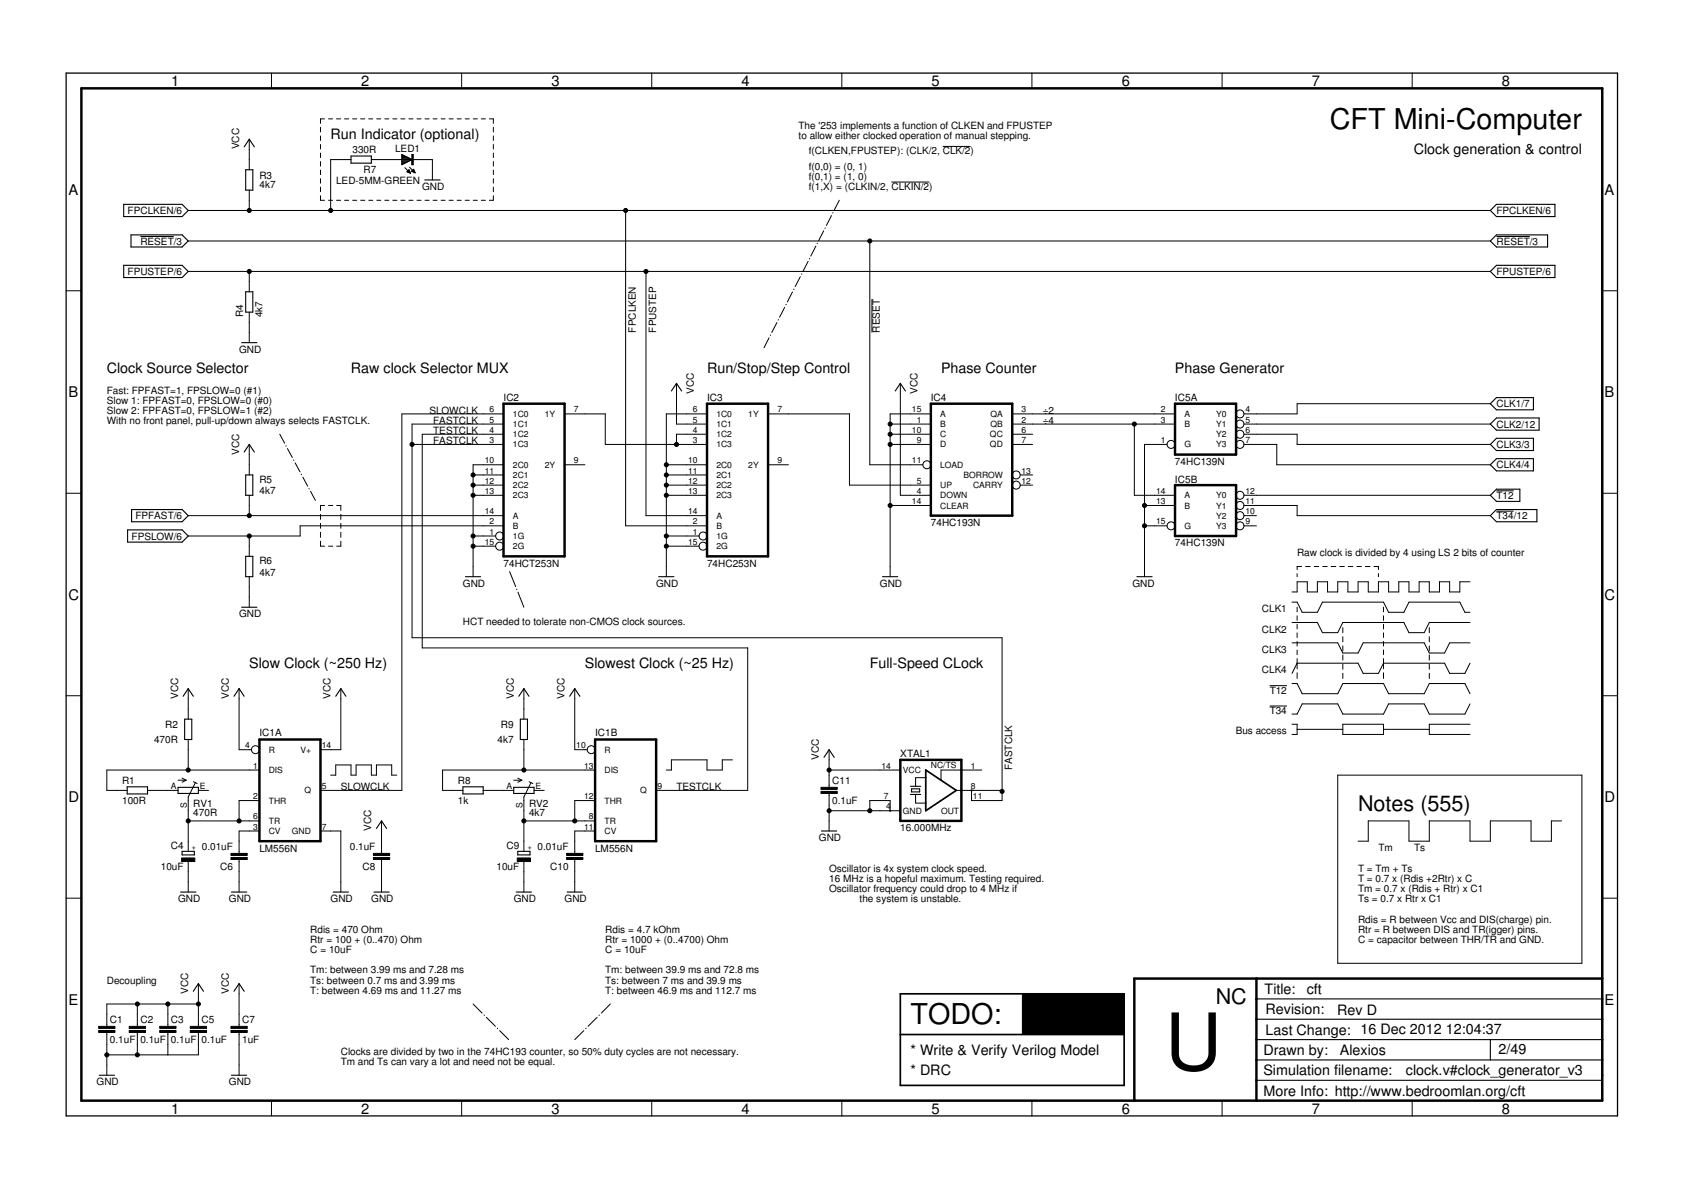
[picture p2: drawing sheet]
<svg xmlns="http://www.w3.org/2000/svg" width="420mm" height="297mm" viewBox="0 0 420 297" stroke-linecap="round" stroke-linejoin="round" font-family="sans-serif">
<defs><g id="words">
<text font-size="19.7" x="290.8" y="267.1">U</text>
<g font-size="7.2">
<text x="332" y="32.2">CFT Mini-Computer</text>
<text x="227.3" y="255.7">TODO:</text>
</g>
<g font-size="5.4">
<text x="339.1" y="202.4">Notes (555)</text>
<text x="303.5" y="250.6">NC</text>
</g>
<g font-size="3.7">
<text x="42.7" y="21.5">1</text>
<text x="90.2" y="21.5">2</text>
<text x="137.7" y="21.5">3</text>
<text x="185.1" y="21.5">4</text>
<text x="232.6" y="21.5">5</text>
<text x="280" y="21.5">6</text>
<text x="327.5" y="21.5">7</text>
<text x="375" y="21.5">8</text>
<text x="17.1" y="48.6">A</text>
<text x="400.6" y="48.6">A</text>
<text x="17.1" y="99.2">B</text>
<text x="400.6" y="99.2">B</text>
<text x="17.1" y="149.7">C</text>
<text x="400.6" y="149.7">C</text>
<text x="17.1" y="200.2">D</text>
<text x="400.6" y="200.2">D</text>
<text x="17.1" y="250.8">E</text>
<text x="400.6" y="250.8">E</text>
<text x="42.7" y="277.9">1</text>
<text x="90.2" y="277.9">2</text>
<text x="137.7" y="277.9">3</text>
<text x="185.1" y="277.9">4</text>
<text x="232.6" y="277.9">5</text>
<text x="280" y="277.9">6</text>
<text x="327.5" y="277.9">7</text>
<text x="375" y="277.9">8</text>
</g>
<g font-size="3.6">
<text x="82.5" y="34.7">Run Indicator (optional)</text>
<text x="353" y="38.6">Clock generation &amp; control</text>
<text x="26.7" y="93.2">Clock Source Selector</text>
<text x="87.6" y="93.2">Raw clock Selector MUX</text>
<text x="176.5" y="93.2">Run/Stop/Step Control</text>
<text x="234.9" y="93.2">Phase Counter</text>
<text x="293.3" y="93.2">Phase Generator</text>
<text x="62.2" y="166.8">Slow Clock (~250 Hz)</text>
<text x="146" y="166.8">Slowest Clock (~25 Hz)</text>
<text x="217.1" y="166.8">Full-Speed CLock</text>
<text x="315.7" y="248.1">Title:</text>
<text x="326.2" y="248.2">cft</text>
<text x="315.9" y="253.2">Revision:</text>
<text x="333.8" y="253.3">Rev D</text>
<text x="227.3" y="263.3">* Write &amp; Verify Verilog Model</text>
<text x="315.4" y="263.3">Drawn by:</text>
<text x="315.9" y="258.2">Last Change: 16 Dec 2012</text>
<text x="334.5" y="263.3">Alexios</text>
<text x="361" y="258.1">12:04:37</text>
<text x="374.1" y="263.2">2/49</text>
<text x="227.3" y="268.4">* DRC</text>
<text x="315.4" y="268.4">Simulation filename:</text>
<text x="351" y="268.4">clock.v#clock_generator_v3</text>
<text x="315.4" y="273.5">More Info: http://www.bedroomlan.org/cft</text>
</g>
<g font-size="2.5">
<text x="199.4" y="32.2">The '253 implements a function of CLKEN and FPUSTEP</text>
<text x="199.4" y="34.7">to allow either clocked operation of manual stepping.</text>
<text x="59.7" y="37.3" transform="rotate(-90 59.7 37.3)">VCC</text>
<text x="88" y="38.3">330R</text>
<text x="98.6" y="38.1">LED1</text>
<text x="201.9" y="38.6">f(CLKEN,FPUSTEP): (CLK/2, CLK/2)</text>
<text x="64.8" y="46.9">4k7</text>
<text x="64.8" y="44.7">R3</text>
<text x="83.9" y="46">LED-5MM-GREEN</text>
<text x="90.8" y="43.1">R7</text>
<text x="105.4" y="47.4">GND</text>
<text x="201.9" y="42.4">f(0,0) = (0, 1)</text>
<text x="201.9" y="44.9">f(0,1) = (1, 0)</text>
<text x="201.9" y="47.4">f(1,X) = (CLKIN/2, CLKIN/2)</text>
<text x="31.9" y="53.4">FPCLKEN/6</text>
<text x="373.6" y="53.4">FPCLKEN/6</text>
<text x="35" y="61">RESET/3</text>
<text x="373.6" y="61">RESET/3</text>
<text x="31.9" y="68.7">FPUSTEP/6</text>
<text x="373.6" y="68.7">FPUSTEP/6</text>
<text x="60.7" y="79.2" transform="rotate(-90 60.7 79.2)">R4</text>
<text x="65.5" y="79.2" transform="rotate(-90 65.5 79.2)">4k7</text>
<text x="158.7" y="83" transform="rotate(-90 158.7 83)">FPCLKEN</text>
<text x="163.8" y="83" transform="rotate(-90 163.8 83)">FPUSTEP</text>
<text x="219.7" y="83" transform="rotate(-90 219.7 83)">RESET</text>
<text x="59.7" y="88.1">GND</text>
<text x="26.7" y="98.2">Fast: FPFAST=1, FPSLOW=0 (#1)</text>
<text x="26.7" y="100.8">Slow 1: FPFAST=0, FPSLOW=0 (#0)</text>
<text x="125.7" y="100.1">IC2</text>
<text x="173.2" y="98.2" transform="rotate(-90 173.2 98.2)">VCC</text>
<text x="176.5" y="100.1">IC3</text>
<text x="229.1" y="98.2" transform="rotate(-90 229.1 98.2)">VCC</text>
<text x="232.4" y="100.1">IC4</text>
<text x="293.3" y="100.1">IC5A</text>
<text x="373.6" y="101.7">CLK1/7</text>
<text x="26.7" y="103.3">Slow 2: FPFAST=0, FPSLOW=1 (#2)</text>
<text x="26.7" y="105.9">With no front panel, pull-up/down always selects FASTCLK.</text>
<text x="107.2" y="103.3">SLOWCLK</text>
<text x="108.1" y="105.9">FASTCLK</text>
<text x="260.3" y="103.3">÷2</text>
<text x="260.3" y="105.9">÷4</text>
<text x="373.6" y="106.7">CLK2/12</text>
<text x="59.7" y="113.5" transform="rotate(-90 59.7 113.5)">VCC</text>
<text x="108.1" y="110.9">FASTCLK</text>
<text x="108.2" y="108.4">TESTCLK</text>
<text x="373.6" y="111.8">CLK3/3</text>
<text x="293.3" y="116">74HC139N</text>
<text x="373.6" y="116.9">CLK4/4</text>
<text x="64.8" y="123.4">4k7</text>
<text x="64.8" y="120.6">R5</text>
<text x="293.3" y="120.5">IC5B</text>
<text x="373.6" y="124.5">T12</text>
<text x="33.8" y="129.6">FPFAST/6</text>
<text x="232.4" y="131.3">74HC193N</text>
<text x="373.6" y="129.6">T34/12</text>
<text x="32.8" y="134.7">FPSLOW/6</text>
<text x="293.3" y="136.3">74HC139N</text>
<text x="64.8" y="143.7">4k7</text>
<text x="64.8" y="140.9">R6</text>
<text x="125.7" y="141.4">74HCT253N</text>
<text x="176.5" y="141.4">74HC253N</text>
<text x="323.8" y="138.9">Raw clock is divided by 4 using LS 2 bits of counter</text>
<text x="115.6" y="146.5">GND</text>
<text x="163.8" y="146.5">GND</text>
<text x="219.7" y="146.5">GND</text>
<text x="282.7" y="146.5">GND</text>
<text x="59.7" y="154.1">GND</text>
<text x="115.6" y="155.9">HCT needed to tolerate non-CMOS clock sources.</text>
<text x="315" y="152.8">CLK1</text>
<text x="315" y="157.9">CLK2</text>
<text x="315" y="163">CLK3</text>
<text x="315" y="168.1">CLK4</text>
<text x="317" y="173.2">T12</text>
<text x="44.4" y="174.4" transform="rotate(-90 44.4 174.4)">VCC</text>
<text x="57.1" y="174.4" transform="rotate(-90 57.1 174.4)">VCC</text>
<text x="82.5" y="174.4" transform="rotate(-90 82.5 174.4)">VCC</text>
<text x="128.3" y="174.4" transform="rotate(-90 128.3 174.4)">VCC</text>
<text x="141" y="174.4" transform="rotate(-90 141 174.4)">VCC</text>
<text x="317" y="178.2">T34</text>
<text x="38.5" y="185.3">470R</text>
<text x="41.3" y="181.8">R2</text>
<text x="64.8" y="183.8">IC1A</text>
<text x="124.2" y="185.3">4k7</text>
<text x="125.1" y="181.8">R9</text>
<text x="148.6" y="183.8">IC1B</text>
<text x="308.5" y="183.3">Bus access</text>
<text x="204.4" y="189.7" transform="rotate(-90 204.4 189.7)">VCC</text>
<text x="224.8" y="189">XTAL1</text>
<text x="30.5" y="195.8">R1</text>
<text x="85.1" y="197.3">SLOWCLK</text>
<text x="114.3" y="195.8">R8</text>
<text x="168.9" y="197.3">TESTCLK</text>
<text x="207.7" y="195.6">C11</text>
<text x="252.7" y="192.2" transform="rotate(-90 252.7 192.2)">FASTCLK</text>
<text x="30.5" y="200.6">100R</text>
<text x="48.3" y="203.6">470R</text>
<text x="48.3" y="201.5">RV1</text>
<text x="114.3" y="200.6">1k</text>
<text x="132.1" y="203.6">4k7</text>
<text x="132.1" y="201.5">RV2</text>
<text x="207.7" y="200.7">0.1uF</text>
<text x="92.7" y="207.4" transform="rotate(-90 92.7 207.4)">VCC</text>
<text x="204.4" y="210">GND</text>
<text x="224.8" y="207.4">16.000MHz</text>
<text x="42.6" y="212">C4</text>
<text x="50.4" y="212.1">0.01uF</text>
<text x="64.8" y="212.6">LM556N</text>
<text x="87.3" y="212.1">0.1uF</text>
<text x="126.4" y="212">C9</text>
<text x="134.2" y="212.1">0.01uF</text>
<text x="148.6" y="212.6">LM556N</text>
<text x="344.1" y="212.5">Tm</text>
<text x="353" y="212.5">Ts</text>
<text x="40.1" y="217.1">10uF</text>
<text x="54.9" y="217.2">C6</text>
<text x="90.5" y="217.2">C8</text>
<text x="123.9" y="217.1">10uF</text>
<text x="137.4" y="217.2">C10</text>
<text x="207" y="217.6">Oscillator is 4x system clock speed.</text>
<text x="207" y="220.1">16 MHz is a hopeful maximum. Testing required.</text>
<text x="339.1" y="220.1">T = 0.7 x (Rdis +2Rtr) x C</text>
<text x="339.1" y="217.6">T = Tm + Ts</text>
<text x="44.4" y="225.2">GND</text>
<text x="57.1" y="225.2">GND</text>
<text x="82.5" y="225.2">GND</text>
<text x="92.7" y="225.2">GND</text>
<text x="128.3" y="225.2">GND</text>
<text x="141" y="225.2">GND</text>
<text x="207" y="222.7">Oscillator frequency could drop to 4 MHz if</text>
<text x="214.6" y="225.2">the system is unstable.</text>
<text x="339.1" y="222.7">Tm = 0.7 x (Rdis + Rtr) x C1</text>
<text x="339.1" y="225.2">Ts = 0.7 x Rtr x C1</text>
<text x="77.5" y="232.8">Rdis = 470 Ohm</text>
<text x="151.1" y="232.8">Rdis = 4.7 kOhm</text>
<text x="339.1" y="230.3">Rdis = R between Vcc and DIS(charge) pin.</text>
<text x="339.1" y="232.8">Rtr = R between DIS and TR(igger) pins.</text>
<text x="77.5" y="235.4">Rtr = 100 + (0..470) Ohm</text>
<text x="77.5" y="237.9">C = 10uF</text>
<text x="151.1" y="235.4">Rtr = 1000 + (0..4700) Ohm</text>
<text x="151.1" y="237.9">C = 10uF</text>
<text x="339.1" y="235.4">C = capacitor between THR/TR and GND.</text>
<text x="26.7" y="245.5">Decoupling</text>
<text x="77.5" y="243">Tm: between 3.99 ms and 7.28 ms</text>
<text x="77.5" y="245.5">Ts: between 0.7 ms and 3.99 ms</text>
<text x="151.1" y="243">Tm: between 39.9 ms and 72.8 ms</text>
<text x="151.1" y="245.5">Ts: between 7 ms and 39.9 ms</text>
<text x="47" y="248.1" transform="rotate(-90 47 248.1)">VCC</text>
<text x="57.1" y="248.1" transform="rotate(-90 57.1 248.1)">VCC</text>
<text x="77.5" y="248.1">T: between 4.69 ms and 11.27 ms</text>
<text x="151.1" y="248.1">T: between 46.9 ms and 112.7 ms</text>
<text x="27.4" y="255.3">C1</text>
<text x="35" y="255.3">C2</text>
<text x="42.7" y="255.3">C3</text>
<text x="50.3" y="255.3">C5</text>
<text x="60.4" y="255.3">C7</text>
<text x="27.4" y="260.4">0.1uF</text>
<text x="35" y="260.4">0.1uF</text>
<text x="42.7" y="260.4">0.1uF</text>
<text x="50.3" y="260.4">0.1uF</text>
<text x="60.4" y="260.4">1uF</text>
<text x="85.1" y="263.3">Clocks are divided by two in the 74HC193 counter, so 50% duty cycles are not necessary.</text>
<text x="85.1" y="265.8">Tm and Ts can vary a lot and need not be equal.</text>
<text x="24.1" y="270.9">GND</text>
<text x="57.1" y="270.9">GND</text>
</g>
<g font-size="2.1">
<text x="122.2" y="105.5">5</text>
<text x="122.2" y="103">6</text>
<text x="128.1" y="106.6">1C1</text>
<text x="128.1" y="104.1">1C0</text>
<text x="136" y="104.1">1Y</text>
<text x="143.3" y="103">7</text>
<text x="173" y="105.5">5</text>
<text x="173" y="103">6</text>
<text x="178.8" y="106.6">1C1</text>
<text x="178.8" y="104.1">1C0</text>
<text x="186.8" y="104.1">1Y</text>
<text x="194.1" y="103">7</text>
<text x="227.7" y="103">15</text>
<text x="228.9" y="105.5">1</text>
<text x="234.7" y="104.1">A</text>
<text x="234.7" y="106.6">B</text>
<text x="247.3" y="106.6">QB</text>
<text x="247.3" y="104.1">QA</text>
<text x="255" y="105.5">2</text>
<text x="255" y="103">3</text>
<text x="289.8" y="103">2</text>
<text x="289.8" y="105.5">3</text>
<text x="295.7" y="104.1">A</text>
<text x="295.7" y="106.6">B</text>
<text x="303.6" y="104.1">Y0</text>
<text x="303.6" y="106.6">Y1</text>
<text x="310.9" y="103">4</text>
<text x="310.9" y="105.5">5</text>
<text x="122.2" y="110.6">3</text>
<text x="122.2" y="108">4</text>
<text x="128.1" y="111.7">1C3</text>
<text x="128.1" y="109.2">1C2</text>
<text x="173" y="110.6">3</text>
<text x="173" y="108">4</text>
<text x="178.8" y="111.7">1C3</text>
<text x="178.8" y="109.2">1C2</text>
<text x="227.7" y="108">10</text>
<text x="228.9" y="110.6">9</text>
<text x="234.7" y="109.2">C</text>
<text x="234.7" y="111.7">D</text>
<text x="247.1" y="111.7">QD</text>
<text x="247.1" y="109.2">QC</text>
<text x="255" y="110.6">7</text>
<text x="255" y="108">6</text>
<text x="289.8" y="110.6">1</text>
<text x="295.7" y="111.7">G</text>
<text x="303.6" y="109.2">Y2</text>
<text x="303.6" y="111.7">Y3</text>
<text x="310.9" y="108">6</text>
<text x="310.9" y="110.6">7</text>
<text x="121" y="115.7">10</text>
<text x="121" y="118.2">11</text>
<text x="128.1" y="116.8">2C0</text>
<text x="128.1" y="119.3">2C1</text>
<text x="136" y="116.8">2Y</text>
<text x="143.3" y="115.7">9</text>
<text x="171.8" y="115.7">10</text>
<text x="171.8" y="118.2">11</text>
<text x="178.8" y="116.8">2C0</text>
<text x="178.8" y="119.3">2C1</text>
<text x="186.8" y="116.8">2Y</text>
<text x="194.1" y="115.7">9</text>
<text x="227.7" y="115.7">11</text>
<text x="234.7" y="116.8">LOAD</text>
<text x="240.5" y="119.3">BORROW</text>
<text x="255" y="118.2">13</text>
<text x="121" y="120.7">12</text>
<text x="121" y="123.3">13</text>
<text x="128.1" y="121.9">2C2</text>
<text x="128.1" y="124.4">2C3</text>
<text x="171.8" y="120.7">12</text>
<text x="171.8" y="123.3">13</text>
<text x="178.8" y="121.9">2C2</text>
<text x="178.8" y="124.4">2C3</text>
<text x="227.7" y="125.8">14</text>
<text x="228.9" y="120.7">5</text>
<text x="228.9" y="123.3">4</text>
<text x="234.7" y="121.9">UP</text>
<text x="234.7" y="124.4">DOWN</text>
<text x="242.9" y="121.9">CARRY</text>
<text x="255" y="120.7">12</text>
<text x="288.6" y="123.3">14</text>
<text x="288.6" y="125.8">13</text>
<text x="295.7" y="124.4">A</text>
<text x="303.6" y="124.4">Y0</text>
<text x="310.9" y="123.3">12</text>
<text x="310.9" y="125.8">11</text>
<text x="121" y="128.4">14</text>
<text x="122.2" y="130.9">2</text>
<text x="128.1" y="129.5">A</text>
<text x="171.8" y="128.4">14</text>
<text x="173" y="130.9">2</text>
<text x="178.8" y="129.5">A</text>
<text x="234.7" y="126.9">CLEAR</text>
<text x="288.6" y="130.9">15</text>
<text x="295.7" y="126.9">B</text>
<text x="303.6" y="126.9">Y1</text>
<text x="303.6" y="129.5">Y2</text>
<text x="310.9" y="128.4">10</text>
<text x="310.9" y="130.9">9</text>
<text x="121" y="136">15</text>
<text x="122.2" y="133.4">1</text>
<text x="128.1" y="134.6">1G</text>
<text x="128.1" y="132">B</text>
<text x="128.1" y="137.1">2G</text>
<text x="171.8" y="136">15</text>
<text x="173" y="133.4">1</text>
<text x="178.8" y="134.6">1G</text>
<text x="178.8" y="132">B</text>
<text x="178.8" y="137.1">2G</text>
<text x="295.7" y="132">G</text>
<text x="303.6" y="132">Y3</text>
<text x="61.2" y="186.8">4</text>
<text x="63.2" y="191.8">1</text>
<text x="67.1" y="187.9">R</text>
<text x="75" y="187.9">V+</text>
<text x="80.4" y="186.8">14</text>
<text x="143.9" y="186.8">10</text>
<text x="145.8" y="191.8">13</text>
<text x="150.9" y="187.9">R</text>
<text x="220.1" y="191.8">14</text>
<text x="232.4" y="191.7">NC/TS</text>
<text x="242.3" y="191.8">1</text>
<text x="42.7" y="196.9">A</text>
<text x="49.9" y="196.9">E</text>
<text x="67.1" y="193">DIS</text>
<text x="80.4" y="196.9">5</text>
<text x="126.5" y="196.9">A</text>
<text x="133.7" y="196.9">E</text>
<text x="150.9" y="193">DIS</text>
<text x="164.2" y="196.9">9</text>
<text x="225.4" y="193">VCC</text>
<text x="242.3" y="196.9">8</text>
<text x="46.6" y="201.6" transform="rotate(-90 46.6 201.6)">S</text>
<text x="63.2" y="199.5">2</text>
<text x="67.1" y="200.6">THR</text>
<text x="76" y="198">Q</text>
<text x="130.4" y="201.6" transform="rotate(-90 130.4 201.6)">S</text>
<text x="145.8" y="199.5">12</text>
<text x="150.9" y="200.6">THR</text>
<text x="159.8" y="198">Q</text>
<text x="220.7" y="199.5">7</text>
<text x="221.2" y="202">4</text>
<text x="225.4" y="203.1">GND</text>
<text x="234.9" y="203.1">OUT</text>
<text x="242.9" y="199.5">11</text>
<text x="63.2" y="204.5">6</text>
<text x="63.2" y="207.1">3</text>
<text x="67.1" y="205.7">TR</text>
<text x="67.1" y="208.2">CV</text>
<text x="72.9" y="208.2">GND</text>
<text x="80.4" y="207.1">7</text>
<text x="145.8" y="207.1">11</text>
<text x="147" y="204.5">8</text>
<text x="150.9" y="205.7">TR</text>
<text x="150.9" y="208.2">CV</text>
</g>
<g font-size="1.8">
<text x="48.8" y="212.1" transform="rotate(-90 48.8 212.1)">+</text>
<text x="132.7" y="212.1" transform="rotate(-90 132.7 212.1)">+</text>
</g>
</g></defs>
<g fill="#000" stroke="#000" stroke-width=".25">
<path d="M67.8 18.2v3.9zM115.3 18.2v3.9zM162.7 18.2v3.9zM210.2 18.2v3.9zM257.6 18.2v3.9zM305.1 18.2v3.9zM352.5 18.2v3.9zM20.3 22.1v252.6zM62.2 34.8v2.5zM62.2 39.8v2.6zM62.2 37.3v2.5zM80 29.7h1z"/>
<path d="M80 38.2v1.1zM80 36.1v1.1zM80 33.9v1.2zM80 31.8v1.1zM80 29.7v1.1zM82 29.7h1zM82.5 39.8v12.7zM84 29.7h1zM85.1 39.8h2.5zM82.5 39.8h2.6zM86 29.7h1zM88 29.7h1z"/>
<path d="M90 29.7h1.1zM92.1 29.7h.9zM94.1 29.7h1zM92.7 39.8h2.5zM96.1 29.7h1zM97.8 39.8h2.5zM95.2 39.8h2.6zM98.1 29.7h1zM100.1 29.7h1zM100.3 39.8h2.6zM102.1 29.7h1zM104.1 29.7h1z"/>
<path d="M102.9 39.8h2.5zM106.1 29.7h1zM105.4 39.8h2.5zM108.1 29.7h1zM110.1 29.7h1zM112.1 29.7h1zM114.1 29.7h1zM116.1 29.7h1.1zM118.2 29.7h1zM120.2 29.7h1zM122.2 29.7h1zM123.2 38.2v1.1z"/>
<path d="M123.2 36.1v1.1zM123.2 33.9v1.2zM123.2 31.8v1.1zM123.2 29.7v1.1zM235.3 36.6h7zM20.3 22.1h379.7zM35.1 59h8.3zM47 52.5h15.2zM62.2 47.5v2.5zM62.2 52.5h20.3zM62.2 50v2.5zM80 48.9v1.1z"/>
<path d="M80 46.7v1.2zM80 44.6v1.1zM80 42.5v1.1zM80 40.3v1.2zM80 50h1zM82 50h1zM82.5 52.5h73.7zM84 50h1zM86 50h1zM88 50h1zM90 50h1.1zM92.1 50h.9z"/>
<path d="M94.1 50h1zM96.1 50h1zM98.1 50h1zM100.1 50h1zM101.1 41.9l1.4 1.4zM101.6 42.9l.5-.5zM101.6 42.8h.7zM101.7 42.9h.6zM101.8 42.7h.4zM101.9 42.6h.3zM102 43.1h.4zM102.1 50h1z"/>
<path d="M102.1 42.4l.4 .9zM102.2 41.7l1.4 1.4zM102.3 43.2h.1zM101.6 42.9l.9 .4zM102.7 42.8l.5-.6zM102.8 42.7h.6zM102.9 42.8h.6zM102.9 42.6h.5zM103 42.5h.3zM103.1 42.3h.2zM103.2 42.9h.3zM103.2 42.2l.4 .9z"/>
<path d="M103.4 43.1h.2zM102.7 42.8l.9 .3zM104.1 50h1zM106.1 50h1zM107.9 42.4v2.5zM107.9 39.8v2.6zM108.1 50h1zM110.1 50h1zM112.1 50h1zM114.1 50h1zM116.1 50h1.1zM118.2 50h1z"/>
<path d="M120.2 50h1zM122.2 50h1zM123.2 48.9v1.1zM123.2 46.7v1.2zM123.2 44.6v1.1zM123.2 42.5v1.1zM123.2 40.3v1.2zM156.2 52.5h215.9zM205.6 57.6l-1.2 2.5zM207.6 53.8l-1.3 2.5zM208 53.1l-.1 .1zM209.5 50l-1.2 2.5z"/>
<path d="M222.5 45.4h9.5zM373.6 59h8.3zM16.5 72.6h3.8zM47 60.2h170.1zM62.2 70.3v2.5zM47 67.8h15.2zM62.2 67.8v2.5zM62.2 67.8h99.1zM161.3 67.8h210.8zM194.3 79.8v.1zM195.9 76.7l-1.3 2.5zM196.3 76l-.1 .1z"/>
<path d="M197.8 72.9l-1.2 2.5zM198.2 72.2v.1zM199.8 69.1l-1.3 2.4zM201.7 65.3l-1.2 2.4zM202.1 64.5v.1zM203.7 61.4l-1.3 2.5zM204.1 60.7l-.1 .1zM217.1 60.2h155zM400 72.6h3.8zM62.2 77.9v2.6zM62.2 83v2.5zM62.2 80.5v2.5z"/>
<path d="M168.9 95.7v2.5zM192 84.3l-1.3 2.5zM193.9 80.5l-1.2 2.5zM217.7 74.7v8.3zM224.8 95.7v2.5zM62.2 116v2.6zM62.2 110.9v2.6zM62.2 113.5v2.5zM69.8 108.4l1.3 2.2zM71.8 112l1.2 2.2zM73.3 114.8l.1 .1zM73.7 115.5l1.2 2.3z"/>
<path d="M75.6 119.1l1.2 2.2zM100.3 103.3v94zM102.9 105.9h17.7zM102.9 105.9v5zM102.9 110.9v48.3zM105.4 108.4v53.3zM118.1 116v2.6zM118.1 118.6v2.5zM120.6 110.9h5.1zM120.6 108.4h5.1zM120.6 105.9h5.1zM120.6 103.3h5.1z"/>
<path d="M120.6 116h5.1zM120.6 118.6h5.1zM118.1 116h2.5zM118.1 118.6h2.5zM102.9 110.9h17.7zM100.3 103.3h20.3zM105.4 108.4h15.2zM140.9 103.3h5.1zM140.9 116h5.1zM146 103.3h5.1zM151.1 103.3v7.6zM151.1 110.9h17.8z"/>
<path d="M166.3 103.3v12.7zM166.3 116v2.6zM166.3 118.6v2.5zM168.9 98.2v7.7zM168.9 110.9h2.5zM168.9 108.4v2.5zM171.4 110.9h5.1zM171.4 108.4h5.1zM171.4 105.9h5.1zM171.4 103.3h5.1zM171.4 116h5.1zM171.4 118.6h5.1z"/>
<path d="M166.3 103.3h5.1zM166.3 116h5.1zM166.3 118.6h5.1zM168.9 105.9h2.5zM168.9 108.4h2.5zM191.7 103.3h5.1zM191.7 116h5.1zM196.8 103.3h15.3zM212.1 103.3v17.8zM217.1 60.2v55.8zM222.2 103.3v2.6zM222.2 105.9v2.5z"/>
<path d="M222.2 108.4v2.5zM222.2 110.9v15.3zM227.3 103.3h5.1zM227.3 105.9h5.1zM227.3 108.4h5.1zM227.3 110.9h5.1zM227.3 116h3.1zM222.2 103.3h5.1zM222.2 105.9h5.1zM222.2 108.4h5.1zM222.2 110.9h5.1zM217.1 116h10.2z"/>
<path d="M252.7 110.9h5.1zM252.7 108.4h5.1zM252.7 105.9h5.1zM252.7 103.3h5.1zM254.7 118.6h3.1zM257.8 105.9h25.4zM285.7 110.9v15.3zM288.3 110.9h3.1zM288.3 103.3h5zM288.3 105.9h5zM285.7 110.9h2.6zM257.8 103.3h30.5z"/>
<path d="M283.2 105.9h5.1zM310.6 103.3h3.1zM310.6 105.9h3.1zM310.6 108.4h3.1zM310.6 110.9h3.1zM313.7 103.3h10.1zM313.7 105.9h58.4zM313.7 108.4h10.1zM313.7 110.9h5zM318.7 110.9v5.1zM318.7 116h53.4zM323.8 100.8v2.5z"/>
<path d="M323.8 100.8h48.3zM323.8 108.4v2.5zM323.8 110.9h48.3zM16.5 123.1h3.8zM62.2 123.6v2.6zM62.2 136.3v2.6zM47 128.7h15.2zM62.2 126.2v2.5zM47 133.8h15.2zM62.2 133.8v2.5zM74.9 131.3v2.5zM62.2 133.8h12.7z"/>
<path d="M77.1 121.9l.1 .2zM77.5 122.7l1.2 2.2zM80 126.2v1.2zM80 128.4v1.2zM80 130.6v1.3zM80 132.9v1.2zM80 135.1v1.2zM80 136.3h1zM80 126.2h1zM82 136.3h1.1zM82 126.2h1.1zM84.1 136.3h1z"/>
<path d="M85.1 135.1v1.2zM85.1 132.9v1.2zM85.1 130.6v1.3zM85.1 128.4v1.2zM85.1 126.2v1.2zM84.1 126.2h1zM118.1 136.3v5.1zM118.1 133.8v2.5zM118.1 121.1v2.5zM118.1 123.6v10.2zM120.6 133.8h3.1zM120.6 131.3h5.1z"/>
<path d="M120.6 121.1h5.1zM120.6 123.6h5.1zM120.6 128.7h5.1zM120.6 136.3h3.1zM118.1 136.3h2.5zM118.1 133.8h2.5zM118.1 121.1h2.5zM118.1 123.6h2.5zM62.2 128.7h58.4zM74.9 131.3h45.7zM156.2 52.5v78.8zM161.3 67.8v60.9z"/>
<path d="M166.3 121.1v2.5zM166.3 123.6v10.2zM166.3 133.8v2.5zM166.3 136.3v5.1zM171.4 133.8h3.1zM171.4 131.3h5.1zM171.4 121.1h5.1zM171.4 123.6h5.1zM171.4 128.7h5.1zM171.4 136.3h3.1zM166.3 133.8h5.1zM166.3 136.3h5.1z"/>
<path d="M166.3 121.1h5.1zM166.3 123.6h5.1zM156.2 131.3h15.2zM161.3 128.7h10.1zM222.2 126.2v15.2zM224.8 98.2v25.4zM227.3 121.1h5.1zM227.3 123.6h5.1zM227.3 126.2h5.1zM222.2 126.2h5.1zM224.8 123.6h2.5zM212.1 121.1h15.2z"/>
<path d="M254.7 121.1h3.1zM283.2 105.9v17.7zM285.7 126.2v5.1zM285.7 131.3v10.1zM288.3 131.3h3.1zM288.3 123.6h5zM288.3 126.2h5zM285.7 126.2h2.6zM285.7 131.3h2.6zM283.2 123.6h5.1zM310.6 123.6h3.1zM310.6 126.2h3.1z"/>
<path d="M310.6 128.7h3.1zM310.6 131.3h3.1zM313.7 123.6h58.4zM313.7 126.2h10.1zM323.8 126.2v2.5zM323.8 128.7h48.3zM373.6 122.5h4.3zM373.6 127.6h4.3zM400 123.1h3.8zM62.2 144v2.5zM62.2 149v2.6zM62.2 146.5v2.5z"/>
<path d="M102.9 159.2h147.3zM118.1 141.4v2.6zM127.2 142.7l1.5 3.7zM129 147.1l.1 .1zM129.3 147.8l1.5 3.8zM166.3 141.4v2.6zM222.2 141.4v2.6zM250.2 159.2v38.1zM285.7 141.4v2.6zM322.6 147.8h1.2zM322.6 150.3h1.2zM322.6 155.4h6.3z"/>
<path d="M323.8 145.2v2.6zM323.8 145.2h2.6zM323.8 143.2v.8zM323.8 141.4v.8zM323.8 141.4h1.1zM323.8 150.3l1.3 2.5zM323.8 151.6v1.1zM323.8 153.7v1.2zM323.8 155.8v1.2zM323.8 158v1.1zM325.1 152.8h3.8zM325.9 141.4h1.2z"/>
<path d="M326.4 145.2v2.6zM326.4 147.8h2.5zM328.1 141.4h1.1zM328.9 145.2v2.6zM328.9 145.2h2.5zM330.2 150.3l-1.3 2.5zM328.9 155.4l1.3 2.5zM330.2 150.3h15.2zM330.2 157.9h3.8zM330.2 141.4h1.1zM331.4 145.2v2.6zM331.4 147.8h2.6z"/>
<path d="M332.3 141.4h1.2zM334 145.2v2.6zM334 145.2h2.5zM335.2 155.4l-1.2 2.5zM334.5 141.4h1.1zM335.2 155.4h15.3zM335.2 156.7v1.2zM335.2 158.9v1.3zM336.5 145.2v2.6zM336.5 147.8h2.5zM336.6 141.4h1.1zM338.7 141.4h1.2z"/>
<path d="M339 145.2v2.6zM339 145.2h2.6zM340.9 141.4h1.1zM341.6 145.2v2.6zM341.6 147.8h2.5zM343 141.4h1.1zM344.1 145.2v2.6zM344.1 145.2h2.6zM344.1 141.4v.8zM344.1 143.2v.8zM345.4 150.3l1.3 2.5zM345.4 151.6v1.1z"/>
<path d="M345.4 153.7v1.2zM345.4 155.8v1.2zM345.4 158v1.1zM346.7 145.2v2.6zM346.7 147.8h2.5zM346.7 152.8h3.8zM349.2 145.2v2.6zM349.2 145.2h2.5zM351.7 150.3l-1.2 2.5zM350.5 155.4l1.2 2.5zM351.7 145.2v2.6zM351.7 147.8h2.6z"/>
<path d="M351.7 150.3h12.7zM351.7 157.9h3.9zM354.3 145.2v2.6zM354.3 145.2h2.5zM356.8 155.4l-1.2 2.5zM356.8 145.2v2.6zM356.8 147.8h2.6zM356.8 155.4h10.2zM356.8 156.7v1.2zM356.8 158.9v1.3zM359.4 145.2v2.6zM359.4 145.2h2.5z"/>
<path d="M361.9 145.2v2.6zM361.9 147.8h2.5zM364.4 145.2v2.6zM364.4 145.2h2.6zM364.4 150.3l1.3 2.5zM365.7 152.8h1.3zM16.5 173.7h3.8zM47 177v2.5zM47 171.9v2.5zM47 174.4v2.6zM59.7 171.9v2.5zM59.7 174.4v12.7z"/>
<path d="M85.1 171.9v2.5zM105.4 161.7h81.3zM130.8 171.9v2.5zM130.8 177v2.5zM130.8 174.4v2.6zM143.5 171.9v2.5zM143.5 174.4v12.7zM186.7 161.7v35.6zM317 171.2h4.3zM317 176.2h4.3zM322.6 160.5h11.4zM322.6 170.6h1.2z"/>
<path d="M322.6 178.2h1.2zM323.8 165.5l-1.2 2.6zM323.8 165.5h15.2zM323.8 170.6l1.3 2.6zM323.8 160.1v1.2zM323.8 162.3v1.1zM323.8 164.4v1.1zM323.8 165.5v1.4zM323.8 167.9v1.5zM325.1 173.2h8.9zM325.1 175.7h8.9zM325.1 175.7l-1.3 2.5z"/>
<path d="M334 160.5l1.2 2.5zM335.2 170.6l-1.2 2.6zM334 175.7l1.2 2.5zM335.2 163h3.8zM335.2 170.6h10.2zM335.2 178.2h10.2zM335.2 161.2v1.3zM335.2 163.5v1.3zM335.2 165.8v1.3zM335.2 168.1v1.3zM340.3 160.5l-1.3 2.5zM339 165.5l1.3 2.6z"/>
<path d="M340.3 160.5h15.3zM340.3 168.1h3.8zM345.4 165.5l-1.3 2.6zM345.4 165.5h15.2zM345.4 170.6l1.3 2.6zM346.7 175.7l-1.3 2.5zM345.4 160.1v1.2zM345.4 162.3v1.1zM345.4 164.4v1.1zM345.4 165.5v1.4zM345.4 167.9v1.5zM346.7 173.2h8.9z"/>
<path d="M346.7 175.7h8.9zM355.6 160.5l1.2 2.5zM356.8 170.6l-1.2 2.6zM355.6 175.7l1.2 2.5zM356.8 163h3.8zM356.8 170.6h8.9zM356.8 178.2h8.9zM356.8 161.2v1.3zM356.8 163.5v1.3zM356.8 165.8v1.3zM356.8 168.1v1.3zM361.9 160.5l-1.3 2.5z"/>
<path d="M360.6 165.5l1.3 2.6zM361.9 160.5h5.1zM361.9 168.1h3.8zM367 175.7l-1.3 2.5zM367 165.5l-1.3 2.6zM365.7 170.6l1.3 2.6zM400 173.7h3.8zM26.7 192.2v5.1zM26.7 197.3h2.5zM29.2 197.3h2.5zM36.8 197.3h2.6zM39.4 197.3h2.5z"/>
<path d="M41.9 197.3h2.5zM44.4 194.8h2.1zM45.5 194.2l1 .6zM45.5 195.3l1-.5zM47 184.6v2.5zM47 198.9v.9zM48.7 195.4l-1.7 3.5zM26.7 192.2h20.3zM47 187.1v5.1zM48.3 195.1l.9 .5zM49.5 197.3h2.6zM59.7 199.8v5.1z"/>
<path d="M62.2 187.1h.6zM62.2 199.8h2.6zM62.2 192.2h2.6zM59.7 187.1h2.5zM59.7 199.8h2.5zM47 192.2h15.2zM82.5 193.5h1.3zM80 197.3h2.5zM80 187.1h2.5zM82.5 187.1h2.6zM82.5 197.3h17.8zM83.8 190.9v2.6z"/>
<path d="M83.8 190.9h3.8zM85.1 174.4v12.7zM87.6 190.9v2.6zM87.6 193.5h1.3zM88.9 190.9v2.6zM88.9 190.9h3.8zM92.7 190.9v2.6zM92.7 193.5h1.3zM94 190.9v2.6zM94 190.9h3.8zM97.8 190.9v2.6zM97.8 193.5h1.3z"/>
<path d="M110.5 192.2v5.1zM110.5 197.3h2.5zM113 197.3h2.6zM120.6 197.3h2.6zM123.2 197.3h2.5zM125.7 197.3h2.5zM128.2 194.8h2.1zM129.3 194.2l1 .6zM129.3 195.3l1-.5zM130.8 198.9v.9zM132.5 195.4l-1.7 3.5zM130.8 184.6v2.5z"/>
<path d="M110.5 192.2h20.3zM130.8 187.1v5.1zM132.1 195.1l.9 .5zM133.3 197.3h2.6zM143.5 199.8v5.1zM146 187.1h.6zM146 199.8h2.6zM146 192.2h2.6zM143.5 187.1h2.5zM143.5 199.8h2.5zM130.8 192.2h15.2zM166.3 192.2h1.3z"/>
<path d="M163.8 197.3h2.5zM166.3 197.3h20.4zM167.6 189.7v2.5zM167.6 189.7h8.9zM176.5 189.7v2.5zM176.5 192.2h3.8zM180.3 189.7v2.5zM180.3 189.7h2.6zM207 187.1v2.6zM207 193.5v2.5zM207 198.1v.5zM207 196v.5z"/>
<path d="M207 192.2h12.7zM207 192.2v1.3zM207 189.7v2.5zM217.1 199.8v2.6zM219.7 192.2h5.1zM219.7 199.8h2.5zM217.1 199.8h2.6zM228.6 194.1h2.5zM228.6 194.1v2.2zM234.9 192.2v2.6zM238.7 197.3h1.3zM234.9 192.2h5.1z"/>
<path d="M242.5 197.3v2.5zM240 197.3h5.1zM240 192.2h5.1zM242.5 199.8h2.6zM245.1 199.8h5.1zM245.1 197.3h5.1zM250.2 197.5v2.3zM250.2 197.3v.2zM322.6 183.3h1.2zM323.8 182.1v1.2zM323.8 180.8v1.3zM322.6 180.8h1.2z"/>
<path d="M323.8 182.1h11.4zM334 193.5v46.9zM335.2 183.3h10.2zM335.2 180.8v2.5zM335.2 180.8h10.2zM345.4 182.1v1.2zM345.4 180.8v1.3zM345.4 182.1h11.4zM356.8 182.1v1.2zM356.8 183.3h10.2zM356.8 180.8v1.3zM356.8 180.8h10.2z"/>
<path d="M334 193.5h60.9zM47 215v2.6zM47 210v2.5zM47 199.8v2.6zM47 204.9v5.1zM47 202.4v2.5zM59.7 215v2.6zM59.7 210v2.5zM59.7 214.5v.5zM59.7 212.5v.5zM59.7 207.4v2.6zM47 204.9h12.7z"/>
<path d="M62.2 204.9h2.6zM62.2 207.4h2.6zM59.7 207.4h2.5zM59.7 204.9h2.5zM80 207.4h2.5zM82.5 207.4h2.6zM85.1 207.4v12.7zM95.2 215v2.6zM95.2 210v2.5zM95.2 214.5v.5zM95.2 212.5v.5zM95.2 204.9v2.5z"/>
<path d="M95.2 207.4v2.6zM130.8 215v2.6zM130.8 210v2.5zM130.8 199.8v2.6zM130.8 204.9v5.1zM130.8 202.4v2.5zM143.5 215v2.6zM143.5 210v2.5zM143.5 214.5v.5zM143.5 212.5v.5zM143.5 207.4v2.6zM130.8 204.9h12.7z"/>
<path d="M146 204.9h2.6zM146 207.4h2.6zM143.5 207.4h2.5zM143.5 204.9h2.5zM207 204.9v2.5zM207 198.6v2.5zM207 202.4h10.1zM207 201.1v1.3zM207 202.4v2.5zM217.1 202.4h2.6zM219.7 202.4h5.1zM222.2 199.8v2.6z"/>
<path d="M228.6 200.5h2.5zM228.6 198.3v2.2zM339 210h2.6zM341.6 204.9v5.1zM341.6 204.9h10.1zM351.7 204.9v5.1zM351.7 210h5.1zM356.8 204.9v5.1zM356.8 204.9h10.2zM367 204.9v5.1zM367 210h5.1zM372.1 204.9v5.1z"/>
<path d="M372.1 204.9h10.1zM382.2 204.9v5.1zM382.2 210h5.1zM387.3 204.9v5.1zM387.3 204.9h2.5zM16.5 224.2h3.8zM47 220.1v2.6zM47 217.6v2.5zM59.7 220.1v2.6zM59.7 217.6v2.5zM85.1 220.1v2.6zM95.2 220.1v2.6z"/>
<path d="M95.2 217.6v2.5zM130.8 220.1v2.6zM130.8 217.6v2.5zM143.5 220.1v2.6zM143.5 217.6v2.5zM400 224.2h3.8zM26.7 253.1v2.6zM26.7 257.7v.5zM26.7 255.7v.5zM26.7 250.6v2.5zM26.7 250.6h7.6zM34.3 253.1v2.6z"/>
<path d="M34.3 257.7v.5zM34.3 255.7v.5zM34.3 250.6v2.5zM41.9 253.1v2.6zM41.9 257.7v.5zM41.9 255.7v.5zM41.9 250.6v2.5zM34.3 250.6h7.6zM41.9 250.6h7.6zM49.5 245.5v2.6zM49.5 253.1v2.6zM49.5 257.7v.5z"/>
<path d="M49.5 255.7v.5zM49.5 250.6v2.5zM49.5 248.1v2.5zM59.7 245.5v2.6zM59.7 253.1v2.6zM59.7 257.7v.5zM59.7 255.7v.5zM59.7 248.1v5zM118.1 250.6l2.3 2.3zM121.4 253.9l2.3 2.3zM124.2 256.7v.1zM124.7 257.3l2.3 2.2z"/>
<path d="M143.5 259.5l2.3-2.2zM146.3 256.7l-.1 .1zM146.8 256.2l2.3-2.3zM149.5 253.4h.1zM152.4 250.6l-2.3 2.3zM334 240.4h60.9zM394.9 193.5v46.9zM20.3 274.7h379.7zM26.7 258.2v2.6zM26.7 265.8v2.6zM26.7 260.8v2.5zM26.7 263.3h7.6z"/>
<path d="M26.7 263.3v2.5zM34.3 258.2v2.6zM34.3 260.8v2.5zM41.9 258.2v2.6zM41.9 260.8v2.5zM34.3 263.3h7.6zM41.9 263.3h7.6zM49.5 258.2v2.6zM49.5 260.8v2.5zM59.7 265.8v2.6zM59.7 258.2v2.6zM59.7 260.8v5z"/>
<path d="M67.8 274.7v3.8zM115.3 274.7v3.8zM162.7 274.7v3.8zM210.2 274.7v3.8zM257.6 274.7v3.8zM305.1 274.7v3.8zM352.5 274.7v3.8zM400 264.5v.1zM400 268.4v6.2zM400 274.6h.1zM400 22.1v252.6z"/>
<circle cx="62.2" cy="52.5" r=".51"/>
<circle cx="82.5" cy="52.5" r=".51"/>
<circle cx="156.2" cy="52.5" r=".51"/>
<circle cx="62.2" cy="67.8" r=".51"/>
<circle cx="161.3" cy="67.8" r=".51"/>
<circle cx="217.1" cy="60.2" r=".51"/>
<circle cx="102.9" cy="110.9" r=".51"/>
<circle cx="118.1" cy="118.6" r=".51"/>
<circle cx="166.3" cy="116" r=".51"/>
<circle cx="166.3" cy="118.6" r=".51"/>
<circle cx="168.9" cy="110.9" r=".51"/>
<circle cx="222.2" cy="105.9" r=".51"/>
<circle cx="222.2" cy="108.4" r=".51"/>
<circle cx="222.2" cy="110.9" r=".51"/>
<circle cx="283.2" cy="105.9" r=".51"/>
<circle cx="62.2" cy="133.8" r=".51"/>
<circle cx="62.2" cy="128.7" r=".51"/>
<circle cx="118.1" cy="133.8" r=".51"/>
<circle cx="118.1" cy="121.1" r=".51"/>
<circle cx="118.1" cy="123.6" r=".51"/>
<circle cx="118.1" cy="136.3" r=".51"/>
<circle cx="166.3" cy="133.8" r=".51"/>
<circle cx="166.3" cy="121.1" r=".51"/>
<circle cx="166.3" cy="136.3" r=".51"/>
<circle cx="166.3" cy="123.6" r=".51"/>
<circle cx="222.2" cy="126.2" r=".51"/>
<circle cx="285.7" cy="126.2" r=".51"/>
<circle cx="285.7" cy="131.3" r=".51"/>
<circle cx="47" cy="192.2" r=".51"/>
<circle cx="130.8" cy="192.2" r=".51"/>
<circle cx="207" cy="192.2" r=".51"/>
<circle cx="250.2" cy="197.5" r=".51"/>
<circle cx="47" cy="204.9" r=".51"/>
<circle cx="59.7" cy="204.9" r=".51"/>
<circle cx="130.8" cy="204.9" r=".51"/>
<circle cx="143.5" cy="204.9" r=".51"/>
<circle cx="207" cy="202.4" r=".51"/>
<circle cx="217.1" cy="202.4" r=".51"/>
<circle cx="34.3" cy="250.6" r=".51"/>
<circle cx="41.9" cy="250.6" r=".51"/>
<circle cx="49.5" cy="250.6" r=".51"/>
<circle cx="26.7" cy="263.3" r=".51"/>
<circle cx="34.3" cy="263.3" r=".51"/>
</g>
<g fill="#000" stroke="#000" stroke-width=".28">
<path d="M62.2 34.8l-1.2 1.9zM62.2 34.8l1.3 1.9zM87.6 38.9v1.8zM87.6 38.9h5.1zM92.7 38.9v1.8zM100.3 38.6l2.6 1.2zM100.3 39.9h2.3zM100.3 39.7h2.4zM100.3 39.5h1.9zM100.3 39.3h1.5zM100.3 39.1h1zM100.3 38.8h.6z"/>
<path d="M102.9 39.8v1.3zM100.3 41.1l2.6-1.3zM102.9 38.6h.2zM102.9 39.9h.2zM102.9 39.7h.2zM102.9 39.5h.2zM102.9 39.3h.2zM102.9 39.1h.2zM102.9 38.8h.2zM103.1 38.6v2.5zM30.9 51v3.1zM32.7 58.6v3.1z"/>
<path d="M32.7 58.6h12.8zM30.9 51h14.6zM30.9 54.1h14.6zM45.5 51l1.5 1.5zM47 52.5l-1.5 1.6zM61.3 42.4v5.1zM63.1 42.4v5.1zM61.3 42.4h1.8zM61.3 47.5h1.8zM87.6 40.7h5.1zM100.3 38.6v2.5zM100.3 40.8h.6z"/>
<path d="M100.3 40.6h1zM100.3 40.4h1.4zM100.3 40.2h1.9zM102.9 38.6v2.5zM102.9 41.1h.2zM102.9 40.8h.2zM102.9 40.6h.2zM102.9 40.4h.2zM102.9 40.2h.2zM106 44.9h3.9zM372.1 52.5l1.5-1.5zM372.1 52.5l1.5 1.6z"/>
<path d="M373.6 58.6h12.7zM373.6 51h14.6zM373.6 54.1h14.6zM386.3 58.6v3.1zM388.2 51v3.1zM30.9 66.2v3.1zM32.7 61.7h12.8zM30.9 66.2h14.6zM30.9 69.3h14.6zM45.5 58.6l1.5 1.6zM45.5 61.7l1.5-1.5zM45.5 66.2l1.5 1.6z"/>
<path d="M47 67.8l-1.5 1.5zM61.3 72.8v5.1zM63.1 72.8v5.1zM61.3 72.8h1.8zM61.3 77.9h1.8zM372.1 60.2l1.5-1.6zM372.1 60.2l1.5 1.5zM372.1 67.8l1.5-1.6zM372.1 67.8l1.5 1.5zM373.6 61.7h12.7zM373.6 66.2h14.6zM373.6 69.3h14.6z"/>
<path d="M388.2 66.2v3.1zM60.3 85.5h3.8zM168.9 95.7l-1.3 1.9zM168.9 95.7l1.3 1.9zM224.8 95.7l-1.3 1.9zM224.8 95.7l1.2 1.9zM373.6 99.2h9.2zM382.8 99.2v3.1zM61.3 118.6v5zM62.2 110.9l-1.2 1.9zM61.3 118.6h1.8zM62.2 110.9l1.3 1.9z"/>
<path d="M373.6 99.2l-1.5 1.6zM372.1 100.8l1.5 1.5zM372.1 105.9l1.5-1.6zM372.1 105.9l1.5 1.5zM372.1 110.9l1.5-1.5zM372.1 110.9l1.5 1.6zM373.6 114.5l-1.5 1.5zM372.1 116l1.5 1.5zM373.6 102.3h9.2zM373.6 104.3h10.6zM373.6 107.4h10.6zM373.6 109.4h9.2z"/>
<path d="M373.6 112.5h9.2zM373.6 114.5h9.2zM373.6 117.5h9.2zM382.8 109.4v3.1zM382.8 114.5v3zM384.2 104.3v3.1zM31.9 132.3v3zM32.9 127.2v3zM32.9 127.2h12.6zM32.9 130.2h12.6zM31.9 132.3h13.6zM31.9 135.3h13.6z"/>
<path d="M45.5 127.2l1.5 1.5zM47 128.7l-1.5 1.5zM45.5 132.3l1.5 1.5zM45.5 135.3l1.5-1.5zM61.3 138.9v5.1zM61.3 138.9h1.8zM63.1 118.6v5zM61.3 123.6h1.8zM373.6 122.1l-1.5 1.5zM372.1 123.6l1.5 1.6zM372.1 128.7l1.5-1.5zM372.1 128.7l1.5 1.5z"/>
<path d="M373.6 122.1h5.8zM373.6 125.2h5.8zM373.6 127.2h10.1zM373.6 130.2h10.1zM379.4 122.1v3.1zM383.7 127.2v3zM60.3 151.6h3.8zM61.3 144h1.8zM63.1 138.9v5.1zM116.2 144h3.8zM164.4 144h3.9zM220.3 144h3.8z"/>
<path d="M283.8 144h3.8zM46.1 179.5h1.8zM47 171.9l-1.3 1.9zM47.9 179.5v5.1zM47 171.9l1.3 1.9zM59.7 171.9l-1.3 1.9zM59.7 171.9l1.3 1.9zM85.1 171.9l-1.3 1.9zM85.1 171.9l1.3 1.9zM129.9 179.5v5.1zM129.9 179.5h1.8zM130.8 171.9l-1.3 1.9z"/>
<path d="M130.8 171.9l1.3 1.9zM143.5 171.9l-1.3 1.9zM143.5 171.9l1.3 1.9zM31.7 198.2h5.1zM31.7 196.4v1.8zM31.7 196.4h5.1zM36.8 196.4v1.8zM44.4 198.1h5.1zM44.4 196.5v1.6zM46.1 179.5v5.1zM46.1 184.6h1.8zM44.4 196.5h5.1z"/>
<path d="M49.5 196.5v1.6zM115.6 198.2h5zM115.6 196.4v1.8zM115.6 196.4h5zM120.6 196.4v1.8zM128.2 198.1h5.1zM128.2 196.5v1.6zM129.9 184.6h1.8zM131.7 179.5v5.1zM128.2 196.5h5.1zM133.3 196.5v1.6zM207 187.1l-1.3 1.9z"/>
<path d="M207 187.1l1.3 1.9zM227.3 198.3h1.3zM227.3 196.3h2.5zM227.6 196.9v.8zM227.6 196.9h2zM227.6 197.7h2zM228.6 198.3h1.2zM229.6 196.9v.8zM45.5 212.5v.9zM45.5 213.4h3zM48.5 212.5v.9zM45.5 212.5h3z"/>
<path d="M95.2 204.9l-1.2 1.9zM95.2 204.9l1.3 1.9zM129.3 212.5v.9zM129.3 213.4h3zM132.3 212.5v.9zM129.3 212.5h3zM205.1 207.4h3.8zM45.1 222.7h3.8zM57.8 222.7h3.8zM83.2 222.7h3.8zM93.3 222.7h3.9zM128.9 222.7h3.8z"/>
<path d="M141.6 222.7h3.8zM49.5 245.5l-1.2 1.9zM49.5 245.5l1.3 1.9zM59.7 245.5l-1.3 1.9zM59.7 245.5l1.3 1.9zM313.7 249.3h86.3zM313.7 254.4h86.3zM313.7 259.5h58.4zM372.1 259.5h27.9zM372.1 259.5v5.1zM24.8 268.4h3.8zM57.8 268.4h3.8z"/>
<path d="M313.7 264.6h58.4zM313.7 269.7h86.3zM372.1 264.6h27.9zM400 268.4v1.3z"/>
</g>
<g fill="#000" stroke="#000" stroke-width=".61">
<path d="M20.3 22.1v252.6zM20.3 22.1h379.7zM125.7 100.8v38.1zM125.7 100.8h15.2zM176.5 100.8v38.1zM176.5 100.8h15.2zM232.4 100.8v27.9zM232.4 100.8h20.3zM293.3 113.5h15.3zM293.3 100.8v12.7zM308.6 100.8v12.7zM293.3 100.8h15.3z"/>
<path d="M125.7 138.9h15.2zM140.9 100.8v38.1zM176.5 138.9h15.2zM191.7 100.8v38.1zM232.4 128.7h20.3zM252.7 100.8v27.9zM293.3 133.8h15.3zM293.3 121.1v12.7zM308.6 121.1v12.7zM293.3 121.1h15.3zM64.8 184.6v25.4zM64.8 184.6h15.2z"/>
<path d="M148.6 184.6v25.4zM148.6 184.6h15.2zM224.8 189.7v15.2zM224.8 189.7h15.2zM240 192.2v5.1zM240 189.7v2.5zM64.8 210h15.2zM80 184.6v25.4zM148.6 210h15.2zM163.8 184.6v25.4zM224.8 204.9h15.2zM240 197.3v7.6z"/>
<path d="M283.2 244.3v30.4zM313.7 254.4v5.1zM313.7 249.3v5.1zM313.7 244.3v5zM313.7 244.3h86.3zM283.2 244.3h30.5zM400 254.4v5.1zM400 249.3v5.1zM400 244.3v5zM400 22.1v222.2zM20.3 274.7h262.9zM283.2 274.7h30.5z"/>
<path d="M313.7 274.7h86.3zM313.7 269.7v5zM313.7 264.6v5.1zM313.7 259.5v5.1zM400 268.4v6.3zM400 264.6v3.8zM400 259.5v5.1z"/>
</g>
<g fill="#000" stroke="#000" stroke-width=".42">
<path d="M231.1 192.2l3.8 2.6zM231.1 192.2v1.9zM234.9 194.8l3.8 2.5zM231.1 202.4l7.6-5.1zM231.1 200.5v1.9zM231.1 194.1v6.4zM224.8 248.1v10.1zM224.8 258.2v12.7zM224.8 258.2h55.8zM280.6 248.1v10.1zM224.8 248.1h55.8zM224.8 270.9h55.8z"/>
<path d="M280.6 258.2v12.7z"/>
</g>
<g fill="none" stroke="#000" stroke-width=".25">
<circle cx="231.4" cy="116" r="1"/>
<circle cx="253.7" cy="118.6" r="1"/>
<circle cx="292.3" cy="110.9" r="1"/>
<circle cx="309.6" cy="108.4" r="1"/>
<circle cx="309.6" cy="110.9" r="1"/>
<circle cx="309.6" cy="103.3" r="1"/>
<circle cx="309.6" cy="105.9" r="1"/>
<circle cx="124.7" cy="133.8" r=".99"/>
<circle cx="124.7" cy="136.3" r=".99"/>
<circle cx="175.5" cy="136.3" r=".99"/>
<circle cx="175.5" cy="133.8" r=".99"/>
<circle cx="253.7" cy="121.1" r="1"/>
<circle cx="292.3" cy="131.3" r="1"/>
<circle cx="309.6" cy="131.3" r="1"/>
<circle cx="309.6" cy="126.2" r="1"/>
<circle cx="309.6" cy="123.6" r="1"/>
<circle cx="309.6" cy="128.7" r="1"/>
<circle cx="63.8" cy="187.1" r=".99"/>
<circle cx="147.6" cy="187.1" r=".99"/>
<circle cx="242.5" cy="197.3" r=".15"/>
<circle cx="222.2" cy="202.4" r=".15"/>
</g>
<g fill="#000" stroke="#000" stroke-width=".25">
<path d="M205 196.5h4v.5h-4zM205 197.5h4v.6h-4zM45.3 214.2h3.3v.8h-3.3zM57.7 213h4v.5h-4zM57.7 214h4v.5h-4zM93.2 213h4.1v.5h-4.1zM93.2 214h4.1v.5h-4.1zM129.1 214.2h3.3v.8h-3.3zM141.5 213h4v.5h-4zM141.5 214h4v.5h-4zM24.6 256.2h4.1v.5h-4.1zM24.6 257.2h4.1v.5h-4.1z"/>
<path d="M32.3 256.2h4v.5h-4zM32.3 257.2h4v.5h-4zM39.9 256.2h4v.5h-4zM39.9 257.2h4v.5h-4zM47.5 256.2h4.1v.5h-4.1zM47.5 257.2h4.1v.5h-4.1zM57.7 256.2h4v.5h-4zM57.7 257.2h4v.5h-4zM255.2 248.1h25.4v10.1h-25.4z"/>
</g>
<path d="M16.5 18.2v260.3zM16.5 18.2h387.3zM16.5 278.5h387.3zM403.8 18.2v260.3z" fill="#000" stroke="#000" stroke-width=".32"/>
<use href="#words"/>
</svg>
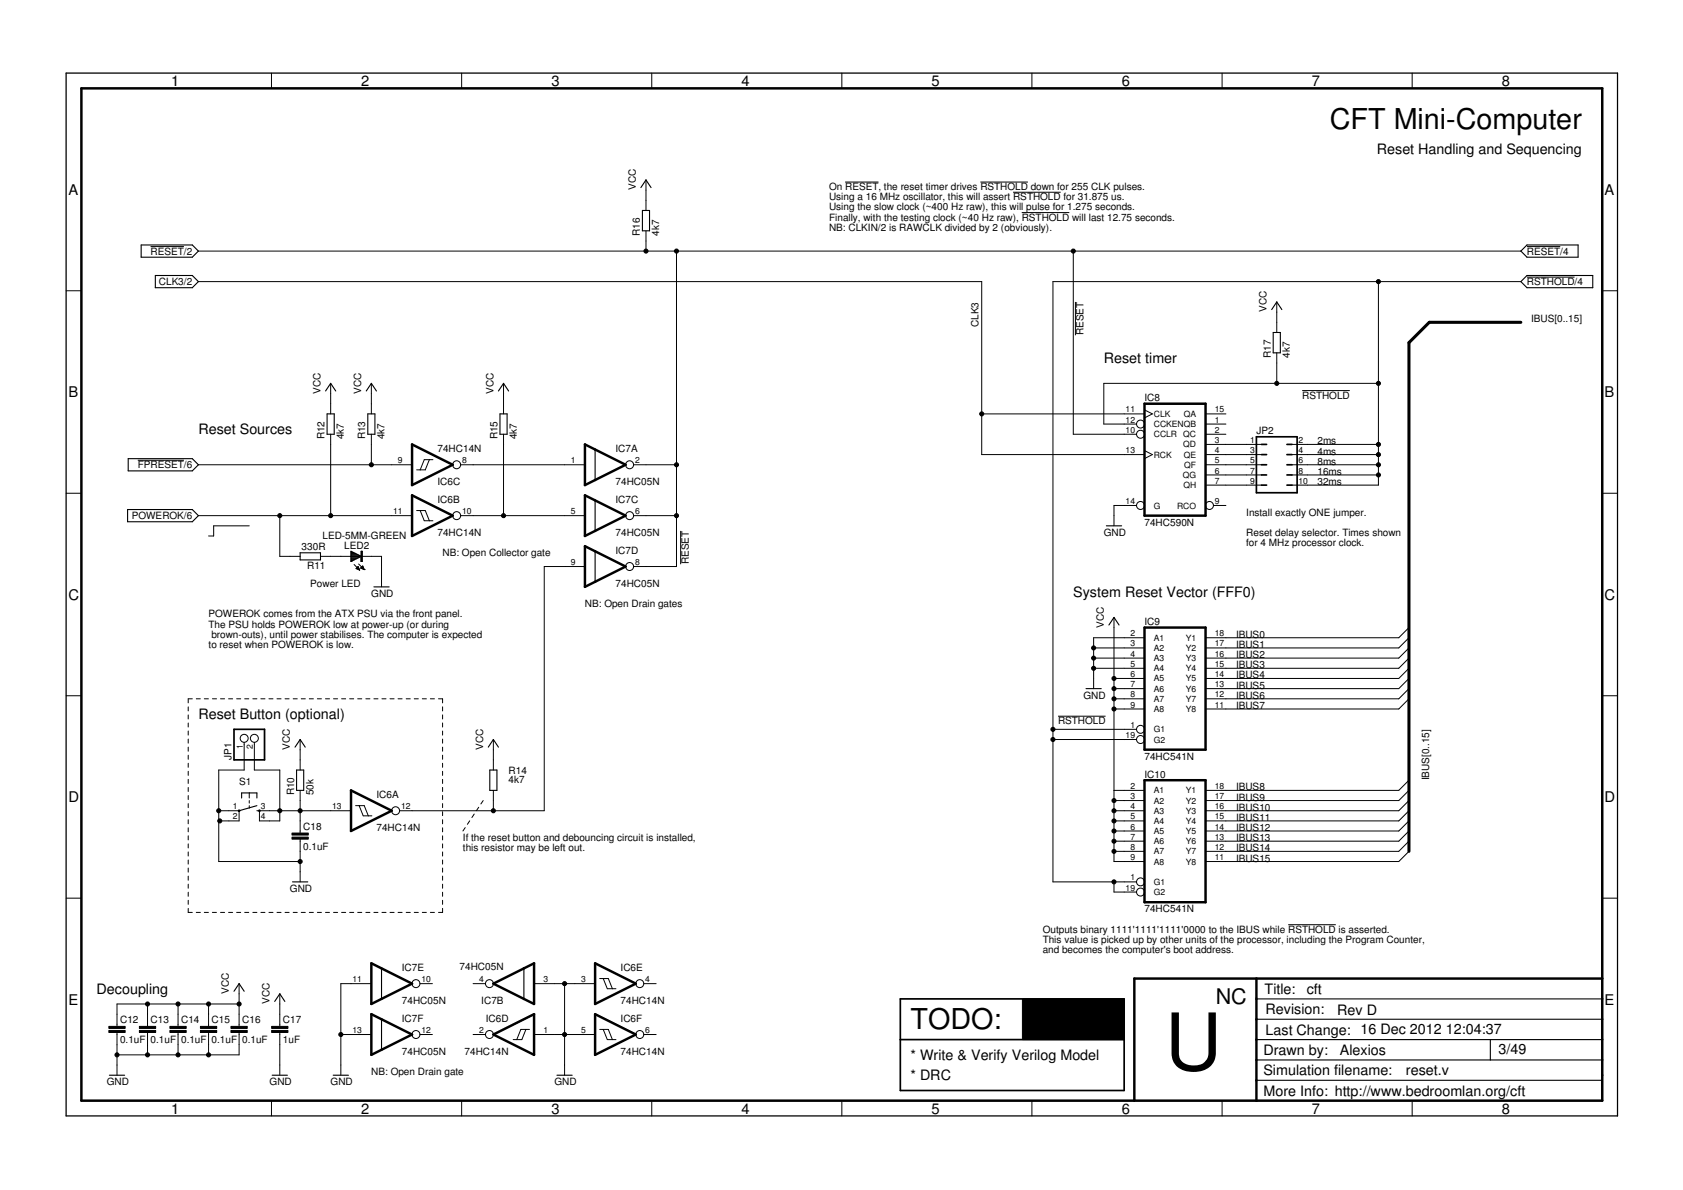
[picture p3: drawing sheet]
<svg xmlns="http://www.w3.org/2000/svg" width="420mm" height="297mm" viewBox="0 0 420 297" stroke-linecap="round" stroke-linejoin="round" font-family="sans-serif">
<defs><g id="words">
<text font-size="19.7" x="290.8" y="267.1">U</text>
<g font-size="7.2">
<text x="332" y="32.2">CFT Mini-Computer</text>
<text x="227.3" y="257">TODO:</text>
</g>
<text font-size="5.4" x="303.5" y="250.6">NC</text>
<g font-size="3.7">
<text x="42.7" y="21.5">1</text>
<text x="90.2" y="21.5">2</text>
<text x="137.7" y="21.5">3</text>
<text x="185.1" y="21.5">4</text>
<text x="232.6" y="21.5">5</text>
<text x="280" y="21.5">6</text>
<text x="327.5" y="21.5">7</text>
<text x="375" y="21.5">8</text>
<text x="17.1" y="48.6">A</text>
<text x="400.6" y="48.6">A</text>
<text x="17.1" y="99.2">B</text>
<text x="400.6" y="99.2">B</text>
<text x="17.1" y="149.7">C</text>
<text x="400.6" y="149.7">C</text>
<text x="17.1" y="200.2">D</text>
<text x="400.6" y="200.2">D</text>
<text x="17.1" y="250.8">E</text>
<text x="400.6" y="250.8">E</text>
<text x="42.7" y="277.9">1</text>
<text x="90.2" y="277.9">2</text>
<text x="137.7" y="277.9">3</text>
<text x="185.1" y="277.9">4</text>
<text x="232.6" y="277.9">5</text>
<text x="280" y="277.9">6</text>
<text x="327.5" y="277.9">7</text>
<text x="375" y="277.9">8</text>
</g>
<g font-size="3.6">
<text x="343.7" y="38.6">Reset Handling and Sequencing</text>
<text x="275.6" y="90.6">Reset timer</text>
<text x="49.5" y="108.4">Reset Sources</text>
<text x="267.9" y="149">System Reset Vector (FFF0)</text>
<text x="49.5" y="179.5">Reset Button (optional)</text>
<text x="24.1" y="248.1">Decoupling</text>
<text x="315.7" y="248.1">Title:</text>
<text x="326.2" y="248.2">cft</text>
<text x="315.9" y="253.2">Revision:</text>
<text x="333.8" y="253.3">Rev D</text>
<text x="315.4" y="263.3">Drawn by:</text>
<text x="315.9" y="258.2">Last Change: 16 Dec 2012</text>
<text x="334.5" y="263.3">Alexios</text>
<text x="361" y="258.1">12:04:37</text>
<text x="374.1" y="263.2">3/49</text>
<text x="227.3" y="264.6">* Write &amp; Verify Verilog Model</text>
<text x="227.3" y="269.7">* DRC</text>
<text x="315.4" y="268.4">Simulation filename:</text>
<text x="351" y="268.4">reset.v</text>
<text x="315.4" y="273.5">More Info: http://www.bedroomlan.org/cft</text>
</g>
<g font-size="2.5">
<text x="158.7" y="47.4" transform="rotate(-90 158.7 47.4)">VCC</text>
<text x="207" y="47.4">On RESET, the reset timer drives RSTHOLD down for 255 CLK pulses.</text>
<text x="207" y="50">Using a 16 MHz oscillator, this will assert RSTHOLD for 31.875 us.</text>
<text x="207" y="52.5">Using the slow clock (~400 Hz raw), this will pulse for 1.275 seconds.</text>
<text x="159.8" y="58.9" transform="rotate(-90 159.8 58.9)">R16</text>
<text x="164.6" y="58.9" transform="rotate(-90 164.6 58.9)">4k7</text>
<text x="207" y="55.1">Finally, with the testing clock (~40 Hz raw), RSTHOLD will last 12.75 seconds.</text>
<text x="207" y="57.6">NB: CLKIN/2 is RAWCLK divided by 2 (obviously).</text>
<text x="37.6" y="63.6">RESET/2</text>
<text x="381.2" y="63.6">RESET/4</text>
<text x="39.7" y="71.2">CLK3/2</text>
<text x="381.2" y="71.2">RSTHOLD/4</text>
<text x="316.2" y="77.9" transform="rotate(-90 316.2 77.9)">VCC</text>
<text x="244.3" y="81.6" transform="rotate(-90 244.3 81.6)">CLK3</text>
<text x="270.5" y="83.7" transform="rotate(-90 270.5 83.7)">RESET</text>
<text x="382.2" y="80.5">IBUS[0..15]</text>
<text x="317.2" y="89.3" transform="rotate(-90 317.2 89.3)">R17</text>
<text x="322" y="89.3" transform="rotate(-90 322 89.3)">4k7</text>
<text x="80" y="98.2" transform="rotate(-90 80 98.2)">VCC</text>
<text x="90.2" y="98.2" transform="rotate(-90 90.2 98.2)">VCC</text>
<text x="123.2" y="98.2" transform="rotate(-90 123.2 98.2)">VCC</text>
<text x="285.7" y="100.1">IC8</text>
<text x="325.1" y="99.5">RSTHOLD</text>
<text x="81" y="109.7" transform="rotate(-90 81 109.7)">R12</text>
<text x="85.8" y="109.7" transform="rotate(-90 85.8 109.7)">4k7</text>
<text x="91.2" y="109.7" transform="rotate(-90 91.2 109.7)">R13</text>
<text x="96" y="109.7" transform="rotate(-90 96 109.7)">4k7</text>
<text x="109.2" y="112.7">74HC14N</text>
<text x="124.2" y="109.7" transform="rotate(-90 124.2 109.7)">R15</text>
<text x="129" y="109.7" transform="rotate(-90 129 109.7)">4k7</text>
<text x="153.7" y="112.8">IC7A</text>
<text x="313.7" y="108.4">JP2</text>
<text x="328.9" y="113.5">4ms</text>
<text x="328.9" y="110.9">2ms</text>
<text x="34.4" y="116.9">FPRESET/6</text>
<text x="328.9" y="116">8ms</text>
<text x="328.9" y="118.6">16ms</text>
<text x="109.2" y="125.5">IC6B</text>
<text x="109.2" y="121">IC6C</text>
<text x="153.7" y="121.1">74HC05N</text>
<text x="153.7" y="125.5">IC7C</text>
<text x="328.9" y="121.1">32ms</text>
<text x="32.9" y="129.6">POWEROK/6</text>
<text x="285.7" y="131.3">74HC590N</text>
<text x="311.1" y="128.7">Install exactly ONE jumper.</text>
<text x="75.3" y="137.3">330R</text>
<text x="80.5" y="134.4">LED-5MM-GREEN</text>
<text x="85.9" y="137.1">LED2</text>
<text x="109.2" y="133.8">74HC14N</text>
<text x="153.7" y="133.8">74HC05N</text>
<text x="275.6" y="133.8">GND</text>
<text x="311.1" y="133.8">Reset delay selector. Times shown</text>
<text x="311.1" y="136.3">for 4 MHz processor clock.</text>
<text x="76.7" y="142.1">R11</text>
<text x="110.5" y="138.9">NB: Open Collector gate</text>
<text x="153.7" y="138.2">IC7D</text>
<text x="171.9" y="140.8" transform="rotate(-90 171.9 140.8)">RESET</text>
<text x="77.5" y="146.5">Power LED</text>
<text x="92.7" y="149">GND</text>
<text x="153.7" y="146.5">74HC05N</text>
<text x="52.1" y="154.1">POWEROK comes from the ATX PSU via the front panel.</text>
<text x="146" y="151.6">NB: Open Drain gates</text>
<text x="52.1" y="156.6">The PSU holds POWEROK low at power-up (or during</text>
<text x="52.1" y="161.7">to reset when POWEROK is low.</text>
<text x="52.8" y="159.2">brown-outs), until power stabilises. The computer is expected</text>
<text x="275.6" y="156.6" transform="rotate(-90 275.6 156.6)">VCC</text>
<text x="285.7" y="156">IC9</text>
<text x="308.6" y="159.2">IBUS0</text>
<text x="308.6" y="161.7">IBUS1</text>
<text x="308.6" y="164.3">IBUS2</text>
<text x="308.6" y="166.8">IBUS3</text>
<text x="308.6" y="169.3">IBUS4</text>
<text x="308.6" y="171.9">IBUS5</text>
<text x="270.5" y="174.4">GND</text>
<text x="308.6" y="174.4">IBUS6</text>
<text x="308.6" y="177">IBUS7</text>
<text x="264.1" y="180.8">RSTHOLD</text>
<text x="57.8" y="189.7" transform="rotate(-90 57.8 189.7)">JP1</text>
<text x="72.4" y="187.1" transform="rotate(-90 72.4 187.1)">VCC</text>
<text x="120.6" y="187.1" transform="rotate(-90 120.6 187.1)">VCC</text>
<text x="285.7" y="189.7">74HC541N</text>
<text x="59.7" y="196">S1</text>
<text x="127" y="195.5">4k7</text>
<text x="127" y="193.2">R14</text>
<text x="285.7" y="194.1">IC10</text>
<text x="308.6" y="197.3">IBUS8</text>
<text x="356.8" y="194.8" transform="rotate(-90 356.8 194.8)">IBUS[0..15]</text>
<text x="73.4" y="198.6" transform="rotate(-90 73.4 198.6)">R10</text>
<text x="78.2" y="198.6" transform="rotate(-90 78.2 198.6)">50k</text>
<text x="94" y="199.2">IC6A</text>
<text x="308.6" y="199.8">IBUS9</text>
<text x="308.6" y="202.4">IBUS10</text>
<text x="75.7" y="207.1">C18</text>
<text x="94" y="207.4">74HC14N</text>
<text x="115.6" y="210">If the reset button and debouncing circuit is installed,</text>
<text x="308.6" y="204.9">IBUS11</text>
<text x="308.6" y="207.4">IBUS12</text>
<text x="308.6" y="210">IBUS13</text>
<text x="75.7" y="212.1">0.1uF</text>
<text x="115.6" y="212.5">this resistor may be left out.</text>
<text x="308.6" y="212.5">IBUS14</text>
<text x="308.6" y="215.1">IBUS15</text>
<text x="72.4" y="222.7">GND</text>
<text x="285.7" y="227.8">74HC541N</text>
<text x="260.3" y="232.8">Outputs binary 1111'1111'1111'0000 to the IBUS while RSTHOLD is asserted.</text>
<text x="260.3" y="235.4">This value is picked up by other units of the processor, including the Program Counter,</text>
<text x="260.3" y="237.9">and becomes the computer's boot address.</text>
<text x="100.3" y="242.4">IC7E</text>
<text x="114.7" y="242.2">74HC05N</text>
<text x="154.9" y="242.4">IC6E</text>
<text x="57.1" y="248.1" transform="rotate(-90 57.1 248.1)">VCC</text>
<text x="67.3" y="250.6" transform="rotate(-90 67.3 250.6)">VCC</text>
<text x="100.3" y="250.6">74HC05N</text>
<text x="120.1" y="250.5">IC7B</text>
<text x="154.9" y="250.6">74HC14N</text>
<text x="30" y="255.3">C12</text>
<text x="37.6" y="255.3">C13</text>
<text x="45.2" y="255.3">C14</text>
<text x="52.8" y="255.3">C15</text>
<text x="60.4" y="255.3">C16</text>
<text x="70.6" y="255.3">C17</text>
<text x="100.3" y="255.1">IC7F</text>
<text x="121.3" y="255.1">IC6D</text>
<text x="154.9" y="255.1">IC6F</text>
<text x="30" y="260.4">0.1uF</text>
<text x="37.6" y="260.4">0.1uF</text>
<text x="45.2" y="260.4">0.1uF</text>
<text x="52.8" y="260.4">0.1uF</text>
<text x="60.4" y="260.4">0.1uF</text>
<text x="70.6" y="260.4">1uF</text>
<text x="100.3" y="263.3">74HC05N</text>
<text x="116" y="263.3">74HC14N</text>
<text x="154.9" y="263.3">74HC14N</text>
<text x="92.7" y="268.4">NB: Open Drain gate</text>
<text x="26.7" y="270.9">GND</text>
<text x="67.3" y="270.9">GND</text>
<text x="82.5" y="270.9">GND</text>
<text x="138.4" y="270.9">GND</text>
</g>
<g font-size="2.1">
<text x="281" y="103">11</text>
<text x="281" y="105.5">12</text>
<text x="288.1" y="104.1">CLK</text>
<text x="288.1" y="106.6">CCKENQB</text>
<text x="295.5" y="104.1">QA</text>
<text x="303.3" y="105.5">1</text>
<text x="303.3" y="103">15</text>
<text x="281" y="108">10</text>
<text x="281" y="113.1">13</text>
<text x="288.1" y="109.2">CCLR</text>
<text x="295.4" y="109.2">QC</text>
<text x="295.4" y="111.7">QD</text>
<text x="303.3" y="108">2</text>
<text x="303.3" y="110.6">3</text>
<text x="303.3" y="113.1">4</text>
<text x="312.1" y="110.6">1</text>
<text x="312.1" y="113.1">3</text>
<text x="324.2" y="110.6">2</text>
<text x="324.2" y="113.1">4</text>
<text x="99.3" y="115.7">9</text>
<text x="115.4" y="115.7">8</text>
<text x="142.5" y="115.7">1</text>
<text x="158.5" y="115.7">2</text>
<text x="288.1" y="114.2">RCK</text>
<text x="295.3" y="119.3">QG</text>
<text x="295.5" y="114.2">QE</text>
<text x="295.6" y="116.8">QF</text>
<text x="303.3" y="115.7">5</text>
<text x="303.3" y="118.2">6</text>
<text x="312.1" y="115.7">5</text>
<text x="312.1" y="118.2">7</text>
<text x="324.2" y="115.7">6</text>
<text x="324.2" y="118.2">8</text>
<text x="281" y="125.8">14</text>
<text x="295.4" y="121.9">QH</text>
<text x="303.3" y="120.7">7</text>
<text x="303.3" y="125.8">9</text>
<text x="312.1" y="120.7">9</text>
<text x="324.2" y="120.7">10</text>
<text x="98.2" y="128.4">11</text>
<text x="115.4" y="128.4">10</text>
<text x="142.5" y="128.4">5</text>
<text x="158.5" y="128.4">6</text>
<text x="288.1" y="126.9">G</text>
<text x="293.9" y="126.9">RCO</text>
<text x="142.5" y="141.1">9</text>
<text x="158.5" y="141.1">8</text>
<text x="282.2" y="158.8">2</text>
<text x="282.2" y="161.4">3</text>
<text x="288.1" y="159.9">A1</text>
<text x="296" y="160">Y1</text>
<text x="303.3" y="161.4">17</text>
<text x="303.3" y="158.8">18</text>
<text x="282.2" y="163.9">4</text>
<text x="282.2" y="166.5">5</text>
<text x="288.1" y="162.5">A2</text>
<text x="288.1" y="165">A3</text>
<text x="288.1" y="167.6">A4</text>
<text x="296" y="167.6">Y4</text>
<text x="296" y="165">Y3</text>
<text x="296" y="162.5">Y2</text>
<text x="303.3" y="166.5">15</text>
<text x="303.3" y="163.9">16</text>
<text x="282.2" y="169">6</text>
<text x="282.2" y="171.5">7</text>
<text x="288.1" y="170.1">A5</text>
<text x="288.1" y="172.6">A6</text>
<text x="296" y="172.6">Y6</text>
<text x="296" y="170.1">Y5</text>
<text x="303.3" y="171.5">13</text>
<text x="303.3" y="169">14</text>
<text x="282.2" y="174.1">8</text>
<text x="282.2" y="176.6">9</text>
<text x="288.1" y="175.2">A7</text>
<text x="288.1" y="177.7">A8</text>
<text x="296" y="177.7">Y8</text>
<text x="296" y="175.2">Y7</text>
<text x="303.3" y="176.6">11</text>
<text x="303.3" y="174.1">12</text>
<text x="281" y="184.2">19</text>
<text x="282.2" y="181.7">1</text>
<text x="288.1" y="182.8">G1</text>
<text x="288.1" y="185.3">G2</text>
<text x="60.6" y="186.8" transform="rotate(-90 60.6 186.8)">1</text>
<text x="63.1" y="186.8" transform="rotate(-90 63.1 186.8)">2</text>
<text x="282.2" y="196.9">2</text>
<text x="303.3" y="196.9">18</text>
<text x="58.1" y="202">1</text>
<text x="65.1" y="202">3</text>
<text x="82.9" y="202">13</text>
<text x="100.1" y="202">12</text>
<text x="282.2" y="199.5">3</text>
<text x="282.2" y="202">4</text>
<text x="288.1" y="198">A1</text>
<text x="288.1" y="200.6">A2</text>
<text x="288.1" y="203.1">A3</text>
<text x="296" y="203.1">Y3</text>
<text x="296" y="200.6">Y2</text>
<text x="296" y="198">Y1</text>
<text x="303.3" y="202">16</text>
<text x="303.3" y="199.5">17</text>
<text x="58.1" y="204.5">2</text>
<text x="65.1" y="204.5">4</text>
<text x="282.2" y="204.5">5</text>
<text x="282.2" y="207.1">6</text>
<text x="282.2" y="209.6">7</text>
<text x="288.1" y="205.7">A4</text>
<text x="288.1" y="208.2">A5</text>
<text x="296" y="208.2">Y5</text>
<text x="296" y="205.7">Y4</text>
<text x="303.3" y="209.6">13</text>
<text x="303.3" y="207.1">14</text>
<text x="303.3" y="204.5">15</text>
<text x="282.2" y="212.2">8</text>
<text x="282.2" y="214.7">9</text>
<text x="288.1" y="210.7">A6</text>
<text x="288.1" y="213.3">A7</text>
<text x="288.1" y="215.8">A8</text>
<text x="296" y="215.8">Y8</text>
<text x="296" y="213.3">Y7</text>
<text x="296" y="210.7">Y6</text>
<text x="303.3" y="214.7">11</text>
<text x="303.3" y="212.2">12</text>
<text x="282.2" y="219.8">1</text>
<text x="288.1" y="220.9">G1</text>
<text x="281" y="222.3">19</text>
<text x="288.1" y="223.4">G2</text>
<text x="88" y="245.2">11</text>
<text x="105.2" y="245.2">10</text>
<text x="119.7" y="245.2">4</text>
<text x="135.7" y="245.2">3</text>
<text x="145.1" y="245.2">3</text>
<text x="161.1" y="245.2">4</text>
<text x="88" y="257.9">13</text>
<text x="105.2" y="257.9">12</text>
<text x="119.7" y="257.9">2</text>
<text x="135.7" y="257.9">1</text>
<text x="145.1" y="257.9">5</text>
<text x="161.1" y="257.9">6</text>
</g>
</g></defs>
<g fill="#000" stroke="#000" stroke-width=".25">
<path d="M67.8 18.2v3.9zM115.3 18.2v3.9zM162.7 18.2v3.9zM210.2 18.2v3.9zM257.6 18.2v3.9zM305.1 18.2v3.9zM352.5 18.2v3.9zM20.3 22.1v252.6zM20.3 22.1h379.7zM161.3 50v2.5zM161.3 44.9v2.6zM161.3 47.5v2.5z"/>
<path d="M211 45.4h8.3zM244.7 45.4h11.9zM252.9 48h11.9zM255.1 53.1h11.8zM16.5 72.6h3.8zM37.6 61.6h8.3zM49.5 62.7h111.8zM161.3 57.6v2.6zM161.3 62.7h7.6zM161.3 60.2v2.5zM168.9 62.7h99zM49.5 70.3h195.6z"/>
<path d="M262.9 70.3h81.2zM267.9 62.7h111.8zM318.7 75.4v2.5zM344.1 70.3h35.6zM381.2 61.6h8.3zM381.2 69.2h11.9zM400 72.6h3.8zM82.5 95.7v2.5zM82.5 98.2v2.6zM92.7 95.7v2.5zM125.7 95.7v2.5zM125.7 98.2v2.6z"/>
<path d="M268.5 75.4v8.3zM275.6 95.7h43.1zM318.7 80.5v2.5zM318.7 88.1v2.5zM318.7 77.9v2.6zM318.7 95.7h25.4zM318.7 90.6v5.1zM325.1 97.5h11.9zM344.1 95.7v15.2zM344.1 70.3v25.4zM34.4 114.9h11.5zM82.5 100.8v2.5z"/>
<path d="M82.5 108.4v2.5zM82.5 110.9v17.8zM92.7 100.8v2.5zM92.7 108.4v2.5zM92.7 98.2v2.6zM49.5 116h43.2zM92.7 110.9v5.1zM97.8 116h5.1zM92.7 116h5.1zM104 117.3h.9zM104.9 117.3h1.3zM105.9 114.7l-1 2.6z"/>
<path d="M105.9 114.7h1.3zM107.2 114.7l-1 2.6zM107.2 114.7h.9zM115 116h3.1zM125.7 100.8v2.5zM125.7 108.4v2.5zM125.7 110.9v17.8zM140.9 116h5.1zM118.1 116h22.8zM158.2 116h3.1zM161.3 116h7.6zM168.9 116v12.7z"/>
<path d="M168.9 62.7v53.3zM245.1 70.3v33zM245.1 103.3v10.2zM245.1 113.5h35.5zM267.9 62.7v45.7zM275.6 95.7v10.2zM280.6 108.4h3.1zM280.6 103.3h5.1zM280.6 105.9h3.1zM280.6 113.5h5.1zM267.9 108.4h12.7zM275.6 105.9h5z"/>
<path d="M245.1 103.3h35.5zM285.7 102.3l2 1zM285.7 112.5l2 1zM285.7 104.3l2-1zM285.7 114.5l2-1zM301 105.9h5zM301 108.4h5zM301 110.9h5zM301 113.5h5zM301 116h5zM301 118.6h5zM301 103.3h5z"/>
<path d="M311.1 110.9h2.6zM311.1 113.5h2.6zM311.1 116h2.6zM311.1 118.6h2.6zM306 118.6h5.1zM306 116h5.1zM306 113.5h5.1zM306 110.9h5.1zM313.7 110.9h1.2zM313.7 113.5h1.2zM313.7 116h1.2zM313.7 118.6h1.2z"/>
<path d="M322.6 110.9h1.2zM322.6 113.5h1.2zM322.6 116h1.2zM322.6 118.6h1.2zM323.8 110.9h2.6zM323.8 113.5h2.6zM323.8 116h2.6zM323.8 118.6h2.6zM326.4 118.6h17.7zM326.4 116h17.7zM326.4 113.5h17.7zM326.4 110.9h17.7z"/>
<path d="M344.1 110.9v2.6zM344.1 113.5v2.5zM344.1 116v2.6zM344.1 118.6v2.5zM16.5 123.1h3.8zM49.5 128.7h20.3zM52.1 133.8h1.2zM53.3 131.3v2.5zM53.3 131.3h8.9zM69.8 138.9h2.6zM69.8 128.7v10.2zM72.4 138.9h2.5z"/>
<path d="M80 138.9h2.5zM82.5 138.9h2.6zM69.8 128.7h12.7zM85.1 138.9h2.5zM87.6 138.9h2.6zM90.2 138.9h2.5zM92.7 138.9h2.5zM97.8 128.7h5.1zM82.5 128.7h15.3zM104 127.4h.9zM104.9 127.4h1.3zM104.9 127.4l1 2.6z"/>
<path d="M105.9 130h1.3zM106.2 127.4l1 2.6zM107.2 130h.9zM115 128.7h3.1zM118.1 128.7h7.6zM125.7 128.7h15.2zM140.9 128.7h5.1zM158.2 128.7h3.1zM161.3 128.7h7.6zM168.9 128.7v12.7zM278.1 128.7v2.6zM278.1 126.2v2.5z"/>
<path d="M280.6 126.2h3.1zM278.1 126.2h2.5zM301 121.1h5zM302.9 126.2h3.1zM311.1 121.1h2.6zM306 121.1h5.1zM313.7 121.1h1.2zM322.6 121.1h1.2zM323.8 121.1h2.6zM326.4 121.1h17.7zM400 123.1h3.8zM88.4 140.9l1.4 1.4z"/>
<path d="M88.9 141.9l.5-.5zM88.9 141.9h.7zM89 141.8h.6zM89.1 141.7h.4zM89.2 142h.5zM89.2 141.6h.3zM89.4 141.4l.4 .9zM89.5 142.2h.2zM89.5 140.8l1.4 1.4zM88.9 141.9l.9 .4zM90 141.8l.5-.5zM90.1 141.8h.7z"/>
<path d="M90.1 141.7h.6zM90.3 141.6h.4zM90.4 141.9h.4zM90.4 141.5h.2zM90.5 141.3l.4 .9zM90.6 142h.3zM90 141.8l.9 .4zM95.2 144v2.5zM95.2 138.9v5.1zM135.9 141.4h5zM140.9 141.4h5.1zM158.2 141.4h3.1z"/>
<path d="M161.3 141.4h7.6zM169.9 132.5v8.3zM273 159.2v2.5zM278.1 154.1v2.6zM280.6 159.2h5.1zM273 159.2h7.6zM301 159.2h5zM306 159.2h43.2zM351.7 156.7l-2.5 2.5zM351.7 159.2l-2.5 2.5zM16.5 173.7h3.8zM47 178.5v1z"/>
<path d="M47 176.4v1.1zM47 174.4v1zM47 174.4h1zM49 174.4h1zM51 174.4h1zM53 174.4h1.1zM55.1 174.4h1zM57.1 174.4h1zM59.1 174.4h1zM61.1 174.4h1zM63.1 174.4h1zM65.1 174.4h1z"/>
<path d="M67.1 174.4h1.1zM69.2 174.4h1zM71.2 174.4h1zM73.2 174.4h1zM75.2 174.4h1zM77.2 174.4h1zM79.2 174.4h1zM81.3 174.4h1zM83.3 174.4h1zM85.3 174.4h1zM87.3 174.4h1zM89.3 174.4h1z"/>
<path d="M91.3 174.4h1zM93.3 174.4h1.1zM95.4 174.4h1zM97.4 174.4h1zM99.4 174.4h1zM101.4 174.4h1zM103.4 174.4h1zM105.4 174.4h1zM107.4 174.4h1.1zM109.5 174.4h1zM110.5 174.4v1zM110.5 176.4v1.1z"/>
<path d="M110.5 178.5v1zM264.1 178.8h11.9zM273 169.4v2.5zM273 166.8v2.6zM273 164.3v2.5zM273 164.3h7.6zM273 161.7v2.6zM278.1 156.7v12.7zM278.1 169.4v2.5zM278.1 171.9v2.5zM278.1 174.4v2.6zM280.6 161.7h5.1z"/>
<path d="M280.6 164.3h5.1zM280.6 166.8h5.1zM280.6 169.4h5.1zM280.6 171.9h5.1zM280.6 174.4h5.1zM280.6 177h5.1zM278.1 169.4h2.5zM278.1 171.9h2.5zM278.1 174.4h2.5zM278.1 177h2.5zM273 166.8h7.6zM273 161.7h7.6z"/>
<path d="M301 177h5zM301 174.4h5zM301 171.9h5zM301 169.4h5zM301 166.8h5zM301 164.3h5zM301 161.7h5zM306 161.7h43.2zM306 164.3h43.2zM306 166.8h43.2zM306 169.4h43.2zM306 171.9h43.2z"/>
<path d="M306 174.4h43.2zM306 177h43.2zM351.7 161.7l-2.5 2.6zM351.7 164.3l-2.5 2.5zM351.7 166.8l-2.5 2.6zM351.7 169.4l-2.5 2.5zM351.7 171.9l-2.5 2.5zM351.7 174.4l-2.5 2.6zM400 173.7h3.8zM47 198.6v1zM47 196.6v1zM47 194.5v1.1z"/>
<path d="M47 192.5v1zM47 190.5v1zM47 188.5v1zM47 186.5v1zM47 184.5v1zM47 182.5v1zM47 180.5v1zM54.6 192.2h6.4zM61 185.3v.6zM61 185.9v6.3zM62.2 199.8v.7zM62.2 197.9v1.3z"/>
<path d="M63.5 185.3v.6zM63.5 185.9v6.3zM63.5 192.2h6.3zM69.8 192.2v10.2zM74.9 189.7v2.5zM74.9 197.3v2.5zM74.9 184.6v2.5zM74.9 187.1v2.6zM74.9 199.8v2.6zM110.5 180.5v1zM110.5 182.5v1zM110.5 184.5v1z"/>
<path d="M110.5 186.5v1zM110.5 188.5v1zM110.5 190.5v1zM110.5 192.5v1zM110.5 194.5v1.1zM110.5 196.6v1zM110.5 198.6v1zM123.2 184.6v2.5zM123.2 189.7v2.5zM123.2 197.3v2.5zM123.2 187.1v2.6zM262.9 184.6v35.5z"/>
<path d="M262.9 182.1v2.5zM262.9 182.1h17.7zM262.9 70.3v111.8zM278.1 197.3v2.5zM278.1 199.8v2.6zM278.1 177v20.3zM280.6 182.1h3.1zM280.6 184.6h3.1zM280.6 197.3h5.1zM280.6 199.8h5.1zM278.1 197.3h2.5zM278.1 199.8h2.5z"/>
<path d="M262.9 184.6h17.7zM301 199.8h5zM301 197.3h5zM306 197.3h43.2zM306 199.8h43.2zM351.7 194.8l-2.5 2.5zM351.7 197.3l-2.5 2.5zM351.7 199.8l-2.5 2.6zM47 218.7v1zM47 216.7v1zM47 214.7v1zM47 212.7v1z"/>
<path d="M47 210.6v1.1zM47 208.6v1.1zM47 206.6v1zM47 204.6v1zM47 202.6v1zM47 200.6v1zM54.6 192.2v10.2zM54.6 202.4v2.5zM54.6 204.9v10.1zM54.6 215h20.3zM54.6 204.9h.3zM57.1 202.4h2.6z"/>
<path d="M57.1 204.9h2.6zM54.6 202.4h2.5zM54.9 204.9h2.2zM59.7 202.4v2.5zM62.2 201.1v.6zM64.8 202.4v2.5zM64.8 202.4h2.5zM64.8 204.9h2.5zM67.3 204.9h2.5zM67.3 202.4h2.5zM69.8 202.4v2.5zM74.9 217.6v2.5z"/>
<path d="M74.9 210v2.5zM74.9 204.9v2.5zM74.9 209.5v.5zM74.9 207.4v.5zM74.9 215v2.6zM74.9 212.5v2.5zM74.9 202.4v2.5zM69.8 202.4h5.1zM82.5 202.4h5.1zM74.9 202.4h7.6zM88.8 201.1h.9zM89.7 201.1h1.2z"/>
<path d="M89.7 201.1l1 2.5zM90.7 203.6h1.2zM90.9 201.1l1 2.5zM91.9 203.6h.9zM99.8 202.4h3.1zM102.9 202.4h20.3zM110.5 200.6v1zM110.5 202.6v1zM110.5 204.6v1zM110.5 206.6v1zM110.5 208.6v1.1zM110.5 210.6v1.1z"/>
<path d="M110.5 212.7v1zM110.5 214.7v1zM110.5 216.7v1zM110.5 218.7v1zM116.1 206.6l-.5 .8zM117.3 204.9l-.6 .9zM118.4 203.2l-.6 .9zM119.5 201.5l-.6 .9zM120.6 199.8l-.5 .9zM123.2 202.4h12.7zM123.2 199.8v2.6zM135.9 141.4v61z"/>
<path d="M278.1 202.4v2.5zM278.1 204.9h2.5zM278.1 204.9v2.5zM278.1 207.4v2.6zM278.1 210v2.5zM278.1 212.5v2.5zM278.1 215h2.5zM280.6 202.4h5.1zM280.6 204.9h5.1zM280.6 207.4h5.1zM280.6 210h5.1zM280.6 212.5h5.1z"/>
<path d="M280.6 215h5.1zM278.1 202.4h2.5zM278.1 207.4h2.5zM278.1 212.5h2.5zM278.1 210h2.5zM301 215h5zM301 212.5h5zM301 210h5zM301 207.4h5zM301 204.9h5zM301 202.4h5zM306 202.4h43.2z"/>
<path d="M306 204.9h43.2zM306 207.4h43.2zM306 210h43.2zM306 212.5h43.2zM306 215h43.2zM351.7 202.4l-2.5 2.5zM349.2 207.4l2.5-2.5zM351.7 207.4l-2.5 2.6zM351.7 210l-2.5 2.5zM351.7 212.5l-2.5 2.5zM16.5 224.2h3.8zM47 227.7h1z"/>
<path d="M47 226.8v.9zM47 224.7v1zM47 222.7v1zM47 220.7v1zM49 227.7h1zM51 227.7h1zM53 227.7h1zM55.1 227.7h1zM57.1 227.7h1zM59.1 227.7h1zM61.1 227.7h1zM63.1 227.7h1z"/>
<path d="M65.1 227.7h1zM67.1 227.7h1.1zM69.2 227.7h1zM71.2 227.7h1zM73.2 227.7h1zM75.2 227.7h1zM77.2 227.7h1zM79.2 227.7h1zM81.3 227.7h1zM83.3 227.7h1zM85.3 227.7h1zM87.3 227.7h1z"/>
<path d="M89.3 227.7h1zM91.3 227.7h1zM93.3 227.7h1.1zM95.4 227.7h1zM97.4 227.7h1zM99.4 227.7h1zM101.4 227.7h1zM103.4 227.7h1zM105.4 227.7h1zM107.4 227.7h1.1zM109.5 227.7h1zM110.5 220.7v1z"/>
<path d="M110.5 222.7v1zM110.5 224.7v1zM110.5 226.7v1zM262.9 220.1h15.2zM278.1 220.1h2.5zM278.1 222.7h2.5zM278.1 220.1v2.6zM280.6 220.1h3.1zM280.6 222.7h3.1zM321.6 230.8h11.9zM400 224.2h3.8zM29.2 253.1v2.6z"/>
<path d="M29.2 257.7v.5zM29.2 255.7v.5zM29.2 250.6h7.6zM29.2 250.6v2.5zM36.8 253.1v2.6zM36.8 257.7v.5zM36.8 255.7v.5zM36.8 250.6v2.5zM44.4 253.1v2.6zM44.4 257.7v.5zM44.4 255.7v.5zM44.4 250.6v2.5z"/>
<path d="M44.4 250.6h7.7zM36.8 250.6h7.6zM52.1 253.1v2.6zM52.1 257.7v.5zM52.1 255.7v.5zM52.1 250.6h7.6zM52.1 250.6v2.5zM59.7 245.5v2.6zM59.7 253.1v2.6zM59.7 257.7v.5zM59.7 255.7v.5zM59.7 250.6v2.5z"/>
<path d="M59.7 248.1v2.5zM69.8 248.1v2.5zM69.8 253.1v2.6zM69.8 257.7v.5zM69.8 255.7v.5zM69.8 250.6v2.5zM85.1 258.2v7.6zM85.1 245.5v12.7zM85.1 245.5h2.5zM87.6 245.5h5.1zM87.6 258.2h5.1zM85.1 258.2h2.5z"/>
<path d="M104.8 245.5h3.1zM104.8 258.2h3.1zM118.1 245.5h3.1zM118.1 258.2h3.1zM130 257l-1 2.5zM128.1 259.5h.9zM131.3 257l-1 2.5zM129 259.5h1.3zM130 257h1.3zM131.3 257h.9zM133.3 245.5h5.1zM133.3 258.2h5.1z"/>
<path d="M138.4 258.2h2.5zM138.4 245.5h2.5zM140.9 245.5v12.7zM140.9 258.2v7.6zM143.5 245.5h5.1zM143.5 258.2h5.1zM140.9 245.5h2.6zM140.9 258.2h2.6zM149.7 244.3h.9zM149.7 257h.9zM150.6 244.3h1.3zM150.6 257h1.3z"/>
<path d="M150.6 244.3l1 2.5zM151.6 246.8h1.3zM150.6 257l1 2.5zM151.6 259.5h1.3zM151.9 244.3l1 2.5zM152.9 246.8h.9zM151.9 257l1 2.5zM152.9 259.5h.9zM160.7 245.5h3.1zM160.7 258.2h3.1zM20.3 274.7h379.7zM29.2 258.2v2.6z"/>
<path d="M29.2 265.8v2.6zM29.2 260.8v2.5zM29.2 263.3h7.6zM29.2 263.3v2.5zM36.8 258.2v2.6zM36.8 260.8v2.5zM44.4 258.2v2.6zM44.4 260.8v2.5zM44.4 263.3h7.7zM36.8 263.3h7.6zM52.1 258.2v2.6zM52.1 263.3h7.6z"/>
<path d="M52.1 260.8v2.5zM59.7 258.2v2.6zM59.7 260.8v2.5zM67.8 274.7v3.8zM69.8 265.8v2.6zM69.8 258.2v2.6zM69.8 260.8v5zM85.1 265.8v2.6zM115.3 274.7v3.8zM140.9 265.8v2.6zM162.7 274.7v3.8zM210.2 274.7v3.8z"/>
<path d="M257.6 274.7v3.8zM305.1 274.7v3.8zM352.5 274.7v3.8zM400 264.5v.1zM400 268.4v6.2zM400 274.6h.1zM400 22.1v252.6z"/>
<circle cx="161.3" cy="62.7" r=".51"/>
<circle cx="168.9" cy="62.7" r=".51"/>
<circle cx="267.9" cy="62.7" r=".51"/>
<circle cx="344.1" cy="70.3" r=".51"/>
<circle cx="318.7" cy="95.7" r=".51"/>
<circle cx="344.1" cy="95.7" r=".51"/>
<circle cx="92.7" cy="116" r=".51"/>
<circle cx="168.9" cy="116" r=".51"/>
<circle cx="245.1" cy="103.3" r=".51"/>
<circle cx="344.1" cy="118.6" r=".51"/>
<circle cx="344.1" cy="113.5" r=".51"/>
<circle cx="344.1" cy="110.9" r=".51"/>
<circle cx="344.1" cy="116" r=".51"/>
<circle cx="69.8" cy="128.7" r=".51"/>
<circle cx="82.5" cy="128.7" r=".51"/>
<circle cx="125.7" cy="128.7" r=".51"/>
<circle cx="168.9" cy="128.7" r=".51"/>
<circle cx="273" cy="164.3" r=".51"/>
<circle cx="273" cy="161.7" r=".51"/>
<circle cx="273" cy="166.8" r=".51"/>
<circle cx="278.1" cy="174.4" r=".51"/>
<circle cx="278.1" cy="169.4" r=".51"/>
<circle cx="278.1" cy="177" r=".51"/>
<circle cx="278.1" cy="171.9" r=".51"/>
<circle cx="262.9" cy="184.6" r=".51"/>
<circle cx="262.9" cy="182.1" r=".51"/>
<circle cx="278.1" cy="199.8" r=".51"/>
<circle cx="54.6" cy="202.4" r=".51"/>
<circle cx="54.9" cy="204.9" r=".51"/>
<circle cx="69.8" cy="202.4" r=".51"/>
<circle cx="74.9" cy="202.4" r=".51"/>
<circle cx="74.9" cy="215" r=".51"/>
<circle cx="123.2" cy="202.4" r=".51"/>
<circle cx="278.1" cy="204.9" r=".51"/>
<circle cx="278.1" cy="210" r=".51"/>
<circle cx="278.1" cy="202.4" r=".51"/>
<circle cx="278.1" cy="207.4" r=".51"/>
<circle cx="278.1" cy="212.5" r=".51"/>
<circle cx="278.1" cy="220.1" r=".51"/>
<circle cx="36.8" cy="250.6" r=".51"/>
<circle cx="44.4" cy="250.6" r=".51"/>
<circle cx="52.1" cy="250.6" r=".51"/>
<circle cx="59.7" cy="250.6" r=".51"/>
<circle cx="85.1" cy="258.2" r=".51"/>
<circle cx="140.9" cy="258.2" r=".51"/>
<circle cx="140.9" cy="245.5" r=".51"/>
<circle cx="29.2" cy="263.3" r=".51"/>
<circle cx="36.8" cy="263.3" r=".51"/>
<circle cx="44.4" cy="263.3" r=".51"/>
<circle cx="52.1" cy="263.3" r=".51"/>
</g>
<g fill="#000" stroke="#000" stroke-width=".28">
<path d="M160.4 52.5v5.1zM161.3 44.9l-1.3 1.9zM162.2 52.5v5.1zM160.4 52.5h1.8zM160.4 57.6h1.8zM161.3 44.9l1.2 1.9zM35.2 61.1v3.1zM38.8 68.8v3zM35.2 61.1h12.8zM35.2 64.2h12.8zM38.8 68.8h9.2zM38.8 71.8h9.2z"/>
<path d="M48 61.1l1.5 1.6zM48 64.2l1.5-1.5zM48 68.8l1.5 1.5zM48 71.8l1.5-1.5zM318.7 75.4l-1.2 1.9zM318.7 75.4l1.3 1.9zM379.7 62.7l1.5-1.6zM379.7 62.7l1.5 1.5zM379.7 70.3l1.5-1.5zM379.7 70.3l1.5 1.5zM381.2 61.1h12.8zM381.2 64.2h12.8z"/>
<path d="M381.2 68.8h16.4zM381.2 71.8h16.4zM394 61.1v3.1zM397.6 68.8v3zM82.5 95.7l-1.2 1.9zM82.5 95.7l1.3 1.9zM92.7 95.7l-1.3 1.9zM92.7 95.7l1.3 1.9zM125.7 95.7l-1.3 1.9zM125.7 95.7l1.3 1.9zM317.9 83v5.1zM319.6 83v5.1z"/>
<path d="M317.9 83h1.7zM317.9 88.1h1.7zM32 114.5v3zM32 114.5h16zM32 117.5h16zM48 114.5l1.5 1.5zM48 117.5l1.5-1.5zM81.7 103.3v5.1zM83.4 103.3v5.1zM81.7 103.3h1.7zM81.7 108.4h1.7zM91.8 103.3v5.1z"/>
<path d="M93.6 103.3v5.1zM91.8 103.3h1.8zM91.8 108.4h1.8zM124.8 103.3v5.1zM126.6 103.3v5.1zM124.8 103.3h1.8zM124.8 108.4h1.8zM148.6 112.2v7.6zM31.9 127.2v3zM31.9 127.2h16.1zM31.9 130.2h16.1zM48 127.2l1.5 1.5z"/>
<path d="M49.5 128.7l-1.5 1.5zM74.9 139.8h5.1zM74.9 138v1.8zM74.9 138h5.1zM80 138v1.8zM87.6 137.6l2.6 1.3zM87.6 139.9h.5zM87.6 139.7h.9zM87.6 139.5h1.4zM87.6 139.3h1.8zM87.6 139h2.3zM87.6 138.8h2.4z"/>
<path d="M87.6 138.6h2zM87.6 138.4h1.6zM87.6 138.1h1.1zM87.6 137.9h.7zM87.6 137.7h.2zM90.2 138.9v1.2zM87.6 140.1l2.6-1.2zM90.2 137.6h.2zM90.2 139.9h.2zM90.2 139.7h.2zM90.2 139.5h.2zM90.2 139.3h.2z"/>
<path d="M90.2 139h.2zM90.2 138.8h.2zM90.2 138.6h.2zM90.2 138.4h.2zM90.2 138.1h.2zM90.2 137.9h.2zM90.2 137.7h.2zM90.4 137.6v2.5zM148.6 124.9v7.6zM148.6 137.6v7.6zM276.2 131.3h3.8zM87.6 137.6v2.5z"/>
<path d="M90.2 137.6v2.5zM90.2 140.1h.2zM93.3 146.5h3.9zM278.1 154.1l-1.3 1.9zM278.1 154.1l1.3 1.9zM271.1 171.9h3.8zM60.3 197.9v1.3zM60.3 197.9h1.9zM64.1 197.9v1.3zM62.2 197.9h1.9zM74 192.2v5.1zM74.9 184.6l-1.2 1.9z"/>
<path d="M75.8 192.2v5.1zM74 192.2h1.8zM74 197.3h1.8zM74.9 184.6l1.3 1.9zM122.3 192.2v5.1zM123.2 184.6l-1.3 1.9zM124.1 192.2v5.1zM122.3 192.2h1.8zM122.3 197.3h1.8zM123.2 184.6l1.2 1.9zM59.7 202.4l4.4-1.3zM64.1 202.4h.7z"/>
<path d="M73 220.1h3.8zM59.7 245.5l-1.3 1.9zM59.7 245.5l1.3 1.9zM69.8 248.1l-1.2 1.9zM69.8 248.1l1.3 1.9zM95.2 241.7v7.6zM95.2 254.4v7.6zM130.8 241.7v7.6zM313.7 249.3h86.3zM313.7 254.4h86.3zM313.7 259.5h58.4zM372.1 259.5h27.9z"/>
<path d="M372.1 259.5v5.1zM27.3 268.4h3.8zM67.9 268.4h3.9zM83.2 268.4h3.8zM139 268.4h3.9zM313.7 264.6h58.4zM313.7 269.7h86.3zM372.1 264.6h27.9zM400 268.4v1.3z"/>
</g>
<g fill="none" stroke="#000" stroke-width=".25">
<circle cx="114" cy="116" r=".99"/>
<circle cx="157.2" cy="116" r=".99"/>
<circle cx="284.7" cy="108.4" r="1"/>
<circle cx="284.7" cy="105.9" r="1"/>
<circle cx="114" cy="128.7" r=".99"/>
<circle cx="157.2" cy="128.7" r=".99"/>
<circle cx="284.7" cy="126.2" r="1"/>
<circle cx="301.9" cy="126.2" r="1"/>
<circle cx="157.2" cy="141.4" r=".99"/>
<circle cx="61" cy="184.3" r=".99"/>
<circle cx="63.5" cy="184.3" r=".99"/>
<circle cx="284.7" cy="182.1" r="1"/>
<circle cx="284.7" cy="184.6" r="1"/>
<circle cx="98.8" cy="202.4" r=".99"/>
<circle cx="284.7" cy="220.1" r="1"/>
<circle cx="284.7" cy="222.7" r="1"/>
<circle cx="103.8" cy="258.2" r=".99"/>
<circle cx="103.8" cy="245.5" r=".99"/>
<circle cx="122.2" cy="245.5" r=".99"/>
<circle cx="122.2" cy="258.2" r=".99"/>
<circle cx="159.7" cy="258.2" r=".99"/>
<circle cx="159.7" cy="245.5" r=".99"/>
</g>
<g fill="#000" stroke="#000" stroke-width=".61">
<path d="M20.3 22.1v252.6zM20.3 22.1h379.7zM102.9 110.9v10.2zM102.9 110.9l10.1 5.1zM146 110.9l2.6 1.3zM148.6 112.2l7.6 3.8zM146 121.1l2.6-1.3zM148.6 119.8l7.6-3.8zM285.7 100.8v27.9zM285.7 100.8h15.3zM102.9 123.6l10.1 5.1zM102.9 123.6v10.2z"/>
<path d="M102.9 121.1l10.1-5.1zM102.9 133.8l10.1-5.1zM146 110.9v10.2zM146 123.6l2.6 1.3zM146 123.6v10.2zM146 136.3l2.6 1.3zM148.6 124.9l7.6 3.8zM146 133.8l2.6-1.3zM148.6 137.6l7.6 3.8zM148.6 132.5l7.6-3.8zM285.7 128.7h15.3zM301 100.8v27.9z"/>
<path d="M146 136.3v10.2zM146 146.5l2.6-1.3zM148.6 145.2l7.6-3.8zM285.7 156.7v30.4zM285.7 156.7h15.3zM87.6 197.3l10.2 5.1zM285.7 187.1h15.3zM285.7 194.8v30.4zM301 156.7v30.4zM285.7 194.8h15.3zM87.6 197.3v10.1zM87.6 207.4l10.2-5z"/>
<path d="M285.7 225.2h15.3zM301 194.8v30.4zM92.7 240.4l2.5 1.3zM92.7 240.4v10.2zM92.7 253.1l2.5 1.3zM95.2 241.7l7.7 3.8zM92.7 250.6l2.5-1.3zM95.2 254.4l7.7 3.8zM95.2 249.3l7.7-3.8zM95.2 262l7.7-3.8zM123.2 245.5l7.6-3.8zM123.2 258.2l10.1 5.1z"/>
<path d="M123.2 245.5l7.6 3.8zM130.8 241.7l2.5-1.3zM130.8 249.3l2.5 1.3zM133.3 240.4v10.2zM123.2 258.2l10.1-5.1zM148.6 240.4l10.1 5.1zM148.6 240.4v10.2zM148.6 253.1l10.1 5.1zM148.6 250.6l10.1-5.1zM148.6 263.3l10.1-5.1zM283.2 244.3v30.4zM313.7 254.4v5.1z"/>
<path d="M313.7 249.3v5.1zM313.7 244.3v5zM313.7 244.3h86.3zM283.2 244.3h30.5zM400 254.4v5.1zM400 249.3v5.1zM400 244.3v5zM400 22.1v222.2zM20.3 274.7h262.9zM92.7 253.1v10.2zM92.7 263.3l2.5-1.3zM133.3 253.1v10.2z"/>
<path d="M148.6 253.1v10.2zM283.2 274.7h30.5zM313.7 274.7h86.3zM313.7 269.7v5zM313.7 264.6v5.1zM313.7 259.5v5.1zM400 268.4v6.3zM400 264.6v3.8zM400 259.5v5.1z"/>
</g>
<g fill="none" stroke="#000" stroke-width=".42">
<circle cx="59.7" cy="202.4" r=".13"/>
<circle cx="64.8" cy="202.4" r=".13"/>
</g>
<g fill="#000" stroke="#000" stroke-width=".25">
<path d="M72.9 207.9h4.1v.5h-4.1zM72.9 209h4.1v.5h-4.1zM27.2 256.2h4v.5h-4zM27.2 257.2h4v.5h-4zM34.8 256.2h4.1v.5h-4.1zM34.8 257.2h4.1v.5h-4.1zM42.4 256.2h4.1v.5h-4.1zM42.4 257.2h4.1v.5h-4.1zM50 256.2h4.1v.5h-4.1zM50 257.2h4.1v.5h-4.1zM57.7 256.2h4v.5h-4zM57.7 257.2h4v.5h-4z"/>
<path d="M67.8 256.2h4.1v.5h-4.1zM67.8 257.2h4.1v.5h-4.1zM255.2 249.3h25.4v10.2h-25.4z"/>
</g>
<g fill="#000" stroke="#000" stroke-width=".42">
<path d="M313.7 109v14zM314.9 110.9h1.3zM314.9 113.5h1.3zM314.9 116h1.3zM314.9 118.6h1.3zM321.3 110.9h1.3zM321.3 113.5h1.3zM321.3 116h1.3zM321.3 118.6h1.3zM313.7 109h10.1zM313.7 123h10.1zM314.9 121.1h1.3z"/>
<path d="M321.3 121.1h1.3zM323.8 109v14zM58.4 182.1v7.6zM58.4 189.7h7.6zM66 182.1v7.6zM58.4 182.1h7.6zM224.8 249.3v10.2zM224.8 259.5v12.7zM224.8 259.5h55.8zM280.6 249.3v10.2zM224.8 249.3h55.8zM224.8 272.2h55.8z"/>
<path d="M280.6 259.5v12.7z"/>
</g>
<path d="M16.5 18.2v260.3zM16.5 18.2h387.3zM16.5 278.5h387.3zM403.8 18.2v260.3z" fill="#000" stroke="#000" stroke-width=".32"/>
<path d="M351.7 85.5l5.1-5zM356.8 80.5h22.9zM351.7 85.5v127z" fill="#000" stroke="#000" stroke-width=".76"/>
<use href="#words"/>
</svg>
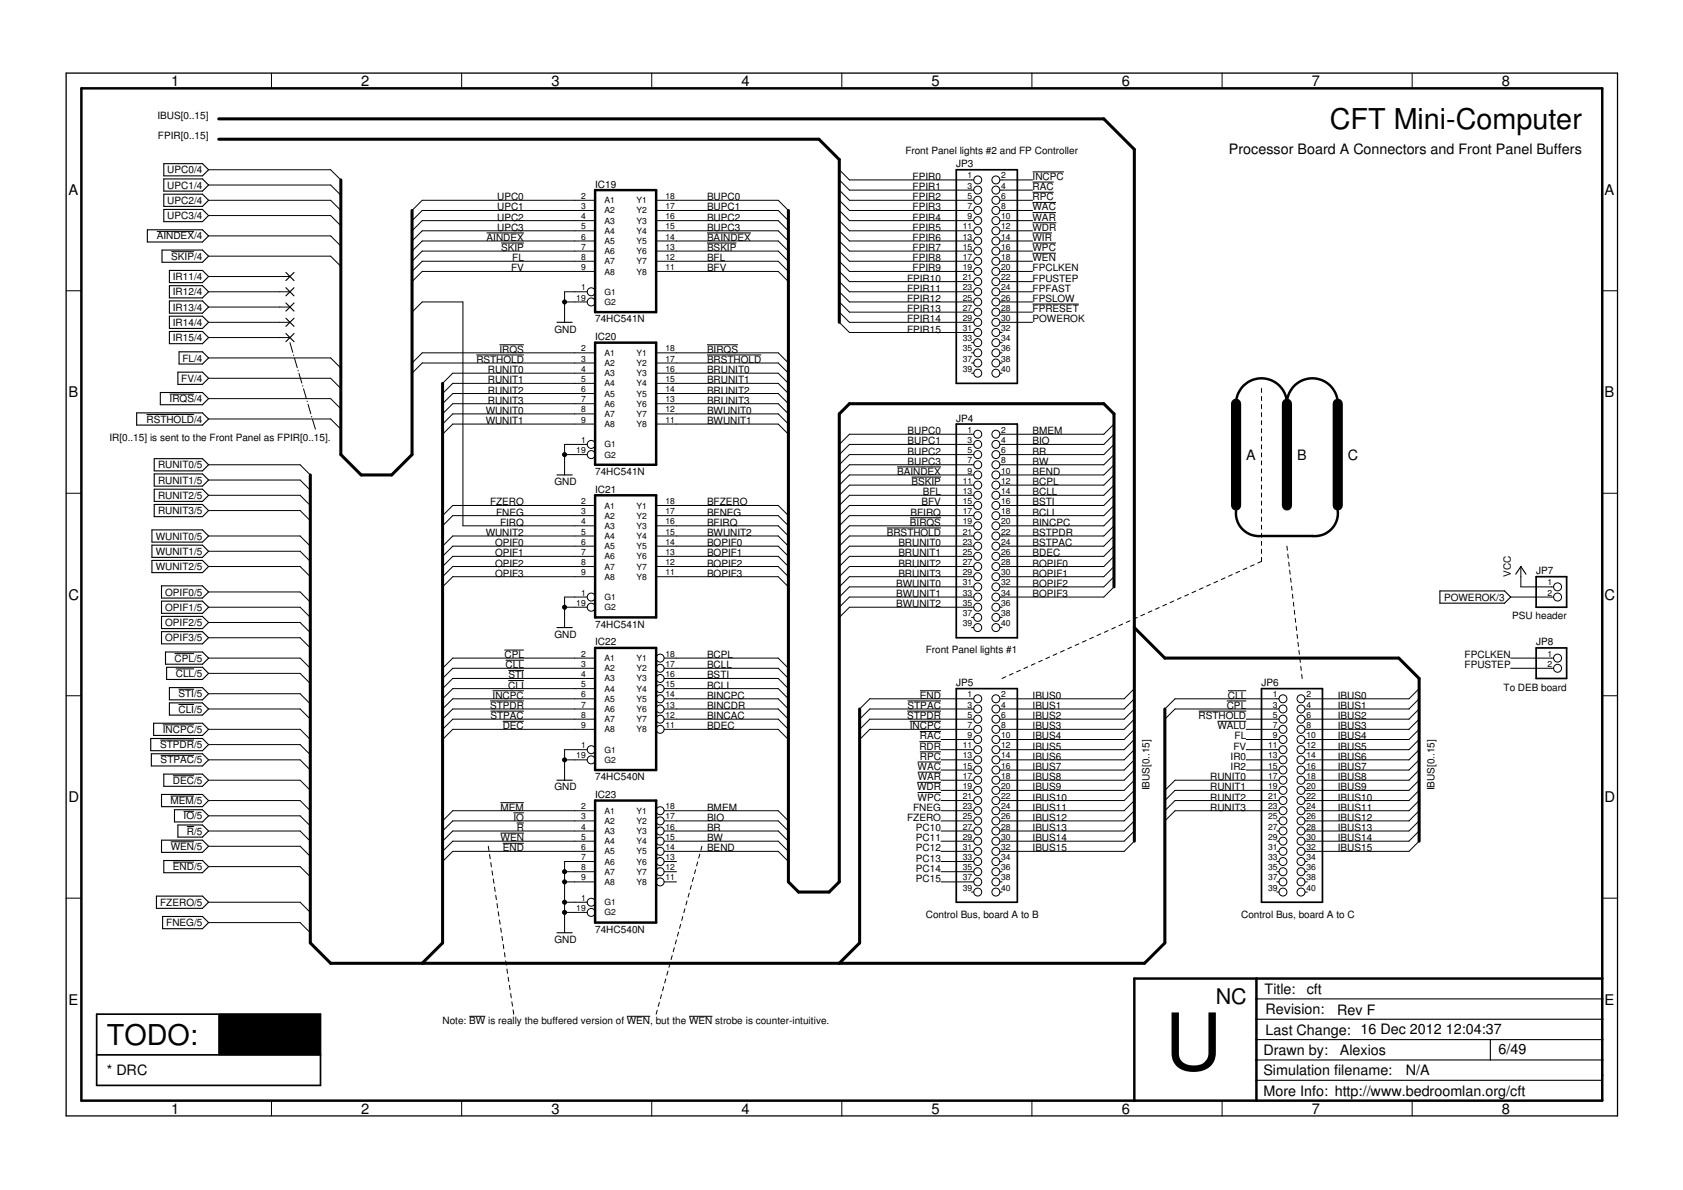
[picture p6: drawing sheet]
<svg xmlns="http://www.w3.org/2000/svg" width="420mm" height="297mm" viewBox="0 0 420 297" stroke-linecap="round" stroke-linejoin="round" font-family="sans-serif">
<defs><g id="words">
<text font-size="19.7" x="290.8" y="267.1">U</text>
<g font-size="7.2">
<text x="332" y="32.2">CFT Mini-Computer</text>
<text x="26.7" y="260.8">TODO:</text>
</g>
<text font-size="5.4" x="303.5" y="250.6">NC</text>
<g font-size="3.7">
<text x="42.7" y="21.5">1</text>
<text x="90.2" y="21.5">2</text>
<text x="137.7" y="21.5">3</text>
<text x="185.1" y="21.5">4</text>
<text x="232.6" y="21.5">5</text>
<text x="280" y="21.5">6</text>
<text x="327.5" y="21.5">7</text>
<text x="375" y="21.5">8</text>
<text x="17.1" y="48.6">A</text>
<text x="400.6" y="48.6">A</text>
<text x="17.1" y="99.2">B</text>
<text x="400.6" y="99.2">B</text>
<text x="17.1" y="149.7">C</text>
<text x="400.6" y="149.7">C</text>
<text x="17.1" y="200.2">D</text>
<text x="400.6" y="200.2">D</text>
<text x="17.1" y="250.8">E</text>
<text x="400.6" y="250.8">E</text>
<text x="42.7" y="277.9">1</text>
<text x="90.2" y="277.9">2</text>
<text x="137.7" y="277.9">3</text>
<text x="185.1" y="277.9">4</text>
<text x="232.6" y="277.9">5</text>
<text x="280" y="277.9">6</text>
<text x="327.5" y="277.9">7</text>
<text x="375" y="277.9">8</text>
</g>
<g font-size="3.6">
<text x="306.8" y="38.6">Processor Board A Connectors and Front Panel Buffers</text>
<text x="311.1" y="114.7">A</text>
<text x="323.8" y="114.7">B</text>
<text x="336.5" y="114.7">C</text>
<text x="315.7" y="248.1">Title:</text>
<text x="326.2" y="248.2">cft</text>
<text x="315.9" y="253.2">Revision:</text>
<text x="333.8" y="253.3">Rev F</text>
<text x="315.4" y="263.3">Drawn by:</text>
<text x="315.9" y="258.2">Last Change: 16 Dec 2012</text>
<text x="334.5" y="263.3">Alexios</text>
<text x="361" y="258.1">12:04:37</text>
<text x="374.1" y="263.2">6/49</text>
<text x="26.7" y="268.4">* DRC</text>
<text x="315.4" y="268.4">Simulation filename:</text>
<text x="351" y="268.4">N/A</text>
<text x="315.4" y="273.5">More Info: http://www.bedroomlan.org/cft</text>
</g>
<g font-size="2.5">
<text x="39.3" y="29.7">IBUS[0..15]</text>
<text x="39.4" y="34.7">FPIR[0..15]</text>
<text x="226" y="38.6">Front Panel lights #2 and FP Controller</text>
<text x="238.7" y="41.7">JP3</text>
<text x="41.8" y="43.3">UPC0/4</text>
<text x="41.8" y="47.1">UPC1/4</text>
<text x="148.6" y="46.8">IC19</text>
<text x="227.8" y="44.9">FPIR0</text>
<text x="227.8" y="47.4">FPIR1</text>
<text x="257.8" y="44.9">INCPC</text>
<text x="257.8" y="47.4">RAC</text>
<text x="41.8" y="50.9">UPC2/4</text>
<text x="124.1" y="50">UPC0</text>
<text x="124.1" y="52.5">UPC1</text>
<text x="176.5" y="50">BUPC0</text>
<text x="176.5" y="52.5">BUPC1</text>
<text x="227.8" y="50">FPIR2</text>
<text x="227.8" y="52.5">FPIR3</text>
<text x="257.8" y="50">RPC</text>
<text x="257.8" y="52.5">WAC</text>
<text x="39.1" y="59.8">AINDEX/4</text>
<text x="41.8" y="54.7">UPC3/4</text>
<text x="124.1" y="55.1">UPC2</text>
<text x="124.1" y="57.6">UPC3</text>
<text x="176.5" y="55.1">BUPC2</text>
<text x="176.5" y="57.6">BUPC3</text>
<text x="227.8" y="55.1">FPIR4</text>
<text x="227.8" y="57.6">FPIR5</text>
<text x="257.8" y="55.1">WAR</text>
<text x="257.8" y="57.6">WDR</text>
<text x="42.8" y="64.8">SKIP/4</text>
<text x="121.5" y="60.1">AINDEX</text>
<text x="125.1" y="62.7">SKIP</text>
<text x="127.9" y="65.2">FL</text>
<text x="176.5" y="60.1">BAINDEX</text>
<text x="176.5" y="62.7">BSKIP</text>
<text x="176.5" y="65.2">BFL</text>
<text x="227.8" y="60.1">FPIR6</text>
<text x="227.8" y="62.7">FPIR7</text>
<text x="227.8" y="65.2">FPIR8</text>
<text x="257.8" y="65.2">WEN</text>
<text x="257.8" y="62.7">WPC</text>
<text x="257.8" y="60.1">WIR</text>
<text x="43.2" y="69.9">IR11/4</text>
<text x="127.6" y="67.8">FV</text>
<text x="176.5" y="67.8">BFV</text>
<text x="226.4" y="70.3">FPIR10</text>
<text x="227.8" y="67.8">FPIR9</text>
<text x="257.8" y="67.8">FPCLKEN</text>
<text x="257.8" y="70.3">FPUSTEP</text>
<text x="43.2" y="73.7">IR12/4</text>
<text x="43.2" y="77.5">IR13/4</text>
<text x="226.4" y="72.8">FPIR11</text>
<text x="226.4" y="75.4">FPIR12</text>
<text x="226.4" y="77.9">FPIR13</text>
<text x="257.8" y="72.8">FPFAST</text>
<text x="257.8" y="75.4">FPSLOW</text>
<text x="257.8" y="77.9">FPRESET</text>
<text x="43.2" y="81.3">IR14/4</text>
<text x="138.4" y="83">GND</text>
<text x="148.6" y="80.5">74HC541N</text>
<text x="226.4" y="80.5">FPIR14</text>
<text x="226.4" y="83">FPIR15</text>
<text x="257.8" y="80.5">POWEROK</text>
<text x="43.2" y="85.2">IR15/4</text>
<text x="124.7" y="88.1">IRQS</text>
<text x="148.6" y="84.9">IC20</text>
<text x="176.5" y="88.1">BIRQS</text>
<text x="45.2" y="95.3">FV/4</text>
<text x="45.5" y="90.2">FL/4</text>
<text x="118.9" y="90.6">RSTHOLD</text>
<text x="121.8" y="93.2">RUNIT0</text>
<text x="121.8" y="95.7">RUNIT1</text>
<text x="176.5" y="90.6">BRSTHOLD</text>
<text x="176.5" y="93.2">BRUNIT0</text>
<text x="176.5" y="95.7">BRUNIT1</text>
<text x="42.4" y="100.4">IRQS/4</text>
<text x="121.8" y="98.2">RUNIT2</text>
<text x="121.8" y="100.8">RUNIT3</text>
<text x="176.5" y="98.2">BRUNIT2</text>
<text x="176.5" y="100.8">BRUNIT3</text>
<text x="36.6" y="105.5">RSTHOLD/4</text>
<text x="121.2" y="103.3">WUNIT0</text>
<text x="121.2" y="105.9">WUNIT1</text>
<text x="176.5" y="103.3">BWUNIT0</text>
<text x="176.5" y="105.9">BWUNIT1</text>
<text x="238.7" y="105.2">JP4</text>
<text x="27.3" y="110.2">IR[0..15] is sent to the Front Panel as FPIR[0..15].</text>
<text x="226.6" y="108.4">BUPC0</text>
<text x="226.6" y="110.9">BUPC1</text>
<text x="226.6" y="113.5">BUPC2</text>
<text x="257.8" y="110.9">BIO</text>
<text x="257.8" y="108.4">BMEM</text>
<text x="257.8" y="113.5">BR</text>
<text x="39.5" y="116.9">RUNIT0/5</text>
<text x="148.6" y="118.6">74HC541N</text>
<text x="224" y="118.6">BAINDEX</text>
<text x="226.6" y="116">BUPC3</text>
<text x="257.8" y="116">BW</text>
<text x="257.8" y="118.6">BEND</text>
<text x="39.5" y="120.7">RUNIT1/5</text>
<text x="39.5" y="124.5">RUNIT2/5</text>
<text x="138.4" y="121.1">GND</text>
<text x="148.6" y="123">IC21</text>
<text x="227.6" y="121.1">BSKIP</text>
<text x="230.4" y="123.6">BFL</text>
<text x="257.8" y="121.1">BCPL</text>
<text x="257.8" y="123.6">BCLL</text>
<text x="39.5" y="128.3">RUNIT3/5</text>
<text x="122.4" y="126.2">FZERO</text>
<text x="123.9" y="128.7">FNEG</text>
<text x="124.8" y="131.3">FIRQ</text>
<text x="176.5" y="126.2">BFZERO</text>
<text x="176.5" y="128.7">BFNEG</text>
<text x="176.5" y="131.3">BFIRQ</text>
<text x="227.2" y="131.3">BIRQS</text>
<text x="227.3" y="128.7">BFIRQ</text>
<text x="230.1" y="126.2">BFV</text>
<text x="257.8" y="126.2">BSTI</text>
<text x="257.8" y="128.7">BCLI</text>
<text x="257.8" y="131.3">BINCPC</text>
<text x="38.9" y="134.7">WUNIT0/5</text>
<text x="121.2" y="133.8">WUNIT2</text>
<text x="123.6" y="136.3">OPIF0</text>
<text x="176.5" y="133.8">BWUNIT2</text>
<text x="176.5" y="136.3">BOPIF0</text>
<text x="221.4" y="133.8">BRSTHOLD</text>
<text x="224.3" y="136.3">BRUNIT0</text>
<text x="257.8" y="133.8">BSTPDR</text>
<text x="257.8" y="136.3">BSTPAC</text>
<text x="38.9" y="138.5">WUNIT1/5</text>
<text x="38.9" y="142.3">WUNIT2/5</text>
<text x="123.6" y="138.9">OPIF1</text>
<text x="123.6" y="141.4">OPIF2</text>
<text x="123.6" y="144">OPIF3</text>
<text x="176.5" y="138.9">BOPIF1</text>
<text x="176.5" y="141.4">BOPIF2</text>
<text x="176.5" y="144">BOPIF3</text>
<text x="224.3" y="138.9">BRUNIT1</text>
<text x="224.3" y="141.4">BRUNIT2</text>
<text x="224.3" y="144">BRUNIT3</text>
<text x="257.8" y="141.4">BOPIF0</text>
<text x="257.8" y="144">BOPIF1</text>
<text x="257.8" y="138.9">BDEC</text>
<text x="377.1" y="144" transform="rotate(-90 377.1 144)">VCC</text>
<text x="383.5" y="143.3">JP7</text>
<text x="41.2" y="148.6">OPIF0/5</text>
<text x="223.7" y="146.5">BWUNIT0</text>
<text x="223.7" y="149">BWUNIT1</text>
<text x="257.8" y="146.5">BOPIF2</text>
<text x="257.8" y="149">BOPIF3</text>
<text x="360.5" y="149.9">POWEROK/3</text>
<text x="41.2" y="152.5">OPIF1/5</text>
<text x="223.7" y="151.6">BWUNIT2</text>
<text x="377.5" y="154.6">PSU header</text>
<text x="41.2" y="156.3">OPIF2/5</text>
<text x="41.2" y="160.1">OPIF3/5</text>
<text x="138.4" y="159.2">GND</text>
<text x="148.6" y="156.6">74HC541N</text>
<text x="148.6" y="161.1">IC22</text>
<text x="383.5" y="161.1">JP8</text>
<text x="43.6" y="165.2">CPL/5</text>
<text x="125.9" y="164.3">CPL</text>
<text x="126.2" y="166.8">CLL</text>
<text x="176.5" y="164.3">BCPL</text>
<text x="176.5" y="166.8">BCLL</text>
<text x="231.1" y="163">Front Panel lights #1</text>
<text x="365.6" y="164.3">FPCLKEN</text>
<text x="365.6" y="166.8">FPUSTEP</text>
<text x="43.9" y="169">CLL/5</text>
<text x="126.9" y="171.9">CLI</text>
<text x="126.9" y="169.3">STI</text>
<text x="176.5" y="169.3">BSTI</text>
<text x="176.5" y="171.9">BCLI</text>
<text x="238.7" y="171.3">JP5</text>
<text x="314.9" y="171.3">JP6</text>
<text x="375.4" y="172.4">To DEB board</text>
<text x="44.6" y="177.9">CLI/5</text>
<text x="44.6" y="174">STI/5</text>
<text x="122.4" y="177">STPDR</text>
<text x="122.5" y="179.5">STPAC</text>
<text x="123" y="174.4">INCPC</text>
<text x="176.5" y="174.4">BINCPC</text>
<text x="176.5" y="177">BINCDR</text>
<text x="176.5" y="179.5">BINCAC</text>
<text x="226.5" y="179.5">STPDR</text>
<text x="226.6" y="177">STPAC</text>
<text x="229.7" y="174.4">END</text>
<text x="257.8" y="174.4">IBUS0</text>
<text x="257.8" y="177">IBUS1</text>
<text x="257.8" y="179.5">IBUS2</text>
<text x="299.2" y="179.5">RSTHOLD</text>
<text x="306.2" y="177">CPL</text>
<text x="306.5" y="174.4">CLL</text>
<text x="334" y="174.4">IBUS0</text>
<text x="334" y="177">IBUS1</text>
<text x="334" y="179.5">IBUS2</text>
<text x="40.6" y="182.9">INCPC/5</text>
<text x="125.5" y="182">DEC</text>
<text x="176.5" y="182">BDEC</text>
<text x="227.1" y="182">INCPC</text>
<text x="229.6" y="184.6">RAC</text>
<text x="257.8" y="182">IBUS3</text>
<text x="257.8" y="184.6">IBUS4</text>
<text x="303.9" y="182">WALU</text>
<text x="308.2" y="184.6">FL</text>
<text x="334" y="182">IBUS3</text>
<text x="334" y="184.6">IBUS4</text>
<text x="40" y="186.7">STPDR/5</text>
<text x="40.1" y="190.6">STPAC/5</text>
<text x="229.5" y="187.1">RDR</text>
<text x="229.6" y="189.7">RPC</text>
<text x="257.8" y="187.1">IBUS5</text>
<text x="257.8" y="189.7">IBUS6</text>
<text x="307.2" y="189.7">IR0</text>
<text x="307.9" y="187.1">FV</text>
<text x="334" y="187.1">IBUS5</text>
<text x="334" y="189.7">IBUS6</text>
<text x="43.2" y="195.6">DEC/5</text>
<text x="138.4" y="197.3">GND</text>
<text x="148.6" y="194.7">74HC540N</text>
<text x="229" y="197.3">WDR</text>
<text x="229.1" y="192.2">WAC</text>
<text x="229.1" y="194.7">WAR</text>
<text x="257.8" y="192.2">IBUS7</text>
<text x="257.8" y="194.7">IBUS8</text>
<text x="257.8" y="197.3">IBUS9</text>
<text x="287" y="197.3" transform="rotate(-90 287 197.3)">IBUS[0..15]</text>
<text x="302.1" y="194.7">RUNIT0</text>
<text x="302.1" y="197.3">RUNIT1</text>
<text x="307.2" y="192.2">IR2</text>
<text x="334" y="192.2">IBUS7</text>
<text x="334" y="194.7">IBUS8</text>
<text x="334" y="197.3">IBUS9</text>
<text x="358.1" y="197.3" transform="rotate(-90 358.1 197.3)">IBUS[0..15]</text>
<text x="42.6" y="200.7">MEM/5</text>
<text x="124.9" y="202.4">MEM</text>
<text x="148.6" y="199.2">IC23</text>
<text x="176.5" y="202.4">BMEM</text>
<text x="228" y="202.4">FNEG</text>
<text x="229.1" y="199.8">WPC</text>
<text x="257.8" y="199.8">IBUS10</text>
<text x="257.8" y="202.4">IBUS11</text>
<text x="302.1" y="199.8">RUNIT2</text>
<text x="302.1" y="202.4">RUNIT3</text>
<text x="334" y="199.8">IBUS10</text>
<text x="334" y="202.4">IBUS11</text>
<text x="45.8" y="204.5">IO/5</text>
<text x="46.6" y="208.3">R/5</text>
<text x="125" y="210">WEN</text>
<text x="128.2" y="204.9">IO</text>
<text x="129" y="207.4">R</text>
<text x="176.5" y="204.9">BIO</text>
<text x="176.5" y="207.4">BR</text>
<text x="176.5" y="210">BW</text>
<text x="226.5" y="204.9">FZERO</text>
<text x="228.6" y="207.4">PC10</text>
<text x="228.6" y="210">PC11</text>
<text x="257.8" y="204.9">IBUS12</text>
<text x="257.8" y="207.4">IBUS13</text>
<text x="257.8" y="210">IBUS14</text>
<text x="334" y="204.9">IBUS12</text>
<text x="334" y="207.4">IBUS13</text>
<text x="334" y="210">IBUS14</text>
<text x="42.6" y="212.1">WEN/5</text>
<text x="125.5" y="212.5">END</text>
<text x="176.5" y="212.5">BEND</text>
<text x="228.6" y="212.5">PC12</text>
<text x="228.6" y="215.1">PC13</text>
<text x="257.8" y="212.5">IBUS15</text>
<text x="334" y="212.5">IBUS15</text>
<text x="43.2" y="217.2">END/5</text>
<text x="228.6" y="217.6">PC14</text>
<text x="228.6" y="220.1">PC15</text>
<text x="40" y="226.1">FZERO/5</text>
<text x="41.5" y="231.2">FNEG/5</text>
<text x="148.6" y="232.8">74HC540N</text>
<text x="231.1" y="229">Control Bus, board A to B</text>
<text x="309.8" y="229">Control Bus, board A to C</text>
<text x="138.4" y="235.4">GND</text>
<text x="110.5" y="255.7">Note: BW is really the buffered version of WEN, but the WEN strobe is counter-intuitive.</text>
</g>
<g font-size="2.1">
<text x="241.6" y="44.6">1</text>
<text x="241.6" y="47.1">3</text>
<text x="250" y="44.6">2</text>
<text x="250" y="47.1">4</text>
<text x="145.1" y="49.6">2</text>
<text x="145.1" y="52.2">3</text>
<text x="150.9" y="50.7">A1</text>
<text x="150.9" y="53.3">A2</text>
<text x="158.9" y="53.3">Y2</text>
<text x="158.9" y="50.7">Y1</text>
<text x="166.1" y="52.2">17</text>
<text x="166.1" y="49.6">18</text>
<text x="241.6" y="49.6">5</text>
<text x="241.6" y="52.2">7</text>
<text x="250" y="49.6">6</text>
<text x="250" y="52.2">8</text>
<text x="145.1" y="54.7">4</text>
<text x="145.1" y="57.2">5</text>
<text x="145.1" y="59.8">6</text>
<text x="150.9" y="55.8">A3</text>
<text x="150.9" y="58.4">A4</text>
<text x="158.9" y="58.4">Y4</text>
<text x="158.9" y="55.8">Y3</text>
<text x="166.1" y="59.8">14</text>
<text x="166.1" y="57.2">15</text>
<text x="166.1" y="54.7">16</text>
<text x="240.4" y="57.2">11</text>
<text x="240.4" y="59.8">13</text>
<text x="241.6" y="54.7">9</text>
<text x="250" y="54.7">10</text>
<text x="250" y="57.2">12</text>
<text x="250" y="59.8">14</text>
<text x="145.1" y="62.3">7</text>
<text x="145.1" y="64.9">8</text>
<text x="150.9" y="60.9">A5</text>
<text x="150.9" y="63.4">A6</text>
<text x="150.9" y="66">A7</text>
<text x="158.9" y="66">Y7</text>
<text x="158.9" y="63.4">Y6</text>
<text x="158.9" y="60.9">Y5</text>
<text x="166.1" y="64.9">12</text>
<text x="166.1" y="62.3">13</text>
<text x="240.4" y="62.3">15</text>
<text x="240.4" y="64.9">17</text>
<text x="250" y="62.3">16</text>
<text x="250" y="64.9">18</text>
<text x="145.1" y="67.4">9</text>
<text x="150.9" y="68.5">A8</text>
<text x="158.9" y="68.5">Y8</text>
<text x="166.1" y="67.4">11</text>
<text x="240.4" y="67.4">19</text>
<text x="240.4" y="69.9">21</text>
<text x="250" y="67.4">20</text>
<text x="250" y="69.9">22</text>
<text x="143.9" y="75">19</text>
<text x="145.1" y="72.5">1</text>
<text x="150.9" y="73.6">G1</text>
<text x="150.9" y="76.1">G2</text>
<text x="240.4" y="72.5">23</text>
<text x="240.4" y="75">25</text>
<text x="240.4" y="77.6">27</text>
<text x="250" y="72.5">24</text>
<text x="250" y="75">26</text>
<text x="250" y="77.6">28</text>
<text x="240.4" y="80.1">29</text>
<text x="240.4" y="82.6">31</text>
<text x="250" y="80.1">30</text>
<text x="250" y="82.6">32</text>
<text x="145.1" y="87.7">2</text>
<text x="150.9" y="88.8">A1</text>
<text x="158.9" y="88.8">Y1</text>
<text x="166.1" y="87.7">18</text>
<text x="240.4" y="85.2">33</text>
<text x="240.4" y="87.7">35</text>
<text x="250" y="85.2">34</text>
<text x="250" y="87.7">36</text>
<text x="145.1" y="90.3">3</text>
<text x="145.1" y="92.8">4</text>
<text x="145.1" y="95.3">5</text>
<text x="150.9" y="91.4">A2</text>
<text x="150.9" y="93.9">A3</text>
<text x="158.9" y="93.9">Y3</text>
<text x="158.9" y="91.4">Y2</text>
<text x="166.1" y="95.3">15</text>
<text x="166.1" y="92.8">16</text>
<text x="166.1" y="90.3">17</text>
<text x="240.4" y="90.3">37</text>
<text x="240.4" y="92.8">39</text>
<text x="250" y="90.3">38</text>
<text x="250" y="92.8">40</text>
<text x="145.1" y="97.9">6</text>
<text x="145.1" y="100.4">7</text>
<text x="150.9" y="96.5">A4</text>
<text x="150.9" y="99">A5</text>
<text x="150.9" y="101.5">A6</text>
<text x="158.9" y="101.5">Y6</text>
<text x="158.9" y="99">Y5</text>
<text x="158.9" y="96.5">Y4</text>
<text x="166.1" y="100.4">13</text>
<text x="166.1" y="97.9">14</text>
<text x="145.1" y="103">8</text>
<text x="145.1" y="105.5">9</text>
<text x="150.9" y="104.1">A7</text>
<text x="150.9" y="106.6">A8</text>
<text x="158.9" y="106.6">Y8</text>
<text x="158.9" y="104.1">Y7</text>
<text x="166.1" y="105.5">11</text>
<text x="166.1" y="103">12</text>
<text x="143.9" y="113.1">19</text>
<text x="145.1" y="110.6">1</text>
<text x="150.9" y="111.7">G1</text>
<text x="241.6" y="108">1</text>
<text x="241.6" y="110.6">3</text>
<text x="241.6" y="113.1">5</text>
<text x="250" y="108">2</text>
<text x="250" y="110.6">4</text>
<text x="250" y="113.1">6</text>
<text x="150.9" y="114.2">G2</text>
<text x="241.6" y="115.7">7</text>
<text x="241.6" y="118.2">9</text>
<text x="250" y="115.7">8</text>
<text x="250" y="118.2">10</text>
<text x="145.1" y="125.8">2</text>
<text x="166.1" y="125.8">18</text>
<text x="240.4" y="120.7">11</text>
<text x="240.4" y="123.3">13</text>
<text x="240.4" y="125.8">15</text>
<text x="250" y="120.7">12</text>
<text x="250" y="123.3">14</text>
<text x="250" y="125.8">16</text>
<text x="145.1" y="128.4">3</text>
<text x="145.1" y="130.9">4</text>
<text x="150.9" y="126.9">A1</text>
<text x="150.9" y="129.5">A2</text>
<text x="158.9" y="129.5">Y2</text>
<text x="158.9" y="126.9">Y1</text>
<text x="166.1" y="130.9">16</text>
<text x="166.1" y="128.4">17</text>
<text x="240.4" y="128.4">17</text>
<text x="240.4" y="130.9">19</text>
<text x="250" y="128.4">18</text>
<text x="250" y="130.9">20</text>
<text x="145.1" y="133.4">5</text>
<text x="145.1" y="136">6</text>
<text x="150.9" y="132">A3</text>
<text x="150.9" y="134.6">A4</text>
<text x="150.9" y="137.1">A5</text>
<text x="158.9" y="137.1">Y5</text>
<text x="158.9" y="134.6">Y4</text>
<text x="158.9" y="132">Y3</text>
<text x="166.1" y="136">14</text>
<text x="166.1" y="133.4">15</text>
<text x="240.4" y="133.4">21</text>
<text x="240.4" y="136">23</text>
<text x="250" y="133.4">22</text>
<text x="250" y="136">24</text>
<text x="145.1" y="138.5">7</text>
<text x="145.1" y="141.1">8</text>
<text x="145.1" y="143.6">9</text>
<text x="150.9" y="139.6">A6</text>
<text x="150.9" y="142.2">A7</text>
<text x="158.9" y="142.2">Y7</text>
<text x="158.9" y="139.6">Y6</text>
<text x="166.1" y="143.6">11</text>
<text x="166.1" y="141.1">12</text>
<text x="166.1" y="138.5">13</text>
<text x="240.4" y="138.5">25</text>
<text x="240.4" y="141.1">27</text>
<text x="240.4" y="143.6">29</text>
<text x="250" y="138.5">26</text>
<text x="250" y="141.1">28</text>
<text x="250" y="143.6">30</text>
<text x="145.1" y="148.7">1</text>
<text x="150.9" y="149.8">G1</text>
<text x="150.9" y="144.7">A8</text>
<text x="158.9" y="144.7">Y8</text>
<text x="240.4" y="146.1">31</text>
<text x="240.4" y="148.7">33</text>
<text x="250" y="146.1">32</text>
<text x="250" y="148.7">34</text>
<text x="386.3" y="146.1">1</text>
<text x="386.3" y="148.7">2</text>
<text x="143.9" y="151.2">19</text>
<text x="150.9" y="152.3">G2</text>
<text x="240.4" y="151.2">35</text>
<text x="240.4" y="153.8">37</text>
<text x="250" y="151.2">36</text>
<text x="250" y="153.8">38</text>
<text x="240.4" y="156.3">39</text>
<text x="250" y="156.3">40</text>
<text x="145.1" y="163.9">2</text>
<text x="145.1" y="166.5">3</text>
<text x="150.9" y="165">A1</text>
<text x="150.9" y="167.6">A2</text>
<text x="158.9" y="167.6">Y2</text>
<text x="158.9" y="165">Y1</text>
<text x="166.1" y="166.5">17</text>
<text x="166.1" y="163.9">18</text>
<text x="386.3" y="163.9">1</text>
<text x="386.3" y="166.5">2</text>
<text x="145.1" y="169">4</text>
<text x="145.1" y="171.5">5</text>
<text x="150.9" y="170.1">A3</text>
<text x="150.9" y="172.6">A4</text>
<text x="158.9" y="172.6">Y4</text>
<text x="158.9" y="170.1">Y3</text>
<text x="166.1" y="171.5">15</text>
<text x="166.1" y="169">16</text>
<text x="145.1" y="174.1">6</text>
<text x="145.1" y="176.6">7</text>
<text x="145.1" y="179.1">8</text>
<text x="150.9" y="175.2">A5</text>
<text x="150.9" y="177.7">A6</text>
<text x="158.9" y="177.7">Y6</text>
<text x="158.9" y="175.2">Y5</text>
<text x="166.1" y="179.1">12</text>
<text x="166.1" y="176.6">13</text>
<text x="166.1" y="174.1">14</text>
<text x="241.6" y="174.1">1</text>
<text x="241.6" y="176.6">3</text>
<text x="241.6" y="179.1">5</text>
<text x="250" y="174.1">2</text>
<text x="250" y="176.6">4</text>
<text x="250" y="179.1">6</text>
<text x="317.8" y="174.1">1</text>
<text x="317.8" y="176.6">3</text>
<text x="317.8" y="179.1">5</text>
<text x="326.1" y="174.1">2</text>
<text x="326.1" y="176.6">4</text>
<text x="326.1" y="179.1">6</text>
<text x="145.1" y="181.7">9</text>
<text x="150.9" y="180.3">A7</text>
<text x="150.9" y="182.8">A8</text>
<text x="158.9" y="182.8">Y8</text>
<text x="158.9" y="180.3">Y7</text>
<text x="166.1" y="181.7">11</text>
<text x="241.6" y="181.7">7</text>
<text x="241.6" y="184.2">9</text>
<text x="250" y="181.7">8</text>
<text x="250" y="184.2">10</text>
<text x="317.8" y="181.7">7</text>
<text x="317.8" y="184.2">9</text>
<text x="326.1" y="181.7">8</text>
<text x="326.1" y="184.2">10</text>
<text x="143.9" y="189.3">19</text>
<text x="145.1" y="186.8">1</text>
<text x="150.9" y="187.9">G1</text>
<text x="150.9" y="190.4">G2</text>
<text x="240.4" y="186.8">11</text>
<text x="240.4" y="189.3">13</text>
<text x="240.4" y="191.8">15</text>
<text x="250" y="186.8">12</text>
<text x="250" y="189.3">14</text>
<text x="250" y="191.8">16</text>
<text x="316.6" y="186.8">11</text>
<text x="316.6" y="189.3">13</text>
<text x="316.6" y="191.8">15</text>
<text x="326.1" y="186.8">12</text>
<text x="326.1" y="189.3">14</text>
<text x="326.1" y="191.8">16</text>
<text x="240.4" y="194.4">17</text>
<text x="240.4" y="196.9">19</text>
<text x="250" y="194.4">18</text>
<text x="250" y="196.9">20</text>
<text x="316.6" y="194.4">17</text>
<text x="316.6" y="196.9">19</text>
<text x="326.1" y="194.4">18</text>
<text x="326.1" y="196.9">20</text>
<text x="145.1" y="202">2</text>
<text x="150.9" y="203.1">A1</text>
<text x="158.9" y="203.1">Y1</text>
<text x="166.1" y="202">18</text>
<text x="240.4" y="199.5">21</text>
<text x="240.4" y="202">23</text>
<text x="250" y="199.5">22</text>
<text x="250" y="202">24</text>
<text x="316.6" y="199.5">21</text>
<text x="316.6" y="202">23</text>
<text x="326.1" y="199.5">22</text>
<text x="326.1" y="202">24</text>
<text x="145.1" y="204.5">3</text>
<text x="145.1" y="207.1">4</text>
<text x="145.1" y="209.6">5</text>
<text x="150.9" y="205.7">A2</text>
<text x="150.9" y="208.2">A3</text>
<text x="158.9" y="208.2">Y3</text>
<text x="158.9" y="205.7">Y2</text>
<text x="166.1" y="209.6">15</text>
<text x="166.1" y="207.1">16</text>
<text x="166.1" y="204.5">17</text>
<text x="240.4" y="204.5">25</text>
<text x="240.4" y="207.1">27</text>
<text x="240.4" y="209.6">29</text>
<text x="250" y="204.5">26</text>
<text x="250" y="207.1">28</text>
<text x="250" y="209.6">30</text>
<text x="316.6" y="204.5">25</text>
<text x="316.6" y="207.1">27</text>
<text x="316.6" y="209.6">29</text>
<text x="326.1" y="204.5">26</text>
<text x="326.1" y="207.1">28</text>
<text x="326.1" y="209.6">30</text>
<text x="145.1" y="212.2">6</text>
<text x="145.1" y="214.7">7</text>
<text x="150.9" y="210.7">A4</text>
<text x="150.9" y="213.3">A5</text>
<text x="150.9" y="215.8">A6</text>
<text x="158.9" y="215.8">Y6</text>
<text x="158.9" y="213.3">Y5</text>
<text x="158.9" y="210.7">Y4</text>
<text x="166.1" y="214.7">13</text>
<text x="166.1" y="212.2">14</text>
<text x="240.4" y="212.2">31</text>
<text x="240.4" y="214.7">33</text>
<text x="250" y="212.2">32</text>
<text x="250" y="214.7">34</text>
<text x="316.6" y="212.2">31</text>
<text x="316.6" y="214.7">33</text>
<text x="326.1" y="212.2">32</text>
<text x="326.1" y="214.7">34</text>
<text x="145.1" y="217.2">8</text>
<text x="145.1" y="219.8">9</text>
<text x="150.9" y="218.4">A7</text>
<text x="150.9" y="220.9">A8</text>
<text x="158.9" y="220.9">Y8</text>
<text x="158.9" y="218.4">Y7</text>
<text x="166.1" y="219.8">11</text>
<text x="166.1" y="217.2">12</text>
<text x="240.4" y="217.2">35</text>
<text x="240.4" y="219.8">37</text>
<text x="250" y="217.2">36</text>
<text x="250" y="219.8">38</text>
<text x="316.6" y="217.2">35</text>
<text x="316.6" y="219.8">37</text>
<text x="326.1" y="217.2">36</text>
<text x="326.1" y="219.8">38</text>
<text x="143.9" y="227.4">19</text>
<text x="145.1" y="224.9">1</text>
<text x="150.9" y="226">G1</text>
<text x="240.4" y="222.3">39</text>
<text x="250" y="222.3">40</text>
<text x="316.6" y="222.3">39</text>
<text x="326.1" y="222.3">40</text>
<text x="150.9" y="228.5">G2</text>
</g>
</g></defs>
<path d="M308.6 100.8a6.3 6.3 0 0 1 6.3-6.4 6.3 6.3 0 0 1 6.4 6.4 6.3 6.3 0 0 1 6.3-6.4 6.3 6.3 0 0 1 6.4 6.4M308.6 127.4a5.7 5.7 0 0 0 6.3 6.4M334 127.4a5.7 5.7 0 0 1-6.4 6.4" fill="none" stroke="#000" stroke-width=".61"/>
<g fill="#000" stroke="#000" stroke-width=".61">
<path d="M20.3 22.1v252.6zM20.3 22.1h379.7zM148.6 47.5v30.4zM148.6 47.5h15.2zM148.6 77.9h15.2zM163.8 47.5v30.4zM148.6 85.5v30.5zM148.6 85.5h15.2zM148.6 116h15.2zM163.8 85.5v30.5zM148.6 123.6v30.5zM148.6 123.6h15.2z"/>
<path d="M314.9 133.8h12.7zM148.6 154.1h15.2zM163.8 123.6v30.5zM148.6 161.7v30.5zM148.6 161.7h15.2zM148.6 192.2h15.2zM148.6 199.8v30.5zM163.8 161.7v30.5zM148.6 199.8h15.2zM148.6 230.3h15.2zM163.8 199.8v30.5zM283.2 244.3v30.4z"/>
<path d="M313.7 254.4v5.1zM313.7 249.3v5.1zM313.7 244.3v5zM313.7 244.3h86.3zM283.2 244.3h30.5zM400 254.4v5.1zM400 249.3v5.1zM400 244.3v5zM400 22.1v222.2zM20.3 274.7h262.9zM283.2 274.7h30.5zM313.7 274.7h86.3z"/>
<path d="M313.7 269.7v5zM313.7 264.6v5.1zM313.7 259.5v5.1zM400 268.4v6.3zM400 264.6v3.8zM400 259.5v5.1z"/>
</g>
<g fill="#000" stroke="#000" stroke-width=".25">
<path d="M67.8 18.2v3.9zM115.3 18.2v3.9zM162.7 18.2v3.9zM210.2 18.2v3.9zM257.6 18.2v3.9zM305.1 18.2v3.9zM352.5 18.2v3.9zM20.3 22.1v252.6zM20.3 22.1h379.7zM39.1 57.8h9.3zM52.1 42.4h30.4zM52.1 46.2h30.4z"/>
<path d="M52.1 50h30.4zM52.1 53.8h30.4zM52.1 58.9h30.4zM82.5 58.9l2.6 2.5zM82.5 42.4l2.6 2.5zM82.5 46.2l2.6 2.5zM82.5 50l2.6 2.5zM82.5 53.8l2.6 2.5zM102.9 52.5l2.5-2.5zM102.9 55.1l2.5-2.6zM102.9 57.6l2.5-2.5zM105.4 50h38.1z"/>
<path d="M105.4 52.5h38.1zM105.4 55.1h38.1zM105.4 57.6h38.1zM121.5 58.1h9.3zM143.5 50h5.1zM143.5 52.5h5.1zM143.5 55.1h5.1zM143.5 57.6h5.1zM163.8 57.6h5.1zM163.8 55.1h5.1zM163.8 52.5h5.1zM163.8 50h5.1z"/>
<path d="M176.5 58.1h11zM168.9 50h25.4zM168.9 52.5h25.4zM168.9 55.1h25.4zM168.9 57.6h25.4zM194.3 50l2.5 2.5zM194.3 52.5l2.5 2.6zM194.3 55.1l2.5 2.5zM209.5 42.4l2.6 2.5zM209.5 44.9l2.6 2.6zM209.5 47.5l2.6 2.5zM209.5 50l2.6 2.5z"/>
<path d="M209.5 52.5l2.6 2.6zM209.5 55.1l2.6 2.5zM242.5 44.9h.6zM242.5 47.5h.6zM242.5 50h.6zM242.5 52.5h.6zM242.5 55.1h.6zM242.5 57.6h.6zM212.1 44.9h30.4zM212.1 47.5h30.4zM212.1 50h30.4zM212.1 52.5h30.4z"/>
<path d="M212.1 55.1h30.4zM212.1 57.6h30.4zM249.6 44.9h.6zM249.6 47.5h.6zM249.6 50h.6zM249.6 52.5h.6zM249.6 55.1h.6zM249.6 57.6h.6zM250.2 44.9h7.6zM250.2 50h7.6zM250.2 47.5h7.6zM250.2 55.1h7.6z"/>
<path d="M250.2 57.6h7.6zM250.2 52.5h7.6zM257.8 42.9h7.8zM257.8 48h5.3zM257.8 45.4h5.3zM257.8 53.1h5.8zM257.8 55.6h5.9zM257.8 50.5h5.8zM257.8 58.1h4.8zM16.5 72.6h3.8zM42.8 62.8h5.6zM52.1 69h17.7z"/>
<path d="M52.1 72.8h17.7zM52.1 76.6h17.7zM69.8 69h2.6zM69.8 72.8h2.6zM69.8 76.6h2.6zM52.1 63.9h30.4zM82.5 63.9l2.6 2.6zM102.9 62.7l2.5-2.5zM102.9 65.2l2.5-2.5zM102.9 70.3l2.5-2.5zM102.9 67.8l2.5-2.6zM102.9 60.2l2.5-2.6z"/>
<path d="M102.9 77.9l2.5-2.5zM105.4 60.2h38.1zM105.4 62.7h38.1zM105.4 67.8h38.1zM105.4 65.2h38.1zM105.4 75.4h10.2zM125.1 60.7h5.7zM140.9 77.9v2.6zM140.9 75.4v2.5zM140.9 72.8v2.6zM143.5 72.8h3.1zM143.5 60.2h5.1z"/>
<path d="M143.5 62.7h5.1zM143.5 65.2h5.1zM143.5 67.8h5.1zM143.5 75.4h3.1zM140.9 75.4h2.6zM140.9 72.8h2.6zM163.8 67.8h5.1zM163.8 65.2h5.1zM163.8 62.7h5.1zM163.8 60.2h5.1zM176.5 60.7h7.4zM168.9 60.2h25.4z"/>
<path d="M168.9 62.7h25.4zM168.9 65.2h25.4zM168.9 67.8h25.4zM194.3 57.6l2.5 2.6zM194.3 60.2l2.5 2.5zM194.3 62.7l2.5 2.5zM194.3 65.2l2.5 2.6zM194.3 67.8l2.5 2.5zM209.5 57.6l2.6 2.6zM209.5 60.2l2.6 2.5zM209.5 62.7l2.6 2.5zM209.5 65.2l2.6 2.6z"/>
<path d="M209.5 67.8l2.6 2.5zM209.5 70.3l2.6 2.5zM209.5 72.8l2.6 2.6zM209.5 75.4l2.6 2.5zM242.5 60.2h.6zM242.5 62.7h.6zM242.5 65.2h.6zM242.5 67.8h.6zM242.5 70.3h.6zM242.5 72.8h.6zM242.5 75.4h.6zM242.5 77.9h.6z"/>
<path d="M212.1 60.2h30.4zM212.1 62.7h30.4zM212.1 65.2h30.4zM212.1 67.8h30.4zM212.1 70.3h30.4zM212.1 72.8h30.4zM212.1 75.4h30.4zM212.1 77.9h30.4zM249.6 60.2h.6zM249.6 62.7h.6zM249.6 65.2h.6zM249.6 67.8h.6z"/>
<path d="M249.6 70.3h.6zM249.6 72.8h.6zM249.6 75.4h.6zM249.6 77.9h.6zM250.2 65.2h7.6zM250.2 70.3h7.6zM250.2 72.8h7.6zM250.2 75.4h7.6zM250.2 77.9h7.6zM250.2 62.7h7.6zM250.2 60.2h7.6zM257.8 63.2h5.8z"/>
<path d="M257.8 75.9h11.5zM257.8 60.7h5.8zM250.2 67.8h7.6zM400 72.6h3.8zM42.4 98.4h6zM52.1 80.5h17.7zM52.1 84.3h17.7zM69.8 80.5h2.6zM69.8 84.3h2.6zM72.4 85.5l.7 2.4zM73.3 88.6v.1zM73.5 89.4l.7 2.4z"/>
<path d="M74.4 92.4v.2zM74.6 93.2l.8 2.4zM75.5 96.3l.1 .1zM75.8 97l.7 2.5zM52.1 99.5h30.4zM82.5 99.5l2.6 2.5zM52.1 94.4h30.4zM82.5 94.4l2.6 2.6zM52.1 89.3h30.4zM82.5 89.3l2.6 2.6zM102.9 93.2l2.5-2.6zM102.9 90.6l2.5-2.5z"/>
<path d="M105.4 90.6h38.1zM105.4 88.1h38.1zM110.5 95.7l2.5-2.5zM110.5 98.2l2.5-2.5zM113 93.2h30.5zM113 95.7h30.5zM113 98.2h30.5zM118.9 88.6h11.9zM124.7 86.1h6.1zM143.5 88.1h5.1zM143.5 90.6h5.1zM143.5 93.2h5.1z"/>
<path d="M143.5 95.7h5.1zM143.5 98.2h5.1zM163.8 98.2h5.1zM163.8 95.7h5.1zM163.8 93.2h5.1zM163.8 90.6h5.1zM163.8 88.1h5.1zM176.5 86.1h7.8zM176.5 88.6h13.5zM168.9 88.1h25.4zM168.9 90.6h25.4zM168.9 93.2h25.4z"/>
<path d="M168.9 95.7h25.4zM168.9 98.2h25.4zM194.3 88.1l2.5 2.5zM194.3 90.6l2.5 2.6zM194.3 93.2l2.5 2.5zM194.3 95.7l2.5 2.5zM209.5 77.9l2.6 2.6zM209.5 80.5l2.6 2.5zM242.5 80.5h.6zM242.5 83h.6zM242.5 85.5h.6zM242.5 88.1h.6z"/>
<path d="M242.5 90.6h.6zM242.5 93.2h.6zM212.1 80.5h30.4zM212.1 83h30.4zM249.6 80.5h.6zM249.6 83h.6zM249.6 85.5h.6zM249.6 88.1h.6zM249.6 90.6h.6zM249.6 93.2h.6zM250.2 80.5h7.6zM314.9 97v1z"/>
<path d="M314.9 99v1zM36.6 103.5h11.8zM52.1 119.8h22.8zM52.1 116h22.8zM74.9 116l2.6 2.6zM74.9 119.8l2.6 2.6zM76.7 100.1v.1zM76.9 100.9l.7 2.4zM77.8 103.9v.2zM78 104.7l.7 2.4zM52.1 104.6h30.4zM82.5 104.6l2.6 2.5z"/>
<path d="M110.5 100.8l2.5-2.6zM110.5 103.3l2.5-2.5zM110.5 105.9l2.5-2.6zM110.5 108.4l2.5-2.5zM113 100.8h30.5zM113 103.3h30.5zM113 105.9h30.5zM140.9 116v2.6zM140.9 113.5v2.5zM140.9 110.9v2.6zM143.5 110.9h3.1zM143.5 100.8h5.1z"/>
<path d="M143.5 103.3h5.1zM143.5 105.9h5.1zM143.5 113.5h3.1zM140.9 113.5h2.6zM140.9 110.9h2.6zM163.8 105.9h5.1zM163.8 103.3h5.1zM163.8 100.8h5.1zM168.9 100.8h25.4zM168.9 103.3h25.4zM168.9 105.9h25.4zM194.3 98.2l2.5 2.6z"/>
<path d="M194.3 100.8l2.5 2.5zM194.3 103.3l2.5 2.6zM194.3 105.9l2.5 2.5zM209.5 110.9l2.6-2.5zM212.1 110.9l-2.6 2.6zM209.5 116l2.6-2.5zM209.5 118.6l2.6-2.6zM212.1 108.4h30.4zM212.1 110.9h30.4zM212.1 113.5h30.4zM212.1 116h30.4zM212.1 118.6h30.4z"/>
<path d="M224 116.5h10.9zM227.6 119.1h7.3zM242.5 108.4h.6zM242.5 110.9h.6zM242.5 113.5h.6zM242.5 116h.6zM242.5 118.6h.6zM249.6 108.4h.6zM249.6 110.9h.6zM249.6 113.5h.6zM249.6 116h.6zM249.6 118.6h.6z"/>
<path d="M250.2 110.9h25.4zM250.2 108.4h25.4zM250.2 113.5h25.4zM250.2 116h25.4zM250.2 118.6h25.4zM278.1 108.4l-2.5 2.5zM278.1 105.9l-2.5 2.5zM278.1 110.9l-2.5 2.6zM278.1 113.5l-2.5 2.5zM278.1 116l-2.5 2.6zM314.9 101v1zM314.9 103v1z"/>
<path d="M314.9 105v1zM314.9 107v1zM314.9 109v1zM314.9 111v1zM314.9 113v1zM314.9 115v1.1zM314.9 117v1zM314.9 119.1v1zM16.5 123.1h3.8zM52.1 133.8h22.8zM52.1 123.6h22.8zM74.9 123.6l2.6 2.6z"/>
<path d="M52.1 127.4h22.8zM74.9 127.4l2.6 2.6zM74.9 133.8l2.6 2.5zM52.1 137.6h22.8zM74.9 137.6l2.6 2.5zM110.5 136.3l2.5-2.5zM110.5 138.9l2.5-2.6zM113 133.8h30.5zM113 136.3h30.5zM113 138.9h30.5zM110.5 131.3l2.5-2.6zM113 126.2l-2.5 2.5z"/>
<path d="M115.6 75.4v55.9zM143.5 126.2h5.1zM143.5 128.7h5.1zM143.5 131.3h5.1zM143.5 133.8h5.1zM143.5 136.3h5.1zM143.5 138.9h5.1zM113 128.7h30.5zM113 126.2h30.5zM115.6 131.3h27.9zM163.8 138.9h5.1zM163.8 136.3h5.1z"/>
<path d="M163.8 133.8h5.1zM163.8 131.3h5.1zM163.8 128.7h5.1zM163.8 126.2h5.1zM168.9 126.2h25.4zM168.9 128.7h25.4zM168.9 131.3h25.4zM168.9 133.8h25.4zM168.9 136.3h25.4zM168.9 138.9h25.4zM194.3 126.2l2.5 2.5zM194.3 128.7l2.5 2.6z"/>
<path d="M194.3 131.3l2.5 2.5zM194.3 133.8l2.5 2.5zM194.3 136.3l2.5 2.6zM212.1 118.6l-2.6 2.5zM209.5 123.6l2.6-2.5zM209.5 126.2l2.6-2.6zM212.1 126.2l-2.6 2.5zM212.1 131.3l-2.6 2.5zM209.5 136.3l2.6-2.5zM209.5 138.9l2.6-2.6zM212.1 121.1h30.4zM212.1 123.6h30.4z"/>
<path d="M212.1 126.2h30.4zM212.1 131.3h30.4zM212.1 133.8h30.4zM212.1 136.3h30.4zM212.1 138.9h30.4zM212.1 128.7l-2.6 2.6zM221.4 131.8h13.5zM227.2 129.2h7.7zM242.5 121.1h.6zM242.5 123.6h.6zM242.5 126.2h.6zM242.5 128.7h.6z"/>
<path d="M242.5 131.3h.6zM242.5 133.8h.6zM242.5 136.3h.6zM242.5 138.9h.6zM212.1 128.7h30.4zM249.6 121.1h.6zM249.6 123.6h.6zM249.6 126.2h.6zM249.6 128.7h.6zM249.6 131.3h.6zM249.6 133.8h.6zM249.6 136.3h.6z"/>
<path d="M249.6 138.9h.6zM250.2 121.1h25.4zM250.2 123.6h25.4zM250.2 126.2h25.4zM250.2 128.7h25.4zM250.2 131.3h25.4zM250.2 138.9h25.4zM250.2 133.8h25.4zM250.2 136.3h25.4zM278.1 118.6l-2.5 2.5zM278.1 121.1l-2.5 2.5zM275.6 126.2l2.5-2.6z"/>
<path d="M278.1 126.2l-2.5 2.5zM278.1 128.7l-2.5 2.6zM278.1 136.3l-2.5 2.6zM275.6 133.8l2.5-2.5zM278.1 133.8l-2.5 2.5zM278.1 138.9l-2.5 2.5zM314.9 121.1v1zM314.9 123.1v1zM314.9 125.1v1zM314.9 127.1v1zM314.9 129.1v1zM314.9 131.1v1z"/>
<path d="M314.9 133.1v1zM314.9 135.1v1zM314.9 137.1v1zM314.9 139.1v1zM321.3 136.3l.1 1zM321.5 138.3l.1 1zM400 123.1h3.8zM52.1 147.8h22.8zM52.1 151.6h22.8zM52.1 155.4h22.8zM52.1 159.2h22.8zM52.1 141.4h22.8z"/>
<path d="M74.9 141.4l2.6 2.6zM74.9 147.8l2.6 2.5zM74.9 151.6l2.6 2.5zM74.9 155.4l2.6 2.5zM74.9 159.2l2.6 2.5zM110.5 141.4l2.5-2.5zM110.5 144l2.5-2.6zM110.5 146.5l2.5-2.5zM113 141.4h30.5zM113 144h30.5zM140.9 154.1v2.6zM140.9 151.6v2.5z"/>
<path d="M140.9 149v2.6zM143.5 149h3.1zM143.5 141.4h5.1zM143.5 144h5.1zM143.5 151.6h3.1zM140.9 151.6h2.6zM140.9 149h2.6zM163.8 144h5.1zM163.8 141.4h5.1zM168.9 141.4h25.4zM168.9 144h25.4zM194.3 138.9l2.5 2.5z"/>
<path d="M194.3 141.4l2.5 2.6zM194.3 144l2.5 2.5zM212.1 138.9l-2.6 2.5zM209.5 144l2.6-2.6zM209.5 146.5l2.6-2.5zM212.1 146.5l-2.6 2.5zM209.5 151.6l2.6-2.6zM209.5 154.1l2.6-2.5zM212.1 141.4h30.4zM212.1 144h30.4zM212.1 146.5h30.4zM212.1 149h30.4z"/>
<path d="M212.1 151.6h30.4zM242.5 141.4h.6zM242.5 144h.6zM242.5 146.5h.6zM242.5 149h.6zM242.5 151.6h.6zM242.5 154.1h.6zM242.5 156.7h.6zM249.6 141.4h.6zM249.6 144h.6zM249.6 146.5h.6zM249.6 149h.6z"/>
<path d="M249.6 151.6h.6zM249.6 154.1h.6zM249.6 156.7h.6zM270.2 160.3l.9-.4zM272.1 159.5l.9-.4zM273.9 158.6l.9-.4zM250.2 141.4h25.4zM250.2 144h25.4zM250.2 146.5h25.4zM250.2 149h25.4zM275.7 157.8l.9-.4zM278.1 141.4l-2.5 2.6z"/>
<path d="M278.1 144l-2.5 2.5zM278.1 146.5l-2.5 2.5zM277.5 157l.9-.4zM279.4 156.2l.9-.4zM281.2 155.4l.9-.4zM283 154.5l.9-.4zM284.8 153.7l.9-.4zM286.7 152.9l.9-.4zM288.5 152.1l.9-.4zM290.3 151.3l.9-.5zM292.1 150.4l.9-.4zM293.9 149.6l1-.4z"/>
<path d="M295.8 148.8l.9-.4zM297.6 148l.9-.4zM299.4 147.1l.9-.4zM301.2 146.3l.9-.4zM303.1 145.5l.9-.4zM304.9 144.7l.9-.5zM306.7 143.8l.9-.4zM308.5 143l1-.4zM310.4 142.2l.9-.4zM312.2 141.4l.9-.4zM314 140.5l.9-.4zM321.7 140.3l.2 1z"/>
<path d="M322 142.3l.1 1zM322.2 144.3l.1 1zM322.4 146.3l.2 1zM322.7 148.3l.1 1zM322.9 150.3l.1 1zM323.1 152.3l.1 1zM323.4 154.3l.1 1zM323.6 156.3l.1 1.1zM323.8 158.3l.1 1zM377.1 149h10.2zM379.7 141.4v2.6zM379.7 144v2.5z"/>
<path d="M379.7 146.5h7.6zM387.3 146.5h.6zM387.3 149h.6zM16.5 173.7h3.8zM43.6 163.1h4.8zM43.9 167h4.5zM44.6 175.8h3.8zM44.6 172h3.8zM52.1 177h22.8zM74.9 177l2.6 2.5zM52.1 173.2h22.8zM74.9 173.2l2.6 2.5z"/>
<path d="M52.1 168.1h22.8zM74.9 168.1l2.6 2.5zM52.1 164.3h22.8zM74.9 164.3l2.6 2.5zM113 177l-2.5 2.5zM113 174.4l-2.5 2.6zM113 171.9l-2.5 2.5zM113 169.4l-2.5 2.5zM113 166.8l-2.5 2.6zM113 164.3l-2.5 2.5zM113 179.5l-2.5 2.6zM122.3 175h8.5z"/>
<path d="M122.4 177.5h8.4zM123 172.4h7.8zM125.9 162.3h4.9zM126.2 164.8h4.6zM126.9 169.9h3.9zM126.9 167.3h3.9zM143.5 164.3h5.1zM143.5 166.8h5.1zM143.5 169.4h5.1zM143.5 171.9h5.1zM143.5 174.4h5.1zM143.5 177h5.1z"/>
<path d="M143.5 179.5h5.1zM113 177h30.5zM113 174.4h30.5zM113 171.9h30.5zM113 169.4h30.5zM113 166.8h30.5zM113 164.3h30.5zM113 179.5h30.5zM165.8 179.5h3.1zM165.8 177h3.1zM165.8 174.4h3.1zM165.8 171.9h3.1z"/>
<path d="M165.8 169.4h3.1zM165.8 166.8h3.1zM165.8 164.3h3.1zM168.9 179.5h25.4zM168.9 164.3h25.4zM168.9 166.8h25.4zM168.9 169.4h25.4zM168.9 171.9h25.4zM168.9 174.4h25.4zM168.9 177h25.4zM194.3 179.5l2.5 2.6zM194.3 164.3l2.5 2.5z"/>
<path d="M194.3 166.8l2.5 2.6zM194.3 169.4l2.5 2.5zM194.3 171.9l2.5 2.5zM194.3 174.4l2.5 2.6zM194.3 177l2.5 2.5zM214.6 179.5l2.5-2.5zM214.6 177l2.5-2.6zM217.1 179.5h25.4zM217.1 177h25.4zM217.1 174.4h25.4zM226.5 177.5h8.4zM226.6 175h8.3z"/>
<path d="M229.7 172.4h5.2zM242.5 174.4h.6zM242.5 177h.6zM242.5 179.5h.6zM249.6 174.4h.6zM249.6 177h.6zM249.6 179.5h.6zM250.2 169.4l.9-.5zM252 168.5l.9-.4zM253.8 167.7l.9-.4zM255.6 166.9l1-.4zM257.5 166l.9-.4z"/>
<path d="M259.3 165.2l.9-.4zM261.1 164.4l.9-.4zM262.9 163.6l.9-.4zM264.7 162.8l1-.5zM266.6 161.9l.9-.4zM268.4 161.1l.9-.4zM250.2 174.4h30.4zM250.2 177h30.4zM250.2 179.5h30.4zM283.2 171.9l-2.6 2.5zM280.6 177l2.6-2.6zM280.6 179.5l2.6-2.5z"/>
<path d="M283.2 179.5l-2.6 2.6zM293.3 174.4l-2.5 2.6zM290.8 179.5l2.5-2.5zM293.3 174.4h25.4zM293.3 177h25.4zM299.2 177.5h11.9zM306.3 175h4.8zM306.6 172.4h4.5zM318.7 174.4h.6zM318.7 177h.6zM318.7 179.5h.6zM311.1 179.5h7.6z"/>
<path d="M324 160.3l.2 1.1zM324.3 162.3l.1 1zM324.5 164.3l.1 1.1zM324.7 166.3l.2 1zM325 168.3l.1 1.1zM325.8 174.4h.6zM325.8 177h.6zM325.8 179.5h.6zM326.4 174.4h25.3zM326.4 177h25.3zM326.4 179.5h25.3zM354.3 171.9l-2.6 2.5z"/>
<path d="M354.3 174.4l-2.6 2.6zM354.3 177l-2.6 2.5zM354.3 179.5l-2.6 2.6zM387.3 164.3h.6zM387.3 166.8h.6zM377.1 164.3h10.2zM377.1 166.8h10.2zM400 173.7h3.8zM40 184.7h8.4zM40.1 188.5h8.3zM40.6 180.9h7.8zM42.6 198.7h5.8z"/>
<path d="M43.2 193.6h5.2zM52.1 199.8h22.8zM74.9 199.8l2.6 2.6zM52.1 185.9h22.8zM74.9 185.9l2.6 2.5zM52.1 182.1h22.8zM74.9 182.1l2.6 2.5zM52.1 189.7h22.8zM74.9 189.7l2.6 2.5zM52.1 194.8h22.8zM74.9 194.8l2.6 2.5zM113 182.1l-2.5 2.5z"/>
<path d="M125.5 180h5.3zM140.9 192.2v2.6zM140.9 189.7v2.5zM140.9 187.1v2.6zM143.5 187.1h3.1zM143.5 182.1h5.1zM143.5 189.7h3.1zM113 182.1h30.5zM140.9 189.7h2.6zM140.9 187.1h2.6zM165.8 182.1h3.1zM168.9 182.1h25.4z"/>
<path d="M194.3 182.1l2.5 2.5zM214.6 182.1l2.5-2.6zM214.6 184.6l2.5-2.5zM217.1 182.1h25.4zM227.1 180h7.8zM229 195.3h5.9zM229.1 197.8h5.8zM229.1 190.2h5.8zM229.1 192.7h5.8zM229.5 185.1h5.4zM229.6 187.7h5.3zM229.6 182.6h5.3z"/>
<path d="M242.5 182.1h.6zM242.5 184.6h.6zM242.5 187.1h.6zM242.5 189.7h.6zM242.5 192.2h.6zM242.5 194.8h.6zM242.5 197.3h.6zM242.5 199.8h.6zM234.9 189.7h7.6zM234.9 187.1h7.6zM234.9 184.6h7.6zM234.9 194.8h7.6z"/>
<path d="M234.9 199.8h7.6zM234.9 197.3h7.6zM234.9 192.2h7.6zM249.6 182.1h.6zM249.6 184.6h.6zM249.6 187.1h.6zM249.6 189.7h.6zM249.6 192.2h.6zM249.6 194.8h.6zM249.6 197.3h.6zM249.6 199.8h.6zM250.2 182.1h30.4z"/>
<path d="M250.2 184.6h30.4zM250.2 187.1h30.4zM250.2 189.7h30.4zM250.2 192.2h30.4zM250.2 194.8h30.4zM250.2 197.3h30.4zM250.2 199.8h30.4zM280.6 184.6l2.6-2.5zM280.6 187.1l2.6-2.5zM283.2 187.1l-2.6 2.6zM280.6 192.2l2.6-2.5zM280.6 194.8l2.6-2.6z"/>
<path d="M283.2 194.8l-2.6 2.5zM280.6 199.8l2.6-2.5zM280.6 202.4l2.6-2.6zM293.3 194.8l-2.5 2.5zM293.3 197.3l-2.5 2.5zM293.3 199.8l-2.5 2.6zM303.9 180h7.2zM318.7 182.1h.6zM318.7 184.6h.6zM318.7 187.1h.6zM318.7 189.7h.6zM318.7 192.2h.6z"/>
<path d="M318.7 194.8h.6zM318.7 197.3h.6zM318.7 199.8h.6zM293.3 194.8h25.4zM293.3 197.3h25.4zM293.3 199.8h25.4zM311.1 187.1h7.6zM311.1 184.6h7.6zM311.1 182.1h7.6zM311.1 189.7h7.6zM311.1 192.2h7.6zM325.8 182.1h.6z"/>
<path d="M325.8 184.6h.6zM325.8 187.1h.6zM325.8 189.7h.6zM325.8 192.2h.6zM325.8 194.8h.6zM325.8 197.3h.6zM325.8 199.8h.6zM326.4 182.1h25.3zM326.4 184.6h25.3zM326.4 187.1h25.3zM326.4 189.7h25.3zM326.4 192.2h25.3z"/>
<path d="M326.4 194.8h25.3zM326.4 197.3h25.3zM326.4 199.8h25.3zM354.3 182.1l-2.6 2.5zM354.3 184.6l-2.6 2.5zM354.3 187.1l-2.6 2.6zM354.3 189.7l-2.6 2.5zM354.3 192.2l-2.6 2.6zM354.3 194.8l-2.6 2.5zM354.3 197.3l-2.6 2.5zM354.3 199.8l-2.6 2.6zM42.6 210.1h5.8z"/>
<path d="M43.2 215.2h5.2zM45.8 202.5h2.6zM46.7 206.3h1.7zM52.1 203.6h22.8zM74.9 203.6l2.6 2.6zM52.1 207.4h22.8zM74.9 207.4l2.6 2.6zM52.1 211.2h22.8zM74.9 211.2l2.6 2.6zM52.1 216.3h22.8zM74.9 216.3l2.6 2.6zM110.5 204.9l2.5-2.5z"/>
<path d="M110.5 207.4l2.5-2.5zM113 207.4l-2.5 2.6zM110.5 212.5l2.5-2.5zM110.5 215l2.5-2.5zM113 202.4h30.5zM113 204.9h30.5zM113 207.4h30.5zM113 210h30.5zM113 212.5h30.5zM121.9 211.2l.2 1.1zM122.2 213.3l.2 1.1zM122.5 215.3l.2 1.1z"/>
<path d="M122.8 217.4l.2 1zM123.1 219.4l.2 1.1zM124.9 200.4h5.9zM125 208h5.8zM125.5 210.5h5.3zM128.2 202.9h2.6zM129 205.4h1.8zM140.9 215v2.6zM140.9 217.6v2.5zM143.5 202.4h5.1zM143.5 204.9h5.1zM143.5 207.4h5.1z"/>
<path d="M143.5 210h5.1zM143.5 212.5h5.1zM143.5 215h5.1zM143.5 217.6h5.1zM140.9 215h2.6zM140.9 217.6h2.6zM165.8 217.6h3.1zM165.8 215h3.1zM165.8 212.5h3.1zM165.8 210h3.1zM165.8 207.4h3.1zM165.8 204.9h3.1z"/>
<path d="M165.8 202.4h3.1zM173.1 219.1l-.3 .9zM173.6 217.1l-.2 1zM174.2 215.2l-.3 .9zM174.7 213.2l-.3 1zM175.2 211.2l-.2 1zM168.9 204.9h25.4zM168.9 202.4h25.4zM168.9 207.4h25.4zM168.9 210h25.4zM168.9 212.5h25.4zM194.3 204.9l2.5 2.5z"/>
<path d="M194.3 202.4l2.5 2.5zM194.3 207.4l2.5 2.6zM194.3 210l2.5 2.5zM194.3 212.5l2.5 2.5zM242.5 202.4h.6zM242.5 204.9h.6zM242.5 207.4h.6zM242.5 210h.6zM242.5 212.5h.6zM242.5 215h.6zM242.5 217.6h.6zM234.9 202.4h7.6z"/>
<path d="M234.9 204.9h7.6zM234.9 207.4h7.6zM234.9 210h7.6zM234.9 212.5h7.6zM234.9 215h7.6zM234.9 217.6h7.6zM249.6 202.4h.6zM249.6 204.9h.6zM249.6 207.4h.6zM249.6 210h.6zM249.6 212.5h.6zM249.6 215h.6z"/>
<path d="M249.6 217.6h.6zM250.2 202.4h30.4zM250.2 204.9h30.4zM250.2 207.4h30.4zM250.2 210h30.4zM250.2 212.5h30.4zM283.2 202.4l-2.6 2.5zM280.6 207.4l2.6-2.5zM283.2 207.4l-2.6 2.6zM283.2 210l-2.6 2.5zM293.3 202.4l-2.5 2.5zM318.7 202.4h.6z"/>
<path d="M318.7 204.9h.6zM318.7 207.4h.6zM318.7 210h.6zM318.7 212.5h.6zM318.7 215h.6zM318.7 217.6h.6zM293.3 202.4h25.4zM325.8 202.4h.6zM325.8 204.9h.6zM325.8 207.4h.6zM325.8 210h.6zM325.8 212.5h.6z"/>
<path d="M325.8 215h.6zM325.8 217.6h.6zM326.4 202.4h25.3zM326.4 204.9h25.3zM326.4 207.4h25.3zM326.4 210h25.3zM326.4 212.5h25.3zM354.3 202.4l-2.6 2.5zM351.7 207.4l2.6-2.5zM354.3 207.4l-2.6 2.6zM354.3 210l-2.6 2.5zM16.5 224.2h3.8z"/>
<path d="M52.1 225.2h22.8zM52.1 230.3h22.8zM74.9 225.2l2.6 2.5zM74.9 230.3l2.6 2.5zM123.5 221.5l.1 1zM123.8 223.5l.1 1.1zM124.1 225.5l.1 1.1zM124.4 227.6l.1 1zM124.7 229.6l.2 1.1zM125 231.7l.2 1zM125.3 233.7l.2 1.1zM125.6 235.8l.2 1z"/>
<path d="M125.9 237.8l.2 1.1zM126.2 239.8l.2 1.1zM140.9 230.3v2.5zM140.9 220.1v5.1zM140.9 225.2v2.5zM140.9 227.7v2.6zM143.5 225.2h3.1zM143.5 220.1h5.1zM143.5 227.7h3.1zM140.9 220.1h2.6zM140.9 225.2h2.6zM140.9 227.7h2.6z"/>
<path d="M167.8 238.5l-.3 1zM168.3 236.6l-.2 1zM168.9 234.6l-.3 1zM165.8 220.1h3.1zM169.4 232.7l-.3 1zM169.9 230.7l-.3 1zM170.5 228.8l-.3 1zM171 226.8l-.3 1zM171.5 224.9l-.2 1zM172.1 222.9l-.3 1zM172.6 221l-.3 1zM242.5 220.1h.6z"/>
<path d="M242.5 222.7h.6zM234.9 220.1h7.6zM249.6 220.1h.6zM249.6 222.7h.6zM318.7 220.1h.6zM318.7 222.7h.6zM325.8 220.1h.6zM325.8 222.7h.6zM400 224.2h3.8zM117.2 253.7h4zM126.6 241.9l.1 1zM126.8 243.9l.2 1.1z"/>
<path d="M127.2 246l.1 1zM127.5 248l.1 1.1zM127.8 250.1l.2 1zM128.1 252.1l.1 1zM156.5 253.7h5.8zM164.1 252.2l-.3 .9zM164.6 250.2l-.3 1zM165.1 248.3l-.2 1zM165.7 246.3l-.3 1zM166.2 244.4l-.3 1zM166.7 242.4l-.2 1zM167.3 240.5l-.3 1z"/>
<path d="M172 253.7h5.9zM20.3 274.7h379.7zM67.8 274.7v3.8zM115.3 274.7v3.8zM162.7 274.7v3.8zM210.2 274.7v3.8zM257.6 274.7v3.8zM305.1 274.7v3.8zM352.5 274.7v3.8zM400 264.5v.1zM400 268.4v6.2zM400 274.6h.1z"/>
<path d="M400 22.1v252.6z"/>
<circle cx="140.9" cy="75.4" r=".51"/>
<circle cx="140.9" cy="113.5" r=".51"/>
<circle cx="140.9" cy="151.6" r=".51"/>
<circle cx="140.9" cy="189.7" r=".51"/>
<circle cx="140.9" cy="217.6" r=".51"/>
<circle cx="140.9" cy="220.1" r=".51"/>
<circle cx="140.9" cy="227.7" r=".51"/>
<circle cx="140.9" cy="225.2" r=".51"/>
</g>
<path d="M308.6 100.8v25.4zM321.3 100.8v25.4zM334 100.8v25.4z" fill="#000" stroke="#000" stroke-width="2.5"/>
<g fill="#000" stroke="#000" stroke-width=".28">
<path d="M36.8 57.4v3zM40.9 40.9v3zM40.9 44.7v3zM40.9 48.5v3zM40.9 52.3v3zM36.8 57.4h13.7zM40.9 40.9h9.6zM40.9 43.9h9.6zM40.9 44.7h9.6zM40.9 47.7h9.6zM40.9 48.5h9.6zM40.9 51.5h9.6z"/>
<path d="M40.9 52.3h9.6zM40.9 55.3h9.6zM50.5 57.4l1.6 1.5zM50.5 60.4l1.6-1.5zM50.5 40.9l1.6 1.5zM52.1 42.4l-1.6 1.5zM50.5 44.7l1.6 1.5zM52.1 46.2l-1.6 1.5zM50.5 48.5l1.6 1.5zM52.1 50l-1.6 1.5zM50.5 52.3l1.6 1.5zM52.1 53.8l-1.6 1.5z"/>
<path d="M40.4 62.4v3.1zM42.3 67.5v3zM42.3 71.3v3.1zM42.3 75.1v3.1zM42.3 78.9v3.1zM36.8 60.4h13.7zM40.4 62.4h10.1zM40.4 65.5h10.1zM42.3 67.5h8.2zM42.3 70.5h8.2zM42.3 71.3h8.2zM42.3 74.4h8.2z"/>
<path d="M42.3 75.1h8.2zM42.3 78.2h8.2zM42.3 78.9h8.2zM50.5 62.4l1.6 1.5zM52.1 63.9l-1.6 1.6zM50.5 67.5l1.6 1.5zM52.1 69l-1.6 1.5zM50.5 71.3l1.6 1.5zM52.1 72.8l-1.6 1.6zM50.5 75.1l1.6 1.5zM52.1 76.6l-1.6 1.6zM71.4 68l2 2z"/>
<path d="M73.4 68l-2 2zM71.4 71.8l2 2zM73.4 71.8l-2 2zM71.4 75.6l2 2.1zM73.4 75.6l-2 2.1zM73.4 79.4l-2 2.1zM40 98v3zM42.3 82.7v3.1zM44.4 92.9v3zM44.7 87.8v3.1zM40 98h10.5zM42.3 82h8.2z"/>
<path d="M42.3 82.7h8.2zM42.3 85.8h8.2zM44.4 92.9h6.1zM44.4 95.9h6.1zM44.7 87.8h5.8zM44.7 90.9h5.8zM50.5 98l1.6 1.5zM52.1 99.5l-1.6 1.5zM50.5 78.9l1.6 1.6zM52.1 80.5l-1.6 1.5zM50.5 82.7l1.6 1.6zM52.1 84.3l-1.6 1.5z"/>
<path d="M50.5 92.9l1.6 1.5zM52.1 94.4l-1.6 1.5zM50.5 87.8l1.6 1.5zM50.5 90.9l1.6-1.6zM71.4 79.4l2 2.1zM71.4 83.2l2 2.1zM73.4 83.2l-2 2.1zM139 80.5h3.9zM34.1 103.1v3zM38.5 114.5v3zM38.5 118.3v3zM34.1 103.1h16.4z"/>
<path d="M34.1 106.1h16.4zM40 101h10.5zM38.5 114.5h12zM38.5 117.5h12zM38.5 118.3h12zM50.5 103.1l1.6 1.5zM50.5 106.1l1.6-1.5zM50.5 114.5l1.6 1.5zM50.5 117.5l1.6-1.5zM50.5 118.3l1.6 1.5zM50.5 121.3l1.6-1.5zM139 118.6h3.9z"/>
<path d="M37.9 132.3v3zM37.9 136.1v3zM37.9 139.9v3zM38.5 122.1v3.1zM38.5 125.9v3.1zM38.5 121.3h12zM38.5 122.1h12zM38.5 125.2h12zM38.5 125.9h12zM38.5 129h12zM37.9 132.3h12.6zM37.9 135.3h12.6z"/>
<path d="M37.9 136.1h12.6zM37.9 139.1h12.6zM37.9 139.9h12.6zM50.5 122.1l1.6 1.5zM50.5 125.2l1.6-1.6zM50.5 125.9l1.6 1.5zM50.5 129l1.6-1.6zM50.5 132.3l1.6 1.5zM52.1 133.8l-1.6 1.5zM50.5 136.1l1.6 1.5zM52.1 137.6l-1.6 1.5zM40.3 146.2v3.1z"/>
<path d="M40.3 150v3.1zM40.3 153.9v3zM40.3 157.7v3zM37.9 142.9h12.6zM40.3 146.2h10.2zM40.3 149.3h10.2zM40.3 150h10.2zM40.3 153.1h10.2zM40.3 153.9h10.2zM40.3 156.9h10.2zM40.3 157.7h10.2zM50.5 139.9l1.6 1.5z"/>
<path d="M52.1 141.4l-1.6 1.5zM50.5 146.2l1.6 1.6zM52.1 147.8l-1.6 1.5zM50.5 150l1.6 1.6zM52.1 151.6l-1.6 1.5zM50.5 153.9l1.6 1.5zM52.1 155.4l-1.6 1.5zM50.5 157.7l1.6 1.5zM52.1 159.2l-1.6 1.5zM139 156.7h3.9zM359.5 147.5v3.1zM359.5 150.6h16.1z"/>
<path d="M359.5 147.5h16.1zM377.1 149l-1.5 1.6zM375.6 147.5l1.5 1.5zM379.7 141.4l-1.3 1.9zM379.7 141.4l1.3 1.9zM41.3 162.7v3.1zM41.6 166.6v3zM42.3 175.4v3.1zM42.3 171.6v3.1zM42.3 175.4h8.2zM42.3 178.5h8.2zM42.3 171.6h8.2z"/>
<path d="M42.3 174.7h8.2zM41.6 166.6h8.9zM41.6 169.6h8.9zM41.3 162.7h9.2zM41.3 165.8h9.2zM40.3 160.7h10.2zM50.5 175.4l1.6 1.6zM52.1 177l-1.6 1.5zM50.5 171.6l1.6 1.6zM52.1 173.2l-1.6 1.5zM50.5 166.6l1.6 1.5zM52.1 168.1l-1.6 1.5z"/>
<path d="M50.5 162.7l1.6 1.6zM52.1 164.3l-1.6 1.5zM37.6 184.3v3.1zM37.8 188.1v3.1zM38.4 180.5v3.1zM40.3 198.3v3.1zM40.9 193.2v3.1zM40.3 198.3h10.2zM37.6 184.3h12.9zM37.6 187.4h12.9zM38.4 180.5h12.1zM38.4 183.6h12.1z"/>
<path d="M37.8 188.1h12.7zM37.8 191.2h12.7zM40.9 193.2h9.6zM40.9 196.3h9.6zM50.5 198.3l1.6 1.5zM52.1 199.8l-1.6 1.6zM50.5 184.3l1.6 1.6zM52.1 185.9l-1.6 1.5zM50.5 180.5l1.6 1.6zM52.1 182.1l-1.6 1.5zM50.5 188.1l1.6 1.6zM52.1 189.7l-1.6 1.5z"/>
<path d="M50.5 193.2l1.6 1.6zM52.1 194.8l-1.6 1.5zM139 194.8h3.9zM40.3 209.7v3.1zM40.9 214.8v3zM43.6 202.1v3.1zM44.4 205.9v3.1zM40.3 201.4h10.2zM43.6 202.1h6.9zM43.6 205.2h6.9zM44.4 205.9h6.1zM44.4 209h6.1z"/>
<path d="M40.3 209.7h10.2zM40.3 212.8h10.2zM40.9 214.8h9.6zM40.9 217.8h9.6zM50.5 202.1l1.6 1.5zM52.1 203.6l-1.6 1.6zM50.5 205.9l1.6 1.5zM52.1 207.4l-1.6 1.6zM50.5 209.7l1.6 1.5zM52.1 211.2l-1.6 1.6zM50.5 214.8l1.6 1.5zM52.1 216.3l-1.6 1.5z"/>
<path d="M39.1 223.7v3zM40.6 228.8v3zM40.6 228.8h9.9zM40.6 231.8h9.9zM39.1 223.7h11.4zM39.1 226.7h11.4zM50.5 228.8l1.6 1.5zM52.1 230.3l-1.6 1.5zM50.5 223.7l1.6 1.5zM52.1 225.2l-1.6 1.5zM139 232.8h3.9zM313.7 249.3h86.3z"/>
<path d="M313.7 254.4h86.3zM313.7 259.5h58.4zM372.1 259.5h27.9zM372.1 259.5v5.1zM313.7 264.6h58.4zM313.7 269.7h86.3zM372.1 264.6h27.9zM400 268.4v1.3z"/>
</g>
<path d="M16.5 18.2v260.3zM16.5 18.2h387.3zM16.5 278.5h387.3zM403.8 18.2v260.3z" fill="#000" stroke="#000" stroke-width=".32"/>
<g fill="none" stroke="#000" stroke-width=".25">
<circle cx="244.1" cy="50" r="1"/>
<circle cx="244.1" cy="57.6" r="1"/>
<circle cx="244.1" cy="55.1" r="1"/>
<circle cx="244.1" cy="52.5" r="1"/>
<circle cx="244.1" cy="47.5" r="1"/>
<circle cx="244.1" cy="44.9" r="1"/>
<circle cx="248.6" cy="50" r="1"/>
<circle cx="248.6" cy="55.1" r="1"/>
<circle cx="248.6" cy="47.5" r="1"/>
<circle cx="248.6" cy="57.6" r="1"/>
<circle cx="248.6" cy="44.9" r="1"/>
<circle cx="248.6" cy="52.5" r="1"/>
<circle cx="147.6" cy="75.4" r=".99"/>
<circle cx="147.6" cy="72.8" r=".99"/>
<circle cx="244.1" cy="62.7" r="1"/>
<circle cx="244.1" cy="77.9" r="1"/>
<circle cx="244.1" cy="70.3" r="1"/>
<circle cx="244.1" cy="60.2" r="1"/>
<circle cx="244.1" cy="67.8" r="1"/>
<circle cx="244.1" cy="75.4" r="1"/>
<circle cx="244.1" cy="65.2" r="1"/>
<circle cx="244.1" cy="72.8" r="1"/>
<circle cx="248.6" cy="62.7" r="1"/>
<circle cx="248.6" cy="77.9" r="1"/>
<circle cx="248.6" cy="67.8" r="1"/>
<circle cx="248.6" cy="70.3" r="1"/>
<circle cx="248.6" cy="72.8" r="1"/>
<circle cx="248.6" cy="60.2" r="1"/>
<circle cx="248.6" cy="65.2" r="1"/>
<circle cx="248.6" cy="75.4" r="1"/>
<circle cx="244.1" cy="90.6" r="1"/>
<circle cx="244.1" cy="88.1" r="1"/>
<circle cx="244.1" cy="93.2" r="1"/>
<circle cx="244.1" cy="80.5" r="1"/>
<circle cx="244.1" cy="83" r="1"/>
<circle cx="244.1" cy="85.5" r="1"/>
<circle cx="248.6" cy="93.2" r="1"/>
<circle cx="248.6" cy="90.6" r="1"/>
<circle cx="248.6" cy="88.1" r="1"/>
<circle cx="248.6" cy="80.5" r="1"/>
<circle cx="248.6" cy="83" r="1"/>
<circle cx="248.6" cy="85.5" r="1"/>
<circle cx="147.6" cy="113.5" r=".99"/>
<circle cx="147.6" cy="110.9" r=".99"/>
<circle cx="244.1" cy="108.4" r="1"/>
<circle cx="244.1" cy="110.9" r="1"/>
<circle cx="244.1" cy="113.5" r="1"/>
<circle cx="244.1" cy="116" r="1"/>
<circle cx="244.1" cy="118.6" r="1"/>
<circle cx="248.6" cy="110.9" r="1"/>
<circle cx="248.6" cy="113.5" r="1"/>
<circle cx="248.6" cy="116" r="1"/>
<circle cx="248.6" cy="108.4" r="1"/>
<circle cx="248.6" cy="118.6" r="1"/>
<circle cx="244.1" cy="121.1" r="1"/>
<circle cx="244.1" cy="133.8" r="1"/>
<circle cx="244.1" cy="123.6" r="1"/>
<circle cx="244.1" cy="126.2" r="1"/>
<circle cx="244.1" cy="138.9" r="1"/>
<circle cx="244.1" cy="128.7" r="1"/>
<circle cx="244.1" cy="131.3" r="1"/>
<circle cx="244.1" cy="136.3" r="1"/>
<circle cx="248.6" cy="138.9" r="1"/>
<circle cx="248.6" cy="126.2" r="1"/>
<circle cx="248.6" cy="128.7" r="1"/>
<circle cx="248.6" cy="136.3" r="1"/>
<circle cx="248.6" cy="121.1" r="1"/>
<circle cx="248.6" cy="123.6" r="1"/>
<circle cx="248.6" cy="133.8" r="1"/>
<circle cx="248.6" cy="131.3" r="1"/>
<circle cx="147.6" cy="149" r=".99"/>
<circle cx="147.6" cy="151.6" r=".99"/>
<circle cx="244.1" cy="149" r="1"/>
<circle cx="244.1" cy="141.4" r="1"/>
<circle cx="244.1" cy="144" r="1"/>
<circle cx="244.1" cy="151.6" r="1"/>
<circle cx="244.1" cy="146.5" r="1"/>
<circle cx="244.1" cy="156.7" r="1"/>
<circle cx="244.1" cy="154.1" r="1"/>
<circle cx="248.6" cy="154.1" r="1"/>
<circle cx="248.6" cy="144" r="1"/>
<circle cx="248.6" cy="146.5" r="1"/>
<circle cx="248.6" cy="149" r="1"/>
<circle cx="248.6" cy="141.4" r="1"/>
<circle cx="248.6" cy="156.7" r="1"/>
<circle cx="248.6" cy="151.6" r="1"/>
<circle cx="388.8" cy="146.5" r="1"/>
<circle cx="388.8" cy="149" r="1"/>
<circle cx="164.8" cy="171.9" r=".99"/>
<circle cx="164.8" cy="164.3" r=".99"/>
<circle cx="164.8" cy="177" r=".99"/>
<circle cx="164.8" cy="169.4" r=".99"/>
<circle cx="164.8" cy="179.5" r=".99"/>
<circle cx="164.8" cy="174.4" r=".99"/>
<circle cx="164.8" cy="166.8" r=".99"/>
<circle cx="244.1" cy="174.4" r="1"/>
<circle cx="244.1" cy="179.5" r="1"/>
<circle cx="244.1" cy="177" r="1"/>
<circle cx="248.6" cy="179.5" r="1"/>
<circle cx="248.6" cy="174.4" r="1"/>
<circle cx="248.6" cy="177" r="1"/>
<circle cx="320.3" cy="174.4" r="1"/>
<circle cx="320.3" cy="179.5" r="1"/>
<circle cx="320.3" cy="177" r="1"/>
<circle cx="324.8" cy="174.4" r="1"/>
<circle cx="324.8" cy="179.5" r="1"/>
<circle cx="324.8" cy="177" r="1"/>
<circle cx="388.8" cy="164.3" r="1"/>
<circle cx="388.8" cy="166.8" r="1"/>
<circle cx="147.6" cy="187.1" r=".99"/>
<circle cx="147.6" cy="189.7" r=".99"/>
<circle cx="164.8" cy="182.1" r=".99"/>
<circle cx="244.1" cy="182.1" r="1"/>
<circle cx="244.1" cy="189.7" r="1"/>
<circle cx="244.1" cy="197.3" r="1"/>
<circle cx="244.1" cy="192.2" r="1"/>
<circle cx="244.1" cy="199.8" r="1"/>
<circle cx="244.1" cy="184.6" r="1"/>
<circle cx="244.1" cy="194.8" r="1"/>
<circle cx="244.1" cy="187.1" r="1"/>
<circle cx="248.6" cy="187.1" r="1"/>
<circle cx="248.6" cy="189.7" r="1"/>
<circle cx="248.6" cy="197.3" r="1"/>
<circle cx="248.6" cy="192.2" r="1"/>
<circle cx="248.6" cy="182.1" r="1"/>
<circle cx="248.6" cy="194.8" r="1"/>
<circle cx="248.6" cy="184.6" r="1"/>
<circle cx="248.6" cy="199.8" r="1"/>
<circle cx="320.3" cy="182.1" r="1"/>
<circle cx="320.3" cy="192.2" r="1"/>
<circle cx="320.3" cy="194.8" r="1"/>
<circle cx="320.3" cy="187.1" r="1"/>
<circle cx="320.3" cy="189.7" r="1"/>
<circle cx="320.3" cy="197.3" r="1"/>
<circle cx="320.3" cy="184.6" r="1"/>
<circle cx="320.3" cy="199.8" r="1"/>
<circle cx="324.8" cy="182.1" r="1"/>
<circle cx="324.8" cy="194.8" r="1"/>
<circle cx="324.8" cy="197.3" r="1"/>
<circle cx="324.8" cy="189.7" r="1"/>
<circle cx="324.8" cy="192.2" r="1"/>
<circle cx="324.8" cy="184.6" r="1"/>
<circle cx="324.8" cy="187.1" r="1"/>
<circle cx="324.8" cy="199.8" r="1"/>
<circle cx="164.8" cy="217.6" r=".99"/>
<circle cx="164.8" cy="215" r=".99"/>
<circle cx="164.8" cy="212.5" r=".99"/>
<circle cx="164.8" cy="207.4" r=".99"/>
<circle cx="164.8" cy="202.4" r=".99"/>
<circle cx="164.8" cy="204.9" r=".99"/>
<circle cx="164.8" cy="210" r=".99"/>
<circle cx="244.1" cy="217.6" r="1"/>
<circle cx="244.1" cy="215" r="1"/>
<circle cx="244.1" cy="212.5" r="1"/>
<circle cx="244.1" cy="210" r="1"/>
<circle cx="244.1" cy="204.9" r="1"/>
<circle cx="244.1" cy="202.4" r="1"/>
<circle cx="244.1" cy="207.4" r="1"/>
<circle cx="248.6" cy="217.6" r="1"/>
<circle cx="248.6" cy="212.5" r="1"/>
<circle cx="248.6" cy="215" r="1"/>
<circle cx="248.6" cy="202.4" r="1"/>
<circle cx="248.6" cy="210" r="1"/>
<circle cx="248.6" cy="204.9" r="1"/>
<circle cx="248.6" cy="207.4" r="1"/>
<circle cx="320.3" cy="215" r="1"/>
<circle cx="320.3" cy="217.6" r="1"/>
<circle cx="320.3" cy="212.5" r="1"/>
<circle cx="320.3" cy="202.4" r="1"/>
<circle cx="320.3" cy="204.9" r="1"/>
<circle cx="320.3" cy="210" r="1"/>
<circle cx="320.3" cy="207.4" r="1"/>
<circle cx="324.8" cy="212.5" r="1"/>
<circle cx="324.8" cy="215" r="1"/>
<circle cx="324.8" cy="217.6" r="1"/>
<circle cx="324.8" cy="210" r="1"/>
<circle cx="324.8" cy="204.9" r="1"/>
<circle cx="324.8" cy="207.4" r="1"/>
<circle cx="324.8" cy="202.4" r="1"/>
<circle cx="147.6" cy="225.2" r=".99"/>
<circle cx="147.6" cy="227.7" r=".99"/>
<circle cx="164.8" cy="220.1" r=".99"/>
<circle cx="244.1" cy="220.1" r="1"/>
<circle cx="244.1" cy="222.7" r="1"/>
<circle cx="248.6" cy="220.1" r="1"/>
<circle cx="248.6" cy="222.7" r="1"/>
<circle cx="320.3" cy="222.7" r="1"/>
<circle cx="320.3" cy="220.1" r="1"/>
<circle cx="324.8" cy="220.1" r="1"/>
<circle cx="324.8" cy="222.7" r="1"/>
</g>
<g fill="#000" stroke="#000" stroke-width=".42">
<path d="M238.7 42.4v53.3zM238.7 42.4h15.3zM238.7 95.7h15.3zM254 42.4v53.3zM238.7 105.9v53.3zM238.7 105.9h15.3zM238.7 159.2h15.3zM254 105.9v53.3zM383.5 151.6h7.6zM383.5 144v7.6zM391.1 144v7.6zM383.5 144h7.6z"/>
<path d="M238.7 171.9v53.3zM238.7 171.9h15.3zM314.9 171.9v53.3zM314.9 171.9h15.3zM383.5 169.4h7.6zM383.5 161.7v7.7zM391.1 161.7v7.7zM383.5 161.7h7.6zM238.7 225.2h15.3zM254 171.9v53.3zM314.9 225.2h15.3zM330.2 171.9v53.3z"/>
<path d="M24.1 253.1v10.2zM24.1 253.1h55.9zM24.1 263.3v7.6zM24.1 270.9h55.9zM24.1 263.3h55.9zM80 263.3v7.6zM80 253.1v10.2z"/>
</g>
<g fill="#000" stroke="#000" stroke-width=".76">
<path d="M54.6 34.8h149.8zM54.6 29.7h221zM204.4 34.8l5.1 5zM275.6 29.7l7.6 7.6zM283.2 37.3v172.7zM102.9 52.5v61zM196.8 52.5v167.6zM209.5 39.8v40.7zM77.5 118.6v116.8zM85.1 44.9v68.6zM85.1 113.5l5.1 5.1zM90.2 118.6h7.6z"/>
<path d="M102.9 113.5l-5.1 5.1zM209.5 103.3l2.6-2.5zM212.1 100.8h63.5zM275.6 100.8l2.5 2.5zM278.1 103.3v43.2zM283.2 156.7l7.6 7.6zM290.8 164.3h58.4zM349.2 164.3l5.1 5.1zM354.3 169.4v40.6zM77.5 235.4l5 5zM110.5 95.7v139.7zM196.8 220.1l2.6 2.6z"/>
<path d="M199.4 222.7h7.6zM207 222.7l2.5-2.6zM209.5 103.3v116.8zM214.6 177v58.4zM290.8 177v58.4zM82.5 240.4h22.9zM110.5 235.4l-5.1 5zM105.4 240.4h104.1zM209.5 240.4l5.1-5zM209.5 240.4h76.2zM285.7 240.4l5.1-5z"/>
</g>
<path d="M54.6 253.1h25.4v10.2h-25.4z" fill="#000" stroke="#000" stroke-width=".25"/>
<use href="#words"/>
</svg>
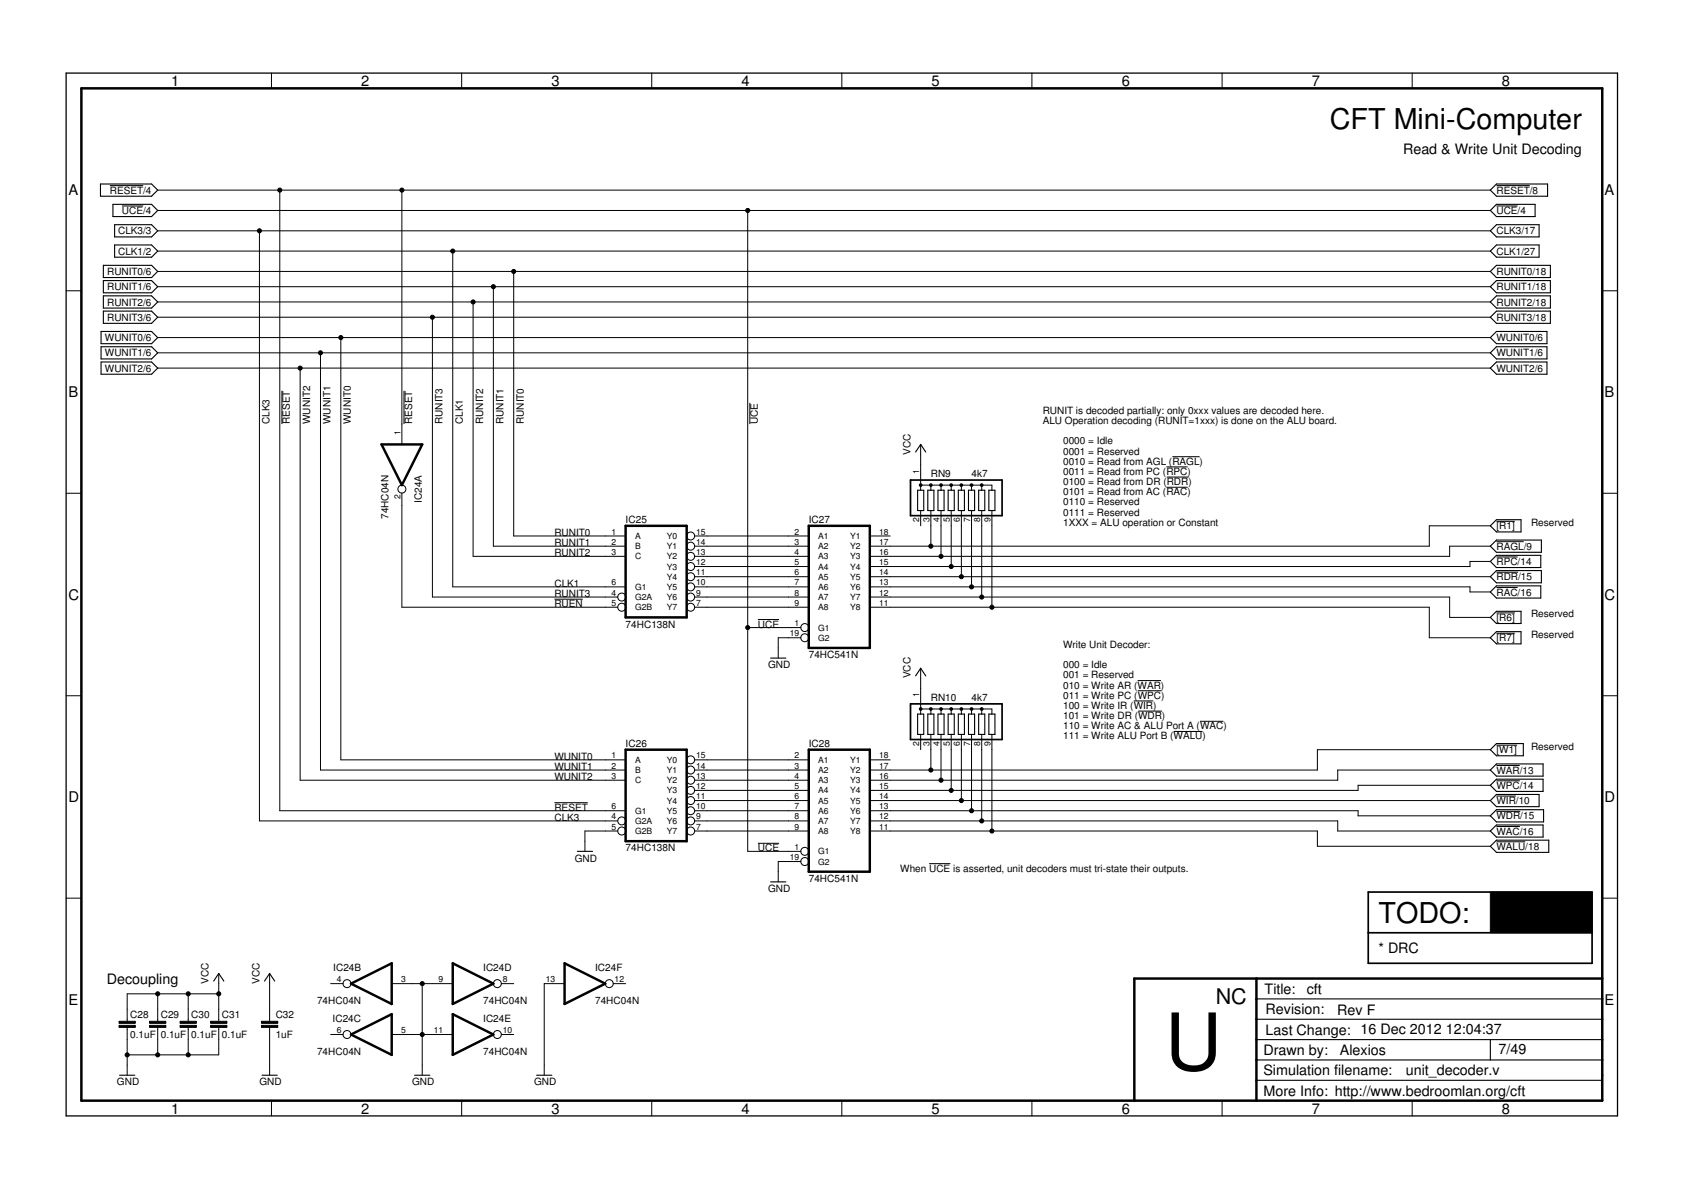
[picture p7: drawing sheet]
<svg xmlns="http://www.w3.org/2000/svg" width="420mm" height="297mm" viewBox="0 0 420 297" stroke-linecap="round" stroke-linejoin="round" font-family="sans-serif">
<defs><g id="words">
<text font-size="19.7" x="290.8" y="267.1">U</text>
<g font-size="7.2">
<text x="332" y="32.2">CFT Mini-Computer</text>
<text x="344.1" y="230.3">TODO:</text>
</g>
<text font-size="5.4" x="303.5" y="250.6">NC</text>
<g font-size="3.7">
<text x="42.7" y="21.5">1</text>
<text x="90.2" y="21.5">2</text>
<text x="137.7" y="21.5">3</text>
<text x="185.1" y="21.5">4</text>
<text x="232.6" y="21.5">5</text>
<text x="280" y="21.5">6</text>
<text x="327.5" y="21.5">7</text>
<text x="375" y="21.5">8</text>
<text x="17.1" y="48.6">A</text>
<text x="400.6" y="48.6">A</text>
<text x="17.1" y="99.2">B</text>
<text x="400.6" y="99.2">B</text>
<text x="17.1" y="149.7">C</text>
<text x="400.6" y="149.7">C</text>
<text x="17.1" y="200.2">D</text>
<text x="400.6" y="200.2">D</text>
<text x="17.1" y="250.8">E</text>
<text x="400.6" y="250.8">E</text>
<text x="42.7" y="277.9">1</text>
<text x="90.2" y="277.9">2</text>
<text x="137.7" y="277.9">3</text>
<text x="185.1" y="277.9">4</text>
<text x="232.6" y="277.9">5</text>
<text x="280" y="277.9">6</text>
<text x="327.5" y="277.9">7</text>
<text x="375" y="277.9">8</text>
</g>
<g font-size="3.6">
<text x="350.3" y="38.6">Read &amp; Write Unit Decoding</text>
<text x="344.1" y="237.9">* DRC</text>
<text x="26.7" y="245.5">Decoupling</text>
<text x="315.7" y="248.1">Title:</text>
<text x="326.2" y="248.2">cft</text>
<text x="315.9" y="253.2">Revision:</text>
<text x="333.8" y="253.3">Rev F</text>
<text x="315.4" y="263.3">Drawn by:</text>
<text x="315.9" y="258.2">Last Change: 16 Dec 2012</text>
<text x="334.5" y="263.3">Alexios</text>
<text x="361" y="258.1">12:04:37</text>
<text x="374.1" y="263.2">7/49</text>
<text x="315.4" y="268.4">Simulation filename:</text>
<text x="351" y="268.4">unit_decoder.v</text>
<text x="315.4" y="273.5">More Info: http://www.bedroomlan.org/cft</text>
</g>
<g font-size="2.5">
<text x="27.4" y="48.3">RESET/4</text>
<text x="30.5" y="53.4">UCE/4</text>
<text x="373.6" y="48.3">RESET/8</text>
<text x="373.6" y="53.4">UCE/4</text>
<text x="29.5" y="58.5">CLK3/3</text>
<text x="373.6" y="58.5">CLK3/17</text>
<text x="29.5" y="63.6">CLK1/2</text>
<text x="373.6" y="63.6">CLK1/27</text>
<text x="26.8" y="68.7">RUNIT0/6</text>
<text x="373.6" y="68.7">RUNIT0/18</text>
<text x="26.8" y="72.5">RUNIT1/6</text>
<text x="26.8" y="76.3">RUNIT2/6</text>
<text x="373.6" y="72.5">RUNIT1/18</text>
<text x="373.6" y="76.3">RUNIT2/18</text>
<text x="26.8" y="80.1">RUNIT3/6</text>
<text x="373.6" y="80.1">RUNIT3/18</text>
<text x="26.2" y="85.2">WUNIT0/6</text>
<text x="26.2" y="89">WUNIT1/6</text>
<text x="373.6" y="85.2">WUNIT0/6</text>
<text x="373.6" y="89">WUNIT1/6</text>
<text x="26.2" y="92.8">WUNIT2/6</text>
<text x="373.6" y="92.8">WUNIT2/6</text>
<text x="67.3" y="105.9" transform="rotate(-90 67.3 105.9)">CLK3</text>
<text x="72.4" y="105.9" transform="rotate(-90 72.4 105.9)">RESET</text>
<text x="77.5" y="105.9" transform="rotate(-90 77.5 105.9)">WUNIT2</text>
<text x="82.5" y="105.9" transform="rotate(-90 82.5 105.9)">WUNIT1</text>
<text x="87.6" y="105.9" transform="rotate(-90 87.6 105.9)">WUNIT0</text>
<text x="102.9" y="105.9" transform="rotate(-90 102.9 105.9)">RESET</text>
<text x="110.5" y="105.9" transform="rotate(-90 110.5 105.9)">RUNIT3</text>
<text x="115.6" y="105.9" transform="rotate(-90 115.6 105.9)">CLK1</text>
<text x="120.6" y="105.9" transform="rotate(-90 120.6 105.9)">RUNIT2</text>
<text x="125.7" y="105.9" transform="rotate(-90 125.7 105.9)">RUNIT1</text>
<text x="130.8" y="105.9" transform="rotate(-90 130.8 105.9)">RUNIT0</text>
<text x="189.2" y="105.9" transform="rotate(-90 189.2 105.9)">UCE</text>
<text x="260.3" y="103.3">RUNIT is decoded partially: only 0xxx values are decoded here.</text>
<text x="260.3" y="105.9">ALU Operation decoding (RUNIT=1xxx) is done on the ALU board.</text>
<text x="227.3" y="113.5" transform="rotate(-90 227.3 113.5)">VCC</text>
<text x="265.4" y="110.9">0000 = Idle</text>
<text x="265.4" y="113.5">0001 = Reserved</text>
<text x="232.4" y="119.2">RN9</text>
<text x="242.5" y="119.2">4k7</text>
<text x="265.4" y="116">0010 = Read from AGL (RAGL)</text>
<text x="265.4" y="118.6">0011 = Read from PC (RPC)</text>
<text x="105.3" y="125.5" transform="rotate(-90 105.3 125.5)">IC24A</text>
<text x="265.4" y="121.1">0100 = Read from DR (RDR)</text>
<text x="265.4" y="123.6">0101 = Read from AC (RAC)</text>
<text x="97" y="129.6" transform="rotate(-90 97 129.6)">74HC04N</text>
<text x="156.2" y="130.6">IC25</text>
<text x="201.9" y="130.6">IC27</text>
<text x="265.4" y="126.2">0110 = Reserved</text>
<text x="265.4" y="128.7">0111 = Reserved</text>
<text x="265.4" y="131.3">1XXX = ALU operation or Constant</text>
<text x="382.2" y="131.3">Reserved</text>
<text x="138.4" y="133.8">RUNIT0</text>
<text x="138.4" y="136.3">RUNIT1</text>
<text x="373.6" y="137.2">RAGL/9</text>
<text x="373.6" y="132.1">[R1]</text>
<text x="138.4" y="138.9">RUNIT2</text>
<text x="373.6" y="141">RPC/14</text>
<text x="138.4" y="149">RUNIT3</text>
<text x="138.4" y="146.5">CLK1</text>
<text x="373.6" y="144.8">RDR/15</text>
<text x="373.6" y="148.6">RAC/16</text>
<text x="138.4" y="151.6">RUEN</text>
<text x="373.6" y="155">[R6]</text>
<text x="382.2" y="154.1">Reserved</text>
<text x="156.2" y="156.6">74HC138N</text>
<text x="189.2" y="156.6">UCE</text>
<text x="265.4" y="161.7">Write Unit Decoder:</text>
<text x="373.6" y="160.1">[R7]</text>
<text x="382.2" y="159.2">Reserved</text>
<text x="191.7" y="166.8">GND</text>
<text x="201.9" y="164.3">74HC541N</text>
<text x="265.4" y="166.8">000 = Idle</text>
<text x="227.3" y="169.3" transform="rotate(-90 227.3 169.3)">VCC</text>
<text x="265.4" y="169.3">001 = Reserved</text>
<text x="265.4" y="171.9">010 = Write AR (WAR)</text>
<text x="232.4" y="175.1">RN10</text>
<text x="242.5" y="175.1">4k7</text>
<text x="265.4" y="174.4">011 = Write PC (WPC)</text>
<text x="265.4" y="177">100 = Write IR (WIR)</text>
<text x="265.4" y="179.5">101 = Write DR (WDR)</text>
<text x="265.4" y="184.6">111 = Write ALU Port B (WALU)</text>
<text x="265.4" y="182">110 = Write AC &amp; ALU Port A (WAC)</text>
<text x="138.4" y="189.7">WUNIT0</text>
<text x="156.2" y="186.5">IC26</text>
<text x="201.9" y="186.5">IC28</text>
<text x="373.6" y="188">[W1]</text>
<text x="382.2" y="187.1">Reserved</text>
<text x="138.4" y="192.2">WUNIT1</text>
<text x="138.4" y="194.7">WUNIT2</text>
<text x="373.6" y="193.1">WAR/13</text>
<text x="373.6" y="196.9">WPC/14</text>
<text x="138.4" y="202.4">RESET</text>
<text x="373.6" y="200.7">WIR/10</text>
<text x="138.4" y="204.9">CLK3</text>
<text x="373.6" y="204.5">WDR/15</text>
<text x="373.6" y="208.3">WAC/16</text>
<text x="143.5" y="215.1">GND</text>
<text x="156.2" y="212.5">74HC138N</text>
<text x="189.2" y="212.5">UCE</text>
<text x="373.6" y="212.1">WALU/18</text>
<text x="201.9" y="220.1">74HC541N</text>
<text x="224.8" y="217.6">When UCE is asserted, unit decoders must tri-state their outputs.</text>
<text x="191.7" y="222.7">GND</text>
<text x="52.1" y="245.5" transform="rotate(-90 52.1 245.5)">VCC</text>
<text x="64.8" y="245.5" transform="rotate(-90 64.8 245.5)">VCC</text>
<text x="83.2" y="242.4">IC24B</text>
<text x="120.6" y="242.4">IC24D</text>
<text x="148.6" y="242.4">IC24F</text>
<text x="79.2" y="250.6">74HC04N</text>
<text x="120.6" y="250.6">74HC04N</text>
<text x="148.6" y="250.6">74HC04N</text>
<text x="32.5" y="254">C28</text>
<text x="40.1" y="254">C29</text>
<text x="47.7" y="254">C30</text>
<text x="55.4" y="254">C31</text>
<text x="68.8" y="254">C32</text>
<text x="83" y="255.1">IC24C</text>
<text x="120.6" y="255.1">IC24E</text>
<text x="32.5" y="259.1">0.1uF</text>
<text x="40.1" y="259.1">0.1uF</text>
<text x="47.7" y="259.1">0.1uF</text>
<text x="55.4" y="259.1">0.1uF</text>
<text x="68.8" y="259.1">1uF</text>
<text x="79.2" y="263.3">74HC04N</text>
<text x="120.6" y="263.3">74HC04N</text>
<text x="29.2" y="270.9">GND</text>
<text x="64.8" y="270.9">GND</text>
<text x="102.9" y="270.9">GND</text>
<text x="133.3" y="270.9">GND</text>
</g>
<g font-size="2.1">
<text x="100" y="108.6" transform="rotate(-90 100 108.6)">1</text>
<text x="229.5" y="118.2" transform="rotate(-90 229.5 118.2)">1</text>
<text x="100" y="124.6" transform="rotate(-90 100 124.6)">2</text>
<text x="229.5" y="130.3" transform="rotate(-90 229.5 130.3)">2</text>
<text x="232" y="130.3" transform="rotate(-90 232 130.3)">3</text>
<text x="234.6" y="130.3" transform="rotate(-90 234.6 130.3)">4</text>
<text x="237.1" y="130.3" transform="rotate(-90 237.1 130.3)">5</text>
<text x="239.6" y="130.3" transform="rotate(-90 239.6 130.3)">6</text>
<text x="242.2" y="130.3" transform="rotate(-90 242.2 130.3)">7</text>
<text x="244.7" y="130.3" transform="rotate(-90 244.7 130.3)">8</text>
<text x="247.3" y="130.3" transform="rotate(-90 247.3 130.3)">9</text>
<text x="152.7" y="133.4">1</text>
<text x="152.7" y="136">2</text>
<text x="158.5" y="134.6">A</text>
<text x="158.5" y="137.1">B</text>
<text x="166.5" y="137.1">Y1</text>
<text x="166.5" y="134.6">Y0</text>
<text x="173.8" y="136">14</text>
<text x="173.8" y="133.4">15</text>
<text x="198.4" y="133.4">2</text>
<text x="198.4" y="136">3</text>
<text x="204.2" y="134.6">A1</text>
<text x="204.2" y="137.1">A2</text>
<text x="212.2" y="137.1">Y2</text>
<text x="212.2" y="134.6">Y1</text>
<text x="219.5" y="136">17</text>
<text x="219.5" y="133.4">18</text>
<text x="152.7" y="138.5">3</text>
<text x="158.5" y="139.6">C</text>
<text x="166.5" y="142.2">Y3</text>
<text x="166.5" y="139.6">Y2</text>
<text x="173.8" y="143.6">11</text>
<text x="173.8" y="141.1">12</text>
<text x="173.8" y="138.5">13</text>
<text x="198.4" y="138.5">4</text>
<text x="198.4" y="141.1">5</text>
<text x="198.4" y="143.6">6</text>
<text x="204.2" y="139.6">A3</text>
<text x="204.2" y="142.2">A4</text>
<text x="212.2" y="142.2">Y4</text>
<text x="212.2" y="139.6">Y3</text>
<text x="219.5" y="143.6">14</text>
<text x="219.5" y="141.1">15</text>
<text x="219.5" y="138.5">16</text>
<text x="152.7" y="148.7">4</text>
<text x="152.7" y="146.1">6</text>
<text x="158.5" y="149.8">G2A</text>
<text x="158.5" y="147.3">G1</text>
<text x="166.5" y="149.8">Y6</text>
<text x="166.5" y="147.3">Y5</text>
<text x="166.5" y="144.7">Y4</text>
<text x="173.8" y="148.7">9</text>
<text x="173.8" y="146.1">10</text>
<text x="198.4" y="146.1">7</text>
<text x="198.4" y="148.7">8</text>
<text x="204.2" y="144.7">A5</text>
<text x="204.2" y="147.3">A6</text>
<text x="204.2" y="149.8">A7</text>
<text x="212.2" y="149.8">Y7</text>
<text x="212.2" y="147.3">Y6</text>
<text x="212.2" y="144.7">Y5</text>
<text x="219.5" y="148.7">12</text>
<text x="219.5" y="146.1">13</text>
<text x="152.7" y="151.2">5</text>
<text x="158.5" y="152.3">G2B</text>
<text x="166.5" y="152.3">Y7</text>
<text x="173.8" y="151.2">7</text>
<text x="198.4" y="151.2">9</text>
<text x="204.2" y="152.3">A8</text>
<text x="212.2" y="152.3">Y8</text>
<text x="219.5" y="151.2">11</text>
<text x="197.2" y="158.8">19</text>
<text x="198.4" y="156.3">1</text>
<text x="204.2" y="157.4">G1</text>
<text x="204.2" y="159.9">G2</text>
<text x="229.5" y="174.1" transform="rotate(-90 229.5 174.1)">1</text>
<text x="152.7" y="189.3">1</text>
<text x="152.7" y="191.8">2</text>
<text x="158.5" y="190.4">A</text>
<text x="166.5" y="190.4">Y0</text>
<text x="173.8" y="191.8">14</text>
<text x="173.8" y="189.3">15</text>
<text x="198.4" y="189.3">2</text>
<text x="198.4" y="191.8">3</text>
<text x="204.2" y="190.4">A1</text>
<text x="212.2" y="190.4">Y1</text>
<text x="219.5" y="191.8">17</text>
<text x="219.5" y="189.3">18</text>
<text x="229.5" y="186.1" transform="rotate(-90 229.5 186.1)">2</text>
<text x="232" y="186.1" transform="rotate(-90 232 186.1)">3</text>
<text x="234.6" y="186.1" transform="rotate(-90 234.6 186.1)">4</text>
<text x="237.1" y="186.1" transform="rotate(-90 237.1 186.1)">5</text>
<text x="239.6" y="186.1" transform="rotate(-90 239.6 186.1)">6</text>
<text x="242.2" y="186.1" transform="rotate(-90 242.2 186.1)">7</text>
<text x="244.7" y="186.1" transform="rotate(-90 244.7 186.1)">8</text>
<text x="247.3" y="186.1" transform="rotate(-90 247.3 186.1)">9</text>
<text x="152.7" y="194.4">3</text>
<text x="158.5" y="193">B</text>
<text x="158.5" y="195.5">C</text>
<text x="166.5" y="195.5">Y2</text>
<text x="166.5" y="193">Y1</text>
<text x="173.8" y="196.9">12</text>
<text x="173.8" y="194.4">13</text>
<text x="198.4" y="194.4">4</text>
<text x="198.4" y="196.9">5</text>
<text x="204.2" y="193">A2</text>
<text x="204.2" y="195.5">A3</text>
<text x="212.2" y="195.5">Y3</text>
<text x="212.2" y="193">Y2</text>
<text x="219.5" y="196.9">15</text>
<text x="219.5" y="194.4">16</text>
<text x="152.7" y="202">6</text>
<text x="158.5" y="203.1">G1</text>
<text x="166.5" y="203.1">Y5</text>
<text x="166.5" y="200.6">Y4</text>
<text x="166.5" y="198">Y3</text>
<text x="173.8" y="202">10</text>
<text x="173.8" y="199.5">11</text>
<text x="198.4" y="199.5">6</text>
<text x="198.4" y="202">7</text>
<text x="204.2" y="198">A4</text>
<text x="204.2" y="200.6">A5</text>
<text x="204.2" y="203.1">A6</text>
<text x="212.2" y="203.1">Y6</text>
<text x="212.2" y="200.6">Y5</text>
<text x="212.2" y="198">Y4</text>
<text x="219.5" y="202">13</text>
<text x="219.5" y="199.5">14</text>
<text x="152.7" y="204.5">4</text>
<text x="152.7" y="207.1">5</text>
<text x="158.5" y="205.7">G2A</text>
<text x="158.5" y="208.2">G2B</text>
<text x="166.5" y="208.2">Y7</text>
<text x="166.5" y="205.7">Y6</text>
<text x="173.8" y="207.1">7</text>
<text x="173.8" y="204.5">9</text>
<text x="198.4" y="204.5">8</text>
<text x="198.4" y="207.1">9</text>
<text x="204.2" y="205.7">A7</text>
<text x="204.2" y="208.2">A8</text>
<text x="212.2" y="208.2">Y8</text>
<text x="212.2" y="205.7">Y7</text>
<text x="219.5" y="207.1">11</text>
<text x="219.5" y="204.5">12</text>
<text x="197.2" y="214.7">19</text>
<text x="198.4" y="212.2">1</text>
<text x="204.2" y="213.3">G1</text>
<text x="204.2" y="215.8">G2</text>
<text x="84.1" y="245.2">4</text>
<text x="100.1" y="245.2">3</text>
<text x="109.5" y="245.2">9</text>
<text x="125.5" y="245.2">8</text>
<text x="136.2" y="245.2">13</text>
<text x="153.5" y="245.2">12</text>
<text x="84.1" y="257.9">6</text>
<text x="100.1" y="257.9">5</text>
<text x="108.3" y="257.9">11</text>
<text x="125.5" y="257.9">10</text>
</g>
</g></defs>
<g fill="#000" stroke="#000" stroke-width=".25">
<path d="M67.8 18.2v3.9zM115.3 18.2v3.9zM162.7 18.2v3.9zM210.2 18.2v3.9zM257.6 18.2v3.9zM305.1 18.2v3.9zM352.5 18.2v3.9zM20.3 22.1v252.6zM20.3 22.1h379.7zM27.4 46.3h8.3zM30.5 51.4h5.2zM39.4 47.5h30.4z"/>
<path d="M39.4 52.5h147.3zM39.4 57.6h25.4zM69.8 47.5h30.5zM100.3 47.5h271.8zM186.7 52.5h185.4zM64.8 57.6h307.3zM373.6 46.3h8.3zM373.6 51.4h5.3zM16.5 72.6h3.8zM39.4 62.7h73.6zM39.4 79.2h68.5zM113 62.7h259.1z"/>
<path d="M39.4 75.4h78.7zM39.4 71.6h83.8zM39.4 67.8h88.8zM128.2 67.8h243.9zM123.2 71.6h248.9zM118.1 75.4h254zM107.9 79.2h264.2zM400 72.6h3.8zM39.4 91.9h35.5zM39.4 88.1h40.6zM39.4 84.3h45.7zM85.1 84.3h287z"/>
<path d="M80 88.1h292.1zM74.9 91.9h297.2zM70.4 97.5v8.4zM100.3 105.9v5zM100.3 47.5v58.4zM100.9 97.5v8.4zM187.2 100.6v5.3zM229.8 116v2.6zM229.8 110.9v2.6zM229.8 113.5v2.5zM291.2 116.5h5.3zM291.3 119.1h5.4z"/>
<path d="M292.7 114h6.8zM16.5 123.1h3.8zM100.3 123.1v3.1zM118.1 75.4v63.5zM123.2 71.6v64.7zM128.2 67.8v66zM151.1 133.8h5.1zM151.1 136.3h5.1zM151.1 138.9h5.1zM128.2 133.8h22.9zM123.2 136.3h27.9zM118.1 138.9h33z"/>
<path d="M173.4 138.9h3.1zM173.4 136.3h3.1zM173.4 133.8h3.1zM176.5 138.9h20.3zM176.5 136.3h20.3zM176.5 133.8h20.3zM196.8 133.8h5.1zM196.8 136.3h5.1zM196.8 138.9h5.1zM217.1 138.9h5.1zM217.1 136.3h5.1zM217.1 133.8h5.1z"/>
<path d="M222.2 138.9h12.7zM222.2 136.3h10.2zM229.8 128.7v2.6zM229.8 127.4v1.3zM229.8 121.1v1.3zM229.8 121.1h2.6zM229.8 118.6v2.5zM232.4 128.7v2.6zM232.4 121.1v1.3zM232.4 121.1h2.5zM232.4 127.4v1.3zM232.4 136.3h124.4z"/>
<path d="M232.4 131.3v5zM234.9 128.7v2.6zM234.9 121.1v1.3zM234.9 121.1h2.6zM234.9 127.4v1.3zM234.9 138.9h127zM234.9 131.3v7.6zM237.5 128.7v2.6zM237.5 121.1v1.3zM237.5 121.1h2.5zM237.5 127.4v1.3zM237.5 131.3v10.1z"/>
<path d="M240 128.7v2.6zM240 121.1v1.3zM240 127.4v1.3zM240 121.1h2.5zM240 131.3v12.7zM242.5 128.7v2.6zM242.5 127.4v1.3zM242.5 121.1v1.3zM242.5 121.1h2.6zM242.5 131.3v15.2zM245.1 128.7v2.6zM245.1 121.1v1.3z"/>
<path d="M245.1 121.1h2.5zM245.1 127.4v1.3zM245.1 131.3v17.7zM247.6 128.7v2.6zM247.6 121.1v1.3zM247.6 127.4v1.3zM247.6 131.3v20.3zM291.2 121.6h5.3zM356.8 131.3v5zM356.8 131.3h15.3zM361.9 136.3v2.6zM361.9 136.3h10.2z"/>
<path d="M373.6 135.2h6.8zM373.6 139h5.3zM373.6 130.1h4.6zM400 123.1h3.8zM100.3 126.2v25.4zM107.9 79.2v69.8zM113 62.7v83.8zM138.4 149.6h7.1zM151.1 149h3.1zM151.1 151.6h3.1zM151.1 146.5h5.1zM107.9 149h43.2z"/>
<path d="M113 146.5h38.1zM100.3 151.6h50.8zM173.4 151.6h3.1zM173.4 149h3.1zM173.4 146.5h3.1zM173.4 144h3.1zM173.4 141.4h3.1zM176.5 151.6h20.3zM176.5 149h20.3zM176.5 146.5h20.3zM176.5 144h20.3zM176.5 141.4h20.3z"/>
<path d="M186.7 52.5v104.2zM189.2 154.6h5.3zM194.3 159.2v2.5zM196.8 156.7h3.1zM196.8 141.4h5.1zM196.8 144h5.1zM196.8 146.5h5.1zM196.8 149h5.1zM196.8 151.6h5.1zM196.8 159.2h3.1zM194.3 159.2h2.5zM186.7 156.7h10.1z"/>
<path d="M217.1 151.6h5.1zM217.1 149h5.1zM217.1 146.5h5.1zM217.1 144h5.1zM217.1 141.4h5.1zM222.2 141.4h15.3zM222.2 144h17.8zM222.2 146.5h20.3zM222.2 149h22.9zM222.2 151.6h25.4zM237.5 141.4h129.5zM240 144h132.1z"/>
<path d="M242.5 146.5h124.5zM245.1 149h116.8zM247.6 151.6h109.2zM356.8 151.6v7.6zM356.8 159.2h15.3zM361.9 149v5.1zM361.9 154.1h10.2zM367 140.1v1.3zM367 140.1h5.1zM367 146.5v1.3zM367 147.8h5.1zM373.6 142.8h5.4z"/>
<path d="M373.6 146.6h5.3zM373.6 153h4.6zM373.6 158.1h4.6zM16.5 173.7h3.8zM194.3 161.7v2.6zM229.8 166.8v2.6zM229.8 171.9v2.5zM229.8 177v1.2zM229.8 177h2.6zM229.8 174.4v2.6zM229.8 169.4v2.5zM232.4 177v1.2z"/>
<path d="M232.4 177h2.5zM234.9 177v1.2zM234.9 177h2.6zM237.5 177v1.2zM237.5 177h2.5zM240 177v1.2zM240 177h2.5zM242.5 177v1.2zM242.5 177h2.6zM245.1 177v1.2zM245.1 177h2.5zM247.6 177v1.2z"/>
<path d="M283 175h4.9zM284 169.9h5.8zM284 172.4h5.9zM284.1 177.5h6zM400 173.7h3.8zM74.9 91.9v102.9zM80 88.1v104.1zM85.1 84.3v105.4zM151.1 189.7h5.1zM151.1 192.2h5.1zM151.1 194.8h5.1zM85.1 189.7h66z"/>
<path d="M80 192.2h71.1zM74.9 194.8h76.2zM173.4 199.8h3.1zM173.4 197.3h3.1zM173.4 194.8h3.1zM173.4 192.2h3.1zM173.4 189.7h3.1zM196.8 189.7h5.1zM196.8 192.2h5.1zM196.8 194.8h5.1zM196.8 197.3h5.1zM196.8 199.8h5.1z"/>
<path d="M176.5 189.7h20.3zM176.5 192.2h20.3zM176.5 194.8h20.3zM176.5 197.3h20.3zM176.5 199.8h20.3zM217.1 199.8h5.1zM217.1 197.3h5.1zM217.1 194.8h5.1zM217.1 192.2h5.1zM217.1 189.7h5.1zM222.2 197.3h15.3zM222.2 192.2h10.2z"/>
<path d="M229.8 184.6v2.5zM229.8 183.3v1.3zM232.4 184.6v2.5zM232.4 183.3v1.3zM232.4 192.2h96.5zM232.4 187.1v5.1zM234.9 184.6v2.5zM234.9 183.3v1.3zM222.2 194.8h12.7zM234.9 187.1v7.7zM237.5 184.6v2.5zM237.5 183.3v1.3z"/>
<path d="M237.5 197.3h101.5zM237.5 187.1v10.2zM240 184.6v2.5zM240 183.3v1.3zM222.2 199.8h17.8zM240 187.1v12.7zM242.5 184.6v2.5zM242.5 183.3v1.3zM242.5 187.1v15.3zM245.1 184.6v2.5zM245.1 183.3v1.3zM245.1 187.1v17.8z"/>
<path d="M247.6 184.6v2.5zM247.6 183.3v1.3zM247.6 187.1v20.3zM293 182.6h7.2zM299.6 180h5.8zM328.9 187.1v5.1zM328.9 187.1h43.2zM334 192.2v2.6zM234.9 194.8h99.1zM339 196v1.3zM339 196h33.1zM334 192.2h38.1z"/>
<path d="M240 199.8h132.1zM373.6 191.1h5.8zM373.6 194.9h5.8zM373.6 198.7h4.8zM373.6 186h5.1zM64.8 57.6v147.3zM69.8 47.5v154.9zM138.4 200.4h8.3zM146 210v2.5zM146 207.4v2.6zM151.1 204.9h3.1zM151.1 207.4h3.1z"/>
<path d="M151.1 202.4h5.1zM146 207.4h5.1zM69.8 202.4h81.3zM64.8 204.9h86.3zM173.4 207.4h3.1zM173.4 204.9h3.1zM173.4 202.4h3.1zM186.7 212.5h10.1zM186.7 156.7v55.8zM189.2 210.5h5.3zM194.3 217.6v2.5zM194.3 215v2.6z"/>
<path d="M196.8 212.5h3.1zM196.8 202.4h5.1zM196.8 204.9h5.1zM196.8 207.4h5.1zM196.8 215h3.1zM194.3 215h2.5zM176.5 202.4h20.3zM176.5 204.9h20.3zM176.5 207.4h20.3zM217.1 207.4h5.1zM217.1 204.9h5.1zM217.1 202.4h5.1z"/>
<path d="M222.2 204.9h22.9zM222.2 207.4h25.4zM232 215.6h5.3zM222.2 202.4h20.3zM245.1 204.9h88.9zM247.6 207.4h81.3zM328.9 207.4v3.8zM328.9 211.2h43.2zM334 204.9v2.5zM334 207.4h38.1zM339 202.4v1.2zM242.5 202.4h96.5z"/>
<path d="M339 203.6h33.1zM373.6 202.5h5.9zM373.6 206.3h5.8zM373.6 210.1h7.2zM16.5 224.2h3.8zM400 224.2h3.8zM31.7 257v2.5zM31.7 251.9v2.5zM31.7 256.5v.5zM31.7 254.4v.5zM31.7 259.5v3.8zM31.7 248.1v3.8z"/>
<path d="M39.4 257v2.5zM39.4 251.9v2.5zM39.4 256.5v.5zM39.4 254.4v.5zM31.7 248.1h7.7zM39.4 248.1v3.8zM47 257v2.5zM47 251.9v2.5zM47 256.5v.5zM47 254.4v.5zM39.4 248.1h7.6zM47 248.1v3.8z"/>
<path d="M54.6 243v2.5zM54.6 257v2.5zM54.6 251.9v2.5zM54.6 256.5v.5zM54.6 254.4v.5zM47 248.1h7.6zM54.6 248.1v3.8zM54.6 245.5v2.6zM67.3 243v2.5zM67.3 251.9v2.5zM67.3 257v2.5zM67.3 254.4v.5z"/>
<path d="M67.3 256.5v.5zM67.3 245.5v6.4zM82.5 245.5h3.1zM82.5 258.2h3.1zM97.8 245.5h5.1zM97.8 258.2h5.1zM102.9 245.5h2.5zM102.9 258.2h2.5zM105.4 245.5v12.7zM105.4 258.2v7.6zM105.4 245.5h2.5zM105.4 258.2h2.5z"/>
<path d="M107.9 245.5h5.1zM107.9 258.2h5.1zM125.2 245.5h3zM125.2 258.2h3zM135.9 245.5h5zM135.9 245.5v20.3zM153.1 245.5h3.1zM20.3 274.7h379.7zM31.7 265.8v2.6zM31.7 263.3h7.7zM31.7 263.3v2.5zM39.4 259.5v3.8z"/>
<path d="M39.4 263.3h7.6zM47 259.5v3.8zM47 263.3h7.6zM54.6 259.5v3.8zM67.3 265.8v2.6zM67.3 259.5v6.3zM67.8 274.7v3.8zM105.4 265.8v2.6zM115.3 274.7v3.8zM135.9 265.8v2.6zM162.7 274.7v3.8zM210.2 274.7v3.8z"/>
<path d="M257.6 274.7v3.8zM305.1 274.7v3.8zM352.5 274.7v3.8zM400 264.5v.1zM400 268.4v6.2zM400 274.6h.1zM400 22.1v252.6z"/>
<circle cx="64.8" cy="57.6" r=".51"/>
<circle cx="69.8" cy="47.5" r=".51"/>
<circle cx="100.3" cy="47.5" r=".51"/>
<circle cx="186.7" cy="52.5" r=".51"/>
<circle cx="107.9" cy="79.2" r=".51"/>
<circle cx="113" cy="62.7" r=".51"/>
<circle cx="118.1" cy="75.4" r=".51"/>
<circle cx="123.2" cy="71.6" r=".51"/>
<circle cx="128.2" cy="67.8" r=".51"/>
<circle cx="74.9" cy="91.9" r=".51"/>
<circle cx="80" cy="88.1" r=".51"/>
<circle cx="85.1" cy="84.3" r=".51"/>
<circle cx="232.4" cy="136.3" r=".51"/>
<circle cx="234.9" cy="138.9" r=".51"/>
<circle cx="186.7" cy="156.7" r=".51"/>
<circle cx="237.5" cy="141.4" r=".51"/>
<circle cx="240" cy="144" r=".51"/>
<circle cx="242.5" cy="146.5" r=".51"/>
<circle cx="245.1" cy="149" r=".51"/>
<circle cx="247.6" cy="151.6" r=".51"/>
<circle cx="232.4" cy="192.2" r=".51"/>
<circle cx="234.9" cy="194.8" r=".51"/>
<circle cx="237.5" cy="197.3" r=".51"/>
<circle cx="240" cy="199.8" r=".51"/>
<circle cx="242.5" cy="202.4" r=".51"/>
<circle cx="245.1" cy="204.9" r=".51"/>
<circle cx="247.6" cy="207.4" r=".51"/>
<circle cx="39.4" cy="248.1" r=".51"/>
<circle cx="47" cy="248.1" r=".51"/>
<circle cx="54.6" cy="248.1" r=".51"/>
<circle cx="105.4" cy="258.2" r=".51"/>
<circle cx="105.4" cy="245.5" r=".51"/>
<circle cx="31.7" cy="263.3" r=".51"/>
<circle cx="39.4" cy="263.3" r=".51"/>
<circle cx="47" cy="263.3" r=".51"/>
</g>
<g fill="#000" stroke="#000" stroke-width=".28">
<path d="M25.1 45.9v3.1zM28.2 51v3.1zM28.6 56.1v3zM25.1 45.9h12.7zM25.1 49h12.7zM28.2 51h9.6zM28.2 54.1h9.6zM28.6 56.1h9.2zM28.6 59.1h9.2zM37.8 45.9l1.6 1.6zM39.4 47.5l-1.6 1.5zM37.8 51l1.6 1.5z"/>
<path d="M39.4 52.5l-1.6 1.6zM37.8 56.1l1.6 1.5zM39.4 57.6l-1.6 1.5zM373.6 45.9l-1.5 1.6zM372.1 47.5l1.5 1.5zM372.1 52.5l1.5-1.5zM372.1 52.5l1.5 1.6zM373.6 56.1l-1.5 1.5zM372.1 57.6l1.5 1.5zM373.6 45.9h12.7zM373.6 49h12.7zM373.6 51h9.6z"/>
<path d="M373.6 54.1h9.6zM373.6 56.1h10.6zM373.6 59.1h10.6zM383.2 51v3.1zM384.2 56.1v3zM386.3 45.9v3.1zM25.8 66.2v3.1zM25.8 70v3.1zM25.8 73.8v3.1zM25.8 77.7v3zM28.6 61.1v3.1zM25.8 66.2h12z"/>
<path d="M25.8 69.3h12zM25.8 70h12zM25.8 73.1h12zM25.8 73.8h12zM25.8 76.9h12zM25.8 77.7h12zM28.6 64.2h9.2zM28.6 61.1h9.2zM37.8 66.2l1.6 1.6zM39.4 67.8l-1.6 1.5zM37.8 70l1.6 1.6zM39.4 71.6l-1.6 1.5z"/>
<path d="M37.8 73.8l1.6 1.6zM39.4 75.4l-1.6 1.5zM37.8 77.7l1.6 1.5zM39.4 79.2l-1.6 1.5zM39.4 62.7l-1.6 1.5zM37.8 61.1l1.6 1.6zM372.1 67.8l1.5-1.6zM372.1 67.8l1.5 1.5zM372.1 71.6l1.5-1.6zM372.1 71.6l1.5 1.5zM372.1 75.4l1.5-1.6zM372.1 75.4l1.5 1.5z"/>
<path d="M372.1 79.2l1.5-1.5zM372.1 79.2l1.5 1.5zM373.6 61.1l-1.5 1.6zM372.1 62.7l1.5 1.5zM373.6 66.2h13.4zM373.6 69.3h13.4zM373.6 70h13.4zM373.6 73.1h13.4zM373.6 73.8h13.4zM373.6 76.9h13.4zM373.6 77.7h13.4zM373.6 61.1h10.6z"/>
<path d="M373.6 64.2h10.6zM384.2 61.1v3.1zM387 66.2v3.1zM387 70v3.1zM387 73.8v3.1zM387 77.7v3zM25.2 82.7v3.1zM25.2 86.5v3.1zM25.2 90.4v3zM25.8 80.7h12zM25.2 82.7h12.6zM25.2 85.8h12.6z"/>
<path d="M25.2 86.5h12.6zM25.2 89.6h12.6zM25.2 90.4h12.6zM25.2 93.4h12.6zM37.8 82.7l1.6 1.6zM39.4 84.3l-1.6 1.5zM37.8 86.5l1.6 1.6zM39.4 88.1l-1.6 1.5zM37.8 90.4l1.6 1.5zM39.4 91.9l-1.6 1.5zM372.1 84.3l1.5-1.6zM372.1 84.3l1.5 1.5z"/>
<path d="M372.1 88.1l1.5-1.6zM372.1 88.1l1.5 1.5zM372.1 91.9l1.5-1.5zM372.1 91.9l1.5 1.5zM373.6 80.7h13.4zM373.6 82.7h12.6zM373.6 85.8h12.6zM373.6 86.5h12.6zM373.6 89.6h12.6zM373.6 90.4h12.6zM373.6 93.4h12.6zM386.2 82.7v3.1z"/>
<path d="M386.2 86.5v3.1zM386.2 90.4v3zM229.8 110.9l-1.2 1.9zM229.8 110.9l1.3 1.9zM229.1 122.4v5zM229.1 127.4h.7zM229.8 127.4h.8zM229.1 122.4h.7zM230.6 122.4v5zM229.8 122.4h.8zM231.6 127.4h.8zM231.6 122.4v5z"/>
<path d="M232.4 127.4h.7zM231.6 122.4h.8zM232.4 122.4h.7zM233.1 122.4v5zM234.2 122.4v5zM234.2 127.4h.7zM234.2 122.4h.7zM234.9 127.4h.8zM235.7 122.4v5zM234.9 122.4h.8zM236.7 122.4v5zM236.7 127.4h.8z"/>
<path d="M236.7 122.4h.8zM237.5 127.4h.7zM238.2 122.4v5zM237.5 122.4h.7zM239.2 122.4v5zM239.2 127.4h.8zM239.2 122.4h.8zM240 127.4h.8zM240.8 122.4v5zM240 122.4h.8zM241.8 122.4v5zM241.8 127.4h.7z"/>
<path d="M242.5 127.4h.8zM241.8 122.4h.7zM243.3 122.4v5zM242.5 122.4h.8zM244.3 127.4h.8zM244.3 122.4v5zM245.1 127.4h.7zM244.3 122.4h.8zM245.1 122.4h.7zM245.8 122.4v5zM246.9 122.4v5zM246.9 127.4h.7z"/>
<path d="M246.9 122.4h.7zM247.6 127.4h.8zM248.4 122.4v5zM247.6 122.4h.8zM372.1 136.3l1.5-1.5zM372.1 136.3l1.5 1.6zM372.1 131.3l1.5-1.6zM372.1 131.3l1.5 1.5zM373.6 134.8h11.2zM373.6 137.9h11.2zM373.6 138.6h11.1zM373.6 129.7h6.1z"/>
<path d="M373.6 132.8h6.1zM379.7 129.7v3.1zM384.7 138.6v3.1zM384.8 134.8v3.1zM372.1 140.1l1.5-1.5zM372.1 140.1l1.5 1.6zM372.1 144l1.5-1.6zM372.1 144l1.5 1.5zM372.1 147.8l1.5-1.6zM372.1 147.8l1.5 1.5zM372.1 154.1l1.5-1.5zM372.1 154.1l1.5 1.5z"/>
<path d="M372.1 159.2l1.5-1.5zM372.1 159.2l1.5 1.5zM373.6 141.7h11.1zM373.6 142.4h11.2zM373.6 145.5h11.2zM373.6 146.2h11.1zM373.6 149.3h11.1zM373.6 152.6h6.1zM373.6 155.6h6.1zM373.6 157.7h6.1zM379.7 152.6v3zM379.7 157.7v3z"/>
<path d="M384.7 146.2v3.1zM384.8 142.4v3.1zM192.4 164.3h3.8zM229.1 178.2v5.1zM229.8 166.8l-1.2 1.9zM229.1 178.2h.7zM229.8 178.2h.8zM229.8 166.8l1.3 1.9zM231.6 178.2v5.1zM231.6 178.2h.8zM232.4 178.2h.7zM234.2 178.2v5.1z"/>
<path d="M234.2 178.2h.7zM234.9 178.2h.8zM236.7 178.2v5.1zM236.7 178.2h.8zM237.5 178.2h.7zM239.2 178.2v5.1zM239.2 178.2h.8zM240 178.2h.8zM241.8 178.2v5.1zM241.8 178.2h.7zM242.5 178.2h.8zM244.3 178.2v5.1z"/>
<path d="M244.3 178.2h.8zM245.1 178.2h.7zM246.9 178.2v5.1zM246.9 178.2h.7zM247.6 178.2h.8zM373.6 160.7h6.1zM229.1 183.3h.7zM229.8 183.3h.8zM230.6 178.2v5.1zM231.6 183.3h.8zM232.4 183.3h.7zM233.1 178.2v5.1z"/>
<path d="M234.2 183.3h.7zM234.9 183.3h.8zM235.7 178.2v5.1zM236.7 183.3h.8zM237.5 183.3h.7zM238.2 178.2v5.1zM239.2 183.3h.8zM240 183.3h.8zM240.8 178.2v5.1zM241.8 183.3h.7zM242.5 183.3h.8zM243.3 178.2v5.1z"/>
<path d="M244.3 183.3h.8zM245.1 183.3h.7zM245.8 178.2v5.1zM246.9 183.3h.7zM247.6 183.3h.8zM248.4 178.2v5.1zM372.1 192.2l1.5-1.5zM372.1 192.2l1.5 1.5zM372.1 196l1.5-1.5zM372.1 196l1.5 1.5zM372.1 199.8l1.5-1.5zM372.1 199.8l1.5 1.6z"/>
<path d="M372.1 187.1l1.5-1.5zM372.1 187.1l1.5 1.6zM373.6 190.7h11.6zM373.6 193.7h11.6zM373.6 194.5h11.6zM373.6 197.5h11.6zM373.6 198.3h10.6zM373.6 185.6h6.7zM373.6 188.7h6.7zM380.3 185.6v3.1zM384.2 198.3v3.1zM385.2 190.7v3z"/>
<path d="M385.2 194.5v3zM144.1 212.5h3.8zM372.1 203.6l1.5-1.5zM372.1 203.6l1.5 1.6zM372.1 207.4l1.5-1.5zM372.1 207.4l1.5 1.6zM372.1 211.2l1.5-1.5zM372.1 211.2l1.5 1.6zM373.6 202.1h11.8zM373.6 205.2h11.8zM373.6 205.9h11.6zM373.6 209h11.6z"/>
<path d="M373.6 209.7h13zM373.6 212.8h13zM373.6 201.4h10.6zM385.2 205.9v3.1zM385.4 202.1v3.1zM386.6 209.7v3.1zM192.4 220.1h3.8zM54.6 243l-1.3 1.9zM54.6 243l1.3 1.9zM67.3 243l-1.3 1.9zM67.3 243l1.3 1.9zM313.7 249.3h86.3z"/>
<path d="M313.7 254.4h86.3zM313.7 259.5h58.4zM372.1 259.5h27.9zM372.1 259.5v5.1zM29.8 268.4h3.9zM65.4 268.4h3.8zM103.5 268.4h3.8zM134 268.4h3.8zM313.7 264.6h58.4zM313.7 269.7h86.3zM372.1 264.6h27.9zM400 268.4v1.3z"/>
</g>
<path d="M372.1 222.7h25.4v10.1h-25.4zM29.7 254.9h4.1v.5h-4.1zM29.7 255.9h4.1v.6h-4.1zM37.3 254.9h4.1v.5h-4.1zM37.3 255.9h4.1v.6h-4.1zM45 254.9h4v.5h-4zM45 255.9h4v.6h-4zM52.6 254.9h4v.5h-4zM52.6 255.9h4v.6h-4zM65.3 255.9h4v.6h-4zM65.3 254.9h4v.5h-4z" fill="#000" stroke="#000" stroke-width=".25"/>
<path d="M16.5 18.2v260.3zM16.5 18.2h387.3zM16.5 278.5h387.3zM403.8 18.2v260.3z" fill="#000" stroke="#000" stroke-width=".32"/>
<g fill="#000" stroke="#000" stroke-width=".61">
<path d="M20.3 22.1v252.6zM20.3 22.1h379.7zM95.2 110.9h10.2zM105.4 110.9l-5.1 10.2zM95.2 110.9l5.1 10.2zM156.2 131.3v22.8zM156.2 131.3h15.2zM201.9 131.3v30.4zM201.9 131.3h15.2zM156.2 154.1h15.2zM171.4 131.3v22.8zM201.9 161.7h15.2z"/>
<path d="M217.1 131.3v30.4zM156.2 187.1v22.9zM156.2 187.1h15.2zM201.9 187.1v30.5zM201.9 187.1h15.2zM156.2 210h15.2zM171.4 187.1v22.9zM201.9 217.6h15.2zM217.1 187.1v30.5zM87.6 245.5l10.2 5.1zM87.6 258.2l10.2 5.1zM87.6 245.5l10.2-5.1z"/>
<path d="M97.8 240.4v10.2zM87.6 258.2l10.2-5.1zM113 240.4l10.2 5.1zM113 240.4v10.2zM113 253.1l10.2 5.1zM113 250.6l10.2-5.1zM113 263.3l10.2-5.1zM140.9 240.4l10.2 5.1zM140.9 240.4v10.2zM140.9 250.6l10.2-5.1zM283.2 244.3v30.4zM313.7 254.4v5.1z"/>
<path d="M313.7 249.3v5.1zM313.7 244.3v5zM313.7 244.3h86.3zM283.2 244.3h30.5zM400 254.4v5.1zM400 249.3v5.1zM400 244.3v5zM400 22.1v222.2zM20.3 274.7h262.9zM97.8 253.1v10.2zM113 253.1v10.2zM283.2 274.7h30.5z"/>
<path d="M313.7 274.7h86.3zM313.7 269.7v5zM313.7 264.6v5.1zM313.7 259.5v5.1zM400 268.4v6.3zM400 264.6v3.8zM400 259.5v5.1z"/>
</g>
<g fill="none" stroke="#000" stroke-width=".25">
<circle cx="100.3" cy="122.1" r=".99"/>
<circle cx="172.4" cy="136.3" r=".99"/>
<circle cx="172.4" cy="133.8" r=".99"/>
<circle cx="172.4" cy="138.9" r=".99"/>
<circle cx="155.2" cy="151.6" r=".99"/>
<circle cx="155.2" cy="149" r=".99"/>
<circle cx="172.4" cy="149" r=".99"/>
<circle cx="172.4" cy="151.6" r=".99"/>
<circle cx="172.4" cy="144" r=".99"/>
<circle cx="172.4" cy="141.4" r=".99"/>
<circle cx="172.4" cy="146.5" r=".99"/>
<circle cx="200.9" cy="156.7" r=".99"/>
<circle cx="200.9" cy="159.2" r=".99"/>
<circle cx="172.4" cy="194.8" r=".99"/>
<circle cx="172.4" cy="197.3" r=".99"/>
<circle cx="172.4" cy="192.2" r=".99"/>
<circle cx="172.4" cy="189.7" r=".99"/>
<circle cx="172.4" cy="199.8" r=".99"/>
<circle cx="155.2" cy="204.9" r=".99"/>
<circle cx="155.2" cy="207.4" r=".99"/>
<circle cx="172.4" cy="204.9" r=".99"/>
<circle cx="172.4" cy="202.4" r=".99"/>
<circle cx="172.4" cy="207.4" r=".99"/>
<circle cx="200.9" cy="212.5" r=".99"/>
<circle cx="200.9" cy="215" r=".99"/>
<circle cx="86.6" cy="258.2" r=".99"/>
<circle cx="86.6" cy="245.5" r=".99"/>
<circle cx="124.2" cy="258.2" r=".99"/>
<circle cx="124.2" cy="245.5" r=".99"/>
<circle cx="152.1" cy="245.5" r=".99"/>
</g>
<g fill="#000" stroke="#000" stroke-width=".42">
<path d="M227.3 119.8v8.9zM227.3 119.8h22.9zM250.2 119.8v8.9zM227.3 128.7h22.9zM227.3 175.7v8.9zM227.3 175.7h22.9zM250.2 175.7v8.9zM227.3 184.6h22.9zM341.6 222.7v10.1zM341.6 232.8v7.6zM341.6 232.8h55.9zM397.5 222.7v10.1z"/>
<path d="M341.6 222.7h55.9zM341.6 240.4h55.9zM397.5 232.8v7.6z"/>
</g>
<g fill="none" stroke="#000" stroke-width=".42">
<circle cx="229.8" cy="121.1" r=".25"/>
<circle cx="232.4" cy="121.1" r=".25"/>
<circle cx="234.9" cy="121.1" r=".25"/>
<circle cx="237.5" cy="121.1" r=".25"/>
<circle cx="240" cy="121.1" r=".25"/>
<circle cx="242.5" cy="121.1" r=".25"/>
<circle cx="245.1" cy="121.1" r=".25"/>
<circle cx="229.8" cy="177" r=".25"/>
<circle cx="232.4" cy="177" r=".25"/>
<circle cx="234.9" cy="177" r=".25"/>
<circle cx="237.5" cy="177" r=".25"/>
<circle cx="240" cy="177" r=".25"/>
<circle cx="242.5" cy="177" r=".25"/>
<circle cx="245.1" cy="177" r=".25"/>
</g>
<use href="#words"/>
</svg>
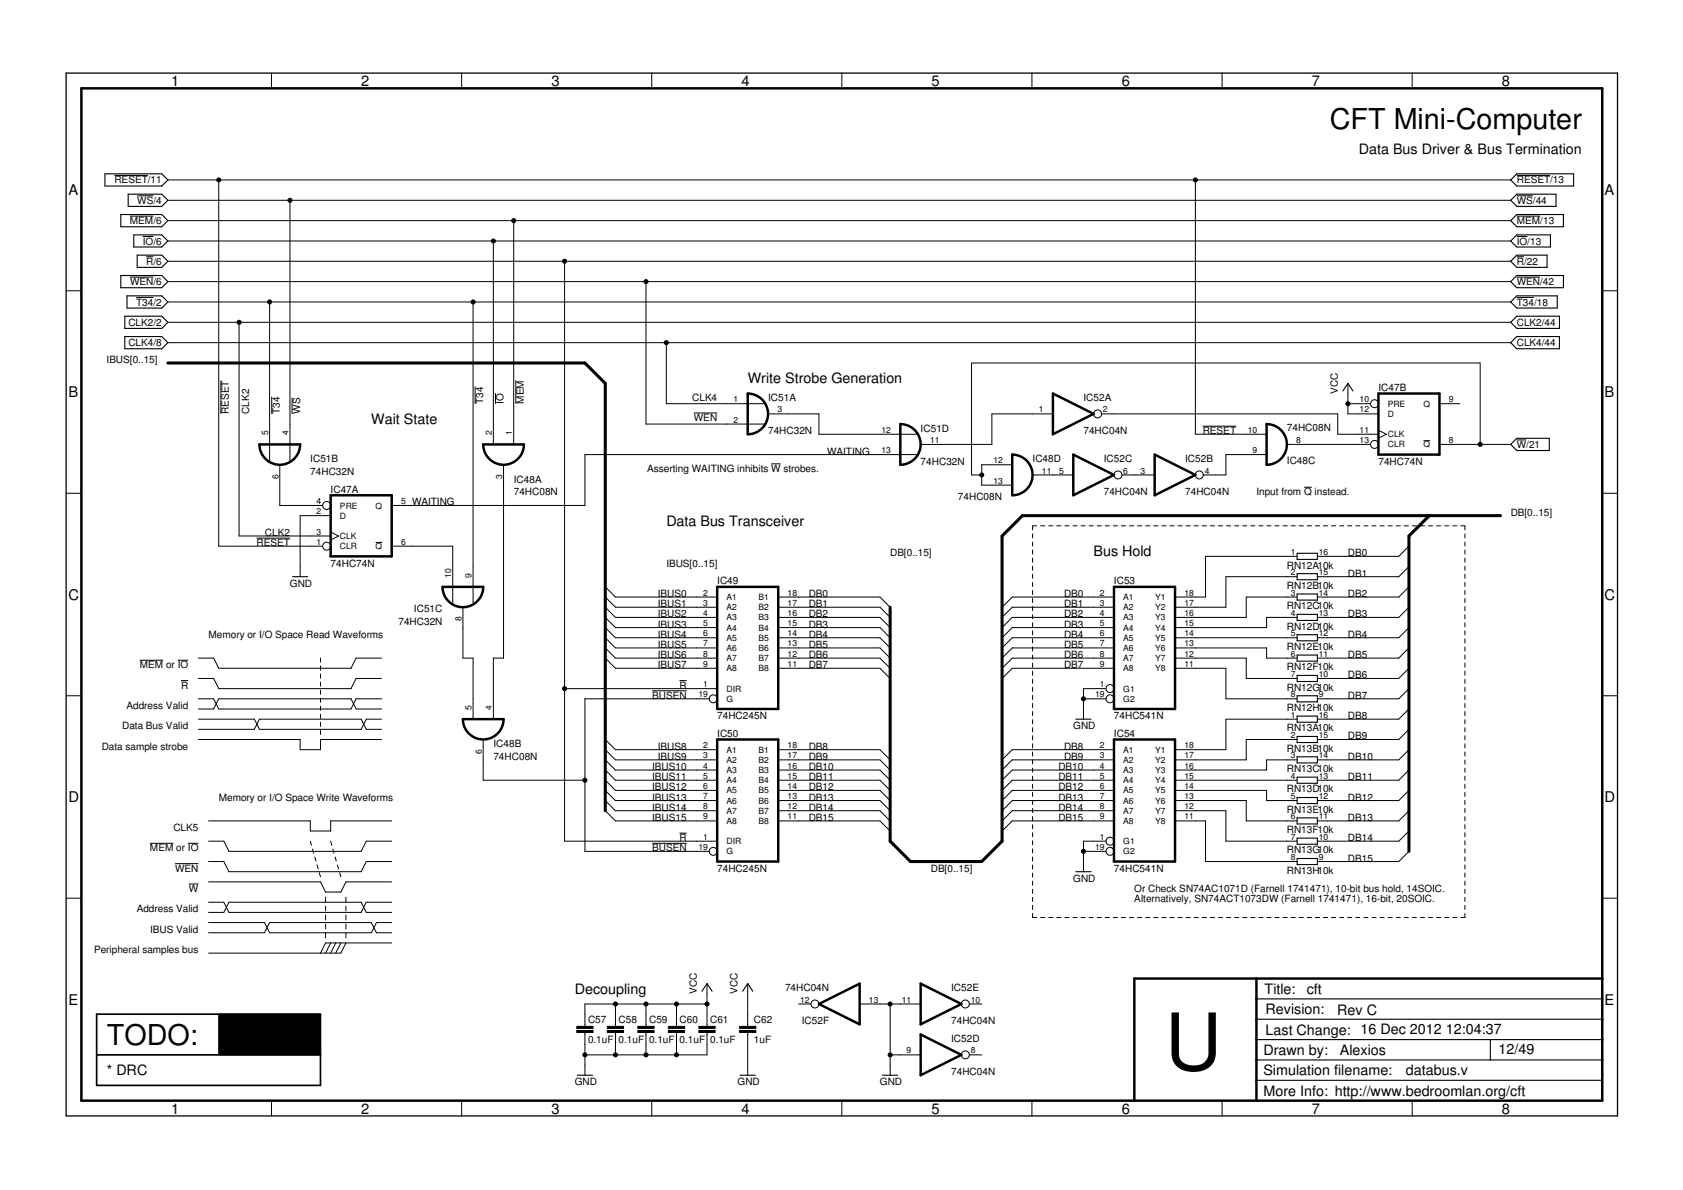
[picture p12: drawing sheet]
<svg xmlns="http://www.w3.org/2000/svg" width="420mm" height="297mm" viewBox="0 0 420 297" stroke-linecap="round" stroke-linejoin="round" font-family="sans-serif">
<defs><g id="words">
<text font-size="19.7" x="290.8" y="267.1">U</text>
<g font-size="7.2">
<text x="332" y="32.2">CFT Mini-Computer</text>
<text x="26.7" y="260.8">TODO:</text>
</g>
<g font-size="3.7">
<text x="42.7" y="21.5">1</text>
<text x="90.2" y="21.5">2</text>
<text x="137.7" y="21.5">3</text>
<text x="185.1" y="21.5">4</text>
<text x="232.6" y="21.5">5</text>
<text x="280" y="21.5">6</text>
<text x="327.5" y="21.5">7</text>
<text x="375" y="21.5">8</text>
<text x="17.1" y="48.6">A</text>
<text x="400.6" y="48.6">A</text>
<text x="17.1" y="99.2">B</text>
<text x="400.6" y="99.2">B</text>
<text x="17.1" y="149.7">C</text>
<text x="400.6" y="149.7">C</text>
<text x="17.1" y="200.2">D</text>
<text x="400.6" y="200.2">D</text>
<text x="17.1" y="250.8">E</text>
<text x="400.6" y="250.8">E</text>
<text x="42.7" y="277.9">1</text>
<text x="90.2" y="277.9">2</text>
<text x="137.7" y="277.9">3</text>
<text x="185.1" y="277.9">4</text>
<text x="232.6" y="277.9">5</text>
<text x="280" y="277.9">6</text>
<text x="327.5" y="277.9">7</text>
<text x="375" y="277.9">8</text>
</g>
<g font-size="3.6">
<text x="339.3" y="38.6">Data Bus Driver &amp; Bus Termination</text>
<text x="186.7" y="95.7">Write Strobe Generation</text>
<text x="92.7" y="105.9">Wait State</text>
<text x="166.4" y="131.3">Data Bus Transceiver</text>
<text x="273" y="138.9">Bus Hold</text>
<text x="143.5" y="248.1">Decoupling</text>
<text x="315.7" y="248.1">Title:</text>
<text x="326.2" y="248.2">cft</text>
<text x="315.9" y="253.2">Revision:</text>
<text x="333.8" y="253.3">Rev C</text>
<text x="315.4" y="263.3">Drawn by:</text>
<text x="315.9" y="258.2">Last Change: 16 Dec 2012</text>
<text x="334.5" y="263.3">Alexios</text>
<text x="361" y="258.1">12:04:37</text>
<text x="374.1" y="263.2">12/49</text>
<text x="26.7" y="268.4">* DRC</text>
<text x="315.4" y="268.4">Simulation filename:</text>
<text x="351" y="268.4">databus.v</text>
<text x="315.4" y="273.5">More Info: http://www.bedroomlan.org/cft</text>
</g>
<g font-size="2.5">
<text x="28.6" y="45.8">RESET/11</text>
<text x="378.7" y="45.8">RESET/13</text>
<text x="34.3" y="50.9">WS/4</text>
<text x="378.7" y="50.9">WS/44</text>
<text x="32.4" y="56">MEM/6</text>
<text x="378.7" y="56">MEM/13</text>
<text x="35.7" y="61">IO/6</text>
<text x="378.7" y="61">IO/13</text>
<text x="32.5" y="71.2">WEN/6</text>
<text x="36.5" y="66.1">R/6</text>
<text x="378.7" y="66.1">R/22</text>
<text x="378.7" y="71.2">WEN/42</text>
<text x="34" y="76.3">T34/2</text>
<text x="378.7" y="76.3">T34/18</text>
<text x="32" y="81.3">CLK2/2</text>
<text x="378.7" y="81.3">CLK2/44</text>
<text x="32" y="86.4">CLK4/8</text>
<text x="378.7" y="86.4">CLK4/44</text>
<text x="26.6" y="90.6">IBUS[0..15]</text>
<text x="120.6" y="100.8" transform="rotate(-90 120.6 100.8)">T34</text>
<text x="125.7" y="100.8" transform="rotate(-90 125.7 100.8)">IO</text>
<text x="130.8" y="100.8" transform="rotate(-90 130.8 100.8)">MEM</text>
<text x="172.8" y="100">CLK4</text>
<text x="191.7" y="100.1">IC51A</text>
<text x="270.5" y="100.1">IC52A</text>
<text x="334" y="98.2" transform="rotate(-90 334 98.2)">VCC</text>
<text x="344.1" y="97.6">IC47B</text>
<text x="57.1" y="103.3" transform="rotate(-90 57.1 103.3)">RESET</text>
<text x="62.2" y="103.3" transform="rotate(-90 62.2 103.3)">CLK2</text>
<text x="69.8" y="103.3" transform="rotate(-90 69.8 103.3)">T34</text>
<text x="74.9" y="103.3" transform="rotate(-90 74.9 103.3)">WS</text>
<text x="173.2" y="105.1">WEN</text>
<text x="229.8" y="107.8">IC51D</text>
<text x="321.3" y="107.6">74HC08N</text>
<text x="191.7" y="108.4">74HC32N</text>
<text x="206.5" y="113.5">WAITING</text>
<text x="270.5" y="108.4">74HC04N</text>
<text x="300.3" y="108.4">RESET</text>
<text x="378.7" y="111.8">W/21</text>
<text x="77.5" y="118.6">74HC32N</text>
<text x="77.5" y="115.4">IC51B</text>
<text x="161.6" y="117.8">Asserting WAITING inhibits W strobes.</text>
<text x="229.8" y="116">74HC32N</text>
<text x="257.8" y="115.4">IC48D</text>
<text x="275.6" y="115.4">IC52C</text>
<text x="295.9" y="115.4">IC52B</text>
<text x="321.3" y="115.9">IC48C</text>
<text x="344.1" y="116">74HC74N</text>
<text x="82.5" y="123">IC47A</text>
<text x="128.3" y="123.6">74HC08N</text>
<text x="128.3" y="120.5">IC48A</text>
<text x="239.2" y="124.9">74HC08N</text>
<text x="275.6" y="123.6">74HC04N</text>
<text x="295.9" y="123.6">74HC04N</text>
<text x="313.7" y="123.6">Input from Q instead.</text>
<text x="102.9" y="126.2">WAITING</text>
<text x="377.1" y="128.7">DB[0..15]</text>
<text x="64.1" y="136.3">RESET</text>
<text x="66.1" y="133.8">CLK2</text>
<text x="82.5" y="141.4">74HC74N</text>
<text x="166.4" y="141.4">IBUS[0..15]</text>
<text x="222.2" y="138.9">DB[0..15]</text>
<text x="321.3" y="141.9">RN12A10k</text>
<text x="336.5" y="138.9">DB0</text>
<text x="336.5" y="144">DB1</text>
<text x="72.4" y="146.5">GND</text>
<text x="164.2" y="149">IBUS0</text>
<text x="179.1" y="145.9">IC49</text>
<text x="201.9" y="149">DB0</text>
<text x="265.6" y="149">DB0</text>
<text x="278.1" y="145.9">IC53</text>
<text x="321.3" y="147">RN12B10k</text>
<text x="336.5" y="149">DB2</text>
<text x="99.5" y="155.9">74HC32N</text>
<text x="103.3" y="152.7">IC51C</text>
<text x="164.2" y="151.6">IBUS1</text>
<text x="164.2" y="154.1">IBUS2</text>
<text x="201.9" y="151.6">DB1</text>
<text x="201.9" y="154.1">DB2</text>
<text x="265.6" y="151.6">DB1</text>
<text x="265.6" y="154.1">DB2</text>
<text x="321.3" y="152.1">RN12C10k</text>
<text x="336.5" y="154.1">DB3</text>
<text x="52.1" y="159.2">Memory or I/O Space Read Waveforms</text>
<text x="164.2" y="156.6">IBUS3</text>
<text x="164.2" y="159.2">IBUS4</text>
<text x="164.2" y="161.7">IBUS5</text>
<text x="201.9" y="156.6">DB3</text>
<text x="201.9" y="159.2">DB4</text>
<text x="201.9" y="161.7">DB5</text>
<text x="265.6" y="156.6">DB3</text>
<text x="265.6" y="159.2">DB4</text>
<text x="265.6" y="161.7">DB5</text>
<text x="321.3" y="157.2">RN12D10k</text>
<text x="336.5" y="159.2">DB4</text>
<text x="34.9" y="166.8">MEM or IO</text>
<text x="164.2" y="164.3">IBUS6</text>
<text x="164.2" y="166.8">IBUS7</text>
<text x="201.9" y="164.3">DB6</text>
<text x="201.9" y="166.8">DB7</text>
<text x="265.6" y="164.3">DB6</text>
<text x="265.6" y="166.8">DB7</text>
<text x="321.3" y="162.2">RN12E10k</text>
<text x="321.3" y="167.3">RN12F10k</text>
<text x="336.5" y="164.3">DB5</text>
<text x="45.2" y="171.9">R</text>
<text x="169.6" y="171.9">R</text>
<text x="321.3" y="172.4">RN12G10k</text>
<text x="336.5" y="169.3">DB6</text>
<text x="31.6" y="177">Address Valid</text>
<text x="162.8" y="174.4">BUSEN</text>
<text x="179.1" y="179.5">74HC245N</text>
<text x="278.1" y="179.5">74HC541N</text>
<text x="321.3" y="177.5">RN12H10k</text>
<text x="336.5" y="179.5">DB8</text>
<text x="336.5" y="174.4">DB7</text>
<text x="30.5" y="182">Data Bus Valid</text>
<text x="179.1" y="183.9">IC50</text>
<text x="267.9" y="182">GND</text>
<text x="278.1" y="183.9">IC54</text>
<text x="321.3" y="182.6">RN13A10k</text>
<text x="336.5" y="184.6">DB9</text>
<text x="25.4" y="187.1">Data sample strobe</text>
<text x="123.2" y="189.7">74HC08N</text>
<text x="123.2" y="186.5">IC48B</text>
<text x="164.2" y="187.1">IBUS8</text>
<text x="164.2" y="189.7">IBUS9</text>
<text x="201.9" y="187.1">DB8</text>
<text x="201.9" y="189.7">DB9</text>
<text x="265.6" y="187.1">DB8</text>
<text x="265.6" y="189.7">DB9</text>
<text x="321.3" y="187.6">RN13B10k</text>
<text x="336.5" y="189.7">DB10</text>
<text x="162.8" y="192.2">IBUS10</text>
<text x="162.8" y="194.7">IBUS11</text>
<text x="162.8" y="197.3">IBUS12</text>
<text x="201.9" y="192.2">DB10</text>
<text x="201.9" y="194.7">DB11</text>
<text x="201.9" y="197.3">DB12</text>
<text x="264.2" y="192.2">DB10</text>
<text x="264.2" y="194.7">DB11</text>
<text x="264.2" y="197.3">DB12</text>
<text x="321.3" y="192.7">RN13C10k</text>
<text x="321.3" y="197.8">RN13D10k</text>
<text x="336.5" y="194.7">DB11</text>
<text x="54.6" y="199.8">Memory or I/O Space Write Waveforms</text>
<text x="162.8" y="199.8">IBUS13</text>
<text x="162.8" y="202.4">IBUS14</text>
<text x="201.9" y="199.8">DB13</text>
<text x="201.9" y="202.4">DB14</text>
<text x="264.2" y="199.8">DB13</text>
<text x="264.2" y="202.4">DB14</text>
<text x="321.3" y="202.9">RN13E10k</text>
<text x="336.5" y="199.8">DB12</text>
<text x="43.3" y="207.4">CLK5</text>
<text x="162.8" y="204.9">IBUS15</text>
<text x="169.6" y="210">R</text>
<text x="201.9" y="204.9">DB15</text>
<text x="264.2" y="204.9">DB15</text>
<text x="321.3" y="207.9">RN13F10k</text>
<text x="336.5" y="204.9">DB13</text>
<text x="336.5" y="210">DB14</text>
<text x="37.4" y="212.5">MEM or IO</text>
<text x="162.8" y="212.5">BUSEN</text>
<text x="321.3" y="213">RN13G10k</text>
<text x="336.5" y="215.1">DB15</text>
<text x="43.7" y="217.6">WEN</text>
<text x="179.1" y="217.6">74HC245N</text>
<text x="232.4" y="217.6">DB[0..15]</text>
<text x="267.9" y="220.1">GND</text>
<text x="278.1" y="217.6">74HC541N</text>
<text x="321.3" y="218.1">RN13H10k</text>
<text x="34.1" y="227.8">Address Valid</text>
<text x="47.2" y="222.7">W</text>
<text x="283.2" y="222.7">Or Check SN74AC1071D (Farnell 1741471), 10-bit bus hold, 14SOIC.</text>
<text x="283.2" y="225.2">Alternatively, SN74ACT1073DW (Farnell 1741471), 16-bit, 20SOIC.</text>
<text x="37.5" y="232.8">IBUS Valid</text>
<text x="23.5" y="237.9">Peripheral samples bus</text>
<text x="174" y="248.1" transform="rotate(-90 174 248.1)">VCC</text>
<text x="184.1" y="248.1" transform="rotate(-90 184.1 248.1)">VCC</text>
<text x="196" y="247.3">74HC04N</text>
<text x="237.5" y="247.4">IC52E</text>
<text x="146.8" y="255.3">C57</text>
<text x="154.4" y="255.3">C58</text>
<text x="162" y="255.3">C59</text>
<text x="169.7" y="255.3">C60</text>
<text x="177.3" y="255.3">C61</text>
<text x="188.2" y="255.3">C62</text>
<text x="200.2" y="255.6">IC52F</text>
<text x="237.5" y="255.7">74HC04N</text>
<text x="146.8" y="260.4">0.1uF</text>
<text x="154.4" y="260.4">0.1uF</text>
<text x="162" y="260.4">0.1uF</text>
<text x="169.7" y="260.4">0.1uF</text>
<text x="177.3" y="260.4">0.1uF</text>
<text x="188.2" y="260.4">1uF</text>
<text x="237.5" y="260.1">IC52D</text>
<text x="237.5" y="268.4">74HC04N</text>
<text x="143.5" y="270.9">GND</text>
<text x="184.1" y="270.9">GND</text>
<text x="219.7" y="270.9">GND</text>
</g>
<g font-size="2.1">
<text x="183.1" y="100.4">1</text>
<text x="339.4" y="100.4">10</text>
<text x="346.5" y="101.5">PRE</text>
<text x="355.4" y="101.5">Q</text>
<text x="361.7" y="100.4">9</text>
<text x="183.1" y="105.5">2</text>
<text x="194.1" y="103">3</text>
<text x="259.3" y="103">1</text>
<text x="275.4" y="103">2</text>
<text x="339.4" y="103">12</text>
<text x="346.5" y="104.1">D</text>
<text x="66.9" y="108.6" transform="rotate(-90 66.9 108.6)">5</text>
<text x="72" y="108.6" transform="rotate(-90 72 108.6)">4</text>
<text x="122.8" y="108.6" transform="rotate(-90 122.8 108.6)">2</text>
<text x="127.9" y="108.6" transform="rotate(-90 127.9 108.6)">1</text>
<text x="220.1" y="108">12</text>
<text x="220.1" y="113.1">13</text>
<text x="232.2" y="110.6">11</text>
<text x="311.5" y="108">10</text>
<text x="312.7" y="113.1">9</text>
<text x="323.6" y="110.6">8</text>
<text x="339.4" y="110.6">13</text>
<text x="339.4" y="108">11</text>
<text x="346.5" y="111.7">CLR</text>
<text x="346.5" y="109.2">CLK</text>
<text x="355.4" y="111.7">Q</text>
<text x="361.7" y="110.6">8</text>
<text x="69.5" y="119.5" transform="rotate(-90 69.5 119.5)">6</text>
<text x="125.4" y="119.5" transform="rotate(-90 125.4 119.5)">3</text>
<text x="248" y="115.7">12</text>
<text x="260.1" y="118.2">11</text>
<text x="264.4" y="118.2">5</text>
<text x="280.4" y="118.2">6</text>
<text x="284.7" y="118.2">3</text>
<text x="300.8" y="118.2">4</text>
<text x="79" y="125.8">4</text>
<text x="100.1" y="125.8">5</text>
<text x="248" y="120.7">13</text>
<text x="79" y="128.4">2</text>
<text x="84.9" y="129.5">D</text>
<text x="84.9" y="126.9">PRE</text>
<text x="93.8" y="126.9">Q</text>
<text x="79" y="136">1</text>
<text x="79" y="133.4">3</text>
<text x="84.9" y="137.1">CLR</text>
<text x="84.9" y="134.6">CLK</text>
<text x="93.8" y="137.1">Q</text>
<text x="100.1" y="136">6</text>
<text x="322.3" y="138.5">1</text>
<text x="322.3" y="143.6">2</text>
<text x="329.2" y="138.5">16</text>
<text x="329.2" y="143.6">15</text>
<text x="112.7" y="144.2" transform="rotate(-90 112.7 144.2)">10</text>
<text x="117.7" y="144.2" transform="rotate(-90 117.7 144.2)">9</text>
<text x="175.5" y="148.7">2</text>
<text x="181.4" y="149.8">A1</text>
<text x="189.3" y="149.8">B1</text>
<text x="196.6" y="148.7">18</text>
<text x="274.6" y="148.7">2</text>
<text x="280.4" y="149.8">A1</text>
<text x="288.4" y="149.8">Y1</text>
<text x="295.7" y="148.7">18</text>
<text x="322.3" y="148.7">3</text>
<text x="329.2" y="148.7">14</text>
<text x="115.2" y="155.1" transform="rotate(-90 115.2 155.1)">8</text>
<text x="175.5" y="151.2">3</text>
<text x="175.5" y="153.8">4</text>
<text x="181.4" y="152.3">A2</text>
<text x="181.4" y="154.9">A3</text>
<text x="189.3" y="154.9">B3</text>
<text x="189.3" y="152.3">B2</text>
<text x="196.6" y="153.8">16</text>
<text x="196.6" y="151.2">17</text>
<text x="274.6" y="151.2">3</text>
<text x="274.6" y="153.8">4</text>
<text x="280.4" y="152.3">A2</text>
<text x="280.4" y="154.9">A3</text>
<text x="288.4" y="154.9">Y3</text>
<text x="288.4" y="152.3">Y2</text>
<text x="295.7" y="153.8">16</text>
<text x="295.7" y="151.2">17</text>
<text x="322.3" y="153.8">4</text>
<text x="329.2" y="153.8">13</text>
<text x="175.5" y="156.3">5</text>
<text x="175.5" y="158.8">6</text>
<text x="175.5" y="161.4">7</text>
<text x="181.4" y="157.4">A4</text>
<text x="181.4" y="159.9">A5</text>
<text x="189.3" y="160">B5</text>
<text x="189.3" y="157.4">B4</text>
<text x="196.6" y="161.4">13</text>
<text x="196.6" y="158.8">14</text>
<text x="196.6" y="156.3">15</text>
<text x="274.6" y="156.3">5</text>
<text x="274.6" y="158.8">6</text>
<text x="274.6" y="161.4">7</text>
<text x="280.4" y="157.4">A4</text>
<text x="280.4" y="159.9">A5</text>
<text x="288.4" y="160">Y5</text>
<text x="288.4" y="157.4">Y4</text>
<text x="295.7" y="161.4">13</text>
<text x="295.7" y="158.8">14</text>
<text x="295.7" y="156.3">15</text>
<text x="322.3" y="158.8">5</text>
<text x="329.2" y="158.8">12</text>
<text x="175.5" y="163.9">8</text>
<text x="175.5" y="166.5">9</text>
<text x="181.4" y="162.5">A6</text>
<text x="181.4" y="165">A7</text>
<text x="181.4" y="167.6">A8</text>
<text x="189.3" y="167.6">B8</text>
<text x="189.3" y="165">B7</text>
<text x="189.3" y="162.5">B6</text>
<text x="196.6" y="166.5">11</text>
<text x="196.6" y="163.9">12</text>
<text x="274.6" y="163.9">8</text>
<text x="274.6" y="166.5">9</text>
<text x="280.4" y="162.5">A6</text>
<text x="280.4" y="165">A7</text>
<text x="280.4" y="167.6">A8</text>
<text x="288.4" y="167.6">Y8</text>
<text x="288.4" y="165">Y7</text>
<text x="288.4" y="162.5">Y6</text>
<text x="295.7" y="166.5">11</text>
<text x="295.7" y="163.9">12</text>
<text x="322.3" y="163.9">6</text>
<text x="329.2" y="163.9">11</text>
<text x="175.5" y="171.5">1</text>
<text x="181.4" y="172.6">DIR</text>
<text x="274.6" y="171.5">1</text>
<text x="280.4" y="172.6">G1</text>
<text x="322.3" y="169">7</text>
<text x="329.2" y="169">10</text>
<text x="117.7" y="177.2" transform="rotate(-90 117.7 177.2)">5</text>
<text x="122.8" y="177.2" transform="rotate(-90 122.8 177.2)">4</text>
<text x="174.3" y="174.1">19</text>
<text x="181.4" y="175.2">G</text>
<text x="273.4" y="174.1">19</text>
<text x="280.4" y="175.2">G2</text>
<text x="322.3" y="174.1">8</text>
<text x="322.3" y="179.1">1</text>
<text x="329.2" y="174.1">9</text>
<text x="329.2" y="179.1">16</text>
<text x="322.3" y="184.2">2</text>
<text x="329.2" y="184.2">15</text>
<text x="120.3" y="188.1" transform="rotate(-90 120.3 188.1)">6</text>
<text x="175.5" y="186.8">2</text>
<text x="175.5" y="189.3">3</text>
<text x="175.5" y="191.8">4</text>
<text x="181.4" y="187.9">A1</text>
<text x="181.4" y="190.4">A2</text>
<text x="189.3" y="190.4">B2</text>
<text x="189.3" y="187.9">B1</text>
<text x="196.6" y="191.8">16</text>
<text x="196.6" y="189.3">17</text>
<text x="196.6" y="186.8">18</text>
<text x="274.6" y="186.8">2</text>
<text x="274.6" y="189.3">3</text>
<text x="274.6" y="191.8">4</text>
<text x="280.4" y="187.9">A1</text>
<text x="280.4" y="190.4">A2</text>
<text x="288.4" y="190.4">Y2</text>
<text x="288.4" y="187.9">Y1</text>
<text x="295.7" y="191.8">16</text>
<text x="295.7" y="189.3">17</text>
<text x="295.7" y="186.8">18</text>
<text x="322.3" y="189.3">3</text>
<text x="329.2" y="189.3">14</text>
<text x="175.5" y="194.4">5</text>
<text x="175.5" y="196.9">6</text>
<text x="181.4" y="193">A3</text>
<text x="181.4" y="195.5">A4</text>
<text x="189.3" y="195.5">B4</text>
<text x="189.3" y="193">B3</text>
<text x="196.6" y="196.9">14</text>
<text x="196.6" y="194.4">15</text>
<text x="274.6" y="194.4">5</text>
<text x="274.6" y="196.9">6</text>
<text x="280.4" y="193">A3</text>
<text x="280.4" y="195.5">A4</text>
<text x="288.4" y="195.5">Y4</text>
<text x="288.4" y="193">Y3</text>
<text x="295.7" y="196.9">14</text>
<text x="295.7" y="194.4">15</text>
<text x="322.3" y="194.4">4</text>
<text x="329.2" y="194.4">13</text>
<text x="175.5" y="199.5">7</text>
<text x="175.5" y="202">8</text>
<text x="181.4" y="198">A5</text>
<text x="181.4" y="200.6">A6</text>
<text x="181.4" y="203.1">A7</text>
<text x="189.3" y="203.1">B7</text>
<text x="189.3" y="200.6">B6</text>
<text x="189.3" y="198">B5</text>
<text x="196.6" y="202">12</text>
<text x="196.6" y="199.5">13</text>
<text x="274.6" y="199.5">7</text>
<text x="274.6" y="202">8</text>
<text x="280.4" y="198">A5</text>
<text x="280.4" y="200.6">A6</text>
<text x="280.4" y="203.1">A7</text>
<text x="288.4" y="203.1">Y7</text>
<text x="288.4" y="200.6">Y6</text>
<text x="288.4" y="198">Y5</text>
<text x="295.7" y="202">12</text>
<text x="295.7" y="199.5">13</text>
<text x="322.3" y="199.5">5</text>
<text x="329.2" y="199.5">12</text>
<text x="175.5" y="209.6">1</text>
<text x="175.5" y="204.5">9</text>
<text x="181.4" y="205.7">A8</text>
<text x="189.3" y="205.7">B8</text>
<text x="196.6" y="204.5">11</text>
<text x="274.6" y="209.6">1</text>
<text x="274.6" y="204.5">9</text>
<text x="280.4" y="205.7">A8</text>
<text x="288.4" y="205.7">Y8</text>
<text x="295.7" y="204.5">11</text>
<text x="322.3" y="204.5">6</text>
<text x="322.3" y="209.6">7</text>
<text x="329.2" y="204.5">11</text>
<text x="329.2" y="209.6">10</text>
<text x="174.3" y="212.2">19</text>
<text x="181.4" y="210.7">DIR</text>
<text x="181.4" y="213.3">G</text>
<text x="273.4" y="212.2">19</text>
<text x="280.4" y="210.7">G1</text>
<text x="280.4" y="213.3">G2</text>
<text x="322.3" y="214.7">8</text>
<text x="329.2" y="214.7">9</text>
<text x="199.7" y="250.3">12</text>
<text x="216.9" y="250.3">13</text>
<text x="225.1" y="250.3">11</text>
<text x="242.3" y="250.3">10</text>
<text x="226.3" y="263">9</text>
<text x="242.3" y="263">8</text>
</g>
</g></defs>
<g fill="#000" stroke="#000" stroke-width=".25">
<path d="M67.8 18.2v3.9zM115.3 18.2v3.9zM162.7 18.2v3.9zM210.2 18.2v3.9zM257.6 18.2v3.9zM305.1 18.2v3.9zM352.5 18.2v3.9zM20.3 22.1v252.6zM20.3 22.1h379.7zM28.6 43.8h8.3zM32.4 54h5.9zM34.3 48.9h4z"/>
<path d="M35.7 59h2.6zM41.9 55.1h86.3zM41.9 44.9h12.7zM41.9 50h30.5zM54.6 44.9h243.8zM72.4 50h304.7zM128.2 55.1v50.8zM128.2 55.1h248.9zM298.4 44.9h78.7zM378.7 59h2.6zM378.7 54h5.8zM378.7 43.8h8.3z"/>
<path d="M378.7 48.9h4zM16.5 72.6h3.8zM32.5 69.2h5.8zM34 74.3h4.3zM36.5 64.1h1.8zM41.9 65.2h99zM41.9 60.2h81.3zM41.9 75.4h25.4zM67.3 75.4h50.8zM118.1 75.4h259zM123.2 60.2v45.7zM123.2 60.2h253.9z"/>
<path d="M140.9 65.2h236.2zM140.9 65.2v106.7zM41.9 70.3h119.4zM161.3 70.3h215.8zM378.7 64.1h1.8zM378.7 69.2h5.8zM378.7 74.3h4.3zM400 72.6h3.8zM41.9 80.5h17.8zM59.7 80.5h317.4zM41.9 85.5h124.4zM166.3 85.5v15.3z"/>
<path d="M166.3 85.5h210.8zM242.5 90.6v28zM336.5 95.7v2.5zM336.5 98.2v2.6zM242.5 90.6h127zM55.1 95v8.3zM67.3 105.9v5zM67.3 110.9v4.4zM67.3 75.4v30.5zM67.8 99v4.3zM72.4 105.9v5zM72.4 110.9v4.4z"/>
<path d="M72.4 50v55.9zM72.9 99.3v4zM118.6 96.5v4.3zM123.2 105.9v5zM123.7 98.1v2.7zM128.2 105.9v5zM128.8 94.9v5.9zM146 113.5h73.7zM161.3 70.3v35.6zM166.3 100.8h15.3zM173.2 103.1h5.8zM181.6 100.8h5.1z"/>
<path d="M181.6 105.9h5.1zM161.3 105.9h20.3zM186.7 100.8h4.3zM186.7 105.9h4.3zM192.5 115.8h2.4zM191.7 103.3h5.1zM196.8 103.3h7.6zM204.4 103.3v5.1zM204.4 108.4h15.3zM219.7 108.4h5.1zM219.7 113.5h5.1zM224.8 108.4h4.3z"/>
<path d="M224.8 113.5h4.3zM229.8 110.9h5.1zM245.1 116v2.6zM245.1 118.6v2.5zM242.5 118.6h2.6zM247.6 116h5.1zM245.1 116h2.5zM247.6 103.3v7.6zM234.9 110.9h12.7zM257.8 103.3h5.1zM247.6 103.3h10.2zM257.8 118.6h5.1z"/>
<path d="M262.9 118.6h5zM275 103.3h3.1zM283.2 118.6h5.1zM280.1 118.6h3.1zM298.4 44.9v63.5zM300.3 106.4h8.3zM300.4 118.6h3.1zM303.5 118.6h2.5zM306 113.5v5.1zM306 113.5h5.1zM311.1 113.5h5.1zM311.1 108.4h5.1z"/>
<path d="M298.4 108.4h12.7zM321.3 110.9h5.1zM326.4 110.9h12.6zM334 103.3v5.1zM278.1 103.3h55.9zM336.5 100.8v2.5zM336.5 103.3h2.5zM339 110.9h3.2zM339 103.3h5.1zM339 108.4h5.1zM339 100.8h3.2zM336.5 100.8h2.5z"/>
<path d="M334 108.4h5zM344.1 107.4l2 1zM344.1 109.4l2-1zM355.4 110h1.6zM359.4 100.8h5zM359.4 110.9h5zM364.4 110.9h5.1zM369.5 90.6v20.3zM369.5 110.9h7.6zM378.7 109.8h2.3zM16.5 123.1h3.8zM54.6 44.9v91.4z"/>
<path d="M59.7 80.5v53.3zM59.7 133.8h17.8zM64.1 134.3h8.3zM69.8 116v5.1zM69.8 121.1v5.1zM74.9 128.7v12.7zM77.5 136.3h3.1zM77.5 128.7h5zM77.5 133.8h5zM77.5 126.2h3.1zM74.9 128.7h2.6zM54.6 136.3h22.9z"/>
<path d="M69.8 126.2h7.7zM82.5 132.8l2 1zM82.5 134.8l2-1zM93.8 135.4h1.6zM97.8 126.2h5.1zM97.8 136.3h5.1zM102.9 126.2h43.1zM102.9 136.3h10.1zM113 136.3v5.1zM125.7 116v5.1zM125.7 121.1v43.2zM146 113.5v12.7z"/>
<path d="M245.1 121.1h2.5zM247.6 121.1h5.1zM257.8 137.3v1zM257.8 135.3v1zM257.8 133.3v1zM257.8 131.3v1zM257.8 131.3h1zM259.8 131.3h1zM261.8 131.3h1zM263.8 131.3h1.1zM265.8 131.3h1.1zM267.9 131.3h1z"/>
<path d="M269.9 131.3h1zM271.9 131.3h1zM273.9 131.3h1.1zM275.9 131.3h1.1zM278 131.3h1zM280 131.3h1zM282 131.3h1zM284 131.3h1zM286 131.3h1zM288.1 131.3h1zM290.1 131.3h1zM292.1 131.3h1z"/>
<path d="M294.1 131.3h1zM296.1 131.3h1zM298.1 131.3h1zM301 138.9h20.3zM300.1 131.3h1.1zM302.2 131.3h1zM304.2 131.3h1zM306.2 131.3h1zM308.2 131.3h1zM310.2 131.3h1.1zM312.2 131.3h1.1zM314.3 131.3h1z"/>
<path d="M316.3 131.3h1zM318.3 131.3h1zM321.3 138.9h2.5zM320.3 131.3h1zM322.3 131.3h1.1zM324.4 131.3h1zM325.6 121.6h1.9zM326.4 131.3h1zM328.4 131.3h1zM330.4 131.3h1zM328.9 138.9h2.5zM331.4 138.9h17.8z"/>
<path d="M332.4 131.3h1zM334.4 131.3h1.1zM336.5 131.3h1zM338.5 131.3h1zM340.5 131.3h1zM342.5 131.3h1zM344.5 131.3h1zM346.5 131.3h1.1zM349.2 138.9l2.5-2.6zM348.6 131.3h1zM350.6 131.3h1zM352.6 131.3h1z"/>
<path d="M354.6 131.3h1zM356.6 131.3h1zM358.6 131.3h1.1zM360.7 131.3h1zM362.7 131.3h1zM365.7 137.3v1zM365.7 135.3v1zM365.7 133.3v1zM365.7 131.3v1zM364.7 131.3h1zM400 123.1h3.8zM74.9 141.4v2.6z"/>
<path d="M113 141.4v5.1zM113 146.5v4.3zM115.6 151.6v5.1zM115.6 156.7v7.6zM118.1 141.4v5.1zM118.1 146.5v4.3zM118.1 75.4v66zM151.1 156.7l2.5 2.5zM151.1 159.2l2.5 2.5zM153.6 149h20.4zM151.1 146.5l2.5 2.5zM153.6 151.6h20.4z"/>
<path d="M151.1 149l2.5 2.6zM153.6 154.1h20.4zM151.1 151.6l2.5 2.5zM153.6 156.7h20.4zM151.1 154.1l2.5 2.6zM153.6 159.2h20.4zM174 149h5zM174 151.6h5zM174 154.1h5zM174 156.7h5zM174 159.2h5zM194.3 159.2h5.1z"/>
<path d="M194.3 156.7h5.1zM194.3 154.1h5.1zM194.3 151.6h5.1zM194.3 149h5.1zM199.4 149h20.3zM199.4 151.6h20.3zM199.4 154.1h20.3zM199.4 156.7h20.3zM199.4 159.2h20.3zM219.7 149l2.5 2.6zM219.7 151.6l2.5 2.5zM219.7 154.1l2.5 2.6z"/>
<path d="M219.7 156.7l2.5 2.5zM219.7 159.2l2.5 2.5zM252.7 149l-2.5 2.6zM252.7 151.6l-2.5 2.5zM252.7 154.1l-2.5 2.6zM252.7 156.7l-2.5 2.5zM252.7 159.2l-2.5 2.5zM257.8 157.5v1zM257.8 155.4v1.1zM257.8 153.4v1.1zM257.8 151.4v1zM257.8 149.4v1z"/>
<path d="M257.8 147.4v1zM257.8 145.4v1zM257.8 143.3v1.1zM257.8 141.3v1zM257.8 139.3v1zM273 149h5.1zM273 151.6h5.1zM273 154.1h5.1zM273 156.7h5.1zM273 159.2h5.1zM252.7 149h20.3zM252.7 151.6h20.3z"/>
<path d="M252.7 154.1h20.3zM252.7 156.7h20.3zM252.7 159.2h20.3zM293.3 159.2h5.1zM293.3 156.7h5.1zM293.3 154.1h5.1zM293.3 151.6h5.1zM293.3 149h5.1zM298.4 156.7h17.8zM298.4 159.2h22.9zM298.4 154.1h12.7zM298.4 151.6h7.6z"/>
<path d="M298.4 149h2.6zM301 138.9v10.1zM306 144v7.6zM306 144h15.3zM311.1 149v5.1zM311.1 149h10.2zM316.2 154.1v2.6zM316.2 154.1h5.1zM321.3 144h2.5zM321.3 149h2.5zM321.3 154.1h2.5zM321.3 159.2h2.5z"/>
<path d="M328.9 144h2.5zM328.9 149h2.5zM328.9 154.1h2.5zM328.9 159.2h2.5zM331.4 144h17.8zM331.4 149h17.8zM331.4 154.1h17.8zM331.4 159.2h17.8zM349.2 144l2.5-2.6zM351.7 146.5l-2.5 2.5zM349.2 154.1l2.5-2.5zM349.2 159.2l2.5-2.5z"/>
<path d="M365.7 157.5v1zM365.7 155.4v1.1zM365.7 153.4v1.1zM365.7 151.4v1zM365.7 149.4v1zM365.7 147.4v1zM365.7 145.4v1zM365.7 143.3v1.1zM365.7 141.3v1zM365.7 139.3v1zM16.5 173.7h3.8zM34.9 164.8h5.9z"/>
<path d="M44.4 164.8h2.6zM45.2 169.9h1.8zM49.5 164.3h3.8zM49.5 169.4h3.8zM49.5 174.4h3.8zM49.5 179.5h14zM53.3 164.3l1.3 2.5zM53.3 169.4l1.3 2.5zM53.3 174.4l1.3 2.6zM49.5 177h3.8zM54.6 166.8h33zM54.6 171.9h33z"/>
<path d="M54.6 177h33zM54.6 174.4l-1.3 2.6zM63.5 179.5l1.3 2.6zM64.8 179.5l-1.3 2.6zM80 178.3v1zM80 176.3v1zM80 174.3v1zM80 172.3v1zM80 170.3v1zM80 168.3v1zM80 166.3v1zM80 164.3v1z"/>
<path d="M88.9 164.3l-1.3 2.5zM88.9 169.4l-1.3 2.5zM88.9 174.4l-1.3 2.6zM54.6 174.4h33zM88.9 164.3h6.3zM88.9 169.4h6.3zM88.9 174.4h6.3zM87.6 174.4l1.3 2.6zM64.8 179.5h25.4zM91.4 179.5h3.8zM88.9 177h6.3zM115.6 164.3h2.5z"/>
<path d="M118.1 174.4v5.1zM118.1 164.3v10.1zM123.2 174.4v5.1zM123.2 164.3v10.1zM123.2 164.3h2.5zM140.9 171.9v38.1zM140.9 171.9h33.1zM146 174.4v20.4zM151.1 161.7l2.5 2.6zM151.1 164.3l2.5 2.5zM153.6 161.7h20.4zM153.6 164.3h20.4z"/>
<path d="M153.6 166.8h20.4zM162.8 172.4h8.6zM169.6 169.9h1.8zM174 171.9h5zM174 161.7h5zM174 164.3h5zM174 166.8h5zM174 174.4h3.1zM146 174.4h28zM194.3 166.8h5.1zM194.3 164.3h5.1zM194.3 161.7h5.1z"/>
<path d="M199.4 161.7h20.3zM199.4 164.3h20.3zM199.4 166.8h20.3zM219.7 161.7l2.5 2.6zM219.7 164.3l2.5 2.5zM219.7 166.8l2.5 2.6zM252.7 161.7l-2.5 2.6zM252.7 164.3l-2.5 2.5zM252.7 166.8l-2.5 2.6zM257.8 177.6v1zM257.8 175.6v1zM257.8 173.6v1z"/>
<path d="M257.8 171.6v1zM257.8 169.6v1zM257.8 167.5v1zM257.8 165.5v1zM257.8 163.5v1zM257.8 161.5v1zM257.8 159.5v1zM270.5 177v2.5zM270.5 171.9v2.5zM270.5 174.4v2.6zM273 171.9h3.1zM273 161.7h5.1z"/>
<path d="M273 164.3h5.1zM273 166.8h5.1zM273 174.4h3.1zM270.5 171.9h2.5zM270.5 174.4h2.5zM252.7 161.7h20.3zM252.7 164.3h20.3zM252.7 166.8h20.3zM293.3 166.8h5.1zM293.3 164.3h5.1zM293.3 161.7h5.1zM298.4 161.7h17.8z"/>
<path d="M298.4 164.3h12.7zM298.4 166.8h7.6zM306 166.8v7.6zM306 174.4h15.3zM306 179.5h15.3zM311.1 164.3v5.1zM311.1 169.4h10.2zM316.2 161.7v2.6zM316.2 164.3h5.1zM321.3 164.3h2.5zM321.3 169.4h2.5zM321.3 174.4h2.5z"/>
<path d="M321.3 179.5h2.5zM328.9 164.3h2.5zM328.9 169.4h2.5zM328.9 174.4h2.5zM328.9 179.5h2.5zM331.4 164.3h17.8zM331.4 169.4h17.8zM331.4 179.5h17.8zM331.4 174.4h17.8zM351.7 161.7l-2.5 2.6zM349.2 169.4l2.5-2.6zM349.2 179.5l2.5-2.5z"/>
<path d="M349.2 174.4l2.5-2.5zM365.7 177.6v1zM365.7 175.6v1zM365.7 173.6v1zM365.7 171.6v1zM365.7 169.6v1zM365.7 167.5v1zM365.7 165.5v1zM365.7 163.5v1zM365.7 161.5v1zM365.7 159.5v1zM400 173.7h3.8z"/>
<path d="M49.5 184.6h25.4zM49.5 182.1h14zM64.8 182.1h25.4zM74.9 187.1h5.1zM74.9 184.6v2.5zM80 184.6v2.5zM80 184.6h15.2zM80 182.3v1zM80 180.3v1zM91.4 179.5l-1.2 2.6zM90.2 179.5l1.2 2.6zM91.4 182.1h3.8z"/>
<path d="M120.6 184.6v5.1zM120.6 189.7v5.1zM120.6 194.8h25.4zM146 194.8v17.7zM151.1 184.6l2.5 2.5zM151.1 187.1l2.5 2.6zM151.1 189.7l2.5 2.5zM151.1 192.2l2.5 2.6zM151.1 194.8l2.5 2.5zM151.1 197.3l2.5 2.5zM151.1 199.8l2.5 2.6zM153.6 187.1h20.4z"/>
<path d="M153.6 189.7h20.4zM153.6 192.2h20.4zM153.6 194.8h20.4zM153.6 197.3h20.4zM153.6 199.8h20.4zM174 187.1h5zM174 189.7h5zM174 192.2h5zM174 194.8h5zM174 197.3h5zM174 199.8h5zM194.3 199.8h5.1z"/>
<path d="M194.3 197.3h5.1zM194.3 194.8h5.1zM194.3 192.2h5.1zM194.3 189.7h5.1zM194.3 187.1h5.1zM199.4 187.1h20.3zM199.4 189.7h20.3zM199.4 192.2h20.3zM199.4 194.8h20.3zM199.4 197.3h20.3zM199.4 199.8h20.3zM219.7 187.1l2.5 2.6z"/>
<path d="M219.7 189.7l2.5 2.5zM219.7 192.2l2.5 2.6zM219.7 194.8l2.5 2.5zM219.7 197.3l2.5 2.5zM219.7 199.8l2.5 2.6zM252.7 187.1l-2.5 2.6zM252.7 189.7l-2.5 2.5zM252.7 192.2l-2.5 2.6zM252.7 194.8l-2.5 2.5zM252.7 197.3l-2.5 2.5zM252.7 199.8l-2.5 2.6zM257.8 197.8v1z"/>
<path d="M257.8 195.8v1zM257.8 193.7v1.1zM257.8 191.7v1zM257.8 189.7v1zM257.8 187.7v1zM257.8 185.7v1zM257.8 183.7v1zM257.8 181.6v1.1zM257.8 179.6v1.1zM273 187.1h5.1zM273 189.7h5.1zM273 192.2h5.1z"/>
<path d="M273 194.8h5.1zM273 197.3h5.1zM273 199.8h5.1zM252.7 187.1h20.3zM252.7 189.7h20.3zM252.7 192.2h20.3zM252.7 194.8h20.3zM252.7 197.3h20.3zM252.7 199.8h20.3zM293.3 199.8h5.1zM293.3 197.3h5.1zM293.3 194.8h5.1z"/>
<path d="M293.3 192.2h5.1zM293.3 189.7h5.1zM293.3 187.1h5.1zM298.4 194.8h22.9zM298.4 192.2h17.8zM298.4 189.7h12.7zM298.4 187.1h7.6zM298.4 197.3h17.8zM298.4 199.8h12.7zM306 179.5v7.6zM311.1 184.6v5.1zM311.1 184.6h10.2z"/>
<path d="M311.1 199.8v5.1zM316.2 189.7v2.5zM316.2 189.7h5.1zM316.2 197.3v2.5zM316.2 199.8h5.1zM321.3 184.6h2.5zM321.3 189.7h2.5zM321.3 194.8h2.5zM321.3 199.8h2.5zM328.9 184.6h2.5zM328.9 189.7h2.5zM328.9 194.8h2.5z"/>
<path d="M328.9 199.8h2.5zM331.4 184.6h17.8zM331.4 189.7h17.8zM331.4 194.8h17.8zM331.4 199.8h17.8zM349.2 184.6l2.5-2.5zM349.2 189.7l2.5-2.6zM349.2 194.8l2.5-2.6zM349.2 199.8l2.5-2.5zM365.7 197.8v1zM365.7 195.8v1zM365.7 193.7v1.1z"/>
<path d="M365.7 191.7v1zM365.7 189.7v1zM365.7 187.7v1zM365.7 185.7v1zM365.7 183.7v1zM365.7 181.6v1.1zM365.7 179.6v1.1zM37.4 210.5h5.9zM43.7 215.6h5.8zM46.9 210.5h2.6zM52.1 210h3.8zM52.1 215h3.8z"/>
<path d="M52.1 204.9h25.4zM55.9 210l1.2 2.5zM55.9 215l1.2 2.6zM57.1 212.5h33.1zM57.1 217.6h33.1zM77.5 207.4h5zM77.5 204.9v2.5zM77.5 210l.2 1zM78 212l.3 1zM78.6 213.9l.3 1zM79.1 215.9l.3 1zM79.7 217.9l.3 1z"/>
<path d="M82.5 204.9v2.5zM82.5 204.9h15.3zM82.5 210l.3 1zM83.1 212l.3 1zM83.7 213.9l.2 1zM84.2 215.9l.3 1zM84.8 217.9l.3 1zM91.4 210l-1.2 2.5zM91.4 215l-1.2 2.6zM91.4 210h6.4zM91.4 215h6.4zM140.9 210h33.1z"/>
<path d="M146 212.5h28zM151.1 202.4l2.5 2.5zM153.6 202.4h20.4zM153.6 204.9h20.4zM162.8 210.5h8.6zM169.6 208h1.8zM174 210h5zM174 202.4h5zM174 204.9h5zM174 212.5h3.1zM194.3 204.9h5.1zM194.3 202.4h5.1z"/>
<path d="M199.4 202.4h20.3zM199.4 204.9h20.3zM219.7 202.4l2.5 2.5zM219.7 204.9l2.5 2.5zM252.7 202.4l-2.5 2.5zM250.2 207.4l2.5-2.5zM257.8 217.9v1zM257.8 215.9v1zM257.8 213.9v1zM257.8 211.9v1zM257.8 209.9v1zM257.8 207.9v1z"/>
<path d="M257.8 205.8v1.1zM257.8 203.8v1zM257.8 201.8v1zM257.8 199.8v1zM270.5 215v2.6zM270.5 210v2.5zM270.5 212.5v2.5zM273 210h3.1zM273 202.4h5.1zM273 204.9h5.1zM273 212.5h3.1zM270.5 210h2.5z"/>
<path d="M270.5 212.5h2.5zM252.7 202.4h20.3zM252.7 204.9h20.3zM293.3 204.9h5.1zM293.3 202.4h5.1zM298.4 202.4h7.6zM298.4 204.9h2.6zM301 204.9v10.1zM301 215h20.3zM306 202.4v7.6zM306 210h15.3zM311.1 204.9h10.2z"/>
<path d="M321.3 204.9h2.5zM321.3 210h2.5zM321.3 215h2.5zM328.9 204.9h2.5zM328.9 210h2.5zM328.9 215h2.5zM331.4 204.9h17.8zM331.4 210h17.8zM331.4 215h17.8zM349.2 204.9l2.5-2.5zM349.2 210l2.5-2.6zM349.2 215l2.5-2.5z"/>
<path d="M365.7 217.9v1zM365.7 215.9v1zM365.7 213.9v1zM365.7 211.9v1zM365.7 209.9v1zM365.7 207.9v1zM365.7 205.8v1.1zM365.7 203.8v1zM365.7 201.8v1zM365.7 199.8v1zM16.5 224.2h3.8zM47.2 220.7h2.3z"/>
<path d="M52.1 220.1h27.9zM52.1 225.2h3.8zM52.1 230.3h13.9zM52.1 237.9h27.9zM55.9 225.2l1.2 2.5zM52.1 227.7h3.8zM57.1 227.7h33.1zM57.1 225.2l-1.2 2.5zM66 230.3l1.3 2.5zM52.1 232.8h13.9zM67.3 232.8h25.4zM67.3 230.3l-1.3 2.5z"/>
<path d="M80 220.1l1.3 2.6zM81.3 235.4l-1.3 2.5zM80 237.9h5.1zM81.3 222.7h3.8zM81.3 235.4h1.2zM82.5 235.4l-1.2 2.5zM81.3 232.9v1.2zM81.3 230.6v1.3zM81.3 228.4v1.2zM81.3 226.2v1.2zM81.3 223.9v1.3zM82.5 235.4h1.3z"/>
<path d="M83.8 235.4l-1.3 2.5zM83.8 235.4h1.3zM85.1 235.4l-1.3 2.5zM86.4 220.1l-1.3 2.6zM85.1 235.4h1.3zM86.4 235.4l-1.3 2.5zM86.4 220.1h11.4zM86.4 235.4h11.4zM86.4 232.9v1.2zM86.4 230.6v1.3zM86.4 228.4v1.2zM86.4 226.2v1.2z"/>
<path d="M86.4 223.9v1.3zM91.4 225.2l-1.2 2.5zM57.1 225.2h33.1zM91.4 225.2h6.4zM90.2 225.2l1.2 2.5zM94 230.3l-1.3 2.5zM67.3 230.3h25.4zM94 230.3h3.8zM92.7 230.3l1.3 2.5zM91.4 227.7h6.4zM94 232.8h3.8zM257.8 228v1z"/>
<path d="M257.8 226v1zM257.8 224v1zM257.8 222v1zM257.8 219.9v1.1zM257.8 229h1zM259.8 229h1zM261.8 229h1zM263.8 229h1.1zM265.8 229h1.1zM267.9 229h1zM269.9 229h1zM271.9 229h1z"/>
<path d="M273.9 229h1.1zM275.9 229h1.1zM278 229h1zM280 229h1zM282 229h1zM284 229h1zM286 229h1zM288.1 229h1zM290.1 229h1zM292.1 229h1zM294.1 229h1zM296.1 229h1z"/>
<path d="M298.1 229h1zM300.1 229h1.1zM302.2 229h1zM304.2 229h1zM306.2 229h1zM308.2 229h1zM310.2 229h1.1zM312.2 229h1.1zM314.3 229h1zM316.3 229h1zM318.3 229h1zM320.3 229h1z"/>
<path d="M322.3 229h1.1zM324.4 229h1zM326.4 229h1zM328.4 229h1zM330.4 229h1zM332.4 229h1zM334.4 229h1.1zM336.5 229h1zM338.5 229h1zM340.5 229h1zM342.5 229h1zM344.5 229h1z"/>
<path d="M346.5 229h1.1zM348.6 229h1zM350.6 229h1zM352.6 229h1zM354.6 229h1zM356.6 229h1zM358.6 229h1.1zM360.7 229h1zM362.7 229h1zM364.7 229h1zM365.7 228v1zM365.7 226v1z"/>
<path d="M365.7 224v1zM365.7 222v1zM365.7 219.9v1.1zM400 224.2h3.8zM146 253.1v2.6zM146 257.7v.5zM146 255.7v.5zM146 250.6v2.5zM153.6 253.1v2.6zM153.6 257.7v.5zM153.6 255.7v.5zM153.6 250.6v2.5z"/>
<path d="M146 250.6h7.6zM161.3 253.1v2.6zM161.3 257.7v.5zM161.3 255.7v.5zM153.6 250.6h7.7zM161.3 250.6v2.5zM168.9 253.1v2.6zM168.9 257.7v.5zM168.9 255.7v.5zM161.3 250.6h7.6zM168.9 250.6v2.5zM176.5 245.5v2.6z"/>
<path d="M176.5 253.1v2.6zM176.5 257.7v.5zM176.5 255.7v.5zM168.9 250.6h7.6zM176.5 248.1v2.5zM176.5 250.6v2.5zM186.7 245.5v2.6zM186.7 253.1v2.6zM186.7 255.7v.5zM186.7 257.7v.5zM186.7 248.1v5zM199.4 250.6h3.1z"/>
<path d="M214.6 250.6h5.1zM219.7 250.6h2.5zM222.2 250.6v12.7zM224.8 250.6h5zM222.2 250.6h2.6zM242 250.6h3.1zM20.3 274.7h379.7zM67.8 274.7v3.8zM115.3 274.7v3.8zM146 265.8v2.6zM146 258.2v2.6zM146 260.8v2.5z"/>
<path d="M146 263.3h7.6zM146 263.3v2.5zM153.6 258.2v2.6zM153.6 260.8v2.5zM161.3 258.2v2.6zM153.6 263.3h7.7zM161.3 260.8v2.5zM162.7 274.7v3.8zM168.9 258.2v2.6zM161.3 263.3h7.6zM168.9 260.8v2.5zM176.5 258.2v2.6z"/>
<path d="M168.9 263.3h7.6zM176.5 260.8v2.5zM186.7 258.2v2.6zM186.7 265.8v2.6zM186.7 260.8v5zM210.2 274.7v3.8zM222.2 265.8v2.6zM222.2 263.3h2.6zM222.2 263.3v2.5zM224.8 263.3h5zM242 263.3h3.1zM257.6 274.7v3.8z"/>
<path d="M305.1 274.7v3.8zM352.5 274.7v3.8zM400 264.5v.1zM400 268.4v6.2zM400 274.6h.1zM400 22.1v252.6z"/>
<circle cx="54.6" cy="44.9" r=".51"/>
<circle cx="72.4" cy="50" r=".51"/>
<circle cx="128.2" cy="55.1" r=".51"/>
<circle cx="298.4" cy="44.9" r=".51"/>
<circle cx="67.3" cy="75.4" r=".51"/>
<circle cx="118.1" cy="75.4" r=".51"/>
<circle cx="123.2" cy="60.2" r=".51"/>
<circle cx="140.9" cy="65.2" r=".51"/>
<circle cx="161.3" cy="70.3" r=".51"/>
<circle cx="59.7" cy="80.5" r=".51"/>
<circle cx="166.3" cy="85.5" r=".51"/>
<circle cx="245.1" cy="118.6" r=".51"/>
<circle cx="336.5" cy="100.8" r=".51"/>
<circle cx="369.5" cy="110.9" r=".51"/>
<circle cx="140.9" cy="171.9" r=".51"/>
<circle cx="270.5" cy="174.4" r=".51"/>
<circle cx="146" cy="194.8" r=".51"/>
<circle cx="270.5" cy="212.5" r=".51"/>
<circle cx="153.6" cy="250.6" r=".51"/>
<circle cx="161.3" cy="250.6" r=".51"/>
<circle cx="168.9" cy="250.6" r=".51"/>
<circle cx="176.5" cy="250.6" r=".51"/>
<circle cx="222.2" cy="250.6" r=".51"/>
<circle cx="146" cy="263.3" r=".51"/>
<circle cx="153.6" cy="263.3" r=".51"/>
<circle cx="161.3" cy="263.3" r=".51"/>
<circle cx="168.9" cy="263.3" r=".51"/>
<circle cx="222.2" cy="263.3" r=".51"/>
</g>
<g fill="#000" stroke="#000" stroke-width=".28">
<path d="M26.2 43.4v3zM30.2 53.6v3zM32 48.5v3zM33.4 58.6v3.1zM33.4 58.6h7zM30.2 53.6h10.2zM30.2 56.6h10.2zM26.2 43.4h14.2zM26.2 46.4h14.2zM32 48.5h8.4zM32 51.5h8.4zM40.4 53.6l1.5 1.5z"/>
<path d="M41.9 55.1l-1.5 1.5zM40.4 43.4l1.5 1.5zM41.9 44.9l-1.5 1.5zM40.4 48.5l1.5 1.5zM41.9 50l-1.5 1.5zM377.1 55.1l1.6-1.5zM377.1 55.1l1.6 1.5zM377.1 44.9l1.6-1.5zM377.1 44.9l1.6 1.5zM378.7 48.5l-1.6 1.5zM377.1 50l1.6 1.5zM378.7 58.6h8.4z"/>
<path d="M378.7 53.6h11.6zM378.7 56.6h11.6zM378.7 43.4h14.1zM378.7 46.4h14.1zM378.7 48.5h9.8zM378.7 51.5h9.8zM387.1 58.6v3.1zM388.5 48.5v3zM390.3 53.6v3zM392.8 43.4v3zM30.2 68.8v3zM31.2 78.9v3.1z"/>
<path d="M31.7 73.8v3.1zM34.2 63.7v3zM34.2 63.7h6.2zM34.2 66.7h6.2zM33.4 61.7h7zM30.2 68.8h10.2zM30.2 71.8h10.2zM31.7 73.8h8.7zM31.7 76.9h8.7zM31.2 78.9h9.2zM40.4 63.7l1.5 1.5zM41.9 65.2l-1.5 1.5z"/>
<path d="M40.4 58.6l1.5 1.6zM40.4 61.7l1.5-1.5zM40.4 68.8l1.5 1.5zM40.4 71.8l1.5-1.5zM40.4 73.8l1.5 1.6zM41.9 75.4l-1.5 1.5zM377.1 65.2l1.6-1.5zM377.1 65.2l1.6 1.5zM377.1 60.2l1.6-1.6zM377.1 60.2l1.6 1.5zM378.7 68.8l-1.6 1.5zM377.1 70.3l1.6 1.5z"/>
<path d="M378.7 73.8l-1.6 1.6zM377.1 75.4l1.6 1.5zM378.7 63.7h7.5zM378.7 66.7h7.5zM378.7 61.7h8.4zM378.7 68.8h11.6zM378.7 71.8h11.6zM378.7 73.8h10.1zM378.7 76.9h10.1zM378.7 78.9h10.6zM386.2 63.7v3zM388.8 73.8v3.1z"/>
<path d="M389.3 78.9v3.1zM390.3 68.8v3zM31.2 84v3.1zM31.2 84h9.2zM31.2 87.1h9.2zM31.2 82h9.2zM40.4 84l1.5 1.5zM40.4 87.1l1.5-1.6zM40.4 78.9l1.5 1.6zM41.9 80.5l-1.5 1.5zM336.5 95.7l-1.3 1.9zM336.5 95.7l1.3 1.9z"/>
<path d="M378.7 84l-1.6 1.5zM377.1 85.5l1.6 1.6zM377.1 80.5l1.6-1.6zM377.1 80.5l1.6 1.5zM378.7 84h10.6zM378.7 87.1h10.6zM378.7 82h10.6zM389.3 84v3.1zM377.1 110.9l1.6-1.5zM377.1 110.9l1.6 1.6zM378.7 109.4h8.1zM378.7 112.5h8.1z"/>
<path d="M386.8 109.4v3.1zM323.8 139.6h5.1zM323.8 138.1v1.5zM323.8 138.1h5.1zM328.9 138.1v1.5zM73 144h3.8zM323.8 144.7h5.1zM323.8 143.2v1.5zM323.8 149.8h5.1zM323.8 148.3v1.5zM323.8 154.9h5.1zM323.8 153.3v1.6z"/>
<path d="M323.8 160h5.1zM323.8 158.4v1.6zM323.8 143.2h5.1zM328.9 143.2v1.5zM323.8 148.3h5.1zM328.9 148.3v1.5zM323.8 153.3h5.1zM328.9 153.3v1.6zM323.8 158.4h5.1zM328.9 158.4v1.6zM268.6 179.5h3.8zM323.8 165h5.1z"/>
<path d="M323.8 163.5v1.5zM323.8 170.1h5.1zM323.8 168.6v1.5zM323.8 175.2h5.1zM323.8 173.7v1.5zM323.8 178.7v1.6zM323.8 163.5h5.1zM328.9 163.5v1.5zM323.8 168.6h5.1zM328.9 168.6v1.5zM323.8 173.7h5.1zM328.9 173.7v1.5z"/>
<path d="M323.8 178.7h5.1zM323.8 180.3h5.1zM323.8 185.4h5.1zM323.8 183.8v1.6zM323.8 190.4h5.1zM323.8 188.9v1.5zM323.8 195.5h5.1zM323.8 194v1.5zM323.8 199.1v1.5zM328.9 178.7v1.6zM323.8 183.8h5.1zM328.9 183.8v1.6z"/>
<path d="M323.8 188.9h5.1zM328.9 188.9v1.5zM323.8 194h5.1zM328.9 194v1.5zM323.8 199.1h5.1zM268.6 217.6h3.8zM323.8 200.6h5.1zM323.8 205.7h5.1zM323.8 204.1v1.6zM323.8 210.7h5.1zM323.8 209.2v1.5zM323.8 215.8h5.1z"/>
<path d="M323.8 214.3v1.5zM328.9 199.1v1.5zM323.8 204.1h5.1zM328.9 204.1v1.6zM323.8 209.2h5.1zM328.9 209.2v1.5zM323.8 214.3h5.1zM328.9 214.3v1.5zM176.5 245.5l-1.3 1.9zM176.5 245.5l1.3 1.9zM186.7 245.5l-1.3 1.9zM186.7 245.5l1.2 1.9z"/>
<path d="M313.7 249.3h86.3zM313.7 254.4h86.3zM313.7 259.5h58.4zM372.1 259.5h27.9zM372.1 259.5v5.1zM144.1 268.4h3.8zM184.8 268.4h3.8zM220.3 268.4h3.8zM313.7 264.6h58.4zM313.7 269.7h86.3zM372.1 264.6h27.9zM400 268.4v1.3z"/>
</g>
<g fill="#000" stroke="#000" stroke-width=".25">
<path d="M54.6 253.1h25.4v10.2h-25.4zM144 256.2h4.1v.5h-4.1zM144 257.2h4.1v.5h-4.1zM151.6 256.2h4.1v.5h-4.1zM151.6 257.2h4.1v.5h-4.1zM159.2 256.2h4.1v.5h-4.1zM159.2 257.2h4.1v.5h-4.1zM166.9 256.2h4v.5h-4zM166.9 257.2h4v.5h-4zM174.5 256.2h4v.5h-4zM174.5 257.2h4v.5h-4zM184.6 257.2h4.1v.5h-4.1z"/>
<path d="M184.6 256.2h4.1v.5h-4.1z"/>
</g>
<g fill="none" stroke="#000" stroke-width=".25">
<circle cx="274" cy="103.3" r="1"/>
<circle cx="279.1" cy="118.6" r="1"/>
<circle cx="299.4" cy="118.6" r="1"/>
<circle cx="343.1" cy="110.9" r="1"/>
<circle cx="343.1" cy="100.8" r="1"/>
<circle cx="81.6" cy="126.2" r=".99"/>
<circle cx="81.6" cy="136.3" r=".99"/>
<circle cx="178.1" cy="174.4" r=".99"/>
<circle cx="277.1" cy="174.4" r="1"/>
<circle cx="277.1" cy="171.9" r="1"/>
<circle cx="178.1" cy="212.5" r=".99"/>
<circle cx="277.1" cy="212.5" r="1"/>
<circle cx="277.1" cy="210" r="1"/>
<circle cx="203.5" cy="250.6" r=".99"/>
<circle cx="241" cy="250.6" r="1"/>
<circle cx="241" cy="263.3" r="1"/>
</g>
<g fill="#000" stroke="#000" stroke-width=".61">
<path d="M20.3 22.1v252.6zM20.3 22.1h379.7zM186.7 98.2v10.2zM262.9 98.2l10.1 5.1zM344.1 98.2v15.3zM344.1 98.2h15.3zM64.8 110.9h10.1zM120.6 110.9h10.2zM224.8 105.9v10.1zM252.7 113.5v10.1zM262.9 98.2v10.2zM267.9 113.5l10.2 5.1z"/>
<path d="M262.9 108.4l10.1-5.1zM267.9 123.6l10.2-5zM288.3 113.5l10.1 5.1zM288.3 123.6l10.1-5zM316.2 105.9v10.1zM344.1 113.5h15.3zM359.4 98.2v15.3zM82.5 138.9h15.3zM82.5 123.6v15.3zM97.8 123.6v15.3zM82.5 123.6h15.3zM267.9 113.5v10.1z"/>
<path d="M288.3 113.5v10.1zM110.5 146.5h10.1zM179 146.5v30.5zM179 146.5h15.3zM278.1 146.5v30.5zM278.1 146.5h15.2zM115.6 179.5h10.1zM179 177h15.3zM194.3 146.5v30.5zM278.1 177h15.2zM293.3 146.5v30.5zM179 184.6v30.4z"/>
<path d="M179 184.6h15.3zM278.1 184.6v30.4zM278.1 184.6h15.2zM179 215h15.3zM194.3 184.6v30.4zM278.1 215h15.2zM293.3 184.6v30.4zM204.4 250.6l10.2-5.1zM204.4 250.6l10.2 5.1zM214.6 245.5v10.2zM229.8 258.2l10.2 5.1zM229.8 245.5l10.2 5.1z"/>
<path d="M229.8 245.5v10.2zM229.8 255.7l10.2-5.1zM283.2 244.3v30.4zM313.7 254.4v5.1zM313.7 249.3v5.1zM313.7 244.3v5zM313.7 244.3h86.3zM283.2 244.3h30.5zM400 254.4v5.1zM400 249.3v5.1zM400 244.3v5zM400 22.1v222.2z"/>
<path d="M20.3 274.7h262.9zM229.8 258.2v10.2zM229.8 268.4l10.2-5.1zM283.2 274.7h30.5zM313.7 274.7h86.3zM313.7 269.7v5zM313.7 264.6v5.1zM313.7 259.5v5.1zM400 268.4v6.3zM400 264.6v3.8zM400 259.5v5.1z"/>
</g>
<path d="M16.5 18.2v260.3zM16.5 18.2h387.3zM16.5 278.5h387.3zM403.8 18.2v260.3z" fill="#000" stroke="#000" stroke-width=".32"/>
<path d="M186.7 98.2a5.1 5.1 0 0 1 5.1 5.1 5.1 5.1 0 0 1-5.1 5.1M64.8 110.9a5.1 5.1 0 0 0 5 5.1 5.1 5.1 0 0 0 5.1-5.1M120.6 110.9a5.1 5.1 0 0 0 5.1 5.1 5.1 5.1 0 0 0 5.1-5.1M224.8 105.9a5.1 5.1 0 0 1 5 5 5.1 5.1 0 0 1-5 5.1M252.7 113.5a5.1 5.1 0 0 1 5.1 5.1 5.1 5.1 0 0 1-5.1 5M316.2 105.9a5.1 5.1 0 0 1 5.1 5 5.1 5.1 0 0 1-5.1 5.1M110.5 146.5a5.1 5.1 0 0 0 5.1 5.1 5.1 5.1 0 0 0 5-5.1M115.6 179.5a5.1 5.1 0 0 0 5 5.1 5.1 5.1 0 0 0 5.1-5.1" fill="none" stroke="#000" stroke-width=".61"/>
<g fill="#000" stroke="#000" stroke-width=".76">
<path d="M41.9 90.6h104.1zM146 90.6l5.1 5.1zM151.1 95.7v106.7zM250.2 133.8v76.2zM250.2 133.8l5-5.1zM255.2 128.7h101.6zM351.7 133.8v78.7zM356.8 128.7l-5.1 5.1zM356.8 128.7h17.8zM222.2 151.6v58.4zM222.2 210l5.1 5zM227.3 215h17.8z"/>
<path d="M245.1 215l5.1-5z"/>
</g>
<path d="M24.1 253.1v10.2zM24.1 253.1h55.9zM24.1 263.3v7.6zM24.1 270.9h55.9zM24.1 263.3h55.9zM80 263.3v7.6zM80 253.1v10.2z" fill="#000" stroke="#000" stroke-width=".42"/>
<use href="#words"/>
</svg>
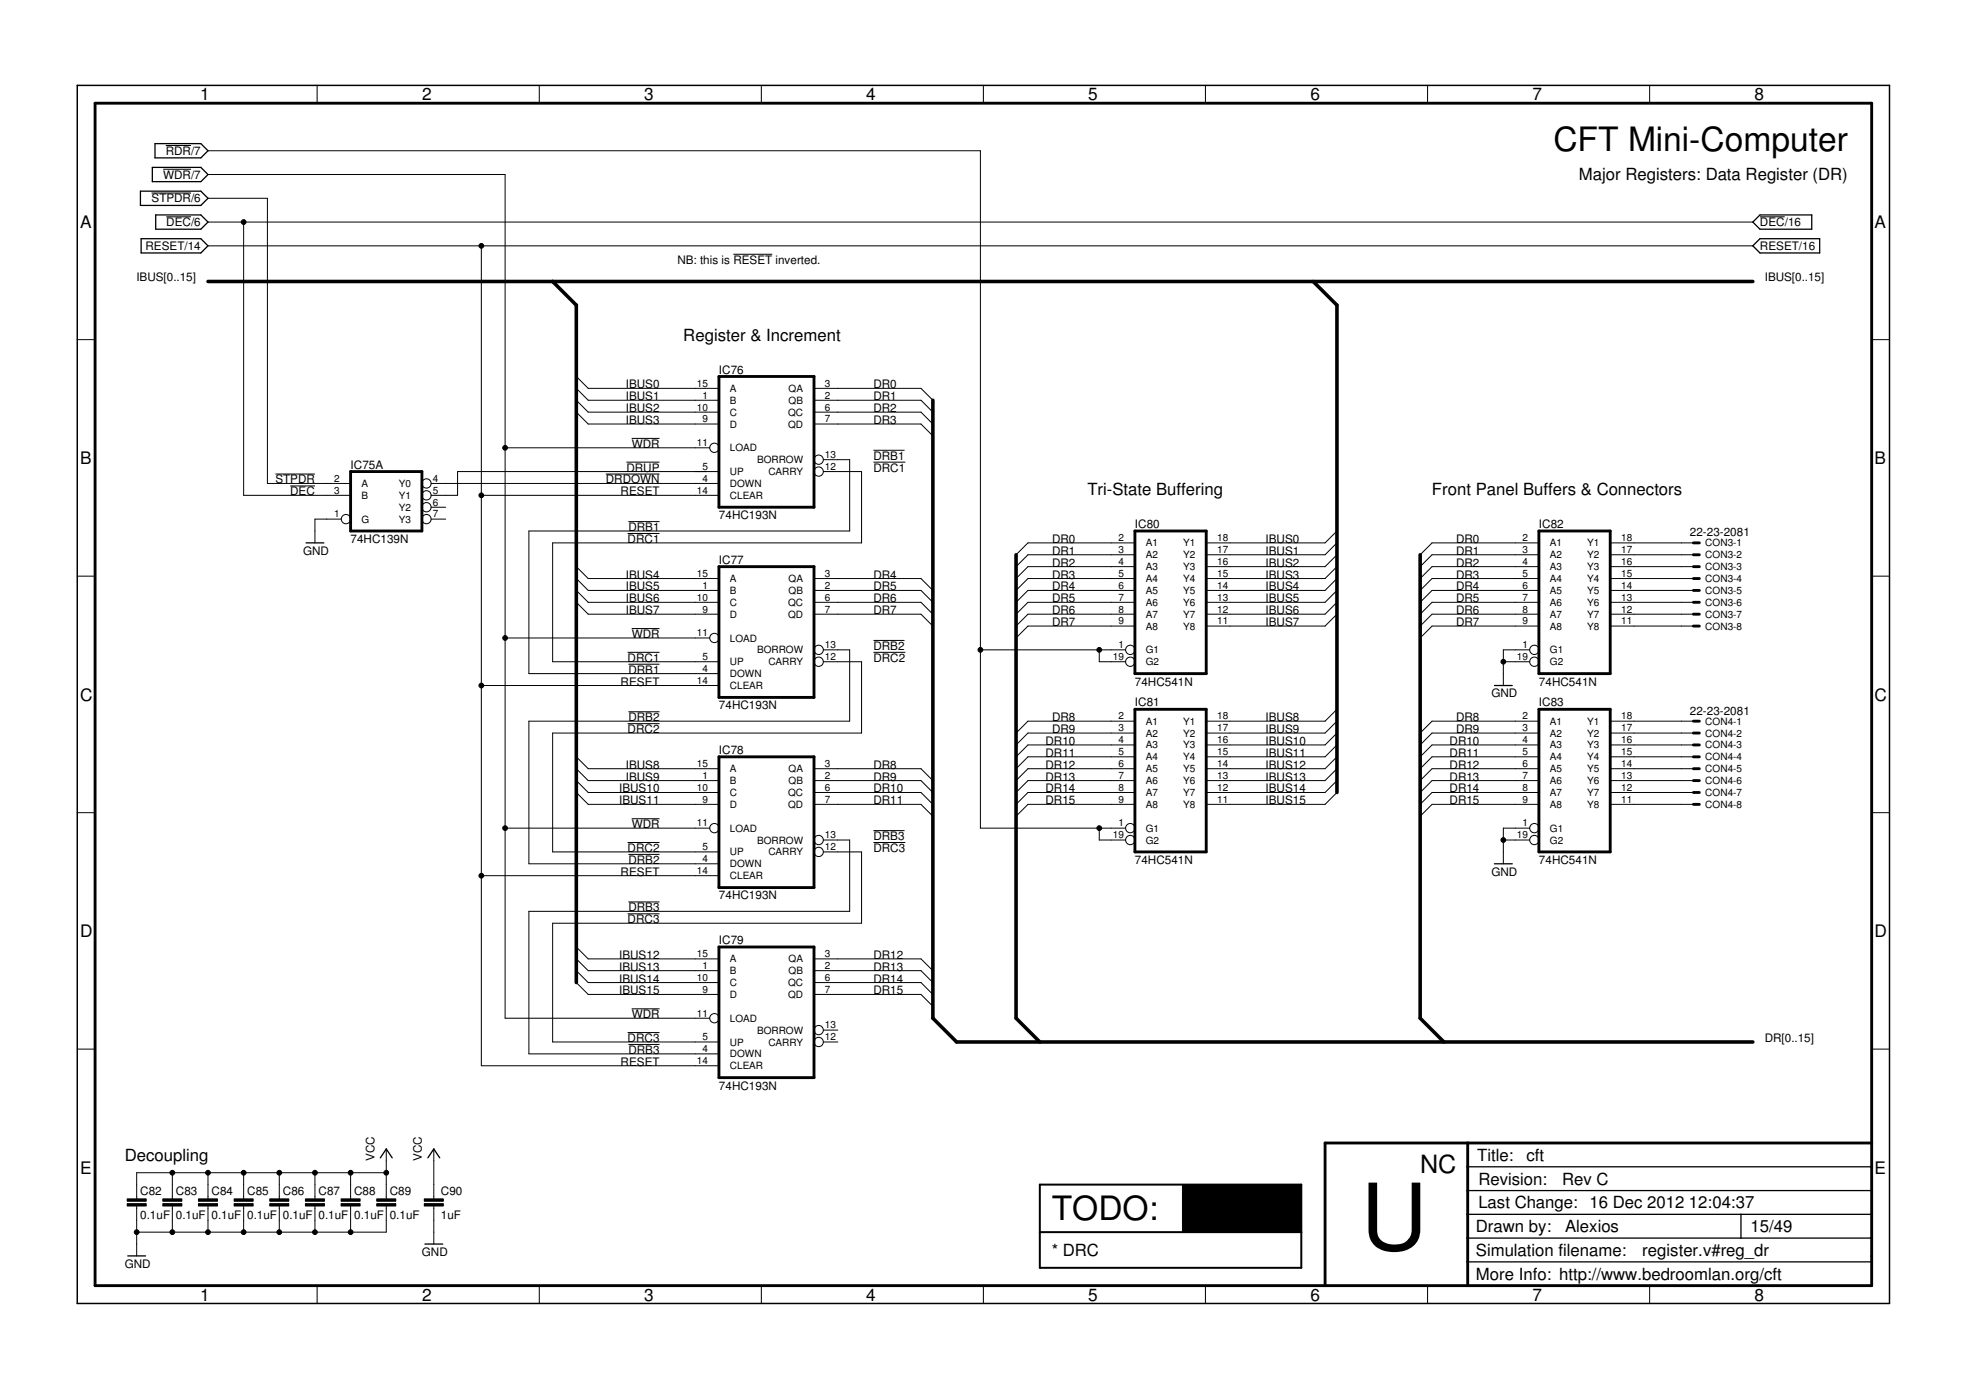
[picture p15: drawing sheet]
<svg xmlns="http://www.w3.org/2000/svg" width="420mm" height="297mm" viewBox="0 0 420 297" stroke-linecap="round" stroke-linejoin="round" font-family="sans-serif">
<defs><g id="words">
<text font-size="19.7" x="290.8" y="267.1">U</text>
<g font-size="7.2">
<text x="332" y="32.2">CFT Mini-Computer</text>
<text x="224.8" y="260.8">TODO:</text>
</g>
<text font-size="5.4" x="303.5" y="250.6">NC</text>
<g font-size="3.7">
<text x="42.7" y="21.5">1</text>
<text x="90.2" y="21.5">2</text>
<text x="137.7" y="21.5">3</text>
<text x="185.1" y="21.5">4</text>
<text x="232.6" y="21.5">5</text>
<text x="280" y="21.5">6</text>
<text x="327.5" y="21.5">7</text>
<text x="375" y="21.5">8</text>
<text x="17.1" y="48.6">A</text>
<text x="400.6" y="48.6">A</text>
<text x="17.1" y="99.2">B</text>
<text x="400.6" y="99.2">B</text>
<text x="17.1" y="149.7">C</text>
<text x="400.6" y="149.7">C</text>
<text x="17.1" y="200.2">D</text>
<text x="400.6" y="200.2">D</text>
<text x="17.1" y="250.8">E</text>
<text x="400.6" y="250.8">E</text>
<text x="42.7" y="277.9">1</text>
<text x="90.2" y="277.9">2</text>
<text x="137.7" y="277.9">3</text>
<text x="185.1" y="277.9">4</text>
<text x="232.6" y="277.9">5</text>
<text x="280" y="277.9">6</text>
<text x="327.5" y="277.9">7</text>
<text x="375" y="277.9">8</text>
</g>
<g font-size="3.6">
<text x="337.4" y="38.6">Major Registers: Data Register (DR)</text>
<text x="146" y="72.8">Register &amp; Increment</text>
<text x="232.4" y="105.9">Tri-State Buffering</text>
<text x="306" y="105.9">Front Panel Buffers &amp; Connectors</text>
<text x="26.7" y="248.1">Decoupling</text>
<text x="315.7" y="248.1">Title:</text>
<text x="326.2" y="248.2">cft</text>
<text x="315.9" y="253.2">Revision:</text>
<text x="333.8" y="253.3">Rev C</text>
<text x="315.4" y="263.3">Drawn by:</text>
<text x="315.9" y="258.2">Last Change: 16 Dec 2012</text>
<text x="334.5" y="263.3">Alexios</text>
<text x="361" y="258.1">12:04:37</text>
<text x="374.1" y="263.2">15/49</text>
<text x="224.8" y="268.4">* DRC</text>
<text x="315.4" y="268.4">Simulation filename:</text>
<text x="351" y="268.4">register.v#reg_dr</text>
<text x="315.4" y="273.5">More Info: http://www.bedroomlan.org/cft</text>
</g>
<g font-size="2.5">
<text x="35.4" y="33.1">RDR/7</text>
<text x="34.9" y="38.2">WDR/7</text>
<text x="32.4" y="43.3">STPDR/6</text>
<text x="31.1" y="53.4">RESET/14</text>
<text x="35.5" y="48.3">DEC/6</text>
<text x="376.1" y="53.4">RESET/16</text>
<text x="376.1" y="48.3">DEC/16</text>
<text x="144.8" y="56.3">NB: this is RESET inverted.</text>
<text x="29.1" y="60.1">IBUS[0..15]</text>
<text x="377.1" y="60.1">IBUS[0..15]</text>
<text x="133.7" y="83">IBUS0</text>
<text x="153.7" y="79.8">IC76</text>
<text x="186.7" y="83">DR0</text>
<text x="133.7" y="85.5">IBUS1</text>
<text x="133.7" y="88.1">IBUS2</text>
<text x="186.7" y="85.5">DR1</text>
<text x="186.7" y="88.1">DR2</text>
<text x="133.7" y="90.6">IBUS3</text>
<text x="135" y="95.7">WDR</text>
<text x="186.7" y="90.6">DR3</text>
<text x="74.9" y="100.1">IC75A</text>
<text x="133.9" y="100.8">DRUP</text>
<text x="186.7" y="100.8">DRC1</text>
<text x="186.7" y="98.2">DRB1</text>
<text x="58.9" y="103.3">STPDR</text>
<text x="62" y="105.9">DEC</text>
<text x="129.5" y="103.3">DRDOWN</text>
<text x="132.6" y="105.9">RESET</text>
<text x="134.3" y="113.5">DRB1</text>
<text x="153.7" y="110.9">74HC193N</text>
<text x="242.5" y="112.8">IC80</text>
<text x="328.9" y="112.8">IC82</text>
<text x="64.8" y="118.6">GND</text>
<text x="74.9" y="116">74HC139N</text>
<text x="134.1" y="116">DRC1</text>
<text x="224.8" y="116">DR0</text>
<text x="224.8" y="118.6">DR1</text>
<text x="270.5" y="116">IBUS0</text>
<text x="270.5" y="118.6">IBUS1</text>
<text x="311.2" y="116">DR0</text>
<text x="311.2" y="118.6">DR1</text>
<text x="361.1" y="114.6">22-23-2081</text>
<text x="133.7" y="123.6">IBUS4</text>
<text x="153.7" y="120.5">IC77</text>
<text x="186.7" y="123.6">DR4</text>
<text x="224.8" y="121.1">DR2</text>
<text x="224.8" y="123.6">DR3</text>
<text x="270.5" y="121.1">IBUS2</text>
<text x="270.5" y="123.6">IBUS3</text>
<text x="311.2" y="121.1">DR2</text>
<text x="311.2" y="123.6">DR3</text>
<text x="133.7" y="126.2">IBUS5</text>
<text x="133.7" y="128.7">IBUS6</text>
<text x="133.7" y="131.3">IBUS7</text>
<text x="186.7" y="126.2">DR5</text>
<text x="186.7" y="128.7">DR6</text>
<text x="186.7" y="131.3">DR7</text>
<text x="224.8" y="126.2">DR4</text>
<text x="224.8" y="128.7">DR5</text>
<text x="224.8" y="131.3">DR6</text>
<text x="270.5" y="126.2">IBUS4</text>
<text x="270.5" y="128.7">IBUS5</text>
<text x="270.5" y="131.3">IBUS6</text>
<text x="311.2" y="126.2">DR4</text>
<text x="311.2" y="128.7">DR5</text>
<text x="311.2" y="131.3">DR6</text>
<text x="135" y="136.3">WDR</text>
<text x="224.8" y="133.8">DR7</text>
<text x="270.5" y="133.8">IBUS7</text>
<text x="311.2" y="133.8">DR7</text>
<text x="134.1" y="141.4">DRC1</text>
<text x="134.3" y="144">DRB1</text>
<text x="186.7" y="141.4">DRC2</text>
<text x="186.7" y="138.9">DRB2</text>
<text x="132.6" y="146.5">RESET</text>
<text x="242.5" y="146.5">74HC541N</text>
<text x="318.7" y="149">GND</text>
<text x="328.9" y="146.5">74HC541N</text>
<text x="134.3" y="154.1">DRB2</text>
<text x="153.7" y="151.6">74HC193N</text>
<text x="224.8" y="154.1">DR8</text>
<text x="242.5" y="150.9">IC81</text>
<text x="270.5" y="154.1">IBUS8</text>
<text x="311.2" y="154.1">DR8</text>
<text x="328.9" y="150.9">IC83</text>
<text x="361.1" y="152.7">22-23-2081</text>
<text x="134.1" y="156.6">DRC2</text>
<text x="153.7" y="161.1">IC78</text>
<text x="223.5" y="159.2">DR10</text>
<text x="223.5" y="161.7">DR11</text>
<text x="224.8" y="156.6">DR9</text>
<text x="270.5" y="156.6">IBUS9</text>
<text x="270.5" y="159.2">IBUS10</text>
<text x="270.5" y="161.7">IBUS11</text>
<text x="309.8" y="159.2">DR10</text>
<text x="309.8" y="161.7">DR11</text>
<text x="311.2" y="156.6">DR9</text>
<text x="133.7" y="164.3">IBUS8</text>
<text x="133.7" y="166.8">IBUS9</text>
<text x="186.7" y="164.3">DR8</text>
<text x="186.7" y="166.8">DR9</text>
<text x="223.5" y="164.3">DR12</text>
<text x="223.5" y="166.8">DR13</text>
<text x="270.5" y="164.3">IBUS12</text>
<text x="270.5" y="166.8">IBUS13</text>
<text x="309.8" y="164.3">DR12</text>
<text x="309.8" y="166.8">DR13</text>
<text x="132.3" y="169.3">IBUS10</text>
<text x="132.3" y="171.9">IBUS11</text>
<text x="186.7" y="169.3">DR10</text>
<text x="186.7" y="171.9">DR11</text>
<text x="223.5" y="169.3">DR14</text>
<text x="223.5" y="171.9">DR15</text>
<text x="270.5" y="169.3">IBUS14</text>
<text x="270.5" y="171.9">IBUS15</text>
<text x="309.8" y="169.3">DR14</text>
<text x="309.8" y="171.9">DR15</text>
<text x="135" y="177">WDR</text>
<text x="186.7" y="179.5">DRB3</text>
<text x="134.1" y="182">DRC2</text>
<text x="134.3" y="184.6">DRB2</text>
<text x="186.7" y="182">DRC3</text>
<text x="242.5" y="184.6">74HC541N</text>
<text x="328.9" y="184.6">74HC541N</text>
<text x="132.6" y="187.1">RESET</text>
<text x="318.7" y="187.1">GND</text>
<text x="134.1" y="197.3">DRC3</text>
<text x="134.3" y="194.7">DRB3</text>
<text x="153.7" y="192.2">74HC193N</text>
<text x="153.7" y="201.7">IC79</text>
<text x="132.3" y="204.9">IBUS12</text>
<text x="132.3" y="207.4">IBUS13</text>
<text x="132.3" y="210">IBUS14</text>
<text x="186.7" y="204.9">DR12</text>
<text x="186.7" y="207.4">DR13</text>
<text x="186.7" y="210">DR14</text>
<text x="132.3" y="212.5">IBUS15</text>
<text x="186.7" y="212.5">DR15</text>
<text x="135" y="217.6">WDR</text>
<text x="132.6" y="227.8">RESET</text>
<text x="134.1" y="222.7">DRC3</text>
<text x="134.3" y="225.2">DRB3</text>
<text x="377.1" y="222.7">DR[0..15]</text>
<text x="153.7" y="232.8">74HC193N</text>
<text x="80" y="248.1" transform="rotate(-90 80 248.1)">VCC</text>
<text x="90.2" y="248.1" transform="rotate(-90 90.2 248.1)">VCC</text>
<text x="30" y="255.3">C82</text>
<text x="37.6" y="255.3">C83</text>
<text x="45.2" y="255.3">C84</text>
<text x="52.8" y="255.3">C85</text>
<text x="60.4" y="255.3">C86</text>
<text x="68.1" y="255.3">C87</text>
<text x="75.7" y="255.3">C88</text>
<text x="83.3" y="255.3">C89</text>
<text x="94.2" y="255.3">C90</text>
<text x="30" y="260.4">0.1uF</text>
<text x="37.6" y="260.4">0.1uF</text>
<text x="45.2" y="260.4">0.1uF</text>
<text x="52.8" y="260.4">0.1uF</text>
<text x="60.4" y="260.4">0.1uF</text>
<text x="68.1" y="260.4">0.1uF</text>
<text x="75.7" y="260.4">0.1uF</text>
<text x="83.3" y="260.4">0.1uF</text>
<text x="94.2" y="260.4">1uF</text>
<text x="90.2" y="268.4">GND</text>
<text x="26.7" y="270.9">GND</text>
</g>
<g font-size="2.1">
<text x="148.9" y="82.6">15</text>
<text x="156" y="83.8">A</text>
<text x="168.5" y="83.8">QA</text>
<text x="176.3" y="82.6">3</text>
<text x="148.9" y="87.7">10</text>
<text x="150.1" y="85.2">1</text>
<text x="156" y="86.3">B</text>
<text x="156" y="88.8">C</text>
<text x="168.4" y="88.8">QC</text>
<text x="168.5" y="86.3">QB</text>
<text x="176.3" y="87.7">6</text>
<text x="176.3" y="85.2">2</text>
<text x="148.9" y="95.3">11</text>
<text x="150.1" y="90.3">9</text>
<text x="156" y="91.4">D</text>
<text x="168.4" y="91.4">QD</text>
<text x="176.3" y="90.3">7</text>
<text x="150.1" y="100.4">5</text>
<text x="156" y="101.5">UP</text>
<text x="156" y="96.5">LOAD</text>
<text x="161.8" y="99">BORROW</text>
<text x="164.2" y="101.5">CARRY</text>
<text x="176.3" y="97.9">13</text>
<text x="176.3" y="100.4">12</text>
<text x="71.4" y="103">2</text>
<text x="71.4" y="105.5">3</text>
<text x="77.3" y="104.1">A</text>
<text x="77.3" y="106.6">B</text>
<text x="85.2" y="104.1">Y0</text>
<text x="85.2" y="106.6">Y1</text>
<text x="92.5" y="103">4</text>
<text x="92.5" y="105.5">5</text>
<text x="148.9" y="105.5">14</text>
<text x="150.1" y="103">4</text>
<text x="156" y="104.1">DOWN</text>
<text x="156" y="106.6">CLEAR</text>
<text x="71.4" y="110.6">1</text>
<text x="77.3" y="111.7">G</text>
<text x="85.2" y="109.2">Y2</text>
<text x="85.2" y="111.7">Y3</text>
<text x="92.5" y="108">6</text>
<text x="92.5" y="110.6">7</text>
<text x="239" y="115.7">2</text>
<text x="239" y="118.2">3</text>
<text x="244.9" y="116.8">A1</text>
<text x="244.9" y="119.3">A2</text>
<text x="252.8" y="119.3">Y2</text>
<text x="252.8" y="116.8">Y1</text>
<text x="260.1" y="118.2">17</text>
<text x="260.1" y="115.7">18</text>
<text x="325.4" y="115.7">2</text>
<text x="325.4" y="118.2">3</text>
<text x="331.2" y="116.8">A1</text>
<text x="331.2" y="119.3">A2</text>
<text x="339.2" y="119.3">Y2</text>
<text x="339.2" y="116.8">Y1</text>
<text x="346.5" y="118.2">17</text>
<text x="346.5" y="115.7">18</text>
<text x="364.4" y="116.8">CON3-1</text>
<text x="364.4" y="119.3">CON3-2</text>
<text x="148.9" y="123.3">15</text>
<text x="150.1" y="125.8">1</text>
<text x="156" y="124.4">A</text>
<text x="168.5" y="124.4">QA</text>
<text x="176.3" y="125.8">2</text>
<text x="176.3" y="123.3">3</text>
<text x="239" y="120.7">4</text>
<text x="239" y="123.3">5</text>
<text x="239" y="125.8">6</text>
<text x="244.9" y="121.9">A3</text>
<text x="244.9" y="124.4">A4</text>
<text x="252.8" y="124.4">Y4</text>
<text x="252.8" y="121.9">Y3</text>
<text x="260.1" y="125.8">14</text>
<text x="260.1" y="123.3">15</text>
<text x="260.1" y="120.7">16</text>
<text x="325.4" y="120.7">4</text>
<text x="325.4" y="123.3">5</text>
<text x="325.4" y="125.8">6</text>
<text x="331.2" y="121.9">A3</text>
<text x="331.2" y="124.4">A4</text>
<text x="339.2" y="124.4">Y4</text>
<text x="339.2" y="121.9">Y3</text>
<text x="346.5" y="125.8">14</text>
<text x="346.5" y="123.3">15</text>
<text x="346.5" y="120.7">16</text>
<text x="364.4" y="121.9">CON3-3</text>
<text x="364.4" y="124.4">CON3-4</text>
<text x="148.9" y="128.4">10</text>
<text x="150.1" y="130.9">9</text>
<text x="156" y="126.9">B</text>
<text x="156" y="129.5">C</text>
<text x="168.4" y="129.5">QC</text>
<text x="168.5" y="126.9">QB</text>
<text x="176.3" y="130.9">7</text>
<text x="176.3" y="128.4">6</text>
<text x="239" y="128.4">7</text>
<text x="239" y="130.9">8</text>
<text x="244.9" y="126.9">A5</text>
<text x="244.9" y="129.5">A6</text>
<text x="252.8" y="129.5">Y6</text>
<text x="252.8" y="126.9">Y5</text>
<text x="260.1" y="130.9">12</text>
<text x="260.1" y="128.4">13</text>
<text x="325.4" y="128.4">7</text>
<text x="325.4" y="130.9">8</text>
<text x="331.2" y="126.9">A5</text>
<text x="331.2" y="129.5">A6</text>
<text x="339.2" y="129.5">Y6</text>
<text x="339.2" y="126.9">Y5</text>
<text x="346.5" y="130.9">12</text>
<text x="346.5" y="128.4">13</text>
<text x="364.4" y="126.9">CON3-5</text>
<text x="364.4" y="129.5">CON3-6</text>
<text x="148.9" y="136">11</text>
<text x="156" y="132">D</text>
<text x="156" y="137.1">LOAD</text>
<text x="168.4" y="132">QD</text>
<text x="239" y="133.4">9</text>
<text x="244.9" y="132">A7</text>
<text x="244.9" y="134.6">A8</text>
<text x="252.8" y="134.6">Y8</text>
<text x="252.8" y="132">Y7</text>
<text x="260.1" y="133.4">11</text>
<text x="325.4" y="133.4">9</text>
<text x="331.2" y="132">A7</text>
<text x="331.2" y="134.6">A8</text>
<text x="339.2" y="134.6">Y8</text>
<text x="339.2" y="132">Y7</text>
<text x="346.5" y="133.4">11</text>
<text x="364.4" y="132">CON3-7</text>
<text x="364.4" y="134.6">CON3-8</text>
<text x="150.1" y="141.1">5</text>
<text x="150.1" y="143.6">4</text>
<text x="156" y="142.2">UP</text>
<text x="161.8" y="139.6">BORROW</text>
<text x="164.2" y="142.2">CARRY</text>
<text x="176.3" y="138.5">13</text>
<text x="176.3" y="141.1">12</text>
<text x="237.8" y="141.1">19</text>
<text x="239" y="138.5">1</text>
<text x="244.9" y="139.6">G1</text>
<text x="244.9" y="142.2">G2</text>
<text x="324.2" y="141.1">19</text>
<text x="325.4" y="138.5">1</text>
<text x="331.2" y="139.6">G1</text>
<text x="331.2" y="142.2">G2</text>
<text x="148.9" y="146.1">14</text>
<text x="156" y="144.7">DOWN</text>
<text x="156" y="147.3">CLEAR</text>
<text x="239" y="153.8">2</text>
<text x="244.9" y="154.9">A1</text>
<text x="252.8" y="154.9">Y1</text>
<text x="260.1" y="153.8">18</text>
<text x="325.4" y="153.8">2</text>
<text x="331.2" y="154.9">A1</text>
<text x="339.2" y="154.9">Y1</text>
<text x="346.5" y="153.8">18</text>
<text x="364.4" y="154.9">CON4-1</text>
<text x="239" y="156.3">3</text>
<text x="239" y="158.8">4</text>
<text x="239" y="161.4">5</text>
<text x="244.9" y="157.4">A2</text>
<text x="244.9" y="159.9">A3</text>
<text x="252.8" y="160">Y3</text>
<text x="252.8" y="157.4">Y2</text>
<text x="260.1" y="161.4">15</text>
<text x="260.1" y="158.8">16</text>
<text x="260.1" y="156.3">17</text>
<text x="325.4" y="156.3">3</text>
<text x="325.4" y="158.8">4</text>
<text x="325.4" y="161.4">5</text>
<text x="331.2" y="157.4">A2</text>
<text x="331.2" y="159.9">A3</text>
<text x="339.2" y="160">Y3</text>
<text x="339.2" y="157.4">Y2</text>
<text x="346.5" y="161.4">15</text>
<text x="346.5" y="158.8">16</text>
<text x="346.5" y="156.3">17</text>
<text x="364.4" y="157.4">CON4-2</text>
<text x="364.4" y="159.9">CON4-3</text>
<text x="148.9" y="163.9">15</text>
<text x="150.1" y="166.5">1</text>
<text x="156" y="165">A</text>
<text x="156" y="167.6">B</text>
<text x="168.5" y="167.6">QB</text>
<text x="168.5" y="165">QA</text>
<text x="176.3" y="166.5">2</text>
<text x="176.3" y="163.9">3</text>
<text x="239" y="163.9">6</text>
<text x="239" y="166.5">7</text>
<text x="244.9" y="162.5">A4</text>
<text x="244.9" y="165">A5</text>
<text x="244.9" y="167.6">A6</text>
<text x="252.8" y="167.6">Y6</text>
<text x="252.8" y="165">Y5</text>
<text x="252.8" y="162.5">Y4</text>
<text x="260.1" y="166.5">13</text>
<text x="260.1" y="163.9">14</text>
<text x="325.4" y="163.9">6</text>
<text x="325.4" y="166.5">7</text>
<text x="331.2" y="162.5">A4</text>
<text x="331.2" y="165">A5</text>
<text x="331.2" y="167.6">A6</text>
<text x="339.2" y="167.6">Y6</text>
<text x="339.2" y="165">Y5</text>
<text x="339.2" y="162.5">Y4</text>
<text x="346.5" y="166.5">13</text>
<text x="346.5" y="163.9">14</text>
<text x="364.4" y="162.5">CON4-4</text>
<text x="364.4" y="165">CON4-5</text>
<text x="364.4" y="167.6">CON4-6</text>
<text x="148.9" y="169">10</text>
<text x="150.1" y="171.5">9</text>
<text x="156" y="170.1">C</text>
<text x="156" y="172.6">D</text>
<text x="168.4" y="172.6">QD</text>
<text x="168.4" y="170.1">QC</text>
<text x="176.3" y="171.5">7</text>
<text x="176.3" y="169">6</text>
<text x="239" y="169">8</text>
<text x="239" y="171.5">9</text>
<text x="244.9" y="170.1">A7</text>
<text x="244.9" y="172.6">A8</text>
<text x="252.8" y="172.6">Y8</text>
<text x="252.8" y="170.1">Y7</text>
<text x="260.1" y="171.5">11</text>
<text x="260.1" y="169">12</text>
<text x="325.4" y="169">8</text>
<text x="325.4" y="171.5">9</text>
<text x="331.2" y="170.1">A7</text>
<text x="331.2" y="172.6">A8</text>
<text x="339.2" y="172.6">Y8</text>
<text x="339.2" y="170.1">Y7</text>
<text x="346.5" y="171.5">11</text>
<text x="346.5" y="169">12</text>
<text x="364.4" y="170.1">CON4-7</text>
<text x="364.4" y="172.6">CON4-8</text>
<text x="148.9" y="176.6">11</text>
<text x="156" y="177.7">LOAD</text>
<text x="176.3" y="179.1">13</text>
<text x="237.8" y="179.1">19</text>
<text x="239" y="176.6">1</text>
<text x="244.9" y="177.7">G1</text>
<text x="324.2" y="179.1">19</text>
<text x="325.4" y="176.6">1</text>
<text x="331.2" y="177.7">G1</text>
<text x="150.1" y="181.7">5</text>
<text x="150.1" y="184.2">4</text>
<text x="156" y="182.8">UP</text>
<text x="156" y="185.3">DOWN</text>
<text x="161.8" y="180.3">BORROW</text>
<text x="164.2" y="182.8">CARRY</text>
<text x="176.3" y="181.7">12</text>
<text x="244.9" y="180.3">G2</text>
<text x="331.2" y="180.3">G2</text>
<text x="148.9" y="186.8">14</text>
<text x="156" y="187.9">CLEAR</text>
<text x="148.9" y="204.5">15</text>
<text x="148.9" y="209.6">10</text>
<text x="150.1" y="207.1">1</text>
<text x="156" y="205.7">A</text>
<text x="156" y="208.2">B</text>
<text x="168.5" y="208.2">QB</text>
<text x="168.5" y="205.7">QA</text>
<text x="176.3" y="209.6">6</text>
<text x="176.3" y="207.1">2</text>
<text x="176.3" y="204.5">3</text>
<text x="150.1" y="212.2">9</text>
<text x="156" y="210.7">C</text>
<text x="156" y="213.3">D</text>
<text x="168.4" y="213.3">QD</text>
<text x="168.4" y="210.7">QC</text>
<text x="176.3" y="212.2">7</text>
<text x="148.9" y="217.2">11</text>
<text x="156" y="218.4">LOAD</text>
<text x="161.8" y="220.9">BORROW</text>
<text x="176.3" y="219.8">13</text>
<text x="148.9" y="227.4">14</text>
<text x="150.1" y="222.3">5</text>
<text x="150.1" y="224.9">4</text>
<text x="156" y="223.4">UP</text>
<text x="156" y="226">DOWN</text>
<text x="164.2" y="223.4">CARRY</text>
<text x="176.3" y="222.3">12</text>
<text x="156" y="228.5">CLEAR</text>
</g>
</g></defs>
<g fill="#000" stroke="#000" stroke-width=".21">
<path d="M67.8 18.2v3.9zM115.3 18.2v3.9zM162.7 18.2v3.9zM210.2 18.2v3.9zM257.6 18.2v3.9zM305.1 18.2v3.9zM352.5 18.2v3.9zM20.3 22.1v252.6zM34.9 36.2h5.9zM35.4 31.1h5.4zM44.4 32.2h165.1zM44.4 37.3h63.5z"/>
<path d="M20.3 22.1h379.7zM32.4 41.3h8.4zM35.5 46.3h5.3zM44.4 47.5h7.7zM52.1 47.5v58.4zM52.1 47.5h322.5zM44.4 42.4h12.7zM44.4 52.5h58.5zM102.9 52.5v53.4zM102.9 52.5h271.7zM156.7 54.3h8.3zM376.1 46.3h5.3z"/>
<path d="M16.5 72.6h3.8zM400 72.6h3.8zM107.9 37.3v58.4zM107.9 95.7v40.6zM123.2 80.5l2.5 2.5zM123.2 83l2.5 2.5zM123.2 85.5l2.5 2.6zM123.2 88.1l2.5 2.5zM125.7 83h22.9zM125.7 85.5h22.9zM125.7 88.1h22.9zM125.7 90.6h22.9z"/>
<path d="M133.9 98.8h7zM135 93.7h5.9zM148.6 83h5zM148.6 85.5h5zM148.6 88.1h5zM148.6 90.6h5zM148.6 95.7h3.1zM107.9 95.7h40.7zM174 90.6h5zM174 88.1h5zM174 85.5h5zM174 83h5z"/>
<path d="M176 98.2h3zM179 83h17.8zM179 85.5h17.8zM179 88.1h17.8zM179 90.6h17.8zM179 98.2h2.6zM181.6 98.2v15.3zM186.7 98.8h6.8zM186.7 96.2h6.6zM196.8 83l2.6 2.5zM196.8 85.5l2.6 2.6zM196.8 88.1l2.6 2.5z"/>
<path d="M196.8 90.6l2.6 2.6zM52.1 105.9h17.7zM57.1 42.4v60.9zM58.9 101.3h8.4zM62 103.8h5.3zM67.3 113.5v2.5zM67.3 110.9v2.6zM69.8 110.9h3.1zM69.8 103.3h5.1zM69.8 105.9h5.1zM67.3 110.9h2.5zM57.1 103.3h12.7z"/>
<path d="M92.1 103.3h3.1zM92.1 105.9h3.1zM92.1 108.4h3.1zM92.1 110.9h3.1zM95.2 103.3h53.4zM95.2 105.9h2.6zM97.8 100.8v5.1zM97.8 100.8h53.3zM102.9 105.9h45.7zM102.9 105.9v40.6zM113 113.5v30.5zM118.1 116v25.4z"/>
<path d="M129.5 101.3h11.4zM134.1 114h6.8zM134.3 111.5h6.6zM148.6 100.8h5zM148.6 103.3h5zM148.6 105.9h5zM176 100.8h3zM179 100.8h5.1zM113 113.5h68.6zM184.1 100.8v15.2zM118.1 116h66zM219.7 116l-2.6 2.6z"/>
<path d="M219.7 118.6l-2.6 2.5zM237.5 116h5zM237.5 118.6h5zM219.7 116h17.8zM219.7 118.6h17.8zM257.8 118.6h5.1zM257.8 116h5.1zM262.9 116h20.3zM285.7 113.5l-2.5 2.5zM262.9 118.6h20.3zM283.2 118.6l2.5-2.6zM303.5 118.6l2.5-2.6z"/>
<path d="M306 118.6l-2.5 2.5zM323.8 116h5.1zM323.8 118.6h5.1zM306 116h17.8zM306 118.6h17.8zM344.1 118.6h5.1zM344.1 116h5.1zM359.4 116h2.5zM359.4 118.6h2.5zM349.2 116h10.2zM349.2 118.6h10.2zM16.5 123.1h3.8z"/>
<path d="M107.9 136.3h40.7zM107.9 136.3v40.7zM123.2 121.1l2.5 2.5zM123.2 123.6l2.5 2.6zM123.2 126.2l2.5 2.5zM123.2 128.7l2.5 2.6zM125.7 123.6h22.9zM125.7 126.2h22.9zM125.7 128.7h22.9zM125.7 131.3h22.9zM134.1 139.4h6.8zM135 134.3h5.9z"/>
<path d="M148.6 123.6h5zM148.6 126.2h5zM148.6 128.7h5zM148.6 131.3h5zM148.6 136.3h3.1zM174 131.3h5zM174 128.7h5zM174 126.2h5zM174 123.6h5zM176 138.9h3zM179 123.6h17.8zM179 126.2h17.8z"/>
<path d="M179 128.7h17.8zM179 131.3h17.8zM179 138.9h2.6zM181.6 138.9v15.2zM186.7 139.4h6.8zM186.7 136.9h6.6zM196.8 123.6l2.6 2.6zM196.8 126.2l2.6 2.5zM196.8 128.7l2.6 2.6zM196.8 131.3l2.6 2.5zM209.5 32.2v106.7zM209.5 138.9v38.1z"/>
<path d="M219.7 121.1l-2.6 2.5zM219.7 123.6l-2.6 2.6zM219.7 126.2l-2.6 2.5zM219.7 128.7l-2.6 2.6zM219.7 131.3l-2.6 2.5zM219.7 133.8l-2.6 2.5zM209.5 138.9h25.4zM237.5 138.9h3.1zM237.5 121.1h5zM237.5 123.6h5zM237.5 126.2h5zM237.5 128.7h5z"/>
<path d="M237.5 131.3h5zM237.5 133.8h5zM219.7 121.1h17.8zM219.7 123.6h17.8zM219.7 126.2h17.8zM219.7 128.7h17.8zM219.7 131.3h17.8zM219.7 133.8h17.8zM234.9 138.9h2.6zM257.8 133.8h5.1zM257.8 131.3h5.1zM257.8 128.7h5.1z"/>
<path d="M257.8 126.2h5.1zM257.8 123.6h5.1zM257.8 121.1h5.1zM262.9 121.1h20.3zM285.7 118.6l-2.5 2.5zM262.9 123.6h20.3zM285.7 121.1l-2.5 2.5zM262.9 126.2h20.3zM262.9 128.7h20.3zM262.9 131.3h20.3zM262.9 133.8h20.3zM285.7 123.6l-2.5 2.6z"/>
<path d="M285.7 126.2l-2.5 2.5zM285.7 128.7l-2.5 2.6zM285.7 131.3l-2.5 2.5zM306 121.1l-2.5 2.5zM303.5 126.2l2.5-2.6zM306 126.2l-2.5 2.5zM303.5 131.3l2.5-2.6zM306 131.3l-2.5 2.5zM306 133.8l-2.5 2.5zM323.8 138.9h3.1zM323.8 121.1h5.1zM323.8 123.6h5.1z"/>
<path d="M323.8 126.2h5.1zM323.8 128.7h5.1zM323.8 131.3h5.1zM323.8 133.8h5.1zM321.3 138.9h2.5zM306 121.1h17.8zM306 123.6h17.8zM306 126.2h17.8zM306 128.7h17.8zM306 131.3h17.8zM306 133.8h17.8zM344.1 133.8h5.1z"/>
<path d="M344.1 131.3h5.1zM344.1 128.7h5.1zM344.1 126.2h5.1zM344.1 123.6h5.1zM344.1 121.1h5.1zM359.4 121.1h2.5zM359.4 123.6h2.5zM359.4 126.2h2.5zM359.4 128.7h2.5zM359.4 131.3h2.5zM359.4 133.8h2.5zM349.2 121.1h10.2z"/>
<path d="M349.2 123.6h10.2zM349.2 126.2h10.2zM349.2 128.7h10.2zM349.2 131.3h10.2zM349.2 133.8h10.2zM400 123.1h3.8zM102.9 146.5h45.7zM102.9 146.5v40.6zM113 144h35.6zM113 154.1v30.5zM118.1 141.4h30.5zM118.1 156.7v25.4z"/>
<path d="M134.1 154.6h6.8zM134.3 141.9h6.6zM134.3 152.1h6.6zM148.6 141.4h5zM148.6 144h5zM148.6 146.5h5zM148.6 146.5h2.5zM176 141.4h3zM179 141.4h5.1zM113 154.1h68.6zM184.1 141.4v15.3zM118.1 156.7h66z"/>
<path d="M219.7 154.1l-2.6 2.6zM219.7 156.7l-2.6 2.5zM219.7 159.2l-2.6 2.5zM234.9 138.9v2.5zM237.5 141.4h3.1zM237.5 154.1h5zM237.5 156.7h5zM237.5 159.2h5zM219.7 154.1h17.8zM219.7 156.7h17.8zM219.7 159.2h17.8zM234.9 141.4h2.6z"/>
<path d="M257.8 159.2h5.1zM257.8 156.7h5.1zM257.8 154.1h5.1zM262.9 154.1h20.3zM262.9 156.7h20.3zM262.9 159.2h20.3zM285.7 151.6l-2.5 2.5zM285.7 154.1l-2.5 2.6zM285.7 156.7l-2.5 2.5zM285.7 159.2l-2.5 2.5zM306 154.1l-2.5 2.6zM306 156.7l-2.5 2.5z"/>
<path d="M303.5 161.7l2.5-2.5zM321.3 144v2.5zM321.3 138.9v2.5zM321.3 141.4v2.6zM323.8 141.4h3.1zM323.8 154.1h5.1zM323.8 156.7h5.1zM323.8 159.2h5.1zM321.3 141.4h2.5zM306 154.1h17.8zM306 156.7h17.8zM306 159.2h17.8z"/>
<path d="M344.1 159.2h5.1zM344.1 156.7h5.1zM344.1 154.1h5.1zM359.4 154.1h2.5zM359.4 156.7h2.5zM359.4 159.2h2.5zM349.2 154.1h10.2zM349.2 156.7h10.2zM349.2 159.2h10.2zM16.5 173.7h3.8zM107.9 177h40.7zM107.9 177v40.6z"/>
<path d="M123.2 161.7l2.5 2.6zM123.2 164.3l2.5 2.5zM123.2 166.8l2.5 2.6zM123.2 169.4l2.5 2.5zM125.7 164.3h22.9zM125.7 166.8h22.9zM125.7 169.4h22.9zM125.7 171.9h22.9zM135 175h5.9zM148.6 164.3h5zM148.6 166.8h5zM148.6 169.4h5z"/>
<path d="M148.6 171.9h5zM148.6 177h3.1zM174 171.9h5zM174 169.4h5zM174 166.8h5zM174 164.3h5zM176 179.5h3zM179 164.3h17.8zM179 166.8h17.8zM179 169.4h17.8zM179 171.9h17.8zM179 179.5h2.6z"/>
<path d="M181.6 179.5v15.3zM186.7 177.5h6.6zM196.8 164.3l2.6 2.5zM196.8 166.8l2.6 2.6zM196.8 169.4l2.6 2.5zM196.8 171.9l2.6 2.5zM209.5 177h25.4zM219.7 161.7l-2.6 2.6zM219.7 164.3l-2.6 2.5zM219.7 166.8l-2.6 2.6zM219.7 169.4l-2.6 2.5zM219.7 171.9l-2.6 2.5z"/>
<path d="M234.9 177h2.6zM234.9 177v2.5zM237.5 177h3.1zM237.5 161.7h5zM237.5 164.3h5zM237.5 166.8h5zM237.5 169.4h5zM237.5 171.9h5zM237.5 179.5h3.1zM219.7 161.7h17.8zM219.7 164.3h17.8zM219.7 166.8h17.8z"/>
<path d="M219.7 169.4h17.8zM219.7 171.9h17.8zM234.9 179.5h2.6zM257.8 171.9h5.1zM257.8 169.4h5.1zM257.8 166.8h5.1zM257.8 164.3h5.1zM257.8 161.7h5.1zM262.9 161.7h20.3zM262.9 164.3h20.3zM262.9 166.8h20.3zM262.9 169.4h20.3z"/>
<path d="M262.9 171.9h20.3zM285.7 161.7l-2.5 2.6zM285.7 164.3l-2.5 2.5zM285.7 166.8l-2.5 2.6zM285.7 169.4l-2.5 2.5zM306 161.7l-2.5 2.6zM306 164.3l-2.5 2.5zM303.5 169.4l2.5-2.6zM306 169.4l-2.5 2.5zM306 171.9l-2.5 2.5zM321.3 177h2.5zM321.3 177v2.5z"/>
<path d="M321.3 179.5v2.6zM323.8 177h3.1zM323.8 161.7h5.1zM323.8 164.3h5.1zM323.8 166.8h5.1zM323.8 169.4h5.1zM323.8 171.9h5.1zM323.8 179.5h3.1zM321.3 179.5h2.5zM306 161.7h17.8zM306 164.3h17.8zM306 166.8h17.8z"/>
<path d="M306 169.4h17.8zM306 171.9h17.8zM344.1 171.9h5.1zM344.1 169.4h5.1zM344.1 166.8h5.1zM344.1 164.3h5.1zM344.1 161.7h5.1zM359.4 161.7h2.5zM359.4 164.3h2.5zM359.4 166.8h2.5zM359.4 169.4h2.5zM359.4 171.9h2.5z"/>
<path d="M349.2 161.7h10.2zM349.2 164.3h10.2zM349.2 166.8h10.2zM349.2 169.4h10.2zM349.2 171.9h10.2zM400 173.7h3.8zM102.9 187.1h45.7zM102.9 187.1v40.6zM113 184.6h35.6zM113 194.8v30.4zM118.1 182.1h30.5zM118.1 197.3v25.4z"/>
<path d="M134.1 180h6.8zM134.1 195.3h6.8zM134.3 182.6h6.6zM134.3 192.7h6.6zM148.6 182.1h5zM148.6 184.6h5zM148.6 187.1h5zM176 182.1h3zM179 182.1h5.1zM113 194.8h68.6zM184.1 182.1v15.2zM118.1 197.3h66z"/>
<path d="M186.7 180h6.8zM321.3 182.1v2.5zM107.9 217.6h40.7zM123.2 202.4l2.5 2.5zM123.2 204.9l2.5 2.5zM123.2 207.4l2.5 2.6zM123.2 210l2.5 2.5zM125.7 204.9h22.9zM125.7 207.4h22.9zM125.7 210h22.9zM125.7 212.5h22.9zM135 215.6h5.9z"/>
<path d="M148.6 204.9h5zM148.6 207.4h5zM148.6 210h5zM148.6 212.5h5zM148.6 217.6h3.1zM174 212.5h5zM174 210h5zM174 207.4h5zM174 204.9h5zM179 204.9h17.8zM179 207.4h17.8zM179 210h17.8z"/>
<path d="M179 212.5h17.8zM196.8 204.9l2.6 2.5zM196.8 207.4l2.6 2.6zM196.8 210l2.6 2.5zM196.8 212.5l2.6 2.5zM16.5 224.2h3.8zM102.9 227.7h45.7zM113 225.2h35.6zM118.1 222.7h30.5zM134.1 220.7h6.8zM134.3 223.2h6.6zM148.6 222.7h5z"/>
<path d="M148.6 225.2h5zM148.6 227.7h5zM176 220.1h3zM176 222.7h3zM400 224.2h3.8zM29.2 253.1v2.6zM29.2 257.7v.5zM29.2 255.7v.5zM29.2 250.6v2.5zM36.8 253.1v2.6zM36.8 257.7v.5zM36.8 255.7v.5z"/>
<path d="M36.8 250.6v2.5zM29.2 250.6h7.6zM44.4 253.1v2.6zM44.4 257.7v.5zM44.4 255.7v.5zM36.8 250.6h7.6zM44.4 250.6v2.5zM52.1 253.1v2.6zM52.1 257.7v.5zM52.1 255.7v.5zM44.4 250.6h7.7zM52.1 250.6v2.5z"/>
<path d="M59.7 253.1v2.6zM59.7 257.7v.5zM59.7 255.7v.5zM52.1 250.6h7.6zM59.7 250.6v2.5zM67.3 253.1v2.6zM67.3 257.7v.5zM67.3 255.7v.5zM59.7 250.6h7.6zM67.3 250.6v2.5zM74.9 253.1v2.6zM74.9 257.7v.5z"/>
<path d="M74.9 255.7v.5zM67.3 250.6h7.6zM74.9 250.6v2.5zM82.5 245.5v2.6zM82.5 253.1v2.6zM82.5 257.7v.5zM82.5 255.7v.5zM74.9 250.6h7.6zM82.5 248.1v2.5zM82.5 250.6v2.5zM92.7 245.5v2.6zM92.7 253.1v2.6z"/>
<path d="M92.7 255.7v.5zM92.7 257.7v.5zM92.7 248.1v5zM20.3 274.7h379.7zM29.2 265.8v2.6zM29.2 258.2v2.6zM29.2 260.8v2.5zM29.2 263.3h7.6zM29.2 263.3v2.5zM36.8 258.2v2.6zM36.8 260.8v2.5zM44.4 258.2v2.6z"/>
<path d="M36.8 263.3h7.6zM44.4 260.8v2.5zM52.1 258.2v2.6zM44.4 263.3h7.7zM52.1 260.8v2.5zM59.7 258.2v2.6zM52.1 263.3h7.6zM59.7 260.8v2.5zM67.3 258.2v2.6zM59.7 263.3h7.6zM67.3 260.8v2.5zM67.8 274.7v3.8z"/>
<path d="M74.9 258.2v2.6zM67.3 263.3h7.6zM74.9 260.8v2.5zM82.5 258.2v2.6zM74.9 263.3h7.6zM82.5 260.8v2.5zM92.7 258.2v2.6zM92.7 263.3v2.5zM92.7 260.8v2.5zM115.3 274.7v3.8zM162.7 274.7v3.8zM210.2 274.7v3.8z"/>
<path d="M257.6 274.7v3.8zM305.1 274.7v3.8zM352.5 274.7v3.8zM400 264.5v.1zM400 268.4v6.2zM400 274.6h.1zM400 22.1v252.6z"/>
<circle cx="52.1" cy="47.5" r=".51"/>
<circle cx="102.9" cy="52.5" r=".51"/>
<circle cx="107.9" cy="95.7" r=".51"/>
<circle cx="102.9" cy="105.9" r=".51"/>
<circle cx="107.9" cy="136.3" r=".51"/>
<circle cx="209.5" cy="138.9" r=".51"/>
<circle cx="234.9" cy="138.9" r=".51"/>
<circle cx="102.9" cy="146.5" r=".51"/>
<circle cx="321.3" cy="141.4" r=".51"/>
<circle cx="107.9" cy="177" r=".51"/>
<circle cx="234.9" cy="177" r=".51"/>
<circle cx="321.3" cy="179.5" r=".51"/>
<circle cx="102.9" cy="187.1" r=".51"/>
<circle cx="36.8" cy="250.6" r=".51"/>
<circle cx="44.4" cy="250.6" r=".51"/>
<circle cx="52.1" cy="250.6" r=".51"/>
<circle cx="59.7" cy="250.6" r=".51"/>
<circle cx="67.3" cy="250.6" r=".51"/>
<circle cx="74.9" cy="250.6" r=".51"/>
<circle cx="82.5" cy="250.6" r=".51"/>
<circle cx="29.2" cy="263.3" r=".51"/>
<circle cx="36.8" cy="263.3" r=".51"/>
<circle cx="44.4" cy="263.3" r=".51"/>
<circle cx="52.1" cy="263.3" r=".51"/>
<circle cx="59.7" cy="263.3" r=".51"/>
<circle cx="67.3" cy="263.3" r=".51"/>
<circle cx="74.9" cy="263.3" r=".51"/>
</g>
<g fill="#000" stroke="#000" stroke-width=".28">
<path d="M32.6 35.8v3zM33.1 30.7v3zM33.1 30.7h9.8zM33.1 33.7h9.8zM32.6 35.8h10.3zM32.6 38.8h10.3zM42.9 30.7l1.5 1.5zM44.4 32.2l-1.5 1.5zM42.9 35.8l1.5 1.5zM44.4 37.3l-1.5 1.5zM30 40.9v3zM30.2 51v3.1z"/>
<path d="M33.3 45.9v3.1zM30.2 51h12.7zM30.2 54.1h12.7zM33.3 45.9h9.6zM33.3 49h9.6zM30 40.9h12.9zM30 43.9h12.9zM42.9 51l1.5 1.5zM44.4 52.5l-1.5 1.6zM42.9 45.9l1.5 1.6zM44.4 47.5l-1.5 1.5zM42.9 40.9l1.5 1.5z"/>
<path d="M44.4 42.4l-1.5 1.5zM374.6 52.5l1.5-1.5zM374.6 52.5l1.5 1.6zM374.6 47.5l1.5-1.6zM374.6 47.5l1.5 1.5zM376.1 51h12.8zM376.1 54.1h12.8zM376.1 45.9h11.1zM376.1 49h11.1zM387.2 45.9v3.1zM388.9 51v3.1zM65.4 116h3.8z"/>
<path d="M319.4 146.5h3.8zM319.4 184.6h3.8zM82.5 245.5l-1.2 1.9zM82.5 245.5l1.3 1.9zM92.7 245.5l-1.3 1.9zM92.7 245.5l1.3 1.9zM313.7 249.3h86.3zM313.7 254.4h86.3zM313.7 259.5h58.4zM372.1 259.5h27.9zM372.1 259.5v5.1zM27.3 268.4h3.8z"/>
<path d="M90.8 265.8h3.8zM313.7 264.6h58.4zM313.7 269.7h86.3zM372.1 264.6h27.9zM400 268.4v1.3z"/>
</g>
<g fill="none" stroke="#000" stroke-width=".21">
<circle cx="152.7" cy="95.7" r=".99"/>
<circle cx="175" cy="98.2" r=".99"/>
<circle cx="73.9" cy="110.9" r=".99"/>
<circle cx="91.1" cy="105.9" r=".99"/>
<circle cx="91.1" cy="108.4" r=".99"/>
<circle cx="91.1" cy="103.3" r=".99"/>
<circle cx="91.1" cy="110.9" r=".99"/>
<circle cx="175" cy="100.8" r=".99"/>
<circle cx="152.7" cy="136.3" r=".99"/>
<circle cx="175" cy="138.9" r=".99"/>
<circle cx="241.5" cy="138.9" r="1"/>
<circle cx="327.9" cy="138.9" r="1"/>
<circle cx="175" cy="141.4" r=".99"/>
<circle cx="241.5" cy="141.4" r="1"/>
<circle cx="327.9" cy="141.4" r="1"/>
<circle cx="152.7" cy="177" r=".99"/>
<circle cx="175" cy="179.5" r=".99"/>
<circle cx="241.5" cy="177" r="1"/>
<circle cx="241.5" cy="179.5" r="1"/>
<circle cx="327.9" cy="177" r="1"/>
<circle cx="327.9" cy="179.5" r="1"/>
<circle cx="175" cy="182.1" r=".99"/>
<circle cx="152.7" cy="217.6" r=".99"/>
<circle cx="175" cy="220.1" r=".99"/>
<circle cx="175" cy="222.7" r=".99"/>
</g>
<g fill="#000" stroke="#000" stroke-width=".61">
<path d="M20.3 22.1v252.6zM20.3 22.1h379.7zM153.6 80.5v27.9zM153.6 80.5h20.4zM74.9 113.5h15.3zM74.9 100.8v12.7zM90.2 100.8v12.7zM74.9 100.8h15.3zM153.6 108.4h20.4zM174 80.5v27.9zM242.5 113.5v30.5zM242.5 113.5h15.3z"/>
<path d="M328.9 113.5v30.5zM328.9 113.5h15.2zM361.9 116h1.3zM361.9 118.6h1.3zM153.6 121.1v27.9zM153.6 121.1h20.4zM361.9 121.1h1.3zM361.9 123.6h1.3zM361.9 126.2h1.3zM361.9 128.7h1.3zM361.9 131.3h1.3zM361.9 133.8h1.3z"/>
<path d="M153.6 149h20.4zM174 121.1v27.9zM242.5 144h15.3zM242.5 151.6v30.5zM257.8 113.5v30.5zM242.5 151.6h15.3zM328.9 144h15.2zM328.9 151.6v30.5zM344.1 113.5v30.5zM328.9 151.6h15.2zM361.9 154.1h1.3zM361.9 156.7h1.3z"/>
<path d="M361.9 159.2h1.3zM153.6 161.7v28zM153.6 161.7h20.4zM361.9 161.7h1.3zM361.9 164.3h1.3zM361.9 166.8h1.3zM361.9 169.4h1.3zM361.9 171.9h1.3zM153.6 189.7h20.4zM174 161.7v28zM242.5 182.1h15.3zM257.8 151.6v30.5z"/>
<path d="M328.9 182.1h15.2zM344.1 151.6v30.5zM153.6 202.4v27.9zM153.6 202.4h20.4zM153.6 230.3h20.4zM174 202.4v27.9zM283.2 244.3v30.4zM313.7 254.4v5.1zM313.7 249.3v5.1zM313.7 244.3v5zM313.7 244.3h86.3zM283.2 244.3h30.5z"/>
<path d="M400 254.4v5.1zM400 249.3v5.1zM400 244.3v5zM400 22.1v222.2zM20.3 274.7h262.9zM283.2 274.7h30.5zM313.7 274.7h86.3zM313.7 269.7v5zM313.7 264.6v5.1zM313.7 259.5v5.1zM400 268.4v6.3zM400 264.6v3.8z"/>
<path d="M400 259.5v5.1z"/>
</g>
<g fill="#000" stroke="#000" stroke-width=".21">
<path d="M27.2 256.2h4v.5h-4zM27.2 257.2h4v.5h-4zM34.8 256.2h4.1v.5h-4.1zM34.8 257.2h4.1v.5h-4.1zM42.4 256.2h4.1v.5h-4.1zM42.4 257.2h4.1v.5h-4.1zM50 256.2h4.1v.5h-4.1zM50 257.2h4.1v.5h-4.1zM57.7 256.2h4v.5h-4zM57.7 257.2h4v.5h-4zM65.3 256.2h4v.5h-4zM65.3 257.2h4v.5h-4z"/>
<path d="M72.9 256.2h4.1v.5h-4.1zM72.9 257.2h4.1v.5h-4.1zM80.5 256.2h4.1v.5h-4.1zM80.5 257.2h4.1v.5h-4.1zM90.7 257.2h4v.5h-4zM90.7 256.2h4v.5h-4zM252.7 253.1h25.4v10.2h-25.4z"/>
</g>
<path d="M16.5 18.2v260.3zM16.5 18.2h387.3zM16.5 278.5h387.3zM403.8 18.2v260.3z" fill="#000" stroke="#000" stroke-width=".32"/>
<g fill="#000" stroke="#000" stroke-width=".76">
<path d="M44.4 60.2h73.7zM118.1 60.2h256.5zM118.1 60.2l5.1 5zM280.6 60.2l5.1 5zM285.7 65.2v104.2zM123.2 65.2v144.8zM199.4 85.5v132.1zM217.1 118.6v99zM303.5 118.6v99zM204.4 222.7h170.2zM199.4 217.6l5 5.1zM217.1 217.6l5.1 5.1z"/>
<path d="M303.5 217.6l5.1 5.1z"/>
</g>
<path d="M222.2 253.1v10.2zM222.2 253.1h55.9zM222.2 263.3v7.6zM222.2 270.9h55.9zM222.2 263.3h55.9zM278.1 263.3v7.6zM278.1 253.1v10.2z" fill="#000" stroke="#000" stroke-width=".42"/>
<use href="#words"/>
</svg>
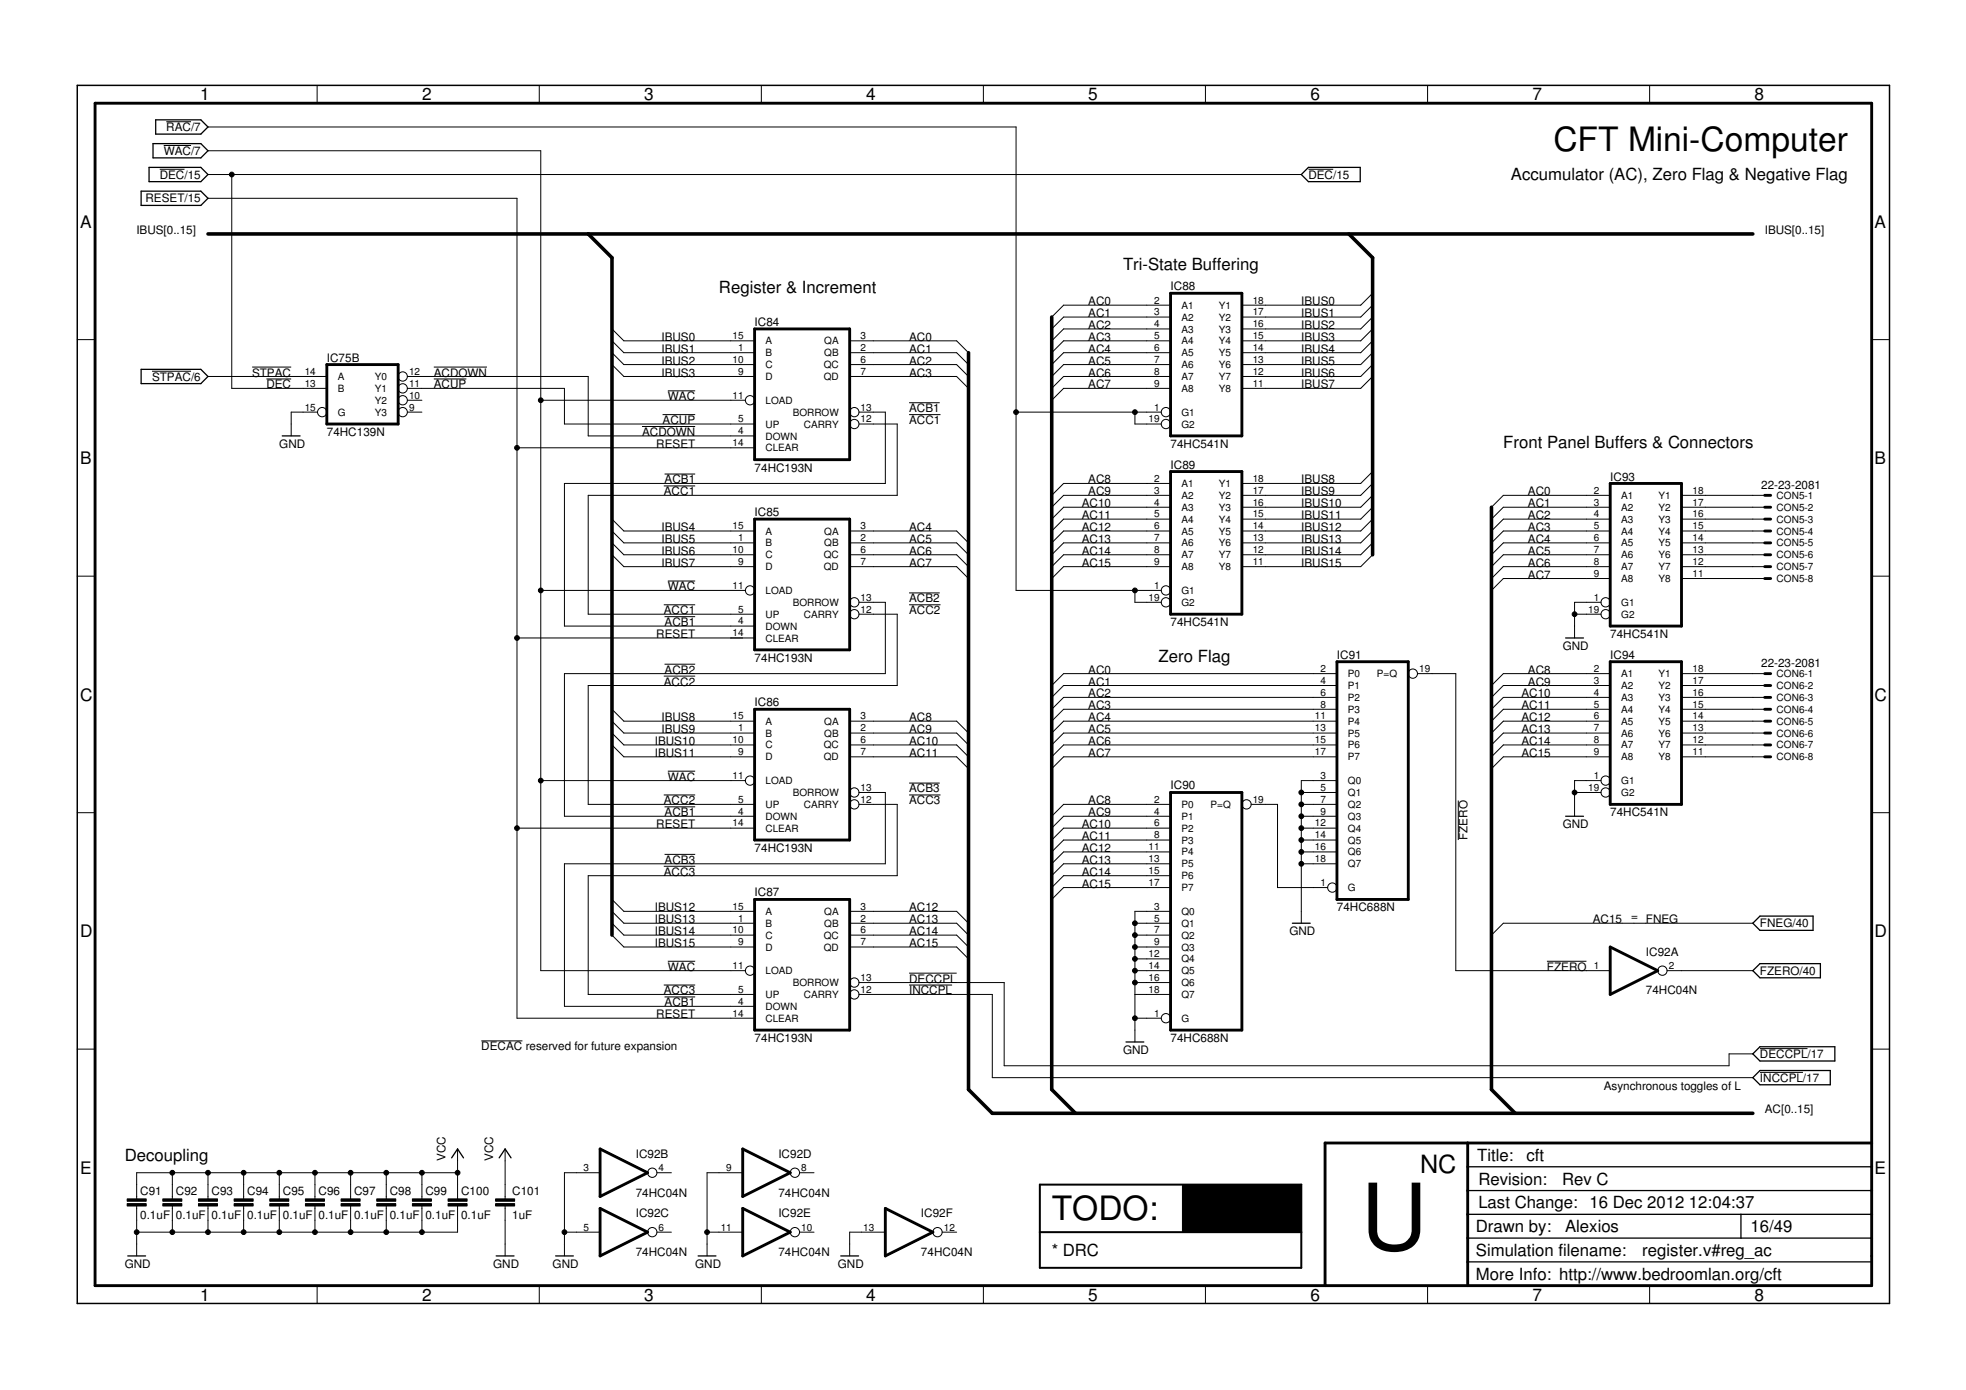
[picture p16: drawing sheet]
<svg xmlns="http://www.w3.org/2000/svg" width="420mm" height="297mm" viewBox="0 0 420 297" stroke-linecap="round" stroke-linejoin="round" font-family="sans-serif">
<defs><g id="words">
<text font-size="19.7" x="290.8" y="267.1">U</text>
<g font-size="7.2">
<text x="332" y="32.2">CFT Mini-Computer</text>
<text x="224.8" y="260.8">TODO:</text>
</g>
<text font-size="5.4" x="303.5" y="250.6">NC</text>
<g font-size="3.7">
<text x="42.7" y="21.5">1</text>
<text x="90.2" y="21.5">2</text>
<text x="137.7" y="21.5">3</text>
<text x="185.1" y="21.5">4</text>
<text x="232.6" y="21.5">5</text>
<text x="280" y="21.5">6</text>
<text x="327.5" y="21.5">7</text>
<text x="375" y="21.5">8</text>
<text x="17.1" y="48.6">A</text>
<text x="400.6" y="48.6">A</text>
<text x="17.1" y="99.2">B</text>
<text x="400.6" y="99.2">B</text>
<text x="17.1" y="149.7">C</text>
<text x="400.6" y="149.7">C</text>
<text x="17.1" y="200.2">D</text>
<text x="400.6" y="200.2">D</text>
<text x="17.1" y="250.8">E</text>
<text x="400.6" y="250.8">E</text>
<text x="42.7" y="277.9">1</text>
<text x="90.2" y="277.9">2</text>
<text x="137.7" y="277.9">3</text>
<text x="185.1" y="277.9">4</text>
<text x="232.6" y="277.9">5</text>
<text x="280" y="277.9">6</text>
<text x="327.5" y="277.9">7</text>
<text x="375" y="277.9">8</text>
</g>
<g font-size="3.6">
<text x="322.9" y="38.6">Accumulator (AC), Zero Flag &amp; Negative Flag</text>
<text x="240" y="57.6">Tri-State Buffering</text>
<text x="153.7" y="62.7">Register &amp; Increment</text>
<text x="321.3" y="95.7">Front Panel Buffers &amp; Connectors</text>
<text x="247.6" y="141.4">Zero Flag</text>
<text x="26.7" y="248.1">Decoupling</text>
<text x="315.7" y="248.1">Title:</text>
<text x="326.2" y="248.2">cft</text>
<text x="315.9" y="253.2">Revision:</text>
<text x="333.8" y="253.3">Rev C</text>
<text x="315.4" y="263.3">Drawn by:</text>
<text x="315.9" y="258.2">Last Change: 16 Dec 2012</text>
<text x="334.5" y="263.3">Alexios</text>
<text x="361" y="258.1">12:04:37</text>
<text x="374.1" y="263.2">16/49</text>
<text x="224.8" y="268.4">* DRC</text>
<text x="315.4" y="268.4">Simulation filename:</text>
<text x="351" y="268.4">register.v#reg_ac</text>
<text x="315.4" y="273.5">More Info: http://www.bedroomlan.org/cft</text>
</g>
<g font-size="2.5">
<text x="35.5" y="28">RAC/7</text>
<text x="35" y="33.1">WAC/7</text>
<text x="34.1" y="38.2">DEC/15</text>
<text x="279.6" y="38.2">DEC/15</text>
<text x="31.1" y="43.3">RESET/15</text>
<text x="29.1" y="50">IBUS[0..15]</text>
<text x="377.1" y="50">IBUS[0..15]</text>
<text x="232.6" y="65.2">AC0</text>
<text x="250.2" y="62">IC88</text>
<text x="278.1" y="65.2">IBUS0</text>
<text x="161.3" y="69.7">IC84</text>
<text x="232.6" y="67.8">AC1</text>
<text x="232.6" y="70.3">AC2</text>
<text x="278.1" y="67.8">IBUS1</text>
<text x="278.1" y="70.3">IBUS2</text>
<text x="69.8" y="77.3">IC75B</text>
<text x="141.4" y="72.8">IBUS0</text>
<text x="141.4" y="75.4">IBUS1</text>
<text x="141.4" y="77.9">IBUS2</text>
<text x="194.3" y="72.8">AC0</text>
<text x="194.3" y="75.4">AC1</text>
<text x="194.3" y="77.9">AC2</text>
<text x="232.6" y="72.8">AC3</text>
<text x="232.6" y="75.4">AC4</text>
<text x="232.6" y="77.9">AC5</text>
<text x="278.1" y="72.8">IBUS3</text>
<text x="278.1" y="75.4">IBUS4</text>
<text x="278.1" y="77.9">IBUS5</text>
<text x="32.5" y="81.3">STPAC/6</text>
<text x="53.9" y="80.5">STPAC</text>
<text x="56.9" y="83">DEC</text>
<text x="92.7" y="80.5">ACDOWN</text>
<text x="92.7" y="83">ACUP</text>
<text x="141.4" y="80.5">IBUS3</text>
<text x="194.3" y="80.5">AC3</text>
<text x="232.6" y="80.5">AC6</text>
<text x="232.6" y="83">AC7</text>
<text x="278.1" y="80.5">IBUS6</text>
<text x="278.1" y="83">IBUS7</text>
<text x="142.7" y="85.5">WAC</text>
<text x="194.3" y="88.1">ACB1</text>
<text x="59.7" y="95.7">GND</text>
<text x="69.8" y="93.2">74HC139N</text>
<text x="137.2" y="93.2">ACDOWN</text>
<text x="140.3" y="95.7">RESET</text>
<text x="141.6" y="90.6">ACUP</text>
<text x="194.3" y="90.6">ACC1</text>
<text x="250.2" y="95.7">74HC541N</text>
<text x="161.3" y="100.8">74HC193N</text>
<text x="250.2" y="100.1">IC89</text>
<text x="141.9" y="105.9">ACC1</text>
<text x="142" y="103.3">ACB1</text>
<text x="232.6" y="103.3">AC8</text>
<text x="232.6" y="105.9">AC9</text>
<text x="278.1" y="103.3">IBUS8</text>
<text x="278.1" y="105.9">IBUS9</text>
<text x="326.5" y="105.9">AC0</text>
<text x="344.1" y="102.7">IC93</text>
<text x="376.4" y="104.5">22-23-2081</text>
<text x="141.4" y="113.5">IBUS4</text>
<text x="161.3" y="110.3">IC85</text>
<text x="194.3" y="113.5">AC4</text>
<text x="231.2" y="108.4">AC10</text>
<text x="231.2" y="110.9">AC11</text>
<text x="231.2" y="113.5">AC12</text>
<text x="278.1" y="108.4">IBUS10</text>
<text x="278.1" y="110.9">IBUS11</text>
<text x="278.1" y="113.5">IBUS12</text>
<text x="326.5" y="108.4">AC1</text>
<text x="326.5" y="110.9">AC2</text>
<text x="326.5" y="113.5">AC3</text>
<text x="141.4" y="116">IBUS5</text>
<text x="141.4" y="118.6">IBUS6</text>
<text x="194.3" y="116">AC5</text>
<text x="194.3" y="118.6">AC6</text>
<text x="231.2" y="116">AC13</text>
<text x="231.2" y="118.6">AC14</text>
<text x="278.1" y="116">IBUS13</text>
<text x="278.1" y="118.6">IBUS14</text>
<text x="326.5" y="116">AC4</text>
<text x="326.5" y="118.6">AC5</text>
<text x="141.4" y="121.1">IBUS7</text>
<text x="194.3" y="121.1">AC7</text>
<text x="231.2" y="121.1">AC15</text>
<text x="278.1" y="121.1">IBUS15</text>
<text x="326.5" y="121.1">AC6</text>
<text x="326.5" y="123.6">AC7</text>
<text x="141.9" y="131.3">ACC1</text>
<text x="142.7" y="126.2">WAC</text>
<text x="194.3" y="131.3">ACC2</text>
<text x="194.3" y="128.7">ACB2</text>
<text x="140.3" y="136.3">RESET</text>
<text x="142" y="133.8">ACB1</text>
<text x="250.2" y="133.8">74HC541N</text>
<text x="344.1" y="136.3">74HC541N</text>
<text x="142" y="144">ACB2</text>
<text x="161.3" y="141.4">74HC193N</text>
<text x="232.6" y="144">AC0</text>
<text x="285.7" y="140.8">IC91</text>
<text x="326.5" y="144">AC8</text>
<text x="334" y="138.9">GND</text>
<text x="344.1" y="140.8">IC94</text>
<text x="376.4" y="142.6">22-23-2081</text>
<text x="141.9" y="146.5">ACC2</text>
<text x="232.6" y="146.5">AC1</text>
<text x="232.6" y="149">AC2</text>
<text x="325.1" y="149">AC10</text>
<text x="326.5" y="146.5">AC9</text>
<text x="141.4" y="154.1">IBUS8</text>
<text x="161.3" y="150.9">IC86</text>
<text x="194.3" y="154.1">AC8</text>
<text x="232.6" y="151.6">AC3</text>
<text x="232.6" y="154.1">AC4</text>
<text x="325.1" y="151.6">AC11</text>
<text x="325.1" y="154.1">AC12</text>
<text x="140" y="159.2">IBUS10</text>
<text x="140" y="161.7">IBUS11</text>
<text x="141.4" y="156.6">IBUS9</text>
<text x="194.3" y="156.6">AC9</text>
<text x="194.3" y="159.2">AC10</text>
<text x="194.3" y="161.7">AC11</text>
<text x="232.6" y="156.6">AC5</text>
<text x="232.6" y="159.2">AC6</text>
<text x="232.6" y="161.7">AC7</text>
<text x="325.1" y="156.6">AC13</text>
<text x="325.1" y="159.2">AC14</text>
<text x="325.1" y="161.7">AC15</text>
<text x="142.7" y="166.8">WAC</text>
<text x="141.9" y="171.9">ACC2</text>
<text x="194.3" y="171.9">ACC3</text>
<text x="194.3" y="169.3">ACB3</text>
<text x="232.6" y="171.9">AC8</text>
<text x="250.2" y="168.7">IC90</text>
<text x="140.3" y="177">RESET</text>
<text x="142" y="174.4">ACB1</text>
<text x="231.2" y="177">AC10</text>
<text x="231.2" y="179.5">AC11</text>
<text x="232.6" y="174.4">AC9</text>
<text x="313.7" y="179.5" transform="rotate(-90 313.7 179.5)">FZERO</text>
<text x="334" y="177">GND</text>
<text x="344.1" y="174.4">74HC541N</text>
<text x="142" y="184.6">ACB3</text>
<text x="161.3" y="182">74HC193N</text>
<text x="231.2" y="182">AC12</text>
<text x="231.2" y="184.6">AC13</text>
<text x="141.9" y="187.1">ACC3</text>
<text x="161.3" y="191.6">IC87</text>
<text x="231.2" y="187.1">AC14</text>
<text x="231.2" y="189.7">AC15</text>
<text x="140" y="194.7">IBUS12</text>
<text x="140" y="197.3">IBUS13</text>
<text x="194.3" y="194.7">AC12</text>
<text x="194.3" y="197.3">AC13</text>
<text x="285.7" y="194.7">74HC688N</text>
<text x="340.4" y="197.3">AC15</text>
<text x="348.6" y="196.6">=</text>
<text x="351.7" y="197.3">FNEG</text>
<text x="140" y="199.8">IBUS14</text>
<text x="140" y="202.4">IBUS15</text>
<text x="194.3" y="199.8">AC14</text>
<text x="194.3" y="202.4">AC15</text>
<text x="275.6" y="199.8">GND</text>
<text x="376.1" y="198.2">FNEG/40</text>
<text x="142.7" y="207.4">WAC</text>
<text x="194.3" y="210">DECCPL</text>
<text x="330.6" y="207.4">FZERO</text>
<text x="351.7" y="204.3">IC92A</text>
<text x="376.1" y="208.3">FZERO/40</text>
<text x="141.9" y="212.5">ACC3</text>
<text x="142" y="215.1">ACB1</text>
<text x="194.3" y="212.5">INCCPL</text>
<text x="351.7" y="212.5">74HC04N</text>
<text x="140.3" y="217.6">RESET</text>
<text x="102.9" y="224.5">DECAC reserved for future expansion</text>
<text x="161.3" y="222.7">74HC193N</text>
<text x="240" y="225.2">GND</text>
<text x="250.2" y="222.7">74HC688N</text>
<text x="376.1" y="226.1">DECCPL/17</text>
<text x="342.8" y="232.8">Asynchronous toggles of L</text>
<text x="376.1" y="231.2">INCCPL/17</text>
<text x="377.1" y="237.9">AC[0..15]</text>
<text x="95.2" y="248.1" transform="rotate(-90 95.2 248.1)">VCC</text>
<text x="105.4" y="248.1" transform="rotate(-90 105.4 248.1)">VCC</text>
<text x="135.9" y="247.4">IC92B</text>
<text x="166.4" y="247.4">IC92D</text>
<text x="30" y="255.3">C91</text>
<text x="37.6" y="255.3">C92</text>
<text x="45.2" y="255.3">C93</text>
<text x="52.8" y="255.3">C94</text>
<text x="60.4" y="255.3">C95</text>
<text x="68.1" y="255.3">C96</text>
<text x="75.7" y="255.3">C97</text>
<text x="83.3" y="255.3">C98</text>
<text x="90.9" y="255.3">C99</text>
<text x="98.5" y="255.3">C100</text>
<text x="109.5" y="255.3">C101</text>
<text x="135.9" y="255.7">74HC04N</text>
<text x="166.4" y="255.7">74HC04N</text>
<text x="30" y="260.4">0.1uF</text>
<text x="37.6" y="260.4">0.1uF</text>
<text x="45.2" y="260.4">0.1uF</text>
<text x="52.8" y="260.4">0.1uF</text>
<text x="60.4" y="260.4">0.1uF</text>
<text x="68.1" y="260.4">0.1uF</text>
<text x="75.7" y="260.4">0.1uF</text>
<text x="83.3" y="260.4">0.1uF</text>
<text x="90.9" y="260.4">0.1uF</text>
<text x="98.5" y="260.4">0.1uF</text>
<text x="109.5" y="260.4">1uF</text>
<text x="135.9" y="260.1">IC92C</text>
<text x="166.4" y="260.1">IC92E</text>
<text x="196.8" y="260.1">IC92F</text>
<text x="135.9" y="268.4">74HC04N</text>
<text x="166.4" y="268.4">74HC04N</text>
<text x="196.8" y="268.4">74HC04N</text>
<text x="26.7" y="270.9">GND</text>
<text x="105.4" y="270.9">GND</text>
<text x="118.1" y="270.9">GND</text>
<text x="148.6" y="270.9">GND</text>
<text x="179.1" y="270.9">GND</text>
</g>
<g font-size="2.1">
<text x="246.6" y="64.9">2</text>
<text x="252.5" y="66">A1</text>
<text x="260.5" y="66">Y1</text>
<text x="267.7" y="64.9">18</text>
<text x="246.6" y="67.4">3</text>
<text x="246.6" y="69.9">4</text>
<text x="252.5" y="68.5">A2</text>
<text x="252.5" y="71.1">A3</text>
<text x="260.5" y="71.1">Y3</text>
<text x="260.5" y="68.5">Y2</text>
<text x="267.7" y="69.9">16</text>
<text x="267.7" y="67.4">17</text>
<text x="156.6" y="72.5">15</text>
<text x="156.6" y="77.6">10</text>
<text x="157.8" y="75">1</text>
<text x="163.6" y="73.6">A</text>
<text x="163.6" y="76.1">B</text>
<text x="176.2" y="76.1">QB</text>
<text x="176.2" y="73.6">QA</text>
<text x="183.9" y="77.6">6</text>
<text x="183.9" y="75">2</text>
<text x="183.9" y="72.5">3</text>
<text x="246.6" y="72.5">5</text>
<text x="246.6" y="75">6</text>
<text x="246.6" y="77.6">7</text>
<text x="252.5" y="73.6">A4</text>
<text x="252.5" y="76.1">A5</text>
<text x="260.5" y="76.1">Y5</text>
<text x="260.5" y="73.6">Y4</text>
<text x="267.7" y="77.6">13</text>
<text x="267.7" y="75">14</text>
<text x="267.7" y="72.5">15</text>
<text x="65.1" y="80.1">14</text>
<text x="65.1" y="82.6">13</text>
<text x="72.2" y="81.2">A</text>
<text x="72.2" y="83.8">B</text>
<text x="80.1" y="81.2">Y0</text>
<text x="80.1" y="83.8">Y1</text>
<text x="87.4" y="80.1">12</text>
<text x="87.4" y="82.6">11</text>
<text x="157.8" y="80.1">9</text>
<text x="163.6" y="78.7">C</text>
<text x="163.6" y="81.2">D</text>
<text x="176" y="81.2">QD</text>
<text x="176" y="78.7">QC</text>
<text x="183.9" y="80.1">7</text>
<text x="246.6" y="80.1">8</text>
<text x="246.6" y="82.6">9</text>
<text x="252.5" y="78.7">A6</text>
<text x="252.5" y="81.2">A7</text>
<text x="252.5" y="83.8">A8</text>
<text x="260.5" y="83.8">Y8</text>
<text x="260.5" y="81.2">Y7</text>
<text x="260.5" y="78.7">Y6</text>
<text x="267.7" y="82.6">11</text>
<text x="267.7" y="80.1">12</text>
<text x="65.1" y="87.7">15</text>
<text x="72.2" y="88.8">G</text>
<text x="80.1" y="86.3">Y2</text>
<text x="80.1" y="88.8">Y3</text>
<text x="87.4" y="85.2">10</text>
<text x="87.4" y="87.7">9</text>
<text x="156.6" y="85.2">11</text>
<text x="163.6" y="86.3">LOAD</text>
<text x="169.4" y="88.8">BORROW</text>
<text x="183.9" y="87.7">13</text>
<text x="246.6" y="87.7">1</text>
<text x="252.5" y="88.8">G1</text>
<text x="156.6" y="95.3">14</text>
<text x="157.8" y="90.3">5</text>
<text x="157.8" y="92.8">4</text>
<text x="163.6" y="91.4">UP</text>
<text x="163.6" y="93.9">DOWN</text>
<text x="171.8" y="91.4">CARRY</text>
<text x="183.9" y="90.3">12</text>
<text x="245.5" y="90.3">19</text>
<text x="252.5" y="91.4">G2</text>
<text x="163.6" y="96.5">CLEAR</text>
<text x="246.6" y="103">2</text>
<text x="246.6" y="105.5">3</text>
<text x="252.5" y="104.1">A1</text>
<text x="252.5" y="106.6">A2</text>
<text x="260.5" y="106.6">Y2</text>
<text x="260.5" y="104.1">Y1</text>
<text x="267.7" y="105.5">17</text>
<text x="267.7" y="103">18</text>
<text x="340.6" y="105.5">2</text>
<text x="346.5" y="106.6">A1</text>
<text x="354.4" y="106.6">Y1</text>
<text x="361.7" y="105.5">18</text>
<text x="379.7" y="106.6">CON5-1</text>
<text x="156.6" y="113.1">15</text>
<text x="183.9" y="113.1">3</text>
<text x="246.6" y="108">4</text>
<text x="246.6" y="110.6">5</text>
<text x="246.6" y="113.1">6</text>
<text x="252.5" y="109.2">A3</text>
<text x="252.5" y="111.7">A4</text>
<text x="260.5" y="111.7">Y4</text>
<text x="260.5" y="109.2">Y3</text>
<text x="267.7" y="113.1">14</text>
<text x="267.7" y="110.6">15</text>
<text x="267.7" y="108">16</text>
<text x="340.6" y="108">3</text>
<text x="340.6" y="110.6">4</text>
<text x="340.6" y="113.1">5</text>
<text x="346.5" y="109.2">A2</text>
<text x="346.5" y="111.7">A3</text>
<text x="354.4" y="111.7">Y3</text>
<text x="354.4" y="109.2">Y2</text>
<text x="361.7" y="113.1">15</text>
<text x="361.7" y="110.6">16</text>
<text x="361.7" y="108">17</text>
<text x="379.7" y="109.2">CON5-2</text>
<text x="379.7" y="111.7">CON5-3</text>
<text x="156.6" y="118.2">10</text>
<text x="157.8" y="115.7">1</text>
<text x="163.6" y="114.2">A</text>
<text x="163.6" y="116.8">B</text>
<text x="163.6" y="119.3">C</text>
<text x="176" y="119.3">QC</text>
<text x="176.2" y="116.8">QB</text>
<text x="176.2" y="114.2">QA</text>
<text x="183.9" y="118.2">6</text>
<text x="183.9" y="115.7">2</text>
<text x="246.6" y="115.7">7</text>
<text x="246.6" y="118.2">8</text>
<text x="252.5" y="114.2">A5</text>
<text x="252.5" y="116.8">A6</text>
<text x="252.5" y="119.3">A7</text>
<text x="260.5" y="119.3">Y7</text>
<text x="260.5" y="116.8">Y6</text>
<text x="260.5" y="114.2">Y5</text>
<text x="267.7" y="118.2">12</text>
<text x="267.7" y="115.7">13</text>
<text x="340.6" y="115.7">6</text>
<text x="340.6" y="118.2">7</text>
<text x="346.5" y="114.2">A4</text>
<text x="346.5" y="116.8">A5</text>
<text x="346.5" y="119.3">A6</text>
<text x="354.4" y="119.3">Y6</text>
<text x="354.4" y="116.8">Y5</text>
<text x="354.4" y="114.2">Y4</text>
<text x="361.7" y="118.2">13</text>
<text x="361.7" y="115.7">14</text>
<text x="379.7" y="114.2">CON5-4</text>
<text x="379.7" y="116.8">CON5-5</text>
<text x="379.7" y="119.3">CON5-6</text>
<text x="156.6" y="125.8">11</text>
<text x="157.8" y="120.7">9</text>
<text x="163.6" y="121.9">D</text>
<text x="176" y="121.9">QD</text>
<text x="183.9" y="120.7">7</text>
<text x="246.6" y="125.8">1</text>
<text x="246.6" y="120.7">9</text>
<text x="252.5" y="121.9">A8</text>
<text x="260.5" y="121.9">Y8</text>
<text x="267.7" y="120.7">11</text>
<text x="340.6" y="120.7">8</text>
<text x="340.6" y="123.3">9</text>
<text x="346.5" y="121.9">A7</text>
<text x="346.5" y="124.4">A8</text>
<text x="354.4" y="124.4">Y8</text>
<text x="354.4" y="121.9">Y7</text>
<text x="361.7" y="123.3">11</text>
<text x="361.7" y="120.7">12</text>
<text x="379.7" y="121.9">CON5-7</text>
<text x="379.7" y="124.4">CON5-8</text>
<text x="157.8" y="130.9">5</text>
<text x="163.6" y="126.9">LOAD</text>
<text x="169.4" y="129.5">BORROW</text>
<text x="183.9" y="128.4">13</text>
<text x="183.9" y="130.9">12</text>
<text x="245.5" y="128.4">19</text>
<text x="252.5" y="126.9">G1</text>
<text x="252.5" y="129.5">G2</text>
<text x="339.4" y="130.9">19</text>
<text x="340.6" y="128.4">1</text>
<text x="346.5" y="129.5">G1</text>
<text x="156.6" y="136">14</text>
<text x="157.8" y="133.4">4</text>
<text x="163.6" y="132">UP</text>
<text x="163.6" y="134.6">DOWN</text>
<text x="163.6" y="137.1">CLEAR</text>
<text x="171.8" y="132">CARRY</text>
<text x="346.5" y="132">G2</text>
<text x="282.2" y="143.6">2</text>
<text x="303.3" y="143.6">19</text>
<text x="340.6" y="143.6">2</text>
<text x="361.7" y="143.6">18</text>
<text x="282.2" y="146.1">4</text>
<text x="282.2" y="148.7">6</text>
<text x="288.1" y="144.7">P0</text>
<text x="288.1" y="147.3">P1</text>
<text x="288.1" y="149.8">P2</text>
<text x="294.3" y="144.7">P=Q</text>
<text x="340.6" y="146.1">3</text>
<text x="340.6" y="148.7">4</text>
<text x="346.5" y="144.7">A1</text>
<text x="346.5" y="147.3">A2</text>
<text x="346.5" y="149.8">A3</text>
<text x="354.4" y="149.8">Y3</text>
<text x="354.4" y="147.3">Y2</text>
<text x="354.4" y="144.7">Y1</text>
<text x="361.7" y="148.7">16</text>
<text x="361.7" y="146.1">17</text>
<text x="379.7" y="144.7">CON6-1</text>
<text x="379.7" y="147.3">CON6-2</text>
<text x="379.7" y="149.8">CON6-3</text>
<text x="156.6" y="153.8">15</text>
<text x="163.6" y="154.9">A</text>
<text x="176.2" y="154.9">QA</text>
<text x="183.9" y="153.8">3</text>
<text x="281" y="153.8">11</text>
<text x="282.2" y="151.2">8</text>
<text x="288.1" y="152.3">P3</text>
<text x="288.1" y="154.9">P4</text>
<text x="340.6" y="151.2">5</text>
<text x="340.6" y="153.8">6</text>
<text x="346.5" y="152.3">A4</text>
<text x="346.5" y="154.9">A5</text>
<text x="354.4" y="154.9">Y5</text>
<text x="354.4" y="152.3">Y4</text>
<text x="361.7" y="153.8">14</text>
<text x="361.7" y="151.2">15</text>
<text x="379.7" y="152.3">CON6-4</text>
<text x="379.7" y="154.9">CON6-5</text>
<text x="156.6" y="158.8">10</text>
<text x="157.8" y="156.3">1</text>
<text x="157.8" y="161.4">9</text>
<text x="163.6" y="157.4">B</text>
<text x="163.6" y="159.9">C</text>
<text x="176" y="160">QC</text>
<text x="176.2" y="157.4">QB</text>
<text x="183.9" y="161.4">7</text>
<text x="183.9" y="158.8">6</text>
<text x="183.9" y="156.3">2</text>
<text x="281" y="156.3">13</text>
<text x="281" y="158.8">15</text>
<text x="281" y="161.4">17</text>
<text x="288.1" y="157.4">P5</text>
<text x="288.1" y="159.9">P6</text>
<text x="340.6" y="156.3">7</text>
<text x="340.6" y="158.8">8</text>
<text x="340.6" y="161.4">9</text>
<text x="346.5" y="157.4">A6</text>
<text x="346.5" y="159.9">A7</text>
<text x="354.4" y="160">Y7</text>
<text x="354.4" y="157.4">Y6</text>
<text x="361.7" y="161.4">11</text>
<text x="361.7" y="158.8">12</text>
<text x="361.7" y="156.3">13</text>
<text x="379.7" y="157.4">CON6-6</text>
<text x="379.7" y="159.9">CON6-7</text>
<text x="156.6" y="166.5">11</text>
<text x="163.6" y="162.5">D</text>
<text x="163.6" y="167.6">LOAD</text>
<text x="176" y="162.5">QD</text>
<text x="282.2" y="166.5">3</text>
<text x="288.1" y="167.6">Q0</text>
<text x="288.1" y="162.5">P7</text>
<text x="340.6" y="166.5">1</text>
<text x="346.5" y="167.6">G1</text>
<text x="346.5" y="162.5">A8</text>
<text x="354.4" y="162.5">Y8</text>
<text x="379.7" y="162.5">CON6-8</text>
<text x="157.8" y="171.5">5</text>
<text x="163.6" y="172.6">UP</text>
<text x="169.4" y="170.1">BORROW</text>
<text x="171.8" y="172.6">CARRY</text>
<text x="183.9" y="169">13</text>
<text x="183.9" y="171.5">12</text>
<text x="246.6" y="171.5">2</text>
<text x="252.5" y="172.6">P0</text>
<text x="258.7" y="172.6">P=Q</text>
<text x="267.7" y="171.5">19</text>
<text x="282.2" y="169">5</text>
<text x="282.2" y="171.5">7</text>
<text x="288.1" y="170.1">Q1</text>
<text x="288.1" y="172.6">Q2</text>
<text x="339.4" y="169">19</text>
<text x="346.5" y="170.1">G2</text>
<text x="156.6" y="176.6">14</text>
<text x="157.8" y="174.1">4</text>
<text x="163.6" y="175.2">DOWN</text>
<text x="163.6" y="177.7">CLEAR</text>
<text x="246.6" y="174.1">4</text>
<text x="246.6" y="176.6">6</text>
<text x="246.6" y="179.1">8</text>
<text x="252.5" y="175.2">P1</text>
<text x="252.5" y="177.7">P2</text>
<text x="281" y="176.6">12</text>
<text x="281" y="179.1">14</text>
<text x="282.2" y="174.1">9</text>
<text x="288.1" y="175.2">Q3</text>
<text x="288.1" y="177.7">Q4</text>
<text x="245.5" y="181.7">11</text>
<text x="245.5" y="184.2">13</text>
<text x="252.5" y="180.3">P3</text>
<text x="252.5" y="182.8">P4</text>
<text x="252.5" y="185.3">P5</text>
<text x="281" y="181.7">16</text>
<text x="281" y="184.2">18</text>
<text x="288.1" y="180.3">Q5</text>
<text x="288.1" y="182.8">Q6</text>
<text x="288.1" y="185.3">Q7</text>
<text x="245.5" y="186.8">15</text>
<text x="245.5" y="189.3">17</text>
<text x="252.5" y="187.9">P6</text>
<text x="252.5" y="190.4">P7</text>
<text x="282.2" y="189.3">1</text>
<text x="288.1" y="190.4">G</text>
<text x="156.6" y="194.4">15</text>
<text x="157.8" y="196.9">1</text>
<text x="163.6" y="195.5">A</text>
<text x="176.2" y="195.5">QA</text>
<text x="183.9" y="196.9">2</text>
<text x="183.9" y="194.4">3</text>
<text x="246.6" y="194.4">3</text>
<text x="246.6" y="196.9">5</text>
<text x="252.5" y="195.5">Q0</text>
<text x="156.6" y="199.5">10</text>
<text x="157.8" y="202">9</text>
<text x="163.6" y="198">B</text>
<text x="163.6" y="200.6">C</text>
<text x="163.6" y="203.1">D</text>
<text x="176" y="203.1">QD</text>
<text x="176" y="200.6">QC</text>
<text x="176.2" y="198">QB</text>
<text x="183.9" y="202">7</text>
<text x="183.9" y="199.5">6</text>
<text x="246.6" y="199.5">7</text>
<text x="246.6" y="202">9</text>
<text x="252.5" y="198">Q1</text>
<text x="252.5" y="200.6">Q2</text>
<text x="252.5" y="203.1">Q3</text>
<text x="156.6" y="207.1">11</text>
<text x="163.6" y="208.2">LOAD</text>
<text x="183.9" y="209.6">13</text>
<text x="245.5" y="204.5">12</text>
<text x="245.5" y="207.1">14</text>
<text x="245.5" y="209.6">16</text>
<text x="252.5" y="205.7">Q4</text>
<text x="252.5" y="208.2">Q5</text>
<text x="340.6" y="207.1">1</text>
<text x="356.6" y="207.1">2</text>
<text x="157.8" y="212.2">5</text>
<text x="157.8" y="214.7">4</text>
<text x="163.6" y="213.3">UP</text>
<text x="163.6" y="215.8">DOWN</text>
<text x="169.4" y="210.7">BORROW</text>
<text x="171.8" y="213.3">CARRY</text>
<text x="183.9" y="212.2">12</text>
<text x="245.5" y="212.2">18</text>
<text x="252.5" y="210.7">Q6</text>
<text x="252.5" y="213.3">Q7</text>
<text x="156.6" y="217.2">14</text>
<text x="163.6" y="218.4">CLEAR</text>
<text x="246.6" y="217.2">1</text>
<text x="252.5" y="218.4">G</text>
<text x="124.7" y="250.3">3</text>
<text x="140.8" y="250.3">4</text>
<text x="155.2" y="250.3">9</text>
<text x="171.2" y="250.3">8</text>
<text x="124.7" y="263">5</text>
<text x="140.8" y="263">6</text>
<text x="154" y="263">11</text>
<text x="171.2" y="263">10</text>
<text x="184.5" y="263">13</text>
<text x="201.7" y="263">12</text>
</g>
</g></defs>
<g fill="#000" stroke="#000" stroke-width=".21">
<path d="M67.8 18.2v3.9zM115.3 18.2v3.9zM162.7 18.2v3.9zM210.2 18.2v3.9zM257.6 18.2v3.9zM305.1 18.2v3.9zM352.5 18.2v3.9zM20.3 22.1v252.6zM34.1 36.2h5.3zM35 31.1h5.8zM35.5 26h5.3zM44.4 27.1h172.7z"/>
<path d="M44.4 32.2h71.2zM44.4 37.3h5.1zM49.5 37.3h228.6zM279.6 36.2h5.3zM20.3 22.1h379.7zM44.4 42.4h66.1zM110.5 42.4v53.3zM16.5 72.6h3.8zM32.5 79.3h8.3zM53.9 78.4h8.3zM92.7 78.4h11.4zM130.8 70.3l2.5 2.5z"/>
<path d="M130.8 72.8l2.5 2.6zM130.8 75.4l2.5 2.5zM130.8 77.9l2.5 2.6zM133.3 72.8h22.9zM133.3 75.4h22.9zM133.3 77.9h22.9zM156.2 72.8h5.1zM156.2 75.4h5.1zM156.2 77.9h5.1zM181.6 77.9h5.1zM181.6 75.4h5.1zM181.6 72.8h5.1z"/>
<path d="M186.7 72.8h17.7zM186.7 75.4h17.7zM186.7 77.9h17.7zM204.4 72.8l2.6 2.6zM204.4 75.4l2.6 2.5zM204.4 77.9l2.6 2.6zM227.3 65.2l-2.5 2.6zM227.3 67.8l-2.5 2.5zM227.3 70.3l-2.5 2.5zM227.3 72.8l-2.5 2.6zM227.3 75.4l-2.5 2.5zM227.3 77.9l-2.5 2.6z"/>
<path d="M245.1 65.2h5.1zM245.1 67.8h5.1zM245.1 70.3h5.1zM245.1 72.8h5.1zM245.1 75.4h5.1zM245.1 77.9h5.1zM227.3 65.2h17.8zM227.3 67.8h17.8zM227.3 70.3h17.8zM227.3 72.8h17.8zM227.3 75.4h17.8zM227.3 77.9h17.8z"/>
<path d="M265.4 77.9h5.1zM265.4 75.4h5.1zM265.4 72.8h5.1zM265.4 70.3h5.1zM265.4 67.8h5.1zM265.4 65.2h5.1zM270.5 65.2h20.3zM290.8 65.2l2.5-2.5zM270.5 67.8h20.3zM293.3 65.2l-2.5 2.6zM270.5 70.3h20.3zM293.3 67.8l-2.5 2.5z"/>
<path d="M270.5 72.8h20.3zM290.8 72.8l2.5-2.5zM270.5 75.4h20.3zM270.5 77.9h20.3zM293.3 72.8l-2.5 2.6zM293.3 75.4l-2.5 2.5zM293.3 77.9l-2.5 2.6zM400 72.6h3.8zM49.5 37.3v45.7zM56.9 81h5.3zM62.2 90.6v2.6zM62.2 88.1v2.5z"/>
<path d="M64.8 88.1h3.1zM64.8 80.5h5zM64.8 83h5zM62.2 88.1h2.6zM44.4 80.5h20.4zM49.5 83h15.3zM87.1 80.5h3.1zM87.1 83h3.1zM87.1 85.5h3.1zM87.1 88.1h3.1zM90.2 80.5h35.5zM92.7 81h7z"/>
<path d="M110.5 95.7h45.7zM110.5 95.7v40.6zM115.6 32.2v53.3zM115.6 85.5v40.7zM120.6 83v7.6zM90.2 83h30.4zM125.7 80.5v12.7zM125.7 93.2h30.5zM133.3 80.5h22.9zM137.2 91.1h11.4zM141.6 88.6h7zM142.7 83.5h5.9z"/>
<path d="M156.2 90.6h5.1zM156.2 80.5h5.1zM156.2 85.5h3.1zM156.2 93.2h5.1zM156.2 95.7h5.1zM115.6 85.5h40.6zM120.6 90.6h35.6zM181.6 80.5h5.1zM183.6 88.1h3.1zM183.6 90.6h3.1zM186.7 80.5h17.7zM186.7 90.6h5z"/>
<path d="M186.7 88.1h2.5zM189.2 88.1v15.2zM191.7 90.6v15.3zM194.3 88.6h6.7zM194.3 86.1h6.5zM204.4 80.5l2.6 2.5zM217.1 27.1v61zM217.1 88.1v38.1zM227.3 80.5l-2.5 2.5zM227.3 83l-2.5 2.5zM242.5 88.1v2.5zM217.1 88.1h25.4z"/>
<path d="M245.1 88.1h3.1zM245.1 80.5h5.1zM245.1 83h5.1zM245.1 90.6h3.1zM227.3 80.5h17.8zM227.3 83h17.8zM242.5 88.1h2.6zM242.5 90.6h2.6zM265.4 83h5.1zM265.4 80.5h5.1zM270.5 80.5h20.3zM270.5 83h20.3z"/>
<path d="M293.3 80.5l-2.5 2.5zM120.6 103.3v30.5zM125.7 105.9v25.4zM130.8 110.9l2.5 2.6zM130.8 113.5l2.5 2.5zM130.8 116l2.5 2.6zM130.8 118.6l2.5 2.5zM133.3 113.5h22.9zM133.3 116h22.9zM133.3 118.6h22.9zM141.9 103.8h6.7zM142 101.3h6.6z"/>
<path d="M156.2 113.5h5.1zM156.2 116h5.1zM156.2 118.6h5.1zM181.6 118.6h5.1zM181.6 116h5.1zM181.6 113.5h5.1zM186.7 113.5h17.7zM186.7 116h17.7zM186.7 118.6h17.7zM120.6 103.3h68.6zM125.7 105.9h66zM204.4 113.5l2.6 2.5z"/>
<path d="M204.4 116l2.6 2.6zM204.4 118.6l2.6 2.5zM227.3 103.3l-2.5 2.6zM227.3 105.9l-2.5 2.5zM227.3 108.4l-2.5 2.5zM227.3 110.9l-2.5 2.6zM227.3 113.5l-2.5 2.5zM227.3 116l-2.5 2.6zM227.3 118.6l-2.5 2.5zM245.1 103.3h5.1zM245.1 105.9h5.1zM245.1 108.4h5.1z"/>
<path d="M245.1 110.9h5.1zM245.1 113.5h5.1zM245.1 116h5.1zM245.1 118.6h5.1zM227.3 103.3h17.8zM227.3 105.9h17.8zM227.3 108.4h17.8zM227.3 110.9h17.8zM227.3 113.5h17.8zM227.3 116h17.8zM227.3 118.6h17.8zM265.4 118.6h5.1z"/>
<path d="M265.4 116h5.1zM265.4 113.5h5.1zM265.4 110.9h5.1zM265.4 108.4h5.1zM265.4 105.9h5.1zM265.4 103.3h5.1zM270.5 103.3h20.3zM270.5 105.9h20.3zM270.5 108.4h20.3zM270.5 110.9h20.3zM270.5 113.5h20.3zM270.5 116h20.3z"/>
<path d="M270.5 118.6h20.3zM293.3 100.8l-2.5 2.5zM293.3 103.3l-2.5 2.6zM293.3 105.9l-2.5 2.5zM293.3 108.4l-2.5 2.5zM293.3 110.9l-2.5 2.6zM293.3 113.5l-2.5 2.5zM293.3 116l-2.5 2.6zM293.3 118.6l-2.5 2.5zM321.3 105.9l-2.6 2.5zM318.7 110.9l2.6-2.5zM321.3 110.9l-2.6 2.6z"/>
<path d="M321.3 113.5l-2.6 2.5zM318.7 118.6l2.6-2.6zM321.3 118.6l-2.6 2.5zM339 105.9h5.1zM339 108.4h5.1zM339 110.9h5.1zM339 113.5h5.1zM339 116h5.1zM339 118.6h5.1zM321.3 105.9h17.7zM321.3 108.4h17.7zM321.3 110.9h17.7z"/>
<path d="M321.3 113.5h17.7zM321.3 116h17.7zM321.3 118.6h17.7zM359.4 118.6h5zM359.4 116h5zM359.4 113.5h5zM359.4 110.9h5zM359.4 108.4h5zM359.4 105.9h5zM374.6 105.9h2.5zM374.6 108.4h2.5zM374.6 110.9h2.5z"/>
<path d="M374.6 113.5h2.5zM374.6 116h2.5zM374.6 118.6h2.5zM364.4 105.9h10.2zM364.4 108.4h10.2zM364.4 110.9h10.2zM364.4 113.5h10.2zM364.4 116h10.2zM364.4 118.6h10.2zM16.5 123.1h3.8zM110.5 136.3h45.7zM110.5 136.3v40.7z"/>
<path d="M115.6 126.2h40.6zM115.6 126.2v40.6zM125.7 131.3h30.5zM133.3 121.1h22.9zM141.9 129.2h6.7zM142 131.8h6.6zM142.7 124.2h5.9zM156.2 131.3h5.1zM156.2 121.1h5.1zM156.2 126.2h3.1zM156.2 133.8h5.1zM156.2 136.3h5.1z"/>
<path d="M156.2 136.3h2.5zM120.6 133.8h35.6zM181.6 121.1h5.1zM183.6 128.7h3.1zM183.6 131.3h3.1zM186.7 121.1h17.7zM186.7 131.3h5zM186.7 128.7h2.5zM189.2 128.7v15.3zM191.7 131.3v15.2zM194.3 129.2h6.7zM194.3 126.7h6.5z"/>
<path d="M204.4 121.1l2.6 2.5zM217.1 126.2h25.4zM227.3 121.1l-2.5 2.5zM242.5 126.2h2.6zM242.5 126.2v2.5zM245.1 126.2h3.1zM245.1 121.1h5.1zM245.1 128.7h3.1zM227.3 121.1h17.8zM242.5 128.7h2.6zM265.4 121.1h5.1zM270.5 121.1h20.3z"/>
<path d="M321.3 121.1l-2.6 2.5zM318.7 126.2l2.6-2.6zM336.5 133.8v2.5zM336.5 128.7v2.6zM336.5 131.3v2.5zM339 128.7h3.2zM339 121.1h5.1zM339 123.6h5.1zM339 131.3h3.2zM336.5 128.7h2.5zM336.5 131.3h2.5zM321.3 121.1h17.7z"/>
<path d="M321.3 123.6h17.7zM359.4 123.6h5zM359.4 121.1h5zM374.6 121.1h2.5zM374.6 123.6h2.5zM364.4 121.1h10.2zM364.4 123.6h10.2zM400 123.1h3.8zM120.6 144v30.4zM125.7 146.5v25.4zM130.8 151.6l2.5 2.5zM130.8 154.1l2.5 2.6z"/>
<path d="M130.8 156.7l2.5 2.5zM130.8 159.2l2.5 2.5zM133.3 154.1h22.9zM133.3 156.7h22.9zM133.3 159.2h22.9zM141.9 144.5h6.7zM142 141.9h6.6zM156.2 154.1h5.1zM156.2 156.7h5.1zM156.2 159.2h5.1zM181.6 159.2h5.1zM181.6 156.7h5.1z"/>
<path d="M181.6 154.1h5.1zM186.7 154.1h17.7zM186.7 156.7h17.7zM186.7 159.2h17.7zM120.6 144h68.6zM125.7 146.5h66zM204.4 154.1l2.6 2.6zM204.4 156.7l2.6 2.5zM204.4 159.2l2.6 2.5zM227.3 144l-2.5 2.5zM227.3 146.5l-2.5 2.5zM227.3 149l-2.5 2.6z"/>
<path d="M227.3 151.6l-2.5 2.5zM227.3 154.1l-2.5 2.6zM227.3 156.7l-2.5 2.5zM227.3 159.2l-2.5 2.5zM280.6 144h5.1zM280.6 146.5h5.1zM280.6 149h5.1zM280.6 151.6h5.1zM280.6 154.1h5.1zM280.6 156.7h5.1zM280.6 159.2h5.1zM227.3 144h53.3z"/>
<path d="M227.3 146.5h53.3zM227.3 149h53.3zM227.3 151.6h53.3zM227.3 154.1h53.3zM227.3 156.7h53.3zM227.3 159.2h53.3zM302.9 144h3.1zM306 144h5.1zM318.7 146.5l2.6-2.5zM321.3 146.5l-2.6 2.5zM321.3 149l-2.6 2.6zM318.7 154.1l2.6-2.5z"/>
<path d="M321.3 154.1l-2.6 2.6zM321.3 156.7l-2.6 2.5zM318.7 161.7l2.6-2.5zM339 144h5.1zM339 146.5h5.1zM339 149h5.1zM339 151.6h5.1zM339 154.1h5.1zM339 156.7h5.1zM339 159.2h5.1zM321.3 144h17.7zM321.3 146.5h17.7z"/>
<path d="M321.3 149h17.7zM321.3 151.6h17.7zM321.3 154.1h17.7zM321.3 156.7h17.7zM321.3 159.2h17.7zM359.4 159.2h5zM359.4 156.7h5zM359.4 154.1h5zM359.4 151.6h5zM359.4 149h5zM359.4 146.5h5zM359.4 144h5z"/>
<path d="M374.6 144h2.5zM374.6 146.5h2.5zM374.6 149h2.5zM374.6 151.6h2.5zM374.6 154.1h2.5zM374.6 156.7h2.5zM374.6 159.2h2.5zM364.4 144h10.2zM364.4 146.5h10.2zM364.4 149h10.2zM364.4 151.6h10.2zM364.4 154.1h10.2z"/>
<path d="M364.4 156.7h10.2zM364.4 159.2h10.2zM16.5 173.7h3.8zM110.5 177h45.7zM110.5 177v40.6zM115.6 166.8h40.6zM115.6 166.8v40.6zM120.6 174.4h35.6zM125.7 171.9h30.5zM133.3 161.7h22.9zM141.9 169.9h6.7zM142 172.4h6.6z"/>
<path d="M142.7 164.8h5.9zM156.2 171.9h5.1zM156.2 161.7h5.1zM156.2 166.8h3.1zM156.2 174.4h5.1zM156.2 177h5.1zM181.6 161.7h5.1zM183.6 169.4h3.1zM183.6 171.9h3.1zM186.7 161.7h17.7zM186.7 171.9h5zM186.7 169.4h2.5z"/>
<path d="M189.2 169.4v15.2zM191.7 171.9v15.2zM194.3 169.9h6.7zM194.3 167.3h6.5zM204.4 161.7l2.6 2.6zM227.3 161.7l-2.5 2.6zM227.3 171.9l-2.5 2.5zM227.3 174.4l-2.5 2.6zM227.3 177l-2.5 2.5zM227.3 179.5l-2.5 2.6zM245.1 171.9h5.1zM245.1 174.4h5.1z"/>
<path d="M245.1 177h5.1zM245.1 179.5h5.1zM227.3 171.9h17.8zM227.3 174.4h17.8zM227.3 177h17.8zM227.3 179.5h17.8zM267.4 171.9h3.1zM270.5 171.9h2.5zM273 171.9v17.8zM278.1 166.8v2.6zM278.1 169.4v2.5zM278.1 171.9v2.5z"/>
<path d="M278.1 174.4v2.6zM278.1 177v2.5zM278.1 179.5v2.6zM280.6 166.8h5.1zM280.6 169.4h5.1zM280.6 171.9h5.1zM280.6 174.4h5.1zM280.6 177h5.1zM280.6 179.5h5.1zM280.6 161.7h5.1zM278.1 166.8h2.5zM278.1 169.4h2.5z"/>
<path d="M278.1 171.9h2.5zM278.1 174.4h2.5zM278.1 177h2.5zM278.1 179.5h2.5zM227.3 161.7h53.3zM311.7 171.1v8.4zM321.3 161.7l-2.6 2.6zM336.5 171.9v2.5zM336.5 166.8h2.5zM336.5 166.8v2.6zM336.5 169.4v2.5zM339 166.8h3.2z"/>
<path d="M339 161.7h5.1zM339 169.4h3.2zM336.5 169.4h2.5zM321.3 161.7h17.7zM359.4 161.7h5zM374.6 161.7h2.5zM364.4 161.7h10.2zM400 173.7h3.8zM120.6 184.6v30.4zM125.7 187.1v25.4zM130.8 192.2l2.5 2.6zM130.8 194.8l2.5 2.5z"/>
<path d="M130.8 197.3l2.5 2.5zM130.8 199.8l2.5 2.6zM133.3 194.8h22.9zM133.3 197.3h22.9zM133.3 199.8h22.9zM141.9 185.1h6.7zM142 182.6h6.6zM156.2 194.8h5.1zM156.2 197.3h5.1zM156.2 199.8h5.1zM181.6 199.8h5.1zM181.6 197.3h5.1z"/>
<path d="M181.6 194.8h5.1zM186.7 194.8h17.7zM186.7 197.3h17.7zM186.7 199.8h17.7zM120.6 184.6h68.6zM125.7 187.1h66zM204.4 194.8l2.6 2.5zM204.4 197.3l2.6 2.5zM204.4 199.8l2.6 2.6zM227.3 182.1l-2.5 2.5zM227.3 184.6l-2.5 2.5zM227.3 187.1l-2.5 2.6z"/>
<path d="M227.3 189.7l-2.5 2.5zM242.5 194.8v2.5zM242.5 197.3v2.5zM242.5 199.8v2.6zM245.1 194.8h5.1zM245.1 197.3h5.1zM245.1 199.8h5.1zM245.1 182.1h5.1zM245.1 184.6h5.1zM245.1 187.1h5.1zM245.1 189.7h5.1zM242.5 194.8h2.6z"/>
<path d="M242.5 197.3h2.6zM242.5 199.8h2.6zM227.3 182.1h17.8zM227.3 184.6h17.8zM227.3 187.1h17.8zM227.3 189.7h17.8zM273 189.7h7.6zM278.1 194.8v2.5zM278.1 182.1v2.5zM278.1 184.6v10.2zM280.6 189.7h3.1zM280.6 182.1h5.1z"/>
<path d="M280.6 184.6h5.1zM278.1 182.1h2.5zM278.1 184.6h2.5zM318.7 199.8l2.6-2.5zM321.3 197.3h25.4zM346.7 197.3h2.5zM349.2 197.3h2.5zM351.7 197.3h22.9zM110.5 217.6h45.7zM115.6 207.4h40.6zM120.6 215h35.6zM125.7 212.5h30.5z"/>
<path d="M133.3 202.4h22.9zM141.9 210.5h6.7zM142 213h6.6zM142.7 205.4h5.9zM156.2 212.5h5.1zM156.2 202.4h5.1zM156.2 207.4h3.1zM156.2 215h5.1zM156.2 217.6h5.1zM181.6 202.4h5.1zM183.6 210h3.1zM183.6 212.5h3.1z"/>
<path d="M186.7 202.4h17.7zM186.7 212.5h25.4zM186.7 210h27.9zM194.3 210.5h9.2zM194.3 208h10.1zM204.4 202.4l2.6 2.5zM212.1 212.5v17.8zM214.6 210v17.7zM242.5 202.4v2.5zM242.5 204.9v2.5zM242.5 207.4v2.6zM242.5 210v2.5z"/>
<path d="M242.5 212.5v5.1zM242.5 217.6v2.5zM245.1 217.6h3.1zM245.1 202.4h5.1zM245.1 204.9h5.1zM245.1 207.4h5.1zM245.1 210h5.1zM245.1 212.5h5.1zM242.5 202.4h2.6zM242.5 204.9h2.6zM242.5 207.4h2.6zM242.5 210h2.6z"/>
<path d="M242.5 212.5h2.6zM242.5 217.6h2.6zM311.1 144v63.4zM330.6 205.4h8.4zM339 207.4h5.1zM311.1 207.4h27.9zM356.3 207.4h3.1zM359.4 207.4h15.2zM16.5 224.2h3.8zM102.9 222.4h8.8zM212.1 230.3h162.5zM214.6 227.7h154.9z"/>
<path d="M242.5 220.1v2.6zM369.5 225.2v2.5zM369.5 225.2h5.1zM376.1 229.2h9.2zM376.1 224.1h10.2zM400 224.2h3.8zM29.2 253.1v2.6zM29.2 257.7v.5zM29.2 255.7v.5zM29.2 250.6v2.5zM36.8 253.1v2.6zM36.8 257.7v.5z"/>
<path d="M36.8 255.7v.5zM36.8 250.6v2.5zM29.2 250.6h7.6zM44.4 253.1v2.6zM44.4 257.7v.5zM44.4 255.7v.5zM36.8 250.6h7.6zM44.4 250.6v2.5zM52.1 253.1v2.6zM52.1 257.7v.5zM52.1 255.7v.5zM44.4 250.6h7.7z"/>
<path d="M52.1 250.6v2.5zM59.7 253.1v2.6zM59.7 257.7v.5zM59.7 255.7v.5zM52.1 250.6h7.6zM59.7 250.6v2.5zM67.3 253.1v2.6zM67.3 257.7v.5zM67.3 255.7v.5zM59.7 250.6h7.6zM67.3 250.6v2.5zM74.9 253.1v2.6z"/>
<path d="M74.9 257.7v.5zM74.9 255.7v.5zM67.3 250.6h7.6zM74.9 250.6v2.5zM82.5 253.1v2.6zM82.5 257.7v.5zM82.5 255.7v.5zM74.9 250.6h7.6zM82.5 250.6v2.5zM90.2 253.1v2.6zM90.2 257.7v.5zM90.2 255.7v.5z"/>
<path d="M82.5 250.6h7.7zM90.2 250.6v2.5zM97.8 245.5v2.6zM97.8 253.1v2.6zM97.8 257.7v.5zM97.8 255.7v.5zM90.2 250.6h7.6zM97.8 248.1v2.5zM97.8 250.6v2.5zM107.9 245.5v2.6zM107.9 253.1v2.6zM107.9 255.7v.5z"/>
<path d="M107.9 257.7v.5zM107.9 248.1v5zM120.6 250.6v12.7zM123.2 250.6h5zM120.6 250.6h2.6zM140.4 250.6h3.1zM151.1 250.6v12.7zM153.6 250.6h5.1zM151.1 250.6h2.5zM170.9 250.6h3.1zM20.3 274.7h379.7zM29.2 265.8v2.6z"/>
<path d="M29.2 258.2v2.6zM29.2 260.8v2.5zM29.2 263.3h7.6zM29.2 263.3v2.5zM36.8 258.2v2.6zM36.8 260.8v2.5zM44.4 258.2v2.6zM36.8 263.3h7.6zM44.4 260.8v2.5zM52.1 258.2v2.6zM44.4 263.3h7.7zM52.1 260.8v2.5z"/>
<path d="M59.7 258.2v2.6zM52.1 263.3h7.6zM59.7 260.8v2.5zM67.3 258.2v2.6zM59.7 263.3h7.6zM67.3 260.8v2.5zM67.8 274.7v3.8zM74.9 258.2v2.6zM67.3 263.3h7.6zM74.9 260.8v2.5zM82.5 258.2v2.6zM74.9 263.3h7.6z"/>
<path d="M82.5 260.8v2.5zM90.2 258.2v2.6zM82.5 263.3h7.7zM90.2 260.8v2.5zM97.8 258.2v2.6zM90.2 263.3h7.6zM97.8 260.8v2.5zM107.9 265.8v2.6zM107.9 258.2v2.6zM107.9 260.8v5zM115.3 274.7v3.8zM120.6 265.8v2.6z"/>
<path d="M120.6 263.3v2.5zM123.2 263.3h5zM120.6 263.3h2.6zM140.4 263.3h3.1zM151.1 265.8v2.6zM151.1 263.3v2.5zM153.6 263.3h5.1zM151.1 263.3h2.5zM162.7 274.7v3.8zM170.9 263.3h3.1zM181.6 265.8v2.6zM181.6 263.3v2.5z"/>
<path d="M184.1 263.3h5.1zM181.6 263.3h2.5zM201.4 263.3h3zM210.2 274.7v3.8zM257.6 274.7v3.8zM305.1 274.7v3.8zM352.5 274.7v3.8zM400 264.5v.1zM400 268.4v6.2zM400 274.6h.1zM400 22.1v252.6z"/>
<circle cx="49.5" cy="37.3" r=".51"/>
<circle cx="110.5" cy="95.7" r=".51"/>
<circle cx="115.6" cy="85.5" r=".51"/>
<circle cx="217.1" cy="88.1" r=".51"/>
<circle cx="242.5" cy="88.1" r=".51"/>
<circle cx="110.5" cy="136.3" r=".51"/>
<circle cx="115.6" cy="126.2" r=".51"/>
<circle cx="242.5" cy="126.2" r=".51"/>
<circle cx="336.5" cy="131.3" r=".51"/>
<circle cx="110.5" cy="177" r=".51"/>
<circle cx="115.6" cy="166.8" r=".51"/>
<circle cx="278.1" cy="179.5" r=".51"/>
<circle cx="278.1" cy="174.4" r=".51"/>
<circle cx="278.1" cy="169.4" r=".51"/>
<circle cx="278.1" cy="177" r=".51"/>
<circle cx="278.1" cy="171.9" r=".51"/>
<circle cx="336.5" cy="169.4" r=".51"/>
<circle cx="242.5" cy="199.8" r=".51"/>
<circle cx="242.5" cy="197.3" r=".51"/>
<circle cx="278.1" cy="182.1" r=".51"/>
<circle cx="278.1" cy="184.6" r=".51"/>
<circle cx="242.5" cy="202.4" r=".51"/>
<circle cx="242.5" cy="204.9" r=".51"/>
<circle cx="242.5" cy="210" r=".51"/>
<circle cx="242.5" cy="207.4" r=".51"/>
<circle cx="242.5" cy="217.6" r=".51"/>
<circle cx="36.8" cy="250.6" r=".51"/>
<circle cx="44.4" cy="250.6" r=".51"/>
<circle cx="52.1" cy="250.6" r=".51"/>
<circle cx="59.7" cy="250.6" r=".51"/>
<circle cx="67.3" cy="250.6" r=".51"/>
<circle cx="74.9" cy="250.6" r=".51"/>
<circle cx="82.5" cy="250.6" r=".51"/>
<circle cx="90.2" cy="250.6" r=".51"/>
<circle cx="97.8" cy="250.6" r=".51"/>
<circle cx="29.2" cy="263.3" r=".51"/>
<circle cx="36.8" cy="263.3" r=".51"/>
<circle cx="44.4" cy="263.3" r=".51"/>
<circle cx="52.1" cy="263.3" r=".51"/>
<circle cx="59.7" cy="263.3" r=".51"/>
<circle cx="67.3" cy="263.3" r=".51"/>
<circle cx="74.9" cy="263.3" r=".51"/>
<circle cx="82.5" cy="263.3" r=".51"/>
<circle cx="90.2" cy="263.3" r=".51"/>
<circle cx="120.6" cy="263.3" r=".51"/>
<circle cx="151.1" cy="263.3" r=".51"/>
</g>
<g fill="#000" stroke="#000" stroke-width=".28">
<path d="M31.9 35.8v3zM32.7 30.7v3zM33.3 25.6v3.1zM33.3 25.6h9.6zM33.3 28.7h9.6zM32.7 30.7h10.2zM32.7 33.7h10.2zM31.9 35.8h11zM31.9 38.8h11zM42.9 25.6l1.5 1.5zM44.4 27.1l-1.5 1.6zM42.9 30.7l1.5 1.5z"/>
<path d="M44.4 32.2l-1.5 1.5zM42.9 35.8l1.5 1.5zM44.4 37.3l-1.5 1.5zM278.1 37.3l1.5-1.5zM278.1 37.3l1.5 1.5zM279.6 35.8h11.1zM279.6 38.8h11.1zM290.7 35.8v3zM30.2 40.9v3zM30.2 40.9h12.7zM30.2 43.9h12.7zM42.9 40.9l1.5 1.5z"/>
<path d="M44.4 42.4l-1.5 1.5zM30.2 78.9v3.1zM30.2 78.9h12.7zM30.2 82h12.7zM42.9 78.9l1.5 1.6zM44.4 80.5l-1.5 1.5zM60.3 93.2h3.8zM334.6 136.3h3.8zM334.6 174.4h3.8zM276.2 197.3h3.8zM374.6 197.3l1.5-1.5zM374.6 197.3l1.5 1.5z"/>
<path d="M376.1 195.8h11.4zM376.1 198.8h11.4zM387.5 195.8v3zM374.6 207.4l1.5-1.5zM374.6 207.4l1.5 1.6zM376.1 205.9h12.9zM376.1 209h12.9zM389 205.9v3.1zM240.6 222.7h3.8zM374.6 230.3l1.5-1.5zM374.6 230.3l1.5 1.5zM374.6 225.2l1.5-1.5z"/>
<path d="M374.6 225.2l1.5 1.5zM376.1 228.8h15.1zM376.1 231.8h15.1zM376.1 223.7h16zM376.1 226.7h16zM391.2 228.8v3zM392.1 223.7v3zM97.8 245.5l-1.3 1.9zM97.8 245.5l1.3 1.9zM107.9 245.5l-1.2 1.9zM107.9 245.5l1.3 1.9zM313.7 249.3h86.3z"/>
<path d="M313.7 254.4h86.3zM313.7 259.5h58.4zM372.1 259.5h27.9zM372.1 259.5v5.1zM27.3 268.4h3.8zM106 268.4h3.9zM118.7 268.4h3.8zM149.2 268.4h3.8zM179.7 268.4h3.8zM313.7 264.6h58.4zM313.7 269.7h86.3zM372.1 264.6h27.9z"/>
<path d="M400 268.4v1.3z"/>
</g>
<g fill="none" stroke="#000" stroke-width=".21">
<circle cx="68.9" cy="88.1" r=".99"/>
<circle cx="86.1" cy="88.1" r=".99"/>
<circle cx="86.1" cy="80.5" r=".99"/>
<circle cx="86.1" cy="83" r=".99"/>
<circle cx="86.1" cy="85.5" r=".99"/>
<circle cx="160.3" cy="85.5" r=".99"/>
<circle cx="182.6" cy="90.6" r=".99"/>
<circle cx="182.6" cy="88.1" r=".99"/>
<circle cx="249.2" cy="88.1" r="1"/>
<circle cx="249.2" cy="90.6" r="1"/>
<circle cx="160.3" cy="126.2" r=".99"/>
<circle cx="182.6" cy="131.3" r=".99"/>
<circle cx="182.6" cy="128.7" r=".99"/>
<circle cx="249.2" cy="128.7" r="1"/>
<circle cx="249.2" cy="126.2" r="1"/>
<circle cx="343.1" cy="128.7" r="1"/>
<circle cx="343.1" cy="131.3" r="1"/>
<circle cx="301.9" cy="144" r="1"/>
<circle cx="160.3" cy="166.8" r=".99"/>
<circle cx="182.6" cy="169.4" r=".99"/>
<circle cx="182.6" cy="171.9" r=".99"/>
<circle cx="266.4" cy="171.9" r="1"/>
<circle cx="343.1" cy="166.8" r="1"/>
<circle cx="343.1" cy="169.4" r="1"/>
<circle cx="284.7" cy="189.7" r="1"/>
<circle cx="160.3" cy="207.4" r=".99"/>
<circle cx="182.6" cy="212.5" r=".99"/>
<circle cx="182.6" cy="210" r=".99"/>
<circle cx="249.2" cy="217.6" r="1"/>
<circle cx="355.3" cy="207.4" r="1"/>
<circle cx="139.4" cy="250.6" r=".99"/>
<circle cx="169.9" cy="250.6" r=".99"/>
<circle cx="139.4" cy="263.3" r=".99"/>
<circle cx="169.9" cy="263.3" r=".99"/>
<circle cx="200.4" cy="263.3" r=".99"/>
</g>
<g fill="#000" stroke="#000" stroke-width=".61">
<path d="M20.3 22.1v252.6zM20.3 22.1h379.7zM69.8 77.9v12.7zM69.8 77.9h15.3zM161.3 70.3v27.9zM161.3 70.3h20.3zM250.2 62.7v30.5zM250.2 62.7h15.2zM69.8 90.6h15.3zM85.1 77.9v12.7zM161.3 98.2h20.3zM181.6 70.3v27.9z"/>
<path d="M250.2 93.2h15.2zM265.4 62.7v30.5zM161.3 110.9v28zM161.3 110.9h20.3zM250.2 100.8v30.5zM250.2 100.8h15.2zM344.1 103.3v30.5zM344.1 103.3h15.3zM377.1 105.9h1.3zM377.1 108.4h1.3zM377.1 110.9h1.3zM377.1 113.5h1.3z"/>
<path d="M377.1 116h1.3zM377.1 118.6h1.3zM161.3 138.9h20.3zM181.6 110.9v28zM250.2 131.3h15.2zM265.4 100.8v30.5zM344.1 133.8h15.3zM359.4 103.3v30.5zM377.1 121.1h1.3zM377.1 123.6h1.3zM161.3 151.6v27.9zM161.3 151.6h20.3z"/>
<path d="M285.7 141.4v50.8zM285.7 141.4h15.3zM344.1 141.4v30.5zM344.1 141.4h15.3zM377.1 144h1.3zM377.1 146.5h1.3zM377.1 149h1.3zM377.1 151.6h1.3zM377.1 154.1h1.3zM377.1 156.7h1.3zM377.1 159.2h1.3zM161.3 179.5h20.3z"/>
<path d="M181.6 151.6v27.9zM250.2 169.4v50.7zM250.2 169.4h15.2zM344.1 171.9h15.3zM359.4 141.4v30.5zM377.1 161.7h1.3zM161.3 192.2v27.9zM161.3 192.2h20.3zM285.7 192.2h15.3zM301 141.4v50.8zM344.1 202.4l10.2 5zM344.1 202.4v10.1z"/>
<path d="M344.1 212.5l10.2-5.1zM161.3 220.1h20.3zM181.6 192.2v27.9zM250.2 220.1h15.2zM265.4 169.4v50.7zM128.2 245.5l10.2 5.1zM128.2 245.5v10.2zM128.2 258.2l10.2 5.1zM128.2 255.7l10.2-5.1zM158.7 245.5l10.2 5.1zM158.7 245.5v10.2zM158.7 258.2l10.2 5.1z"/>
<path d="M158.7 255.7l10.2-5.1zM189.2 258.2l10.2 5.1zM283.2 244.3v30.4zM313.7 254.4v5.1zM313.7 249.3v5.1zM313.7 244.3v5zM313.7 244.3h86.3zM283.2 244.3h30.5zM400 254.4v5.1zM400 249.3v5.1zM400 244.3v5zM400 22.1v222.2z"/>
<path d="M20.3 274.7h262.9zM128.2 258.2v10.2zM128.2 268.4l10.2-5.1zM158.7 258.2v10.2zM158.7 268.4l10.2-5.1zM189.2 258.2v10.2zM189.2 268.4l10.2-5.1zM283.2 274.7h30.5zM313.7 274.7h86.3zM313.7 269.7v5zM313.7 264.6v5.1zM313.7 259.5v5.1z"/>
<path d="M400 268.4v6.3zM400 264.6v3.8zM400 259.5v5.1z"/>
</g>
<path d="M16.5 18.2v260.3zM16.5 18.2h387.3zM16.5 278.5h387.3zM403.8 18.2v260.3z" fill="#000" stroke="#000" stroke-width=".32"/>
<g fill="#000" stroke="#000" stroke-width=".21">
<path d="M27.2 256.2h4v.5h-4zM27.2 257.2h4v.5h-4zM34.8 256.2h4.1v.5h-4.1zM34.8 257.2h4.1v.5h-4.1zM42.4 256.2h4.1v.5h-4.1zM42.4 257.2h4.1v.5h-4.1zM50 256.2h4.1v.5h-4.1zM50 257.2h4.1v.5h-4.1zM57.7 256.2h4v.5h-4zM57.7 257.2h4v.5h-4zM65.3 256.2h4v.5h-4zM65.3 257.2h4v.5h-4z"/>
<path d="M72.9 256.2h4.1v.5h-4.1zM72.9 257.2h4.1v.5h-4.1zM80.5 256.2h4.1v.5h-4.1zM80.5 257.2h4.1v.5h-4.1zM88.1 256.2h4.1v.5h-4.1zM88.1 257.2h4.1v.5h-4.1zM95.8 256.2h4v.5h-4zM95.8 257.2h4v.5h-4zM105.9 257.2h4.1v.5h-4.1zM105.9 256.2h4.1v.5h-4.1zM252.7 253.1h25.4v10.2h-25.4z"/>
</g>
<g fill="#000" stroke="#000" stroke-width=".76">
<path d="M44.4 50h81.3zM125.7 50h248.9zM125.7 50l5.1 5.1zM288.3 50l5 5.1zM293.3 55.1v63.5zM130.8 55.1v144.7zM207 75.4v157.4zM212.1 237.9h162.5zM207 232.8l5.1 5.1zM224.8 67.8v165zM224.8 232.8l5 5.1zM318.7 108.4v124.4z"/>
<path d="M318.7 232.8l5.1 5.1z"/>
</g>
<path d="M222.2 253.1v10.2zM222.2 253.1h55.9zM222.2 263.3v7.6zM222.2 270.9h55.9zM222.2 263.3h55.9zM278.1 263.3v7.6zM278.1 253.1v10.2z" fill="#000" stroke="#000" stroke-width=".42"/>
<use href="#words"/>
</svg>
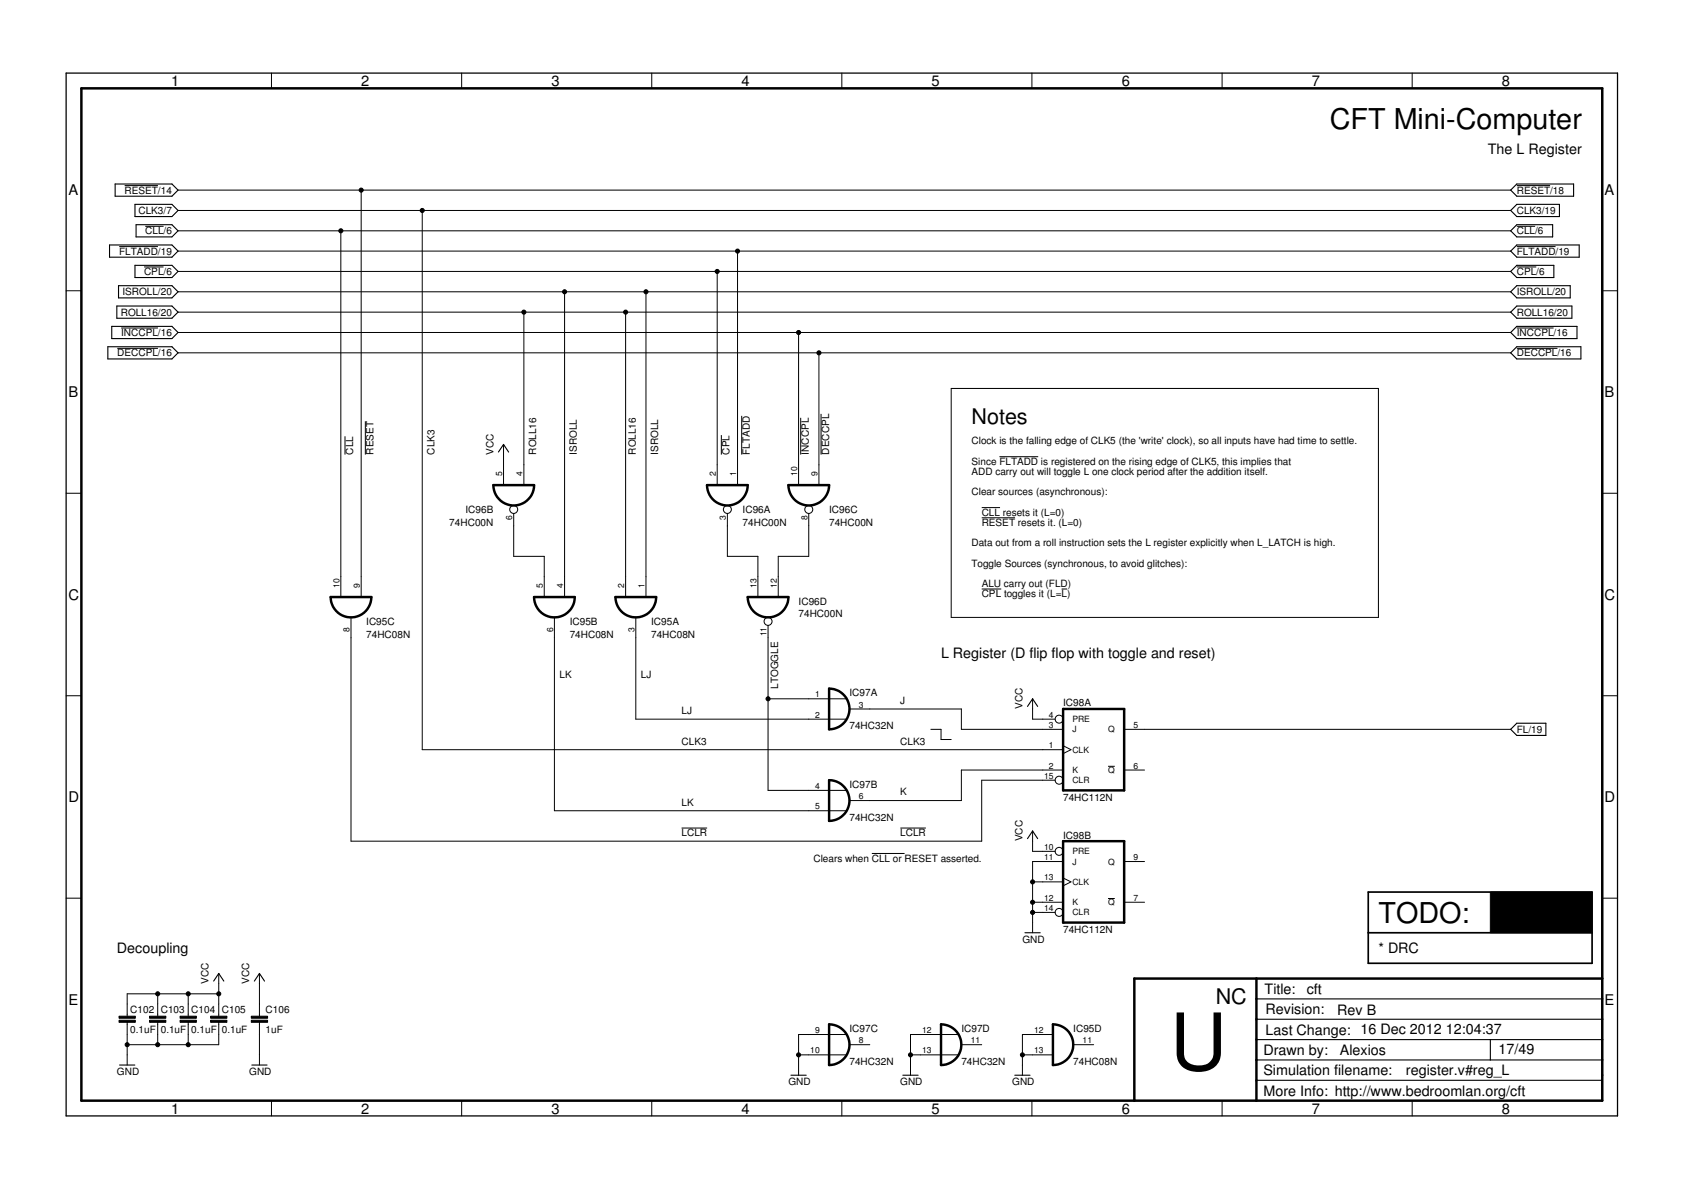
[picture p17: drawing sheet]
<svg xmlns="http://www.w3.org/2000/svg" width="420mm" height="297mm" viewBox="0 0 420 297" stroke-linecap="round" stroke-linejoin="round" font-family="sans-serif">
<defs><g id="words">
<text font-size="19.7" x="292.1" y="267.1">U</text>
<g font-size="7.2">
<text x="332" y="32.2">CFT Mini-Computer</text>
<text x="344.1" y="230.3">TODO:</text>
</g>
<g font-size="5.4">
<text x="242.5" y="105.9">Notes</text>
<text x="303.5" y="250.6">NC</text>
</g>
<g font-size="3.7">
<text x="42.7" y="21.5">1</text>
<text x="90.2" y="21.5">2</text>
<text x="137.7" y="21.5">3</text>
<text x="185.1" y="21.5">4</text>
<text x="232.6" y="21.5">5</text>
<text x="280" y="21.5">6</text>
<text x="327.5" y="21.5">7</text>
<text x="375" y="21.5">8</text>
<text x="17.1" y="48.6">A</text>
<text x="400.6" y="48.6">A</text>
<text x="17.1" y="99.2">B</text>
<text x="400.6" y="99.2">B</text>
<text x="17.1" y="149.7">C</text>
<text x="400.6" y="149.7">C</text>
<text x="17.1" y="200.2">D</text>
<text x="400.6" y="200.2">D</text>
<text x="17.1" y="250.8">E</text>
<text x="400.6" y="250.8">E</text>
<text x="42.7" y="277.9">1</text>
<text x="90.2" y="277.9">2</text>
<text x="137.7" y="277.9">3</text>
<text x="185.1" y="277.9">4</text>
<text x="232.6" y="277.9">5</text>
<text x="280" y="277.9">6</text>
<text x="327.5" y="277.9">7</text>
<text x="375" y="277.9">8</text>
</g>
<g font-size="3.6">
<text x="371.4" y="38.6">The L Register</text>
<text x="234.9" y="164.3">L Register (D flip flop with toggle and reset)</text>
<text x="29.2" y="237.9">Decoupling</text>
<text x="344.1" y="237.9">* DRC</text>
<text x="315.7" y="248.1">Title:</text>
<text x="326.2" y="248.2">cft</text>
<text x="315.9" y="253.2">Revision:</text>
<text x="333.8" y="253.3">Rev B</text>
<text x="315.4" y="263.3">Drawn by:</text>
<text x="315.9" y="258.2">Last Change: 16 Dec 2012</text>
<text x="334.5" y="263.3">Alexios</text>
<text x="361" y="258.1">12:04:37</text>
<text x="374.1" y="263.2">17/49</text>
<text x="315.4" y="268.4">Simulation filename:</text>
<text x="351" y="268.4">register.v#reg_L</text>
<text x="315.4" y="273.5">More Info: http://www.bedroomlan.org/cft</text>
</g>
<g font-size="2.5">
<text x="31.1" y="48.3">RESET/14</text>
<text x="34.6" y="53.4">CLK3/7</text>
<text x="378.7" y="48.3">RESET/18</text>
<text x="378.7" y="53.4">CLK3/19</text>
<text x="36.3" y="58.5">CLL/6</text>
<text x="378.7" y="58.5">CLL/6</text>
<text x="29.8" y="63.6">FLTADD/19</text>
<text x="378.7" y="63.6">FLTADD/19</text>
<text x="36" y="68.7">CPL/6</text>
<text x="378.7" y="68.7">CPL/6</text>
<text x="30.6" y="73.7">ISROLL/20</text>
<text x="378.7" y="73.7">ISROLL/20</text>
<text x="30.2" y="78.8">ROLL16/20</text>
<text x="30.2" y="83.9">INCCPL/16</text>
<text x="378.7" y="78.8">ROLL16/20</text>
<text x="378.7" y="83.9">INCCPL/16</text>
<text x="29.3" y="89">DECCPL/16</text>
<text x="378.7" y="89">DECCPL/16</text>
<text x="88.1" y="113.5" transform="rotate(-90 88.1 113.5)">CLL</text>
<text x="93.2" y="113.5" transform="rotate(-90 93.2 113.5)">RESET</text>
<text x="108.4" y="113.5" transform="rotate(-90 108.4 113.5)">CLK3</text>
<text x="123.2" y="113.5" transform="rotate(-90 123.2 113.5)">VCC</text>
<text x="133.8" y="113.5" transform="rotate(-90 133.8 113.5)">ROLL16</text>
<text x="144" y="113.5" transform="rotate(-90 144 113.5)">ISROLL</text>
<text x="158.7" y="113.5" transform="rotate(-90 158.7 113.5)">ROLL16</text>
<text x="164.3" y="113.5" transform="rotate(-90 164.3 113.5)">ISROLL</text>
<text x="182.1" y="113.5" transform="rotate(-90 182.1 113.5)">CPL</text>
<text x="187.2" y="113.5" transform="rotate(-90 187.2 113.5)">FLTADD</text>
<text x="201.9" y="113.5" transform="rotate(-90 201.9 113.5)">INCCPL</text>
<text x="207" y="113.5" transform="rotate(-90 207 113.5)">DECCPL</text>
<text x="242.5" y="110.9">Clock is the falling edge of CLK5 (the 'write' clock), so all inputs have had time to settle.</text>
<text x="242.5" y="116">Since FLTADD is registered on the rising edge of CLK5, this implies that</text>
<text x="242.5" y="118.6">ADD carry out will toggle L one clock period after the addition itself.</text>
<text x="242.5" y="123.6">Clear sources (asynchronous):</text>
<text x="112.2" y="131.3">74HC00N</text>
<text x="116.2" y="128.1">IC96B</text>
<text x="185.4" y="131.3">74HC00N</text>
<text x="185.4" y="128.1">IC96A</text>
<text x="207" y="131.3">74HC00N</text>
<text x="207" y="128.1">IC96C</text>
<text x="245.1" y="128.7">CLL resets it (L=0)</text>
<text x="245.1" y="131.3">RESET resets it. (L=0)</text>
<text x="242.5" y="136.3">Data out from a roll instruction sets the L register explicitly when L_LATCH is high.</text>
<text x="242.5" y="141.4">Toggle Sources (synchronous, to avoid glitches):</text>
<text x="245.1" y="146.5">ALU carry out (FLD)</text>
<text x="245.1" y="149">CPL toggles it (L=L)</text>
<text x="199.4" y="154.1">74HC00N</text>
<text x="199.4" y="150.9">IC96D</text>
<text x="91.4" y="159.2">74HC08N</text>
<text x="91.4" y="156">IC95C</text>
<text x="142.2" y="159.2">74HC08N</text>
<text x="142.2" y="156">IC95B</text>
<text x="162.5" y="159.2">74HC08N</text>
<text x="162.5" y="156">IC95A</text>
<text x="139.7" y="169.3">LK</text>
<text x="160" y="169.3">LJ</text>
<text x="194.3" y="171.9" transform="rotate(-90 194.3 171.9)">LTOGGLE</text>
<text x="212.1" y="173.8">IC97A</text>
<text x="170.2" y="178.2">LJ</text>
<text x="224.8" y="175.7">J</text>
<text x="255.2" y="177" transform="rotate(-90 255.2 177)">VCC</text>
<text x="265.4" y="176.3">IC98A</text>
<text x="170.2" y="185.9">CLK3</text>
<text x="212.1" y="182">74HC32N</text>
<text x="224.8" y="185.9">CLK3</text>
<text x="378.7" y="182.9">FL/19</text>
<text x="212.1" y="196.6">IC97B</text>
<text x="170.2" y="201.1">LK</text>
<text x="224.8" y="198.6">K</text>
<text x="265.4" y="199.8">74HC112N</text>
<text x="170.2" y="208.7">LCLR</text>
<text x="212.1" y="204.9">74HC32N</text>
<text x="224.8" y="208.7">LCLR</text>
<text x="255.2" y="210" transform="rotate(-90 255.2 210)">VCC</text>
<text x="265.4" y="209.3">IC98B</text>
<text x="203.1" y="215.1">Clears when CLL or RESET asserted.</text>
<text x="265.4" y="232.8">74HC112N</text>
<text x="255.2" y="235.4">GND</text>
<text x="52.1" y="245.5" transform="rotate(-90 52.1 245.5)">VCC</text>
<text x="62.2" y="245.5" transform="rotate(-90 62.2 245.5)">VCC</text>
<text x="32.5" y="257.9">0.1uF</text>
<text x="32.5" y="252.8">C102</text>
<text x="40.1" y="257.9">0.1uF</text>
<text x="40.1" y="252.8">C103</text>
<text x="47.7" y="257.9">0.1uF</text>
<text x="47.7" y="252.8">C104</text>
<text x="55.4" y="257.9">0.1uF</text>
<text x="55.4" y="252.8">C105</text>
<text x="66.3" y="257.9">1uF</text>
<text x="66.3" y="252.8">C106</text>
<text x="212.1" y="257.6">IC97C</text>
<text x="240" y="257.6">IC97D</text>
<text x="267.9" y="257.6">IC95D</text>
<text x="29.2" y="268.4">GND</text>
<text x="62.2" y="268.4">GND</text>
<text x="212.1" y="265.8">74HC32N</text>
<text x="240" y="265.8">74HC32N</text>
<text x="267.9" y="265.8">74HC08N</text>
<text x="196.8" y="270.9">GND</text>
<text x="224.8" y="270.9">GND</text>
<text x="252.7" y="270.9">GND</text>
</g>
<g font-size="2.1">
<text x="125.4" y="118.8" transform="rotate(-90 125.4 118.8)">5</text>
<text x="130.4" y="118.8" transform="rotate(-90 130.4 118.8)">4</text>
<text x="178.7" y="118.8" transform="rotate(-90 178.7 118.8)">2</text>
<text x="183.8" y="118.8" transform="rotate(-90 183.8 118.8)">1</text>
<text x="199" y="118.8" transform="rotate(-90 199 118.8)">10</text>
<text x="204.1" y="118.8" transform="rotate(-90 204.1 118.8)">9</text>
<text x="127.9" y="129.7" transform="rotate(-90 127.9 129.7)">6</text>
<text x="181.2" y="129.7" transform="rotate(-90 181.2 129.7)">3</text>
<text x="201.6" y="129.7" transform="rotate(-90 201.6 129.7)">8</text>
<text x="84.7" y="146.7" transform="rotate(-90 84.7 146.7)">10</text>
<text x="89.8" y="146.7" transform="rotate(-90 89.8 146.7)">9</text>
<text x="135.5" y="146.7" transform="rotate(-90 135.5 146.7)">5</text>
<text x="140.6" y="146.7" transform="rotate(-90 140.6 146.7)">4</text>
<text x="155.8" y="146.7" transform="rotate(-90 155.8 146.7)">2</text>
<text x="160.9" y="146.7" transform="rotate(-90 160.9 146.7)">1</text>
<text x="188.9" y="146.7" transform="rotate(-90 188.9 146.7)">13</text>
<text x="193.9" y="146.7" transform="rotate(-90 193.9 146.7)">12</text>
<text x="87.3" y="157.6" transform="rotate(-90 87.3 157.6)">8</text>
<text x="138.1" y="157.6" transform="rotate(-90 138.1 157.6)">6</text>
<text x="158.4" y="157.6" transform="rotate(-90 158.4 157.6)">3</text>
<text x="191.4" y="158.8" transform="rotate(-90 191.4 158.8)">11</text>
<text x="203.5" y="174.1">1</text>
<text x="203.5" y="179.1">2</text>
<text x="214.4" y="176.6">3</text>
<text x="261.9" y="179.1">4</text>
<text x="261.9" y="181.7">3</text>
<text x="267.7" y="182.8">J</text>
<text x="267.7" y="180.3">PRE</text>
<text x="276.6" y="182.8">Q</text>
<text x="283" y="181.7">5</text>
<text x="261.9" y="186.8">1</text>
<text x="261.9" y="191.8">2</text>
<text x="267.7" y="187.9">CLK</text>
<text x="283" y="191.8">6</text>
<text x="203.5" y="196.9">4</text>
<text x="260.7" y="194.4">15</text>
<text x="267.7" y="193">K</text>
<text x="267.7" y="195.5">CLR</text>
<text x="276.6" y="193">Q</text>
<text x="203.5" y="202">5</text>
<text x="214.4" y="199.5">6</text>
<text x="260.7" y="214.7">11</text>
<text x="260.7" y="212.2">10</text>
<text x="267.7" y="215.8">J</text>
<text x="267.7" y="213.3">PRE</text>
<text x="276.6" y="215.8">Q</text>
<text x="283" y="214.7">9</text>
<text x="260.7" y="219.8">13</text>
<text x="267.7" y="220.9">CLK</text>
<text x="260.7" y="224.9">12</text>
<text x="260.7" y="227.4">14</text>
<text x="267.7" y="226">K</text>
<text x="276.6" y="226">Q</text>
<text x="283" y="224.9">7</text>
<text x="267.7" y="228.5">CLR</text>
<text x="203.5" y="257.9">9</text>
<text x="230.2" y="257.9">12</text>
<text x="258.2" y="257.9">12</text>
<text x="202.3" y="263">10</text>
<text x="214.4" y="260.4">8</text>
<text x="230.2" y="263">13</text>
<text x="242.3" y="260.4">11</text>
<text x="258.2" y="263">13</text>
<text x="270.3" y="260.4">11</text>
</g>
</g></defs>
<g fill="#000" stroke="#000" stroke-width=".25">
<path d="M67.8 18.2v3.9zM115.3 18.2v3.9zM162.7 18.2v3.9zM210.2 18.2v3.9zM257.6 18.2v3.9zM305.1 18.2v3.9zM352.5 18.2v3.9zM20.3 22.1v252.6zM20.3 22.1h379.7zM31.1 46.3h8.3zM36.3 56.5h4.5zM44.4 52.5h61z"/>
<path d="M44.4 57.6h40.7zM85.1 57.6v86.4zM44.4 47.5h45.8zM90.2 47.5v96.5zM105.4 52.5h271.7zM105.4 52.5v134.6zM90.2 47.5h286.9zM85.1 57.6h292zM378.7 46.3h8.3zM378.7 56.5h4.5zM16.5 72.6h3.8zM29.8 61.6h9.6z"/>
<path d="M36 66.6h4.8zM44.4 77.9h86.4zM44.4 72.8h96.5zM130.8 77.9h25.4zM140.9 72.8h20.4zM140.9 72.8v71.2zM156.2 77.9h220.9zM161.3 72.8h215.8zM44.4 67.8h134.6zM44.4 62.7h139.7zM184.1 62.7v53.3zM179 67.8h198.1z"/>
<path d="M184.1 62.7h193zM378.7 66.6h4.8zM378.7 61.6h9.6zM400 72.6h3.8zM29.3 87h10.1zM30.2 81.9h9.2zM44.4 83h155zM44.4 88.1h160zM199.4 83h177.7zM204.4 88.1h172.7zM237.5 97v57.1zM237.5 97h106.6z"/>
<path d="M378.7 81.9h9.2zM378.7 87h10.1zM86.1 108.9v4.6zM91.2 105.2v8.3zM125.7 116v5.1zM125.7 110.9v2.6zM125.7 113.5v2.5zM130.8 116v5.1zM130.8 77.9v38.1zM179 116v5.1zM179 67.8v48.2zM180.1 108.6v4.9z"/>
<path d="M184.1 116v5.1zM185.2 103.8v9.7zM199.4 116v5.1zM199.4 83v33zM199.9 104.3v9.2zM204.4 116v5.1zM204.4 88.1v27.9zM205 103.3v10.2zM249.5 114h9.7zM16.5 123.1h3.8zM128.2 128.2v3.1zM128.2 131.3v7.6z"/>
<path d="M128.2 138.9h7.7zM135.9 138.9v5.1zM181.6 128.2v3.1zM181.6 131.3v7.6zM181.6 138.9h7.6zM189.2 138.9v5.1zM194.3 138.9h7.6zM201.9 128.2v3.1zM201.9 131.3v7.6zM245.1 126.7h4.6zM245.1 129.2h8.3zM400 123.1h3.8z"/>
<path d="M85.1 144v5zM87.6 154.1v5.1zM87.6 159.2v50.8zM90.2 144v5zM135.9 144v5zM138.4 154.1v5.1zM138.4 159.2v43.2zM140.9 144v5zM156.2 144v5zM156.2 77.9v66.1zM158.7 154.1v5.1zM158.7 159.2v20.3z"/>
<path d="M161.3 144v5zM161.3 72.8v71.2zM189.2 144v5zM191.7 156.1v3.1zM194.3 144v5zM194.3 138.9v5.1zM237.5 154.1h106.6zM245.1 147h4.9zM265 147h1.4zM344.1 97v57.1zM16.5 173.7h3.8zM158.7 179.5h43.2z"/>
<path d="M191.7 174.4h10.2zM191.7 174.4v22.9zM191.7 159.2v15.2zM201.9 174.4h5.1zM201.9 179.5h5.1zM207 174.4h4.3zM207 179.5h4.3zM212.1 177h5zM217.1 177h22.9zM240 177v5.1zM257.8 174.4v2.6zM257.8 177v2.5z"/>
<path d="M260.3 179.5h3.1zM257.8 179.5h2.5zM400 173.7h3.8zM105.4 187.1h154.9zM191.7 197.3h10.2zM201.9 197.3h5.1zM207 197.3h4.3zM212.1 199.8h5zM217.1 199.8h22.9zM232.4 182.1h2.5zM234.9 182.1v2.5zM234.9 184.6h2.6z"/>
<path d="M240 182.1h20.3zM240 192.2v7.6zM240 192.2h20.3zM245.1 194.8h15.2zM260.3 187.1h5.1zM260.3 192.2h5.1zM260.3 182.1h5.1zM260.3 194.8h3.1zM265.4 186.1l2 1zM265.4 188.1l2-1zM276.6 191.3h1.7zM280.6 182.1h5.1z"/>
<path d="M280.6 192.2h5.1zM285.7 182.1h91.4zM87.6 210h157.5zM138.4 202.4h63.5zM170.2 206.7h6.3zM201.9 202.4h5.1zM207 202.4h4.3zM217.7 213h8.1zM224.8 206.7h6.3zM245.1 194.8v15.2zM257.8 207.4v2.6zM257.8 210v2.5z"/>
<path d="M257.8 215v5.1zM260.3 215h5.1zM260.3 212.5h3.1zM257.8 212.5h2.5zM257.8 215h2.5zM265.4 219.2l2 .9zM280.6 215h5.1zM16.5 224.2h3.8zM257.8 230.3v2.5zM257.8 220.1v5.1zM257.8 225.2v2.5zM257.8 227.7v2.6z"/>
<path d="M260.3 220.1h5.1zM260.3 225.2h5.1zM260.3 227.7h3.1zM257.8 220.1h2.5zM257.8 225.2h2.5zM257.8 227.7h2.5zM265.4 221.1l2-1zM276.6 224.3h1.7zM280.6 225.2h5.1zM400 224.2h3.8zM31.7 255.7v2.5zM31.7 250.6v2.5z"/>
<path d="M31.7 255.2v.5zM31.7 253.1v.6zM31.7 248.1v2.5zM31.7 258.2v2.6zM39.4 255.7v2.5zM39.4 250.6v2.5zM39.4 255.2v.5zM39.4 253.1v.6zM39.4 248.1v2.5zM31.7 248.1h7.7zM47 255.7v2.5zM47 250.6v2.5z"/>
<path d="M47 255.2v.5zM47 253.1v.6zM39.4 248.1h7.6zM47 248.1v2.5zM54.6 243v2.5zM54.6 255.7v2.5zM54.6 250.6v2.5zM54.6 255.2v.5zM54.6 253.1v.6zM47 248.1h7.6zM54.6 245.5v2.6zM54.6 248.1v2.5z"/>
<path d="M64.8 243v2.5zM64.8 250.6v2.5zM64.8 255.7v2.5zM64.8 253.1v.6zM64.8 255.2v.5zM64.8 245.5v5.1zM199.4 258.2v5.1zM201.9 258.2h5.1zM199.4 258.2h2.5zM207 258.2h4.3zM227.3 258.2v5.1zM229.8 258.2h5.1z"/>
<path d="M227.3 258.2h2.5zM234.9 258.2h4.3zM255.2 258.2v5.1zM257.8 258.2h5.1zM255.2 258.2h2.6zM20.3 274.7h379.7zM31.7 263.3v2.5zM31.7 260.8h7.7zM31.7 260.8v2.5zM39.4 258.2v2.6zM39.4 260.8h7.6zM47 258.2v2.6z"/>
<path d="M47 260.8h7.6zM54.6 258.2v2.6zM64.8 263.3v2.5zM64.8 258.2v5.1zM67.8 274.7v3.8zM115.3 274.7v3.8zM162.7 274.7v3.8zM199.4 265.8v2.6zM199.4 263.3v2.5zM201.9 263.3h5.1zM199.4 263.3h2.5zM210.2 274.7v3.8z"/>
<path d="M207 263.3h4.3zM212.1 260.8h5zM227.3 265.8v2.6zM227.3 263.3v2.5zM229.8 263.3h5.1zM227.3 263.3h2.5zM234.9 263.3h4.3zM240 260.8h5.1zM255.2 265.8v2.6zM255.2 263.3v2.5zM257.6 274.7v3.8zM257.8 263.3h5.1z"/>
<path d="M255.2 263.3h2.6zM267.9 260.8h5.1zM305.1 274.7v3.8zM352.5 274.7v3.8zM400 264.5v.1zM400 268.4v6.2zM400 274.6h.1zM400 22.1v252.6z"/>
<circle cx="85.1" cy="57.6" r=".51"/>
<circle cx="90.2" cy="47.5" r=".51"/>
<circle cx="105.4" cy="52.5" r=".51"/>
<circle cx="130.8" cy="77.9" r=".51"/>
<circle cx="140.9" cy="72.8" r=".51"/>
<circle cx="156.2" cy="77.9" r=".51"/>
<circle cx="161.3" cy="72.8" r=".51"/>
<circle cx="179" cy="67.8" r=".51"/>
<circle cx="184.1" cy="62.7" r=".51"/>
<circle cx="199.4" cy="83" r=".51"/>
<circle cx="204.4" cy="88.1" r=".51"/>
<circle cx="191.7" cy="174.4" r=".51"/>
<circle cx="257.8" cy="227.7" r=".51"/>
<circle cx="257.8" cy="220.1" r=".51"/>
<circle cx="257.8" cy="225.2" r=".51"/>
<circle cx="39.4" cy="248.1" r=".51"/>
<circle cx="47" cy="248.1" r=".51"/>
<circle cx="54.6" cy="248.1" r=".51"/>
<circle cx="31.7" cy="260.8" r=".51"/>
<circle cx="39.4" cy="260.8" r=".51"/>
<circle cx="47" cy="260.8" r=".51"/>
<circle cx="199.4" cy="263.3" r=".51"/>
<circle cx="227.3" cy="263.3" r=".51"/>
<circle cx="255.2" cy="263.3" r=".51"/>
</g>
<g fill="#000" stroke="#000" stroke-width=".28">
<path d="M28.7 45.9v3.1zM33.7 51v3.1zM34 56.1v3zM28.7 45.9h14.2zM28.7 49h14.2zM34 56.1h8.9zM34 59.1h8.9zM33.7 51h9.2zM33.7 54.1h9.2zM42.9 45.9l1.5 1.6zM44.4 47.5l-1.5 1.5zM42.9 56.1l1.5 1.5z"/>
<path d="M44.4 57.6l-1.5 1.5zM42.9 51l1.5 1.5zM44.4 52.5l-1.5 1.6zM377.1 47.5l1.6 1.5zM377.1 47.5l1.6-1.6zM377.1 57.6l1.6 1.5zM378.7 56.1l-1.6 1.5zM377.1 52.5l1.6 1.6zM377.1 52.5l1.6-1.5zM378.7 49h14.1zM378.7 45.9h14.1zM378.7 59.1h8.9z"/>
<path d="M378.7 56.1h8.9zM378.7 54.1h10.6zM378.7 51h10.6zM387.6 56.1v3zM389.3 51v3.1zM392.8 45.9v3.1zM27.3 61.1v3.1zM29.2 76.4v3zM29.6 71.3v3.1zM33.7 66.2v3.1zM33.7 66.2h9.2zM33.7 69.3h9.2z"/>
<path d="M29.2 76.4h13.7zM29.2 79.4h13.7zM29.6 71.3h13.3zM29.6 74.4h13.3zM27.3 61.1h15.6zM27.3 64.2h15.6zM42.9 66.2l1.5 1.6zM44.4 67.8l-1.5 1.5zM42.9 76.4l1.5 1.5zM42.9 79.4l1.5-1.5zM42.9 71.3l1.5 1.5zM44.4 72.8l-1.5 1.6z"/>
<path d="M42.9 61.1l1.5 1.6zM42.9 64.2l1.5-1.5zM377.1 67.8l1.6 1.5zM378.7 66.2l-1.6 1.6zM377.1 77.9l1.6 1.5zM378.7 76.4l-1.6 1.5zM377.1 72.8l1.6 1.6zM377.1 72.8l1.6-1.5zM377.1 62.7l1.6 1.5zM378.7 61.1l-1.6 1.6zM378.7 69.3h9.2zM378.7 66.2h9.2z"/>
<path d="M378.7 79.4h13.7zM378.7 76.4h13.7zM378.7 74.4h13.3zM378.7 71.3h13.3zM378.7 64.2h15.5zM378.7 61.1h15.5zM387.9 66.2v3.1zM392 71.3v3.1zM392.4 76.4v3zM394.2 61.1v3.1zM26.9 86.5v3.1zM27.9 81.5v3z"/>
<path d="M27.9 84.5h15zM27.9 81.5h15zM26.9 89.6h16zM26.9 86.5h16zM44.4 83l-1.5 1.5zM42.9 81.5l1.5 1.5zM44.4 88.1l-1.5 1.5zM42.9 86.5l1.5 1.6zM378.7 81.5l-1.6 1.5zM377.1 83l1.6 1.5zM377.1 88.1l1.6-1.6zM377.1 88.1l1.6 1.5z"/>
<path d="M378.7 81.5h15zM378.7 84.5h15zM378.7 86.5h16zM378.7 89.6h16zM393.7 81.5v3zM394.7 86.5v3.1zM125.7 110.9l-1.3 1.9zM125.7 110.9l1.3 1.9zM257.8 174.4l-1.3 1.9zM257.8 174.4l1.3 1.9zM377.1 182.1l1.6-1.6zM377.1 182.1l1.6 1.5z"/>
<path d="M378.7 180.5h7.2zM378.7 183.6h7.2zM385.9 180.5v3.1zM257.8 207.4l-1.3 1.9zM257.8 207.4l1.3 1.9zM255.9 232.8h3.8zM54.6 243l-1.3 1.9zM54.6 243l1.3 1.9zM64.8 243l-1.3 1.9zM64.8 243l1.2 1.9zM313.7 249.3h86.3zM313.7 254.4h86.3z"/>
<path d="M313.7 259.5h58.4zM372.1 259.5h27.9zM372.1 259.5v5.1zM29.8 265.8h3.9zM62.9 265.8h3.8zM197.5 268.4h3.8zM225.4 268.4h3.8zM253.3 268.4h3.8zM313.7 264.6h58.4zM313.7 269.7h86.3zM372.1 264.6h27.9zM400 268.4v1.3z"/>
</g>
<g fill="#000" stroke="#000" stroke-width=".61">
<path d="M20.3 22.1v252.6zM20.3 22.1h379.7zM123.2 121.1h10.1zM176.5 121.1h10.2zM196.8 121.1h10.2zM82.5 149h10.2zM133.3 149h10.2zM153.6 149h10.2zM186.7 149h10.1zM207 171.9v10.2zM265.4 177v20.3zM265.4 177h15.2z"/>
<path d="M207 194.8v10.1zM265.4 197.3h15.2zM280.6 177v20.3zM265.4 210v20.3zM265.4 210h15.2zM265.4 230.3h15.2zM280.6 210v20.3zM207 255.7v10.1zM234.9 255.7v10.1zM262.9 255.7v10.1zM283.2 244.3v30.4zM313.7 254.4v5.1z"/>
<path d="M313.7 249.3v5.1zM313.7 244.3v5zM313.7 244.3h86.3zM283.2 244.3h30.5zM400 254.4v5.1zM400 249.3v5.1zM400 244.3v5zM400 22.1v222.2zM20.3 274.7h262.9zM283.2 274.7h30.5zM313.7 274.7h86.3zM313.7 269.7v5z"/>
<path d="M313.7 264.6v5.1zM313.7 259.5v5.1zM400 268.4v6.3zM400 264.6v3.8zM400 259.5v5.1z"/>
</g>
<path d="M123.2 121.1a5.1 5.1 0 0 0 5 5.1 5.1 5.1 0 0 0 5.1-5.1M176.5 121.1a5.1 5.1 0 0 0 5.1 5.1 5.1 5.1 0 0 0 5.1-5.1M196.8 121.1a5.1 5.1 0 0 0 5.1 5.1 5.1 5.1 0 0 0 5.1-5.1M82.5 149a5.1 5.1 0 0 0 5.1 5.1 5.1 5.1 0 0 0 5.1-5.1M133.3 149a5.1 5.1 0 0 0 5.1 5.1 5.1 5.1 0 0 0 5.1-5.1M153.6 149a5.1 5.1 0 0 0 5.1 5.1 5.1 5.1 0 0 0 5.1-5.1M186.7 149a5.1 5.1 0 0 0 5 5.1 5.1 5.1 0 0 0 5.1-5.1M207 171.9a5.1 5.1 0 0 1 5.1 5.1 5.1 5.1 0 0 1-5.1 5.1M207 194.8a5.1 5.1 0 0 1 5.1 5 5.1 5.1 0 0 1-5.1 5.1M207 255.7a5.1 5.1 0 0 1 5.1 5.1 5.1 5.1 0 0 1-5.1 5M234.9 255.7a5.1 5.1 0 0 1 5.1 5.1 5.1 5.1 0 0 1-5.1 5M262.9 255.7a5.1 5.1 0 0 1 5 5.1 5.1 5.1 0 0 1-5 5" fill="none" stroke="#000" stroke-width=".61"/>
<g fill="none" stroke="#000" stroke-width=".25">
<circle cx="128.2" cy="127.2" r=".99"/>
<circle cx="181.6" cy="127.2" r=".99"/>
<circle cx="201.9" cy="127.2" r=".99"/>
<circle cx="191.7" cy="155.1" r=".99"/>
<circle cx="264.4" cy="179.5" r="1"/>
<circle cx="264.4" cy="194.8" r="1"/>
<circle cx="264.4" cy="212.5" r="1"/>
<circle cx="264.4" cy="227.7" r="1"/>
</g>
<path d="M16.5 18.2v260.3zM16.5 18.2h387.3zM16.5 278.5h387.3zM403.8 18.2v260.3z" fill="#000" stroke="#000" stroke-width=".32"/>
<path d="M372.1 222.7h25.4v10.1h-25.4zM29.7 253.7h4.1v.5h-4.1zM29.7 254.7h4.1v.5h-4.1zM37.3 253.7h4.1v.5h-4.1zM37.3 254.7h4.1v.5h-4.1zM45 253.7h4v.5h-4zM45 254.7h4v.5h-4zM52.6 253.7h4v.5h-4zM52.6 254.7h4v.5h-4zM62.7 254.7h4.1v.5h-4.1zM62.7 253.7h4.1v.5h-4.1z" fill="#000" stroke="#000" stroke-width=".25"/>
<path d="M341.6 222.7v10.1zM341.6 232.8v7.6zM341.6 232.8h55.9zM397.5 222.7v10.1zM341.6 222.7h55.9zM341.6 240.4h55.9zM397.5 232.8v7.6z" fill="#000" stroke="#000" stroke-width=".42"/>
<use href="#words"/>
</svg>
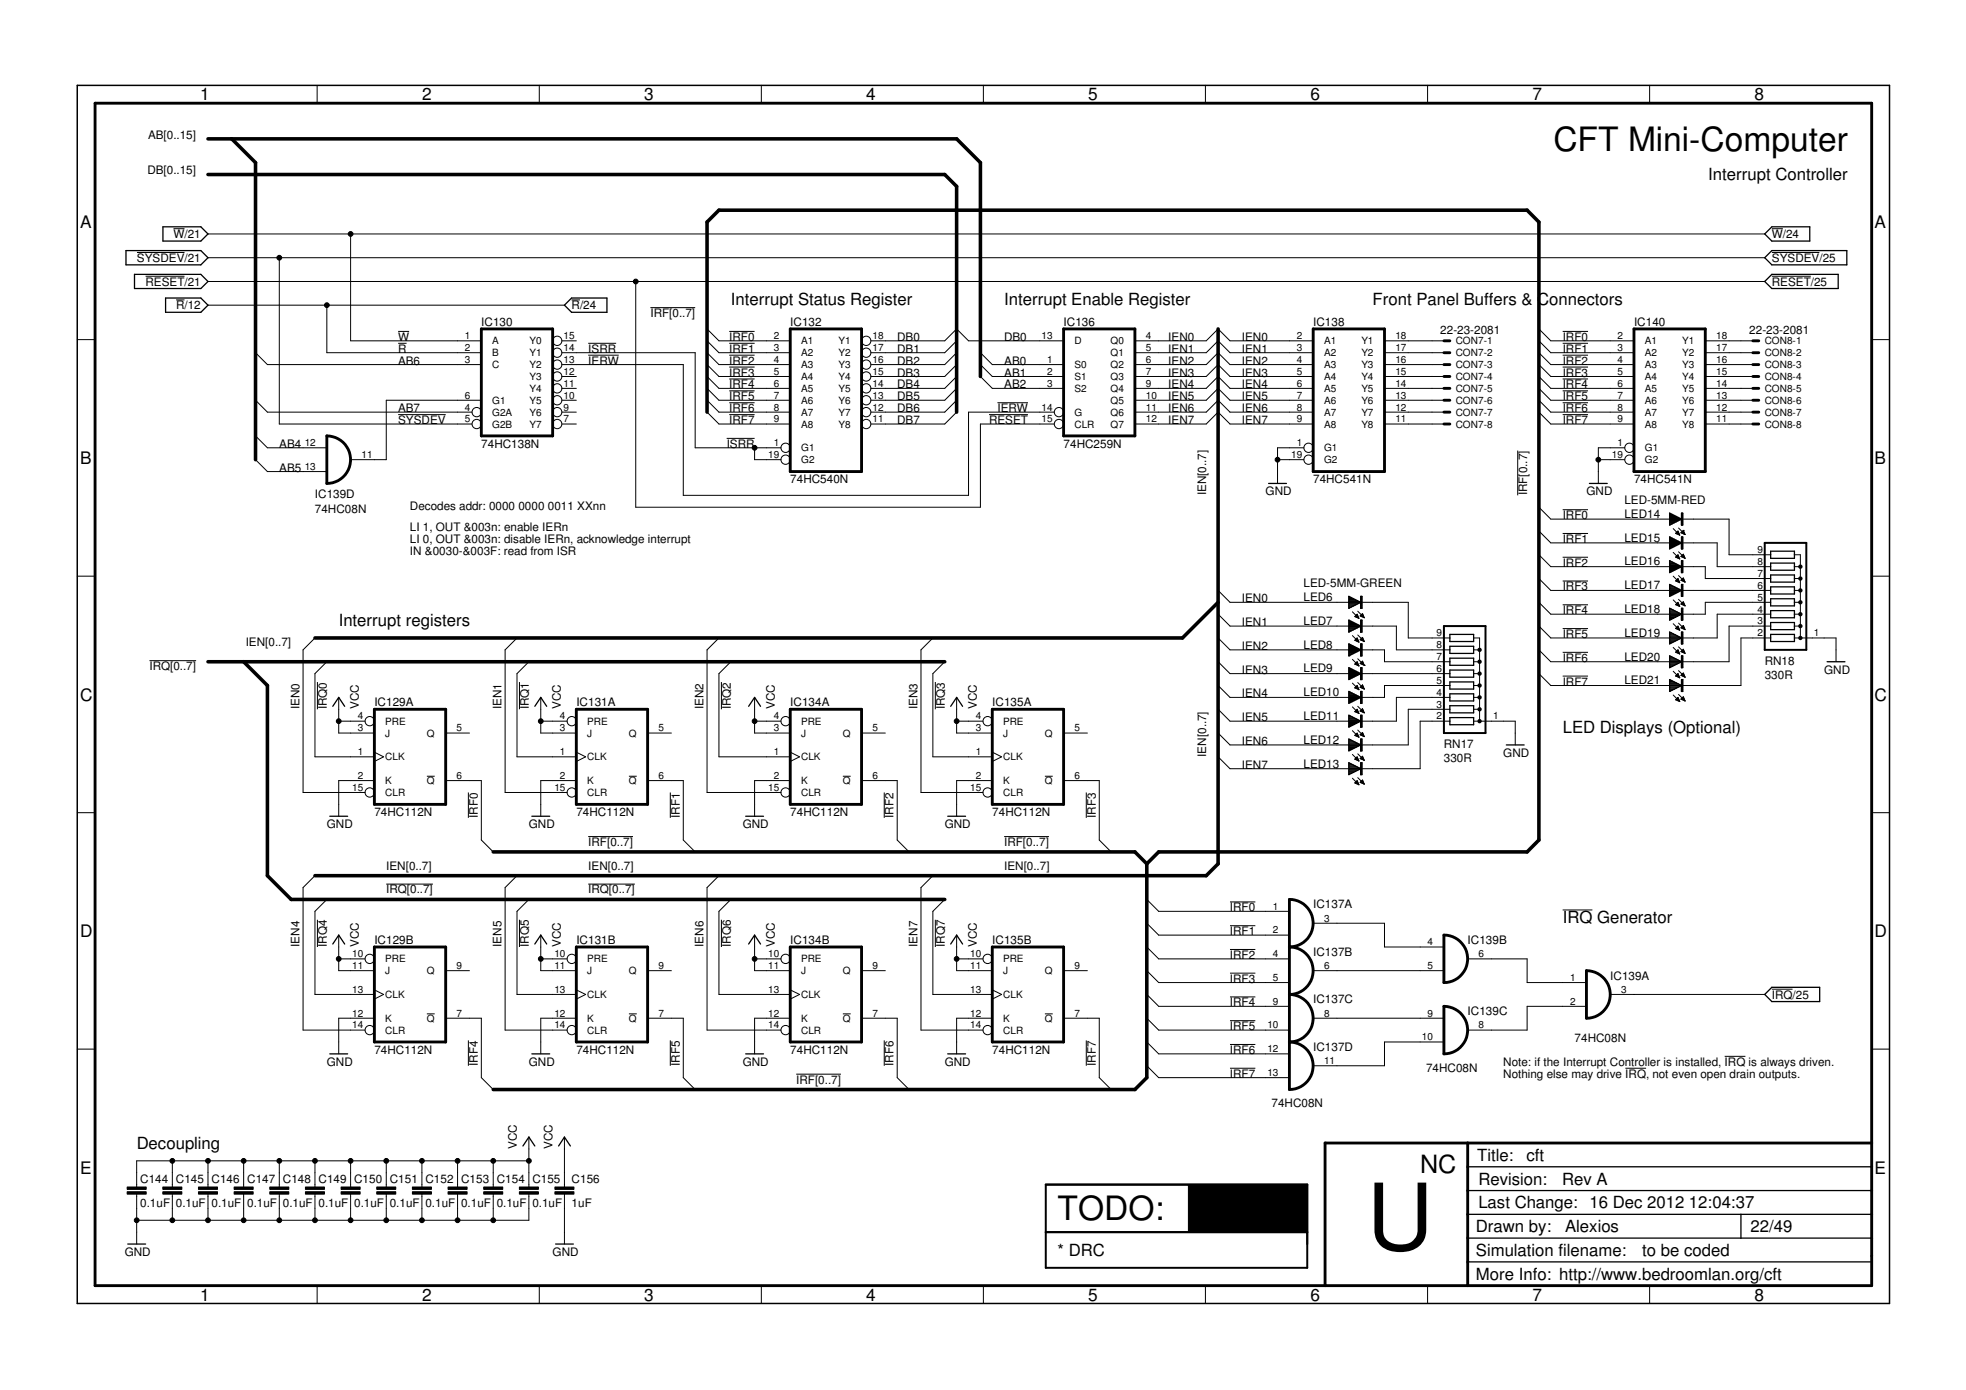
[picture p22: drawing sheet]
<svg xmlns="http://www.w3.org/2000/svg" width="420mm" height="297mm" viewBox="0 0 420 297" stroke-linecap="round" stroke-linejoin="round" font-family="sans-serif">
<defs><g id="words">
<text font-size="19.7" x="292.1" y="267.1">U</text>
<g font-size="7.2">
<text x="332" y="32.2">CFT Mini-Computer</text>
<text x="226" y="260.8">TODO:</text>
</g>
<text font-size="5.4" x="303.5" y="250.6">NC</text>
<g font-size="3.7">
<text x="42.7" y="21.5">1</text>
<text x="90.2" y="21.5">2</text>
<text x="137.7" y="21.5">3</text>
<text x="185.1" y="21.5">4</text>
<text x="232.6" y="21.5">5</text>
<text x="280" y="21.5">6</text>
<text x="327.5" y="21.5">7</text>
<text x="375" y="21.5">8</text>
<text x="17.1" y="48.6">A</text>
<text x="400.6" y="48.6">A</text>
<text x="17.1" y="99.2">B</text>
<text x="400.6" y="99.2">B</text>
<text x="17.1" y="149.7">C</text>
<text x="400.6" y="149.7">C</text>
<text x="17.1" y="200.2">D</text>
<text x="400.6" y="200.2">D</text>
<text x="17.1" y="250.8">E</text>
<text x="400.6" y="250.8">E</text>
<text x="42.7" y="277.9">1</text>
<text x="90.2" y="277.9">2</text>
<text x="137.7" y="277.9">3</text>
<text x="185.1" y="277.9">4</text>
<text x="232.6" y="277.9">5</text>
<text x="280" y="277.9">6</text>
<text x="327.5" y="277.9">7</text>
<text x="375" y="277.9">8</text>
</g>
<g font-size="3.6">
<text x="365.1" y="38.6">Interrupt Controller</text>
<text x="156.2" y="65.2">Interrupt Status Register</text>
<text x="214.6" y="65.2">Interrupt Enable Register</text>
<text x="293.3" y="65.2">Front Panel Buffers &amp; Connectors</text>
<text x="72.4" y="133.8">Interrupt registers</text>
<text x="334" y="156.6">LED Displays (Optional)</text>
<text x="334" y="197.3">IRQ Generator</text>
<text x="29.2" y="245.5">Decoupling</text>
<text x="315.7" y="248.1">Title:</text>
<text x="326.2" y="248.2">cft</text>
<text x="315.9" y="253.2">Revision:</text>
<text x="333.8" y="253.3">Rev A</text>
<text x="315.4" y="263.3">Drawn by:</text>
<text x="315.9" y="258.2">Last Change: 16 Dec 2012</text>
<text x="334.5" y="263.3">Alexios</text>
<text x="361" y="258.1">12:04:37</text>
<text x="374.1" y="263.2">22/49</text>
<text x="226" y="268.4">* DRC</text>
<text x="315.4" y="268.4">Simulation filename:</text>
<text x="351" y="268.4">to be coded</text>
<text x="315.4" y="273.5">More Info: http://www.bedroomlan.org/cft</text>
</g>
<g font-size="2.5">
<text x="31.6" y="29.7">AB[0..15]</text>
<text x="31.5" y="37.3">DB[0..15]</text>
<text x="37.1" y="50.9">W/21</text>
<text x="378.7" y="50.9">W/24</text>
<text x="29.3" y="56">SYSDEV/21</text>
<text x="378.7" y="56">SYSDEV/25</text>
<text x="31.1" y="61">RESET/21</text>
<text x="378.7" y="61">RESET/25</text>
<text x="37.6" y="66.1">R/12</text>
<text x="102.9" y="69.7">IC130</text>
<text x="122.2" y="66.1">R/24</text>
<text x="139" y="67.8">IRF[0..7]</text>
<text x="168.9" y="69.7">IC132</text>
<text x="227.3" y="69.7">IC136</text>
<text x="280.6" y="69.7">IC138</text>
<text x="307.8" y="71.4">22-23-2081</text>
<text x="349.2" y="69.7">IC140</text>
<text x="373.8" y="71.4">22-23-2081</text>
<text x="85.1" y="72.8">W</text>
<text x="85.1" y="75.4">R</text>
<text x="85.1" y="77.9">AB6</text>
<text x="125.7" y="77.9">IERW</text>
<text x="125.7" y="75.4">ISRR</text>
<text x="155.9" y="72.8">IRF0</text>
<text x="155.9" y="75.4">IRF1</text>
<text x="155.9" y="77.9">IRF2</text>
<text x="191.7" y="72.8">DB0</text>
<text x="191.7" y="75.4">DB1</text>
<text x="191.7" y="77.9">DB2</text>
<text x="214.6" y="72.8">DB0</text>
<text x="214.6" y="77.9">AB0</text>
<text x="249.7" y="75.4">IEN1</text>
<text x="249.7" y="72.8">IEN0</text>
<text x="249.7" y="77.9">IEN2</text>
<text x="265.4" y="75.4">IEN1</text>
<text x="265.4" y="72.8">IEN0</text>
<text x="265.4" y="77.9">IEN2</text>
<text x="334" y="72.8">IRF0</text>
<text x="334" y="75.4">IRF1</text>
<text x="334" y="77.9">IRF2</text>
<text x="155.9" y="80.5">IRF3</text>
<text x="155.9" y="83">IRF4</text>
<text x="191.7" y="80.5">DB3</text>
<text x="191.7" y="83">DB4</text>
<text x="214.6" y="80.5">AB1</text>
<text x="214.6" y="83">AB2</text>
<text x="249.7" y="83">IEN4</text>
<text x="249.7" y="80.5">IEN3</text>
<text x="265.4" y="83">IEN4</text>
<text x="265.4" y="80.5">IEN3</text>
<text x="334" y="80.5">IRF3</text>
<text x="334" y="83">IRF4</text>
<text x="85.1" y="88.1">AB7</text>
<text x="155.9" y="85.5">IRF5</text>
<text x="155.9" y="88.1">IRF6</text>
<text x="191.7" y="85.5">DB5</text>
<text x="191.7" y="88.1">DB6</text>
<text x="213.2" y="88.1">IERW</text>
<text x="249.7" y="85.5">IEN5</text>
<text x="249.7" y="88.1">IEN6</text>
<text x="265.4" y="85.5">IEN5</text>
<text x="265.4" y="88.1">IEN6</text>
<text x="334" y="85.5">IRF5</text>
<text x="334" y="88.1">IRF6</text>
<text x="59.7" y="95.7">AB4</text>
<text x="85.1" y="90.6">SYSDEV</text>
<text x="102.9" y="95.7">74HC138N</text>
<text x="155.3" y="95.7">ISRR</text>
<text x="155.9" y="90.6">IRF7</text>
<text x="191.7" y="90.6">DB7</text>
<text x="211.4" y="90.6">RESET</text>
<text x="227.3" y="95.7">74HC259N</text>
<text x="249.7" y="90.6">IEN7</text>
<text x="265.4" y="90.6">IEN7</text>
<text x="334" y="90.6">IRF7</text>
<text x="59.7" y="100.8">AB5</text>
<text x="67.3" y="106.5">IC139D</text>
<text x="168.9" y="103.3">74HC540N</text>
<text x="257.8" y="105.9" transform="rotate(-90 257.8 105.9)">IEN[0..7]</text>
<text x="270.5" y="105.9">GND</text>
<text x="280.6" y="103.3">74HC541N</text>
<text x="326.4" y="105.9" transform="rotate(-90 326.4 105.9)">IRF[0..7]</text>
<text x="339.1" y="105.9">GND</text>
<text x="347.2" y="107.8">LED-5MM-RED</text>
<text x="349.2" y="103.3">74HC541N</text>
<text x="67.3" y="109.7">74HC08N</text>
<text x="87.6" y="108.9">Decodes addr: 0000</text>
<text x="87.6" y="113.5">LI 1, OUT &amp;003n: enable IERn</text>
<text x="110.8" y="108.9">0000</text>
<text x="117.1" y="108.9">0011 XXnn</text>
<text x="334" y="110.9">IRF0</text>
<text x="347.2" y="110.7">LED14</text>
<text x="87.6" y="116">LI 0, OUT &amp;003n: disable IERn, acknowledge interrupt</text>
<text x="87.6" y="118.6">IN &amp;0030-&amp;003F: read from ISR</text>
<text x="334" y="116">IRF1</text>
<text x="347.2" y="115.8">LED15</text>
<text x="278.6" y="125.5">LED-5MM-GREEN</text>
<text x="334" y="121.1">IRF2</text>
<text x="347.2" y="120.8">LED16</text>
<text x="347.2" y="125.9">LED17</text>
<text x="265.4" y="128.7">IEN0</text>
<text x="278.6" y="128.5">LED6</text>
<text x="334" y="126.2">IRF3</text>
<text x="334" y="131.3">IRF4</text>
<text x="347.2" y="131">LED18</text>
<text x="265.4" y="133.8">IEN1</text>
<text x="278.6" y="133.5">LED7</text>
<text x="334" y="136.3">IRF5</text>
<text x="347.2" y="136.1">LED19</text>
<text x="31.9" y="143.2">IRQ[0..7]</text>
<text x="52.5" y="138.1">IEN[0..7]</text>
<text x="265.4" y="138.9">IEN2</text>
<text x="265.4" y="144">IEN3</text>
<text x="278.6" y="138.6">LED8</text>
<text x="278.6" y="143.7">LED9</text>
<text x="334" y="141.4">IRF6</text>
<text x="347.2" y="141.2">LED20</text>
<text x="377.1" y="142">RN18</text>
<text x="389.8" y="144">GND</text>
<text x="265.4" y="149">IEN4</text>
<text x="278.6" y="148.8">LED10</text>
<text x="334" y="146.5">IRF7</text>
<text x="347.2" y="146.2">LED21</text>
<text x="377.1" y="145.1">330R</text>
<text x="64" y="151.6" transform="rotate(-90 64 151.6)">IEN0</text>
<text x="69.8" y="151.6" transform="rotate(-90 69.8 151.6)">IRQ0</text>
<text x="76.7" y="151.6" transform="rotate(-90 76.7 151.6)">VCC</text>
<text x="80" y="150.9">IC129A</text>
<text x="107.2" y="151.6" transform="rotate(-90 107.2 151.6)">IEN1</text>
<text x="113" y="151.6" transform="rotate(-90 113 151.6)">IRQ1</text>
<text x="119.9" y="151.6" transform="rotate(-90 119.9 151.6)">VCC</text>
<text x="123.2" y="150.9">IC131A</text>
<text x="150.4" y="151.6" transform="rotate(-90 150.4 151.6)">IEN2</text>
<text x="156.2" y="151.6" transform="rotate(-90 156.2 151.6)">IRQ2</text>
<text x="165.6" y="151.6" transform="rotate(-90 165.6 151.6)">VCC</text>
<text x="168.9" y="150.9">IC134A</text>
<text x="196.1" y="151.6" transform="rotate(-90 196.1 151.6)">IEN3</text>
<text x="201.9" y="151.6" transform="rotate(-90 201.9 151.6)">IRQ3</text>
<text x="208.8" y="151.6" transform="rotate(-90 208.8 151.6)">VCC</text>
<text x="212.1" y="150.9">IC135A</text>
<text x="265.4" y="154.1">IEN5</text>
<text x="278.6" y="153.9">LED11</text>
<text x="257.8" y="161.7" transform="rotate(-90 257.8 161.7)">IEN[0..7]</text>
<text x="265.4" y="159.2">IEN6</text>
<text x="278.6" y="158.9">LED12</text>
<text x="308.6" y="159.8">RN17</text>
<text x="321.3" y="161.7">GND</text>
<text x="265.4" y="164.3">IEN7</text>
<text x="278.6" y="164">LED13</text>
<text x="308.6" y="162.9">330R</text>
<text x="69.8" y="177">GND</text>
<text x="80" y="174.4">74HC112N</text>
<text x="102.1" y="174.8" transform="rotate(-90 102.1 174.8)">IRF0</text>
<text x="113" y="177">GND</text>
<text x="123.2" y="174.4">74HC112N</text>
<text x="145.3" y="174.8" transform="rotate(-90 145.3 174.8)">IRF1</text>
<text x="158.7" y="177">GND</text>
<text x="168.9" y="174.4">74HC112N</text>
<text x="191" y="174.8" transform="rotate(-90 191 174.8)">IRF2</text>
<text x="201.9" y="177">GND</text>
<text x="212.1" y="174.4">74HC112N</text>
<text x="234.2" y="174.8" transform="rotate(-90 234.2 174.8)">IRF3</text>
<text x="82.5" y="185.9">IEN[0..7]</text>
<text x="125.7" y="185.9">IEN[0..7]</text>
<text x="125.7" y="180.8">IRF[0..7]</text>
<text x="214.6" y="185.9">IEN[0..7]</text>
<text x="214.6" y="180.8">IRF[0..7]</text>
<text x="82.5" y="190.9">IRQ[0..7]</text>
<text x="125.7" y="190.9">IRQ[0..7]</text>
<text x="262.9" y="194.7">IRF0</text>
<text x="280.6" y="194.1">IC137A</text>
<text x="64" y="202.4" transform="rotate(-90 64 202.4)">IEN4</text>
<text x="69.8" y="202.4" transform="rotate(-90 69.8 202.4)">IRQ4</text>
<text x="76.7" y="202.4" transform="rotate(-90 76.7 202.4)">VCC</text>
<text x="80" y="201.7">IC129B</text>
<text x="107.2" y="202.4" transform="rotate(-90 107.2 202.4)">IEN5</text>
<text x="113" y="202.4" transform="rotate(-90 113 202.4)">IRQ5</text>
<text x="119.9" y="202.4" transform="rotate(-90 119.9 202.4)">VCC</text>
<text x="123.2" y="201.7">IC131B</text>
<text x="150.4" y="202.4" transform="rotate(-90 150.4 202.4)">IEN6</text>
<text x="156.2" y="202.4" transform="rotate(-90 156.2 202.4)">IRQ6</text>
<text x="165.6" y="202.4" transform="rotate(-90 165.6 202.4)">VCC</text>
<text x="168.9" y="201.7">IC134B</text>
<text x="196.1" y="202.4" transform="rotate(-90 196.1 202.4)">IEN7</text>
<text x="201.9" y="202.4" transform="rotate(-90 201.9 202.4)">IRQ7</text>
<text x="208.8" y="202.4" transform="rotate(-90 208.8 202.4)">VCC</text>
<text x="212.1" y="201.7">IC135B</text>
<text x="262.9" y="199.8">IRF1</text>
<text x="313.7" y="201.7">IC139B</text>
<text x="262.9" y="204.9">IRF2</text>
<text x="262.9" y="210">IRF3</text>
<text x="280.6" y="204.3">IC137B</text>
<text x="344.1" y="209.3">IC139A</text>
<text x="262.9" y="215.1">IRF4</text>
<text x="280.6" y="214.4">IC137C</text>
<text x="378.7" y="213.4">IRQ/25</text>
<text x="262.9" y="220.1">IRF5</text>
<text x="313.7" y="217">IC139C</text>
<text x="69.8" y="227.8">GND</text>
<text x="80" y="225.2">74HC112N</text>
<text x="102.1" y="227.8" transform="rotate(-90 102.1 227.8)">IRF4</text>
<text x="113" y="227.8">GND</text>
<text x="123.2" y="225.2">74HC112N</text>
<text x="145.3" y="227.8" transform="rotate(-90 145.3 227.8)">IRF5</text>
<text x="158.7" y="227.8">GND</text>
<text x="168.9" y="225.2">74HC112N</text>
<text x="191" y="227.8" transform="rotate(-90 191 227.8)">IRF6</text>
<text x="201.9" y="227.8">GND</text>
<text x="212.1" y="225.2">74HC112N</text>
<text x="234.2" y="227.8" transform="rotate(-90 234.2 227.8)">IRF7</text>
<text x="262.9" y="225.2">IRF6</text>
<text x="280.6" y="224.6">IC137D</text>
<text x="321.3" y="227.8">Note: if the Interrupt Controller is installed, IRQ is always driven.</text>
<text x="336.5" y="222.7">74HC08N</text>
<text x="170.2" y="231.6">IRF[0..7]</text>
<text x="262.9" y="230.3">IRF7</text>
<text x="304.8" y="229">74HC08N</text>
<text x="321.3" y="230.3">Nothing else may drive IRQ, not even open drain outputs.</text>
<text x="271.7" y="236.6">74HC08N</text>
<text x="110.5" y="245.5" transform="rotate(-90 110.5 245.5)">VCC</text>
<text x="118.1" y="245.5" transform="rotate(-90 118.1 245.5)">VCC</text>
<text x="30" y="257.9">0.1uF</text>
<text x="30" y="252.8">C144</text>
<text x="37.6" y="257.9">0.1uF</text>
<text x="37.6" y="252.8">C145</text>
<text x="45.2" y="257.9">0.1uF</text>
<text x="45.2" y="252.8">C146</text>
<text x="52.8" y="257.9">0.1uF</text>
<text x="52.8" y="252.8">C147</text>
<text x="60.4" y="257.9">0.1uF</text>
<text x="60.4" y="252.8">C148</text>
<text x="68.1" y="257.9">0.1uF</text>
<text x="68.1" y="252.8">C149</text>
<text x="75.7" y="257.9">0.1uF</text>
<text x="75.7" y="252.8">C150</text>
<text x="83.3" y="257.9">0.1uF</text>
<text x="83.3" y="252.8">C151</text>
<text x="90.9" y="257.9">0.1uF</text>
<text x="90.9" y="252.8">C152</text>
<text x="98.5" y="257.9">0.1uF</text>
<text x="98.5" y="252.8">C153</text>
<text x="106.2" y="257.9">0.1uF</text>
<text x="106.2" y="252.8">C154</text>
<text x="113.8" y="257.9">0.1uF</text>
<text x="113.8" y="252.8">C155</text>
<text x="122.2" y="257.9">1uF</text>
<text x="122.2" y="252.8">C156</text>
<text x="26.7" y="268.4">GND</text>
<text x="118.1" y="268.4">GND</text>
</g>
<g font-size="2.1">
<text x="99.3" y="72.5">1</text>
<text x="99.3" y="75">2</text>
<text x="99.3" y="77.6">3</text>
<text x="105.2" y="73.6">A</text>
<text x="105.2" y="76.1">B</text>
<text x="113.2" y="76.1">Y1</text>
<text x="113.2" y="73.6">Y0</text>
<text x="120.4" y="77.6">13</text>
<text x="120.4" y="75">14</text>
<text x="120.4" y="72.5">15</text>
<text x="165.4" y="72.5">2</text>
<text x="165.4" y="75">3</text>
<text x="165.4" y="77.6">4</text>
<text x="171.2" y="73.6">A1</text>
<text x="171.2" y="76.1">A2</text>
<text x="179.2" y="76.1">Y2</text>
<text x="179.2" y="73.6">Y1</text>
<text x="186.5" y="77.6">16</text>
<text x="186.5" y="75">17</text>
<text x="186.5" y="72.5">18</text>
<text x="222.6" y="72.5">13</text>
<text x="223.8" y="77.6">1</text>
<text x="229.6" y="73.6">D</text>
<text x="237.3" y="73.6">Q0</text>
<text x="237.3" y="76.1">Q1</text>
<text x="244.9" y="72.5">4</text>
<text x="244.9" y="75">5</text>
<text x="244.9" y="77.6">6</text>
<text x="277.1" y="72.5">2</text>
<text x="277.1" y="75">3</text>
<text x="277.1" y="77.6">4</text>
<text x="283" y="73.6">A1</text>
<text x="283" y="76.1">A2</text>
<text x="290.9" y="76.1">Y2</text>
<text x="290.9" y="73.6">Y1</text>
<text x="298.2" y="77.6">16</text>
<text x="298.2" y="75">17</text>
<text x="298.2" y="72.5">18</text>
<text x="311.1" y="73.6">CON7-1</text>
<text x="311.1" y="76.1">CON7-2</text>
<text x="345.7" y="72.5">2</text>
<text x="345.7" y="75">3</text>
<text x="345.7" y="77.6">4</text>
<text x="351.5" y="73.6">A1</text>
<text x="351.5" y="76.1">A2</text>
<text x="359.5" y="76.1">Y2</text>
<text x="359.5" y="73.6">Y1</text>
<text x="366.8" y="77.6">16</text>
<text x="366.8" y="75">17</text>
<text x="366.8" y="72.5">18</text>
<text x="377.1" y="73.6">CON8-1</text>
<text x="377.1" y="76.1">CON8-2</text>
<text x="105.2" y="78.7">C</text>
<text x="113.2" y="83.8">Y4</text>
<text x="113.2" y="81.2">Y3</text>
<text x="113.2" y="78.7">Y2</text>
<text x="120.4" y="82.6">11</text>
<text x="120.4" y="80.1">12</text>
<text x="165.4" y="80.1">5</text>
<text x="165.4" y="82.6">6</text>
<text x="171.2" y="78.7">A3</text>
<text x="171.2" y="81.2">A4</text>
<text x="171.2" y="83.8">A5</text>
<text x="179.2" y="83.8">Y5</text>
<text x="179.2" y="81.2">Y4</text>
<text x="179.2" y="78.7">Y3</text>
<text x="186.5" y="82.6">14</text>
<text x="186.5" y="80.1">15</text>
<text x="223.8" y="80.1">2</text>
<text x="223.8" y="82.6">3</text>
<text x="229.6" y="78.7">S0</text>
<text x="229.6" y="81.2">S1</text>
<text x="229.6" y="83.8">S2</text>
<text x="237.3" y="78.7">Q2</text>
<text x="237.3" y="81.2">Q3</text>
<text x="237.3" y="83.8">Q4</text>
<text x="244.9" y="80.1">7</text>
<text x="244.9" y="82.6">9</text>
<text x="277.1" y="80.1">5</text>
<text x="277.1" y="82.6">6</text>
<text x="283" y="78.7">A3</text>
<text x="283" y="81.2">A4</text>
<text x="283" y="83.8">A5</text>
<text x="290.9" y="83.8">Y5</text>
<text x="290.9" y="81.2">Y4</text>
<text x="290.9" y="78.7">Y3</text>
<text x="298.2" y="82.6">14</text>
<text x="298.2" y="80.1">15</text>
<text x="311.1" y="78.7">CON7-3</text>
<text x="311.1" y="81.2">CON7-4</text>
<text x="311.1" y="83.8">CON7-5</text>
<text x="345.7" y="80.1">5</text>
<text x="345.7" y="82.6">6</text>
<text x="351.5" y="78.7">A3</text>
<text x="351.5" y="81.2">A4</text>
<text x="351.5" y="83.8">A5</text>
<text x="359.5" y="83.8">Y5</text>
<text x="359.5" y="81.2">Y4</text>
<text x="359.5" y="78.7">Y3</text>
<text x="366.8" y="82.6">14</text>
<text x="366.8" y="80.1">15</text>
<text x="377.1" y="78.7">CON8-3</text>
<text x="377.1" y="81.2">CON8-4</text>
<text x="377.1" y="83.8">CON8-5</text>
<text x="99.3" y="87.7">4</text>
<text x="99.3" y="85.2">6</text>
<text x="105.2" y="88.8">G2A</text>
<text x="105.2" y="86.3">G1</text>
<text x="113.2" y="88.8">Y6</text>
<text x="113.2" y="86.3">Y5</text>
<text x="120.4" y="87.7">9</text>
<text x="120.4" y="85.2">10</text>
<text x="165.4" y="85.2">7</text>
<text x="165.4" y="87.7">8</text>
<text x="171.2" y="86.3">A6</text>
<text x="171.2" y="88.8">A7</text>
<text x="179.2" y="88.8">Y7</text>
<text x="179.2" y="86.3">Y6</text>
<text x="186.5" y="87.7">12</text>
<text x="186.5" y="85.2">13</text>
<text x="222.6" y="87.7">14</text>
<text x="229.6" y="88.8">G</text>
<text x="237.3" y="86.3">Q5</text>
<text x="237.3" y="88.8">Q6</text>
<text x="244.9" y="85.2">10</text>
<text x="244.9" y="87.7">11</text>
<text x="277.1" y="85.2">7</text>
<text x="277.1" y="87.7">8</text>
<text x="283" y="86.3">A6</text>
<text x="283" y="88.8">A7</text>
<text x="290.9" y="88.8">Y7</text>
<text x="290.9" y="86.3">Y6</text>
<text x="298.2" y="87.7">12</text>
<text x="298.2" y="85.2">13</text>
<text x="311.1" y="86.3">CON7-6</text>
<text x="311.1" y="88.8">CON7-7</text>
<text x="345.7" y="85.2">7</text>
<text x="345.7" y="87.7">8</text>
<text x="351.5" y="86.3">A6</text>
<text x="351.5" y="88.8">A7</text>
<text x="359.5" y="88.8">Y7</text>
<text x="359.5" y="86.3">Y6</text>
<text x="366.8" y="87.7">12</text>
<text x="366.8" y="85.2">13</text>
<text x="377.1" y="86.3">CON8-6</text>
<text x="377.1" y="88.8">CON8-7</text>
<text x="65.1" y="95.3">12</text>
<text x="99.3" y="90.3">5</text>
<text x="105.2" y="91.4">G2B</text>
<text x="113.2" y="91.4">Y7</text>
<text x="120.4" y="90.3">7</text>
<text x="165.4" y="95.3">1</text>
<text x="165.4" y="90.3">9</text>
<text x="171.2" y="91.4">A8</text>
<text x="179.2" y="91.4">Y8</text>
<text x="186.5" y="90.3">11</text>
<text x="222.6" y="90.3">15</text>
<text x="229.6" y="91.4">CLR</text>
<text x="237.3" y="91.4">Q7</text>
<text x="244.9" y="90.3">12</text>
<text x="277.1" y="95.3">1</text>
<text x="277.1" y="90.3">9</text>
<text x="283" y="91.4">A8</text>
<text x="290.9" y="91.4">Y8</text>
<text x="298.2" y="90.3">11</text>
<text x="311.1" y="91.4">CON7-8</text>
<text x="345.7" y="95.3">1</text>
<text x="345.7" y="90.3">9</text>
<text x="351.5" y="91.4">A8</text>
<text x="359.5" y="91.4">Y8</text>
<text x="366.8" y="90.3">11</text>
<text x="377.1" y="91.4">CON8-8</text>
<text x="65.1" y="100.4">13</text>
<text x="77.3" y="97.9">11</text>
<text x="164.2" y="97.9">19</text>
<text x="171.2" y="96.5">G1</text>
<text x="171.2" y="99">G2</text>
<text x="275.9" y="97.9">19</text>
<text x="283" y="96.5">G1</text>
<text x="283" y="99">G2</text>
<text x="344.5" y="97.9">19</text>
<text x="351.5" y="96.5">G1</text>
<text x="351.5" y="99">G2</text>
<text x="375.6" y="118.2">9</text>
<text x="375.6" y="125.8">6</text>
<text x="375.6" y="123.3">7</text>
<text x="375.6" y="120.7">8</text>
<text x="375.6" y="130.9">4</text>
<text x="375.6" y="128.4">5</text>
<text x="307" y="136">9</text>
<text x="375.6" y="136">2</text>
<text x="375.6" y="133.4">3</text>
<text x="387.7" y="136">1</text>
<text x="307" y="143.6">6</text>
<text x="307" y="141.1">7</text>
<text x="307" y="138.5">8</text>
<text x="307" y="148.7">4</text>
<text x="307" y="146.1">5</text>
<text x="76.5" y="153.8">4</text>
<text x="82.3" y="154.9">PRE</text>
<text x="119.7" y="153.8">4</text>
<text x="125.5" y="154.9">PRE</text>
<text x="165.4" y="153.8">4</text>
<text x="171.2" y="154.9">PRE</text>
<text x="208.5" y="153.8">4</text>
<text x="214.4" y="154.9">PRE</text>
<text x="307" y="153.8">2</text>
<text x="307" y="151.2">3</text>
<text x="319.1" y="153.8">1</text>
<text x="76.5" y="161.4">1</text>
<text x="76.5" y="156.3">3</text>
<text x="82.3" y="157.4">J</text>
<text x="91.2" y="157.4">Q</text>
<text x="97.6" y="156.3">5</text>
<text x="119.7" y="161.4">1</text>
<text x="119.7" y="156.3">3</text>
<text x="125.5" y="157.4">J</text>
<text x="134.4" y="157.4">Q</text>
<text x="140.8" y="156.3">5</text>
<text x="165.4" y="161.4">1</text>
<text x="165.4" y="156.3">3</text>
<text x="171.2" y="157.4">J</text>
<text x="180.1" y="157.4">Q</text>
<text x="186.5" y="156.3">5</text>
<text x="208.5" y="161.4">1</text>
<text x="208.5" y="156.3">3</text>
<text x="214.4" y="157.4">J</text>
<text x="223.3" y="157.4">Q</text>
<text x="229.6" y="156.3">5</text>
<text x="76.5" y="166.5">2</text>
<text x="82.3" y="162.5">CLK</text>
<text x="82.3" y="167.6">K</text>
<text x="91.2" y="167.6">Q</text>
<text x="97.6" y="166.5">6</text>
<text x="119.7" y="166.5">2</text>
<text x="125.5" y="162.5">CLK</text>
<text x="125.5" y="167.6">K</text>
<text x="134.4" y="167.6">Q</text>
<text x="140.8" y="166.5">6</text>
<text x="165.4" y="166.5">2</text>
<text x="171.2" y="162.5">CLK</text>
<text x="171.2" y="167.6">K</text>
<text x="180.1" y="167.6">Q</text>
<text x="186.5" y="166.5">6</text>
<text x="208.5" y="166.5">2</text>
<text x="214.4" y="162.5">CLK</text>
<text x="214.4" y="167.6">K</text>
<text x="223.3" y="167.6">Q</text>
<text x="229.6" y="166.5">6</text>
<text x="75.3" y="169">15</text>
<text x="82.3" y="170.1">CLR</text>
<text x="118.5" y="169">15</text>
<text x="125.5" y="170.1">CLR</text>
<text x="164.2" y="169">15</text>
<text x="171.2" y="170.1">CLR</text>
<text x="207.4" y="169">15</text>
<text x="214.4" y="170.1">CLR</text>
<text x="272" y="194.4">1</text>
<text x="283" y="196.9">3</text>
<text x="272" y="199.5">2</text>
<text x="305.1" y="202">4</text>
<text x="75.3" y="207.1">11</text>
<text x="75.3" y="204.5">10</text>
<text x="82.3" y="208.2">J</text>
<text x="82.3" y="205.7">PRE</text>
<text x="91.2" y="208.2">Q</text>
<text x="97.6" y="207.1">9</text>
<text x="118.5" y="207.1">11</text>
<text x="118.5" y="204.5">10</text>
<text x="125.5" y="208.2">J</text>
<text x="125.5" y="205.7">PRE</text>
<text x="134.4" y="208.2">Q</text>
<text x="140.8" y="207.1">9</text>
<text x="164.2" y="207.1">11</text>
<text x="164.2" y="204.5">10</text>
<text x="171.2" y="208.2">J</text>
<text x="171.2" y="205.7">PRE</text>
<text x="180.1" y="208.2">Q</text>
<text x="186.5" y="207.1">9</text>
<text x="207.4" y="207.1">11</text>
<text x="207.4" y="204.5">10</text>
<text x="214.4" y="208.2">J</text>
<text x="214.4" y="205.7">PRE</text>
<text x="223.3" y="208.2">Q</text>
<text x="229.6" y="207.1">9</text>
<text x="272" y="204.5">4</text>
<text x="272" y="209.6">5</text>
<text x="283" y="207.1">6</text>
<text x="305.1" y="207.1">5</text>
<text x="316" y="204.5">6</text>
<text x="335.5" y="209.6">1</text>
<text x="75.3" y="212.2">13</text>
<text x="82.3" y="213.3">CLK</text>
<text x="118.5" y="212.2">13</text>
<text x="125.5" y="213.3">CLK</text>
<text x="164.2" y="212.2">13</text>
<text x="171.2" y="213.3">CLK</text>
<text x="207.4" y="212.2">13</text>
<text x="214.4" y="213.3">CLK</text>
<text x="272" y="214.7">9</text>
<text x="335.5" y="214.7">2</text>
<text x="346.5" y="212.2">3</text>
<text x="75.3" y="217.2">12</text>
<text x="75.3" y="219.8">14</text>
<text x="82.3" y="218.4">K</text>
<text x="82.3" y="220.9">CLR</text>
<text x="91.2" y="218.4">Q</text>
<text x="97.6" y="217.2">7</text>
<text x="118.5" y="217.2">12</text>
<text x="118.5" y="219.8">14</text>
<text x="125.5" y="218.4">K</text>
<text x="125.5" y="220.9">CLR</text>
<text x="134.4" y="218.4">Q</text>
<text x="140.8" y="217.2">7</text>
<text x="164.2" y="217.2">12</text>
<text x="164.2" y="219.8">14</text>
<text x="171.2" y="218.4">K</text>
<text x="171.2" y="220.9">CLR</text>
<text x="180.1" y="218.4">Q</text>
<text x="186.5" y="217.2">7</text>
<text x="207.4" y="217.2">12</text>
<text x="207.4" y="219.8">14</text>
<text x="214.4" y="218.4">K</text>
<text x="214.4" y="220.9">CLR</text>
<text x="223.3" y="218.4">Q</text>
<text x="229.6" y="217.2">7</text>
<text x="270.9" y="219.8">10</text>
<text x="283" y="217.2">8</text>
<text x="305.1" y="217.2">9</text>
<text x="316" y="219.8">8</text>
<text x="270.9" y="224.9">12</text>
<text x="283" y="227.4">11</text>
<text x="303.9" y="222.3">10</text>
<text x="270.9" y="229.9">13</text>
</g>
</g></defs>
<g fill="#000" stroke="#000" stroke-width=".21">
<path d="M67.8 18.2v3.9zM115.3 18.2v3.9zM162.7 18.2v3.9zM210.2 18.2v3.9zM257.6 18.2v3.9zM305.1 18.2v3.9zM352.5 18.2v3.9zM20.3 22.1v252.6zM20.3 22.1h379.7zM29.3 54h10.1zM31.1 59h8.3zM37.1 48.9h2.3z"/>
<path d="M44.4 55.1h15.3zM59.7 55.1h317.4zM44.4 50h30.5zM74.9 50h302.2zM378.7 59h8.3zM378.7 48.9h2.3zM378.7 54h10.1zM16.5 72.6h3.8zM37.6 64.1h1.8zM44.4 65.2h25.4zM54.6 75.4l2.5 2.5zM69.8 65.2v10.2z"/>
<path d="M69.8 65.2h50.8zM74.9 50v22.8zM85.1 70.8h2.3zM85.1 73.4h1.8zM97.8 72.8h5.1zM97.8 75.4h5.1zM97.8 77.9h5.1zM74.9 72.8h22.9zM69.8 75.4h28zM57.1 77.9h40.7zM122.2 64.1h1.7zM120.1 77.9h3.1z"/>
<path d="M120.1 75.4h3.1zM120.1 72.8h3.1zM125.7 75.9h6.5zM125.7 73.4h6zM44.4 60.2h91.5zM139 65.7h9.6zM146 77.9v28zM123.2 77.9h22.8zM123.2 75.4h25.4zM151.1 70.3l2.5 2.5zM151.1 72.8l2.5 2.6zM151.1 75.4l2.5 2.5z"/>
<path d="M151.1 77.9l2.5 2.6zM153.6 72.8h10.2zM153.6 75.4h10.2zM153.6 77.9h10.2zM155.8 70.8h5.5zM155.8 73.4h5.5zM155.8 75.9h5.5zM155.8 78.4h5.5zM163.8 72.8h5.1zM163.8 75.4h5.1zM163.8 77.9h5.1zM186.1 77.9h3.1z"/>
<path d="M186.1 75.4h3.1zM186.1 72.8h3.1zM189.2 72.8h12.7zM189.2 75.4h12.7zM189.2 77.9h12.7zM204.4 70.3l-2.5 2.5zM204.4 72.8l-2.5 2.6zM204.4 75.4l-2.5 2.5zM204.4 77.9l-2.5 2.6zM204.4 70.3l2.6 2.5zM209.5 75.4l2.6 2.5zM222.2 77.9h5.1z"/>
<path d="M222.2 72.8h5.1zM207 72.8h15.2zM212.1 77.9h10.1zM242.5 72.8h5.1zM242.5 75.4h5.1zM242.5 77.9h5.1zM247.6 75.4h10.2zM247.6 72.8h10.2zM247.6 77.9h10.2zM260.3 72.8l-2.5 2.6zM260.3 72.8l2.6 2.6zM260.3 70.3l-2.5 2.5z"/>
<path d="M260.3 70.3l2.6 2.5zM260.3 75.4l-2.5 2.5zM260.3 75.4l2.6 2.5zM257.8 80.5l2.5-2.6zM260.3 77.9l2.6 2.6zM262.9 75.4h12.7zM262.9 72.8h12.7zM262.9 77.9h12.7zM275.6 72.8h5zM275.6 75.4h5zM275.6 77.9h5zM295.9 77.9h5.1z"/>
<path d="M295.9 75.4h5.1zM295.9 72.8h5.1zM306 72.8h2.6zM306 75.4h2.6zM306 77.9h2.6zM301 72.8h5zM301 75.4h5zM301 77.9h5zM328.9 70.3l2.5 2.5zM328.9 72.8l2.5 2.6zM328.9 75.4l2.5 2.5zM328.9 77.9l2.5 2.6z"/>
<path d="M331.4 72.8h12.7zM331.4 75.4h12.7zM331.4 77.9h12.7zM334 70.8h5.4zM334 73.4h5.4zM334 75.9h5.4zM334 78.4h5.4zM344.1 72.8h5.1zM344.1 75.4h5.1zM344.1 77.9h5.1zM364.4 77.9h5.1zM364.4 75.4h5.1z"/>
<path d="M364.4 72.8h5.1zM372.1 72.8h2.5zM372.1 75.4h2.5zM372.1 77.9h2.5zM369.5 72.8h2.6zM369.5 75.4h2.6zM369.5 77.9h2.6zM135.9 60.2h241.2zM400 72.6h3.8zM54.6 85.5l2.5 2.6zM54.6 93.2l2.5 2.5zM59.7 55.1v35.5z"/>
<path d="M64.8 95.7h5zM57.1 95.7h7.7zM74.9 98.2h5.1zM80 98.2h2.5zM82.5 85.5v12.7zM82.5 85.5h15.3zM85.1 88.6h10.1zM97.8 88.1h3.1zM97.8 90.6h3.1zM97.8 85.5h5.1zM59.7 90.6h38.1zM57.1 88.1h40.7z"/>
<path d="M120.1 90.6h3.1zM120.1 88.1h3.1zM120.1 85.5h3.1zM120.1 83h3.1zM120.1 80.5h3.1zM148.6 95.7h12.7zM148.6 75.4v20.3zM151.1 80.5l2.5 2.5zM151.1 83l2.5 2.5zM151.1 85.5l2.5 2.6zM151.1 88.1l2.5 2.5zM153.6 80.5h10.2z"/>
<path d="M153.6 83h10.2zM153.6 85.5h10.2zM153.6 88.1h10.2zM153.6 90.6h10.2zM155.3 93.7h6zM155.8 81h5.5zM155.8 83.5h5.5zM155.8 86.1h5.5zM155.8 88.6h5.5zM161.3 95.7v2.5zM161.3 98.2h2.5zM163.8 95.7h3.1z"/>
<path d="M163.8 80.5h5.1zM163.8 83h5.1zM163.8 85.5h5.1zM163.8 88.1h5.1zM163.8 90.6h5.1zM163.8 98.2h3.1zM161.3 95.7h2.5zM186.1 90.6h3.1zM186.1 88.1h3.1zM186.1 85.5h3.1zM186.1 83h3.1zM186.1 80.5h3.1z"/>
<path d="M189.2 80.5h12.7zM189.2 83h12.7zM189.2 85.5h12.7zM189.2 88.1h12.7zM189.2 90.6h12.7zM204.4 80.5l-2.5 2.5zM204.4 83l-2.5 2.5zM204.4 85.5l-2.5 2.6zM204.4 88.1l-2.5 2.5zM207 88.1h15.2zM209.5 90.6h12.7zM209.5 90.6v17.8z"/>
<path d="M211.4 88.6h8.3zM209.5 77.9l2.6 2.6zM209.5 80.5l2.6 2.5zM213.2 86.1h6.5zM222.2 80.5h5.1zM222.2 83h5.1zM222.2 88.1h3.1zM222.2 90.6h3.1zM212.1 80.5h10.1zM212.1 83h10.1zM242.5 80.5h5.1zM242.5 83h5.1z"/>
<path d="M242.5 85.5h5.1zM242.5 88.1h5.1zM242.5 90.6h5.1zM247.6 83h10.2zM247.6 85.5h10.2zM247.6 88.1h10.2zM247.6 90.6h10.2zM247.6 80.5h10.2zM260.3 80.5l-2.5 2.5zM260.3 80.5l2.6 2.5zM260.3 83l-2.5 2.5zM260.3 83l2.6 2.5z"/>
<path d="M257.8 88.1l2.5-2.6zM260.3 85.5l2.6 2.6zM260.3 88.1l-2.5 2.5zM260.3 88.1l2.6 2.5zM262.9 83h12.7zM262.9 85.5h12.7zM262.9 88.1h12.7zM262.9 90.6h12.7zM262.9 80.5h12.7zM273 95.7v2.5zM273 98.2v2.6zM275.6 95.7h3.1z"/>
<path d="M275.6 80.5h5zM275.6 83h5zM275.6 85.5h5zM275.6 88.1h5zM275.6 90.6h5zM275.6 98.2h3.1zM273 95.7h2.6zM273 98.2h2.6zM295.9 90.6h5.1zM295.9 88.1h5.1zM295.9 85.5h5.1zM295.9 83h5.1z"/>
<path d="M295.9 80.5h5.1zM306 80.5h2.6zM306 83h2.6zM306 85.5h2.6zM306 88.1h2.6zM306 90.6h2.6zM301 80.5h5zM301 83h5zM301 85.5h5zM301 88.1h5zM301 90.6h5zM328.9 80.5l2.5 2.5z"/>
<path d="M328.9 83l2.5 2.5zM328.9 85.5l2.5 2.6zM328.9 88.1l2.5 2.5zM331.4 80.5h12.7zM331.4 83h12.7zM331.4 85.5h12.7zM331.4 88.1h12.7zM331.4 90.6h12.7zM334 81h5.4zM334 83.5h5.4zM334 86.1h5.4zM334 88.6h5.4z"/>
<path d="M341.6 95.7v2.5zM341.6 98.2v2.6zM344.1 95.7h3.1zM344.1 80.5h5.1zM344.1 83h5.1zM344.1 85.5h5.1zM344.1 88.1h5.1zM344.1 90.6h5.1zM344.1 98.2h3.1zM341.6 95.7h2.5zM341.6 98.2h2.5zM364.4 90.6h5.1z"/>
<path d="M364.4 88.1h5.1zM364.4 85.5h5.1zM364.4 83h5.1zM364.4 80.5h5.1zM372.1 80.5h2.5zM372.1 83h2.5zM372.1 85.5h2.5zM372.1 88.1h2.5zM372.1 90.6h2.5zM369.5 80.5h2.6zM369.5 83h2.6zM369.5 85.5h2.6z"/>
<path d="M369.5 88.1h2.6zM369.5 90.6h2.6zM54.6 98.2l2.5 2.6zM64.8 100.8h5zM57.1 100.8h7.7zM135.9 60.2v48.2zM146 105.9h61zM207 88.1v17.8zM135.9 108.4h73.6zM273 100.8v2.5zM324.4 96.3v9.6zM328.9 108.4l2.5 2.5z"/>
<path d="M328.9 113.5l2.5 2.5zM334 108.9h5.4zM334 114h5.4zM334 119.1h5.4zM341.6 100.8v2.5zM354.3 110.9h2.5zM354.3 116h2.5zM331.4 110.9h22.9zM331.4 116h22.9zM356.8 110.9h2.6zM356.8 116h2.6zM357.6 113l1.4 1.4z"/>
<path d="M357.6 118l1.4 1.4zM358.6 113.5l-.5 .5zM358.6 118.6l-.5 .5zM358.1 114h.7zM358.1 119h.7zM358.2 113.8h.6zM358.3 118.9h.4zM358.3 119.1h.6zM358.3 114.1h.6zM358.4 113.7h.3zM358.4 118.8h.3zM358.5 113.6h.2z"/>
<path d="M358.5 118.7h.1zM358.6 119.3h.3zM358.6 113.5l.4 .9zM358.6 114.2h.3zM358.6 118.6l.4 .8zM358.7 112.8l1.4 1.4zM358.7 117.9l1.4 1.4zM358.1 114l.9 .4zM358.1 119.1l.9 .3zM359.2 113.9l.5-.6zM359.2 118.9l.5-.5zM359.3 113.8h.7z"/>
<path d="M359.3 118.9h.7zM359.4 113.7h.5zM359.4 118.8h.5zM359.4 119h.6zM359.5 114h.5zM359.5 113.6h.3zM359.5 118.7h.3zM359.6 113.5h.2zM359.6 118.5h.2zM359.7 119.1h.4zM359.7 113.3l.4 .9zM359.7 118.4l.4 .9z"/>
<path d="M359.8 114.1h.3zM359.2 113.9l.9 .3zM359.2 118.9l.9 .4zM359.4 110.9h2.5zM359.4 116h2.5zM361.9 116h5.1zM367 116v5.1zM369.5 110.9v7.7zM361.9 110.9h7.6zM374.6 118.6h2.5zM369.5 118.6h5.1zM377.1 118.6h1.3z"/>
<path d="M383.5 118.6h1.3zM16.5 123.1h3.8zM64.8 138.9v30.5zM67.3 136.3l-2.5 2.6zM107.9 138.9v30.5zM110.5 136.3l-2.6 2.6zM151.1 138.9v30.5zM151.1 138.9l2.5-2.6zM196.8 138.9v30.5zM199.4 136.3l-2.6 2.6zM260.3 131.3l2.6 2.5zM260.3 126.2l2.6 2.5z"/>
<path d="M260.3 136.3l2.6 2.6zM262.9 133.8h22.8zM262.9 128.7h22.8zM262.9 138.9h22.8zM285.7 128.7h2.6zM285.7 133.8h2.6zM285.7 138.9h2.6zM288.3 128.7h2.5zM288.3 133.8h2.5zM288.3 138.9h2.5zM289 130.7l1.4 1.4zM289 135.8l1.4 1.4z"/>
<path d="M289.5 131.8l.5-.5zM289.5 136.8l.5-.5zM289.6 131.7h.6zM289.6 136.9h.7zM289.6 131.8h.7zM289.6 136.8h.6zM289.7 131.6h.5zM289.7 136.6h.5zM289.9 131.4h.2zM289.9 136.5h.2zM289.9 137h.4zM289.9 131.9h.4z"/>
<path d="M290 131.3l.4 .8zM290 136.3l.4 .9zM290.1 137.1h.3zM290.2 130.6l1.4 1.4zM290.2 135.7l1.4 1.4zM290.2 132h.2zM289.5 131.8l.9 .3zM289.5 136.8l.9 .4zM290.7 131.6l.5-.5zM290.7 136.7l.5-.5zM290.7 131.6h.7zM290.7 136.8h.7z"/>
<path d="M290.8 136.6h.6zM290.8 131.7h.6zM290.9 131.4h.4zM290.9 136.5h.4zM291 131.3h.3zM291 136.4h.2zM291 136.9h.5zM291.1 131.8h.4zM291.2 131.1l.4 .9zM291.2 136.2l.4 .9zM291.3 137h.2zM291.4 131.9h.1z"/>
<path d="M290.7 131.6l.9 .4zM290.7 136.7l.9 .4zM290.8 128.7h2.5zM290.8 133.8h2.5zM290.8 138.9h2.5zM293.3 133.8h5.1zM293.3 138.9h2.6zM298.4 133.8v5.1zM298.4 138.9h7.6zM301 128.7v7.6zM293.3 128.7h7.7zM306 138.9h2.6z"/>
<path d="M306 136.3h2.6zM301 136.3h5zM308.6 136.3h1.3zM308.6 138.9h1.3zM314.9 138.9h1.3zM316.2 136.3v2.6zM314.9 136.3h1.3zM328.9 118.6l2.5 2.5zM328.9 123.6l2.5 2.6zM328.9 128.7l2.5 2.6zM328.9 133.8l2.5 2.5zM334 124.2h5.4z"/>
<path d="M334 129.2h5.4zM334 134.3h5.4zM334 139.4h5.4zM354.3 121.1h2.5zM354.3 126.2h2.5zM354.3 131.3h2.5zM354.3 136.3h2.5zM331.4 121.1h22.9zM331.4 126.2h22.9zM331.4 131.3h22.9zM331.4 136.3h22.9zM356.8 121.1h2.6z"/>
<path d="M356.8 126.2h2.6zM356.8 131.3h2.6zM356.8 136.3h2.6zM357.6 123.1l1.4 1.4zM357.6 128.2l1.4 1.4zM357.6 133.3l1.4 1.4zM357.6 138.4l1.4 1.4zM358.1 124.1l.5-.5zM358.6 128.7l-.5 .5zM358.6 133.8l-.5 .5zM358.1 139.4l.5-.5zM358.2 124.1h.6z"/>
<path d="M358.2 139.4h.6zM358.2 129.2h.6zM358.2 134.3h.6zM358.2 134.2h.6zM358.2 139.3h.6zM358.2 129.3h.7zM358.2 124.2h.7zM358.3 124h.4zM358.3 129h.4zM358.3 134.1h.4zM358.3 139.1h.4zM358.4 123.8h.3z"/>
<path d="M358.4 128.9h.3zM358.4 134h.3zM358.4 139.5h.5zM358.5 134.4h.4zM358.5 139h.2zM358.5 129.4h.4zM358.5 123.7h.1zM358.5 124.3h.4zM358.6 123.6l.4 .9zM358.6 128.7l.4 .9zM358.6 133.8l.4 .9zM358.6 138.9l.4 .9z"/>
<path d="M358.7 139.6h.2zM358.7 123l1.4 1.4zM358.7 128.1l1.4 1.4zM358.7 133.2l1.4 1.4zM358.7 138.2l1.4 1.4zM358.7 134.6h.2zM358.8 129.5h.2zM358.8 124.4h.2zM358.1 124.1l.9 .4zM358.1 129.2l.9 .4zM358.1 134.3l.9 .4zM358.1 139.4l.9 .4z"/>
<path d="M359.2 124l.5-.5zM359.2 129.1l.5-.5zM359.2 134.2l.5-.5zM359.2 139.3l.5-.6zM359.3 124h.7zM359.3 129h.6zM359.3 139.3h.7zM359.3 134.1h.6zM359.3 134.2h.7zM359.3 139.1h.6zM359.4 129.2h.6zM359.4 124.1h.6z"/>
<path d="M359.4 123.8h.5zM359.4 128.9h.5zM359.4 134h.5zM359.5 139h.4zM359.5 123.7h.3zM359.6 128.8h.2zM359.6 133.9h.2zM359.6 138.9h.2zM359.6 139.4h.4zM359.6 134.3h.4zM359.7 123.6h.1zM359.7 129.3h.3z"/>
<path d="M359.7 124.2h.3zM359.7 123.5l.4 .9zM359.7 128.6l.4 .9zM359.7 133.7l.4 .9zM359.7 138.7l.4 .9zM359.9 139.5h.2zM359.9 134.4h.2zM359.9 129.4h.2zM360 124.3h.1zM359.2 124l.9 .4zM359.2 129.1l.9 .4zM359.2 134.2l.9 .4z"/>
<path d="M359.2 139.3l.9 .3zM359.4 121.1h2.5zM359.4 126.2h2.5zM359.4 131.3h2.5zM359.4 136.3h2.5zM361.9 126.2h12.7zM361.9 131.3h2.5zM361.9 136.3h5.1zM364.4 121.1v2.5zM361.9 121.1h2.5zM364.4 128.7v2.6zM364.4 128.7h10.2z"/>
<path d="M367 121.1h7.6zM367 131.3v5zM367 131.3h7.6zM369.5 133.8h5.1zM372.1 136.3h2.5zM374.6 136.3h2.5zM374.6 133.8h2.5zM374.6 131.3h2.5zM374.6 128.7h2.5zM374.6 126.2h2.5zM374.6 123.6h2.5zM374.6 121.1h2.5z"/>
<path d="M364.4 123.6h10.2zM377.1 126.2h1.3zM377.1 128.7h1.3zM377.1 131.3h1.3zM377.1 133.8h1.3zM377.1 121.1h1.3zM377.1 136.3h1.3zM377.1 123.6h1.3zM383.5 136.3h1.3zM384.8 133.8v2.5zM383.5 133.8h1.3zM384.8 131.3v2.5z"/>
<path d="M383.5 131.3h1.3zM384.8 128.7v2.6zM383.5 128.7h1.3zM384.8 126.2v2.5zM383.5 126.2h1.3zM383.5 123.6h1.3zM384.8 121.1v2.5zM383.5 121.1h1.3zM384.8 118.6v2.5zM384.8 123.6v2.6zM384.8 136.3h2.5zM387.3 136.3h2.5z"/>
<path d="M389.8 136.3h2.6zM392.4 138.9v2.5zM392.4 136.3v2.6zM400 123.1h3.8zM31.9 141.2h10zM67.3 144v17.7zM67.8 145.8v5.8zM67.3 144l2.5-2.6zM72.4 149v2.6zM72.4 151.6v2.5zM72.4 154.1v2.6zM74.9 156.7h5.1z"/>
<path d="M74.9 154.1h3.1zM72.4 154.1h2.5zM72.4 156.7h2.5zM95.2 156.7h5.1zM110.5 144v17.7zM111 145.8v5.8zM113 141.4l-2.5 2.6zM115.6 149v2.6zM115.6 151.6v2.5zM115.6 154.1v2.6zM118.1 156.7h5.1zM118.1 154.1h3.1z"/>
<path d="M115.6 154.1h2.5zM115.6 156.7h2.5zM138.4 156.7h5.1zM153.6 144v17.7zM154.2 145.8v5.8zM156.2 141.4l-2.6 2.6zM161.3 149v2.6zM161.3 151.6v2.5zM161.3 154.1v2.6zM163.8 156.7h5.1zM163.8 154.1h3.1zM161.3 154.1h2.5z"/>
<path d="M161.3 156.7h2.5zM184.1 156.7h5.1zM199.4 144v17.7zM199.9 145.8v5.8zM199.4 144l2.5-2.6zM204.4 149v2.6zM204.4 151.6v2.5zM204.4 154.1v2.6zM207 156.7h5.1zM207 154.1h3.1zM204.4 154.1h2.6zM204.4 156.7h2.6z"/>
<path d="M227.3 156.7h5.1zM260.3 146.5l2.6 2.5zM260.3 151.6l2.6 2.5zM260.3 156.7l2.6 2.5zM260.3 141.4l2.6 2.6zM262.9 149h22.8zM262.9 154.1h22.8zM262.9 159.2h22.8zM262.9 144h22.8zM285.7 144h2.6zM285.7 149h2.6zM285.7 154.1h2.6z"/>
<path d="M285.7 159.2h2.6zM288.3 144h2.5zM288.3 149h2.5zM288.3 154.1h2.5zM288.3 159.2h2.5zM289 140.9l1.4 1.4zM289 146l1.4 1.4zM289 151.1l1.4 1.4zM289 156.1l1.4 1.4zM289.5 141.9l.5-.5zM289.5 147l.5-.5zM289.5 147h.8z"/>
<path d="M289.5 152.1l.5-.5zM289.5 157.2l.5-.5zM289.6 141.9h.7zM289.6 152.1h.7zM289.6 157.1h.6zM289.6 141.8h.6zM289.6 146.9h.6zM289.7 151.9h.5zM289.7 157h.5zM289.7 157.2h.6zM289.7 141.7h.4zM289.8 146.7h.3z"/>
<path d="M289.8 152.2h.5zM289.8 151.8h.3zM289.8 147.1h.5zM289.8 156.9h.3zM289.8 142h.5zM289.9 141.6h.2zM289.9 146.6h.2zM289.9 151.7h.2zM289.9 156.8h.2zM290 157.4h.3zM290 141.4l.4 .9zM290 146.5l.4 .9z"/>
<path d="M290 151.6l.4 .9zM290 152.3h.3zM290 156.7l.4 .8zM290.1 147.2h.3zM290.1 142.2h.3zM290.2 140.8l1.4 1.4zM290.2 145.9l1.4 1.4zM290.2 150.9l1.4 1.4zM290.2 156l1.4 1.4zM289.5 141.9l.9 .4zM289.5 147l.9 .4zM289.5 152.1l.9 .4z"/>
<path d="M289.5 157.2l.9 .3zM290.7 141.8l.5-.5zM290.7 146.9l.5-.5zM290.7 146.9h.7zM290.7 152l.5-.6zM290.7 151.9h.7zM290.7 157l.5-.5zM290.7 157h.7zM290.7 141.8h.7zM290.8 141.7h.6zM290.8 146.7h.6zM290.8 151.8h.5z"/>
<path d="M290.8 156.9h.5zM290.9 141.6h.4zM290.9 157.1h.5zM290.9 146.6h.4zM290.9 152.1h.5zM290.9 151.7h.4zM290.9 156.8h.4zM291 147h.4zM291 141.9h.5zM291 141.5h.2zM291 146.5h.2zM291 151.6h.2z"/>
<path d="M291.1 156.7h.1zM291.2 157.2h.3zM291.2 141.3l.4 .9zM291.2 146.4l.4 .9zM291.2 151.4l.4 .9zM291.2 156.5l.4 .9zM291.2 152.2h.3zM291.2 147.1h.3zM291.3 142h.2zM290.7 141.8l.9 .4zM290.7 146.9l.9 .4zM290.7 152l.9 .3z"/>
<path d="M290.7 157l.9 .4zM290.8 144h2.5zM290.8 149h2.5zM290.8 154.1h2.5zM290.8 159.2h2.5zM293.3 144h12.7zM293.3 149h2.6zM293.3 154.1h5.1zM293.3 159.2h7.7zM295.9 138.9v2.5zM295.9 146.5v2.5zM295.9 146.5h10.1z"/>
<path d="M298.4 149v5.1zM298.4 149h7.6zM301 151.6v7.6zM301 151.6h5zM303.5 154.1h2.5zM306 154.1h2.6zM306 151.6h2.6zM306 149h2.6zM306 146.5h2.6zM306 144h2.6zM306 141.4h2.6zM295.9 141.4h10.1z"/>
<path d="M308.6 144h1.3zM308.6 146.5h1.3zM308.6 149h1.3zM308.6 151.6h1.3zM308.6 154.1h1.3zM308.6 141.4h1.3zM314.9 154.1h1.3zM316.2 151.6v2.5zM314.9 151.6h1.3zM316.2 149v2.6zM314.9 149h1.3zM316.2 146.5v2.5z"/>
<path d="M314.9 146.5h1.3zM316.2 144v2.5zM314.9 144h1.3zM314.9 141.4h1.3zM316.2 138.9v2.5zM316.2 141.4v2.6zM316.2 154.1h2.5zM318.7 154.1h2.6zM321.3 154.1h2.5zM323.8 156.7v2.5zM323.8 154.1v2.6zM328.9 138.9l2.5 2.5z"/>
<path d="M328.9 144l2.5 2.5zM334 144.5h5.4zM354.3 141.4h2.5zM354.3 146.5h2.5zM331.4 141.4h22.9zM331.4 146.5h22.9zM356.8 141.4h2.6zM356.8 146.5h2.6zM357.6 143.4l1.4 1.4zM357.6 148.5l1.4 1.4zM358.6 144l-.5 .5zM358.6 149l-.5 .5z"/>
<path d="M358.1 144.5h.7zM358.1 149.5h.7zM358.2 144.3h.6zM358.2 149.4h.6zM358.3 144.2h.4zM358.3 149.3h.4zM358.4 149.6h.5zM358.4 144.6h.5zM358.5 144.1h.2zM358.5 149.2h.2zM358.6 144l.4 .8zM358.6 149l.4 .9z"/>
<path d="M358.6 149.8h.3zM358.7 144.7h.2zM358.7 143.3l1.4 1.4zM358.7 148.4l1.4 1.4zM358.1 144.5l.9 .3zM358.1 149.5l.9 .4zM359.2 144.3l.5-.5zM359.2 149.4l.5-.5zM359.3 149.4h.7zM359.3 144.3h.7zM359.4 144.2h.5zM359.4 149.3h.5z"/>
<path d="M359.5 144.1h.4zM359.5 149.2h.4zM359.5 149.5h.5zM359.6 144.5h.4zM359.6 144h.2zM359.6 149.1h.2zM359.7 143.8l.4 .9zM359.7 148.9l.4 .9zM359.8 149.6h.3zM359.8 144.6h.3zM359.2 144.3l.9 .4zM359.2 149.4l.9 .4z"/>
<path d="M359.4 141.4h2.5zM359.4 146.5h2.5zM361.9 141.4h7.6zM361.9 146.5h10.2zM369.5 133.8v7.6zM372.1 136.3v10.2zM16.5 173.7h3.8zM64.8 169.4h10.1zM67.3 161.7h7.6zM72.4 171.9v2.5zM72.4 166.8v5.1zM72.4 166.8h2.5z"/>
<path d="M74.9 161.7h5.1zM74.9 166.8h5.1zM74.9 169.4h3.1zM80 160.7l2 1zM80 162.7l2-1zM91.2 165.9h1.7zM100.1 169.4v5.4zM95.2 166.8h5.1zM102.9 166.8v12.7zM100.3 166.8h2.6zM107.9 169.4h10.2zM110.5 161.7h7.6z"/>
<path d="M115.6 171.9v2.5zM115.6 166.8v5.1zM118.1 161.7h5.1zM118.1 166.8h5.1zM118.1 169.4h3.1zM115.6 166.8h2.5zM123.2 160.7l2 1zM123.2 162.7l2-1zM125.7 178.8h9.6zM134.4 165.9h1.7zM143.3 169.4v5.4zM138.4 166.8h5.1z"/>
<path d="M146 166.8v12.7zM143.5 166.8h2.5zM151.1 169.4h12.7zM153.6 161.7h10.2zM161.3 171.9v2.5zM161.3 166.8v5.1zM163.8 161.7h5.1zM163.8 166.8h5.1zM163.8 169.4h3.1zM161.3 166.8h2.5zM168.9 160.7l2 1zM168.9 162.7l2-1z"/>
<path d="M180.1 165.9h1.7zM189 169.4v5.4zM184.1 166.8h5.1zM191.7 166.8v12.7zM189.2 166.8h2.5zM196.8 169.4h10.2zM199.4 161.7h7.6zM204.4 171.9v2.5zM204.4 166.8v5.1zM204.4 166.8h2.6zM207 161.7h5.1zM207 166.8h5.1z"/>
<path d="M207 169.4h3.1zM212.1 160.7l2 1zM212.1 162.7l2-1zM214.6 178.8h9.6zM223.3 165.9h1.7zM232.2 169.4v5.4zM227.3 166.8h5.1zM234.9 166.8v12.7zM232.4 166.8h2.5zM260.3 161.7l2.6 2.6zM262.9 164.3h22.8zM285.7 164.3h2.6z"/>
<path d="M288.3 164.3h2.5zM289 161.2l1.4 1.4zM289 166.3l1.4 1.4zM289.5 162.2l.5-.5zM289.5 167.3l.5-.5zM289.6 162.2h.6zM289.6 167.3h.6zM289.7 167.4h.6zM289.7 162.3h.6zM289.7 162.1h.5zM289.7 167.1h.5zM289.8 161.9h.3z"/>
<path d="M289.8 167h.3zM289.9 161.8h.2zM289.9 167.5h.4zM290 162.4h.3zM290 161.7l.4 .9zM290 166.8l.4 .9zM290.2 161.1l1.4 1.4zM290.2 166.2l1.4 1.4zM290.2 167.6h.2zM290.3 162.6h.1zM289.5 162.2l.9 .4zM289.5 167.3l.9 .4z"/>
<path d="M290.7 162.1l.5-.5zM290.7 167.2l.5-.5zM290.7 162.1h.7zM290.7 167.1h.7zM290.8 161.9h.5zM290.8 167.3h.6zM290.8 162.2h.6zM290.8 167h.5zM291 161.8h.3zM291 166.9h.3zM291.1 161.7h.1zM291.1 166.8h.1z"/>
<path d="M291.1 167.4h.4zM291.1 162.3h.4zM291.2 161.6l.4 .9zM291.2 166.7l.4 .9zM291.4 167.5h.1zM290.7 162.1l.9 .4zM290.7 167.2l.9 .4zM290.8 164.3h2.5zM293.3 164.3h10.2zM303.5 154.1v10.2zM400 173.7h3.8zM64.8 189.7v30.4z"/>
<path d="M67.3 187.1l-2.5 2.6zM67.3 194.8v17.7zM69.8 192.2l-2.5 2.6zM82.5 188.9h10zM102.9 179.5l2.5 2.6zM107.9 189.7v30.4zM110.5 187.1l-2.6 2.6zM110.5 194.8v17.7zM113 192.2l-2.5 2.6zM125.7 188.9h10zM146 179.5l2.6 2.6zM151.1 189.7v30.4z"/>
<path d="M153.6 187.1l-2.5 2.6zM153.6 194.8v17.7zM156.2 192.2l-2.6 2.6zM191.7 179.5l2.6 2.6zM196.8 189.7v30.4zM199.4 187.1l-2.6 2.6zM199.4 194.8v17.7zM201.9 192.2l-2.5 2.6zM234.9 179.5l2.6 2.6zM245.1 192.2l2.5 2.6zM245.1 197.3l2.5 2.5zM247.6 194.8h22.9z"/>
<path d="M247.6 199.8h22.9zM262.9 192.7h5.4zM262.9 197.8h5.4zM270.5 194.8h5.1zM270.5 199.8h5.1zM280.6 197.3h5.1zM285.7 197.3h10.2zM334 194.5h6.3zM67.3 212.5h7.6zM67.8 196.6v5.8zM72.4 199.8v2.6zM72.4 217.6v5.1z"/>
<path d="M72.4 217.6h2.5zM72.4 202.4v2.5zM72.4 204.9v2.5zM74.9 212.5h5.1zM74.9 217.6h5.1zM74.9 207.4h5.1zM74.9 204.9h3.1zM72.4 204.9h2.5zM72.4 207.4h2.5zM80 211.5l2 1zM80 213.5l2-1zM91.2 216.7h1.7z"/>
<path d="M95.2 207.4h5.1zM95.2 217.6h5.1zM100.3 217.6h2.6zM110.5 212.5h7.6zM111 196.6v5.8zM115.6 199.8v2.6zM115.6 217.6v5.1zM115.6 202.4v2.5zM115.6 204.9v2.5zM118.1 212.5h5.1zM118.1 217.6h5.1zM118.1 207.4h5.1z"/>
<path d="M118.1 204.9h3.1zM115.6 217.6h2.5zM115.6 204.9h2.5zM115.6 207.4h2.5zM123.2 211.5l2 1zM123.2 213.5l2-1zM134.4 216.7h1.7zM138.4 207.4h5.1zM138.4 217.6h5.1zM143.5 217.6h2.5zM153.6 212.5h10.2zM154.2 196.6v5.8z"/>
<path d="M161.3 199.8v2.6zM161.3 217.6v5.1zM161.3 202.4v2.5zM161.3 204.9v2.5zM163.8 212.5h5.1zM163.8 217.6h5.1zM163.8 207.4h5.1zM163.8 204.9h3.1zM161.3 217.6h2.5zM161.3 204.9h2.5zM161.3 207.4h2.5zM168.9 211.5l2 1z"/>
<path d="M168.9 213.5l2-1zM180.1 216.7h1.7zM184.1 207.4h5.1zM184.1 217.6h5.1zM189.2 217.6h2.5zM199.4 212.5h7.6zM199.9 196.6v5.8zM204.4 199.8v2.6zM204.4 217.6h2.6zM204.4 202.4v2.5zM204.4 204.9v2.5zM207 212.5h5.1z"/>
<path d="M207 217.6h5.1zM207 207.4h5.1zM207 204.9h3.1zM204.4 204.9h2.6zM204.4 207.4h2.6zM212.1 211.5l2 1zM212.1 213.5l2-1zM223.3 216.7h1.7zM227.3 207.4h5.1zM227.3 217.6h5.1zM232.4 217.6h2.5zM245.1 202.4l2.5 2.5z"/>
<path d="M245.1 207.4l2.5 2.6zM245.1 212.5l2.5 2.5zM245.1 217.6l2.5 2.5zM247.6 204.9h22.9zM247.6 210h22.9zM247.6 215h22.9zM262.9 202.9h5.4zM262.9 208h5.4zM262.9 213h5.4zM262.9 218.1h5.4zM270.5 204.9h5.1zM270.5 210h5.1z"/>
<path d="M270.5 215h5.1zM280.6 207.4h5.1zM280.6 217.6h5.1zM285.7 207.4h17.8zM285.7 217.6h17.8zM295.9 197.3v5.1zM303.5 202.4h5.1zM303.5 207.4h5.1zM303.5 217.6h5.1zM295.9 202.4h7.6zM313.7 204.9h5zM318.7 204.9h7.7z"/>
<path d="M326.4 204.9v5.1zM326.4 210h7.6zM326.4 215h7.6zM334 210h5zM334 215h5zM344.1 212.5h5.1zM349.2 212.5h27.9zM378.7 211.4h4.4zM16.5 224.2h3.8zM64.8 220.1h10.1zM72.4 222.7v2.5zM74.9 220.1h3.1z"/>
<path d="M100.1 222.3v5.4zM102.9 217.6v12.7zM102.9 230.3l2.5 2.5zM107.9 220.1h10.2zM115.6 222.7v2.5zM118.1 220.1h3.1zM143.3 222.3v5.4zM146 217.6v12.7zM146 230.3l2.6 2.5zM151.1 220.1h12.7zM161.3 222.7v2.5zM163.8 220.1h3.1z"/>
<path d="M170.2 229.5h9.5zM189 222.3v5.4zM191.7 217.6v12.7zM191.7 230.3l2.6 2.5zM196.8 220.1h10.2zM204.4 222.7v2.5zM204.4 217.6v5.1zM207 220.1h3.1zM232.2 222.3v5.4zM234.9 217.6v12.7zM234.9 230.3l2.6 2.5zM245.1 222.7l2.5 2.5z"/>
<path d="M245.1 227.7l2.5 2.6zM247.6 220.1h22.9zM247.6 225.2h22.9zM247.6 230.3h22.9zM262.9 223.2h5.4zM262.9 228.3h5.4zM270.5 220.1h5.1zM270.5 225.2h5.1zM270.5 230.3h5.1zM280.6 227.7h5.1zM285.7 227.7h10.2zM295.9 222.7v5z"/>
<path d="M295.9 222.7h7.6zM303.5 222.7h5.1zM313.7 220.1h5zM318.7 220.1h7.7zM326.4 215v5.1zM347.4 228.3h4.4zM368.6 225.7h4.4zM400 224.2h3.8zM29.2 255.7v2.5zM29.2 250.6v2.5zM29.2 255.2v.5zM29.2 253.1v.6z"/>
<path d="M29.2 258.2v2.6zM29.2 248.1v2.5zM36.8 255.7v2.5zM36.8 250.6v2.5zM36.8 255.2v.5zM36.8 253.1v.6zM36.8 248.1v2.5zM29.2 248.1h7.6zM44.4 255.7v2.5zM44.4 250.6v2.5zM44.4 255.2v.5zM44.4 253.1v.6z"/>
<path d="M36.8 248.1h7.6zM44.4 248.1v2.5zM52.1 255.7v2.5zM52.1 250.6v2.5zM52.1 255.2v.5zM52.1 253.1v.6zM44.4 248.1h7.7zM52.1 248.1v2.5zM59.7 255.7v2.5zM59.7 250.6v2.5zM59.7 255.2v.5zM59.7 253.1v.6z"/>
<path d="M52.1 248.1h7.6zM59.7 248.1v2.5zM67.3 255.7v2.5zM67.3 250.6v2.5zM67.3 255.2v.5zM67.3 253.1v.6zM59.7 248.1h7.6zM67.3 248.1v2.5zM74.9 255.7v2.5zM74.9 250.6v2.5zM74.9 255.2v.5zM74.9 253.1v.6z"/>
<path d="M67.3 248.1h7.6zM74.9 248.1v2.5zM82.5 255.7v2.5zM82.5 250.6v2.5zM82.5 255.2v.5zM82.5 253.1v.6zM74.9 248.1h7.6zM82.5 248.1v2.5zM90.2 255.7v2.5zM90.2 250.6v2.5zM90.2 255.2v.5zM90.2 253.1v.6z"/>
<path d="M82.5 248.1h7.7zM90.2 248.1v2.5zM97.8 255.7v2.5zM97.8 250.6v2.5zM97.8 255.2v.5zM97.8 253.1v.6zM97.8 258.2v2.6zM90.2 248.1h7.6zM97.8 248.1v2.5zM105.4 255.7v2.5zM105.4 250.6v2.5zM105.4 255.2v.5z"/>
<path d="M105.4 253.1v.6zM105.4 258.2v2.6zM97.8 248.1h7.6zM105.4 248.1v2.5zM113 243v2.5zM113 255.7v2.5zM113 250.6v2.5zM113 255.2v.5zM113 253.1v.6zM105.4 248.1h7.6zM113 245.5v2.6zM113 248.1v2.5z"/>
<path d="M120.6 243v2.5zM120.6 250.6v2.5zM120.6 255.7v2.5zM120.6 253.1v.6zM120.6 255.2v.5zM120.6 245.5v5.1zM20.3 274.7h379.7zM29.2 263.3v2.5zM29.2 260.8h7.6zM29.2 260.8v2.5zM36.8 258.2v2.6zM36.8 260.8h7.6z"/>
<path d="M44.4 258.2v2.6zM44.4 260.8h7.7zM52.1 258.2v2.6zM52.1 260.8h7.6zM59.7 258.2v2.6zM59.7 260.8h7.6zM67.3 258.2v2.6zM67.8 274.7v3.8zM67.3 260.8h7.6zM74.9 258.2v2.6zM74.9 260.8h7.6zM82.5 258.2v2.6z"/>
<path d="M82.5 260.8h7.7zM90.2 258.2v2.6zM90.2 260.8h7.6zM97.8 260.8h7.6zM105.4 260.8h7.6zM113 258.2v2.6zM115.3 274.7v3.8zM120.6 263.3v2.5zM120.6 258.2v5.1zM162.7 274.7v3.8zM210.2 274.7v3.8zM257.6 274.7v3.8z"/>
<path d="M305.1 274.7v3.8zM352.5 274.7v3.8zM400 264.5v.1zM400 268.4v6.2zM400 274.6h.1zM400 22.1v252.6z"/>
<circle cx="59.7" cy="55.1" r=".51"/>
<circle cx="74.9" cy="50" r=".51"/>
<circle cx="69.8" cy="65.2" r=".51"/>
<circle cx="135.9" cy="60.2" r=".51"/>
<circle cx="161.3" cy="95.7" r=".51"/>
<circle cx="273" cy="98.2" r=".51"/>
<circle cx="341.6" cy="98.2" r=".51"/>
<circle cx="72.4" cy="154.1" r=".51"/>
<circle cx="115.6" cy="154.1" r=".51"/>
<circle cx="161.3" cy="154.1" r=".51"/>
<circle cx="204.4" cy="154.1" r=".51"/>
<circle cx="72.4" cy="204.9" r=".51"/>
<circle cx="115.6" cy="204.9" r=".51"/>
<circle cx="161.3" cy="204.9" r=".51"/>
<circle cx="204.4" cy="204.9" r=".51"/>
<circle cx="36.8" cy="248.1" r=".51"/>
<circle cx="44.4" cy="248.1" r=".51"/>
<circle cx="52.1" cy="248.1" r=".51"/>
<circle cx="59.7" cy="248.1" r=".51"/>
<circle cx="67.3" cy="248.1" r=".51"/>
<circle cx="74.9" cy="248.1" r=".51"/>
<circle cx="82.5" cy="248.1" r=".51"/>
<circle cx="90.2" cy="248.1" r=".51"/>
<circle cx="97.8" cy="248.1" r=".51"/>
<circle cx="105.4" cy="248.1" r=".51"/>
<circle cx="113" cy="248.1" r=".51"/>
<circle cx="29.2" cy="260.8" r=".51"/>
<circle cx="36.8" cy="260.8" r=".51"/>
<circle cx="44.4" cy="260.8" r=".51"/>
<circle cx="52.1" cy="260.8" r=".51"/>
<circle cx="59.7" cy="260.8" r=".51"/>
<circle cx="67.3" cy="260.8" r=".51"/>
<circle cx="74.9" cy="260.8" r=".51"/>
<circle cx="82.5" cy="260.8" r=".51"/>
<circle cx="90.2" cy="260.8" r=".51"/>
<circle cx="97.8" cy="260.8" r=".51"/>
<circle cx="105.4" cy="260.8" r=".51"/>
</g>
<g fill="#000" stroke="#000" stroke-width=".28">
<path d="M26.9 53.6v3zM28.7 58.6v3.1zM34.8 48.5v3zM28.7 58.6h14.2zM34.8 48.5h8.1zM34.8 51.5h8.1zM26.9 56.6h16zM26.9 53.6h16zM42.9 48.5l1.5 1.5zM44.4 50l-1.5 1.5zM42.9 56.6l1.5-1.5zM42.9 53.6l1.5 1.5z"/>
<path d="M378.7 48.5l-1.6 1.5zM377.1 50l1.6 1.5zM377.1 55.1l1.6-1.5zM377.1 55.1l1.6 1.5zM378.7 58.6h14.1zM378.7 48.5h8.1zM378.7 51.5h8.1zM378.7 53.6h16zM378.7 56.6h16zM386.8 48.5v3zM392.8 58.6v3.1zM394.7 53.6v3z"/>
<path d="M35.4 63.7v3zM28.7 61.7h14.2zM35.4 66.7h7.5zM35.4 63.7h7.5zM42.9 58.6l1.5 1.6zM42.9 61.7l1.5-1.5zM44.4 65.2l-1.5 1.5zM42.9 63.7l1.5 1.5zM122.2 63.7l-1.6 1.5zM120.6 65.2l1.6 1.5zM122.2 63.7h7.5zM122.2 66.7h7.5z"/>
<path d="M129.7 63.7v3zM377.1 60.2l1.6-1.6zM377.1 60.2l1.6 1.5zM378.7 61.7h14.1zM271.1 103.3h3.8zM339.7 103.3h3.8zM356.8 109.7v2.5zM356.8 109.7l2.6 1.2zM356.8 112.1h.1zM356.8 111.9h.6zM356.8 111.7h1zM356.8 111.5h1.5z"/>
<path d="M356.8 111.3h1.9zM356.8 111h2.4zM356.8 110.8h2.3zM356.8 110.6h1.9zM356.8 110.4h1.4zM356.8 110.1h1zM356.8 109.9h.6zM356.8 114.7v2.6zM356.8 114.7l2.6 1.3zM356.8 117h.5zM356.8 116.8h1zM356.8 116.6h1.4z"/>
<path d="M356.8 116.4h1.9zM356.8 116.1h2.3zM356.8 115.9h2.4zM356.8 115.7h1.9zM356.8 115.5h1.5zM356.8 115.3h1.1zM356.8 115h.6zM356.8 114.8h.2zM356.8 119.8l2.6 1.3zM356.8 119.9h.2zM359.4 110.9v1.3zM356.8 112.2l2.6-1.3z"/>
<path d="M359.4 109.7v2.5zM359.4 109.7h.2zM359.4 112.1h.2zM359.4 111.9h.2zM359.4 111.7h.2zM359.4 111.5h.2zM359.4 111.3h.2zM359.4 111h.2zM359.4 110.8h.2zM359.4 110.6h.2zM359.4 110.4h.2zM359.4 110.1h.2z"/>
<path d="M359.4 109.9h.2zM359.4 116v1.3zM356.8 117.3l2.6-1.3zM359.4 114.7v2.6zM359.4 114.7h.2zM359.4 117.3h.2zM359.4 117h.2zM359.4 116.8h.2zM359.4 116.6h.2zM359.4 116.4h.2zM359.4 116.1h.2zM359.4 115.9h.2z"/>
<path d="M359.4 115.7h.2zM359.4 115.5h.2zM359.4 115.3h.2zM359.4 115h.2zM359.4 114.8h.2zM359.4 119.8h.2zM359.4 119.9h.2zM359.6 109.7v2.5zM359.4 112.2h.2zM359.6 114.7v2.6zM359.6 119.8v2.6zM378.4 117.8h5.1z"/>
<path d="M378.4 117.8v.8zM378.4 118.6v.7zM378.4 119.3h5.1zM383.5 117.8v.8zM383.5 118.6v.7zM288.3 127.4v2.6zM288.3 127.4l2.5 1.3zM288.3 129.9h.1zM288.3 129.7h.5zM288.3 129.5h1zM288.3 129.3h1.4zM288.3 129h1.8z"/>
<path d="M288.3 128.8h2.3zM288.3 128.6h2.2zM288.3 128.4h1.8zM288.3 128.1h1.4zM288.3 127.9h.9zM288.3 127.7h.5zM288.3 132.5v2.6zM288.3 132.5l2.5 1.3zM288.3 134.8h.5zM288.3 134.6h.9zM288.3 134.4h1.4zM288.3 134.2h1.8z"/>
<path d="M288.3 133.9h2.2zM288.3 133.7h2.3zM288.3 133.5h1.9zM288.3 133.3h1.4zM288.3 133h1zM288.3 132.8h.5zM288.3 132.6h.1zM288.3 137.6l2.5 1.3zM288.3 139.9h.4zM288.3 139.7h.9zM288.3 139.5h1.3zM288.3 139.3h1.7z"/>
<path d="M288.3 139h2.2zM288.3 138.8h2.4zM288.3 138.6h1.9zM288.3 138.4h1.5zM288.3 138.1h1zM288.3 137.9h.6zM288.3 137.7h.2zM290.8 128.7v1.3zM288.3 130l2.5-1.3zM290.8 127.4v2.6zM290.8 127.4h.3zM290.8 129.9h.3z"/>
<path d="M290.8 129.7h.3zM290.8 129.5h.3zM290.8 129.3h.3zM290.8 129h.3zM290.8 128.8h.3zM290.8 128.6h.3zM290.8 128.4h.3zM290.8 128.1h.3zM290.8 127.9h.3zM290.8 127.7h.3zM290.8 127.5h.3zM290.8 133.8v1.3z"/>
<path d="M288.3 135.1l2.5-1.3zM290.8 132.5v2.6zM290.8 132.5h.3zM290.8 135h.3zM290.8 134.8h.3zM290.8 134.6h.3zM290.8 134.4h.3zM290.8 134.2h.3zM290.8 133.9h.3zM290.8 133.7h.3zM290.8 133.5h.3zM290.8 133.3h.3z"/>
<path d="M290.8 133h.3zM290.8 132.8h.3zM290.8 132.6h.3zM290.8 138.9v1.2zM288.3 140.1l2.5-1.2zM290.8 137.6h.3zM290.8 139.9h.3zM290.8 139.7h.3zM290.8 139.5h.3zM290.8 139.3h.3zM290.8 139h.3zM290.8 138.8h.3z"/>
<path d="M290.8 138.6h.3zM290.8 138.4h.3zM290.8 138.1h.3zM290.8 137.9h.3zM290.8 137.7h.3zM291.1 127.4v2.6zM290.8 130h.3zM291.1 132.5v2.6zM290.8 135.1h.3zM291.1 137.6v2.5zM309.9 138.1v.8zM309.9 138.9v.7z"/>
<path d="M309.9 138.1h5zM309.9 135.6h5zM309.9 135.6v.7zM309.9 136.3v.8zM314.9 138.1v.8zM314.9 138.9v.7zM309.9 139.6h5zM309.9 137.1h5zM314.9 135.6v.7zM314.9 136.3v.8zM356.8 119.8v2.6zM356.8 122.2h.5z"/>
<path d="M356.8 121.9h.9zM356.8 121.7h1.4zM356.8 121.5h1.8zM356.8 121.3h2.2zM356.8 121h2.5zM356.8 120.8h2zM356.8 120.6h1.6zM356.8 120.4h1.1zM356.8 120.1h.7zM356.8 124.9v2.5zM356.8 124.9l2.6 1.3zM356.8 127.3h.4z"/>
<path d="M356.8 127h.8zM356.8 126.8h1.3zM356.8 126.6h1.7zM356.8 126.4h2.2zM356.8 126.2h2.5zM356.8 125.9h2.1zM356.8 125.7h1.6zM356.8 125.5h1.2zM356.8 125.3h.7zM356.8 125h.3zM356.8 130v2.5zM356.8 130l2.6 1.3z"/>
<path d="M356.8 132.4h.3zM356.8 132.1h.8zM356.8 131.9h1.2zM356.8 131.7h1.7zM356.8 131.5h2.1zM356.8 131.3h2.6zM356.8 131h2.1zM356.8 130.8h1.7zM356.8 130.6h1.2zM356.8 130.4h.8zM356.8 130.2h.4zM356.8 135.1v2.5z"/>
<path d="M356.8 135.1l2.6 1.2zM356.8 137.5h.3zM356.8 137.2h.7zM356.8 137h1.2zM356.8 136.8h1.6zM356.8 136.6h2.1zM356.8 136.4h2.5zM356.8 136.1h2.2zM356.8 135.9h1.7zM356.8 135.7h1.3zM356.8 135.5h.8zM356.8 135.3h.4z"/>
<path d="M359.4 121.1v1.3zM356.8 122.4l2.6-1.3zM359.4 119.8v2.6zM359.4 122.2h.2zM359.4 121.9h.2zM359.4 121.7h.2zM359.4 121.5h.2zM359.4 121.3h.2zM359.4 121h.2zM359.4 120.8h.2zM359.4 120.6h.2zM359.4 120.4h.2z"/>
<path d="M359.4 120.1h.2zM359.4 126.2v1.2zM356.8 127.4l2.6-1.2zM359.4 124.9v2.5zM359.4 124.9h.2zM359.4 127.3h.2zM359.4 127h.2zM359.4 126.8h.2zM359.4 126.6h.2zM359.4 126.4h.2zM359.4 126.2h.2zM359.4 125.9h.2z"/>
<path d="M359.4 125.7h.2zM359.4 125.5h.2zM359.4 125.3h.2zM359.4 125h.2zM359.4 131.3v1.2zM356.8 132.5l2.6-1.2zM359.4 130v2.5zM359.4 130h.2zM359.4 132.4h.2zM359.4 132.1h.2zM359.4 131.9h.2zM359.4 131.7h.2z"/>
<path d="M359.4 131.5h.2zM359.4 131.3h.2zM359.4 131h.2zM359.4 130.8h.2zM359.4 130.6h.2zM359.4 130.4h.2zM359.4 130.2h.2zM359.4 136.3v1.3zM356.8 137.6l2.6-1.3zM359.4 135.1v2.5zM359.4 135.1h.2zM359.4 137.5h.2z"/>
<path d="M359.4 137.2h.2zM359.4 137h.2zM359.4 136.8h.2zM359.4 136.6h.2zM359.4 136.4h.2zM359.4 136.1h.2zM359.4 135.9h.2zM359.4 135.7h.2zM359.4 135.5h.2zM359.4 135.3h.2zM359.4 122.4h.2zM359.6 124.9v2.5z"/>
<path d="M359.4 127.4h.2zM359.6 130v2.5zM359.4 132.5h.2zM359.6 135.1v2.5zM359.4 137.6h.2zM378.4 135.6h5.1zM378.4 136.3v.8zM378.4 135.6v.7zM378.4 133v.8zM378.4 133.8v.8zM378.4 133h5.1zM378.4 130.5h5.1z"/>
<path d="M378.4 128h5.1zM378.4 125.4h5.1zM378.4 130.5v.8zM378.4 128v.7zM378.4 125.4v.8zM378.4 131.3v.7zM378.4 128.7v.8zM378.4 126.2v.7zM378.4 122.9h5.1zM378.4 123.6v.8zM378.4 122.9v.7zM378.4 120.3v.8z"/>
<path d="M378.4 121.1v.8zM378.4 120.3h5.1zM378.4 137.1h5.1zM383.5 135.6v.7zM383.5 136.3v.8zM383.5 133v.8zM383.5 133.8v.8zM378.4 134.6h5.1zM378.4 132h5.1zM378.4 129.5h5.1zM378.4 126.9h5.1zM383.5 130.5v.8z"/>
<path d="M383.5 128v.7zM383.5 125.4v.8zM383.5 131.3v.7zM383.5 128.7v.8zM383.5 126.2v.7zM378.4 124.4h5.1zM383.5 122.9v.7zM383.5 123.6v.8zM383.5 120.3v.8zM383.5 121.1v.8zM378.4 121.9h5.1zM72.4 149l-1.3 1.9z"/>
<path d="M72.4 149l1.3 1.9zM115.6 149l-1.3 1.9zM115.6 149l1.2 1.9zM161.3 149l-1.3 1.9zM161.3 149l1.2 1.9zM204.4 149l-1.2 1.9zM204.4 149l1.3 1.9zM288.3 137.6v2.5zM288.3 142.7v2.5zM288.3 142.7l2.5 1.3zM288.3 145h.3zM288.3 144.8h.8z"/>
<path d="M288.3 144.6h1.2zM288.3 144.4h1.7zM288.3 144.1h2.1zM288.3 143.9h2.4zM288.3 143.7h2zM288.3 143.5h1.6zM288.3 143.3h1.1zM288.3 143h.7zM288.3 142.8h.2zM288.3 147.8v2.5zM288.3 147.8l2.5 1.2zM288.3 150.1h.3z"/>
<path d="M288.3 149.9h.7zM288.3 149.7h1.2zM288.3 149.5h1.6zM288.3 149.2h2.1zM288.3 149h2.5zM288.3 148.8h2zM288.3 148.6h1.6zM288.3 148.4h1.1zM288.3 148.1h.7zM288.3 147.9h.3zM288.3 152.8v2.6zM288.3 152.8l2.5 1.3z"/>
<path d="M288.3 155.3h.2zM288.3 155h.7zM288.3 154.8h1.1zM288.3 154.6h1.6zM288.3 154.4h2zM288.3 154.1h2.4zM288.3 153.9h2.1zM288.3 153.7h1.7zM288.3 153.5h1.2zM288.3 153.2h.8zM288.3 153h.3zM288.3 157.9l2.5 1.3z"/>
<path d="M288.3 159.9h1zM288.3 159.7h1.5zM288.3 159.5h1.9zM288.3 159.3h2.4zM288.3 159h2.2zM288.3 158.8h1.7zM288.3 158.6h1.3zM288.3 158.4h.8zM288.3 158.1h.4zM290.8 137.6v2.5zM290.8 140.1h.3zM290.8 144v1.2z"/>
<path d="M288.3 145.2l2.5-1.2zM290.8 142.7v2.5zM290.8 142.7h.3zM290.8 145h.3zM290.8 144.8h.3zM290.8 144.6h.3zM290.8 144.4h.3zM290.8 144.1h.3zM290.8 143.9h.3zM290.8 143.7h.3zM290.8 143.5h.3zM290.8 143.3h.3z"/>
<path d="M290.8 143h.3zM290.8 142.8h.3zM290.8 149v1.3zM288.3 150.3l2.5-1.3zM290.8 147.8v2.5zM290.8 147.8h.3zM290.8 150.1h.3zM290.8 149.9h.3zM290.8 149.7h.3zM290.8 149.5h.3zM290.8 149.2h.3zM290.8 149h.3z"/>
<path d="M290.8 148.8h.3zM290.8 148.6h.3zM290.8 148.4h.3zM290.8 148.1h.3zM290.8 147.9h.3zM290.8 154.1v1.3zM288.3 155.4l2.5-1.3zM290.8 152.8v2.6zM290.8 152.8h.3zM290.8 155.3h.3zM290.8 155h.3zM290.8 154.8h.3z"/>
<path d="M290.8 154.6h.3zM290.8 154.4h.3zM290.8 154.1h.3zM290.8 153.9h.3zM290.8 153.7h.3zM290.8 153.5h.3zM290.8 153.2h.3zM290.8 153h.3zM290.8 159.2v1.3zM288.3 160.5l2.5-1.3zM290.8 157.9h.3zM290.8 159.9h.3z"/>
<path d="M290.8 159.7h.3zM290.8 159.5h.3zM290.8 159.3h.3zM290.8 159h.3zM290.8 158.8h.3zM290.8 158.6h.3zM290.8 158.4h.3zM290.8 158.1h.3zM291.1 142.7v2.5zM290.8 145.2h.3zM291.1 147.8v2.5zM290.8 150.3h.3z"/>
<path d="M291.1 152.8v2.6zM290.8 155.4h.3zM291.1 157.9v2.6zM309.9 153.3h5zM309.9 154.1v.8zM309.9 153.3v.8zM309.9 150.8v.8zM309.9 151.6v.7zM309.9 150.8h5zM309.9 148.3h5zM309.9 145.7h5zM309.9 143.2h5z"/>
<path d="M309.9 148.3v.7zM309.9 145.7v.8zM309.9 143.2v.8zM309.9 149v.8zM309.9 146.5v.8zM309.9 144v.7zM309.9 140.7h5zM309.9 141.4v.8zM309.9 140.7v.7zM309.9 154.9h5zM314.9 153.3v.8zM314.9 154.1v.8z"/>
<path d="M314.9 150.8v.8zM314.9 151.6v.7zM309.9 152.3h5zM309.9 149.8h5zM309.9 147.3h5zM309.9 144.7h5zM314.9 148.3v.7zM314.9 145.7v.8zM314.9 143.2v.8zM314.9 149v.8zM314.9 146.5v.8zM314.9 144v.7z"/>
<path d="M309.9 142.2h5zM314.9 140.7v.7zM314.9 141.4v.8zM321.9 159.2h3.8zM356.8 140.1v2.6zM356.8 140.1l2.6 1.3zM356.8 142.6h.2zM356.8 142.4h.7zM356.8 142.1h1.1zM356.8 141.9h1.5zM356.8 141.7h2zM356.8 141.5h2.4z"/>
<path d="M356.8 141.2h2.2zM356.8 141h1.8zM356.8 140.8h1.4zM356.8 140.6h.9zM356.8 140.4h.5zM356.8 145.2v2.6zM356.8 145.2l2.6 1.3zM356.8 147.7h.2zM356.8 147.5h.6zM356.8 147.3h1.1zM356.8 147h1.5zM356.8 146.8h1.9z"/>
<path d="M356.8 146.6h2.4zM356.8 146.4h2.3zM356.8 146.1h1.9zM356.8 145.9h1.4zM356.8 145.7h1zM356.8 145.5h.5zM359.4 141.4v1.3zM356.8 142.7l2.6-1.3zM359.4 140.1v2.6zM359.4 140.1h.2zM359.4 142.6h.2zM359.4 142.4h.2z"/>
<path d="M359.4 142.1h.2zM359.4 141.9h.2zM359.4 141.7h.2zM359.4 141.5h.2zM359.4 141.2h.2zM359.4 141h.2zM359.4 140.8h.2zM359.4 140.6h.2zM359.4 140.4h.2zM359.4 146.5v1.3zM356.8 147.8l2.6-1.3zM359.4 145.2v2.6z"/>
<path d="M359.4 145.2h.2zM359.4 147.7h.2zM359.4 147.5h.2zM359.4 147.3h.2zM359.4 147h.2zM359.4 146.8h.2zM359.4 146.6h.2zM359.4 146.4h.2zM359.4 146.1h.2zM359.4 145.9h.2zM359.4 145.7h.2zM359.4 145.5h.2z"/>
<path d="M359.6 140.1v2.6zM359.4 142.7h.2zM359.6 145.2v2.6zM359.4 147.8h.2zM390.5 141.4h3.8zM70.5 174.4h3.8zM113.7 174.4h3.8zM159.4 174.4h3.8zM202.5 174.4h3.9zM288.3 157.9v2.6zM288.3 160.4h.2zM288.3 160.1h.6z"/>
<path d="M288.3 163v2.5zM288.3 163l2.5 1.3zM288.3 165.5h.1zM288.3 165.2h.5zM288.3 165h1zM288.3 164.8h1.4zM288.3 164.6h1.9zM288.3 164.4h2.3zM288.3 164.1h2.2zM288.3 163.9h1.8zM288.3 163.7h1.3zM288.3 163.5h.9z"/>
<path d="M288.3 163.3h.5zM290.8 157.9v2.6zM290.8 160.4h.3zM290.8 160.1h.3zM290.8 164.3v1.2zM288.3 165.5l2.5-1.2zM290.8 163v2.5zM290.8 163h.3zM290.8 165.5h.3zM290.8 165.2h.3zM290.8 165h.3zM290.8 164.8h.3z"/>
<path d="M290.8 164.6h.3zM290.8 164.4h.3zM290.8 164.1h.3zM290.8 163.9h.3zM290.8 163.7h.3zM290.8 163.5h.3zM290.8 163.3h.3zM290.8 160.5h.3zM291.1 163v2.5zM72.4 199.8l1.3 1.9zM115.6 199.8l1.2 1.9zM161.3 199.8l1.2 1.9z"/>
<path d="M204.4 199.8l1.3 1.9zM72.4 199.8l-1.3 1.9zM115.6 199.8l-1.3 1.9zM161.3 199.8l-1.3 1.9zM204.4 199.8l-1.2 1.9zM377.1 212.5l1.6-1.5zM377.1 212.5l1.6 1.5zM378.7 211h10.2zM378.7 214h10.2zM388.9 211v3zM70.5 225.2h3.8zM113.7 225.2h3.8z"/>
<path d="M159.4 225.2h3.8zM202.5 225.2h3.9zM113 243l-1.2 1.9zM113 243l1.3 1.9zM120.6 243l-1.2 1.9zM120.6 243l1.3 1.9zM313.7 249.3h86.3zM313.7 254.4h86.3zM313.7 259.5h58.4zM372.1 259.5h27.9zM372.1 259.5v5.1zM27.3 265.8h3.8z"/>
<path d="M118.7 265.8h3.8zM313.7 264.6h58.4zM313.7 269.7h86.3zM372.1 264.6h27.9zM400 268.4v1.3z"/>
</g>
<path d="M16.5 18.2v260.3zM16.5 18.2h387.3zM16.5 278.5h387.3zM403.8 18.2v260.3z" fill="#000" stroke="#000" stroke-width=".32"/>
<g fill="#000" stroke="#000" stroke-width=".61">
<path d="M20.3 22.1v252.6zM20.3 22.1h379.7zM102.9 70.3v22.9zM102.9 70.3h15.2zM168.9 70.3v30.5zM168.9 70.3h15.2zM227.3 70.3v22.9zM227.3 70.3h15.2zM280.6 70.3v30.5zM280.6 70.3h15.3zM308.6 72.8h1.3zM308.6 75.4h1.3z"/>
<path d="M308.6 77.9h1.3zM349.2 70.3v30.5zM349.2 70.3h15.2zM374.6 72.8h1.3zM374.6 75.4h1.3zM374.6 77.9h1.3zM69.8 93.2v10.1zM102.9 93.2h15.2zM118.1 70.3v22.9zM227.3 93.2h15.2zM242.5 70.3v22.9zM308.6 80.5h1.3z"/>
<path d="M308.6 83h1.3zM308.6 85.5h1.3zM308.6 88.1h1.3zM308.6 90.6h1.3zM374.6 80.5h1.3zM374.6 83h1.3zM374.6 85.5h1.3zM374.6 88.1h1.3zM374.6 90.6h1.3zM168.9 100.8h15.2zM184.1 70.3v30.5zM280.6 100.8h15.3z"/>
<path d="M295.9 70.3v30.5zM349.2 100.8h15.2zM364.4 70.3v30.5zM80 151.6v20.3zM80 151.6h15.2zM123.2 151.6v20.3zM123.2 151.6h15.2zM168.9 151.6v20.3zM168.9 151.6h15.2zM212.1 151.6v20.3zM212.1 151.6h15.2zM80 171.9h15.2z"/>
<path d="M95.2 151.6v20.3zM123.2 171.9h15.2zM138.4 151.6v20.3zM168.9 171.9h15.2zM184.1 151.6v20.3zM212.1 171.9h15.2zM227.3 151.6v20.3zM275.6 192.2v10.2zM308.6 199.8v10.2zM80 202.4v20.3zM80 202.4h15.2zM123.2 202.4v20.3z"/>
<path d="M123.2 202.4h15.2zM168.9 202.4v20.3zM168.9 202.4h15.2zM212.1 202.4v20.3zM212.1 202.4h15.2zM275.6 202.4v10.1zM275.6 212.5v10.2zM308.6 215v10.2zM339 207.4v10.2zM80 222.7h15.2zM95.2 202.4v20.3zM123.2 222.7h15.2z"/>
<path d="M138.4 202.4v20.3zM168.9 222.7h15.2zM184.1 202.4v20.3zM212.1 222.7h15.2zM227.3 202.4v20.3zM275.6 222.7v10.1zM283.2 244.3v30.4zM313.7 254.4v5.1zM313.7 249.3v5.1zM313.7 244.3v5zM313.7 244.3h86.3zM283.2 244.3h30.5z"/>
<path d="M400 254.4v5.1zM400 249.3v5.1zM400 244.3v5zM400 22.1v222.2zM20.3 274.7h262.9zM283.2 274.7h30.5zM313.7 274.7h86.3zM313.7 269.7v5zM313.7 264.6v5.1zM313.7 259.5v5.1zM400 268.4v6.3zM400 264.6v3.8z"/>
<path d="M400 259.5v5.1z"/>
</g>
<g fill="none" stroke="#000" stroke-width=".21">
<circle cx="119.1" cy="77.9" r=".99"/>
<circle cx="119.1" cy="72.8" r=".99"/>
<circle cx="119.1" cy="75.4" r=".99"/>
<circle cx="185.1" cy="72.8" r=".99"/>
<circle cx="185.1" cy="75.4" r=".99"/>
<circle cx="185.1" cy="77.9" r=".99"/>
<circle cx="101.9" cy="88.1" r=".99"/>
<circle cx="101.9" cy="90.6" r=".99"/>
<circle cx="119.1" cy="90.6" r=".99"/>
<circle cx="119.1" cy="88.1" r=".99"/>
<circle cx="119.1" cy="85.5" r=".99"/>
<circle cx="119.1" cy="80.5" r=".99"/>
<circle cx="119.1" cy="83" r=".99"/>
<circle cx="167.9" cy="98.2" r=".99"/>
<circle cx="167.9" cy="95.7" r=".99"/>
<circle cx="185.1" cy="90.6" r=".99"/>
<circle cx="185.1" cy="88.1" r=".99"/>
<circle cx="185.1" cy="80.5" r=".99"/>
<circle cx="185.1" cy="85.5" r=".99"/>
<circle cx="185.1" cy="83" r=".99"/>
<circle cx="226.3" cy="90.6" r="1"/>
<circle cx="226.3" cy="88.1" r="1"/>
<circle cx="279.6" cy="95.7" r="1"/>
<circle cx="279.6" cy="98.2" r="1"/>
<circle cx="348.2" cy="95.7" r="1"/>
<circle cx="348.2" cy="98.2" r="1"/>
<circle cx="79" cy="154.1" r=".99"/>
<circle cx="122.2" cy="154.1" r=".99"/>
<circle cx="167.9" cy="154.1" r=".99"/>
<circle cx="211.1" cy="154.1" r=".99"/>
<circle cx="79" cy="169.4" r=".99"/>
<circle cx="122.2" cy="169.4" r=".99"/>
<circle cx="167.9" cy="169.4" r=".99"/>
<circle cx="211.1" cy="169.4" r=".99"/>
<circle cx="79" cy="204.9" r=".99"/>
<circle cx="122.2" cy="204.9" r=".99"/>
<circle cx="167.9" cy="204.9" r=".99"/>
<circle cx="211.1" cy="204.9" r=".99"/>
<circle cx="79" cy="220.1" r=".99"/>
<circle cx="122.2" cy="220.1" r=".99"/>
<circle cx="167.9" cy="220.1" r=".99"/>
<circle cx="211.1" cy="220.1" r=".99"/>
</g>
<path d="M69.8 93.2a5.1 5.1 0 0 1 5.1 5 5.1 5.1 0 0 1-5.1 5.1M275.6 192.2a5.1 5.1 0 0 1 5 5.1 5.1 5.1 0 0 1-5 5.1 5.1 5.1 0 0 1 5 5 5.1 5.1 0 0 1-5 5.1 5.1 5.1 0 0 1 5 5.1 5.1 5.1 0 0 1-5 5.1 5.1 5.1 0 0 1 5 5 5.1 5.1 0 0 1-5 5.1M308.6 199.8a5.1 5.1 0 0 1 5.1 5.1 5.1 5.1 0 0 1-5.1 5.1M308.6 215a5.1 5.1 0 0 1 5.1 5.1 5.1 5.1 0 0 1-5.1 5.1M339 207.4a5.1 5.1 0 0 1 5.1 5.1 5.1 5.1 0 0 1-5.1 5.1" fill="none" stroke="#000" stroke-width=".61"/>
<g fill="#000" stroke="#000" stroke-width=".21">
<path d="M27.2 253.7h4v.5h-4zM27.2 254.7h4v.5h-4zM34.8 253.7h4.1v.5h-4.1zM34.8 254.7h4.1v.5h-4.1zM42.4 253.7h4.1v.5h-4.1zM42.4 254.7h4.1v.5h-4.1zM50 253.7h4.1v.5h-4.1zM50 254.7h4.1v.5h-4.1zM57.7 253.7h4v.5h-4zM57.7 254.7h4v.5h-4zM65.3 253.7h4v.5h-4zM65.3 254.7h4v.5h-4z"/>
<path d="M72.9 253.7h4.1v.5h-4.1zM72.9 254.7h4.1v.5h-4.1zM80.5 253.7h4.1v.5h-4.1zM80.5 254.7h4.1v.5h-4.1zM88.1 253.7h4.1v.5h-4.1zM88.1 254.7h4.1v.5h-4.1zM95.8 253.7h4v.5h-4zM95.8 254.7h4v.5h-4zM103.4 253.7h4v.5h-4zM103.4 254.7h4v.5h-4zM111 253.7h4.1v.5h-4.1zM111 254.7h4.1v.5h-4.1z"/>
<path d="M118.6 254.7h4.1v.5h-4.1zM118.6 253.7h4.1v.5h-4.1zM254 253.1h25.4v10.2h-25.4z"/>
</g>
<g fill="#000" stroke="#000" stroke-width=".42">
<path d="M377.1 116h8.9zM308.6 133.8h8.9zM377.1 116v22.9zM377.1 138.9h8.9zM386 116v22.9zM308.6 133.8v22.9zM308.6 156.7h8.9zM317.5 133.8v22.9zM223.5 253.1v10.2zM223.5 253.1h55.9zM223.5 263.3v7.6zM223.5 270.9h55.9z"/>
<path d="M223.5 263.3h55.9zM279.4 263.3v7.6zM279.4 253.1v10.2zM279.4 263.3v2.5z"/>
</g>
<g fill="none" stroke="#000" stroke-width=".42">
<circle cx="316.2" cy="138.9" r=".25"/>
<circle cx="384.8" cy="121.1" r=".25"/>
<circle cx="384.8" cy="131.3" r=".25"/>
<circle cx="384.8" cy="123.6" r=".25"/>
<circle cx="384.8" cy="128.7" r=".25"/>
<circle cx="384.8" cy="136.3" r=".25"/>
<circle cx="384.8" cy="126.2" r=".25"/>
<circle cx="384.8" cy="133.8" r=".25"/>
<circle cx="316.2" cy="146.5" r=".25"/>
<circle cx="316.2" cy="154.1" r=".25"/>
<circle cx="316.2" cy="149" r=".25"/>
<circle cx="316.2" cy="141.4" r=".25"/>
<circle cx="316.2" cy="144" r=".25"/>
<circle cx="316.2" cy="151.6" r=".25"/>
</g>
<g fill="#000" stroke="#000" stroke-width=".76">
<path d="M44.4 29.7h5.1zM49.5 29.7l5.1 5.1zM44.4 37.3h157.5zM49.5 29.7h154.9zM201.9 37.3l2.5 2.5zM204.4 29.7l5.1 5.1zM151.1 47.5l2.5-2.6zM153.6 44.9h172.8zM326.4 44.9l2.5 2.6zM260.3 70.3v114.3zM54.6 34.8v63.4zM151.1 47.5v40.6z"/>
<path d="M204.4 39.8v48.3zM209.5 34.8v45.7zM67.3 136.3h185.4zM252.7 136.3l7.6-7.6zM44.4 141.4h157.5zM52.1 141.4l5 5.1zM57.1 146.5v40.6zM328.9 47.5v132zM57.1 187.1l5.1 5.1zM62.2 192.2h139.7zM67.3 187.1h190.5zM105.4 182.1h137.1z"/>
<path d="M242.5 182.1l2.6 2.5zM245.1 184.6v45.7zM245.1 184.6l2.5-2.5zM247.6 182.1h78.8zM257.8 187.1l2.5-2.5zM328.9 179.5l-2.5 2.6zM105.4 232.8h137.1zM245.1 230.3l-2.6 2.5z"/>
</g>
<use href="#words"/>
</svg>
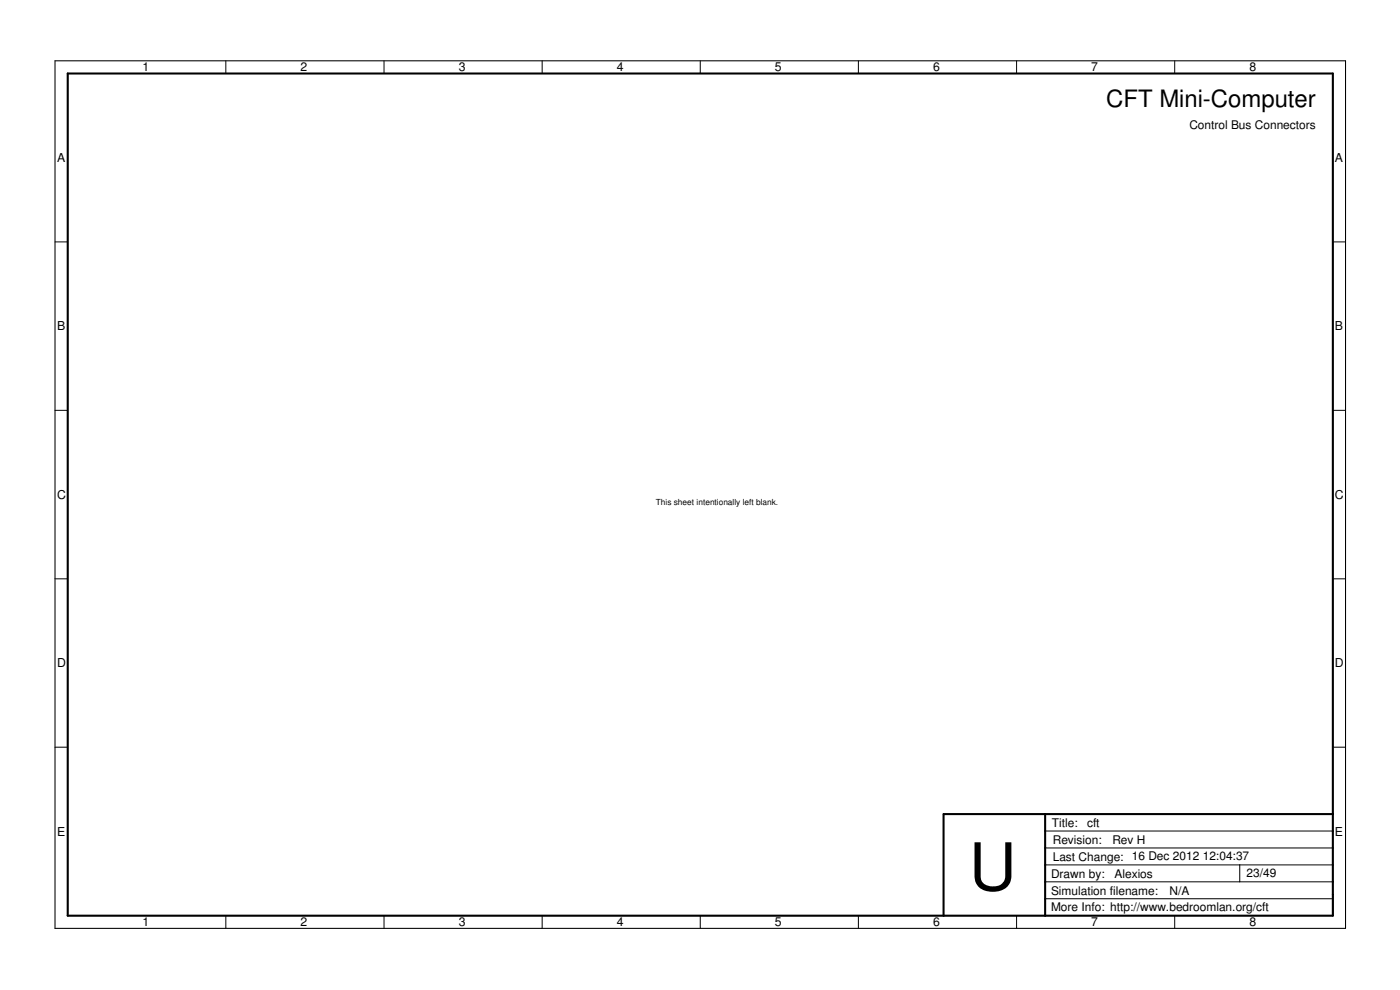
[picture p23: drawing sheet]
<svg xmlns="http://www.w3.org/2000/svg" width="420mm" height="297mm" viewBox="0 0 420 297" stroke-linecap="round" stroke-linejoin="round" font-family="sans-serif">
<defs><g id="words">
<text font-size="19.7" x="290.8" y="267.1">U</text>
<text font-size="7.2" x="332" y="32.2">CFT Mini-Computer</text>
<g font-size="3.7">
<text x="42.7" y="21.5">1</text>
<text x="90.2" y="21.5">2</text>
<text x="137.7" y="21.5">3</text>
<text x="185.1" y="21.5">4</text>
<text x="232.6" y="21.5">5</text>
<text x="280" y="21.5">6</text>
<text x="327.5" y="21.5">7</text>
<text x="375" y="21.5">8</text>
<text x="17.1" y="48.6">A</text>
<text x="400.6" y="48.6">A</text>
<text x="17.1" y="99.2">B</text>
<text x="400.6" y="99.2">B</text>
<text x="17.1" y="149.7">C</text>
<text x="400.6" y="149.7">C</text>
<text x="17.1" y="200.2">D</text>
<text x="400.6" y="200.2">D</text>
<text x="17.1" y="250.8">E</text>
<text x="400.6" y="250.8">E</text>
<text x="42.7" y="277.9">1</text>
<text x="90.2" y="277.9">2</text>
<text x="137.7" y="277.9">3</text>
<text x="185.1" y="277.9">4</text>
<text x="232.6" y="277.9">5</text>
<text x="280" y="277.9">6</text>
<text x="327.5" y="277.9">7</text>
<text x="375" y="277.9">8</text>
</g>
<g font-size="3.6">
<text x="357" y="38.6">Control Bus Connectors</text>
<text x="315.7" y="248.1">Title:</text>
<text x="326.2" y="248.2">cft</text>
<text x="315.9" y="253.2">Revision:</text>
<text x="333.8" y="253.3">Rev H</text>
<text x="315.4" y="263.3">Drawn by:</text>
<text x="315.9" y="258.2">Last Change: 16 Dec 2012</text>
<text x="334.5" y="263.3">Alexios</text>
<text x="361" y="258.1">12:04:37</text>
<text x="374.1" y="263.2">23/49</text>
<text x="315.4" y="268.4">Simulation filename:</text>
<text x="351" y="268.4">N/A</text>
<text x="315.4" y="273.5">More Info: http://www.bedroomlan.org/cft</text>
</g>
<text font-size="2.5" x="196.8" y="151.6">This sheet intentionally left blank.</text>
</g></defs>
<g fill="#000" stroke="#000" stroke-width=".3">
<path d="M67.8 18.2v3.9zM115.3 18.2v3.9zM162.7 18.2v3.9zM210.2 18.2v3.9zM257.6 18.2v3.9zM305.1 18.2v3.9zM352.5 18.2v3.9zM20.3 22.1v252.6zM20.3 22.1h379.7zM16.5 72.6h3.8zM400 72.6h3.8zM16.5 123.1h3.8z"/>
<path d="M400 123.1h3.8zM16.5 173.7h3.8zM400 173.7h3.8zM16.5 224.2h3.8zM400 224.2h3.8zM313.7 249.3h86.3zM313.7 254.4h86.3zM313.7 259.5h58.4zM372.1 259.5h27.9zM372.1 259.5v5.1zM20.3 274.7h379.7zM67.8 274.7v3.8z"/>
<path d="M115.3 274.7v3.8zM162.7 274.7v3.8zM210.2 274.7v3.8zM257.6 274.7v3.8zM305.1 274.7v3.8zM313.7 264.6h58.4zM313.7 269.7h86.3zM352.5 274.7v3.8zM372.1 264.6h27.9zM400 268.4v6.2zM400 22.1v252.6zM400 268.4v1.3z"/>
</g>
<path d="M16.5 18.2v260.3zM16.5 18.2h387.3zM16.5 278.5h387.3zM403.8 18.2v260.3z" fill="#000" stroke="#000" stroke-width=".32"/>
<g fill="#000" stroke="#000" stroke-width=".61">
<path d="M20.3 22.1v252.6zM20.3 22.1h379.7zM283.2 244.3v30.4zM313.7 254.4v5.1zM313.7 249.3v5.1zM313.7 244.3v5zM313.7 244.3h86.3zM283.2 244.3h30.5zM400 254.4v5.1zM400 249.3v5.1zM400 244.3v5zM400 22.1v222.2z"/>
<path d="M20.3 274.7h262.9zM283.2 274.7h30.5zM313.7 274.7h86.3zM313.7 269.7v5zM313.7 264.6v5.1zM313.7 259.5v5.1zM400 268.4v6.3zM400 264.6v3.8zM400 259.5v5.1z"/>
</g>
<use href="#words"/>
</svg>
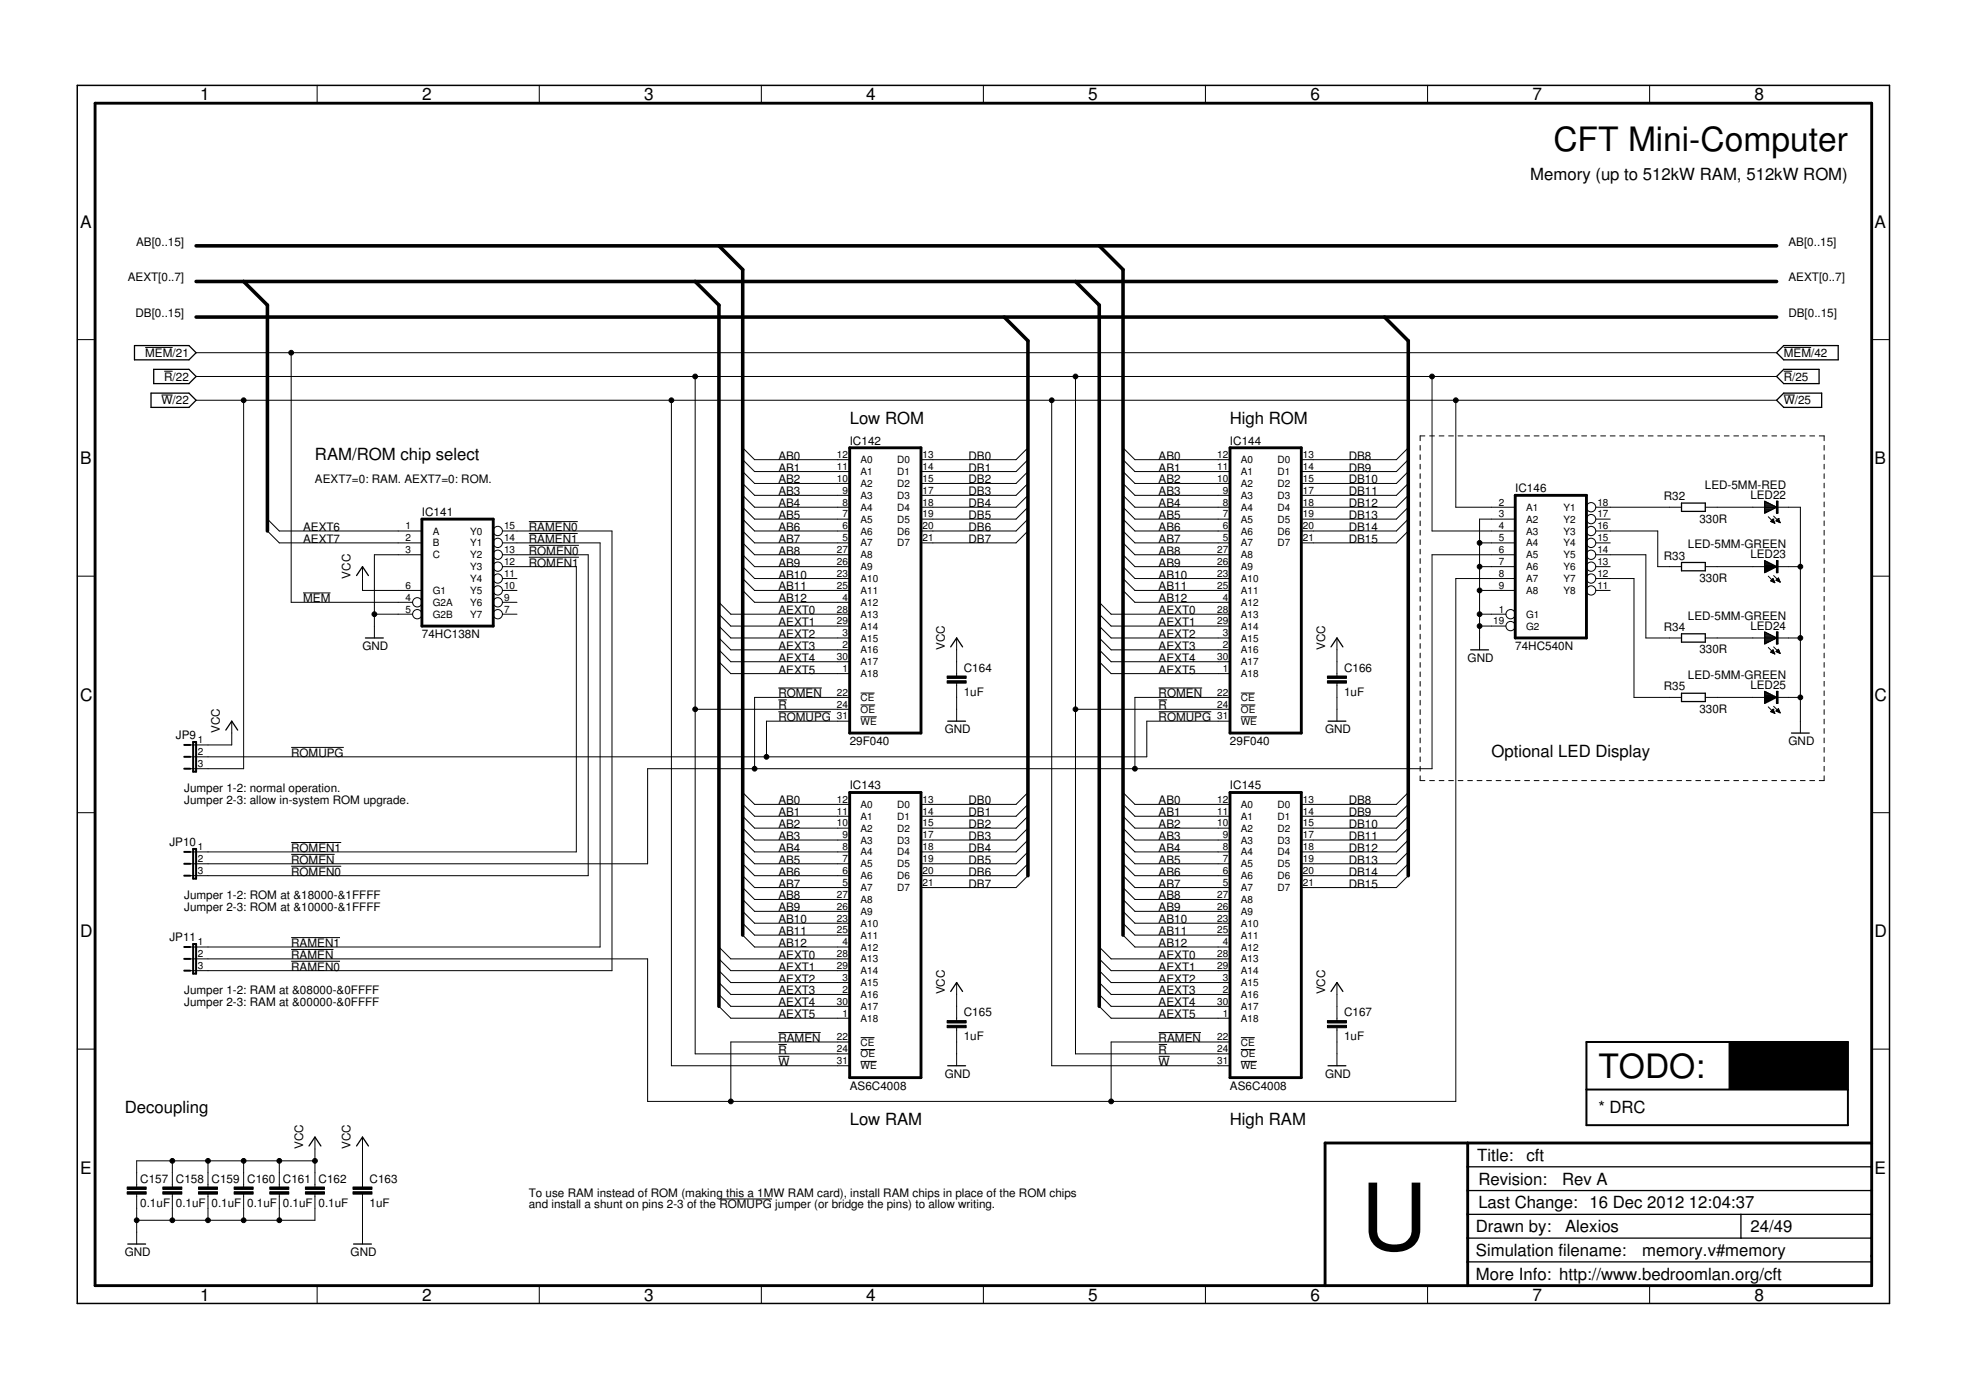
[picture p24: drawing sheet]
<svg xmlns="http://www.w3.org/2000/svg" width="420mm" height="297mm" viewBox="0 0 420 297" stroke-linecap="round" stroke-linejoin="round" font-family="sans-serif">
<defs><g id="words">
<text font-size="19.7" x="290.8" y="267.1">U</text>
<g font-size="7.2">
<text x="332" y="32.2">CFT Mini-Computer</text>
<text x="341.6" y="230.3">TODO:</text>
</g>
<g font-size="3.7">
<text x="42.7" y="21.5">1</text>
<text x="90.2" y="21.5">2</text>
<text x="137.7" y="21.5">3</text>
<text x="185.1" y="21.5">4</text>
<text x="232.6" y="21.5">5</text>
<text x="280" y="21.5">6</text>
<text x="327.5" y="21.5">7</text>
<text x="375" y="21.5">8</text>
<text x="17.1" y="48.6">A</text>
<text x="400.6" y="48.6">A</text>
<text x="17.1" y="99.2">B</text>
<text x="400.6" y="99.2">B</text>
<text x="17.1" y="149.7">C</text>
<text x="400.6" y="149.7">C</text>
<text x="17.1" y="200.2">D</text>
<text x="400.6" y="200.2">D</text>
<text x="17.1" y="250.8">E</text>
<text x="400.6" y="250.8">E</text>
<text x="42.7" y="277.9">1</text>
<text x="90.2" y="277.9">2</text>
<text x="137.7" y="277.9">3</text>
<text x="185.1" y="277.9">4</text>
<text x="232.6" y="277.9">5</text>
<text x="280" y="277.9">6</text>
<text x="327.5" y="277.9">7</text>
<text x="375" y="277.9">8</text>
</g>
<g font-size="3.6">
<text x="327" y="38.6">Memory (up to 512kW RAM, 512kW ROM)</text>
<text x="181.6" y="90.6">Low ROM</text>
<text x="262.9" y="90.6">High ROM</text>
<text x="67.3" y="98.2">RAM/ROM chip select</text>
<text x="318.7" y="161.7">Optional LED Display</text>
<text x="26.7" y="237.9">Decoupling</text>
<text x="341.6" y="237.9">* DRC</text>
<text x="181.6" y="240.5">Low RAM</text>
<text x="262.9" y="240.5">High RAM</text>
<text x="315.7" y="248.1">Title:</text>
<text x="326.2" y="248.2">cft</text>
<text x="315.9" y="253.2">Revision:</text>
<text x="333.8" y="253.3">Rev A</text>
<text x="315.4" y="263.3">Drawn by:</text>
<text x="315.9" y="258.2">Last Change: 16 Dec 2012</text>
<text x="334.5" y="263.3">Alexios</text>
<text x="361" y="258.1">12:04:37</text>
<text x="374.1" y="263.2">24/49</text>
<text x="315.4" y="268.4">Simulation filename:</text>
<text x="351" y="268.4">memory.v#memory</text>
<text x="315.4" y="273.5">More Info: http://www.bedroomlan.org/cft</text>
</g>
<g font-size="2.5">
<text x="29.1" y="52.5">AB[0..15]</text>
<text x="382.2" y="52.5">AB[0..15]</text>
<text x="27.3" y="60.1">AEXT[0..7]</text>
<text x="382.2" y="60.1">AEXT[0..7]</text>
<text x="29" y="67.8">DB[0..15]</text>
<text x="382.2" y="67.8">DB[0..15]</text>
<text x="31" y="76.3">MEM/21</text>
<text x="381.2" y="76.3">MEM/42</text>
<text x="35.1" y="81.3">R/22</text>
<text x="381.2" y="81.3">R/25</text>
<text x="34.5" y="86.4">W/22</text>
<text x="381.2" y="86.4">W/25</text>
<text x="181.6" y="95.1">IC142</text>
<text x="262.9" y="95.1">IC144</text>
<text x="166.4" y="98.2">AB0</text>
<text x="166.4" y="100.8">AB1</text>
<text x="207" y="98.2">DB0</text>
<text x="207" y="100.8">DB1</text>
<text x="247.6" y="98.2">AB0</text>
<text x="247.6" y="100.8">AB1</text>
<text x="288.3" y="98.2">DB8</text>
<text x="288.3" y="100.8">DB9</text>
<text x="67.3" y="103.3">AEXT7=0: RAM. AEXT7=0: ROM.</text>
<text x="166.4" y="103.3">AB2</text>
<text x="166.4" y="105.9">AB3</text>
<text x="207" y="103.3">DB2</text>
<text x="207" y="105.9">DB3</text>
<text x="247.6" y="103.3">AB2</text>
<text x="247.6" y="105.9">AB3</text>
<text x="288.3" y="103.3">DB10</text>
<text x="288.3" y="105.9">DB11</text>
<text x="323.8" y="105.2">IC146</text>
<text x="355.6" y="106.9">R32</text>
<text x="364.4" y="104.5">LED-5MM-RED</text>
<text x="374.1" y="106.6">LED22</text>
<text x="64.8" y="113.5">AEXT6</text>
<text x="90.2" y="110.3">IC141</text>
<text x="113" y="113.5">RAMEN0</text>
<text x="166.4" y="108.4">AB4</text>
<text x="166.4" y="110.9">AB5</text>
<text x="166.4" y="113.5">AB6</text>
<text x="207" y="108.4">DB4</text>
<text x="207" y="110.9">DB5</text>
<text x="207" y="113.5">DB6</text>
<text x="247.6" y="108.4">AB4</text>
<text x="247.6" y="110.9">AB5</text>
<text x="247.6" y="113.5">AB6</text>
<text x="288.3" y="108.4">DB12</text>
<text x="288.3" y="110.9">DB13</text>
<text x="288.3" y="113.5">DB14</text>
<text x="363.2" y="111.7">330R</text>
<text x="64.8" y="116">AEXT7</text>
<text x="113" y="116">RAMEN1</text>
<text x="113" y="118.6">ROMEN0</text>
<text x="166.4" y="116">AB7</text>
<text x="166.4" y="118.6">AB8</text>
<text x="207" y="116">DB7</text>
<text x="247.6" y="116">AB7</text>
<text x="247.6" y="118.6">AB8</text>
<text x="288.3" y="116">DB15</text>
<text x="355.6" y="119.6">R33</text>
<text x="360.7" y="117.2">LED-5MM-GREEN</text>
<text x="374.1" y="119.3">LED23</text>
<text x="74.9" y="123.6" transform="rotate(-90 74.9 123.6)">VCC</text>
<text x="113" y="121.1">ROMEN1</text>
<text x="166.4" y="121.1">AB9</text>
<text x="166.4" y="123.6">AB10</text>
<text x="247.6" y="121.1">AB9</text>
<text x="247.6" y="123.6">AB10</text>
<text x="363.2" y="124.4">330R</text>
<text x="64.8" y="128.7">MEM</text>
<text x="166.4" y="126.2">AB11</text>
<text x="166.4" y="131.3">AEXT0</text>
<text x="166.4" y="128.7">AB12</text>
<text x="247.6" y="126.2">AB11</text>
<text x="247.6" y="131.3">AEXT0</text>
<text x="247.6" y="128.7">AB12</text>
<text x="90.2" y="136.3">74HC138N</text>
<text x="166.4" y="136.3">AEXT2</text>
<text x="166.4" y="133.8">AEXT1</text>
<text x="247.6" y="136.3">AEXT2</text>
<text x="247.6" y="133.8">AEXT1</text>
<text x="355.6" y="134.8">R34</text>
<text x="360.7" y="132.4">LED-5MM-GREEN</text>
<text x="374.1" y="134.6">LED24</text>
<text x="77.5" y="138.9">GND</text>
<text x="166.4" y="138.9">AEXT3</text>
<text x="166.4" y="141.4">AEXT4</text>
<text x="166.4" y="144">AEXT5</text>
<text x="201.9" y="138.9" transform="rotate(-90 201.9 138.9)">VCC</text>
<text x="206" y="143.6">C164</text>
<text x="247.6" y="138.9">AEXT3</text>
<text x="247.6" y="141.4">AEXT4</text>
<text x="247.6" y="144">AEXT5</text>
<text x="283.2" y="138.9" transform="rotate(-90 283.2 138.9)">VCC</text>
<text x="287.2" y="143.6">C166</text>
<text x="313.7" y="141.4">GND</text>
<text x="323.8" y="138.9">74HC540N</text>
<text x="363.2" y="139.6">330R</text>
<text x="166.4" y="149">ROMEN</text>
<text x="206" y="148.6">1uF</text>
<text x="247.6" y="149">ROMEN</text>
<text x="287.2" y="148.6">1uF</text>
<text x="355.6" y="147.5">R35</text>
<text x="360.7" y="145.1">LED-5MM-GREEN</text>
<text x="374.1" y="147.3">LED25</text>
<text x="166.4" y="151.6">R</text>
<text x="166.4" y="154.1">ROMUPG</text>
<text x="247.6" y="151.6">R</text>
<text x="247.6" y="154.1">ROMUPG</text>
<text x="363.2" y="152.3">330R</text>
<text x="37.6" y="157.9">JP9</text>
<text x="47" y="156.6" transform="rotate(-90 47 156.6)">VCC</text>
<text x="62.2" y="161.7">ROMUPG</text>
<text x="181.6" y="159.2">29F040</text>
<text x="201.9" y="156.6">GND</text>
<text x="262.9" y="159.2">29F040</text>
<text x="283.2" y="156.6">GND</text>
<text x="382.2" y="159.2">GND</text>
<text x="39.4" y="169.3">Jumper 1-2: normal operation.</text>
<text x="39.4" y="171.9">Jumper 2-3: allow in-system ROM upgrade.</text>
<text x="166.4" y="171.9">AB0</text>
<text x="181.6" y="168.7">IC143</text>
<text x="207" y="171.9">DB0</text>
<text x="247.6" y="171.9">AB0</text>
<text x="262.9" y="168.7">IC145</text>
<text x="288.3" y="171.9">DB8</text>
<text x="166.4" y="174.4">AB1</text>
<text x="166.4" y="177">AB2</text>
<text x="166.4" y="179.5">AB3</text>
<text x="207" y="174.4">DB1</text>
<text x="207" y="177">DB2</text>
<text x="207" y="179.5">DB3</text>
<text x="247.6" y="174.4">AB1</text>
<text x="247.6" y="177">AB2</text>
<text x="247.6" y="179.5">AB3</text>
<text x="288.3" y="174.4">DB9</text>
<text x="288.3" y="177">DB10</text>
<text x="288.3" y="179.5">DB11</text>
<text x="36.2" y="180.8">JP10</text>
<text x="62.2" y="184.6">ROMEN</text>
<text x="62.2" y="182">ROMEN1</text>
<text x="166.4" y="182">AB4</text>
<text x="166.4" y="184.6">AB5</text>
<text x="207" y="182">DB4</text>
<text x="207" y="184.6">DB5</text>
<text x="247.6" y="182">AB4</text>
<text x="247.6" y="184.6">AB5</text>
<text x="288.3" y="182">DB12</text>
<text x="288.3" y="184.6">DB13</text>
<text x="62.2" y="187.1">ROMEN0</text>
<text x="166.4" y="187.1">AB6</text>
<text x="166.4" y="189.7">AB7</text>
<text x="207" y="187.1">DB6</text>
<text x="207" y="189.7">DB7</text>
<text x="247.6" y="187.1">AB6</text>
<text x="247.6" y="189.7">AB7</text>
<text x="288.3" y="187.1">DB14</text>
<text x="288.3" y="189.7">DB15</text>
<text x="39.4" y="192.2">Jumper 1-2: ROM at &amp;18000-&amp;1FFFF</text>
<text x="39.4" y="194.7">Jumper 2-3: ROM at &amp;10000-&amp;1FFFF</text>
<text x="166.4" y="192.2">AB8</text>
<text x="166.4" y="194.7">AB9</text>
<text x="166.4" y="197.3">AB10</text>
<text x="247.6" y="192.2">AB8</text>
<text x="247.6" y="194.7">AB9</text>
<text x="247.6" y="197.3">AB10</text>
<text x="36.2" y="201.1">JP11</text>
<text x="62.2" y="202.4">RAMEN1</text>
<text x="166.4" y="199.8">AB11</text>
<text x="166.4" y="202.4">AB12</text>
<text x="247.6" y="199.8">AB11</text>
<text x="247.6" y="202.4">AB12</text>
<text x="62.2" y="204.9">RAMEN</text>
<text x="62.2" y="207.4">RAMEN0</text>
<text x="166.4" y="210">AEXT2</text>
<text x="166.4" y="207.4">AEXT1</text>
<text x="166.4" y="204.9">AEXT0</text>
<text x="247.6" y="210">AEXT2</text>
<text x="247.6" y="207.4">AEXT1</text>
<text x="247.6" y="204.9">AEXT0</text>
<text x="39.4" y="212.5">Jumper 1-2: RAM at &amp;08000-&amp;0FFFF</text>
<text x="39.4" y="215.1">Jumper 2-3: RAM at &amp;00000-&amp;0FFFF</text>
<text x="166.4" y="212.5">AEXT3</text>
<text x="166.4" y="215.1">AEXT4</text>
<text x="201.9" y="212.5" transform="rotate(-90 201.9 212.5)">VCC</text>
<text x="247.6" y="212.5">AEXT3</text>
<text x="247.6" y="215.1">AEXT4</text>
<text x="283.2" y="212.5" transform="rotate(-90 283.2 212.5)">VCC</text>
<text x="166.4" y="217.6">AEXT5</text>
<text x="206" y="217.2">C165</text>
<text x="247.6" y="217.6">AEXT5</text>
<text x="287.2" y="217.2">C167</text>
<text x="166.4" y="225.2">R</text>
<text x="166.4" y="227.8">W</text>
<text x="166.4" y="222.7">RAMEN</text>
<text x="206" y="222.3">1uF</text>
<text x="247.6" y="225.2">R</text>
<text x="247.6" y="227.8">W</text>
<text x="247.6" y="222.7">RAMEN</text>
<text x="287.2" y="222.3">1uF</text>
<text x="181.6" y="232.8">AS6C4008</text>
<text x="201.9" y="230.3">GND</text>
<text x="262.9" y="232.8">AS6C4008</text>
<text x="283.2" y="230.3">GND</text>
<text x="64.8" y="245.5" transform="rotate(-90 64.8 245.5)">VCC</text>
<text x="74.9" y="245.5" transform="rotate(-90 74.9 245.5)">VCC</text>
<text x="30" y="257.9">0.1uF</text>
<text x="30" y="252.8">C157</text>
<text x="37.6" y="257.9">0.1uF</text>
<text x="37.6" y="252.8">C158</text>
<text x="45.2" y="257.9">0.1uF</text>
<text x="45.2" y="252.8">C159</text>
<text x="52.8" y="257.9">0.1uF</text>
<text x="52.8" y="252.8">C160</text>
<text x="60.4" y="257.9">0.1uF</text>
<text x="60.4" y="252.8">C161</text>
<text x="68.1" y="257.9">0.1uF</text>
<text x="68.1" y="252.8">C162</text>
<text x="79" y="257.9">1uF</text>
<text x="79" y="252.8">C163</text>
<text x="113" y="255.7">To use RAM instead of ROM (making this a 1MW RAM card), install RAM chips in place of the ROM chips</text>
<text x="113" y="258.2">and install a shunt on pins 2-3 of the ROMUPG jumper (or bridge the pins) to allow writing.</text>
<text x="26.7" y="268.4">GND</text>
<text x="74.9" y="268.4">GND</text>
</g>
<g font-size="2.1">
<text x="178.9" y="100.4">11</text>
<text x="178.9" y="97.9">12</text>
<text x="183.9" y="101.5">A1</text>
<text x="183.9" y="99">A0</text>
<text x="191.8" y="99">D0</text>
<text x="191.8" y="101.5">D1</text>
<text x="197.2" y="97.9">13</text>
<text x="197.2" y="100.4">14</text>
<text x="260.1" y="100.4">11</text>
<text x="260.1" y="97.9">12</text>
<text x="265.2" y="101.5">A1</text>
<text x="265.2" y="99">A0</text>
<text x="273" y="99">D0</text>
<text x="273" y="101.5">D1</text>
<text x="278.5" y="97.9">13</text>
<text x="278.5" y="100.4">14</text>
<text x="178.9" y="103">10</text>
<text x="180" y="105.5">9</text>
<text x="183.9" y="106.6">A3</text>
<text x="183.9" y="104.1">A2</text>
<text x="191.8" y="104.1">D2</text>
<text x="191.8" y="106.6">D3</text>
<text x="197.2" y="103">15</text>
<text x="197.2" y="105.5">17</text>
<text x="260.1" y="103">10</text>
<text x="261.3" y="105.5">9</text>
<text x="265.2" y="106.6">A3</text>
<text x="265.2" y="104.1">A2</text>
<text x="273" y="104.1">D2</text>
<text x="273" y="106.6">D3</text>
<text x="278.5" y="103">15</text>
<text x="278.5" y="105.5">17</text>
<text x="86.6" y="113.1">1</text>
<text x="107.7" y="113.1">15</text>
<text x="180" y="113.1">6</text>
<text x="180" y="110.6">7</text>
<text x="180" y="108">8</text>
<text x="183.9" y="111.7">A5</text>
<text x="183.9" y="109.2">A4</text>
<text x="191.8" y="109.2">D4</text>
<text x="191.8" y="111.7">D5</text>
<text x="197.2" y="108">18</text>
<text x="197.2" y="110.6">19</text>
<text x="197.2" y="113.1">20</text>
<text x="261.3" y="113.1">6</text>
<text x="261.3" y="110.6">7</text>
<text x="261.3" y="108">8</text>
<text x="265.2" y="111.7">A5</text>
<text x="265.2" y="109.2">A4</text>
<text x="273" y="109.2">D4</text>
<text x="273" y="111.7">D5</text>
<text x="278.5" y="108">18</text>
<text x="278.5" y="110.6">19</text>
<text x="278.5" y="113.1">20</text>
<text x="320.3" y="108">2</text>
<text x="320.3" y="110.6">3</text>
<text x="320.3" y="113.1">4</text>
<text x="326.1" y="109.2">A1</text>
<text x="326.1" y="111.7">A2</text>
<text x="334.1" y="111.7">Y2</text>
<text x="334.1" y="109.2">Y1</text>
<text x="341.4" y="113.1">16</text>
<text x="341.4" y="110.6">17</text>
<text x="341.4" y="108">18</text>
<text x="86.6" y="115.7">2</text>
<text x="86.6" y="118.2">3</text>
<text x="92.5" y="114.2">A</text>
<text x="92.5" y="116.8">B</text>
<text x="92.5" y="119.3">C</text>
<text x="100.5" y="119.3">Y2</text>
<text x="100.5" y="116.8">Y1</text>
<text x="100.5" y="114.2">Y0</text>
<text x="107.7" y="118.2">13</text>
<text x="107.7" y="115.7">14</text>
<text x="178.9" y="118.2">27</text>
<text x="180" y="115.7">5</text>
<text x="183.9" y="116.8">A7</text>
<text x="183.9" y="114.2">A6</text>
<text x="183.9" y="119.3">A8</text>
<text x="191.8" y="114.2">D6</text>
<text x="191.8" y="116.8">D7</text>
<text x="197.2" y="115.7">21</text>
<text x="260.1" y="118.2">27</text>
<text x="261.3" y="115.7">5</text>
<text x="265.2" y="116.8">A7</text>
<text x="265.2" y="114.2">A6</text>
<text x="265.2" y="119.3">A8</text>
<text x="273" y="114.2">D6</text>
<text x="273" y="116.8">D7</text>
<text x="278.5" y="115.7">21</text>
<text x="320.3" y="115.7">5</text>
<text x="320.3" y="118.2">6</text>
<text x="326.1" y="114.2">A3</text>
<text x="326.1" y="116.8">A4</text>
<text x="326.1" y="119.3">A5</text>
<text x="334.1" y="119.3">Y5</text>
<text x="334.1" y="116.8">Y4</text>
<text x="334.1" y="114.2">Y3</text>
<text x="341.4" y="118.2">14</text>
<text x="341.4" y="115.7">15</text>
<text x="86.6" y="125.8">6</text>
<text x="100.5" y="124.4">Y4</text>
<text x="100.5" y="121.9">Y3</text>
<text x="107.7" y="125.8">10</text>
<text x="107.7" y="123.3">11</text>
<text x="107.7" y="120.7">12</text>
<text x="178.9" y="123.3">23</text>
<text x="178.9" y="125.8">25</text>
<text x="178.9" y="120.7">26</text>
<text x="183.9" y="124.4">A10</text>
<text x="183.9" y="121.9">A9</text>
<text x="260.1" y="123.3">23</text>
<text x="260.1" y="125.8">25</text>
<text x="260.1" y="120.7">26</text>
<text x="265.2" y="124.4">A10</text>
<text x="265.2" y="121.9">A9</text>
<text x="320.3" y="120.7">7</text>
<text x="320.3" y="123.3">8</text>
<text x="320.3" y="125.8">9</text>
<text x="326.1" y="121.9">A6</text>
<text x="326.1" y="124.4">A7</text>
<text x="334.1" y="124.4">Y7</text>
<text x="334.1" y="121.9">Y6</text>
<text x="341.4" y="125.8">11</text>
<text x="341.4" y="123.3">12</text>
<text x="341.4" y="120.7">13</text>
<text x="86.6" y="128.4">4</text>
<text x="86.6" y="130.9">5</text>
<text x="92.5" y="129.5">G2A</text>
<text x="92.5" y="126.9">G1</text>
<text x="100.5" y="129.5">Y6</text>
<text x="100.5" y="126.9">Y5</text>
<text x="107.7" y="130.9">7</text>
<text x="107.7" y="128.4">9</text>
<text x="178.9" y="130.9">28</text>
<text x="180" y="128.4">4</text>
<text x="183.9" y="129.5">A12</text>
<text x="183.9" y="126.9">A11</text>
<text x="260.1" y="130.9">28</text>
<text x="261.3" y="128.4">4</text>
<text x="265.2" y="129.5">A12</text>
<text x="265.2" y="126.9">A11</text>
<text x="320.3" y="130.9">1</text>
<text x="326.1" y="126.9">A8</text>
<text x="334.1" y="126.9">Y8</text>
<text x="92.5" y="132">G2B</text>
<text x="100.5" y="132">Y7</text>
<text x="178.9" y="133.4">29</text>
<text x="180" y="136">3</text>
<text x="183.9" y="132">A13</text>
<text x="183.9" y="134.6">A14</text>
<text x="183.9" y="137.1">A15</text>
<text x="260.1" y="133.4">29</text>
<text x="261.3" y="136">3</text>
<text x="265.2" y="132">A13</text>
<text x="265.2" y="134.6">A14</text>
<text x="265.2" y="137.1">A15</text>
<text x="319.1" y="133.4">19</text>
<text x="326.1" y="132">G1</text>
<text x="326.1" y="134.6">G2</text>
<text x="178.9" y="141.1">30</text>
<text x="180" y="138.5">2</text>
<text x="180" y="143.6">1</text>
<text x="183.9" y="139.6">A16</text>
<text x="183.9" y="142.2">A17</text>
<text x="260.1" y="141.1">30</text>
<text x="261.3" y="138.5">2</text>
<text x="261.3" y="143.6">1</text>
<text x="265.2" y="139.6">A16</text>
<text x="265.2" y="142.2">A17</text>
<text x="178.9" y="148.7">22</text>
<text x="183.9" y="149.8">CE</text>
<text x="183.9" y="144.7">A18</text>
<text x="260.1" y="148.7">22</text>
<text x="265.2" y="149.8">CE</text>
<text x="265.2" y="144.7">A18</text>
<text x="178.9" y="153.8">31</text>
<text x="178.9" y="151.2">24</text>
<text x="183.9" y="154.9">WE</text>
<text x="183.9" y="152.3">OE</text>
<text x="260.1" y="153.8">31</text>
<text x="260.1" y="151.2">24</text>
<text x="265.2" y="154.9">WE</text>
<text x="265.2" y="152.3">OE</text>
<text x="42.3" y="158.8">1</text>
<text x="42.3" y="161.4">2</text>
<text x="42.3" y="163.9">3</text>
<text x="178.9" y="171.5">12</text>
<text x="183.9" y="172.6">A0</text>
<text x="191.8" y="172.6">D0</text>
<text x="197.2" y="171.5">13</text>
<text x="260.1" y="171.5">12</text>
<text x="265.2" y="172.6">A0</text>
<text x="273" y="172.6">D0</text>
<text x="278.5" y="171.5">13</text>
<text x="178.9" y="176.6">10</text>
<text x="178.9" y="174.1">11</text>
<text x="180" y="179.1">9</text>
<text x="183.9" y="177.7">A2</text>
<text x="183.9" y="175.2">A1</text>
<text x="191.8" y="175.2">D1</text>
<text x="191.8" y="177.7">D2</text>
<text x="197.2" y="174.1">14</text>
<text x="197.2" y="176.6">15</text>
<text x="197.2" y="179.1">17</text>
<text x="260.1" y="176.6">10</text>
<text x="260.1" y="174.1">11</text>
<text x="261.3" y="179.1">9</text>
<text x="265.2" y="177.7">A2</text>
<text x="265.2" y="175.2">A1</text>
<text x="273" y="175.2">D1</text>
<text x="273" y="177.7">D2</text>
<text x="278.5" y="174.1">14</text>
<text x="278.5" y="176.6">15</text>
<text x="278.5" y="179.1">17</text>
<text x="42.3" y="181.7">1</text>
<text x="42.3" y="184.2">2</text>
<text x="180" y="184.2">7</text>
<text x="180" y="181.7">8</text>
<text x="183.9" y="185.3">A5</text>
<text x="183.9" y="182.8">A4</text>
<text x="183.9" y="180.3">A3</text>
<text x="191.8" y="180.3">D3</text>
<text x="191.8" y="182.8">D4</text>
<text x="191.8" y="185.3">D5</text>
<text x="197.2" y="181.7">18</text>
<text x="197.2" y="184.2">19</text>
<text x="261.3" y="184.2">7</text>
<text x="261.3" y="181.7">8</text>
<text x="265.2" y="185.3">A5</text>
<text x="265.2" y="182.8">A4</text>
<text x="265.2" y="180.3">A3</text>
<text x="273" y="180.3">D3</text>
<text x="273" y="182.8">D4</text>
<text x="273" y="185.3">D5</text>
<text x="278.5" y="181.7">18</text>
<text x="278.5" y="184.2">19</text>
<text x="42.3" y="186.8">3</text>
<text x="178.9" y="191.8">27</text>
<text x="180" y="189.3">5</text>
<text x="180" y="186.8">6</text>
<text x="183.9" y="190.4">A7</text>
<text x="183.9" y="187.9">A6</text>
<text x="191.8" y="187.9">D6</text>
<text x="191.8" y="190.4">D7</text>
<text x="197.2" y="186.8">20</text>
<text x="197.2" y="189.3">21</text>
<text x="260.1" y="191.8">27</text>
<text x="261.3" y="189.3">5</text>
<text x="261.3" y="186.8">6</text>
<text x="265.2" y="190.4">A7</text>
<text x="265.2" y="187.9">A6</text>
<text x="273" y="187.9">D6</text>
<text x="273" y="190.4">D7</text>
<text x="278.5" y="186.8">20</text>
<text x="278.5" y="189.3">21</text>
<text x="178.9" y="196.9">23</text>
<text x="178.9" y="194.4">26</text>
<text x="183.9" y="195.5">A9</text>
<text x="183.9" y="193">A8</text>
<text x="260.1" y="196.9">23</text>
<text x="260.1" y="194.4">26</text>
<text x="265.2" y="195.5">A9</text>
<text x="265.2" y="193">A8</text>
<text x="42.3" y="202">1</text>
<text x="178.9" y="199.5">25</text>
<text x="180" y="202">4</text>
<text x="183.9" y="203.1">A12</text>
<text x="183.9" y="198">A10</text>
<text x="183.9" y="200.6">A11</text>
<text x="260.1" y="199.5">25</text>
<text x="261.3" y="202">4</text>
<text x="265.2" y="203.1">A12</text>
<text x="265.2" y="198">A10</text>
<text x="265.2" y="200.6">A11</text>
<text x="42.3" y="204.5">2</text>
<text x="42.3" y="207.1">3</text>
<text x="178.9" y="204.5">28</text>
<text x="178.9" y="207.1">29</text>
<text x="180" y="209.6">3</text>
<text x="183.9" y="205.7">A13</text>
<text x="183.9" y="208.2">A14</text>
<text x="260.1" y="204.5">28</text>
<text x="260.1" y="207.1">29</text>
<text x="261.3" y="209.6">3</text>
<text x="265.2" y="205.7">A13</text>
<text x="265.2" y="208.2">A14</text>
<text x="178.9" y="214.7">30</text>
<text x="180" y="212.2">2</text>
<text x="183.9" y="210.7">A15</text>
<text x="183.9" y="213.3">A16</text>
<text x="183.9" y="215.8">A17</text>
<text x="260.1" y="214.7">30</text>
<text x="261.3" y="212.2">2</text>
<text x="265.2" y="210.7">A15</text>
<text x="265.2" y="213.3">A16</text>
<text x="265.2" y="215.8">A17</text>
<text x="180" y="217.2">1</text>
<text x="183.9" y="218.4">A18</text>
<text x="261.3" y="217.2">1</text>
<text x="265.2" y="218.4">A18</text>
<text x="178.9" y="227.4">31</text>
<text x="178.9" y="222.3">22</text>
<text x="178.9" y="224.9">24</text>
<text x="183.9" y="223.4">CE</text>
<text x="183.9" y="226">OE</text>
<text x="260.1" y="227.4">31</text>
<text x="260.1" y="222.3">22</text>
<text x="260.1" y="224.9">24</text>
<text x="265.2" y="223.4">CE</text>
<text x="265.2" y="226">OE</text>
<text x="183.9" y="228.5">WE</text>
<text x="265.2" y="228.5">WE</text>
</g>
</g></defs>
<g fill="#000" stroke="#000" stroke-width=".21">
<path d="M67.8 18.2v3.9zM115.3 18.2v3.9zM162.7 18.2v3.9zM210.2 18.2v3.9zM257.6 18.2v3.9zM305.1 18.2v3.9zM352.5 18.2v3.9zM20.3 22.1v252.6zM20.3 22.1h379.7zM16.5 72.6h3.8zM31 74.3h5.9zM35.1 79.3h1.8z"/>
<path d="M41.9 75.4h20.3zM62.2 75.4v53.3zM62.2 75.4h317.5zM381.2 79.3h1.8zM381.2 74.3h5.9zM400 72.6h3.8zM34.5 84.4h2.4zM41.9 80.5h106.7zM41.9 85.5h10.2zM52.1 85.5v78.8zM52.1 85.5h91.4zM148.6 80.5h81.2z"/>
<path d="M158.7 95.7l2.6 2.5zM158.7 98.2l2.6 2.6zM161.3 98.2h17.7zM179 98.2h2.6zM196.8 98.2h2.6zM199.4 98.2h17.7zM219.7 95.7l-2.6 2.5zM219.7 98.2l-2.6 2.6zM143.5 85.5h81.3zM224.8 85.5v142.2zM229.8 80.5h76.2zM240 95.7l2.5 2.5z"/>
<path d="M240 98.2l2.5 2.6zM242.5 98.2h17.8zM260.3 98.2h2.6zM278.1 98.2h2.5zM280.6 98.2h17.8zM301 95.7l-2.6 2.5zM301 98.2l-2.6 2.6zM303.5 93.2h1zM303.5 97.2v1zM303.5 95.2v1zM303.5 93.2v1zM305.5 93.2h1.1z"/>
<path d="M306 80.5h73.7zM307.6 93.2h1zM309.6 93.2h1zM224.8 85.5h86.3zM311.6 93.2h1zM313.6 93.2h1.1zM315.7 93.2h1zM317.7 93.2h1zM319.7 93.2h1.1zM321.8 93.2h1zM323.8 93.2h1zM325.8 93.2h1.1z"/>
<path d="M327.9 93.2h1zM329.9 93.2h1zM331.9 93.2h1.1zM334 93.2h1zM336 93.2h1zM338 93.2h1.1zM340.1 93.2h1zM342.1 93.2h1zM344.1 93.2h1.1zM346.2 93.2h1zM348.2 93.2h1zM350.2 93.2h1.1z"/>
<path d="M352.2 93.2h1.1zM354.3 93.2h1zM356.3 93.2h1.1zM358.3 93.2h1.1zM360.4 93.2h1zM362.4 93.2h1zM364.4 93.2h1.1zM366.5 93.2h1zM368.5 93.2h1zM370.5 93.2h1.1zM372.6 93.2h1zM374.6 93.2h1z"/>
<path d="M376.6 93.2h1zM378.7 93.2h1zM311.1 85.5h68.6zM380.7 93.2h1zM381.2 84.4h2.4zM382.7 93.2h1zM384.7 93.2h1.1zM386.8 93.2h1zM388.8 93.2h1zM389.8 93.2v1zM389.8 95.2v1zM389.8 97.2v1z"/>
<path d="M389.8 99.2v1zM57.1 110.9l2.6 2.6zM57.1 113.5l2.6 2.5zM80 118.6v12.7zM85.1 113.5h5.1zM85.1 116h5.1zM85.1 118.6h5.1zM80 118.6h5.1zM59.7 113.5h25.4zM59.7 116h25.4zM107.4 118.6h3.1zM107.4 116h3.1z"/>
<path d="M107.4 113.5h3.1zM110.5 118.6h15.2zM113 114h10.5zM113 119.1h10.7zM113 111.5h10.5zM113 116.5h10.7zM125.7 118.6v68.5zM110.5 116h17.7zM110.5 113.5h20.3zM158.7 100.8l2.6 2.5zM158.7 103.3l2.6 2.6zM158.7 105.9l2.6 2.5z"/>
<path d="M158.7 108.4l2.6 2.5zM158.7 110.9l2.6 2.6zM158.7 113.5l2.6 2.5zM158.7 116l2.6 2.6zM158.7 118.6l2.6 2.5zM161.3 100.8h17.7zM161.3 103.3h17.7zM161.3 105.9h17.7zM161.3 108.4h17.7zM161.3 110.9h17.7zM161.3 113.5h17.7zM161.3 116h17.7z"/>
<path d="M161.3 118.6h17.7zM179 116h2.6zM179 113.5h2.6zM179 110.9h2.6zM179 108.4h2.6zM179 105.9h2.6zM179 103.3h2.6zM179 100.8h2.6zM179 118.6h2.6zM196.8 100.8h2.6zM196.8 103.3h2.6zM196.8 105.9h2.6z"/>
<path d="M196.8 108.4h2.6zM196.8 110.9h2.6zM196.8 113.5h2.6zM196.8 116h2.6zM199.4 100.8h17.7zM199.4 103.3h17.7zM199.4 105.9h17.7zM199.4 108.4h17.7zM199.4 110.9h17.7zM199.4 113.5h17.7zM199.4 116h17.7zM219.7 100.8l-2.6 2.5z"/>
<path d="M219.7 103.3l-2.6 2.6zM219.7 105.9l-2.6 2.5zM219.7 108.4l-2.6 2.5zM219.7 110.9l-2.6 2.6zM219.7 113.5l-2.6 2.5zM240 100.8l2.5 2.5zM240 103.3l2.5 2.6zM240 105.9l2.5 2.5zM240 108.4l2.5 2.5zM240 110.9l2.5 2.6zM240 113.5l2.5 2.5zM240 116l2.5 2.6z"/>
<path d="M240 118.6l2.5 2.5zM242.5 100.8h17.8zM242.5 103.3h17.8zM242.5 105.9h17.8zM242.5 108.4h17.8zM242.5 110.9h17.8zM242.5 113.5h17.8zM242.5 116h17.8zM242.5 118.6h17.8zM260.3 116h2.6zM260.3 113.5h2.6zM260.3 110.9h2.6z"/>
<path d="M260.3 108.4h2.6zM260.3 105.9h2.6zM260.3 103.3h2.6zM260.3 100.8h2.6zM260.3 118.6h2.6zM278.1 100.8h2.5zM278.1 103.3h2.5zM278.1 105.9h2.5zM278.1 108.4h2.5zM278.1 110.9h2.5zM278.1 113.5h2.5zM278.1 116h2.5z"/>
<path d="M280.6 100.8h17.8zM280.6 103.3h17.8zM280.6 105.9h17.8zM280.6 108.4h17.8zM280.6 110.9h17.8zM280.6 113.5h17.8zM280.6 116h17.8zM301 100.8l-2.6 2.5zM301 103.3l-2.6 2.6zM301 105.9l-2.6 2.5zM301 108.4l-2.6 2.5zM301 110.9l-2.6 2.6z"/>
<path d="M301 113.5l-2.6 2.5zM303.5 117.4v1zM303.5 115.4v1zM303.5 113.3v1.1zM303.5 111.3v1zM303.5 109.3v1zM303.5 107.3v1zM303.5 105.3v1zM303.5 103.2v1.1zM303.5 101.2v1.1zM303.5 99.2v1zM306 80.5v33z"/>
<path d="M306 118.6h12.7zM311.1 85.5v22.9zM316.2 110.9v5.1zM316.2 116v5.1zM318.7 108.4h5.1zM318.7 110.9h5.1zM318.7 113.5h5.1zM318.7 116h5.1zM318.7 118.6h5.1zM316.2 110.9h2.5zM316.2 116h2.5zM306 113.5h12.7z"/>
<path d="M311.1 108.4h7.6zM341 118.6h3.1zM341 116h3.1zM341 113.5h3.1zM341 110.9h3.1zM341 108.4h3.1zM344.1 113.5h10.2zM344.1 118.6h7.6zM351.7 118.6v17.7zM354.3 113.5v7.6zM356.8 108.4h2.6zM344.1 108.4h12.7z"/>
<path d="M364.4 108.4h2.6zM374.6 108.4h2.5zM367 108.4h7.6zM377.1 108.4h2.6zM377.9 110.4l1.4 1.4zM378.4 111.4l.5-.5zM378.4 111.4h.7zM378.6 111.3h.5zM378.6 111.5h.6zM378.7 111.2h.3zM378.8 111.1h.2zM378.9 110.9l.4 .9z"/>
<path d="M378.9 111.7h.3zM379 110.3l1.4 1.4zM378.4 111.4l.9 .4zM379.6 111.3l.5-.5zM379.6 111.3h.7zM379.7 111.2h.5zM379.8 111.4h.5zM379.8 111.1h.4zM379.9 110.9h.2zM380.1 110.8l.3 .9zM380.1 111.5h.3zM379.6 111.3l.8 .4z"/>
<path d="M379.7 108.4h2.5zM382.2 108.4h2.6zM384.8 108.4v12.7zM389.8 101.2v1.1zM389.8 103.2v1.1zM389.8 105.3v1zM389.8 107.3v1zM389.8 109.3v1zM389.8 111.3v1zM389.8 113.3v1.1zM389.8 115.4v1zM389.8 117.4v1z"/>
<path d="M389.8 119.4v1zM16.5 123.1h3.8zM62.2 128.7h22.9zM64.8 126.7h5.8zM77.5 121.1v2.5zM77.5 123.6v2.6zM80 133.8v2.5zM80 131.3v2.5zM85.1 128.7h3.1zM85.1 131.3h3.1zM85.1 126.2h5.1zM80 131.3h5.1z"/>
<path d="M77.5 126.2h7.6zM107.4 131.3h3.1zM107.4 128.7h3.1zM107.4 126.2h3.1zM107.4 123.6h3.1zM107.4 121.1h3.1zM110.5 121.1h12.7zM123.2 121.1v61zM153.6 136.3l2.6 2.6zM153.6 133.8l2.6 2.5zM153.6 131.3l2.6 2.5zM153.6 128.7l2.6 2.6z"/>
<path d="M158.7 121.1l2.6 2.5zM158.7 123.6l2.6 2.6zM161.3 121.1h17.7zM161.3 123.6h17.7zM161.3 126.2h17.7zM158.7 126.2l2.6 2.5zM179 128.7h2.6zM179 123.6h2.6zM179 126.2h2.6zM179 121.1h2.6zM179 131.3h2.6zM179 133.8h2.6z"/>
<path d="M179 136.3h2.6zM179 138.9h2.6zM156.2 138.9h22.8zM156.2 136.3h22.8zM156.2 133.8h22.8zM156.2 131.3h22.8zM161.3 128.7h17.7zM204.4 136.3v2.6zM234.9 136.3l2.6 2.6zM234.9 133.8l2.6 2.5zM234.9 131.3l2.6 2.5zM234.9 128.7l2.6 2.6z"/>
<path d="M240 121.1l2.5 2.5zM240 123.6l2.5 2.6zM242.5 121.1h17.8zM242.5 123.6h17.8zM242.5 126.2h17.8zM240 126.2l2.5 2.5zM260.3 128.7h2.6zM260.3 123.6h2.6zM260.3 126.2h2.6zM260.3 121.1h2.6zM260.3 131.3h2.6zM260.3 133.8h2.6z"/>
<path d="M260.3 136.3h2.6zM260.3 138.9h2.6zM237.5 138.9h22.8zM237.5 136.3h22.8zM237.5 133.8h22.8zM237.5 131.3h22.8zM242.5 128.7h17.8zM285.7 136.3v2.6zM303.5 137.5v1.1zM303.5 135.5v1zM303.5 133.5v1zM303.5 131.5v1z"/>
<path d="M303.5 129.5v1zM303.5 127.5v1zM303.5 125.4v1zM303.5 123.4v1zM303.5 121.4v1zM303.5 119.4v1zM311.1 123.6v111.8zM316.2 136.3v2.6zM316.2 131.3v2.5zM316.2 133.8v2.5zM316.2 121.1v5.1zM316.2 126.2v5.1z"/>
<path d="M318.7 131.3h3.1zM318.7 121.1h5.1zM318.7 123.6h5.1zM318.7 126.2h5.1zM318.7 133.8h3.1zM316.2 131.3h2.5zM316.2 133.8h2.5zM316.2 121.1h2.5zM316.2 126.2h2.5zM311.1 123.6h7.6zM341 126.2h3.1zM341 123.6h3.1z"/>
<path d="M341 121.1h3.1zM344.1 123.6h5.1zM349.2 123.6v25.4zM351.7 136.3h5.1zM354.3 121.1h2.5zM356.8 121.1h2.6zM356.8 136.3h2.6zM364.4 121.1h2.6zM364.4 136.3h2.6zM367 136.3h7.6zM374.6 121.1h2.5zM374.6 136.3h2.5z"/>
<path d="M367 121.1h7.6zM377.1 121.1h2.6zM377.1 136.3h2.6zM377.9 123.1l1.4 1.4zM377.9 138.4l1.4 1.4zM378.4 124.1l.5-.5zM378.4 139.4l.5-.5zM378.5 139.4h.7zM378.5 124.1h.6zM378.5 139.3h.6zM378.6 124.2h.6zM378.6 124h.5z"/>
<path d="M378.6 139.1h.4zM378.7 123.8h.3zM378.8 139.5h.4zM378.8 139h.2zM378.8 123.7h.2zM378.9 124.3h.3zM378.9 123.6l.4 .9zM378.9 138.9l.4 .9zM379 139.6h.3zM379 123l1.4 1.4zM379 138.2l1.4 1.4zM379.1 124.4h.2z"/>
<path d="M378.4 124.1l.9 .4zM378.4 139.4l.9 .4zM379.6 124l.5-.5zM379.6 139.3l.5-.6zM379.6 124h.7zM379.6 139.3h.7zM379.7 139.1h.6zM379.7 124.1h.6zM379.7 123.8h.5zM379.8 139h.4zM379.9 123.7h.3zM379.9 139.4h.4z"/>
<path d="M379.9 138.9h.2zM380 123.6h.1zM380 124.2h.4zM380.1 123.5l.3 .9zM380.1 138.7l.3 .9zM380.2 139.5h.2zM380.3 124.3h.1zM379.6 124l.8 .4zM379.6 139.3l.8 .3zM379.7 121.1h2.5zM379.7 136.3h2.5zM382.2 121.1h2.6z"/>
<path d="M382.2 136.3h2.6zM384.8 121.1v15.2zM384.8 136.3v12.7zM389.8 121.4v1zM389.8 123.4v1zM389.8 125.4v1zM389.8 127.5v1zM389.8 129.5v1zM389.8 131.5v1zM389.8 133.5v1zM389.8 135.5v1zM389.8 137.5v1.1z"/>
<path d="M389.8 139.6v1zM400 123.1h3.8zM40.6 159.2h1.3zM41.9 159.2h2.5zM44.4 159.2h5.1zM49.5 154.1v2.6zM49.5 156.7v2.5zM62.2 159.7h11.3zM148.6 80.5v71.1zM148.6 151.6v73.6zM153.6 138.9l2.6 2.5zM153.6 141.4l2.6 2.6z"/>
<path d="M161.3 149v15.3zM163.8 154.1v7.6zM166.3 149.6h1.8zM166.3 147h9.3zM166.3 152.1h11.3zM179 154.1h2.6zM179 149h2.6zM179 151.6h2.6zM179 141.4h2.6zM179 144h2.6zM148.6 151.6h30.4zM161.3 149h17.7z"/>
<path d="M156.2 141.4h22.8zM156.2 144h22.8zM163.8 154.1h15.2zM183.9 153.2h3.5zM183.9 148.1h3zM183.9 150.6h3.1zM204.4 151.6v2.5zM204.4 141.4v2.6zM204.4 146.5v2.5zM204.4 144v.5zM204.4 146v.5zM204.4 149v2.6z"/>
<path d="M204.4 138.9v2.5zM229.8 80.5v71.1zM229.8 151.6v73.6zM234.9 138.9l2.6 2.5zM234.9 141.4l2.6 2.6zM242.5 149h17.8zM245.1 154.1v7.6zM247.6 149.6h1.8zM247.6 147h9.3zM247.6 152.1h11.3zM260.3 154.1h2.6zM260.3 149h2.6z"/>
<path d="M260.3 151.6h2.6zM260.3 141.4h2.6zM260.3 144h2.6zM229.8 151.6h30.5zM237.5 141.4h22.8zM237.5 144h22.8zM245.1 154.1h15.2zM265.2 153.2h3.4zM265.2 148.1h3zM265.2 150.6h3.1zM285.7 151.6v2.5zM285.7 141.4v2.6z"/>
<path d="M285.7 146.5v2.5zM285.7 144v.5zM285.7 146v.5zM285.7 149v2.6zM285.7 138.9v2.5zM303.5 157.7v1zM303.5 155.7v1zM303.5 153.7v1zM303.5 151.7v1zM303.5 149.6v1.1zM303.5 147.6v1.1zM303.5 145.6v1z"/>
<path d="M303.5 143.6v1zM303.5 141.6v1zM303.5 139.6v1zM349.2 149h7.6zM356.8 149h2.6zM364.4 149h2.6zM367 149h7.6zM374.6 149h2.5zM377.1 149h2.6zM377.9 151.1l1.4 1.4zM378.4 152.1l.5-.5zM378.4 152.1h.7z"/>
<path d="M378.6 151.9h.5zM378.7 152.2h.5zM378.7 151.8h.3zM378.8 151.7h.2zM378.9 151.6l.4 .9zM378.9 152.3h.3zM379 150.9l1.4 1.4zM378.4 152.1l.9 .4zM379.6 152l.5-.6zM379.6 151.9h.7zM379.7 151.8h.5zM379.8 152.1h.5z"/>
<path d="M379.8 151.7h.4zM379.9 151.6h.2zM380.1 151.4l.3 .9zM380.1 152.2h.3zM379.6 152l.8 .3zM379.7 149h2.5zM382.2 149h2.6zM384.8 154.1v2.6zM384.8 149v5.1zM389.8 141.6v1zM389.8 143.6v1zM389.8 145.6v1z"/>
<path d="M389.8 147.6v1.1zM389.8 149.6v1.1zM389.8 151.7v1zM389.8 153.7v1zM389.8 155.7v1zM389.8 157.7v1zM389.8 159.7v1.1zM16.5 173.7h3.8zM40.6 164.3h1.3zM40.6 161.7h1.3zM41.9 161.7h2.5zM41.9 164.3h2.5z"/>
<path d="M44.4 164.3h7.7zM158.7 169.4l2.6 2.5zM158.7 171.9l2.6 2.5zM158.7 174.4l2.6 2.6zM158.7 177l2.6 2.5zM158.7 179.5l2.6 2.6zM161.3 171.9h17.7zM161.3 174.4h17.7zM161.3 177h17.7zM161.3 179.5h17.7zM138.4 164.3h22.9zM44.4 161.7h119.4z"/>
<path d="M179 179.5h2.6zM179 177h2.6zM179 174.4h2.6zM179 171.9h2.6zM196.8 171.9h2.6zM196.8 174.4h2.6zM196.8 177h2.6zM196.8 179.5h2.6zM199.4 171.9h17.7zM199.4 174.4h17.7zM199.4 177h17.7zM199.4 179.5h17.7z"/>
<path d="M219.7 169.4l-2.6 2.5zM219.7 171.9l-2.6 2.5zM219.7 174.4l-2.6 2.6zM219.7 177l-2.6 2.5zM219.7 179.5l-2.6 2.6zM240 169.4l2.5 2.5zM240 171.9l2.5 2.5zM240 174.4l2.5 2.6zM240 177l2.5 2.5zM240 179.5l2.5 2.6zM242.5 171.9h17.8zM242.5 174.4h17.8z"/>
<path d="M242.5 177h17.8zM242.5 179.5h17.8zM161.3 164.3h81.2zM242.5 149v15.3zM242.5 164.3h63.5zM163.8 161.7h81.3zM260.3 179.5h2.6zM260.3 177h2.6zM260.3 174.4h2.6zM260.3 171.9h2.6zM278.1 171.9h2.5zM278.1 174.4h2.5z"/>
<path d="M278.1 177h2.5zM278.1 179.5h2.5zM280.6 171.9h17.8zM280.6 174.4h17.8zM280.6 177h17.8zM280.6 179.5h17.8zM301 169.4l-2.6 2.5zM301 171.9l-2.6 2.5zM301 174.4l-2.6 2.6zM301 177l-2.6 2.5zM301 179.5l-2.6 2.6zM303.5 165.8v1z"/>
<path d="M303.5 163.8v1zM303.5 161.8v1zM303.5 159.7v1.1zM303.5 166.8h1zM306 118.6v45.7zM305.5 166.8h1.1zM307.6 166.8h1zM309.6 166.8h1zM311.6 166.8h1zM313.7 166.8h1zM315.7 166.8h1zM317.7 166.8h1z"/>
<path d="M319.7 166.8h1.1zM321.8 166.8h1zM323.8 166.8h1zM325.8 166.8h1.1zM327.9 166.8h1zM329.9 166.8h1zM331.9 166.8h1.1zM334 166.8h1zM336 166.8h1zM338 166.8h1.1zM340.1 166.8h1zM342.1 166.8h1z"/>
<path d="M344.1 166.8h1.1zM346.2 166.8h1zM348.2 166.8h1zM350.2 166.8h1.1zM352.2 166.8h1.1zM354.3 166.8h1zM356.3 166.8h1.1zM358.3 166.8h1.1zM360.4 166.8h1zM362.4 166.8h1zM364.4 166.8h1.1zM366.5 166.8h1z"/>
<path d="M368.5 166.8h1zM370.5 166.8h1.1zM372.6 166.8h1zM374.6 166.8h1zM376.6 166.8h1zM378.7 166.8h1zM380.7 166.8h1zM382.7 166.8h1zM384.8 166.8h1zM386.8 166.8h1zM389.8 161.8v1zM389.8 163.8v1z"/>
<path d="M389.8 165.8v1zM388.8 166.8h1zM400 173.7h3.8zM40.6 187.1h1.3zM40.6 184.6h1.3zM40.6 182.1h1.3zM41.9 182.1h2.5zM41.9 184.6h2.5zM41.9 187.1h2.5zM44.4 184.6h94zM62.2 182.6h9.3zM62.2 180h10.7z"/>
<path d="M62.2 185.1h10.7zM44.4 182.1h78.8zM44.4 187.1h81.3zM138.4 164.3v20.3zM158.7 182.1l2.6 2.5zM158.7 184.6l2.6 2.5zM158.7 187.1l2.6 2.6zM158.7 189.7l2.6 2.5zM158.7 192.2l2.6 2.6zM158.7 194.8l2.6 2.5zM158.7 197.3l2.6 2.5zM161.3 182.1h17.7z"/>
<path d="M161.3 184.6h17.7zM161.3 187.1h17.7zM161.3 189.7h17.7zM161.3 192.2h17.7zM161.3 194.8h17.7zM161.3 197.3h17.7zM161.3 199.8h17.7zM179 189.7h2.6zM179 187.1h2.6zM179 184.6h2.6zM179 182.1h2.6zM179 197.3h2.6z"/>
<path d="M179 199.8h2.6zM179 194.8h2.6zM179 192.2h2.6zM196.8 182.1h2.6zM196.8 184.6h2.6zM196.8 187.1h2.6zM196.8 189.7h2.6zM199.4 182.1h17.7zM199.4 184.6h17.7zM199.4 187.1h17.7zM199.4 189.7h17.7zM219.7 182.1l-2.6 2.5z"/>
<path d="M219.7 184.6l-2.6 2.5zM219.7 187.1l-2.6 2.6zM240 182.1l2.5 2.5zM240 184.6l2.5 2.5zM240 187.1l2.5 2.6zM240 189.7l2.5 2.5zM240 192.2l2.5 2.6zM240 194.8l2.5 2.5zM240 197.3l2.5 2.5zM242.5 182.1h17.8zM242.5 184.6h17.8zM242.5 187.1h17.8z"/>
<path d="M242.5 189.7h17.8zM242.5 192.2h17.8zM242.5 194.8h17.8zM242.5 197.3h17.8zM242.5 199.8h17.8zM260.3 189.7h2.6zM260.3 187.1h2.6zM260.3 184.6h2.6zM260.3 182.1h2.6zM260.3 197.3h2.6zM260.3 199.8h2.6zM260.3 194.8h2.6z"/>
<path d="M260.3 192.2h2.6zM278.1 182.1h2.5zM278.1 184.6h2.5zM278.1 187.1h2.5zM278.1 189.7h2.5zM280.6 182.1h17.8zM280.6 184.6h17.8zM280.6 187.1h17.8zM280.6 189.7h17.8zM301 182.1l-2.6 2.5zM301 184.6l-2.6 2.5zM301 187.1l-2.6 2.6z"/>
<path d="M40.6 207.4h1.3zM40.6 204.9h1.3zM40.6 202.4h1.3zM41.9 202.4h2.5zM41.9 204.9h2.5zM41.9 207.4h2.5zM44.4 204.9h94zM44.4 202.4h83.8zM44.4 207.4h86.4zM62.2 202.9h9.1zM62.2 200.4h10.5zM62.2 205.4h10.5z"/>
<path d="M128.2 116v86.4zM130.8 113.5v93.9zM138.4 204.9v30.5zM153.6 210l2.6 2.5zM153.6 212.5l2.6 2.5zM153.6 215l2.6 2.6zM153.6 207.4l2.6 2.6zM153.6 204.9l2.6 2.5zM153.6 202.4l2.6 2.5zM158.7 199.8l2.6 2.6zM179 202.4h2.6zM179 204.9h2.6z"/>
<path d="M179 207.4h2.6zM179 210h2.6zM179 212.5h2.6zM179 215h2.6zM179 217.6h2.6zM156.2 212.5h22.8zM156.2 215h22.8zM156.2 217.6h22.8zM156.2 210h22.8zM156.2 207.4h22.8zM156.2 204.9h22.8zM161.3 202.4h17.7z"/>
<path d="M204.4 210v2.5zM204.4 215v2.6zM204.4 217.6v.5zM204.4 212.5v2.5zM234.9 210l2.6 2.5zM234.9 212.5l2.6 2.5zM234.9 215l2.6 2.6zM234.9 207.4l2.6 2.6zM234.9 204.9l2.6 2.5zM234.9 202.4l2.6 2.5zM240 199.8l2.5 2.6zM260.3 202.4h2.6z"/>
<path d="M260.3 204.9h2.6zM260.3 207.4h2.6zM260.3 210h2.6zM260.3 212.5h2.6zM260.3 215h2.6zM260.3 217.6h2.6zM237.5 212.5h22.8zM237.5 215h22.8zM237.5 217.6h22.8zM237.5 210h22.8zM237.5 207.4h22.8zM237.5 204.9h22.8z"/>
<path d="M242.5 202.4h17.8zM285.7 210v2.5zM285.7 215v2.6zM285.7 217.6v.5zM285.7 212.5v2.5zM16.5 224.2h3.8zM143.5 85.5v142.2zM148.6 225.2h30.4zM156.2 222.7v12.7zM138.4 235.4h17.8zM166.3 223.2h1.8zM166.3 225.7h2.4z"/>
<path d="M166.3 220.7h9.1zM179 227.7h2.6zM179 222.7h2.6zM179 225.2h2.6zM143.5 227.7h35.5zM156.2 222.7h22.8zM183.9 226.8h3.5zM183.9 221.7h3zM183.9 224.3h3.1zM204.4 225.2v2.5zM204.4 220.1v2.6zM204.4 219.6v.5z"/>
<path d="M204.4 222.7v2.5zM224.8 227.7h35.5zM229.8 225.2h30.5zM237.5 222.7v12.7zM156.2 235.4h81.3zM237.5 235.4h73.6zM247.6 223.2h1.8zM247.6 225.7h2.4zM247.6 220.7h9.1zM260.3 227.7h2.6zM260.3 222.7h2.6zM260.3 225.2h2.6z"/>
<path d="M237.5 222.7h22.8zM265.2 226.8h3.4zM265.2 221.7h3zM265.2 224.3h3.1zM285.7 225.2v2.5zM285.7 220.1v2.6zM285.7 219.6v.5zM285.7 222.7v2.5zM400 224.2h3.8zM29.2 255.7v2.5zM29.2 250.6v2.5zM29.2 255.2v.5z"/>
<path d="M29.2 253.1v.6zM29.2 258.2v2.6zM29.2 248.1v2.5zM36.8 255.7v2.5zM36.8 250.6v2.5zM36.8 255.2v.5zM36.8 253.1v.6zM36.8 248.1v2.5zM29.2 248.1h7.6zM44.4 255.7v2.5zM44.4 250.6v2.5zM44.4 255.2v.5z"/>
<path d="M44.4 253.1v.6zM36.8 248.1h7.6zM44.4 248.1v2.5zM52.1 255.7v2.5zM52.1 250.6v2.5zM52.1 255.2v.5zM52.1 253.1v.6zM44.4 248.1h7.7zM52.1 248.1v2.5zM59.7 255.7v2.5zM59.7 250.6v2.5zM59.7 255.2v.5z"/>
<path d="M59.7 253.1v.6zM59.7 258.2v2.6zM52.1 248.1h7.6zM59.7 248.1v2.5zM67.3 243v2.5zM67.3 255.7v2.5zM67.3 250.6v2.5zM67.3 255.2v.5zM67.3 253.1v.6zM59.7 248.1h7.6zM67.3 245.5v2.6zM67.3 248.1v2.5z"/>
<path d="M77.5 243v2.5zM77.5 250.6v2.5zM77.5 255.7v2.5zM77.5 253.1v.6zM77.5 255.2v.5zM77.5 245.5v5.1zM153.8 256.2h11.2zM20.3 274.7h379.7zM29.2 263.3v2.5zM29.2 260.8h7.6zM29.2 260.8v2.5zM36.8 258.2v2.6z"/>
<path d="M36.8 260.8h7.6zM44.4 258.2v2.6zM44.4 260.8h7.7zM52.1 258.2v2.6zM52.1 260.8h7.6zM59.7 260.8h7.6zM67.3 258.2v2.6zM67.8 274.7v3.8zM77.5 263.3v2.5zM77.5 258.2v5.1zM115.3 274.7v3.8zM162.7 274.7v3.8z"/>
<path d="M210.2 274.7v3.8zM257.6 274.7v3.8zM305.1 274.7v3.8zM352.5 274.7v3.8zM400 264.5v.1zM400 268.4v6.2zM400 274.6h.1zM400 22.1v252.6z"/>
<circle cx="62.2" cy="75.4" r=".51"/>
<circle cx="52.1" cy="85.5" r=".51"/>
<circle cx="143.5" cy="85.5" r=".51"/>
<circle cx="148.6" cy="80.5" r=".51"/>
<circle cx="224.8" cy="85.5" r=".51"/>
<circle cx="229.8" cy="80.5" r=".51"/>
<circle cx="306" cy="80.5" r=".51"/>
<circle cx="311.1" cy="85.5" r=".51"/>
<circle cx="316.2" cy="116" r=".51"/>
<circle cx="80" cy="131.3" r=".51"/>
<circle cx="316.2" cy="133.8" r=".51"/>
<circle cx="316.2" cy="126.2" r=".51"/>
<circle cx="316.2" cy="131.3" r=".51"/>
<circle cx="316.2" cy="121.1" r=".51"/>
<circle cx="384.8" cy="136.3" r=".51"/>
<circle cx="384.8" cy="121.1" r=".51"/>
<circle cx="148.6" cy="151.6" r=".51"/>
<circle cx="229.8" cy="151.6" r=".51"/>
<circle cx="384.8" cy="149" r=".51"/>
<circle cx="161.3" cy="164.3" r=".51"/>
<circle cx="163.8" cy="161.7" r=".51"/>
<circle cx="242.5" cy="164.3" r=".51"/>
<circle cx="156.2" cy="235.4" r=".51"/>
<circle cx="237.5" cy="235.4" r=".51"/>
<circle cx="36.8" cy="248.1" r=".51"/>
<circle cx="44.4" cy="248.1" r=".51"/>
<circle cx="52.1" cy="248.1" r=".51"/>
<circle cx="59.7" cy="248.1" r=".51"/>
<circle cx="67.3" cy="248.1" r=".51"/>
<circle cx="29.2" cy="260.8" r=".51"/>
<circle cx="36.8" cy="260.8" r=".51"/>
<circle cx="44.4" cy="260.8" r=".51"/>
<circle cx="52.1" cy="260.8" r=".51"/>
<circle cx="59.7" cy="260.8" r=".51"/>
</g>
<g fill="#000" stroke="#000" stroke-width=".28">
<path d="M28.7 73.8v3.1zM32.9 78.9v3.1zM32.9 78.9h7.5zM28.7 73.8h11.7zM28.7 76.9h11.7zM40.4 73.8l1.5 1.6zM41.9 75.4l-1.5 1.5zM379.7 75.4l1.5 1.5zM379.7 75.4l1.5-1.6zM381.2 78.9h7.6zM381.2 76.9h11.6zM381.2 73.8h11.6z"/>
<path d="M392.8 73.8v3.1zM32.3 84v3.1zM32.9 82h7.5zM32.3 84h8.1zM32.3 87.1h8.1zM40.4 78.9l1.5 1.6zM41.9 80.5l-1.5 1.5zM40.4 84l1.5 1.5zM40.4 87.1l1.5-1.6zM379.7 80.5l1.5 1.5zM379.7 80.5l1.5-1.6zM379.7 85.5l1.5 1.6z"/>
<path d="M379.7 85.5l1.5-1.5zM381.2 82h7.6zM381.2 87.1h8.1zM381.2 84h8.1zM388.8 78.9v3.1zM389.3 84v3.1zM359.4 109.3h5zM359.4 107.5v1.8zM359.4 107.5h5zM364.4 107.5v1.8zM377.1 119.8l2.6 1.3zM377.1 119.9h.3z"/>
<path d="M377.1 107.1v2.6zM377.1 107.1l2.6 1.3zM377.1 109.5h.4zM377.1 109.3h.9zM377.1 109h1.3zM377.1 108.8h1.8zM377.1 108.6h2.2zM377.1 108.4h2.5zM377.1 108.1h2.1zM377.1 107.9h1.7zM377.1 107.7h1.2zM377.1 107.5h.8z"/>
<path d="M377.1 107.3h.3zM379.7 119.8h.2zM379.7 119.9h.2zM379.7 108.4v1.3zM377.1 109.7l2.6-1.3zM379.7 107.1v2.6zM379.7 107.1h.2zM379.7 109.5h.2zM379.7 109.3h.2zM379.7 109h.2zM379.7 108.8h.2zM379.7 108.6h.2z"/>
<path d="M379.7 108.4h.2zM379.7 108.1h.2zM379.7 107.9h.2zM379.7 107.7h.2zM379.7 107.5h.2zM379.7 107.3h.2zM379.9 119.8v2.6zM379.9 107.1v2.6zM379.7 109.7h.2zM77.5 121.1l-1.3 1.9zM78.1 136.3h3.8zM77.5 121.1l1.2 1.9z"/>
<path d="M204.4 136.3l-1.2 1.9zM204.4 136.3l1.3 1.9zM285.7 136.3l-1.2 1.9zM285.7 136.3l1.3 1.9zM314.3 138.9h3.8zM359.4 122h5zM359.4 120.2v1.8zM359.4 137.2h5zM359.4 135.4v1.8zM359.4 120.2h5zM364.4 120.2v1.8zM359.4 135.4h5z"/>
<path d="M364.4 135.4v1.8zM377.1 119.8v2.6zM377.1 122.2h.5zM377.1 121.9h.9zM377.1 121.7h1.4zM377.1 121.5h1.8zM377.1 121.3h2.3zM377.1 121h2.5zM377.1 120.8h2zM377.1 120.6h1.6zM377.1 120.4h1.1zM377.1 120.1h.7z"/>
<path d="M377.1 135.1v2.5zM377.1 135.1l2.6 1.2zM377.1 137.5h.3zM377.1 137.2h.7zM377.1 137h1.2zM377.1 136.8h1.6zM377.1 136.6h2.1zM377.1 136.4h2.5zM377.1 136.1h2.2zM377.1 135.9h1.8zM377.1 135.7h1.3zM377.1 135.5h.9z"/>
<path d="M377.1 135.3h.4zM379.7 121.1v1.3zM377.1 122.4l2.6-1.3zM379.7 119.8v2.6zM379.7 122.2h.2zM379.7 121.9h.2zM379.7 121.7h.2zM379.7 121.5h.2zM379.7 121.3h.2zM379.7 121h.2zM379.7 120.8h.2zM379.7 120.6h.2z"/>
<path d="M379.7 120.4h.2zM379.7 120.1h.2zM379.7 136.3v1.3zM377.1 137.6l2.6-1.3zM379.7 135.1v2.5zM379.7 135.1h.2zM379.7 137.5h.2zM379.7 137.2h.2zM379.7 137h.2zM379.7 136.8h.2zM379.7 136.6h.2zM379.7 136.4h.2z"/>
<path d="M379.7 136.1h.2zM379.7 135.9h.2zM379.7 135.7h.2zM379.7 135.5h.2zM379.7 135.3h.2zM379.7 122.4h.2zM379.9 135.1v2.5zM379.7 137.6h.2zM49.5 154.1l-1.2 1.9zM49.5 154.1l1.3 1.9zM202.5 154.1h3.9zM283.8 154.1h3.8z"/>
<path d="M359.4 149.9h5zM359.4 148.1v1.8zM359.4 148.1h5zM364.4 148.1v1.8zM377.1 147.8v2.5zM377.1 147.8l2.6 1.2zM377.1 150.1h.4zM377.1 149.9h.8zM377.1 149.7h1.3zM377.1 149.5h1.7zM377.1 149.2h2.1zM377.1 149h2.6z"/>
<path d="M377.1 148.8h2.1zM377.1 148.6h1.7zM377.1 148.4h1.2zM377.1 148.1h.8zM377.1 147.9h.4zM379.7 149v1.3zM377.1 150.3l2.6-1.3zM379.7 147.8v2.5zM379.7 147.8h.2zM379.7 150.1h.2zM379.7 149.9h.2zM379.7 149.7h.2z"/>
<path d="M379.7 149.5h.2zM379.7 149.2h.2zM379.7 149h.2zM379.7 148.8h.2zM379.7 148.6h.2zM379.7 148.4h.2zM379.7 148.1h.2zM379.7 147.9h.2zM379.9 147.8v2.5zM379.7 150.3h.2zM382.9 156.7h3.8zM204.4 210l-1.2 1.9z"/>
<path d="M204.4 210l1.3 1.9zM285.7 210l-1.2 1.9zM285.7 210l1.3 1.9zM202.5 227.7h3.9zM283.8 227.7h3.8zM67.3 243l-1.3 1.9zM67.3 243l1.3 1.9zM77.5 243l-1.3 1.9zM77.5 243l1.2 1.9zM313.7 249.3h86.3zM313.7 254.4h86.3zM313.7 259.5h58.4z"/>
<path d="M372.1 259.5h27.9zM372.1 259.5v5.1zM27.3 265.8h3.8zM75.6 265.8h3.8zM313.7 264.6h58.4zM313.7 269.7h86.3zM372.1 264.6h27.9zM400 268.4v1.3z"/>
</g>
<path d="M16.5 18.2v260.3zM16.5 18.2h387.3zM16.5 278.5h387.3zM403.8 18.2v260.3z" fill="#000" stroke="#000" stroke-width=".32"/>
<g fill="#000" stroke="#000" stroke-width=".61">
<path d="M20.3 22.1v252.6zM20.3 22.1h379.7zM181.6 95.7v61zM181.6 95.7h15.2zM262.9 95.7v61zM262.9 95.7h15.2zM90.2 110.9v22.9zM90.2 110.9h15.2zM323.8 105.9v30.4zM323.8 105.9h15.2zM90.2 133.8h15.2zM105.4 110.9v22.9z"/>
<path d="M323.8 136.3h15.2zM339 105.9v30.4zM181.6 156.7h15.2zM196.8 95.7v61zM262.9 156.7h15.2zM278.1 95.7v61zM181.6 169.4v60.9zM181.6 169.4h15.2zM262.9 169.4v60.9zM262.9 169.4h15.2zM181.6 230.3h15.2zM196.8 169.4v60.9z"/>
<path d="M262.9 230.3h15.2zM278.1 169.4v60.9zM283.2 244.3v30.4zM313.7 254.4v5.1zM313.7 249.3v5.1zM313.7 244.3v5zM313.7 244.3h86.3zM283.2 244.3h30.5zM400 254.4v5.1zM400 249.3v5.1zM400 244.3v5zM400 22.1v222.2z"/>
<path d="M20.3 274.7h262.9zM283.2 274.7h30.5zM313.7 274.7h86.3zM313.7 269.7v5zM313.7 264.6v5.1zM313.7 259.5v5.1zM400 268.4v6.3zM400 264.6v3.8zM400 259.5v5.1z"/>
</g>
<g fill="none" stroke="#000" stroke-width=".21">
<circle cx="106.4" cy="116" r=".99"/>
<circle cx="106.4" cy="118.6" r=".99"/>
<circle cx="106.4" cy="113.5" r=".99"/>
<circle cx="340" cy="113.5" r="1"/>
<circle cx="340" cy="110.9" r="1"/>
<circle cx="340" cy="108.4" r="1"/>
<circle cx="340" cy="118.6" r="1"/>
<circle cx="340" cy="116" r="1"/>
<circle cx="89.2" cy="128.7" r=".99"/>
<circle cx="89.2" cy="131.3" r=".99"/>
<circle cx="106.4" cy="131.3" r=".99"/>
<circle cx="106.4" cy="126.2" r=".99"/>
<circle cx="106.4" cy="123.6" r=".99"/>
<circle cx="106.4" cy="121.1" r=".99"/>
<circle cx="106.4" cy="128.7" r=".99"/>
<circle cx="322.8" cy="131.3" r="1"/>
<circle cx="322.8" cy="133.8" r="1"/>
<circle cx="340" cy="121.1" r="1"/>
<circle cx="340" cy="126.2" r="1"/>
<circle cx="340" cy="123.6" r="1"/>
</g>
<g fill="#000" stroke="#000" stroke-width=".42">
<path d="M39.4 159.2h1.2zM41.3 158.6h.6zM41.9 158.6v6.3zM39.4 164.3h1.2zM39.4 161.7h1.2zM41.3 158.6v6.3zM41.3 164.9h.6zM39.4 187.1h1.2zM39.4 184.6h1.2zM39.4 182.1h1.2zM41.3 181.4v6.4zM41.3 181.4h.6z"/>
<path d="M41.9 181.4v6.4zM41.3 187.8h.6zM39.4 207.4h1.2zM39.4 204.9h1.2zM39.4 202.4h1.2zM41.3 201.7v6.4zM41.3 201.7h.6zM41.9 201.7v6.4zM41.3 208.1h.6zM339 222.7v10.1zM339 232.8v7.6zM339 232.8h55.9z"/>
<path d="M394.9 222.7v10.1zM339 222.7h55.9zM339 240.4h55.9zM394.9 232.8v7.6z"/>
</g>
<g fill="#000" stroke="#000" stroke-width=".21">
<path d="M202.4 145.5h4.1v.5h-4.1zM202.4 144.5h4.1v.5h-4.1zM283.7 145.5h4.1v.5h-4.1zM283.7 144.5h4.1v.5h-4.1zM202.4 219.1h4.1v.5h-4.1zM202.4 218.1h4.1v.5h-4.1zM283.7 219.1h4.1v.5h-4.1zM283.7 218.1h4.1v.5h-4.1zM369.5 222.7h25.4v10.1h-25.4zM27.2 253.7h4v.5h-4zM27.2 254.7h4v.5h-4zM34.8 253.7h4.1v.5h-4.1z"/>
<path d="M34.8 254.7h4.1v.5h-4.1zM42.4 253.7h4.1v.5h-4.1zM42.4 254.7h4.1v.5h-4.1zM50 253.7h4.1v.5h-4.1zM50 254.7h4.1v.5h-4.1zM57.7 253.7h4v.5h-4zM57.7 254.7h4v.5h-4zM65.3 253.7h4v.5h-4zM65.3 254.7h4v.5h-4zM75.4 254.7h4.1v.5h-4.1zM75.4 253.7h4.1v.5h-4.1z"/>
</g>
<g fill="#000" stroke="#000" stroke-width=".76">
<path d="M41.9 52.5h337.8zM153.6 52.5l5.1 5.1zM158.7 57.6v142.2zM234.9 52.5l5.1 5.1zM240 57.6v142.2zM41.9 67.8h337.8zM41.9 60.2h10.2zM52.1 60.2h96.5zM52.1 60.2l5 5zM148.6 60.2h231.1zM148.6 60.2l5 5zM214.6 67.8l5.1 5z"/>
<path d="M219.7 72.8v114.3zM229.8 60.2l5.1 5zM295.9 67.8l5.1 5zM301 72.8v114.3zM57.1 65.2v48.3zM153.6 65.2v149.8zM234.9 65.2v149.8z"/>
</g>
<use href="#words"/>
</svg>
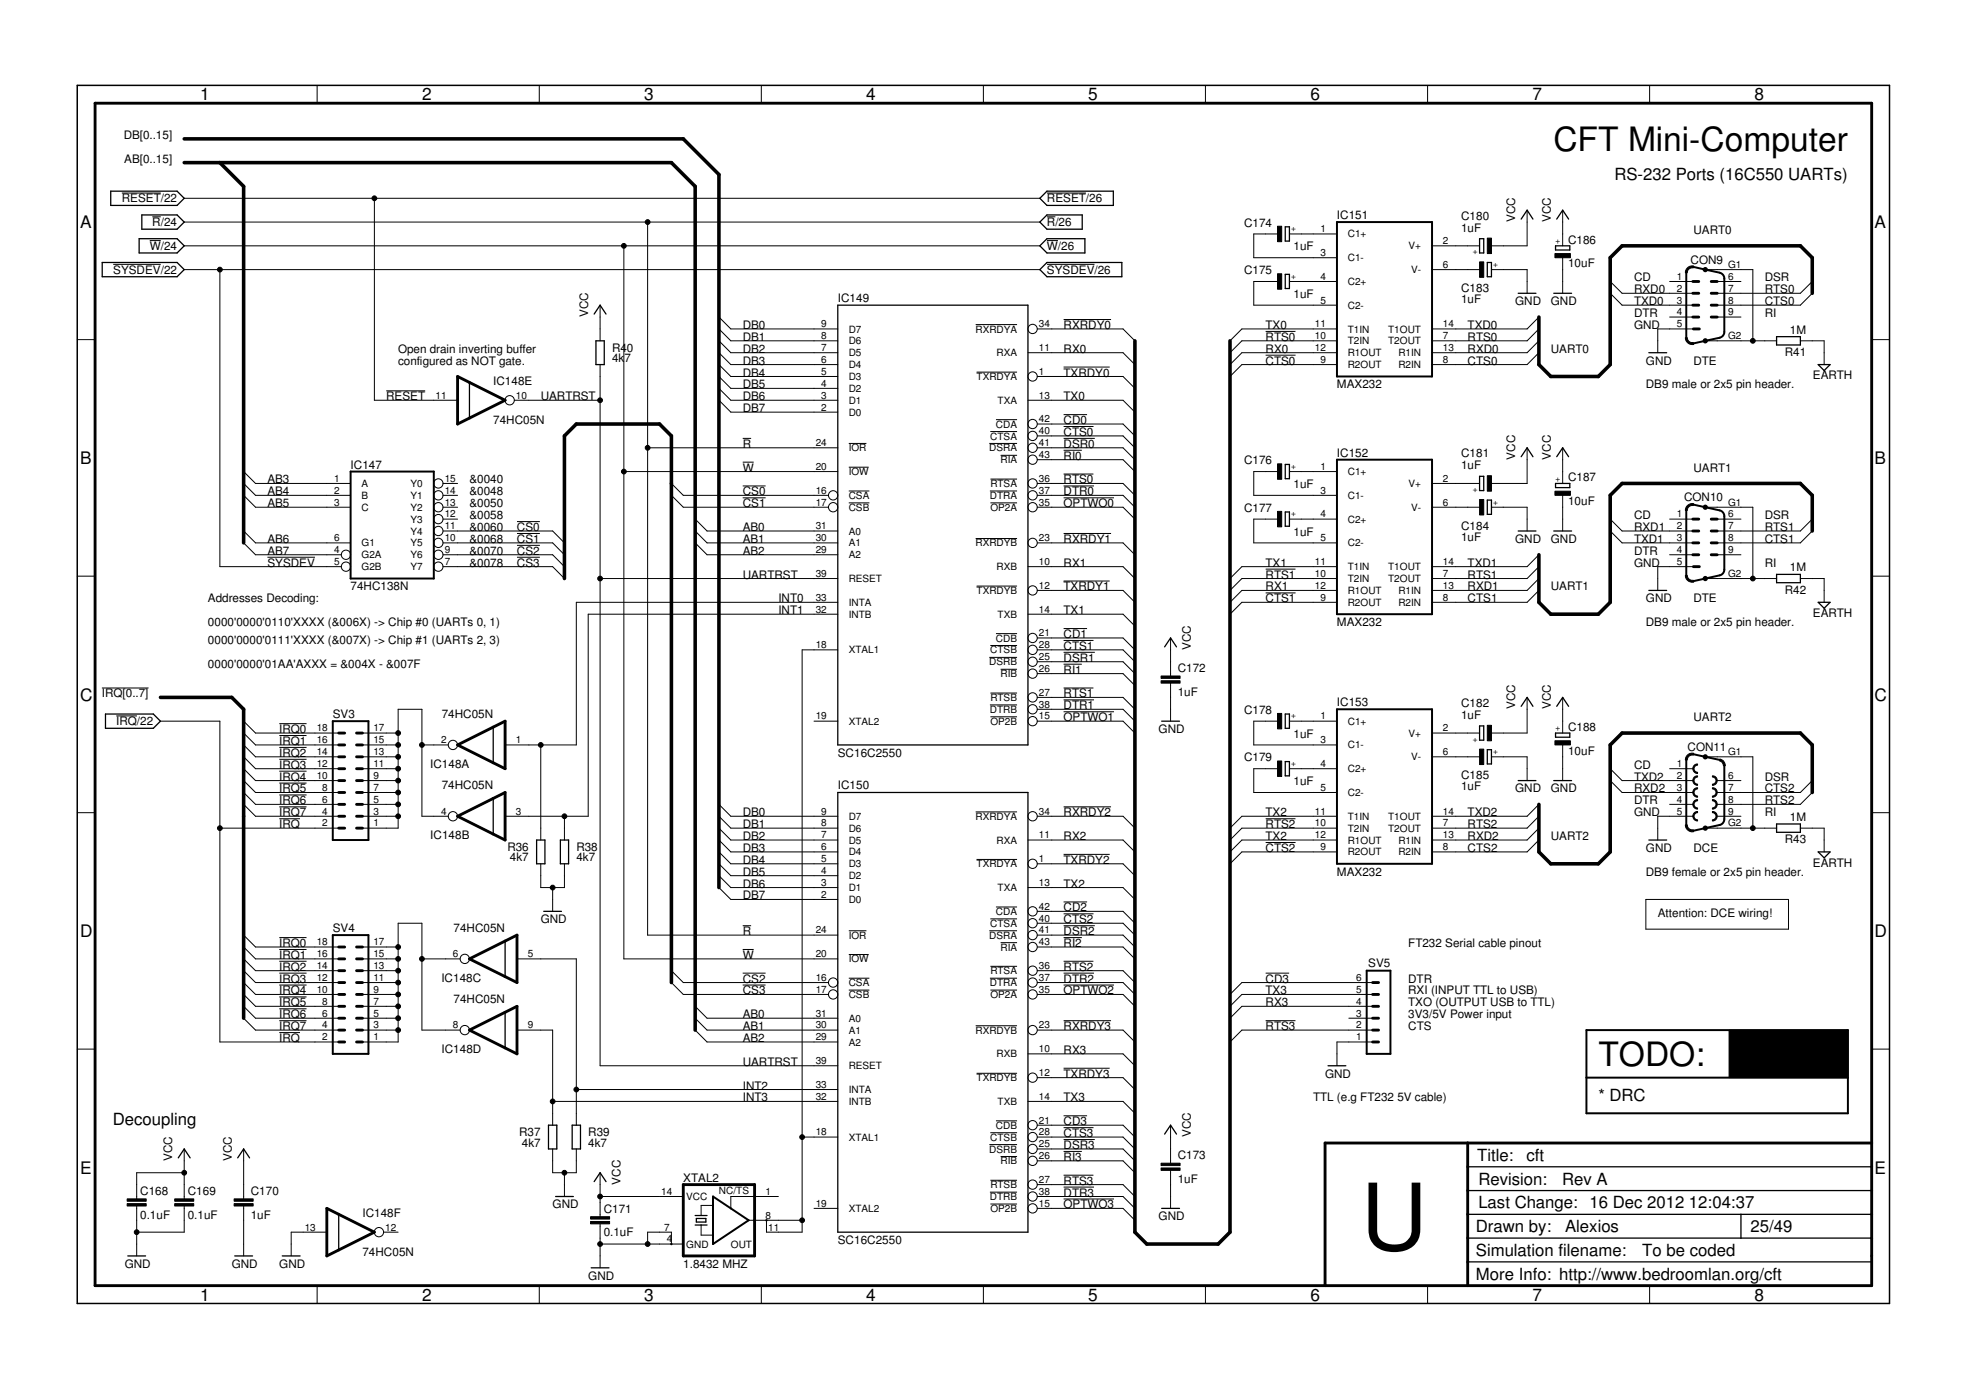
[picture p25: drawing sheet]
<svg xmlns="http://www.w3.org/2000/svg" width="420mm" height="297mm" viewBox="0 0 420 297" stroke-linecap="round" stroke-linejoin="round" font-family="sans-serif">
<defs><g id="words">
<text font-size="19.7" x="290.8" y="267.1">U</text>
<g font-size="7.2">
<text x="332" y="32.2">CFT Mini-Computer</text>
<text x="341.6" y="227.8">TODO:</text>
</g>
<g font-size="3.7">
<text x="42.7" y="21.5">1</text>
<text x="90.2" y="21.5">2</text>
<text x="137.7" y="21.5">3</text>
<text x="185.1" y="21.5">4</text>
<text x="232.6" y="21.5">5</text>
<text x="280" y="21.5">6</text>
<text x="327.5" y="21.5">7</text>
<text x="375" y="21.5">8</text>
<text x="17.1" y="48.6">A</text>
<text x="400.6" y="48.6">A</text>
<text x="17.1" y="99.2">B</text>
<text x="400.6" y="99.2">B</text>
<text x="17.1" y="149.7">C</text>
<text x="400.6" y="149.7">C</text>
<text x="17.1" y="200.2">D</text>
<text x="400.6" y="200.2">D</text>
<text x="17.1" y="250.8">E</text>
<text x="400.6" y="250.8">E</text>
<text x="42.7" y="277.9">1</text>
<text x="90.2" y="277.9">2</text>
<text x="137.7" y="277.9">3</text>
<text x="185.1" y="277.9">4</text>
<text x="232.6" y="277.9">5</text>
<text x="280" y="277.9">6</text>
<text x="327.5" y="277.9">7</text>
<text x="375" y="277.9">8</text>
</g>
<g font-size="3.6">
<text x="345" y="38.6">RS-232 Ports (16C550 UARTs)</text>
<text x="341.6" y="235.4">* DRC</text>
<text x="24.1" y="240.5">Decoupling</text>
<text x="315.7" y="248.1">Title:</text>
<text x="326.2" y="248.2">cft</text>
<text x="315.9" y="253.2">Revision:</text>
<text x="333.8" y="253.3">Rev A</text>
<text x="315.4" y="263.3">Drawn by:</text>
<text x="315.9" y="258.2">Last Change: 16 Dec 2012</text>
<text x="334.5" y="263.3">Alexios</text>
<text x="361" y="258.1">12:04:37</text>
<text x="374.1" y="263.2">25/49</text>
<text x="315.4" y="268.4">Simulation filename:</text>
<text x="351" y="268.4">To be coded</text>
<text x="315.4" y="273.5">More Info: http://www.bedroomlan.org/cft</text>
</g>
<g font-size="2.5">
<text x="26.4" y="29.7">DB[0..15]</text>
<text x="26.6" y="34.7">AB[0..15]</text>
<text x="26" y="43.3">RESET/22</text>
<text x="223.7" y="43.3">RESET/26</text>
<text x="285.7" y="46.8">IC151</text>
<text x="312.3" y="47">C180</text>
<text x="323.8" y="47.4" transform="rotate(-90 323.8 47.4)">VCC</text>
<text x="331.4" y="47.4" transform="rotate(-90 331.4 47.4)">VCC</text>
<text x="32" y="53.4">W/24</text>
<text x="32.6" y="48.3">R/24</text>
<text x="223.7" y="48.3">R/26</text>
<text x="223.7" y="53.4">W/26</text>
<text x="265.9" y="48.4">C174</text>
<text x="276.4" y="53.5">1uF</text>
<text x="312.3" y="49.5">1uF</text>
<text x="335.1" y="52">C186</text>
<text x="361.9" y="50">UART0</text>
<text x="24.2" y="58.5">SYSDEV/22</text>
<text x="223.7" y="58.5">SYSDEV/26</text>
<text x="265.9" y="58.6">C175</text>
<text x="335.1" y="57.1">10uF</text>
<text x="361.3" y="56.3">CON9</text>
<text x="179.1" y="64.6">IC149</text>
<text x="276.4" y="63.7">1uF</text>
<text x="312.3" y="64.7">1uF</text>
<text x="312.3" y="62.4">C183</text>
<text x="323.8" y="65.2">GND</text>
<text x="331.4" y="65.2">GND</text>
<text x="349.2" y="65.2">TXD0</text>
<text x="349.2" y="62.7">RXD0</text>
<text x="349.2" y="60.1">CD</text>
<text x="377.1" y="62.7">RTS0</text>
<text x="377.1" y="65.2">CTS0</text>
<text x="377.1" y="60.1">DSR</text>
<text x="125.7" y="67.8" transform="rotate(-90 125.7 67.8)">VCC</text>
<text x="158.7" y="70.3">DB0</text>
<text x="227.3" y="70.3">RXRDY0</text>
<text x="270.5" y="70.3">TX0</text>
<text x="313.7" y="70.3">TXD0</text>
<text x="349.2" y="67.8">DTR</text>
<text x="349.2" y="70.3">GND</text>
<text x="377.1" y="67.8">RI</text>
<text x="382.5" y="71.3">1M</text>
<text x="85.1" y="75.4">Open drain inverting buffer</text>
<text x="85.1" y="77.9">configured as NOT gate.</text>
<text x="130.8" y="77.4">4k</text>
<text x="130.8" y="75.2">R4</text>
<text x="133.4" y="77.4">7</text>
<text x="134" y="75.2">0</text>
<text x="158.7" y="72.8">DB1</text>
<text x="158.7" y="75.4">DB2</text>
<text x="158.7" y="77.9">DB3</text>
<text x="227.3" y="75.4">RX0</text>
<text x="270.5" y="75.4">RX0</text>
<text x="270.5" y="77.9">CTS0</text>
<text x="270.5" y="72.8">RTS0</text>
<text x="313.7" y="72.8">RTS0</text>
<text x="313.7" y="75.4">RXD0</text>
<text x="313.7" y="77.9">CTS0</text>
<text x="331.4" y="75.4">UART0</text>
<text x="351.7" y="77.9">GND</text>
<text x="361.9" y="77.9">DTE</text>
<text x="381.4" y="76.1">R41</text>
<text x="105.4" y="82.4">IC148E</text>
<text x="158.7" y="80.5">DB4</text>
<text x="158.7" y="83">DB5</text>
<text x="227.3" y="80.5">TXRDY0</text>
<text x="285.7" y="83">MAX232</text>
<text x="351.7" y="83">DB9 male or 2x5 pin header.</text>
<text x="387.4" y="81.1">EARTH</text>
<text x="82.5" y="85.5">RESET</text>
<text x="115.6" y="85.5">UARTRST</text>
<text x="158.7" y="85.5">DB6</text>
<text x="158.7" y="88.1">DB7</text>
<text x="227.3" y="85.5">TX0</text>
<text x="105.4" y="90.6">74HC05N</text>
<text x="158.7" y="95.7">R</text>
<text x="227.3" y="90.6">CD0</text>
<text x="227.3" y="93.2">CTS0</text>
<text x="227.3" y="95.7">DSR0</text>
<text x="74.9" y="100.1">IC147</text>
<text x="158.7" y="100.8">W</text>
<text x="227.3" y="98.2">RI0</text>
<text x="265.9" y="99.2">C176</text>
<text x="285.7" y="97.6">IC152</text>
<text x="312.3" y="100.3">1uF</text>
<text x="312.3" y="97.8">C181</text>
<text x="323.8" y="98.2" transform="rotate(-90 323.8 98.2)">VCC</text>
<text x="331.4" y="98.2" transform="rotate(-90 331.4 98.2)">VCC</text>
<text x="361.9" y="100.8">UART1</text>
<text x="57.1" y="103.3">AB3</text>
<text x="57.1" y="105.9">AB4</text>
<text x="100.3" y="103.3">&amp;0040</text>
<text x="100.3" y="105.9">&amp;0048</text>
<text x="158.7" y="105.9">CS0</text>
<text x="227.3" y="103.3">RTS0</text>
<text x="227.3" y="105.9">DTR0</text>
<text x="276.4" y="104.3">1uF</text>
<text x="335.1" y="107.9">10uF</text>
<text x="335.1" y="102.8">C187</text>
<text x="359.9" y="107.1">CON10</text>
<text x="57.1" y="108.4">AB5</text>
<text x="100.3" y="108.4">&amp;0050</text>
<text x="100.3" y="110.9">&amp;0058</text>
<text x="100.3" y="113.5">&amp;0060</text>
<text x="110.5" y="113.5">CS0</text>
<text x="158.7" y="113.5">AB0</text>
<text x="158.7" y="108.4">CS1</text>
<text x="227.3" y="108.4">OPTWO0</text>
<text x="265.9" y="109.4">C177</text>
<text x="312.3" y="113.2">C184</text>
<text x="349.2" y="113.5">RXD1</text>
<text x="349.2" y="110.9">CD</text>
<text x="377.1" y="113.5">RTS1</text>
<text x="377.1" y="110.9">DSR</text>
<text x="57.1" y="116">AB6</text>
<text x="57.1" y="118.6">AB7</text>
<text x="100.3" y="116">&amp;0068</text>
<text x="100.3" y="118.6">&amp;0070</text>
<text x="110.5" y="116">CS1</text>
<text x="110.5" y="118.6">CS2</text>
<text x="158.7" y="116">AB1</text>
<text x="158.7" y="118.6">AB2</text>
<text x="227.3" y="116">RXRDY1</text>
<text x="276.4" y="114.5">1uF</text>
<text x="312.3" y="115.5">1uF</text>
<text x="323.8" y="116">GND</text>
<text x="331.4" y="116">GND</text>
<text x="349.2" y="116">TXD1</text>
<text x="349.2" y="118.6">DTR</text>
<text x="377.1" y="116">CTS1</text>
<text x="57.1" y="121.1">SYSDEV</text>
<text x="100.3" y="121.1">&amp;0078</text>
<text x="110.5" y="121.1">CS3</text>
<text x="158.7" y="123.6">UARTRST</text>
<text x="227.3" y="121.1">RX1</text>
<text x="270.5" y="121.1">TX1</text>
<text x="270.5" y="123.6">RTS1</text>
<text x="313.7" y="121.1">TXD1</text>
<text x="313.7" y="123.6">RTS1</text>
<text x="349.2" y="121.1">GND</text>
<text x="377.1" y="121.1">RI</text>
<text x="382.5" y="122.1">1M</text>
<text x="44.4" y="128.7">Addresses Decoding:</text>
<text x="74.9" y="126.2">74HC138N</text>
<text x="166.4" y="128.7">INT0</text>
<text x="166.4" y="131.3">INT1</text>
<text x="227.3" y="126.2">TXRDY1</text>
<text x="227.3" y="131.3">TX1</text>
<text x="270.5" y="126.2">RX1</text>
<text x="270.5" y="128.7">CTS1</text>
<text x="313.7" y="126.2">RXD1</text>
<text x="313.7" y="128.7">CTS1</text>
<text x="331.4" y="126.2">UART1</text>
<text x="351.7" y="128.7">GND</text>
<text x="361.9" y="128.7">DTE</text>
<text x="381.4" y="126.9">R42</text>
<text x="387.4" y="131.9">EARTH</text>
<text x="44.4" y="133.8">0000'0000'0110'XXXX (&amp;006X) -&gt; Chip #0 (UARTs 0, 1)</text>
<text x="44.4" y="137.6">0000'0000'0111'XXXX (&amp;007X) -&gt; Chip #1 (UARTs 2, 3)</text>
<text x="227.3" y="136.3">CD1</text>
<text x="285.7" y="133.8">MAX232</text>
<text x="351.7" y="133.8">DB9 male or 2x5 pin header.</text>
<text x="44.4" y="142.7">0000'0000'01AA'AXXX = &amp;004X - &amp;007F</text>
<text x="227.3" y="138.9">CTS1</text>
<text x="227.3" y="141.4">DSR1</text>
<text x="227.3" y="144">RI1</text>
<text x="251.7" y="143.6">C172</text>
<text x="254.5" y="138.9" transform="rotate(-90 254.5 138.9)">VCC</text>
<text x="21.8" y="149">IRQ[0..7]</text>
<text x="227.3" y="149">RTS1</text>
<text x="251.7" y="148.6">1uF</text>
<text x="24.8" y="155">IRQ/22</text>
<text x="71.1" y="153.3">SV3</text>
<text x="94.4" y="153.3">74HC05N</text>
<text x="227.3" y="151.6">DTR1</text>
<text x="227.3" y="154.1">OPTWO1</text>
<text x="265.9" y="152.6">C178</text>
<text x="285.7" y="150.9">IC153</text>
<text x="312.3" y="153.6">1uF</text>
<text x="312.3" y="151.1">C182</text>
<text x="323.8" y="151.6" transform="rotate(-90 323.8 151.6)">VCC</text>
<text x="331.4" y="151.6" transform="rotate(-90 331.4 151.6)">VCC</text>
<text x="361.9" y="154.1">UART2</text>
<text x="59.7" y="156.6">IRQ0</text>
<text x="59.7" y="159.2">IRQ1</text>
<text x="59.7" y="161.7">IRQ2</text>
<text x="179.1" y="161.7">SC16C2550</text>
<text x="247.6" y="156.6">GND</text>
<text x="276.4" y="157.6">1uF</text>
<text x="335.1" y="161.2">10uF</text>
<text x="335.1" y="156.2">C188</text>
<text x="360.6" y="160.5">CON11</text>
<text x="59.7" y="164.3">IRQ3</text>
<text x="59.7" y="166.8">IRQ4</text>
<text x="91.9" y="164.1">IC148A</text>
<text x="265.9" y="162.7">C179</text>
<text x="276.4" y="167.8">1uF</text>
<text x="312.3" y="166.5">C185</text>
<text x="349.2" y="166.8">TXD2</text>
<text x="349.2" y="164.3">CD</text>
<text x="377.1" y="166.8">DSR</text>
<text x="59.7" y="169.3">IRQ5</text>
<text x="59.7" y="171.9">IRQ6</text>
<text x="94.4" y="168.6">74HC05N</text>
<text x="179.1" y="168.7">IC150</text>
<text x="312.3" y="168.9">1uF</text>
<text x="323.8" y="169.3">GND</text>
<text x="331.4" y="169.3">GND</text>
<text x="349.2" y="169.3">RXD2</text>
<text x="349.2" y="171.9">DTR</text>
<text x="377.1" y="169.3">CTS2</text>
<text x="377.1" y="171.9">RTS2</text>
<text x="59.7" y="174.4">IRQ7</text>
<text x="59.7" y="177">IRQ</text>
<text x="92" y="179.4">IC148B</text>
<text x="158.7" y="174.4">DB0</text>
<text x="158.7" y="177">DB1</text>
<text x="158.7" y="179.5">DB2</text>
<text x="227.3" y="174.4">RXRDY2</text>
<text x="227.3" y="179.5">RX2</text>
<text x="270.5" y="174.4">TX2</text>
<text x="270.5" y="179.5">TX2</text>
<text x="270.5" y="177">RTS2</text>
<text x="313.7" y="174.4">TXD2</text>
<text x="313.7" y="179.5">RXD2</text>
<text x="313.7" y="177">RTS2</text>
<text x="331.4" y="179.5">UART2</text>
<text x="349.2" y="174.4">GND</text>
<text x="377.1" y="174.4">RI</text>
<text x="382.5" y="175.4">1M</text>
<text x="108.4" y="181.8">R36</text>
<text x="109" y="184.1">4k7</text>
<text x="123.2" y="184.1">4k7</text>
<text x="123.2" y="181.8">R38</text>
<text x="158.7" y="182">DB3</text>
<text x="158.7" y="184.6">DB4</text>
<text x="227.3" y="184.6">TXRDY2</text>
<text x="270.5" y="182">CTS2</text>
<text x="313.7" y="182">CTS2</text>
<text x="351.7" y="182">GND</text>
<text x="361.9" y="182">DCE</text>
<text x="381.4" y="180.2">R43</text>
<text x="387.4" y="185.2">EARTH</text>
<text x="158.7" y="187.1">DB5</text>
<text x="158.7" y="189.7">DB6</text>
<text x="227.3" y="189.7">TX2</text>
<text x="285.7" y="187.1">MAX232</text>
<text x="351.7" y="187.1">DB9 female or 2x5 pin header.</text>
<text x="115.6" y="197.3">GND</text>
<text x="158.7" y="192.2">DB7</text>
<text x="227.3" y="194.7">CD2</text>
<text x="227.3" y="197.3">CTS2</text>
<text x="354.3" y="196">Attention: DCE wiring!</text>
<text x="59.7" y="202.4">IRQ0</text>
<text x="71.1" y="199.1">SV4</text>
<text x="96.9" y="199.1">74HC05N</text>
<text x="158.7" y="199.8">R</text>
<text x="227.3" y="199.8">DSR2</text>
<text x="227.3" y="202.4">RI2</text>
<text x="301" y="202.4">FT232 Serial cable pinout</text>
<text x="59.7" y="204.9">IRQ1</text>
<text x="59.7" y="207.4">IRQ2</text>
<text x="59.7" y="210">IRQ3</text>
<text x="94.3" y="209.9">IC148C</text>
<text x="158.7" y="204.9">W</text>
<text x="158.7" y="210">CS2</text>
<text x="227.3" y="207.4">RTS2</text>
<text x="227.3" y="210">DTR2</text>
<text x="270.5" y="210">CD3</text>
<text x="292.4" y="206.7">SV5</text>
<text x="301" y="210">DTR</text>
<text x="59.7" y="212.5">IRQ4</text>
<text x="59.7" y="215.1">IRQ5</text>
<text x="96.9" y="214.3">74HC05N</text>
<text x="158.7" y="212.5">CS3</text>
<text x="227.3" y="212.5">OPTWO2</text>
<text x="270.5" y="215.1">RX3</text>
<text x="270.5" y="212.5">TX3</text>
<text x="301" y="215.1">TXO (OUTPUT USB to TTL)</text>
<text x="301" y="212.5">RXI (INPUT TTL to USB)</text>
<text x="59.7" y="217.6">IRQ6</text>
<text x="59.7" y="220.1">IRQ7</text>
<text x="158.7" y="217.6">AB0</text>
<text x="158.7" y="220.1">AB1</text>
<text x="227.3" y="220.1">RXRDY3</text>
<text x="270.5" y="220.1">RTS3</text>
<text x="301" y="220.1">CTS</text>
<text x="301" y="217.6">3V3/5V Power input</text>
<text x="59.7" y="222.7">IRQ</text>
<text x="94.4" y="225.1">IC148D</text>
<text x="158.7" y="222.7">AB2</text>
<text x="158.7" y="227.8">UARTRST</text>
<text x="227.3" y="225.2">RX3</text>
<text x="158.7" y="232.8">INT2</text>
<text x="227.3" y="230.3">TXRDY3</text>
<text x="283.2" y="230.3">GND</text>
<text x="158.7" y="235.4">INT3</text>
<text x="227.3" y="235.4">TX3</text>
<text x="280.6" y="235.4">TTL (e.g FT232</text>
<text x="298.6" y="235.4">5V cable)</text>
<text x="111" y="242.8">R37</text>
<text x="111.5" y="245">4k7</text>
<text x="125.7" y="245">4k7</text>
<text x="125.7" y="242.8">R39</text>
<text x="227.3" y="240.5">CD3</text>
<text x="227.3" y="243">CTS3</text>
<text x="227.3" y="245.5">DSR3</text>
<text x="254.5" y="243" transform="rotate(-90 254.5 243)">VCC</text>
<text x="36.8" y="248.1" transform="rotate(-90 36.8 248.1)">VCC</text>
<text x="49.5" y="248.1" transform="rotate(-90 49.5 248.1)">VCC</text>
<text x="227.3" y="248.1">RI3</text>
<text x="251.7" y="247.7">C173</text>
<text x="30" y="255.3">C168</text>
<text x="40.1" y="255.3">C169</text>
<text x="53.6" y="255.3">C170</text>
<text x="132.6" y="253.2" transform="rotate(-90 132.6 253.2)">VCC</text>
<text x="146" y="252.5">XTAL2</text>
<text x="227.3" y="253.2">RTS3</text>
<text x="227.3" y="255.7">DTR3</text>
<text x="251.7" y="252.8">1uF</text>
<text x="30" y="260.4">0.1uF</text>
<text x="40.1" y="260.4">0.1uF</text>
<text x="53.6" y="260.4">1uF</text>
<text x="77.5" y="260.1">IC148F</text>
<text x="118.1" y="258.2">GND</text>
<text x="129" y="259.1">C171</text>
<text x="227.3" y="258.2">OPTWO3</text>
<text x="247.6" y="260.8">GND</text>
<text x="77.5" y="268.4">74HC05N</text>
<text x="129" y="264.2">0.1uF</text>
<text x="179.1" y="265.8">SC16C2550</text>
<text x="26.7" y="270.9">GND</text>
<text x="49.5" y="270.9">GND</text>
<text x="59.7" y="270.9">GND</text>
<text x="125.7" y="273.5">GND</text>
<text x="146" y="270.9">1.8432 MHZ</text>
</g>
<g font-size="2.1">
<text x="282.2" y="49.6">1</text>
<text x="288.1" y="50.7">C1+</text>
<text x="301" y="53.3">V+</text>
<text x="308.4" y="52.2">2</text>
<text x="282.2" y="54.7">3</text>
<text x="282.2" y="59.8">4</text>
<text x="288.1" y="55.8">C1-</text>
<text x="301.6" y="58.4">V-</text>
<text x="308.4" y="57.2">6</text>
<text x="358.4" y="59.8">1</text>
<text x="369.3" y="59.8">6</text>
<text x="369.3" y="57.2">G1</text>
<text x="282.2" y="64.9">5</text>
<text x="288.1" y="60.9">C2+</text>
<text x="288.1" y="66">C2-</text>
<text x="358.4" y="62.3">2</text>
<text x="358.4" y="64.9">3</text>
<text x="369.3" y="62.3">7</text>
<text x="369.3" y="64.9">8</text>
<text x="175.5" y="69.9">9</text>
<text x="181.4" y="71.1">D7</text>
<text x="208.5" y="71.1">RXRDYA</text>
<text x="222" y="69.9">34</text>
<text x="281" y="69.9">11</text>
<text x="288.1" y="71.1">T1IN</text>
<text x="296.7" y="71.1">T1OUT</text>
<text x="308.4" y="69.9">14</text>
<text x="358.4" y="67.4">4</text>
<text x="358.4" y="69.9">5</text>
<text x="369.3" y="67.4">9</text>
<text x="175.5" y="75">7</text>
<text x="175.5" y="72.5">8</text>
<text x="175.5" y="77.6">6</text>
<text x="181.4" y="76.1">D5</text>
<text x="181.4" y="73.6">D6</text>
<text x="213" y="76.1">RXA</text>
<text x="222" y="75">11</text>
<text x="281" y="72.5">10</text>
<text x="281" y="75">12</text>
<text x="282.2" y="77.6">9</text>
<text x="288.1" y="73.6">T2IN</text>
<text x="288.1" y="76.1">R1OUT</text>
<text x="296.7" y="73.6">T2OUT</text>
<text x="298.9" y="76.1">R1IN</text>
<text x="308.4" y="72.5">7</text>
<text x="308.4" y="75">13</text>
<text x="308.4" y="77.6">8</text>
<text x="369.3" y="72.5">G2</text>
<text x="175.5" y="80.1">5</text>
<text x="175.5" y="82.6">4</text>
<text x="181.4" y="81.2">D3</text>
<text x="181.4" y="78.7">D4</text>
<text x="181.4" y="83.8">D2</text>
<text x="208.7" y="81.2">TXRDYA</text>
<text x="222" y="80.1">1</text>
<text x="288.1" y="78.7">R2OUT</text>
<text x="298.9" y="78.7">R2IN</text>
<text x="93.1" y="85.2">11</text>
<text x="110.3" y="85.2">10</text>
<text x="175.5" y="85.2">3</text>
<text x="175.5" y="87.7">2</text>
<text x="181.4" y="86.3">D1</text>
<text x="181.4" y="88.8">D0</text>
<text x="213.2" y="86.3">TXA</text>
<text x="222" y="85.2">13</text>
<text x="174.3" y="95.3">24</text>
<text x="211.6" y="93.9">CTSA</text>
<text x="212.8" y="91.4">CDA</text>
<text x="222" y="90.3">42</text>
<text x="222" y="92.8">40</text>
<text x="222" y="95.3">41</text>
<text x="174.3" y="100.4">20</text>
<text x="181.4" y="101.5">IOW</text>
<text x="181.4" y="96.5">IOR</text>
<text x="211.4" y="96.5">DSRA</text>
<text x="213.8" y="99">RIA</text>
<text x="222" y="97.9">43</text>
<text x="282.2" y="100.4">1</text>
<text x="288.1" y="101.5">C1+</text>
<text x="71.4" y="103">1</text>
<text x="71.4" y="105.5">2</text>
<text x="77.3" y="104.1">A</text>
<text x="77.3" y="106.6">B</text>
<text x="87.8" y="106.6">Y1</text>
<text x="87.8" y="104.1">Y0</text>
<text x="95" y="105.5">14</text>
<text x="95" y="103">15</text>
<text x="174.3" y="105.5">16</text>
<text x="181.4" y="106.6">CSA</text>
<text x="211.5" y="106.6">DTRA</text>
<text x="211.7" y="104.1">RTSA</text>
<text x="222" y="105.5">37</text>
<text x="222" y="103">36</text>
<text x="282.2" y="105.5">3</text>
<text x="288.1" y="106.6">C1-</text>
<text x="301" y="104.1">V+</text>
<text x="308.4" y="103">2</text>
<text x="71.4" y="108">3</text>
<text x="77.3" y="109.2">C</text>
<text x="87.8" y="111.7">Y3</text>
<text x="87.8" y="109.2">Y2</text>
<text x="95" y="113.1">11</text>
<text x="95" y="110.6">12</text>
<text x="95" y="108">13</text>
<text x="174.3" y="113.1">31</text>
<text x="174.3" y="108">17</text>
<text x="181.4" y="109.2">CSB</text>
<text x="211.7" y="109.2">OP2A</text>
<text x="222" y="108">35</text>
<text x="282.2" y="110.6">4</text>
<text x="288.1" y="111.7">C2+</text>
<text x="301.6" y="109.2">V-</text>
<text x="308.4" y="108">6</text>
<text x="358.4" y="110.6">1</text>
<text x="358.4" y="113.1">2</text>
<text x="369.3" y="110.6">6</text>
<text x="369.3" y="113.1">7</text>
<text x="369.3" y="108">G1</text>
<text x="71.4" y="118.2">4</text>
<text x="71.4" y="115.7">6</text>
<text x="77.3" y="119.3">G2A</text>
<text x="77.3" y="116.8">G1</text>
<text x="87.8" y="119.3">Y6</text>
<text x="87.8" y="116.8">Y5</text>
<text x="87.8" y="114.2">Y4</text>
<text x="95" y="118.2">9</text>
<text x="95" y="115.7">10</text>
<text x="174.3" y="115.7">30</text>
<text x="174.3" y="118.2">29</text>
<text x="181.4" y="114.2">A0</text>
<text x="181.4" y="116.8">A1</text>
<text x="181.4" y="119.3">A2</text>
<text x="208.5" y="116.8">RXRDYB</text>
<text x="222" y="115.7">23</text>
<text x="282.2" y="115.7">5</text>
<text x="288.1" y="116.8">C2-</text>
<text x="358.4" y="115.7">3</text>
<text x="358.4" y="118.2">4</text>
<text x="369.3" y="115.7">8</text>
<text x="369.3" y="118.2">9</text>
<text x="71.4" y="120.7">5</text>
<text x="77.3" y="121.9">G2B</text>
<text x="87.8" y="121.9">Y7</text>
<text x="95" y="120.7">7</text>
<text x="174.3" y="123.3">39</text>
<text x="181.4" y="124.4">RESET</text>
<text x="213" y="121.9">RXB</text>
<text x="222" y="125.8">12</text>
<text x="222" y="120.7">10</text>
<text x="281" y="120.7">11</text>
<text x="281" y="123.3">10</text>
<text x="281" y="125.8">12</text>
<text x="288.1" y="121.9">T1IN</text>
<text x="288.1" y="124.4">T2IN</text>
<text x="296.7" y="121.9">T1OUT</text>
<text x="296.7" y="124.4">T2OUT</text>
<text x="308.4" y="120.7">14</text>
<text x="308.4" y="123.3">7</text>
<text x="308.4" y="125.8">13</text>
<text x="358.4" y="120.7">5</text>
<text x="369.3" y="123.3">G2</text>
<text x="174.3" y="128.4">33</text>
<text x="174.3" y="130.9">32</text>
<text x="181.4" y="129.5">INTA</text>
<text x="208.7" y="126.9">TXRDYB</text>
<text x="222" y="130.9">14</text>
<text x="282.2" y="128.4">9</text>
<text x="288.1" y="126.9">R1OUT</text>
<text x="288.1" y="129.5">R2OUT</text>
<text x="298.9" y="126.9">R1IN</text>
<text x="298.9" y="129.5">R2IN</text>
<text x="308.4" y="128.4">8</text>
<text x="181.4" y="132">INTB</text>
<text x="212.8" y="137.1">CDB</text>
<text x="213.2" y="132">TXB</text>
<text x="222" y="136">21</text>
<text x="174.3" y="138.5">18</text>
<text x="181.4" y="139.6">XTAL1</text>
<text x="211.4" y="142.2">DSRB</text>
<text x="211.6" y="139.6">CTSB</text>
<text x="222" y="138.5">28</text>
<text x="222" y="141.1">25</text>
<text x="222" y="143.6">26</text>
<text x="211.7" y="149.8">RTSB</text>
<text x="213.8" y="144.7">RIB</text>
<text x="222" y="148.7">27</text>
<text x="174.3" y="153.8">19</text>
<text x="181.4" y="154.9">XTAL2</text>
<text x="211.5" y="152.3">DTRB</text>
<text x="211.7" y="154.9">OP2B</text>
<text x="222" y="151.2">38</text>
<text x="222" y="153.8">15</text>
<text x="282.2" y="153.8">1</text>
<text x="288.1" y="154.9">C1+</text>
<text x="67.7" y="161.4">14</text>
<text x="67.7" y="158.8">16</text>
<text x="67.7" y="156.3">18</text>
<text x="79.8" y="161.4">13</text>
<text x="79.8" y="158.8">15</text>
<text x="79.8" y="156.3">17</text>
<text x="94.3" y="158.8">2</text>
<text x="110.3" y="158.8">1</text>
<text x="282.2" y="158.8">3</text>
<text x="288.1" y="159.9">C1-</text>
<text x="301" y="157.4">V+</text>
<text x="308.4" y="156.3">2</text>
<text x="308.4" y="161.4">6</text>
<text x="369.3" y="161.4">G1</text>
<text x="67.7" y="166.5">10</text>
<text x="67.7" y="163.9">12</text>
<text x="79.8" y="166.5">9</text>
<text x="79.8" y="163.9">11</text>
<text x="282.2" y="163.9">4</text>
<text x="288.1" y="165">C2+</text>
<text x="301.6" y="162.5">V-</text>
<text x="358.4" y="163.9">1</text>
<text x="358.4" y="166.5">2</text>
<text x="369.3" y="166.5">6</text>
<text x="68.9" y="171.5">6</text>
<text x="68.9" y="169">8</text>
<text x="79.8" y="171.5">5</text>
<text x="79.8" y="169">7</text>
<text x="282.2" y="169">5</text>
<text x="288.1" y="170.1">C2-</text>
<text x="358.4" y="169">3</text>
<text x="358.4" y="171.5">4</text>
<text x="369.3" y="169">7</text>
<text x="369.3" y="171.5">8</text>
<text x="68.9" y="176.6">2</text>
<text x="68.9" y="174.1">4</text>
<text x="79.8" y="176.6">1</text>
<text x="79.8" y="174.1">3</text>
<text x="94.3" y="174.1">4</text>
<text x="110.3" y="174.1">3</text>
<text x="175.5" y="179.1">7</text>
<text x="175.5" y="174.1">9</text>
<text x="175.5" y="176.6">8</text>
<text x="181.4" y="175.2">D7</text>
<text x="181.4" y="177.7">D6</text>
<text x="208.5" y="175.2">RXRDYA</text>
<text x="222" y="174.1">34</text>
<text x="222" y="179.1">11</text>
<text x="281" y="174.1">11</text>
<text x="281" y="176.6">10</text>
<text x="281" y="179.1">12</text>
<text x="288.1" y="175.2">T1IN</text>
<text x="288.1" y="177.7">T2IN</text>
<text x="296.7" y="175.2">T1OUT</text>
<text x="296.7" y="177.7">T2OUT</text>
<text x="308.4" y="174.1">14</text>
<text x="308.4" y="176.6">7</text>
<text x="308.4" y="179.1">13</text>
<text x="358.4" y="174.1">5</text>
<text x="369.3" y="174.1">9</text>
<text x="369.3" y="176.6">G2</text>
<text x="175.5" y="184.2">5</text>
<text x="175.5" y="181.7">6</text>
<text x="181.4" y="185.3">D3</text>
<text x="181.4" y="180.3">D5</text>
<text x="181.4" y="182.8">D4</text>
<text x="208.7" y="185.3">TXRDYA</text>
<text x="213" y="180.3">RXA</text>
<text x="222" y="184.2">1</text>
<text x="282.2" y="181.7">9</text>
<text x="288.1" y="180.3">R1OUT</text>
<text x="288.1" y="182.8">R2OUT</text>
<text x="298.9" y="180.3">R1IN</text>
<text x="298.9" y="182.8">R2IN</text>
<text x="308.4" y="181.7">8</text>
<text x="175.5" y="189.3">3</text>
<text x="175.5" y="186.8">4</text>
<text x="175.5" y="191.8">2</text>
<text x="181.4" y="190.4">D1</text>
<text x="181.4" y="187.9">D2</text>
<text x="213.2" y="190.4">TXA</text>
<text x="222" y="189.3">13</text>
<text x="181.4" y="193">D0</text>
<text x="212.8" y="195.5">CDA</text>
<text x="222" y="194.4">42</text>
<text x="222" y="196.9">40</text>
<text x="67.7" y="202">18</text>
<text x="79.8" y="202">17</text>
<text x="174.3" y="199.5">24</text>
<text x="181.4" y="200.6">IOR</text>
<text x="211.4" y="200.6">DSRA</text>
<text x="211.6" y="198">CTSA</text>
<text x="213.8" y="203.1">RIA</text>
<text x="222" y="199.5">41</text>
<text x="222" y="202">43</text>
<text x="67.7" y="209.6">12</text>
<text x="67.7" y="207.1">14</text>
<text x="67.7" y="204.5">16</text>
<text x="79.8" y="209.6">11</text>
<text x="79.8" y="207.1">13</text>
<text x="79.8" y="204.5">15</text>
<text x="96.8" y="204.5">6</text>
<text x="112.8" y="204.5">5</text>
<text x="174.3" y="204.5">20</text>
<text x="174.3" y="209.6">16</text>
<text x="181.4" y="205.7">IOW</text>
<text x="211.7" y="208.2">RTSA</text>
<text x="222" y="209.6">37</text>
<text x="222" y="207.1">36</text>
<text x="289.8" y="209.6">6</text>
<text x="67.7" y="212.2">10</text>
<text x="68.9" y="214.7">8</text>
<text x="79.8" y="214.7">7</text>
<text x="79.8" y="212.2">9</text>
<text x="174.3" y="212.2">17</text>
<text x="181.4" y="210.7">CSA</text>
<text x="181.4" y="213.3">CSB</text>
<text x="211.5" y="210.7">DTRA</text>
<text x="211.7" y="213.3">OP2A</text>
<text x="222" y="212.2">35</text>
<text x="289.8" y="214.7">4</text>
<text x="289.8" y="212.2">5</text>
<text x="68.9" y="219.8">4</text>
<text x="68.9" y="217.2">6</text>
<text x="79.8" y="219.8">3</text>
<text x="79.8" y="217.2">5</text>
<text x="96.8" y="219.8">8</text>
<text x="112.8" y="219.8">9</text>
<text x="174.3" y="217.2">31</text>
<text x="174.3" y="219.8">30</text>
<text x="181.4" y="218.4">A0</text>
<text x="181.4" y="220.9">A1</text>
<text x="208.5" y="220.9">RXRDYB</text>
<text x="222" y="219.8">23</text>
<text x="289.8" y="219.8">2</text>
<text x="289.8" y="217.2">3</text>
<text x="68.9" y="222.3">2</text>
<text x="79.8" y="222.3">1</text>
<text x="174.3" y="222.3">29</text>
<text x="174.3" y="227.4">39</text>
<text x="181.4" y="223.4">A2</text>
<text x="213" y="226">RXB</text>
<text x="222" y="224.9">10</text>
<text x="289.8" y="222.3">1</text>
<text x="174.3" y="232.5">33</text>
<text x="181.4" y="233.6">INTA</text>
<text x="181.4" y="228.5">RESET</text>
<text x="208.7" y="231.1">TXRDYB</text>
<text x="222" y="229.9">12</text>
<text x="174.3" y="235">32</text>
<text x="181.4" y="236.1">INTB</text>
<text x="213.2" y="236.1">TXB</text>
<text x="222" y="235">14</text>
<text x="174.3" y="242.6">18</text>
<text x="181.4" y="243.8">XTAL1</text>
<text x="211.6" y="243.8">CTSB</text>
<text x="212.8" y="241.2">CDB</text>
<text x="222" y="240.1">21</text>
<text x="222" y="242.6">28</text>
<text x="222" y="245.2">25</text>
<text x="211.4" y="246.3">DSRB</text>
<text x="213.8" y="248.8">RIB</text>
<text x="222" y="247.7">26</text>
<text x="141.3" y="255.3">14</text>
<text x="146.7" y="256.5">VCC</text>
<text x="153.7" y="255.2">NC/TS</text>
<text x="163.6" y="255.3">1</text>
<text x="174.3" y="257.9">19</text>
<text x="211.5" y="256.5">DTRB</text>
<text x="211.7" y="253.9">RTSB</text>
<text x="222" y="255.3">38</text>
<text x="222" y="252.8">27</text>
<text x="222" y="257.9">15</text>
<text x="65.1" y="263">13</text>
<text x="82.3" y="263">12</text>
<text x="142" y="263">7</text>
<text x="163.6" y="260.4">8</text>
<text x="164.2" y="263">11</text>
<text x="181.4" y="259">XTAL2</text>
<text x="211.7" y="259">OP2B</text>
<text x="142.5" y="265.5">4</text>
<text x="146.7" y="266.6">GND</text>
<text x="156.2" y="266.6">OUT</text>
</g>
<g font-size="1.8">
<text x="276" y="49.4">+</text>
<text x="333.4" y="52.1" transform="rotate(-90 333.4 52.1)">+</text>
<text x="276" y="59.6">+</text>
<text x="314.7" y="54.4">+</text>
<text x="319.1" y="57">+</text>
<text x="276" y="100.2">+</text>
<text x="314.7" y="105.2">+</text>
<text x="319.1" y="107.8">+</text>
<text x="333.4" y="102.9" transform="rotate(-90 333.4 102.9)">+</text>
<text x="276" y="110.4">+</text>
<text x="276" y="153.5">+</text>
<text x="314.7" y="158.5">+</text>
<text x="319.1" y="161.1">+</text>
<text x="333.4" y="156.2" transform="rotate(-90 333.4 156.2)">+</text>
<text x="276" y="163.7">+</text>
</g>
</g></defs>
<g fill="#000" stroke="#000" stroke-width=".21">
<path d="M67.8 18.2v3.9zM115.3 18.2v3.9zM162.7 18.2v3.9zM210.2 18.2v3.9zM257.6 18.2v3.9zM305.1 18.2v3.9zM352.5 18.2v3.9zM20.3 22.1v252.6zM20.3 22.1h379.7zM24.2 56.5h10.2zM26 41.3h8.4zM32 51.4h2.4z"/>
<path d="M32.6 46.3h1.8zM39.4 47.5h99zM39.4 52.5h93.9zM39.4 57.6h7.6zM39.4 42.4h40.6zM47 57.6v63.5zM47 57.6h175.2zM80 42.4h142.2zM133.3 52.5v48.3zM133.3 52.5h88.9zM138.4 47.5v48.2zM138.4 47.5h83.8z"/>
<path d="M223.7 46.3h1.8zM223.7 51.4h2.4zM223.7 56.5h10.2zM223.7 41.3h8.4zM267.9 50v5.1zM267.9 55.1h12.7zM270.5 50h2.5zM267.9 50h2.6zM275.6 50h2.5zM278.1 50h2.5zM280.6 50h5.1zM280.6 55.1h5.1z"/>
<path d="M306 52.5h5.1zM306 57.6h5.1zM311.1 52.5h2.6zM313.7 57.6h2.5zM313.7 52.5h2.5zM311.1 57.6h2.6zM318.7 57.6h2.6zM318.7 52.5h2.6zM321.3 52.5h5.1zM321.3 57.6h5.1zM326.4 44.9v2.6zM326.4 47.5v5z"/>
<path d="M326.4 57.6v2.6zM334 44.9v2.6zM334 55.1v2.5zM334 50v2.5zM334 47.5v2.5zM334 57.6v2.6zM364.4 57.6h2.6zM367 57.6h5.1zM372.1 57.6h2.5zM374.6 57.6v15.2zM16.5 72.6h3.8zM128.2 65.2v2.6z"/>
<path d="M128.2 70.3v2.5zM128.2 67.8v2.5zM153.6 67.8l2.6 2.5zM153.6 70.3l2.6 2.5zM153.6 72.8l2.6 2.6zM153.6 75.4l2.6 2.5zM153.6 77.9l2.6 2.6zM156.2 70.3h17.8zM156.2 72.8h17.8zM156.2 75.4h17.8zM156.2 77.9h17.8zM174 75.4h5z"/>
<path d="M174 70.3h5zM174 72.8h5zM174 77.9h5zM208.5 69.4h8.9zM208.7 79.5h8.7zM221.7 70.3h3.1zM219.7 75.4h5.1zM227.3 68.3h10.1zM227.3 78.4h9.8zM224.8 70.3h15.2zM224.8 75.4h15.2zM240 70.3l2.5 2.5z"/>
<path d="M240 75.4l2.5 2.5zM262.9 77.9l2.5-2.5zM262.9 72.8l2.5-2.5zM262.9 75.4l2.5-2.6zM265.4 75.4h15.2zM265.4 70.3h15.2zM265.4 77.9h15.2zM265.4 72.8h15.2zM267.9 60.2v5zM267.9 65.2h12.7zM270.5 75.9h6.4zM270.5 70.8h6.4z"/>
<path d="M270.5 60.2h2.5zM267.9 60.2h2.6zM275.6 60.2h2.5zM278.1 60.2h2.5zM280.6 60.2h5.1zM280.6 65.2h5.1zM280.6 70.3h5.1zM280.6 72.8h5.1zM280.6 75.4h5.1zM280.6 77.9h5.1zM306 70.3h5.1zM306 72.8h5.1z"/>
<path d="M306 75.4h5.1zM306 77.9h5.1zM311.1 70.3h15.3zM311.1 72.8h15.3zM311.1 75.4h15.3zM311.1 77.9h15.3zM326.4 60.2v2.5zM328.9 67.8l-2.5 2.5zM328.9 70.3l-2.5 2.5zM328.9 72.8l-2.5 2.6zM328.9 75.4l-2.5 2.5zM334 60.2v2.5z"/>
<path d="M344.1 62.7l2.6 2.5zM344.1 60.2l2.6 2.5zM354.3 72.8v2.6zM354.3 70.3v2.5zM356.8 60.2h5.1zM356.8 62.7h5.1zM356.8 65.2h5.1zM356.8 67.8h5.1zM356.8 70.3h5.1zM354.3 70.3h2.5zM346.7 65.2h10.1zM346.7 62.7h10.1z"/>
<path d="M364.4 72.8h2.6zM367 60.2h5.1zM367 62.7h5.1zM367 65.2h5.1zM367 67.8h5.1zM367 72.8h5.1zM372.1 72.8h2.5zM372.1 62.7h12.7zM372.1 65.2h12.7zM374.6 72.8h2.5zM377.1 72.8h2.6zM384.8 62.7l2.5-2.5z"/>
<path d="M384.8 65.2l2.5-2.5zM384.8 72.8h2.5zM389.8 75.4v2.5zM389.8 72.8v2.6zM387.3 72.8h2.5zM400 72.6h3.8zM80 42.4v43.1zM82.5 83.5h8.4zM92.7 85.5h5.1zM80 85.5h12.7zM109.9 85.5h3.1zM113 85.5h15.2z"/>
<path d="M128.2 77.9v2.6zM128.2 85.5v38.1zM128.2 80.5v5zM138.4 95.7v104.1zM153.6 80.5l2.6 2.5zM153.6 83l2.6 2.5zM153.6 85.5l2.6 2.6zM156.2 80.5h17.8zM156.2 83h17.8zM156.2 85.5h17.8zM156.2 88.1h17.8zM158.7 93.7h1.8z"/>
<path d="M158.7 98.8h2.4zM174 95.7h5zM174 85.5h5zM174 80.5h5zM174 83h5zM174 88.1h5zM138.4 95.7h35.6zM181.4 99.8h4.2zM181.4 94.8h3.8zM211.4 94.8h6zM211.6 92.2h5.8zM212.8 89.7h4.6z"/>
<path d="M213.8 97.3h3.6zM221.7 80.5h3.1zM221.7 90.6h3.1zM221.7 93.2h3.1zM221.7 95.7h3.1zM221.7 98.2h3.1zM219.7 85.5h5.1zM227.3 88.6h5zM227.3 91.1h6.4zM227.3 93.7h6.7zM227.3 96.2h3.9zM224.8 80.5h15.2z"/>
<path d="M224.8 85.5h15.2zM224.8 90.6h15.2zM224.8 93.2h15.2zM224.8 95.7h15.2zM224.8 98.2h15.2zM240 80.5l2.5 2.5zM240 85.5l2.5 2.6zM240 90.6l2.5 2.6zM240 93.2l2.5 2.5zM240 95.7l2.5 2.5zM262.9 80.5l2.5-2.6zM326.4 95.7v2.5z"/>
<path d="M334 95.7v2.5zM52.1 100.8l2.5 2.5zM52.1 113.5l2.5 2.5zM52.1 116l2.5 2.6zM52.1 103.3l2.5 2.6zM52.1 105.9l2.5 2.5zM54.6 103.3h15.2zM54.6 116h15.2zM54.6 118.6h15.2zM54.6 105.9h15.2zM54.6 108.4h15.2zM57.1 119.1h10.2z"/>
<path d="M69.8 103.3h5.1zM69.8 105.9h5.1zM69.8 108.4h5.1zM69.8 118.6h3.1zM69.8 116h5.1zM94.7 118.6h3.1zM94.7 116h3.1zM94.7 113.5h3.1zM94.7 110.9h3.1zM94.7 108.4h3.1zM94.7 105.9h3.1zM94.7 103.3h3.1z"/>
<path d="M97.8 113.5h20.3zM97.8 116h20.3zM97.8 118.6h20.3zM110.5 111.5h4.9zM110.5 114h4.9zM110.5 119.1h4.9zM110.5 116.5h4.9zM118.1 113.5l2.5 2.5zM118.1 116l2.5 2.6zM133.3 100.8v104.1zM143.5 103.3l2.5 2.6zM143.5 105.9l2.5 2.5z"/>
<path d="M146 105.9h28zM146 108.4h28zM148.6 110.9l2.5 2.6zM148.6 113.5l2.5 2.5zM148.6 116l2.5 2.6zM151.1 113.5h22.9zM151.1 116h22.9zM151.1 118.6h22.9zM158.7 103.8h4.9zM158.7 106.4h4.9zM174 113.5h5zM174 116h5z"/>
<path d="M174 118.6h5zM174 100.8h5zM174 105.9h3.1zM174 108.4h3.1zM133.3 100.8h40.7zM181.4 104.9h4.4zM181.4 107.5h4.4zM208.5 115.1h8.9zM211.6 104.9h5.8zM211.7 102.4h5.7zM211.7 107.5h5.7zM221.7 105.9h3.1z"/>
<path d="M221.7 103.3h3.1zM221.7 116h3.1zM221.7 108.4h3.1zM224.8 108.4h15.2zM227.3 114h10.1zM227.3 101.3h6.4zM227.3 103.8h6.5zM227.3 106.4h10.8zM224.8 116h15.2zM224.8 103.3h15.2zM224.8 105.9h15.2zM240 108.4l2.5 2.5z"/>
<path d="M240 116l2.5 2.6zM240 98.2l2.5 2.6zM240 103.3l2.5 2.6zM240 105.9l2.5 2.5zM267.9 100.8v5.1zM267.9 105.9h12.7zM267.9 110.9v5.1zM267.9 116h12.7zM270.5 100.8h2.5zM270.5 110.9h2.5zM267.9 100.8h2.6zM267.9 110.9h2.6z"/>
<path d="M275.6 100.8h2.5zM275.6 110.9h2.5zM278.1 100.8h2.5zM278.1 110.9h2.5zM280.6 100.8h5.1zM280.6 105.9h5.1zM280.6 110.9h5.1zM280.6 116h5.1zM306 103.3h5.1zM306 108.4h5.1zM311.1 103.3h2.6zM313.7 108.4h2.5z"/>
<path d="M313.7 103.3h2.5zM311.1 108.4h2.6zM318.7 108.4h2.6zM318.7 103.3h2.6zM321.3 103.3h5.1zM321.3 108.4h5.1zM326.4 110.9v2.6zM326.4 98.2v5.1zM326.4 108.4v2.5zM334 105.9v2.5zM334 100.8v2.5zM334 110.9v2.6z"/>
<path d="M334 98.2v2.6zM334 108.4v2.5zM344.1 113.5l2.6 2.5zM344.1 110.9l2.6 2.6zM356.8 110.9h5.1zM356.8 113.5h5.1zM356.8 116h5.1zM356.8 118.6h5.1zM346.7 116h10.1zM346.7 113.5h10.1zM364.4 108.4h2.6zM367 110.9h5.1z"/>
<path d="M367 113.5h5.1zM367 116h5.1zM367 118.6h5.1zM367 108.4h5.1zM372.1 108.4h2.5zM372.1 113.5h12.7zM372.1 116h12.7zM374.6 108.4v15.2zM387.3 110.9l-2.5 2.6zM387.3 113.5l-2.5 2.5zM16.5 123.1h3.8zM47 121.1h22.8z"/>
<path d="M69.8 121.1h3.1zM94.7 121.1h3.1zM97.8 121.1h20.3zM118.1 121.1l2.5 2.5zM118.1 118.6l2.5 2.5zM123.2 128.7v30.5zM125.7 131.3h48.3zM128.2 123.6v104.1zM171.4 138.9h2.6zM174 128.7h5zM174 138.9h5zM174 123.6h5z"/>
<path d="M174 131.3h5zM123.2 128.7h50.8zM128.2 123.6h45.8zM208.7 125.2h8.7zM211.6 137.9h5.8zM212.8 135.4h4.6zM221.7 126.2h3.1zM221.7 136.3h3.1zM221.7 138.9h3.1zM219.7 121.1h5.1zM219.7 131.3h5.1zM224.8 121.1h15.2z"/>
<path d="M224.8 126.2h15.2zM224.8 131.3h15.2zM224.8 136.3h15.2zM224.8 138.9h15.2zM227.3 124.2h9.8zM227.3 134.3h5zM227.3 136.9h6.4zM227.3 139.4h6.7zM240 121.1l2.5 2.5zM240 126.2l2.5 2.5zM240 131.3l2.5 2.5zM240 136.3l2.5 2.6z"/>
<path d="M240 138.9l2.5 2.5zM250.2 136.3v2.6zM262.9 128.7l2.5-2.5zM262.9 123.6l2.5-2.5zM262.9 131.3l2.5-2.6zM262.9 126.2l2.5-2.6zM265.4 126.2h15.2zM265.4 121.1h15.2zM265.4 128.7h15.2zM265.4 123.6h15.2zM270.5 126.7h6.4zM270.5 121.6h6.4z"/>
<path d="M280.6 121.1h5.1zM280.6 123.6h5.1zM280.6 126.2h5.1zM280.6 128.7h5.1zM306 121.1h5.1zM306 123.6h5.1zM306 126.2h5.1zM306 128.7h5.1zM311.1 121.1h15.3zM311.1 123.6h15.3zM311.1 126.2h15.3zM311.1 128.7h15.3z"/>
<path d="M328.9 118.6l-2.5 2.5zM328.9 121.1l-2.5 2.5zM328.9 123.6l-2.5 2.6zM328.9 126.2l-2.5 2.5zM354.3 123.6v2.6zM354.3 121.1v2.5zM356.8 121.1h5.1zM354.3 121.1h2.5zM364.4 123.6h2.6zM367 123.6h5.1zM372.1 123.6h2.5zM374.6 123.6h2.5z"/>
<path d="M377.1 123.6h2.6zM384.8 123.6h2.5zM389.8 126.2v2.5zM389.8 123.6v2.6zM387.3 123.6h2.5zM400 123.1h3.8zM21.8 147h9.9zM24.8 153h4.5zM34.3 154.1h12.7zM52.1 154.1l2.5 2.6zM52.1 156.7l2.5 2.5zM52.1 159.2l2.5 2.5z"/>
<path d="M54.6 156.7h12.7zM54.6 159.2h12.7zM59.7 154.6h5.8zM59.7 157.2h5.8zM59.7 159.7h5.8zM67.3 159.2h5.1zM67.3 156.7h5.1zM77.5 159.2h5zM77.5 156.7h5zM82.5 159.2h2.6zM82.5 156.7h2.6zM85.1 151.6v5.1z"/>
<path d="M85.1 156.7v2.5zM85.1 159.2v2.5zM85.1 151.6h5.1zM90.2 151.6v7.6zM90.2 159.2v15.2zM92.7 159.2h3.1zM90.2 159.2h2.5zM107.9 159.2h5.1zM113 159.2h2.6zM115.6 159.2h7.6zM115.6 159.2v17.8zM174 154.1h5z"/>
<path d="M211.4 140.5h6zM211.6 150.6h5.8zM211.7 148.1h5.7zM211.7 153.2h5.7zM213.8 143h3.6zM221.7 141.4h3.1zM221.7 151.6h3.1zM221.7 144h3.1zM221.7 149h3.1zM221.7 154.1h3.1zM224.8 141.4h15.2zM224.8 144h15.2z"/>
<path d="M224.8 149h15.2zM224.8 151.6h15.2zM224.8 154.1h15.2zM227.3 141.9h3.9zM227.3 147h6.4zM227.3 149.6h6.5zM227.3 152.1h10.8zM240 141.4l2.5 2.6zM240 144l2.5 2.5zM240 149l2.5 2.6zM240 151.6l2.5 2.5zM240 154.1l2.5 2.6z"/>
<path d="M250.2 151.6v2.5zM250.2 141.4v2.6zM250.2 146.5v2.5zM250.2 144v.5zM250.2 146v.5zM250.2 138.9v2.5zM250.2 149v2.6zM267.9 154.1v5.1zM267.9 159.2h12.7zM270.5 154.1h2.5zM267.9 154.1h2.6zM275.6 154.1h2.5z"/>
<path d="M278.1 154.1h2.5zM280.6 154.1h5.1zM280.6 159.2h5.1zM306 156.7h5.1zM311.1 156.7h2.6zM313.7 156.7h2.5zM318.7 156.7h2.6zM321.3 156.7h5.1zM326.4 149v2.6zM326.4 151.6v5.1zM334 149v2.6zM334 154.1v2.6z"/>
<path d="M334 151.6v2.5zM16.5 173.7h3.8zM47 154.1v22.9zM47 177v45.7zM52.1 161.7l2.5 2.6zM52.1 164.3l2.5 2.5zM52.1 166.8l2.5 2.6zM52.1 169.4l2.5 2.5zM52.1 171.9l2.5 2.5zM54.6 161.7h12.7zM54.6 164.3h12.7zM54.6 166.8h12.7z"/>
<path d="M54.6 169.4h12.7zM54.6 171.9h12.7zM54.6 174.4h12.7zM59.7 162.3h5.8zM59.7 164.8h5.8zM59.7 167.3h5.8zM59.7 169.9h5.8zM59.7 172.4h5.8zM59.7 175h4.4zM67.3 177h5.1zM67.3 174.4h5.1zM67.3 171.9h5.1z"/>
<path d="M67.3 169.4h5.1zM67.3 166.8h5.1zM67.3 164.3h5.1zM67.3 161.7h5.1zM47 177h20.3zM77.5 177h5zM77.5 174.4h5zM77.5 171.9h5zM77.5 169.4h5zM77.5 166.8h5zM77.5 164.3h5zM77.5 161.7h5z"/>
<path d="M82.5 174.4h2.6zM82.5 171.9h2.6zM82.5 169.4h2.6zM82.5 166.8h2.6zM82.5 164.3h2.6zM82.5 161.7h2.6zM82.5 177h2.6zM85.1 161.7v2.6zM85.1 164.3v2.5zM85.1 166.8v2.6zM85.1 169.4v2.5zM85.1 171.9v2.5z"/>
<path d="M85.1 174.4v2.6zM90.2 174.4h2.5zM92.7 174.4h3.1zM107.9 174.4h5.1zM115.6 177v2.5zM120.6 177v2.5zM113 174.4h7.6zM120.6 174.4v2.6zM125.7 131.3v43.1zM120.6 174.4h5.1zM153.6 171.9l2.6 2.5zM153.6 174.4l2.6 2.6z"/>
<path d="M153.6 177l2.6 2.5zM153.6 179.5l2.6 2.6zM156.2 174.4h17.8zM156.2 177h17.8zM156.2 179.5h17.8zM174 179.5h5zM174 174.4h5zM174 177h5zM208.5 173.5h8.9zM221.7 174.4h3.1zM219.7 179.5h5.1zM224.8 179.5h15.2z"/>
<path d="M227.3 172.4h10.1zM224.8 174.4h15.2zM240 179.5l2.5 2.6zM240 174.4l2.5 2.6zM262.9 177l2.5-2.6zM262.9 179.5l2.5-2.5zM265.4 174.4h15.2zM265.4 179.5h15.2zM265.4 177h15.2zM267.9 164.3v5.1zM267.9 169.4h12.7zM270.5 175h6.4z"/>
<path d="M270.5 164.3h2.5zM267.9 164.3h2.6zM275.6 164.3h2.5zM278.1 164.3h2.5zM280.6 164.3h5.1zM280.6 169.4h5.1zM280.6 174.4h5.1zM280.6 177h5.1zM280.6 179.5h5.1zM306 161.7h5.1zM306 174.4h5.1zM306 177h5.1z"/>
<path d="M306 179.5h5.1zM311.1 174.4h15.3zM311.1 179.5h15.3zM311.1 177h15.3zM313.7 161.7h2.5zM311.1 161.7h2.6zM318.7 161.7h2.6zM321.3 161.7h5.1zM326.4 164.3v2.5zM326.4 161.7v2.6zM328.9 171.9l-2.5 2.5zM328.9 177l-2.5 2.5z"/>
<path d="M328.9 174.4l-2.5 2.6zM334 159.2v2.5zM334 164.3v2.5zM334 161.7v2.6zM344.1 164.3l2.6 2.5zM344.1 166.8l2.6 2.6zM354.3 177v2.5zM354.3 174.4v2.6zM356.8 164.3h5.1zM356.8 166.8h5.1zM356.8 169.4h5.1zM356.8 171.9h5.1z"/>
<path d="M356.8 174.4h5.1zM354.3 174.4h2.5zM346.7 166.8h10.1zM346.7 169.4h10.1zM364.4 177h2.6zM364.4 161.7h2.6zM367 166.8h5.1zM367 169.4h5.1zM367 171.9h5.1zM367 174.4h5.1zM367 161.7h5.1zM367 177h5.1z"/>
<path d="M372.1 161.7h2.5zM372.1 177h2.5zM372.1 169.4h12.7zM372.1 171.9h12.7zM374.6 161.7v15.3zM374.6 177h2.5zM377.1 177h2.6zM384.8 169.4l2.5-2.6zM384.8 171.9l2.5-2.5zM384.8 177h2.5zM389.8 179.5v2.6zM389.8 177v2.5z"/>
<path d="M387.3 177h2.5zM400 173.7h3.8zM52.1 199.8l2.5 2.6zM85.1 197.3h5.1zM90.2 197.3v7.6zM115.6 184.6v2.5zM115.6 187.1v2.6zM115.6 189.7h2.5zM118.1 192.2v2.6zM118.1 189.7h2.5zM118.1 189.7v2.5zM120.6 184.6v2.5z"/>
<path d="M120.6 187.1v2.6zM138.4 199.8h35.6zM153.6 182.1l2.6 2.5zM153.6 184.6l2.6 2.5zM153.6 187.1l2.6 2.6zM153.6 189.7l2.6 2.5zM156.2 182.1h17.8zM156.2 184.6h17.8zM156.2 187.1h17.8zM156.2 189.7h17.8zM156.2 192.2h17.8zM158.7 197.8h1.8z"/>
<path d="M174 199.8h5zM174 189.7h5zM174 184.6h5zM174 182.1h5zM174 187.1h5zM174 192.2h5zM181.4 198.9h3.8zM208.7 183.7h8.7zM211.4 198.9h6zM211.6 196.4h5.8zM212.8 193.8h4.6zM221.7 184.6h3.1z"/>
<path d="M221.7 194.8h3.1zM221.7 197.3h3.1zM221.7 199.8h3.1zM219.7 189.7h5.1zM224.8 184.6h15.2zM224.8 189.7h15.2zM224.8 194.8h15.2zM224.8 197.3h15.2zM224.8 199.8h15.2zM227.3 182.6h9.8zM227.3 192.7h5zM227.3 195.3h6.4z"/>
<path d="M227.3 197.8h6.7zM240 184.6l2.5 2.5zM240 189.7l2.5 2.5zM240 194.8l2.5 2.5zM240 197.3l2.5 2.5zM240 199.8l2.5 2.6zM262.9 182.1l2.5-2.6zM262.9 184.6l2.5-2.5zM265.4 182.1h15.2zM270.5 180h6.4zM280.6 182.1h5.1zM306 182.1h5.1z"/>
<path d="M311.1 182.1h15.3zM328.9 179.5l-2.5 2.6zM351.7 192.2h30.5zM351.7 192.2v6.4zM382.2 192.2v6.4zM351.7 198.6h30.5zM52.1 202.4l2.5 2.5zM52.1 204.9l2.5 2.5zM52.1 207.4l2.5 2.6zM52.1 210l2.5 2.5zM52.1 212.5l2.5 2.5zM52.1 215l2.5 2.6z"/>
<path d="M52.1 217.6l2.5 2.5zM54.6 202.4h12.7zM54.6 204.9h12.7zM54.6 207.4h12.7zM54.6 210h12.7zM54.6 212.5h12.7zM54.6 215h12.7zM54.6 217.6h12.7zM59.7 200.4h5.8zM59.7 202.9h5.8zM59.7 205.4h5.8zM59.7 208h5.8z"/>
<path d="M59.7 210.5h5.8zM59.7 213h5.8zM59.7 215.6h5.8zM59.7 218.1h5.8zM67.3 217.6h5.1zM67.3 215h5.1zM67.3 212.5h5.1zM67.3 210h5.1zM67.3 207.4h5.1zM67.3 204.9h5.1zM67.3 202.4h5.1zM77.5 217.6h5z"/>
<path d="M77.5 215h5zM77.5 212.5h5zM77.5 210h5zM77.5 207.4h5zM77.5 204.9h5zM77.5 202.4h5zM82.5 204.9h2.6zM82.5 210h2.6zM82.5 215h2.6zM82.5 202.4h2.6zM85.1 197.3v5.1zM85.1 202.4v2.5z"/>
<path d="M85.1 204.9v2.5zM82.5 207.4h2.6zM85.1 207.4v2.6zM85.1 210v2.5zM82.5 212.5h2.6zM85.1 212.5v2.5zM85.1 215v2.6zM82.5 217.6h2.6zM85.1 217.6v2.5zM90.2 204.9v15.2zM95.2 204.9h3.1zM90.2 204.9h5z"/>
<path d="M110.5 204.9h5.1zM115.6 204.9h7.6zM133.3 204.9h40.7zM143.5 210l2.5 2.5zM143.5 207.4l2.5 2.6zM146 212.5h28zM146 210h28zM148.6 215l2.5 2.6zM148.6 217.6l2.5 2.5zM151.1 217.6h22.9zM158.7 202.9h2.4zM158.7 210.5h4.9z"/>
<path d="M158.7 208h4.9zM174 217.6h5zM174 204.9h5zM174 210h3.1zM174 212.5h3.1zM181.4 204h4.2zM181.4 209h4.4zM181.4 211.6h4.4zM208.5 219.2h8.9zM211.6 209h5.8zM211.7 206.5h5.7zM211.7 211.6h5.7z"/>
<path d="M213.8 201.4h3.6zM221.7 210h3.1zM221.7 202.4h3.1zM221.7 207.4h3.1zM221.7 212.5h3.1zM224.8 202.4h15.2zM224.8 207.4h15.2zM224.8 210h15.2zM224.8 212.5h15.2zM227.3 218.1h10.1zM227.3 200.4h3.9zM227.3 205.4h6.4z"/>
<path d="M227.3 208h6.5zM227.3 210.5h10.8zM240 202.4l2.5 2.5zM240 207.4l2.5 2.6zM240 210l2.5 2.5zM240 212.5l2.5 2.5zM262.9 217.6l2.5-2.6zM262.9 215l2.5-2.5zM265.4 215h22.9zM265.4 212.5h22.9zM262.9 212.5l2.5-2.5zM270.5 208h5z"/>
<path d="M270.5 218.1h6.4zM288.3 217.6h5zM288.3 215h5zM288.3 212.5h5zM288.3 210h5zM265.4 210h22.9zM16.5 224.2h3.8zM54.6 220.1h12.7zM59.7 220.7h4.4zM67.3 222.7h5.1zM67.3 220.1h5.1zM47 222.7h20.3z"/>
<path d="M77.5 222.7h5zM77.5 220.1h5zM82.5 220.1h2.6zM85.1 220.1v2.6zM82.5 222.7h2.6zM90.2 220.1h5zM95.2 220.1h3.1zM110.5 220.1h5.1zM118.1 237.9v2.5zM118.1 220.1v15.3zM115.6 220.1h2.5zM118.1 235.4v2.5z"/>
<path d="M123.2 237.9v2.5zM123.2 204.9v27.9zM123.2 232.8v5.1zM128.2 227.7h45.8zM148.6 220.1l2.5 2.6zM151.1 220.1h22.9zM151.1 222.7h22.9zM174 220.1h5zM174 222.7h5zM174 232.8h5zM174 227.7h5zM174 235.4h5z"/>
<path d="M123.2 232.8h50.8zM118.1 235.4h55.9zM208.7 229.4h8.7zM212.8 239.5h4.6zM221.7 220.1h3.1zM221.7 230.3h3.1zM219.7 225.2h5.1zM219.7 235.4h5.1zM224.8 225.2h15.2zM224.8 230.3h15.2zM224.8 235.4h15.2zM227.3 228.3h9.8z"/>
<path d="M227.3 238.4h5zM224.8 220.1h15.2zM240 225.2l2.5 2.5zM240 230.3l2.5 2.5zM240 235.4l2.5 2.5zM240 220.1l2.5 2.6zM262.9 222.7l2.5-2.6zM285.7 225.2v2.5zM285.7 222.7v2.5zM288.3 222.7h5zM288.3 220.1h5zM285.7 222.7h2.6z"/>
<path d="M265.4 220.1h22.9zM400 224.2h3.8zM29.2 253.1v2.6zM29.2 257.7v.5zM29.2 255.7v.5zM29.2 250.6v2.5zM39.4 245.5v2.6zM39.4 253.1v2.6zM39.4 257.7v.5zM39.4 255.7v.5zM29.2 250.6h10.2zM39.4 248.1v2.5z"/>
<path d="M39.4 250.6v2.5zM52.1 245.5v2.6zM52.1 253.1v2.6zM52.1 255.7v.5zM52.1 257.7v.5zM52.1 248.1v5zM118.1 245.5v2.6zM118.1 248.1v2.5zM118.1 250.6h2.5zM120.6 253.1v2.6zM120.6 250.6h2.6zM120.6 250.6v2.5z"/>
<path d="M123.2 245.5v2.6zM123.2 248.1v2.5zM128.2 250.6v2.5zM128.2 257v2.5zM128.2 259.5v.5zM128.2 255.7h12.7zM128.2 255.7v1.3zM128.2 253.1v2.6zM140.9 255.7h5.1zM149.8 257.6h2.6zM149.8 257.6v2.2zM156.2 255.7v2.5z"/>
<path d="M156.2 255.7h5.1zM161.3 255.7h5zM171.4 243h2.6zM171.4 138.9v104.1zM174 243h5zM174 258.2h5zM211.4 244.6h6zM211.6 254.8h5.8zM211.6 242.1h5.8zM211.7 252.2h5.7zM211.7 257.3h5.7zM213.8 247.1h3.6z"/>
<path d="M221.7 240.4h3.1zM221.7 243h3.1zM221.7 245.5h3.1zM221.7 255.7h3.1zM221.7 248.1h3.1zM221.7 253.1h3.1zM221.7 258.2h3.1zM224.8 240.4h15.2zM224.8 243h15.2zM224.8 245.5h15.2zM224.8 248.1h15.2zM224.8 253.1h15.2z"/>
<path d="M224.8 255.7h15.2zM224.8 258.2h15.2zM227.3 241h6.4zM227.3 243.5h6.7zM227.3 246.1h3.9zM227.3 251.1h6.4zM227.3 253.7h6.5zM227.3 256.2h10.8zM240 240.4l2.5 2.6zM240 243l2.5 2.5zM240 245.5l2.5 2.6zM240 248.1l2.5 2.5z"/>
<path d="M240 253.1l2.5 2.6zM240 255.7l2.5 2.5zM240 258.2l2.5 2.6zM250.2 255.7v2.5zM250.2 240.4v2.6zM250.2 245.5v2.6zM250.2 250.6v2.5zM250.2 248.1v.5zM250.2 250.1v.5zM250.2 243v2.5zM250.2 253.1v2.6zM20.3 274.7h379.7z"/>
<path d="M29.2 265.8v2.6zM29.2 258.2v2.6zM29.2 260.8v2.5zM29.2 263.3v2.5zM39.4 258.2v2.6zM29.2 263.3h10.2zM39.4 260.8v2.5zM52.1 265.8v2.6zM52.1 258.2v2.6zM52.1 260.8v5zM62.2 265.8v2.6zM62.2 263.3v2.5z"/>
<path d="M64.8 263.3h5zM62.2 263.3h2.6zM67.8 274.7v3.8zM82 263.3h3.1zM115.3 274.7v3.8zM128.2 268.4v2.5zM128.2 262v2.6zM128.2 261.5v.5zM128.2 265.8h10.2zM128.2 264.6v1.2zM128.2 265.8v2.6zM138.4 265.8h2.5z"/>
<path d="M138.4 263.3v2.5zM140.9 265.8h5.1zM140.9 263.3h2.6zM138.4 263.3h2.5zM143.5 263.3v2.5zM149.8 263.9h2.6zM149.8 261.8v2.1zM160 260.8h1.3zM162.7 274.7v3.8zM163.8 260.8v2.5zM161.3 260.8h5zM163.8 263.3h2.5z"/>
<path d="M166.3 263.3h5.1zM166.3 260.8h5.1zM171.4 243v17.8zM171.4 260.8v2.5zM210.2 274.7v3.8zM257.6 274.7v3.8zM305.1 274.7v3.8zM352.5 274.7v3.8zM400 264.5v.1zM400 268.4v6.2zM400 274.6h.1zM400 22.1v252.6z"/>
<path d="M360.6 57.3l.6-.4h.8l-.1 .4-.8 .1-.4 .4-.1 .5h-.4l.1-.5z" fill-rule="evenodd"/>
<path d="M360.2 72.2h.4l.1 .5 .4 .4 .8 .1 .1 .4a1.46 1.46 0 0 1-1.8-1.4z" fill-rule="evenodd"/>
<path d="M360.6 108l.6-.3h.8l-.1 .3-.5 .1-.5 .3-.3 .7h-.4l.1-.5z" fill-rule="evenodd"/>
<path d="M360.2 123h.4l.1 .5 .4 .3 .8 .2 .1 .4a1.46 1.46 0 0 1-1.8-1.4z" fill-rule="evenodd"/>
<path d="M360.2 176.3h.4l.1 .5 .4 .4 .8 .1 .1 .4a1.46 1.46 0 0 1-1.8-1.4z" fill-rule="evenodd"/>
<path d="M360.6 161.4l.6-.4h.8l-.1 .4-.8 .1-.4 .4-.1 .5h-.4l.1-.5z" fill-rule="evenodd"/>
<path d="M362 166.2l.7-.4h.1v.2a.76 .76 0 0 0-.8 .8 .76 .76 0 0 0 .8 .8v.2a1.03 1.03 0 0 1-.9-.5 1.03 1.03 0 0 1 .1-1.1z" fill-rule="evenodd"/>
<path d="M362 163.6l.7-.3h.1v.2a.76 .76 0 0 0-.8 .8 .76 .76 0 0 0 .8 .7v.3a1.03 1.03 0 0 1-.9-.6 1.03 1.03 0 0 1 .1-1.1z" fill-rule="evenodd"/>
<path d="M362 168.7l.7-.4h.1v.3a.76 .76 0 0 0-.8 .8 .76 .76 0 0 0 .8 .7v.3a1.03 1.03 0 0 1-.9-.6 1.03 1.03 0 0 1 .1-1.1z" fill-rule="evenodd"/>
<path d="M362 171.3l.7-.4h.1v.2a.76 .76 0 0 0-.8 .8 .76 .76 0 0 0 .8 .8v.2a1.03 1.03 0 0 1-.9-.6 1.03 1.03 0 0 1 .1-1z" fill-rule="evenodd"/>
<path d="M362 173.8l.7-.4h.1v.3a.76 .76 0 0 0-.8 .7 .76 .76 0 0 0 .8 .8v.2a1.03 1.03 0 0 1-.9-.5 1.03 1.03 0 0 1 .1-1.1z" fill-rule="evenodd"/>
<path d="M366 165.8a1.02 1.02 0 0 1 1 1 1.02 1.02 0 0 1-1 1v-.2a.76 .76 0 0 0 .7-.8 .76 .76 0 0 0-.7-.8z" fill-rule="evenodd"/>
<path d="M366 170.9a1.02 1.02 0 0 1 1 1 1.02 1.02 0 0 1-1 1v-.2a.76 .76 0 0 0 .7-.8 .76 .76 0 0 0-.7-.8z" fill-rule="evenodd"/>
<path d="M366 168.3a1.02 1.02 0 0 1 1 1.1 1.02 1.02 0 0 1-1 1v-.3a.76 .76 0 0 0 .7-.7 .76 .76 0 0 0-.7-.8z" fill-rule="evenodd"/>
<path d="M366 173.4a1.02 1.02 0 0 1 1 1 1.02 1.02 0 0 1-1 1v-.2a.76 .76 0 0 0 .7-.8 .76 .76 0 0 0-.7-.7z" fill-rule="evenodd"/>
<path d="M367.6 162.2h.1a1.51 1.51 0 0 1 1 1.4h-.4v-.2a1.01 1.01 0 0 0-.8-.8z" fill-rule="evenodd"/>
<circle cx="47" cy="57.6" r=".51"/>
<circle cx="80" cy="42.4" r=".51"/>
<circle cx="133.3" cy="52.5" r=".51"/>
<circle cx="138.4" cy="47.5" r=".51"/>
<circle cx="374.6" cy="72.8" r=".51"/>
<circle cx="128.2" cy="85.5" r=".51"/>
<circle cx="138.4" cy="95.7" r=".51"/>
<circle cx="133.3" cy="100.8" r=".51"/>
<circle cx="128.2" cy="123.6" r=".51"/>
<circle cx="374.6" cy="123.6" r=".51"/>
<circle cx="85.1" cy="159.2" r=".51"/>
<circle cx="85.1" cy="156.7" r=".51"/>
<circle cx="90.2" cy="159.2" r=".51"/>
<circle cx="115.6" cy="159.2" r=".51"/>
<circle cx="47" cy="177" r=".51"/>
<circle cx="85.1" cy="161.7" r=".51"/>
<circle cx="85.1" cy="166.8" r=".51"/>
<circle cx="85.1" cy="164.3" r=".51"/>
<circle cx="85.1" cy="171.9" r=".51"/>
<circle cx="85.1" cy="169.4" r=".51"/>
<circle cx="85.1" cy="174.4" r=".51"/>
<circle cx="120.6" cy="174.4" r=".51"/>
<circle cx="374.6" cy="177" r=".51"/>
<circle cx="118.1" cy="189.7" r=".51"/>
<circle cx="85.1" cy="204.9" r=".51"/>
<circle cx="85.1" cy="202.4" r=".51"/>
<circle cx="85.1" cy="207.4" r=".51"/>
<circle cx="85.1" cy="210" r=".51"/>
<circle cx="85.1" cy="217.6" r=".51"/>
<circle cx="85.1" cy="212.5" r=".51"/>
<circle cx="85.1" cy="215" r=".51"/>
<circle cx="90.2" cy="204.9" r=".51"/>
<circle cx="85.1" cy="220.1" r=".51"/>
<circle cx="118.1" cy="235.4" r=".51"/>
<circle cx="123.2" cy="232.8" r=".51"/>
<circle cx="39.4" cy="250.6" r=".51"/>
<circle cx="120.6" cy="250.6" r=".51"/>
<circle cx="128.2" cy="255.7" r=".51"/>
<circle cx="171.4" cy="243" r=".51"/>
<circle cx="29.2" cy="263.3" r=".51"/>
<circle cx="128.2" cy="265.8" r=".51"/>
<circle cx="138.4" cy="265.8" r=".51"/>
<circle cx="171.4" cy="260.8" r=".51"/>
</g>
<g fill="#000" stroke="#000" stroke-width=".28">
<path d="M21.8 56.1v3zM23.7 40.9v3zM29.7 51v3.1zM30.3 45.9v3.1zM30.3 45.9h7.5zM30.3 49h7.5zM29.7 51h8.1zM29.7 54.1h8.1zM21.8 56.1h16zM21.8 59.1h16zM23.7 40.9h14.1zM23.7 43.9h14.1z"/>
<path d="M37.8 45.9l1.6 1.6zM39.4 47.5l-1.6 1.5zM37.8 51l1.6 1.5zM39.4 52.5l-1.6 1.6zM37.8 56.1l1.6 1.5zM39.4 57.6l-1.6 1.5zM37.8 40.9l1.6 1.5zM39.4 42.4l-1.6 1.5zM222.2 47.5l1.5-1.6zM222.2 47.5l1.5 1.5zM222.2 52.5l1.5-1.5zM222.2 52.5l1.5 1.6z"/>
<path d="M222.2 57.6l1.5-1.5zM222.2 57.6l1.5 1.5zM222.2 42.4l1.5-1.5zM222.2 42.4l1.5 1.5zM223.7 45.9h7.6zM223.7 49h7.6zM223.7 51h8.2zM223.7 54.1h8.2zM223.7 56.1h16.1zM223.7 59.1h16.1zM223.7 40.9h14.2zM223.7 43.9h14.2z"/>
<path d="M231.3 45.9v3.1zM231.9 51v3.1zM237.9 40.9v3zM239.8 56.1v3zM274.7 48.5v3zM274.7 51.5h.9zM274.7 58.6v3.1zM274.7 48.5h.9zM275.6 48.5v3zM274.7 58.6h.9zM275.6 58.6v3.1zM316.2 54.1h.9z"/>
<path d="M316.2 51v3.1zM317.1 51v3.1zM316.2 51h.9zM317.9 56.1v3zM317.9 59.1h.8zM317.9 56.1h.8zM318.7 56.1v3zM326.4 44.9l-1.3 1.9zM326.4 44.9l1.2 1.9zM332.4 53.4h3.1zM332.4 52.5v.9zM332.4 52.5h3.1z"/>
<path d="M334 44.9l-1.3 1.9zM334 44.9l1.2 1.9zM335.5 52.5v.9zM127.4 72.8v5.1zM128.2 65.2l-1.2 1.9zM129.1 72.8v5.1zM127.4 72.8h1.7zM127.4 77.9h1.7zM128.2 65.2l1.3 1.9zM179 65.2h40.7zM219.7 65.2v94zM274.7 61.7h.9z"/>
<path d="M324.5 62.7h3.7zM332.1 62.7h3.8zM352.4 75.4h3.8zM379.7 73.7h5.1zM379.7 71.9v1.8zM379.7 71.9h5.1zM384.8 71.9v1.8zM388.6 77.9h2.5zM388.6 77.9l1.2 1.3zM391.1 77.9l-1.3 1.3zM100.3 81.7v7.6zM274.7 99.2v3.1z"/>
<path d="M274.7 99.2h.9zM275.6 99.2v3.1zM326.4 95.7l-1.3 1.9zM326.4 95.7l1.2 1.9zM334 95.7l-1.3 1.9zM334 95.7l1.2 1.9zM274.7 102.3h.9zM274.7 109.4v3.1zM274.7 112.5h.9zM274.7 109.4h.9zM275.6 109.4v3.1zM316.2 104.8h.9z"/>
<path d="M316.2 101.8v3zM317.1 101.8v3zM316.2 101.8h.9zM317.9 106.9v3zM317.9 109.9h.8zM317.9 106.9h.8zM318.7 106.9v3zM324.5 113.5h3.7zM332.1 113.5h3.8zM332.4 104.2h3.1zM332.4 103.3v.9zM332.4 103.3h3.1z"/>
<path d="M335.5 103.3v.9zM250.2 136.3l-1.3 1.9zM250.2 136.3l1.2 1.9zM352.4 126.2h3.8zM379.7 124.5h5.1zM379.7 122.7v1.8zM379.7 122.7h5.1zM384.8 122.7v1.8zM388.6 128.7h2.5zM388.6 128.7l1.2 1.3zM391.1 128.7l-1.3 1.3zM22.5 152.6v3z"/>
<path d="M22.5 152.6h10.3zM22.5 155.6h10.3zM32.8 152.6l1.5 1.5zM34.3 154.1l-1.5 1.5zM179 65.2v94zM179 159.2h40.7zM248.3 154.1h3.8zM274.7 152.6v3zM274.7 155.6h.9zM274.7 152.6h.9zM275.6 152.6v3zM316.2 158.2h.9z"/>
<path d="M316.2 155.1v3.1zM317.1 155.1v3.1zM316.2 155.1h.9zM326.4 149l-1.3 1.9zM326.4 149l1.2 1.9zM332.4 157.5h3.1zM332.4 156.7v.8zM332.4 156.7h3.1zM334 149l-1.3 1.9zM334 149l1.2 1.9zM335.5 156.7v.8zM105.4 155.4v7.6z"/>
<path d="M105.4 170.6v7.6zM114.7 179.5h1.8zM116.5 179.5v5.1zM119.8 179.5v5.1zM119.8 179.5h1.7zM179 169.4h40.7zM219.7 169.4v93.9zM274.7 162.7v3.1zM274.7 165.8h.9zM274.7 162.7h.9zM275.6 162.7v3.1zM317.9 160.2v3.1z"/>
<path d="M317.9 163.3h.8zM317.9 160.2h.8zM318.7 160.2v3.1zM324.5 166.8h3.7zM332.1 166.8h3.8zM352.4 179.5h3.8zM379.7 177.9h5.1zM379.7 176.1v1.8zM379.7 176.1h5.1zM384.8 176.1v1.8zM114.7 179.5v5.1zM114.7 184.6h1.8z"/>
<path d="M116.2 194.8h3.8zM121.5 179.5v5.1zM119.8 184.6h1.7zM388.6 182.1h2.5zM388.6 182.1l1.2 1.2zM391.1 182.1l-1.3 1.2zM107.9 201.1v7.6zM107.9 216.3v7.6zM283.8 227.7h3.8zM39.4 245.5l-1.3 1.9zM39.4 245.5l1.2 1.9zM52.1 245.5l-1.3 1.9z"/>
<path d="M52.1 245.5l1.2 1.9zM72.4 259.5v7.6zM117.2 240.4v5.1zM117.2 240.4h1.8zM117.2 245.5h1.8zM118.7 255.7h3.8zM119 240.4v5.1zM122.3 240.4v5.1zM124.1 240.4v5.1zM122.3 240.4h1.8zM122.3 245.5h1.8zM128.2 250.6l-1.2 1.9z"/>
<path d="M128.2 250.6l1.3 1.9zM148.6 259.8h2.5zM248.3 258.2h3.8zM250.2 240.4l-1.3 2zM250.2 240.4l1.2 2zM313.7 249.3h86.3zM313.7 254.4h86.3zM313.7 259.5h58.4zM372.1 259.5h27.9zM372.1 259.5v5.1zM27.3 268.4h3.8zM50.2 268.4h3.8z"/>
<path d="M60.3 268.4h3.8zM126.3 270.9h3.9zM148.6 261.8h1.2zM148.8 260.4v.7zM148.8 260.4h2.1zM148.8 261.1h2.1zM149.8 261.8h1.3zM150.9 260.4v.7zM179 169.4v93.9zM179 263.3h40.7zM313.7 264.6h58.4zM313.7 269.7h86.3z"/>
<path d="M372.1 264.6h27.9zM400 268.4v1.3z"/>
</g>
<g fill="#000" stroke="#000" stroke-width=".61">
<path d="M20.3 22.1v252.6zM20.3 22.1h379.7zM361.8 60.2h1.2zM361.8 62.7h1.2zM361.8 65.2h1.2zM361.8 67.8h1.2zM361.9 70.3h1.3zM365.7 60.2h1.3zM365.7 62.7h1.3zM365.7 65.2h1.3zM365.7 67.8h1.3zM97.8 80.5l2.5 1.2z"/>
<path d="M97.8 80.5v10.1zM100.3 81.7l7.6 3.8zM97.8 90.6l2.5-1.3zM100.3 89.3l7.6-3.8zM361.8 110.9h1.2zM361.8 113.5h1.2zM361.8 116h1.2zM361.8 118.6h1.2zM365.7 110.9h1.3zM365.7 113.5h1.3zM365.7 116h1.3zM365.7 118.6h1.3z"/>
<path d="M361.9 121.1h1.3zM72.4 159.2h1.3zM72.4 156.7h1.3zM76.2 159.2h1.3zM76.2 156.7h1.3zM97.8 159.2l7.6-3.8zM105.4 155.4l2.5-1.3zM107.9 154.1v10.2zM72.4 171.9h1.3zM72.4 174.4h1.3zM72.4 177h1.3zM72.4 166.8h1.3z"/>
<path d="M72.4 169.4h1.3zM72.4 161.7h1.3zM72.4 164.3h1.3zM76.2 171.9h1.3zM76.2 174.4h1.3zM76.2 177h1.3zM76.2 166.8h1.3zM76.2 169.4h1.3zM76.2 161.7h1.3zM76.2 164.3h1.3zM97.8 174.4l7.6-3.8zM97.8 159.2l7.6 3.8z"/>
<path d="M97.8 174.4l7.6 3.8zM105.4 170.6l2.5-1.2zM105.4 163l2.5 1.3zM105.4 178.2l2.5 1.3zM107.9 169.4v10.1zM110.5 199.8v10.2zM72.4 217.6h1.3zM72.4 212.5h1.3zM72.4 215h1.3zM72.4 204.9h1.3zM72.4 207.4h1.3zM72.4 210h1.3z"/>
<path d="M72.4 202.4h1.3zM76.2 217.6h1.3zM76.2 212.5h1.3zM76.2 215h1.3zM76.2 204.9h1.3zM76.2 207.4h1.3zM76.2 210h1.3zM76.2 202.4h1.3zM100.3 204.9l7.6-3.8zM100.3 204.9l7.6 3.8zM107.9 201.1l2.6-1.3zM107.9 216.3l2.6-1.3z"/>
<path d="M107.9 208.7l2.6 1.3zM110.5 215v10.2zM293.3 217.6h1.3zM293.3 212.5h1.3zM293.3 215h1.3zM293.3 210h1.3zM72.4 220.1h1.3zM72.4 222.7h1.3zM76.2 220.1h1.3zM76.2 222.7h1.3zM100.3 220.1l7.6-3.8zM100.3 220.1l7.6 3.8z"/>
<path d="M107.9 223.9l2.6 1.3zM293.3 220.1h1.3zM293.3 222.7h1.3zM69.8 258.2l2.6 1.3zM72.4 259.5l7.6 3.8zM146 253.1v15.3zM146 253.1h15.3zM161.3 253.1v2.6zM283.2 244.3v30.4zM313.7 254.4v5.1zM313.7 249.3v5.1zM313.7 244.3v5z"/>
<path d="M313.7 244.3h86.3zM283.2 244.3h30.5zM400 254.4v5.1zM400 249.3v5.1zM400 244.3v5zM400 22.1v222.2zM20.3 274.7h262.9zM69.8 258.2v10.2zM69.8 268.4l2.6-1.3zM72.4 267.1l7.6-3.8zM146 268.4h15.3zM161.3 260.8v7.6z"/>
<path d="M161.3 255.7v5.1zM283.2 274.7h30.5zM313.7 274.7h86.3zM313.7 269.7v5zM313.7 264.6v5.1zM313.7 259.5v5.1zM400 268.4v6.3zM400 264.6v3.8zM400 259.5v5.1z"/>
</g>
<g fill="#000" stroke="#000" stroke-width=".42">
<path d="M285.7 47.5h20.3zM285.7 47.5v33zM360.4 58.3v13.9zM361.9 57l2.5 .6zM364.4 57.6l3.1 .7zM368.5 59.5v11.4zM361.9 73.4l2.5-.6zM364.4 72.8l3.1-.6zM285.7 98.2h20.3zM285.7 98.2v33.1zM306 47.5v33zM285.7 80.5h20.3z"/>
<path d="M74.9 100.8v22.8zM74.9 100.8h17.8zM360.4 109.1v13.9zM361.9 107.8l2.5 .6zM364.4 108.4l3.1 .7zM368.5 110.3v11.4zM74.9 123.6h17.8zM92.7 100.8v22.8zM306 98.2v33.1zM285.7 131.3h20.3zM361.9 124.2l2.5-.6zM364.4 123.6l3.1-.6z"/>
<path d="M71.1 154.1v25.4zM71.1 154.1h7.6zM285.7 151.6h20.3zM285.7 151.6v33zM71.1 179.5h7.6zM78.7 154.1v25.4zM360.4 162.4v13.9zM361.9 161.2l2.5 .5zM361.9 177.5l2.5-.5zM364.4 161.7l3.1 .7zM364.4 177l3.1-.7zM368.5 163.6v11.4z"/>
<path d="M71.1 199.8v25.4zM71.1 199.8h7.6zM306 151.6v33zM285.7 184.6h20.3zM297.2 207.4v17.8zM292.1 207.4h5.1zM71.1 225.2h7.6zM78.7 199.8v25.4zM292.1 225.2h5.1zM292.1 207.4v17.8zM339 220.1v10.2zM339 230.3v7.6z"/>
<path d="M339 237.9h55.9zM339 230.3h55.9zM394.9 230.3v7.6zM394.9 220.1v10.2zM339 220.1h55.9zM152.4 255.7l3.8 2.5zM152.4 255.7v1.9zM156.2 258.2l3.8 2.6zM152.4 263.9v1.9zM152.4 257.6v6.3zM152.4 265.8l7.6-5z"/>
</g>
<path d="M367.5 58.3l.7 .4 .3 .8M368.5 70.9l-.3 .8-.7 .5M367.5 109.1l.7 .4 .3 .8M368.5 121.7l-.3 .8-.7 .5M368.5 175l-.3 .8-.7 .5" fill="none" stroke="#000" stroke-width=".42"/>
<g fill="none" stroke="#000" stroke-width=".61">
<circle cx="364.4" cy="57.6" r=".25"/>
<circle cx="364.4" cy="72.8" r=".25"/>
<circle cx="364.4" cy="108.4" r=".25"/>
<circle cx="364.4" cy="123.6" r=".25"/>
<circle cx="364.4" cy="161.7" r=".25"/>
<circle cx="364.4" cy="177" r=".25"/>
</g>
<g fill="none" stroke="#000" stroke-width=".21">
<circle cx="220.7" cy="70.3" r="1"/>
<circle cx="108.9" cy="85.5" r=".99"/>
<circle cx="220.7" cy="90.6" r="1"/>
<circle cx="220.7" cy="93.2" r="1"/>
<circle cx="220.7" cy="98.2" r="1"/>
<circle cx="220.7" cy="95.7" r="1"/>
<circle cx="220.7" cy="80.5" r="1"/>
<circle cx="73.9" cy="118.6" r=".99"/>
<circle cx="93.7" cy="118.6" r=".99"/>
<circle cx="93.7" cy="116" r=".99"/>
<circle cx="93.7" cy="110.9" r=".99"/>
<circle cx="93.7" cy="103.3" r=".99"/>
<circle cx="93.7" cy="113.5" r=".99"/>
<circle cx="93.7" cy="105.9" r=".99"/>
<circle cx="93.7" cy="108.4" r=".99"/>
<circle cx="178.1" cy="108.4" r=".99"/>
<circle cx="178.1" cy="105.9" r=".99"/>
<circle cx="220.7" cy="105.9" r="1"/>
<circle cx="220.7" cy="108.4" r="1"/>
<circle cx="220.7" cy="103.3" r="1"/>
<circle cx="220.7" cy="116" r="1"/>
<circle cx="73.9" cy="121.1" r=".99"/>
<circle cx="93.7" cy="121.1" r=".99"/>
<circle cx="220.7" cy="136.3" r="1"/>
<circle cx="220.7" cy="138.9" r="1"/>
<circle cx="220.7" cy="126.2" r="1"/>
<circle cx="96.8" cy="159.2" r=".99"/>
<circle cx="220.7" cy="154.1" r="1"/>
<circle cx="220.7" cy="149" r="1"/>
<circle cx="220.7" cy="141.4" r="1"/>
<circle cx="220.7" cy="151.6" r="1"/>
<circle cx="220.7" cy="144" r="1"/>
<circle cx="96.8" cy="174.4" r=".99"/>
<circle cx="220.7" cy="174.4" r="1"/>
<circle cx="220.7" cy="194.8" r="1"/>
<circle cx="220.7" cy="199.8" r="1"/>
<circle cx="220.7" cy="197.3" r="1"/>
<circle cx="220.7" cy="184.6" r="1"/>
<circle cx="99.3" cy="204.9" r=".99"/>
<circle cx="178.1" cy="212.5" r=".99"/>
<circle cx="178.1" cy="210" r=".99"/>
<circle cx="220.7" cy="212.5" r="1"/>
<circle cx="220.7" cy="202.4" r="1"/>
<circle cx="220.7" cy="207.4" r="1"/>
<circle cx="220.7" cy="210" r="1"/>
<circle cx="99.3" cy="220.1" r=".99"/>
<circle cx="220.7" cy="230.3" r="1"/>
<circle cx="220.7" cy="220.1" r="1"/>
<circle cx="220.7" cy="258.2" r="1"/>
<circle cx="220.7" cy="255.7" r="1"/>
<circle cx="220.7" cy="243" r="1"/>
<circle cx="220.7" cy="240.4" r="1"/>
<circle cx="220.7" cy="253.1" r="1"/>
<circle cx="220.7" cy="248.1" r="1"/>
<circle cx="220.7" cy="245.5" r="1"/>
<circle cx="81" cy="263.3" r=".99"/>
<circle cx="143.5" cy="265.8" r=".15"/>
<circle cx="163.8" cy="260.8" r=".15"/>
</g>
<g fill="#000" stroke="#000" stroke-width=".21">
<path d="M273 48.3h.9v3.3h-.9zM273 58.5h.9v3.3h-.9zM316.2 56h.9v3.3h-.9zM317.9 50.9h.8v3.3h-.8zM332.3 54.2h3.3v.9h-3.3zM273 99.1h.9v3.3h-.9zM273 109.3h.9v3.3h-.9zM316.2 106.7h.9v3.3h-.9zM317.9 101.7h.8v3.3h-.8zM332.3 105h3.3v.9h-3.3zM248.1 145.5h4.1v.5h-4.1zM248.1 144.5h4.1v.5h-4.1z"/>
<path d="M273 152.5h.9v3.3h-.9zM317.9 155h.8v3.3h-.8zM332.3 158.3h3.3v.9h-3.3zM273 162.6h.9v3.3h-.9zM316.2 160.1h.9v3.3h-.9zM369.5 220.1h25.4v10.2h-25.4zM27.2 256.2h4v.5h-4zM27.2 257.2h4v.5h-4zM37.3 256.2h4.1v.5h-4.1zM37.3 257.2h4.1v.5h-4.1zM50 257.2h4.1v.5h-4.1zM50 256.2h4.1v.5h-4.1z"/>
<path d="M248.1 249.6h4.1v.5h-4.1zM248.1 248.6h4.1v.5h-4.1zM126.2 260h4.1v.5h-4.1zM126.2 261h4.1v.5h-4.1z"/>
</g>
<path d="M16.5 18.2v260.3zM16.5 18.2h387.3zM16.5 278.5h387.3zM403.8 18.2v260.3z" fill="#000" stroke="#000" stroke-width=".32"/>
<g fill="#000" stroke="#000" stroke-width=".76">
<path d="M39.4 29.7h106.6zM39.4 34.8h7.6zM47 34.8h96.5zM47 34.8l5.1 5zM143.5 34.8l5.1 5zM146 29.7l7.6 7.6zM148.6 39.8v180.3zM153.6 37.3v152.4zM344.1 55.1v22.8zM346.7 52.5l-2.6 2.6zM346.7 52.5h38.1zM384.8 52.5l2.5 2.6z"/>
<path d="M387.3 55.1v7.6zM242.5 72.8v190.5zM262.9 72.8v190.5zM328.9 67.8v10.1zM328.9 77.9l2.5 2.6zM344.1 77.9l-2.5 2.6zM120.6 93.2v30.4zM123.2 90.6l-2.6 2.6zM123.2 90.6h17.7zM140.9 90.6l2.6 2.6zM331.4 80.5h10.2zM52.1 39.8v76.2z"/>
<path d="M143.5 93.2v10.1zM328.9 118.6v10.1zM344.1 105.9v22.8zM346.7 103.3l-2.6 2.6zM346.7 103.3h38.1zM384.8 103.3l2.5 2.6zM387.3 105.9v7.6zM328.9 128.7l2.5 2.6zM331.4 131.3h10.2zM344.1 128.7l-2.5 2.6zM34.3 149h15.2zM49.5 149l2.6 2.6z"/>
<path d="M52.1 151.6v22.8zM344.1 159.2v22.9zM346.7 156.7l-2.6 2.5zM346.7 156.7h38.1zM384.8 156.7l2.5 2.5zM387.3 159.2v10.2zM52.1 174.4v43.2zM328.9 171.9v10.2zM328.9 182.1l2.5 2.5zM331.4 184.6h10.2zM344.1 182.1l-2.5 2.5zM143.5 103.3v106.7z"/>
<path d="M242.5 263.3l2.6 2.5zM245.1 265.8h15.2zM262.9 263.3l-2.6 2.5z"/>
</g>
<use href="#words"/>
</svg>
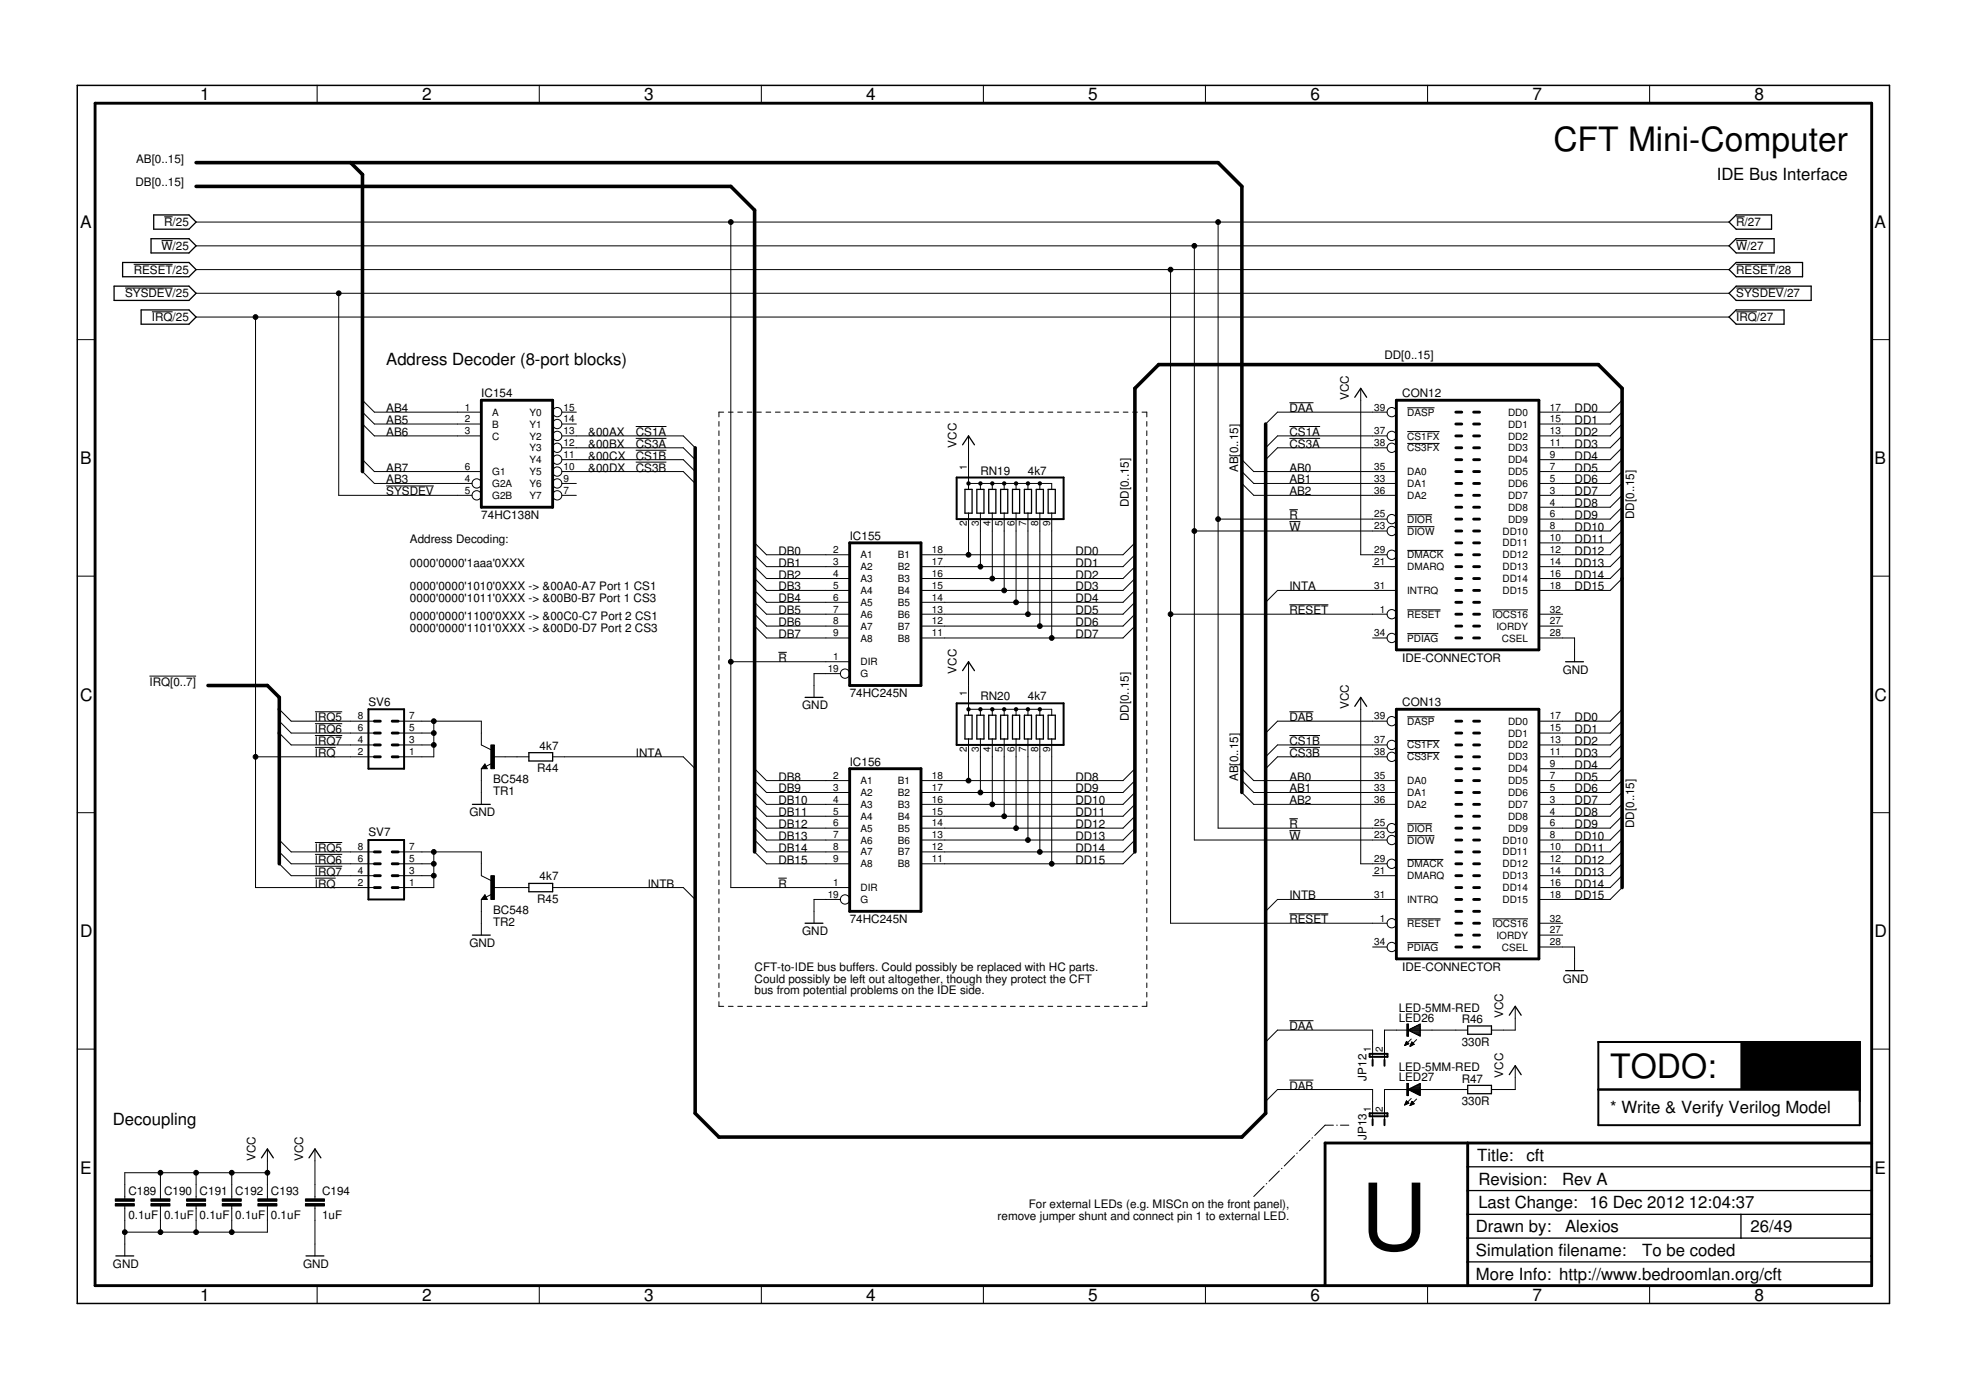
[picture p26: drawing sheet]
<svg xmlns="http://www.w3.org/2000/svg" width="420mm" height="297mm" viewBox="0 0 420 297" stroke-linecap="round" stroke-linejoin="round" font-family="sans-serif">
<defs><g id="words">
<text font-size="19.7" x="290.8" y="267.1">U</text>
<g font-size="7.2">
<text x="332" y="32.2">CFT Mini-Computer</text>
<text x="344.1" y="230.3">TODO:</text>
</g>
<g font-size="3.7">
<text x="42.7" y="21.5">1</text>
<text x="90.2" y="21.5">2</text>
<text x="137.7" y="21.5">3</text>
<text x="185.1" y="21.5">4</text>
<text x="232.6" y="21.5">5</text>
<text x="280" y="21.5">6</text>
<text x="327.5" y="21.5">7</text>
<text x="375" y="21.5">8</text>
<text x="17.1" y="48.6">A</text>
<text x="400.6" y="48.6">A</text>
<text x="17.1" y="99.2">B</text>
<text x="400.6" y="99.2">B</text>
<text x="17.1" y="149.7">C</text>
<text x="400.6" y="149.7">C</text>
<text x="17.1" y="200.2">D</text>
<text x="400.6" y="200.2">D</text>
<text x="17.1" y="250.8">E</text>
<text x="400.6" y="250.8">E</text>
<text x="42.7" y="277.9">1</text>
<text x="90.2" y="277.9">2</text>
<text x="137.7" y="277.9">3</text>
<text x="185.1" y="277.9">4</text>
<text x="232.6" y="277.9">5</text>
<text x="280" y="277.9">6</text>
<text x="327.5" y="277.9">7</text>
<text x="375" y="277.9">8</text>
</g>
<g font-size="3.6">
<text x="366.9" y="38.6">IDE Bus Interface</text>
<text x="82.5" y="77.9">Address Decoder (8-port blocks)</text>
<text x="344.1" y="237.9">* Write &amp; Verify Verilog Model</text>
<text x="24.1" y="240.5">Decoupling</text>
<text x="315.7" y="248.1">Title:</text>
<text x="326.2" y="248.2">cft</text>
<text x="315.9" y="253.2">Revision:</text>
<text x="333.8" y="253.3">Rev A</text>
<text x="315.4" y="263.3">Drawn by:</text>
<text x="315.9" y="258.2">Last Change: 16 Dec 2012</text>
<text x="334.5" y="263.3">Alexios</text>
<text x="361" y="258.1">12:04:37</text>
<text x="374.1" y="263.2">26/49</text>
<text x="315.4" y="268.4">Simulation filename:</text>
<text x="351" y="268.4">To be coded</text>
<text x="315.4" y="273.5">More Info: http://www.bedroomlan.org/cft</text>
</g>
<g font-size="2.5">
<text x="29.1" y="34.7">AB[0..15]</text>
<text x="29" y="39.8">DB[0..15]</text>
<text x="34.5" y="53.4">W/25</text>
<text x="35.1" y="48.3">R/25</text>
<text x="371" y="53.4">W/27</text>
<text x="371" y="48.3">R/27</text>
<text x="28.6" y="58.5">RESET/25</text>
<text x="371" y="58.5">RESET/28</text>
<text x="26.7" y="63.6">SYSDEV/25</text>
<text x="371" y="63.6">SYSDEV/27</text>
<text x="32.5" y="68.7">IRQ/25</text>
<text x="371" y="68.7">IRQ/27</text>
<text x="295.9" y="76.7">DD[0..15]</text>
<text x="82.5" y="88.1">AB4</text>
<text x="102.9" y="84.9">IC154</text>
<text x="275.6" y="88.1">DAA</text>
<text x="288.3" y="85.5" transform="rotate(-90 288.3 85.5)">VCC</text>
<text x="299.7" y="84.8">CON12</text>
<text x="336.5" y="88.1">DD0</text>
<text x="82.5" y="90.6">AB5</text>
<text x="82.5" y="93.2">AB6</text>
<text x="125.7" y="93.2">&amp;00AX</text>
<text x="125.7" y="95.7">&amp;00BX</text>
<text x="135.9" y="93.2">CS1A</text>
<text x="135.9" y="95.7">CS3A</text>
<text x="204.4" y="95.7" transform="rotate(-90 204.4 95.7)">VCC</text>
<text x="275.6" y="93.2">CS1A</text>
<text x="275.6" y="95.7">CS3A</text>
<text x="336.5" y="95.7">DD3</text>
<text x="336.5" y="93.2">DD2</text>
<text x="336.5" y="90.6">DD1</text>
<text x="82.5" y="100.8">AB7</text>
<text x="125.7" y="98.2">&amp;00CX</text>
<text x="125.7" y="100.8">&amp;00DX</text>
<text x="135.9" y="98.2">CS1B</text>
<text x="135.9" y="100.8">CS3B</text>
<text x="209.5" y="101.4">RN19</text>
<text x="219.7" y="101.4">4k7</text>
<text x="264.6" y="100.9" transform="rotate(-90 264.6 100.9)">AB[0..15]</text>
<text x="275.6" y="100.8">AB0</text>
<text x="336.5" y="100.8">DD5</text>
<text x="336.5" y="98.2">DD4</text>
<text x="82.5" y="105.9">SYSDEV</text>
<text x="82.5" y="103.3">AB3</text>
<text x="275.6" y="105.9">AB2</text>
<text x="275.6" y="103.3">AB1</text>
<text x="336.5" y="105.9">DD7</text>
<text x="336.5" y="103.3">DD6</text>
<text x="102.9" y="110.9">74HC138N</text>
<text x="241.3" y="108.4" transform="rotate(-90 241.3 108.4)">DD[0..15]</text>
<text x="275.6" y="113.5">W</text>
<text x="275.6" y="110.9">R</text>
<text x="336.5" y="108.4">DD8</text>
<text x="336.5" y="110.9">DD9</text>
<text x="336.5" y="113.5">DD10</text>
<text x="349.2" y="110.9" transform="rotate(-90 349.2 110.9)">DD[0..15]</text>
<text x="87.6" y="116">Address Decoding:</text>
<text x="166.4" y="118.6">DB0</text>
<text x="181.6" y="115.4">IC155</text>
<text x="229.8" y="118.6">DD0</text>
<text x="336.5" y="116">DD11</text>
<text x="336.5" y="118.6">DD12</text>
<text x="87.6" y="121.1">0000'0000'1aaa'0XXX</text>
<text x="166.4" y="121.1">DB1</text>
<text x="166.4" y="123.6">DB2</text>
<text x="229.8" y="123.6">DD2</text>
<text x="229.8" y="121.1">DD1</text>
<text x="336.5" y="121.1">DD13</text>
<text x="336.5" y="123.6">DD14</text>
<text x="87.6" y="126.2">0000'0000'1010'0XXX -&gt; &amp;00A0-A7 Port 1 CS1</text>
<text x="87.6" y="128.7">0000'0000'1011'0XXX -&gt; &amp;00B0-B7 Port 1 CS3</text>
<text x="166.4" y="126.2">DB3</text>
<text x="166.4" y="128.7">DB4</text>
<text x="166.4" y="131.3">DB5</text>
<text x="229.8" y="131.3">DD5</text>
<text x="229.8" y="128.7">DD4</text>
<text x="229.8" y="126.2">DD3</text>
<text x="275.6" y="126.2">INTA</text>
<text x="275.6" y="131.3">RESET</text>
<text x="336.5" y="126.2">DD15</text>
<text x="87.6" y="132.5">0000'0000'1100'0XXX -&gt; &amp;00C0-C7 Port 2 CS1</text>
<text x="87.6" y="135.1">0000'0000'1101'0XXX -&gt; &amp;00D0-D7 Port 2 CS3</text>
<text x="166.4" y="133.8">DB6</text>
<text x="166.4" y="136.3">DB7</text>
<text x="229.8" y="136.3">DD7</text>
<text x="229.8" y="133.8">DD6</text>
<text x="166.4" y="141.4">R</text>
<text x="204.4" y="144" transform="rotate(-90 204.4 144)">VCC</text>
<text x="299.7" y="141.4">IDE-CONNECTOR</text>
<text x="334" y="144">GND</text>
<text x="31.9" y="146.5">IRQ[0..7]</text>
<text x="181.6" y="149">74HC245N</text>
<text x="209.5" y="149.7">RN20</text>
<text x="219.7" y="149.7">4k7</text>
<text x="67.3" y="154.1">IRQ5</text>
<text x="78.7" y="150.8">SV6</text>
<text x="171.4" y="151.6">GND</text>
<text x="241.3" y="154.1" transform="rotate(-90 241.3 154.1)">DD[0..15]</text>
<text x="275.6" y="154.1">DAB</text>
<text x="288.3" y="151.6" transform="rotate(-90 288.3 151.6)">VCC</text>
<text x="299.7" y="150.8">CON13</text>
<text x="336.5" y="154.1">DD0</text>
<text x="67.3" y="161.7">IRQ</text>
<text x="67.3" y="156.6">IRQ6</text>
<text x="67.3" y="159.2">IRQ7</text>
<text x="115.3" y="160.2">4k7</text>
<text x="135.9" y="161.7">INTA</text>
<text x="275.6" y="159.2">CS1B</text>
<text x="275.6" y="161.7">CS3B</text>
<text x="336.5" y="161.7">DD3</text>
<text x="336.5" y="159.2">DD2</text>
<text x="336.5" y="156.6">DD1</text>
<text x="105.4" y="167.3">BC548</text>
<text x="114.8" y="165">R44</text>
<text x="166.4" y="166.8">DB8</text>
<text x="181.6" y="163.6">IC156</text>
<text x="229.8" y="166.8">DD8</text>
<text x="264.6" y="166.9" transform="rotate(-90 264.6 166.9)">AB[0..15]</text>
<text x="275.6" y="166.8">AB0</text>
<text x="336.5" y="166.8">DD5</text>
<text x="336.5" y="164.3">DD4</text>
<text x="105.4" y="169.9">TR1</text>
<text x="166.4" y="171.9">DB10</text>
<text x="166.4" y="169.3">DB9</text>
<text x="229.8" y="169.3">DD9</text>
<text x="229.8" y="171.9">DD10</text>
<text x="275.6" y="171.9">AB2</text>
<text x="275.6" y="169.3">AB1</text>
<text x="336.5" y="171.9">DD7</text>
<text x="336.5" y="169.3">DD6</text>
<text x="78.7" y="178.7">SV7</text>
<text x="100.3" y="174.4">GND</text>
<text x="166.4" y="179.5">DB13</text>
<text x="166.4" y="177">DB12</text>
<text x="166.4" y="174.4">DB11</text>
<text x="229.8" y="174.4">DD11</text>
<text x="229.8" y="177">DD12</text>
<text x="229.8" y="179.5">DD13</text>
<text x="275.6" y="179.5">W</text>
<text x="275.6" y="177">R</text>
<text x="336.5" y="174.4">DD8</text>
<text x="336.5" y="177">DD9</text>
<text x="336.5" y="179.5">DD10</text>
<text x="349.2" y="177" transform="rotate(-90 349.2 177)">DD[0..15]</text>
<text x="67.3" y="182">IRQ5</text>
<text x="67.3" y="184.6">IRQ6</text>
<text x="166.4" y="184.6">DB15</text>
<text x="166.4" y="182">DB14</text>
<text x="229.8" y="182">DD14</text>
<text x="229.8" y="184.6">DD15</text>
<text x="336.5" y="182">DD11</text>
<text x="336.5" y="184.6">DD12</text>
<text x="67.3" y="189.7">IRQ</text>
<text x="67.3" y="187.1">IRQ7</text>
<text x="115.3" y="188.1">4k7</text>
<text x="138.4" y="189.7">INTB</text>
<text x="166.4" y="189.7">R</text>
<text x="336.5" y="187.1">DD13</text>
<text x="336.5" y="189.7">DD14</text>
<text x="105.4" y="195.3">BC548</text>
<text x="105.4" y="197.8">TR2</text>
<text x="114.8" y="192.9">R45</text>
<text x="181.6" y="197.3">74HC245N</text>
<text x="275.6" y="192.2">INTB</text>
<text x="275.6" y="197.3">RESET</text>
<text x="336.5" y="192.2">DD15</text>
<text x="100.3" y="202.4">GND</text>
<text x="171.4" y="199.8">GND</text>
<text x="161.3" y="207.4">CFT-to-IDE bus buffers. Could possibly be replaced with HC parts.</text>
<text x="161.3" y="210">Could possibly be left out altogether, though they protect the CFT</text>
<text x="299.7" y="207.4">IDE-CONNECTOR</text>
<text x="334" y="210">GND</text>
<text x="161.3" y="212.5">bus from potential problems on the IDE side.</text>
<text x="275.6" y="220.1">DAA</text>
<text x="298.9" y="216.2">LED-5MM-RED</text>
<text x="298.9" y="218.4">LED26</text>
<text x="312.4" y="218.6">R46</text>
<text x="321.3" y="217.6" transform="rotate(-90 321.3 217.6)">VCC</text>
<text x="312.4" y="223.4">330R</text>
<text x="275.6" y="232.8">DAB</text>
<text x="292.1" y="230.9" transform="rotate(-90 292.1 230.9)">JP12</text>
<text x="298.9" y="228.9">LED-5MM-RED</text>
<text x="298.9" y="231.1">LED27</text>
<text x="312.4" y="231.3">R47</text>
<text x="321.3" y="230.3" transform="rotate(-90 321.3 230.3)">VCC</text>
<text x="312.4" y="236.1">330R</text>
<text x="292.1" y="243.6" transform="rotate(-90 292.1 243.6)">JP13</text>
<text x="54.6" y="248.1" transform="rotate(-90 54.6 248.1)">VCC</text>
<text x="64.8" y="248.1" transform="rotate(-90 64.8 248.1)">VCC</text>
<text x="27.4" y="255.3">C189</text>
<text x="35" y="255.3">C190</text>
<text x="42.7" y="255.3">C191</text>
<text x="50.3" y="255.3">C192</text>
<text x="57.9" y="255.3">C193</text>
<text x="68.8" y="255.3">C194</text>
<text x="27.4" y="260.4">0.1uF</text>
<text x="35" y="260.4">0.1uF</text>
<text x="42.7" y="260.4">0.1uF</text>
<text x="50.3" y="260.4">0.1uF</text>
<text x="57.9" y="260.4">0.1uF</text>
<text x="68.8" y="260.4">1uF</text>
<text x="213.2" y="260.8">remove jumper shunt and connect pin 1 to external LED.</text>
<text x="219.9" y="258.2">For external LEDs (e.g. MISCn on the front panel),</text>
<text x="24.1" y="270.9">GND</text>
<text x="64.8" y="270.9">GND</text>
</g>
<g font-size="2.1">
<text x="99.3" y="87.7">1</text>
<text x="105.2" y="88.8">A</text>
<text x="113.2" y="88.8">Y0</text>
<text x="120.4" y="87.7">15</text>
<text x="293.7" y="87.7">39</text>
<text x="300.8" y="88.8">DASP</text>
<text x="322.3" y="88.8">DD0</text>
<text x="331.2" y="87.7">17</text>
<text x="99.3" y="90.3">2</text>
<text x="99.3" y="92.8">3</text>
<text x="105.2" y="91.4">B</text>
<text x="105.2" y="93.9">C</text>
<text x="113.2" y="93.9">Y2</text>
<text x="113.2" y="91.4">Y1</text>
<text x="120.4" y="95.3">12</text>
<text x="120.4" y="92.8">13</text>
<text x="120.4" y="90.3">14</text>
<text x="293.7" y="92.8">37</text>
<text x="293.7" y="95.3">38</text>
<text x="300.8" y="93.9">CS1FX</text>
<text x="322.3" y="91.4">DD1</text>
<text x="322.3" y="93.9">DD2</text>
<text x="331.2" y="90.3">15</text>
<text x="331.2" y="92.8">13</text>
<text x="331.2" y="95.3">11</text>
<text x="99.3" y="100.4">6</text>
<text x="105.2" y="101.5">G1</text>
<text x="113.2" y="101.5">Y5</text>
<text x="113.2" y="99">Y4</text>
<text x="113.2" y="96.5">Y3</text>
<text x="120.4" y="100.4">10</text>
<text x="120.4" y="97.9">11</text>
<text x="206.6" y="100.4" transform="rotate(-90 206.6 100.4)">1</text>
<text x="293.7" y="100.4">35</text>
<text x="300.8" y="96.5">CS3FX</text>
<text x="300.8" y="101.5">DA0</text>
<text x="322.3" y="96.5">DD3</text>
<text x="322.3" y="99">DD4</text>
<text x="322.3" y="101.5">DD5</text>
<text x="331.2" y="97.9">9</text>
<text x="331.2" y="100.4">7</text>
<text x="99.3" y="103">4</text>
<text x="99.3" y="105.5">5</text>
<text x="105.2" y="104.1">G2A</text>
<text x="105.2" y="106.6">G2B</text>
<text x="113.2" y="106.6">Y7</text>
<text x="113.2" y="104.1">Y6</text>
<text x="120.4" y="105.5">7</text>
<text x="120.4" y="103">9</text>
<text x="293.7" y="103">33</text>
<text x="293.7" y="105.5">36</text>
<text x="300.8" y="104.1">DA1</text>
<text x="300.8" y="106.6">DA2</text>
<text x="322.3" y="104.1">DD6</text>
<text x="322.3" y="106.6">DD7</text>
<text x="331.2" y="103">5</text>
<text x="331.2" y="105.5">3</text>
<text x="206.6" y="112.5" transform="rotate(-90 206.6 112.5)">2</text>
<text x="209.2" y="112.5" transform="rotate(-90 209.2 112.5)">3</text>
<text x="211.7" y="112.5" transform="rotate(-90 211.7 112.5)">4</text>
<text x="214.2" y="112.5" transform="rotate(-90 214.2 112.5)">5</text>
<text x="216.8" y="112.5" transform="rotate(-90 216.8 112.5)">6</text>
<text x="219.3" y="112.5" transform="rotate(-90 219.3 112.5)">7</text>
<text x="221.9" y="112.5" transform="rotate(-90 221.9 112.5)">8</text>
<text x="224.4" y="112.5" transform="rotate(-90 224.4 112.5)">9</text>
<text x="293.7" y="110.6">25</text>
<text x="293.7" y="113.1">23</text>
<text x="300.8" y="111.7">DIOR</text>
<text x="322.3" y="109.2">DD8</text>
<text x="322.3" y="111.7">DD9</text>
<text x="331.2" y="108">4</text>
<text x="331.2" y="110.6">6</text>
<text x="331.2" y="113.1">8</text>
<text x="178.1" y="118.2">2</text>
<text x="183.9" y="119.3">A1</text>
<text x="191.9" y="119.3">B1</text>
<text x="199.2" y="118.2">18</text>
<text x="293.7" y="118.2">29</text>
<text x="300.8" y="114.2">DIOW</text>
<text x="300.8" y="119.3">DMACK</text>
<text x="321.1" y="114.2">DD10</text>
<text x="321.1" y="116.8">DD11</text>
<text x="321.1" y="119.3">DD12</text>
<text x="331.2" y="115.7">10</text>
<text x="331.2" y="118.2">12</text>
<text x="178.1" y="120.7">3</text>
<text x="178.1" y="123.3">4</text>
<text x="178.1" y="125.8">5</text>
<text x="183.9" y="121.9">A2</text>
<text x="183.9" y="124.4">A3</text>
<text x="191.9" y="124.4">B3</text>
<text x="191.9" y="121.9">B2</text>
<text x="199.2" y="125.8">15</text>
<text x="199.2" y="123.3">16</text>
<text x="199.2" y="120.7">17</text>
<text x="293.7" y="120.7">21</text>
<text x="293.7" y="125.8">31</text>
<text x="300.8" y="121.9">DMARQ</text>
<text x="321.1" y="121.9">DD13</text>
<text x="321.1" y="124.4">DD14</text>
<text x="331.2" y="120.7">14</text>
<text x="331.2" y="123.3">16</text>
<text x="331.2" y="125.8">18</text>
<text x="178.1" y="128.4">6</text>
<text x="178.1" y="130.9">7</text>
<text x="183.9" y="126.9">A4</text>
<text x="183.9" y="129.5">A5</text>
<text x="191.9" y="129.5">B5</text>
<text x="191.9" y="126.9">B4</text>
<text x="199.2" y="130.9">13</text>
<text x="199.2" y="128.4">14</text>
<text x="294.9" y="130.9">1</text>
<text x="300.8" y="126.9">INTRQ</text>
<text x="321.1" y="126.9">DD15</text>
<text x="331.2" y="130.9">32</text>
<text x="178.1" y="133.4">8</text>
<text x="178.1" y="136">9</text>
<text x="183.9" y="132">A6</text>
<text x="183.9" y="134.6">A7</text>
<text x="183.9" y="137.1">A8</text>
<text x="191.9" y="137.1">B8</text>
<text x="191.9" y="134.6">B7</text>
<text x="191.9" y="132">B6</text>
<text x="199.2" y="136">11</text>
<text x="199.2" y="133.4">12</text>
<text x="293.7" y="136">34</text>
<text x="300.8" y="137.1">PDIAG</text>
<text x="300.8" y="132">RESET</text>
<text x="319" y="132">IOCS16</text>
<text x="319.8" y="134.6">IORDY</text>
<text x="321" y="137.1">CSEL</text>
<text x="331.2" y="133.4">27</text>
<text x="331.2" y="136">28</text>
<text x="176.9" y="143.6">19</text>
<text x="178.1" y="141.1">1</text>
<text x="183.9" y="142.2">DIR</text>
<text x="183.9" y="144.7">G</text>
<text x="206.6" y="148.7" transform="rotate(-90 206.6 148.7)">1</text>
<text x="76.5" y="153.8">8</text>
<text x="87.4" y="153.8">7</text>
<text x="293.7" y="153.8">39</text>
<text x="300.8" y="154.9">DASP</text>
<text x="322.3" y="154.9">DD0</text>
<text x="331.2" y="153.8">17</text>
<text x="76.5" y="161.4">2</text>
<text x="76.5" y="158.8">4</text>
<text x="76.5" y="156.3">6</text>
<text x="87.4" y="161.4">1</text>
<text x="87.4" y="158.8">3</text>
<text x="87.4" y="156.3">5</text>
<text x="206.6" y="160.7" transform="rotate(-90 206.6 160.7)">2</text>
<text x="209.2" y="160.7" transform="rotate(-90 209.2 160.7)">3</text>
<text x="211.7" y="160.7" transform="rotate(-90 211.7 160.7)">4</text>
<text x="214.2" y="160.7" transform="rotate(-90 214.2 160.7)">5</text>
<text x="216.8" y="160.7" transform="rotate(-90 216.8 160.7)">6</text>
<text x="219.3" y="160.7" transform="rotate(-90 219.3 160.7)">7</text>
<text x="221.9" y="160.7" transform="rotate(-90 221.9 160.7)">8</text>
<text x="224.4" y="160.7" transform="rotate(-90 224.4 160.7)">9</text>
<text x="293.7" y="158.8">37</text>
<text x="293.7" y="161.4">38</text>
<text x="300.8" y="159.9">CS1FX</text>
<text x="322.3" y="157.4">DD1</text>
<text x="322.3" y="160">DD2</text>
<text x="331.2" y="156.3">15</text>
<text x="331.2" y="158.8">13</text>
<text x="331.2" y="161.4">11</text>
<text x="178.1" y="166.5">2</text>
<text x="183.9" y="167.6">A1</text>
<text x="191.9" y="167.6">B1</text>
<text x="199.2" y="166.5">18</text>
<text x="293.7" y="166.5">35</text>
<text x="300.8" y="162.5">CS3FX</text>
<text x="300.8" y="167.6">DA0</text>
<text x="322.3" y="162.5">DD3</text>
<text x="322.3" y="165">DD4</text>
<text x="322.3" y="167.6">DD5</text>
<text x="331.2" y="163.9">9</text>
<text x="331.2" y="166.5">7</text>
<text x="178.1" y="169">3</text>
<text x="178.1" y="171.5">4</text>
<text x="183.9" y="170.1">A2</text>
<text x="183.9" y="172.6">A3</text>
<text x="191.9" y="172.6">B3</text>
<text x="191.9" y="170.1">B2</text>
<text x="199.2" y="171.5">16</text>
<text x="199.2" y="169">17</text>
<text x="293.7" y="169">33</text>
<text x="293.7" y="171.5">36</text>
<text x="300.8" y="170.1">DA1</text>
<text x="300.8" y="172.6">DA2</text>
<text x="322.3" y="170.1">DD6</text>
<text x="322.3" y="172.6">DD7</text>
<text x="331.2" y="169">5</text>
<text x="331.2" y="171.5">3</text>
<text x="178.1" y="174.1">5</text>
<text x="178.1" y="176.6">6</text>
<text x="178.1" y="179.1">7</text>
<text x="183.9" y="175.2">A4</text>
<text x="183.9" y="177.7">A5</text>
<text x="191.9" y="177.7">B5</text>
<text x="191.9" y="175.2">B4</text>
<text x="199.2" y="179.1">13</text>
<text x="199.2" y="176.6">14</text>
<text x="199.2" y="174.1">15</text>
<text x="293.7" y="176.6">25</text>
<text x="293.7" y="179.1">23</text>
<text x="300.8" y="177.7">DIOR</text>
<text x="322.3" y="175.2">DD8</text>
<text x="322.3" y="177.7">DD9</text>
<text x="331.2" y="174.1">4</text>
<text x="331.2" y="176.6">6</text>
<text x="331.2" y="179.1">8</text>
<text x="76.5" y="184.2">6</text>
<text x="76.5" y="181.7">8</text>
<text x="87.4" y="184.2">5</text>
<text x="87.4" y="181.7">7</text>
<text x="178.1" y="181.7">8</text>
<text x="178.1" y="184.2">9</text>
<text x="183.9" y="180.3">A6</text>
<text x="183.9" y="182.8">A7</text>
<text x="183.9" y="185.3">A8</text>
<text x="191.9" y="185.3">B8</text>
<text x="191.9" y="182.8">B7</text>
<text x="191.9" y="180.3">B6</text>
<text x="199.2" y="184.2">11</text>
<text x="199.2" y="181.7">12</text>
<text x="293.7" y="184.2">29</text>
<text x="300.8" y="180.3">DIOW</text>
<text x="300.8" y="185.3">DMACK</text>
<text x="321.1" y="180.3">DD10</text>
<text x="321.1" y="182.8">DD11</text>
<text x="321.1" y="185.3">DD12</text>
<text x="331.2" y="181.7">10</text>
<text x="331.2" y="184.2">12</text>
<text x="76.5" y="189.3">2</text>
<text x="76.5" y="186.8">4</text>
<text x="87.4" y="189.3">1</text>
<text x="87.4" y="186.8">3</text>
<text x="176.9" y="191.8">19</text>
<text x="178.1" y="189.3">1</text>
<text x="183.9" y="190.4">DIR</text>
<text x="293.7" y="186.8">21</text>
<text x="293.7" y="191.8">31</text>
<text x="300.8" y="187.9">DMARQ</text>
<text x="321.1" y="187.9">DD13</text>
<text x="321.1" y="190.4">DD14</text>
<text x="331.2" y="186.8">14</text>
<text x="331.2" y="189.3">16</text>
<text x="331.2" y="191.8">18</text>
<text x="183.9" y="193">G</text>
<text x="294.9" y="196.9">1</text>
<text x="300.8" y="193">INTRQ</text>
<text x="321.1" y="193">DD15</text>
<text x="331.2" y="196.9">32</text>
<text x="293.7" y="202">34</text>
<text x="300.8" y="203.1">PDIAG</text>
<text x="300.8" y="198">RESET</text>
<text x="319" y="198">IOCS16</text>
<text x="319.8" y="200.6">IORDY</text>
<text x="321" y="203.1">CSEL</text>
<text x="331.2" y="199.5">27</text>
<text x="331.2" y="202">28</text>
<text x="293" y="224.9" transform="rotate(-90 293 224.9)">1</text>
<text x="295.5" y="224.9" transform="rotate(-90 295.5 224.9)">2</text>
<text x="293" y="237.6" transform="rotate(-90 293 237.6)">1</text>
<text x="295.5" y="237.6" transform="rotate(-90 295.5 237.6)">2</text>
</g>
</g></defs>
<g fill="#000" stroke="#000" stroke-width=".21">
<path d="M67.8 18.2v3.9zM115.3 18.2v3.9zM162.7 18.2v3.9zM210.2 18.2v3.9zM257.6 18.2v3.9zM305.1 18.2v3.9zM352.5 18.2v3.9zM20.3 22.1v252.6zM20.3 22.1h379.7zM28.6 56.5h8.3zM34.5 51.4h2.4zM35.1 46.3h1.8z"/>
<path d="M41.9 52.5h213.3zM41.9 47.5h114.3zM156.2 47.5h104.1zM156.2 47.5v93.9zM41.9 57.6h208.3zM250.2 57.6h119.3zM255.2 52.5v61zM255.2 52.5h114.3zM260.3 47.5h109.2zM371 51.4h2.4zM371 46.3h1.8zM371 56.5h8.4z"/>
<path d="M16.5 72.6h3.8zM26.7 61.6h10.2zM32.5 66.6h4.4zM41.9 67.8h12.7zM41.9 62.7h30.5zM54.6 67.8h314.9zM72.4 62.7h297.1zM72.4 62.7v43.2zM371 66.6h4.5zM371 61.6h10.2zM400 72.6h3.8zM77.5 85.5l2.5 2.6z"/>
<path d="M77.5 88.1l2.5 2.5zM77.5 90.6l2.5 2.6zM80 88.1h17.8zM80 90.6h17.8zM80 93.2h17.8zM97.8 88.1h5.1zM97.8 90.6h5.1zM97.8 93.2h5.1zM120.1 98.2h3.1zM120.1 95.7h3.1zM120.1 93.2h3.1zM120.1 90.6h3.1z"/>
<path d="M120.1 88.1h3.1zM123.2 93.2h22.8zM123.2 95.7h22.8zM123.2 98.2h22.8zM135.9 91.1h6.5zM135.9 93.7h6.5zM135.9 96.2h6.5zM135.9 98.8h6.5zM146 93.2l2.6 2.5zM146 95.7l2.6 2.5zM146 98.2l2.6 2.6zM153.6 88.1v1z"/>
<path d="M153.6 90.1v1zM153.6 92.1v1zM153.6 94.1v1zM153.6 96.1v1zM153.6 98.1v1zM153.6 88.1h1.1zM155.7 88.1h1zM157.7 88.1h1zM159.7 88.1h1zM161.7 88.1h1zM163.7 88.1h1zM165.7 88.1h1z"/>
<path d="M167.7 88.1h1zM169.7 88.1h1zM171.7 88.1h1.1zM173.8 88.1h.9zM175.8 88.1h1zM177.8 88.1h1zM179.8 88.1h1zM181.8 88.1h1zM183.8 88.1h1zM185.8 88.1h1zM187.8 88.1h1zM189.8 88.1h1z"/>
<path d="M191.8 88.1h1zM193.8 88.1h1.1zM195.9 88.1h1zM197.9 88.1h1zM199.9 88.1h1zM201.9 88.1h1zM203.9 88.1h1zM205.9 88.1h1zM207 98.2v2.6zM207 93.2v2.5zM207 95.7v2.5zM207.9 88.1h1z"/>
<path d="M209.9 88.1h1zM211.9 88.1h1zM213.9 88.1h1zM215.9 88.1h1.1zM217.9 88.1h1.1zM220 88.1h1zM222 88.1h1zM224 88.1h1zM226 88.1h1zM228 88.1h1zM230 88.1h1zM232 88.1h1z"/>
<path d="M234 88.1h1zM236 88.1h1zM238 88.1h1.1zM240 88.1h1.1zM242.1 88.1h1zM245.1 98.1v1zM245.1 96.1v1zM245.1 94.1v1zM245.1 92.1v1zM245.1 90.1v1zM245.1 88.1v1zM244.1 88.1h1z"/>
<path d="M273 88.1l-2.5 2.5zM270.5 95.7l2.5-2.5zM273 95.7l-2.5 2.5zM275.6 86.1h5.1zM275.6 91.1h6.5zM275.6 93.7h6.5zM290.8 83v2.5zM293.3 93.2h3.1zM293.3 95.7h3.1zM293.3 88.1h3.1zM273 88.1h20.3zM273 93.2h20.3z"/>
<path d="M273 95.7h20.3zM300.8 92.2h6.9zM300.8 94.8h6.9zM300.8 87.1h5.8zM328.9 88.1h5.1zM328.9 90.6h5.1zM328.9 93.2h5.1zM328.9 95.7h5.1zM328.9 98.2h5.1zM334 98.2h10.1zM334 95.7h10.1zM334 93.2h10.1z"/>
<path d="M334 90.6h10.1zM334 88.1h10.1zM344.1 98.2l2.6-2.5zM344.1 95.7l2.6-2.5zM344.1 93.2l2.6-2.6zM344.1 90.6l2.6-2.5zM344.1 88.1l2.6-2.6zM77.5 98.2l2.5 2.6zM77.5 100.8l2.5 2.5zM82.5 103.8h10.2zM97.8 103.3h3.1zM97.8 105.9h3.1z"/>
<path d="M97.8 100.8h5.1zM72.4 105.9h25.4zM80 100.8h17.8zM80 103.3h17.8zM120.1 105.9h3.1zM120.1 103.3h3.1zM120.1 100.8h3.1zM123.2 100.8h22.8zM146 100.8l2.6 2.5zM153.6 100.1v1zM153.6 102.1v1zM153.6 104.1v1z"/>
<path d="M153.6 106.1v1zM153.6 108.1v1zM153.6 110.1v1zM153.6 112.1v1zM153.6 114.1v1zM153.6 116.1v1zM153.6 118.1v1zM161.3 116l2.5 2.6zM161.3 118.6l2.5 2.5zM163.8 118.6h12.7zM176.5 118.6h5.1zM196.8 118.6h5.1z"/>
<path d="M207 110.9v2.6zM207 109.7v1.2zM207 103.3v1.3zM207 103.3h2.5zM207 100.8v2.5zM201.9 118.6h5.1zM207 113.5v5.1zM209.5 110.9v2.6zM209.5 103.3v1.3zM209.5 103.3h2.6zM209.5 109.7v1.2zM209.5 113.5v7.6z"/>
<path d="M212.1 110.9v2.6zM212.1 103.3v1.3zM212.1 103.3h2.5zM212.1 109.7v1.2zM212.1 113.5v10.1zM214.6 110.9v2.6zM214.6 103.3v1.3zM214.6 103.3h2.5zM214.6 109.7v1.2zM214.6 113.5v12.7zM217.1 110.9v2.6zM217.1 103.3v1.3z"/>
<path d="M217.1 109.7v1.2zM217.1 103.3h2.6zM217.1 113.5v15.2zM219.7 110.9v2.6zM219.7 109.7v1.2zM219.7 103.3v1.3zM219.7 103.3h2.5zM219.7 113.5v17.8zM222.2 110.9v2.6zM222.2 103.3v1.3zM222.2 103.3h2.6zM222.2 109.7v1.2z"/>
<path d="M222.2 113.5v20.3zM224.8 110.9v2.6zM224.8 103.3v1.3zM224.8 109.7v1.2zM224.8 113.5v22.8zM207 118.6h33zM242.5 118.6l-2.5 2.5zM242.5 116l-2.5 2.6zM245.1 118.1v1zM245.1 116.1v1zM245.1 114.1v1zM245.1 112.1v1z"/>
<path d="M245.1 110.1v1zM245.1 108.1v1zM245.1 106.1v1zM245.1 104.1v1zM245.1 102.1v1zM245.1 100.1v1zM255.2 113.5h38.1zM255.2 113.5v66zM260.3 47.5v63.4zM260.3 110.9v66.1zM265.4 103.3l2.5 2.6zM265.4 100.8l2.5 2.5z"/>
<path d="M265.4 98.2l2.5 2.6zM275.6 111.5h2.3zM275.6 108.9h1.8zM290.8 85.5v33.1zM293.3 100.8h5.1zM293.3 103.3h5.1zM293.3 105.9h5.1zM293.3 110.9h3.1zM293.3 113.5h3.1zM293.3 118.6h3.1zM290.8 118.6h2.5zM260.3 110.9h33z"/>
<path d="M267.9 105.9h25.4zM267.9 103.3h25.4zM267.9 100.8h25.4zM300.8 110h5.3zM300.8 112.5h5.8zM300.8 117.6h7.7zM328.9 100.8h5.1zM328.9 103.3h5.1zM328.9 105.9h5.1zM328.9 108.4h5.1zM328.9 110.9h5.1zM328.9 113.5h5.1z"/>
<path d="M328.9 116h5.1zM328.9 118.6h5.1zM334 105.9h10.1zM334 103.3h10.1zM334 100.8h10.1zM344.1 105.9l2.6-2.6zM344.1 103.3l2.6-2.5zM344.1 100.8l2.6-2.6zM334 108.4h10.1zM334 110.9h10.1zM334 113.5h10.1zM334 116h10.1z"/>
<path d="M334 118.6h10.1zM346.7 105.9l-2.6 2.5zM344.1 110.9l2.6-2.5zM346.7 110.9l-2.6 2.6zM346.7 113.5l-2.6 2.5zM344.1 118.6l2.6-2.6zM346.7 118.6l-2.6 2.5zM16.5 123.1h3.8zM153.6 120.1v1zM153.6 122.1v1zM153.6 124.1v1zM153.6 126.1v1z"/>
<path d="M153.6 128.1v1zM153.6 130.1v1zM153.6 132.1v1zM153.6 134.1v1zM153.6 136.1v1zM153.6 138.1v1zM161.3 121.1l2.5 2.5zM161.3 123.6l2.5 2.6zM161.3 126.2l2.5 2.5zM161.3 128.7l2.5 2.6zM161.3 131.3l2.5 2.5zM161.3 133.8l2.5 2.5z"/>
<path d="M163.8 121.1h12.7zM163.8 123.6h12.7zM163.8 126.2h12.7zM163.8 128.7h12.7zM163.8 131.3h12.7zM163.8 133.8h12.7zM163.8 136.3h12.7zM166.3 139.4h1.8zM176.5 121.1h5.1zM176.5 123.6h5.1zM176.5 126.2h5.1zM176.5 128.7h5.1z"/>
<path d="M176.5 131.3h5.1zM176.5 133.8h5.1zM176.5 136.3h5.1zM196.8 136.3h5.1zM196.8 133.8h5.1zM196.8 131.3h5.1zM196.8 128.7h5.1zM196.8 126.2h5.1zM196.8 123.6h5.1zM196.8 121.1h5.1zM201.9 121.1h7.6zM201.9 123.6h10.2z"/>
<path d="M201.9 126.2h12.7zM201.9 128.7h15.2zM201.9 131.3h17.8zM201.9 133.8h20.3zM201.9 136.3h22.9zM224.8 136.3h15.2zM222.2 133.8h17.8zM219.7 131.3h20.3zM217.1 128.7h22.9zM214.6 126.2h25.4zM212.1 123.6h27.9zM209.5 121.1h30.5z"/>
<path d="M242.5 133.8l-2.5 2.5zM242.5 131.3l-2.5 2.5zM242.5 128.7l-2.5 2.6zM242.5 126.2l-2.5 2.5zM242.5 123.6l-2.5 2.6zM242.5 121.1l-2.5 2.5zM245.1 138.1v1zM245.1 136.1v1zM245.1 134.1v1zM245.1 132.1v1zM245.1 130.1v1zM245.1 128.1v1z"/>
<path d="M245.1 126.1v1zM245.1 124.1v1zM245.1 122.1v1zM245.1 120.1v1zM250.2 57.6v73.7zM250.2 131.3v66zM273 126.2l-2.5 2.5zM275.6 129.2h8.3zM293.3 121.1h5.1zM293.3 126.2h5.1zM293.3 136.3h3.1zM293.3 131.3h3.1z"/>
<path d="M273 126.2h20.3zM250.2 131.3h43.1zM300.8 135.4h6.6zM300.8 130.3h7.1zM319 130.3h7.6zM328.9 121.1h5.1zM328.9 123.6h5.1zM328.9 126.2h5.1zM328.9 131.3h5.1zM328.9 133.8h5.1zM328.9 136.3h5.1zM334 136.3h2.5z"/>
<path d="M336.5 138.9v2.5zM336.5 136.3v2.6zM334 121.1h10.1zM334 123.6h10.1zM334 126.2h10.1zM346.7 121.1l-2.6 2.5zM344.1 126.2l2.6-2.6zM400 123.1h3.8zM31.9 144.5h10zM59.7 151.6l2.5 2.5zM59.7 154.1l2.5 2.6zM59.7 156.7l2.5 2.5z"/>
<path d="M67.3 159.7h4.4zM67.3 152.1h5.8zM67.3 154.6h5.8zM67.3 157.2h5.8zM74.9 159.2h5.1zM74.9 156.7h5.1zM74.9 154.1h5.1zM62.2 154.1h12.7zM62.2 156.7h12.7zM62.2 159.2h12.7zM85.1 159.2h5.1zM85.1 156.7h5.1z"/>
<path d="M85.1 154.1h5.1zM90.2 156.7h2.5zM90.2 154.1h2.5zM92.7 154.1v2.6zM92.7 156.7v2.5zM90.2 159.2h2.5zM92.7 159.2v2.5zM102.9 156.7v2.5zM102.9 159.2l2 1zM92.7 154.1h10.2zM102.9 154.1v2.6zM153.6 140.1v1z"/>
<path d="M153.6 142.1v1zM153.6 144.1v1zM153.6 146.1v1zM153.6 148.1v1zM153.6 150.1v1zM153.6 152.1v1zM153.6 154.1v1zM153.6 156.1v1zM153.6 158.1v1zM156.2 141.4h20.3zM156.2 141.4v48.3zM174 146.5v2.5z"/>
<path d="M174 144v2.5zM176.5 141.4h5.1zM176.5 144h3.1zM174 144h2.5zM207 146.5v2.5zM207 157.9v1.3zM207 151.6v1.2zM207 151.6h2.5zM207 149v2.6zM207 141.4v2.6zM207 144v2.5zM209.5 151.6v1.2z"/>
<path d="M209.5 151.6h2.6zM209.5 157.9v1.3zM212.1 151.6v1.2zM212.1 151.6h2.5zM212.1 157.9v1.3zM214.6 151.6v1.2zM214.6 151.6h2.5zM214.6 157.9v1.3zM217.1 151.6v1.2zM217.1 157.9v1.3zM217.1 151.6h2.6zM219.7 157.9v1.3z"/>
<path d="M219.7 151.6v1.2zM219.7 151.6h2.5zM222.2 151.6v1.2zM222.2 151.6h2.6zM222.2 157.9v1.3zM224.8 151.6v1.2zM224.8 157.9v1.3zM245.1 158.1v1zM245.1 156.1v1zM245.1 154.1v1zM245.1 152.1v1zM245.1 150.1v1z"/>
<path d="M245.1 148.1v1zM245.1 146.1v1zM245.1 144.1v1zM245.1 142.1v1zM245.1 140.1v1zM273 154.1l-2.5 2.6zM273 159.2l-2.5 2.5zM275.6 152.1h5.1zM275.6 157.2h6.5zM275.6 159.7h6.5zM290.8 149v2.6zM293.3 159.2h3.1z"/>
<path d="M293.3 154.1h3.1zM273 154.1h20.3zM273 159.2h20.3zM300.8 158.3h6.9zM300.8 153.2h5.8zM328.9 154.1h5.1zM328.9 156.7h5.1zM328.9 159.2h5.1zM334 159.2h10.1zM334 156.7h10.1zM334 154.1h10.1zM344.1 159.2l2.6-2.5z"/>
<path d="M344.1 156.7l2.6-2.6zM344.1 154.1l2.6-2.5zM16.5 173.7h3.8zM54.6 67.8v93.9zM74.9 161.7h5.1zM54.6 161.7h20.3zM85.1 161.7h5.1zM90.2 161.7h2.5zM102.9 169.4v2.5zM102.9 164.3v2.5zM102.9 164.3h1.2zM102.9 166.8v2.6z"/>
<path d="M103.6 163.3l-.7 1zM103.9 163.8l1.2-.7zM103.6 163.3l.5 1zM105.4 161.7h2.5zM110.5 161.7h2.5zM107.9 161.7h2.6zM118.1 161.7h2.5zM120.6 161.7h25.4zM146 161.7l2.6 2.6zM153.6 160.1v1zM153.6 162.1v1zM153.6 164.1v1z"/>
<path d="M153.6 166.1v1zM153.6 168.1v1zM153.6 170.1v1zM153.6 172.1v1zM153.6 174.1v1zM153.6 176.1v1zM153.6 178.1v1zM161.3 179.5l2.5 2.6zM161.3 177l2.5 2.5zM161.3 174.4l2.5 2.6zM161.3 171.9l2.5 2.5zM161.3 169.4l2.5 2.5z"/>
<path d="M161.3 166.8l2.5 2.6zM161.3 164.3l2.5 2.5zM176.5 166.8h5.1zM176.5 169.4h5.1zM176.5 171.9h5.1zM176.5 174.4h5.1zM176.5 177h5.1zM176.5 179.5h5.1zM163.8 179.5h12.7zM163.8 177h12.7zM163.8 174.4h12.7zM163.8 171.9h12.7z"/>
<path d="M163.8 169.4h12.7zM163.8 166.8h12.7zM196.8 179.5h5.1zM196.8 177h5.1zM196.8 174.4h5.1zM196.8 171.9h5.1zM196.8 169.4h5.1zM196.8 166.8h5.1zM207 159.2v2.5zM201.9 166.8h5.1zM207 161.7v5.1zM209.5 159.2v2.5z"/>
<path d="M201.9 169.4h7.6zM209.5 161.7v7.7zM212.1 159.2v2.5zM201.9 171.9h10.2zM212.1 161.7v10.2zM214.6 159.2v2.5zM201.9 174.4h12.7zM214.6 161.7v12.7zM217.1 159.2v2.5zM201.9 177h15.2zM217.1 161.7v15.3zM219.7 159.2v2.5z"/>
<path d="M201.9 179.5h17.8zM219.7 161.7v17.8zM222.2 159.2v2.5zM222.2 161.7v20.4zM224.8 159.2v2.5zM224.8 161.7v22.9zM207 166.8h33zM209.5 169.4h30.5zM212.1 171.9h27.9zM214.6 174.4h25.4zM217.1 177h22.9zM219.7 179.5h20.3z"/>
<path d="M242.5 164.3l-2.5 2.5zM242.5 166.8l-2.5 2.6zM242.5 169.4l-2.5 2.5zM242.5 171.9l-2.5 2.5zM242.5 174.4l-2.5 2.6zM242.5 177l-2.5 2.5zM242.5 179.5l-2.5 2.6zM245.1 178.1v1zM245.1 176.1v1zM245.1 174.1v1zM245.1 172.1v1zM245.1 170.1v1z"/>
<path d="M245.1 168.1v1zM245.1 166.1v1zM245.1 164.1v1zM245.1 162.1v1zM245.1 160.1v1zM255.2 179.5h38.1zM265.4 169.4l2.5 2.5zM265.4 166.8l2.5 2.6zM265.4 164.3l2.5 2.5zM273 161.7l-2.5 2.6zM275.6 177.5h2.3zM275.6 175h1.8z"/>
<path d="M293.3 161.7h3.1zM293.3 166.8h5.1zM293.3 169.4h5.1zM293.3 171.9h5.1zM293.3 177h3.1zM293.3 179.5h3.1zM260.3 177h33zM273 161.7h20.3zM267.9 171.9h25.4zM267.9 169.4h25.4zM267.9 166.8h25.4zM300.8 160.8h6.9z"/>
<path d="M300.8 176h5.3zM300.8 178.6h5.8zM328.9 161.7h5.1zM328.9 164.3h5.1zM328.9 166.8h5.1zM328.9 169.4h5.1zM328.9 171.9h5.1zM328.9 174.4h5.1zM328.9 177h5.1zM328.9 179.5h5.1zM334 171.9h10.1zM334 169.4h10.1z"/>
<path d="M334 166.8h10.1zM334 164.3h10.1zM334 161.7h10.1zM344.1 171.9l2.6-2.5zM344.1 169.4l2.6-2.6zM344.1 166.8l2.6-2.5zM344.1 164.3l2.6-2.6zM344.1 161.7l2.6-2.5zM334 174.4h10.1zM334 177h10.1zM334 179.5h10.1zM346.7 171.9l-2.6 2.5z"/>
<path d="M346.7 174.4l-2.6 2.6zM346.7 177l-2.6 2.5zM346.7 179.5l-2.6 2.6zM400 173.7h3.8zM54.6 161.7v28zM59.7 179.5l2.5 2.6zM59.7 182.1l2.5 2.5zM59.7 184.6l2.5 2.5zM67.3 187.7h4.4zM67.3 180h5.8zM67.3 182.6h5.8zM67.3 185.1h5.8z"/>
<path d="M74.9 189.7h5.1zM74.9 187.1h5.1zM74.9 184.6h5.1zM74.9 182.1h5.1zM54.6 189.7h20.3zM62.2 182.1h12.7zM62.2 184.6h12.7zM62.2 187.1h12.7zM85.1 189.7h5.1zM85.1 187.1h5.1zM85.1 184.6h5.1zM85.1 182.1h5.1z"/>
<path d="M90.2 184.6h2.5zM90.2 189.7h2.5zM90.2 182.1h2.5zM92.7 182.1v2.5zM92.7 184.6v2.5zM90.2 187.1h2.5zM92.7 187.1v2.6zM92.7 182.1h10.2zM102.9 197.3v2.5zM102.9 192.2v2.6zM102.9 184.6v2.5zM102.9 187.1l2 1z"/>
<path d="M102.9 192.2h1.2zM102.9 194.8v2.5zM102.9 182.1v2.5zM103.6 191.2l-.7 1zM103.9 191.7l1.2-.6zM103.6 191.2l.5 1zM105.4 189.7h2.5zM110.5 189.7h2.5zM107.9 189.7h2.6zM118.1 189.7h2.5zM120.6 189.7h25.4zM146 189.7l2.6 2.5z"/>
<path d="M153.6 180.1v1zM153.6 182.1v1zM153.6 184.1v1zM153.6 186.1v1zM153.6 188.1v1zM153.6 190.1v1zM153.6 192.1v1zM153.6 194.1v1zM153.6 196.1v1zM153.6 198.1v1zM156.2 189.7h20.3zM161.3 182.1l2.5 2.5z"/>
<path d="M163.8 184.6h12.7zM163.8 182.1h12.7zM166.3 187.7h1.8zM174 194.8v2.5zM174 192.2v2.6zM176.5 189.7h5.1zM176.5 182.1h5.1zM176.5 184.6h5.1zM176.5 192.2h3.1zM174 192.2h2.5zM196.8 184.6h5.1zM196.8 182.1h5.1z"/>
<path d="M201.9 182.1h20.3zM201.9 184.6h22.9zM222.2 182.1h17.8zM224.8 184.6h15.2zM242.5 182.1l-2.5 2.5zM245.1 198.1v1zM245.1 196.1v1zM245.1 194.1v1zM245.1 192.1v1zM245.1 190.1v1zM245.1 188.1v1zM245.1 186.1v1z"/>
<path d="M245.1 184.1v1zM245.1 182.1v1zM245.1 180.1v1zM273 192.2l-2.5 2.6zM275.6 195.3h8.3zM290.8 151.6v33zM293.3 184.6h3.1zM293.3 187.1h5.1zM293.3 192.2h5.1zM293.3 197.3h3.1zM290.8 184.6h2.5zM273 192.2h20.3z"/>
<path d="M250.2 197.3h43.1zM300.8 183.7h7.7zM300.8 196.4h7.1zM319 196.4h7.6zM328.9 182.1h5.1zM328.9 184.6h5.1zM328.9 187.1h5.1zM328.9 189.7h5.1zM328.9 192.2h5.1zM328.9 197.3h5.1zM328.9 199.8h5.1zM334 182.1h10.1z"/>
<path d="M334 184.6h10.1zM334 187.1h10.1zM334 189.7h10.1zM334 192.2h10.1zM346.7 182.1l-2.6 2.5zM346.7 184.6l-2.6 2.5zM346.7 187.1l-2.6 2.6zM346.7 189.7l-2.6 2.5zM153.6 215h1.1zM153.6 200.1v1zM153.6 202.1v1zM153.6 204.1v1z"/>
<path d="M153.6 206.1v1zM153.6 208.1v1zM153.6 210.1v.9zM153.6 212.1v1zM153.6 214.1v.9zM155.7 215h1zM157.7 215h1zM159.7 215h1zM161.7 215h1zM163.7 215h1zM165.7 215h1zM167.7 215h1z"/>
<path d="M169.7 215h1zM171.7 215h1zM173.8 215h.9zM175.8 215h1zM177.8 215h1zM179.8 215h1zM181.8 215h1zM183.8 215h1zM185.8 215h1zM187.8 215h1zM189.8 215h1zM191.8 215h1z"/>
<path d="M193.8 215h1.1zM195.9 215h.9zM197.9 215h1zM199.9 215h1zM201.9 215h1zM203.9 215h1zM205.9 215h1zM207.9 215h1zM209.9 215h1zM211.9 215h1zM213.9 215h1zM215.9 215h1.1z"/>
<path d="M217.9 215h1.1zM220 215h1zM222 215h1zM224 215h1zM226 215h1zM228 215h1zM230 215h1zM232 215h1zM234 215h1zM236 215h1zM238 215h1.1zM240 215h1.1z"/>
<path d="M242.1 215h1zM244.1 215h1zM245.1 214.1v.9zM245.1 212.1v1zM245.1 210.1v.9zM245.1 208.1v1zM245.1 206.1v1zM245.1 204.1v1zM245.1 202.1v1zM245.1 200.1v1zM275.6 218.1h5.1zM293.3 202.4h3.1z"/>
<path d="M300.8 201.4h6.6zM323.8 215v2.6zM328.9 202.4h5.1zM334 202.4h2.5zM336.5 204.9v2.5zM336.5 202.4v2.5zM16.5 224.2h3.8zM270.5 222.7l2.5-2.6zM270.5 235.4l2.5-2.6zM275.6 230.8h5.1zM293.3 222.7v2.5zM293.3 225.2v1.3z"/>
<path d="M293.3 235.4v2.5zM293.3 237.9v1.3zM273 220.1h20.3zM293.3 220.1v2.6zM273 232.8h20.3zM293.3 232.8v2.6zM295.9 222.7v2.5zM295.9 225.2v1.3zM295.9 235.4v2.5zM295.9 237.9v1.3zM295.9 220.1v2.6zM295.9 220.1h2.5z"/>
<path d="M295.9 232.8v2.6zM295.9 232.8h2.5zM298.4 220.1h2.6zM298.4 232.8h2.6zM300.2 223.4l.9-.3zM300.2 236.1l.9-.3zM300.2 223.3h.3zM300.3 236h.3zM300.3 223.2h.5zM300.3 235.9h.5zM300.3 223.1h.7zM300.4 235.8h.7z"/>
<path d="M300.4 223h.6zM300.4 235.6h.5zM300.5 222.8h.4zM300.5 235.5h.3zM300.5 222.7h.3zM300.5 235.4h.2zM300.6 222.5l-.4 .9zM300.6 235.2l-.4 .9zM300.6 222.5l.5 .6zM300.6 235.2l.5 .6zM301.3 223.6l.9-.4zM301.3 236.3l.9-.4z"/>
<path d="M301.4 223.5h.2zM301.4 236.1h.3zM301.5 223.3h.4zM301.5 236h.5zM301.5 223.2h.7zM301.5 235.9h.7zM301.5 223.1h.6zM301.6 235.8h.5zM301.6 222l-1.4 1.4zM301.6 223h.4zM301.6 234.7l-1.4 1.4zM301.6 235.6h.4z"/>
<path d="M301.6 222.8h.3zM301.7 235.5h.2zM301.7 222.7l-.4 .9zM301.7 235.4l-.4 .9zM301.7 222.7l.5 .5zM301.7 235.4l.5 .5zM302.7 222.2l-1.4 1.4zM302.7 234.9l-1.4 1.4zM301 220.1h2.5zM301 232.8h2.5zM303.5 220.1h2.5zM303.5 232.8h2.5z"/>
<path d="M311.1 220.1h2.6zM311.1 232.8h2.6zM306 220.1h5.1zM306 232.8h5.1zM318.7 220.1h2.6zM318.7 232.8h2.6zM321.3 220.1h2.5zM321.3 232.8h2.5zM323.8 227.7v2.6zM323.8 217.6v2.5zM323.8 230.3v2.5zM400 224.2h3.8z"/>
<path d="M26.7 253.1v2.6zM26.7 257.7v.5zM26.7 255.7v.5zM26.7 250.6v2.5zM34.3 253.1v2.6zM34.3 257.7v.5zM34.3 255.7v.5zM34.3 250.6v2.5zM26.7 250.6h7.6zM41.9 253.1v2.6zM41.9 257.7v.5zM41.9 255.7v.5z"/>
<path d="M34.3 250.6h7.6zM41.9 250.6v2.5zM49.5 253.1v2.6zM49.5 257.7v.5zM49.5 255.7v.5zM41.9 250.6h7.6zM49.5 250.6v2.5zM57.1 245.5v2.6zM57.1 253.1v2.6zM57.1 257.7v.5zM57.1 255.7v.5zM49.5 250.6h7.6z"/>
<path d="M57.1 248.1v2.5zM57.1 250.6v2.5zM67.3 245.5v2.6zM67.3 253.1v2.6zM67.3 255.7v.5zM67.3 257.7v.5zM67.3 248.1v5zM267.9 255.7l2.2-2.2zM270.6 253l.1-.1zM271.2 252.4l2.2-2.2zM273.9 249.7h.1zM274.5 249.2l2.2-2.2z"/>
<path d="M277.1 246.5l.1-.1zM277.7 245.9l2.2-2.2zM280.4 243.2l.1-.1zM281 242.7l2.2-2.3zM283.2 240.4h1.8zM285.7 240.4h.1zM286.5 240.4h1.8zM20.3 274.7h379.7zM26.7 265.8v2.6zM26.7 258.2v2.6zM26.7 260.8v2.5zM26.7 263.3h7.6z"/>
<path d="M26.7 263.3v2.5zM34.3 258.2v2.6zM34.3 260.8v2.5zM41.9 258.2v2.6zM34.3 263.3h7.6zM41.9 260.8v2.5zM49.5 258.2v2.6zM41.9 263.3h7.6zM49.5 260.8v2.5zM57.1 258.2v2.6zM49.5 263.3h7.6zM57.1 260.8v2.5z"/>
<path d="M67.3 265.8v2.6zM67.3 258.2v2.6zM67.3 260.8v5zM67.8 274.7v3.8zM115.3 274.7v3.8zM162.7 274.7v3.8zM210.2 274.7v3.8zM257.6 274.7v3.8zM305.1 274.7v3.8zM352.5 274.7v3.8zM400 264.5v.1zM400 268.4v6.2z"/>
<path d="M400 274.6h.1zM400 22.1v252.6z"/>
<circle cx="156.2" cy="47.5" r=".51"/>
<circle cx="250.2" cy="57.6" r=".51"/>
<circle cx="255.2" cy="52.5" r=".51"/>
<circle cx="260.3" cy="47.5" r=".51"/>
<circle cx="54.6" cy="67.8" r=".51"/>
<circle cx="72.4" cy="62.7" r=".51"/>
<circle cx="207" cy="118.6" r=".51"/>
<circle cx="255.2" cy="113.5" r=".51"/>
<circle cx="260.3" cy="110.9" r=".51"/>
<circle cx="209.5" cy="121.1" r=".51"/>
<circle cx="212.1" cy="123.6" r=".51"/>
<circle cx="214.6" cy="126.2" r=".51"/>
<circle cx="217.1" cy="128.7" r=".51"/>
<circle cx="219.7" cy="131.3" r=".51"/>
<circle cx="222.2" cy="133.8" r=".51"/>
<circle cx="224.8" cy="136.3" r=".51"/>
<circle cx="250.2" cy="131.3" r=".51"/>
<circle cx="92.7" cy="156.7" r=".51"/>
<circle cx="92.7" cy="154.1" r=".51"/>
<circle cx="92.7" cy="159.2" r=".51"/>
<circle cx="156.2" cy="141.4" r=".51"/>
<circle cx="54.6" cy="161.7" r=".51"/>
<circle cx="207" cy="166.8" r=".51"/>
<circle cx="209.5" cy="169.4" r=".51"/>
<circle cx="212.1" cy="171.9" r=".51"/>
<circle cx="214.6" cy="174.4" r=".51"/>
<circle cx="217.1" cy="177" r=".51"/>
<circle cx="219.7" cy="179.5" r=".51"/>
<circle cx="92.7" cy="182.1" r=".51"/>
<circle cx="92.7" cy="184.6" r=".51"/>
<circle cx="92.7" cy="187.1" r=".51"/>
<circle cx="222.2" cy="182.1" r=".51"/>
<circle cx="224.8" cy="184.6" r=".51"/>
<circle cx="34.3" cy="250.6" r=".51"/>
<circle cx="41.9" cy="250.6" r=".51"/>
<circle cx="49.5" cy="250.6" r=".51"/>
<circle cx="57.1" cy="250.6" r=".51"/>
<circle cx="26.7" cy="263.3" r=".51"/>
<circle cx="34.3" cy="263.3" r=".51"/>
<circle cx="41.9" cy="263.3" r=".51"/>
<circle cx="49.5" cy="263.3" r=".51"/>
</g>
<g fill="#000" stroke="#000" stroke-width=".28">
<path d="M26.2 56.1v3zM32.3 51v3.1zM32.9 45.9v3.1zM32.3 51h8.1zM32.3 54.1h8.1zM32.9 45.9h7.5zM32.9 49h7.5zM26.2 56.1h14.2zM26.2 59.1h14.2zM40.4 51l1.5 1.5zM41.9 52.5l-1.5 1.6zM40.4 45.9l1.5 1.6z"/>
<path d="M41.9 47.5l-1.5 1.5zM40.4 56.1l1.5 1.5zM41.9 57.6l-1.5 1.5zM369.5 52.5l1.5-1.5zM369.5 52.5l1.5 1.6zM369.5 47.5l1.5-1.6zM369.5 47.5l1.5 1.5zM371 56.1l-1.5 1.5zM369.5 57.6l1.5 1.5zM371 51h8.2zM371 54.1h8.2zM371 45.9h7.6z"/>
<path d="M371 49h7.6zM371 56.1h14.2zM371 59.1h14.2zM378.6 45.9v3.1zM379.2 51v3.1zM385.2 56.1v3zM24.4 61.1v3.1zM30.2 66.2v3.1zM30.2 69.3h10.2zM30.2 66.2h10.2zM24.4 64.2h16zM24.4 61.1h16z"/>
<path d="M41.9 67.8l-1.5 1.5zM40.4 66.2l1.5 1.6zM40.4 64.2l1.5-1.5zM40.4 61.1l1.5 1.6zM371 66.2l-1.5 1.6zM369.5 67.8l1.5 1.5zM371 61.1l-1.5 1.6zM369.5 62.7l1.5 1.5zM371 66.2h10.3zM371 69.3h10.3zM371 61.1h16.1zM371 64.2h16.1z"/>
<path d="M381.3 66.2v3.1zM387.1 61.1v3.1zM207 93.2l-1.3 1.9zM207 93.2l1.3 1.9zM290.8 83l-1.3 1.9zM290.8 83l1.3 1.9zM206.2 104.6v5.1zM206.2 109.7h.8zM207 109.7h.7zM206.2 104.6h.8zM207.7 104.6v5.1zM207 104.6h.7z"/>
<path d="M208.8 109.7h.7zM208.8 104.6v5.1zM209.5 109.7h.8zM208.8 104.6h.7zM209.5 104.6h.8zM210.3 104.6v5.1zM211.3 104.6v5.1zM211.3 109.7h.8zM211.3 104.6h.8zM212.1 109.7h.7zM212.8 104.6v5.1zM212.1 104.6h.7z"/>
<path d="M213.8 104.6v5.1zM213.8 109.7h.8zM213.8 104.6h.8zM214.6 109.7h.8zM215.4 104.6v5.1zM214.6 104.6h.8zM216.4 104.6v5.1zM216.4 109.7h.7zM216.4 104.6h.7zM217.1 109.7h.8zM217.9 104.6v5.1zM217.1 104.6h.8z"/>
<path d="M218.9 104.6v5.1zM218.9 109.7h.8zM219.7 109.7h.7zM218.9 104.6h.8zM220.4 104.6v5.1zM219.7 104.6h.7zM221.5 109.7h.7zM221.5 104.6v5.1zM222.2 109.7h.8zM221.5 104.6h.7zM222.2 104.6h.8zM223 104.6v5.1z"/>
<path d="M224 104.6v5.1zM224 109.7h.8zM224 104.6h.8zM224.8 109.7h.7zM225.5 104.6v5.1zM224.8 104.6h.7zM172.1 149h3.8zM206.2 152.8v5.1zM206.2 157.9h.8zM207 157.9h.7zM206.2 152.8h.8zM207 141.4l-1.3 1.9z"/>
<path d="M207.7 152.8v5.1zM207 152.8h.7zM207 141.4l1.3 1.9zM208.8 157.9h.7zM208.8 152.8v5.1zM209.5 157.9h.8zM208.8 152.8h.7zM209.5 152.8h.8zM210.3 152.8v5.1zM211.3 152.8v5.1zM211.3 157.9h.8zM211.3 152.8h.8z"/>
<path d="M212.1 157.9h.7zM212.8 152.8v5.1zM212.1 152.8h.7zM213.8 152.8v5.1zM213.8 157.9h.8zM213.8 152.8h.8zM214.6 157.9h.8zM215.4 152.8v5.1zM214.6 152.8h.8zM216.4 152.8v5.1zM216.4 157.9h.7zM216.4 152.8h.7z"/>
<path d="M217.1 157.9h.8zM217.9 152.8v5.1zM217.1 152.8h.8zM218.9 152.8v5.1zM218.9 157.9h.8zM219.7 157.9h.7zM218.9 152.8h.8zM220.4 152.8v5.1zM219.7 152.8h.7zM221.5 157.9h.7zM221.5 152.8v5.1zM222.2 157.9h.8z"/>
<path d="M221.5 152.8h.7zM222.2 152.8h.8zM223 152.8v5.1zM224 152.8v5.1zM224 157.9h.8zM224 152.8h.8zM224.8 157.9h.7zM225.5 152.8v5.1zM224.8 152.8h.7zM290.8 149l-1.3 1.9zM290.8 149l1.3 1.9zM334.6 141.4h3.8z"/>
<path d="M101 171.9h3.8zM103.6 163.5l-.5 .6zM103.6 163.8l-.1 .2zM103.6 163.5l.3 .5zM103.1 164.1h.8zM103.5 164h.4zM113 162.6h5.1zM113 160.8v1.8zM113 160.8h5.1zM118.1 160.8v1.8zM101 199.8h3.8zM103.6 191.4l-.5 .7z"/>
<path d="M103.6 191.7l-.1 .3zM103.6 191.4l.3 .6zM103.1 192.1h.8zM103.5 192h.4zM113 190.6h5.1zM113 188.8v1.8zM113 188.8h5.1zM118.1 188.8v1.8zM172.1 197.3h3.8zM300.7 218.9v2.5zM300.7 219.9h.3zM300.7 219.7h.3z"/>
<path d="M300.7 219.5h.3zM300.7 219.2h.3zM300.7 219h.3zM300.7 218.9h.3zM301.4 219.9h2.1zM301.9 219.7h1.6zM302.3 219.5h1.2zM302.8 219.2h.7zM303.2 219h.3zM301 220.1l2.5-1.2zM313.7 219.2h5zM323.8 215l-1.2 2z"/>
<path d="M323.8 215l1.3 2zM334.6 207.4h3.8zM300.7 221.4h.3zM300.7 221.2h.3zM300.7 221h.3zM300.7 220.8h.3zM300.7 220.6h.3zM300.7 220.3h.3zM300.7 220.1h.3zM300.7 231.6v2.5zM300.7 234.1h.3zM300.7 233.9h.3z"/>
<path d="M300.7 233.7h.3zM300.7 233.4h.3zM300.7 233.2h.3zM300.7 233h.3zM300.7 232.8h.3zM300.7 232.6h.3zM300.7 232.3h.3zM300.7 232.1h.3zM300.7 231.9h.3zM300.7 231.7h.3zM301 220.1v1.3zM301 220.1l2.5 1.3z"/>
<path d="M301 218.9v2.5zM301 232.8v1.3zM301 232.8l2.5 1.3zM301 231.6v2.5zM300.7 231.6h.3zM301 220.1h2.5zM301.1 232.8h2.4zM301.3 233h2.2zM301.4 220.3h2.1zM301.5 232.6h2zM301.7 233.2h1.8zM301.8 220.6h1.7z"/>
<path d="M302 232.3h1.5zM302.2 233.4h1.3zM302.3 220.8h1.2zM302.4 232.1h1.1zM302.6 233.7h.9zM302.7 221h.8zM302.8 231.9h.7zM303.1 233.9h.4zM303.1 221.2h.4zM303.3 231.7h.2zM303.5 218.9v2.5zM303.5 231.6v2.5z"/>
<path d="M301 232.8l2.5-1.2zM313.7 221h5zM313.7 219.2v1.8zM313.7 233.7h5zM313.7 231.9v1.8zM318.7 219.2v1.8zM313.7 231.9h5zM318.7 231.9v1.8zM323.8 227.7l-1.2 2zM323.8 227.7l1.3 2zM57.1 245.5l-1.2 1.9zM57.1 245.5l1.3 1.9z"/>
<path d="M67.3 245.5l-1.3 1.9zM67.3 245.5l1.3 1.9zM313.7 249.3h86.3zM313.7 254.4h86.3zM313.7 259.5h58.4zM372.1 259.5h27.9zM372.1 259.5v5.1zM24.8 268.4h3.8zM65.4 268.4h3.8zM313.7 264.6h58.4zM313.7 269.7h86.3zM372.1 264.6h27.9z"/>
<path d="M400 268.4v1.3z"/>
</g>
<g fill="none" stroke="#000" stroke-width=".21">
<circle cx="119.1" cy="90.6" r=".99"/>
<circle cx="119.1" cy="95.7" r=".99"/>
<circle cx="119.1" cy="88.1" r=".99"/>
<circle cx="119.1" cy="93.2" r=".99"/>
<circle cx="119.1" cy="98.2" r=".99"/>
<circle cx="297.4" cy="95.7" r="1"/>
<circle cx="297.4" cy="93.2" r="1"/>
<circle cx="297.4" cy="88.1" r="1"/>
<circle cx="101.9" cy="105.9" r=".99"/>
<circle cx="101.9" cy="103.3" r=".99"/>
<circle cx="119.1" cy="103.3" r=".99"/>
<circle cx="119.1" cy="100.8" r=".99"/>
<circle cx="119.1" cy="105.9" r=".99"/>
<circle cx="297.4" cy="110.9" r="1"/>
<circle cx="297.4" cy="118.6" r="1"/>
<circle cx="297.4" cy="113.5" r="1"/>
<circle cx="297.4" cy="136.3" r="1"/>
<circle cx="297.4" cy="131.3" r="1"/>
<circle cx="180.6" cy="144" r=".99"/>
<circle cx="297.4" cy="159.2" r="1"/>
<circle cx="297.4" cy="154.1" r="1"/>
<circle cx="297.4" cy="177" r="1"/>
<circle cx="297.4" cy="179.5" r="1"/>
<circle cx="297.4" cy="161.7" r="1"/>
<circle cx="180.6" cy="192.2" r=".99"/>
<circle cx="297.4" cy="184.6" r="1"/>
<circle cx="297.4" cy="197.3" r="1"/>
<circle cx="297.4" cy="202.4" r="1"/>
</g>
<g fill="#000" stroke="#000" stroke-width=".61">
<path d="M20.3 22.1v252.6zM20.3 22.1h379.7zM102.9 85.5v22.9zM102.9 85.5h15.2zM298.4 85.5v53.4zM298.4 85.5h30.5zM311.1 95.7h1.3zM311.1 98.2h1.3zM311.1 93.2h1.3zM311.1 90.6h1.3zM311.1 88.1h1.3zM314.9 95.7h1.3z"/>
<path d="M314.9 98.2h1.3zM314.9 93.2h1.3zM314.9 90.6h1.3zM314.9 88.1h1.3zM102.9 108.4h15.2zM118.1 85.5v22.9zM181.6 116v30.5zM181.6 116h15.2zM311.1 118.6h1.3zM311.1 113.5h1.3zM311.1 116h1.3zM311.1 105.9h1.3z"/>
<path d="M311.1 108.4h1.3zM311.1 110.9h1.3zM311.1 100.8h1.3zM311.1 103.3h1.3zM314.9 118.6h1.3zM314.9 113.5h1.3zM314.9 116h1.3zM314.9 105.9h1.3zM314.9 108.4h1.3zM314.9 110.9h1.3zM314.9 100.8h1.3zM314.9 103.3h1.3z"/>
<path d="M311.1 126.2h1.3zM311.1 121.1h1.3zM311.1 123.6h1.3zM311.1 131.3h1.3zM311.1 133.8h1.3zM311.1 136.3h1.3zM311.1 128.7h1.3zM314.9 126.2h1.3zM314.9 121.1h1.3zM314.9 123.6h1.3zM314.9 131.3h1.3zM314.9 133.8h1.3z"/>
<path d="M314.9 136.3h1.3zM314.9 128.7h1.3zM298.4 138.9h30.5zM328.9 85.5v53.4zM80 156.7h1.3zM80 159.2h1.3zM80 154.1h1.3zM83.8 156.7h1.3zM83.8 159.2h1.3zM83.8 154.1h1.3zM181.6 146.5h15.2zM196.8 116v30.5z"/>
<path d="M298.4 151.6v53.3zM298.4 151.6h30.5zM311.1 159.2h1.3zM311.1 156.7h1.3zM311.1 154.1h1.3zM314.9 159.2h1.3zM314.9 156.7h1.3zM314.9 154.1h1.3zM80 161.7h1.3zM83.8 161.7h1.3zM181.6 164.3v30.5zM181.6 164.3h15.2z"/>
<path d="M311.1 179.5h1.3zM311.1 171.9h1.3zM311.1 174.4h1.3zM311.1 177h1.3zM311.1 166.8h1.3zM311.1 169.4h1.3zM311.1 161.7h1.3zM311.1 164.3h1.3zM314.9 179.5h1.3zM314.9 171.9h1.3zM314.9 174.4h1.3zM314.9 177h1.3z"/>
<path d="M314.9 166.8h1.3zM314.9 169.4h1.3zM314.9 161.7h1.3zM314.9 164.3h1.3zM80 184.6h1.3zM80 187.1h1.3zM80 189.7h1.3zM80 182.1h1.3zM83.8 184.6h1.3zM83.8 187.1h1.3zM83.8 189.7h1.3zM83.8 182.1h1.3z"/>
<path d="M181.6 194.8h15.2zM196.8 164.3v30.5zM311.1 192.2h1.3zM311.1 184.6h1.3zM311.1 187.1h1.3zM311.1 189.7h1.3zM311.1 182.1h1.3zM311.1 197.3h1.3zM311.1 199.8h1.3zM311.1 194.8h1.3zM314.9 192.2h1.3zM314.9 184.6h1.3z"/>
<path d="M314.9 187.1h1.3zM314.9 189.7h1.3zM314.9 182.1h1.3zM314.9 197.3h1.3zM314.9 199.8h1.3zM314.9 194.8h1.3zM311.1 202.4h1.3zM314.9 202.4h1.3zM298.4 204.9h30.5zM328.9 151.6v53.3zM283.2 244.3v30.4zM313.7 254.4v5.1z"/>
<path d="M313.7 249.3v5.1zM313.7 244.3v5zM313.7 244.3h86.3zM283.2 244.3h30.5zM400 254.4v5.1zM400 249.3v5.1zM400 244.3v5zM400 22.1v222.2zM20.3 274.7h262.9zM283.2 274.7h30.5zM313.7 274.7h86.3zM313.7 269.7v5z"/>
<path d="M313.7 264.6v5.1zM313.7 259.5v5.1zM400 268.4v6.3zM400 264.6v3.8zM400 259.5v5.1z"/>
</g>
<g fill="#000" stroke="#000" stroke-width=".42">
<path d="M204.4 102v8.9zM204.4 102h22.9zM204.4 110.9h22.9zM227.3 102v8.9zM78.7 151.6v12.7zM78.7 151.6h7.7zM204.4 150.3v8.9zM204.4 150.3h22.9zM204.4 159.2h22.9zM227.3 150.3v8.9zM78.7 179.5v12.7zM78.7 179.5h7.7z"/>
<path d="M78.7 164.3h7.7zM86.4 151.6v12.7zM78.7 192.2h7.7zM86.4 179.5v12.7zM292.7 225.2h3.8zM292.7 225.2v.6zM292.7 237.9h3.8zM292.7 237.9v.6zM293.3 226.5v1.2zM295.9 226.5v1.2zM296.5 225.2v.6zM292.7 225.8h3.8z"/>
<path d="M296.5 237.9v.6zM292.7 238.5h3.8zM341.6 222.7v10.1zM341.6 232.8v7.6zM341.6 232.8h55.9zM397.5 222.7v10.1zM341.6 222.7h55.9zM397.5 232.8v2.6zM293.3 239.2v1.2zM295.9 239.2v1.2zM341.6 240.4h55.9zM397.5 232.8v7.6z"/>
</g>
<g fill="none" stroke="#000" stroke-width=".42">
<circle cx="207" cy="103.3" r=".25"/>
<circle cx="209.5" cy="103.3" r=".25"/>
<circle cx="212.1" cy="103.3" r=".25"/>
<circle cx="214.6" cy="103.3" r=".25"/>
<circle cx="217.1" cy="103.3" r=".25"/>
<circle cx="219.7" cy="103.3" r=".25"/>
<circle cx="222.2" cy="103.3" r=".25"/>
<circle cx="207" cy="151.6" r=".25"/>
<circle cx="209.5" cy="151.6" r=".25"/>
<circle cx="212.1" cy="151.6" r=".25"/>
<circle cx="214.6" cy="151.6" r=".25"/>
<circle cx="217.1" cy="151.6" r=".25"/>
<circle cx="219.7" cy="151.6" r=".25"/>
<circle cx="222.2" cy="151.6" r=".25"/>
</g>
<path d="M16.5 18.2v260.3zM16.5 18.2h387.3zM16.5 278.5h387.3zM403.8 18.2v260.3z" fill="#000" stroke="#000" stroke-width=".32"/>
<g fill="#000" stroke="#000" stroke-width=".21">
<path d="M104.9 159.2h.8v5.1h-.8zM104.9 187.1h.8v5.1h-.8zM372.1 222.7h25.4v10.1h-25.4zM24.6 256.2h4.1v.5h-4.1zM24.6 257.2h4.1v.5h-4.1zM32.3 256.2h4v.5h-4zM32.3 257.2h4v.5h-4zM39.9 256.2h4v.5h-4zM39.9 257.2h4v.5h-4zM47.5 256.2h4.1v.5h-4.1zM47.5 257.2h4.1v.5h-4.1zM55.1 256.2h4.1v.5h-4.1z"/>
<path d="M55.1 257.2h4.1v.5h-4.1zM65.3 257.2h4v.5h-4zM65.3 256.2h4v.5h-4z"/>
</g>
<g fill="#000" stroke="#000" stroke-width=".76">
<path d="M41.9 34.8h33zM74.9 34.8l2.6 2.5zM74.9 34.8h185.4zM77.5 37.3v63.5zM41.9 39.8h114.3zM260.3 34.8l5.1 5zM265.4 39.8v129.6zM156.2 39.8l5.1 5.1zM247.6 77.9l-5.1 5.1zM247.6 77.9h94zM341.6 77.9l5.1 5.1zM242.5 83v99.1z"/>
<path d="M270.5 90.6v147.3zM346.7 83v40.6zM346.7 123.6v66.1zM44.4 146.5h12.7zM57.1 146.5l2.6 2.5zM59.7 149v2.6zM59.7 151.6v5.1zM59.7 156.7v27.9zM161.3 44.9v137.2zM148.6 95.7v142.2zM270.5 237.9l-5.1 5.1zM148.6 237.9l5 5.1z"/>
<path d="M153.6 243h111.8z"/>
</g>
<use href="#words"/>
</svg>
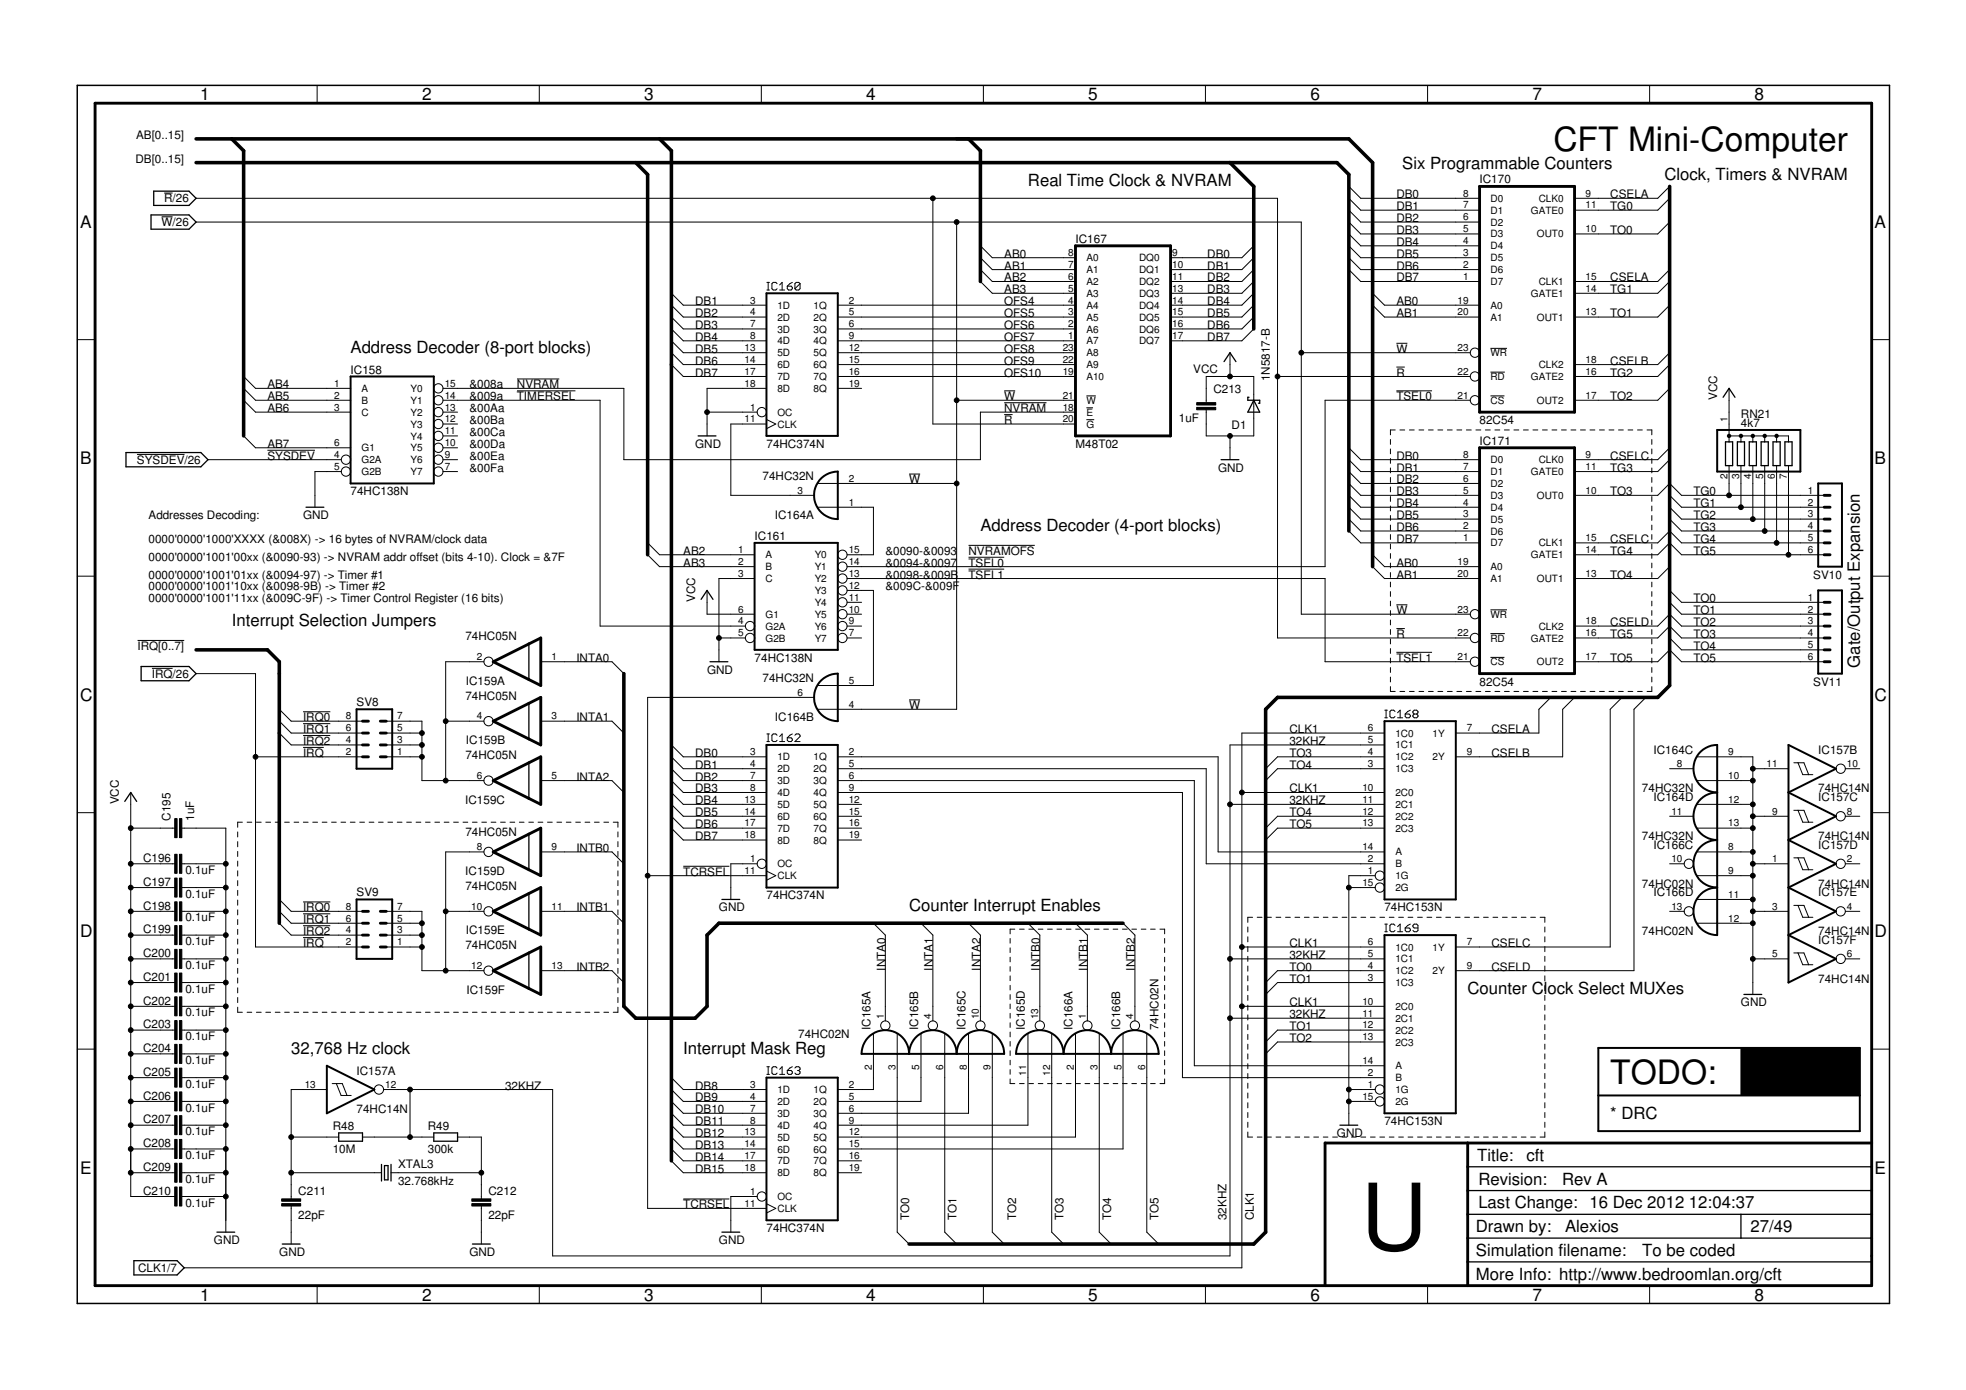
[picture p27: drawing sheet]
<svg xmlns="http://www.w3.org/2000/svg" width="420mm" height="297mm" viewBox="0 0 420 297" stroke-linecap="round" stroke-linejoin="round" font-family="sans-serif">
<defs><g id="words">
<text font-size="19.7" x="290.8" y="267.1">U</text>
<g font-size="7.2">
<text x="332" y="32.2">CFT Mini-Computer</text>
<text x="344.1" y="231.6">TODO:</text>
</g>
<g font-size="3.7">
<text x="42.7" y="21.5">1</text>
<text x="90.2" y="21.5">2</text>
<text x="137.7" y="21.5">3</text>
<text x="185.1" y="21.5">4</text>
<text x="232.6" y="21.5">5</text>
<text x="280" y="21.5">6</text>
<text x="327.5" y="21.5">7</text>
<text x="375" y="21.5">8</text>
<text x="17.1" y="48.6">A</text>
<text x="400.6" y="48.6">A</text>
<text x="17.1" y="99.2">B</text>
<text x="400.6" y="99.2">B</text>
<text x="17.1" y="149.7">C</text>
<text x="400.6" y="149.7">C</text>
<text x="17.1" y="200.2">D</text>
<text x="400.6" y="200.2">D</text>
<text x="17.1" y="250.8">E</text>
<text x="400.6" y="250.8">E</text>
<text x="42.7" y="277.9">1</text>
<text x="90.2" y="277.9">2</text>
<text x="137.7" y="277.9">3</text>
<text x="185.1" y="277.9">4</text>
<text x="232.6" y="277.9">5</text>
<text x="280" y="277.9">6</text>
<text x="327.5" y="277.9">7</text>
<text x="375" y="277.9">8</text>
</g>
<g font-size="3.6">
<text x="219.7" y="39.8">Real Time Clock &amp; NVRAM</text>
<text x="299.7" y="36">Six Programmable Counters</text>
<text x="355.7" y="38.6">Clock, Timers &amp; NVRAM</text>
<text x="74.9" y="75.4">Address Decoder (8-port blocks)</text>
<text x="209.5" y="113.5">Address Decoder (4-port blocks)</text>
<text x="49.5" y="133.8">Interrupt Selection Jumpers</text>
<text x="397.5" y="142.7" transform="rotate(-90 397.5 142.7)">Gate/Output Expansion</text>
<text x="194.3" y="194.7">Counter Interrupt Enables</text>
<text x="313.7" y="212.5">Counter Clock Select MUXes</text>
<text x="62.2" y="225.2">32,768 Hz clock</text>
<text x="146" y="225.2">Interrupt Mask Reg</text>
<text x="344.1" y="239.2">* DRC</text>
<text x="315.7" y="248.1">Title:</text>
<text x="326.2" y="248.2">cft</text>
<text x="315.9" y="253.2">Revision:</text>
<text x="333.8" y="253.3">Rev A</text>
<text x="315.4" y="263.3">Drawn by:</text>
<text x="315.9" y="258.2">Last Change: 16 Dec 2012</text>
<text x="334.5" y="263.3">Alexios</text>
<text x="361" y="258.1">12:04:37</text>
<text x="374.1" y="263.2">27/49</text>
<text x="315.4" y="268.4">Simulation filename:</text>
<text x="351" y="268.4">To be coded</text>
<text x="315.4" y="273.5">More Info: http://www.bedroomlan.org/cft</text>
</g>
<g font-size="2.5">
<text x="29.1" y="29.7">AB[0..15]</text>
<text x="29" y="34.7">DB[0..15]</text>
<text x="316.2" y="39.2">IC170</text>
<text x="35.1" y="43.3">R/26</text>
<text x="298.4" y="42.4">DB0</text>
<text x="298.4" y="44.9">DB1</text>
<text x="298.4" y="47.4">DB2</text>
<text x="344.1" y="44.9">TG0</text>
<text x="344.1" y="42.4">CSELA</text>
<text x="34.5" y="48.3">W/26</text>
<text x="229.8" y="51.9">IC167</text>
<text x="298.4" y="50">DB3</text>
<text x="298.4" y="52.5">DB4</text>
<text x="344.1" y="50">TO0</text>
<text x="214.6" y="57.6">AB1</text>
<text x="214.6" y="55.1">AB0</text>
<text x="258" y="55.1">DB0</text>
<text x="258" y="57.6">DB1</text>
<text x="298.4" y="55.1">DB5</text>
<text x="298.4" y="57.6">DB6</text>
<text x="148.6" y="65.2">DB1</text>
<text x="214.6" y="60.1">AB2</text>
<text x="214.6" y="62.7">AB3</text>
<text x="214.6" y="65.2">OFS4</text>
<text x="258" y="60.1">DB2</text>
<text x="258" y="62.7">DB3</text>
<text x="258" y="65.2">DB4</text>
<text x="298.4" y="60.1">DB7</text>
<text x="298.4" y="65.2">AB0</text>
<text x="344.1" y="62.7">TG1</text>
<text x="344.1" y="60.1">CSELA</text>
<text x="148.6" y="67.8">DB2</text>
<text x="148.6" y="70.3">DB3</text>
<text x="214.6" y="67.8">OFS5</text>
<text x="214.6" y="70.3">OFS6</text>
<text x="258" y="67.8">DB5</text>
<text x="258" y="70.3">DB6</text>
<text x="298.4" y="67.8">AB1</text>
<text x="344.1" y="67.8">TO1</text>
<text x="148.6" y="72.8">DB4</text>
<text x="148.6" y="75.4">DB5</text>
<text x="148.6" y="77.9">DB6</text>
<text x="214.6" y="72.8">OFS7</text>
<text x="214.6" y="75.4">OFS8</text>
<text x="214.6" y="77.9">OFS9</text>
<text x="258" y="72.8">DB7</text>
<text x="298.4" y="75.4">W</text>
<text x="344.1" y="77.9">CSELB</text>
<text x="57.1" y="83">AB4</text>
<text x="74.9" y="79.8">IC158</text>
<text x="100.3" y="83">&amp;008a</text>
<text x="110.5" y="83">NVRAM</text>
<text x="148.6" y="80.5">DB7</text>
<text x="214.6" y="80.5">OFS10</text>
<text x="255" y="79.7">VCC</text>
<text x="259.3" y="83.9">C213</text>
<text x="271.4" y="81.5" transform="rotate(-90 271.4 81.5)">1N5817-B</text>
<text x="298.4" y="80.5">R</text>
<text x="344.1" y="80.5">TG2</text>
<text x="57.1" y="85.5">AB5</text>
<text x="57.1" y="88.1">AB6</text>
<text x="100.3" y="85.5">&amp;009a</text>
<text x="100.3" y="88.1">&amp;00Aa</text>
<text x="110.5" y="85.5">TIMERSEL</text>
<text x="214.6" y="88.1">NVRAM</text>
<text x="214.6" y="85.5">W</text>
<text x="298.4" y="85.5">TSEL0</text>
<text x="344.1" y="85.5">TO2</text>
<text x="367" y="85.5" transform="rotate(-90 367 85.5)">VCC</text>
<text x="372.1" y="89.3">RN21</text>
<text x="57.1" y="95.7">AB7</text>
<text x="100.3" y="90.6">&amp;00Ba</text>
<text x="100.3" y="93.2">&amp;00Ca</text>
<text x="100.3" y="95.7">&amp;00Da</text>
<text x="148.6" y="95.7">GND</text>
<text x="163.8" y="95.7">74HC374N</text>
<text x="214.6" y="90.6">R</text>
<text x="229.8" y="95.7">M48T02</text>
<text x="251.9" y="90.2">1uF</text>
<text x="263.2" y="91.8">D1</text>
<text x="316.2" y="90.6">82C54</text>
<text x="316.2" y="95.1">IC171</text>
<text x="372.1" y="91.3">4k7</text>
<text x="29.3" y="99.1">SYSDEV/26</text>
<text x="57.1" y="98.2">SYSDEV</text>
<text x="100.3" y="98.2">&amp;00Ea</text>
<text x="100.3" y="100.8">&amp;00Fa</text>
<text x="260.3" y="100.8">GND</text>
<text x="298.4" y="98.2">DB0</text>
<text x="298.4" y="100.8">DB1</text>
<text x="344.1" y="100.8">TG3</text>
<text x="344.1" y="98.2">CSELC</text>
<text x="74.9" y="105.9">74HC138N</text>
<text x="163" y="102.6">74HC32N</text>
<text x="194.3" y="103.3">W</text>
<text x="298.4" y="103.3">DB2</text>
<text x="298.4" y="105.9">DB3</text>
<text x="344.1" y="105.9">TO3</text>
<text x="361.9" y="105.9">TG0</text>
<text x="31.7" y="110.9">Addresses Decoding:</text>
<text x="64.8" y="110.9">GND</text>
<text x="165.6" y="110.8">IC164A</text>
<text x="298.4" y="108.4">DB4</text>
<text x="298.4" y="110.9">DB5</text>
<text x="298.4" y="113.5">DB6</text>
<text x="361.9" y="108.4">TG1</text>
<text x="361.9" y="113.5">TG3</text>
<text x="361.9" y="110.9">TG2</text>
<text x="31.7" y="116">0000'0000'1000'XXXX (&amp;008X) -&gt; 16 bytes of NVRAM/clock data</text>
<text x="31.7" y="119.8">0000'0000'1001'00xx (&amp;0090-93) -&gt; NVRAM addr offset (bits 4-10). Clock = &amp;7F</text>
<text x="146" y="118.6">AB2</text>
<text x="161.3" y="115.4">IC161</text>
<text x="189.2" y="118.6">&amp;0090-&amp;0093</text>
<text x="207" y="118.6">NVRAMOFS</text>
<text x="298.4" y="116">DB7</text>
<text x="344.1" y="118.6">TG4</text>
<text x="344.1" y="116">CSELC</text>
<text x="361.9" y="116">TG4</text>
<text x="361.9" y="118.6">TG5</text>
<text x="31.7" y="123.6">0000'0000'1001'01xx (&amp;0094-97) -&gt; Timer #1</text>
<text x="146" y="121.1">AB3</text>
<text x="189.2" y="121.1">&amp;0094-&amp;0097</text>
<text x="189.2" y="123.6">&amp;0098-&amp;009B</text>
<text x="207" y="123.6">TSEL1</text>
<text x="207" y="121.1">TSEL0</text>
<text x="298.4" y="123.6">AB1</text>
<text x="298.4" y="121.1">AB0</text>
<text x="344.1" y="123.6">TO4</text>
<text x="387.5" y="123.6">SV10</text>
<text x="31.7" y="126.2">0000'0000'1001'10xx (&amp;0098-9B) -&gt; Timer #2</text>
<text x="31.7" y="128.7">0000'0000'1001'11xx (&amp;009C-9F) -&gt; Timer Control Register (16 bits)</text>
<text x="148.6" y="128.7" transform="rotate(-90 148.6 128.7)">VCC</text>
<text x="189.2" y="126.2">&amp;009C-&amp;009F</text>
<text x="298.4" y="131.3">W</text>
<text x="361.9" y="128.7">TO0</text>
<text x="361.9" y="131.3">TO1</text>
<text x="99.5" y="136.8">74HC05N</text>
<text x="298.4" y="136.3">R</text>
<text x="344.1" y="136.3">TG5</text>
<text x="344.1" y="133.8">CSELD</text>
<text x="361.9" y="136.3">TO3</text>
<text x="361.9" y="133.8">TO2</text>
<text x="29.4" y="138.9">IRQ[0..7]</text>
<text x="123.2" y="141.4">INTA0</text>
<text x="151.1" y="144">GND</text>
<text x="161.3" y="141.4">74HC138N</text>
<text x="298.4" y="141.4">TSEL1</text>
<text x="344.1" y="141.4">TO5</text>
<text x="361.9" y="138.9">TO4</text>
<text x="361.9" y="141.4">TO5</text>
<text x="32.5" y="144.8">IRQ/26</text>
<text x="99.5" y="149.5">74HC05N</text>
<text x="99.6" y="146.4">IC159A</text>
<text x="163" y="145.7">74HC32N</text>
<text x="316.2" y="146.5">82C54</text>
<text x="387.5" y="146.5">SV11</text>
<text x="64.8" y="154.1">IRQ0</text>
<text x="76.2" y="150.8">SV8</text>
<text x="123.2" y="154.1">INTA1</text>
<text x="165.6" y="154">IC164B</text>
<text x="194.3" y="151.6">W</text>
<text x="64.8" y="156.6">IRQ1</text>
<text x="64.8" y="159.2">IRQ2</text>
<text x="64.8" y="161.7">IRQ</text>
<text x="99.6" y="159.1">IC159B</text>
<text x="148.6" y="161.7">DB0</text>
<text x="275.6" y="159.2">32KHZ</text>
<text x="275.6" y="161.7">TO3</text>
<text x="275.6" y="156.6">CLK1</text>
<text x="318.7" y="156.6">CSELA</text>
<text x="318.7" y="161.7">CSELB</text>
<text x="353.4" y="161.1">IC164C</text>
<text x="388.6" y="161.1">IC157B</text>
<text x="99.5" y="162.2">74HC05N</text>
<text x="123.2" y="166.8">INTA2</text>
<text x="148.6" y="164.3">DB1</text>
<text x="148.6" y="166.8">DB2</text>
<text x="275.6" y="164.3">TO4</text>
<text x="25.4" y="171.9" transform="rotate(-90 25.4 171.9)">VCC</text>
<text x="99.4" y="171.8">IC159C</text>
<text x="148.6" y="169.3">DB3</text>
<text x="148.6" y="171.9">DB4</text>
<text x="275.6" y="171.9">32KHZ</text>
<text x="275.6" y="169.3">CLK1</text>
<text x="350.9" y="169.3">74HC32N</text>
<text x="353.4" y="171.3">IC164D</text>
<text x="388.6" y="169.3">74HC14N</text>
<text x="388.6" y="171.3">IC157C</text>
<text x="36.4" y="175.4" transform="rotate(-90 36.4 175.4)">C195</text>
<text x="41.5" y="175.4" transform="rotate(-90 41.5 175.4)">1uF</text>
<text x="99.5" y="178.7">74HC05N</text>
<text x="148.6" y="174.4">DB5</text>
<text x="148.6" y="177">DB6</text>
<text x="148.6" y="179.5">DB7</text>
<text x="275.6" y="174.4">TO4</text>
<text x="275.6" y="177">TO5</text>
<text x="350.9" y="179.5">74HC32N</text>
<text x="388.6" y="179.5">74HC14N</text>
<text x="30.6" y="184.2">C196</text>
<text x="123.2" y="182">INTB0</text>
<text x="353.4" y="181.4">IC166C</text>
<text x="388.6" y="181.4">IC157D</text>
<text x="30.6" y="189.3">C197</text>
<text x="39.6" y="186.7">0.1uF</text>
<text x="39.6" y="191.8">0.1uF</text>
<text x="76.2" y="191.4">SV9</text>
<text x="99.4" y="187">IC159D</text>
<text x="99.5" y="190.2">74HC05N</text>
<text x="146" y="187.1">TCRSEL</text>
<text x="350.9" y="189.7">74HC02N</text>
<text x="353.4" y="191.6">IC166D</text>
<text x="388.6" y="189.7">74HC14N</text>
<text x="388.6" y="191.6">IC157E</text>
<text x="30.6" y="194.4">C198</text>
<text x="39.6" y="196.9">0.1uF</text>
<text x="64.8" y="194.7">IRQ0</text>
<text x="64.8" y="197.3">IRQ1</text>
<text x="123.2" y="194.7">INTB1</text>
<text x="153.7" y="194.7">GND</text>
<text x="163.8" y="192.2">74HC374N</text>
<text x="295.9" y="194.7">74HC153N</text>
<text x="30.6" y="199.4">C199</text>
<text x="39.6" y="202">0.1uF</text>
<text x="64.8" y="199.8">IRQ2</text>
<text x="64.8" y="202.4">IRQ</text>
<text x="99.5" y="202.9">74HC05N</text>
<text x="99.6" y="199.7">IC159E</text>
<text x="275.6" y="202.4">CLK1</text>
<text x="318.7" y="202.4">CSELC</text>
<text x="350.9" y="199.8">74HC02N</text>
<text x="388.6" y="199.8">74HC14N</text>
<text x="388.6" y="201.7">IC157F</text>
<text x="30.6" y="204.5">C200</text>
<text x="30.6" y="209.6">C201</text>
<text x="39.6" y="207.1">0.1uF</text>
<text x="123.2" y="207.4">INTB2</text>
<text x="189.2" y="207.4" transform="rotate(-90 189.2 207.4)">INTA0</text>
<text x="199.4" y="207.4" transform="rotate(-90 199.4 207.4)">INTA1</text>
<text x="209.5" y="207.4" transform="rotate(-90 209.5 207.4)">INTA2</text>
<text x="222.2" y="207.4" transform="rotate(-90 222.2 207.4)">INTB0</text>
<text x="232.4" y="207.4" transform="rotate(-90 232.4 207.4)">INTB1</text>
<text x="242.5" y="207.4" transform="rotate(-90 242.5 207.4)">INTB2</text>
<text x="275.6" y="204.9">32KHZ</text>
<text x="275.6" y="207.4">TO0</text>
<text x="275.6" y="210">TO1</text>
<text x="318.7" y="207.4">CSELD</text>
<text x="388.6" y="210">74HC14N</text>
<text x="30.6" y="214.7">C202</text>
<text x="39.6" y="212.1">0.1uF</text>
<text x="99.7" y="212.4">IC159F</text>
<text x="275.6" y="215.1">CLK1</text>
<text x="372.1" y="215.1">GND</text>
<text x="30.6" y="219.8">C203</text>
<text x="39.6" y="217.2">0.1uF</text>
<text x="170.6" y="221.9">74HC02N</text>
<text x="186" y="220.1" transform="rotate(-90 186 220.1)">IC165A</text>
<text x="196.2" y="220.1" transform="rotate(-90 196.2 220.1)">IC165B</text>
<text x="206.4" y="220.1" transform="rotate(-90 206.4 220.1)">IC165C</text>
<text x="219.1" y="220.1" transform="rotate(-90 219.1 220.1)">IC165D</text>
<text x="229.2" y="220.1" transform="rotate(-90 229.2 220.1)">IC166A</text>
<text x="239.4" y="220.1" transform="rotate(-90 239.4 220.1)">IC166B</text>
<text x="247.6" y="220.1" transform="rotate(-90 247.6 220.1)">74HC02N</text>
<text x="275.6" y="217.6">32KHZ</text>
<text x="275.6" y="220.1">TO1</text>
<text x="30.6" y="224.8">C204</text>
<text x="39.6" y="222.3">0.1uF</text>
<text x="39.6" y="227.4">0.1uF</text>
<text x="275.6" y="222.7">TO2</text>
<text x="30.6" y="229.9">C205</text>
<text x="39.6" y="232.5">0.1uF</text>
<text x="76.2" y="229.7">IC157A</text>
<text x="107.9" y="232.8">32KHZ</text>
<text x="148.6" y="232.8">DB8</text>
<text x="30.6" y="235">C206</text>
<text x="39.6" y="237.5">0.1uF</text>
<text x="76.2" y="237.9">74HC14N</text>
<text x="148.6" y="237.9">DB10</text>
<text x="148.6" y="235.4">DB9</text>
<text x="30.6" y="240.1">C207</text>
<text x="30.6" y="245.2">C208</text>
<text x="39.6" y="242.6">0.1uF</text>
<text x="71.1" y="241.5">R48</text>
<text x="91.4" y="241.5">R49</text>
<text x="148.6" y="245.5">DB13</text>
<text x="148.6" y="243">DB12</text>
<text x="148.6" y="240.5">DB11</text>
<text x="285.7" y="243">GND</text>
<text x="295.9" y="240.5">74HC153N</text>
<text x="30.6" y="250.2">C209</text>
<text x="39.6" y="247.7">0.1uF</text>
<text x="71.1" y="246.3">10M</text>
<text x="85.1" y="249.6">XTAL3</text>
<text x="91.4" y="246.3">300k</text>
<text x="148.6" y="250.6">DB15</text>
<text x="148.6" y="248.1">DB14</text>
<text x="30.6" y="255.3">C210</text>
<text x="39.6" y="257.9">0.1uF</text>
<text x="39.6" y="252.8">0.1uF</text>
<text x="63.7" y="255.3">C211</text>
<text x="85.1" y="253.2">32.768kHz</text>
<text x="104.4" y="255.3">C212</text>
<text x="63.7" y="260.4">22pF</text>
<text x="104.4" y="260.4">22pF</text>
<text x="146" y="258.2">TCRSEL</text>
<text x="163.8" y="263.3">74HC374N</text>
<text x="194.3" y="260.8" transform="rotate(-90 194.3 260.8)">TO0</text>
<text x="204.4" y="260.8" transform="rotate(-90 204.4 260.8)">TO1</text>
<text x="217.1" y="260.8" transform="rotate(-90 217.1 260.8)">TO2</text>
<text x="227.3" y="260.8" transform="rotate(-90 227.3 260.8)">TO3</text>
<text x="237.5" y="260.8" transform="rotate(-90 237.5 260.8)">TO4</text>
<text x="247.6" y="260.8" transform="rotate(-90 247.6 260.8)">TO5</text>
<text x="262.1" y="260.8" transform="rotate(-90 262.1 260.8)">32KHZ</text>
<text x="267.9" y="260.8" transform="rotate(-90 267.9 260.8)">CLK1</text>
<text x="45.7" y="265.8">GND</text>
<text x="59.7" y="268.4">GND</text>
<text x="100.3" y="268.4">GND</text>
<text x="153.7" y="265.8">GND</text>
<text x="29.5" y="271.8">CLK1/7</text>
</g>
<g font-size="2.1">
<text x="312.7" y="42">8</text>
<text x="312.7" y="44.6">7</text>
<text x="312.7" y="47.1">6</text>
<text x="318.5" y="43.1">D0</text>
<text x="318.5" y="45.7">D1</text>
<text x="327.2" y="45.7">GATE0</text>
<text x="328.8" y="43.1">CLK0</text>
<text x="338.8" y="42">9</text>
<text x="338.8" y="44.6">11</text>
<text x="312.7" y="49.6">5</text>
<text x="312.7" y="52.2">4</text>
<text x="318.5" y="48.2">D2</text>
<text x="318.5" y="50.7">D3</text>
<text x="318.5" y="53.3">D4</text>
<text x="328.5" y="50.7">OUT0</text>
<text x="338.8" y="49.6">10</text>
<text x="228.3" y="54.7">8</text>
<text x="228.3" y="57.2">7</text>
<text x="228.3" y="59.8">6</text>
<text x="232.2" y="55.8">A0</text>
<text x="232.2" y="58.4">A1</text>
<text x="243.4" y="55.8">DQ0</text>
<text x="243.4" y="58.4">DQ1</text>
<text x="250.5" y="54.7">9</text>
<text x="250.5" y="57.2">10</text>
<text x="250.5" y="59.8">11</text>
<text x="312.7" y="54.7">3</text>
<text x="312.7" y="57.2">2</text>
<text x="312.7" y="59.8">1</text>
<text x="318.5" y="55.8">D5</text>
<text x="318.5" y="58.4">D6</text>
<text x="338.8" y="59.8">15</text>
<text x="160.3" y="64.9">3</text>
<text x="166.1" y="66">1D</text>
<text x="173.9" y="66">1Q</text>
<text x="181.4" y="64.9">2</text>
<text x="228.3" y="62.3">5</text>
<text x="228.3" y="64.9">4</text>
<text x="232.2" y="60.9">A2</text>
<text x="232.2" y="63.4">A3</text>
<text x="232.2" y="66">A4</text>
<text x="243.4" y="60.9">DQ2</text>
<text x="243.4" y="63.4">DQ3</text>
<text x="243.4" y="66">DQ4</text>
<text x="250.5" y="62.3">13</text>
<text x="250.5" y="64.9">14</text>
<text x="311.5" y="64.9">19</text>
<text x="318.5" y="60.9">D7</text>
<text x="318.5" y="66">A0</text>
<text x="327.2" y="63.4">GATE1</text>
<text x="328.8" y="60.9">CLK1</text>
<text x="338.8" y="62.3">14</text>
<text x="160.3" y="67.4">4</text>
<text x="160.3" y="69.9">7</text>
<text x="166.1" y="68.5">2D</text>
<text x="166.1" y="71.1">3D</text>
<text x="173.9" y="68.5">2Q</text>
<text x="173.9" y="71.1">3Q</text>
<text x="181.4" y="67.4">5</text>
<text x="181.4" y="69.9">6</text>
<text x="228.3" y="67.4">3</text>
<text x="228.3" y="69.9">2</text>
<text x="232.2" y="68.5">A5</text>
<text x="232.2" y="71.1">A6</text>
<text x="243.4" y="68.5">DQ5</text>
<text x="243.4" y="71.1">DQ6</text>
<text x="250.5" y="67.4">15</text>
<text x="250.5" y="69.9">16</text>
<text x="311.5" y="67.4">20</text>
<text x="318.5" y="68.5">A1</text>
<text x="328.5" y="68.5">OUT1</text>
<text x="338.8" y="67.4">13</text>
<text x="159.1" y="75">13</text>
<text x="159.1" y="77.6">14</text>
<text x="160.3" y="72.5">8</text>
<text x="166.1" y="73.6">4D</text>
<text x="166.1" y="76.1">5D</text>
<text x="173.9" y="73.6">4Q</text>
<text x="173.9" y="76.1">5Q</text>
<text x="181.4" y="72.5">9</text>
<text x="181.4" y="75">12</text>
<text x="181.4" y="77.6">15</text>
<text x="227.1" y="75">23</text>
<text x="227.1" y="77.6">22</text>
<text x="228.3" y="72.5">1</text>
<text x="232.2" y="73.6">A7</text>
<text x="232.2" y="76.1">A8</text>
<text x="243.4" y="73.6">DQ7</text>
<text x="250.5" y="72.5">17</text>
<text x="311.5" y="75">23</text>
<text x="318.5" y="76.1">WR</text>
<text x="338.8" y="77.6">18</text>
<text x="71.4" y="82.6">1</text>
<text x="77.3" y="83.8">A</text>
<text x="87.8" y="83.8">Y0</text>
<text x="95" y="82.6">15</text>
<text x="159.1" y="80.1">17</text>
<text x="159.1" y="82.6">18</text>
<text x="166.1" y="78.7">6D</text>
<text x="166.1" y="81.2">7D</text>
<text x="166.1" y="83.8">8D</text>
<text x="173.9" y="78.7">6Q</text>
<text x="173.9" y="81.2">7Q</text>
<text x="173.9" y="83.8">8Q</text>
<text x="181.4" y="80.1">16</text>
<text x="181.4" y="82.6">19</text>
<text x="227.1" y="80.1">19</text>
<text x="232.2" y="78.7">A9</text>
<text x="232.2" y="81.2">A10</text>
<text x="311.5" y="80.1">22</text>
<text x="318.5" y="81.2">RD</text>
<text x="327.2" y="81.2">GATE2</text>
<text x="328.8" y="78.7">CLK2</text>
<text x="338.8" y="80.1">16</text>
<text x="71.4" y="85.2">2</text>
<text x="71.4" y="87.7">3</text>
<text x="77.3" y="86.3">B</text>
<text x="77.3" y="88.8">C</text>
<text x="87.8" y="88.8">Y2</text>
<text x="87.8" y="86.3">Y1</text>
<text x="95" y="87.7">13</text>
<text x="95" y="85.2">14</text>
<text x="160.3" y="87.7">1</text>
<text x="166.1" y="88.8">OC</text>
<text x="227.1" y="85.2">21</text>
<text x="227.1" y="87.7">18</text>
<text x="232.2" y="86.3">W</text>
<text x="232.2" y="88.8">E</text>
<text x="311.5" y="85.2">21</text>
<text x="318.5" y="86.3">CS</text>
<text x="328.5" y="86.3">OUT2</text>
<text x="338.8" y="85.2">17</text>
<text x="71.4" y="95.3">6</text>
<text x="87.8" y="93.9">Y4</text>
<text x="87.8" y="91.4">Y3</text>
<text x="95" y="95.3">10</text>
<text x="95" y="92.8">11</text>
<text x="95" y="90.3">12</text>
<text x="159.1" y="90.3">11</text>
<text x="166.1" y="91.4">CLK</text>
<text x="227.1" y="90.3">20</text>
<text x="232.2" y="91.4">G</text>
<text x="369.2" y="90.3" transform="rotate(-90 369.2 90.3)">1</text>
<text x="71.4" y="97.9">4</text>
<text x="71.4" y="100.4">5</text>
<text x="77.3" y="99">G2A</text>
<text x="77.3" y="101.5">G2B</text>
<text x="77.3" y="96.5">G1</text>
<text x="87.8" y="101.5">Y7</text>
<text x="87.8" y="99">Y6</text>
<text x="87.8" y="96.5">Y5</text>
<text x="95" y="100.4">7</text>
<text x="95" y="97.9">9</text>
<text x="312.7" y="97.9">8</text>
<text x="312.7" y="100.4">7</text>
<text x="318.5" y="99">D0</text>
<text x="318.5" y="101.5">D1</text>
<text x="327.2" y="101.5">GATE0</text>
<text x="328.8" y="99">CLK0</text>
<text x="338.8" y="97.9">9</text>
<text x="338.8" y="100.4">11</text>
<text x="170.4" y="105.5">3</text>
<text x="181.4" y="103">2</text>
<text x="312.7" y="103">6</text>
<text x="312.7" y="105.5">5</text>
<text x="318.5" y="104.1">D2</text>
<text x="318.5" y="106.6">D3</text>
<text x="328.5" y="106.6">OUT0</text>
<text x="338.8" y="105.5">10</text>
<text x="369.2" y="102.3" transform="rotate(-90 369.2 102.3)">2</text>
<text x="371.7" y="102.3" transform="rotate(-90 371.7 102.3)">3</text>
<text x="374.3" y="102.3" transform="rotate(-90 374.3 102.3)">4</text>
<text x="376.8" y="102.3" transform="rotate(-90 376.8 102.3)">5</text>
<text x="379.3" y="102.3" transform="rotate(-90 379.3 102.3)">6</text>
<text x="381.9" y="102.3" transform="rotate(-90 381.9 102.3)">7</text>
<text x="386.3" y="105.5">1</text>
<text x="181.4" y="108">1</text>
<text x="312.7" y="108">4</text>
<text x="312.7" y="110.6">3</text>
<text x="312.7" y="113.1">2</text>
<text x="318.5" y="109.2">D4</text>
<text x="318.5" y="111.7">D5</text>
<text x="386.3" y="108">2</text>
<text x="386.3" y="110.6">3</text>
<text x="386.3" y="113.1">4</text>
<text x="157.8" y="118.2">1</text>
<text x="163.6" y="119.3">A</text>
<text x="174.1" y="119.3">Y0</text>
<text x="181.4" y="118.2">15</text>
<text x="312.7" y="115.7">1</text>
<text x="318.5" y="114.2">D6</text>
<text x="318.5" y="116.8">D7</text>
<text x="327.2" y="119.3">GATE1</text>
<text x="328.8" y="116.8">CLK1</text>
<text x="338.8" y="115.7">15</text>
<text x="338.8" y="118.2">14</text>
<text x="386.3" y="115.7">5</text>
<text x="386.3" y="118.2">6</text>
<text x="157.8" y="120.7">2</text>
<text x="157.8" y="123.3">3</text>
<text x="163.6" y="121.9">B</text>
<text x="163.6" y="124.4">C</text>
<text x="174.1" y="124.4">Y2</text>
<text x="174.1" y="121.9">Y1</text>
<text x="181.4" y="125.8">12</text>
<text x="181.4" y="123.3">13</text>
<text x="181.4" y="120.7">14</text>
<text x="311.5" y="120.7">19</text>
<text x="311.5" y="123.3">20</text>
<text x="318.5" y="121.9">A0</text>
<text x="318.5" y="124.4">A1</text>
<text x="328.5" y="124.4">OUT1</text>
<text x="338.8" y="123.3">13</text>
<text x="157.8" y="130.9">6</text>
<text x="174.1" y="129.5">Y4</text>
<text x="174.1" y="126.9">Y3</text>
<text x="181.4" y="130.9">10</text>
<text x="181.4" y="128.4">11</text>
<text x="311.5" y="130.9">23</text>
<text x="386.3" y="128.4">1</text>
<text x="386.3" y="130.9">2</text>
<text x="157.8" y="133.4">4</text>
<text x="157.8" y="136">5</text>
<text x="163.6" y="134.6">G2A</text>
<text x="163.6" y="137.1">G2B</text>
<text x="163.6" y="132">G1</text>
<text x="174.1" y="137.1">Y7</text>
<text x="174.1" y="134.6">Y6</text>
<text x="174.1" y="132">Y5</text>
<text x="181.4" y="136">7</text>
<text x="181.4" y="133.4">9</text>
<text x="311.5" y="136">22</text>
<text x="318.5" y="132">WR</text>
<text x="318.5" y="137.1">RD</text>
<text x="327.2" y="137.1">GATE2</text>
<text x="328.8" y="134.6">CLK2</text>
<text x="338.8" y="133.4">18</text>
<text x="338.8" y="136">16</text>
<text x="386.3" y="133.4">3</text>
<text x="386.3" y="136">4</text>
<text x="101.9" y="141.1">2</text>
<text x="117.9" y="141.1">1</text>
<text x="311.5" y="141.1">21</text>
<text x="318.5" y="142.2">CS</text>
<text x="328.5" y="142.2">OUT2</text>
<text x="338.8" y="141.1">17</text>
<text x="386.3" y="138.5">5</text>
<text x="386.3" y="141.1">6</text>
<text x="170.4" y="148.7">6</text>
<text x="181.4" y="146.1">5</text>
<text x="73.9" y="153.8">8</text>
<text x="84.9" y="153.8">7</text>
<text x="101.9" y="153.8">4</text>
<text x="117.9" y="153.8">3</text>
<text x="181.4" y="151.2">4</text>
<text x="73.9" y="161.4">2</text>
<text x="73.9" y="158.8">4</text>
<text x="73.9" y="156.3">6</text>
<text x="84.9" y="161.4">1</text>
<text x="84.9" y="158.8">3</text>
<text x="84.9" y="156.3">5</text>
<text x="160.3" y="161.4">3</text>
<text x="181.4" y="161.4">2</text>
<text x="292.4" y="161.4">4</text>
<text x="292.4" y="158.8">5</text>
<text x="292.4" y="156.3">6</text>
<text x="298.2" y="159.9">1C1</text>
<text x="298.2" y="157.4">1C0</text>
<text x="306.2" y="157.4">1Y</text>
<text x="313.4" y="156.3">7</text>
<text x="313.4" y="161.4">9</text>
<text x="369.3" y="161.4">9</text>
<text x="101.9" y="166.5">6</text>
<text x="117.9" y="166.5">5</text>
<text x="160.3" y="163.9">4</text>
<text x="160.3" y="166.5">7</text>
<text x="166.1" y="162.5">1D</text>
<text x="166.1" y="165">2D</text>
<text x="166.1" y="167.6">3D</text>
<text x="173.9" y="162.5">1Q</text>
<text x="173.9" y="165">2Q</text>
<text x="173.9" y="167.6">3Q</text>
<text x="181.4" y="163.9">5</text>
<text x="181.4" y="166.5">6</text>
<text x="292.4" y="163.9">3</text>
<text x="298.2" y="165">1C3</text>
<text x="298.2" y="162.5">1C2</text>
<text x="306.2" y="162.5">2Y</text>
<text x="358.4" y="163.9">8</text>
<text x="369.3" y="166.5">10</text>
<text x="377.5" y="163.9">11</text>
<text x="394.7" y="163.9">10</text>
<text x="159.1" y="171.5">13</text>
<text x="160.3" y="169">8</text>
<text x="166.1" y="170.1">4D</text>
<text x="166.1" y="172.6">5D</text>
<text x="173.9" y="170.1">4Q</text>
<text x="173.9" y="172.6">5Q</text>
<text x="181.4" y="169">9</text>
<text x="181.4" y="171.5">12</text>
<text x="291.2" y="169">10</text>
<text x="291.2" y="171.5">11</text>
<text x="298.2" y="170.1">2C0</text>
<text x="298.2" y="172.6">2C1</text>
<text x="369.3" y="171.5">12</text>
<text x="159.1" y="174.1">14</text>
<text x="159.1" y="176.6">17</text>
<text x="159.1" y="179.1">18</text>
<text x="166.1" y="175.2">6D</text>
<text x="166.1" y="177.7">7D</text>
<text x="173.9" y="175.2">6Q</text>
<text x="173.9" y="177.7">7Q</text>
<text x="181.4" y="174.1">15</text>
<text x="181.4" y="176.6">16</text>
<text x="181.4" y="179.1">19</text>
<text x="291.2" y="174.1">12</text>
<text x="291.2" y="176.6">13</text>
<text x="298.2" y="175.2">2C2</text>
<text x="298.2" y="177.7">2C3</text>
<text x="357.2" y="174.1">11</text>
<text x="369.3" y="176.6">13</text>
<text x="378.7" y="174.1">9</text>
<text x="394.7" y="174.1">8</text>
<text x="101.9" y="181.7">8</text>
<text x="117.9" y="181.7">9</text>
<text x="160.3" y="184.2">1</text>
<text x="166.1" y="185.3">OC</text>
<text x="166.1" y="180.3">8D</text>
<text x="173.9" y="180.3">8Q</text>
<text x="291.2" y="181.7">14</text>
<text x="292.4" y="184.2">2</text>
<text x="298.2" y="185.3">B</text>
<text x="298.2" y="182.8">A</text>
<text x="357.2" y="184.2">10</text>
<text x="369.3" y="181.7">8</text>
<text x="378.7" y="184.2">1</text>
<text x="394.7" y="184.2">2</text>
<text x="159.1" y="186.8">11</text>
<text x="166.1" y="187.9">CLK</text>
<text x="291.2" y="189.3">15</text>
<text x="292.4" y="186.8">1</text>
<text x="298.2" y="187.9">1G</text>
<text x="298.2" y="190.4">2G</text>
<text x="369.3" y="186.8">9</text>
<text x="369.3" y="191.8">11</text>
<text x="73.9" y="196.9">6</text>
<text x="73.9" y="194.4">8</text>
<text x="84.9" y="196.9">5</text>
<text x="84.9" y="194.4">7</text>
<text x="100.7" y="194.4">10</text>
<text x="117.9" y="194.4">11</text>
<text x="357.2" y="194.4">13</text>
<text x="369.3" y="196.9">12</text>
<text x="378.7" y="194.4">3</text>
<text x="394.7" y="194.4">4</text>
<text x="73.9" y="202">2</text>
<text x="73.9" y="199.5">4</text>
<text x="84.9" y="202">1</text>
<text x="84.9" y="199.5">3</text>
<text x="292.4" y="202">6</text>
<text x="298.2" y="203.1">1C0</text>
<text x="306.2" y="203.1">1Y</text>
<text x="313.4" y="202">7</text>
<text x="100.7" y="207.1">12</text>
<text x="117.9" y="207.1">13</text>
<text x="292.4" y="209.6">3</text>
<text x="292.4" y="207.1">4</text>
<text x="292.4" y="204.5">5</text>
<text x="298.2" y="208.2">1C2</text>
<text x="298.2" y="205.7">1C1</text>
<text x="306.2" y="208.2">2Y</text>
<text x="313.4" y="207.1">9</text>
<text x="378.7" y="204.5">5</text>
<text x="394.7" y="204.5">6</text>
<text x="291.2" y="214.7">10</text>
<text x="298.2" y="210.7">1C3</text>
<text x="298.2" y="215.8">2C0</text>
<text x="188.9" y="217.8" transform="rotate(-90 188.9 217.8)">1</text>
<text x="199" y="217.8" transform="rotate(-90 199 217.8)">4</text>
<text x="209.2" y="217.8" transform="rotate(-90 209.2 217.8)">10</text>
<text x="221.9" y="217.8" transform="rotate(-90 221.9 217.8)">13</text>
<text x="232" y="217.8" transform="rotate(-90 232 217.8)">1</text>
<text x="242.2" y="217.8" transform="rotate(-90 242.2 217.8)">4</text>
<text x="291.2" y="217.2">11</text>
<text x="291.2" y="219.8">12</text>
<text x="298.2" y="218.4">2C1</text>
<text x="298.2" y="220.9">2C2</text>
<text x="291.2" y="222.3">13</text>
<text x="291.2" y="227.4">14</text>
<text x="298.2" y="223.4">2C3</text>
<text x="65.1" y="232.5">13</text>
<text x="82.3" y="232.5">12</text>
<text x="160.3" y="232.5">3</text>
<text x="166.1" y="233.6">1D</text>
<text x="173.9" y="233.6">1Q</text>
<text x="181.4" y="232.5">2</text>
<text x="186.3" y="228.7" transform="rotate(-90 186.3 228.7)">2</text>
<text x="191.4" y="228.7" transform="rotate(-90 191.4 228.7)">3</text>
<text x="196.5" y="228.7" transform="rotate(-90 196.5 228.7)">5</text>
<text x="201.6" y="228.7" transform="rotate(-90 201.6 228.7)">6</text>
<text x="206.6" y="228.7" transform="rotate(-90 206.6 228.7)">8</text>
<text x="211.7" y="228.7" transform="rotate(-90 211.7 228.7)">9</text>
<text x="219.3" y="229.9" transform="rotate(-90 219.3 229.9)">11</text>
<text x="224.4" y="229.9" transform="rotate(-90 224.4 229.9)">12</text>
<text x="229.5" y="228.7" transform="rotate(-90 229.5 228.7)">2</text>
<text x="234.6" y="228.7" transform="rotate(-90 234.6 228.7)">3</text>
<text x="239.6" y="228.7" transform="rotate(-90 239.6 228.7)">5</text>
<text x="244.7" y="228.7" transform="rotate(-90 244.7 228.7)">6</text>
<text x="292.4" y="232.5">1</text>
<text x="292.4" y="229.9">2</text>
<text x="298.2" y="233.6">1G</text>
<text x="298.2" y="231.1">B</text>
<text x="298.2" y="228.5">A</text>
<text x="160.3" y="235">4</text>
<text x="160.3" y="237.6">7</text>
<text x="166.1" y="236.1">2D</text>
<text x="166.1" y="238.7">3D</text>
<text x="173.9" y="236.1">2Q</text>
<text x="173.9" y="238.7">3Q</text>
<text x="181.4" y="235">5</text>
<text x="181.4" y="237.6">6</text>
<text x="291.2" y="235">15</text>
<text x="298.2" y="236.1">2G</text>
<text x="159.1" y="242.6">13</text>
<text x="159.1" y="245.2">14</text>
<text x="160.3" y="240.1">8</text>
<text x="166.1" y="241.2">4D</text>
<text x="166.1" y="243.8">5D</text>
<text x="173.9" y="241.2">4Q</text>
<text x="173.9" y="243.8">5Q</text>
<text x="181.4" y="240.1">9</text>
<text x="181.4" y="242.6">12</text>
<text x="181.4" y="245.2">15</text>
<text x="159.1" y="247.7">17</text>
<text x="159.1" y="250.3">18</text>
<text x="166.1" y="246.3">6D</text>
<text x="166.1" y="248.8">7D</text>
<text x="166.1" y="251.4">8D</text>
<text x="173.9" y="246.3">6Q</text>
<text x="173.9" y="248.8">7Q</text>
<text x="173.9" y="251.4">8Q</text>
<text x="181.4" y="247.7">16</text>
<text x="181.4" y="250.3">19</text>
<text x="159.1" y="257.9">11</text>
<text x="160.3" y="255.3">1</text>
<text x="166.1" y="256.5">OC</text>
<text x="166.1" y="259">CLK</text>
</g>
</g></defs>
<g fill="#000" stroke="#000" stroke-width=".21">
<path d="M67.8 18.2v3.9zM115.3 18.2v3.9zM162.7 18.2v3.9zM210.2 18.2v3.9zM257.6 18.2v3.9zM305.1 18.2v3.9zM352.5 18.2v3.9zM20.3 22.1v252.6zM288.3 39.8l2.5 2.6zM356.8 39.8l-2.5 2.6zM20.3 22.1h379.7zM34.5 46.3h2.4z"/>
<path d="M35.1 41.3h1.8zM41.9 47.5h162.5zM41.9 42.4h157.5zM199.4 42.4h73.6zM204.4 47.5h73.7zM209.5 55.1l2.6 2.5zM209.5 57.6l2.6 2.6zM209.5 52.5l2.6 2.6zM212.1 57.6h15.2zM212.1 55.1h15.2zM227.3 55.1h2.5zM227.3 57.6h2.5z"/>
<path d="M250.2 55.1h2.5zM250.2 57.6h2.5zM252.7 55.1h12.7zM252.7 57.6h12.7zM267.9 52.5l-2.5 2.6zM267.9 55.1l-2.5 2.5zM265.4 60.2l2.5-2.6zM288.3 42.4l2.5 2.5zM288.3 44.9l2.5 2.6zM288.3 47.5l2.5 2.5zM288.3 50l2.5 2.5zM288.3 52.5l2.5 2.6z"/>
<path d="M288.3 55.1l2.5 2.5zM288.3 57.6l2.5 2.6zM290.8 42.4h20.3zM290.8 44.9h20.3zM290.8 47.5h20.3zM290.8 50h20.3zM290.8 52.5h20.3zM290.8 55.1h20.3zM290.8 57.6h20.3zM311.1 42.4h5.1zM311.1 44.9h5.1zM311.1 47.5h5.1z"/>
<path d="M311.1 50h5.1zM311.1 52.5h5.1zM311.1 55.1h5.1zM311.1 57.6h5.1zM336.5 42.4h5.1zM336.5 50h5.1zM336.5 44.9h5.1zM341.6 44.9h12.7zM341.6 50h12.7zM354.3 44.9l2.5-2.5zM354.3 50l2.5-2.5zM341.6 42.4h12.7z"/>
<path d="M16.5 72.6h3.8zM143.5 62.7l2.5 2.5zM143.5 65.2l2.5 2.6zM143.5 67.8l2.5 2.5zM143.5 70.3l2.5 2.5zM143.5 72.8l2.5 2.6zM143.5 75.4l2.5 2.5zM143.5 77.9l2.5 2.6zM146 65.2h12.7zM146 67.8h12.7zM146 70.3h12.7zM146 72.8h12.7z"/>
<path d="M146 75.4h12.7zM146 77.9h12.7zM158.7 65.2h5.1zM158.7 67.8h5.1zM158.7 70.3h5.1zM158.7 72.8h5.1zM158.7 75.4h5.1zM158.7 77.9h5.1zM163.9 62h.5zM163.9 60.3h.5zM164.2 60.3v1.7zM165 60.6v1.1z"/>
<path d="M165 61.7l.2 .3zM165.2 60.3l-.2 .3zM165.2 62h.6zM165.2 60.3h.6zM165.8 62l.3-.3zM165.8 60.3l.3 .3zM167.2 60.3l-.6 .6zM166.6 62h1.1zM167.2 60.3v1.7zM168.3 61.1v.6zM168.3 61.7l.2 .3zM168.5 62h.6z"/>
<path d="M168.3 61.1l.5-.5zM169.3 61.7l-.2 .3zM168.3 61.1h.8zM168.8 60.6l.5-.3zM169.3 61.4v.3zM169.1 61.1l.2 .3zM169.9 60.6v1.1zM170.2 60.3l-.3 .3zM169.9 61.7l1.1-1.1zM170.2 60.3h.5zM169.9 61.7l.3 .3zM170.7 60.3l.3 .3z"/>
<path d="M170.2 62h.5zM171 60.6v1.1zM171 61.7l-.3 .3zM179 65.2h5.1zM179 67.8h5.1zM179 70.3h5.1zM179 72.8h5.1zM179 75.4h5.1zM179 77.9h5.1zM184.1 65.2h43.2zM184.1 67.8h43.2zM184.1 70.3h43.2z"/>
<path d="M184.1 72.8h43.2zM184.1 75.4h43.2zM184.1 77.9h43.2zM209.5 60.2l2.6 2.5zM212.1 60.2h15.2zM212.1 62.7h15.2zM227.3 60.2h2.5zM227.3 62.7h2.5zM227.3 65.2h2.5zM227.3 67.8h2.5zM227.3 70.3h2.5zM227.3 72.8h2.5z"/>
<path d="M227.3 75.4h2.5zM227.3 77.9h2.5zM250.2 60.2h2.5zM250.2 62.7h2.5zM250.2 65.2h2.5zM250.2 67.8h2.5zM250.2 70.3h2.5zM250.2 72.8h2.5zM262.9 75.4v2.5zM262.9 77.9v2.6zM252.7 60.2h12.7zM252.7 62.7h12.7z"/>
<path d="M252.7 65.2h12.7zM252.7 67.8h12.7zM252.7 70.3h12.7zM252.7 72.8h12.7zM265.4 62.7l2.5-2.5zM267.9 62.7l-2.5 2.5zM267.9 65.2l-2.5 2.6zM267.9 67.8l-2.5 2.5zM267.9 70.3l-2.5 2.5zM278.1 47.5v27.9zM278.1 75.4v55.9zM290.8 60.2h20.3z"/>
<path d="M293.3 65.2l2.6 2.6zM293.3 62.7l2.6 2.5zM298.4 73.4h2.4zM298.4 78.4h1.8zM311.1 60.2h5.1zM311.1 75.4h3.1zM311.1 65.2h5.1zM311.1 67.8h5.1zM295.9 67.8h15.2zM295.9 65.2h15.2zM278.1 75.4h33zM318.5 74.4h3.6z"/>
<path d="M318.5 79.5h3.1zM336.5 60.2h5.1zM336.5 67.8h5.1zM336.5 62.7h5.1zM336.5 77.9h5.1zM341.6 62.7h12.7zM341.6 67.8h12.7zM341.6 60.2h12.7zM341.6 77.9h12.7zM354.3 62.7l2.5-2.5zM354.3 67.8l2.5-2.6zM354.3 60.2l2.5-2.6z"/>
<path d="M354.3 77.9l2.5-2.5zM400 72.6h3.8zM29.3 97.1h10.1zM44.4 98.2h25.4zM52.1 80.5l2.5 2.5zM52.1 83l2.5 2.5zM52.1 85.5l2.5 2.6zM54.6 83h15.2zM54.6 85.5h15.2zM54.6 88.1h15.2zM52.1 93.2l2.5 2.5zM57.1 96.2h10.2z"/>
<path d="M69.8 83h5.1zM69.8 85.5h5.1zM69.8 88.1h5.1zM69.8 98.2h3.1zM69.8 95.7h5.1zM54.6 95.7h15.2zM94.7 98.2h3.1zM94.7 95.7h3.1zM94.7 93.2h3.1zM94.7 90.6h3.1zM94.7 88.1h3.1zM94.7 85.5h3.1z"/>
<path d="M94.7 83h3.1zM97.8 83h35.5zM97.8 85.5h30.4zM110.5 81h9zM110.5 83.5h12.5zM128.2 85.5v48.3zM133.3 83v15.2zM133.3 98.2h76.2zM146 80.5h12.7zM151.1 90.6v2.6zM151.1 88.1v2.5zM151.1 83v5.1z"/>
<path d="M158.7 88.1h3.1zM158.7 90.6h5.1zM158.7 80.5h5.1zM158.7 83h5.1zM151.1 88.1h7.6zM151.1 83h7.6zM156.2 90.6h2.5zM163.8 89.6l2 1zM163.8 91.6l2-1zM179 80.5h5.1zM179 83h5.1zM184.1 80.5h43.2z"/>
<path d="M199.4 42.4v48.2zM204.4 47.5v38zM209.5 88.1v10.1zM209.5 88.1h17.8zM214.6 86.1h9zM214.6 83.5h2.4zM214.6 88.6h1.8zM227.3 80.5h2.5zM227.3 85.5h2.5zM227.3 88.1h2.5zM227.3 90.6h2.5zM204.4 85.5h22.9z"/>
<path d="M199.4 90.6h27.9zM232.2 84.6h2zM232.2 87.1h1.4zM232.2 89.7h1.6zM257.8 83v2.5zM257.8 88.1v2.5zM257.8 85.5v.5zM257.8 87.6v.5zM257.8 80.5v2.5zM257.8 80.5h5.1zM257.8 90.6v2.6zM257.8 93.2h5.1z"/>
<path d="M262.9 95.7v2.5zM262.9 80.5h5zM262.9 93.2h5zM262.9 93.2v2.5zM267.9 86.8v2.5zM267.9 84.3v2.5zM267.9 80.5v3.8zM267.9 89.3v3.9zM273 80.5h38.1zM273 80.5v55.8zM273 42.4v38.1zM288.3 95.7l2.5 2.5z"/>
<path d="M288.3 98.2l2.5 2.6zM290.8 98.2h20.3zM297.2 98v1zM297.2 95.9v1.1zM297.2 93.9v1.1zM297.2 91.9v1zM297.2 91.9h1zM298.4 83.5h7.6zM299.2 91.9h1zM301.2 91.9h1zM303.2 91.9h1.1zM305.3 91.9h1z"/>
<path d="M307.3 91.9h1zM309.3 91.9h1.1zM311.1 80.5h3.1zM311.1 85.5h3.1zM311.1 98.2h5.1zM283.2 85.5h27.9zM311.4 91.9h1zM313.4 91.9h1zM315.4 91.9h1.1zM317.5 91.9h1zM318.5 84.6h3zM319.5 91.9h1z"/>
<path d="M321.5 91.9h1.1zM323.5 91.9h1.1zM325.6 91.9h1zM327.6 91.9h1zM329.6 91.9h1.1zM331.7 91.9h1zM333.7 91.9h1zM335.7 91.9h1.1zM337.8 91.9h1zM339.8 91.9h1zM336.5 85.5h5.1zM336.5 80.5h5.1z"/>
<path d="M336.5 98.2h5.1zM341.6 80.5h12.7zM341.6 85.5h12.7zM341.6 98.2h12.7zM341.8 91.9h1.1zM343.9 91.9h1zM345.9 91.9h1zM347.9 91.9h1zM350 91.9h1zM353 98v1zM353 95.9v1.1zM353 93.9v1.1z"/>
<path d="M353 91.9v1zM352 91.9h1zM354.3 80.5l2.5-2.6zM354.3 85.5l2.5-2.5zM354.3 98.2l2.5-2.5zM369.5 88.1v2.5zM369.5 99.5v1.3zM369.5 93.2v1.2zM369.5 93.2h2.6zM369.5 90.6v2.6zM369.5 83v2.5zM369.5 85.5v2.6z"/>
<path d="M372.1 93.2v1.2zM372.1 93.2h2.5zM374.6 93.2v1.2zM374.6 93.2h2.5zM377.1 93.2v1.2zM377.1 93.2h2.6zM379.7 93.2v1.2zM379.7 93.2h2.5zM382.2 93.2v1.2zM67.3 105.9v2.5zM67.3 100.8v5.1zM69.8 100.8h3.1z"/>
<path d="M67.3 100.8h2.5zM94.7 100.8h3.1zM138.4 116l2.5 2.6zM156.2 118.6h5.1zM140.9 118.6h15.3zM156.2 90.6v15.3zM168.9 105.9h5.1zM156.2 105.9h12.7zM174.7 108.4h4.3zM174.7 103.3h4.3zM181 118.6h3.1zM179 108.4h5.1z"/>
<path d="M179 103.3h5.1zM184.1 118.6h2.6zM184.1 108.4h2.6zM184.1 103.3h20.3zM186.7 108.4v10.2zM194.3 101.3h2.3zM204.4 103.3v48.3zM204.4 85.5v17.8zM207 116.5h14.1zM207 119.1h7.6zM288.3 100.8l2.5 2.5zM288.3 103.3l2.5 2.6z"/>
<path d="M288.3 105.9l2.5 2.5zM288.3 108.4l2.5 2.5zM288.3 110.9l2.5 2.6zM288.3 113.5l2.5 2.5zM290.8 100.8h20.3zM290.8 103.3h20.3zM290.8 105.9h20.3zM290.8 108.4h20.3zM290.8 110.9h20.3zM290.8 113.5h20.3zM290.8 116h20.3zM297.2 118.3v1z"/>
<path d="M297.2 116.3v1zM297.2 114.2v1.1zM297.2 112.2v1zM297.2 110.2v1zM297.2 108.1v1.1zM297.2 106.1v1zM297.2 104.1v1zM297.2 102v1.1zM297.2 100v1zM311.1 100.8h5.1zM311.1 103.3h5.1zM311.1 105.9h5.1z"/>
<path d="M311.1 108.4h5.1zM311.1 110.9h5.1zM311.1 113.5h5.1zM311.1 116h5.1zM336.5 105.9h5.1zM336.5 100.8h5.1zM336.5 116h5.1zM336.5 118.6h5.1zM341.6 100.8h12.7zM341.6 105.9h12.7zM341.6 118.6h12.7zM341.6 116h12.7z"/>
<path d="M353 118.3v1zM353 116.3v1zM353 114.2v1.1zM353 112.2v1zM353 110.2v1zM353 108.1v1.1zM353 106.1v1zM353 104.1v1zM353 102v1.1zM353 100v1zM354.3 100.8l2.5-2.6zM354.3 105.9l2.5-2.6z"/>
<path d="M354.3 118.6l2.5-2.6zM354.3 116l2.5-2.5zM356.8 103.3l2.6 2.6zM359.4 108.4h12.7zM356.8 105.9l2.6 2.5zM359.4 113.5h17.7zM356.8 110.9l2.6 2.6zM359.4 116h20.3zM356.8 113.5l2.6 2.5zM359.4 110.9h15.2zM356.8 108.4l2.6 2.5zM359.4 118.6h22.8z"/>
<path d="M356.8 116l2.6 2.6zM369.5 100.8v2.5zM369.5 105.9h15.3zM369.5 103.3v2.6zM359.4 105.9h10.1zM372.1 100.8v2.5zM372.1 99.5v1.3zM372.1 108.4h12.7zM372.1 103.3v5.1zM374.6 100.8v2.5zM374.6 99.5v1.3zM374.6 110.9h10.2z"/>
<path d="M374.6 103.3v7.6zM377.1 100.8v2.5zM377.1 99.5v1.3zM377.1 113.5h7.7zM377.1 103.3v10.2zM379.7 100.8v2.5zM379.7 99.5v1.3zM379.7 116h5.1zM379.7 103.3v12.7zM382.2 100.8v2.5zM382.2 99.5v1.3zM382.2 118.6h2.6z"/>
<path d="M382.2 103.3v15.3zM384.8 105.9h5zM384.8 108.4h5zM384.8 110.9h5zM384.8 113.5h5zM384.8 116h5zM384.8 118.6h5zM16.5 123.1h3.8zM29.4 136.9h10zM128.2 133.8h28zM138.4 118.6l2.5 2.5zM151.1 126.2v2.5z"/>
<path d="M151.1 128.7v2.6zM153.6 138.9v2.5zM153.6 123.6v12.7zM153.6 136.3v2.6zM156.2 121.1h5.1zM156.2 123.6h5.1zM156.2 133.8h3.1zM156.2 136.3h3.1zM156.2 131.3h5.1zM151.1 131.3h5.1zM153.6 123.6h2.6zM153.6 136.3h2.6z"/>
<path d="M140.9 121.1h15.3zM181 136.3h3.1zM181 133.8h3.1zM181 131.3h3.1zM181 128.7h3.1zM181 126.2h3.1zM181 123.6h3.1zM181 121.1h3.1zM184.1 121.1h99.1zM184.1 126.2h2.6zM186.7 126.2v20.3zM207 121.6h7.6z"/>
<path d="M273 136.3h38.1zM278.1 131.3h33zM184.1 123.6h99.1zM283.2 85.5v35.6zM293.3 121.1l2.6 2.5zM293.3 118.6l2.6 2.5zM297.2 138.6v1zM297.2 136.6v1zM297.2 134.5v1.1zM297.2 132.5v1zM297.2 130.5v1zM297.2 128.5v1z"/>
<path d="M297.2 126.4v1zM297.2 124.4v1zM297.2 122.4v1zM297.2 120.3v1zM298.4 129.2h2.4zM298.4 134.3h1.8zM298.4 139.4h7.6zM311.1 131.3h3.1zM311.1 136.3h3.1zM311.1 121.1h5.1zM311.1 123.6h5.1zM295.9 123.6h15.2z"/>
<path d="M295.9 121.1h15.2zM318.5 130.3h3.6zM318.5 135.4h3.1zM336.5 123.6h5.1zM336.5 133.8h5.1zM336.5 136.3h5.1zM341.6 123.6h12.7zM341.6 136.3h12.7zM341.6 133.8h12.7zM353 138.6v1zM353 136.6v1zM353 134.5v1.1z"/>
<path d="M353 132.5v1zM353 130.5v1zM353 128.5v1zM353 126.4v1zM353 124.4v1zM353 122.4v1zM353 120.3v1zM354.3 123.6l2.5-2.5zM354.3 136.3l2.5-2.5zM354.3 133.8l2.5-2.5zM356.8 126.2l2.6 2.5zM356.8 128.7l2.6 2.6z"/>
<path d="M356.8 133.8l2.6 2.5zM356.8 136.3l2.6 2.6zM356.8 131.3l2.6 2.5zM384.8 128.7h5zM384.8 131.3h5zM384.8 133.8h5zM384.8 136.3h5zM384.8 138.9h5zM359.4 128.7h25.4zM359.4 131.3h25.4zM359.4 136.3h25.4zM359.4 138.9h25.4z"/>
<path d="M359.4 133.8h25.4zM400 123.1h3.8zM32.5 142.8h4.4zM41.9 144h12.7zM59.7 151.6l2.5 2.5zM59.7 154.1l2.5 2.6zM59.7 156.7l2.5 2.5zM62.2 154.1h10.2zM62.2 156.7h10.2zM62.2 159.2h10.2zM64.8 152.1h5.8zM64.8 154.6h5.8z"/>
<path d="M64.8 157.2h5.8zM64.8 159.7h4.4zM72.4 159.2h5.1zM72.4 156.7h5.1zM72.4 154.1h5.1zM82.5 159.2h5.1zM82.5 156.7h5.1zM82.5 154.1h5.1zM87.6 156.7h2.6zM87.6 154.1h2.6zM90.2 154.1v2.6zM90.2 156.7v2.5z"/>
<path d="M90.2 159.2v2.5zM87.6 159.2h2.6zM95.2 141.4v12.7zM95.2 154.1v12.7zM100.3 141.4h3.1zM100.3 154.1h3.1zM95.2 141.4h5.1zM95.2 154.1h5.1zM115.6 141.4h5zM115.6 154.1h5zM120.6 141.4h10.2zM120.6 154.1h10.2z"/>
<path d="M130.8 141.4l2.5 2.6zM130.8 154.1l2.5 2.6zM138.4 149v38.1zM143.5 159.2l2.5 2.5zM163.9 158.5h.5zM163.9 156.8h.5zM164.2 156.8v1.7zM165 157.1v1.1zM165 158.2l.2 .3zM165.2 156.8l-.2 .3zM165.2 158.5h.6zM165.2 156.8h.6z"/>
<path d="M166.1 158.2l-.3 .3zM165.8 156.8l.3 .3zM167.2 156.8l-.6 .6zM166.6 158.5h1.1zM167.2 156.8v1.7zM168.3 157.7v.5zM168.3 158.2l.2 .3zM168.5 158.5h.6zM168.8 157.1l-.5 .6zM168.9 149h5.1zM138.4 149h30.5zM169.3 158.2l-.2 .3z"/>
<path d="M168.3 157.7h.8zM168.8 157.1l.5-.3zM169.3 157.9v.3zM169.1 157.7l.2 .2zM169.9 158.5l1.1-1.1zM170.2 156.8l-.3 .3zM170.2 156.8h.5zM169.9 158.5h1.1zM171 157.1v.3zM170.7 156.8l.3 .3zM174.7 151.6h4.3zM174.7 146.5h4.3z"/>
<path d="M179 151.6h5.1zM179 146.5h5.1zM184.1 146.5h2.6zM194.3 149.6h2.3zM184.1 151.6h20.3zM262.9 159.2h27.9zM265.4 156.7h25.4zM283.2 123.6v17.8zM290.8 159.2h5.1zM290.8 156.7h5.1zM295.9 153.4h.6zM295.9 151.8h.6z"/>
<path d="M296.2 151.8v1.6zM297 152v1.1zM297 153.1l.3 .3zM297.2 146.7v1.1zM297.2 144.7v1zM297.2 142.7v1zM297.2 140.6v1.1zM297.3 151.8l-.3 .2zM297.3 153.4h.6zM297.3 151.8h.6zM297.9 153.4l.2-.3zM297.9 151.8l.2 .2z"/>
<path d="M297.2 147.8h1zM299.2 151.8l-.5 .5zM298.7 153.4h1.1zM299.2 151.8v1.6zM299.2 147.8h1zM300.3 152.6v.5zM300.3 153.1l.3 .3zM300.6 153.4h.5zM300.3 152.6l.6-.6zM301.1 153.4l.3-.3zM300.3 152.6h.8zM300.9 152l.5-.2z"/>
<path d="M301.4 152.9v.2zM301.1 152.6l.3 .3zM302 152l.2-.2zM302 152.9v.2zM302 152.9l.2-.3zM302 152v.3zM301.2 147.8h1zM302.2 151.8h.6zM302 153.1l.2 .3zM302 152.3l.2 .3zM302.2 152.6h.6zM302.8 151.8l.2 .2z"/>
<path d="M302.8 152.6l.2 .3zM302.2 153.4h.6zM303 152v.3zM303 152.3l-.2 .3zM303 152.9v.2zM303 153.1l-.2 .3zM303.2 147.8h1.1zM305.3 147.8h1zM307.3 147.8h1zM309.3 147.8h1.1zM311.1 141.4h3.1zM283.2 141.4h27.9z"/>
<path d="M311.4 147.8h1zM313.4 147.8h1zM311.1 156.7h5.1zM316.2 156.7h12.7zM315.4 147.8h1.1zM317.5 147.8h1zM318.5 140.5h3zM319.5 147.8h1zM321.5 147.8h1.1zM323.5 147.8h1.1zM325.6 147.8h1zM327.6 147.8h1z"/>
<path d="M328.9 151.6v5.1zM328.9 151.6l2.5-2.6zM329.6 147.8h1.1zM331.7 147.8h1zM334 151.6l2.5-2.6zM333.7 147.8h1zM335.7 147.8h1.1zM337.8 147.8h1zM339.8 147.8h1zM336.5 141.4h5.1zM341.6 141.4h12.7zM341.8 147.8h1.1z"/>
<path d="M344.1 151.6l2.6-2.6zM343.9 147.8h1zM345.9 147.8h1zM347.9 147.8h1zM349.2 151.6l2.5-2.6zM350 147.8h1zM352 147.8h1zM353 146.7v1.1zM353 144.7v1zM353 142.7v1zM353 140.6v1.1zM354.3 141.4l2.5-2.5z"/>
<path d="M356.8 138.9l2.6 2.5zM384.8 141.4h5zM359.4 141.4h25.4zM16.5 173.7h3.8zM27.9 169.4v2.5zM27.9 171.9v5.1zM27.9 177v7.6zM34.3 177h2.5zM27.9 177h6.4zM36.8 177h.5zM38.9 177h.5zM39.4 177h2.5z"/>
<path d="M41.9 177h6.4zM48.3 177v7.6zM50.8 175.7h1zM50.8 177.8v1.1zM50.8 175.7v1.1zM52.8 175.7h1zM54.6 144v17.7zM54.8 175.7h1zM56.8 175.7h1zM58.8 175.7h1zM60.8 175.7h1zM62.8 175.7h1z"/>
<path d="M64.8 175.7h1zM66.8 175.7h1.1zM68.9 175.7h1zM70.9 175.7h1zM72.4 161.7h5.1zM54.6 161.7h17.8zM72.9 175.7h1zM74.9 175.7h1zM76.9 175.7h1zM78.9 175.7h1zM80.9 175.7h1zM82.9 175.7h1z"/>
<path d="M84.9 175.7h1zM86.9 175.7h1zM82.5 161.7h5.1zM87.6 161.7h2.6zM88.9 175.7h1zM90.2 161.7v5.1zM90.2 166.8h5zM90.9 175.7h1zM92.9 175.7h1zM94.9 175.7h1zM95.2 166.8h5.1zM96.9 175.7h1.1z"/>
<path d="M99 175.7h1zM100.3 166.8h3.1zM101 175.7h1zM103 175.7h1zM105 175.7h1zM107 175.7h1zM109 175.7h1zM111 175.7h1zM113 175.7h1zM115 175.7h1zM117 175.7h1zM119 175.7h1z"/>
<path d="M115.6 166.8h5zM120.6 166.8h10.2zM121 175.7h1zM123 175.7h1zM125 175.7h1zM127 175.7h1.1zM129.1 175.7h1zM130.8 166.8l2.5 2.6zM131.1 175.7h1zM132.1 177.8v1.1zM132.1 175.7v1.1zM143.5 161.7l2.5 2.6z"/>
<path d="M143.5 164.3l2.5 2.5zM143.5 166.8l2.5 2.6zM143.5 169.4l2.5 2.5zM143.5 171.9l2.5 2.5zM143.5 174.4l2.5 2.6zM143.5 177l2.5 2.5zM146 161.7h12.7zM146 164.3h12.7zM146 166.8h12.7zM146 169.4h12.7zM146 171.9h12.7zM146 174.4h12.7z"/>
<path d="M146 177h12.7zM146 179.5h12.7zM158.7 161.7h5.1zM158.7 164.3h5.1zM158.7 166.8h5.1zM158.7 169.4h5.1zM158.7 171.9h5.1zM158.7 174.4h5.1zM158.7 177h5.1zM158.7 179.5h5.1zM179 161.7h5.1zM179 164.3h5.1z"/>
<path d="M179 166.8h5.1zM179 169.4h5.1zM179 171.9h5.1zM179 174.4h5.1zM179 177h5.1zM179 179.5h5.1zM184.1 161.7h76.2zM184.1 164.3h73.7zM184.1 166.8h71.1zM184.1 169.4h68.6zM252.7 169.4v60.9zM255.2 166.8v60.9z"/>
<path d="M257.8 164.3v20.3zM260.3 161.7v20.4zM262.9 171.9h27.9zM262.9 159.2v12.7zM265.4 156.7v12.7zM273 161.7l-2.5 2.6zM270.5 166.8l2.5-2.5zM273 174.4l-2.5 2.6zM273 177l-2.5 2.5zM290.8 164.3h5.1zM290.8 161.7h5.1zM290.8 169.4h5.1z"/>
<path d="M290.8 171.9h5.1zM290.8 174.4h5.1zM290.8 177h5.1zM273 161.7h17.8zM273 164.3h17.8zM273 174.4h17.8zM273 177h17.8zM265.4 169.4h25.4zM311.1 161.7h5.1zM316.2 161.7h17.8zM334 151.6v10.1zM356.8 164.3h5.1z"/>
<path d="M356.8 174.4h5.1zM362.7 161.7h4.3zM362.7 166.8h4.3zM362.7 171.9h4.3zM362.7 177h4.3zM367 161.7h5.1zM367 166.8h5.1zM367 171.9h5.1zM367 177h5.1zM372.1 161.7h2.5zM372.1 166.8h2.5zM372.1 171.9h2.5z"/>
<path d="M372.1 177h2.5zM374.6 164.3v2.5zM374.6 166.8v5.1zM374.6 171.9v2.5zM374.6 174.4v2.6zM374.6 177v5.1zM374.6 161.7v2.6zM377.1 164.3h5.1zM377.1 174.4h5.1zM374.6 164.3h2.5zM374.6 174.4h2.5zM383.4 163h.9z"/>
<path d="M383.4 173.2h.9zM384.3 163h1.2zM384.3 173.2h1.2zM384.3 163l1 2.5zM385.3 165.5h1.2zM384.3 173.2l1 2.5zM385.3 175.7h1.2zM385.5 163l1 2.5zM386.5 165.5h.9zM385.5 173.2l1 2.5zM386.5 175.7h.9zM394.4 164.3h3.1z"/>
<path d="M394.4 174.4h3.1zM400 173.7h3.8zM27.9 184.6v5.1zM27.9 189.7v5.1zM27.9 194.8v5zM27.9 199.8v5.1zM34.3 184.6h2.5zM34.3 189.7h2.5zM34.3 194.8h2.5zM34.3 199.8h2.5zM27.9 199.8h6.4zM27.9 194.8h6.4z"/>
<path d="M27.9 189.7h6.4zM27.9 184.6h6.4zM36.8 184.6h.5zM36.8 189.7h.5zM36.8 194.8h.5zM36.8 199.8h.5zM38.9 184.6h.5zM38.9 189.7h.5zM38.9 194.8h.5zM38.9 199.8h.5zM39.4 184.6h2.5zM39.4 189.7h2.5z"/>
<path d="M39.4 194.8h2.5zM39.4 199.8h2.5zM41.9 184.6h6.4zM41.9 189.7h6.4zM41.9 194.8h6.4zM41.9 199.8h6.4zM48.3 194.8v5zM48.3 189.7v5.1zM48.3 184.6v5.1zM50.8 198.6v1.1zM50.8 196.5v1.1zM50.8 194.4v1.1z"/>
<path d="M50.8 192.3v1.1zM50.8 190.3v1zM50.8 188.2v1.1zM50.8 186.1v1.1zM50.8 184v1.1zM50.8 181.9v1.1zM50.8 179.9v1.1zM59.7 192.2l2.5 2.6zM59.7 194.8l2.5 2.5zM59.7 197.3l2.5 2.5zM62.2 194.8h10.2zM62.2 197.3h10.2z"/>
<path d="M62.2 199.8h10.2zM64.8 192.7h5.8zM64.8 195.3h5.8zM64.8 197.8h5.8zM72.4 199.8h5.1zM72.4 197.3h5.1zM72.4 194.8h5.1zM82.5 199.8h5.1zM82.5 197.3h5.1zM82.5 194.8h5.1zM87.6 197.3h2.6zM87.6 194.8h2.6z"/>
<path d="M90.2 194.8v2.5zM90.2 197.3v2.5zM90.2 199.8v2.6zM87.6 199.8h2.6zM95.2 194.8h5.1zM95.2 182.1v12.7zM100.3 182.1h3.1zM100.3 194.8h3.1zM95.2 182.1h5.1zM115.6 182.1h5zM115.6 194.8h5zM120.6 182.1h10.2z"/>
<path d="M120.6 194.8h10.2zM130.8 182.1l2.5 2.5zM130.8 194.8l2.5 2.5zM132.1 198.6v1.1zM132.1 196.5v1.1zM132.1 194.4v1.1zM132.1 192.3v1.1zM132.1 190.3v1zM132.1 188.2v1.1zM132.1 186.1v1.1zM132.1 184v1.1zM132.1 181.9v1.1z"/>
<path d="M132.1 179.9v1.1zM138.4 187.1v71.1zM138.4 187.1h20.3zM146 185.1h9.9zM156.2 189.7v2.5zM156.2 184.6v5.1zM158.7 184.6h3.1zM158.7 187.1h5.1zM156.2 184.6h2.5zM163.8 186.1l2 1zM163.8 188.1l2-1zM186.7 197.3l2.5 2.5z"/>
<path d="M196.8 197.3l2.6 2.5zM207 197.3l2.5 2.5zM215.9 198.6v1zM215.9 198.6h1zM217.9 198.6h1zM219.9 198.6h1zM219.7 197.3l2.5 2.5zM221.9 198.6h1zM223.9 198.6h1zM225.9 198.6h1zM227.9 198.6h1zM229.9 198.6h1z"/>
<path d="M229.8 197.3l2.6 2.5zM231.9 198.6h1zM233.9 198.6h1zM235.9 198.6h1zM237.9 198.6h1zM239.9 198.6h1zM240 197.3l2.5 2.5zM241.9 198.6h1zM243.9 198.6h1zM245.9 198.6h1zM248.9 198.6v1zM247.9 198.6h1z"/>
<path d="M257.8 184.6h33zM260.3 182.1h30.5zM266.7 196h1zM266.7 198.1v1.1zM266.7 196v1.1zM268.7 196h1zM270.7 196h1zM272.7 196h1zM274.7 196h1.1zM276.7 196h1.1zM278.8 196h1zM280.8 196h1z"/>
<path d="M282.8 196h1zM284.8 196h1zM286.8 196h1zM288.3 187.1v2.6zM288.3 189.7v43.1zM288.8 196h1.1zM290.8 187.1h3.1zM290.8 184.6h5.1zM290.8 182.1h5.1zM290.8 189.7h3.1zM288.3 187.1h2.5zM288.3 189.7h2.5z"/>
<path d="M290.8 196h1.1zM292.9 196h1zM294.9 196h1zM295.9 199.1h.6zM295.9 197.5h.6zM296.2 197.5v1.6zM296.9 196h1zM297 197.8v1zM297 198.8l.3 .3zM297.3 197.5l-.3 .3zM297.3 199.1h.6zM297.3 197.5h.6z"/>
<path d="M297.9 199.1l.2-.3zM297.9 197.5l.2 .3zM299.2 197.5l-.5 .5zM298.7 199.1h1.1zM298.9 196h1zM299.2 197.5v1.6zM300.3 198.3v.5zM300.3 198.8l.3 .3zM300.6 199.1h.5zM300.3 198.3l.6-.5zM300.9 196h1zM301.1 199.1l.3-.3z"/>
<path d="M300.3 198.3h.8zM300.9 197.8l.5-.3zM301.4 198.6v.2zM301.1 198.3l.3 .3zM302 198.8l.2 .3zM302 197.8v.2zM302 198l.2 .3zM302.2 199.1h.6zM302.2 197.5l-.2 .3zM302.2 198.3h.8zM302.8 199.1l.2-.3zM302.2 197.5h.6z"/>
<path d="M303 196h1zM303 197.8v1zM302.8 197.5l.2 .3zM305 196h1zM307 196h1zM309 196h1zM311 196h1zM313 196h1zM315 196h1.1zM317.1 196h1zM319.1 196h1zM321.1 196h1z"/>
<path d="M323.1 196h1zM325.1 196h1zM327.1 196h1zM329.1 196h1.1zM330.2 198.1v1.1zM330.2 196v1.1zM356.8 184.6h3.1zM356.8 194.8h3.1zM362.7 182.1h4.3zM362.7 187.1h4.3zM362.7 192.2h4.3zM362.7 197.3h4.3z"/>
<path d="M367 182.1h5.1zM367 187.1h5.1zM367 192.2h5.1zM367 197.3h5.1zM372.1 182.1h2.5zM372.1 187.1h2.5zM372.1 192.2h2.5zM372.1 197.3h2.5zM374.6 182.1v2.5zM374.6 184.6v2.5zM374.6 187.1v5.1zM374.6 192.2v2.6z"/>
<path d="M374.6 194.8v2.5zM374.6 197.3v7.6zM377.1 184.6h5.1zM377.1 194.8h5.1zM374.6 194.8h2.5zM374.6 184.6h2.5zM383.4 183.3h.9zM383.4 193.5h.9zM384.3 183.3h1.2zM384.3 193.5h1.2zM384.3 183.3l1 2.6zM385.3 185.9h1.2z"/>
<path d="M384.3 193.5l1 2.5zM385.3 196h1.2zM385.5 183.3l1 2.6zM386.5 185.9h.9zM385.5 193.5l1 2.5zM386.5 196h.9zM394.4 184.6h3.1zM394.4 194.8h3.1zM27.9 204.9v5.1zM27.9 210v5zM27.9 215v5.1zM34.3 204.9h2.5z"/>
<path d="M34.3 210h2.5zM34.3 215h2.5zM27.9 215h6.4zM27.9 210h6.4zM27.9 204.9h6.4zM36.8 204.9h.5zM36.8 210h.5zM36.8 215h.5zM38.9 204.9h.5zM38.9 210h.5zM38.9 215h.5zM39.4 204.9h2.5z"/>
<path d="M39.4 210h2.5zM39.4 215h2.5zM41.9 204.9h6.4zM41.9 210h6.4zM41.9 215h6.4zM48.3 210v5zM48.3 204.9v5.1zM48.3 199.8v5.1zM50.8 215.2v1.1zM50.8 213.2v1zM50.8 211.1v1.1zM50.8 209v1.1z"/>
<path d="M50.8 206.9v1.1zM50.8 204.8v1.1zM50.8 202.8v1zM50.8 200.7v1.1zM50.8 216.3h1zM52.8 216.3h1zM54.6 161.7v40.7zM54.8 216.3h1zM56.8 216.3h1zM58.8 216.3h1zM60.8 216.3h1zM62.8 216.3h1z"/>
<path d="M64.8 200.4h4.4zM64.8 216.3h1zM66.8 216.3h1.1zM68.9 216.3h1zM70.9 216.3h1zM72.4 202.4h5.1zM54.6 202.4h17.8zM72.9 216.3h1zM74.9 216.3h1zM76.9 216.3h1zM78.9 216.3h1zM80.9 216.3h1z"/>
<path d="M82.9 216.3h1zM84.9 216.3h1zM86.9 216.3h1zM82.5 202.4h5.1zM87.6 202.4h2.6zM88.9 216.3h1zM90.2 202.4v5zM90.2 207.4h5zM90.9 216.3h1zM92.9 216.3h1zM94.9 216.3h1zM95.2 207.4h5.1z"/>
<path d="M95.2 194.8v12.6zM96.9 216.3h1.1zM99 216.3h1zM100.3 207.4h3.1zM101 216.3h1zM103 216.3h1zM105 216.3h1zM107 216.3h1zM109 216.3h1zM111 216.3h1zM113 216.3h1zM115 216.3h1z"/>
<path d="M117 216.3h1zM119 216.3h1zM115.6 207.4h5zM120.6 207.4h10.2zM121 216.3h1zM123 216.3h1zM125 216.3h1zM127 216.3h1.1zM129.1 216.3h1zM130.8 207.4l2.5 2.6zM131.1 216.3h1zM132.1 215.2v1.1z"/>
<path d="M132.1 213.2v1zM132.1 211.1v1.1zM132.1 209v1.1zM132.1 206.9v1.1zM132.1 204.8v1.1zM132.1 202.8v1zM132.1 200.7v1.1zM189.2 215v3.2zM189.2 199.8v15.2zM199.4 215v3.2zM199.4 199.8v15.2zM209.5 215v3.2z"/>
<path d="M209.5 199.8v15.2zM215.9 218.6v1zM215.9 216.6v1zM215.9 214.6v1zM215.9 212.6v1zM215.9 210.6v1zM215.9 208.6v1zM215.9 206.6v1zM215.9 204.6v.9zM215.9 202.6v1zM215.9 200.6v.9zM222.2 215v3.2z"/>
<path d="M222.2 199.8v15.2zM232.4 215v3.2zM232.4 199.8v15.2zM242.5 215v3.2zM242.5 199.8v15.2zM248.9 200.6v.9zM248.9 202.6v1zM248.9 204.6v.9zM248.9 206.6v1zM248.9 208.6v.9zM248.9 210.6v1zM248.9 212.6v1z"/>
<path d="M248.9 214.6v1zM248.9 216.6v1zM248.9 218.6v1zM262.9 217.6h27.9zM262.9 204.9v12.7zM262.9 171.9v33zM265.4 202.4v12.6zM265.4 169.4v33zM266.7 216.9v1.1zM266.7 214.8v1.1zM266.7 212.7v1.1zM266.7 210.6v1.1z"/>
<path d="M266.7 208.5v1.1zM266.7 206.4v1.1zM266.7 204.4v1zM266.7 202.3v1.1zM266.7 200.2v1.1zM273 207.4l-2.5 2.6zM270.5 212.5l2.5-2.5zM290.8 210h5.1zM290.8 207.4h5.1zM290.8 204.9h5.1zM290.8 202.4h5.1zM290.8 215h5.1z"/>
<path d="M290.8 217.6h5.1zM262.9 204.9h27.9zM273 207.4h17.8zM273 210h17.8zM265.4 202.4h25.4zM265.4 215h25.4zM311.1 202.4h5.1zM311.1 207.4h5.1zM316.2 202.4h27.9zM316.2 207.4h33zM330.2 216.9v1.1zM330.2 214.8v1.1z"/>
<path d="M330.2 212.7v1.1zM330.2 210.6v1.1zM330.2 208.5v1.1zM330.2 206.4v1.1zM330.2 204.4v1zM330.2 202.3v1.1zM330.2 200.2v1.1zM344.1 151.6v50.8zM349.2 151.6v55.8zM374.6 210v2.5zM374.6 204.9v5.1zM377.1 204.9h5.1z"/>
<path d="M374.6 204.9h2.5zM383.4 203.6h.9zM384.3 203.6h1.2zM384.3 203.6l1 2.6zM385.3 206.2h1.2zM385.5 203.6l1 2.6zM386.5 206.2h.9zM394.4 204.9h3.1zM16.5 224.2h3.8zM27.9 220.1v5.1zM27.9 225.2v5.1zM27.9 230.3v5.1z"/>
<path d="M27.9 235.4v5zM34.3 220.1h2.5zM34.3 225.2h2.5zM34.3 230.3h2.5zM34.3 235.4h2.5zM27.9 235.4h6.4zM27.9 230.3h6.4zM27.9 225.2h6.4zM27.9 220.1h6.4zM36.8 220.1h.5zM36.8 225.2h.5zM36.8 230.3h.5z"/>
<path d="M36.8 235.4h.5zM38.9 220.1h.5zM38.9 225.2h.5zM38.9 230.3h.5zM38.9 235.4h.5zM39.4 220.1h2.5zM39.4 225.2h2.5zM39.4 230.3h2.5zM39.4 235.4h2.5zM41.9 220.1h6.4zM41.9 225.2h6.4zM41.9 230.3h6.4z"/>
<path d="M41.9 235.4h6.4zM48.3 230.3v5.1zM48.3 225.2v5.1zM48.3 220.1v5.1zM48.3 215v5.1zM62.2 232.8h2.6zM64.8 232.8h5zM71 231.6h.9zM71.9 231.6h1.3zM71.9 231.6l1 2.5zM72.9 234.1h1.3zM73.2 231.6l1 2.5z"/>
<path d="M74.2 234.1h.9zM82 232.8h3.1zM85.1 232.8h2.5zM87.6 232.8h30.5zM118.1 232.8v35.6zM143.5 235.4l2.5 2.5zM143.5 232.8l2.5 2.6zM143.5 230.3l2.5 2.5zM158.7 232.8h5.1zM158.7 235.4h5.1zM158.7 237.9h5.1zM146 237.9h12.7z"/>
<path d="M146 235.4h12.7zM146 232.8h12.7zM163.9 229.6h.5zM163.9 228h.5zM164.2 228v1.6zM165 228.2v1.1zM165 229.3l.2 .3zM165.2 228l-.2 .2zM165.2 229.6h.6zM165.2 228h.6zM165.8 229.6l.3-.3zM165.8 228l.3 .2z"/>
<path d="M167.2 228l-.6 .5zM166.6 229.6h1.1zM167.2 228v1.6zM168.3 228.8v.5zM168.3 229.3l.2 .3zM168.5 229.6h.6zM168.3 228.8l.5-.6zM169.3 229.3l-.2 .3zM168.3 228.8h.8zM168.8 228.2l.5-.2zM169.3 229v.3zM169.1 228.8l.2 .2z"/>
<path d="M169.9 228.2l.3-.2zM170.2 228h.5zM169.9 229.3l.3 .3zM170.7 228l.3 .2zM170.4 228.8h.3zM170.7 228.8l.3 .2zM170.2 229.6h.5zM171 228.2v.3zM170.7 228.8l.3-.3zM171 229v.3zM171 229.3l-.3 .3zM179 232.8h5.1z"/>
<path d="M179 235.4h5.1zM179 237.9h5.1zM184.1 235.4h12.7zM184.1 237.9h22.9zM186.7 225.2v5.1zM186.7 220.9v4.3zM186.7 230.3v2.5zM184.1 232.8h2.6zM191.7 225.2v5.1zM191.7 220.9v4.3zM191.7 230.3v33zM196.8 225.2v5.1z"/>
<path d="M196.8 220.9v4.3zM196.8 230.3v5.1zM201.9 225.2v5.1zM201.9 220.9v4.3zM201.9 230.3v33zM207 225.2v5.1zM207 220.9v4.3zM207 230.3v7.6zM212.1 225.2v5.1zM212.1 220.9v4.3zM212.1 230.3v33zM215.9 230.6v1z"/>
<path d="M215.9 228.6v1zM215.9 226.6v1zM215.9 224.6v1zM215.9 222.6v1zM215.9 220.6v1zM215.9 231.6h1zM217.9 231.6h1zM219.7 225.2v5.1zM219.7 220.9v4.3zM219.9 231.6h1zM221.9 231.6h1zM224.8 225.2v5.1z"/>
<path d="M224.8 220.9v4.3zM224.8 230.3v33zM223.9 231.6h1zM225.9 231.6h1zM227.9 231.6h1zM229.8 225.2v5.1zM229.8 220.9v4.3zM229.9 231.6h1zM231.9 231.6h1zM233.9 231.6h1zM234.9 225.2v5.1zM234.9 220.9v4.3z"/>
<path d="M234.9 230.3v33zM235.9 231.6h1zM237.9 231.6h1zM240 225.2v5.1zM240 220.9v4.3zM239.9 231.6h1zM241.9 231.6h1zM243.9 231.6h1zM245.1 225.2v5.1zM245.1 220.9v4.3zM245.1 230.3v33zM245.9 231.6h1z"/>
<path d="M247.9 231.6h1zM248.9 220.6v1zM248.9 222.6v1zM248.9 224.6v1zM248.9 226.6v1zM248.9 228.6v1zM248.9 230.6v1zM252.7 230.3h38.1zM255.2 227.7h35.6zM266.7 237.7v1.1zM266.7 235.6v1.1zM266.7 233.6v1z"/>
<path d="M266.7 231.5v1.1zM266.7 229.4v1.1zM266.7 227.3v1.1zM266.7 225.2v1.1zM266.7 223.1v1.1zM266.7 221v1.1zM266.7 219v1zM270.5 222.7l2.5-2.6zM273 222.7l-2.5 2.5zM288.3 237.9v2.5zM288.3 232.8v2.6zM288.3 235.4v2.5z"/>
<path d="M290.8 232.8h3.1zM290.8 230.3h5.1zM290.8 220.1h5.1zM290.8 222.7h5.1zM290.8 227.7h5.1zM290.8 235.4h3.1zM288.3 232.8h2.5zM288.3 235.4h2.5zM273 220.1h17.8zM273 222.7h17.8zM330.2 237.7v1.1zM330.2 235.6v1.1z"/>
<path d="M330.2 233.6v1zM330.2 231.5v1.1zM330.2 229.4v1.1zM330.2 227.3v1.1zM330.2 225.2v1.1zM330.2 223.1v1.1zM330.2 221v1.1zM330.2 219v1zM400 224.2h3.8zM27.9 240.4v5.1zM27.9 245.5v5.1zM27.9 250.6v5.1z"/>
<path d="M27.9 245.5h6.4zM27.9 250.6h6.4zM34.3 240.4h2.5zM34.3 245.5h2.5zM34.3 255.7h2.5zM34.3 250.6h2.5zM27.9 255.7h6.4zM27.9 240.4h6.4zM36.8 240.4h.5zM36.8 245.5h.5zM36.8 255.7h.5zM36.8 250.6h.5z"/>
<path d="M38.9 240.4h.5zM38.9 245.5h.5zM38.9 255.7h.5zM38.9 250.6h.5zM39.4 240.4h2.5zM39.4 245.5h2.5zM39.4 255.7h2.5zM39.4 250.6h2.5zM41.9 240.4h6.4zM41.9 255.7h6.4zM41.9 245.5h6.4zM41.9 250.6h6.4z"/>
<path d="M48.3 245.5v10.2zM48.3 240.4v5.1zM48.3 235.4v5zM48.3 245.5v5.1zM62.2 253.1v2.6zM62.2 255.7v.5zM62.2 257.7v.5zM62.2 250.6v2.5zM62.2 243v7.6zM62.2 232.8v10.2zM69.8 243h2.6zM62.2 243h7.6z"/>
<path d="M80 250.6h1.5zM77.5 243h2.5zM62.2 250.6h17.8zM80 243h7.6zM83.6 250.6h1.5zM85.1 250.6h17.8zM87.6 232.8v10.2zM90.2 243h2.5zM87.6 243h2.6zM97.8 243h2.5zM100.3 243h2.6zM102.9 253.1v2.6z"/>
<path d="M102.9 255.7v.5zM102.9 257.7v.5zM102.9 250.6v2.5zM102.9 243v7.6zM138.4 258.2h20.3zM143.5 248.1l2.5 2.5zM143.5 245.5l2.5 2.6zM146 256.2h9.9zM146 250.6h12.7zM146 248.1h12.7zM143.5 243l2.5 2.5zM143.5 240.4l2.5 2.6z"/>
<path d="M143.5 237.9l2.5 2.5zM156.2 255.7v5.1zM158.7 255.7h3.1zM158.7 240.4h5.1zM158.7 258.2h5.1zM158.7 243h5.1zM158.7 245.5h5.1zM158.7 248.1h5.1zM158.7 250.6h5.1zM156.2 255.7h2.5zM146 245.5h12.7zM146 243h12.7z"/>
<path d="M146 240.4h12.7zM163.8 257.2l2 1zM163.8 259.2l2-1zM179 240.4h5.1zM179 243h5.1zM179 245.5h5.1zM179 248.1h5.1zM179 250.6h5.1zM184.1 240.4h35.6zM184.1 243h45.7zM184.1 245.5h55.9zM219.7 230.3v10.1z"/>
<path d="M229.8 230.3v12.7zM240 230.3v15.2zM266.7 241.9v1.1zM266.7 239.8v1.1zM266.7 243h1zM268.7 243h1zM270.7 243h1zM272.7 243h1zM274.7 243h1.1zM276.7 243h1.1zM278.8 243h1zM280.8 243h1z"/>
<path d="M282.8 243h1zM284.8 243h1zM286.8 243h1zM288.8 243h1.1zM290.8 243h1.1zM292.9 243h1zM294.9 243h1zM296.9 243h1zM298.9 243h1zM300.9 243h1zM303 243h1zM305 243h1z"/>
<path d="M307 243h1zM309 243h1zM311 243h1zM313 243h1zM315 243h1.1zM317.1 243h1zM319.1 243h1zM321.1 243h1zM323.1 243h1zM325.1 243h1zM327.1 243h1zM329.1 243h1.1z"/>
<path d="M330.2 241.9v1.1zM330.2 239.8v1.1zM20.3 274.7h379.7zM39.4 270.9h226zM48.3 260.8v2.5zM48.3 255.7v5.1zM48.3 250.6v10.2zM62.2 258.2v2.6zM62.2 263.3v2.5zM62.2 260.8v2.5zM67.8 274.7v3.8zM102.9 263.3v2.5z"/>
<path d="M102.9 258.2v2.6zM102.9 260.8v2.5zM115.3 274.7v3.8zM118.1 268.4h144.8zM156.2 260.8v2.5zM162.7 274.7v3.8zM191.7 263.3l2.6 2.5zM201.9 263.3l2.5 2.5zM210.2 274.7v3.8zM212.1 263.3l2.5 2.5zM224.8 263.3l2.5 2.5zM234.9 263.3l2.6 2.5z"/>
<path d="M245.1 263.3l2.5 2.5zM257.6 274.7v3.8zM262.9 217.6v50.8zM265.4 215v55.9zM305.1 274.7v3.8zM352.5 274.7v3.8zM400 264.5v.1zM400 268.4v6.2zM400 274.6h.1zM400 22.1v252.6z"/>
<circle cx="199.4" cy="42.4" r=".51"/>
<circle cx="204.4" cy="47.5" r=".51"/>
<circle cx="278.1" cy="75.4" r=".51"/>
<circle cx="151.1" cy="88.1" r=".51"/>
<circle cx="204.4" cy="85.5" r=".51"/>
<circle cx="262.9" cy="80.5" r=".51"/>
<circle cx="262.9" cy="93.2" r=".51"/>
<circle cx="273" cy="80.5" r=".51"/>
<circle cx="204.4" cy="103.3" r=".51"/>
<circle cx="369.5" cy="105.9" r=".51"/>
<circle cx="372.1" cy="108.4" r=".51"/>
<circle cx="374.6" cy="110.9" r=".51"/>
<circle cx="377.1" cy="113.5" r=".51"/>
<circle cx="379.7" cy="116" r=".51"/>
<circle cx="382.2" cy="118.6" r=".51"/>
<circle cx="153.6" cy="136.3" r=".51"/>
<circle cx="90.2" cy="159.2" r=".51"/>
<circle cx="90.2" cy="156.7" r=".51"/>
<circle cx="95.2" cy="154.1" r=".51"/>
<circle cx="27.9" cy="177" r=".51"/>
<circle cx="54.6" cy="161.7" r=".51"/>
<circle cx="90.2" cy="161.7" r=".51"/>
<circle cx="95.2" cy="166.8" r=".51"/>
<circle cx="262.9" cy="171.9" r=".51"/>
<circle cx="265.4" cy="169.4" r=".51"/>
<circle cx="374.6" cy="171.9" r=".51"/>
<circle cx="374.6" cy="164.3" r=".51"/>
<circle cx="374.6" cy="174.4" r=".51"/>
<circle cx="374.6" cy="166.8" r=".51"/>
<circle cx="374.6" cy="177" r=".51"/>
<circle cx="27.9" cy="194.8" r=".51"/>
<circle cx="27.9" cy="184.6" r=".51"/>
<circle cx="27.9" cy="189.7" r=".51"/>
<circle cx="27.9" cy="199.8" r=".51"/>
<circle cx="48.3" cy="194.8" r=".51"/>
<circle cx="48.3" cy="184.6" r=".51"/>
<circle cx="48.3" cy="199.8" r=".51"/>
<circle cx="48.3" cy="189.7" r=".51"/>
<circle cx="90.2" cy="197.3" r=".51"/>
<circle cx="90.2" cy="199.8" r=".51"/>
<circle cx="95.2" cy="194.8" r=".51"/>
<circle cx="138.4" cy="187.1" r=".51"/>
<circle cx="288.3" cy="189.7" r=".51"/>
<circle cx="374.6" cy="187.1" r=".51"/>
<circle cx="374.6" cy="197.3" r=".51"/>
<circle cx="374.6" cy="182.1" r=".51"/>
<circle cx="374.6" cy="192.2" r=".51"/>
<circle cx="374.6" cy="184.6" r=".51"/>
<circle cx="374.6" cy="194.8" r=".51"/>
<circle cx="27.9" cy="210" r=".51"/>
<circle cx="27.9" cy="204.9" r=".51"/>
<circle cx="27.9" cy="215" r=".51"/>
<circle cx="48.3" cy="204.9" r=".51"/>
<circle cx="48.3" cy="210" r=".51"/>
<circle cx="48.3" cy="215" r=".51"/>
<circle cx="90.2" cy="202.4" r=".51"/>
<circle cx="95.2" cy="207.4" r=".51"/>
<circle cx="262.9" cy="204.9" r=".51"/>
<circle cx="262.9" cy="217.6" r=".51"/>
<circle cx="265.4" cy="202.4" r=".51"/>
<circle cx="265.4" cy="215" r=".51"/>
<circle cx="374.6" cy="204.9" r=".51"/>
<circle cx="27.9" cy="230.3" r=".51"/>
<circle cx="27.9" cy="220.1" r=".51"/>
<circle cx="27.9" cy="235.4" r=".51"/>
<circle cx="27.9" cy="225.2" r=".51"/>
<circle cx="48.3" cy="225.2" r=".51"/>
<circle cx="48.3" cy="230.3" r=".51"/>
<circle cx="48.3" cy="235.4" r=".51"/>
<circle cx="48.3" cy="220.1" r=".51"/>
<circle cx="87.6" cy="232.8" r=".51"/>
<circle cx="288.3" cy="235.4" r=".51"/>
<circle cx="288.3" cy="232.8" r=".51"/>
<circle cx="27.9" cy="240.4" r=".51"/>
<circle cx="27.9" cy="250.6" r=".51"/>
<circle cx="27.9" cy="245.5" r=".51"/>
<circle cx="48.3" cy="255.7" r=".51"/>
<circle cx="48.3" cy="240.4" r=".51"/>
<circle cx="48.3" cy="250.6" r=".51"/>
<circle cx="48.3" cy="245.5" r=".51"/>
<circle cx="62.2" cy="243" r=".51"/>
<circle cx="62.2" cy="250.6" r=".51"/>
<circle cx="87.6" cy="243" r=".51"/>
<circle cx="102.9" cy="250.6" r=".51"/>
</g>
<g fill="#000" stroke="#000" stroke-width=".28">
<path d="M32.3 45.9v3.1zM32.9 40.9v3zM32.3 45.9h8.1zM32.3 49h8.1zM32.9 40.9h7.5zM32.9 43.9h7.5zM40.4 45.9l1.5 1.6zM41.9 47.5l-1.5 1.5zM40.4 40.9l1.5 1.5zM41.9 42.4l-1.5 1.5zM262.9 75.4l-1.3 1.9zM262.9 75.4l1.2 1.9z"/>
<path d="M26.9 96.7v3.1zM26.9 96.7h16zM26.9 99.8h16zM42.9 96.7l1.5 1.5zM44.4 98.2l-1.5 1.6zM149.2 93.2h3.8zM261 98.2h3.8zM266.7 84.9v.6zM266.7 85.5h1.2zM266.7 88.1h2.5zM266.7 84.9h.2zM267.9 85.5l-1.2 2.6z"/>
<path d="M267.9 85.5h1.3zM269 86.2h.2zM267.9 85.5l1.3 2.6zM269.2 85.5v.7zM368.8 94.4v5.1zM368.8 99.5h.7zM369.5 99.5h.8zM368.8 94.4h.7zM369.5 83l-1.2 1.9zM370.3 94.4v5.1zM369.5 94.4h.8zM369.5 83l1.3 1.9z"/>
<path d="M371.3 99.5h.8zM371.3 94.4v5.1zM372.1 99.5h.7zM371.3 94.4h.8zM372.1 94.4h.7zM372.8 94.4v5.1zM373.8 94.4v5.1zM373.8 99.5h.8zM373.8 94.4h.8zM374.6 99.5h.8zM375.4 94.4v5.1zM374.6 94.4h.8z"/>
<path d="M376.4 94.4v5.1zM376.4 99.5h.7zM376.4 94.4h.7zM377.1 99.5h.8zM377.9 94.4v5.1zM377.1 94.4h.8zM378.9 94.4v5.1zM378.9 99.5h.8zM378.9 94.4h.8zM379.7 99.5h.7zM380.4 94.4v5.1zM379.7 94.4h.7z"/>
<path d="M381.5 94.4v5.1zM381.5 99.5h.7zM382.2 99.5h.8zM381.5 94.4h.7zM383 94.4v5.1zM382.2 94.4h.8zM65.4 108.4h3.8zM151.1 126.2l-1.3 1.9zM151.1 126.2l1.3 1.9zM30.2 142.4v3.1zM30.2 142.4h10.2zM30.2 145.5h10.2z"/>
<path d="M40.4 142.4l1.5 1.6zM41.9 144l-1.5 1.5zM113 137.6v7.6zM113 150.3v7.6zM151.7 141.4h3.9zM27.9 169.4l-1.2 1.9zM27.9 169.4l1.3 1.9zM113 163v7.6zM113 178.2v7.7zM113 190.9v7.7zM154.3 192.2h3.8zM113 203.6v7.6z"/>
<path d="M372.7 212.5h3.8zM72.4 243.9h5.1zM72.4 242.1v1.8zM72.4 242.1h5.1zM77.5 242.1v1.8zM81.5 248.8v3.6zM82.2 249.1v3zM82.2 252.1h.7zM82.9 249.1v3zM82.2 249.1h.7zM83.6 248.8v3.6zM92.7 243.9h5.1z"/>
<path d="M92.7 242.1v1.8zM92.7 242.1h5.1zM97.8 242.1v1.8zM286.4 240.4h3.8zM313.7 249.3h86.3zM313.7 254.4h86.3zM313.7 259.5h58.4zM372.1 259.5h27.9zM372.1 259.5v5.1zM28.6 269.4v3.1zM28.6 269.4h9.2zM28.6 272.5h9.2z"/>
<path d="M37.8 269.4l1.6 1.5zM39.4 270.9l-1.6 1.6zM46.4 263.3h3.8zM60.3 265.8h3.8zM101 265.8h3.8zM154.3 263.3h3.8zM313.7 264.6h58.4zM313.7 269.7h86.3zM372.1 264.6h27.9zM400 268.4v1.3z"/>
</g>
<g fill="none" stroke="#000" stroke-width=".21">
<circle cx="315.2" cy="75.4" r="1"/>
<circle cx="73.9" cy="98.2" r=".99"/>
<circle cx="93.7" cy="90.6" r=".99"/>
<circle cx="93.7" cy="98.2" r=".99"/>
<circle cx="93.7" cy="93.2" r=".99"/>
<circle cx="93.7" cy="95.7" r=".99"/>
<circle cx="93.7" cy="88.1" r=".99"/>
<circle cx="93.7" cy="85.5" r=".99"/>
<circle cx="93.7" cy="83" r=".99"/>
<circle cx="162.8" cy="88.1" r=".99"/>
<circle cx="315.2" cy="80.5" r="1"/>
<circle cx="315.2" cy="85.5" r="1"/>
<circle cx="73.9" cy="100.8" r=".99"/>
<circle cx="93.7" cy="100.8" r=".99"/>
<circle cx="180" cy="118.6" r=".99"/>
<circle cx="160.3" cy="133.8" r=".99"/>
<circle cx="160.3" cy="136.3" r=".99"/>
<circle cx="180" cy="126.2" r=".99"/>
<circle cx="180" cy="131.3" r=".99"/>
<circle cx="180" cy="123.6" r=".99"/>
<circle cx="180" cy="133.8" r=".99"/>
<circle cx="180" cy="121.1" r=".99"/>
<circle cx="180" cy="136.3" r=".99"/>
<circle cx="180" cy="128.7" r=".99"/>
<circle cx="315.2" cy="136.3" r="1"/>
<circle cx="315.2" cy="131.3" r="1"/>
<circle cx="104.4" cy="154.1" r=".99"/>
<circle cx="104.4" cy="141.4" r=".99"/>
<circle cx="315.2" cy="141.4" r="1"/>
<circle cx="104.4" cy="166.8" r=".99"/>
<circle cx="393.4" cy="174.4" r="1"/>
<circle cx="393.4" cy="164.3" r="1"/>
<circle cx="104.4" cy="194.8" r=".99"/>
<circle cx="104.4" cy="182.1" r=".99"/>
<circle cx="162.8" cy="184.6" r=".99"/>
<circle cx="294.9" cy="187.1" r="1"/>
<circle cx="294.9" cy="189.7" r="1"/>
<circle cx="360.9" cy="194.8" r="1"/>
<circle cx="360.9" cy="184.6" r="1"/>
<circle cx="393.4" cy="194.8" r="1"/>
<circle cx="393.4" cy="184.6" r="1"/>
<circle cx="104.4" cy="207.4" r=".99"/>
<circle cx="189.2" cy="219.2" r=".99"/>
<circle cx="199.4" cy="219.2" r=".99"/>
<circle cx="209.5" cy="219.2" r=".99"/>
<circle cx="222.2" cy="219.2" r="1"/>
<circle cx="232.4" cy="219.2" r="1"/>
<circle cx="242.5" cy="219.2" r="1"/>
<circle cx="393.4" cy="204.9" r="1"/>
<circle cx="81" cy="232.8" r=".99"/>
<circle cx="294.9" cy="232.8" r="1"/>
<circle cx="294.9" cy="235.4" r="1"/>
<circle cx="162.8" cy="255.7" r=".99"/>
</g>
<g fill="#000" stroke="#000" stroke-width=".42">
<path d="M163.8 62.7v30.5zM163.8 62.7h15.2zM74.9 80.5v22.8zM74.9 80.5h17.8zM163.8 93.2h15.2zM179 62.7v30.5zM367 91.9h17.8zM384.8 91.9v8.9zM74.9 103.3h17.8zM92.7 80.5v22.8zM161.3 116v22.9zM161.3 116h17.7z"/>
<path d="M179 100.8v10.1zM367 91.9v8.9zM367 100.8h17.8zM388.6 103.3h5.1zM388.6 103.3v17.8zM161.3 138.9h17.7zM179 116v22.9zM388.6 126.2h5.1zM388.6 126.2v17.8zM393.7 103.3v17.8zM388.6 121.1h5.1zM76.2 151.6v12.7z"/>
<path d="M76.2 151.6h7.6zM163.8 159.2v30.5zM163.8 159.2h15.2zM179 144v10.1zM295.9 154.1v38.1zM295.9 154.1h15.2zM367 159.2v10.2zM382.2 159.2l10.2 5.1zM393.7 126.2v17.8zM388.6 144h5.1zM76.2 164.3h7.6zM83.8 151.6v12.7z"/>
<path d="M367 169.4v10.1zM367 179.5v7.6zM382.2 159.2v10.2zM382.2 169.4l10.2 5zM382.2 169.4v10.1zM382.2 179.5l10.2 5.1zM382.2 169.4l10.2-5.1zM382.2 179.5l10.2-5.1zM76.2 192.2v12.7zM76.2 192.2h7.6zM163.8 189.7h15.2zM179 159.2v30.5z"/>
<path d="M295.9 192.2h15.2zM295.9 199.8v38.1zM311.1 154.1v38.1zM295.9 199.8h15.2zM367 187.1v2.6zM367 189.7v7.6zM367 197.3v2.5zM382.2 179.5v10.2zM382.2 189.7l10.2 5.1zM382.2 189.7v10.1zM382.2 199.8l10.2 5.1zM382.2 189.7l10.2-5.1z"/>
<path d="M382.2 199.8l10.2-5zM76.2 204.9h7.6zM83.8 192.2v12.7zM382.2 199.8v10.2zM382.2 210l10.2-5.1zM69.8 227.7l10.2 5.1zM69.8 227.7v10.2zM69.8 237.9l10.2-5.1zM163.8 230.3v30.5zM163.8 230.3h15.2zM184.1 225.2h7.6zM191.7 225.2h2.6z"/>
<path d="M194.3 225.2h7.6zM201.9 225.2h2.5zM204.4 225.2h7.7zM212.1 225.2h2.5zM217.1 225.2h7.7zM224.8 225.2h2.5zM227.3 225.2h7.6zM234.9 225.2h2.6zM237.5 225.2h7.6zM245.1 225.2h2.5zM295.9 237.9h15.2zM311.1 199.8v38.1z"/>
<path d="M341.6 223.9v10.2zM341.6 234.1v7.6zM341.6 234.1h55.9zM397.5 223.9v10.2zM341.6 223.9h55.9zM341.6 241.7h55.9zM397.5 234.1v7.6zM163.8 260.8h15.2zM179 230.3v30.5z"/>
</g>
<g fill="#000" stroke="#000" stroke-width=".21">
<path d="M255.8 87.1h4v.5h-4zM255.8 86h4v.5h-4zM37.3 174.9h.5v4.1h-.5zM38.4 174.9h.5v4.1h-.5zM37.3 182.6h.5v4h-.5zM37.3 187.6h.5v4.1h-.5zM37.3 192.7h.5v4.1h-.5zM37.3 197.8h.5v4.1h-.5zM38.4 182.6h.5v4h-.5zM38.4 187.6h.5v4.1h-.5zM38.4 192.7h.5v4.1h-.5zM38.4 197.8h.5v4.1h-.5z"/>
<path d="M37.3 202.9h.5v4h-.5zM37.3 207.9h.5v4.1h-.5zM37.3 213h.5v4.1h-.5zM37.3 218.1h.5v4.1h-.5zM38.4 202.9h.5v4h-.5zM38.4 207.9h.5v4.1h-.5zM38.4 213h.5v4.1h-.5zM38.4 218.1h.5v4.1h-.5zM37.3 223.2h.5v4h-.5zM37.3 228.3h.5v4h-.5zM37.3 233.3h.5v4.1h-.5zM37.3 238.4h.5v4.1h-.5z"/>
<path d="M38.4 223.2h.5v4h-.5zM38.4 228.3h.5v4h-.5zM38.4 233.3h.5v4.1h-.5zM38.4 238.4h.5v4.1h-.5zM372.1 223.9h25.4v10.2h-25.4zM37.3 243.5h.5v4.1h-.5zM37.3 253.7h.5v4h-.5zM37.3 248.6h.5v4h-.5zM38.4 243.5h.5v4.1h-.5zM38.4 253.7h.5v4h-.5zM38.4 248.6h.5v4h-.5zM60.2 257.2h4.1v.5h-4.1z"/>
<path d="M60.2 256.2h4.1v.5h-4.1zM100.8 257.2h4.1v.5h-4.1zM100.8 256.2h4.1v.5h-4.1z"/>
</g>
<g fill="#000" stroke="#000" stroke-width=".61">
<path d="M20.3 22.1v252.6zM316.2 39.8v48.3zM316.2 39.8h20.3zM20.3 22.1h379.7zM250.2 52.5v40.7zM229.8 52.5h20.4zM229.8 93.2h20.4zM229.8 52.5v40.7zM316.2 88.1h20.3zM316.2 95.7v48.3zM336.5 39.8v48.3zM316.2 95.7h20.3z"/>
<path d="M389.8 110.9h1.3zM389.8 108.4h1.3zM389.8 105.9h1.3zM389.8 116h1.3zM389.8 113.5h1.3zM389.8 118.6h1.3zM113 137.6l2.6-1.3zM115.6 136.3v10.2zM389.8 133.8h1.3zM389.8 131.3h1.3zM389.8 128.7h1.3zM389.8 138.9h1.3z"/>
<path d="M389.8 136.3h1.3zM77.5 156.7h1.2zM77.5 159.2h1.2zM77.5 154.1h1.2zM81.3 156.7h1.2zM81.3 159.2h1.2zM81.3 154.1h1.2zM105.4 141.4l7.6-3.8zM105.4 154.1l7.6-3.8zM105.4 141.4l7.6 3.8zM105.4 154.1l7.6 3.8zM113 150.3l2.6-1.3z"/>
<path d="M113 145.2l2.6 1.3zM113 157.9l2.6 1.3zM115.6 149v10.2zM316.2 144h20.3zM336.5 95.7v48.3zM389.8 141.4h1.3zM77.5 161.7h1.2zM81.3 161.7h1.2zM105.4 166.8l7.6-3.8zM105.4 166.8l7.6 3.8zM113 163l2.6-1.3zM113 178.2l2.6-1.2z"/>
<path d="M113 170.6l2.6 1.3zM115.6 161.7v10.2zM115.6 177v10.1zM77.5 197.3h1.2zM77.5 199.8h1.2zM77.5 194.8h1.2zM81.3 197.3h1.2zM81.3 199.8h1.2zM81.3 194.8h1.2zM105.4 182.1l7.6-3.9zM105.4 194.8l7.6-3.9zM105.4 182.1l7.6 3.8z"/>
<path d="M105.4 194.8l7.6 3.8zM113 190.9l2.6-1.2zM113 185.9l2.6 1.2zM113 198.6l2.6 1.2zM115.6 189.7v10.1zM77.5 202.4h1.2zM81.3 202.4h1.2zM105.4 207.4l7.6-3.8zM105.4 207.4l7.6 3.8zM113 203.6l2.6-1.2zM113 211.2l2.6 1.3zM115.6 202.4v10.1z"/>
<path d="M283.2 244.3v30.4zM313.7 254.4v5.1zM313.7 249.3v5.1zM313.7 244.3v5zM313.7 244.3h86.3zM283.2 244.3h30.5zM400 254.4v5.1zM400 249.3v5.1zM400 244.3v5zM400 22.1v222.2zM20.3 274.7h262.9zM283.2 274.7h30.5z"/>
<path d="M313.7 274.7h86.3zM313.7 269.7v5zM313.7 264.6v5.1zM313.7 259.5v5.1zM400 268.4v6.3zM400 264.6v3.8zM400 259.5v5.1z"/>
</g>
<g fill="none" stroke="#000" stroke-width=".42">
<path d="M179 100.8a5.1 5.1 0 0 0-5 5.1 5.1 5.1 0 0 0 5 5M179 144a5.1 5.1 0 0 0-5 5 5.1 5.1 0 0 0 5 5.1M367 159.2a5.1 5.1 0 0 0-5.1 5.1 5.1 5.1 0 0 0 5.1 5.1 5.1 5.1 0 0 0-5.1 5 5.1 5.1 0 0 0 5.1 5.1 5.1 5.1 0 0 0-5.1 5.1 5.1 5.1 0 0 0 5.1 5.1 5.1 5.1 0 0 0-5.1 5.1 5.1 5.1 0 0 0 5.1 5M184.1 225.2a5.1 5.1 0 0 1 5.1-5.1 5.1 5.1 0 0 1 5.1 5.1 5.1 5.1 0 0 1 5.1-5.1 5.1 5.1 0 0 1 5 5.1 5.1 5.1 0 0 1 5.1-5.1 5.1 5.1 0 0 1 5.1 5.1M217.1 225.2a5.1 5.1 0 0 1 5.1-5.1 5.1 5.1 0 0 1 5.1 5.1 5.1 5.1 0 0 1 5.1-5.1 5.1 5.1 0 0 1 5.1 5.1 5.1 5.1 0 0 1 5-5.1 5.1 5.1 0 0 1 5.1 5.1"/>
<circle cx="369.5" cy="93.2" r=".25"/>
<circle cx="372.1" cy="93.2" r=".25"/>
<circle cx="374.6" cy="93.2" r=".25"/>
<circle cx="377.1" cy="93.2" r=".25"/>
<circle cx="379.7" cy="93.2" r=".25"/>
</g>
<path d="M16.5 18.2v260.3zM16.5 18.2h387.3zM16.5 278.5h387.3zM403.8 18.2v260.3z" fill="#000" stroke="#000" stroke-width=".32"/>
<g fill="#000" stroke="#000" stroke-width=".76">
<path d="M41.9 34.8h221zM41.9 29.7h7.6zM49.5 29.7h157.5zM49.5 29.7l2.6 2.5zM135.9 34.8l2.5 2.5zM138.4 37.3v81.3zM140.9 29.7l2.6 2.5zM143.5 32.2v45.7zM204.4 29.7h83.9zM207 29.7l2.5 2.5zM209.5 32.2v28zM262.9 34.8l5 5z"/>
<path d="M262.9 34.8h22.8zM267.9 39.8v30.5zM285.7 34.8l2.6 2.5zM288.3 37.3v76.2zM288.3 29.7l5 5.1zM293.3 34.8v86.3zM356.8 39.8v106.7zM143.5 77.9v170.2zM52.1 32.2v61zM41.9 138.9h15.2zM57.1 138.9l2.6 2.5zM59.7 141.4v2.6z"/>
<path d="M59.7 144v12.7zM59.7 156.7v40.6zM133.3 144v71zM270.5 151.6v111.7zM270.5 151.6l2.5-2.6zM273 149h81.3zM356.8 146.5l-2.5 2.5zM151.1 199.8l2.5-2.5zM153.6 197.3h86.4zM133.3 215l2.6 2.6zM135.9 217.6h12.7zM148.6 217.6l2.5-2.6z"/>
<path d="M151.1 199.8v15.2zM194.3 265.8h73.6zM270.5 263.3l-2.6 2.5z"/>
</g>
<use href="#words"/>
</svg>
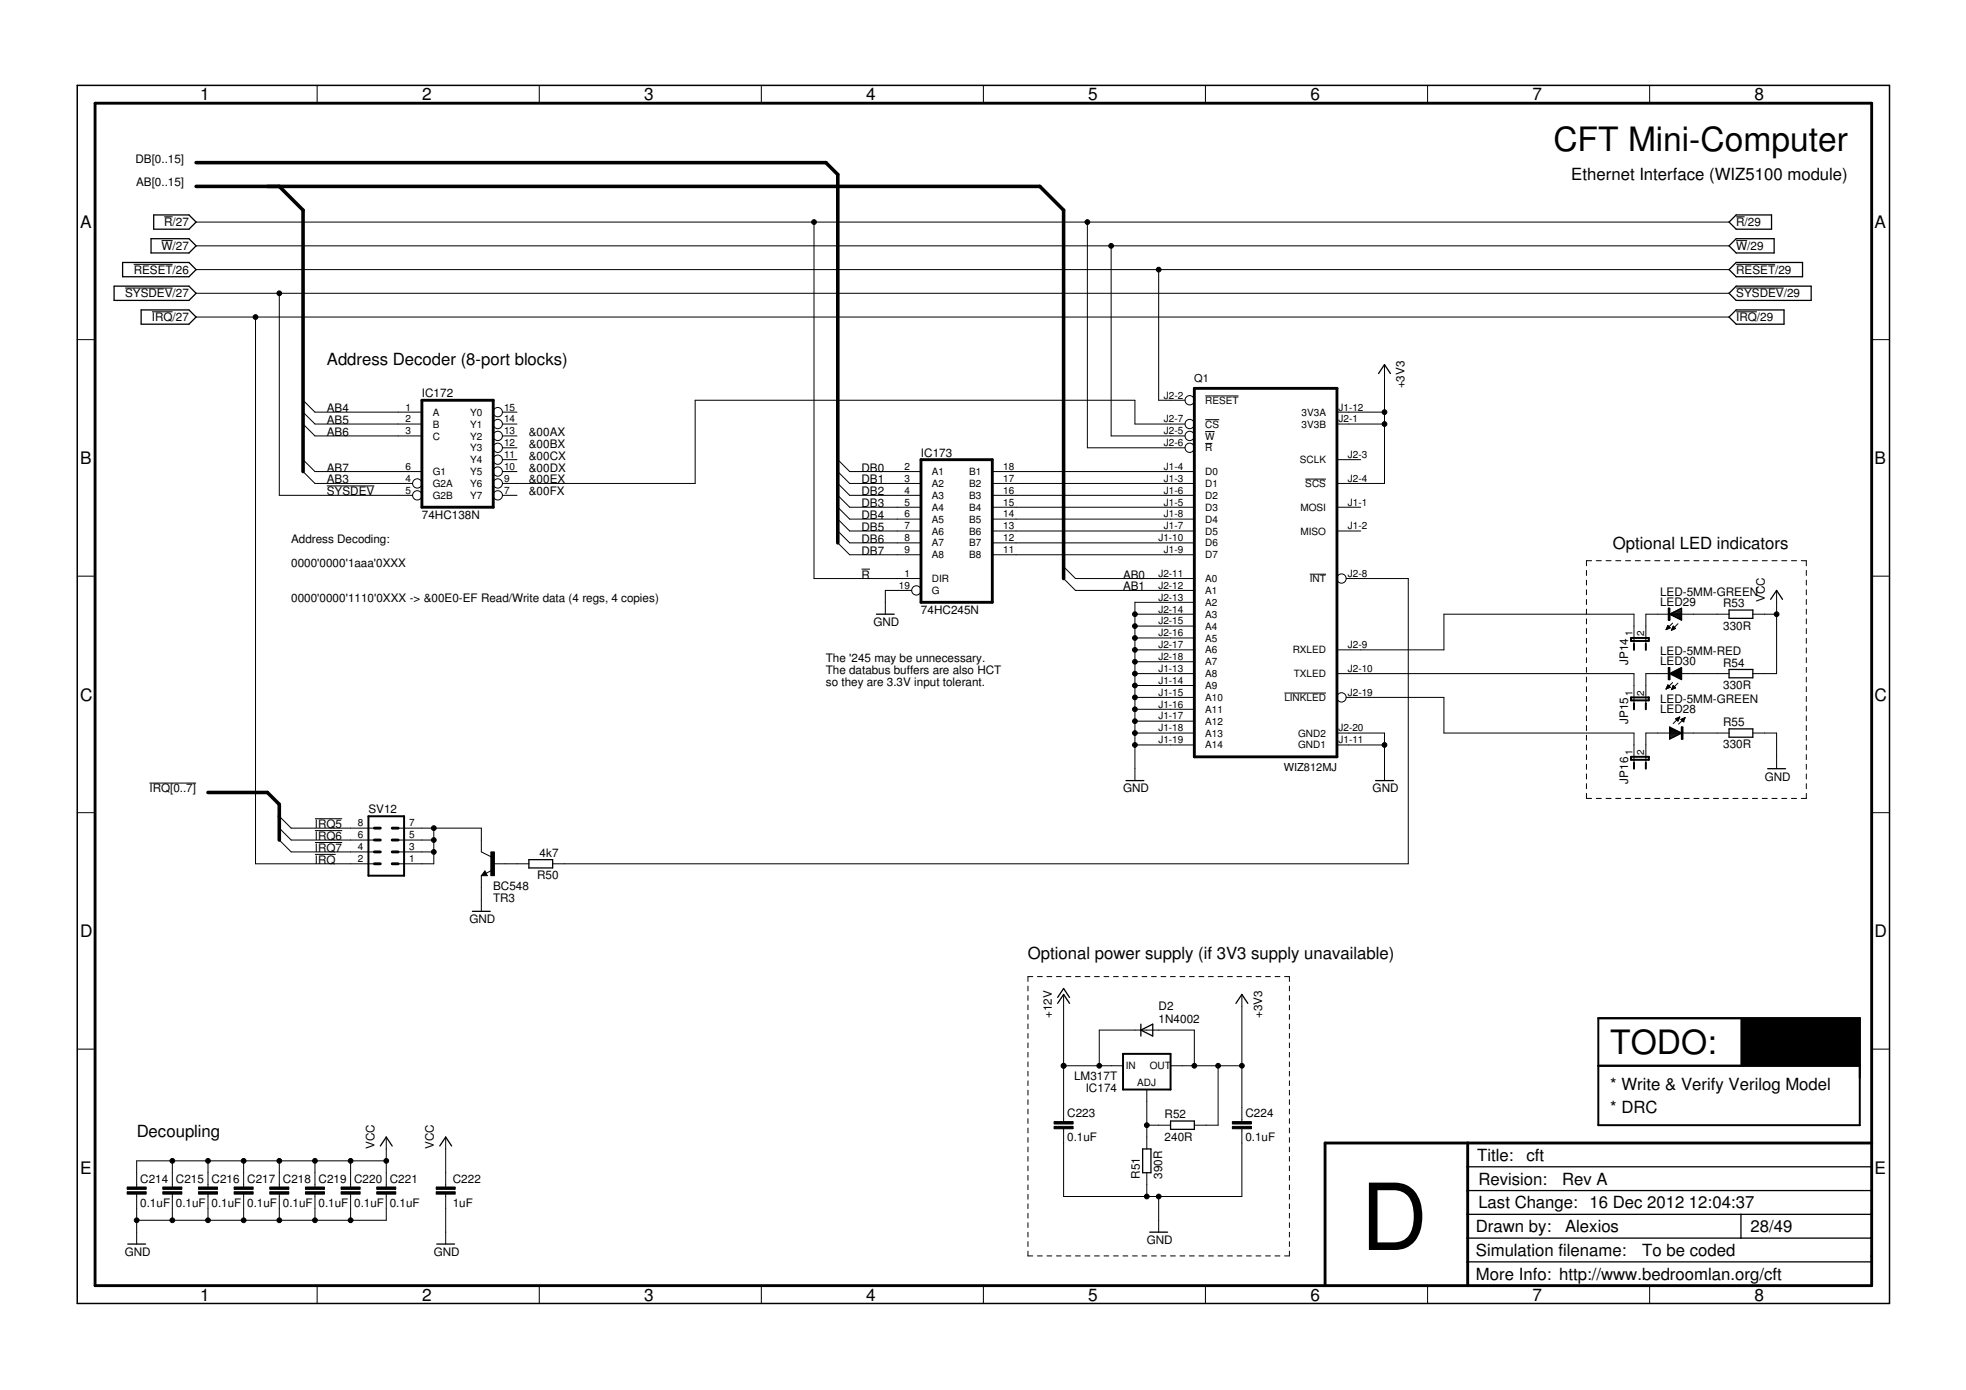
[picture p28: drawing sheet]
<svg xmlns="http://www.w3.org/2000/svg" width="420mm" height="297mm" viewBox="0 0 420 297" stroke-linecap="round" stroke-linejoin="round" font-family="sans-serif">
<defs><g id="words">
<text font-size="19.7" x="290.8" y="267.1">D</text>
<g font-size="7.2">
<text x="332" y="32.2">CFT Mini-Computer</text>
<text x="344.1" y="225.2">TODO:</text>
</g>
<g font-size="3.7">
<text x="42.7" y="21.5">1</text>
<text x="90.2" y="21.5">2</text>
<text x="137.7" y="21.5">3</text>
<text x="185.1" y="21.5">4</text>
<text x="232.6" y="21.5">5</text>
<text x="280" y="21.5">6</text>
<text x="327.5" y="21.5">7</text>
<text x="375" y="21.5">8</text>
<text x="17.1" y="48.6">A</text>
<text x="400.6" y="48.6">A</text>
<text x="17.1" y="99.2">B</text>
<text x="400.6" y="99.2">B</text>
<text x="17.1" y="149.7">C</text>
<text x="400.6" y="149.7">C</text>
<text x="17.1" y="200.2">D</text>
<text x="400.6" y="200.2">D</text>
<text x="17.1" y="250.8">E</text>
<text x="400.6" y="250.8">E</text>
<text x="42.7" y="277.9">1</text>
<text x="90.2" y="277.9">2</text>
<text x="137.7" y="277.9">3</text>
<text x="185.1" y="277.9">4</text>
<text x="232.6" y="277.9">5</text>
<text x="280" y="277.9">6</text>
<text x="327.5" y="277.9">7</text>
<text x="375" y="277.9">8</text>
</g>
<g font-size="3.6">
<text x="335.8" y="38.6">Ethernet Interface (WIZ5100 module)</text>
<text x="69.8" y="77.9">Address Decoder (8-port blocks)</text>
<text x="344.7" y="117.3">Optional LED indicators</text>
<text x="219.7" y="204.9">Optional power supply (if 3V3 supply unavailable)</text>
<text x="344.1" y="232.8">* Write &amp; Verify Verilog Model</text>
<text x="344.1" y="237.9">* DRC</text>
<text x="29.2" y="243">Decoupling</text>
<text x="315.7" y="248.1">Title:</text>
<text x="326.2" y="248.2">cft</text>
<text x="315.9" y="253.2">Revision:</text>
<text x="333.8" y="253.3">Rev A</text>
<text x="315.4" y="263.3">Drawn by:</text>
<text x="315.9" y="258.2">Last Change: 16 Dec 2012</text>
<text x="334.5" y="263.3">Alexios</text>
<text x="361" y="258.1">12:04:37</text>
<text x="374.1" y="263.2">28/49</text>
<text x="315.4" y="268.4">Simulation filename:</text>
<text x="351" y="268.4">To be coded</text>
<text x="315.4" y="273.5">More Info: http://www.bedroomlan.org/cft</text>
</g>
<g font-size="2.5">
<text x="29" y="34.7">DB[0..15]</text>
<text x="29.1" y="39.8">AB[0..15]</text>
<text x="34.5" y="53.4">W/27</text>
<text x="35.1" y="48.3">R/27</text>
<text x="371" y="53.4">W/29</text>
<text x="371" y="48.3">R/29</text>
<text x="28.6" y="58.5">RESET/26</text>
<text x="371" y="58.5">RESET/29</text>
<text x="26.7" y="63.6">SYSDEV/27</text>
<text x="371" y="63.6">SYSDEV/29</text>
<text x="32.5" y="68.7">IRQ/27</text>
<text x="371" y="68.7">IRQ/29</text>
<text x="300.2" y="83" transform="rotate(-90 300.2 83)">+3V3</text>
<text x="69.8" y="88.1">AB4</text>
<text x="90.2" y="84.9">IC172</text>
<text x="69.8" y="90.6">AB5</text>
<text x="69.8" y="93.2">AB6</text>
<text x="113" y="93.2">&amp;00AX</text>
<text x="113" y="95.7">&amp;00BX</text>
<text x="69.8" y="100.8">AB7</text>
<text x="113" y="98.2">&amp;00CX</text>
<text x="113" y="100.8">&amp;00DX</text>
<text x="184.1" y="100.8">DB0</text>
<text x="196.8" y="97.6">IC173</text>
<text x="69.8" y="105.9">SYSDEV</text>
<text x="69.8" y="103.3">AB3</text>
<text x="113" y="103.3">&amp;00EX</text>
<text x="113" y="105.9">&amp;00FX</text>
<text x="184.1" y="103.3">DB1</text>
<text x="184.1" y="105.9">DB2</text>
<text x="90.2" y="110.9">74HC138N</text>
<text x="184.1" y="108.4">DB3</text>
<text x="184.1" y="110.9">DB4</text>
<text x="184.1" y="113.5">DB5</text>
<text x="62.2" y="116">Address Decoding:</text>
<text x="184.1" y="116">DB6</text>
<text x="184.1" y="118.6">DB7</text>
<text x="62.2" y="121.1">0000'0000'1aaa'0XXX</text>
<text x="184.1" y="123.6">R</text>
<text x="240" y="123.6">AB0</text>
<text x="62.2" y="128.7">0000'0000'1110'0XXX -&gt; &amp;00E0-EF Read/Write data (4 regs, 4 copies)</text>
<text x="196.8" y="131.3">74HC245N</text>
<text x="240" y="126.2">AB1</text>
<text x="354.8" y="127.3">LED-5MM-GREEN</text>
<text x="354.8" y="129.5">LED29</text>
<text x="368.3" y="129.8">R53</text>
<text x="377.1" y="128.7" transform="rotate(-90 377.1 128.7)">VCC</text>
<text x="186.7" y="133.8">GND</text>
<text x="368.3" y="134.6">330R</text>
<text x="176.5" y="141.4">The '245 may be unnecessary.</text>
<text x="176.5" y="144">The databus buffers are also HCT</text>
<text x="347.9" y="142" transform="rotate(-90 347.9 142)">JP14</text>
<text x="354.8" y="140">LED-5MM-RED</text>
<text x="354.8" y="142.2">LED30</text>
<text x="368.3" y="142.5">R54</text>
<text x="176.5" y="146.5">so they are 3.3V input tolerant.</text>
<text x="368.3" y="147.3">330R</text>
<text x="347.9" y="154.7" transform="rotate(-90 347.9 154.7)">JP15</text>
<text x="354.8" y="150.2">LED-5MM-GREEN</text>
<text x="354.8" y="152.3">LED28</text>
<text x="368.3" y="155.2">R55</text>
<text x="368.3" y="159.9">330R</text>
<text x="347.9" y="167.4" transform="rotate(-90 347.9 167.4)">JP16</text>
<text x="377.1" y="166.8">GND</text>
<text x="31.9" y="169.3">IRQ[0..7]</text>
<text x="78.7" y="173.7">SV12</text>
<text x="240" y="169.3">GND</text>
<text x="293.3" y="169.3">GND</text>
<text x="67.3" y="177">IRQ5</text>
<text x="67.3" y="179.5">IRQ6</text>
<text x="67.3" y="184.6">IRQ</text>
<text x="67.3" y="182">IRQ7</text>
<text x="115.3" y="183.1">4k7</text>
<text x="105.4" y="190.2">BC548</text>
<text x="114.8" y="187.9">R50</text>
<text x="100.3" y="197.3">GND</text>
<text x="105.4" y="192.7">TR3</text>
<text x="247.6" y="215.8">D2</text>
<text x="224.8" y="217.6" transform="rotate(-90 224.8 217.6)">+12V</text>
<text x="247.6" y="218.6">1N4002</text>
<text x="269.7" y="217.6" transform="rotate(-90 269.7 217.6)">+3V3</text>
<text x="229.6" y="230.8">LM317T</text>
<text x="232" y="233.3">IC174</text>
<text x="228.1" y="238.8">C223</text>
<text x="248.9" y="239">R52</text>
<text x="266.2" y="238.8">C224</text>
<text x="80" y="245.5" transform="rotate(-90 80 245.5)">VCC</text>
<text x="92.7" y="245.5" transform="rotate(-90 92.7 245.5)">VCC</text>
<text x="228.1" y="243.9">0.1uF</text>
<text x="248.9" y="243.8">240R</text>
<text x="266.2" y="243.9">0.1uF</text>
<text x="243.6" y="251.9" transform="rotate(-90 243.6 251.9)">R51</text>
<text x="248.4" y="251.9" transform="rotate(-90 248.4 251.9)">390R</text>
<text x="30" y="257.9">0.1uF</text>
<text x="30" y="252.8">C214</text>
<text x="37.6" y="257.9">0.1uF</text>
<text x="37.6" y="252.8">C215</text>
<text x="45.2" y="257.9">0.1uF</text>
<text x="45.2" y="252.8">C216</text>
<text x="52.8" y="257.9">0.1uF</text>
<text x="52.8" y="252.8">C217</text>
<text x="60.4" y="257.9">0.1uF</text>
<text x="60.4" y="252.8">C218</text>
<text x="68.1" y="257.9">0.1uF</text>
<text x="68.1" y="252.8">C219</text>
<text x="75.7" y="257.9">0.1uF</text>
<text x="75.7" y="252.8">C220</text>
<text x="83.3" y="257.9">0.1uF</text>
<text x="83.3" y="252.8">C221</text>
<text x="96.8" y="257.9">1uF</text>
<text x="96.8" y="252.8">C222</text>
<text x="26.7" y="268.4">GND</text>
<text x="92.7" y="268.4">GND</text>
<text x="245.1" y="265.8">GND</text>
</g>
<g font-size="2.3">
<text x="255.2" y="81.7">Q1</text>
<text x="274.4" y="164.7">WIZ812MJ</text>
</g>
<g font-size="2.1">
<text x="86.6" y="87.7">1</text>
<text x="92.5" y="88.8">A</text>
<text x="100.5" y="88.8">Y0</text>
<text x="107.7" y="87.7">15</text>
<text x="248.8" y="85.2">J2-2</text>
<text x="257.6" y="86.3">RESET</text>
<text x="278.2" y="88.8">3V3A</text>
<text x="286.1" y="87.7">J1-12</text>
<text x="86.6" y="90.3">2</text>
<text x="86.6" y="92.8">3</text>
<text x="92.5" y="91.4">B</text>
<text x="92.5" y="93.9">C</text>
<text x="100.5" y="93.9">Y2</text>
<text x="100.5" y="91.4">Y1</text>
<text x="107.7" y="95.3">12</text>
<text x="107.7" y="92.8">13</text>
<text x="107.7" y="90.3">14</text>
<text x="248.8" y="90.3">J2-7</text>
<text x="248.8" y="92.8">J2-5</text>
<text x="248.8" y="95.3">J2-6</text>
<text x="257.6" y="91.4">CS</text>
<text x="257.6" y="93.9">W</text>
<text x="278.2" y="91.4">3V3B</text>
<text x="286.1" y="90.3">J2-1</text>
<text x="86.6" y="100.4">6</text>
<text x="92.5" y="101.5">G1</text>
<text x="100.5" y="101.5">Y5</text>
<text x="100.5" y="99">Y4</text>
<text x="100.5" y="96.5">Y3</text>
<text x="107.7" y="100.4">10</text>
<text x="107.7" y="97.9">11</text>
<text x="193.3" y="100.4">2</text>
<text x="199.2" y="101.5">A1</text>
<text x="207.1" y="101.5">B1</text>
<text x="214.4" y="100.4">18</text>
<text x="248.8" y="100.4">J1-4</text>
<text x="257.6" y="101.5">D0</text>
<text x="257.6" y="96.5">R</text>
<text x="277.8" y="99">SCLK</text>
<text x="288.1" y="97.9">J2-3</text>
<text x="86.6" y="103">4</text>
<text x="86.6" y="105.5">5</text>
<text x="92.5" y="104.1">G2A</text>
<text x="92.5" y="106.6">G2B</text>
<text x="100.5" y="106.6">Y7</text>
<text x="100.5" y="104.1">Y6</text>
<text x="107.7" y="105.5">7</text>
<text x="107.7" y="103">9</text>
<text x="193.3" y="103">3</text>
<text x="193.3" y="105.5">4</text>
<text x="199.2" y="104.1">A2</text>
<text x="199.2" y="106.6">A3</text>
<text x="207.1" y="106.6">B3</text>
<text x="207.1" y="104.1">B2</text>
<text x="214.4" y="105.5">16</text>
<text x="214.4" y="103">17</text>
<text x="248.8" y="103">J1-3</text>
<text x="248.8" y="105.5">J1-6</text>
<text x="257.6" y="104.1">D1</text>
<text x="257.6" y="106.6">D2</text>
<text x="279" y="104.1">SCS</text>
<text x="288.1" y="103">J2-4</text>
<text x="193.3" y="108">5</text>
<text x="193.3" y="110.6">6</text>
<text x="193.3" y="113.1">7</text>
<text x="199.2" y="109.2">A4</text>
<text x="199.2" y="111.7">A5</text>
<text x="207.1" y="111.7">B5</text>
<text x="207.1" y="109.2">B4</text>
<text x="214.4" y="113.1">13</text>
<text x="214.4" y="110.6">14</text>
<text x="214.4" y="108">15</text>
<text x="248.8" y="108">J1-5</text>
<text x="248.8" y="110.6">J1-8</text>
<text x="248.8" y="113.1">J1-7</text>
<text x="257.6" y="109.2">D3</text>
<text x="257.6" y="111.7">D4</text>
<text x="277.9" y="109.2">MOSI</text>
<text x="288.1" y="108">J1-1</text>
<text x="288.1" y="113.1">J1-2</text>
<text x="193.3" y="115.7">8</text>
<text x="193.3" y="118.2">9</text>
<text x="199.2" y="114.2">A6</text>
<text x="199.2" y="116.8">A7</text>
<text x="199.2" y="119.3">A8</text>
<text x="207.1" y="119.3">B8</text>
<text x="207.1" y="116.8">B7</text>
<text x="207.1" y="114.2">B6</text>
<text x="214.4" y="118.2">11</text>
<text x="214.4" y="115.7">12</text>
<text x="247.6" y="115.7">J1-10</text>
<text x="248.8" y="118.2">J1-9</text>
<text x="257.6" y="114.2">D5</text>
<text x="257.6" y="116.8">D6</text>
<text x="257.6" y="119.3">D7</text>
<text x="277.9" y="114.2">MISO</text>
<text x="192.1" y="125.8">19</text>
<text x="193.3" y="123.3">1</text>
<text x="199.2" y="124.4">DIR</text>
<text x="247.6" y="123.3">J2-11</text>
<text x="247.6" y="125.8">J2-12</text>
<text x="257.6" y="124.4">A0</text>
<text x="279.9" y="124.4">INT</text>
<text x="288.1" y="123.3">J2-8</text>
<text x="199.2" y="126.9">G</text>
<text x="247.6" y="128.4">J2-13</text>
<text x="247.6" y="130.9">J2-14</text>
<text x="257.6" y="126.9">A1</text>
<text x="257.6" y="129.5">A2</text>
<text x="247.6" y="133.4">J2-15</text>
<text x="247.6" y="136">J2-16</text>
<text x="257.6" y="132">A3</text>
<text x="257.6" y="134.6">A4</text>
<text x="257.6" y="137.1">A5</text>
<text x="348.9" y="136" transform="rotate(-90 348.9 136)">1</text>
<text x="351.4" y="136" transform="rotate(-90 351.4 136)">2</text>
<text x="247.6" y="138.5">J2-17</text>
<text x="247.6" y="141.1">J2-18</text>
<text x="247.6" y="143.6">J1-13</text>
<text x="257.6" y="139.6">A6</text>
<text x="257.6" y="142.2">A7</text>
<text x="276.3" y="139.6">RXLED</text>
<text x="288.1" y="143.6">J2-10</text>
<text x="288.1" y="138.5">J2-9</text>
<text x="247.6" y="146.1">J1-14</text>
<text x="247.6" y="148.7">J1-15</text>
<text x="257.6" y="144.7">A8</text>
<text x="257.6" y="147.3">A9</text>
<text x="257.6" y="149.8">A10</text>
<text x="274.5" y="149.8">LINKLED</text>
<text x="276.5" y="144.7">TXLED</text>
<text x="288.1" y="148.7">J2-19</text>
<text x="348.9" y="148.7" transform="rotate(-90 348.9 148.7)">1</text>
<text x="351.4" y="148.7" transform="rotate(-90 351.4 148.7)">2</text>
<text x="247.6" y="151.2">J1-16</text>
<text x="247.6" y="153.8">J1-17</text>
<text x="257.6" y="152.3">A11</text>
<text x="257.6" y="154.9">A12</text>
<text x="247.6" y="156.3">J1-18</text>
<text x="247.6" y="158.8">J1-19</text>
<text x="257.6" y="157.4">A13</text>
<text x="257.6" y="159.9">A14</text>
<text x="277.4" y="160">GND1</text>
<text x="277.4" y="157.4">GND2</text>
<text x="286.1" y="158.8">J1-11</text>
<text x="286.1" y="156.3">J2-20</text>
<text x="348.9" y="161.4" transform="rotate(-90 348.9 161.4)">1</text>
<text x="351.4" y="161.4" transform="rotate(-90 351.4 161.4)">2</text>
<text x="76.5" y="179.1">6</text>
<text x="76.5" y="176.6">8</text>
<text x="87.4" y="179.1">5</text>
<text x="87.4" y="176.6">7</text>
<text x="76.5" y="184.2">2</text>
<text x="76.5" y="181.7">4</text>
<text x="87.4" y="184.2">1</text>
<text x="87.4" y="181.7">3</text>
<text x="240.6" y="228.4">IN</text>
<text x="243.1" y="232.1">ADJ</text>
<text x="245.7" y="228.4">OUT</text>
</g>
</g></defs>
<g fill="#000" stroke="#000" stroke-width=".21">
<path d="M67.8 18.2v3.9zM115.3 18.2v3.9zM162.7 18.2v3.9zM210.2 18.2v3.9zM257.6 18.2v3.9zM305.1 18.2v3.9zM352.5 18.2v3.9zM20.3 22.1v252.6zM20.3 22.1h379.7zM28.6 56.5h8.3zM34.5 51.4h2.4zM35.1 46.3h1.8z"/>
<path d="M41.9 52.5h195.6zM41.9 47.5h132.1zM174 47.5h58.4zM232.4 47.5h137.1zM237.5 52.5h132zM41.9 57.6h205.7zM247.6 57.6h121.9zM371 51.4h2.4zM371 46.3h1.8zM371 56.5h8.4zM16.5 72.6h3.8zM26.7 61.6h10.2z"/>
<path d="M32.5 66.6h4.4zM41.9 67.8h12.7zM41.9 62.7h17.8zM54.6 67.8h314.9zM59.7 62.7h309.8zM59.7 62.7v43.2zM371 66.6h4.5zM371 61.6h10.2zM400 72.6h3.8zM64.8 85.5l2.5 2.6zM64.8 88.1l2.5 2.5zM64.8 90.6l2.5 2.6z"/>
<path d="M67.3 88.1h17.8zM67.3 90.6h17.8zM67.3 93.2h17.8zM85.1 88.1h5.1zM85.1 90.6h5.1zM85.1 93.2h5.1zM107.4 98.2h3.1zM107.4 95.7h3.1zM107.4 93.2h3.1zM107.4 90.6h3.1zM107.4 88.1h3.1zM148.6 85.5h93.9z"/>
<path d="M232.4 47.5v48.2zM237.5 52.5v40.7zM242.5 90.6h7.7zM242.5 85.5v5.1zM247.6 57.6v27.9zM250.2 85.5h3.1zM250.2 90.6h3.1zM250.2 93.2h3.1zM250.2 95.7h3.1zM237.5 93.2h12.7zM232.4 95.7h17.8zM247.6 85.5h2.6z"/>
<path d="M257.6 84.6h7.1zM257.6 89.7h3zM257.6 92.2h2zM257.6 94.8h1.5zM285.7 88.1h2.6zM285.7 90.6h2.6zM288.3 88.1h7.6zM288.3 90.6h7.6zM285.7 98.2h5.1zM295.9 77.9v2.6zM295.9 80.5v7.6zM295.9 88.1v2.5z"/>
<path d="M64.8 98.2l2.5 2.6zM64.8 100.8l2.5 2.5zM69.8 103.8h10.2zM85.1 103.3h3.1zM85.1 105.9h3.1zM85.1 100.8h5.1zM59.7 105.9h25.4zM67.3 100.8h17.8zM67.3 103.3h17.8zM107.4 105.9h3.1zM107.4 103.3h3.1zM107.4 100.8h3.1z"/>
<path d="M110.5 103.3h38.1zM148.6 85.5v17.8zM179 116l2.6 2.6zM179 98.2l2.6 2.6zM179 100.8l2.6 2.5zM179 103.3l2.6 2.6zM179 105.9l2.6 2.5zM179 108.4l2.6 2.5zM179 110.9l2.6 2.6zM179 113.5l2.6 2.5zM181.6 118.6h10.1zM191.7 100.8h5.1z"/>
<path d="M191.7 103.3h5.1zM191.7 105.9h5.1zM191.7 108.4h5.1zM191.7 110.9h5.1zM191.7 113.5h5.1zM191.7 116h5.1zM191.7 118.6h5.1zM181.6 100.8h10.1zM181.6 103.3h10.1zM181.6 105.9h10.1zM181.6 108.4h10.1zM181.6 110.9h10.1z"/>
<path d="M181.6 113.5h10.1zM181.6 116h10.1zM212.1 118.6h5zM212.1 116h5zM212.1 113.5h5zM212.1 110.9h5zM212.1 108.4h5zM212.1 105.9h5zM212.1 103.3h5zM212.1 100.8h5zM217.1 118.6h33.1zM217.1 116h33.1z"/>
<path d="M217.1 113.5h33.1zM217.1 110.9h33.1zM217.1 108.4h33.1zM217.1 105.9h33.1zM217.1 103.3h33.1zM217.1 100.8h33.1zM250.2 100.8h5zM250.2 103.3h5zM250.2 105.9h5zM250.2 108.4h5zM250.2 110.9h5zM250.2 113.5h5z"/>
<path d="M250.2 116h5zM250.2 118.6h5zM279 102.4h4.4zM285.7 103.3h5.1zM285.7 108.4h5.1zM285.7 113.5h5.1zM290.8 103.3h5.1zM295.9 90.6v12.7zM339 119.8h1.1zM341.1 119.8h1.1zM343.2 119.8h1.1zM345.3 119.8h1.1z"/>
<path d="M347.4 119.8h1.1zM349.5 119.8h1.1zM351.6 119.8h1.1zM353.6 119.8h1.1zM355.7 119.8h1.1zM357.8 119.8h1.1zM359.9 119.8h1.1zM362 119.8h1.1zM364.1 119.8h1.1zM366.2 119.8h1.1zM368.3 119.8h1.1zM370.3 119.8h1.1z"/>
<path d="M372.4 119.8h1.1zM374.5 119.8h1.1zM376.6 119.8h1.1zM378.7 119.8h1.1zM380.8 119.8h1.1zM382.9 119.8h1.1zM385 119.8h1zM16.5 123.1h3.8zM174 47.5v76.1zM184.1 121.6h1.8zM189.2 128.7v2.6zM189.2 126.2v2.5z"/>
<path d="M191.7 123.6h5.1zM191.7 126.2h3.2zM189.2 126.2h2.5zM174 123.6h17.7zM227.3 123.6l2.5 2.6zM227.3 121.1l2.5 2.5zM229.8 126.2h20.4zM229.8 123.6h20.4zM242.5 128.7v2.6zM242.5 131.3v2.5zM242.5 133.8v2.5zM242.5 136.3v2.6z"/>
<path d="M242.5 138.9v2.5zM242.5 138.9h7.7zM250.2 123.6h5zM250.2 126.2h5zM250.2 128.7h5zM250.2 131.3h5zM250.2 133.8h5zM250.2 136.3h5zM250.2 138.9h5zM242.5 128.7h7.7zM242.5 131.3h7.7zM242.5 133.8h7.7z"/>
<path d="M242.5 136.3h7.7zM279.9 122.7h3.5zM287.7 123.6h3.1zM285.7 138.9h5.1zM290.8 138.9h17.8zM301 123.6v61zM290.8 123.6h10.2zM308.6 131.3v7.6zM308.6 131.3h40.6zM339 138.5v1zM339 136.4v1.1zM339 134.3v1.1z"/>
<path d="M339 132.2v1.1zM339 130.2v1.1zM339 128.1v1.1zM339 126v1.1zM339 124v1zM339 121.9v1.1zM339 119.8v1.1zM349.2 133.8v2.5zM349.2 136.3v1.3zM349.2 131.3v2.5zM351.7 133.8v2.5zM351.7 136.3v1.3z"/>
<path d="M351.7 131.3v2.5zM351.7 131.3h2.6zM354.3 131.3h2.5zM356.1 134.6l.8-.4zM356.1 134.4h.2zM356.2 134.3h.4zM356.2 134.2h.7zM356.3 134.1h.6zM356.3 134h.5zM356.4 133.9h.2zM356.4 133.7l-.3 .9zM356.4 133.7l.5 .5z"/>
<path d="M357.2 134.7l.9-.4zM357.2 134.6h.3zM357.3 134.4h.4zM357.4 134.3h.6zM357.4 134.2h.6zM357.5 133.2l-1.4 1.4zM357.5 134.1h.4zM357.5 134h.3zM357.6 133.8l-.4 .9zM357.6 133.8l.5 .5zM358.6 133.3l-1.4 1.4zM356.8 131.3h2.6z"/>
<path d="M359.4 131.3h2.5zM367 131.3h2.5zM361.9 131.3h5.1zM374.6 131.3h2.5zM377.1 131.3h2.6zM379.7 126.2v2.5zM379.7 128.7v2.6zM386 138.5v1zM386 136.4v1.1zM386 134.3v1.1zM386 132.2v1.1zM386 130.2v1.1z"/>
<path d="M386 128.1v1.1zM386 126v1.1zM386 124v1zM386 121.9v1.1zM386 119.8v1.1zM400 123.1h3.8zM242.5 141.4v2.6zM242.5 144v2.5zM242.5 146.5v2.5zM242.5 149v2.6zM242.5 151.6v2.5zM242.5 154.1v2.6z"/>
<path d="M242.5 156.7v2.5zM242.5 159.2v5.1zM242.5 144h7.7zM242.5 149h7.7zM242.5 154.1h7.7zM242.5 159.2h7.7zM250.2 141.4h5zM250.2 144h5zM250.2 146.5h5zM250.2 149h5zM250.2 151.6h5zM250.2 154.1h5z"/>
<path d="M250.2 156.7h5zM250.2 159.2h5zM242.5 141.4h7.7zM242.5 146.5h7.7zM242.5 151.6h7.7zM242.5 156.7h7.7zM274.5 148.1h8.9zM285.7 159.2h2.6zM285.7 156.7h2.6zM288.3 156.7h7.6zM288.3 159.2h7.6zM287.7 149h3.1z"/>
<path d="M285.7 144h5.1zM290.8 149h17.8zM295.9 156.7v2.5zM295.9 159.2v5.1zM308.6 149v7.7zM308.6 156.7h40.6zM339 157.1v1.1zM339 155v1.1zM339 153v1zM339 150.9v1.1zM339 148.8v1.1zM339 146.7v1.1z"/>
<path d="M339 144.7v1.1zM339 142.6v1.1zM339 140.5v1.1zM349.2 146.5v2.5zM349.2 149v1.3zM349.2 159.2v2.5zM349.2 144v2.5zM290.8 144h58.4zM349.2 156.7v2.5zM351.7 146.5v2.5zM351.7 149v1.3zM351.7 159.2v2.5z"/>
<path d="M351.7 144v2.5zM351.7 144h2.6zM351.7 156.7v2.5zM351.7 156.7h2.6zM354.3 144h2.5zM354.3 156.7h2.5zM356.1 147.3l.8-.4zM356.1 147.1h.3zM356.2 147h.5zM356.2 146.9h.7zM356.3 146.7h.5zM356.3 146.6h.4z"/>
<path d="M356.4 146.5h.2zM356.4 146.4l-.3 .9zM356.8 156.7h2.6zM356.4 146.4l.5 .5zM357.2 147.4l.9-.4zM357.3 147.2h.2zM357.3 147.1h.5zM357.4 147h.7zM357.4 146.9h.6zM357.5 145.9l-1.4 1.4zM357.5 146.7h.4zM357.5 146.6h.2z"/>
<path d="M357.6 146.5l-.4 .9zM357.6 154.6l1.4-1.4zM357.6 146.5l.5 .5zM358.1 153.6l.5 .5zM358.1 153.6h.7zM358.2 153.8h.6zM358.3 153.5h.6zM358.4 153.9h.3zM358.5 154h.2zM358.6 146l-1.4 1.4zM359 153.2l-.4 .9zM358.6 153.4h.3z"/>
<path d="M360.1 153.3l-1.4 1.4zM358.1 153.6l.9-.4zM359.2 153.7l.5 .5zM359.3 153.8h.7zM356.8 144h2.6zM359.4 153.9h.5zM359.5 153.6h.5zM359.5 154h.3zM359.6 154.1h.2zM360.1 153.3l-.4 .9zM359.8 153.5h.3zM359.2 153.7l.9-.4z"/>
<path d="M359.4 144h2.5zM359.4 156.7h2.5zM361.9 156.7h5.1zM367 144h2.5zM367 156.7h2.5zM361.9 144h5.1zM374.6 144h2.5zM374.6 156.7h2.5zM377.1 156.7h2.6zM377.1 144h2.6zM379.7 156.7v5zM379.7 131.3v12.7z"/>
<path d="M386 157.1v1.1zM386 155v1.1zM386 153v1zM386 150.9v1.1zM386 148.8v1.1zM386 146.7v1.1zM386 144.7v1.1zM386 142.6v1.1zM386 140.5v1.1zM16.5 173.7h3.8zM31.9 167.3h10zM59.7 174.4l2.5 2.6z"/>
<path d="M59.7 177l2.5 2.5zM67.3 175h5.8zM67.3 177.5h5.8zM74.9 179.5h5.1zM74.9 177h5.1zM62.2 177h12.7zM62.2 179.5h12.7zM85.1 179.5h5.1zM85.1 177h5.1zM90.2 179.5h2.5zM90.2 177h2.5zM92.7 177v2.5z"/>
<path d="M92.7 179.5v2.6zM102.9 179.5v2.6zM92.7 177h10.2zM102.9 177v2.5zM242.5 164.3v2.5zM295.9 164.3v2.5zM339 169.5v1.1zM339 167.5v1zM339 165.4v1.1zM339 163.3v1.1zM339 161.3v1zM339 159.2v1.1z"/>
<path d="M339 170.6h1.1zM341.1 170.6h1.1zM343.2 170.6h1.1zM345.3 170.6h1.1zM347.4 170.6h1.1zM349.2 161.7v1.3zM349.5 170.6h1.1zM351.7 161.7v1.3zM351.6 170.6h1.1zM353.6 170.6h1.1zM355.7 170.6h1.1zM357.8 170.6h1.1z"/>
<path d="M359.9 170.6h1.1zM362 170.6h1.1zM364.1 170.6h1.1zM366.2 170.6h1.1zM368.3 170.6h1.1zM370.3 170.6h1.1zM372.4 170.6h1.1zM374.5 170.6h1.1zM376.6 170.6h1.1zM379.7 161.7v2.6zM378.7 170.6h1.1zM380.8 170.6h1.1z"/>
<path d="M382.9 170.6h1.1zM385 170.6h1zM386 169.5v1.1zM386 167.5v1zM386 165.4v1.1zM386 163.3v1.1zM386 161.3v1zM386 159.2v1.1zM400 173.7h3.8zM54.6 67.8v116.8zM59.7 179.5l2.5 2.6zM67.3 182.6h4.4z"/>
<path d="M67.3 180h5.8zM74.9 184.6h5.1zM74.9 182.1h5.1zM54.6 184.6h20.3zM62.2 182.1h12.7zM85.1 184.6h5.1zM85.1 182.1h5.1zM90.2 184.6h2.5zM90.2 182.1h2.5zM92.7 182.1v2.5zM102.9 192.2v2.6zM102.9 187.1v2.6z"/>
<path d="M102.9 182.1l2 1zM102.9 187.1h1.2zM102.9 189.7v2.5zM103.6 186.1l-.7 1zM103.9 186.6l1.2-.6zM103.6 186.1l.5 1zM105.4 184.6h2.5zM110.5 184.6h2.5zM107.9 184.6h2.6zM118.1 184.6h2.5zM120.6 184.6h180.4zM219.7 208.7v1z"/>
<path d="M219.7 210.7v1zM219.7 212.8v1zM219.7 214.8v1zM219.7 216.8v1zM219.7 218.8v1.1zM219.7 208.7h1zM221.7 208.7h1.1zM223.7 208.7h1.1zM225.8 208.7h1zM227.3 212.5v2.5zM227.8 208.7h1.1zM229.8 208.7h1.1z"/>
<path d="M231.9 208.7h1zM233.9 208.7h1zM235.9 208.7h1.1zM238 208.7h1zM240 208.7h1zM242 208.7h1.1zM244.1 208.7h1zM246.1 208.7h1zM248.1 208.7h1zM250.1 208.7h1.1zM252.2 208.7h1zM254.2 208.7h1z"/>
<path d="M256.2 208.7h1.1zM258.3 208.7h1zM260.3 208.7h1zM262.3 208.7h1.1zM264.4 208.7h1zM265.4 212.5v2.5zM265.4 215v12.7zM266.4 208.7h1zM268.4 208.7h1.1zM270.5 208.7h1zM272.5 208.7h1zM274.5 208.7h1.1z"/>
<path d="M275.6 208.7v1zM275.6 210.7v1zM275.6 212.8v1zM275.6 214.8v1zM275.6 216.8v1zM275.6 218.8v1.1zM16.5 224.2h3.8zM219.7 220.8v1.1zM219.7 222.9v1zM219.7 224.9v1zM219.7 226.9v1zM219.7 228.9v1.1z"/>
<path d="M219.7 231v1zM219.7 233v1zM219.7 235v1zM219.7 237v1.1zM219.7 239.1v1zM227.3 236.6v2.6zM227.3 239.2v.5zM227.3 227.7h7.6zM227.3 227.7v8.9zM227.3 215v12.7zM234.9 227.7h2.6zM234.9 220.1v7.6z"/>
<path d="M237.5 227.7h2.5zM242.5 220.1h2.6zM234.9 220.1h7.6zM245.1 232.8v2.6zM245.1 235.4v5zM245.1 220.1h2.5zM247.6 220.1h7.6zM250.2 227.7h2.5zM252.7 227.7h2.5zM255.2 220.1v7.6zM255.2 227.7h5.1zM260.3 227.7h5.1z"/>
<path d="M265.4 236.6v2.6zM265.4 239.2v.5zM265.4 227.7v8.9zM275.6 220.8v1.1zM275.6 222.9v1zM275.6 224.9v1zM275.6 226.9v1zM275.6 228.9v1.1zM275.6 231v1zM275.6 233v1zM275.6 235v1zM275.6 237v1.1z"/>
<path d="M275.6 239.1v1zM400 224.2h3.8zM29.2 255.7v2.5zM29.2 250.6v2.5zM29.2 255.2v.5zM29.2 253.1v.6zM29.2 258.2v2.6zM29.2 248.1v2.5zM36.8 255.7v2.5zM36.8 250.6v2.5zM36.8 255.2v.5zM36.8 253.1v.6z"/>
<path d="M36.8 248.1v2.5zM29.2 248.1h7.6zM44.4 255.7v2.5zM44.4 250.6v2.5zM44.4 255.2v.5zM44.4 253.1v.6zM36.8 248.1h7.6zM44.4 248.1v2.5zM52.1 255.7v2.5zM52.1 250.6v2.5zM52.1 255.2v.5zM52.1 253.1v.6z"/>
<path d="M44.4 248.1h7.7zM52.1 248.1v2.5zM59.7 255.7v2.5zM59.7 250.6v2.5zM59.7 255.2v.5zM59.7 253.1v.6zM52.1 248.1h7.6zM59.7 248.1v2.5zM67.3 255.7v2.5zM67.3 250.6v2.5zM67.3 255.2v.5zM67.3 253.1v.6z"/>
<path d="M59.7 248.1h7.6zM67.3 248.1v2.5zM74.9 255.7v2.5zM74.9 250.6v2.5zM74.9 255.2v.5zM74.9 253.1v.6zM67.3 248.1h7.6zM74.9 248.1v2.5zM82.5 243v2.5zM82.5 255.7v2.5zM82.5 250.6v2.5zM82.5 255.2v.5z"/>
<path d="M82.5 253.1v.6zM74.9 248.1h7.6zM82.5 245.5v2.6zM82.5 248.1v2.5zM95.2 243v2.5zM95.2 250.6v2.5zM95.2 255.7v2.5zM95.2 253.1v.6zM95.2 255.2v.5zM95.2 245.5v5.1zM219.7 241.1v1zM219.7 243.1v1z"/>
<path d="M219.7 245.1v1zM219.7 247.1v1.1zM219.7 249.2v1zM219.7 251.2v1zM219.7 253.2v1zM219.7 255.2v1.1zM219.7 257.3v1zM219.7 259.3v1zM227.3 241.7v2.6zM227.3 241.2v.5zM227.3 255.7h17.8zM227.3 244.3v11.4z"/>
<path d="M245.1 243v2.5zM245.1 250.6v2.5zM245.1 255.7h2.5zM245.1 253.1v2.6zM245.1 240.4v2.6zM245.1 240.4h2.5zM247.6 240.4h2.6zM247.6 255.7h17.8zM255.2 240.4h2.6zM257.8 240.4h2.5zM260.3 227.7v12.7zM265.4 241.7v2.6z"/>
<path d="M265.4 241.2v.5zM265.4 244.3v11.4zM275.6 241.1v1zM275.6 243.1v1zM275.6 245.1v1zM275.6 247.1v1.1zM275.6 249.2v1zM275.6 251.2v1zM275.6 253.2v1zM275.6 255.2v1.1zM275.6 257.3v1zM275.6 259.3v1z"/>
<path d="M20.3 274.7h379.7zM29.2 263.3v2.5zM29.2 260.8h7.6zM29.2 260.8v2.5zM36.8 258.2v2.6zM36.8 260.8h7.6zM44.4 258.2v2.6zM44.4 260.8h7.7zM52.1 258.2v2.6zM52.1 260.8h7.6zM59.7 258.2v2.6zM59.7 260.8h7.6z"/>
<path d="M67.3 258.2v2.6zM67.8 274.7v3.8zM67.3 260.8h7.6zM74.9 258.2v2.6zM74.9 260.8h7.6zM82.5 258.2v2.6zM95.2 263.3v2.5zM95.2 258.2v5.1zM115.3 274.7v3.8zM162.7 274.7v3.8zM210.2 274.7v3.8zM219.7 261.3v1z"/>
<path d="M219.7 263.3v1zM219.7 265.3v1.1zM219.7 267.4v1zM219.7 268.4h1zM221.7 268.4h1.1zM223.7 268.4h1.1zM225.8 268.4h1zM227.8 268.4h1.1zM229.8 268.4h1.1zM231.9 268.4h1zM233.9 268.4h1zM235.9 268.4h1.1z"/>
<path d="M238 268.4h1zM240 268.4h1zM242 268.4h1.1zM244.1 268.4h1zM246.1 268.4h1zM247.6 260.8v2.5zM247.6 255.7v5.1zM248.1 268.4h1zM250.1 268.4h1.1zM252.2 268.4h1zM254.2 268.4h1zM256.2 268.4h1.1z"/>
<path d="M257.6 274.7v3.8zM258.3 268.4h1zM260.3 268.4h1zM262.3 268.4h1.1zM264.4 268.4h1zM266.4 268.4h1zM268.4 268.4h1.1zM270.5 268.4h1zM272.5 268.4h1zM274.5 268.4h1.1zM275.6 261.3v1zM275.6 263.3v1z"/>
<path d="M275.6 265.3v1.1zM275.6 267.4v1zM305.1 274.7v3.8zM352.5 274.7v3.8zM400 264.5v.1zM400 268.4v6.2zM400 274.6h.1zM400 22.1v252.6z"/>
<circle cx="174" cy="47.5" r=".51"/>
<circle cx="232.4" cy="47.5" r=".51"/>
<circle cx="237.5" cy="52.5" r=".51"/>
<circle cx="247.6" cy="57.6" r=".51"/>
<circle cx="54.6" cy="67.8" r=".51"/>
<circle cx="59.7" cy="62.7" r=".51"/>
<circle cx="295.9" cy="88.1" r=".51"/>
<circle cx="295.9" cy="90.6" r=".51"/>
<circle cx="242.5" cy="133.8" r=".51"/>
<circle cx="242.5" cy="136.3" r=".51"/>
<circle cx="242.5" cy="138.9" r=".51"/>
<circle cx="242.5" cy="131.3" r=".51"/>
<circle cx="379.7" cy="131.3" r=".51"/>
<circle cx="242.5" cy="144" r=".51"/>
<circle cx="242.5" cy="159.2" r=".51"/>
<circle cx="242.5" cy="146.5" r=".51"/>
<circle cx="242.5" cy="141.4" r=".51"/>
<circle cx="242.5" cy="156.7" r=".51"/>
<circle cx="242.5" cy="149" r=".51"/>
<circle cx="242.5" cy="154.1" r=".51"/>
<circle cx="242.5" cy="151.6" r=".51"/>
<circle cx="295.9" cy="159.2" r=".51"/>
<circle cx="92.7" cy="177" r=".51"/>
<circle cx="92.7" cy="179.5" r=".51"/>
<circle cx="92.7" cy="182.1" r=".51"/>
<circle cx="227.3" cy="227.7" r=".51"/>
<circle cx="234.9" cy="227.7" r=".51"/>
<circle cx="255.2" cy="227.7" r=".51"/>
<circle cx="260.3" cy="227.7" r=".51"/>
<circle cx="265.4" cy="227.7" r=".51"/>
<circle cx="36.8" cy="248.1" r=".51"/>
<circle cx="44.4" cy="248.1" r=".51"/>
<circle cx="52.1" cy="248.1" r=".51"/>
<circle cx="59.7" cy="248.1" r=".51"/>
<circle cx="67.3" cy="248.1" r=".51"/>
<circle cx="74.9" cy="248.1" r=".51"/>
<circle cx="82.5" cy="248.1" r=".51"/>
<circle cx="245.1" cy="255.7" r=".51"/>
<circle cx="245.1" cy="240.4" r=".51"/>
<circle cx="247.6" cy="255.7" r=".51"/>
<circle cx="29.2" cy="260.8" r=".51"/>
<circle cx="36.8" cy="260.8" r=".51"/>
<circle cx="44.4" cy="260.8" r=".51"/>
<circle cx="52.1" cy="260.8" r=".51"/>
<circle cx="59.7" cy="260.8" r=".51"/>
<circle cx="67.3" cy="260.8" r=".51"/>
<circle cx="74.9" cy="260.8" r=".51"/>
</g>
<g fill="#000" stroke="#000" stroke-width=".28">
<path d="M26.2 56.1v3zM32.3 51v3.1zM32.9 45.9v3.1zM32.3 51h8.1zM32.3 54.1h8.1zM32.9 45.9h7.5zM32.9 49h7.5zM26.2 56.1h14.2zM26.2 59.1h14.2zM40.4 51l1.5 1.5zM41.9 52.5l-1.5 1.6zM40.4 45.9l1.5 1.6z"/>
<path d="M41.9 47.5l-1.5 1.5zM40.4 56.1l1.5 1.5zM41.9 57.6l-1.5 1.5zM369.5 52.5l1.5-1.5zM369.5 52.5l1.5 1.6zM369.5 47.5l1.5-1.6zM369.5 47.5l1.5 1.5zM371 56.1l-1.5 1.5zM369.5 57.6l1.5 1.5zM371 51h8.2zM371 54.1h8.2zM371 45.9h7.6z"/>
<path d="M371 49h7.6zM371 56.1h14.2zM371 59.1h14.2zM378.6 45.9v3.1zM379.2 51v3.1zM385.2 56.1v3zM24.4 61.1v3.1zM30.2 66.2v3.1zM30.2 69.3h10.2zM30.2 66.2h10.2zM24.4 64.2h16zM24.4 61.1h16z"/>
<path d="M41.9 67.8l-1.5 1.5zM40.4 66.2l1.5 1.6zM40.4 64.2l1.5-1.5zM40.4 61.1l1.5 1.6zM295.9 77.9l-1.3 1.9zM295.9 77.9l1.3 1.9zM371 66.2l-1.5 1.6zM369.5 67.8l1.5 1.5zM371 61.1l-1.5 1.6zM369.5 62.7l1.5 1.5zM371 66.2h10.3zM371 69.3h10.3z"/>
<path d="M371 61.1h16.1zM371 64.2h16.1zM381.3 66.2v3.1zM387.1 61.1v3.1zM187.3 131.3h3.8zM356.6 130v2.5zM356.6 132.5h.2zM356.6 132.4h.2zM356.6 132.1h.2zM356.6 131.9h.2zM356.6 131.7h.2zM356.6 131.5h.2z"/>
<path d="M356.6 131.3h.2zM356.6 131h.2zM356.6 130.8h.2zM356.6 130.6h.2zM356.6 130.4h.2zM356.6 130.2h.2zM356.8 131.3v1.2zM356.8 131.3l2.6 1.2zM356.8 131.3h2.6zM356.8 130v2.5zM356.6 130h.2zM357.3 131.5h2.1z"/>
<path d="M357.3 131h2.1zM357.7 131.7h1.7zM357.7 130.8h1.7zM358.2 131.9h1.2zM358.2 130.6h1.2zM358.6 132.1h.8zM358.6 130.4h.8zM359 132.4h.4zM359 130.2h.4zM359.4 130v2.5zM356.8 131.3l2.6-1.3zM369.5 132.1h5.1z"/>
<path d="M369.5 130.4v1.7zM369.5 130.4h5.1zM374.6 130.4v1.7zM379.7 126.2l-1.3 1.9zM379.7 126.2l1.3 1.9zM356.6 142.7v2.5zM356.6 145.2h.2zM356.6 145h.2zM356.6 144.8h.2zM356.6 144.6h.2zM356.6 144.4h.2zM356.6 144.1h.2z"/>
<path d="M356.6 143.9h.2zM356.6 143.7h.2zM356.6 143.5h.2zM356.6 143.3h.2zM356.6 143h.2zM356.6 142.8h.2zM356.8 144v1.2zM356.8 144l2.6 1.2zM356.8 142.7v2.5zM356.6 142.7h.2zM356.8 155.4v2.5zM356.8 157.9l2.6-1.2z"/>
<path d="M356.8 157.7h.5zM356.8 157.5h.9zM356.8 157.2h1.4zM356.8 157h1.8zM356.8 156.8h2.3zM356.8 156.6h2.4zM356.8 156.4h2zM356.8 156.1h1.5zM356.8 155.9h1.1zM356.8 155.7h.7zM356.8 155.5h.2zM356.9 143.9h2.5z"/>
<path d="M357.2 144.1h2.2zM357.3 143.7h2.1zM357.6 144.4h1.8zM357.8 143.5h1.6zM358.1 144.6h1.3zM358.2 143.3h1.2zM358.5 144.8h.9zM358.7 143h.7zM359 145h.4zM359.1 142.8h.3zM359.4 142.7v2.5zM356.8 144l2.6-1.3z"/>
<path d="M359.4 155.4v1.3zM356.8 155.4l2.6 1.3zM359.4 155.4v2.5zM359.4 157.9h.2zM359.4 157.7h.2zM359.4 157.5h.2zM359.4 157.2h.2zM359.4 157h.2zM359.4 156.8h.2zM359.4 156.6h.2zM359.4 156.4h.2zM359.4 156.1h.2z"/>
<path d="M359.4 155.9h.2zM359.4 155.7h.2zM359.4 155.5h.2zM359.6 155.4v2.5zM359.4 155.4h.2zM369.5 144.8h5.1zM369.5 143.1v1.7zM369.5 157.5h5.1zM369.5 155.8v1.7zM369.5 143.1h5.1zM374.6 143.1v1.7zM369.5 155.8h5.1z"/>
<path d="M374.6 155.8v1.7zM240.6 166.8h3.8zM294 166.8h3.8zM377.8 164.3h3.8zM101 194.8h3.8zM103.6 186.4l-.5 .6zM103.6 186.6l-.1 .3zM103.6 186.4l.3 .5zM103.1 187h.8zM103.5 186.9h.4zM113 185.5h5.1zM113 183.7v1.8z"/>
<path d="M113 183.7h5.1zM118.1 183.7v1.8zM227.3 212.5l-1.3 1.9zM227.3 211.2l-1.3 1.9zM227.3 212.5l1.3 1.9zM227.3 211.2l1.3 1.9zM243.8 220.1l2.6-1.2zM265.4 212.5l-1.3 1.9zM265.4 212.5l1.3 1.9zM243.8 220.1l2.6 1.3zM243.8 220.1v1.3zM243.8 218.9v1.2z"/>
<path d="M246.4 218.9v2.5zM250.2 239.6h5zM82.5 243l-1.2 1.9zM82.5 243l1.3 1.9zM95.2 243l-1.2 1.9zM95.2 243l1.3 1.9zM244.2 245.5v5.1zM246 245.5v5.1zM244.2 245.5h1.8zM244.2 250.6h1.8zM250.2 241.3h5zM250.2 239.6v1.7z"/>
<path d="M255.2 239.6v1.7zM313.7 249.3h86.3zM313.7 254.4h86.3zM313.7 259.5h58.4zM372.1 259.5h27.9zM372.1 259.5v5.1zM27.3 265.8h3.8zM93.3 265.8h3.9zM245.7 263.3h3.8zM313.7 264.6h58.4zM313.7 269.7h86.3zM372.1 264.6h27.9z"/>
<path d="M400 268.4v1.3z"/>
</g>
<g fill="none" stroke="#000" stroke-width=".21">
<circle cx="106.4" cy="95.7" r=".99"/>
<circle cx="106.4" cy="93.2" r=".99"/>
<circle cx="106.4" cy="90.6" r=".99"/>
<circle cx="106.4" cy="88.1" r=".99"/>
<circle cx="106.4" cy="98.2" r=".99"/>
<circle cx="254.2" cy="95.7" r="1"/>
<circle cx="254.2" cy="90.6" r="1"/>
<circle cx="254.2" cy="93.2" r="1"/>
<circle cx="254.2" cy="85.5" r="1"/>
<circle cx="89.2" cy="103.3" r=".99"/>
<circle cx="89.2" cy="105.9" r=".99"/>
<circle cx="106.4" cy="105.9" r=".99"/>
<circle cx="106.4" cy="103.3" r=".99"/>
<circle cx="106.4" cy="100.8" r=".99"/>
<circle cx="195.8" cy="126.2" r=".99"/>
<circle cx="286.7" cy="123.6" r="1"/>
<circle cx="286.7" cy="149" r="1"/>
</g>
<g fill="#000" stroke="#000" stroke-width=".61">
<path d="M20.3 22.1v252.6zM20.3 22.1h379.7zM90.2 85.5v22.9zM90.2 85.5h15.2zM196.8 98.2v30.5zM196.8 98.2h15.3zM255.2 83h30.5zM285.7 83v78.7zM90.2 108.4h15.2zM105.4 85.5v22.9zM196.8 128.7h15.3zM212.1 98.2v30.5z"/>
<path d="M80 179.5h1.3zM80 177h1.3zM83.8 179.5h1.3zM83.8 177h1.3zM255.2 83v78.7zM255.2 161.7h30.5zM80 182.1h1.3zM80 184.6h1.3zM83.8 182.1h1.3zM83.8 184.6h1.3zM283.2 244.3v30.4zM313.7 254.4v5.1z"/>
<path d="M313.7 249.3v5.1zM313.7 244.3v5zM313.7 244.3h86.3zM283.2 244.3h30.5zM400 254.4v5.1zM400 249.3v5.1zM400 244.3v5zM400 22.1v222.2zM20.3 274.7h262.9zM283.2 274.7h30.5zM313.7 274.7h86.3zM313.7 269.7v5z"/>
<path d="M313.7 264.6v5.1zM313.7 259.5v5.1zM400 268.4v6.3zM400 264.6v3.8zM400 259.5v5.1z"/>
</g>
<g fill="#000" stroke="#000" stroke-width=".42">
<path d="M348.6 136.3h3.8zM348.6 136.3v.7zM349.2 137.6v1.3zM351.7 137.6v1.3zM352.4 136.3v.7zM348.6 137h3.8zM348.6 149h3.8zM348.6 149v.7zM349.2 150.3v1.3zM351.7 150.3v1.3zM352.4 149v.7zM348.6 149.7h3.8z"/>
<path d="M78.7 174.4v12.7zM78.7 174.4h7.7zM348.6 161.7h3.8zM348.6 161.7v.7zM349.2 163v1.3zM351.7 163v1.3zM352.4 161.7v.7zM348.6 162.4h3.8zM78.7 187.1h7.7zM86.4 174.4v12.7zM341.6 217.6v10.1zM341.6 217.6h55.9z"/>
<path d="M240 232.8h10.2zM240 225.2v7.6zM250.2 225.2v7.6zM240 225.2h10.2zM341.6 227.7v12.7zM341.6 227.7h55.9zM397.5 217.6v10.1zM397.5 227.7v2.6zM341.6 240.4h55.9zM397.5 227.7v12.7z"/>
</g>
<path d="M16.5 18.2v260.3zM16.5 18.2h387.3zM16.5 278.5h387.3zM403.8 18.2v260.3z" fill="#000" stroke="#000" stroke-width=".32"/>
<g fill="#000" stroke="#000" stroke-width=".21">
<path d="M104.9 182.1h.8v5h-.8zM372.1 217.6h25.4v10.1h-25.4zM225.3 239.7h4v.5h-4zM263.4 239.7h4v.5h-4zM27.2 253.7h4v.5h-4zM27.2 254.7h4v.5h-4zM34.8 253.7h4.1v.5h-4.1zM34.8 254.7h4.1v.5h-4.1zM42.4 253.7h4.1v.5h-4.1zM42.4 254.7h4.1v.5h-4.1zM50 253.7h4.1v.5h-4.1zM50 254.7h4.1v.5h-4.1z"/>
<path d="M57.7 253.7h4v.5h-4zM57.7 254.7h4v.5h-4zM65.3 253.7h4v.5h-4zM65.3 254.7h4v.5h-4zM72.9 253.7h4.1v.5h-4.1zM72.9 254.7h4.1v.5h-4.1zM80.5 253.7h4.1v.5h-4.1zM80.5 254.7h4.1v.5h-4.1zM93.2 254.7h4.1v.5h-4.1zM93.2 253.7h4.1v.5h-4.1zM225.3 240.7h4v.5h-4zM263.4 240.7h4v.5h-4z"/>
</g>
<g fill="#000" stroke="#000" stroke-width=".76">
<path d="M41.9 39.8h17.8zM57.1 39.8h165.1zM59.7 39.8l5.1 5.1zM41.9 34.8h134.6zM176.5 34.8l2.5 2.5zM179 37.3v78.7zM222.2 39.8l5.1 5.1zM64.8 44.9v55.9zM227.3 44.9v78.7zM44.4 169.4h12.7zM57.1 169.4l2.6 2.5zM59.7 171.9v2.5z"/>
<path d="M59.7 174.4v5.1z"/>
</g>
<use href="#words"/>
</svg>
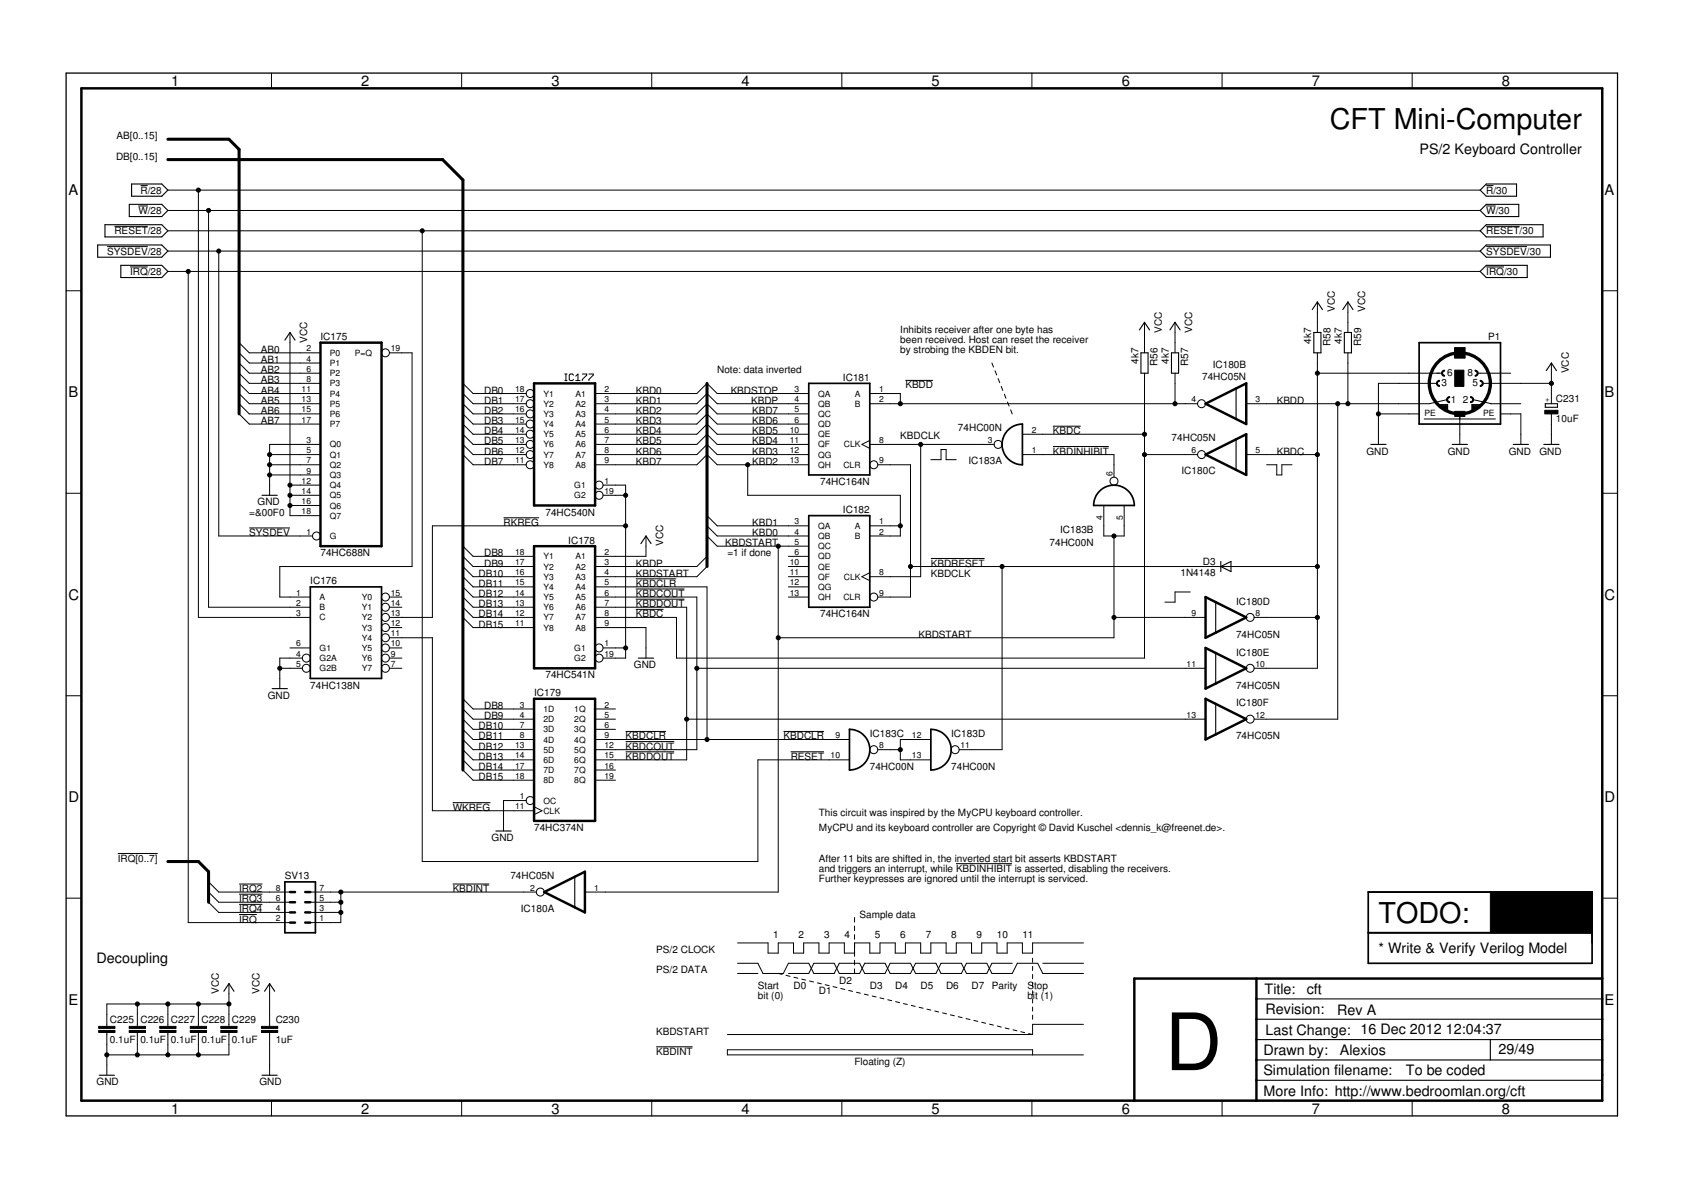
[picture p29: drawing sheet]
<svg xmlns="http://www.w3.org/2000/svg" width="420mm" height="297mm" viewBox="0 0 420 297" stroke-linecap="round" stroke-linejoin="round" font-family="sans-serif">
<defs><g id="words">
<text font-size="19.7" x="290.8" y="267.1">D</text>
<g font-size="7.2">
<text x="332" y="32.2">CFT Mini-Computer</text>
<text x="344.1" y="230.3">TODO:</text>
</g>
<g font-size="3.7">
<text x="42.7" y="21.5">1</text>
<text x="90.2" y="21.5">2</text>
<text x="137.7" y="21.5">3</text>
<text x="185.1" y="21.5">4</text>
<text x="232.6" y="21.5">5</text>
<text x="280" y="21.5">6</text>
<text x="327.5" y="21.5">7</text>
<text x="375" y="21.5">8</text>
<text x="17.1" y="48.6">A</text>
<text x="400.6" y="48.6">A</text>
<text x="17.1" y="99.2">B</text>
<text x="400.6" y="99.2">B</text>
<text x="17.1" y="149.7">C</text>
<text x="400.6" y="149.7">C</text>
<text x="17.1" y="200.2">D</text>
<text x="400.6" y="200.2">D</text>
<text x="17.1" y="250.8">E</text>
<text x="400.6" y="250.8">E</text>
<text x="42.7" y="277.9">1</text>
<text x="90.2" y="277.9">2</text>
<text x="137.7" y="277.9">3</text>
<text x="185.1" y="277.9">4</text>
<text x="232.6" y="277.9">5</text>
<text x="280" y="277.9">6</text>
<text x="327.5" y="277.9">7</text>
<text x="375" y="277.9">8</text>
</g>
<g font-size="3.6">
<text x="354.4" y="38.6">PS/2 Keyboard Controller</text>
<text x="344.1" y="237.9">* Write &amp; Verify Verilog Model</text>
<text x="24.1" y="240.5">Decoupling</text>
<text x="315.7" y="248.1">Title:</text>
<text x="326.2" y="248.2">cft</text>
<text x="315.9" y="253.2">Revision:</text>
<text x="333.8" y="253.3">Rev A</text>
<text x="315.4" y="263.3">Drawn by:</text>
<text x="315.9" y="258.2">Last Change: 16 Dec 2012</text>
<text x="334.5" y="263.3">Alexios</text>
<text x="361" y="258.1">12:04:37</text>
<text x="374.1" y="263.2">29/49</text>
<text x="315.4" y="268.4">Simulation filename:</text>
<text x="351" y="268.4">To be coded</text>
<text x="315.4" y="273.5">More Info: http://www.bedroomlan.org/cft</text>
</g>
<g font-size="2.5">
<text x="29.1" y="34.7">AB[0..15]</text>
<text x="29" y="39.8">DB[0..15]</text>
<text x="34.5" y="53.4">W/28</text>
<text x="35.1" y="48.3">R/28</text>
<text x="371" y="53.4">W/30</text>
<text x="371" y="48.3">R/30</text>
<text x="28.6" y="58.5">RESET/28</text>
<text x="371" y="58.5">RESET/30</text>
<text x="26.7" y="63.6">SYSDEV/28</text>
<text x="371" y="63.6">SYSDEV/30</text>
<text x="32.5" y="68.7">IRQ/28</text>
<text x="371" y="68.7">IRQ/30</text>
<text x="333.2" y="77.9" transform="rotate(-90 333.2 77.9)">VCC</text>
<text x="340.8" y="77.9" transform="rotate(-90 340.8 77.9)">VCC</text>
<text x="224.8" y="83">Inhibits receiver after one byte has</text>
<text x="290" y="83" transform="rotate(-90 290 83)">VCC</text>
<text x="297.7" y="83" transform="rotate(-90 297.7 83)">VCC</text>
<text x="65.1" y="88.1">AB0</text>
<text x="76.7" y="85.5" transform="rotate(-90 76.7 85.5)">VCC</text>
<text x="80" y="84.9">IC175</text>
<text x="224.8" y="85.5">been received. Host can reset the receiver</text>
<text x="224.8" y="88.1">by strobing the KBDEN bit.</text>
<text x="327.4" y="85.8" transform="rotate(-90 327.4 85.8)">4k7</text>
<text x="332.2" y="86.3" transform="rotate(-90 332.2 86.3)">R58</text>
<text x="335" y="85.8" transform="rotate(-90 335 85.8)">4k7</text>
<text x="339.8" y="86.3" transform="rotate(-90 339.8 86.3)">R59</text>
<text x="371.5" y="84.9">P1</text>
<text x="65.1" y="90.6">AB1</text>
<text x="65.1" y="93.2">AB2</text>
<text x="65.1" y="95.7">AB3</text>
<text x="179.1" y="93.2">Note: data inverted</text>
<text x="210.4" y="95.1">IC181</text>
<text x="284.2" y="90.9" transform="rotate(-90 284.2 90.9)">4k7</text>
<text x="289" y="91.4" transform="rotate(-90 289 91.4)">R56</text>
<text x="291.8" y="90.9" transform="rotate(-90 291.8 90.9)">4k7</text>
<text x="296.6" y="91.4" transform="rotate(-90 296.6 91.4)">R57</text>
<text x="300.1" y="94.9">74HC05N</text>
<text x="302.8" y="91.8">IC180B</text>
<text x="361.3" y="93.9">6</text>
<text x="366.4" y="93.9">8</text>
<text x="391.6" y="93.2" transform="rotate(-90 391.6 93.2)">VCC</text>
<text x="65.1" y="98.2">AB4</text>
<text x="65.1" y="100.8">AB5</text>
<text x="120.9" y="98.2">DB0</text>
<text x="120.9" y="100.8">DB1</text>
<text x="158.7" y="100.8">KBD1</text>
<text x="158.7" y="98.2">KBD0</text>
<text x="182.4" y="98.2">KBDSTOP</text>
<text x="187.5" y="100.8">KBDP</text>
<text x="226" y="97">KBDD</text>
<text x="318.7" y="100.8">KBDD</text>
<text x="359.9" y="96.5">3</text>
<text x="362.2" y="100.5">1</text>
<text x="365.2" y="100.5">2</text>
<text x="367.6" y="96.5">5</text>
<text x="388.4" y="100.3">C231</text>
<text x="65.1" y="103.3">AB6</text>
<text x="65.1" y="105.9">AB7</text>
<text x="120.9" y="103.3">DB2</text>
<text x="120.9" y="105.9">DB3</text>
<text x="158.7" y="105.9">KBD3</text>
<text x="158.7" y="103.3">KBD2</text>
<text x="187.8" y="103.3">KBD7</text>
<text x="187.8" y="105.9">KBD6</text>
<text x="239.2" y="107.6">74HC00N</text>
<text x="388.4" y="105.4">10uF</text>
<text x="120.9" y="108.4">DB4</text>
<text x="120.9" y="110.9">DB5</text>
<text x="120.9" y="113.5">DB6</text>
<text x="158.7" y="113.5">KBD6</text>
<text x="158.7" y="110.9">KBD5</text>
<text x="158.7" y="108.4">KBD4</text>
<text x="187.8" y="108.4">KBD5</text>
<text x="187.8" y="110.9">KBD4</text>
<text x="187.8" y="113.5">KBD3</text>
<text x="224.8" y="109.7">KBDCLK</text>
<text x="262.9" y="108.4">KBDC</text>
<text x="262.9" y="113.5">KBDINHIBIT</text>
<text x="292.5" y="110.2">74HC05N</text>
<text x="318.7" y="113.5">KBDC</text>
<text x="341.1" y="113.5">GND</text>
<text x="361.4" y="113.5">GND</text>
<text x="376.7" y="113.5">GND</text>
<text x="384.3" y="113.5">GND</text>
<text x="120.9" y="116">DB7</text>
<text x="158.7" y="116">KBD7</text>
<text x="187.8" y="116">KBD2</text>
<text x="241.8" y="115.9">IC183A</text>
<text x="295" y="118.4">IC180C</text>
<text x="204.7" y="121.1">74HC164N</text>
<text x="62.2" y="128.7">=&amp;00F0</text>
<text x="64.3" y="126.2">GND</text>
<text x="125.7" y="131.3">RKREG</text>
<text x="136.2" y="128.7">74HC540N</text>
<text x="187.8" y="131.3">KBD1</text>
<text x="210.4" y="128.1">IC182</text>
<text x="62.2" y="133.8">SYSDEV</text>
<text x="141.9" y="135.7">IC178</text>
<text x="165.6" y="136.3" transform="rotate(-90 165.6 136.3)">VCC</text>
<text x="181" y="136.3">KBDSTART</text>
<text x="187.8" y="133.8">KBD0</text>
<text x="262" y="136.3">74HC00N</text>
<text x="264.7" y="133.2">IC183B</text>
<text x="80" y="138.9">74HC688N</text>
<text x="119.5" y="144">DB10</text>
<text x="120.9" y="138.9">DB8</text>
<text x="120.9" y="141.4">DB9</text>
<text x="158.7" y="141.4">KBDP</text>
<text x="158.7" y="144">KBDSTART</text>
<text x="181.6" y="138.9">=1 if done</text>
<text x="232.4" y="141.4">KBDRESET</text>
<text x="232.4" y="144">KBDCLK</text>
<text x="294.7" y="143.7">1N4148</text>
<text x="300.3" y="140.9">D3</text>
<text x="77.5" y="145.9">IC176</text>
<text x="119.5" y="149">DB12</text>
<text x="119.5" y="146.5">DB11</text>
<text x="158.7" y="146.5">KBDCLR</text>
<text x="158.7" y="149">KBDCOUT</text>
<text x="119.5" y="151.6">DB13</text>
<text x="119.5" y="154.1">DB14</text>
<text x="158.7" y="154.1">KBDC</text>
<text x="158.7" y="151.6">KBDDOUT</text>
<text x="204.7" y="154.1">74HC164N</text>
<text x="308.6" y="150.9">IC180D</text>
<text x="119.5" y="156.6">DB15</text>
<text x="229.3" y="159.2">KBDSTART</text>
<text x="308.6" y="159.2">74HC05N</text>
<text x="158.3" y="166.8">GND</text>
<text x="308.6" y="163.6">IC180E</text>
<text x="77.5" y="171.9">74HC138N</text>
<text x="133.3" y="173.8">IC179</text>
<text x="136.2" y="169.3">74HC541N</text>
<text x="308.6" y="171.9">74HC05N</text>
<text x="66.8" y="174.4">GND</text>
<text x="120.9" y="177">DB8</text>
<text x="120.9" y="179.5">DB9</text>
<text x="308.6" y="176.3">IC180F</text>
<text x="119.5" y="182">DB10</text>
<text x="119.5" y="184.6">DB11</text>
<text x="156.2" y="184.6">KBDCLR</text>
<text x="195.6" y="184.6">KBDCLR</text>
<text x="217.1" y="183.9">IC183C</text>
<text x="237.5" y="183.9">IC183D</text>
<text x="308.6" y="184.6">74HC05N</text>
<text x="119.5" y="187.1">DB12</text>
<text x="119.5" y="189.7">DB13</text>
<text x="156.2" y="187.1">KBDCOUT</text>
<text x="156.2" y="189.7">KBDDOUT</text>
<text x="197.4" y="189.7">RESET</text>
<text x="119.5" y="192.2">DB14</text>
<text x="119.5" y="194.7">DB15</text>
<text x="217.1" y="192.2">74HC00N</text>
<text x="237.5" y="192.2">74HC00N</text>
<text x="113" y="202.4">WKREG</text>
<text x="204.4" y="203.6">This circuit was inspired by the MyCPU keyboard controller.</text>
<text x="122.7" y="210">GND</text>
<text x="133.3" y="207.4">74HC374N</text>
<text x="204.4" y="207.4">MyCPU and its keyboard controller are Copyright © David Kuschel &lt;dennis_k@freenet.de&gt;.</text>
<text x="29.4" y="215.1">IRQ[0..7]</text>
<text x="204.4" y="215.1">After 11 bits are shifted in, the inverted start bit asserts KBDSTART</text>
<text x="71.1" y="219.4">SV13</text>
<text x="127.4" y="219.4">74HC05N</text>
<text x="204.4" y="217.6">and triggers an interrupt, while KBDINHIBIT is asserted, disabling the receivers.</text>
<text x="204.4" y="220.1">Further keypresses are ignored until the interrupt is serviced.</text>
<text x="59.7" y="222.7">IRQ2</text>
<text x="59.7" y="225.2">IRQ3</text>
<text x="59.7" y="227.8">IRQ4</text>
<text x="113" y="222.7">KBDINT</text>
<text x="130" y="227.6">IC180A</text>
<text x="59.7" y="230.3">IRQ</text>
<text x="214.6" y="229">Sample data</text>
<text x="163.8" y="237.9">PS/2 CLOCK</text>
<text x="193" y="234.1">1</text>
<text x="199.4" y="234.1">2</text>
<text x="205.7" y="234.1">3</text>
<text x="210.8" y="234.1">4</text>
<text x="218.4" y="234.1">5</text>
<text x="224.8" y="234.1">6</text>
<text x="231.1" y="234.1">7</text>
<text x="237.5" y="234.1">8</text>
<text x="243.8" y="234.1">9</text>
<text x="248.9" y="234.1">10</text>
<text x="255.2" y="234.1">11</text>
<text x="163.8" y="243">PS/2 DATA</text>
<text x="209.5" y="245.5">D2</text>
<text x="54.6" y="248.1" transform="rotate(-90 54.6 248.1)">VCC</text>
<text x="64.8" y="248.1" transform="rotate(-90 64.8 248.1)">VCC</text>
<text x="189.2" y="246.8">Start</text>
<text x="189.2" y="249.3">bit (0)</text>
<text x="198.1" y="246.8">D0</text>
<text x="204.4" y="248.1">D1</text>
<text x="217.1" y="246.8">D3</text>
<text x="223.5" y="246.8">D4</text>
<text x="229.8" y="246.8">D5</text>
<text x="236.2" y="246.8">D6</text>
<text x="242.5" y="246.8">D7</text>
<text x="247.6" y="246.8">Parity</text>
<text x="256.5" y="246.8">Stop</text>
<text x="256.5" y="249.3">bit (1)</text>
<text x="27.4" y="255.3">C225</text>
<text x="35" y="255.3">C226</text>
<text x="42.7" y="255.3">C227</text>
<text x="50.3" y="255.3">C228</text>
<text x="57.9" y="255.3">C229</text>
<text x="68.8" y="255.3">C230</text>
<text x="27.4" y="260.4">0.1uF</text>
<text x="35" y="260.4">0.1uF</text>
<text x="42.7" y="260.4">0.1uF</text>
<text x="50.3" y="260.4">0.1uF</text>
<text x="57.9" y="260.4">0.1uF</text>
<text x="68.8" y="260.4">1uF</text>
<text x="163.8" y="258.2">KBDSTART</text>
<text x="163.8" y="263.3">KBDINT</text>
<text x="213.3" y="265.8">Floating (Z)</text>
<text x="24.1" y="270.9">GND</text>
<text x="64.8" y="270.9">GND</text>
</g>
<g font-size="2.1">
<text x="76.5" y="87.7">2</text>
<text x="82.3" y="88.8">P0</text>
<text x="88.6" y="88.8">P=Q</text>
<text x="97.6" y="87.7">19</text>
<text x="76.5" y="90.3">4</text>
<text x="76.5" y="92.8">6</text>
<text x="76.5" y="95.3">8</text>
<text x="82.3" y="91.4">P1</text>
<text x="82.3" y="93.9">P2</text>
<text x="75.3" y="97.9">11</text>
<text x="75.3" y="100.4">13</text>
<text x="82.3" y="96.5">P3</text>
<text x="82.3" y="99">P4</text>
<text x="82.3" y="101.5">P5</text>
<text x="128.6" y="100.4">17</text>
<text x="128.6" y="97.9">18</text>
<text x="135.7" y="101.5">Y2</text>
<text x="135.7" y="99">Y1</text>
<text x="143.6" y="99">A1</text>
<text x="143.6" y="101.5">A2</text>
<text x="150.9" y="97.9">2</text>
<text x="150.9" y="100.4">3</text>
<text x="198.4" y="97.9">3</text>
<text x="198.4" y="100.4">4</text>
<text x="204.2" y="99">QA</text>
<text x="204.2" y="101.5">QB</text>
<text x="213.4" y="99">A</text>
<text x="213.4" y="101.5">B</text>
<text x="219.5" y="97.9">1</text>
<text x="219.5" y="100.4">2</text>
<text x="297.4" y="100.4">4</text>
<text x="313.4" y="100.4">3</text>
<text x="75.3" y="103">15</text>
<text x="75.3" y="105.5">17</text>
<text x="82.3" y="104.1">P6</text>
<text x="82.3" y="106.6">P7</text>
<text x="128.6" y="105.5">15</text>
<text x="128.6" y="103">16</text>
<text x="135.7" y="106.6">Y4</text>
<text x="135.7" y="104.1">Y3</text>
<text x="143.6" y="104.1">A3</text>
<text x="143.6" y="106.6">A4</text>
<text x="150.9" y="103">4</text>
<text x="150.9" y="105.5">5</text>
<text x="198.4" y="103">5</text>
<text x="198.4" y="105.5">6</text>
<text x="204.2" y="104.1">QC</text>
<text x="204.2" y="106.6">QD</text>
<text x="355.6" y="104">PE</text>
<text x="370.2" y="104">PE</text>
<text x="76.5" y="110.6">3</text>
<text x="76.5" y="113.1">5</text>
<text x="82.3" y="111.7">Q0</text>
<text x="128.6" y="113.1">12</text>
<text x="128.6" y="110.6">13</text>
<text x="128.6" y="108">14</text>
<text x="135.7" y="111.7">Y6</text>
<text x="135.7" y="109.2">Y5</text>
<text x="143.6" y="109.2">A5</text>
<text x="143.6" y="111.7">A6</text>
<text x="150.9" y="108">6</text>
<text x="150.9" y="110.6">7</text>
<text x="150.9" y="113.1">8</text>
<text x="197.2" y="108">10</text>
<text x="197.2" y="110.6">11</text>
<text x="197.2" y="113.1">12</text>
<text x="204.2" y="109.2">QE</text>
<text x="204.2" y="111.7">QF</text>
<text x="210.7" y="111.7">CLK</text>
<text x="219.5" y="110.6">8</text>
<text x="246.6" y="110.6">3</text>
<text x="257.6" y="113.1">1</text>
<text x="257.6" y="108">2</text>
<text x="297.4" y="113.1">6</text>
<text x="313.4" y="113.1">5</text>
<text x="76.5" y="115.7">7</text>
<text x="76.5" y="118.2">9</text>
<text x="82.3" y="114.2">Q1</text>
<text x="82.3" y="116.8">Q2</text>
<text x="82.3" y="119.3">Q3</text>
<text x="128.6" y="115.7">11</text>
<text x="135.7" y="116.8">Y8</text>
<text x="135.7" y="114.2">Y7</text>
<text x="143.6" y="114.2">A7</text>
<text x="143.6" y="116.8">A8</text>
<text x="150.9" y="115.7">9</text>
<text x="197.2" y="115.7">13</text>
<text x="204.2" y="114.2">QG</text>
<text x="204.2" y="116.8">QH</text>
<text x="210.6" y="116.8">CLR</text>
<text x="219.5" y="115.7">9</text>
<text x="277.7" y="118.8" transform="rotate(-90 277.7 118.8)">6</text>
<text x="75.3" y="120.7">12</text>
<text x="75.3" y="123.3">14</text>
<text x="75.3" y="125.8">16</text>
<text x="82.3" y="121.9">Q4</text>
<text x="82.3" y="124.4">Q5</text>
<text x="143.4" y="121.9">G1</text>
<text x="143.4" y="124.4">G2</text>
<text x="150.9" y="120.7">1</text>
<text x="150.9" y="123.3">19</text>
<text x="75.3" y="128.4">18</text>
<text x="82.3" y="126.9">Q6</text>
<text x="82.3" y="129.5">Q7</text>
<text x="198.4" y="130.9">3</text>
<text x="219.5" y="130.9">1</text>
<text x="275.2" y="129.7" transform="rotate(-90 275.2 129.7)">4</text>
<text x="280.3" y="129.7" transform="rotate(-90 280.3 129.7)">5</text>
<text x="76.5" y="133.4">1</text>
<text x="82.3" y="134.6">G</text>
<text x="198.4" y="133.4">4</text>
<text x="198.4" y="136">5</text>
<text x="204.2" y="132">QA</text>
<text x="204.2" y="134.6">QB</text>
<text x="204.2" y="137.1">QC</text>
<text x="213.4" y="132">A</text>
<text x="213.4" y="134.6">B</text>
<text x="219.5" y="133.4">2</text>
<text x="128.6" y="143.6">16</text>
<text x="128.6" y="141.1">17</text>
<text x="128.6" y="138.5">18</text>
<text x="135.7" y="142.2">Y2</text>
<text x="135.7" y="139.6">Y1</text>
<text x="143.6" y="139.6">A1</text>
<text x="143.6" y="142.2">A2</text>
<text x="150.9" y="138.5">2</text>
<text x="150.9" y="141.1">3</text>
<text x="150.9" y="143.6">4</text>
<text x="197.2" y="141.1">10</text>
<text x="197.2" y="143.6">11</text>
<text x="198.4" y="138.5">6</text>
<text x="204.2" y="139.6">QD</text>
<text x="204.2" y="142.2">QE</text>
<text x="219.5" y="143.6">8</text>
<text x="73.9" y="148.7">1</text>
<text x="79.8" y="149.8">A</text>
<text x="90.3" y="149.8">Y0</text>
<text x="97.6" y="148.7">15</text>
<text x="128.6" y="148.7">14</text>
<text x="128.6" y="146.1">15</text>
<text x="135.7" y="149.8">Y5</text>
<text x="135.7" y="147.3">Y4</text>
<text x="135.7" y="144.7">Y3</text>
<text x="143.6" y="144.7">A3</text>
<text x="143.6" y="147.3">A4</text>
<text x="143.6" y="149.8">A5</text>
<text x="150.9" y="146.1">5</text>
<text x="150.9" y="148.7">6</text>
<text x="197.2" y="146.1">12</text>
<text x="197.2" y="148.7">13</text>
<text x="204.2" y="144.7">QF</text>
<text x="204.2" y="147.3">QG</text>
<text x="204.2" y="149.8">QH</text>
<text x="210.6" y="149.8">CLR</text>
<text x="210.7" y="144.7">CLK</text>
<text x="219.5" y="148.7">9</text>
<text x="73.9" y="151.2">2</text>
<text x="73.9" y="153.8">3</text>
<text x="79.8" y="152.3">B</text>
<text x="79.8" y="154.9">C</text>
<text x="90.3" y="154.9">Y2</text>
<text x="90.3" y="152.3">Y1</text>
<text x="97.6" y="153.8">13</text>
<text x="97.6" y="151.2">14</text>
<text x="128.6" y="153.8">12</text>
<text x="128.6" y="151.2">13</text>
<text x="135.7" y="154.9">Y7</text>
<text x="135.7" y="152.3">Y6</text>
<text x="143.6" y="152.3">A6</text>
<text x="143.6" y="154.9">A7</text>
<text x="150.9" y="151.2">7</text>
<text x="150.9" y="153.8">8</text>
<text x="297.4" y="153.8">9</text>
<text x="313.4" y="153.8">8</text>
<text x="73.9" y="161.4">6</text>
<text x="90.3" y="160">Y4</text>
<text x="90.3" y="157.4">Y3</text>
<text x="97.6" y="161.4">10</text>
<text x="97.6" y="158.8">11</text>
<text x="97.6" y="156.3">12</text>
<text x="128.6" y="156.3">11</text>
<text x="135.7" y="157.4">Y8</text>
<text x="143.6" y="157.4">A8</text>
<text x="150.9" y="161.4">1</text>
<text x="150.9" y="156.3">9</text>
<text x="73.9" y="163.9">4</text>
<text x="73.9" y="166.5">5</text>
<text x="79.8" y="165">G2A</text>
<text x="79.8" y="167.6">G2B</text>
<text x="79.8" y="162.5">G1</text>
<text x="90.3" y="167.6">Y7</text>
<text x="90.3" y="165">Y6</text>
<text x="90.3" y="162.5">Y5</text>
<text x="97.6" y="166.5">7</text>
<text x="97.6" y="163.9">9</text>
<text x="143.4" y="162.5">G1</text>
<text x="143.4" y="165">G2</text>
<text x="150.9" y="163.9">19</text>
<text x="296.2" y="166.5">11</text>
<text x="313.4" y="166.5">10</text>
<text x="129.8" y="176.6">3</text>
<text x="129.8" y="179.1">4</text>
<text x="135.7" y="177.7">1D</text>
<text x="143.4" y="177.7">1Q</text>
<text x="150.9" y="176.6">2</text>
<text x="150.9" y="179.1">5</text>
<text x="296.2" y="179.1">13</text>
<text x="313.4" y="179.1">12</text>
<text x="129.8" y="181.7">7</text>
<text x="129.8" y="184.2">8</text>
<text x="135.7" y="180.3">2D</text>
<text x="135.7" y="182.8">3D</text>
<text x="135.7" y="185.3">4D</text>
<text x="143.4" y="180.3">2Q</text>
<text x="143.4" y="182.8">3Q</text>
<text x="143.4" y="185.3">4Q</text>
<text x="150.9" y="181.7">6</text>
<text x="150.9" y="184.2">9</text>
<text x="208.5" y="184.2">9</text>
<text x="227.7" y="184.2">12</text>
<text x="128.6" y="186.8">13</text>
<text x="128.6" y="189.3">14</text>
<text x="128.6" y="191.8">17</text>
<text x="135.7" y="187.9">5D</text>
<text x="135.7" y="190.4">6D</text>
<text x="143.4" y="187.9">5Q</text>
<text x="143.4" y="190.4">6Q</text>
<text x="150.9" y="186.8">12</text>
<text x="150.9" y="189.3">15</text>
<text x="150.9" y="191.8">16</text>
<text x="207.4" y="189.3">10</text>
<text x="219.5" y="186.8">8</text>
<text x="227.7" y="189.3">13</text>
<text x="239.8" y="186.8">11</text>
<text x="128.6" y="194.4">18</text>
<text x="135.7" y="193">7D</text>
<text x="135.7" y="195.5">8D</text>
<text x="143.4" y="193">7Q</text>
<text x="143.4" y="195.5">8Q</text>
<text x="150.9" y="194.4">19</text>
<text x="128.6" y="202">11</text>
<text x="129.8" y="199.5">1</text>
<text x="135.7" y="200.6">OC</text>
<text x="135.7" y="203.1">CLK</text>
<text x="68.9" y="227.4">4</text>
<text x="68.9" y="224.9">6</text>
<text x="68.9" y="222.3">8</text>
<text x="79.8" y="227.4">3</text>
<text x="79.8" y="224.9">5</text>
<text x="79.8" y="222.3">7</text>
<text x="132.4" y="222.3">2</text>
<text x="148.4" y="222.3">1</text>
<text x="68.9" y="229.9">2</text>
<text x="79.8" y="229.9">1</text>
</g>
<text font-size="1.8" x="386.7" y="100.4" transform="rotate(-90 386.7 100.4)">+</text>
</g></defs>
<g fill="#000" stroke="#000" stroke-width=".25">
<path d="M67.8 18.2v3.9zM115.3 18.2v3.9zM162.7 18.2v3.9zM210.2 18.2v3.9zM257.6 18.2v3.9zM305.1 18.2v3.9zM352.5 18.2v3.9zM20.3 22.1v252.6zM20.3 22.1h379.7zM28.6 56.5h8.3zM34.5 51.4h2.4zM35.1 46.3h1.8z"/>
<path d="M41.9 52.5h10.2zM41.9 47.5h7.6zM49.5 47.5h320zM49.5 47.5v106.6zM52.1 52.5h317.4zM41.9 57.6h63.5zM105.4 57.6h264.1zM371 51.4h2.4zM371 46.3h1.8zM371 56.5h8.4zM16.5 72.6h3.8zM26.7 61.6h10.2z"/>
<path d="M32.5 66.6h4.4zM41.9 67.8h5.1zM41.9 62.7h12.7zM47 67.8h322.5zM54.6 62.7h314.9zM54.6 62.7v71.1zM328.9 75.4v2.5zM328.9 77.9v2.6zM336.5 75.4v2.5zM336.5 77.9v2.6zM371 66.6h4.5zM371 61.6h10.2z"/>
<path d="M400 72.6h3.8zM59.7 95.7l2.5 2.5zM59.7 98.2l2.5 2.6zM59.7 85.5l2.5 2.6zM59.7 88.1l2.5 2.5zM59.7 90.6l2.5 2.6zM59.7 93.2l2.5 2.5zM62.2 98.2h12.7zM72.4 83v2.5zM74.9 88.1h5.1zM74.9 90.6h5.1zM74.9 93.2h5.1z"/>
<path d="M74.9 95.7h5.1zM74.9 98.2h5.1zM62.2 88.1h12.7zM62.2 90.6h12.7zM62.2 93.2h12.7zM62.2 95.7h12.7zM97.2 88.1h3.1zM100.3 88.1h2.6zM102.9 88.1v53.3zM115.6 95.7l2.5 2.5zM128.2 98.2h3.2zM118.1 98.2h10.1z"/>
<path d="M141 95h.6zM141 93.4h.6zM141.3 93.4v1.6zM142.1 93.6v1.1zM142.1 94.7l.3 .3zM142.4 93.4l-.3 .2zM142.4 95h.5zM142.4 93.4h.5zM142.9 95l.3-.3zM142.9 93.4l.3 .2zM143.7 93.9l.6-.5zM143.7 95h1.1z"/>
<path d="M144.3 93.4v1.6zM145.4 93.4h1.1zM145.4 94.7v.3zM146.5 93.4v.2zM145.4 94.7l1.1-1.1zM147 93.4h1.1zM147 94.7v.3zM148.1 93.4v.2zM148.1 93.6l-1.1 1.1zM148.6 98.2h5zM153.6 98.2h20.4zM176.5 95.7l2.5 2.5z"/>
<path d="M176.5 98.2l2.5 2.6zM176.5 98.2l-2.5 2.6zM176.5 95.7l-2.5 2.5zM179 98.2h17.8zM196.8 98.2h5.1zM217.1 98.2h5.1zM222.2 98.2h2.6zM224.8 98.2v2.6zM226 95h6.9zM247.6 90.6l.4 1zM248.4 92.6l.4 1zM249.2 94.5l.4 1z"/>
<path d="M250 96.5l.4 1zM250.7 98.4l.4 1zM285.7 93.2v2.5zM285.7 85.5v2.6zM285.7 80.5v2.5zM285.7 83v2.5zM285.7 95.7v12.7zM293.3 93.2v2.5zM293.3 85.5v2.6zM293.3 80.5v2.5zM293.3 83v2.5zM293.3 95.7v5.1z"/>
<path d="M328.9 88.1v2.5zM328.9 80.5v2.5zM328.9 90.6v2.6zM328.9 93.2v20.3zM336.5 88.1v2.5zM336.5 80.5v2.5zM344.1 95.7v7.6zM349.2 95.7h7.6zM344.1 95.7h5.1zM351.7 93.2h7.7zM328.9 93.2h22.8zM356.8 95.7h1.9z"/>
<path d="M358.7 93.2h1.3zM356.8 100.8l4.5-1zM363.2 86.8v2.5zM363.2 89.3h2.5zM365.7 86.8v2.5zM363.2 86.8h2.5zM368.9 93.2h.6zM370.2 95.7h1.9zM369.5 93.2h7.6zM372.1 95.7h7.6zM379.7 95.7h7.6zM387.3 90.6v2.6z"/>
<path d="M387.3 98.2v2.6zM387.3 93.2v2.5zM387.3 95.7v2.5zM59.7 100.8l2.5 2.5zM59.7 103.3l2.5 2.6zM62.2 100.8h12.7zM62.2 103.3h12.7zM62.2 105.9h12.7zM67.3 110.9v2.6zM67.3 113.5v2.5zM67.3 116v2.6zM67.3 118.6v2.5z"/>
<path d="M74.9 110.9h5.1zM74.9 113.5h5.1zM74.9 116h5.1zM74.9 118.6h5.1zM74.9 100.8h5.1zM74.9 103.3h5.1zM74.9 105.9h5.1zM67.3 110.9h7.6zM67.3 113.5h7.6zM67.3 116h7.6zM67.3 118.6h7.6zM115.6 98.2l2.5 2.6z"/>
<path d="M115.6 100.8l2.5 2.5zM115.6 103.3l2.5 2.6zM115.6 105.9l2.5 2.5zM115.6 108.4l2.5 2.5zM115.6 110.9l2.5 2.6zM115.6 113.5l2.5 2.5zM128.2 116h3.2zM128.2 113.5h3.2zM128.2 110.9h3.2zM128.2 108.4h3.2zM128.2 105.9h3.2zM128.2 103.3h3.2z"/>
<path d="M128.2 100.8h3.2zM118.1 100.8h10.1zM118.1 103.3h10.1zM118.1 105.9h10.1zM118.1 108.4h10.1zM118.1 110.9h10.1zM118.1 113.5h10.1zM118.1 116h10.1zM148.6 100.8h5zM148.6 103.3h5zM148.6 105.9h5zM148.6 108.4h5z"/>
<path d="M148.6 110.9h5zM148.6 113.5h5zM148.6 116h5zM153.6 116h20.4zM153.6 113.5h20.4zM153.6 110.9h20.4zM153.6 108.4h20.4zM153.6 105.9h20.4zM153.6 103.3h20.4zM153.6 100.8h20.4zM176.5 100.8l2.5 2.5zM176.5 113.5l-2.5 2.5z"/>
<path d="M176.5 103.3l2.5 2.6zM176.5 110.9l-2.5 2.6zM176.5 105.9l2.5 2.5zM174 110.9l2.5-2.5zM176.5 108.4l2.5 2.5zM176.5 105.9l-2.5 2.5zM176.5 110.9l2.5 2.6zM176.5 103.3l-2.5 2.6zM176.5 113.5l2.5 2.5zM174 103.3l2.5-2.5zM179 100.8h17.8zM179 103.3h17.8z"/>
<path d="M179 105.9h17.8zM179 108.4h17.8zM179 110.9h17.8zM179 113.5h17.8zM179 116h7.7zM186.7 116h10.1zM196.8 100.8h5.1zM196.8 103.3h5.1zM196.8 105.9h5.1zM196.8 108.4h5.1zM196.8 110.9h5.1zM196.8 113.5h5.1z"/>
<path d="M196.8 116h5.1zM215.2 110.9l1.9 1zM215.2 110.9l1.9-1zM217.1 100.8h5.1zM217.1 110.9h5.1zM219.1 116h3.1zM222.2 100.8h2.6zM222.2 116h5.1zM224.8 100.8h68.5zM227.3 116v25.4zM222.2 110.9h7.6zM229.8 110.9v33.1z"/>
<path d="M229.8 110.9h15.3zM232.4 114.7h2.5zM234.9 112.2v2.5zM234.9 112.2h1.3zM236.2 112.2v2.5zM236.2 114.7h2.5zM245.1 110.9h3.1zM251.5 100.3l.4 1.1zM252.3 102.3l.4 1zM255.2 113.5h5.1zM255.2 108.4h5.1zM260.3 108.4h25.4z"/>
<path d="M260.3 113.5h17.8zM262.9 106.4h6.9zM262.9 111.5h13.9zM278.1 116v3.1zM278.1 113.5v2.5zM285.7 108.4v5.1zM293.3 100.8h2.6zM295.9 100.8h3.1zM295.9 113.5h3.1zM285.7 113.5h10.2zM316.2 116h2.5zM311.1 100.8h5.1z"/>
<path d="M311.1 113.5h5.1zM318.7 116v2.6zM318.7 118.6h1.3zM320 116v2.6zM320 116h2.6zM316.2 113.5h12.7zM316.2 100.8h17.8zM334 100.8h2.5zM336.5 90.6v10.2zM344.1 108.4v2.5zM344.1 103.3v5.1zM349.2 100.8h7.6z"/>
<path d="M336.5 100.8h12.7zM351.7 103.3h2.6zM344.1 103.3h7.6zM364.4 103.3v1.3zM355.6 104.6h8.8zM364.4 103.3v5.1zM364.4 108.4v2.5zM367.7 99.8l4.6 1zM364.4 104.6h8.9zM374.6 103.3h2.5zM377.1 103.3h2.6zM372.1 100.8h7.6z"/>
<path d="M379.7 108.4v2.5zM379.7 103.3v5.1zM387.3 108.4v2.5zM387.3 103.3v2.6zM387.3 105.9v2.5zM16.5 123.1h3.8zM62.2 131.8h10.2zM67.3 121.1v2.5zM72.4 85.5v35.6zM72.4 121.1v2.5zM72.4 123.6v2.6zM72.4 126.2v2.5z"/>
<path d="M74.9 133.8h3.1zM74.9 121.1h5.1zM74.9 123.6h5.1zM74.9 126.2h5.1zM74.9 128.7h5.1zM72.4 121.1h2.5zM72.4 123.6h2.5zM72.4 126.2h2.5zM72.4 128.7h2.5zM54.6 133.8h20.3zM115.6 136.3l2.5 2.6zM115.6 138.9l2.5 2.5z"/>
<path d="M118.1 138.9h10.1zM125.7 129.2h8.9zM128.2 138.9h5.1zM150.6 121.1h3zM150.6 123.6h3zM148.6 138.9h5zM153.6 138.9h7.7zM153.6 121.1h2.6zM153.6 123.6h2.6zM156.2 121.1v2.5zM156.2 123.6v7.7zM156.2 131.3v30.4z"/>
<path d="M107.9 131.3h48.3zM161.3 133.8v2.5zM161.3 136.3v2.6zM176.5 138.9l-2.5 2.5zM176.5 128.7l2.5 2.6zM176.5 131.3l2.5 2.5zM176.5 133.8l2.5 2.5zM179 131.3h17.8zM179 133.8h17.8zM179 136.3h15.3zM186.7 116v7.6zM194.3 136.3h2.5z"/>
<path d="M196.8 131.3h5.1zM196.8 133.8h5.1zM196.8 136.3h5.1zM196.8 138.9h5.1zM217.1 131.3h5.1zM217.1 133.8h5.1zM222.2 131.3h2.6zM222.2 133.8h2.6zM224.8 123.6v7.7zM186.7 123.6h38.1zM224.8 131.3v2.5zM232.4 139.4h13.4z"/>
<path d="M275.6 126.2v5.1zM275.6 131.3v2.5zM275.6 133.8h2.5zM278.1 133.8h2.5zM280.6 126.2v5.1zM280.6 131.3v2.5zM400 123.1h3.8zM49.5 154.1h22.9zM52.1 52.5v99.1zM69.8 141.4v7.6zM69.8 149h2.6zM72.4 149h5.1z"/>
<path d="M72.4 151.6h5.1zM72.4 154.1h5.1zM52.1 151.6h20.3zM97.2 159.2h3.1zM97.2 156.7h3.1zM97.2 154.1h3.1zM97.2 151.6h3.1zM97.2 149h3.1zM100.3 154.1h7.6zM100.3 159.2h7.6zM69.8 141.4h33.1zM107.9 131.3v22.8z"/>
<path d="M107.9 159.2v43.2zM115.6 141.4l2.5 2.6zM115.6 146.5l2.5 2.5zM115.6 149l2.5 2.6zM115.6 151.6l2.5 2.5zM115.6 154.1l2.5 2.6zM115.6 144l2.5 2.5zM118.1 141.4h10.1zM118.1 144h10.1zM118.1 149h10.1zM118.1 151.6h10.1zM118.1 154.1h10.1z"/>
<path d="M118.1 156.7h10.1zM118.1 146.5h10.1zM128.2 156.7h5.1zM128.2 154.1h5.1zM128.2 151.6h5.1zM128.2 149h5.1zM128.2 146.5h5.1zM128.2 144h5.1zM128.2 141.4h5.1zM148.6 141.4h5zM148.6 144h5zM148.6 146.5h5z"/>
<path d="M148.6 149h5zM148.6 151.6h5zM148.6 154.1h5zM148.6 156.7h5zM153.6 156.7h7.7zM153.6 144h20.4zM153.6 154.1h15.3zM153.6 146.5h22.9zM153.6 149h20.4zM153.6 151.6h17.8zM158.7 152.1h6.9zM158.7 144.5h10.1z"/>
<path d="M158.7 147h12.2zM158.7 149.6h12.2zM161.3 156.7v5zM168.9 154.1v10.2zM171.4 151.6v27.9zM153.6 141.4h20.4zM174 144l2.5-2.6zM174 149v17.8zM176.5 146.5v38.1zM194.3 136.3v22.9zM194.3 159.2h83.8zM196.8 141.4h5.1z"/>
<path d="M196.8 144h5.1zM196.8 146.5h5.1zM196.8 149h5.1zM215.2 144l1.9 .9zM215.2 144l1.9-1zM217.1 144h5.1zM219.1 149h3.1zM222.2 149h5.1zM227.3 141.4v7.6zM222.2 144h7.6zM227.3 141.4h22.9zM278.1 154.1h17.8z"/>
<path d="M278.1 154.1v5.1zM278.1 133.8v20.3zM290.8 150.3h2.5zM293.3 147.8v2.5zM293.3 147.8h3.9zM295.9 154.1h5.1zM303.5 141.4h2.5zM250.2 141.4h53.3zM306 141.4h2.6zM308.6 141.4h20.3zM313.1 154.1h3.1zM316.2 154.1h12.7z"/>
<path d="M328.9 141.4v12.7zM328.9 113.5v27.9zM16.5 173.7h3.8zM69.8 169.4v2.5zM69.8 164.3v2.5zM69.8 166.8v2.6zM72.4 164.3h3.1zM72.4 166.8h3.1zM72.4 161.7h5.1zM69.8 164.3h2.6zM69.8 166.8h2.6zM97.2 166.8h3.1z"/>
<path d="M97.2 164.3h3.1zM97.2 161.7h3.1zM115.6 174.4l2.5 2.6zM115.6 177l2.5 2.5zM115.6 179.5l2.5 2.6zM118.1 177h10.1zM118.1 179.5h10.1zM128.2 177h5.1zM128.2 179.5h5.1zM148.6 177h5zM148.6 179.5h5zM150.6 161.7h3z"/>
<path d="M150.6 164.3h3zM153.6 161.7h2.6zM153.6 164.3h2.6zM156.2 161.7v2.6zM161.3 161.7v2.6zM168.9 164.3h116.8zM171.4 179.5v10.2zM174 166.8v20.3zM174 166.8h121.9zM285.7 113.5v50.8zM295.9 166.8h5.1zM295.9 179.5h5.1z"/>
<path d="M171.4 179.5h124.5zM313.1 166.8h3.1zM313.1 179.5h3.1zM316.2 179.5h17.8zM316.2 166.8h12.7zM328.9 154.1v12.7zM334 100.8v78.7zM400 173.7h3.8zM115.6 184.6l2.5 2.5zM115.6 187.1l2.5 2.6zM115.6 189.7l2.5 2.5zM115.6 192.2l2.5 2.6z"/>
<path d="M115.6 182.1l2.5 2.5zM118.1 182.1h10.1zM118.1 187.1h10.1zM118.1 189.7h10.1zM118.1 192.2h10.1zM118.1 194.8h10.1zM118.1 184.6h10.1zM125.7 199.8v5.1zM128.2 199.8h3.2zM128.2 182.1h5.1zM128.2 184.6h5.1zM128.2 187.1h5.1z"/>
<path d="M128.2 189.7h5.1zM128.2 192.2h5.1zM128.2 194.8h5.1zM125.7 199.8h2.5zM148.6 182.1h5zM148.6 184.6h5zM148.6 187.1h5zM148.6 189.7h5zM148.6 192.2h5zM148.6 194.8h5zM153.6 184.6h22.9zM153.6 187.1h20.4z"/>
<path d="M153.6 189.7h17.8zM156.2 182.6h10.1zM156.2 185.1h12.1zM156.2 187.7h12.1zM189.2 189.7h17.8zM195.6 182.6h10.1zM197.4 187.7h8.3zM207 184.6h5.1zM207 189.7h5.1zM176.5 184.6h30.5zM219.1 187.1h3.1zM222.2 187.1h2.6z"/>
<path d="M224.8 184.6v2.5zM224.8 184.6h2.5zM224.8 187.1v2.6zM224.8 189.7h2.5zM227.3 184.6h5.1zM227.3 189.7h5.1zM239.5 187.1h3zM242.5 187.1h7.7zM250.2 141.4v45.7zM29.4 213h10zM105.4 215h83.8zM105.4 57.6v157.4z"/>
<path d="M113 200.4h9.4zM125.7 204.9v2.5zM128.2 202.4h5.1zM107.9 202.4h20.3zM133.3 201.4l2 1zM133.3 203.3l2-.9zM189.2 189.7v25.3zM238.7 215.6h13.9zM16.5 224.2h3.8zM47 67.8v162.5zM52.1 220.1l2.5 2.6zM52.1 222.7l2.5 2.5z"/>
<path d="M52.1 225.2l2.5 2.5zM59.7 228.3h4.4zM59.7 220.7h5.8zM59.7 223.2h5.8zM59.7 225.7h5.8zM67.3 230.3h5.1zM67.3 227.7h5.1zM67.3 225.2h5.1zM67.3 222.7h5.1zM47 230.3h20.3zM54.6 222.7h12.7zM54.6 225.2h12.7z"/>
<path d="M54.6 227.7h12.7zM77.5 230.3h5zM77.5 227.7h5zM77.5 225.2h5zM77.5 222.7h5zM82.5 225.2h2.6zM82.5 230.3h2.6zM82.5 222.7h2.6zM85.1 222.7v2.5zM85.1 225.2v2.5zM82.5 227.7h2.6zM85.1 227.7v2.6z"/>
<path d="M113 220.7h9.1zM130.8 222.7h3.1zM85.1 222.7h45.7zM146 222.7h5.1zM151.1 222.7h43.2zM184.1 235.4h7.6zM191.7 235.4v2.5zM191.7 237.9h2.6zM194.3 235.4v2.5zM194.3 235.4h3.8zM194.3 159.2v63.5zM198.1 235.4v2.5z"/>
<path d="M198.1 237.9h2.5zM200.6 235.4v2.5zM200.6 235.4h3.8zM204.4 235.4v2.5zM204.4 237.9h2.6zM207 235.4v2.5zM207 235.4h3.8zM210.8 235.4v2.5zM210.8 237.9h2.5zM213.3 235.4v2.5zM213.3 235.4h3.8zM213.3 229v1.2z"/>
<path d="M213.3 231.2v1.1zM213.3 233.3v1.1zM213.3 235.4v1.2zM213.3 237.6v1.1zM213.3 239.7v1.2zM217.1 235.4v2.5zM217.1 237.9h2.6zM219.7 235.4v2.5zM219.7 235.4h3.8zM223.5 235.4v2.5zM223.5 237.9h2.5zM226 235.4v2.5z"/>
<path d="M226 235.4h3.8zM229.8 235.4v2.5zM229.8 237.9h2.6zM232.4 235.4v2.5zM232.4 235.4h3.8zM236.2 235.4v2.5zM236.2 237.9h2.5zM238.7 235.4v2.5zM238.7 235.4h3.8zM242.5 235.4v2.5zM242.5 237.9h2.6zM245.1 235.4v2.5z"/>
<path d="M245.1 235.4h3.8zM248.9 235.4v2.5zM248.9 237.9h2.5zM251.4 235.4v2.5zM251.4 235.4h3.8zM255.2 235.4v2.5zM255.2 237.9h2.6zM257.8 235.4v2.5zM257.8 235.4h12.7zM257.8 239.2v1zM400 224.2h3.8zM26.7 253.1v2.6z"/>
<path d="M26.7 257.7v.5zM26.7 255.7v.5zM26.7 250.6v2.5zM34.3 253.1v2.6zM34.3 257.7v.5zM34.3 255.7v.5zM34.3 250.6v2.5zM26.7 250.6h7.6zM41.9 253.1v2.6zM41.9 257.7v.5zM41.9 255.7v.5zM34.3 250.6h7.6z"/>
<path d="M41.9 250.6v2.5zM49.5 253.1v2.6zM49.5 257.7v.5zM49.5 255.7v.5zM41.9 250.6h7.6zM49.5 250.6v2.5zM57.1 245.5v2.6zM57.1 253.1v2.6zM57.1 257.7v.5zM57.1 255.7v.5zM49.5 250.6h7.6zM57.1 248.1v2.5z"/>
<path d="M57.1 250.6v2.5zM67.3 245.5v2.6zM67.3 253.1v2.6zM67.3 255.7v.5zM67.3 257.7v.5zM67.3 248.1v5zM181.6 258.2h76.2zM184.1 240.4h5.1zM184.1 243h5.1zM189.2 240.4l1.3 2.6zM190.5 243h3.8zM194.3 243h1.3z"/>
<path d="M194.3 243l1 .2zM196.8 240.4l-1.2 2.6zM196.2 243.5l1 .2zM196.8 243h5.1zM196.8 240.4h5.1zM198.2 243.9l1 .3zM200.1 244.4l1 .2zM203.2 240.4l-1.3 2.6zM201.9 240.4l1.3 2.6zM202.1 244.9l1 .2zM203.2 243h5.1zM203.2 240.4h5.1z"/>
<path d="M204.1 245.3l.9 .3zM206 245.8l1 .2zM208 246.3l1 .2zM209.5 240.4l-1.2 2.6zM208.3 240.4l1.2 2.6zM209.5 243h3.8zM209.5 240.4h5.1zM209.9 246.7l1 .3zM211.9 247.2l.9 .3zM213.3 243h1.3zM213.3 241.8v1.2zM213.8 247.7l1 .2z"/>
<path d="M215.9 240.4l-1.3 2.6zM214.6 240.4l1.3 2.6zM215.8 248.2l1 .2zM215.9 243h5.1zM215.9 240.4h5.1zM217.7 248.6l1 .3zM219.7 249.1l1 .2zM222.2 240.4l-1.2 2.6zM221 240.4l1.2 2.6zM221.6 249.6l1 .2zM222.2 243h5.1zM222.2 240.4h5.1z"/>
<path d="M223.6 250l1 .3zM225.5 250.5l1 .2zM228.6 240.4l-1.3 2.6zM227.3 240.4l1.3 2.6zM227.5 251l1 .2zM228.6 243h5.1zM228.6 240.4h5.1zM229.4 251.4l1 .3zM231.4 251.9l1 .2zM233.4 252.4l.9 .2zM234.9 240.4l-1.2 2.6zM233.7 240.4l1.2 2.6z"/>
<path d="M234.9 243h5.1zM234.9 240.4h5.1zM235.3 252.8l1 .3zM237.3 253.3l.9 .3zM239.2 253.8l1 .2zM241.3 240.4l-1.3 2.6zM240 240.4l1.3 2.6zM241.2 254.2l.9 .3zM241.3 243h5.1zM241.3 240.4h5.1zM243.1 254.7l1 .2zM245.1 255.2l1 .2z"/>
<path d="M247.6 240.4l-1.2 2.6zM246.4 240.4l1.2 2.6zM247 255.6l1 .3zM247.6 243h5.1zM247.6 240.4h5.1zM249 256.1l1 .3zM250.9 256.6l1 .2zM254 240.4l-1.3 2.6zM252.9 257.1l1 .2zM254 240.4h5.1zM254.8 257.5l1 .3zM256.8 258l1 .2z"/>
<path d="M257.8 255.7v2.5zM257.8 255.7h12.7zM257.8 241.2v1zM257.8 243.2v1.1zM257.8 245.3v1zM257.8 247.3v1zM257.8 249.3v1.1zM257.8 251.4v1zM257.8 253.4v1zM259.1 240.4l1.2 2.6zM260.3 240.4h10.2zM260.3 243h10.2z"/>
<path d="M20.3 274.7h379.7zM26.7 265.8v2.6zM26.7 258.2v2.6zM26.7 260.8v2.5zM26.7 263.3h7.6zM26.7 263.3v2.5zM34.3 258.2v2.6zM34.3 260.8v2.5zM41.9 258.2v2.6zM34.3 263.3h7.6zM41.9 260.8v2.5zM49.5 258.2v2.6z"/>
<path d="M41.9 263.3h7.6zM49.5 260.8v2.5zM57.1 258.2v2.6zM49.5 263.3h7.6zM57.1 260.8v2.5zM67.3 265.8v2.6zM67.3 258.2v2.6zM67.3 260.8v5zM67.8 274.7v3.8zM115.3 274.7v3.8zM162.7 274.7v3.8zM163.8 261.3h9.1z"/>
<path d="M181.6 262h76.2zM181.6 263.3h76.2zM181.6 262v1.3zM210.2 274.7v3.8zM257.6 274.7v3.8zM257.8 262v1.3zM257.8 263.3h12.7zM305.1 274.7v3.8zM352.5 274.7v3.8zM400 264.5v.1zM400 268.4v6.2zM400 274.6h.1z"/>
<path d="M400 22.1v252.6z"/>
<path d="M358.8 95.1l.6-.2v.3a.51 .51 0 0 0-.5 .5 .51 .51 0 0 0 .5 .5v.3a.76 .76 0 0 1-.8-.5 .76 .76 0 0 1 .2-.9z" fill-rule="evenodd"/>
<path d="M360.1 92.6l.5-.2v.2a.51 .51 0 0 0-.5 .6 .51 .51 0 0 0 .5 .5v.2a.75 .75 0 0 1-.7-.4 .75 .75 0 0 1 .2-.9z" fill-rule="evenodd"/>
<path d="M361.4 99.2l.5-.2v.2a.51 .51 0 0 0-.5 .6 .51 .51 0 0 0 .5 .5v.2a.76 .76 0 0 1-.7-.5 .76 .76 0 0 1 .2-.8z" fill-rule="evenodd"/>
<path d="M368.3 92.4a.76 .76 0 0 1 .7 .8 .76 .76 0 0 1-.7 .7v-.2a.51 .51 0 0 0 .5-.5 .51 .51 0 0 0-.5-.6z" fill-rule="evenodd"/>
<path d="M369.5 94.9a.76 .76 0 0 1 .8 .8 .76 .76 0 0 1-.8 .8v-.3a.51 .51 0 0 0 .5-.5 .51 .51 0 0 0-.5-.5z" fill-rule="evenodd"/>
<path d="M367.1 99a.76 .76 0 0 1 .8 .8 .76 .76 0 0 1-.8 .7v-.2a.51 .51 0 0 0 .5-.5 .51 .51 0 0 0-.5-.6z" fill-rule="evenodd"/>
<circle cx="49.5" cy="47.5" r=".51"/>
<circle cx="52.1" cy="52.5" r=".51"/>
<circle cx="105.4" cy="57.6" r=".51"/>
<circle cx="47" cy="67.8" r=".51"/>
<circle cx="54.6" cy="62.7" r=".51"/>
<circle cx="328.9" cy="93.2" r=".51"/>
<circle cx="387.3" cy="95.7" r=".51"/>
<circle cx="67.3" cy="118.6" r=".51"/>
<circle cx="67.3" cy="113.5" r=".51"/>
<circle cx="67.3" cy="116" r=".51"/>
<circle cx="186.7" cy="116" r=".51"/>
<circle cx="224.8" cy="100.8" r=".51"/>
<circle cx="229.8" cy="110.9" r=".51"/>
<circle cx="285.7" cy="108.4" r=".51"/>
<circle cx="285.7" cy="113.5" r=".51"/>
<circle cx="293.3" cy="100.8" r=".51"/>
<circle cx="328.9" cy="113.5" r=".51"/>
<circle cx="334" cy="100.8" r=".51"/>
<circle cx="336.5" cy="100.8" r=".51"/>
<circle cx="344.1" cy="103.3" r=".51"/>
<circle cx="72.4" cy="123.6" r=".51"/>
<circle cx="72.4" cy="121.1" r=".51"/>
<circle cx="72.4" cy="126.2" r=".51"/>
<circle cx="156.2" cy="123.6" r=".51"/>
<circle cx="156.2" cy="131.3" r=".51"/>
<circle cx="194.3" cy="136.3" r=".51"/>
<circle cx="224.8" cy="131.3" r=".51"/>
<circle cx="278.1" cy="133.8" r=".51"/>
<circle cx="194.3" cy="159.2" r=".51"/>
<circle cx="227.3" cy="141.4" r=".51"/>
<circle cx="250.2" cy="141.4" r=".51"/>
<circle cx="278.1" cy="154.1" r=".51"/>
<circle cx="328.9" cy="154.1" r=".51"/>
<circle cx="328.9" cy="141.4" r=".51"/>
<circle cx="69.8" cy="166.8" r=".51"/>
<circle cx="156.2" cy="161.7" r=".51"/>
<circle cx="171.4" cy="179.5" r=".51"/>
<circle cx="174" cy="166.8" r=".51"/>
<circle cx="176.5" cy="184.6" r=".51"/>
<circle cx="224.8" cy="187.1" r=".51"/>
<circle cx="85.1" cy="227.7" r=".51"/>
<circle cx="85.1" cy="225.2" r=".51"/>
<circle cx="85.1" cy="222.7" r=".51"/>
<circle cx="34.3" cy="250.6" r=".51"/>
<circle cx="41.9" cy="250.6" r=".51"/>
<circle cx="49.5" cy="250.6" r=".51"/>
<circle cx="57.1" cy="250.6" r=".51"/>
<circle cx="26.7" cy="263.3" r=".51"/>
<circle cx="34.3" cy="263.3" r=".51"/>
<circle cx="41.9" cy="263.3" r=".51"/>
<circle cx="49.5" cy="263.3" r=".51"/>
</g>
<g fill="#000" stroke="#000" stroke-width=".28">
<path d="M26.2 56.1v3zM32.3 51v3.1zM32.9 45.9v3.1zM32.3 51h8.1zM32.3 54.1h8.1zM32.9 45.9h7.5zM32.9 49h7.5zM26.2 56.1h14.2zM26.2 59.1h14.2zM40.4 51l1.5 1.5zM41.9 52.5l-1.5 1.6zM40.4 45.9l1.5 1.6z"/>
<path d="M41.9 47.5l-1.5 1.5zM40.4 56.1l1.5 1.5zM41.9 57.6l-1.5 1.5zM369.5 52.5l1.5-1.5zM369.5 52.5l1.5 1.6zM369.5 47.5l1.5-1.6zM369.5 47.5l1.5 1.5zM371 56.1l-1.5 1.5zM369.5 57.6l1.5 1.5zM371 51h8.2zM371 54.1h8.2zM371 45.9h7.6z"/>
<path d="M371 49h7.6zM371 56.1h14.2zM371 59.1h14.2zM378.6 45.9v3.1zM379.2 51v3.1zM385.2 56.1v3zM24.4 61.1v3.1zM30.2 66.2v3.1zM30.2 69.3h10.2zM30.2 66.2h10.2zM24.4 64.2h16zM24.4 61.1h16z"/>
<path d="M41.9 67.8l-1.5 1.5zM40.4 66.2l1.5 1.6zM40.4 64.2l1.5-1.5zM40.4 61.1l1.5 1.6zM328.9 75.4l-1.3 1.9zM328.9 75.4l1.3 1.9zM336.5 75.4l-1.3 1.9zM336.5 75.4l1.3 1.9zM371 66.2l-1.5 1.6zM369.5 67.8l1.5 1.5zM371 61.1l-1.5 1.6zM369.5 62.7l1.5 1.5z"/>
<path d="M371 66.2h10.3zM371 69.3h10.3zM371 61.1h16.1zM371 64.2h16.1zM381.3 66.2v3.1zM387.1 61.1v3.1zM72.4 83l-1.3 1.9zM72.4 83l1.3 1.9zM285.7 80.5l-1.2 1.9zM284.8 88.1v5.1zM284.8 93.2h1.8zM284.8 88.1h1.8z"/>
<path d="M285.7 80.5l1.3 1.9zM286.6 88.1v5.1zM293.3 80.5l-1.2 1.9zM292.5 88.1v5.1zM292.5 93.2h1.7zM292.5 88.1h1.7zM293.3 80.5l1.3 1.9zM294.2 88.1v5.1zM328 83v5.1zM328 88.1h1.8zM328 83h1.8zM329.8 83v5.1z"/>
<path d="M335.6 83v5.1zM335.6 88.1h1.8zM335.6 83h1.8zM337.4 83v5.1zM387.3 90.6l-1.3 1.9zM387.3 90.6l1.3 1.9zM308.6 97v7.6zM308.6 109.7v7.6zM342.2 110.9h3.8zM358.9 101l2.5 1.6zM358.9 101h2.5zM359.2 101.3h2.2z"/>
<path d="M359.6 101.5h1.8zM360 101.7h1.4zM360.4 101.9h1zM360.7 102.1h.7zM361.1 102.4h.3zM361.4 101v1.6zM362.5 110.9h3.8zM367.5 101v1.6zM367.5 101h2.5zM367.5 102.4h.3zM367.5 102.1h.7zM367.5 101.9h1z"/>
<path d="M367.5 101.7h1.4zM367.5 101.5h1.8zM367.5 101.3h2.1zM367.5 102.6l2.5-1.6zM377.8 110.9h3.8zM385.8 101.7h3zM385.8 100.8v.9zM385.8 100.8h3zM388.8 100.8v.9zM385.4 110.9h3.8zM65.4 123.6h3.8zM161.3 133.8l-1.3 1.9z"/>
<path d="M161.3 133.8l1.2 1.9zM303.5 150.3v7.6zM304.8 141.4l2.5-1.3zM304.8 140.1v1.3zM304.8 141.4v1.3zM304.8 141.4l2.5 1.3zM307.3 140.1v2.6zM67.9 171.9h3.9zM159.4 164.3h3.8zM303.5 163v7.6zM303.5 175.7v7.6zM123.8 207.4h3.8z"/>
<path d="M143.5 218.9v7.6zM57.1 245.5l-1.2 1.9zM57.1 245.5l1.3 1.9zM67.3 245.5l-1.3 1.9zM67.3 245.5l1.3 1.9zM313.7 249.3h86.3zM313.7 254.4h86.3zM313.7 259.5h58.4zM372.1 259.5h27.9zM372.1 259.5v5.1zM24.8 268.4h3.8zM65.4 268.4h3.8z"/>
<path d="M313.7 264.6h58.4zM313.7 269.7h86.3zM372.1 264.6h27.9zM400 268.4v1.3z"/>
</g>
<g fill="#000" stroke="#000" stroke-width=".42">
<path d="M201.9 95.7h15.2zM217.1 95.7v22.9zM354.3 85.5v20.4zM354.3 85.5h20.3zM201.9 95.7v22.9zM201.9 118.6h15.2zM255.2 105.9v10.1zM354.3 105.9h20.3zM374.6 85.5v20.4zM201.9 128.7h15.2zM217.1 128.7v22.9zM273 126.2h10.2z"/>
<path d="M77.5 146.5v22.9zM77.5 146.5h17.7zM201.9 128.7v22.9zM201.9 151.6h15.2zM77.5 169.4h17.7zM95.2 146.5v22.9zM212.1 182.1v10.1zM232.4 182.1v10.1zM71.1 220.1v12.7zM71.1 220.1h7.6zM71.1 232.8h7.6zM78.7 220.1v12.7z"/>
<path d="M341.6 222.7v10.1zM341.6 232.8v7.6zM341.6 232.8h55.9zM397.5 222.7v10.1zM341.6 222.7h55.9zM397.5 232.8v2.6zM341.6 240.4h55.9zM397.5 232.8v7.6z"/>
</g>
<g fill="#000" stroke="#000" stroke-width=".61">
<path d="M20.3 22.1v252.6zM20.3 22.1h379.7zM80 85.5v50.8zM80 85.5h15.2zM133.3 95.7h15.3zM148.6 95.7v30.5zM308.6 97l2.5-1.3zM311.1 95.7v10.2zM301 100.8l7.6-3.8zM301 113.5l7.6-3.8zM301 100.8l7.6 3.8zM301 113.5l7.6 3.8z"/>
<path d="M308.6 109.7l2.5-1.3zM308.6 104.6l2.5 1.3zM308.6 117.3l2.5 1.3zM311.1 108.4v10.2zM80 136.3h15.2zM95.2 85.5v50.8zM133.3 95.7v30.5zM133.3 136.3h15.3zM133.3 126.2h15.3zM148.6 136.3v30.5zM301 149l2.5 1.3zM301 149v10.2z"/>
<path d="M303.5 150.3l7.6 3.8zM301 159.2l2.5-1.3zM303.5 157.9l7.6-3.8zM133.3 174.4v30.5zM133.3 136.3v30.5zM133.3 174.4h15.3zM133.3 166.8h15.3zM301 161.7l2.5 1.3zM301 161.7v10.2zM301 174.4l2.5 1.3zM303.5 163l7.6 3.8zM301 171.9l2.5-1.3z"/>
<path d="M303.5 175.7l7.6 3.8zM303.5 170.6l7.6-3.8zM303.5 183.3l7.6-3.8zM301 174.4v10.2zM301 184.6l2.5-1.3zM133.3 204.9h15.3zM143.5 218.9l2.5-1.3zM146 217.6v10.1zM148.6 174.4v30.5zM72.4 225.2h1.3zM72.4 227.7h1.3zM72.4 230.3h1.3z"/>
<path d="M72.4 222.7h1.3zM76.2 225.2h1.3zM76.2 227.7h1.3zM76.2 230.3h1.3zM76.2 222.7h1.3zM135.9 222.7l7.6-3.8zM135.9 222.7l7.6 3.8zM143.5 226.5l2.5 1.2zM283.2 244.3v30.4zM313.7 254.4v5.1zM313.7 249.3v5.1zM313.7 244.3v5z"/>
<path d="M313.7 244.3h86.3zM283.2 244.3h30.5zM400 254.4v5.1zM400 249.3v5.1zM400 244.3v5zM400 22.1v222.2zM20.3 274.7h262.9zM283.2 274.7h30.5zM313.7 274.7h86.3zM313.7 269.7v5zM313.7 264.6v5.1zM313.7 259.5v5.1z"/>
<path d="M400 268.4v6.3zM400 264.6v3.8zM400 259.5v5.1z"/>
</g>
<path d="M16.5 18.2v260.3zM16.5 18.2h387.3zM16.5 278.5h387.3zM403.8 18.2v260.3z" fill="#000" stroke="#000" stroke-width=".32"/>
<g fill="#000" stroke="#000" stroke-width=".25">
<path d="M363.2 86.8h2.5v2.5h-2.5zM363.2 92.4h2.3v4.1h-2.3zM363.2 102.7h2.5v1.2h-2.5zM385.7 102.4h3.3v.9h-3.3zM372.1 222.7h25.4v10.1h-25.4zM24.6 256.2h4.1v.5h-4.1zM24.6 257.2h4.1v.5h-4.1zM32.3 256.2h4v.5h-4zM32.3 257.2h4v.5h-4zM39.9 256.2h4v.5h-4zM39.9 257.2h4v.5h-4zM47.5 256.2h4.1v.5h-4.1z"/>
<path d="M47.5 257.2h4.1v.5h-4.1zM55.1 256.2h4.1v.5h-4.1zM55.1 257.2h4.1v.5h-4.1zM65.3 257.2h4v.5h-4zM65.3 256.2h4v.5h-4z"/>
</g>
<circle cx="364.4" cy="95.7" r="7.6" fill="none" stroke="#000" stroke-width=".83"/>
<g fill="none" stroke="#000" stroke-width=".25">
<circle cx="96.2" cy="88.1" r=".99"/>
<circle cx="132.4" cy="98.2" r=".99"/>
<circle cx="132.4" cy="105.9" r=".99"/>
<circle cx="132.4" cy="108.4" r=".99"/>
<circle cx="132.4" cy="113.5" r=".99"/>
<circle cx="132.4" cy="110.9" r=".99"/>
<circle cx="132.4" cy="103.3" r=".99"/>
<circle cx="132.4" cy="100.8" r=".99"/>
<circle cx="132.4" cy="116" r=".99"/>
<circle cx="218.1" cy="116" r="1"/>
<circle cx="249.2" cy="110.9" r="1"/>
<circle cx="300" cy="100.8" r="1"/>
<circle cx="300" cy="113.5" r="1"/>
<circle cx="79" cy="133.8" r=".99"/>
<circle cx="149.6" cy="123.6" r=".99"/>
<circle cx="149.6" cy="121.1" r=".99"/>
<circle cx="278.1" cy="120.1" r="1"/>
<circle cx="96.2" cy="159.2" r=".99"/>
<circle cx="96.2" cy="149" r=".99"/>
<circle cx="96.2" cy="154.1" r=".99"/>
<circle cx="96.2" cy="151.6" r=".99"/>
<circle cx="96.2" cy="156.7" r=".99"/>
<circle cx="218.1" cy="149" r="1"/>
<circle cx="312.1" cy="154.1" r="1"/>
<circle cx="76.5" cy="164.3" r=".99"/>
<circle cx="76.5" cy="166.8" r=".99"/>
<circle cx="96.2" cy="166.8" r=".99"/>
<circle cx="96.2" cy="164.3" r=".99"/>
<circle cx="96.2" cy="161.7" r=".99"/>
<circle cx="149.6" cy="161.7" r=".99"/>
<circle cx="149.6" cy="164.3" r=".99"/>
<circle cx="312.1" cy="166.8" r="1"/>
<circle cx="312.1" cy="179.5" r="1"/>
<circle cx="132.4" cy="199.8" r=".99"/>
<circle cx="218.1" cy="187.1" r="1"/>
<circle cx="238.5" cy="187.1" r="1"/>
<circle cx="134.9" cy="222.7" r=".99"/>
</g>
<path d="M255.2 105.9a5.1 5.1 0 0 0-5 5 5.1 5.1 0 0 0 5 5.1M273 126.2a5.1 5.1 0 0 1 5.1-5.1 5.1 5.1 0 0 1 5.1 5.1M212.1 182.1a5.1 5.1 0 0 1 5.1 5 5.1 5.1 0 0 1-5.1 5.1M232.4 182.1a5.1 5.1 0 0 1 5.1 5 5.1 5.1 0 0 1-5.1 5.1" fill="none" stroke="#000" stroke-width=".42"/>
<path d="M41.9 34.8h15.2zM57.1 34.8l2.6 2.5zM59.7 37.3v66zM41.9 39.8h68.6zM110.5 39.8l5.1 5.1zM176.5 95.7v45.7zM115.6 44.9v147.3zM41.9 215h7.6zM49.5 215l2.6 2.6zM52.1 217.6v2.5zM52.1 220.1v5.1z" fill="#000" stroke="#000" stroke-width=".76"/>
<use href="#words"/>
</svg>
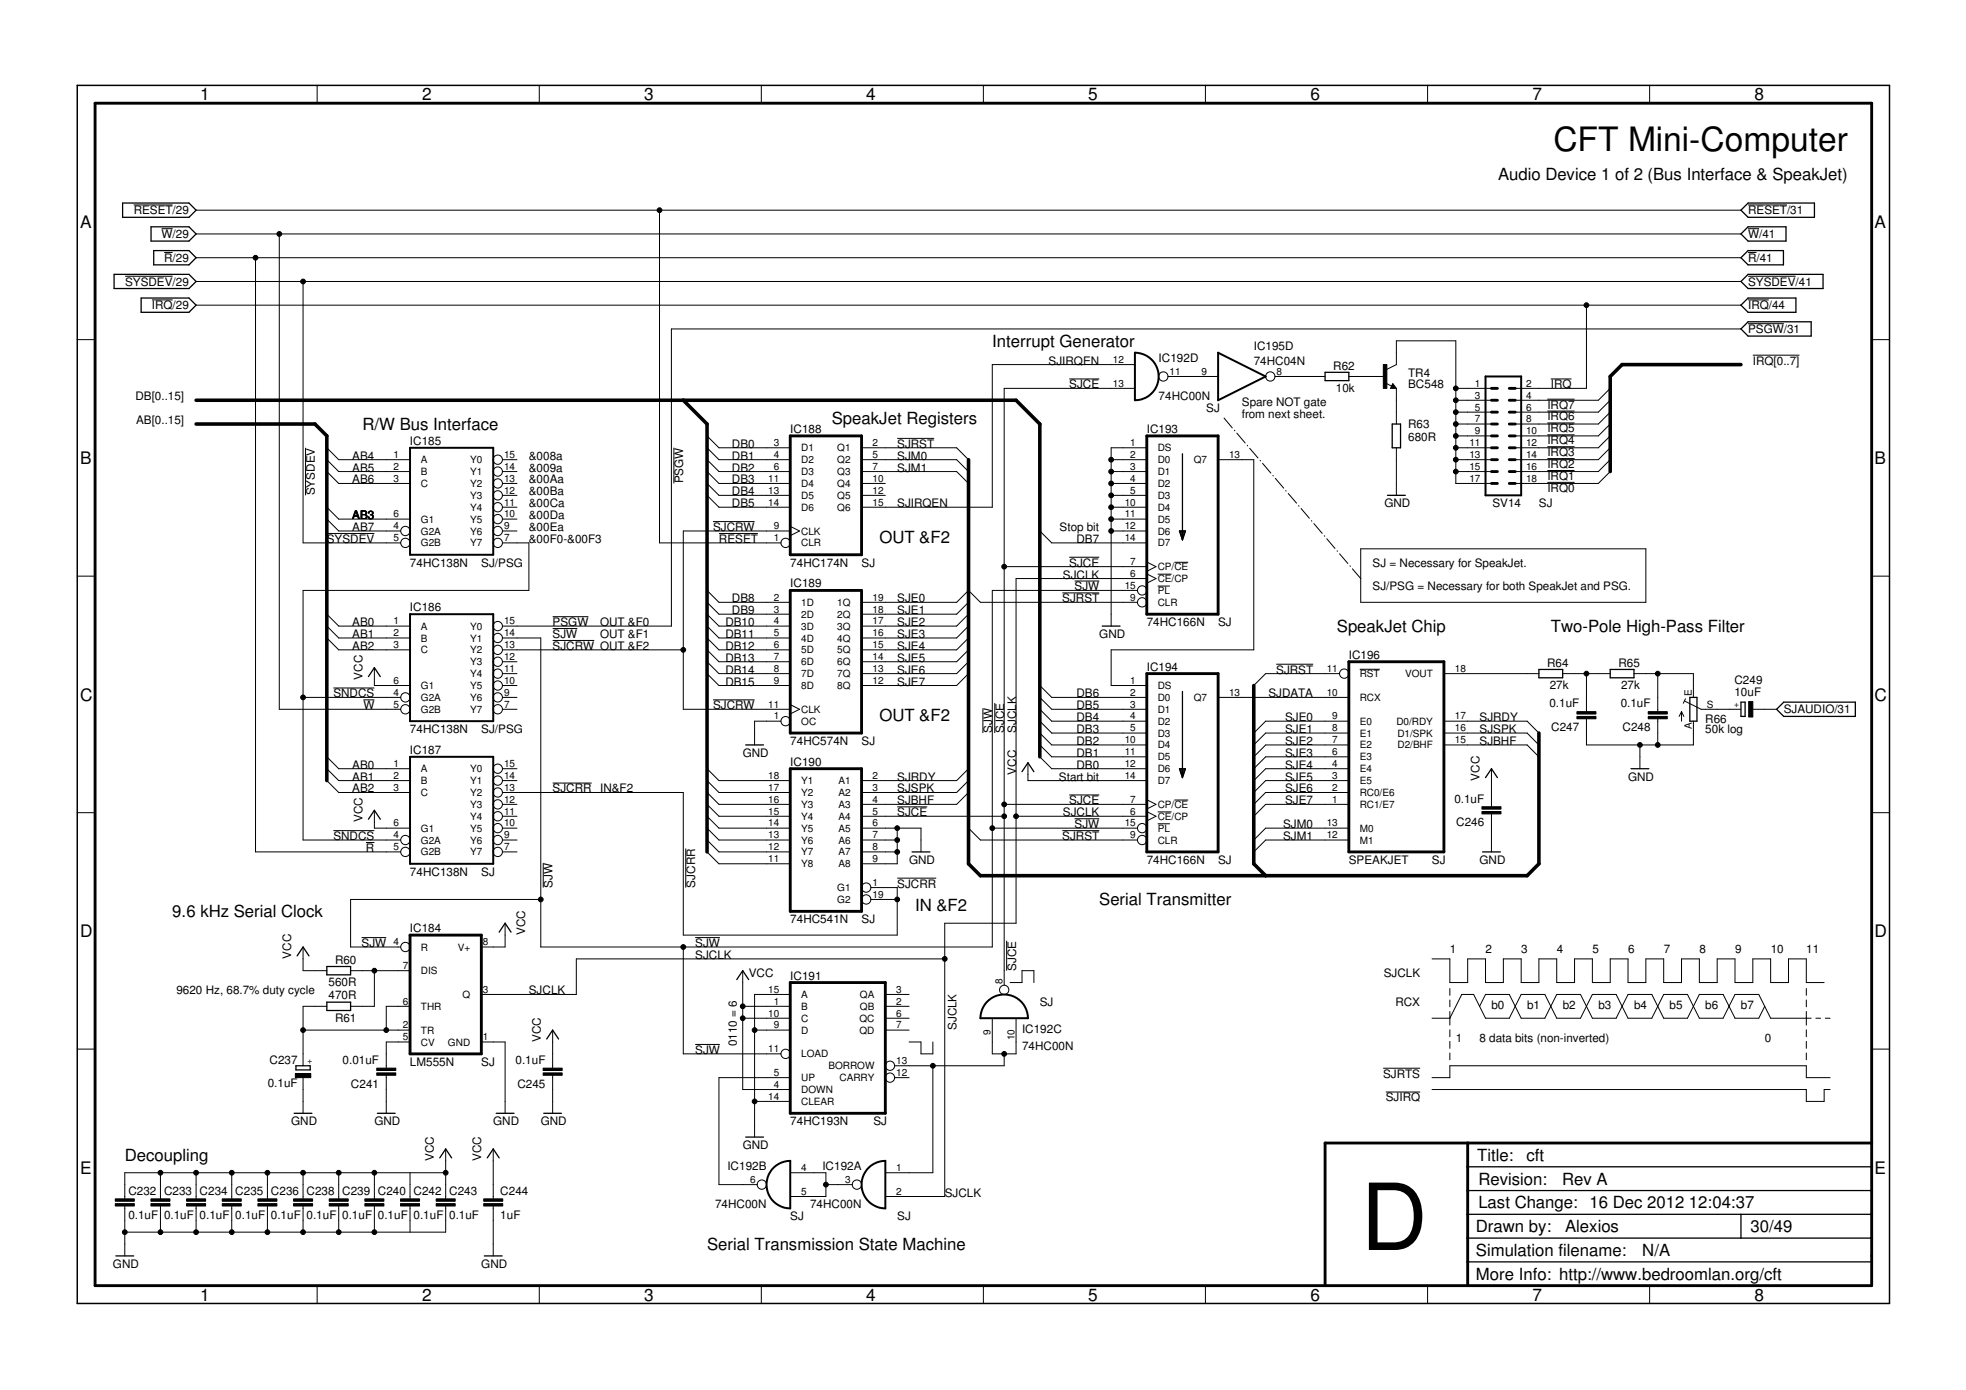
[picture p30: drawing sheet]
<svg xmlns="http://www.w3.org/2000/svg" width="420mm" height="297mm" viewBox="0 0 420 297" stroke-linecap="round" stroke-linejoin="round" font-family="sans-serif">
<defs><g id="words">
<text font-size="19.7" x="290.8" y="267.1">D</text>
<text font-size="7.2" x="332" y="32.2">CFT Mini-Computer</text>
<g font-size="3.7">
<text x="42.7" y="21.5">1</text>
<text x="90.2" y="21.5">2</text>
<text x="137.7" y="21.5">3</text>
<text x="185.1" y="21.5">4</text>
<text x="232.6" y="21.5">5</text>
<text x="280" y="21.5">6</text>
<text x="327.5" y="21.5">7</text>
<text x="375" y="21.5">8</text>
<text x="17.1" y="48.6">A</text>
<text x="400.6" y="48.6">A</text>
<text x="17.1" y="99.2">B</text>
<text x="400.6" y="99.2">B</text>
<text x="17.1" y="149.7">C</text>
<text x="400.6" y="149.7">C</text>
<text x="17.1" y="200.2">D</text>
<text x="400.6" y="200.2">D</text>
<text x="17.1" y="250.8">E</text>
<text x="400.6" y="250.8">E</text>
<text x="42.7" y="277.9">1</text>
<text x="90.2" y="277.9">2</text>
<text x="137.7" y="277.9">3</text>
<text x="185.1" y="277.9">4</text>
<text x="232.6" y="277.9">5</text>
<text x="280" y="277.9">6</text>
<text x="327.5" y="277.9">7</text>
<text x="375" y="277.9">8</text>
</g>
<g font-size="3.6">
<text x="320.1" y="38.6">Audio Device 1 of 2 (Bus Interface &amp; SpeakJet)</text>
<text x="212.1" y="74.1">Interrupt Generator</text>
<text x="77.5" y="91.9">R/W Bus Interface</text>
<text x="177.8" y="90.6">SpeakJet Registers</text>
<text x="187.9" y="116">OUT &amp;F2</text>
<text x="285.7" y="135.1">SpeakJet Chip</text>
<text x="331.4" y="135.1">Two-Pole High-Pass Filter</text>
<text x="187.9" y="154.1">OUT &amp;F2</text>
<text x="36.8" y="196">9.6 kHz Serial Clock</text>
<text x="195.6" y="194.7">IN &amp;F2</text>
<text x="234.9" y="193.5">Serial Transmitter</text>
<text x="26.7" y="248.1">Decoupling</text>
<text x="315.7" y="248.1">Title:</text>
<text x="326.2" y="248.2">cft</text>
<text x="315.9" y="253.2">Revision:</text>
<text x="333.8" y="253.3">Rev A</text>
<text x="315.4" y="263.3">Drawn by:</text>
<text x="315.9" y="258.2">Last Change: 16 Dec 2012</text>
<text x="334.5" y="263.3">Alexios</text>
<text x="361" y="258.1">12:04:37</text>
<text x="374.1" y="263.2">30/49</text>
<text x="151.1" y="267.1">Serial Transmission State Machine</text>
<text x="315.4" y="268.4">Simulation filename:</text>
<text x="351" y="268.4">N/A</text>
<text x="315.4" y="273.5">More Info: http://www.bedroomlan.org/cft</text>
</g>
<g font-size="2.5">
<text x="28.6" y="45.8">RESET/29</text>
<text x="373.6" y="45.8">RESET/31</text>
<text x="34.5" y="50.9">W/29</text>
<text x="373.6" y="50.9">W/41</text>
<text x="35.1" y="56">R/29</text>
<text x="373.6" y="56">R/41</text>
<text x="26.7" y="61">SYSDEV/29</text>
<text x="373.6" y="61">SYSDEV/41</text>
<text x="32.5" y="66.1">IRQ/29</text>
<text x="373.6" y="71.2">PSGW/31</text>
<text x="373.6" y="66.1">IRQ/44</text>
<text x="224.1" y="77.9">SJIRQEN</text>
<text x="247.6" y="77.3">IC192D</text>
<text x="267.9" y="77.9">74HC04N</text>
<text x="267.9" y="74.7">IC195D</text>
<text x="374.6" y="77.9">IRQ[0..7]</text>
<text x="228.5" y="83">SJCE</text>
<text x="284.9" y="79">R62</text>
<text x="285.5" y="83.8">10k</text>
<text x="301" y="83">BC548</text>
<text x="301" y="80.5">TR4</text>
<text x="331.4" y="83">IRQ</text>
<text x="29" y="85.5">DB[0..15]</text>
<text x="247.6" y="85.5">74HC00N</text>
<text x="257.8" y="88.1">SJ</text>
<text x="265.4" y="86.8">Spare NOT gate</text>
<text x="265.4" y="89.3">from next sheet.</text>
<text x="330.7" y="89.9">IRQ6</text>
<text x="330.7" y="87.3">IRQ7</text>
<text x="29.1" y="90.6">AB[0..15]</text>
<text x="87.6" y="95.1">IC185</text>
<text x="156.4" y="95.7">DB0</text>
<text x="168.9" y="92.5">IC188</text>
<text x="191.7" y="95.7">SJRST</text>
<text x="245.1" y="92.5">IC193</text>
<text x="301" y="94.2">680R</text>
<text x="301" y="91.4">R63</text>
<text x="330.7" y="94.9">IRQ4</text>
<text x="330.7" y="92.4">IRQ5</text>
<text x="75.3" y="98.2">AB4</text>
<text x="75.3" y="100.8">AB5</text>
<text x="113" y="98.2">&amp;008a</text>
<text x="113" y="100.8">&amp;009a</text>
<text x="156.4" y="98.2">DB1</text>
<text x="156.4" y="100.8">DB2</text>
<text x="191.7" y="98.2">SJM0</text>
<text x="191.7" y="100.8">SJM1</text>
<text x="330.7" y="100">IRQ2</text>
<text x="330.7" y="97.5">IRQ3</text>
<text x="67.3" y="105.9" transform="rotate(-90 67.3 105.9)">SYSDEV</text>
<text x="75.3" y="103.3">AB6</text>
<text x="113" y="103.3">&amp;00Aa</text>
<text x="113" y="105.9">&amp;00Ba</text>
<text x="146" y="103.3" transform="rotate(-90 146 103.3)">PSGW</text>
<text x="156.4" y="103.3">DB3</text>
<text x="156.4" y="105.9">DB4</text>
<text x="330.7" y="105.1">IRQ0</text>
<text x="330.7" y="102.6">IRQ1</text>
<text x="75.3" y="113.5">AB7</text>
<text x="75.3" y="110.9">AB3</text>
<text x="113" y="108.4">&amp;00Ca</text>
<text x="113" y="110.9">&amp;00Da</text>
<text x="113" y="113.5">&amp;00Ea</text>
<text x="152.4" y="113.5">SJCRW</text>
<text x="156.4" y="108.4">DB5</text>
<text x="191.7" y="108.4">SJIRQEN</text>
<text x="226.5" y="113.5">Stop bit</text>
<text x="295.9" y="108.4">GND</text>
<text x="318.9" y="108.4">SV14</text>
<text x="328.9" y="108.4">SJ</text>
<text x="69.8" y="116">SYSDEV</text>
<text x="113" y="116">&amp;00F0-&amp;00F3</text>
<text x="153.7" y="116">RESET</text>
<text x="230.1" y="116">DB7</text>
<text x="87.6" y="121.1">74HC138N</text>
<text x="102.9" y="121.1">SJ/PSG</text>
<text x="168.9" y="121.1">74HC174N</text>
<text x="168.9" y="125.5">IC189</text>
<text x="184.1" y="121.1">SJ</text>
<text x="227.2" y="123.6">SJCLK</text>
<text x="228.5" y="121.1">SJCE</text>
<text x="293.3" y="121.1">SJ = Necessary for SpeakJet.</text>
<text x="87.6" y="130.6">IC186</text>
<text x="156.4" y="128.7">DB8</text>
<text x="156.4" y="131.3">DB9</text>
<text x="191.7" y="128.7">SJE0</text>
<text x="191.7" y="131.3">SJE1</text>
<text x="227" y="128.7">SJRST</text>
<text x="229.7" y="126.2">SJW</text>
<text x="293.3" y="126.2">SJ/PSG = Necessary for both SpeakJet and PSG.</text>
<text x="75.3" y="133.8">AB0</text>
<text x="75.3" y="136.3">AB1</text>
<text x="118.1" y="133.8">PSGW</text>
<text x="118.1" y="136.3">SJW</text>
<text x="128.3" y="133.8">OUT &amp;F0</text>
<text x="128.3" y="136.3">OUT &amp;F1</text>
<text x="155" y="133.8">DB10</text>
<text x="155" y="136.3">DB11</text>
<text x="191.7" y="133.8">SJE2</text>
<text x="191.7" y="136.3">SJE3</text>
<text x="234.9" y="136.3">GND</text>
<text x="245.1" y="133.8">74HC166N</text>
<text x="260.3" y="133.8">SJ</text>
<text x="75.3" y="138.9">AB2</text>
<text x="118.1" y="138.9">SJCRW OUT &amp;F2</text>
<text x="155" y="138.9">DB12</text>
<text x="155" y="141.4">DB13</text>
<text x="155" y="144">DB14</text>
<text x="191.7" y="138.9">SJE4</text>
<text x="191.7" y="141.4">SJE5</text>
<text x="191.7" y="144">SJE6</text>
<text x="245.1" y="143.3">IC194</text>
<text x="272.7" y="144">SJRST</text>
<text x="288.3" y="140.8">IC196</text>
<text x="330.6" y="142.5">R64</text>
<text x="345.9" y="142.5">R65</text>
<text x="71.2" y="149">SNDCS</text>
<text x="77.5" y="145.2" transform="rotate(-90 77.5 145.2)">VCC</text>
<text x="155" y="146.5">DB15</text>
<text x="191.7" y="146.5">SJE7</text>
<text x="230.1" y="149">DB6</text>
<text x="271.1" y="149">SJDATA</text>
<text x="331.2" y="147.3">27k</text>
<text x="346.4" y="147.3">27k</text>
<text x="370.7" y="148.8">10uF</text>
<text x="370.7" y="146.2">C249</text>
<text x="77.7" y="151.6">W</text>
<text x="152.4" y="151.6">SJCRW</text>
<text x="230.1" y="154.1">DB4</text>
<text x="230.1" y="151.6">DB5</text>
<text x="274.6" y="154.1">SJE0</text>
<text x="316.2" y="154.1">SJRDY</text>
<text x="331.1" y="151.2">0.1uF</text>
<text x="346.4" y="151.2">0.1uF</text>
<text x="364.4" y="154.5">R66</text>
<text x="381.2" y="152.5">SJAUDIO/31</text>
<text x="87.6" y="156.6">74HC138N</text>
<text x="87.6" y="161.1">IC187</text>
<text x="102.9" y="156.6">SJ/PSG</text>
<text x="158.7" y="161.7">GND</text>
<text x="168.9" y="159.2">74HC574N</text>
<text x="184.1" y="159.2">SJ</text>
<text x="212.1" y="156.6" transform="rotate(-90 212.1 156.6)">SJW</text>
<text x="214.6" y="156.6" transform="rotate(-90 214.6 156.6)">SJCE</text>
<text x="217.1" y="156.6" transform="rotate(-90 217.1 156.6)">SJCLK</text>
<text x="230.1" y="161.7">DB1</text>
<text x="230.1" y="159.2">DB2</text>
<text x="230.1" y="156.6">DB3</text>
<text x="274.6" y="156.6">SJE1</text>
<text x="274.6" y="159.2">SJE2</text>
<text x="274.6" y="161.7">SJE3</text>
<text x="316.2" y="156.6">SJSPK</text>
<text x="316.2" y="159.2">SJBHF</text>
<text x="331.5" y="156.3">C247</text>
<text x="346.8" y="156.3">C248</text>
<text x="364.4" y="156.6">50k log</text>
<text x="75.3" y="164.3">AB0</text>
<text x="75.3" y="166.8">AB1</text>
<text x="168.9" y="163.6">IC190</text>
<text x="191.7" y="166.8">SJRDY</text>
<text x="217.1" y="165.5" transform="rotate(-90 217.1 165.5)">VCC</text>
<text x="226.3" y="166.8">Start bit</text>
<text x="230.1" y="164.3">DB0</text>
<text x="274.6" y="164.3">SJE4</text>
<text x="274.6" y="166.8">SJE5</text>
<text x="316.2" y="166.8" transform="rotate(-90 316.2 166.8)">VCC</text>
<text x="347.9" y="166.8">GND</text>
<text x="75.3" y="169.3">AB2</text>
<text x="118.1" y="169.3">SJCRR</text>
<text x="128.3" y="169.3">IN&amp;F2</text>
<text x="191.7" y="169.3">SJSPK</text>
<text x="191.7" y="171.9">SJBHF</text>
<text x="228.5" y="171.9">SJCE</text>
<text x="274.6" y="169.3">SJE6</text>
<text x="274.6" y="171.9">SJE7</text>
<text x="310.8" y="171.5">0.1uF</text>
<text x="71.2" y="179.5">SNDCS</text>
<text x="77.5" y="175.7" transform="rotate(-90 77.5 175.7)">VCC</text>
<text x="191.7" y="174.4">SJCE</text>
<text x="227" y="179.5">SJRST</text>
<text x="227.2" y="174.4">SJCLK</text>
<text x="229.7" y="177">SJW</text>
<text x="274.2" y="177">SJM0</text>
<text x="274.2" y="179.5">SJM1</text>
<text x="311.2" y="176.6">C246</text>
<text x="78.2" y="182">R</text>
<text x="194.3" y="184.6">GND</text>
<text x="245.1" y="184.6">74HC166N</text>
<text x="260.3" y="184.6">SJ</text>
<text x="288.3" y="184.6">SPEAKJET</text>
<text x="306" y="184.6">SJ</text>
<text x="316.2" y="184.6">GND</text>
<text x="87.6" y="187.1">74HC138N</text>
<text x="102.9" y="187.1">SJ</text>
<text x="118.1" y="189.7" transform="rotate(-90 118.1 189.7)">SJW</text>
<text x="148.6" y="189.7" transform="rotate(-90 148.6 189.7)">SJCRR</text>
<text x="191.7" y="189.7">SJCRR</text>
<text x="168.9" y="197.3">74HC541N</text>
<text x="184.1" y="197.3">SJ</text>
<text x="77.3" y="202.4">SJW</text>
<text x="87.6" y="199.1">IC184</text>
<text x="112.3" y="199.8" transform="rotate(-90 112.3 199.8)">VCC</text>
<text x="148.6" y="202.4">SJW</text>
<text x="309.8" y="203.6">1</text>
<text x="317.5" y="203.6">2</text>
<text x="325.1" y="203.6">3</text>
<text x="332.7" y="203.6">4</text>
<text x="340.3" y="203.6">5</text>
<text x="347.9" y="203.6">6</text>
<text x="355.6" y="203.6">7</text>
<text x="363.2" y="203.6">8</text>
<text x="370.8" y="203.6">9</text>
<text x="378.4" y="203.6">10</text>
<text x="386" y="203.6">11</text>
<text x="62.2" y="204.9" transform="rotate(-90 62.2 204.9)">VCC</text>
<text x="71.6" y="205.9">R60</text>
<text x="148.6" y="204.9">SJCLK</text>
<text x="160" y="208.7">VCC</text>
<text x="168.9" y="209.3">IC191</text>
<text x="217.1" y="207.4" transform="rotate(-90 217.1 207.4)">SJCE</text>
<text x="295.7" y="208.7">SJCLK</text>
<text x="37.7" y="212.5">9620 Hz, 68.7% duty cycle</text>
<text x="70.2" y="210.7">560R</text>
<text x="70.2" y="213.5">470R</text>
<text x="113" y="212.5">SJCLK</text>
<text x="222.2" y="215.1">SJ</text>
<text x="298.2" y="215.1">RCX</text>
<text x="318.7" y="215.7">b0</text>
<text x="326.4" y="215.7">b1</text>
<text x="334" y="215.7">b2</text>
<text x="341.6" y="215.7">b3</text>
<text x="349.2" y="215.7">b4</text>
<text x="356.8" y="215.7">b5</text>
<text x="364.4" y="215.7">b6</text>
<text x="372.1" y="215.7">b7</text>
<text x="71.6" y="218.3">R61</text>
<text x="204.4" y="220.1" transform="rotate(-90 204.4 220.1)">SJCLK</text>
<text x="218.4" y="220.8">IC192C</text>
<text x="57.6" y="227.3">C237</text>
<text x="73.2" y="227.4">0.01uF</text>
<text x="87.6" y="227.9">LM555N</text>
<text x="102.9" y="227.8">SJ</text>
<text x="110.2" y="227.4">0.1uF</text>
<text x="115.6" y="222.7" transform="rotate(-90 115.6 222.7)">VCC</text>
<text x="148.6" y="225.2">SJW</text>
<text x="157.5" y="223.6" transform="rotate(-90 157.5 223.6)">0110 = 6</text>
<text x="218.4" y="224.5">74HC00N</text>
<text x="311.1" y="222.7">1</text>
<text x="316.2" y="222.7">8 data bits (non-inverted)</text>
<text x="377.1" y="222.7">0</text>
<text x="57.2" y="232.4">0.1uF</text>
<text x="75" y="232.5">C241</text>
<text x="110.6" y="232.5">C245</text>
<text x="295.6" y="230.3">SJRTS</text>
<text x="296.2" y="235.4">SJIRQ</text>
<text x="62.2" y="240.5">GND</text>
<text x="80" y="240.5">GND</text>
<text x="105.4" y="240.5">GND</text>
<text x="115.6" y="240.5">GND</text>
<text x="158.7" y="245.5">GND</text>
<text x="168.9" y="240.5">74HC193N</text>
<text x="186.7" y="240.5">SJ</text>
<text x="92.7" y="248.1" transform="rotate(-90 92.7 248.1)">VCC</text>
<text x="102.9" y="248.1" transform="rotate(-90 102.9 248.1)">VCC</text>
<text x="155.5" y="250">IC192B</text>
<text x="175.7" y="250">IC192A</text>
<text x="27.4" y="255.3">C232</text>
<text x="35" y="255.3">C233</text>
<text x="42.7" y="255.3">C234</text>
<text x="50.3" y="255.3">C235</text>
<text x="57.9" y="255.3">C236</text>
<text x="65.5" y="255.3">C238</text>
<text x="73.1" y="255.3">C239</text>
<text x="80.8" y="255.3">C240</text>
<text x="88.4" y="255.3">C242</text>
<text x="96" y="255.3">C243</text>
<text x="106.9" y="255.3">C244</text>
<text x="201.9" y="255.7">SJCLK</text>
<text x="27.4" y="260.4">0.1uF</text>
<text x="35" y="260.4">0.1uF</text>
<text x="42.7" y="260.4">0.1uF</text>
<text x="50.3" y="260.4">0.1uF</text>
<text x="57.9" y="260.4">0.1uF</text>
<text x="65.5" y="260.4">0.1uF</text>
<text x="73.1" y="260.4">0.1uF</text>
<text x="80.8" y="260.4">0.1uF</text>
<text x="88.4" y="260.4">0.1uF</text>
<text x="96" y="260.4">0.1uF</text>
<text x="106.9" y="260.4">1uF</text>
<text x="152.8" y="258.2">74HC00N</text>
<text x="168.9" y="260.8">SJ</text>
<text x="173.1" y="258.2">74HC00N</text>
<text x="191.7" y="260.8">SJ</text>
<text x="24.1" y="270.9">GND</text>
<text x="102.9" y="270.9">GND</text>
</g>
<g font-size="2.1">
<text x="237.8" y="77.6">12</text>
<text x="237.8" y="82.6">13</text>
<text x="250" y="80.1">11</text>
<text x="256.8" y="80.1">9</text>
<text x="272.8" y="80.1">8</text>
<text x="315.2" y="82.6">1</text>
<text x="326.1" y="82.6">2</text>
<text x="315.2" y="85.2">3</text>
<text x="315.2" y="87.7">5</text>
<text x="326.1" y="85.2">4</text>
<text x="326.1" y="87.7">6</text>
<text x="165.4" y="95.3">3</text>
<text x="186.5" y="95.3">2</text>
<text x="241.6" y="95.3">1</text>
<text x="314" y="95.3">11</text>
<text x="315.2" y="90.3">7</text>
<text x="315.2" y="92.8">9</text>
<text x="326.1" y="90.3">8</text>
<text x="326.1" y="92.8">10</text>
<text x="326.1" y="95.3">12</text>
<text x="84.1" y="97.9">1</text>
<text x="84.1" y="100.4">2</text>
<text x="90" y="99">A</text>
<text x="90" y="101.5">B</text>
<text x="100.5" y="101.5">Y1</text>
<text x="100.5" y="99">Y0</text>
<text x="107.7" y="100.4">14</text>
<text x="107.7" y="97.9">15</text>
<text x="165.4" y="97.9">4</text>
<text x="165.4" y="100.4">6</text>
<text x="171.2" y="96.5">D1</text>
<text x="171.2" y="99">D2</text>
<text x="171.2" y="101.5">D3</text>
<text x="178.9" y="96.5">Q1</text>
<text x="178.9" y="99">Q2</text>
<text x="178.9" y="101.5">Q3</text>
<text x="186.5" y="97.9">5</text>
<text x="186.5" y="100.4">7</text>
<text x="241.6" y="97.9">2</text>
<text x="241.6" y="100.4">3</text>
<text x="247.4" y="96.5">DS</text>
<text x="247.4" y="99">D0</text>
<text x="247.4" y="101.5">D1</text>
<text x="255.1" y="99">Q7</text>
<text x="262.7" y="97.9">13</text>
<text x="314" y="97.9">13</text>
<text x="314" y="100.4">15</text>
<text x="326.1" y="97.9">14</text>
<text x="326.1" y="100.4">16</text>
<text x="84.1" y="103">3</text>
<text x="90" y="104.1">C</text>
<text x="100.5" y="106.6">Y3</text>
<text x="100.5" y="104.1">Y2</text>
<text x="107.7" y="105.5">12</text>
<text x="107.7" y="103">13</text>
<text x="164.2" y="103">11</text>
<text x="164.2" y="105.5">13</text>
<text x="171.2" y="104.1">D4</text>
<text x="171.2" y="106.6">D5</text>
<text x="178.9" y="104.1">Q4</text>
<text x="178.9" y="106.6">Q5</text>
<text x="186.5" y="103">10</text>
<text x="186.5" y="105.5">12</text>
<text x="241.6" y="103">4</text>
<text x="241.6" y="105.5">5</text>
<text x="247.4" y="104.1">D2</text>
<text x="247.4" y="106.6">D3</text>
<text x="314" y="103">17</text>
<text x="326.1" y="103">18</text>
<text x="84.1" y="113.1">4</text>
<text x="84.1" y="110.6">6</text>
<text x="90" y="111.7">G1</text>
<text x="100.5" y="111.7">Y5</text>
<text x="100.5" y="109.2">Y4</text>
<text x="107.7" y="113.1">9</text>
<text x="107.7" y="110.6">10</text>
<text x="107.7" y="108">11</text>
<text x="164.2" y="108">14</text>
<text x="165.4" y="113.1">9</text>
<text x="171.2" y="109.2">D6</text>
<text x="178.9" y="109.2">Q6</text>
<text x="186.5" y="108">15</text>
<text x="240.4" y="108">10</text>
<text x="240.4" y="110.6">11</text>
<text x="240.4" y="113.1">12</text>
<text x="247.4" y="109.2">D4</text>
<text x="247.4" y="111.7">D5</text>
<text x="84.1" y="115.7">5</text>
<text x="90" y="114.2">G2A</text>
<text x="90" y="116.8">G2B</text>
<text x="100.5" y="116.8">Y7</text>
<text x="100.5" y="114.2">Y6</text>
<text x="107.7" y="115.7">7</text>
<text x="165.4" y="115.7">1</text>
<text x="171.2" y="116.8">CLR</text>
<text x="171.2" y="114.2">CLK</text>
<text x="240.4" y="115.7">14</text>
<text x="247.4" y="114.2">D6</text>
<text x="247.4" y="116.8">D7</text>
<text x="240.4" y="125.8">15</text>
<text x="241.6" y="123.3">6</text>
<text x="241.6" y="120.7">7</text>
<text x="247.4" y="124.4">CE/CP</text>
<text x="247.4" y="121.9">CP/CE</text>
<text x="165.4" y="128.4">2</text>
<text x="165.4" y="130.9">3</text>
<text x="171.2" y="129.5">1D</text>
<text x="178.9" y="129.5">1Q</text>
<text x="186.5" y="130.9">18</text>
<text x="186.5" y="128.4">19</text>
<text x="241.6" y="128.4">9</text>
<text x="247.4" y="129.5">CLR</text>
<text x="247.4" y="126.9">PL</text>
<text x="84.1" y="133.4">1</text>
<text x="84.1" y="136">2</text>
<text x="90" y="134.6">A</text>
<text x="90" y="137.1">B</text>
<text x="100.5" y="137.1">Y1</text>
<text x="100.5" y="134.6">Y0</text>
<text x="107.7" y="136">14</text>
<text x="107.7" y="133.4">15</text>
<text x="165.4" y="133.4">4</text>
<text x="165.4" y="136">5</text>
<text x="171.2" y="132">2D</text>
<text x="171.2" y="134.6">3D</text>
<text x="171.2" y="137.1">4D</text>
<text x="178.9" y="137.1">4Q</text>
<text x="178.9" y="134.6">3Q</text>
<text x="178.9" y="132">2Q</text>
<text x="186.5" y="136">16</text>
<text x="186.5" y="133.4">17</text>
<text x="84.1" y="138.5">3</text>
<text x="90" y="139.6">C</text>
<text x="100.5" y="142.2">Y3</text>
<text x="100.5" y="139.6">Y2</text>
<text x="107.7" y="143.6">11</text>
<text x="107.7" y="141.1">12</text>
<text x="107.7" y="138.5">13</text>
<text x="165.4" y="138.5">6</text>
<text x="165.4" y="141.1">7</text>
<text x="165.4" y="143.6">8</text>
<text x="171.2" y="139.6">5D</text>
<text x="171.2" y="142.2">6D</text>
<text x="178.9" y="142.2">6Q</text>
<text x="178.9" y="139.6">5Q</text>
<text x="186.5" y="143.6">13</text>
<text x="186.5" y="141.1">14</text>
<text x="186.5" y="138.5">15</text>
<text x="283.5" y="143.6">11</text>
<text x="310.9" y="143.6">18</text>
<text x="84.1" y="148.7">4</text>
<text x="84.1" y="146.1">6</text>
<text x="90" y="149.8">G2A</text>
<text x="90" y="147.3">G1</text>
<text x="100.5" y="149.8">Y6</text>
<text x="100.5" y="147.3">Y5</text>
<text x="100.5" y="144.7">Y4</text>
<text x="107.7" y="148.7">9</text>
<text x="107.7" y="146.1">10</text>
<text x="165.4" y="146.1">9</text>
<text x="171.2" y="144.7">7D</text>
<text x="171.2" y="147.3">8D</text>
<text x="178.9" y="147.3">8Q</text>
<text x="178.9" y="144.7">7Q</text>
<text x="186.5" y="146.1">12</text>
<text x="241.6" y="146.1">1</text>
<text x="241.6" y="148.7">2</text>
<text x="247.4" y="147.3">DS</text>
<text x="247.4" y="149.8">D0</text>
<text x="255.1" y="149.8">Q7</text>
<text x="262.7" y="148.7">13</text>
<text x="283.5" y="148.7">10</text>
<text x="290.6" y="144.7">RST</text>
<text x="290.6" y="149.8">RCX</text>
<text x="300.3" y="144.7">VOUT</text>
<text x="361.6" y="148.7" transform="rotate(-90 361.6 148.7)">E</text>
<text x="84.1" y="151.2">5</text>
<text x="90" y="152.3">G2B</text>
<text x="100.5" y="152.3">Y7</text>
<text x="107.7" y="151.2">7</text>
<text x="164.2" y="151.2">11</text>
<text x="165.4" y="153.8">1</text>
<text x="171.2" y="154.9">OC</text>
<text x="171.2" y="152.3">CLK</text>
<text x="241.6" y="151.2">3</text>
<text x="241.6" y="153.8">4</text>
<text x="247.4" y="152.3">D1</text>
<text x="247.4" y="154.9">D2</text>
<text x="284.7" y="153.8">9</text>
<text x="290.6" y="154.9">E0</text>
<text x="298.4" y="154.9">D0/RDY</text>
<text x="310.9" y="153.8">17</text>
<text x="361.6" y="155.9" transform="rotate(-90 361.6 155.9)">A</text>
<text x="364.8" y="151.2">S</text>
<text x="240.4" y="158.8">10</text>
<text x="240.4" y="161.4">11</text>
<text x="241.6" y="156.3">5</text>
<text x="247.4" y="157.4">D3</text>
<text x="247.4" y="159.9">D4</text>
<text x="284.7" y="156.3">8</text>
<text x="284.7" y="158.8">7</text>
<text x="284.7" y="161.4">6</text>
<text x="290.6" y="157.4">E1</text>
<text x="290.6" y="159.9">E2</text>
<text x="298.6" y="157.4">D1/SPK</text>
<text x="298.7" y="160">D2/BHF</text>
<text x="310.9" y="156.3">16</text>
<text x="310.9" y="158.8">15</text>
<text x="84.1" y="163.9">1</text>
<text x="84.1" y="166.5">2</text>
<text x="90" y="165">A</text>
<text x="90" y="167.6">B</text>
<text x="100.5" y="167.6">Y1</text>
<text x="100.5" y="165">Y0</text>
<text x="107.7" y="166.5">14</text>
<text x="107.7" y="163.9">15</text>
<text x="164.2" y="166.5">18</text>
<text x="171.2" y="167.6">Y1</text>
<text x="179.2" y="167.6">A1</text>
<text x="186.5" y="166.5">2</text>
<text x="240.4" y="163.9">12</text>
<text x="240.4" y="166.5">14</text>
<text x="247.4" y="162.5">D5</text>
<text x="247.4" y="165">D6</text>
<text x="247.4" y="167.6">D7</text>
<text x="284.7" y="163.9">4</text>
<text x="284.7" y="166.5">3</text>
<text x="290.6" y="162.5">E3</text>
<text x="290.6" y="165">E4</text>
<text x="290.6" y="167.6">E5</text>
<text x="84.1" y="169">3</text>
<text x="90" y="170.1">C</text>
<text x="100.5" y="172.6">Y3</text>
<text x="100.5" y="170.1">Y2</text>
<text x="107.7" y="171.5">12</text>
<text x="107.7" y="169">13</text>
<text x="164.2" y="171.5">16</text>
<text x="164.2" y="169">17</text>
<text x="171.2" y="172.6">Y3</text>
<text x="171.2" y="170.1">Y2</text>
<text x="179.2" y="170.1">A2</text>
<text x="179.2" y="172.6">A3</text>
<text x="186.5" y="169">3</text>
<text x="186.5" y="171.5">4</text>
<text x="241.6" y="171.5">7</text>
<text x="247.4" y="172.6">CP/CE</text>
<text x="284.7" y="169">2</text>
<text x="284.7" y="171.5">1</text>
<text x="290.6" y="170.1">RC0/E6</text>
<text x="290.6" y="172.6">RC1/E7</text>
<text x="84.1" y="179.1">4</text>
<text x="84.1" y="176.6">6</text>
<text x="90" y="177.7">G1</text>
<text x="100.5" y="177.7">Y5</text>
<text x="100.5" y="175.2">Y4</text>
<text x="107.7" y="179.1">9</text>
<text x="107.7" y="176.6">10</text>
<text x="107.7" y="174.1">11</text>
<text x="164.2" y="179.1">13</text>
<text x="164.2" y="176.6">14</text>
<text x="164.2" y="174.1">15</text>
<text x="171.2" y="177.7">Y5</text>
<text x="171.2" y="175.2">Y4</text>
<text x="179.2" y="175.2">A4</text>
<text x="179.2" y="177.7">A5</text>
<text x="186.5" y="174.1">5</text>
<text x="186.5" y="176.6">6</text>
<text x="186.5" y="179.1">7</text>
<text x="240.4" y="176.6">15</text>
<text x="241.6" y="174.1">6</text>
<text x="241.6" y="179.1">9</text>
<text x="247.4" y="175.2">CE/CP</text>
<text x="247.4" y="177.7">PL</text>
<text x="283.5" y="176.6">13</text>
<text x="283.5" y="179.1">12</text>
<text x="290.6" y="177.7">M0</text>
<text x="84.1" y="181.7">5</text>
<text x="90" y="180.3">G2A</text>
<text x="90" y="182.8">G2B</text>
<text x="100.5" y="182.8">Y7</text>
<text x="100.5" y="180.3">Y6</text>
<text x="107.7" y="181.7">7</text>
<text x="164.2" y="184.2">11</text>
<text x="164.2" y="181.7">12</text>
<text x="171.2" y="185.3">Y8</text>
<text x="171.2" y="182.8">Y7</text>
<text x="171.2" y="180.3">Y6</text>
<text x="179.2" y="180.3">A6</text>
<text x="179.2" y="182.8">A7</text>
<text x="179.2" y="185.3">A8</text>
<text x="186.5" y="181.7">8</text>
<text x="186.5" y="184.2">9</text>
<text x="247.4" y="180.3">CLR</text>
<text x="290.6" y="180.3">M1</text>
<text x="178.9" y="190.4">G1</text>
<text x="186.5" y="189.3">1</text>
<text x="186.5" y="191.8">19</text>
<text x="178.9" y="193">G2</text>
<text x="84.1" y="202">4</text>
<text x="90" y="203.1">R</text>
<text x="97.9" y="203.1">V+</text>
<text x="103.2" y="202">8</text>
<text x="86.1" y="207.1">7</text>
<text x="90" y="208.2">DIS</text>
<text x="86.1" y="214.7">6</text>
<text x="90" y="215.8">THR</text>
<text x="98.9" y="213.3">Q</text>
<text x="103.2" y="212.2">3</text>
<text x="164.2" y="212.2">15</text>
<text x="165.4" y="214.7">1</text>
<text x="171.2" y="213.3">A</text>
<text x="171.2" y="215.8">B</text>
<text x="183.8" y="215.8">QB</text>
<text x="183.8" y="213.3">QA</text>
<text x="191.5" y="214.7">2</text>
<text x="191.5" y="212.2">3</text>
<text x="214.2" y="210.2" transform="rotate(-90 214.2 210.2)">8</text>
<text x="86.1" y="219.8">2</text>
<text x="90" y="220.9">TR</text>
<text x="164.2" y="217.2">10</text>
<text x="165.4" y="219.8">9</text>
<text x="171.2" y="218.4">C</text>
<text x="171.2" y="220.9">D</text>
<text x="183.7" y="220.9">QD</text>
<text x="183.7" y="218.4">QC</text>
<text x="191.5" y="219.8">7</text>
<text x="191.5" y="217.2">6</text>
<text x="211.7" y="221.1" transform="rotate(-90 211.7 221.1)">9</text>
<text x="86.1" y="222.3">5</text>
<text x="90" y="223.4">CV</text>
<text x="95.7" y="223.4">GND</text>
<text x="103.2" y="222.3">1</text>
<text x="164.2" y="224.9">11</text>
<text x="171.2" y="226">LOAD</text>
<text x="191.5" y="227.4">13</text>
<text x="216.8" y="222.3" transform="rotate(-90 216.8 222.3)">10</text>
<text x="165.4" y="229.9">5</text>
<text x="165.4" y="232.5">4</text>
<text x="171.2" y="231.1">UP</text>
<text x="171.2" y="233.6">DOWN</text>
<text x="177.1" y="228.5">BORROW</text>
<text x="179.4" y="231.1">CARRY</text>
<text x="191.5" y="229.9">12</text>
<text x="164.2" y="235">14</text>
<text x="171.2" y="236.1">CLEAR</text>
<text x="171.2" y="250.3">4</text>
<text x="191.5" y="250.3">1</text>
<text x="160.3" y="252.8">6</text>
<text x="171.2" y="255.3">5</text>
<text x="180.6" y="252.8">3</text>
<text x="191.5" y="255.3">2</text>
</g>
<g font-size="1.8">
<text x="370.6" y="151">+</text>
<text x="66.6" y="227.3" transform="rotate(-90 66.6 227.3)">+</text>
</g>
</g></defs>
<g fill="#000" stroke="#000" stroke-width=".21">
<path d="M67.8 18.2v3.9zM115.3 18.2v3.9zM162.7 18.2v3.9zM210.2 18.2v3.9zM257.6 18.2v3.9zM305.1 18.2v3.9zM352.5 18.2v3.9zM20.3 22.1v252.6zM20.3 22.1h379.7zM26.7 59h10.2zM28.6 43.8h8.3zM34.5 48.9h2.4z"/>
<path d="M35.1 54h1.8zM41.9 50h17.8zM41.9 55.1h12.7zM54.6 55.1h317.5zM54.6 55.1v127zM59.7 50h312.4zM59.7 50v101.6zM41.9 44.9h99zM140.9 44.9h231.2zM373.6 43.8h8.3zM373.6 59h10.1zM373.6 48.9h2.3z"/>
<path d="M373.6 54h1.8zM16.5 72.6h3.8zM32.5 64.1h4.4zM41.9 60.2h22.9zM64.8 60.2h307.3zM64.8 60.2v55.8zM143.5 70.3h228.6zM212.1 77.9h25.4zM237.5 77.9h5zM298.4 75.4v2.5zM296.4 78.9l2-1zM298.4 72.8v2.6z"/>
<path d="M298.4 72.8h12.7zM311.1 72.8v10.2zM41.9 65.2h297.1zM339 65.2h33.1zM373.6 69.2h7.6zM373.6 64.1h4.4zM374.6 75.9h10zM400 72.6h3.8zM69.8 95.7l2.6 2.5zM69.8 98.2l2.6 2.6zM72.4 98.2h10.1zM82.5 98.2h5.1z"/>
<path d="M107.4 98.2h3.1zM151.1 93.2l2.5 2.5zM151.1 95.7l2.5 2.5zM163.8 95.7h5.1zM163.8 98.2h5.1zM153.6 95.7h10.2zM153.6 98.2h10.2zM184.1 95.7h5.1zM184.1 98.2h5.1zM189.2 95.7h15.2zM189.2 98.2h15.2zM191.7 93.7h7.9z"/>
<path d="M204.4 95.7l2.6 2.5zM204.4 98.2l2.6 2.6zM214.6 83h22.9zM228.5 81h6.4zM237.5 83h5zM237.5 95.7v2.5zM237.5 95.7h2.5zM240 95.7h5.1zM240 98.2h5.1zM237.5 98.2h2.5zM249.6 80.5h3.1zM255.2 80.5h5.1z"/>
<path d="M252.7 80.5h2.5zM261.6 89.3l1.8 2.1zM263.8 91.9l.1 .2zM264.3 92.6l1.8 2.1zM260.3 98.2h5.1zM265.4 98.2h2.5zM266.5 95.2l.1 .1zM267.1 95.8l1.8 2.1zM267.9 98.2v40.7zM269.3 98.4l.1 .1zM269.8 99l1.8 2.1zM272.5 80.5h3.1z"/>
<path d="M280.6 80.5h2.6zM275.6 80.5h5zM288.3 80.5h2.5zM293.3 80.5h2.6zM290.8 80.5h2.5zM297.7 82l-.5 1zM296.2 81.9l1.2 .6zM297.7 82l.7 1zM298.4 95.7v2.5zM298.4 88.1v2.5zM298.4 83v2.5zM297.2 83h1.2z"/>
<path d="M298.4 85.5v2.6zM311.1 83v2.5zM311.1 85.5v2.6zM311.1 88.1v2.5zM311.1 90.6v2.6zM311.1 93.2v2.5zM311.1 95.7v2.5zM311.1 98.2v2.6zM313.7 83h5zM313.7 85.5h5zM313.7 88.1h5zM313.7 90.6h5z"/>
<path d="M313.7 93.2h5zM313.7 95.7h5zM313.7 98.2h5zM311.1 98.2h2.6zM311.1 95.7h2.6zM311.1 93.2h2.6zM311.1 90.6h2.6zM311.1 88.1h2.6zM311.1 85.5h2.6zM311.1 83h2.6zM323.8 83h5.1zM323.8 85.5h5.1z"/>
<path d="M323.8 88.1h5.1zM323.8 90.6h5.1zM323.8 93.2h5.1zM323.8 95.7h5.1zM323.8 98.2h5.1zM328.9 83h10.1zM330.7 98h5.8zM330.7 95.5h5.8zM330.7 92.9h5.8zM330.7 90.4h5.8zM330.7 87.8h5.8zM330.7 85.3h5.8z"/>
<path d="M331.4 81h4.4zM339 65.2v17.8zM328.9 98.2h12.7zM328.9 95.7h12.7zM328.9 93.2h12.7zM328.9 90.6h12.7zM328.9 88.1h12.7zM328.9 85.5h12.7zM344.1 98.2l-2.5 2.6zM344.1 95.7l-2.5 2.5zM344.1 93.2l-2.5 2.5zM344.1 90.6l-2.5 2.6z"/>
<path d="M344.1 88.1l-2.5 2.5zM344.1 85.5l-2.5 2.6zM344.1 83l-2.5 2.5zM64.8 116h17.7zM65.3 95.7v10.2zM69.8 114h10.2zM69.8 100.8l2.6 2.5zM69.8 110.9l2.6 2.6zM72.4 100.8h10.1zM72.4 103.3h10.1zM72.4 113.5h10.1zM69.8 108.4l2.6 2.5z"/>
<path d="M82.5 100.8h5.1zM82.5 103.3h5.1zM82.5 113.5h3.1zM82.5 116h3.1zM82.5 110.9h5.1zM72.4 110.9h10.1zM107.4 116h3.1zM107.4 113.5h3.1zM107.4 110.9h3.1zM107.4 108.4h3.1zM107.4 105.9h3.1zM107.4 103.3h3.1z"/>
<path d="M107.4 100.8h3.1zM110.5 116h2.5zM113 116v10.2zM140.9 44.9v71.1zM144 95.7v7.6zM146 113.5h17.8zM152.4 111.5h8.9zM153.6 114h8.4zM151.1 98.2l2.5 2.6zM151.1 100.8l2.5 2.5zM151.1 103.3l2.5 2.6zM151.1 105.9l2.5 2.5z"/>
<path d="M163.8 116h3.1zM163.8 100.8h5.1zM163.8 113.5h5.1zM163.8 103.3h5.1zM163.8 105.9h5.1zM163.8 108.4h5.1zM140.9 116h22.9zM153.6 100.8h10.2zM153.6 103.3h10.2zM153.6 105.9h10.2zM153.6 108.4h10.2zM168.9 112.5l2 1z"/>
<path d="M168.9 114.5l2-1zM184.1 100.8h5.1zM184.1 103.3h5.1zM184.1 105.9h5.1zM184.1 108.4h5.1zM189.2 100.8h15.2zM189.2 108.4h22.9zM204.4 100.8l2.6 2.5zM212.1 77.9v30.5zM222.2 113.5l2.6 2.5zM228.5 119.1h6.4zM237.5 113.5v17.8z"/>
<path d="M237.5 110.9v2.6zM237.5 108.4v2.5zM237.5 105.9v2.5zM237.5 103.3v2.6zM237.5 100.8v2.5zM237.5 98.2v2.6zM240 100.8h5.1zM240 103.3h5.1zM240 105.9h5.1zM240 108.4h5.1zM240 110.9h5.1zM240 113.5h5.1z"/>
<path d="M240 116h5.1zM237.5 113.5h2.5zM237.5 110.9h2.5zM237.5 108.4h2.5zM237.5 105.9h2.5zM237.5 103.3h2.5zM237.5 100.8h2.5zM224.8 116h15.2zM272 101.6l.1 .1zM272.6 102.2l1.7 2.1zM274.8 104.8l.1 .1zM275.3 105.5l1.8 2z"/>
<path d="M277.5 108.1l.1 .1zM278.1 108.7l1.7 2zM280.3 111.3v.1zM280.8 111.9l1.8 2.1zM283 114.5l.1 .1zM283.5 115.1l1.8 2.1zM285.7 117.7l.1 .1zM286.3 118.3l1.8 2.1zM290.8 117.3h60.9zM298.4 103.3v2.6zM298.4 98.2v5.1zM311.1 100.8v2.5z"/>
<path d="M313.7 100.8h5zM313.7 103.3h5zM311.1 100.8h2.6zM311.1 103.3h2.6zM323.8 100.8h5.1zM323.8 103.3h5.1zM330.7 103.1h5.8zM330.7 100.5h5.8zM328.9 103.3h12.7zM328.9 100.8h12.7zM344.1 100.8l-2.5 2.5zM351.7 117.3v11.4z"/>
<path d="M16.5 123.1h3.8zM64.8 126.2v22.8zM69.8 131.3l2.6 2.5zM69.8 136.3l2.6 2.6zM69.8 133.8l2.6 2.5zM82.5 133.8h5.1zM82.5 136.3h5.1zM82.5 138.9h5.1zM72.4 133.8h10.1zM72.4 138.9h10.1zM72.4 136.3h10.1zM107.4 138.9h3.1z"/>
<path d="M107.4 136.3h3.1zM107.4 133.8h3.1zM110.5 133.8h33zM110.5 136.3h5.1zM110.5 138.9h35.5zM64.8 126.2h48.2zM115.6 136.3v55.9zM118.1 131.8h7.6zM118.1 134.3h5.3zM118.1 136.9h8.9zM143.5 70.3v63.5zM146 113.5v25.4z"/>
<path d="M146 138.9v12.7zM151.1 126.2l2.5 2.5zM151.1 128.7l2.5 2.6zM151.1 131.3l2.5 2.5zM151.1 133.8l2.5 2.5zM151.1 136.3l2.5 2.6zM163.8 128.7h5.1zM163.8 131.3h5.1zM163.8 133.8h5.1zM163.8 136.3h5.1zM163.8 138.9h5.1zM153.6 128.7h10.2z"/>
<path d="M153.6 131.3h10.2zM153.6 133.8h10.2zM153.6 136.3h10.2zM153.6 138.9h10.2zM184.1 138.9h5.1zM184.1 136.3h5.1zM184.1 133.8h5.1zM184.1 131.3h5.1zM184.1 128.7h5.1zM189.2 128.7h15.2zM189.2 131.3h15.2zM189.2 133.8h15.2z"/>
<path d="M189.2 136.3h15.2zM189.2 138.9h15.2zM204.4 128.7l2.6-2.5zM204.4 131.3l2.6-2.6zM207 131.3l-2.6 2.5zM204.4 136.3l2.6-2.5zM204.4 138.9l2.6-2.6zM207 126.2l2.5 2.5zM209.5 128.7h30.5zM212.1 126.2h27.9zM214.6 121.1v50.8zM214.6 83v38.1z"/>
<path d="M217.1 123.6v50.8zM227 126.7h7.9zM229.7 124.2h5.2zM237.5 131.3v2.5zM237.5 138.9v7.6zM240 123.6h5.1zM240 121.1h5.1zM240 128.7h3.1zM240 126.2h3.1zM217.1 123.6h22.9zM214.6 121.1h25.4zM245.1 122.6l2 1z"/>
<path d="M245.1 120.1l2 1zM245.1 124.6l2-1zM245.1 122.1l2-1zM247.4 122.7h3zM247.4 125.2h2.6zM251 120.2h2.9zM237.5 138.9h30.4zM288.5 120.9l.1 .1zM289 121.6l1.8 2zM290.8 123.6v5.1zM290.8 117.3v6.3zM290.8 128.7h60.9z"/>
<path d="M400 123.1h3.8zM59.7 151.6h22.8zM64.8 149h17.7zM64.8 149v30.5zM71.2 147h8.8zM77.7 149.6h2.3zM80 142.7v2.5zM80 145.2v1.3zM82.5 149h3.1zM82.5 151.6h3.1zM82.5 146.5h5.1zM80 146.5h2.5z"/>
<path d="M107.4 151.6h3.1zM107.4 149h3.1zM107.4 146.5h3.1zM107.4 144h3.1zM107.4 141.4h3.1zM146 151.6h17.8zM152.4 149.6h8.9zM151.1 138.9l2.5 2.5zM151.1 141.4l2.5 2.6zM151.1 144l2.5 2.5zM161.3 156.7v2.5zM161.3 154.1v2.6z"/>
<path d="M163.8 154.1h3.1zM163.8 141.4h5.1zM163.8 144h5.1zM163.8 146.5h5.1zM163.8 151.6h5.1zM161.3 154.1h2.5zM153.6 141.4h10.2zM153.6 144h10.2zM153.6 146.5h10.2zM168.9 150.6l2 1zM168.9 152.6l2-1zM184.1 146.5h5.1z"/>
<path d="M184.1 144h5.1zM184.1 141.4h5.1zM189.2 141.4h15.2zM189.2 144h15.2zM189.2 146.5h15.2zM207 138.9l-2.6 2.5zM204.4 144l2.6-2.6zM204.4 146.5l2.6-2.5zM210.1 151.4v5.3zM212.6 150.2v6.5zM222.2 156.7l2.6 2.5zM222.2 154.1l2.6 2.6z"/>
<path d="M222.2 151.6l2.6 2.5zM222.2 149l2.6 2.6zM222.2 146.5l2.6 2.5zM237.5 146.5h2.5zM240 146.5h5.1zM240 149h5.1zM240 151.6h5.1zM240 154.1h5.1zM240 156.7h5.1zM240 159.2h5.1zM224.8 159.2h15.2zM224.8 156.7h15.2z"/>
<path d="M224.8 154.1h15.2zM224.8 151.6h15.2zM224.8 149h15.2zM260.3 149h5.1zM270.5 144l-2.6 2.5zM270.5 144h12.7zM270.5 154.1l-2.6 2.6zM270.5 156.7l-2.6 2.5zM270.5 159.2l-2.6 2.5zM272.7 141.9h7.9zM283.2 154.1h5.1zM283.2 156.7h5.1z"/>
<path d="M283.2 159.2h5.1zM283.2 144h3.1zM283.2 149h5.1zM265.4 149h17.8zM270.5 154.1h12.7zM270.5 156.7h12.7zM270.5 159.2h12.7zM290.6 143h4.3zM308.6 144h5.1zM308.6 154.1h5.1zM308.6 156.7h5.1zM308.6 159.2h5.1z"/>
<path d="M313.7 154.1h12.7zM313.7 156.7h12.7zM313.7 159.2h12.7zM313.7 144h12.7zM326.4 144h2.5zM326.4 154.1l2.5 2.6zM326.4 156.7l2.5 2.5zM326.4 159.2l2.5 2.5zM334 144h2.5zM336.5 144h2.5zM339 154.1v2.6zM339 149v2.6z"/>
<path d="M339 153.6v.5zM339 151.6v.5zM339 156.7v2.5zM339 159.2h11.5zM339 144h2.6zM339 144v5zM341.6 144h2.5zM350.5 159.2h3.8zM349.2 144h2.5zM351.7 144h2.6zM354.3 154.1v2.6zM354.3 149v2.6z"/>
<path d="M354.3 153.6v.5zM354.3 151.6v.5zM354.3 156.7v2.5zM354.3 159.2h7.6zM354.3 144v5zM354.3 144h7.6zM359.4 152.1v2zM359.4 152.1l-.5 1zM359.4 152.1l.5 1zM360.2 149.3l-.5 1zM361.9 154.1v2.6zM361.9 146.5v2.5z"/>
<path d="M361.9 156.7v2.5zM361.9 144v2.5zM360 149.8l3.6 1.8zM363.6 151.6h.8zM364.4 151.6h2.6zM369.5 151.6h2.6zM367 151.6h2.5zM374.6 151.6h2.5zM377.1 151.6h2.6zM16.5 173.7h3.8zM64.8 179.5h17.7zM71.2 177.5h8.8z"/>
<path d="M69.8 161.7l2.6 2.6zM69.8 166.8l2.6 2.6zM69.8 164.3l2.6 2.5zM80 173.2v2.5zM80 175.7v1.3zM82.5 164.3h5.1zM82.5 166.8h5.1zM82.5 169.4h5.1zM82.5 179.5h3.1zM82.5 177h5.1zM80 177h2.5zM72.4 164.3h10.1z"/>
<path d="M72.4 169.4h10.1zM72.4 166.8h10.1zM107.4 179.5h3.1zM107.4 177h3.1zM107.4 174.4h3.1zM107.4 171.9h3.1zM107.4 169.4h3.1zM107.4 166.8h3.1zM107.4 164.3h3.1zM110.5 169.4h35.5zM118.1 167.3h8.3zM151.1 164.3l2.5 2.5z"/>
<path d="M151.1 166.8l2.5 2.6zM151.1 169.4l2.5 2.5zM151.1 171.9l2.5 2.5zM151.1 174.4l2.5 2.6zM151.1 177l2.5 2.5zM163.8 179.5h5.1zM163.8 177h5.1zM163.8 174.4h5.1zM163.8 171.9h5.1zM163.8 169.4h5.1zM163.8 166.8h5.1zM153.6 166.8h10.2z"/>
<path d="M153.6 169.4h10.2zM153.6 171.9h10.2zM153.6 174.4h10.2zM153.6 177h10.2zM153.6 179.5h10.2zM184.1 166.8h5.1zM184.1 169.4h5.1zM184.1 171.9h5.1zM184.1 174.4h5.1zM184.1 177h5.1zM184.1 179.5h5.1zM189.2 177h2.5z"/>
<path d="M189.2 179.5h2.5zM189.2 166.8h15.2zM189.2 169.4h15.2zM189.2 171.9h15.2zM189.2 174.4h25.4zM191.7 172.4h6.5zM191.7 177v2.5zM191.7 179.5v2.6zM191.7 177h5.1zM196.8 179.5v2.6zM196.8 177v2.5zM204.4 166.8l2.6-2.5z"/>
<path d="M204.4 169.4l2.6-2.6zM207 169.4l-2.6 2.5zM207 177l2.5 2.5zM212.1 126.2v50.8zM214.6 171.9v2.5zM214.6 174.4v33zM217.1 174.4v22.9zM219.7 163v2.5zM219.7 165.5v1.3zM222.2 161.7l2.6 2.6zM222.2 159.2l2.6 2.5zM227 177.5h7.9z"/>
<path d="M228.5 169.9h6.4zM229.7 175h5.2zM240 174.4h5.1zM240 171.9h5.1zM240 179.5h3.1zM240 161.7h5.1zM240 164.3h5.1zM240 166.8h5.1zM240 177h3.1zM219.7 166.8h20.3zM212.1 177h27.9zM209.5 179.5h30.5z"/>
<path d="M224.8 164.3h15.2zM224.8 161.7h15.2zM217.1 174.4h22.9zM214.6 171.9h25.4zM245.1 173.4l2 1zM245.1 170.9l2 1zM245.1 175.4l2-1zM245.1 172.9l2-1zM247.4 173.5h3zM247.4 176h2.6zM251 171h2.9zM270.5 161.7l-2.6 2.6z"/>
<path d="M270.5 164.3l-2.6 2.5zM270.5 166.8l-2.6 2.6zM270.5 169.4l-2.6 2.5zM270.5 171.9l-2.6 2.5zM270.5 177l-2.6 2.5zM270.5 179.5l-2.6 2.6zM283.2 161.7h5.1zM283.2 164.3h5.1zM283.2 166.8h5.1zM283.2 169.4h5.1zM283.2 171.9h5.1zM283.2 177h5.1z"/>
<path d="M283.2 179.5h5.1zM270.5 161.7h12.7zM270.5 164.3h12.7zM270.5 166.8h12.7zM270.5 169.4h12.7zM270.5 171.9h12.7zM270.5 177h12.7zM270.5 179.5h12.7zM318.7 174.4v2.6zM318.7 169.4v2.5zM318.7 173.9v.5zM318.7 171.9v.5z"/>
<path d="M318.7 179.5v2.6zM318.7 164.3v2.5zM318.7 177v2.5zM318.7 166.8v2.6zM350.5 161.7v2.6zM350.5 159.2v2.5zM400 173.7h3.8zM54.6 182.1h27.9zM78.2 180h1.8zM82.5 182.1h3.1zM107.9 197.3v2.5zM107.4 182.1h3.1z"/>
<path d="M74.9 192.2h40.7zM115.6 192.2v10.2zM116.1 184.4v5.3zM146 169.4v30.4zM146.6 181.3v8.4zM151.1 179.5l2.5 2.6zM151.1 182.1l2.5 2.5zM163.8 184.6h5.1zM163.8 182.1h5.1zM153.6 182.1h10.2zM153.6 184.6h10.2zM186.1 189.7h3.1z"/>
<path d="M184.1 182.1h5.1zM184.1 184.6h5.1zM186.1 192.2h3.1zM189.2 182.1h2.5zM189.2 184.6h2.5zM189.2 189.7h2.5zM189.2 192.2h2.5zM191.7 187.7h8.4zM191.7 182.1v2.5zM191.7 189.7v2.5zM191.7 192.2v7.6zM146 199.8h45.7z"/>
<path d="M201.9 197.3h15.2zM64.8 202.4v2.5zM64.8 204.9v2.5zM64.8 207.4h2.5zM64.8 215v5.1zM67.3 207.4h2.5zM67.3 215h2.5zM64.8 215h2.5zM74.9 192.2v10.2zM77.3 200.4h5.2zM74.9 207.4h2.6zM74.9 215h2.6z"/>
<path d="M77.5 215h2.5zM77.5 207.4h2.5zM80 207.4v7.6zM82.5 215v5.1zM85.1 202.4h.5zM85.1 215h2.5zM85.1 207.4h2.5zM82.5 215h2.6zM80 207.4h5.1zM74.9 202.4h10.2zM102.9 212.5h2.5zM102.9 202.4h2.5z"/>
<path d="M105.4 202.4h2.5zM105.4 212.5h17.8zM107.9 199.8v2.6zM115.6 202.4h30.4zM123.2 204.9v7.6zM123.2 204.9h78.7zM146 202.4v22.8zM146 202.4h66.1zM148.6 200.4h5.2zM158.7 207.4v2.6zM158.7 210v5zM158.7 215v2.6z"/>
<path d="M158.7 217.6v15.2zM161.3 212.5v7.6zM163.8 212.5h5.1zM163.8 215h5.1zM163.8 217.6h5.1zM161.3 212.5h2.5zM158.7 215h5.1zM158.7 217.6h5.1zM189.2 217.6h5.1zM189.2 215h5.1zM189.2 212.5h5.1zM201.9 204.9v50.8z"/>
<path d="M201.9 197.3v7.6zM212.1 177v25.4zM214.6 207.4v3.1zM215.1 201v6.4zM215.9 210h2.5zM218.4 207.4v2.6zM218.4 207.4h2.6zM221 207.4v2.6zM306 204.9h3.9zM306 217.6h3.9zM309.9 204.9v5.1zM309.9 210h3.8z"/>
<path d="M309.9 211.2v1.5zM309.9 213.7v1.5zM309.9 216.2v1.4zM309.9 217.6v1.5zM312.4 212.5h2.5zM312.4 212.5l-2.5 5.1zM313.7 204.9v5.1zM313.7 204.9h3.8zM314.9 212.5l1.3 2.5zM317.5 212.5l-1.3 2.5zM316.2 215l1.3 2.6zM317.5 212.5h5.1z"/>
<path d="M317.5 217.6h5.1zM317.5 204.9v5.1zM317.5 210h3.8zM321.3 204.9v5.1zM321.3 204.9h3.8zM323.8 215l-1.2 2.6zM322.6 212.5l1.2 2.5zM325.1 212.5l-1.3 2.5zM323.8 215l1.3 2.6zM325.1 204.9v5.1zM325.1 210h3.8zM325.1 212.5h5.1z"/>
<path d="M325.1 217.6h5.1zM328.9 204.9v5.1zM328.9 204.9h3.8zM331.4 215l-1.2 2.6zM330.2 212.5l1.2 2.5zM332.7 212.5l-1.3 2.5zM331.4 215l1.3 2.6zM332.7 204.9v5.1zM332.7 210h3.8zM332.7 212.5h5.1zM332.7 217.6h5.1zM336.5 204.9v5.1z"/>
<path d="M336.5 204.9h3.8zM339 215l-1.2 2.6zM337.8 212.5l1.2 2.5zM340.3 212.5l-1.3 2.5zM339 215l1.3 2.6zM340.3 204.9v5.1zM340.3 210h3.8zM340.3 212.5h5.1zM340.3 217.6h5.1zM344.1 204.9v5.1zM344.1 204.9h3.8zM346.7 215l-1.3 2.6z"/>
<path d="M345.4 212.5l1.3 2.5zM347.9 212.5l-1.2 2.5zM346.7 215l1.2 2.6zM347.9 204.9v5.1zM347.9 210h3.8zM347.9 212.5h5.1zM347.9 217.6h5.1zM351.7 204.9v5.1zM351.7 204.9h3.9zM354.3 215l-1.3 2.6zM353 212.5l1.3 2.5zM355.6 212.5l-1.3 2.5z"/>
<path d="M354.3 215l1.3 2.6zM355.6 204.9v5.1zM355.6 210h3.8zM355.6 212.5h5zM355.6 217.6h5zM359.4 204.9v5.1zM359.4 204.9h3.8zM361.9 215l-1.3 2.6zM360.6 212.5l1.3 2.5zM363.2 212.5l-1.3 2.5zM361.9 215l1.3 2.6zM363.2 204.9v5.1z"/>
<path d="M363.2 210h3.8zM363.2 212.5h5.1zM363.2 217.6h5.1zM367 204.9v5.1zM367 204.9h3.8zM369.5 215l-1.2 2.6zM368.3 212.5l1.2 2.5zM370.8 212.5l-1.3 2.5zM369.5 215l1.3 2.6zM370.8 204.9v5.1zM370.8 210h3.8zM370.8 212.5h5.1z"/>
<path d="M370.8 217.6h5.1zM374.6 204.9v5.1zM374.6 204.9h3.8zM375.9 212.5l1.2 2.5zM377.1 215l-1.2 2.6zM377.1 215l1.3 2.6zM378.4 204.9v5.1zM378.4 210h3.8zM378.4 217.6h7.6zM382.2 204.9v5.1zM382.2 204.9h3.8zM386 217.6h1.1z"/>
<path d="M386 204.9v5.1zM386 210h3.8zM386 211.2v1.5zM386 213.7v1.5zM386 216.2v1.4zM386 217.6v1.5zM388.1 217.6h1zM390.1 217.6h1zM16.5 224.2h3.8zM64.8 235.4v2.5zM64.8 230.3v2.5zM64.8 225.2v2.5z"/>
<path d="M64.8 232.8v2.6zM64.8 220.1v5.1zM82.5 230.3v2.5zM82.5 225.2v2.5zM82.5 229.8v.5zM82.5 227.7v.6zM82.5 235.4v2.5zM82.5 232.8v2.6zM82.5 222.7v2.5zM64.8 220.1h17.7zM85.1 220.1h2.5zM85.1 222.7h2.5z"/>
<path d="M82.5 222.7h2.6zM82.5 220.1h2.6zM102.9 222.7h2.5zM105.4 222.7h2.5zM107.9 235.4v2.5zM107.9 222.7v12.7zM118.1 230.3v2.5zM118.1 225.2v2.5zM118.1 229.8v.5zM118.1 227.7v.6zM118.1 235.4v2.5zM118.1 220.1v2.6z"/>
<path d="M118.1 232.8v2.6zM118.1 222.7v2.5zM146 225.2h17.8zM148.6 223.2h5.2zM158.7 232.8h5.1zM161.3 220.1v15.3zM161.3 235.4v5zM163.8 230.3h5.1zM163.8 220.1h5.1zM163.8 225.2h3.1zM163.8 232.8h5.1zM163.8 235.4h5.1z"/>
<path d="M161.3 220.1h2.5zM161.3 235.4h2.5zM153.6 230.3h10.2zM194.3 222.7h2.5zM189.2 220.1h5.1zM191.2 227.7h3.1zM191.2 230.3h3.1zM194.3 227.7h5.1zM196.8 222.7v2.5zM196.8 225.2h2.6zM199.4 222.7v2.5zM199.4 227.7v22.9z"/>
<path d="M199.4 227.7h15.2zM212.1 217.6v5.1zM212.1 222.7v2.5zM214.6 225.2v2.5zM212.1 225.2h2.5zM214.6 225.2h2.5zM217.1 217.6v5.1zM217.1 222.7v2.5zM295.6 228.3h7.9zM296.2 233.4h7.3zM306 230.3h3.9zM306 232.8h80z"/>
<path d="M309.9 227.7v2.6zM309.9 227.7h76.1zM309.9 220.1v1.4zM309.9 222.5v1.5zM309.9 225v1.5zM386 227.7v2.6zM386 230.3h5.1zM386 220.1v1.4zM386 222.5v1.5zM386 225v1.5zM386 232.8v2.6zM386 235.4h3.8z"/>
<path d="M389.8 232.8v2.6zM389.8 232.8h1.3zM400 224.2h3.8zM26.7 253.1v2.6zM26.7 257.7v.5zM26.7 255.7v.5zM26.7 250.6v2.5zM34.3 253.1v2.6zM34.3 257.7v.5zM34.3 255.7v.5zM34.3 250.6v2.5zM26.7 250.6h7.6z"/>
<path d="M41.9 253.1v2.6zM41.9 257.7v.5zM41.9 255.7v.5zM34.3 250.6h7.6zM41.9 250.6v2.5zM49.5 253.1v2.6zM49.5 257.7v.5zM49.5 255.7v.5zM41.9 250.6h7.6zM49.5 250.6v2.5zM57.1 253.1v2.6zM57.1 257.7v.5z"/>
<path d="M57.1 255.7v.5zM49.5 250.6h7.6zM57.1 250.6v2.5zM64.8 253.1v2.6zM64.8 257.7v.5zM64.8 255.7v.5zM57.1 250.6h7.7zM64.8 250.6v2.5zM72.4 253.1v2.6zM72.4 257.7v.5zM72.4 255.7v.5zM64.8 250.6h7.6z"/>
<path d="M72.4 250.6v2.5zM80 253.1v2.6zM80 257.7v.5zM80 255.7v.5zM72.4 250.6h7.6zM80 250.6v2.5zM87.6 253.1v2.6zM87.6 257.7v.5zM87.6 255.7v.5zM87.6 250.6v2.5zM95.2 245.5v2.6zM95.2 253.1v2.6z"/>
<path d="M95.2 257.7v.5zM95.2 255.7v.5zM80 250.6h15.2zM95.2 248.1v2.5zM95.2 250.6v2.5zM105.4 245.5v2.6zM105.4 253.1v2.6zM105.4 255.7v.5zM105.4 257.7v.5zM105.4 248.1v5zM153.6 230.3v22.8zM158.7 253.1h3.1z"/>
<path d="M153.6 253.1h5.1zM161.3 240.4v2.6zM168.9 250.6h5.1zM168.9 255.7h5.1zM176.5 250.6v2.5zM174 250.6h2.5zM176.5 253.1v2.6zM174 255.7h2.5zM179 253.1h3.2zM176.5 253.1h2.5zM189.2 250.6h5.1zM189.2 255.7h5.1z"/>
<path d="M194.3 255.7h7.6zM194.3 250.6h5.1zM20.3 274.7h379.7zM26.7 265.8v2.6zM26.7 258.2v2.6zM26.7 260.8v2.5zM26.7 263.3h7.6zM26.7 263.3v2.5zM34.3 258.2v2.6zM34.3 260.8v2.5zM41.9 258.2v2.6zM34.3 263.3h7.6z"/>
<path d="M41.9 260.8v2.5zM49.5 258.2v2.6zM41.9 263.3h7.6zM49.5 260.8v2.5zM57.1 258.2v2.6zM49.5 263.3h7.6zM57.1 260.8v2.5zM64.8 258.2v2.6zM57.1 263.3h7.7zM64.8 260.8v2.5zM67.8 274.7v3.8zM72.4 258.2v2.6z"/>
<path d="M64.8 263.3h7.6zM72.4 260.8v2.5zM80 258.2v2.6zM72.4 263.3h7.6zM80 260.8v2.5zM87.6 258.2v2.6zM87.6 260.8v2.5zM95.2 258.2v2.6zM80 263.3h15.2zM95.2 260.8v2.5zM105.4 265.8v2.6zM105.4 258.2v2.6z"/>
<path d="M105.4 260.8v5zM115.3 274.7v3.8zM162.7 274.7v3.8zM210.2 274.7v3.8zM257.6 274.7v3.8zM305.1 274.7v3.8zM352.5 274.7v3.8zM400 264.5v.1zM400 268.4v6.2zM400 274.6h.1zM400 22.1v252.6z"/>
<circle cx="54.6" cy="55.1" r=".51"/>
<circle cx="59.7" cy="50" r=".51"/>
<circle cx="140.9" cy="44.9" r=".51"/>
<circle cx="64.8" cy="60.2" r=".51"/>
<circle cx="339" cy="65.2" r=".51"/>
<circle cx="237.5" cy="98.2" r=".51"/>
<circle cx="311.1" cy="83" r=".51"/>
<circle cx="311.1" cy="85.5" r=".51"/>
<circle cx="311.1" cy="88.1" r=".51"/>
<circle cx="311.1" cy="95.7" r=".51"/>
<circle cx="311.1" cy="93.2" r=".51"/>
<circle cx="311.1" cy="98.2" r=".51"/>
<circle cx="311.1" cy="90.6" r=".51"/>
<circle cx="237.5" cy="103.3" r=".51"/>
<circle cx="237.5" cy="110.9" r=".51"/>
<circle cx="237.5" cy="105.9" r=".51"/>
<circle cx="237.5" cy="100.8" r=".51"/>
<circle cx="237.5" cy="113.5" r=".51"/>
<circle cx="237.5" cy="108.4" r=".51"/>
<circle cx="311.1" cy="100.8" r=".51"/>
<circle cx="146" cy="138.9" r=".51"/>
<circle cx="214.6" cy="121.1" r=".51"/>
<circle cx="64.8" cy="149" r=".51"/>
<circle cx="339" cy="144" r=".51"/>
<circle cx="350.5" cy="159.2" r=".51"/>
<circle cx="354.3" cy="144" r=".51"/>
<circle cx="354.3" cy="159.2" r=".51"/>
<circle cx="191.7" cy="177" r=".51"/>
<circle cx="191.7" cy="179.5" r=".51"/>
<circle cx="212.1" cy="177" r=".51"/>
<circle cx="214.6" cy="174.4" r=".51"/>
<circle cx="214.6" cy="171.9" r=".51"/>
<circle cx="217.1" cy="174.4" r=".51"/>
<circle cx="115.6" cy="192.2" r=".51"/>
<circle cx="191.7" cy="192.2" r=".51"/>
<circle cx="191.7" cy="182.1" r=".51"/>
<circle cx="80" cy="207.4" r=".51"/>
<circle cx="146" cy="202.4" r=".51"/>
<circle cx="158.7" cy="217.6" r=".51"/>
<circle cx="158.7" cy="215" r=".51"/>
<circle cx="201.9" cy="204.9" r=".51"/>
<circle cx="64.8" cy="220.1" r=".51"/>
<circle cx="82.5" cy="220.1" r=".51"/>
<circle cx="161.3" cy="220.1" r=".51"/>
<circle cx="161.3" cy="235.4" r=".51"/>
<circle cx="199.4" cy="227.7" r=".51"/>
<circle cx="214.6" cy="225.2" r=".51"/>
<circle cx="34.3" cy="250.6" r=".51"/>
<circle cx="41.9" cy="250.6" r=".51"/>
<circle cx="49.5" cy="250.6" r=".51"/>
<circle cx="57.1" cy="250.6" r=".51"/>
<circle cx="64.8" cy="250.6" r=".51"/>
<circle cx="72.4" cy="250.6" r=".51"/>
<circle cx="80" cy="250.6" r=".51"/>
<circle cx="95.2" cy="250.6" r=".51"/>
<circle cx="176.5" cy="253.1" r=".51"/>
<circle cx="26.7" cy="263.3" r=".51"/>
<circle cx="34.3" cy="263.3" r=".51"/>
<circle cx="41.9" cy="263.3" r=".51"/>
<circle cx="49.5" cy="263.3" r=".51"/>
<circle cx="57.1" cy="263.3" r=".51"/>
<circle cx="64.8" cy="263.3" r=".51"/>
<circle cx="72.4" cy="263.3" r=".51"/>
<circle cx="80" cy="263.3" r=".51"/>
</g>
<g fill="#000" stroke="#000" stroke-width=".28">
<path d="M24.4 58.6v3.1zM26.2 43.4v3zM32.3 48.5v3zM32.9 53.6v3zM26.2 43.4h14.2zM26.2 46.4h14.2zM24.4 58.6h16zM32.3 48.5h8.1zM32.3 51.5h8.1zM32.9 53.6h7.5zM32.9 56.6h7.5zM40.4 43.4l1.5 1.5z"/>
<path d="M41.9 44.9l-1.5 1.5zM40.4 48.5l1.5 1.5zM41.9 50l-1.5 1.5zM40.4 53.6l1.5 1.5zM41.9 55.1l-1.5 1.5zM372.1 44.9l1.5-1.5zM372.1 44.9l1.5 1.5zM373.6 48.5l-1.5 1.5zM372.1 50l1.5 1.5zM373.6 53.6l-1.5 1.5zM372.1 55.1l1.5 1.5zM373.6 43.4h14.2z"/>
<path d="M373.6 46.4h14.2zM373.6 58.6h16zM373.6 48.5h8.1zM373.6 51.5h8.1zM373.6 53.6h7.5zM373.6 56.6h7.5zM381.1 53.6v3zM381.7 48.5v3zM387.8 43.4v3zM389.6 58.6v3.1zM30.2 63.7v3zM24.4 61.7h16z"/>
<path d="M30.2 63.7h10.2zM30.2 66.7h10.2zM40.4 58.6l1.5 1.6zM40.4 61.7l1.5-1.5zM40.4 63.7l1.5 1.5zM41.9 65.2l-1.5 1.5zM283.2 79.6h5.1zM372.1 60.2l1.5-1.6zM372.1 60.2l1.5 1.5zM373.6 68.8l-1.5 1.5zM372.1 70.3l1.5 1.5zM373.6 63.7l-1.5 1.5z"/>
<path d="M372.1 65.2l1.5 1.5zM373.6 61.7h16zM373.6 68.8h13.5zM373.6 71.8h13.5zM373.6 63.7h10.2zM373.6 66.7h10.2zM383.8 63.7v3zM387.1 68.8v3zM252.7 97v18.4zM283.2 79.6v1.7zM283.2 81.3h5.1zM288.3 79.6v1.7z"/>
<path d="M297.4 82.9h.8zM297.4 82.7h.4zM297.5 90.6v5.1zM297.7 82.2l-.3 .5zM297.7 82.5l.1 .2zM297.7 82.2l.5 .7zM299.3 90.6v5.1zM297.5 95.7h1.8zM297.5 90.6h1.8zM252.1 113.5h1.2zM252.1 113.7h1.2zM252.2 113.9h1z"/>
<path d="M252.3 114.1h.8zM252.4 114.4h.6zM252.4 114.6h.6zM252.5 114.8h.4zM252.6 115h.2zM252.1 113.5l.6 1.9zM253.3 113.5l-.6 1.9zM296.5 105.9h3.8zM235.6 133.8h3.8zM80 142.7l-1.3 1.9zM80 142.7l1.3 1.9zM159.4 159.2h3.8z"/>
<path d="M252.7 147.8v18.4zM328.9 143.1h5.1zM328.9 143.1v1.7zM328.9 144.8h5.1zM334 143.1v1.7zM344.1 143.1h5.1zM344.1 143.1v1.7zM344.1 144.8h5.1zM349.2 143.1v1.7zM361.1 149v5.1zM361.1 154.1h1.6zM362.7 149v5.1z"/>
<path d="M361.1 149h1.6zM372.1 150h.9zM372.1 150v3.1zM373 150v3.1zM372.1 153.1h.9zM379.7 151.6l1.5-1.6zM379.7 151.6l1.5 1.5zM381.2 150h15.3zM381.2 153.1h15.3zM396.5 150v3.1zM80 173.2l-1.3 1.9zM80 173.2l1.3 1.9z"/>
<path d="M219.7 163l-1.3 1.9zM219.7 163l1.3 1.9zM252.1 164.3h1.2zM252.1 164.4h1.2zM252.2 164.6h1zM252.2 164.8h.9zM252.3 165h.8zM252.4 165.2h.6zM252.5 165.5h.4zM252.5 165.7h.4zM252.6 165.9h.2zM252.1 164.3l.6 1.9z"/>
<path d="M253.3 164.3l-.6 1.9zM318.7 164.3l-1.2 1.9zM318.7 164.3l1.3 1.9zM348.6 164.3h3.8zM107.9 197.3l-1.2 1.9zM107.9 197.3l1.3 1.9zM194.9 182.1h3.8zM316.8 182.1h3.8zM64.8 202.4l-1.3 1.9zM64.8 202.4l1.2 1.9zM69.8 206.5h5.1zM69.8 206.5v1.8z"/>
<path d="M69.8 215.9h5.1zM69.8 214.2v1.7zM69.8 208.3h5.1zM74.9 206.5v1.8zM69.8 214.2h5.1zM74.9 214.2v1.7zM158.7 207.4l-1.2 1.9zM158.7 207.4l1.3 1.9zM62.9 237.9h3.8zM63.2 227.7v.9zM63.2 228.6h3.1zM66.3 227.7v.9z"/>
<path d="M63.2 227.7h3.1zM80.6 237.9h3.9zM106 237.9h3.9zM116.2 237.9h3.8zM118.1 220.1l-1.3 1.9zM118.1 220.1l1.3 1.9zM95.2 245.5l-1.2 1.9zM95.2 245.5l1.3 1.9zM105.4 245.5l-1.3 1.9zM105.4 245.5l1.3 1.9zM159.4 243h3.8zM313.7 249.3h86.3z"/>
<path d="M313.7 254.4h86.3zM313.7 259.5h58.4zM372.1 259.5h27.9zM372.1 259.5v5.1zM24.8 268.4h3.8zM103.5 268.4h3.8zM313.7 264.6h58.4zM313.7 269.7h86.3zM372.1 264.6h27.9zM400 268.4v1.3z"/>
</g>
<path d="M16.5 18.2v260.3zM16.5 18.2h387.3zM16.5 278.5h387.3zM403.8 18.2v260.3z" fill="#000" stroke="#000" stroke-width=".32"/>
<g fill="#000" stroke="#000" stroke-width=".61">
<path d="M20.3 22.1v252.6zM20.3 22.1h379.7zM168.9 93.2v25.4zM168.9 93.2h15.2zM245.1 93.2v38.1zM245.1 93.2h15.2zM318.7 88.1h1.3zM318.7 85.5h1.3zM318.7 83h1.3zM318.7 93.2h1.3zM318.7 90.6h1.3zM318.7 98.2h1.3z"/>
<path d="M318.7 95.7h1.3zM322.6 88.1h1.2zM322.6 85.5h1.2zM322.6 83h1.2zM322.6 93.2h1.2zM322.6 90.6h1.2zM322.6 98.2h1.2zM322.6 95.7h1.2zM168.9 118.6h15.2zM184.1 93.2v25.4zM318.7 100.8h1.3zM318.7 103.3h1.3z"/>
<path d="M322.6 100.8h1.2zM322.6 103.3h1.2zM168.9 126.2v30.5zM168.9 126.2h15.2zM245.1 131.3h15.2zM260.3 93.2v38.1zM168.9 156.7h15.2zM184.1 126.2v30.5zM245.1 144v38.1zM245.1 144h15.2zM288.3 141.4v40.7zM288.3 141.4h20.3z"/>
<path d="M168.9 164.3h15.2zM184.1 164.3v30.5zM87.6 199.8v25.4zM87.6 199.8h15.3zM168.9 164.3v30.5zM168.9 194.8h15.2zM245.1 182.1h15.2zM260.3 144v38.1zM288.3 182.1h20.3zM308.6 141.4v40.7zM168.9 210v27.9zM168.9 210h20.3z"/>
<path d="M87.6 225.2h15.3zM102.9 199.8v25.4zM168.9 237.9h20.3zM189.2 210v27.9zM283.2 244.3v30.4zM313.7 254.4v5.1zM313.7 249.3v5.1zM313.7 244.3v5zM313.7 244.3h86.3zM283.2 244.3h30.5zM400 254.4v5.1zM400 249.3v5.1z"/>
<path d="M400 244.3v5zM400 22.1v222.2zM20.3 274.7h262.9zM283.2 274.7h30.5zM313.7 274.7h86.3zM313.7 269.7v5zM313.7 264.6v5.1zM313.7 259.5v5.1zM400 268.4v6.3zM400 264.6v3.8zM400 259.5v5.1z"/>
</g>
<g fill="none" stroke="#000" stroke-width=".21">
<circle cx="106.4" cy="98.2" r=".99"/>
<circle cx="248.6" cy="80.5" r="1"/>
<circle cx="271.5" cy="80.5" r="1"/>
<circle cx="86.6" cy="113.5" r=".99"/>
<circle cx="86.6" cy="116" r=".99"/>
<circle cx="106.4" cy="116" r=".99"/>
<circle cx="106.4" cy="110.9" r=".99"/>
<circle cx="106.4" cy="108.4" r=".99"/>
<circle cx="106.4" cy="105.9" r=".99"/>
<circle cx="106.4" cy="103.3" r=".99"/>
<circle cx="106.4" cy="100.8" r=".99"/>
<circle cx="106.4" cy="113.5" r=".99"/>
<circle cx="167.9" cy="116" r=".99"/>
<circle cx="106.4" cy="136.3" r=".99"/>
<circle cx="106.4" cy="138.9" r=".99"/>
<circle cx="106.4" cy="133.8" r=".99"/>
<circle cx="244.1" cy="126.2" r="1"/>
<circle cx="244.1" cy="128.7" r="1"/>
<circle cx="86.6" cy="149" r=".99"/>
<circle cx="86.6" cy="151.6" r=".99"/>
<circle cx="106.4" cy="146.5" r=".99"/>
<circle cx="106.4" cy="149" r=".99"/>
<circle cx="106.4" cy="144" r=".99"/>
<circle cx="106.4" cy="141.4" r=".99"/>
<circle cx="106.4" cy="151.6" r=".99"/>
<circle cx="167.9" cy="154.1" r=".99"/>
<circle cx="287.3" cy="144" r="1"/>
<circle cx="86.6" cy="179.5" r=".99"/>
<circle cx="106.4" cy="177" r=".99"/>
<circle cx="106.4" cy="171.9" r=".99"/>
<circle cx="106.4" cy="169.4" r=".99"/>
<circle cx="106.4" cy="174.4" r=".99"/>
<circle cx="106.4" cy="166.8" r=".99"/>
<circle cx="106.4" cy="179.5" r=".99"/>
<circle cx="106.4" cy="164.3" r=".99"/>
<circle cx="244.1" cy="179.5" r="1"/>
<circle cx="244.1" cy="177" r="1"/>
<circle cx="86.6" cy="182.1" r=".99"/>
<circle cx="106.4" cy="182.1" r=".99"/>
<circle cx="185.1" cy="192.2" r=".99"/>
<circle cx="185.1" cy="189.7" r=".99"/>
<circle cx="86.6" cy="202.4" r=".99"/>
<circle cx="214.6" cy="211.5" r=".99"/>
<circle cx="167.9" cy="225.2" r=".99"/>
<circle cx="190.2" cy="230.3" r=".99"/>
<circle cx="190.2" cy="227.7" r=".99"/>
<circle cx="162.8" cy="253.1" r=".99"/>
<circle cx="183.1" cy="253.1" r=".99"/>
</g>
<g fill="#000" stroke="#000" stroke-width=".21">
<path d="M295.6 77.9h.8v5.1h-.8zM337 152.1h4.1v.5h-4.1zM337 153.1h4.1v.5h-4.1zM352.2 152.1h4.1v.5h-4.1zM352.2 153.1h4.1v.5h-4.1zM373.7 149.9h.9v3.3h-.9zM316.7 172.4h4.1v.5h-4.1zM316.7 173.4h4.1v.5h-4.1zM63.1 229.4h3.3v.9h-3.3zM80.5 228.3h4.1v.5h-4.1zM80.5 229.3h4.1v.5h-4.1zM116.1 228.3h4v.5h-4z"/>
<path d="M116.1 229.3h4v.5h-4zM24.6 256.2h4.1v.5h-4.1zM24.6 257.2h4.1v.5h-4.1zM32.3 256.2h4v.5h-4zM32.3 257.2h4v.5h-4zM39.9 256.2h4v.5h-4zM39.9 257.2h4v.5h-4zM47.5 256.2h4.1v.5h-4.1zM47.5 257.2h4.1v.5h-4.1zM55.1 256.2h4.1v.5h-4.1zM55.1 257.2h4.1v.5h-4.1zM62.7 256.2h4.1v.5h-4.1z"/>
<path d="M62.7 257.2h4.1v.5h-4.1zM70.4 256.2h4v.5h-4zM70.4 257.2h4v.5h-4zM78 256.2h4v.5h-4zM78 257.2h4v.5h-4zM85.6 256.2h4.1v.5h-4.1zM85.6 257.2h4.1v.5h-4.1zM93.2 256.2h4.1v.5h-4.1zM93.2 257.2h4.1v.5h-4.1zM103.4 257.2h4v.5h-4zM103.4 256.2h4v.5h-4z"/>
</g>
<g fill="#000" stroke="#000" stroke-width=".42">
<path d="M242.5 75.4v10.1zM260.3 75.4l10.2 5.1zM87.6 95.7v22.9zM87.6 95.7h17.8zM260.3 75.4v10.1zM260.3 85.5l10.2-5zM317.5 80.5h7.6zM317.5 80.5v25.4zM87.6 118.6h17.8zM105.4 95.7v22.9zM325.1 80.5v25.4zM317.5 105.9h7.6z"/>
<path d="M87.6 131.3v22.8zM87.6 131.3h17.8zM87.6 154.1h17.8zM105.4 131.3v22.8zM87.6 161.7v22.9zM87.6 161.7h17.8zM87.6 184.6h17.8zM105.4 161.7v22.9zM209.5 217.6h10.2zM168.9 248.1v10.1zM189.2 248.1v10.1z"/>
</g>
<path d="M242.5 75.4a5.1 5.1 0 0 1 5.1 5.1 5.1 5.1 0 0 1-5.1 5M209.5 217.6a5.1 5.1 0 0 1 5.1-5.1 5.1 5.1 0 0 1 5.1 5.1M168.9 248.1a5.1 5.1 0 0 0-5.1 5 5.1 5.1 0 0 0 5.1 5.1M189.2 248.1a5.1 5.1 0 0 0-5.1 5 5.1 5.1 0 0 0 5.1 5.1" fill="none" stroke="#000" stroke-width=".42"/>
<g fill="#000" stroke="#000" stroke-width=".76">
<path d="M344.1 80.5l2.6-2.6zM346.7 77.9h25.4zM41.9 90.6h25.4zM67.3 90.6l2.5 2.6zM41.9 85.5h104.1zM146 85.5l5.1 5.1zM207 98.2v86.4zM146 85.5h71.1zM217.1 85.5l5.1 5.1zM344.1 80.5v20.3zM267.9 146.5v38.1zM328.9 156.7v27.9z"/>
<path d="M69.8 93.2v73.6zM222.2 90.6v71.1zM151.1 90.6v91.5zM207 184.6l2.5 2.5zM209.5 187.1h61zM267.9 184.6l2.6 2.5zM270.5 187.1h55.9zM328.9 184.6l-2.5 2.5z"/>
</g>
<use href="#words"/>
</svg>
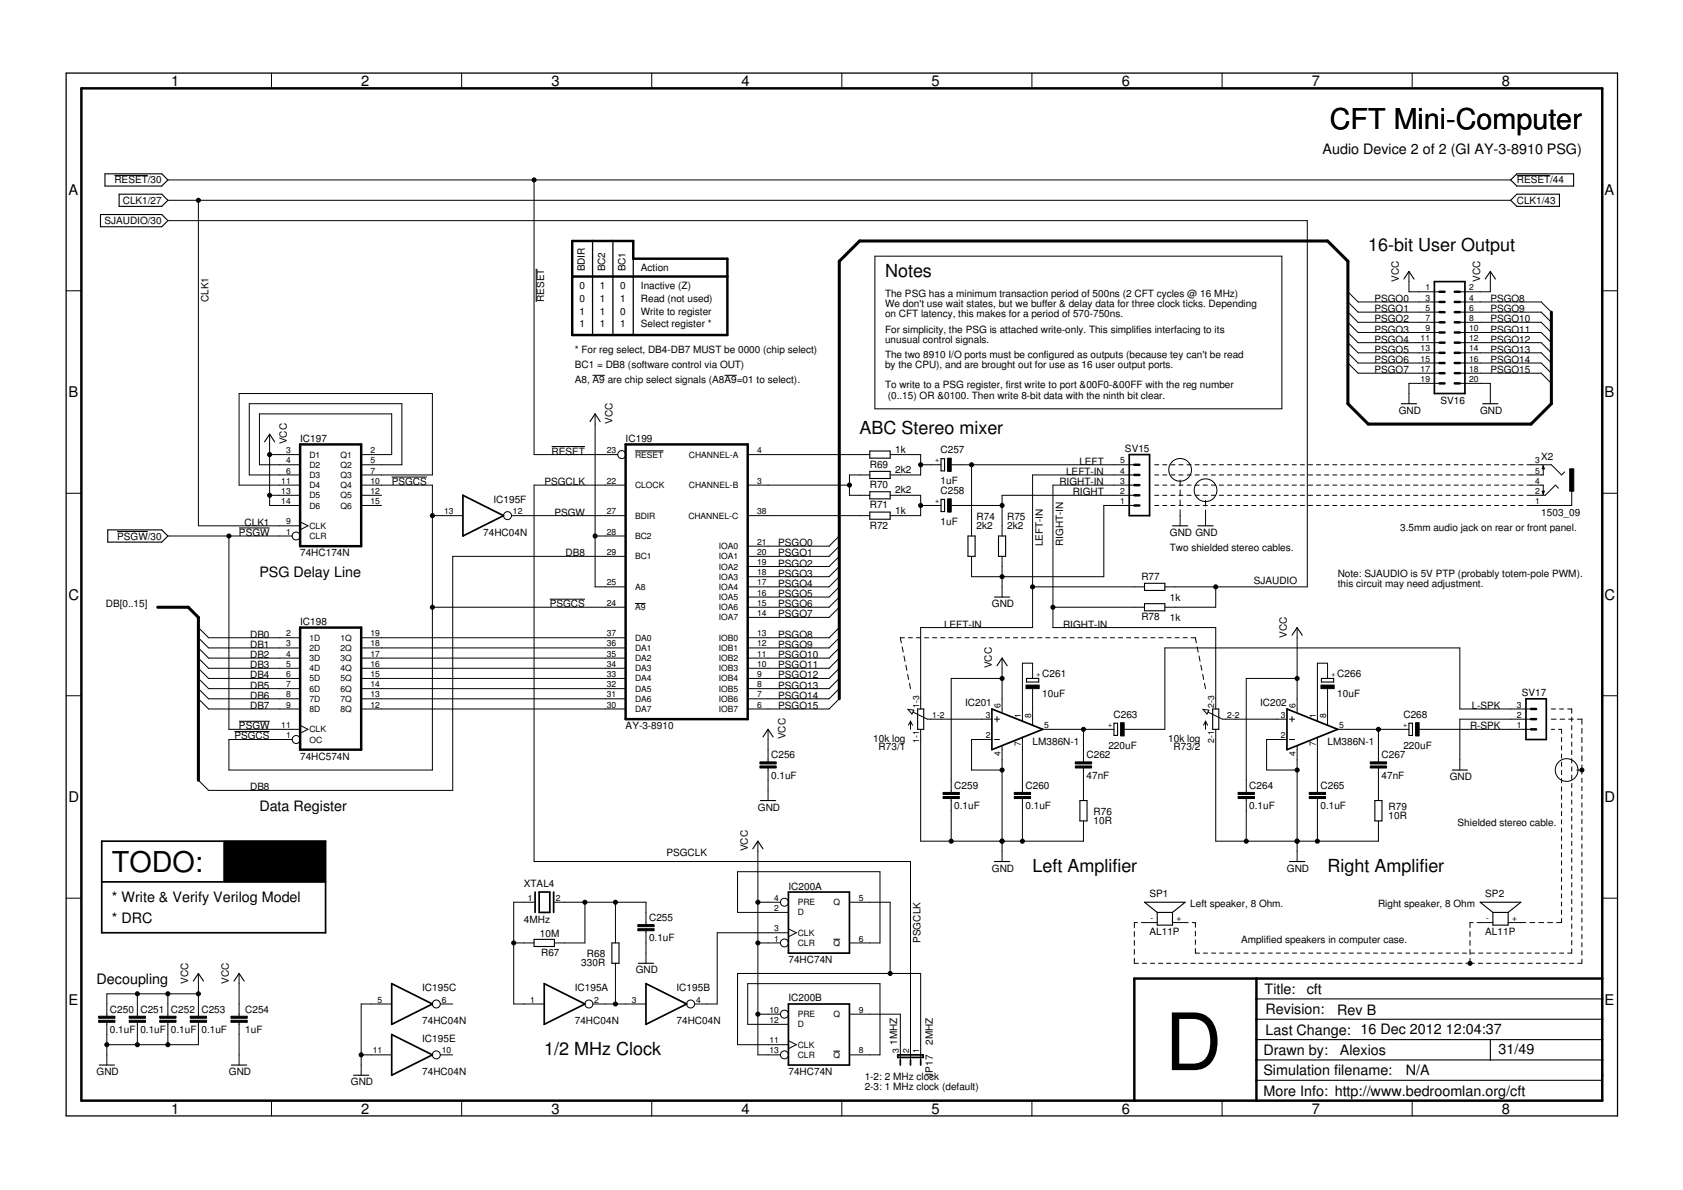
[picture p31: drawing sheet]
<svg xmlns="http://www.w3.org/2000/svg" width="420mm" height="297mm" viewBox="0 0 420 297" stroke-linecap="round" stroke-linejoin="round" font-family="sans-serif">
<defs><g id="words">
<text font-size="19.7" x="290.8" y="267.1">D</text>
<g font-size="7.2">
<text x="332" y="32.2">CFT Mini-Computer</text>
<text x="27.9" y="217.6">TODO:</text>
</g>
<g font-size="4.5">
<text x="341.6" y="62.7">16-bit User Output</text>
<text x="221" y="69">Notes</text>
<text x="214.6" y="108.4">ABC Stereo mixer</text>
<text x="257.8" y="217.6">Left Amplifier</text>
<text x="331.4" y="217.6">Right Amplifier</text>
<text x="135.9" y="263.3">1/2 MHz Clock</text>
</g>
<g font-size="3.7">
<text x="42.7" y="21.5">1</text>
<text x="90.2" y="21.5">2</text>
<text x="137.7" y="21.5">3</text>
<text x="185.1" y="21.5">4</text>
<text x="232.6" y="21.5">5</text>
<text x="280" y="21.5">6</text>
<text x="327.5" y="21.5">7</text>
<text x="375" y="21.5">8</text>
<text x="17.1" y="48.6">A</text>
<text x="400.6" y="48.6">A</text>
<text x="17.1" y="99.2">B</text>
<text x="400.6" y="99.2">B</text>
<text x="17.1" y="149.7">C</text>
<text x="400.6" y="149.7">C</text>
<text x="17.1" y="200.2">D</text>
<text x="400.6" y="200.2">D</text>
<text x="17.1" y="250.8">E</text>
<text x="400.6" y="250.8">E</text>
<text x="42.7" y="277.9">1</text>
<text x="90.2" y="277.9">2</text>
<text x="137.7" y="277.9">3</text>
<text x="185.1" y="277.9">4</text>
<text x="232.6" y="277.9">5</text>
<text x="280" y="277.9">6</text>
<text x="327.5" y="277.9">7</text>
<text x="375" y="277.9">8</text>
</g>
<g font-size="3.6">
<text x="330.2" y="38.6">Audio Device 2 of 2 (GI AY-3-8910 PSG)</text>
<text x="64.8" y="144">PSG Delay Line</text>
<text x="64.8" y="202.4">Data Register</text>
<text x="27.9" y="225.2">* Write &amp; Verify Verilog Model</text>
<text x="27.9" y="230.3">* DRC</text>
<text x="24.1" y="245.5">Decoupling</text>
<text x="315.7" y="248.1">Title:</text>
<text x="326.2" y="248.2">cft</text>
<text x="315.9" y="253.2">Revision:</text>
<text x="333.8" y="253.3">Rev B</text>
<text x="315.4" y="263.3">Drawn by:</text>
<text x="315.9" y="258.2">Last Change: 16 Dec 2012</text>
<text x="334.5" y="263.3">Alexios</text>
<text x="361" y="258.1">12:04:37</text>
<text x="374.1" y="263.2">31/49</text>
<text x="315.4" y="268.4">Simulation filename:</text>
<text x="351" y="268.4">N/A</text>
<text x="315.4" y="273.5">More Info: http://www.bedroomlan.org/cft</text>
</g>
<g font-size="2.5">
<text x="28.6" y="45.8">RESET/30</text>
<text x="378.7" y="45.8">RESET/44</text>
<text x="30.6" y="50.9">CLK1/27</text>
<text x="378.7" y="50.9">CLK1/43</text>
<text x="26.1" y="56">SJAUDIO/30</text>
<text x="146" y="67.8" transform="rotate(-90 146 67.8)">BDIR</text>
<text x="151.1" y="67.8" transform="rotate(-90 151.1 67.8)">BC2</text>
<text x="156.2" y="67.8" transform="rotate(-90 156.2 67.8)">BC1</text>
<text x="160" y="67.8">Action</text>
<text x="349.2" y="70.3" transform="rotate(-90 349.2 70.3)">VCC</text>
<text x="369.5" y="70.3" transform="rotate(-90 369.5 70.3)">VCC</text>
<text x="52.1" y="75.4" transform="rotate(-90 52.1 75.4)">CLK1</text>
<text x="135.9" y="75.4" transform="rotate(-90 135.9 75.4)">RESET</text>
<text x="144.6" y="72.2">0</text>
<text x="144.6" y="75.4">0</text>
<text x="149.7" y="72.2">1</text>
<text x="149.7" y="75.4">1</text>
<text x="154.8" y="72.2">0</text>
<text x="154.8" y="75.4">1</text>
<text x="160" y="72.2">Inactive (Z)</text>
<text x="160" y="75.4">Read (not used)</text>
<text x="221" y="74.1">The PSG has a minimum transaction period of 500ns (2 CFT cycles @ 16 MHz)</text>
<text x="221" y="76.7">We don't use wait states, but we buffer &amp; delay data for three clock ticks. Depending</text>
<text x="343.1" y="75.4">PSGO0</text>
<text x="343.1" y="77.9">PSGO1</text>
<text x="372.1" y="75.4">PSGO8</text>
<text x="372.1" y="77.9">PSGO9</text>
<text x="144.6" y="78.6">1</text>
<text x="144.6" y="81.7">1</text>
<text x="149.7" y="78.6">1</text>
<text x="149.7" y="81.7">1</text>
<text x="154.8" y="78.6">0</text>
<text x="154.8" y="81.7">1</text>
<text x="160" y="78.6">Write to register</text>
<text x="160" y="81.7">Select register *</text>
<text x="221" y="79.2">on CFT latency, this makes for a period of 570-750ns.</text>
<text x="221" y="83">For simplicity, the PSG is attached write-only. This simplifies interfacing to its</text>
<text x="343.1" y="80.5">PSGO2</text>
<text x="343.1" y="83">PSGO3</text>
<text x="372.1" y="80.5">PSGO10</text>
<text x="372.1" y="83">PSGO11</text>
<text x="143.5" y="88.1">* For reg select, DB4-DB7 MUST be 0000 (chip select)</text>
<text x="221" y="85.5">unusual control signals.</text>
<text x="221" y="89.3">The two 8910 I/O ports must be configured as outputs (because tey can't be read</text>
<text x="343.1" y="85.5">PSGO4</text>
<text x="343.1" y="88.1">PSGO5</text>
<text x="372.1" y="85.5">PSGO12</text>
<text x="372.1" y="88.1">PSGO13</text>
<text x="143.5" y="91.9">BC1 = DB8 (software control via OUT)</text>
<text x="143.5" y="95.7">A8, A9 are chip select signals (A8A9=01 to select).</text>
<text x="221" y="91.9">by the CPU), and are brought out for use as 16 user output ports.</text>
<text x="343.1" y="90.6">PSGO6</text>
<text x="343.1" y="93.2">PSGO7</text>
<text x="372.1" y="90.6">PSGO14</text>
<text x="372.1" y="93.2">PSGO15</text>
<text x="221" y="97">To write to a PSG register, first write to port &amp;00F0-&amp;00FF with the reg number</text>
<text x="221.7" y="99.5">(0..15) OR &amp;0100. Then write 8-bit data with the ninth bit clear.</text>
<text x="359.6" y="100.8">SV16</text>
<text x="152.9" y="105.9" transform="rotate(-90 152.9 105.9)">VCC</text>
<text x="349.2" y="103.3">GND</text>
<text x="369.5" y="103.3">GND</text>
<text x="71.6" y="110.9" transform="rotate(-90 71.6 110.9)">VCC</text>
<text x="74.9" y="110.3">IC197</text>
<text x="137.7" y="113.5">RESET</text>
<text x="156.2" y="110.3">IC199</text>
<text x="223.5" y="113">1k</text>
<text x="234.8" y="113.2">C257</text>
<text x="280.8" y="112.7">SV15</text>
<text x="217.1" y="116.8">R69</text>
<text x="223.5" y="118">2k2</text>
<text x="266.2" y="118.6">LEFT-IN</text>
<text x="269.5" y="116">LEFT</text>
<text x="384.8" y="114.7">X2</text>
<text x="97.8" y="121.1">PSGCS</text>
<text x="123.2" y="125.5">IC195F</text>
<text x="135.9" y="121.1">PSGCLK</text>
<text x="217.1" y="121.8">R70</text>
<text x="223.5" y="123.1">2k2</text>
<text x="234.8" y="120.8">1uF</text>
<text x="234.8" y="123.4">C258</text>
<text x="264.5" y="121.1">RIGHT-IN</text>
<text x="267.8" y="123.6">RIGHT</text>
<text x="61.1" y="131.3">CLK1</text>
<text x="138.4" y="128.7">PSGW</text>
<text x="217.1" y="126.9">R71</text>
<text x="217.1" y="132">R72</text>
<text x="223.5" y="128.2">1k</text>
<text x="234.8" y="131">1uF</text>
<text x="243.8" y="129.8">R74</text>
<text x="251.4" y="129.8">R75</text>
<text x="384.8" y="128.7">1503_09</text>
<text x="29.2" y="134.7">PSGW/30</text>
<text x="59.7" y="133.8">PSGW</text>
<text x="120.6" y="133.8">74HC04N</text>
<text x="194.3" y="136.3">PSGO0</text>
<text x="243.8" y="132">2k2</text>
<text x="251.4" y="132">2k2</text>
<text x="260.3" y="136.3" transform="rotate(-90 260.3 136.3)">LEFT-IN</text>
<text x="265.4" y="136.3" transform="rotate(-90 265.4 136.3)">RIGHT-IN</text>
<text x="292.1" y="137.6">Two shielded stereo cables.</text>
<text x="292.1" y="133.8">GND GND</text>
<text x="349.5" y="132.5">3.5mm audio jack on rear or front panel.</text>
<text x="74.9" y="138.9">74HC174N</text>
<text x="141.2" y="138.9">DB8</text>
<text x="194.3" y="138.9">PSGO1</text>
<text x="194.3" y="141.4">PSGO2</text>
<text x="194.3" y="144">PSGO3</text>
<text x="334" y="144">Note: SJAUDIO is 5V PTP (probably totem-pole PWM).</text>
<text x="194.3" y="146.5">PSGO4</text>
<text x="194.3" y="149">PSGO5</text>
<text x="284.9" y="144.7">R77</text>
<text x="313" y="145.7">SJAUDIO</text>
<text x="334" y="146.5">this circuit may need adjustment.</text>
<text x="26.4" y="151.6">DB[0..15]</text>
<text x="137.3" y="151.6">PSGCS</text>
<text x="194.3" y="151.6">PSGO6</text>
<text x="194.3" y="154.1">PSGO7</text>
<text x="247.6" y="151.6">GND</text>
<text x="284.9" y="154.8">R78</text>
<text x="292.1" y="150">1k</text>
<text x="292.1" y="155.1">1k</text>
<text x="62.5" y="159.2">DB0</text>
<text x="62.5" y="161.7">DB1</text>
<text x="74.9" y="156">IC198</text>
<text x="194.3" y="159.2">PSGO8</text>
<text x="194.3" y="161.7">PSGO9</text>
<text x="235.7" y="156.6">LEFT-IN</text>
<text x="265.4" y="156.6">RIGHT-IN</text>
<text x="321.3" y="159.2" transform="rotate(-90 321.3 159.2)">VCC</text>
<text x="62.5" y="164.3">DB2</text>
<text x="62.5" y="166.8">DB3</text>
<text x="194.3" y="164.3">PSGO10</text>
<text x="194.3" y="166.8">PSGO11</text>
<text x="247.6" y="166.8" transform="rotate(-90 247.6 166.8)">VCC</text>
<text x="62.5" y="169.3">DB4</text>
<text x="62.5" y="171.9">DB5</text>
<text x="194.3" y="169.3">PSGO12</text>
<text x="194.3" y="171.9">PSGO13</text>
<text x="260.2" y="173.9">10uF</text>
<text x="260.2" y="168.9">C261</text>
<text x="333.8" y="173.9">10uF</text>
<text x="333.8" y="168.9">C266</text>
<text x="379.9" y="173.7">SV17</text>
<text x="62.5" y="174.4">DB6</text>
<text x="62.5" y="177">DB7</text>
<text x="194.3" y="174.4">PSGO14</text>
<text x="194.3" y="177">PSGO15</text>
<text x="240.9" y="176.2">IC201</text>
<text x="278" y="179.2">C263</text>
<text x="314.6" y="176.2">IC202</text>
<text x="350.4" y="179.2">C268</text>
<text x="367.4" y="177">L-SPK</text>
<text x="58.5" y="184.6">PSGCS</text>
<text x="59.7" y="182">PSGW</text>
<text x="156.2" y="182">AY-3-8910</text>
<text x="196.1" y="184.6" transform="rotate(-90 196.1 184.6)">VCC</text>
<text x="218" y="185.1">10k log</text>
<text x="257.8" y="185.9">LM386N-1</text>
<text x="291.6" y="185.1">10k log</text>
<text x="331.4" y="185.9">LM386N-1</text>
<text x="367" y="182">R-SPK</text>
<text x="74.9" y="189.7">74HC574N</text>
<text x="192.5" y="189.3">C256</text>
<text x="219.3" y="187.3">R73/1</text>
<text x="271.2" y="189.3">C262</text>
<text x="276.7" y="186.8">220uF</text>
<text x="293" y="187.3">R73/2</text>
<text x="344.9" y="189.3">C267</text>
<text x="350.4" y="186.8">220uF</text>
<text x="62.5" y="197.3">DB8</text>
<text x="192.5" y="194.4">0.1uF</text>
<text x="238.2" y="196.9">C259</text>
<text x="256" y="196.9">C260</text>
<text x="271.2" y="194.4">47nF</text>
<text x="311.9" y="196.9">C264</text>
<text x="329.7" y="196.9">C265</text>
<text x="344.9" y="194.4">47nF</text>
<text x="361.9" y="194.7">GND</text>
<text x="189.2" y="202.4">GND</text>
<text x="238.2" y="202">0.1uF</text>
<text x="256" y="202">0.1uF</text>
<text x="273" y="203.4">R76</text>
<text x="311.9" y="202">0.1uF</text>
<text x="329.7" y="202">0.1uF</text>
<text x="346.7" y="202.1">R79</text>
<text x="273" y="205.7">10R</text>
<text x="346.7" y="204.4">10R</text>
<text x="363.9" y="206.2">Shielded stereo cable.</text>
<text x="166.4" y="213.8">PSGCLK</text>
<text x="186.7" y="212.5" transform="rotate(-90 186.7 212.5)">VCC</text>
<text x="130.8" y="221.4">XTAL4</text>
<text x="247.6" y="217.6">GND</text>
<text x="321.3" y="217.6">GND</text>
<text x="196.8" y="222">IC200A</text>
<text x="287" y="223.9">SP1</text>
<text x="297.1" y="226.5">Left speaker, 8 Ohm.</text>
<text x="344" y="226.5">Right speaker, 8 Ohm</text>
<text x="370.8" y="223.9">SP2</text>
<text x="130.8" y="230.3">4MHz</text>
<text x="134.8" y="233.9">10M</text>
<text x="162" y="229.9">C255</text>
<text x="287" y="233.5">AL11P</text>
<text x="370.8" y="233.5">AL11P</text>
<text x="135.1" y="238.7">R67</text>
<text x="146.5" y="239">R68</text>
<text x="162" y="235">0.1uF</text>
<text x="229.8" y="235.4" transform="rotate(-90 229.8 235.4)">PSGCLK</text>
<text x="309.8" y="235.4">Amplified speakers in computer case.</text>
<text x="47" y="245.5" transform="rotate(-90 47 245.5)">VCC</text>
<text x="57.1" y="245.5" transform="rotate(-90 57.1 245.5)">VCC</text>
<text x="145.1" y="241.2">330R</text>
<text x="158.7" y="243">GND</text>
<text x="196.8" y="240.5">74HC74N</text>
<text x="105.4" y="247.4">IC195C</text>
<text x="143.5" y="247.4">IC195A</text>
<text x="168.9" y="247.4">IC195B</text>
<text x="196.8" y="250">IC200B</text>
<text x="27.4" y="257.9">0.1uF</text>
<text x="27.4" y="252.8">C250</text>
<text x="35" y="257.9">0.1uF</text>
<text x="35" y="252.8">C251</text>
<text x="42.7" y="257.9">0.1uF</text>
<text x="42.7" y="252.8">C252</text>
<text x="50.3" y="257.9">0.1uF</text>
<text x="50.3" y="252.8">C253</text>
<text x="61.2" y="257.9">1uF</text>
<text x="61.2" y="252.8">C254</text>
<text x="105.4" y="255.7">74HC04N</text>
<text x="143.5" y="255.7">74HC04N</text>
<text x="168.9" y="255.7">74HC04N</text>
<text x="105.4" y="260.1">IC195E</text>
<text x="224" y="260.8" transform="rotate(-90 224 260.8)">1MHZ</text>
<text x="232.9" y="260.8" transform="rotate(-90 232.9 260.8)">2MHZ</text>
<text x="24.1" y="268.4">GND</text>
<text x="57.1" y="268.4">GND</text>
<text x="105.4" y="268.4">74HC04N</text>
<text x="196.8" y="268.4">74HC74N</text>
<text x="215.9" y="269.7">1-2: 2 MHz clock</text>
<text x="232.9" y="269" transform="rotate(-90 232.9 269)">JP17</text>
<text x="87.6" y="270.9">GND</text>
<text x="215.9" y="272.2">2-3: 1 MHz clock (default)</text>
</g>
<g font-size="2.1">
<text x="355.8" y="72.5">1</text>
<text x="355.8" y="75">3</text>
<text x="355.8" y="77.6">5</text>
<text x="366.8" y="72.5">2</text>
<text x="366.8" y="75">4</text>
<text x="366.8" y="77.6">6</text>
<text x="355.8" y="80.1">7</text>
<text x="355.8" y="82.6">9</text>
<text x="366.8" y="80.1">8</text>
<text x="366.8" y="82.6">10</text>
<text x="354.7" y="85.2">11</text>
<text x="354.7" y="87.7">13</text>
<text x="366.8" y="85.2">12</text>
<text x="366.8" y="87.7">14</text>
<text x="354.7" y="90.3">15</text>
<text x="354.7" y="92.8">17</text>
<text x="354.7" y="95.3">19</text>
<text x="366.8" y="90.3">16</text>
<text x="366.8" y="92.8">18</text>
<text x="366.8" y="95.3">20</text>
<text x="71.4" y="113.1">3</text>
<text x="92.5" y="113.1">2</text>
<text x="151.5" y="113.1">23</text>
<text x="189" y="113.1">4</text>
<text x="71.4" y="115.7">4</text>
<text x="71.4" y="118.2">6</text>
<text x="77.3" y="114.2">D1</text>
<text x="77.3" y="116.8">D2</text>
<text x="77.3" y="119.3">D3</text>
<text x="85" y="114.2">Q1</text>
<text x="85" y="116.8">Q2</text>
<text x="85" y="119.3">Q3</text>
<text x="92.5" y="115.7">5</text>
<text x="92.5" y="118.2">7</text>
<text x="158.5" y="114.2">RESET</text>
<text x="172" y="114.2">CHANNEL-A</text>
<text x="279.7" y="118.2">4</text>
<text x="279.7" y="115.7">5</text>
<text x="383.2" y="115.7">3</text>
<text x="383.2" y="118.2">5</text>
<text x="70.2" y="120.7">11</text>
<text x="70.2" y="123.3">13</text>
<text x="70.2" y="125.8">14</text>
<text x="77.3" y="121.9">D4</text>
<text x="77.3" y="124.4">D5</text>
<text x="85" y="121.9">Q4</text>
<text x="85" y="124.4">Q5</text>
<text x="92.5" y="120.7">10</text>
<text x="92.5" y="123.3">12</text>
<text x="92.5" y="125.8">15</text>
<text x="151.5" y="120.7">22</text>
<text x="158.5" y="121.9">CLOCK</text>
<text x="172" y="121.9">CHANNEL-B</text>
<text x="189" y="120.7">3</text>
<text x="279.7" y="125.8">1</text>
<text x="279.7" y="123.3">2</text>
<text x="279.7" y="120.7">3</text>
<text x="383.2" y="125.8">1</text>
<text x="383.2" y="123.3">2</text>
<text x="383.2" y="120.7">4</text>
<text x="71.4" y="130.9">9</text>
<text x="77.3" y="126.9">D6</text>
<text x="85" y="126.9">Q6</text>
<text x="110.9" y="128.4">13</text>
<text x="128.1" y="128.4">12</text>
<text x="151.5" y="128.4">27</text>
<text x="158.5" y="129.5">BDIR</text>
<text x="171.8" y="129.5">CHANNEL-C</text>
<text x="189" y="128.4">38</text>
<text x="71.4" y="133.4">1</text>
<text x="77.3" y="134.6">CLR</text>
<text x="77.3" y="132">CLK</text>
<text x="151.5" y="133.4">28</text>
<text x="158.5" y="134.6">BC2</text>
<text x="179.5" y="137.1">IOA0</text>
<text x="189" y="136">21</text>
<text x="151.5" y="138.5">29</text>
<text x="158.5" y="139.6">BC1</text>
<text x="179.5" y="139.6">IOA1</text>
<text x="179.5" y="142.2">IOA2</text>
<text x="189" y="138.5">20</text>
<text x="189" y="141.1">19</text>
<text x="189" y="143.6">18</text>
<text x="151.5" y="146.1">25</text>
<text x="158.5" y="147.3">A8</text>
<text x="179.5" y="144.7">IOA3</text>
<text x="179.5" y="147.3">IOA4</text>
<text x="179.5" y="149.8">IOA5</text>
<text x="189" y="146.1">17</text>
<text x="189" y="148.7">16</text>
<text x="151.5" y="151.2">24</text>
<text x="158.5" y="152.3">A9</text>
<text x="179.5" y="152.3">IOA6</text>
<text x="179.5" y="154.9">IOA7</text>
<text x="189" y="151.2">15</text>
<text x="189" y="153.8">14</text>
<text x="71.4" y="158.8">2</text>
<text x="71.4" y="161.4">3</text>
<text x="77.3" y="159.9">1D</text>
<text x="85" y="160">1Q</text>
<text x="92.5" y="161.4">18</text>
<text x="92.5" y="158.8">19</text>
<text x="151.5" y="158.8">37</text>
<text x="151.5" y="161.4">36</text>
<text x="158.5" y="159.9">DA0</text>
<text x="179.5" y="160">IOB0</text>
<text x="189" y="158.8">13</text>
<text x="189" y="161.4">12</text>
<text x="71.4" y="163.9">4</text>
<text x="71.4" y="166.5">5</text>
<text x="77.3" y="162.5">2D</text>
<text x="77.3" y="165">3D</text>
<text x="77.3" y="167.6">4D</text>
<text x="85" y="167.6">4Q</text>
<text x="85" y="165">3Q</text>
<text x="85" y="162.5">2Q</text>
<text x="92.5" y="166.5">16</text>
<text x="92.5" y="163.9">17</text>
<text x="151.5" y="163.9">35</text>
<text x="151.5" y="166.5">34</text>
<text x="158.5" y="162.5">DA1</text>
<text x="158.5" y="165">DA2</text>
<text x="158.5" y="167.6">DA3</text>
<text x="179.5" y="162.5">IOB1</text>
<text x="179.5" y="165">IOB2</text>
<text x="179.5" y="167.6">IOB3</text>
<text x="189" y="163.9">11</text>
<text x="189" y="166.5">10</text>
<text x="71.4" y="169">6</text>
<text x="71.4" y="171.5">7</text>
<text x="77.3" y="170.1">5D</text>
<text x="77.3" y="172.6">6D</text>
<text x="85" y="172.6">6Q</text>
<text x="85" y="170.1">5Q</text>
<text x="92.5" y="171.5">14</text>
<text x="92.5" y="169">15</text>
<text x="151.5" y="169">33</text>
<text x="151.5" y="171.5">32</text>
<text x="158.5" y="170.1">DA4</text>
<text x="158.5" y="172.6">DA5</text>
<text x="179.5" y="170.1">IOB4</text>
<text x="179.5" y="172.6">IOB5</text>
<text x="189" y="169">9</text>
<text x="189" y="171.5">8</text>
<text x="71.4" y="174.1">8</text>
<text x="71.4" y="176.6">9</text>
<text x="77.3" y="175.2">7D</text>
<text x="77.3" y="177.7">8D</text>
<text x="85" y="177.7">8Q</text>
<text x="85" y="175.2">7Q</text>
<text x="92.5" y="176.6">12</text>
<text x="92.5" y="174.1">13</text>
<text x="151.5" y="174.1">31</text>
<text x="151.5" y="176.6">30</text>
<text x="158.5" y="175.2">DA6</text>
<text x="158.5" y="177.7">DA7</text>
<text x="179.5" y="175.2">IOB6</text>
<text x="179.5" y="177.7">IOB7</text>
<text x="189" y="174.1">7</text>
<text x="189" y="176.6">6</text>
<text x="229.5" y="176.6" transform="rotate(-90 229.5 176.6)">1-3</text>
<text x="232.7" y="179.1">1-2</text>
<text x="246.1" y="179.1">3</text>
<text x="249.8" y="176.6" transform="rotate(-90 249.8 176.6)">6</text>
<text x="254.9" y="179.1" transform="rotate(-90 254.9 179.1)">1</text>
<text x="257.4" y="179.1" transform="rotate(-90 257.4 179.1)">8</text>
<text x="303.1" y="176.6" transform="rotate(-90 303.1 176.6)">2-3</text>
<text x="306.4" y="179.1">2-2</text>
<text x="319.7" y="179.1">3</text>
<text x="323.5" y="176.6" transform="rotate(-90 323.5 176.6)">6</text>
<text x="328.5" y="179.1" transform="rotate(-90 328.5 179.1)">1</text>
<text x="331.1" y="179.1" transform="rotate(-90 331.1 179.1)">8</text>
<text x="378.7" y="179.1">2</text>
<text x="378.7" y="176.6">3</text>
<text x="70.2" y="181.7">11</text>
<text x="71.4" y="184.2">1</text>
<text x="77.3" y="185.3">OC</text>
<text x="77.3" y="182.8">CLK</text>
<text x="229.5" y="185.5" transform="rotate(-90 229.5 185.5)">1-1</text>
<text x="246.1" y="184.2">2</text>
<text x="260.7" y="181.7">5</text>
<text x="303.1" y="185.5" transform="rotate(-90 303.1 185.5)">2-1</text>
<text x="319.7" y="184.2">2</text>
<text x="334.3" y="181.7">5</text>
<text x="378.7" y="181.7">1</text>
<text x="249.8" y="188.7" transform="rotate(-90 249.8 188.7)">4</text>
<text x="254.9" y="186.1" transform="rotate(-90 254.9 186.1)">7</text>
<text x="323.5" y="188.7" transform="rotate(-90 323.5 188.7)">4</text>
<text x="328.5" y="186.1" transform="rotate(-90 328.5 186.1)">7</text>
<text x="131.8" y="224.9">1</text>
<text x="138.8" y="224.9">2</text>
<text x="193.3" y="227.4">2</text>
<text x="193.3" y="224.9">4</text>
<text x="199.2" y="226">PRE</text>
<text x="208.1" y="226">Q</text>
<text x="214.4" y="224.9">5</text>
<text x="193.3" y="232.5">3</text>
<text x="199.2" y="228.5">D</text>
<text x="199.2" y="233.6">CLK</text>
<text x="287.2" y="229.9">-</text>
<text x="293.7" y="229.9">+</text>
<text x="371" y="229.9">-</text>
<text x="377.5" y="229.9">+</text>
<text x="193.3" y="235">1</text>
<text x="199.2" y="236.1">CLR</text>
<text x="208.1" y="236.1">Q</text>
<text x="214.4" y="235">6</text>
<text x="94.3" y="250.3">5</text>
<text x="110.3" y="250.3">6</text>
<text x="132.4" y="250.3">1</text>
<text x="148.4" y="250.3">2</text>
<text x="157.8" y="250.3">3</text>
<text x="173.8" y="250.3">4</text>
<text x="192.1" y="255.3">12</text>
<text x="192.1" y="252.8">10</text>
<text x="199.2" y="256.5">D</text>
<text x="199.2" y="253.9">PRE</text>
<text x="208.1" y="253.9">Q</text>
<text x="214.4" y="252.8">9</text>
<text x="93.1" y="263">11</text>
<text x="110.3" y="263">10</text>
<text x="192.1" y="263">13</text>
<text x="192.1" y="260.4">11</text>
<text x="199.2" y="261.5">CLK</text>
<text x="214.4" y="263">8</text>
<text x="224.4" y="263" transform="rotate(-90 224.4 263)">3</text>
<text x="226.9" y="263" transform="rotate(-90 226.9 263)">2</text>
<text x="229.5" y="263" transform="rotate(-90 229.5 263)">1</text>
<text x="199.2" y="264.1">CLR</text>
<text x="208.1" y="264.1">Q</text>
</g>
<g font-size="1.8">
<text x="233.5" y="115.4">+</text>
<text x="233.5" y="125.6">+</text>
<text x="259.6" y="168.9" transform="rotate(-90 259.6 168.9)">+</text>
<text x="333.3" y="168.9" transform="rotate(-90 333.3 168.9)">+</text>
<text x="276.7" y="181.5">+</text>
<text x="350.3" y="181.5">+</text>
</g>
</g></defs>
<g fill="#000" stroke="#000" stroke-width=".25">
<path d="M67.8 18.2v3.9zM115.3 18.2v3.9zM162.7 18.2v3.9zM210.2 18.2v3.9zM257.6 18.2v3.9zM305.1 18.2v3.9zM352.5 18.2v3.9zM20.3 22.1v252.6zM20.3 22.1h379.7zM28.6 43.8h8.3zM41.9 50h7.6zM41.9 55.1h284.5z"/>
<path d="M49.5 50h327.6zM41.9 44.9h91.4zM326.4 55.1v91.4zM133.3 44.9h243.8zM378.7 43.8h8.3zM16.5 72.6h3.8zM133.9 67.1v8.3zM218.4 63.9v38.1zM218.4 63.9h101.6zM336.5 72.8l2.5 2.6zM336.5 75.4l2.5 2.5zM351.7 67.8v2.5z"/>
<path d="M351.7 70.3v2.5zM354.3 72.8h5.1zM354.3 75.4h5.1zM354.3 77.9h5.1zM351.7 72.8h2.6zM339 75.4h15.3zM339 77.9h15.3zM364.4 72.8h5.1zM364.4 75.4h5.1zM364.4 77.9h5.1zM369.5 72.8h2.6zM369.5 75.4h15.3z"/>
<path d="M369.5 77.9h15.3zM372.1 67.8v2.5zM372.1 70.3v2.5zM384.8 75.4l2.5 2.5zM384.8 77.9l2.5 2.6zM400 72.6h3.8zM59.7 98.2h48.2zM107.9 98.2v20.4zM147.9 93.7h3.1zM180.9 93.7h3zM336.5 77.9l2.5 2.6zM336.5 80.5l2.5 2.5z"/>
<path d="M336.5 83l2.5 2.5zM336.5 85.5l2.5 2.6zM336.5 88.1l2.5 2.5zM336.5 90.6l2.5 2.6zM351.7 98.2v2.6zM351.7 95.7v2.5zM354.3 80.5h5.1zM354.3 83h5.1zM354.3 85.5h5.1zM354.3 88.1h5.1zM354.3 90.6h5.1zM354.3 93.2h5.1z"/>
<path d="M354.3 95.7h5.1zM351.7 95.7h2.6zM339 80.5h15.3zM339 83h15.3zM339 85.5h15.3zM339 88.1h15.3zM339 90.6h15.3zM339 93.2h15.3zM364.4 80.5h5.1zM364.4 83h5.1zM364.4 85.5h5.1zM364.4 88.1h5.1z"/>
<path d="M364.4 90.6h5.1zM364.4 93.2h5.1zM364.4 95.7h5.1zM369.5 95.7h2.6zM369.5 80.5h15.3zM369.5 83h15.3zM369.5 85.5h15.3zM369.5 88.1h15.3zM369.5 90.6h15.3zM369.5 93.2h15.3zM372.1 98.2v2.6zM372.1 95.7v2.5z"/>
<path d="M384.8 80.5l2.5 2.5zM384.8 83l2.5 2.5zM384.8 85.5l2.5 2.6zM384.8 88.1l2.5 2.5zM384.8 90.6l2.5 2.6zM384.8 93.2l2.5 2.5zM62.2 100.8v17.8zM62.2 100.8h38.1zM64.8 103.3v12.7zM64.8 103.3h33zM67.3 108.4v2.5zM67.3 110.9v2.6z"/>
<path d="M69.8 113.5h5.1zM69.8 116h5.1zM69.8 118.6h5.1zM67.3 113.5h2.5zM64.8 116h5zM62.2 118.6h7.6zM90.2 113.5h5zM90.2 116h5zM90.2 118.6h5zM97.8 119.1h8.8zM97.8 103.3v10.2zM95.2 113.5h2.6z"/>
<path d="M100.3 100.8v15.2zM95.2 116h5.1zM95.2 118.6h12.7zM133.3 44.9v68.6zM137.7 111.5h8.3zM148.6 103.3v2.6zM151.1 113.5h3.1zM133.3 113.5h17.8zM158.5 112.5h7.1zM186.7 113.5h5zM212.1 118.6h2.5zM214.6 113.5h2.5z"/>
<path d="M214.6 118.6h2.5zM191.7 113.5h22.9zM218.4 102h101.6zM222.2 113.5h2.6zM222.2 118.6h2.6zM224.8 113.5h5zM229.8 113.5v2.5zM229.8 116v2.6zM224.8 118.6h5zM229.8 116h2.6zM232.4 116h2.5zM237.5 116h2.5z"/>
<path d="M240 116h2.5zM242.5 116h35.6zM257.8 118.6v27.9zM278.1 118.6h5.1zM278.1 116h5.1zM257.8 118.6h20.3zM288.3 116h1zM288.3 118.6h1zM290.3 116h1zM290.3 118.6h1zM292.3 116h1zM292.3 118.6h1z"/>
<path d="M294.3 116h1zM294.3 118.6h1zM294.6 119.8v1.5zM296.3 116h1.1zM296.3 118.6h1.1zM298.4 116h1zM298.4 118.6h1zM300.4 116h1zM300.4 118.6h1zM302.4 116h1zM302.4 118.6h1zM304.4 116h1.1z"/>
<path d="M304.4 118.6h1.1zM306.4 116h1.1zM306.4 118.6h1.1zM308.5 116h1zM308.5 118.6h1zM310.5 116h1zM310.5 118.6h1zM312.5 116h1zM312.5 118.6h1zM314.5 116h1zM314.5 118.6h1zM316.5 116h1.1z"/>
<path d="M316.5 118.6h1.1zM318.6 116h1zM318.6 118.6h1zM320 63.9v38.1zM320.6 116h1zM320.6 118.6h1zM322.6 116h1zM322.6 118.6h1zM324.6 116h1zM324.6 118.6h1zM326.6 116h1.1zM326.6 118.6h1.1z"/>
<path d="M328.7 116h1zM328.7 118.6h1zM330.7 116h1zM330.7 118.6h1zM332.7 116h1zM332.7 118.6h1zM334.7 116h1.1zM334.7 118.6h1.1zM336.8 116h1zM336.8 118.6h1zM338.8 116h1zM338.8 118.6h1z"/>
<path d="M340.8 116h1zM340.8 118.6h1zM342.8 116h1zM342.8 118.6h1zM344.8 116h1.1zM344.8 118.6h1.1zM346.9 116h1zM346.9 118.6h1zM348.9 116h1zM348.9 118.6h1zM350.9 116h1zM350.9 118.6h1z"/>
<path d="M352.9 116h1zM352.9 118.6h1zM354.9 116h1.1zM354.9 118.6h1.1zM356.9 116h1.1zM356.9 118.6h1.1zM359 116h1zM359 118.6h1zM361 116h1zM361 118.6h1zM363 116h1zM363 118.6h1z"/>
<path d="M365 116h1.1zM365 118.6h1.1zM367.1 116h1zM367.1 118.6h1zM369.1 116h1zM369.1 118.6h1zM371.1 116h1zM371.1 118.6h1zM373.1 116h1zM373.1 118.6h1zM375.2 116h1zM375.2 118.6h1z"/>
<path d="M377.2 116h1zM377.2 118.6h1zM379.2 116h1zM379.2 118.6h1zM381.2 116h1zM381.2 118.6h1zM382.2 116h2.6zM382.2 118.6h2.6zM384.8 116h2.5zM384.8 118.6h.5zM385.3 116.3v2.3zM387.3 116l2.5 2.6z"/>
<path d="M389.8 118.6l.8-.8zM16.5 123.1h3.8zM29.3 132.7h7.6zM41.9 133.8h15.2zM49.5 50v81.3zM57.1 133.8v48.3zM59.7 131.8h7.6zM59.7 98.2v22.9zM67.3 123.6v2.6zM67.3 113.5v10.1zM69.8 133.8h3.1zM69.8 131.3h5.1z"/>
<path d="M69.8 121.1h5.1zM69.8 123.6h5.1zM69.8 126.2h5.1zM67.3 126.2h2.5zM67.3 123.6h2.5zM57.1 133.8h12.7zM49.5 131.3h20.3zM59.7 121.1h10.1zM74.9 130.3l2 1zM74.9 132.2l2-.9zM90.2 121.1h5zM90.2 123.6h5z"/>
<path d="M90.2 126.2h5zM95.2 121.1h12.7zM107.9 121.1v7.6zM110.5 128.7h5.1zM107.9 128.7h2.6zM113 138.9v58.4zM127.7 128.7h3.1zM130.8 128.7h20.3zM133.3 121.1h17.8zM148.6 105.9v27.9zM151.1 121.1h5.1zM151.1 128.7h5.1z"/>
<path d="M151.1 138.9h5.1zM151.1 133.8h5.1zM148.6 133.8h2.5zM113 138.9h38.1zM186.7 121.1h5zM186.7 128.7h5zM186.7 136.3h5zM186.7 138.9h5zM191.7 121.1h20.4zM191.7 136.3h15.3zM191.7 138.9h15.3zM207 136.3l2.5-2.5z"/>
<path d="M207 138.9l2.5-2.6zM212.1 118.6v2.5zM212.1 121.1v2.5zM212.1 123.6h2.5zM214.6 123.6h2.5zM214.6 128.7h2.5zM191.7 128.7h22.9zM222.2 123.6h2.6zM222.2 128.7h2.6zM224.8 123.6h5zM229.8 123.6v2.6zM229.8 126.2v2.5z"/>
<path d="M224.8 128.7h5zM229.8 126.2h2.6zM232.4 126.2h2.5zM237.5 126.2h2.5zM240 126.2h10.2zM242.5 131.3v2.5zM242.5 116v15.3zM250.2 131.3v2.5zM250.2 123.6h27.9zM250.2 123.6v2.6zM250.2 126.2v5.1zM262.9 121.1v30.5z"/>
<path d="M275.6 126.2v17.8zM278.1 126.2h5.1zM278.1 123.6h5.1zM278.1 121.1h5.1zM275.6 126.2h2.5zM262.9 121.1h15.2zM288.3 121.1h1zM288.3 123.6h1zM288.3 126.2h1zM290.3 121.1h1zM290.3 123.6h1zM290.3 126.2h1z"/>
<path d="M292.3 121.1h1zM292.3 123.6h1zM292.3 126.2h1zM294.3 121.1h1zM294.3 123.6h1zM294.3 126.2h1zM294.6 128.7v2.6zM294.6 122.3v1.5zM294.6 124.8v1.4zM294.6 127.2v1.5zM296.3 121.1h1.1zM296.3 123.6h1.1z"/>
<path d="M296.3 126.2h1.1zM298.4 121.1h1zM298.4 123.6h1zM298.4 126.2h1zM300.4 121.1h1zM300.4 123.6h1zM300.4 126.2h1zM301 128.7v2.6zM301 124.9v1.4zM301 127.3v1.4zM302.4 121.1h1zM302.4 123.6h1z"/>
<path d="M302.4 126.2h1zM304.4 121.1h1.1zM304.4 123.6h1.1zM304.4 126.2h1.1zM306.4 121.1h1.1zM306.4 123.6h1.1zM306.4 126.2h1.1zM308.5 121.1h1zM308.5 123.6h1zM308.5 126.2h1zM310.5 121.1h1zM310.5 123.6h1z"/>
<path d="M310.5 126.2h1zM312.5 121.1h1zM312.5 123.6h1zM312.5 126.2h1zM314.5 121.1h1zM314.5 123.6h1zM314.5 126.2h1zM316.5 121.1h1.1zM316.5 123.6h1.1zM316.5 126.2h1.1zM318.6 121.1h1zM318.6 123.6h1z"/>
<path d="M318.6 126.2h1zM320.6 121.1h1zM320.6 123.6h1zM320.6 126.2h1zM322.6 121.1h1zM322.6 123.6h1zM322.6 126.2h1zM324.6 121.1h1zM324.6 123.6h1zM324.6 126.2h1zM326.6 121.1h1.1zM326.6 123.6h1.1z"/>
<path d="M326.6 126.2h1.1zM328.7 121.1h1zM328.7 123.6h1zM328.7 126.2h1zM330.7 121.1h1zM330.7 123.6h1zM330.7 126.2h1zM332.7 121.1h1zM332.7 123.6h1zM332.7 126.2h1zM334.7 121.1h1.1zM334.7 123.6h1.1z"/>
<path d="M334.7 126.2h1.1zM336.8 121.1h1zM336.8 123.6h1zM336.8 126.2h1zM338.8 121.1h1zM338.8 123.6h1zM338.8 126.2h1zM340.8 121.1h1zM340.8 123.6h1zM340.8 126.2h1zM342.8 121.1h1zM342.8 123.6h1z"/>
<path d="M342.8 126.2h1zM344.8 121.1h1.1zM344.8 123.6h1.1zM344.8 126.2h1.1zM346.9 121.1h1zM346.9 123.6h1zM346.9 126.2h1zM348.9 121.1h1zM348.9 123.6h1zM348.9 126.2h1zM350.9 121.1h1zM350.9 123.6h1z"/>
<path d="M350.9 126.2h1zM352.9 121.1h1zM352.9 123.6h1zM352.9 126.2h1zM354.9 121.1h1.1zM354.9 123.6h1.1zM354.9 126.2h1.1zM356.9 121.1h1.1zM356.9 123.6h1.1zM356.9 126.2h1.1zM359 121.1h1zM359 123.6h1z"/>
<path d="M359 126.2h1zM361 121.1h1zM361 123.6h1zM361 126.2h1zM363 121.1h1zM363 123.6h1zM363 126.2h1zM365 121.1h1.1zM365 123.6h1.1zM365 126.2h1.1zM367.1 121.1h1zM367.1 123.6h1z"/>
<path d="M367.1 126.2h1zM369.1 121.1h1zM369.1 123.6h1zM369.1 126.2h1zM371.1 121.1h1zM371.1 123.6h1zM371.1 126.2h1zM373.1 121.1h1zM373.1 123.6h1zM373.1 126.2h1zM375.2 121.1h1zM375.2 123.6h1z"/>
<path d="M375.2 126.2h1zM377.2 121.1h1zM377.2 123.6h1zM377.2 126.2h1zM379.2 121.1h1zM379.2 123.6h1zM379.2 126.2h1zM381.2 121.1h1zM381.2 123.6h1zM381.2 126.2h1zM382.2 126.2h2.6zM382.2 123.6h2.6z"/>
<path d="M382.2 121.1h2.6zM384.8 126.2h7.6zM384.8 123.6h1zM384.8 121.1h.5zM385.3 121.1v2.3zM385.8 123.6l2.5-2.5zM388.3 121.1l.8 .8zM392.4 122.6v3.6zM400 123.1h3.8zM49.5 156.7l2.6 2.5zM69.8 159.2h5.1zM52.1 159.2h17.7z"/>
<path d="M90.2 159.2h5zM95.2 159.2h55.9zM107.9 128.7v22.9zM137.2 149.6h8.8zM148.6 133.8v12.7zM151.1 159.2h5.1zM151.1 146.5h5.1zM151.1 151.6h5.1zM148.6 146.5h2.5zM107.9 151.6h43.2zM158.5 150.6h2.6zM186.7 141.4h5z"/>
<path d="M186.7 144h5zM186.7 146.5h5zM186.7 149h5zM186.7 151.6h5zM186.7 154.1h5zM186.7 159.2h5zM191.7 141.4h15.3zM191.7 144h15.3zM191.7 146.5h15.3zM191.7 149h15.3zM191.7 151.6h15.3zM191.7 154.1h15.3z"/>
<path d="M191.7 159.2h15.3zM207 141.4l2.5-2.5zM207 144l2.5-2.6zM207 146.5l2.5-2.5zM207 149l2.5-2.5zM207 151.6l2.5-2.6zM207 154.1l2.5-2.5zM207 159.2l2.5-2.5zM224.8 159.2h1zM226.8 159.2h1zM228.8 159.2h1zM229.8 156.7h28z"/>
<path d="M230.8 159.2h1zM232.8 159.2h1zM234.9 159.2h1zM236.9 159.2h1zM238.9 159.2h1zM240.9 159.2h1zM242.5 138.9v2.5zM242.5 141.4v2.6zM242.5 144h7.7zM242.9 159.2h1zM244.9 159.2h1.1zM247 159.2h1z"/>
<path d="M249 159.2h1zM250.2 138.9v2.5zM250.2 146.5v2.5zM250.2 141.4v2.6zM250.2 144h25.4zM250.2 144v2.5zM251 159.2h1zM253 159.2h1zM255 159.2h1zM257 159.2h1.1zM257.8 146.5v10.2zM259.1 159.2h1z"/>
<path d="M261.1 159.2h1zM262.9 151.6v5.1zM263.1 159.2h1zM265.1 159.2h1zM267.1 159.2h1.1zM269.2 159.2h1zM271.2 159.2h1zM273.2 159.2h1zM275.2 159.2h1zM277.2 159.2h1zM279.2 159.2h1.1zM281.3 159.2h1z"/>
<path d="M283.2 146.5h2.5zM283.2 151.6h2.5zM257.8 146.5h25.4zM262.9 151.6h20.3zM283.3 159.2h1zM285.3 159.2h1zM287.3 159.2h1zM289.3 159.2h1zM291.4 159.2h1zM290.8 146.5h2.5zM290.8 151.6h2.5zM293.3 151.6h10.2z"/>
<path d="M293.4 159.2h1zM295.4 159.2h1zM297.4 159.2h1zM298.4 159.2l.3 1.3zM262.9 156.7h40.6zM293.3 146.5h10.2zM303.5 146.5v5.1zM323.8 156.7v2.5zM303.5 146.5h22.9zM16.5 173.7h3.8zM49.5 159.2l2.6 2.5zM49.5 161.7l2.6 2.6z"/>
<path d="M49.5 164.3l2.6 2.5zM49.5 166.8l2.6 2.6zM49.5 169.4l2.6 2.5zM49.5 171.9l2.6 2.5zM49.5 174.4l2.6 2.6zM69.8 161.7h5.1zM69.8 164.3h5.1zM69.8 166.8h5.1zM69.8 169.4h5.1zM69.8 171.9h5.1zM69.8 174.4h5.1zM69.8 177h5.1z"/>
<path d="M52.1 161.7h17.7zM52.1 164.3h17.7zM52.1 166.8h17.7zM52.1 169.4h17.7zM52.1 171.9h17.7zM52.1 174.4h17.7zM52.1 177h17.7zM90.2 177h5zM90.2 174.4h5zM90.2 171.9h5zM90.2 169.4h5zM90.2 166.8h5z"/>
<path d="M90.2 164.3h5zM90.2 161.7h5zM95.2 177h55.9zM95.2 174.4h55.9zM95.2 171.9h55.9zM95.2 169.4h55.9zM95.2 166.8h55.9zM95.2 164.3h55.9zM95.2 161.7h55.9zM151.1 161.7h5.1zM151.1 164.3h5.1zM151.1 166.8h5.1z"/>
<path d="M151.1 169.4h5.1zM151.1 171.9h5.1zM151.1 174.4h5.1zM151.1 177h5.1zM186.7 161.7h5zM186.7 164.3h5zM186.7 166.8h5zM186.7 169.4h5zM186.7 171.9h5zM186.7 174.4h5zM186.7 177h5zM191.7 161.7h15.3z"/>
<path d="M191.7 164.3h15.3zM191.7 166.8h15.3zM191.7 169.4h15.3zM191.7 171.9h15.3zM191.7 174.4h15.3zM191.7 177h15.3zM207 161.7l2.5-2.5zM207 164.3l2.5-2.6zM207 166.8l2.5-2.5zM207 169.4l2.5-2.6zM207 171.9l2.5-2.5zM207 174.4l2.5-2.5z"/>
<path d="M207 177l2.5-2.6zM224.8 159.2l.2 1.3zM225.2 161.5l.3 1.3zM225.7 163.7l.2 1.4zM226.1 166l.3 1.3zM226.6 177.1l1.6 .2zM226.6 168.3l.2 1.3zM227.1 170.6l.2 1.3zM226.6 177.1l1.1 1.1zM228.2 177.3l-.5 .9zM229.8 174.4v2.6zM229.8 156.7v17.7z"/>
<path d="M228 177.8l3.5 1.7zM231.5 179.5h.9zM232.4 179.5h2.5zM234.9 179.5h10.2zM237.5 169.4v25.4zM245.1 179.5h2.5zM248.3 179.5h1.2zM248.9 178.9v1.2zM250.2 177v.9zM250.2 174.4v2.6zM250.2 164.3v2.5zM250.2 169.4v5z"/>
<path d="M250.2 166.8v2.6zM237.5 169.4h12.7zM255.2 177v2.5zM255.2 179.5v.5zM255.2 165.5v11.5zM255.2 165.5h2.6zM257.8 177v2.5zM257.8 179.5v1.5zM257.8 171.9v2.5zM257.8 166.8v2.6zM257.8 174.4v2.6zM257.8 165.5v1.3z"/>
<path d="M290.8 161.7h73.6zM298.9 161.5l.2 1.3zM299.3 163.7l.3 1.4zM299.8 166l.3 1.3zM300.2 168.3l.3 1.3zM300.3 177.1l1.5 .2zM300.7 170.6l.3 1.3zM300.3 177.1l1 1.1zM301.8 177.3l-.5 .9zM303.5 174.4v2.6zM303.5 156.7v17.7zM301.6 177.8l3.6 1.7z"/>
<path d="M305.2 179.5h.8zM306 179.5h2.6zM308.6 179.5h10.1zM311.1 169.4v25.4zM318.7 179.5h2.6zM321.9 179.5h1.3zM322.6 178.9v1.2zM323.8 177v.9zM323.8 174.4v2.6zM323.8 169.4v5zM323.8 159.2v10.2zM311.1 169.4h12.7z"/>
<path d="M328.9 177v2.5zM328.9 179.5v.5zM328.9 165.5v11.5zM328.9 165.5h2.5zM331.4 177v2.5zM331.4 179.5v1.5zM331.4 171.9v2.5zM331.4 166.8v2.6zM331.4 174.4v2.6zM331.4 165.5v1.3zM364.4 179.5v10.2zM364.4 161.7v15.3z"/>
<path d="M364.4 177h12.7zM377.1 179.5h5.1zM377.1 177h5.1zM364.4 179.5h12.7zM387.3 177h1zM387.3 179.5h1.2zM389.3 177h1zM389.5 179.5h1.1zM391.4 177h1zM391.6 179.5h1.2zM392.4 177v1zM392.4 179v1.1z"/>
<path d="M393.8 179.5h1.1zM394.9 179.5v1.3zM400 173.7h3.8zM49.5 194.8l2.6 2.5zM57.1 182.1h12.7zM57.1 184.6v7.6zM57.1 192.2h50.8zM58.5 182.6h8.8zM59.7 180h7.6zM69.8 184.6h3.1zM69.8 182.1h5.1zM57.1 184.6h12.7z"/>
<path d="M74.9 181.1l2 1zM74.9 183l2-.9zM107.9 151.6v40.6zM52.1 197.3h60.9zM191.7 182.1v2.5zM191.7 192.2v2.6zM191.7 187.1v2.6zM191.7 191.7v.5zM191.7 189.7v.5zM191.7 197.3v2.5zM191.7 194.8v2.5zM191.7 184.6v2.5z"/>
<path d="M227.3 180v2.1zM227.3 180l-.5 1zM227.3 180l.5 1zM229.8 182.1v2.5zM229.8 184.6v25.4zM237.5 194.8v2.5zM237.5 199.3v.5zM237.5 197.3v.5zM242.5 184.6v7.6zM242.5 192.2h7.7zM245.1 184.6h2.5zM242.5 184.6h2.6z"/>
<path d="M248.3 184.6h1.2zM250.2 186.2v.9zM250.2 187.1v2.6zM250.2 189.7v2.5zM250.2 192.2v17.8zM255.2 184.6v2.5zM255.2 184.1v.5zM255.2 194.8v2.5zM255.2 199.3v.5zM255.2 197.3v.5zM255.2 187.1v7.7zM260.3 182.1h2.6z"/>
<path d="M270.5 192.2v2.6zM270.5 187.1v2.6zM270.5 191.7v.5zM270.5 189.7v.5zM270.5 197.3v2.5zM270.5 194.8v2.5zM262.9 182.1h7.6zM270.5 182.1v5zM275.6 182.1h2.5zM270.5 182.1h5.1zM280.6 182.1h2.6zM283.2 182.1h7.6z"/>
<path d="M290.8 161.7v20.4zM301 180v2.1zM301 180l-.5 1zM301 180l.5 1zM303.5 182.1v2.5zM303.5 184.6v25.4zM311.1 194.8v2.5zM311.1 199.3v.5zM311.1 197.3v.5zM316.2 184.6v7.6zM316.2 192.2h7.6zM318.7 184.6h2.6z"/>
<path d="M316.2 184.6h2.5zM321.9 184.6h1.3zM323.8 186.2v.9zM323.8 187.1v2.6zM323.8 189.7v2.5zM323.8 192.2v17.8zM328.9 184.6v2.5zM328.9 184.1v.5zM328.9 194.8v2.5zM328.9 199.3v.5zM328.9 197.3v.5zM328.9 187.1v7.7z"/>
<path d="M334 182.1h2.5zM344.1 192.2v2.6zM344.1 187.1v2.6zM344.1 191.7v.5zM344.1 189.7v.5zM344.1 197.3v2.5zM344.1 194.8v2.5zM336.5 182.1h7.6zM344.1 182.1v5zM349.2 182.1h2.5zM344.1 182.1h5.1zM354.3 182.1h2.5z"/>
<path d="M356.8 182.1h20.3zM364.4 189.7v2.5zM377.1 182.1h5.1zM387.3 182.1h.8zM389.1 182.1h.7zM389.8 182.1v1zM389.8 184.1v1zM389.8 186.2v1zM389.8 188.2v1zM389.8 190.2v1.1zM389.8 192.3v1.1zM389.8 194.3v1.1z"/>
<path d="M389.8 196.4v1.1zM389.8 198.5v1zM392.4 181.1v1.1zM392.4 183.2v1zM392.4 185.2v1.1zM392.4 187.3v1.1zM392.4 189.4v1zM392.4 191.4v1.1zM392.4 193.5v1zM392.4 195.6v1zM392.4 197.6v1.1zM392.4 199.7v1z"/>
<path d="M394.9 181.8v1.3zM394.9 184.1v1.3zM394.9 186.3v1.3zM394.9 188.6v1.3zM394.9 190.9v1.3zM393.7 192.2h1.2zM394.9 192.2v1zM394.9 194.3v1zM394.9 196.3v1.1zM394.9 198.3v1.1zM133.3 121.1v93.9zM184.1 217.6v10.1z"/>
<path d="M189.2 210v2.5zM184.1 217.6h35.6zM133.3 215h94zM229.8 210h7.7zM237.5 199.8v2.6zM237.5 202.4v7.6zM237.5 210h12.7zM250.2 212.5v2.5zM250.2 210h5zM250.2 210v2.5zM255.2 199.8v2.6zM255.2 210h15.3z"/>
<path d="M255.2 202.4v7.6zM270.5 204.9v2.5zM270.5 207.4v2.6zM303.5 210h7.6zM311.1 199.8v2.6zM311.1 202.4v7.6zM311.1 210h12.7zM323.8 212.5v2.5zM323.8 210h5.1zM323.8 210v2.5zM328.9 199.8v2.6zM328.9 210h15.2z"/>
<path d="M328.9 202.4v7.6zM344.1 204.9v2.5zM344.1 207.4v2.6zM389.8 200.5v1.1zM389.8 202.6v1zM389.8 204.6v1.1zM389.8 206.7v1zM389.8 208.7v1.1zM389.8 210.8v1zM389.8 212.8v1.1zM389.8 214.9v1zM389.8 216.9v1.1z"/>
<path d="M389.8 219v1zM392.4 201.7v1.1zM392.4 203.8v1.1zM392.4 205.9v1zM392.4 207.9v1.1zM392.4 210v1.1zM392.4 212.1v1zM392.4 214.1v1.1zM392.4 216.2v1.1zM392.4 218.3v1zM394.9 200.4v1.1zM394.9 202.5v1z"/>
<path d="M394.9 204.5v1.1zM394.9 206.6v1zM394.9 208.6v1.1zM394.9 210.7v1zM394.9 212.7v1.1zM394.9 214.8v1zM394.9 216.8v1.1zM394.9 218.9v1zM16.5 224.2h3.8zM128.2 225.2v10.2zM128.2 235.4v15.2zM130.8 225.2h2.5z"/>
<path d="M130.8 235.4h2.5zM128.2 225.2h2.6zM128.2 235.4h2.6zM138.4 225.2h2.5zM138.4 235.4h2.5zM140.9 225.2h5.1zM140.9 235.4h5.1zM146 225.2h7.6zM146 225.2v10.2zM153.6 232.8v2.6zM153.6 225.2v7.6zM153.6 225.2h7.7z"/>
<path d="M161.3 232.8v2.6zM161.3 227.7v2.6zM161.3 232.3v.5zM161.3 230.3v.5zM161.3 237.9v2.5zM161.3 235.4v2.5zM161.3 225.2v2.5zM179 232.8h12.7zM184.1 227.7h7.6zM189.2 225.2v10.2zM189.2 212.5v12.7zM189.2 235.4v17.7z"/>
<path d="M191.7 235.4h3.2zM191.7 227.7h5.1zM191.7 232.8h5.1zM191.7 225.2h3.2zM189.2 235.4h2.5zM189.2 225.2h2.5zM196.8 231.9l2 .9zM196.8 233.8l2-1zM208.1 234.4h1.6zM212.1 225.2h5zM212.1 235.4h5zM217.1 225.2h5.1z"/>
<path d="M217.1 235.4h2.6zM219.7 217.6v17.8zM222.2 225.2v17.8zM283.2 237v1.2zM283.2 234.8v1.2zM283.2 232.5v1.3zM283.2 230.3v1.2zM283.2 230.3h.7zM284.9 230.3h.8zM285.7 230.3h2.6zM288.3 230.3h.6zM292.7 230.3h.6z"/>
<path d="M293.3 230.3h2.6zM295.9 230.3h.7zM298.4 236.8v1.1zM298.4 234.6v1.2zM298.4 232.4v1.2zM298.4 230.3v1.2zM297.6 230.3h.8zM298.4 237.9h1zM300.4 237.9h1.1zM302.5 237.9h1zM304.5 237.9h1zM306.5 237.9h1z"/>
<path d="M308.5 237.9h1zM310.6 237.9h1zM312.6 237.9h1zM314.6 237.9h1zM316.6 237.9h1zM318.6 237.9h1.1zM320.6 237.9h1.1zM322.7 237.9h1zM324.7 237.9h1zM326.7 237.9h1zM328.7 237.9h1.1zM330.7 237.9h1.1z"/>
<path d="M332.8 237.9h1zM334.8 237.9h1zM336.8 237.9h1zM338.8 237.9h1zM340.8 237.9h1.1zM342.9 237.9h1zM344.9 237.9h1zM346.9 237.9h1zM348.9 237.9h1zM351 237.9h1zM353 237.9h1zM355 237.9h1z"/>
<path d="M357 237.9h1zM359 237.9h1.1zM361.1 237.9h1zM363.1 237.9h1zM365.1 237.9h1zM367 237v1.2zM367 234.8v1.2zM367 232.5v1.3zM367 230.3v1.2zM367 230.3h.8zM367.1 237.9h1zM368.8 230.3h.7z"/>
<path d="M369.5 230.3h2.6zM369.1 237.9h1.1zM372.1 230.3h.6zM371.2 237.9h1zM373.2 237.9h1zM375.2 237.9h1zM376.5 230.3h.6zM377.2 237.9h1zM377.1 230.3h2.6zM379.2 237.9h1.1zM379.7 230.3h1.2zM381.3 237.9h1z"/>
<path d="M381.9 230.3h1.3zM383.3 237.9h1zM384.1 230.3h1.3zM385.3 237.9h1zM386.4 230.3h1.2zM387.3 237.9h1zM389.8 221v1.1zM389.8 223.1v1zM389.8 225.1v1.1zM389.8 227.2v1zM389.8 229.3v1zM388.6 230.3h1.2z"/>
<path d="M389.3 237.9h1.1zM392.4 220.3v1.1zM392.4 222.4v1.1zM392.4 224.5v1zM392.4 226.5v1.1zM392.4 228.6v1.1zM392.4 230.6v1.1zM392.4 232.7v1.1zM392.4 234.8v1.1zM392.4 236.9v1zM391.4 237.9h1zM394.9 220.9v1.1z"/>
<path d="M394.9 223v1zM394.9 225v1.1zM394.9 227.1v1.1zM394.9 229.1v1.1zM394.9 231.2v1zM394.9 233.3v1zM394.9 235.3v1zM394.9 237.4v1zM394.9 239.4v1zM400 224.2h3.8zM26.7 255.7v2.5zM26.7 250.6v2.5z"/>
<path d="M26.7 255.2v.5zM26.7 253.1v.6zM26.7 258.2v2.6zM26.7 248.1v2.5zM34.3 255.7v2.5zM34.3 250.6v2.5zM34.3 255.2v.5zM34.3 253.1v.6zM34.3 248.1v2.5zM26.7 248.1h7.6zM41.9 255.7v2.5zM41.9 250.6v2.5z"/>
<path d="M41.9 255.2v.5zM41.9 253.1v.6zM34.3 248.1h7.6zM41.9 248.1v2.5zM49.5 243v2.5zM49.5 255.7v2.5zM49.5 250.6v2.5zM49.5 255.2v.5zM49.5 253.1v.6zM41.9 248.1h7.6zM49.5 245.5v2.6zM49.5 248.1v2.5z"/>
<path d="M59.7 243v2.5zM59.7 250.6v2.5zM59.7 255.7v2.5zM59.7 253.1v.6zM59.7 255.2v.5zM59.7 245.5v5.1zM90.2 250.6v12.7zM92.7 250.6h5.1zM90.2 250.6h2.5zM109.9 250.6h3.1zM128.2 250.6h2.6zM130.8 250.6h5.1z"/>
<path d="M148 250.6h3.1zM151.1 250.6h2.5zM153.6 240.4v2.6zM153.6 250.6h2.6zM153.6 243v7.6zM156.2 250.6h5.1zM173.4 250.6h3.1zM176.5 250.6h2.5zM179 232.8v17.8zM184.1 243v17.8zM186.7 245.5v10.2zM186.7 255.7h5z"/>
<path d="M189.2 253.1v10.2zM191.7 255.7h5.1zM191.7 253.1h3.2zM189.2 253.1h2.5zM196.8 259.8l2 1zM212.1 253.1h5zM217.1 253.1h7.7zM186.7 245.5h33zM184.1 243h38.1zM222.2 243h7.6zM283.2 239.2v1.2zM283.2 240.4h1z"/>
<path d="M285.2 240.4h1zM287.2 240.4h1zM289.2 240.4h1.1zM291.2 240.4h1.1zM293.3 240.4h1zM295.3 240.4h1zM297.3 240.4h1zM299.3 240.4h1zM301.3 240.4h1.1zM303.4 240.4h1zM305.4 240.4h1zM307.4 240.4h1z"/>
<path d="M309.4 240.4h1zM311.4 240.4h1.1zM313.5 240.4h1zM315.5 240.4h1zM317.5 240.4h1zM319.5 240.4h1zM321.5 240.4h1.1zM323.6 240.4h1zM325.6 240.4h1zM327.6 240.4h1zM329.6 240.4h1zM331.6 240.4h1.1z"/>
<path d="M333.7 240.4h1zM335.7 240.4h1zM337.7 240.4h1zM339.7 240.4h1zM341.7 240.4h1.1zM343.8 240.4h1zM345.8 240.4h1zM347.8 240.4h1zM349.8 240.4h1zM351.8 240.4h1.1zM353.9 240.4h1zM355.9 240.4h1z"/>
<path d="M357.9 240.4h1zM359.9 240.4h1zM361.9 240.4h1.1zM364 240.4h1zM367 239.2v1.2zM366 240.4h1zM367 240.4h1.1zM369.1 240.4h1zM371.1 240.4h1.1zM373.2 240.4h1.1zM375.3 240.4h1zM377.3 240.4h1.1z"/>
<path d="M379.4 240.4h1.1zM381.5 240.4h1zM383.5 240.4h1.1zM385.6 240.4h1.1zM387.7 240.4h1zM389.7 240.4h1.1zM391.8 240.4h1.1zM393.9 240.4h1zM20.3 274.7h379.7zM26.7 263.3v2.5zM26.7 260.8h7.6zM26.7 260.8v2.5z"/>
<path d="M34.3 258.2v2.6zM34.3 260.8h7.6zM41.9 258.2v2.6zM41.9 260.8h7.6zM49.5 258.2v2.6zM59.7 263.3v2.5zM59.7 258.2v5.1zM67.8 274.7v3.8zM90.2 265.8v2.6zM90.2 263.3v2.5zM92.7 263.3h5.1zM90.2 263.3h2.5z"/>
<path d="M109.9 263.3h3.1zM115.3 274.7v3.8zM162.7 274.7v3.8zM184.1 260.8h7.6zM189.2 263.3h2.5zM191.7 263.3h3.2zM191.7 260.8h5.1zM196.8 261.8l2-1zM208.1 262.4h1.6zM210.2 274.7v3.8zM212.1 263.3h5zM217.1 263.3h2.6z"/>
<path d="M219.7 245.5v17.8zM224.8 260.8v2.5zM224.8 263.3v1.3zM224.8 253.1v7.7zM227.3 260.8v2.5zM227.3 263.3v1.3zM227.3 215v45.8zM229.8 260.8v2.5zM229.8 263.3v1.3zM229.8 243v17.8zM257.6 274.7v3.8zM305.1 274.7v3.8z"/>
<path d="M352.5 274.7v3.8zM400 264.5v.1zM400 268.4v6.2zM400 274.6h.1zM400 22.1v252.6z"/>
<circle cx="49.5" cy="50" r=".51"/>
<circle cx="133.3" cy="44.9" r=".51"/>
<circle cx="67.3" cy="113.5" r=".51"/>
<circle cx="229.8" cy="116" r=".51"/>
<circle cx="242.5" cy="116" r=".51"/>
<circle cx="57.1" cy="133.8" r=".51"/>
<circle cx="67.3" cy="123.6" r=".51"/>
<circle cx="107.9" cy="128.7" r=".51"/>
<circle cx="148.6" cy="133.8" r=".51"/>
<circle cx="212.1" cy="121.1" r=".51"/>
<circle cx="229.8" cy="126.2" r=".51"/>
<circle cx="250.2" cy="126.2" r=".51"/>
<circle cx="107.9" cy="151.6" r=".51"/>
<circle cx="250.2" cy="144" r=".51"/>
<circle cx="257.8" cy="146.5" r=".51"/>
<circle cx="262.9" cy="151.6" r=".51"/>
<circle cx="303.5" cy="146.5" r=".51"/>
<circle cx="250.2" cy="169.4" r=".51"/>
<circle cx="323.8" cy="169.4" r=".51"/>
<circle cx="250.2" cy="192.2" r=".51"/>
<circle cx="270.5" cy="182.1" r=".51"/>
<circle cx="323.8" cy="192.2" r=".51"/>
<circle cx="344.1" cy="182.1" r=".51"/>
<circle cx="394.9" cy="192.2" r=".51"/>
<circle cx="237.5" cy="210" r=".51"/>
<circle cx="250.2" cy="210" r=".51"/>
<circle cx="255.2" cy="210" r=".51"/>
<circle cx="311.1" cy="210" r=".51"/>
<circle cx="323.8" cy="210" r=".51"/>
<circle cx="328.9" cy="210" r=".51"/>
<circle cx="128.2" cy="235.4" r=".51"/>
<circle cx="146" cy="225.2" r=".51"/>
<circle cx="153.6" cy="225.2" r=".51"/>
<circle cx="189.2" cy="235.4" r=".51"/>
<circle cx="189.2" cy="225.2" r=".51"/>
<circle cx="34.3" cy="248.1" r=".51"/>
<circle cx="41.9" cy="248.1" r=".51"/>
<circle cx="49.5" cy="248.1" r=".51"/>
<circle cx="153.6" cy="250.6" r=".51"/>
<circle cx="189.2" cy="253.1" r=".51"/>
<circle cx="222.2" cy="243" r=".51"/>
<circle cx="367" cy="240.4" r=".51"/>
<circle cx="26.7" cy="260.8" r=".51"/>
<circle cx="34.3" cy="260.8" r=".51"/>
<circle cx="41.9" cy="260.8" r=".51"/>
<circle cx="90.2" cy="263.3" r=".51"/>
</g>
<g fill="#000" stroke="#000" stroke-width=".61">
<path d="M20.3 22.1v252.6zM20.3 22.1h379.7zM142.9 60.2v8.8zM142.9 69v14.6zM142.9 69h38.7zM142.9 60.2h5zM147.9 60.2h5.1zM153 60.2h5.1zM158.1 60.2v4.4zM158.1 64.6h23.5zM181.6 64.6v4.4zM359.4 77.9h1.2z"/>
<path d="M359.4 75.4h1.2zM359.4 72.8h1.2zM363.2 77.9h1.2zM363.2 75.4h1.2zM363.2 72.8h1.2zM142.9 83.6h5zM147.9 83.6h5.1zM153 83.6h5.1zM158.1 83.6h23.5zM181.6 69v14.6zM359.4 83h1.2zM359.4 80.5h1.2z"/>
<path d="M359.4 90.6h1.2zM359.4 88.1h1.2zM359.4 85.5h1.2zM359.4 95.7h1.2zM359.4 93.2h1.2zM363.2 83h1.2zM363.2 80.5h1.2zM363.2 90.6h1.2zM363.2 88.1h1.2zM363.2 85.5h1.2zM363.2 95.7h1.2zM363.2 93.2h1.2z"/>
<path d="M74.9 110.9v25.4zM74.9 110.9h15.3zM156.2 110.9h30.5zM186.7 110.9v68.6zM283.2 116h1.3zM283.2 118.6h1.3zM74.9 136.3h15.3zM90.2 110.9v25.4zM283.2 121.1h1.3zM283.2 123.6h1.3zM283.2 126.2h1.3zM74.9 156.7v30.4z"/>
<path d="M74.9 156.7h15.3zM156.2 110.9v68.6zM156.2 179.5h30.5zM382.2 177h1.3zM382.2 179.5h1.3zM74.9 187.1h15.3zM90.2 156.7v30.4zM382.2 182.1h1.3zM283.2 244.3v30.4zM313.7 254.4v5.1zM313.7 249.3v5.1zM313.7 244.3v5z"/>
<path d="M313.7 244.3h86.3zM283.2 244.3h30.5zM400 254.4v5.1zM400 249.3v5.1zM400 244.3v5zM400 22.1v222.2zM20.3 274.7h262.9zM283.2 274.7h30.5zM313.7 274.7h86.3zM313.7 269.7v5zM313.7 264.6v5.1zM313.7 259.5v5.1z"/>
<path d="M400 268.4v6.3zM400 264.6v3.8zM400 259.5v5.1z"/>
</g>
<path d="M16.5 18.2v260.3zM16.5 18.2h387.3zM147.9 60.2v23.4zM153 60.2v23.4zM158.1 64.6v19zM16.5 278.5h387.3zM403.8 18.2v260.3z" fill="#000" stroke="#000" stroke-width=".32"/>
<g fill="#000" stroke="#000" stroke-width=".28">
<path d="M25.1 53.6v3zM26.2 43.4v3zM29.7 48.5v3zM26.2 43.4h14.2zM26.2 46.4h14.2zM29.7 48.5h10.7zM29.7 51.5h10.7zM25.1 56.6h15.3zM25.1 53.6h15.3zM40.4 43.4l1.5 1.5zM41.9 44.9l-1.5 1.5zM40.4 48.5l1.5 1.5z"/>
<path d="M41.9 50l-1.5 1.5zM41.9 55.1l-1.5 1.5zM40.4 53.6l1.5 1.5zM377.1 44.9l1.6 1.5zM377.1 44.9l1.6-1.5zM377.1 50l1.6 1.5zM378.7 48.5l-1.6 1.5zM378.7 46.4h14.1zM378.7 43.4h14.1zM378.7 51.5h10.6zM378.7 48.5h10.6zM389.3 48.5v3z"/>
<path d="M392.8 43.4v3zM351.7 67.8l-1.2 1.9zM351.7 67.8l1.3 1.9zM372.1 67.8l-1.3 1.9zM372.1 67.8l1.2 1.9zM67.3 108.4l-1.3 1.9zM67.3 108.4l1.3 1.9zM148.6 103.3l-1.3 1.9zM148.6 103.3l1.2 1.9zM217.1 114.4h5.1zM217.1 112.6v1.8zM217.1 119.4h5.1z"/>
<path d="M217.1 117.7v1.7zM217.1 112.6h5.1zM222.2 112.6v1.8zM217.1 117.7h5.1zM222.2 117.7v1.7zM234.9 114.5h.9zM234.9 114.5v3zM235.8 114.5v3zM234.9 117.5h.9zM349.8 100.8h3.8zM370.2 100.8h3.8zM385 117h.5z"/>
<path d="M385.3 116.3l-.3 .7zM385.3 116.3l.2 .7zM26.9 132.3v3zM26.9 132.3h13.5zM26.9 135.3h13.5zM40.4 132.3l1.5 1.5zM41.9 133.8l-1.5 1.5zM217.1 124.5h5.1zM217.1 122.7v1.8zM217.1 129.6h5.1zM217.1 127.8v1.8zM217.1 122.7h5.1z"/>
<path d="M222.2 122.7v1.8zM217.1 127.8h5.1zM222.2 127.8v1.8zM234.9 124.6h.9zM234.9 124.6v3.1zM235.8 124.6v3.1zM234.9 127.7h.9zM241.7 133.8v5.1zM241.7 138.9h1.7zM241.7 133.8h1.7zM243.4 133.8v5.1zM249.3 133.8v5.1z"/>
<path d="M249.3 138.9h1.8zM249.3 133.8h1.8zM251.1 133.8v5.1zM292.7 131.3h3.8zM299.1 131.3h3.8zM385 122.6h.5zM385 122.6l.3 .8zM385.5 122.6l-.2 .8zM248.3 149h3.8zM285.7 147.4h5.1zM285.7 145.6v1.8zM285.7 152.5h5.1z"/>
<path d="M285.7 150.7v1.8zM285.7 145.6h5.1zM290.8 145.6v1.8zM285.7 150.7h5.1zM290.8 150.7v1.8zM323.8 156.7l-1.2 1.9zM323.8 156.7l1.3 1.9zM229.1 177v5.1zM229.1 177h1.5zM250.2 164.3l-1.3 1.9zM250.2 164.3l1.2 1.9zM256.3 169.4v.8z"/>
<path d="M256.3 170.2h3zM259.3 169.4v.8zM256.3 169.4h3zM302.7 177v5.1zM302.7 177h1.6zM329.9 169.4v.8zM329.9 170.2h3zM332.9 169.4v.8zM329.9 169.4h3zM189.8 199.8h3.9zM191.7 182.1l-1.2 1.9zM191.7 182.1l1.3 1.9z"/>
<path d="M229.1 182.1h1.5zM230.6 177v5.1zM269.6 199.8v5.1zM269.6 199.8h1.8zM278.1 180.5h.9zM278.1 180.5v3.1zM279 180.5v3.1zM278.1 183.6h.9zM302.7 182.1h1.6zM304.3 177v5.1zM343.2 199.8v5.1zM343.2 199.8h1.8z"/>
<path d="M351.7 180.5h.9zM351.7 180.5v3.1zM352.6 180.5v3.1zM351.7 183.6h.9zM362.5 192.2h3.8zM189.2 210l-1.3 1.9zM189.2 210l1.3 1.9zM248.3 215h3.8zM269.6 204.9h1.8zM271.4 199.8v5.1zM321.9 215h3.8zM343.2 204.9h1.8z"/>
<path d="M345 199.8v5.1zM133.3 236.3h5.1zM133.3 234.5v1.8zM133.3 234.5h5.1zM138.4 234.5v1.8zM154.5 235.4v5zM152.8 235.4h1.7zM288.9 230.9h3.8zM288.9 230.3v.6zM285.7 225.2l3.2 2.5zM288.9 227.7v2.6zM292.7 230.3v.6z"/>
<path d="M288.9 227.7h3.8zM292.7 227.7l3.2-2.5zM292.7 227.7v2.6zM285.7 225.2h10.2zM372.7 230.9h3.8zM372.7 230.3v.6zM369.5 225.2l3.2 2.5zM372.7 227.7v2.6zM376.5 230.3v.6zM372.7 227.7h3.8zM376.5 227.7l3.2-2.5zM376.5 227.7v2.6z"/>
<path d="M369.5 225.2h10.2zM49.5 243l-1.2 1.9zM49.5 243l1.3 1.9zM59.7 243l-1.3 1.9zM59.7 243l1.3 1.9zM152.8 235.4v5zM152.8 240.4h1.7zM159.4 240.4h3.8zM313.7 249.3h86.3zM313.7 254.4h86.3zM313.7 259.5h58.4zM372.1 259.5h27.9z"/>
<path d="M372.1 259.5v5.1zM24.8 265.8h3.8zM57.8 265.8h3.8zM88.3 268.4h3.8zM313.7 264.6h58.4zM313.7 269.7h86.3zM372.1 264.6h27.9zM400 268.4v1.3z"/>
</g>
<g fill="none" stroke="#000" stroke-width=".25">
<circle cx="155.2" cy="113.5" r=".99"/>
<circle cx="294.6" cy="117.3" r="2.84"/>
<circle cx="73.9" cy="133.8" r=".99"/>
<circle cx="126.7" cy="128.7" r=".99"/>
<circle cx="301" cy="122.4" r="2.84"/>
<circle cx="73.9" cy="184.6" r=".99"/>
<circle cx="391.1" cy="192.2" r="2.84"/>
<circle cx="195.8" cy="225.2" r=".99"/>
<circle cx="195.8" cy="235.4" r=".99"/>
<circle cx="108.9" cy="250.6" r=".99"/>
<circle cx="147" cy="250.6" r=".99"/>
<circle cx="172.4" cy="250.6" r=".99"/>
<circle cx="195.8" cy="253.1" r=".99"/>
<circle cx="108.9" cy="263.3" r=".99"/>
<circle cx="195.8" cy="263.3" r=".99"/>
</g>
<g fill="#000" stroke="#000" stroke-width=".25">
<path d="M236.6 114.4h.9v3.3h-.9zM391.9 117h1v5.6h-1zM236.6 124.5h.9v3.3h-.9zM256.1 171h3.3v.9h-3.3zM329.8 171h3.3v.9h-3.3zM189.7 190.2h4.1v.5h-4.1zM189.7 191.2h4.1v.5h-4.1zM235.4 197.8h4.1v.5h-4.1zM235.4 198.8h4.1v.5h-4.1zM253.2 197.8h4.1v.5h-4.1zM253.2 198.8h4.1v.5h-4.1zM268.5 190.2h4v.5h-4z"/>
<path d="M268.5 191.2h4v.5h-4zM279.8 180.4h.8v3.3h-.8zM309.1 197.8h4.1v.5h-4.1zM309.1 198.8h4.1v.5h-4.1zM326.9 197.8h4v.5h-4zM326.9 198.8h4v.5h-4zM342.1 190.2h4.1v.5h-4.1zM342.1 191.2h4.1v.5h-4.1zM353.4 180.4h.9v3.3h-.9zM55.9 210h25.4v10.1h-25.4zM159.2 230.8h4.1v.5h-4.1zM159.2 231.8h4.1v.5h-4.1z"/>
<path d="M24.6 253.7h4.1v.5h-4.1zM24.6 254.7h4.1v.5h-4.1zM32.3 253.7h4v.5h-4zM32.3 254.7h4v.5h-4zM39.9 253.7h4v.5h-4zM39.9 254.7h4v.5h-4zM47.5 253.7h4.1v.5h-4.1zM47.5 254.7h4.1v.5h-4.1zM57.7 254.7h4v.5h-4zM57.7 253.7h4v.5h-4z"/>
</g>
<g fill="#000" stroke="#000" stroke-width=".42">
<path d="M358.1 70.3h7.6zM358.1 70.3v27.9zM365.7 70.3v27.9zM358.1 98.2h7.6zM287 113.5v15.2zM281.9 113.5h5.1zM115.6 123.6l10.1 5.1zM115.6 123.6v10.2zM115.6 133.8l10.1-5.1zM281.9 128.7h5.1zM281.9 113.5v15.2zM247.6 177v10.1z"/>
<path d="M321.3 177v10.1zM386 174.4v10.2zM381 174.4h5zM247.6 187.1l7.6-3zM255.2 184.1l5.1-2zM247.6 177l7.6 3zM255.2 180l2.6 1zM257.8 181l2.5 1.1zM321.3 187.1l7.6-3zM328.9 184.1l5.1-2zM321.3 177l7.6 3zM328.9 180l2.5 1z"/>
<path d="M331.4 181l2.6 1.1zM381 184.6h5zM381 174.4v10.2zM25.4 210v10.1zM25.4 210h55.9zM25.4 220.1v12.7zM25.4 232.8h55.9zM25.4 220.1h55.9zM81.3 220.1v12.7zM81.3 210v10.1zM133.6 222.7v5zM134.6 222.7h2.7z"/>
<path d="M134.6 222.7v5zM137.3 222.7v5zM134.6 227.7h2.7zM138.2 222.7v5zM196.8 237.9h15.3zM196.8 222.7v15.2zM212.1 222.7v15.2zM196.8 222.7h15.3zM97.8 245.5l10.1 5.1zM97.8 245.5v10.2zM97.8 258.2l10.1 5.1zM97.8 255.7l10.1-5.1z"/>
<path d="M135.9 245.5l10.1 5.1zM135.9 245.5v10.2zM135.9 255.7l10.1-5.1zM161.3 245.5l10.1 5.1zM161.3 245.5v10.2zM161.3 255.7l10.1-5.1zM196.8 250.6v15.2zM196.8 250.6h15.3zM97.8 258.2v10.2zM97.8 268.4l10.1-5.1zM196.8 265.8h15.3zM212.1 250.6v15.2z"/>
<path d="M224.1 263.3v.6zM224.1 263.9h6.4zM224.8 264.6v1.2zM227.3 264.6v1.2zM229.8 264.6v1.2zM224.1 263.3h6.4zM230.5 263.3v.6z"/>
</g>
<path d="M209.5 65.2l5.1-5zM214.6 60.2h116.8zM331.4 60.2l5.1 5zM336.5 65.2v35.6zM387.3 77.9v22.9zM336.5 100.8l5.1 5.1zM341.6 105.9h40.6zM382.2 105.9l5.1-5.1zM39.4 151.6h7.6zM47 151.6l2.5 2.5zM209.5 65.2v109.2zM49.5 154.1v40.7z" fill="#000" stroke="#000" stroke-width=".76"/>
<use href="#words"/>
</svg>
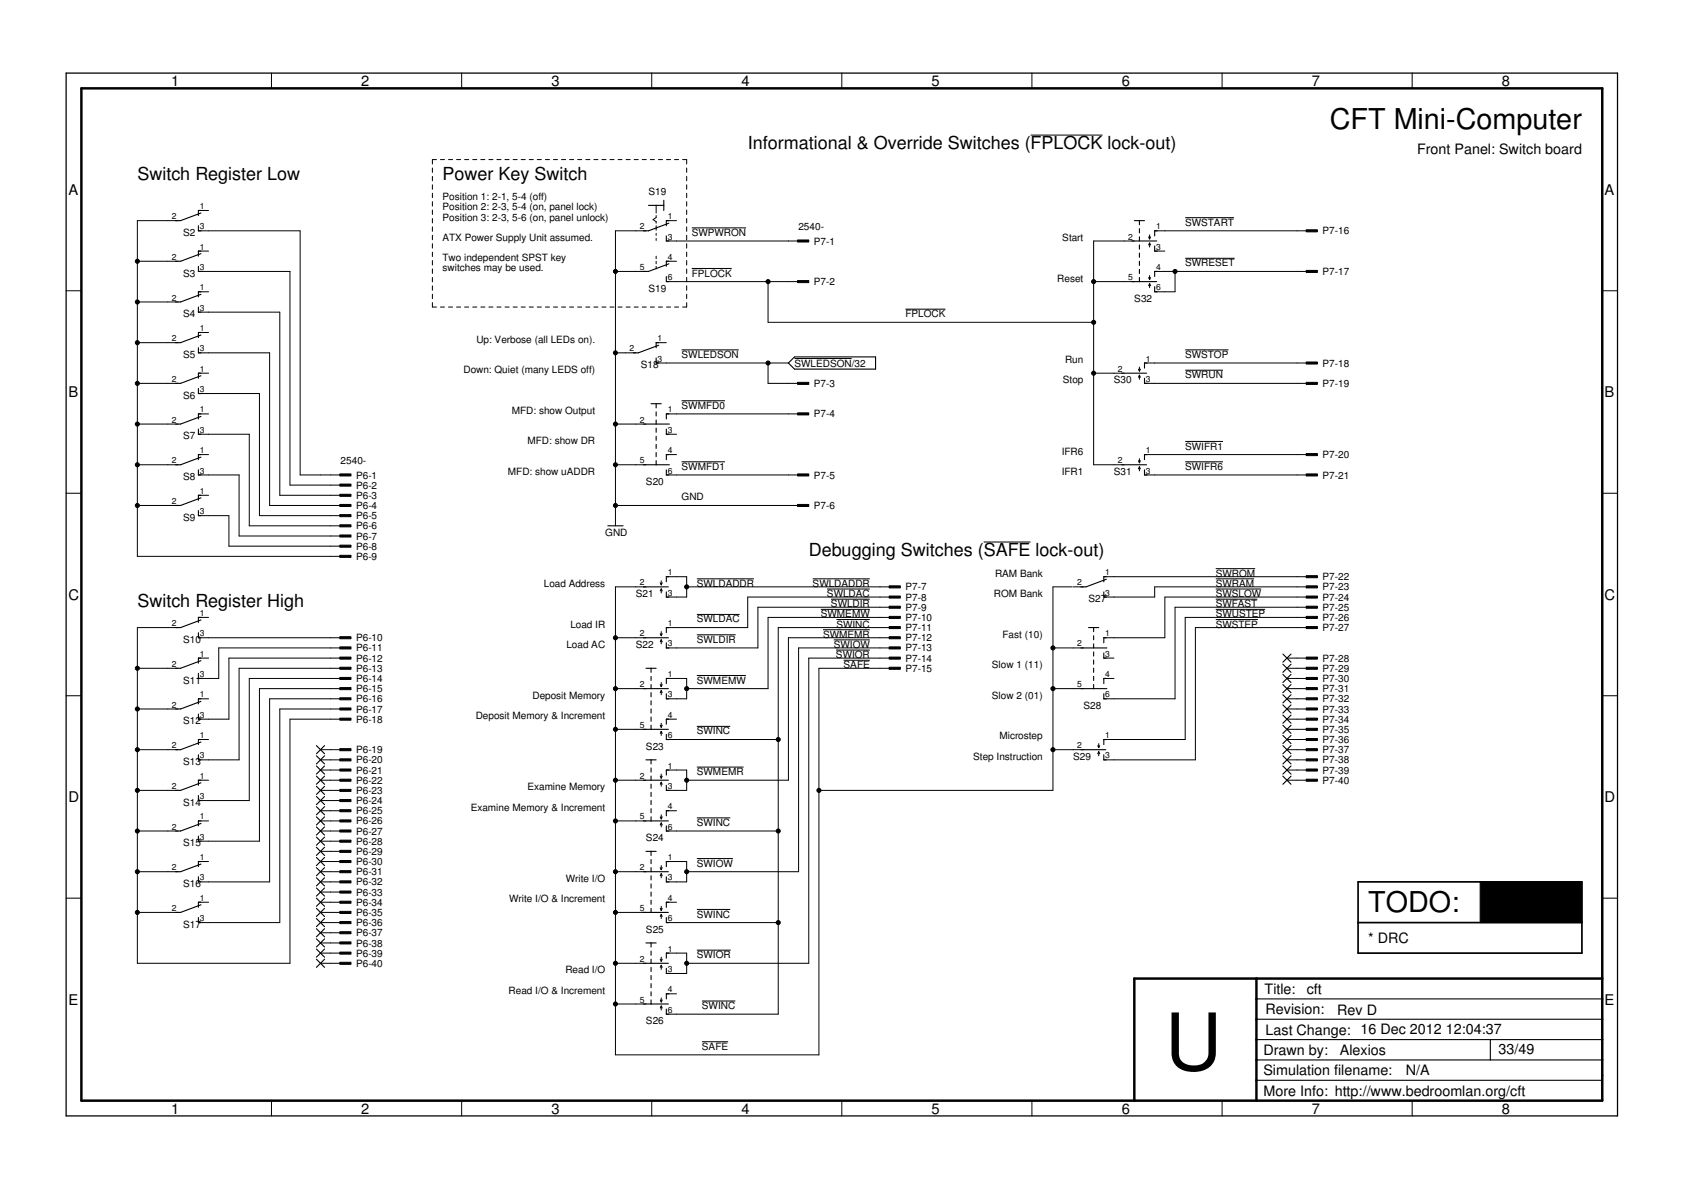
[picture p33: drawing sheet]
<svg xmlns="http://www.w3.org/2000/svg" width="420mm" height="297mm" viewBox="0 0 420 297" stroke-linecap="round" stroke-linejoin="round" font-family="sans-serif">
<defs><g id="words">
<text font-size="19.7" x="290.8" y="267.1">U</text>
<g font-size="7.2">
<text x="332" y="32.2">CFT Mini-Computer</text>
<text x="341.6" y="227.8">TODO:</text>
</g>
<g font-size="4.5">
<text x="186.7" y="37.3">Informational &amp; Override Switches (FPLOCK lock-out)</text>
<text x="34.3" y="44.9">Switch Register Low</text>
<text x="110.5" y="44.9">Power Key Switch</text>
<text x="201.9" y="138.9">Debugging Switches (SAFE lock-out)</text>
<text x="34.3" y="151.6">Switch Register High</text>
</g>
<g font-size="3.7">
<text x="42.7" y="21.5">1</text>
<text x="90.2" y="21.5">2</text>
<text x="137.7" y="21.5">3</text>
<text x="185.1" y="21.5">4</text>
<text x="232.6" y="21.5">5</text>
<text x="280" y="21.5">6</text>
<text x="327.5" y="21.5">7</text>
<text x="375" y="21.5">8</text>
<text x="17.1" y="48.6">A</text>
<text x="400.6" y="48.6">A</text>
<text x="17.1" y="99.2">B</text>
<text x="400.6" y="99.2">B</text>
<text x="17.1" y="149.7">C</text>
<text x="400.6" y="149.7">C</text>
<text x="17.1" y="200.2">D</text>
<text x="400.6" y="200.2">D</text>
<text x="17.1" y="250.8">E</text>
<text x="400.6" y="250.8">E</text>
<text x="42.7" y="277.9">1</text>
<text x="90.2" y="277.9">2</text>
<text x="137.7" y="277.9">3</text>
<text x="185.1" y="277.9">4</text>
<text x="232.6" y="277.9">5</text>
<text x="280" y="277.9">6</text>
<text x="327.5" y="277.9">7</text>
<text x="375" y="277.9">8</text>
</g>
<g font-size="3.6">
<text x="353.8" y="38.6">Front Panel: Switch board</text>
<text x="341.6" y="235.4">* DRC</text>
<text x="315.7" y="248.1">Title:</text>
<text x="326.2" y="248.2">cft</text>
<text x="315.9" y="253.2">Revision:</text>
<text x="333.8" y="253.3">Rev D</text>
<text x="315.4" y="263.3">Drawn by:</text>
<text x="315.9" y="258.2">Last Change: 16 Dec 2012</text>
<text x="334.5" y="263.3">Alexios</text>
<text x="361" y="258.1">12:04:37</text>
<text x="374.1" y="263.2">33/49</text>
<text x="315.4" y="268.4">Simulation filename:</text>
<text x="351" y="268.4">N/A</text>
<text x="315.4" y="273.5">More Info: http://www.bedroomlan.org/cft</text>
</g>
<g font-size="2.5">
<text x="110.5" y="50">Position 1: 2-1, 5-4 (off)</text>
<text x="110.5" y="52.5">Position 2: 2-3, 5-4 (on, panel lock)</text>
<text x="161.9" y="48.7">S19</text>
<text x="45.7" y="58.9">S2</text>
<text x="110.5" y="55.1">Position 3: 2-3, 5-6 (on, panel unlock)</text>
<text x="172.7" y="58.9">SWPWRON</text>
<text x="199.3" y="57.5">2540-</text>
<text x="295.9" y="56.3">SWSTART</text>
<text x="330.2" y="58.5">P7-16</text>
<text x="110.5" y="60.1">ATX Power Supply Unit assumed.</text>
<text x="110.5" y="65.2">Two independent SPST key</text>
<text x="203.2" y="61">P7-1</text>
<text x="265.2" y="60.1">Start</text>
<text x="45.7" y="69">S3</text>
<text x="110.5" y="67.8">switches may be used.</text>
<text x="172.7" y="69">FPLOCK</text>
<text x="203.2" y="71.2">P7-2</text>
<text x="263.9" y="70.3">Reset</text>
<text x="295.9" y="66.5">SWRESET</text>
<text x="330.2" y="68.7">P7-17</text>
<text x="161.9" y="72.8">S19</text>
<text x="283.2" y="75.4">S32</text>
<text x="45.7" y="79.2">S4</text>
<text x="226" y="79.2">FPLOCK</text>
<text x="45.7" y="89.3">S5</text>
<text x="118.9" y="85.5">Up: Verbose (all LEDs on).</text>
<text x="170.2" y="89.3">SWLEDSON</text>
<text x="295.9" y="89.3">SWSTOP</text>
<text x="115.7" y="93.2">Down: Quiet (many LEDS off)</text>
<text x="160" y="91.9">S18</text>
<text x="198.4" y="91.5">SWLEDSON/32</text>
<text x="265.4" y="95.7">Stop</text>
<text x="265.9" y="90.6">Run</text>
<text x="278.1" y="95.7">S30</text>
<text x="295.9" y="94.4">SWRUN</text>
<text x="330.2" y="91.5">P7-18</text>
<text x="45.7" y="99.5">S6</text>
<text x="203.2" y="96.6">P7-3</text>
<text x="330.2" y="96.6">P7-19</text>
<text x="127.8" y="103.3">MFD: show Output</text>
<text x="170.2" y="102">SWMFD0</text>
<text x="203.2" y="104.2">P7-4</text>
<text x="45.7" y="109.7">S7</text>
<text x="131.7" y="110.9">MFD: show DR</text>
<text x="265.1" y="113.5">IFR6</text>
<text x="295.9" y="112.2">SWIFR1</text>
<text x="45.7" y="119.8">S8</text>
<text x="85" y="115.9">2540-</text>
<text x="88.9" y="119.4">P6-1</text>
<text x="126.8" y="118.6">MFD: show uADDR</text>
<text x="170.2" y="117.3">SWMFD1</text>
<text x="203.2" y="119.4">P7-5</text>
<text x="265.1" y="118.6">IFR1</text>
<text x="278.1" y="118.6">S31</text>
<text x="295.9" y="117.3">SWIFR6</text>
<text x="330.2" y="114.4">P7-20</text>
<text x="330.2" y="119.4">P7-21</text>
<text x="88.9" y="122">P6-2</text>
<text x="88.9" y="124.5">P6-3</text>
<text x="161.3" y="121.1">S20</text>
<text x="170.2" y="124.9">GND</text>
<text x="45.7" y="130">S9</text>
<text x="88.9" y="127.1">P6-4</text>
<text x="88.9" y="129.6">P6-5</text>
<text x="203.2" y="127.1">P7-6</text>
<text x="88.9" y="132.1">P6-6</text>
<text x="88.9" y="134.7">P6-7</text>
<text x="88.9" y="137.2">P6-8</text>
<text x="151.1" y="133.8">GND</text>
<text x="88.9" y="139.8">P6-9</text>
<text x="248.4" y="144">RAM Bank</text>
<text x="303.5" y="144">SWROM</text>
<text x="135.8" y="146.5">Load Address</text>
<text x="158.7" y="149">S21</text>
<text x="174" y="146.5">SWLDADDR</text>
<text x="202.9" y="146.5">SWLDADDR</text>
<text x="206.5" y="149">SWLDAC</text>
<text x="226" y="147.4">P7-7</text>
<text x="226" y="149.9">P7-8</text>
<text x="248.1" y="149">ROM Bank</text>
<text x="303.5" y="149">SWSLOW</text>
<text x="303.5" y="146.5">SWRAM</text>
<text x="330.2" y="144.8">P7-22</text>
<text x="330.2" y="147.4">P7-23</text>
<text x="330.2" y="149.9">P7-24</text>
<text x="174" y="155.4">SWLDAC</text>
<text x="204.9" y="154.1">SWMEMW</text>
<text x="207.5" y="151.6">SWLDIR</text>
<text x="226" y="152.5">P7-9</text>
<text x="226" y="155">P7-10</text>
<text x="271.7" y="150.3">S27</text>
<text x="303.5" y="154.1">SWUSTEP</text>
<text x="303.5" y="151.6">SWFAST</text>
<text x="330.2" y="152.5">P7-25</text>
<text x="330.2" y="155">P7-26</text>
<text x="45.7" y="160.5">S10</text>
<text x="88.9" y="160.1">P6-10</text>
<text x="141.4" y="161.7">Load AC</text>
<text x="142.4" y="156.6">Load IR</text>
<text x="158.7" y="161.7">S22</text>
<text x="174" y="160.5">SWLDIR</text>
<text x="205.5" y="159.2">SWMEMR</text>
<text x="208.1" y="161.7">SWIOW</text>
<text x="208.8" y="156.6">SWINC</text>
<text x="226" y="157.5">P7-11</text>
<text x="226" y="160.1">P7-12</text>
<text x="250.3" y="159.2">Fast (10)</text>
<text x="303.5" y="156.6">SWSTEP</text>
<text x="330.2" y="157.5">P7-27</text>
<text x="88.9" y="162.6">P6-11</text>
<text x="88.9" y="165.2">P6-12</text>
<text x="88.9" y="167.7">P6-13</text>
<text x="208.7" y="164.3">SWIOR</text>
<text x="210.6" y="166.8">SAFE</text>
<text x="226" y="162.6">P7-13</text>
<text x="226" y="165.2">P7-14</text>
<text x="226" y="167.7">P7-15</text>
<text x="247.6" y="166.8">Slow 1 (11)</text>
<text x="330.2" y="165.2">P7-28</text>
<text x="330.2" y="167.7">P7-29</text>
<text x="45.7" y="170.6">S11</text>
<text x="88.9" y="170.2">P6-14</text>
<text x="88.9" y="172.8">P6-15</text>
<text x="174" y="170.6">SWMEMW</text>
<text x="330.2" y="170.2">P7-30</text>
<text x="330.2" y="172.8">P7-31</text>
<text x="88.9" y="175.3">P6-16</text>
<text x="88.9" y="177.9">P6-17</text>
<text x="118.8" y="179.5">Deposit Memory &amp; Increment</text>
<text x="132.9" y="174.4">Deposit Memory</text>
<text x="247.6" y="174.4">Slow 2 (01)</text>
<text x="270.5" y="177">S28</text>
<text x="330.2" y="175.3">P7-32</text>
<text x="330.2" y="177.9">P7-33</text>
<text x="45.7" y="180.8">S12</text>
<text x="88.9" y="180.4">P6-18</text>
<text x="174" y="183.3">SWINC</text>
<text x="249.5" y="184.6">Microstep</text>
<text x="330.2" y="180.4">P7-34</text>
<text x="330.2" y="182.9">P7-35</text>
<text x="330.2" y="185.5">P7-36</text>
<text x="45.7" y="190.9">S13</text>
<text x="88.9" y="188">P6-19</text>
<text x="88.9" y="190.6">P6-20</text>
<text x="161.3" y="187.1">S23</text>
<text x="243" y="189.7">Step Instruction</text>
<text x="267.9" y="189.7">S29</text>
<text x="330.2" y="188">P7-37</text>
<text x="330.2" y="190.6">P7-38</text>
<text x="88.9" y="193.1">P6-21</text>
<text x="88.9" y="195.6">P6-22</text>
<text x="131.7" y="197.3">Examine Memory</text>
<text x="174" y="193.5">SWMEMR</text>
<text x="330.2" y="193.1">P7-39</text>
<text x="330.2" y="195.6">P7-40</text>
<text x="45.7" y="201.1">S14</text>
<text x="88.9" y="198.2">P6-23</text>
<text x="88.9" y="200.7">P6-24</text>
<text x="88.9" y="203.3">P6-25</text>
<text x="117.5" y="202.4">Examine Memory &amp; Increment</text>
<text x="88.9" y="205.8">P6-26</text>
<text x="88.9" y="208.3">P6-27</text>
<text x="161.3" y="210">S24</text>
<text x="174" y="206.2">SWINC</text>
<text x="45.7" y="211.2">S15</text>
<text x="88.9" y="210.9">P6-28</text>
<text x="88.9" y="213.4">P6-29</text>
<text x="88.9" y="215.9">P6-30</text>
<text x="45.7" y="221.4">S16</text>
<text x="88.9" y="218.5">P6-31</text>
<text x="88.9" y="221">P6-32</text>
<text x="141.3" y="220.1">Write I/O</text>
<text x="174" y="216.3">SWIOW</text>
<text x="88.9" y="223.6">P6-33</text>
<text x="88.9" y="226.1">P6-34</text>
<text x="127.1" y="225.2">Write I/O &amp; Increment</text>
<text x="45.7" y="231.6">S17</text>
<text x="88.9" y="228.6">P6-35</text>
<text x="88.9" y="231.2">P6-36</text>
<text x="88.9" y="233.7">P6-37</text>
<text x="161.3" y="232.8">S25</text>
<text x="174" y="229">SWINC</text>
<text x="88.9" y="236.3">P6-38</text>
<text x="88.9" y="238.8">P6-39</text>
<text x="174" y="239.2">SWIOR</text>
<text x="88.9" y="241.3">P6-40</text>
<text x="141.1" y="243">Read I/O</text>
<text x="127" y="248.1">Read I/O &amp; Increment</text>
<text x="175.2" y="251.9">SWINC</text>
<text x="161.3" y="255.7">S26</text>
<text x="175.2" y="262">SAFE</text>
</g>
<g font-size="2.1">
<text x="49.9" y="52.2">1</text>
<text x="42.9" y="54.7">2</text>
<text x="49.9" y="57.2">3</text>
<text x="159.7" y="57.2">2</text>
<text x="166.7" y="59.8">3</text>
<text x="166.7" y="54.7">1</text>
<text x="281.6" y="59.8">2</text>
<text x="288.6" y="57.2">1</text>
<text x="42.9" y="64.9">2</text>
<text x="49.9" y="62.3">1</text>
<text x="166.7" y="64.9">4</text>
<text x="288.6" y="62.3">3</text>
<text x="49.9" y="67.4">3</text>
<text x="159.7" y="67.4">5</text>
<text x="166.7" y="69.9">6</text>
<text x="281.6" y="69.9">5</text>
<text x="288.6" y="67.4">4</text>
<text x="42.9" y="75">2</text>
<text x="49.9" y="77.6">3</text>
<text x="49.9" y="72.5">1</text>
<text x="288.6" y="72.5">6</text>
<text x="49.9" y="82.6">1</text>
<text x="42.9" y="85.2">2</text>
<text x="49.9" y="87.7">3</text>
<text x="157.2" y="87.7">2</text>
<text x="164.2" y="85.2">1</text>
<text x="42.9" y="95.3">2</text>
<text x="49.9" y="92.8">1</text>
<text x="164.2" y="90.3">3</text>
<text x="279.1" y="92.8">2</text>
<text x="286.1" y="95.3">3</text>
<text x="286.1" y="90.3">1</text>
<text x="49.9" y="97.9">3</text>
<text x="42.9" y="105.5">2</text>
<text x="49.9" y="103">1</text>
<text x="159.7" y="105.5">2</text>
<text x="166.7" y="103">1</text>
<text x="49.9" y="108">3</text>
<text x="49.9" y="113.1">1</text>
<text x="166.7" y="108">3</text>
<text x="166.7" y="113.1">4</text>
<text x="286.1" y="113.1">1</text>
<text x="42.9" y="115.7">2</text>
<text x="49.9" y="118.2">3</text>
<text x="159.7" y="115.7">5</text>
<text x="166.7" y="118.2">6</text>
<text x="279.1" y="115.7">2</text>
<text x="286.1" y="118.2">3</text>
<text x="42.9" y="125.8">2</text>
<text x="49.9" y="123.3">1</text>
<text x="49.9" y="128.4">3</text>
<text x="166.7" y="143.6">1</text>
<text x="275.9" y="143.6">1</text>
<text x="159.7" y="146.1">2</text>
<text x="166.7" y="148.7">3</text>
<text x="268.9" y="146.1">2</text>
<text x="275.9" y="148.7">3</text>
<text x="49.9" y="153.8">1</text>
<text x="42.9" y="156.3">2</text>
<text x="49.9" y="158.8">3</text>
<text x="159.7" y="158.8">2</text>
<text x="166.7" y="161.4">3</text>
<text x="166.7" y="156.3">1</text>
<text x="268.9" y="161.4">2</text>
<text x="275.9" y="158.8">1</text>
<text x="42.9" y="166.5">2</text>
<text x="49.9" y="163.9">1</text>
<text x="275.9" y="163.9">3</text>
<text x="49.9" y="169">3</text>
<text x="159.7" y="171.5">2</text>
<text x="166.7" y="169">1</text>
<text x="268.9" y="171.5">5</text>
<text x="275.9" y="169">4</text>
<text x="42.9" y="176.6">2</text>
<text x="49.9" y="179.1">3</text>
<text x="49.9" y="174.1">1</text>
<text x="166.7" y="174.1">3</text>
<text x="166.7" y="179.1">4</text>
<text x="275.9" y="174.1">6</text>
<text x="49.9" y="184.2">1</text>
<text x="159.7" y="181.7">5</text>
<text x="166.7" y="184.2">6</text>
<text x="275.9" y="184.2">1</text>
<text x="42.9" y="186.8">2</text>
<text x="49.9" y="189.3">3</text>
<text x="166.7" y="191.8">1</text>
<text x="268.9" y="186.8">2</text>
<text x="275.9" y="189.3">3</text>
<text x="42.9" y="196.9">2</text>
<text x="49.9" y="194.4">1</text>
<text x="159.7" y="194.4">2</text>
<text x="166.7" y="196.9">3</text>
<text x="49.9" y="199.5">3</text>
<text x="166.7" y="202">4</text>
<text x="42.9" y="207.1">2</text>
<text x="49.9" y="209.6">3</text>
<text x="49.9" y="204.5">1</text>
<text x="159.7" y="204.5">5</text>
<text x="166.7" y="207.1">6</text>
<text x="49.9" y="214.7">1</text>
<text x="166.7" y="214.7">1</text>
<text x="42.9" y="217.2">2</text>
<text x="49.9" y="219.8">3</text>
<text x="159.7" y="217.2">2</text>
<text x="166.7" y="219.8">3</text>
<text x="42.9" y="227.4">2</text>
<text x="49.9" y="224.9">1</text>
<text x="159.7" y="227.4">5</text>
<text x="166.7" y="224.9">4</text>
<text x="49.9" y="229.9">3</text>
<text x="166.7" y="229.9">6</text>
<text x="166.7" y="237.6">1</text>
<text x="159.7" y="240.1">2</text>
<text x="166.7" y="242.6">3</text>
<text x="159.7" y="250.3">5</text>
<text x="166.7" y="247.7">4</text>
<text x="166.7" y="252.8">6</text>
</g>
</g></defs>
<g fill="#000" stroke="#000" stroke-width=".25">
<path d="M67.8 18.2v3.9zM115.3 18.2v3.9zM162.7 18.2v3.9zM210.2 18.2v3.9zM257.6 18.2v3.9zM305.1 18.2v3.9zM352.5 18.2v3.9zM20.3 22.1v252.6zM107.9 39.8h1.1zM110 39.8h1zM112 39.8h1zM114 39.8h1z"/>
<path d="M116 39.8h1zM118 39.8h1zM120 39.8h1.1zM122 39.8h1.1zM124.1 39.8h1zM126.1 39.8h1zM128.1 39.8h1zM130.1 39.8h1zM132.1 39.8h1zM134.1 39.8h1zM136.2 39.8h1zM138.2 39.8h1z"/>
<path d="M140.2 39.8h1zM142.2 39.8h1zM144.2 39.8h1zM146.2 39.8h1.1zM148.2 39.8h1.1zM150.3 39.8h1zM152.3 39.8h1zM154.3 39.8h1zM156.3 39.8h1zM158.3 39.8h1zM160.3 39.8h1.1zM162.3 39.8h1.1z"/>
<path d="M164.4 39.8h1zM166.4 39.8h1zM168.4 39.8h1zM170.4 39.8h1zM171.4 39.8v1.1zM257.3 33.7h18zM20.3 22.1h379.7zM34.3 55.1v10.1zM41.9 55.1h2.5zM34.3 55.1h7.6zM49.5 57.6h2.6zM49.5 52.5h2.6z"/>
<path d="M52.1 57.6h22.8zM74.9 57.6v61zM107.9 58.7v1.1zM107.9 56.6v1.1zM107.9 54.5v1.1zM107.9 52.4v1.1zM107.9 50.3v1.1zM107.9 48.2v1.1zM107.9 46.1v1.1zM107.9 44v1.1zM107.9 41.9v1.1zM107.9 39.8v1.1z"/>
<path d="M153.6 57.6v10.2zM158.7 57.6h2.6zM153.6 57.6h5.1zM163 54.8l.8 .5zM163.8 51.3v1.9zM163.8 53.8v.5zM163.8 55.3v.4zM163.8 56.3v.7zM163 54.8l.8-.5zM163.8 57v.5zM163.8 58.2v.6zM163.8 59.5v.5z"/>
<path d="M166.3 55.1h2.6zM171.4 41.9v1.1zM171.4 44v1.1zM171.4 46.1v1.1zM171.4 48.2v1.1zM171.4 50.3v1.1zM171.4 52.4v1.1zM171.4 54.5v1.1zM171.4 56.6v1.1zM171.4 58.7v1.1zM172.7 56.9h13.6zM287 58.6v1z"/>
<path d="M287.2 59.1l-.2 .5zM286.7 59.1l.3 .5zM288.3 57.6h2.5zM290.8 57.6h33zM295.9 54.3h12.2zM323.8 57.6h2.6zM16.5 72.6h3.8zM34.3 75.4v10.1zM34.3 65.2v10.2zM41.9 65.2h2.5zM41.9 75.4h2.5zM34.3 75.4h7.6z"/>
<path d="M34.3 65.2h7.6zM49.5 67.8h2.6zM49.5 62.7h2.6zM49.5 77.9h2.6zM49.5 72.8h2.6zM52.1 67.8h20.3zM52.1 77.9h17.7zM69.8 77.9v45.7zM72.4 67.8v53.3zM107.9 75.5v1.1zM107.9 73.4v1.1zM107.9 71.4v1.1z"/>
<path d="M107.9 69.3v1.1zM107.9 67.1v1.1zM107.9 65v1.1zM107.9 62.9v1.1zM107.9 60.8v1.1zM107.9 76.6h1.1zM110 76.6h1zM112 76.6h1zM114 76.6h1zM116 76.6h1zM118 76.6h1zM120 76.6h1.1z"/>
<path d="M122 76.6h1.1zM124.1 76.6h1zM126.1 76.6h1zM128.1 76.6h1zM130.1 76.6h1zM132.1 76.6h1zM134.1 76.6h1zM136.2 76.6h1zM138.2 76.6h1zM140.2 76.6h1zM142.2 76.6h1zM144.2 76.6h1z"/>
<path d="M146.2 76.6h1.1zM148.2 76.6h1.1zM150.3 76.6h1zM152.3 76.6h1zM153.6 67.8v20.3zM154.3 76.6h1zM156.3 76.6h1zM158.7 67.8h2.6zM153.6 67.8h5.1zM158.3 76.6h1zM160.3 76.6h1.1zM162.3 76.6h1.1z"/>
<path d="M163.8 66.5v.6zM163.8 65.2v.6zM163.8 63.9v.7zM164.4 76.6h1zM166.4 76.6h1zM166.3 70.3h2.6zM166.3 65.2h2.6zM166.3 60.2h2.6zM168.9 70.3h22.8zM168.9 60.2h27.9zM168.4 76.6h1zM171.4 60.8v1.1z"/>
<path d="M171.4 62.9v1.1zM171.4 65v1.1zM171.4 67.1v1.1zM171.4 69.2v1.2zM171.4 71.4v1.1zM171.4 73.4v1.1zM171.4 75.5v1.1zM170.4 76.6h1zM172.7 67h10zM191.7 70.3h5.1zM191.7 70.3v10.2zM196.8 60.2h2.6z"/>
<path d="M196.8 70.3h2.6zM226 77.2h10zM273 60.2h7.6zM273 70.3h7.6zM273 60.2v10.1zM280.6 60.2h2.6zM280.6 70.3h2.6zM287 60.7l.2 .4zM287 60.7l-.3 .4zM287 60.7v1zM287 68.8v1zM287.2 69.3l-.2 .5z"/>
<path d="M286.7 69.3l.3 .5zM287 70.8l.2 .5zM287 70.8l-.3 .5zM287 70.8v1zM288.3 62.7h2.5zM288.3 72.8h2.5zM288.3 67.8h2.5zM290.8 67.8h2.5zM290.8 72.8h2.5zM293.3 67.8h30.5zM293.3 67.8v5zM295.9 64.5h12.3z"/>
<path d="M323.8 67.8h2.6zM400 72.6h3.8zM34.3 95.7v10.2zM34.3 85.5v10.2zM41.9 85.5h2.5zM41.9 95.7h2.5zM34.3 95.7h7.6zM34.3 85.5h7.6zM49.5 88.1h2.6zM49.5 83h2.6zM49.5 98.2h2.6zM49.5 93.2h2.6z"/>
<path d="M52.1 88.1h15.2zM52.1 98.2h12.7zM64.8 98.2v30.5zM67.3 88.1v38.1zM153.6 88.1v17.8zM156.2 88.1h2.5zM153.6 88.1h2.6zM163.8 90.6h2.5zM163.8 85.5h2.5zM166.3 90.6h25.4zM170.2 87.3h14.2zM191.7 80.5h81.3z"/>
<path d="M191.7 90.6v5.1zM191.7 95.7h5.1zM191.7 90.6h5.1zM196.8 95.7h2.6zM198.3 89.5h14.3zM273 80.5v12.7zM273 70.3v10.2zM278.1 93.2h2.5zM273 93.2h5.1zM284.5 91.6v1zM284.7 92.1l-.2 .5zM284.2 92.1l.3 .5z"/>
<path d="M284.5 93.7l.2 .5zM284.5 93.7l-.3 .5zM284.5 93.7v1zM285.7 95.7h2.6zM285.7 90.6h2.6zM288.3 90.6h35.5zM295.9 87.3h10.8zM295.9 92.4h9.4zM323.8 90.6h2.6zM323.8 95.7h2.6zM288.3 95.7h35.5zM34.3 116v10.2z"/>
<path d="M34.3 105.9v10.1zM41.9 105.9h2.5zM41.9 116h2.5zM34.3 116h7.6zM34.3 105.9h7.6zM49.5 108.4h2.6zM49.5 103.3h2.6zM49.5 118.6h2.6zM49.5 113.5h2.6zM52.1 108.4h10.1zM52.1 118.6h7.6zM59.7 118.6v15.2z"/>
<path d="M62.2 108.4v22.9zM74.9 118.6h5.1zM80 118.6h2.5zM82.5 118.6h2.6zM153.6 105.9v10.1zM158.7 105.9h2.6zM158.7 116h2.6zM153.6 105.9h5.1zM153.6 116h5.1zM166.3 108.4h2.6zM166.3 103.3h2.6zM166.3 118.6h2.6z"/>
<path d="M166.3 113.5h2.6zM168.9 103.3h27.9zM168.9 118.6h27.9zM170.2 100h10.8zM170.2 115.3h10.8zM196.8 103.3h2.6zM196.8 118.6h2.6zM273 93.2v22.8zM278.1 116h2.5zM273 116h5.1zM284.5 114.5v1zM284.7 115l-.2 .5z"/>
<path d="M284.2 115l.3 .5zM284.5 116.5l.2 .5zM284.5 116.5l-.3 .5zM284.5 116.5v1zM285.7 118.6h2.6zM285.7 113.5h2.6zM295.9 110.2h9.4zM295.9 115.3h9.4zM323.8 113.5h2.6zM323.8 118.6h2.6zM288.3 113.5h35.5zM288.3 118.6h35.5z"/>
<path d="M16.5 123.1h3.8zM34.3 126.2v12.7zM34.3 138.9h48.2zM41.9 126.2h2.5zM34.3 126.2h7.6zM49.5 128.7h2.6zM49.5 123.6h2.6zM52.1 128.7h5zM57.1 128.7v7.6zM57.1 136.3h25.4zM59.7 133.8h22.8zM62.2 131.3h20.3z"/>
<path d="M64.8 128.7h17.7zM67.3 126.2h15.2zM69.8 123.6h12.7zM72.4 121.1h10.1zM82.5 121.1h2.6zM82.5 123.6h2.6zM82.5 126.2h2.6zM82.5 128.7h2.6zM82.5 131.3h2.6zM82.5 133.8h2.6zM82.5 136.3h2.6zM82.5 138.9h2.6z"/>
<path d="M153.6 128.7v2.6zM153.6 116v10.2zM153.6 126.2h43.2zM153.6 126.2v2.5zM196.8 126.2h2.6zM245.6 135.3h11.7zM400 123.1h3.8zM34.3 156.7v10.1zM41.9 156.7h2.5zM34.3 156.7h7.6zM49.5 159.2h2.6zM49.5 154.1h2.6z"/>
<path d="M52.1 159.2h30.4zM82.5 159.2h2.6zM153.6 146.5h5.1zM153.6 159.2v12.7zM153.6 146.5v12.7zM158.7 159.2h2.6zM158.7 146.5h2.6zM153.6 159.2h5.1zM165.1 157.7v1zM165.3 158.2l-.2 .5zM164.8 158.2l.3 .5zM165.1 159.7l.2 .5z"/>
<path d="M165.1 159.7l-.3 .5zM165.1 159.7v1zM165.1 145v1zM165.3 145.5l-.2 .5zM164.8 145.5l.3 .5zM165.1 147l.2 .5zM165.1 147l-.3 .5zM165.1 147v1zM166.3 156.7h2.6zM166.3 149h2.6zM166.3 144h2.6zM168.9 144h2.5z"/>
<path d="M171.4 144v2.5zM171.4 146.5v2.5zM168.9 149h2.5zM171.4 146.5h48.3zM174 144.5h14.2zM174 153.4h10.7zM174 158.5h9.7zM168.9 156.7h17.8zM186.7 149v7.7zM186.7 149h33zM189.2 151.6v10.1zM191.7 154.1h28z"/>
<path d="M194.3 156.7h25.4zM196.8 159.2h22.9zM202.9 144.5h14.2zM204.9 152.1h12.2zM205.5 157.2h11.6zM206.5 147h10.6zM207.5 149.6h9.6zM208.1 159.7h9zM208.8 154.6h8.3zM219.7 146.5h2.5zM219.7 149h2.5zM219.7 151.6h2.5z"/>
<path d="M219.7 154.1h2.5zM219.7 156.7h2.5zM219.7 159.2h2.5zM189.2 151.6h30.5zM262.9 146.5v15.2zM262.9 146.5h4.8zM267.9 146.5h2.6zM275.6 159.2h2.5zM275.6 149h2.5zM275.6 144h2.5zM278.1 144h45.7zM278.1 149h10.2z"/>
<path d="M288.3 146.5v2.5zM288.3 146.5h35.5zM290.8 149v10.2zM278.1 159.2h12.7zM293.3 151.6v22.8zM295.9 154.1v30.5zM298.4 156.7v33zM303.5 152.1h12.3zM303.5 154.6h10.5zM303.5 147h11.3zM303.5 149.6h10.4zM303.5 141.9h9.8z"/>
<path d="M303.5 144.5h9.6zM323.8 144h2.6zM323.8 146.5h2.6zM323.8 149h2.6zM323.8 151.6h2.6zM323.8 154.1h2.6zM323.8 156.7h2.6zM295.9 154.1h27.9zM298.4 156.7h25.4zM290.8 149h33zM293.3 151.6h30.5zM16.5 173.7h3.8z"/>
<path d="M34.3 166.8v10.2zM34.3 177v10.1zM41.9 166.8h2.5zM41.9 177h2.5zM34.3 177h7.6zM34.3 166.8h7.6zM49.5 169.4h2.6zM49.5 164.3h2.6zM49.5 179.5h2.6zM49.5 174.4h2.6zM52.1 169.4h2.5zM52.1 179.5h5z"/>
<path d="M54.6 161.7h27.9zM54.6 161.7v7.7zM57.1 164.3h25.4zM57.1 164.3v15.2zM59.7 166.8h22.8zM62.2 169.4h20.3zM64.8 171.9h17.7zM67.3 174.4h15.2zM69.8 177h12.7zM72.4 179.5h10.1zM82.5 161.7h2.6zM82.5 164.3h2.6z"/>
<path d="M82.5 166.8h2.6zM82.5 169.4h2.6zM82.5 171.9h2.6zM82.5 174.4h2.6zM82.5 177h2.6zM82.5 179.5h2.6zM153.6 171.9h5.1zM153.6 171.9v10.2zM158.7 171.9h2.6zM165.1 170.4v1zM165.3 170.9l-.2 .5zM164.8 170.9l.3 .5z"/>
<path d="M165.1 172.4l.2 .5zM165.1 172.4l-.3 .5zM165.1 172.4v1zM166.3 161.7h2.6zM166.3 174.4h2.6zM166.3 169.4h2.6zM166.3 179.5h2.6zM168.9 169.4h2.5zM171.4 169.4v2.5zM171.4 171.9v2.5zM168.9 174.4h2.5zM171.4 171.9h20.3z"/>
<path d="M174 168.6h12.2zM168.9 161.7h20.3zM191.7 154.1v17.8zM199.4 161.7h20.3zM201.9 164.3h17.8zM204.4 166.8h15.3zM208.7 162.3h8.4zM210.6 164.8h6.5zM219.7 161.7h2.5zM219.7 164.3h2.5zM219.7 166.8h2.5zM262.9 161.7v10.2z"/>
<path d="M262.9 171.9v15.2zM267.9 161.7h2.6zM267.9 171.9h2.6zM262.9 161.7h5zM262.9 171.9h5zM275.6 164.3h2.5zM275.6 174.4h2.5zM275.6 169.4h2.5zM278.1 174.4h15.2zM323.8 164.3h2.6zM323.8 166.8h2.6zM323.8 169.4h2.6z"/>
<path d="M323.8 171.9h2.6zM323.8 174.4h2.6zM323.8 177h2.6zM323.8 179.5h2.6zM321.3 164.3h2.5zM321.3 166.8h2.5zM321.3 169.4h2.5zM321.3 171.9h2.5zM321.3 174.4h2.5zM321.3 177h2.5zM321.3 179.5h2.5zM400 173.7h3.8z"/>
<path d="M34.3 187.1v10.2zM34.3 197.3v10.1zM41.9 187.1h2.5zM41.9 197.3h2.5zM34.3 197.3h7.6zM34.3 187.1h7.6zM49.5 189.7h2.6zM49.5 184.6h2.6zM49.5 199.8h2.6zM49.5 194.8h2.6zM52.1 189.7h7.6zM52.1 199.8h10.1z"/>
<path d="M59.7 166.8v22.9zM62.2 169.4v30.4zM82.5 187.1h2.6zM82.5 189.7h2.6zM82.5 192.2h2.6zM82.5 194.8h2.6zM82.5 197.3h2.6zM82.5 199.8h2.6zM80 187.1h2.5zM80 189.7h2.5zM80 192.2h2.5zM80 194.8h2.5z"/>
<path d="M80 197.3h2.5zM80 199.8h2.5zM153.6 194.8h5.1zM153.6 194.8v10.1zM153.6 182.1h5.1zM153.6 182.1v12.7zM158.7 182.1h2.6zM158.7 194.8h2.6zM165.1 180.5v1zM165.3 181l-.2 .5zM164.8 181l.3 .5zM165.1 182.6l.2 .5z"/>
<path d="M165.1 182.6l-.3 .5zM165.1 182.6v1zM165.1 193.2v1zM165.3 193.7l-.2 .5zM164.8 193.7l.3 .5zM165.1 195.3l.2 .5zM165.1 195.3l-.3 .5zM165.1 195.3v1zM166.3 184.6h2.6zM166.3 197.3h2.6zM166.3 192.2h2.6zM168.9 184.6h25.4z"/>
<path d="M168.9 192.2h2.5zM171.4 192.2v2.6zM171.4 194.8v2.5zM168.9 197.3h2.5zM171.4 194.8h25.4zM174 181.3h8.3zM174 191.5h11.6zM194.3 156.7v27.9zM196.8 159.2v35.6zM204.4 166.8v30.5zM262.9 187.1v10.2zM204.4 197.3h58.5z"/>
<path d="M267.9 187.1h2.6zM262.9 187.1h5zM274.3 185.6v1zM274.5 186.1l-.2 .5zM274 186.1l.3 .5zM274.3 187.6l.2 .5zM274.3 187.6l-.3 .5zM274.3 187.6v1.1zM275.6 189.7h2.5zM275.6 184.6h2.5zM278.1 184.6h17.8zM278.1 189.7h20.3z"/>
<path d="M323.8 182.1h2.6zM323.8 184.6h2.6zM323.8 187.1h2.6zM323.8 189.7h2.6zM323.8 192.2h2.6zM323.8 194.8h2.6zM321.3 182.1h2.5zM321.3 184.6h2.5zM321.3 187.1h2.5zM321.3 189.7h2.5zM321.3 192.2h2.5zM321.3 194.8h2.5z"/>
<path d="M34.3 207.4v10.2zM34.3 217.6v10.1zM41.9 207.4h2.5zM41.9 217.6h2.5zM34.3 217.6h7.6zM34.3 207.4h7.6zM49.5 210h2.6zM49.5 204.9h2.6zM49.5 215h2.6zM52.1 210h12.7zM64.8 171.9v38.1zM82.5 202.4h2.6z"/>
<path d="M82.5 204.9h2.6zM82.5 207.4h2.6zM82.5 210h2.6zM82.5 212.5h2.6zM82.5 215h2.6zM82.5 217.6h2.6zM80 202.4h2.5zM80 204.9h2.5zM80 207.4h2.5zM80 210h2.5zM80 212.5h2.5zM80 215h2.5z"/>
<path d="M80 217.6h2.5zM153.6 217.6h5.1zM153.6 217.6v10.1zM153.6 204.9h5.1zM153.6 204.9v12.7zM158.7 204.9h2.6zM158.7 217.6h2.6zM165.1 203.4v1zM165.3 203.9l-.2 .5zM164.8 203.9l.3 .5zM165.1 205.4l.2 .5zM165.1 205.4l-.3 .5z"/>
<path d="M165.1 205.4v1zM165.1 216.1v1zM165.3 216.6l-.2 .5zM164.8 216.6l.3 .5zM165.1 218.1l.2 .5zM165.1 218.1l-.3 .5zM165.1 218.1v1zM166.3 207.4h2.6zM166.3 202.4h2.6zM166.3 215h2.6zM168.9 207.4h25.4zM168.9 215h2.5z"/>
<path d="M171.4 215v2.6zM171.4 217.6v2.5zM171.4 217.6h28zM174 204.1h8.3zM174 214.3h9zM194.3 184.6v22.8zM199.4 161.7v55.9zM16.5 224.2h3.8zM34.3 227.7v12.7zM41.9 227.7h2.5zM34.3 227.7h7.6zM49.5 220.1h2.6z"/>
<path d="M49.5 230.3h2.6zM49.5 225.2h2.6zM52.1 220.1h15.2zM52.1 230.3h17.7zM67.3 174.4v45.7zM69.8 177v53.3zM82.5 220.1h2.6zM82.5 222.7h2.6zM82.5 225.2h2.6zM82.5 227.7h2.6zM82.5 230.3h2.6zM82.5 232.8h2.6z"/>
<path d="M82.5 235.4h2.6zM82.5 237.9h2.6zM80 220.1h2.5zM80 222.7h2.5zM80 225.2h2.5zM80 227.7h2.5zM80 230.3h2.5zM80 232.8h2.5zM80 235.4h2.5zM80 237.9h2.5zM153.6 227.7h5.1zM153.6 227.7v12.7z"/>
<path d="M158.7 227.7h2.6zM165.1 226.2v1zM165.3 226.7l-.2 .5zM164.8 226.7l.3 .5zM165.1 228.3l.2 .5zM165.1 228.3l-.3 .5zM165.1 228.3v1zM165.1 238.9v1zM165.3 239.4l-.2 .5zM164.8 239.4l.3 .5zM166.3 220.1h2.6zM166.3 230.3h2.6z"/>
<path d="M166.3 225.2h2.6zM166.3 237.9h2.6zM168.9 230.3h25.4zM168.9 237.9h2.5zM168.9 220.1h2.5zM171.4 237.9v2.5zM174 227h8.3zM174 237.2h8.4zM194.3 207.4v22.9zM400 224.2h3.8zM34.3 240.4h38.1zM72.4 179.5v60.9z"/>
<path d="M82.5 240.4h2.6zM80 240.4h2.5zM153.6 250.6h5.1zM153.6 250.6v12.7zM153.6 240.4h5.1zM153.6 240.4v10.2zM158.7 240.4h2.6zM158.7 250.6h2.6zM165.1 241l.2 .5zM165.1 241l-.3 .5zM165.1 241v1zM165.1 249.1v1z"/>
<path d="M165.3 249.6l-.2 .5zM164.8 249.6l.3 .5zM165.1 251.1l.2 .5zM165.1 251.1l-.3 .5zM165.1 251.1v1zM166.3 243h2.6zM166.3 253.1h2.6zM166.3 248.1h2.6zM168.9 253.1h25.4zM171.4 240.4v2.6zM168.9 243h2.5zM171.4 240.4h30.5z"/>
<path d="M175.2 249.9h8.4zM194.3 230.3v22.8zM201.9 164.3v76.1zM20.3 274.7h379.7zM67.8 274.7v3.8zM115.3 274.7v3.8zM153.6 263.3h50.8zM162.7 274.7v3.8zM175.2 260h6.6zM204.4 197.3v66zM210.2 274.7v3.8zM257.6 274.7v3.8z"/>
<path d="M305.1 274.7v3.8zM352.5 274.7v3.8zM400 264.5v.1zM400 268.4v6.2zM400 274.6h.1zM400 22.1v252.6z"/>
<circle cx="34.3" cy="65.2" r=".51"/>
<circle cx="34.3" cy="75.4" r=".51"/>
<circle cx="153.6" cy="67.8" r=".51"/>
<circle cx="191.7" cy="70.3" r=".51"/>
<circle cx="273" cy="70.3" r=".51"/>
<circle cx="293.3" cy="67.8" r=".51"/>
<circle cx="34.3" cy="85.5" r=".51"/>
<circle cx="34.3" cy="95.7" r=".51"/>
<circle cx="153.6" cy="88.1" r=".51"/>
<circle cx="191.7" cy="90.6" r=".51"/>
<circle cx="273" cy="80.5" r=".51"/>
<circle cx="273" cy="93.2" r=".51"/>
<circle cx="34.3" cy="116" r=".51"/>
<circle cx="34.3" cy="105.9" r=".51"/>
<circle cx="153.6" cy="105.9" r=".51"/>
<circle cx="153.6" cy="116" r=".51"/>
<circle cx="34.3" cy="126.2" r=".51"/>
<circle cx="153.6" cy="126.2" r=".51"/>
<circle cx="153.6" cy="159.2" r=".51"/>
<circle cx="171.4" cy="146.5" r=".51"/>
<circle cx="34.3" cy="177" r=".51"/>
<circle cx="34.3" cy="166.8" r=".51"/>
<circle cx="153.6" cy="171.9" r=".51"/>
<circle cx="171.4" cy="171.9" r=".51"/>
<circle cx="262.9" cy="161.7" r=".51"/>
<circle cx="262.9" cy="171.9" r=".51"/>
<circle cx="34.3" cy="187.1" r=".51"/>
<circle cx="34.3" cy="197.3" r=".51"/>
<circle cx="153.6" cy="194.8" r=".51"/>
<circle cx="153.6" cy="182.1" r=".51"/>
<circle cx="171.4" cy="194.8" r=".51"/>
<circle cx="194.3" cy="184.6" r=".51"/>
<circle cx="204.4" cy="197.3" r=".51"/>
<circle cx="262.9" cy="187.1" r=".51"/>
<circle cx="34.3" cy="207.4" r=".51"/>
<circle cx="34.3" cy="217.6" r=".51"/>
<circle cx="153.6" cy="204.9" r=".51"/>
<circle cx="153.6" cy="217.6" r=".51"/>
<circle cx="171.4" cy="217.6" r=".51"/>
<circle cx="194.3" cy="207.4" r=".51"/>
<circle cx="34.3" cy="227.7" r=".51"/>
<circle cx="153.6" cy="227.7" r=".51"/>
<circle cx="194.3" cy="230.3" r=".51"/>
<circle cx="153.6" cy="240.4" r=".51"/>
<circle cx="153.6" cy="250.6" r=".51"/>
<circle cx="171.4" cy="240.4" r=".51"/>
</g>
<g fill="#000" stroke="#000" stroke-width=".28">
<path d="M43.8 55.1h1.3zM45.1 55.1l5.1-1.9zM49.5 56.3v1.3zM49.5 57.6h.7zM49.5 52.5v1.3zM49.5 52.5h.7zM160.6 57.6h1.3zM161.9 57.6l5.1-1.9zM161.9 51.3h1.9zM165.7 51.3v1.2zM163.8 51.3h1.9zM165.7 50v1.3z"/>
<path d="M166.3 58.9v1.3zM166.3 55.1v1.2zM166.3 55.1h.7zM283.2 55.1h1.3zM284.5 57.1v1zM284.5 55.1v1zM284.5 55.1h1.2zM288.3 57.6v1.3zM288.3 57.6h.6zM43.8 65.2h1.3zM43.8 75.4h1.3zM45.1 65.2l5.1-1.9z"/>
<path d="M45.1 75.4l5.1-1.9zM49.5 66.5v1.3zM49.5 67.8h.7zM49.5 62.7v1.2zM49.5 62.7h.7zM49.5 76.6v1.3zM49.5 77.9h.7zM49.5 72.8v1.3zM49.5 72.8h.7zM160.6 67.8h1.3zM161.9 67.8l5.1-2zM166.3 69v1.3z"/>
<path d="M166.3 70.3h.7zM166.3 65.2v1.3zM166.3 65.2h.7zM166.3 60.2h.7zM282.5 60.2h6.3zM282.5 70.3h2zM284.5 70.3h4.3zM284.5 69.3v1zM284.5 67.2v1.1zM284.5 65.2v1.1zM284.5 63.2v1zM284.5 61.1v1.1z"/>
<path d="M284.5 59.1v1.1zM288.3 61.4v1.3zM288.3 62.7h.6zM288.3 71.6v1.2zM288.3 72.8h.6zM288.3 67.8v1.2zM288.3 67.8h.6zM43.8 85.5h1.3zM43.8 95.7h1.3zM45.1 85.5l5.1-1.9zM45.1 95.7l5.1-1.9zM49.5 86.8v1.3z"/>
<path d="M49.5 88.1h.7zM49.5 83v1.3zM49.5 83h.7zM49.5 97v1.2zM49.5 98.2h.7zM49.5 93.2v1.2zM49.5 93.2h.7zM158.1 88.1h1.3zM159.4 88.1l5-1.9zM163.8 89.3v1.3zM163.8 90.6h.6zM163.8 85.5v1.3z"/>
<path d="M163.8 85.5h.6zM196.8 90.6l1.5-1.5zM196.8 90.6l1.5 1.5zM198.3 89.1h20.3zM198.3 92.1h20.3zM218.6 89.1v3zM280 93.2h6.2zM285.7 94.4v1.3zM285.7 95.7h.7zM285.7 90.6v1.3zM285.7 90.6h.7zM43.8 105.9h1.3z"/>
<path d="M43.8 116h1.3zM45.1 105.9l5.1-2zM45.1 116l5.1-1.9zM49.5 107.1v1.3zM49.5 108.4h.7zM49.5 103.3v1.3zM49.5 103.3h.7zM49.5 117.3v1.3zM49.5 118.6h.7zM49.5 113.5v1.2zM49.5 113.5h.7zM160.6 105.9h6.5z"/>
<path d="M160.6 116h3.2zM163.8 116h3.3zM163.8 115v1zM163.8 113v1zM163.8 110.9v1zM163.8 108.9v1zM163.8 106.9v1zM163.8 104.8v1.1zM163.8 102.8v1zM163.8 100.8v1zM162.5 100.8h2.6zM166.3 107.1v1.3z"/>
<path d="M166.3 108.4h.7zM166.3 103.3v1.3zM166.3 103.3h.7zM166.3 117.3v1.3zM166.3 118.6h.7zM166.3 113.5v1.2zM166.3 113.5h.7zM280 116h6.2zM285.7 117.3v1.3zM285.7 118.6h.7zM285.7 113.5v1.2zM285.7 113.5h.7z"/>
<path d="M43.8 126.2h1.3zM45.1 126.2l5.1-1.9zM49.5 127.4v1.3zM49.5 128.7h.7zM49.5 123.6v1.3zM49.5 123.6h.7zM151.7 131.3h3.9zM43.8 156.7h1.3zM45.1 156.7l5.1-2zM49.5 157.9v1.3zM49.5 159.2h.7zM49.5 154.1v1.3z"/>
<path d="M49.5 154.1h.7zM160.6 159.2h6.3zM160.6 146.5h6.3zM166.3 156.7v1.2zM166.3 156.7h.7zM166.3 147.8v1.2zM166.3 149h.7zM166.3 144v1.2zM166.3 144h.7zM269.8 146.5h1.3zM271.1 146.5l5.1-1.9zM273 158.7v1z"/>
<path d="M273 156.7v1zM271.8 156.7h2.5zM275.6 159.2v1.3zM275.6 159.2h.6zM275.6 147.8v1.2zM275.6 149h.6zM275.6 144v1.2zM275.6 144h.6zM43.8 166.8h1.3zM43.8 177h1.3zM45.1 166.8l5.1-1.9zM45.1 177l5.1-1.9z"/>
<path d="M49.5 168.1v1.3zM49.5 169.4h.7zM49.5 164.3v1.2zM49.5 164.3h.7zM49.5 178.2v1.3zM49.5 179.5h.7zM49.5 174.4v1.3zM49.5 174.4h.7zM160.6 171.9h6.3zM161.3 166.8h1.2zM162.5 177v1zM162.5 174.9v1.1z"/>
<path d="M162.5 172.9v1zM162.5 170.9v1zM162.5 168.8v1.1zM162.5 166.8v1zM162.5 166.8h1.3zM166.3 160.5v1.2zM166.3 161.7h.7zM166.3 173.2v1.2zM166.3 174.4h.7zM166.3 169.4v1.2zM166.3 169.4h.7zM166.3 179.5v1.3z"/>
<path d="M166.3 179.5h.7zM269.8 161.7h6.5zM269.8 171.9h3.2zM273 171.9h3.3zM273 170.9v1zM273 168.8v1.1zM273 166.8v1zM273 164.8v1zM273 162.7v1.1zM273 160.7v1zM275.6 163v1.3zM275.6 164.3h.6z"/>
<path d="M275.6 173.2v1.2zM275.6 174.4h.6zM275.6 169.4v1.2zM275.6 169.4h.6zM320.3 165.3l2-2zM320.3 163.3l2 2zM320.3 167.8l2-2zM320.3 165.8l2 2zM320.3 170.4l2-2.1zM320.3 168.3l2 2.1zM320.3 172.9l2-2zM320.3 170.9l2 2z"/>
<path d="M320.3 175.4l2-2zM320.3 173.4l2 2zM320.3 178l2-2zM320.3 176l2 2zM320.3 178.5l2 2zM43.8 187.1h1.3zM43.8 197.3h1.3zM45.1 187.1l5.1-1.9zM45.1 197.3l5.1-1.9zM49.5 188.4v1.3zM49.5 189.7h.7zM49.5 184.6v1.3z"/>
<path d="M49.5 184.6h.7zM49.5 198.6v1.2zM49.5 199.8h.7zM49.5 194.8v1.2zM49.5 194.8h.7zM79 188.1l2-2zM79 186.1l2 2zM79 190.7l2-2zM79 188.7l2 2zM79 193.2l2-2zM79 191.2l2 2zM79 195.8l2-2.1z"/>
<path d="M79 193.7l2 2.1zM79 198.3l2-2zM79 196.3l2 2zM79 198.8l2 2zM160.6 182.1h1.9zM160.6 194.8h6.3zM161.3 189.7h1.2zM162.5 182.1h4.4zM162.5 181v1.1zM162.5 179v1zM162.5 197.8v1zM162.5 195.7v1.1z"/>
<path d="M162.5 193.7v1.1zM162.5 191.7v1zM162.5 189.7v1zM162.5 189.7h1.3zM166.3 183.3v1.3zM166.3 184.6h.7zM166.3 196v1.3zM166.3 197.3h.7zM166.3 192.2v1.3zM166.3 192.2h.7zM269.8 187.1h6.3zM275.6 188.4v1.3z"/>
<path d="M275.6 189.7h.6zM275.6 184.6v1.3zM275.6 184.6h.6zM320.3 180.5l2-2zM320.3 183.1l2-2.1zM320.3 181l2 2.1zM320.3 185.6l2-2zM320.3 183.6l2 2zM320.3 188.1l2-2zM320.3 186.1l2 2zM320.3 190.7l2-2zM320.3 188.7l2 2z"/>
<path d="M320.3 193.2l2-2zM320.3 191.2l2 2zM320.3 195.8l2-2.1zM320.3 193.7l2 2.1zM43.8 207.4h1.3zM43.8 217.6h1.3zM45.1 207.4l5.1-1.9zM45.1 217.6l5.1-1.9zM49.5 208.7v1.3zM49.5 210h.7zM49.5 204.9v1.3zM49.5 204.9h.7z"/>
<path d="M49.5 218.9v1.2zM49.5 215v1.3zM49.5 215h.7zM79 200.8l2-2zM79 203.4l2-2zM79 201.4l2 2zM79 205.9l2-2zM79 203.9l2 2zM79 208.4l2-2zM79 206.4l2 2zM79 211l2-2zM79 209l2 2z"/>
<path d="M79 213.5l2-2zM79 211.5l2 2zM79 216.1l2-2.1zM79 214l2 2.1zM79 218.6l2-2zM79 216.6l2 2zM79 219.1l2 2zM160.6 204.9h1.9zM160.6 217.6h6.3zM161.3 212.5h1.2zM162.5 204.9h4.4zM162.5 203.9v1z"/>
<path d="M162.5 201.8v1.1zM162.5 199.8v1zM162.5 218.6v1zM162.5 216.6v1zM162.5 214.5v1.1zM162.5 212.5v1zM162.5 212.5h1.3zM166.3 206.2v1.2zM166.3 207.4h.7zM166.3 202.4v1.2zM166.3 202.4h.7zM166.3 218.9v1.2z"/>
<path d="M166.3 215v1.3zM166.3 215h.7zM43.8 227.7h1.3zM45.1 227.7l5.1-1.9zM49.5 220.1h.7zM49.5 229v1.3zM49.5 230.3h.7zM49.5 225.2v1.3zM49.5 225.2h.7zM79 221.1l2-2zM79 223.7l2-2zM79 221.7l2 2z"/>
<path d="M79 226.2l2-2zM79 224.2l2 2zM79 228.8l2-2.1zM79 226.7l2 2.1zM79 231.3l2-2zM79 229.3l2 2zM79 233.8l2-2zM79 231.8l2 2zM79 236.4l2-2zM79 234.4l2 2zM79 238.9l2-2zM79 236.9l2 2z"/>
<path d="M79 239.4l2 2.1zM160.6 227.7h1.9zM161.3 235.4h1.2zM162.5 227.7h4.4zM162.5 226.7v1zM162.5 224.7v1zM162.5 222.7v1zM162.5 220.6v1.1zM162.5 237.4v1zM162.5 235.4v1zM162.5 235.4h1.3zM166.3 220.1h.7z"/>
<path d="M166.3 229v1.3zM166.3 230.3h.7zM166.3 225.2v1.3zM166.3 225.2h.7zM166.3 237.9v1.3zM166.3 237.9h.7zM79 241.5l2-2.1zM160.6 240.4h6.3zM160.6 250.6h1.9zM162.5 250.6h4.4zM162.5 249.6v1zM162.5 247.6v1z"/>
<path d="M162.5 245.5v1zM162.5 243.5v1zM162.5 241.5v1zM162.5 239.4v1.1zM166.3 241.7v1.3zM166.3 243h.7zM166.3 251.9v1.2zM166.3 253.1h.7zM166.3 248.1v1.2zM166.3 248.1h.7zM313.7 249.3h86.3zM313.7 254.4h86.3z"/>
<path d="M313.7 259.5h58.4zM372.1 259.5h27.9zM372.1 259.5v5.1zM313.7 264.6h58.4zM313.7 269.7h86.3zM372.1 264.6h27.9zM400 268.4v1.3z"/>
</g>
<path d="M16.5 18.2v260.3zM16.5 18.2h387.3zM16.5 278.5h387.3zM403.8 18.2v260.3z" fill="#000" stroke="#000" stroke-width=".32"/>
<g fill="#000" stroke="#000" stroke-width=".61">
<path d="M20.3 22.1v252.6zM20.3 22.1h379.7zM283.2 244.3v30.4zM313.7 254.4v5.1zM313.7 249.3v5.1zM313.7 244.3v5zM313.7 244.3h86.3zM283.2 244.3h30.5zM400 254.4v5.1zM400 249.3v5.1zM400 244.3v5zM400 22.1v222.2z"/>
<path d="M20.3 274.7h262.9zM283.2 274.7h30.5zM313.7 274.7h86.3zM313.7 269.7v5zM313.7 264.6v5.1zM313.7 259.5v5.1zM400 268.4v6.3zM400 264.6v3.8zM400 259.5v5.1z"/>
</g>
<g fill="#000" stroke="#000" stroke-width=".25">
<path d="M199.1 59.9h2.8v.5h-2.8zM326.1 57.4h2.8v.5h-2.8zM199.1 70h2.8v.5h-2.8zM326.1 67.5h2.8v.5h-2.8zM199.1 95.4h2.8v.5h-2.8zM326.1 90.4h2.8v.5h-2.8zM326.1 95.4h2.8v.5h-2.8zM84.8 118.3h2.8v.5h-2.8zM199.1 103.1h2.8v.5h-2.8zM199.1 118.3h2.8v.5h-2.8zM326.1 113.2h2.8v.5h-2.8zM326.1 118.3h2.8v.5h-2.8z"/>
<path d="M84.8 120.8h2.8v.5h-2.8zM84.8 123.4h2.8v.5h-2.8zM84.8 125.9h2.8v.5h-2.8zM84.8 128.5h2.8v.5h-2.8zM84.8 131h2.8v.5h-2.8zM84.8 133.5h2.8v.5h-2.8zM84.8 136.1h2.8v.5h-2.8zM84.8 138.6h2.8v.5h-2.8zM199.1 125.9h2.8v.5h-2.8zM84.8 158.9h2.8v.5h-2.8zM222 146.2h2.8v.5h-2.8zM222 148.8h2.8v.5h-2.8z"/>
<path d="M222 151.3h2.8v.5h-2.8zM222 153.9h2.8v.5h-2.8zM222 156.4h2.8v.5h-2.8zM222 158.9h2.8v.5h-2.8zM326.1 143.7h2.8v.5h-2.8zM326.1 146.2h2.8v.5h-2.8zM326.1 148.8h2.8v.5h-2.8zM326.1 151.3h2.8v.5h-2.8zM326.1 153.9h2.8v.5h-2.8zM326.1 156.4h2.8v.5h-2.8zM84.8 161.5h2.8v.5h-2.8zM84.8 164h2.8v.5h-2.8z"/>
<path d="M84.8 166.6h2.8v.5h-2.8zM84.8 169.1h2.8v.5h-2.8zM84.8 171.6h2.8v.5h-2.8zM84.8 174.2h2.8v.5h-2.8zM84.8 176.7h2.8v.5h-2.8zM84.8 179.3h2.8v.5h-2.8zM222 161.5h2.8v.5h-2.8zM222 164h2.8v.5h-2.8zM222 166.6h2.8v.5h-2.8zM326.1 164h2.8v.5h-2.8zM326.1 166.6h2.8v.5h-2.8zM326.1 169.1h2.8v.5h-2.8z"/>
<path d="M326.1 171.6h2.8v.5h-2.8zM326.1 174.2h2.8v.5h-2.8zM326.1 176.7h2.8v.5h-2.8zM326.1 179.3h2.8v.5h-2.8zM84.8 186.9h2.8v.5h-2.8zM84.8 189.4h2.8v.5h-2.8zM84.8 192h2.8v.5h-2.8zM84.8 194.5h2.8v.5h-2.8zM84.8 197h2.8v.5h-2.8zM84.8 199.6h2.8v.5h-2.8zM326.1 181.8h2.8v.5h-2.8zM326.1 184.3h2.8v.5h-2.8z"/>
<path d="M326.1 186.9h2.8v.5h-2.8zM326.1 189.4h2.8v.5h-2.8zM326.1 192h2.8v.5h-2.8zM326.1 194.5h2.8v.5h-2.8zM84.8 202.1h2.8v.5h-2.8zM84.8 204.7h2.8v.5h-2.8zM84.8 207.2h2.8v.5h-2.8zM84.8 209.7h2.8v.5h-2.8zM84.8 212.3h2.8v.5h-2.8zM84.8 214.8h2.8v.5h-2.8zM84.8 217.3h2.8v.5h-2.8zM84.8 219.9h2.8v.5h-2.8z"/>
<path d="M84.8 222.4h2.8v.5h-2.8zM84.8 225h2.8v.5h-2.8zM84.8 227.5h2.8v.5h-2.8zM84.8 230h2.8v.5h-2.8zM84.8 232.6h2.8v.5h-2.8zM84.8 235.1h2.8v.5h-2.8zM84.8 237.7h2.8v.5h-2.8zM369.5 220.1h25.4v10.2h-25.4zM84.8 240.2h2.8v.5h-2.8z"/>
</g>
<path d="M339 220.1v10.2zM339 230.3v7.6zM339 237.9h55.9zM339 230.3h55.9zM394.9 230.3v7.6zM394.9 220.1v10.2zM339 220.1h55.9z" fill="#000" stroke="#000" stroke-width=".42"/>
<use href="#words"/>
</svg>
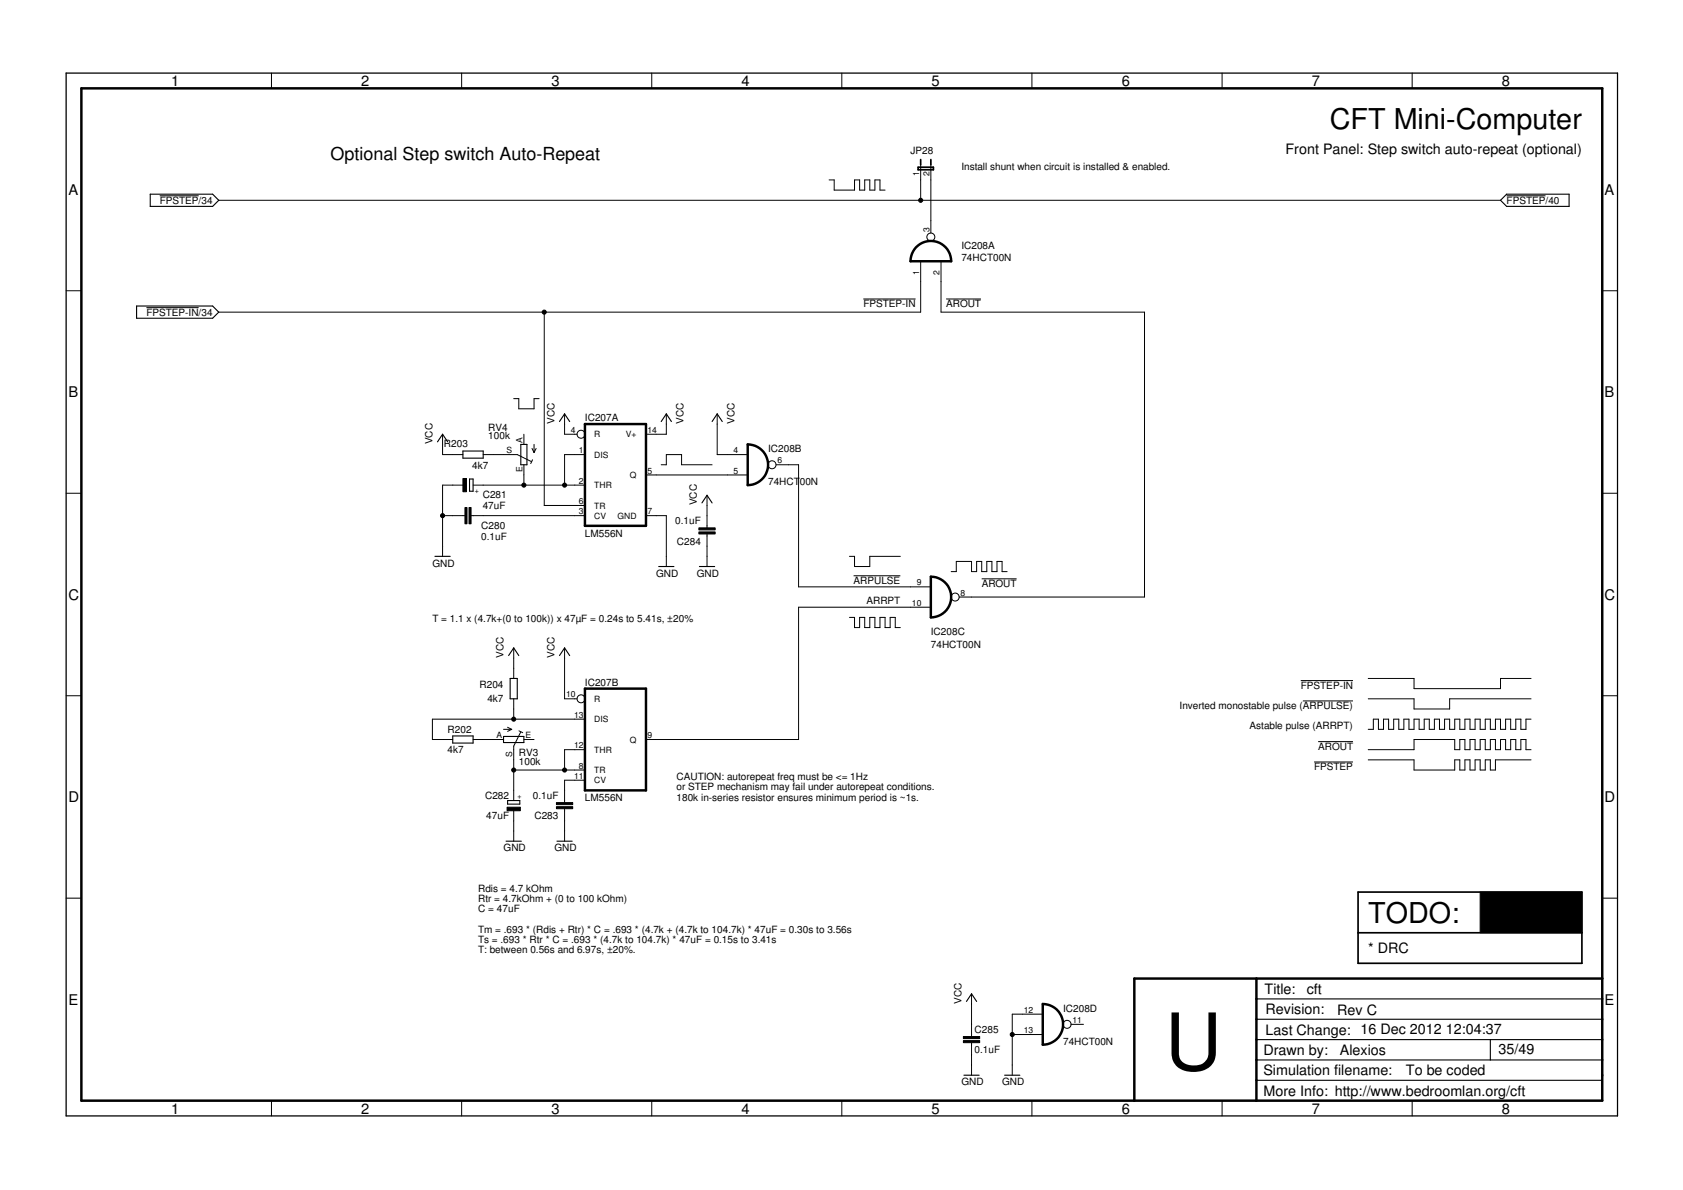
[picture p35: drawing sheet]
<svg xmlns="http://www.w3.org/2000/svg" width="420mm" height="297mm" viewBox="0 0 420 297" stroke-linecap="round" stroke-linejoin="round" font-family="sans-serif">
<defs><g id="words">
<text font-size="19.7" x="290.8" y="267.1">U</text>
<g font-size="7.2">
<text x="332" y="32.2">CFT Mini-Computer</text>
<text x="341.6" y="230.3">TODO:</text>
</g>
<text font-size="4.5" x="82.5" y="39.8">Optional Step switch Auto-Repeat</text>
<g font-size="3.7">
<text x="42.7" y="21.5">1</text>
<text x="90.2" y="21.5">2</text>
<text x="137.7" y="21.5">3</text>
<text x="185.1" y="21.5">4</text>
<text x="232.6" y="21.5">5</text>
<text x="280" y="21.5">6</text>
<text x="327.5" y="21.5">7</text>
<text x="375" y="21.5">8</text>
<text x="17.1" y="48.6">A</text>
<text x="400.6" y="48.6">A</text>
<text x="17.1" y="99.2">B</text>
<text x="400.6" y="99.2">B</text>
<text x="17.1" y="149.7">C</text>
<text x="400.6" y="149.7">C</text>
<text x="17.1" y="200.2">D</text>
<text x="400.6" y="200.2">D</text>
<text x="17.1" y="250.8">E</text>
<text x="400.6" y="250.8">E</text>
<text x="42.7" y="277.9">1</text>
<text x="90.2" y="277.9">2</text>
<text x="137.7" y="277.9">3</text>
<text x="185.1" y="277.9">4</text>
<text x="232.6" y="277.9">5</text>
<text x="280" y="277.9">6</text>
<text x="327.5" y="277.9">7</text>
<text x="375" y="277.9">8</text>
</g>
<g font-size="3.6">
<text x="320.9" y="38.6">Front Panel: Step switch auto-repeat (optional)</text>
<text x="341.6" y="237.9">* DRC</text>
<text x="315.7" y="248.1">Title:</text>
<text x="326.2" y="248.2">cft</text>
<text x="315.9" y="253.2">Revision:</text>
<text x="333.8" y="253.3">Rev C</text>
<text x="315.4" y="263.3">Drawn by:</text>
<text x="315.9" y="258.2">Last Change: 16 Dec 2012</text>
<text x="334.5" y="263.3">Alexios</text>
<text x="361" y="258.1">12:04:37</text>
<text x="374.1" y="263.2">35/49</text>
<text x="315.4" y="268.4">Simulation filename:</text>
<text x="351" y="268.4">To be coded</text>
<text x="315.4" y="273.5">More Info: http://www.bedroomlan.org/cft</text>
</g>
<g font-size="2.5">
<text x="227.3" y="38.6">JP28</text>
<text x="240" y="42.4">Install shunt when circuit is installed &amp; enabled.</text>
<text x="39.9" y="50.9">FPSTEP/34</text>
<text x="376.1" y="50.9">FPSTEP/40</text>
<text x="240" y="65.2">74HCT00N</text>
<text x="240" y="62">IC208A</text>
<text x="215.5" y="76.7">FPSTEP-IN</text>
<text x="236.2" y="76.7">AROUT</text>
<text x="36.6" y="78.8">FPSTEP-IN/34</text>
<text x="121.9" y="107.5">RV4</text>
<text x="138.4" y="105.9" transform="rotate(-90 138.4 105.9)">VCC</text>
<text x="146" y="105.1">IC207A</text>
<text x="170.7" y="105.9" transform="rotate(-90 170.7 105.9)">VCC</text>
<text x="183.4" y="105.9" transform="rotate(-90 183.4 105.9)">VCC</text>
<text x="107.9" y="110.9" transform="rotate(-90 107.9 110.9)">VCC</text>
<text x="110.8" y="111.7">R203</text>
<text x="121.9" y="109.7">100k</text>
<text x="191.7" y="112.8">IC208B</text>
<text x="117.9" y="117">4k7</text>
<text x="120.5" y="124.4">C281</text>
<text x="191.7" y="121.1">74HCT</text>
<text x="199.7" y="121.1">00N</text>
<text x="120.5" y="127">47uF</text>
<text x="168.6" y="130.9">0.1uF</text>
<text x="174" y="126.2" transform="rotate(-90 174 126.2)">VCC</text>
<text x="120.1" y="134.7">0.1uF</text>
<text x="120.1" y="132.1">C280</text>
<text x="146" y="133.9">LM556N</text>
<text x="169" y="136">C284</text>
<text x="107.9" y="141.4">GND</text>
<text x="163.8" y="144">GND</text>
<text x="174" y="144">GND</text>
<text x="213.1" y="145.7">ARPULSE</text>
<text x="245.1" y="146.5">AROUT</text>
<text x="107.9" y="155.4">T = 1.1 x (4.7k+(0 to 100k)) x 47µF = 0.24s to 5.41s, ±20%</text>
<text x="216.3" y="150.8">ARRPT</text>
<text x="232.4" y="161.7">74HCT00N</text>
<text x="232.4" y="158.6">IC208C</text>
<text x="125.7" y="164.3" transform="rotate(-90 125.7 164.3)">VCC</text>
<text x="138.4" y="164.3" transform="rotate(-90 138.4 164.3)">VCC</text>
<text x="119.7" y="171.7">R204</text>
<text x="146" y="171.1">IC207B</text>
<text x="324.7" y="171.9">FPSTEP-IN</text>
<text x="121.7" y="175.2">4k7</text>
<text x="294.5" y="177">Inverted monostable pulse (ARPULSE)</text>
<text x="111.7" y="183.1">R202</text>
<text x="312" y="182">Astable pulse (ARRPT)</text>
<text x="111.7" y="187.9">4k7</text>
<text x="129.5" y="190.9">100k</text>
<text x="129.5" y="188.8">RV3</text>
<text x="329.1" y="187.1">AROUT</text>
<text x="168.9" y="194.7">CAUTION: autorepeat freq must be &lt;= 1Hz</text>
<text x="168.9" y="197.3">or STEP mechanism may fail under autorepeat conditions.</text>
<text x="328.1" y="192.2">FPSTEP</text>
<text x="121.1" y="199.3">C282</text>
<text x="133" y="199.4">0.1uF</text>
<text x="146" y="199.9">LM556N</text>
<text x="168.9" y="199.8">180k in-series resistor ensures minimum period is ~1s.</text>
<text x="121.4" y="204.4">47uF</text>
<text x="133.4" y="204.5">C283</text>
<text x="125.7" y="212.5">GND</text>
<text x="138.4" y="212.5">GND</text>
<text x="119.4" y="222.7">Rdis = 4.7 kOhm</text>
<text x="119.4" y="225.2">Rtr = 4.7kOhm + (0 to 100 kOhm)</text>
<text x="119.4" y="227.8">C = 47uF</text>
<text x="119.4" y="232.8">Tm = .693 * (Rdis + Rtr) * C = .693 * (4.7k + (4.7k to 104.7k) * 47uF = 0.30s to 3.56s</text>
<text x="119.4" y="235.4">Ts = .693 * Rtr * C = .693 * (4.7k to 104.7k) * 47uF = 0.15s to 3.41s</text>
<text x="119.4" y="237.9">T: between 0.56s and 6.97s, ±20%.</text>
<text x="240" y="250.6" transform="rotate(-90 240 250.6)">VCC</text>
<text x="243.3" y="257.9">C285</text>
<text x="265.4" y="252.5">IC208D</text>
<text x="243.3" y="262.9">0.1uF</text>
<text x="265.4" y="260.8">74HCT00N</text>
<text x="240" y="270.9">GND</text>
<text x="250.2" y="270.9">GND</text>
</g>
<g font-size="2.1">
<text x="229.5" y="43.9" transform="rotate(-90 229.5 43.9)">1</text>
<text x="232" y="43.9" transform="rotate(-90 232 43.9)">2</text>
<text x="232" y="57.8" transform="rotate(-90 232 57.8)">3</text>
<text x="229.5" y="68.7" transform="rotate(-90 229.5 68.7)">1</text>
<text x="234.6" y="68.7" transform="rotate(-90 234.6 68.7)">2</text>
<text x="126.5" y="113.1">S</text>
<text x="130.4" y="110.6" transform="rotate(-90 130.4 110.6)">A</text>
<text x="142.5" y="108">4</text>
<text x="144.5" y="113.1">1</text>
<text x="148.4" y="109.2">R</text>
<text x="156.3" y="109.2">V+</text>
<text x="161.6" y="108">14</text>
<text x="183.1" y="113.1">4</text>
<text x="130.4" y="117.8" transform="rotate(-90 130.4 117.8)">E</text>
<text x="148.4" y="114.2">DIS</text>
<text x="157.3" y="119.3">Q</text>
<text x="161.6" y="118.2">5</text>
<text x="183.1" y="118.2">5</text>
<text x="194.1" y="115.7">6</text>
<text x="144.5" y="125.8">6</text>
<text x="144.5" y="120.7">2</text>
<text x="148.4" y="121.9">THR</text>
<text x="144.5" y="128.4">3</text>
<text x="148.4" y="126.9">TR</text>
<text x="148.4" y="129.5">CV</text>
<text x="154.2" y="129.5">GND</text>
<text x="161.6" y="128.4">7</text>
<text x="228.9" y="146.1">9</text>
<text x="239.8" y="148.7">8</text>
<text x="227.7" y="151.2">10</text>
<text x="141.3" y="174.1">10</text>
<text x="143.3" y="179.1">13</text>
<text x="148.4" y="175.2">R</text>
<text x="123.9" y="184.2">A</text>
<text x="131.2" y="184.2">E</text>
<text x="148.4" y="180.3">DIS</text>
<text x="157.3" y="185.3">Q</text>
<text x="161.6" y="184.2">9</text>
<text x="127.9" y="188.9" transform="rotate(-90 127.9 188.9)">S</text>
<text x="143.3" y="186.8">12</text>
<text x="144.5" y="191.8">8</text>
<text x="148.4" y="187.9">THR</text>
<text x="143.3" y="194.4">11</text>
<text x="148.4" y="193">TR</text>
<text x="148.4" y="195.5">CV</text>
<text x="255.6" y="252.8">12</text>
<text x="255.6" y="257.9">13</text>
<text x="267.7" y="255.3">11</text>
</g>
<g font-size="1.8">
<text x="118.5" y="122.9">+</text>
<text x="130.1" y="199.4" transform="rotate(-90 130.1 199.4)">+</text>
</g>
</g></defs>
<g fill="#000" stroke="#000" stroke-width=".25">
<path d="M67.8 18.2v3.9zM115.3 18.2v3.9zM162.7 18.2v3.9zM210.2 18.2v3.9zM257.6 18.2v3.9zM305.1 18.2v3.9zM352.5 18.2v3.9zM20.3 22.1v252.6zM20.3 22.1h379.7zM39.9 48.9h9.7zM207 44.9h1.3zM208.3 44.9v2.6z"/>
<path d="M208.3 47.5h5zM213.3 44.9v2.6zM213.3 44.9h1.3zM214.6 44.9v2.6zM214.6 47.5h1.3zM215.9 44.9v2.6zM215.9 44.9h1.2zM217.1 44.9v2.6zM217.1 47.5h1.3zM218.4 44.9v2.6zM218.4 44.9h1.3zM219.7 44.9v2.6z"/>
<path d="M219.7 47.5h1.3zM229.8 42.4v2.5zM229.8 41.1v1.3zM229.8 44.9v5.1zM54.6 50h175.2zM229.8 50h144.8zM232.4 42.4v2.5zM232.4 41.1v1.3zM232.4 55.1v3.1zM232.4 44.9v10.2zM376.1 48.9h9.7zM16.5 72.6h3.8z"/>
<path d="M36.6 76.8h13zM135.9 77.9v48.3zM54.6 77.9h81.3zM135.9 77.9h93.9zM215.5 74.6h13.1zM229.8 65.2v5.1zM229.8 70.3v7.6zM234.9 65.2v5.1zM234.9 70.3v7.6zM234.9 77.9h50.8zM236.2 74.6h8.7zM285.7 77.9v71.1z"/>
<path d="M400 72.6h3.8zM128.2 99.5h1.3zM129.5 99.5v2.5zM133.3 99.5h1.3zM110.5 108.4v2.5zM110.5 110.9v2.6zM110.5 113.5h2.5zM113 113.5h2.6zM120.6 113.5h2.6zM123.2 113.5h2.5zM125.7 113.5h2.5zM128.2 113.5h.9z"/>
<path d="M129.1 113.5l3.6 1.7zM129.5 102h3.8zM130.8 108.4v2.5zM130.8 116v2.6zM130.8 118.6v2.5zM132.9 114.8l-.4 .9zM133.3 99.5v2.5zM133.3 110.9v2.1zM133.8 111.9l-.5 1.1zM132.8 111.9l.5 1.1zM140.9 103.3v2.6zM140.9 105.9v2.5z"/>
<path d="M140.9 113.5v7.6zM143.5 108.4h.6zM143.5 113.5h2.5zM140.9 108.4h2.6zM140.9 113.5h2.6zM161.3 118.6h2.5zM161.3 108.4h2.5zM163.8 108.4h2.5zM163.8 118.6h17.8zM165.1 116h1.2zM166.3 113.5v2.5zM166.3 113.5h3.9z"/>
<path d="M166.3 103.3v2.6zM166.3 105.9v2.5zM170.2 113.5v2.5zM170.2 116h7.6zM179 103.3v2.6zM179 105.9v7.6zM181.6 113.5h5.1zM181.6 118.6h5.1zM179 113.5h2.6zM193.7 116h3.1zM196.8 116h2.6zM199.4 116v30.5z"/>
<path d="M16.5 123.1h3.8zM110.5 136.3v2.6zM110.5 121.1v7.6zM110.5 128.7v7.6zM113 121.1h2.6zM113 128.7h2.6zM110.5 121.1h2.5zM110.5 128.7h2.5zM115.6 128.7h.5zM117.6 128.7h.5zM118.1 121.1h2.5zM118.1 128.7h2.5z"/>
<path d="M120.6 121.1h10.2zM135.9 126.2h7.6zM130.8 121.1h10.1zM143.5 126.2h2.5zM143.5 128.7h2.5zM143.5 121.1h2.5zM140.9 121.1h2.6zM120.6 128.7h22.9zM161.3 128.7h2.5zM163.8 128.7h2.5zM166.3 138.9v2.5zM166.3 128.7v10.2z"/>
<path d="M176.5 133.8v2.5zM176.5 128.7v2.6zM176.5 133.3v.5zM176.5 131.3v.5zM176.5 138.9v2.5zM176.5 123.6v2.6zM176.5 126.2v2.5zM176.5 136.3v2.6zM212.1 138.9h1.2zM213.3 138.9v2.5zM217.1 138.9h7.7zM400 123.1h3.8z"/>
<path d="M199.4 151.6h27.9zM199.4 146.5h27.9zM212.1 154.1h1.2zM213.1 143.7h11.7zM213.3 141.4h3.8zM213.3 154.1v2.6zM213.3 156.7h1.3zM214.6 154.1v2.6zM214.6 154.1h1.3zM215.9 154.1v2.6zM215.9 156.7h1.2zM217.1 138.9v2.5z"/>
<path d="M217.1 154.1v2.6zM217.1 154.1h1.3zM218.4 154.1v2.6zM218.4 156.7h1.3zM219.7 154.1v2.6zM219.7 154.1h1.3zM221 154.1v2.6zM221 156.7h1.2zM222.2 154.1v2.6zM222.2 154.1h1.3zM223.5 154.1v2.6zM223.5 156.7h1.3z"/>
<path d="M227.3 146.5h5.1zM227.3 151.6h5.1zM237.5 142.7h1.2zM238.7 140.1v2.6zM238.7 140.1h3.8zM242.5 140.1v2.6zM242.5 142.7h1.3zM239.5 149h3zM242.5 149h43.2zM243.8 140.1v2.6zM243.8 140.1h1.3zM245.1 140.1v2.6z"/>
<path d="M245.1 142.7h1.3zM245.1 144.5h8.7zM246.4 140.1v2.6zM246.4 140.1h1.2zM247.6 140.1v2.6zM247.6 142.7h1.3zM248.9 140.1v2.6zM248.9 140.1h1.3zM250.2 140.1v2.6zM250.2 142.7h1.2zM16.5 173.7h3.8zM107.9 179.5v5.1z"/>
<path d="M128.2 166.8v2.6zM128.2 174.4v2.6zM128.2 161.7v2.6zM128.2 164.3v2.5zM107.9 179.5h20.3zM128.2 177v2.5zM140.9 161.7v2.6zM140.9 164.3v10.1zM143.5 174.4h.6zM143.5 179.5h2.5zM140.9 174.4h2.6zM128.2 179.5h15.3z"/>
<path d="M324.7 169.9h13.1zM325.3 175h12.5zM341.6 169.4h11.4zM341.6 174.4h11.4zM342.9 179.5h1.2zM344.1 179.5v2.6zM345.4 179.5h1.3zM346.7 179.5v2.6zM347.9 179.5h1.3zM349.2 179.5v2.6zM350.5 179.5h1.2zM351.7 179.5v2.6z"/>
<path d="M353 169.4v2.5zM353 171.9h21.6zM353 179.5h1.3zM353 174.4v2.6zM353 177h8.9zM354.3 179.5v2.6zM355.6 179.5h1.2zM356.8 179.5v2.6zM358.1 179.5h1.3zM359.4 179.5v2.6zM360.6 179.5h1.3zM361.9 179.5v2.6z"/>
<path d="M361.9 174.4v2.6zM361.9 174.4h20.3zM363.2 179.5h1.2zM364.4 179.5v2.6zM365.7 179.5h1.3zM367 179.5v2.6zM368.3 179.5h1.2zM369.5 179.5v2.6zM370.8 179.5h1.3zM372.1 179.5v2.6zM373.3 179.5h1.3zM374.6 169.4v2.5z"/>
<path d="M374.6 169.4h7.6zM374.6 179.5v2.6zM375.9 179.5h1.2zM377.1 179.5v2.6zM378.4 179.5h1.3zM379.7 179.5v2.6zM381 179.5h1.2zM400 173.7h3.8zM107.9 184.6h2.6zM110.5 184.6h2.5zM118.1 184.6h2.5zM120.6 184.6h2.6z"/>
<path d="M123.2 184.6h2.5zM125.7 182.1h2zM126.7 181.5l1 .6zM126.7 182.6l1-.5zM128.2 197.3v2.5zM128.2 187.1v2.6zM128.2 186.2v.9zM130 182.7l-1.8 3.5zM128.2 192.2v5.1zM128.2 189.7v2.5zM129.6 182.4l.9 .5zM130.8 184.6h2.5z"/>
<path d="M140.9 197.3v2.5zM140.9 199.8v.5zM140.9 194.8v2.5zM128.2 192.2h12.7zM140.9 187.1v5.1zM143.5 192.2h2.5zM143.5 194.8h2.5zM143.5 187.1h2.5zM140.9 194.8h2.6zM140.9 192.2h2.6zM140.9 187.1h2.6zM161.3 184.6h2.5z"/>
<path d="M163.8 184.6h35.6zM199.4 151.6v33zM328.1 190.2h9.7zM329.1 185.1h8.7zM341.6 182.1h1.3zM341.6 187.1h11.4zM341.6 189.7h11.4zM342.9 179.5v2.6zM344.1 182.1h1.3zM345.4 179.5v2.6zM346.7 182.1h1.2zM347.9 179.5v2.6z"/>
<path d="M349.2 182.1h1.3zM350.5 179.5v2.6zM351.7 182.1h1.3zM353 179.5v2.6zM353 184.6v2.5zM353 184.6h10.2zM353 189.7v2.5zM353 192.2h10.2zM354.3 182.1h1.3zM355.6 179.5v2.6zM356.8 182.1h1.3zM358.1 179.5v2.6z"/>
<path d="M359.4 182.1h1.2zM360.6 179.5v2.6zM361.9 182.1h1.3zM363.2 179.5v2.6zM363.2 184.6v2.5zM363.2 187.1h1.2zM363.2 189.7v2.5zM363.2 189.7h1.2zM364.4 182.1h1.3zM364.4 184.6v2.5zM364.4 184.6h1.3zM364.4 189.7v2.5z"/>
<path d="M364.4 192.2h1.3zM365.7 179.5v2.6zM365.7 184.6v2.5zM365.7 187.1h1.3zM365.7 189.7v2.5zM365.7 189.7h1.3zM367 182.1h1.3zM367 184.6v2.5zM367 184.6h1.3zM367 189.7v2.5zM367 192.2h1.3zM368.3 179.5v2.6z"/>
<path d="M368.3 184.6v2.5zM368.3 187.1h1.2zM368.3 189.7v2.5zM368.3 189.7h1.2zM369.5 182.1h1.3zM369.5 184.6v2.5zM369.5 184.6h1.3zM369.5 189.7v2.5zM369.5 192.2h1.3zM370.8 179.5v2.6zM370.8 184.6v2.5zM370.8 187.1h1.3z"/>
<path d="M370.8 189.7v2.5zM370.8 189.7h1.3zM372.1 182.1h1.2zM372.1 184.6v2.5zM372.1 184.6h1.2zM372.1 189.7v2.5zM372.1 192.2h1.2zM373.3 179.5v2.6zM373.3 184.6v2.5zM373.3 187.1h1.3zM373.3 189.7v2.5zM373.3 189.7h8.9z"/>
<path d="M374.6 182.1h1.3zM374.6 184.6v2.5zM374.6 184.6h1.3zM375.9 179.5v2.6zM375.9 184.6v2.5zM375.9 187.1h1.2zM377.1 182.1h1.3zM377.1 184.6v2.5zM377.1 184.6h1.3zM378.4 179.5v2.6zM378.4 184.6v2.5zM378.4 187.1h1.3z"/>
<path d="M379.7 182.1h1.3zM379.7 184.6v2.5zM379.7 184.6h1.3zM381 179.5v2.6zM381 184.6v2.5zM381 187.1h1.2zM128.2 207.4v2.6zM128.2 202.4v2.5zM128.2 204.9v2.5zM140.9 202.4v2.5zM140.9 201.9v.5zM140.9 207.4v2.6z"/>
<path d="M140.9 204.9v2.5zM16.5 224.2h3.8zM400 224.2h3.8zM242.5 248.1v2.5zM242.5 255.7v2.5zM242.5 258.2v.5zM242.5 250.6v5.1zM252.7 253.1v5.1zM252.7 258.2v7.6zM255.2 253.1h5.1zM255.2 258.2h5.1zM252.7 253.1h2.5z"/>
<path d="M252.7 258.2h2.5zM267.4 255.7h3.1zM20.3 274.7h379.7zM67.8 274.7v3.8zM115.3 274.7v3.8zM162.7 274.7v3.8zM210.2 274.7v3.8zM242.5 265.8v2.6zM242.5 260.8v2.5zM242.5 260.3v.5zM242.5 263.3v2.5zM252.7 265.8v2.6z"/>
<path d="M257.6 274.7v3.8zM305.1 274.7v3.8zM352.5 274.7v3.8zM400 264.5v.1zM400 268.4v6.2zM400 274.6h.1zM400 22.1v252.6z"/>
<circle cx="229.8" cy="50" r=".51"/>
<circle cx="135.9" cy="77.9" r=".51"/>
<circle cx="110.5" cy="128.7" r=".51"/>
<circle cx="130.8" cy="121.1" r=".51"/>
<circle cx="140.9" cy="121.1" r=".51"/>
<circle cx="128.2" cy="179.5" r=".51"/>
<circle cx="128.2" cy="192.2" r=".51"/>
<circle cx="140.9" cy="192.2" r=".51"/>
<circle cx="252.7" cy="258.2" r=".51"/>
</g>
<g fill="#000" stroke="#000" stroke-width=".28">
<path d="M37.5 48.5v3zM37.5 51.5h15.6zM37.5 48.5h15.6zM54.6 50l-1.5 1.5zM53.1 48.5l1.5 1.5zM374.6 50l1.5-1.5zM374.6 50l1.5 1.5zM376.1 48.5h15.6zM376.1 51.5h15.6zM391.7 48.5v3zM34.1 76.4v3zM34.1 79.4h19z"/>
<path d="M34.1 76.4h19zM54.6 77.9l-1.5 1.5zM53.1 76.4l1.5 1.5zM110.5 108.4l-1.3 1.9zM110.5 108.4l1.3 1.9zM115.6 114.4h5zM115.6 112.6v1.8zM117.2 119.6h.9zM115.6 112.6h5zM120.6 112.6v1.8zM130 110.9v5.1zM130 116h1.5z"/>
<path d="M131.5 110.9v5.1zM130 110.9h1.5zM140.9 103.3l-1.2 1.9zM140.9 103.3l1.3 1.9zM166.3 103.3l-1.2 1.9zM166.3 103.3l1.3 1.9zM179 103.3l-1.2 1.9zM179 103.3l1.3 1.9zM108.6 138.9h3.8zM117.2 119.6v3zM117.2 122.6h.9zM118.1 119.6v3z"/>
<path d="M176.5 123.6l-1.3 1.9zM176.5 123.6l1.3 1.9zM164.4 141.4h3.9zM174.6 141.4h3.8zM127.4 169.4v5zM127.4 169.4h1.7zM127.4 174.4h1.7zM128.2 161.7l-1.2 1.9zM129.1 169.4v5zM128.2 161.7l1.3 1.9zM140.9 161.7l-1.2 1.9zM140.9 161.7l1.3 1.9z"/>
<path d="M113 185.5h5.1zM113 183.7v1.8zM113 183.7h5.1zM118.1 183.7v1.8zM125.7 185.4h5.1zM125.7 183.8v1.6zM129.8 199.8v.9zM126.7 199.8h3.1zM125.7 183.8h5.1zM130.8 183.8v1.6zM126.3 210h3.9zM126.7 199.8v.9z"/>
<path d="M126.7 200.7h3.1zM139 210h3.9zM242.5 248.1l-1.2 1.9zM242.5 248.1l1.3 1.9zM313.7 249.3h86.3zM313.7 254.4h86.3zM313.7 259.5h58.4zM372.1 259.5h27.9zM372.1 259.5v5.1zM240.6 268.4h3.8zM250.8 268.4h3.8zM313.7 264.6h58.4z"/>
<path d="M313.7 269.7h86.3zM372.1 264.6h27.9zM400 268.4v1.3z"/>
</g>
<path d="M16.5 18.2v260.3zM16.5 18.2h387.3zM16.5 278.5h387.3zM403.8 18.2v260.3z" fill="#000" stroke="#000" stroke-width=".32"/>
<g fill="#000" stroke="#000" stroke-width=".61">
<path d="M20.3 22.1v252.6zM20.3 22.1h379.7zM227.3 65.2h10.2zM146 105.9v25.4zM146 105.9h15.3zM186.7 110.9v10.2zM146 131.3h15.3zM161.3 105.9v25.4zM232.4 144v10.1zM146 171.9v25.4zM146 171.9h15.3zM146 197.3h15.3z"/>
<path d="M161.3 171.9v25.4zM260.3 250.6v10.2zM283.2 244.3v30.4zM313.7 254.4v5.1zM313.7 249.3v5.1zM313.7 244.3v5zM313.7 244.3h86.3zM283.2 244.3h30.5zM400 254.4v5.1zM400 249.3v5.1zM400 244.3v5zM400 22.1v222.2z"/>
<path d="M20.3 274.7h262.9zM283.2 274.7h30.5zM313.7 274.7h86.3zM313.7 269.7v5zM313.7 264.6v5.1zM313.7 259.5v5.1zM400 268.4v6.3zM400 264.6v3.8zM400 259.5v5.1z"/>
</g>
<path d="M115.6 119.4h.9v3.3h-.9zM116.1 126.7h.5v4h-.5zM117.1 126.7h.5v4h-.5zM174.5 131.8h4v.5h-4zM174.5 132.8h4v.5h-4zM126.6 201.5h3.3v.9h-3.3zM138.9 200.3h4.1v.5h-4.1zM138.9 201.4h4.1v.5h-4.1zM369.5 222.7h25.4v10.1h-25.4zM240.5 258.7h4.1v.5h-4.1zM240.5 259.8h4.1v.5h-4.1z" fill="#000" stroke="#000" stroke-width=".25"/>
<g fill="none" stroke="#000" stroke-width=".25">
<circle cx="232.4" cy="59.2" r="1"/>
<circle cx="145.1" cy="108.4" r=".99"/>
<circle cx="192.7" cy="116" r=".99"/>
<circle cx="238.5" cy="149" r="1"/>
<circle cx="145.1" cy="174.4" r=".99"/>
<circle cx="266.4" cy="255.7" r="1"/>
</g>
<g fill="#000" stroke="#000" stroke-width=".42">
<path d="M229.8 39.8v1.3zM232.4 39.8v1.3zM229.2 42.4h3.8zM229.2 41.7v.7zM233 41.7v.7zM229.2 41.7h3.8zM339 222.7v10.1zM339 232.8v7.6zM339 232.8h55.9zM394.9 222.7v10.1zM339 222.7h55.9zM339 240.4h55.9z"/>
<path d="M394.9 232.8v7.6z"/>
</g>
<path d="M227.3 65.2a5.1 5.1 0 0 1 5.1-5.1 5.1 5.1 0 0 1 5.1 5.1M186.7 110.9a5.1 5.1 0 0 1 5.1 5.1 5.1 5.1 0 0 1-5.1 5.1M232.4 144a5.1 5.1 0 0 1 5.1 5 5.1 5.1 0 0 1-5.1 5.1M260.3 250.6a5.1 5.1 0 0 1 5.1 5.1 5.1 5.1 0 0 1-5.1 5.1" fill="none" stroke="#000" stroke-width=".61"/>
<use href="#words"/>
</svg>
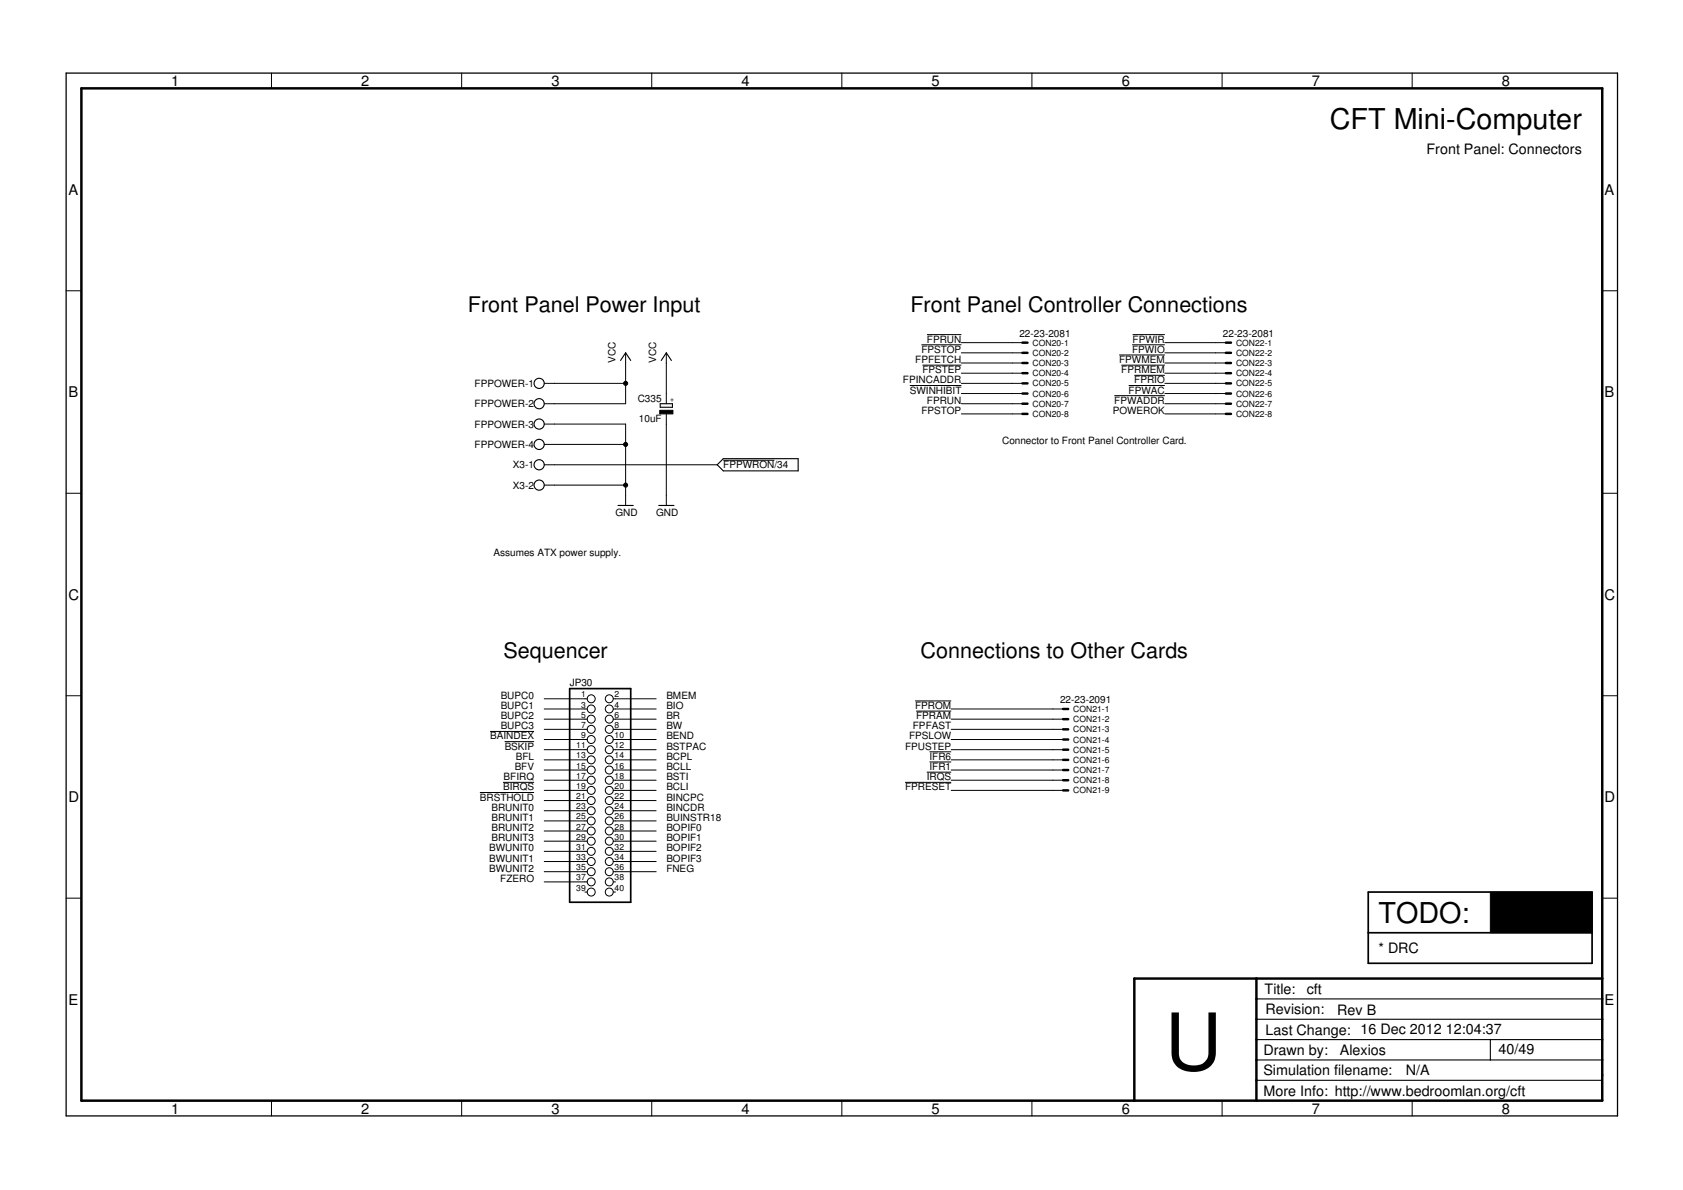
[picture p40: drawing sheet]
<svg xmlns="http://www.w3.org/2000/svg" width="420mm" height="297mm" viewBox="0 0 420 297" stroke-linecap="round" stroke-linejoin="round" font-family="sans-serif">
<defs><g id="words">
<text font-size="19.7" x="290.8" y="267.1">U</text>
<g font-size="7.2">
<text x="332" y="32.2">CFT Mini-Computer</text>
<text x="344.1" y="230.3">TODO:</text>
</g>
<g font-size="5.4">
<text x="116.8" y="77.9">Front Panel Power Input</text>
<text x="227.3" y="77.9">Front Panel Controller Connections</text>
<text x="125.7" y="164.3">Sequencer</text>
<text x="229.8" y="164.3">Connections to Other Cards</text>
</g>
<g font-size="3.7">
<text x="42.7" y="21.5">1</text>
<text x="90.2" y="21.5">2</text>
<text x="137.7" y="21.5">3</text>
<text x="185.1" y="21.5">4</text>
<text x="232.6" y="21.5">5</text>
<text x="280" y="21.5">6</text>
<text x="327.5" y="21.5">7</text>
<text x="375" y="21.5">8</text>
<text x="17.1" y="48.6">A</text>
<text x="400.6" y="48.6">A</text>
<text x="17.1" y="99.2">B</text>
<text x="400.6" y="99.2">B</text>
<text x="17.1" y="149.7">C</text>
<text x="400.6" y="149.7">C</text>
<text x="17.1" y="200.2">D</text>
<text x="400.6" y="200.2">D</text>
<text x="17.1" y="250.8">E</text>
<text x="400.6" y="250.8">E</text>
<text x="42.7" y="277.9">1</text>
<text x="90.2" y="277.9">2</text>
<text x="137.7" y="277.9">3</text>
<text x="185.1" y="277.9">4</text>
<text x="232.6" y="277.9">5</text>
<text x="280" y="277.9">6</text>
<text x="327.5" y="277.9">7</text>
<text x="375" y="277.9">8</text>
</g>
<g font-size="3.6">
<text x="356.1" y="38.6">Front Panel: Connectors</text>
<text x="344.1" y="237.9">* DRC</text>
<text x="315.7" y="248.1">Title:</text>
<text x="326.2" y="248.2">cft</text>
<text x="315.9" y="253.2">Revision:</text>
<text x="333.8" y="253.3">Rev B</text>
<text x="315.4" y="263.3">Drawn by:</text>
<text x="315.9" y="258.2">Last Change: 16 Dec 2012</text>
<text x="334.5" y="263.3">Alexios</text>
<text x="361" y="258.1">12:04:37</text>
<text x="374.1" y="263.2">40/49</text>
<text x="315.4" y="268.4">Simulation filename:</text>
<text x="351" y="268.4">N/A</text>
<text x="315.4" y="273.5">More Info: http://www.bedroomlan.org/cft</text>
</g>
<g font-size="2.5">
<text x="230" y="88.1">FPSTOP</text>
<text x="231.4" y="85.5">FPRUN</text>
<text x="254.5" y="84.1">22-23-2081</text>
<text x="282.6" y="88.1">FPWIO</text>
<text x="282.8" y="85.5">FPWIR</text>
<text x="305.3" y="84.1">22-23-2081</text>
<text x="153.7" y="90.6" transform="rotate(-90 153.7 90.6)">VCC</text>
<text x="163.8" y="90.6" transform="rotate(-90 163.8 90.6)">VCC</text>
<text x="225.4" y="95.7">FPINCADDR</text>
<text x="228.5" y="90.6">FPFETCH</text>
<text x="230.3" y="93.2">FPSTEP</text>
<text x="279.4" y="90.6">FPWMEM</text>
<text x="279.9" y="93.2">FPRMEM</text>
<text x="283.2" y="95.7">FPRIO</text>
<text x="118.5" y="96.6">FPPOWER-1</text>
<text x="118.5" y="101.7">FPPOWER-2</text>
<text x="159.2" y="100.3">C335</text>
<text x="227.1" y="98.2">SWINHIBIT</text>
<text x="231.4" y="100.8">FPRUN</text>
<text x="278.2" y="100.8">FPWADDR</text>
<text x="281.8" y="98.2">FPWAC</text>
<text x="118.5" y="106.7">FPPOWER-3</text>
<text x="159.5" y="105.4">10uF</text>
<text x="230" y="103.3">FPSTOP</text>
<text x="277.8" y="103.3">POWEROK</text>
<text x="118.5" y="111.8">FPPOWER-4</text>
<text x="250.2" y="110.9">Connector to Front Panel Controller Card.</text>
<text x="128" y="116.9">X3-1</text>
<text x="180.6" y="116.9">FPPWRON/34</text>
<text x="128" y="122">X3-2</text>
<text x="153.7" y="128.7">GND</text>
<text x="163.8" y="128.7">GND</text>
<text x="123.2" y="138.9">Assumes ATX power supply.</text>
<text x="142.2" y="171.3">JP30</text>
<text x="125" y="174.4">BUPC0</text>
<text x="125" y="177">BUPC1</text>
<text x="125" y="179.5">BUPC2</text>
<text x="166.4" y="177">BIO</text>
<text x="166.4" y="174.4">BMEM</text>
<text x="166.4" y="179.5">BR</text>
<text x="228.4" y="177">FPROM</text>
<text x="228.7" y="179.5">FPRAM</text>
<text x="264.6" y="175.6">22-23-2091</text>
<text x="122.4" y="184.6">BAINDEX</text>
<text x="125" y="182">BUPC3</text>
<text x="166.4" y="182">BW</text>
<text x="166.4" y="184.6">BEND</text>
<text x="226.9" y="184.6">FPSLOW</text>
<text x="227.9" y="182">FPFAST</text>
<text x="126" y="187.1">BSKIP</text>
<text x="128.8" y="189.7">BFL</text>
<text x="166.4" y="187.1">BSTPAC</text>
<text x="166.4" y="189.7">BCPL</text>
<text x="225.9" y="187.1">FPUSTEP</text>
<text x="232" y="189.7">IFR6</text>
<text x="125.6" y="197.3">BIRQS</text>
<text x="125.7" y="194.7">BFIRQ</text>
<text x="128.5" y="192.2">BFV</text>
<text x="166.4" y="192.2">BCLL</text>
<text x="166.4" y="194.7">BSTI</text>
<text x="166.4" y="197.3">BCLI</text>
<text x="225.9" y="197.3">FPRESET</text>
<text x="231.4" y="194.7">IRQS</text>
<text x="232" y="192.2">IFR1</text>
<text x="119.8" y="199.8">BRSTHOLD</text>
<text x="122.7" y="202.4">BRUNIT0</text>
<text x="166.4" y="199.8">BINCPC</text>
<text x="166.4" y="202.4">BINCDR</text>
<text x="122.7" y="204.9">BRUNIT1</text>
<text x="122.7" y="207.4">BRUNIT2</text>
<text x="122.7" y="210">BRUNIT3</text>
<text x="166.4" y="207.4">BOPIF0</text>
<text x="166.4" y="210">BOPIF1</text>
<text x="166.4" y="204.9">BUINSTR18</text>
<text x="122.1" y="212.5">BWUNIT0</text>
<text x="122.1" y="215.1">BWUNIT1</text>
<text x="166.4" y="212.5">BOPIF2</text>
<text x="166.4" y="215.1">BOPIF3</text>
<text x="122.1" y="217.6">BWUNIT2</text>
<text x="124.9" y="220.1">FZERO</text>
<text x="166.4" y="217.6">FNEG</text>
</g>
<g font-size="2.1">
<text x="257.8" y="86.3">CON20-1</text>
<text x="257.8" y="88.8">CON20-2</text>
<text x="308.6" y="86.3">CON22-1</text>
<text x="308.6" y="88.8">CON22-2</text>
<text x="257.8" y="91.4">CON20-3</text>
<text x="257.8" y="93.9">CON20-4</text>
<text x="308.6" y="91.4">CON22-3</text>
<text x="308.6" y="93.9">CON22-4</text>
<text x="257.8" y="96.5">CON20-5</text>
<text x="257.8" y="99">CON20-6</text>
<text x="257.8" y="101.5">CON20-7</text>
<text x="308.6" y="96.5">CON22-5</text>
<text x="308.6" y="99">CON22-6</text>
<text x="308.6" y="101.5">CON22-7</text>
<text x="257.8" y="104.1">CON20-8</text>
<text x="308.6" y="104.1">CON22-8</text>
<text x="145.1" y="174.1">1</text>
<text x="145.1" y="176.6">3</text>
<text x="145.1" y="179.1">5</text>
<text x="153.5" y="174.1">2</text>
<text x="153.5" y="176.6">4</text>
<text x="153.5" y="179.1">6</text>
<text x="267.9" y="177.7">CON21-1</text>
<text x="145.1" y="181.7">7</text>
<text x="145.1" y="184.2">9</text>
<text x="153.5" y="181.7">8</text>
<text x="153.5" y="184.2">10</text>
<text x="267.9" y="180.3">CON21-2</text>
<text x="267.9" y="182.8">CON21-3</text>
<text x="267.9" y="185.3">CON21-4</text>
<text x="143.9" y="186.8">11</text>
<text x="143.9" y="189.3">13</text>
<text x="143.9" y="191.8">15</text>
<text x="153.5" y="186.8">12</text>
<text x="153.5" y="189.3">14</text>
<text x="153.5" y="191.8">16</text>
<text x="267.9" y="187.9">CON21-5</text>
<text x="267.9" y="190.4">CON21-6</text>
<text x="143.9" y="194.4">17</text>
<text x="143.9" y="196.9">19</text>
<text x="153.5" y="194.4">18</text>
<text x="153.5" y="196.9">20</text>
<text x="267.9" y="193">CON21-7</text>
<text x="267.9" y="195.5">CON21-8</text>
<text x="143.9" y="199.5">21</text>
<text x="143.9" y="202">23</text>
<text x="153.5" y="199.5">22</text>
<text x="153.5" y="202">24</text>
<text x="267.9" y="198">CON21-9</text>
<text x="143.9" y="204.5">25</text>
<text x="143.9" y="207.1">27</text>
<text x="143.9" y="209.6">29</text>
<text x="153.5" y="204.5">26</text>
<text x="153.5" y="207.1">28</text>
<text x="153.5" y="209.6">30</text>
<text x="143.9" y="212.2">31</text>
<text x="143.9" y="214.7">33</text>
<text x="153.5" y="212.2">32</text>
<text x="153.5" y="214.7">34</text>
<text x="143.9" y="217.2">35</text>
<text x="143.9" y="219.8">37</text>
<text x="153.5" y="217.2">36</text>
<text x="153.5" y="219.8">38</text>
<text x="143.9" y="222.3">39</text>
<text x="153.5" y="222.3">40</text>
</g>
<text font-size="1.8" x="168.2" y="100.4" transform="rotate(-90 168.2 100.4)">+</text>
</g></defs>
<g fill="#000" stroke="#000" stroke-width=".25">
<path d="M67.8 18.2v3.9zM115.3 18.2v3.9zM162.7 18.2v3.9zM210.2 18.2v3.9zM257.6 18.2v3.9zM305.1 18.2v3.9zM352.5 18.2v3.9zM20.3 22.1v252.6zM20.3 22.1h379.7zM16.5 72.6h3.8zM400 72.6h3.8zM135.9 95.7h2.5z"/>
<path d="M156.2 88.1v2.5zM156.2 90.6v5.1zM138.4 95.7h17.8zM166.3 98.2v2.6zM166.3 88.1v2.5zM166.3 90.6v7.6zM227.1 96.2h12.9zM230 86.1h10zM230.3 91.1h9.7zM231.4 83.5h8.6zM240 98.2h12.7zM240 90.6h12.7z"/>
<path d="M252.7 85.5h2.5zM252.7 88.1h2.5zM252.7 90.6h2.5zM252.7 93.2h2.5zM252.7 95.7h2.5zM252.7 98.2h2.5zM240 93.2h12.7zM240 85.5h12.7zM240 88.1h12.7zM240 95.7h12.7zM278.2 98.8h12.6zM279.4 88.6h11.4z"/>
<path d="M279.9 91.1h10.9zM281.8 96.2h9zM282.6 86.1h8.2zM282.8 83.5h8zM283.2 93.7h7.6zM303.5 85.5h2.5zM303.5 88.1h2.5zM303.5 90.6h2.5zM303.5 93.2h2.5zM303.5 95.7h2.5zM303.5 98.2h2.5zM290.8 98.2h12.7z"/>
<path d="M290.8 85.5h12.7zM290.8 90.6h12.7zM290.8 93.2h12.7zM290.8 88.1h12.7zM290.8 95.7h12.7zM135.9 100.8h2.5zM135.9 105.9h2.5zM135.9 110.9h2.5zM135.9 116h2.5zM138.4 110.9h17.8zM138.4 105.9h17.8zM138.4 100.8h17.8z"/>
<path d="M138.4 116h40.6zM156.2 110.9v10.2zM156.2 105.9v5zM156.2 95.7v5.1zM166.3 103.3v2.6zM180.6 114.9h12.7zM240 103.3h12.7zM240 100.8h12.7zM252.7 100.8h2.5zM252.7 103.3h2.5zM303.5 100.8h2.5zM303.5 103.3h2.5z"/>
<path d="M290.8 103.3h12.7zM290.8 100.8h12.7zM16.5 123.1h3.8zM135.9 121.1h2.5zM138.4 121.1h17.8zM156.2 123.6v2.6zM156.2 121.1v2.5zM166.3 123.6v2.6zM166.3 105.9v17.7zM400 123.1h3.8zM16.5 173.7h3.8zM135.9 174.4h10.1z"/>
<path d="M135.9 177h10.1zM135.9 179.5h10.1zM146 174.4h.6zM146 177h.6zM146 179.5h.6zM153.1 174.4h.5zM153.1 177h.5zM153.1 179.5h.5zM153.6 177h10.2zM153.6 174.4h10.2zM153.6 179.5h10.2zM228.4 175h9.1z"/>
<path d="M228.7 177.5h8.8zM262.9 177h2.5zM262.9 179.5h2.5zM237.5 177h25.4zM237.5 179.5h25.4zM400 173.7h3.8zM119.8 197.8h13.5zM122.4 182.6h10.9zM125.6 195.3h7.7zM126 185.1h7.3zM135.9 182.1h10.1zM135.9 184.6h10.1z"/>
<path d="M135.9 187.1h10.1zM135.9 189.7h10.1zM135.9 192.2h10.1zM135.9 197.3h10.1zM135.9 199.8h10.1zM135.9 194.8h10.1zM146 182.1h.6zM146 184.6h.6zM146 187.1h.6zM146 189.7h.6zM146 192.2h.6zM146 194.8h.6z"/>
<path d="M146 197.3h.6zM146 199.8h.6zM153.1 182.1h.5zM153.1 184.6h.5zM153.1 187.1h.5zM153.1 189.7h.5zM153.1 192.2h.5zM153.1 194.8h.5zM153.1 197.3h.5zM153.1 199.8h.5zM153.6 187.1h10.2zM153.6 189.7h10.2z"/>
<path d="M153.6 192.2h10.2zM153.6 194.8h10.2zM153.6 197.3h10.2zM153.6 199.8h10.2zM153.6 182.1h10.2zM153.6 184.6h10.2zM226 195.3h11.5zM231.4 192.7h6.1zM232 187.7h5.5zM232 190.2h5.5zM262.9 182.1h2.5zM262.9 184.6h2.5z"/>
<path d="M262.9 187.1h2.5zM262.9 189.7h2.5zM262.9 192.2h2.5zM262.9 194.8h2.5zM262.9 197.3h2.5zM237.5 187.1h25.4zM237.5 182.1h25.4zM237.5 184.6h25.4zM237.5 189.7h25.4zM237.5 192.2h25.4zM237.5 197.3h25.4zM237.5 194.8h25.4z"/>
<path d="M135.9 202.4h10.1zM135.9 204.9h10.1zM135.9 207.4h10.1zM135.9 210h10.1zM135.9 212.5h10.1zM135.9 215h10.1zM135.9 217.6h10.1zM146 202.4h.6zM146 204.9h.6zM146 207.4h.6zM146 210h.6zM146 212.5h.6z"/>
<path d="M146 215h.6zM146 217.6h.6zM153.1 202.4h.5zM153.1 204.9h.5zM153.1 207.4h.5zM153.1 210h.5zM153.1 212.5h.5zM153.1 215h.5zM153.1 217.6h.5zM153.6 217.6h10.2zM153.6 207.4h10.2zM153.6 210h10.2z"/>
<path d="M153.6 212.5h10.2zM153.6 215h10.2zM153.6 202.4h10.2zM153.6 204.9h10.2zM16.5 224.2h3.8zM146 220.1h.6zM146 222.7h.6zM135.9 220.1h10.1zM153.1 220.1h.5zM153.1 222.7h.5zM400 224.2h3.8zM20.3 274.7h379.7z"/>
<path d="M67.8 274.7v3.8zM115.3 274.7v3.8zM162.7 274.7v3.8zM210.2 274.7v3.8zM257.6 274.7v3.8zM305.1 274.7v3.8zM352.5 274.7v3.8zM400 264.5v.1zM400 268.4v6.2zM400 274.6h.1zM400 22.1v252.6z"/>
<circle cx="156.2" cy="95.7" r=".51"/>
<circle cx="156.2" cy="110.9" r=".51"/>
<circle cx="156.2" cy="121.1" r=".51"/>
</g>
<g fill="#000" stroke="#000" stroke-width=".28">
<path d="M156.2 88.1l-1.3 1.9zM156.2 88.1l1.3 1.9zM166.3 88.1l-1.2 1.9zM166.3 88.1l1.3 1.9zM164.8 100.8v.9zM164.8 101.7h3.1zM167.9 100.8v.9zM164.8 100.8h3.1zM179 116l1.6 1.5zM179 116l1.6-1.5zM180.6 117.5h18.7zM180.6 114.5h18.7z"/>
<path d="M199.3 114.5v3zM154.3 126.2h3.8zM164.4 126.2h3.9zM313.7 249.3h86.3zM313.7 254.4h86.3zM313.7 259.5h58.4zM372.1 259.5h27.9zM372.1 259.5v5.1zM313.7 264.6h58.4zM313.7 269.7h86.3zM372.1 264.6h27.9zM400 268.4v1.3z"/>
</g>
<g fill="none" stroke="#000" stroke-width=".28">
<circle cx="134.6" cy="95.7" r="1.27"/>
<circle cx="134.6" cy="110.9" r="1.27"/>
<circle cx="134.6" cy="116" r="1.27"/>
<circle cx="134.6" cy="100.8" r="1.27"/>
<circle cx="134.6" cy="105.9" r="1.27"/>
<circle cx="134.6" cy="121.1" r="1.27"/>
</g>
<g fill="#000" stroke="#000" stroke-width=".61">
<path d="M20.3 22.1v252.6zM20.3 22.1h379.7zM255.2 85.5h1.3zM255.2 88.1h1.3zM255.2 90.6h1.3zM255.2 93.2h1.3zM255.2 95.7h1.3zM255.2 98.2h1.3zM306 85.5h1.3zM306 88.1h1.3zM306 90.6h1.3zM306 93.2h1.3z"/>
<path d="M306 95.7h1.3zM306 98.2h1.3zM255.2 100.8h1.3zM255.2 103.3h1.3zM306 100.8h1.3zM306 103.3h1.3zM265.4 177h1.3zM265.4 179.5h1.3zM265.4 182.1h1.3zM265.4 184.6h1.3zM265.4 187.1h1.3zM265.4 189.7h1.3z"/>
<path d="M265.4 192.2h1.3zM265.4 194.8h1.3zM265.4 197.3h1.3zM283.2 244.3v30.4zM313.7 254.4v5.1zM313.7 249.3v5.1zM313.7 244.3v5zM313.7 244.3h86.3zM283.2 244.3h30.5zM400 254.4v5.1zM400 249.3v5.1zM400 244.3v5z"/>
<path d="M400 22.1v222.2zM20.3 274.7h262.9zM283.2 274.7h30.5zM313.7 274.7h86.3zM313.7 269.7v5zM313.7 264.6v5.1zM313.7 259.5v5.1zM400 268.4v6.3zM400 264.6v3.8zM400 259.5v5.1z"/>
</g>
<path d="M16.5 18.2v260.3zM16.5 18.2h387.3zM16.5 278.5h387.3zM403.8 18.2v260.3z" fill="#000" stroke="#000" stroke-width=".32"/>
<path d="M164.7 102.4h3.3v.9h-3.3zM372.1 222.7h25.4v10.1h-25.4z" fill="#000" stroke="#000" stroke-width=".25"/>
<g fill="none" stroke="#000" stroke-width=".25">
<circle cx="147.6" cy="177" r=".99"/>
<circle cx="147.6" cy="179.5" r=".99"/>
<circle cx="147.6" cy="174.4" r=".99"/>
<circle cx="152.1" cy="179.5" r=".99"/>
<circle cx="152.1" cy="177" r=".99"/>
<circle cx="152.1" cy="174.4" r=".99"/>
<circle cx="147.6" cy="199.8" r=".99"/>
<circle cx="147.6" cy="182.1" r=".99"/>
<circle cx="147.6" cy="194.8" r=".99"/>
<circle cx="147.6" cy="197.3" r=".99"/>
<circle cx="147.6" cy="192.2" r=".99"/>
<circle cx="147.6" cy="187.1" r=".99"/>
<circle cx="147.6" cy="184.6" r=".99"/>
<circle cx="147.6" cy="189.7" r=".99"/>
<circle cx="152.1" cy="192.2" r=".99"/>
<circle cx="152.1" cy="194.8" r=".99"/>
<circle cx="152.1" cy="182.1" r=".99"/>
<circle cx="152.1" cy="187.1" r=".99"/>
<circle cx="152.1" cy="197.3" r=".99"/>
<circle cx="152.1" cy="199.8" r=".99"/>
<circle cx="152.1" cy="184.6" r=".99"/>
<circle cx="152.1" cy="189.7" r=".99"/>
<circle cx="147.6" cy="217.6" r=".99"/>
<circle cx="147.6" cy="215" r=".99"/>
<circle cx="147.6" cy="212.5" r=".99"/>
<circle cx="147.6" cy="210" r=".99"/>
<circle cx="147.6" cy="202.4" r=".99"/>
<circle cx="147.6" cy="204.9" r=".99"/>
<circle cx="147.6" cy="207.4" r=".99"/>
<circle cx="152.1" cy="215" r=".99"/>
<circle cx="152.1" cy="217.6" r=".99"/>
<circle cx="152.1" cy="212.5" r=".99"/>
<circle cx="152.1" cy="210" r=".99"/>
<circle cx="152.1" cy="202.4" r=".99"/>
<circle cx="152.1" cy="204.9" r=".99"/>
<circle cx="152.1" cy="207.4" r=".99"/>
<circle cx="147.6" cy="220.1" r=".99"/>
<circle cx="147.6" cy="222.7" r=".99"/>
<circle cx="152.1" cy="220.1" r=".99"/>
<circle cx="152.1" cy="222.7" r=".99"/>
</g>
<path d="M142.2 171.9v53.3zM142.2 171.9h15.3zM142.2 225.2h15.3zM157.5 171.9v53.3zM341.6 222.7v10.1zM341.6 232.8v7.6zM341.6 232.8h55.9zM397.5 222.7v10.1zM341.6 222.7h55.9zM341.6 240.4h55.9zM397.5 232.8v7.6z" fill="#000" stroke="#000" stroke-width=".42"/>
<use href="#words"/>
</svg>
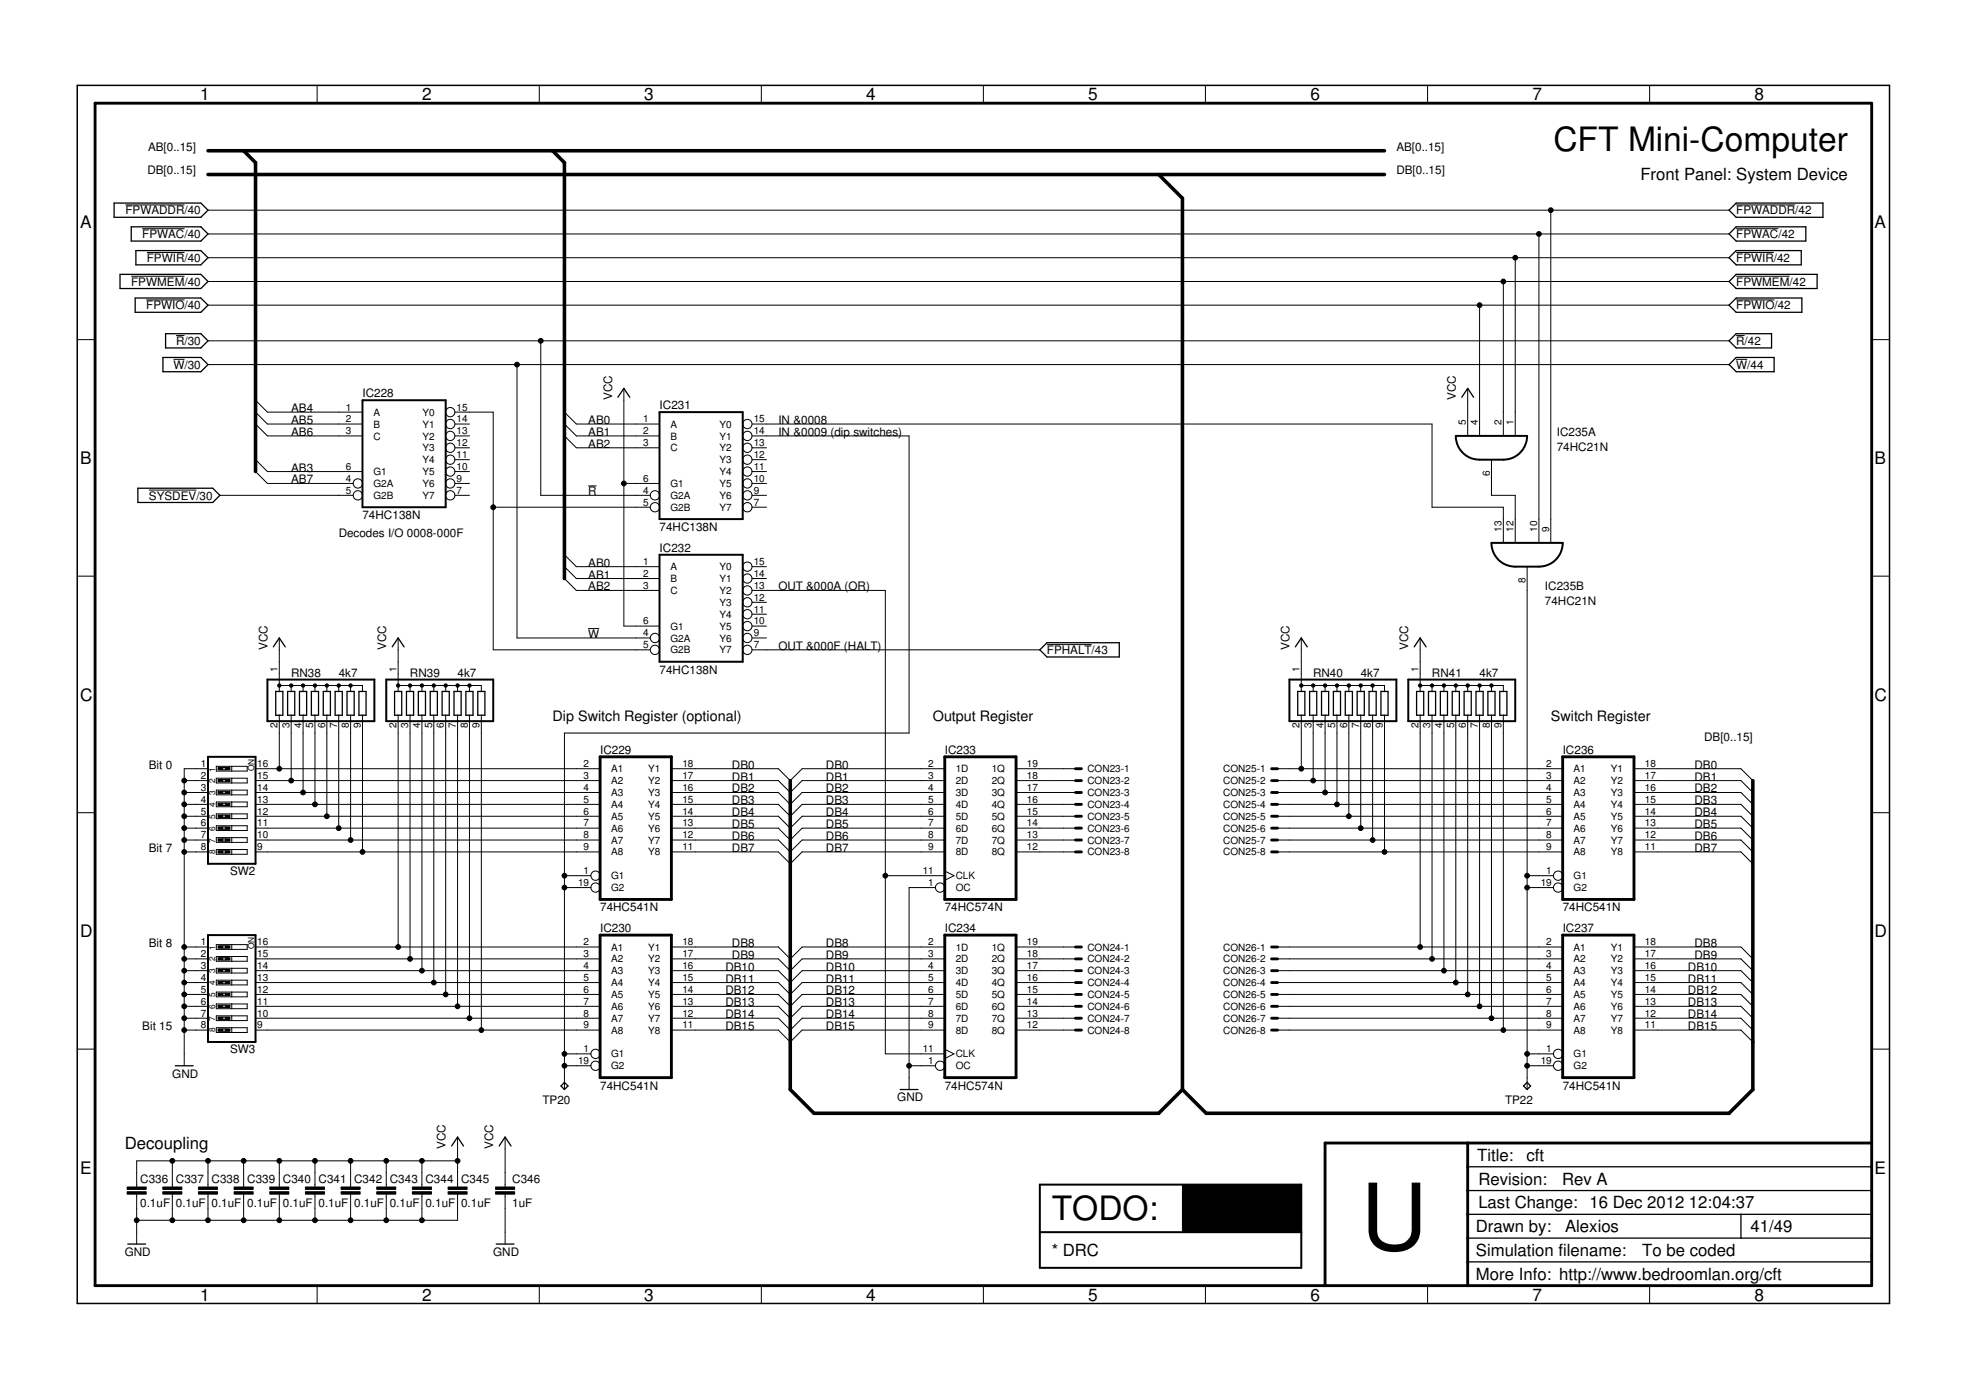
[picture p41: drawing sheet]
<svg xmlns="http://www.w3.org/2000/svg" width="420mm" height="297mm" viewBox="0 0 420 297" stroke-linecap="round" stroke-linejoin="round" font-family="sans-serif">
<defs><g id="words">
<text font-size="19.7" x="290.8" y="267.1">U</text>
<g font-size="7.2">
<text x="332" y="32.2">CFT Mini-Computer</text>
<text x="224.8" y="260.8">TODO:</text>
</g>
<g font-size="3.7">
<text x="42.7" y="21.5">1</text>
<text x="90.2" y="21.5">2</text>
<text x="137.7" y="21.5">3</text>
<text x="185.1" y="21.5">4</text>
<text x="232.6" y="21.5">5</text>
<text x="280" y="21.5">6</text>
<text x="327.5" y="21.5">7</text>
<text x="375" y="21.5">8</text>
<text x="17.1" y="48.6">A</text>
<text x="400.6" y="48.6">A</text>
<text x="17.1" y="99.2">B</text>
<text x="400.6" y="99.2">B</text>
<text x="17.1" y="149.7">C</text>
<text x="400.6" y="149.7">C</text>
<text x="17.1" y="200.2">D</text>
<text x="400.6" y="200.2">D</text>
<text x="17.1" y="250.8">E</text>
<text x="400.6" y="250.8">E</text>
<text x="42.7" y="277.9">1</text>
<text x="90.2" y="277.9">2</text>
<text x="137.7" y="277.9">3</text>
<text x="185.1" y="277.9">4</text>
<text x="232.6" y="277.9">5</text>
<text x="280" y="277.9">6</text>
<text x="327.5" y="277.9">7</text>
<text x="375" y="277.9">8</text>
</g>
<g font-size="3.6">
<text x="350.6" y="38.6">Front Panel: System Device</text>
<text x="26.7" y="245.5">Decoupling</text>
<text x="315.7" y="248.1">Title:</text>
<text x="326.2" y="248.2">cft</text>
<text x="315.9" y="253.2">Revision:</text>
<text x="333.8" y="253.3">Rev A</text>
<text x="315.4" y="263.3">Drawn by:</text>
<text x="315.9" y="258.2">Last Change: 16 Dec 2012</text>
<text x="334.5" y="263.3">Alexios</text>
<text x="361" y="258.1">12:04:37</text>
<text x="374.1" y="263.2">41/49</text>
<text x="224.8" y="268.4">* DRC</text>
<text x="315.4" y="268.4">Simulation filename:</text>
<text x="351" y="268.4">To be coded</text>
<text x="315.4" y="273.5">More Info: http://www.bedroomlan.org/cft</text>
</g>
<g font-size="3.1">
<text x="118.1" y="154.1">Dip Switch Register (optional)</text>
<text x="199.4" y="154.1">Output Register</text>
<text x="331.4" y="154.1">Switch Register</text>
</g>
<g font-size="2.5">
<text x="31.6" y="32.2">AB[0..15]</text>
<text x="298.4" y="32.2">AB[0..15]</text>
<text x="31.5" y="37.3">DB[0..15]</text>
<text x="298.4" y="37.3">DB[0..15]</text>
<text x="26.8" y="45.8">FPWADDR/40</text>
<text x="371" y="45.8">FPWADDR/42</text>
<text x="30.4" y="50.9">FPWAC/40</text>
<text x="371" y="50.9">FPWAC/42</text>
<text x="31.4" y="56">FPWIR/40</text>
<text x="371" y="56">FPWIR/42</text>
<text x="28" y="61">FPWMEM/40</text>
<text x="371" y="61">FPWMEM/42</text>
<text x="31.3" y="66.1">FPWIO/40</text>
<text x="371" y="66.1">FPWIO/42</text>
<text x="37.6" y="73.7">R/30</text>
<text x="371" y="73.7">R/42</text>
<text x="37.1" y="78.8">W/30</text>
<text x="371" y="78.8">W/44</text>
<text x="62.2" y="88.1">AB4</text>
<text x="77.5" y="84.9">IC228</text>
<text x="130.8" y="85.5" transform="rotate(-90 130.8 85.5)">VCC</text>
<text x="141" y="87.4">IC231</text>
<text x="311.1" y="85.5" transform="rotate(-90 311.1 85.5)">VCC</text>
<text x="62.2" y="90.6">AB5</text>
<text x="62.2" y="93.2">AB6</text>
<text x="125.7" y="90.6">AB0</text>
<text x="125.7" y="93.2">AB1</text>
<text x="125.7" y="95.7">AB2</text>
<text x="166.4" y="90.6">IN &amp;0008</text>
<text x="166.4" y="93.2">IN &amp;0009 (dip switches)</text>
<text x="332.7" y="93.2">IC235A</text>
<text x="62.2" y="100.8">AB3</text>
<text x="332.7" y="96.3">74HC21N</text>
<text x="31.8" y="106.7">SYSDEV/30</text>
<text x="62.2" y="103.3">AB7</text>
<text x="125.7" y="105.9">R</text>
<text x="77.5" y="110.9">74HC138N</text>
<text x="141" y="113.5">74HC138N</text>
<text x="72.4" y="114.7">Decodes I/O 0008-000F</text>
<text x="141" y="117.9">IC232</text>
<text x="125.7" y="121.1">AB0</text>
<text x="125.7" y="123.6">AB1</text>
<text x="125.7" y="126.2">AB2</text>
<text x="166.4" y="126.2">OUT &amp;000A (OR)</text>
<text x="330.2" y="129.3">74HC21N</text>
<text x="330.2" y="126.2">IC235B</text>
<text x="125.7" y="136.3">W</text>
<text x="57.1" y="138.9" transform="rotate(-90 57.1 138.9)">VCC</text>
<text x="82.5" y="138.9" transform="rotate(-90 82.5 138.9)">VCC</text>
<text x="141" y="144">74HC138N</text>
<text x="166.4" y="138.9">OUT &amp;000F (HALT)</text>
<text x="223.7" y="139.8">FPHALT/43</text>
<text x="275.6" y="138.9" transform="rotate(-90 275.6 138.9)">VCC</text>
<text x="301" y="138.9" transform="rotate(-90 301 138.9)">VCC</text>
<text x="62.2" y="144.6">RN38</text>
<text x="72.4" y="144.6">4k7</text>
<text x="87.6" y="144.6">RN39</text>
<text x="97.8" y="144.6">4k7</text>
<text x="280.6" y="144.6">RN40</text>
<text x="290.8" y="144.6">4k7</text>
<text x="306" y="144.6">RN41</text>
<text x="316.2" y="144.6">4k7</text>
<text x="128.3" y="161.1">IC229</text>
<text x="201.9" y="161.1">IC233</text>
<text x="334" y="161.1">IC236</text>
<text x="364.2" y="158.4">DB[0..15]</text>
<text x="31.8" y="164.3">Bit 0</text>
<text x="156.4" y="164.3">DB0</text>
<text x="156.4" y="166.8">DB1</text>
<text x="176.5" y="164.3">DB0</text>
<text x="176.5" y="166.8">DB1</text>
<text x="362.1" y="164.3">DB0</text>
<text x="362.1" y="166.8">DB1</text>
<text x="156.4" y="169.3">DB2</text>
<text x="156.4" y="171.9">DB3</text>
<text x="176.5" y="169.3">DB2</text>
<text x="176.5" y="171.9">DB3</text>
<text x="362.1" y="169.3">DB2</text>
<text x="362.1" y="171.9">DB3</text>
<text x="156.4" y="177">DB5</text>
<text x="156.4" y="179.5">DB6</text>
<text x="156.4" y="174.4">DB4</text>
<text x="176.5" y="177">DB5</text>
<text x="176.5" y="179.5">DB6</text>
<text x="176.5" y="174.4">DB4</text>
<text x="362.1" y="177">DB5</text>
<text x="362.1" y="179.5">DB6</text>
<text x="362.1" y="174.4">DB4</text>
<text x="31.8" y="182">Bit 7</text>
<text x="156.4" y="182">DB7</text>
<text x="176.5" y="182">DB7</text>
<text x="362.1" y="182">DB7</text>
<text x="49.2" y="187">SW2</text>
<text x="128.3" y="194.7">74HC541N</text>
<text x="201.9" y="194.7">74HC574N</text>
<text x="334" y="194.7">74HC541N</text>
<text x="31.8" y="202.4">Bit 8</text>
<text x="128.3" y="199.2">IC230</text>
<text x="156.4" y="202.4">DB8</text>
<text x="176.5" y="202.4">DB8</text>
<text x="201.9" y="199.2">IC234</text>
<text x="334" y="199.2">IC237</text>
<text x="362.1" y="202.4">DB8</text>
<text x="155" y="207.4">DB10</text>
<text x="155" y="210">DB11</text>
<text x="156.4" y="204.9">DB9</text>
<text x="176.5" y="204.9">DB9</text>
<text x="176.5" y="207.4">DB10</text>
<text x="176.5" y="210">DB11</text>
<text x="360.7" y="207.4">DB10</text>
<text x="360.7" y="210">DB11</text>
<text x="362.1" y="204.9">DB9</text>
<text x="155" y="212.5">DB12</text>
<text x="155" y="215.1">DB13</text>
<text x="176.5" y="212.5">DB12</text>
<text x="176.5" y="215.1">DB13</text>
<text x="360.7" y="212.5">DB12</text>
<text x="360.7" y="215.1">DB13</text>
<text x="30.4" y="220.1">Bit 15</text>
<text x="155" y="217.6">DB14</text>
<text x="155" y="220.1">DB15</text>
<text x="176.5" y="217.6">DB14</text>
<text x="176.5" y="220.1">DB15</text>
<text x="360.7" y="217.6">DB14</text>
<text x="360.7" y="220.1">DB15</text>
<text x="49.2" y="225.1">SW3</text>
<text x="36.8" y="230.3">GND</text>
<text x="128.3" y="232.8">74HC541N</text>
<text x="201.9" y="232.8">74HC574N</text>
<text x="334" y="232.8">74HC541N</text>
<text x="115.9" y="235.9">TP20</text>
<text x="191.7" y="235.4">GND</text>
<text x="321.7" y="235.9">TP22</text>
<text x="95.2" y="245.5" transform="rotate(-90 95.2 245.5)">VCC</text>
<text x="105.4" y="245.5" transform="rotate(-90 105.4 245.5)">VCC</text>
<text x="30" y="257.9">0.1uF</text>
<text x="30" y="252.8">C336</text>
<text x="37.6" y="257.9">0.1uF</text>
<text x="37.6" y="252.8">C337</text>
<text x="45.2" y="257.9">0.1uF</text>
<text x="45.2" y="252.8">C338</text>
<text x="52.8" y="257.9">0.1uF</text>
<text x="52.8" y="252.8">C339</text>
<text x="60.4" y="257.9">0.1uF</text>
<text x="60.4" y="252.8">C340</text>
<text x="68.1" y="257.9">0.1uF</text>
<text x="68.1" y="252.8">C341</text>
<text x="75.7" y="257.9">0.1uF</text>
<text x="75.7" y="252.8">C342</text>
<text x="83.3" y="257.9">0.1uF</text>
<text x="83.3" y="252.8">C343</text>
<text x="90.9" y="257.9">0.1uF</text>
<text x="90.9" y="252.8">C344</text>
<text x="98.5" y="257.9">0.1uF</text>
<text x="98.5" y="252.8">C345</text>
<text x="109.5" y="257.9">1uF</text>
<text x="109.5" y="252.8">C346</text>
<text x="26.7" y="268.4">GND</text>
<text x="105.4" y="268.4">GND</text>
</g>
<g font-size="2.1">
<text x="73.9" y="87.7">1</text>
<text x="79.8" y="88.8">A</text>
<text x="90.3" y="88.8">Y0</text>
<text x="97.6" y="87.7">15</text>
<text x="73.9" y="90.3">2</text>
<text x="73.9" y="92.8">3</text>
<text x="79.8" y="91.4">B</text>
<text x="79.8" y="93.9">C</text>
<text x="90.3" y="93.9">Y2</text>
<text x="90.3" y="91.4">Y1</text>
<text x="97.6" y="95.3">12</text>
<text x="97.6" y="92.8">13</text>
<text x="97.6" y="90.3">14</text>
<text x="137.4" y="90.3">1</text>
<text x="137.4" y="92.8">2</text>
<text x="137.4" y="95.3">3</text>
<text x="143.3" y="91.4">A</text>
<text x="143.3" y="93.9">B</text>
<text x="153.8" y="93.9">Y1</text>
<text x="153.8" y="91.4">Y0</text>
<text x="161.1" y="95.3">13</text>
<text x="161.1" y="92.8">14</text>
<text x="161.1" y="90.3">15</text>
<text x="313.3" y="90.8" transform="rotate(-90 313.3 90.8)">5</text>
<text x="315.8" y="90.8" transform="rotate(-90 315.8 90.8)">4</text>
<text x="320.9" y="90.8" transform="rotate(-90 320.9 90.8)">2</text>
<text x="323.5" y="90.8" transform="rotate(-90 323.5 90.8)">1</text>
<text x="73.9" y="100.4">6</text>
<text x="79.8" y="101.5">G1</text>
<text x="90.3" y="101.5">Y5</text>
<text x="90.3" y="99">Y4</text>
<text x="90.3" y="96.5">Y3</text>
<text x="97.6" y="100.4">10</text>
<text x="97.6" y="97.9">11</text>
<text x="143.3" y="96.5">C</text>
<text x="153.8" y="101.5">Y4</text>
<text x="153.8" y="99">Y3</text>
<text x="153.8" y="96.5">Y2</text>
<text x="161.1" y="100.4">11</text>
<text x="161.1" y="97.9">12</text>
<text x="318.4" y="101.8" transform="rotate(-90 318.4 101.8)">6</text>
<text x="73.9" y="103">4</text>
<text x="73.9" y="105.5">5</text>
<text x="79.8" y="104.1">G2A</text>
<text x="79.8" y="106.6">G2B</text>
<text x="90.3" y="106.6">Y7</text>
<text x="90.3" y="104.1">Y6</text>
<text x="97.6" y="105.5">7</text>
<text x="97.6" y="103">9</text>
<text x="137.4" y="105.5">4</text>
<text x="137.4" y="103">6</text>
<text x="143.3" y="106.6">G2A</text>
<text x="143.3" y="104.1">G1</text>
<text x="153.8" y="106.6">Y6</text>
<text x="153.8" y="104.1">Y5</text>
<text x="161.1" y="105.5">9</text>
<text x="161.1" y="103">10</text>
<text x="137.4" y="108">5</text>
<text x="143.3" y="109.2">G2B</text>
<text x="153.8" y="109.2">Y7</text>
<text x="161.1" y="108">7</text>
<text x="320.9" y="113.7" transform="rotate(-90 320.9 113.7)">13</text>
<text x="323.5" y="113.7" transform="rotate(-90 323.5 113.7)">12</text>
<text x="328.5" y="113.7" transform="rotate(-90 328.5 113.7)">10</text>
<text x="331.1" y="113.7" transform="rotate(-90 331.1 113.7)">9</text>
<text x="137.4" y="120.7">1</text>
<text x="137.4" y="123.3">2</text>
<text x="137.4" y="125.8">3</text>
<text x="143.3" y="121.9">A</text>
<text x="143.3" y="124.4">B</text>
<text x="153.8" y="124.4">Y1</text>
<text x="153.8" y="121.9">Y0</text>
<text x="161.1" y="125.8">13</text>
<text x="161.1" y="123.3">14</text>
<text x="161.1" y="120.7">15</text>
<text x="326" y="124.6" transform="rotate(-90 326 124.6)">8</text>
<text x="143.3" y="126.9">C</text>
<text x="153.8" y="129.5">Y3</text>
<text x="153.8" y="126.9">Y2</text>
<text x="161.1" y="130.9">11</text>
<text x="161.1" y="128.4">12</text>
<text x="137.4" y="136">4</text>
<text x="137.4" y="133.4">6</text>
<text x="143.3" y="137.1">G2A</text>
<text x="143.3" y="134.6">G1</text>
<text x="153.8" y="137.1">Y6</text>
<text x="153.8" y="134.6">Y5</text>
<text x="153.8" y="132">Y4</text>
<text x="161.1" y="136">9</text>
<text x="161.1" y="133.4">10</text>
<text x="59.3" y="143.6" transform="rotate(-90 59.3 143.6)">1</text>
<text x="84.7" y="143.6" transform="rotate(-90 84.7 143.6)">1</text>
<text x="137.4" y="138.5">5</text>
<text x="143.3" y="139.6">G2B</text>
<text x="153.8" y="139.6">Y7</text>
<text x="161.1" y="138.5">7</text>
<text x="277.7" y="143.6" transform="rotate(-90 277.7 143.6)">1</text>
<text x="303.1" y="143.6" transform="rotate(-90 303.1 143.6)">1</text>
<text x="59.3" y="155.6" transform="rotate(-90 59.3 155.6)">2</text>
<text x="61.9" y="155.6" transform="rotate(-90 61.9 155.6)">3</text>
<text x="64.4" y="155.6" transform="rotate(-90 64.4 155.6)">4</text>
<text x="66.9" y="155.6" transform="rotate(-90 66.9 155.6)">5</text>
<text x="69.5" y="155.6" transform="rotate(-90 69.5 155.6)">6</text>
<text x="72" y="155.6" transform="rotate(-90 72 155.6)">7</text>
<text x="74.6" y="155.6" transform="rotate(-90 74.6 155.6)">8</text>
<text x="77.1" y="155.6" transform="rotate(-90 77.1 155.6)">9</text>
<text x="84.7" y="155.6" transform="rotate(-90 84.7 155.6)">2</text>
<text x="87.3" y="155.6" transform="rotate(-90 87.3 155.6)">3</text>
<text x="89.8" y="155.6" transform="rotate(-90 89.8 155.6)">4</text>
<text x="92.3" y="155.6" transform="rotate(-90 92.3 155.6)">5</text>
<text x="94.9" y="155.6" transform="rotate(-90 94.9 155.6)">6</text>
<text x="97.4" y="155.6" transform="rotate(-90 97.4 155.6)">7</text>
<text x="100" y="155.6" transform="rotate(-90 100 155.6)">8</text>
<text x="102.5" y="155.6" transform="rotate(-90 102.5 155.6)">9</text>
<text x="277.7" y="155.6" transform="rotate(-90 277.7 155.6)">2</text>
<text x="280.3" y="155.6" transform="rotate(-90 280.3 155.6)">3</text>
<text x="282.8" y="155.6" transform="rotate(-90 282.8 155.6)">4</text>
<text x="285.4" y="155.6" transform="rotate(-90 285.4 155.6)">5</text>
<text x="287.9" y="155.6" transform="rotate(-90 287.9 155.6)">6</text>
<text x="290.4" y="155.6" transform="rotate(-90 290.4 155.6)">7</text>
<text x="293" y="155.6" transform="rotate(-90 293 155.6)">8</text>
<text x="295.5" y="155.6" transform="rotate(-90 295.5 155.6)">9</text>
<text x="303.1" y="155.6" transform="rotate(-90 303.1 155.6)">2</text>
<text x="305.7" y="155.6" transform="rotate(-90 305.7 155.6)">3</text>
<text x="308.2" y="155.6" transform="rotate(-90 308.2 155.6)">4</text>
<text x="310.8" y="155.6" transform="rotate(-90 310.8 155.6)">5</text>
<text x="313.3" y="155.6" transform="rotate(-90 313.3 155.6)">6</text>
<text x="315.8" y="155.6" transform="rotate(-90 315.8 155.6)">7</text>
<text x="318.4" y="155.6" transform="rotate(-90 318.4 155.6)">8</text>
<text x="320.9" y="155.6" transform="rotate(-90 320.9 155.6)">9</text>
<text x="42.9" y="163.9">1</text>
<text x="42.9" y="166.5">2</text>
<text x="55" y="166.5">15</text>
<text x="55" y="163.9">16</text>
<text x="124.7" y="163.9">2</text>
<text x="124.7" y="166.5">3</text>
<text x="130.6" y="165">A1</text>
<text x="130.6" y="167.6">A2</text>
<text x="138.6" y="167.6">Y2</text>
<text x="138.6" y="165">Y1</text>
<text x="145.8" y="166.5">17</text>
<text x="145.8" y="163.9">18</text>
<text x="198.4" y="163.9">2</text>
<text x="198.4" y="166.5">3</text>
<text x="204.2" y="165">1D</text>
<text x="204.2" y="167.6">2D</text>
<text x="212" y="167.6">2Q</text>
<text x="212" y="165">1Q</text>
<text x="219.5" y="166.5">18</text>
<text x="219.5" y="163.9">19</text>
<text x="232.4" y="165">CON23-1</text>
<text x="232.4" y="167.6">CON23-2</text>
<text x="261.4" y="165">CON25-1</text>
<text x="261.4" y="167.6">CON25-2</text>
<text x="330.4" y="163.9">2</text>
<text x="330.4" y="166.5">3</text>
<text x="336.3" y="165">A1</text>
<text x="336.3" y="167.6">A2</text>
<text x="344.3" y="167.6">Y2</text>
<text x="344.3" y="165">Y1</text>
<text x="351.5" y="166.5">17</text>
<text x="351.5" y="163.9">18</text>
<text x="42.9" y="169">3</text>
<text x="42.9" y="171.5">4</text>
<text x="55" y="171.5">13</text>
<text x="55" y="169">14</text>
<text x="124.7" y="169">4</text>
<text x="124.7" y="171.5">5</text>
<text x="130.6" y="170.1">A3</text>
<text x="130.6" y="172.6">A4</text>
<text x="138.6" y="172.6">Y4</text>
<text x="138.6" y="170.1">Y3</text>
<text x="145.8" y="171.5">15</text>
<text x="145.8" y="169">16</text>
<text x="198.4" y="169">4</text>
<text x="198.4" y="171.5">5</text>
<text x="204.2" y="170.1">3D</text>
<text x="204.2" y="172.6">4D</text>
<text x="212" y="172.6">4Q</text>
<text x="212" y="170.1">3Q</text>
<text x="219.5" y="171.5">16</text>
<text x="219.5" y="169">17</text>
<text x="232.4" y="170.1">CON23-3</text>
<text x="232.4" y="172.6">CON23-4</text>
<text x="261.4" y="170.1">CON25-3</text>
<text x="261.4" y="172.6">CON25-4</text>
<text x="330.4" y="169">4</text>
<text x="330.4" y="171.5">5</text>
<text x="336.3" y="170.1">A3</text>
<text x="336.3" y="172.6">A4</text>
<text x="344.3" y="172.6">Y4</text>
<text x="344.3" y="170.1">Y3</text>
<text x="351.5" y="171.5">15</text>
<text x="351.5" y="169">16</text>
<text x="42.9" y="174.1">5</text>
<text x="42.9" y="176.6">6</text>
<text x="42.9" y="179.1">7</text>
<text x="55" y="179.1">10</text>
<text x="55" y="176.6">11</text>
<text x="55" y="174.1">12</text>
<text x="124.7" y="174.1">6</text>
<text x="124.7" y="176.6">7</text>
<text x="124.7" y="179.1">8</text>
<text x="130.6" y="175.2">A5</text>
<text x="130.6" y="177.7">A6</text>
<text x="138.6" y="177.7">Y6</text>
<text x="138.6" y="175.2">Y5</text>
<text x="145.8" y="179.1">12</text>
<text x="145.8" y="176.6">13</text>
<text x="145.8" y="174.1">14</text>
<text x="198.4" y="174.1">6</text>
<text x="198.4" y="176.6">7</text>
<text x="198.4" y="179.1">8</text>
<text x="204.2" y="175.2">5D</text>
<text x="204.2" y="177.7">6D</text>
<text x="212" y="177.7">6Q</text>
<text x="212" y="175.2">5Q</text>
<text x="219.5" y="179.1">13</text>
<text x="219.5" y="176.6">14</text>
<text x="219.5" y="174.1">15</text>
<text x="232.4" y="175.2">CON23-5</text>
<text x="232.4" y="177.7">CON23-6</text>
<text x="261.4" y="175.2">CON25-5</text>
<text x="261.4" y="177.7">CON25-6</text>
<text x="330.4" y="174.1">6</text>
<text x="330.4" y="176.6">7</text>
<text x="330.4" y="179.1">8</text>
<text x="336.3" y="175.2">A5</text>
<text x="336.3" y="177.7">A6</text>
<text x="344.3" y="177.7">Y6</text>
<text x="344.3" y="175.2">Y5</text>
<text x="351.5" y="179.1">12</text>
<text x="351.5" y="176.6">13</text>
<text x="351.5" y="174.1">14</text>
<text x="42.9" y="181.7">8</text>
<text x="55" y="181.7">9</text>
<text x="124.7" y="181.7">9</text>
<text x="130.6" y="180.3">A7</text>
<text x="130.6" y="182.8">A8</text>
<text x="138.6" y="182.8">Y8</text>
<text x="138.6" y="180.3">Y7</text>
<text x="145.8" y="181.7">11</text>
<text x="198.4" y="181.7">9</text>
<text x="204.2" y="180.3">7D</text>
<text x="204.2" y="182.8">8D</text>
<text x="212" y="182.8">8Q</text>
<text x="212" y="180.3">7Q</text>
<text x="219.5" y="181.7">12</text>
<text x="232.4" y="180.3">CON23-7</text>
<text x="232.4" y="182.8">CON23-8</text>
<text x="261.4" y="180.3">CON25-7</text>
<text x="261.4" y="182.8">CON25-8</text>
<text x="330.4" y="181.7">9</text>
<text x="336.3" y="180.3">A7</text>
<text x="336.3" y="182.8">A8</text>
<text x="344.3" y="182.8">Y8</text>
<text x="344.3" y="180.3">Y7</text>
<text x="351.5" y="181.7">11</text>
<text x="123.5" y="189.3">19</text>
<text x="124.7" y="186.8">1</text>
<text x="130.6" y="187.9">G1</text>
<text x="130.6" y="190.4">G2</text>
<text x="197.2" y="186.8">11</text>
<text x="198.4" y="189.3">1</text>
<text x="204.2" y="190.4">OC</text>
<text x="204.2" y="187.9">CLK</text>
<text x="329.3" y="189.3">19</text>
<text x="330.4" y="186.8">1</text>
<text x="336.3" y="187.9">G1</text>
<text x="336.3" y="190.4">G2</text>
<text x="42.9" y="202">1</text>
<text x="55" y="202">16</text>
<text x="124.7" y="202">2</text>
<text x="130.6" y="203.1">A1</text>
<text x="138.6" y="203.1">Y1</text>
<text x="145.8" y="202">18</text>
<text x="198.4" y="202">2</text>
<text x="204.2" y="203.1">1D</text>
<text x="212" y="203.1">1Q</text>
<text x="219.5" y="202">19</text>
<text x="232.4" y="203.1">CON24-1</text>
<text x="261.4" y="203.1">CON26-1</text>
<text x="330.4" y="202">2</text>
<text x="336.3" y="203.1">A1</text>
<text x="344.3" y="203.1">Y1</text>
<text x="351.5" y="202">18</text>
<text x="42.9" y="204.5">2</text>
<text x="42.9" y="207.1">3</text>
<text x="42.9" y="209.6">4</text>
<text x="55" y="209.6">13</text>
<text x="55" y="207.1">14</text>
<text x="55" y="204.5">15</text>
<text x="124.7" y="204.5">3</text>
<text x="124.7" y="207.1">4</text>
<text x="124.7" y="209.6">5</text>
<text x="130.6" y="205.7">A2</text>
<text x="130.6" y="208.2">A3</text>
<text x="138.6" y="208.2">Y3</text>
<text x="138.6" y="205.7">Y2</text>
<text x="145.8" y="209.6">15</text>
<text x="145.8" y="207.1">16</text>
<text x="145.8" y="204.5">17</text>
<text x="198.4" y="204.5">3</text>
<text x="198.4" y="207.1">4</text>
<text x="198.4" y="209.6">5</text>
<text x="204.2" y="205.7">2D</text>
<text x="204.2" y="208.2">3D</text>
<text x="212" y="208.2">3Q</text>
<text x="212" y="205.7">2Q</text>
<text x="219.5" y="209.6">16</text>
<text x="219.5" y="207.1">17</text>
<text x="219.5" y="204.5">18</text>
<text x="232.4" y="205.7">CON24-2</text>
<text x="232.4" y="208.2">CON24-3</text>
<text x="261.4" y="205.7">CON26-2</text>
<text x="261.4" y="208.2">CON26-3</text>
<text x="330.4" y="204.5">3</text>
<text x="330.4" y="207.1">4</text>
<text x="330.4" y="209.6">5</text>
<text x="336.3" y="205.7">A2</text>
<text x="336.3" y="208.2">A3</text>
<text x="344.3" y="208.2">Y3</text>
<text x="344.3" y="205.7">Y2</text>
<text x="351.5" y="209.6">15</text>
<text x="351.5" y="207.1">16</text>
<text x="351.5" y="204.5">17</text>
<text x="42.9" y="212.2">5</text>
<text x="42.9" y="214.7">6</text>
<text x="55" y="214.7">11</text>
<text x="55" y="212.2">12</text>
<text x="124.7" y="212.2">6</text>
<text x="124.7" y="214.7">7</text>
<text x="130.6" y="210.7">A4</text>
<text x="130.6" y="213.3">A5</text>
<text x="130.6" y="215.8">A6</text>
<text x="138.6" y="215.8">Y6</text>
<text x="138.6" y="213.3">Y5</text>
<text x="138.6" y="210.7">Y4</text>
<text x="145.8" y="214.7">13</text>
<text x="145.8" y="212.2">14</text>
<text x="198.4" y="212.2">6</text>
<text x="198.4" y="214.7">7</text>
<text x="204.2" y="210.7">4D</text>
<text x="204.2" y="213.3">5D</text>
<text x="204.2" y="215.8">6D</text>
<text x="212" y="215.8">6Q</text>
<text x="212" y="213.3">5Q</text>
<text x="212" y="210.7">4Q</text>
<text x="219.5" y="214.7">14</text>
<text x="219.5" y="212.2">15</text>
<text x="232.4" y="210.7">CON24-4</text>
<text x="232.4" y="213.3">CON24-5</text>
<text x="232.4" y="215.8">CON24-6</text>
<text x="261.4" y="210.7">CON26-4</text>
<text x="261.4" y="213.3">CON26-5</text>
<text x="261.4" y="215.8">CON26-6</text>
<text x="330.4" y="212.2">6</text>
<text x="330.4" y="214.7">7</text>
<text x="336.3" y="210.7">A4</text>
<text x="336.3" y="213.3">A5</text>
<text x="336.3" y="215.8">A6</text>
<text x="344.3" y="215.8">Y6</text>
<text x="344.3" y="213.3">Y5</text>
<text x="344.3" y="210.7">Y4</text>
<text x="351.5" y="214.7">13</text>
<text x="351.5" y="212.2">14</text>
<text x="42.9" y="217.2">7</text>
<text x="42.9" y="219.8">8</text>
<text x="55" y="219.8">9</text>
<text x="55" y="217.2">10</text>
<text x="124.7" y="217.2">8</text>
<text x="124.7" y="219.8">9</text>
<text x="130.6" y="218.4">A7</text>
<text x="130.6" y="220.9">A8</text>
<text x="138.6" y="220.9">Y8</text>
<text x="138.6" y="218.4">Y7</text>
<text x="145.8" y="219.8">11</text>
<text x="145.8" y="217.2">12</text>
<text x="198.4" y="217.2">8</text>
<text x="198.4" y="219.8">9</text>
<text x="204.2" y="218.4">7D</text>
<text x="204.2" y="220.9">8D</text>
<text x="212" y="220.9">8Q</text>
<text x="212" y="218.4">7Q</text>
<text x="219.5" y="219.8">12</text>
<text x="219.5" y="217.2">13</text>
<text x="232.4" y="218.4">CON24-7</text>
<text x="232.4" y="220.9">CON24-8</text>
<text x="261.4" y="218.4">CON26-7</text>
<text x="261.4" y="220.9">CON26-8</text>
<text x="330.4" y="217.2">8</text>
<text x="330.4" y="219.8">9</text>
<text x="336.3" y="218.4">A7</text>
<text x="336.3" y="220.9">A8</text>
<text x="344.3" y="220.9">Y8</text>
<text x="344.3" y="218.4">Y7</text>
<text x="351.5" y="219.8">11</text>
<text x="351.5" y="217.2">12</text>
<text x="123.5" y="227.4">19</text>
<text x="124.7" y="224.9">1</text>
<text x="130.6" y="226">G1</text>
<text x="197.2" y="224.9">11</text>
<text x="198.4" y="227.4">1</text>
<text x="204.2" y="226">CLK</text>
<text x="329.3" y="227.4">19</text>
<text x="330.4" y="224.9">1</text>
<text x="336.3" y="226">G1</text>
<text x="130.6" y="228.5">G2</text>
<text x="204.2" y="228.5">OC</text>
<text x="336.3" y="228.5">G2</text>
</g>
<g font-size="1.8">
<text x="46" y="167.3" transform="rotate(-90 46 167.3)">2</text>
<text x="46" y="165" transform="rotate(-90 46 165)">1</text>
<text x="54.4" y="164.8" transform="rotate(-90 54.4 164.8)">ON</text>
<text x="46" y="172.4" transform="rotate(-90 46 172.4)">4</text>
<text x="46" y="169.8" transform="rotate(-90 46 169.8)">3</text>
<text x="46" y="177.6" transform="rotate(-90 46 177.6)">6</text>
<text x="46" y="175" transform="rotate(-90 46 175)">5</text>
<text x="46" y="182.5" transform="rotate(-90 46 182.5)">8</text>
<text x="46" y="180.1" transform="rotate(-90 46 180.1)">7</text>
<text x="46" y="203.1" transform="rotate(-90 46 203.1)">1</text>
<text x="54.4" y="202.8" transform="rotate(-90 54.4 202.8)">ON</text>
<text x="46" y="207.9" transform="rotate(-90 46 207.9)">3</text>
<text x="46" y="205.4" transform="rotate(-90 46 205.4)">2</text>
<text x="46" y="215.7" transform="rotate(-90 46 215.7)">6</text>
<text x="46" y="213.1" transform="rotate(-90 46 213.1)">5</text>
<text x="46" y="210.5" transform="rotate(-90 46 210.5)">4</text>
<text x="46" y="220.6" transform="rotate(-90 46 220.6)">8</text>
<text x="46" y="218.2" transform="rotate(-90 46 218.2)">7</text>
</g>
</g></defs>
<g fill="#000" stroke="#000" stroke-width=".28">
<path d="M24.4 43.4v3zM25.7 58.6v3.1zM28 48.5v3zM29 53.6v3zM24.4 43.4h18.5zM24.4 46.4h18.5zM28 48.5h14.9zM28 51.5h14.9zM29 53.6h13.9zM29 56.6h13.9zM25.7 58.6h17.2zM42.9 43.4l1.5 1.5z"/>
<path d="M44.4 44.9l-1.5 1.5zM42.9 48.5l1.5 1.5zM44.4 50l-1.5 1.5zM42.9 53.6l1.5 1.5zM42.9 56.6l1.5-1.5zM369.5 44.9l1.5-1.5zM369.5 44.9l1.5 1.5zM371 48.5l-1.5 1.5zM369.5 50l1.5 1.5zM369.5 55.1l1.5-1.5zM369.5 55.1l1.5 1.5zM371 43.4h18.6z"/>
<path d="M371 46.4h18.6zM371 48.5h14.9zM371 51.5h14.9zM371 53.6h14zM371 56.6h14zM371 58.6h17.3zM385 53.6v3zM385.9 48.5v3zM388.3 58.6v3.1zM389.6 43.4v3zM28.9 63.7v3zM34.8 76.4v3z"/>
<path d="M35.4 71.3v3.1zM25.7 61.7h17.2zM28.9 63.7h14zM28.9 66.7h14zM35.4 71.3h7.5zM35.4 74.4h7.5zM34.8 76.4h8.1zM34.8 79.4h8.1zM42.9 58.6l1.5 1.6zM42.9 61.7l1.5-1.5zM42.9 63.7l1.5 1.5zM44.4 65.2l-1.5 1.5z"/>
<path d="M42.9 71.3l1.5 1.5zM44.4 72.8l-1.5 1.6zM42.9 76.4l1.5 1.5zM42.9 79.4l1.5-1.5zM369.5 60.2l1.5-1.6zM369.5 60.2l1.5 1.5zM369.5 65.2l1.5-1.5zM369.5 65.2l1.5 1.5zM369.5 72.8l1.5-1.5zM369.5 72.8l1.5 1.6zM371 76.4l-1.5 1.5zM369.5 77.9l1.5 1.5z"/>
<path d="M371 61.7h17.3zM371 63.7h14.1zM371 66.7h14.1zM371 71.3h7.6zM371 74.4h7.6zM371 76.4h8.2zM371 79.4h8.2zM378.6 71.3v3.1zM379.2 76.4v3zM385.1 63.7v3zM133.3 83l-1.2 1.9zM133.3 83l1.3 1.9z"/>
<path d="M313.7 83l-1.3 1.9zM313.7 83l1.2 1.9zM29.5 104.3v3.1zM29.5 104.3h16zM29.5 107.4h16zM45.5 104.3l1.5 1.6zM47 105.9l-1.5 1.5zM59.7 136.3l-1.3 1.9zM59.7 136.3l1.3 1.9zM85.1 136.3l-1.3 1.9zM85.1 136.3l1.3 1.9zM222.2 138.9l1.5-1.6z"/>
<path d="M222.2 138.9l1.5 1.5zM223.7 137.3h15.5zM239.2 137.3v3.1zM278.1 136.3l-1.3 1.9zM278.1 136.3l1.3 1.9zM303.5 136.3l-1.3 1.9zM303.5 136.3l1.3 1.9zM58.9 147.8v5zM58.9 152.8h.8zM59.7 152.8h.8zM58.9 147.8h.8zM60.5 147.8v5z"/>
<path d="M59.7 147.8h.8zM61.5 152.8h.7zM61.5 147.8v5zM62.2 152.8h.8zM61.5 147.8h.7zM62.2 147.8h.8zM63 147.8v5zM64 147.8v5zM64 152.8h.8zM64 147.8h.8zM64.8 152.8h.7zM65.5 147.8v5z"/>
<path d="M64.8 147.8h.7zM66.5 147.8v5zM66.5 152.8h.8zM66.5 147.8h.8zM67.3 152.8h.8zM68.1 147.8v5zM67.3 147.8h.8zM69.1 147.8v5zM69.1 152.8h.7zM69.1 147.8h.7zM69.8 152.8h.8zM70.6 147.8v5z"/>
<path d="M69.8 147.8h.8zM71.6 147.8v5zM71.6 152.8h.8zM72.4 152.8h.8zM71.6 147.8h.8zM73.2 147.8v5zM72.4 147.8h.8zM74.2 152.8h.7zM74.2 147.8v5zM74.9 152.8h.8zM74.2 147.8h.7zM74.9 147.8h.8z"/>
<path d="M75.7 147.8v5zM76.7 147.8v5zM76.7 152.8h.8zM76.7 147.8h.8zM77.5 152.8h.7zM78.2 147.8v5zM77.5 147.8h.7zM84.3 147.8v5zM84.3 152.8h.8zM85.1 152.8h.8zM84.3 147.8h.8zM85.9 147.8v5z"/>
<path d="M85.1 147.8h.8zM86.9 152.8h.7zM86.9 147.8v5zM87.6 152.8h.8zM86.9 147.8h.7zM87.6 147.8h.8zM88.4 147.8v5zM89.4 147.8v5zM89.4 152.8h.8zM89.4 147.8h.8zM90.2 152.8h.7zM90.9 147.8v5z"/>
<path d="M90.2 147.8h.7zM91.9 147.8v5zM91.9 152.8h.8zM91.9 147.8h.8zM92.7 152.8h.8zM93.5 147.8v5zM92.7 147.8h.8zM94.5 147.8v5zM94.5 152.8h.7zM94.5 147.8h.7zM95.2 152.8h.8zM96 147.8v5z"/>
<path d="M95.2 147.8h.8zM97 147.8v5zM97 152.8h.8zM97.8 152.8h.8zM97 147.8h.8zM98.6 147.8v5zM97.8 147.8h.8zM99.6 152.8h.7zM99.6 147.8v5zM100.3 152.8h.8zM99.6 147.8h.7zM100.3 147.8h.8z"/>
<path d="M101.1 147.8v5zM102.1 147.8v5zM102.1 152.8h.8zM102.1 147.8h.8zM102.9 152.8h.7zM103.6 147.8v5zM102.9 147.8h.7zM223.7 140.4h15.5zM277.3 147.8v5zM277.3 152.8h.8zM278.1 152.8h.8zM277.3 147.8h.8z"/>
<path d="M278.9 147.8v5zM278.1 147.8h.8zM279.9 152.8h.7zM279.9 147.8v5zM280.6 152.8h.8zM279.9 147.8h.7zM280.6 147.8h.8zM281.4 147.8v5zM282.4 147.8v5zM282.4 152.8h.8zM282.4 147.8h.8zM283.2 152.8h.7z"/>
<path d="M283.9 147.8v5zM283.2 147.8h.7zM285 147.8v5zM285 152.8h.7zM285 147.8h.7zM285.7 152.8h.8zM286.5 147.8v5zM285.7 147.8h.8zM287.5 147.8v5zM287.5 152.8h.8zM287.5 147.8h.8zM288.3 152.8h.7z"/>
<path d="M289 147.8v5zM288.3 147.8h.7zM290 147.8v5zM290 152.8h.8zM290.8 152.8h.8zM290 147.8h.8zM291.6 147.8v5zM290.8 147.8h.8zM292.6 152.8h.7zM292.6 147.8v5zM293.3 152.8h.8zM292.6 147.8h.7z"/>
<path d="M293.3 147.8h.8zM294.1 147.8v5zM295.1 147.8v5zM295.1 152.8h.8zM295.1 147.8h.8zM295.9 152.8h.7zM296.6 147.8v5zM295.9 147.8h.7zM302.7 147.8v5zM302.7 152.8h.8zM303.5 152.8h.8zM302.7 147.8h.8z"/>
<path d="M304.3 147.8v5zM303.5 147.8h.8zM305.3 152.8h.7zM305.3 147.8v5zM306 152.8h.8zM305.3 147.8h.7zM306 147.8h.8zM306.8 147.8v5zM307.8 147.8v5zM307.8 152.8h.8zM307.8 147.8h.8zM308.6 152.8h.7z"/>
<path d="M309.3 147.8v5zM308.6 147.8h.7zM310.4 147.8v5zM310.4 152.8h.7zM310.4 147.8h.7zM311.1 152.8h.8zM311.9 147.8v5zM311.1 147.8h.8zM312.9 147.8v5zM312.9 152.8h.8zM312.9 147.8h.8zM313.7 152.8h.7z"/>
<path d="M314.4 147.8v5zM313.7 147.8h.7zM315.4 147.8v5zM315.4 152.8h.8zM316.2 152.8h.8zM315.4 147.8h.8zM317 147.8v5zM316.2 147.8h.8zM318 152.8h.7zM318 147.8v5zM318.7 152.8h.8zM318 147.8h.7z"/>
<path d="M318.7 147.8h.8zM319.5 147.8v5zM320.5 147.8v5zM320.5 152.8h.8zM320.5 147.8h.8zM321.3 152.8h.7zM322 147.8v5zM321.3 147.8h.7zM37.5 227.7h3.8zM120.6 231.3l-.7 .8zM119.9 232.1l.7 .7zM120.6 231.3l.8 .8z"/>
<path d="M121.4 232.1l-.8 .7zM192.4 232.8h3.8zM325.6 232.1l.8-.8zM325.6 232.1l.8 .7zM326.4 231.3l.7 .8zM327.1 232.1l-.7 .7zM97.8 243l-1.3 1.9zM97.8 243l1.3 1.9zM107.9 243l-1.2 1.9zM107.9 243l1.3 1.9zM313.7 249.3h86.3zM313.7 254.4h86.3z"/>
<path d="M313.7 259.5h58.4zM372.1 259.5h27.9zM372.1 259.5v5.1zM27.3 265.8h3.8zM106 265.8h3.9zM313.7 264.6h58.4zM313.7 269.7h86.3zM372.1 264.6h27.9zM400 268.4v1.3z"/>
</g>
<g fill="#000" stroke="#000" stroke-width=".21">
<path d="M67.8 18.2v3.9zM115.3 18.2v3.9zM162.7 18.2v3.9zM210.2 18.2v3.9zM257.6 18.2v3.9zM305.1 18.2v3.9zM352.5 18.2v3.9zM20.3 22.1v252.6zM20.3 22.1h379.7zM26.8 43.8h12.6zM28 59h11.4zM30.4 48.9h9z"/>
<path d="M31.4 54h8zM44.4 44.9h287zM44.4 50h284.5zM44.4 55.1h279.4zM323.8 55.1h45.7zM328.9 50h40.6zM331.4 44.9h38.1zM371 43.8h12.7zM371 48.9h9.1zM371 54h8.1zM371 59h11.5zM16.5 72.6h3.8z"/>
<path d="M31.3 64.1h8.1zM37.1 76.8h2.3zM37.6 71.7h1.8zM44.4 60.2h276.9zM44.4 65.2h271.8zM44.4 72.8h71.2zM44.4 77.9h66.1zM110.5 77.9h259zM110.5 77.9v58.4zM115.6 72.8h253.9zM316.2 65.2h53.3zM321.3 60.2h48.2z"/>
<path d="M371 64.1h8.2zM371 71.7h1.8zM371 76.8h2.4zM400 72.6h3.8zM54.6 88.1l2.5 2.5zM54.6 85.5l2.5 2.6zM54.6 90.6l2.5 2.6zM72.4 88.1h5.1zM72.4 90.6h5.1zM72.4 93.2h5.1zM57.1 90.6h15.3zM57.1 88.1h15.3z"/>
<path d="M57.1 93.2h15.3zM97.2 98.2h3.1zM97.2 95.7h3.1zM97.2 93.2h3.1zM97.2 90.6h3.1zM97.2 88.1h3.1zM100.3 88.1h5.1zM105.4 88.1v20.3zM120.6 88.1l2.6 2.5zM120.6 90.6l2.6 2.6zM120.6 93.2l2.6 2.5zM133.3 83v2.5z"/>
<path d="M135.9 90.6h5zM135.9 93.2h5zM135.9 95.7h5zM123.2 90.6h12.7zM123.2 93.2h12.7zM123.2 95.7h12.7zM160.7 98.2h3.1zM160.7 95.7h3.1zM160.7 93.2h3.1zM160.7 90.6h3.1zM163.8 90.6h142.2zM163.8 93.2h30.5z"/>
<path d="M194.3 93.2v63.5zM306 90.6v17.8zM313.7 88.1v5.1zM313.7 83v2.5zM313.7 85.5v2.6zM316.2 88.1v5.1zM316.2 65.2v22.9zM321.3 88.1v5.1zM321.3 60.2v27.9zM323.8 88.1v5.1zM323.8 55.1v33zM31.8 104.7h10.2z"/>
<path d="M47 105.9h25.4zM54.6 100.8l2.5 2.5zM54.6 98.2l2.5 2.6zM72.4 103.3h3.1zM72.4 105.9h3.1zM72.4 100.8h5.1zM57.1 103.3h15.3zM57.1 100.8h15.3zM97.2 105.9h3.1zM97.2 103.3h3.1zM97.2 100.8h3.1zM105.4 108.4v30.5z"/>
<path d="M115.6 72.8v33.1zM125.7 103.8h1.8zM133.3 85.5v17.8zM133.3 103.3v30.5zM135.9 105.9h3.1zM135.9 108.4h3.1zM135.9 103.3h5zM133.3 103.3h2.6zM115.6 105.9h20.3zM105.4 108.4h30.5zM160.7 108.4h3.1zM160.7 105.9h3.1z"/>
<path d="M160.7 103.3h3.1zM160.7 100.8h3.1zM306 108.4h15.3zM318.7 98.2v5.1zM318.7 103.3v2.6zM321.3 110.9v5.1zM321.3 108.4v2.5zM323.8 110.9v5.1zM323.8 105.9v5zM318.7 105.9h5.1zM328.9 110.9v5.1zM328.9 50v60.9z"/>
<path d="M331.4 110.9v5.1zM331.4 44.9v66zM16.5 123.1h3.8zM59.7 136.3v2.6zM59.7 138.9v2.5zM85.1 136.3v2.6zM85.1 138.9v2.5zM105.4 138.9h30.5zM110.5 136.3h25.4zM120.6 118.6l2.6 2.5zM120.6 121.1l2.6 2.5zM120.6 123.6l2.6 2.6z"/>
<path d="M125.7 134.3h2.4zM133.3 133.8h2.6zM135.9 121.1h5zM135.9 123.6h5zM135.9 126.2h5zM135.9 136.3h3.1zM135.9 138.9h3.1zM135.9 133.8h5zM123.2 121.1h12.7zM123.2 123.6h12.7zM123.2 126.2h12.7zM160.7 138.9h3.1z"/>
<path d="M160.7 136.3h3.1zM160.7 133.8h3.1zM160.7 131.3h3.1zM160.7 128.7h3.1zM160.7 126.2h3.1zM160.7 123.6h3.1zM160.7 121.1h3.1zM163.8 126.2h25.4zM163.8 138.9h58.4zM223.7 137.8h9.6zM278.1 136.3v2.6zM278.1 138.9v2.5z"/>
<path d="M303.5 136.3v2.6zM303.5 138.9v2.5zM326.4 121.1v5.1zM326.4 126.2v60.9zM400 123.1h3.8zM59.7 141.4v2.6zM59.7 154.1v2.6zM59.7 152.8v1.3zM59.7 146.5v1.3zM59.7 146.5h2.5zM59.7 144v2.5zM59.7 156.7v7.6z"/>
<path d="M62.2 154.1v2.6zM62.2 146.5v1.3zM62.2 146.5h2.6zM62.2 152.8v1.3zM62.2 156.7v10.1zM64.8 154.1v2.6zM64.8 146.5v1.3zM64.8 146.5h2.5zM64.8 152.8v1.3zM64.8 156.7v12.7zM67.3 154.1v2.6zM67.3 146.5v1.3z"/>
<path d="M67.3 146.5h2.5zM67.3 152.8v1.3zM67.3 156.7v15.2zM69.8 154.1v2.6zM69.8 146.5v1.3zM69.8 152.8v1.3zM69.8 146.5h2.6zM69.8 156.7v17.7zM72.4 154.1v2.6zM72.4 152.8v1.3zM72.4 146.5v1.3zM72.4 146.5h2.5z"/>
<path d="M72.4 156.7v20.3zM74.9 154.1v2.6zM74.9 146.5v1.3zM74.9 146.5h2.6zM74.9 152.8v1.3zM74.9 156.7v22.8zM77.5 154.1v2.6zM77.5 146.5v1.3zM77.5 152.8v1.3zM77.5 156.7v25.4zM85.1 141.4v2.6zM85.1 154.1v2.6z"/>
<path d="M85.1 152.8v1.3zM85.1 146.5v1.3zM85.1 146.5h2.5zM85.1 144v2.5zM85.1 156.7v45.7zM87.6 154.1v2.6zM87.6 146.5v1.3zM87.6 146.5h2.6zM87.6 152.8v1.3zM87.6 156.7v48.2zM90.2 154.1v2.6zM90.2 146.5v1.3z"/>
<path d="M90.2 146.5h2.5zM90.2 152.8v1.3zM90.2 156.7v50.7zM92.7 154.1v2.6zM92.7 146.5v1.3zM92.7 146.5h2.5zM92.7 152.8v1.3zM92.7 156.7v53.3zM95.2 154.1v2.6zM95.2 146.5v1.3zM95.2 152.8v1.3zM95.2 146.5h2.6z"/>
<path d="M95.2 156.7v55.8zM97.8 154.1v2.6zM97.8 152.8v1.3zM97.8 146.5v1.3zM97.8 146.5h2.5zM97.8 156.7v58.3zM100.3 154.1v2.6zM100.3 146.5v1.3zM100.3 146.5h2.6zM100.3 152.8v1.3zM100.3 156.7v60.9zM102.9 154.1v2.6z"/>
<path d="M102.9 146.5v1.3zM102.9 152.8v1.3zM102.9 156.7v63.4zM120.6 156.7h73.7zM278.1 141.4v2.6zM278.1 154.1v2.6zM278.1 152.8v1.3zM278.1 146.5v1.3zM278.1 146.5h2.5zM278.1 144v2.5zM278.1 156.7v7.6zM280.6 154.1v2.6z"/>
<path d="M280.6 146.5v1.3zM280.6 146.5h2.6zM280.6 152.8v1.3zM280.6 156.7v10.1zM283.2 154.1v2.6zM283.2 146.5v1.3zM283.2 146.5h2.5zM283.2 152.8v1.3zM283.2 156.7v12.7zM285.7 154.1v2.6zM285.7 146.5v1.3zM285.7 146.5h2.6z"/>
<path d="M285.7 152.8v1.3zM285.7 156.7v15.2zM288.3 154.1v2.6zM288.3 146.5v1.3zM288.3 152.8v1.3zM288.3 146.5h2.5zM288.3 156.7v17.7zM290.8 154.1v2.6zM290.8 152.8v1.3zM290.8 146.5v1.3zM290.8 146.5h2.5zM290.8 156.7v20.3z"/>
<path d="M293.3 154.1v2.6zM293.3 146.5v1.3zM293.3 146.5h2.6zM293.3 152.8v1.3zM293.3 156.7v22.8zM295.9 154.1v2.6zM295.9 146.5v1.3zM295.9 152.8v1.3zM295.9 156.7v25.4zM303.5 141.4v2.6zM303.5 154.1v2.6zM303.5 152.8v1.3z"/>
<path d="M303.5 146.5v1.3zM303.5 146.5h2.5zM303.5 144v2.5zM303.5 156.7v45.7zM306 154.1v2.6zM306 146.5v1.3zM306 146.5h2.6zM306 152.8v1.3zM306 156.7v48.2zM308.6 154.1v2.6zM308.6 146.5v1.3zM308.6 146.5h2.5z"/>
<path d="M308.6 152.8v1.3zM308.6 156.7v50.7zM311.1 154.1v2.6zM311.1 146.5v1.3zM311.1 146.5h2.6zM311.1 152.8v1.3zM311.1 156.7v53.3zM313.7 154.1v2.6zM313.7 146.5v1.3zM313.7 152.8v1.3zM313.7 146.5h2.5zM313.7 156.7v55.8z"/>
<path d="M316.2 154.1v2.6zM316.2 152.8v1.3zM316.2 146.5v1.3zM316.2 146.5h2.5zM316.2 156.7v58.3zM318.7 154.1v2.6zM318.7 146.5v1.3zM318.7 146.5h2.6zM318.7 152.8v1.3zM318.7 156.7v60.9zM321.3 154.1v2.6zM321.3 146.5v1.3z"/>
<path d="M321.3 152.8v1.3zM321.3 156.7v63.4zM16.5 173.7h3.8zM39.4 164.3v2.5zM39.4 166.8v2.6zM39.4 169.4v2.5zM39.4 171.9v2.5zM39.4 174.4v2.6zM39.4 177v2.5zM39.4 179.5v2.6zM41.9 164.3h2.5zM41.9 166.8h2.5z"/>
<path d="M41.9 169.4h2.5zM41.9 171.9h2.5zM41.9 174.4h2.5zM41.9 177h2.5zM41.9 179.5h2.5zM39.4 164.3h2.5zM39.4 166.8h2.5zM39.4 169.4h2.5zM39.4 171.9h2.5zM39.4 174.4h2.5zM39.4 177h2.5zM39.4 179.5h2.5z"/>
<path d="M46.2 179h3.3zM46.2 176.5v1zM46.2 176.5h3.3zM46.2 173.9v1zM46.2 173.9h3.3zM46.2 171.4v1zM46.2 171.4h3.3zM46.2 168.8v1.1zM46.2 168.8h3.3zM46.2 166.3v1zM46.2 166.3h3.3zM46.2 163.8v1z"/>
<path d="M46.2 163.8h3.3zM47.6 179.8h.5zM47.6 179.3h.5zM47.6 177.2h.5zM47.6 176.7h.5zM47.6 174.7h.5zM47.6 174.2h.5zM47.6 172.1h.5zM47.6 171.6h.5zM47.6 169.6h.5zM47.6 169.1h.5zM47.6 167.1h.5z"/>
<path d="M47.6 166.6h.5zM47.6 164.5h.5zM47.6 164h.5zM49.5 179h3.3zM49.5 176.5v1zM46.2 177.5h3.3zM49.5 176.5h3.3zM49.5 173.9v1zM46.2 174.9h3.3zM49.5 173.9h3.3zM49.5 171.4v1zM46.2 172.4h3.3z"/>
<path d="M49.5 171.4h3.3zM49.5 168.8v1.1zM46.2 169.9h3.3zM49.5 168.8h3.3zM49.5 166.3v1zM46.2 167.3h3.3zM49.5 166.3h3.3zM49.5 163.8v1zM46.2 164.8h3.3zM49.5 163.8h3.3zM52.8 179v1zM49.5 177.5h3.3z"/>
<path d="M52.8 176.5v1zM49.5 174.9h3.3zM52.8 173.9v1zM49.5 172.4h3.3zM52.8 171.4v1zM49.5 169.9h3.3zM52.8 168.8v1.1zM49.5 167.3h3.3zM52.8 166.3v1zM49.5 164.8h3.3zM52.8 163.8v1zM54.6 179.5h2.5z"/>
<path d="M54.6 177h2.5zM54.6 174.4h2.5zM54.6 171.9h2.5zM54.6 169.4h2.5zM54.6 166.8h2.5zM54.6 164.3h2.5zM57.1 164.3h2.6zM57.1 166.8h5.1zM57.1 169.4h7.7zM57.1 171.9h10.2zM57.1 174.4h12.7zM57.1 177h15.3z"/>
<path d="M57.1 179.5h17.8zM59.7 164.3h63.5zM62.2 166.8h61zM64.8 169.4h58.4zM67.3 171.9h55.9zM69.8 174.4h53.4zM72.4 177h50.8zM74.9 179.5h48.3zM123.2 164.3h5zM123.2 166.8h5zM123.2 169.4h5zM123.2 171.9h5z"/>
<path d="M123.2 174.4h5zM123.2 177h5zM123.2 179.5h5zM143.5 179.5h5.1zM143.5 177h5.1zM143.5 174.4h5.1zM143.5 171.9h5.1zM143.5 169.4h5.1zM143.5 166.8h5.1zM143.5 164.3h5.1zM148.6 164.3h17.7zM148.6 166.8h17.7z"/>
<path d="M148.6 169.4h17.7zM148.6 171.9h17.7zM148.6 177h17.7zM148.6 179.5h17.7zM148.6 174.4h17.7zM168.9 166.8l2.5-2.5zM166.3 164.3l2.6 2.5zM168.9 169.4l2.5-2.6zM166.3 166.8l2.6 2.6zM168.9 171.9l2.5-2.5zM166.3 169.4l2.6 2.5zM168.9 174.4l2.5-2.5z"/>
<path d="M166.3 171.9l2.6 2.5zM168.9 179.5l2.5-2.5zM166.3 177l2.6 2.5zM168.9 177l2.5-2.6zM166.3 174.4l2.6 2.6zM171.4 164.3h25.4zM171.4 166.8h25.4zM171.4 169.4h25.4zM171.4 171.9h25.4zM171.4 177h25.4zM171.4 179.5h25.4zM171.4 174.4h25.4z"/>
<path d="M196.8 164.3h5.1zM196.8 166.8h5.1zM196.8 169.4h5.1zM196.8 171.9h5.1zM196.8 174.4h5.1zM196.8 177h5.1zM196.8 179.5h5.1zM217.1 179.5h5.1zM217.1 177h5.1zM217.1 174.4h5.1zM217.1 171.9h5.1zM217.1 169.4h5.1z"/>
<path d="M217.1 166.8h5.1zM217.1 164.3h5.1zM227.3 164.3h2.5zM227.3 166.8h2.5zM227.3 169.4h2.5zM227.3 171.9h2.5zM227.3 174.4h2.5zM227.3 177h2.5zM227.3 179.5h2.5zM222.2 164.3h5.1zM222.2 166.8h5.1zM222.2 169.4h5.1z"/>
<path d="M222.2 171.9h5.1zM222.2 174.4h5.1zM222.2 177h5.1zM222.2 179.5h5.1zM273 164.3h2.6zM273 166.8h2.6zM273 169.4h2.6zM273 171.9h2.6zM273 174.4h2.6zM273 177h2.6zM273 179.5h2.6zM275.6 164.3h2.5z"/>
<path d="M275.6 166.8h5zM275.6 169.4h7.6zM275.6 171.9h10.1zM275.6 174.4h12.7zM275.6 177h15.2zM275.6 179.5h17.7zM278.1 164.3h50.8zM280.6 166.8h48.3zM283.2 169.4h45.7zM285.7 171.9h43.2zM288.3 174.4h40.6zM290.8 177h38.1z"/>
<path d="M293.3 179.5h35.6zM328.9 164.3h5.1zM328.9 166.8h5.1zM328.9 169.4h5.1zM328.9 171.9h5.1zM328.9 174.4h5.1zM328.9 177h5.1zM328.9 179.5h5.1zM349.2 179.5h5.1zM349.2 177h5.1zM349.2 174.4h5.1zM349.2 171.9h5.1z"/>
<path d="M349.2 169.4h5.1zM349.2 166.8h5.1zM349.2 164.3h5.1zM354.3 164.3h17.8zM354.3 166.8h17.8zM354.3 169.4h17.8zM354.3 171.9h17.8zM354.3 177h17.8zM354.3 179.5h17.8zM354.3 174.4h17.8zM372.1 164.3l2.5 2.5zM372.1 166.8l2.5 2.6z"/>
<path d="M372.1 169.4l2.5 2.5zM372.1 171.9l2.5 2.5zM372.1 177l2.5 2.5zM372.1 174.4l2.5 2.6zM400 173.7h3.8zM39.4 182.1v20.3zM41.9 182.1h2.5zM39.4 182.1h2.5zM46.2 181.5v1.1zM46.2 181.5h3.3zM46.2 179v1zM47.6 182.3h.5z"/>
<path d="M47.6 181.8h.5zM49.5 181.5v1.1zM46.2 182.6h3.3zM49.5 181.5h3.3zM49.5 179v1zM46.2 180h3.3zM49.5 182.6h3.3zM52.8 181.5v1.1zM49.5 180h3.3zM54.6 182.1h2.5zM57.1 182.1h20.4zM77.5 182.1h45.7z"/>
<path d="M120.6 187.1v2.6zM120.6 156.7v30.4zM123.2 187.1h3.1zM123.2 182.1h5zM123.2 189.7h3.1zM120.6 187.1h2.6zM120.6 189.7h2.6zM143.5 182.1h5.1zM148.6 182.1h17.7zM171.4 179.5l-2.5 2.6zM166.3 179.5l2.6 2.6zM168.9 184.6l2.5-2.5z"/>
<path d="M166.3 182.1l2.6 2.5zM171.4 182.1h25.4zM189.2 187.1h7.6zM189.2 126.2v60.9zM189.2 187.1v38.1zM194.3 189.7h2.5zM194.3 189.7v38zM196.8 189.7h3.1zM196.8 182.1h5.1zM196.8 187.1h5.1zM201.9 186.1l2 1zM201.9 188.1l2-1z"/>
<path d="M217.1 182.1h5.1zM227.3 182.1h2.5zM222.2 182.1h5.1zM273 182.1h2.6zM275.6 182.1h20.3zM295.9 182.1h33zM326.4 187.1v2.6zM328.9 187.1h3.1zM328.9 182.1h5.1zM328.9 189.7h3.1zM326.4 187.1h2.5zM326.4 189.7h2.5z"/>
<path d="M349.2 182.1h5.1zM354.3 182.1h17.8zM372.1 179.5l2.5 2.6zM372.1 182.1l2.5 2.5zM39.4 202.4v2.5zM39.4 204.9v2.5zM39.4 207.4v2.6zM39.4 210v2.5zM39.4 212.5v2.5zM39.4 215v2.6zM39.4 217.6v2.5zM41.9 202.4h2.5z"/>
<path d="M41.9 204.9h2.5zM41.9 207.4h2.5zM41.9 210h2.5zM41.9 212.5h2.5zM41.9 215h2.5zM41.9 217.6h2.5zM39.4 202.4h2.5zM39.4 204.9h2.5zM39.4 207.4h2.5zM39.4 210h2.5zM39.4 212.5h2.5zM39.4 215h2.5z"/>
<path d="M39.4 217.6h2.5zM46.2 219.6h3.3zM46.2 217.1v1zM46.2 217.1h3.3zM46.2 214.5v1.1zM46.2 214.5h3.3zM46.2 212v1zM46.2 212h3.3zM46.2 209.5v1zM46.2 209.5h3.3zM46.2 206.9v1zM46.2 206.9h3.3z"/>
<path d="M46.2 204.4v1zM46.2 204.4h3.3zM46.2 201.9v1zM46.2 201.9h3.3zM47.6 219.9h.5zM47.6 217.8h.5zM47.6 217.3h.5zM47.6 215.3h.5zM47.6 214.8h.5zM47.6 212.8h.5zM47.6 212.3h.5zM47.6 210.2h.5z"/>
<path d="M47.6 209.7h.5zM47.6 207.7h.5zM47.6 207.2h.5zM47.6 205.2h.5zM47.6 204.7h.5zM47.6 202.6h.5zM47.6 202.1h.5zM49.5 219.6h3.3zM49.5 217.1v1zM46.2 218.1h3.3zM49.5 217.1h3.3zM49.5 214.5v1.1z"/>
<path d="M46.2 215.6h3.3zM49.5 214.5h3.3zM49.5 212v1zM46.2 213h3.3zM49.5 212h3.3zM49.5 209.5v1zM46.2 210.5h3.3zM49.5 209.5h3.3zM49.5 206.9v1zM46.2 207.9h3.3zM49.5 206.9h3.3zM49.5 204.4v1z"/>
<path d="M46.2 205.4h3.3zM49.5 204.4h3.3zM49.5 201.9v1zM46.2 202.9h3.3zM49.5 201.9h3.3zM52.8 219.6v1zM49.5 218.1h3.3zM52.8 217.1v1zM49.5 215.6h3.3zM52.8 214.5v1.1zM49.5 213h3.3zM52.8 212v1z"/>
<path d="M49.5 210.5h3.3zM52.8 209.5v1zM49.5 207.9h3.3zM52.8 206.9v1zM49.5 205.4h3.3zM52.8 204.4v1zM49.5 202.9h3.3zM52.8 201.9v1zM54.6 217.6h2.5zM54.6 215h2.5zM54.6 212.5h2.5zM54.6 210h2.5z"/>
<path d="M54.6 207.4h2.5zM54.6 204.9h2.5zM54.6 202.4h2.5zM57.1 202.4h28zM57.1 204.9h30.5zM57.1 207.4h33.1zM57.1 210h35.6zM57.1 212.5h38.1zM57.1 215h40.7zM57.1 217.6h43.2zM85.1 202.4h38.1zM87.6 204.9h35.6z"/>
<path d="M90.2 207.4h33zM92.7 210h30.5zM95.2 212.5h28zM97.8 215h25.4zM100.3 217.6h22.9zM123.2 202.4h5zM123.2 204.9h5zM123.2 207.4h5zM123.2 210h5zM123.2 212.5h5zM123.2 215h5zM123.2 217.6h5z"/>
<path d="M143.5 217.6h5.1zM143.5 215h5.1zM143.5 212.5h5.1zM143.5 210h5.1zM143.5 207.4h5.1zM143.5 204.9h5.1zM143.5 202.4h5.1zM148.6 202.4h17.7zM148.6 204.9h17.7zM148.6 207.4h17.7zM148.6 210h17.7zM148.6 212.5h17.7z"/>
<path d="M148.6 215h17.7zM148.6 217.6h17.7zM171.4 202.4l-2.5 2.5zM166.3 202.4l2.6 2.5zM168.9 207.4l2.5-2.5zM166.3 204.9l2.6 2.5zM168.9 210l2.5-2.6zM166.3 207.4l2.6 2.6zM168.9 212.5l2.5-2.5zM166.3 210l2.6 2.5zM168.9 215l2.5-2.5zM166.3 212.5l2.6 2.5z"/>
<path d="M168.9 217.6l2.5-2.6zM166.3 215l2.6 2.6zM171.4 202.4h25.4zM171.4 204.9h25.4zM171.4 207.4h25.4zM171.4 210h25.4zM171.4 212.5h25.4zM171.4 215h25.4zM171.4 217.6h25.4zM196.8 202.4h5.1zM196.8 204.9h5.1zM196.8 207.4h5.1z"/>
<path d="M196.8 210h5.1zM196.8 212.5h5.1zM196.8 215h5.1zM196.8 217.6h5.1zM217.1 217.6h5.1zM217.1 215h5.1zM217.1 212.5h5.1zM217.1 210h5.1zM217.1 207.4h5.1zM217.1 204.9h5.1zM217.1 202.4h5.1zM227.3 202.4h2.5z"/>
<path d="M227.3 204.9h2.5zM227.3 207.4h2.5zM227.3 210h2.5zM227.3 212.5h2.5zM227.3 215h2.5zM227.3 217.6h2.5zM222.2 202.4h5.1zM222.2 204.9h5.1zM222.2 207.4h5.1zM222.2 210h5.1zM222.2 212.5h5.1zM222.2 215h5.1z"/>
<path d="M222.2 217.6h5.1zM273 202.4h2.6zM273 204.9h2.6zM273 207.4h2.6zM273 210h2.6zM273 212.5h2.6zM273 215h2.6zM273 217.6h2.6zM275.6 202.4h27.9zM275.6 204.9h30.4zM275.6 207.4h33zM275.6 210h35.5z"/>
<path d="M275.6 212.5h38.1zM275.6 215h40.6zM275.6 217.6h43.1zM303.5 202.4h25.4zM306 204.9h22.9zM308.6 207.4h20.3zM311.1 210h17.8zM313.7 212.5h15.2zM316.2 215h12.7zM318.7 217.6h10.2zM328.9 202.4h5.1zM328.9 204.9h5.1z"/>
<path d="M328.9 207.4h5.1zM328.9 210h5.1zM328.9 212.5h5.1zM328.9 215h5.1zM328.9 217.6h5.1zM349.2 217.6h5.1zM349.2 215h5.1zM349.2 212.5h5.1zM349.2 210h5.1zM349.2 207.4h5.1zM349.2 204.9h5.1zM349.2 202.4h5.1z"/>
<path d="M354.3 202.4h17.8zM354.3 204.9h17.8zM354.3 207.4h17.8zM354.3 210h17.8zM354.3 212.5h17.8zM354.3 215h17.8zM354.3 217.6h17.8zM372.1 202.4l2.5 2.5zM372.1 204.9l2.5 2.5zM372.1 207.4l2.5 2.6zM372.1 210l2.5 2.5zM372.1 212.5l2.5 2.5z"/>
<path d="M372.1 215l2.5 2.6zM16.5 224.2h3.8zM39.4 225.2v2.5zM39.4 220.1v5.1zM41.9 220.1h2.5zM39.4 220.1h2.5zM46.2 219.6v1zM47.6 220.4h.5zM49.5 219.6v1zM46.2 220.6h3.3zM49.5 220.6h3.3zM54.6 220.1h2.5z"/>
<path d="M57.1 220.1h45.8zM102.9 220.1h20.3zM120.6 230.3v2.5zM120.6 227.7v2.6zM120.6 225.2v2.5zM120.6 189.7v35.5zM123.2 225.2h3.1zM123.2 220.1h5zM123.2 227.7h3.1zM120.6 225.2h2.6zM120.6 227.7h2.6zM143.5 220.1h5.1z"/>
<path d="M148.6 220.1h17.7zM168.9 220.1l2.5-2.5zM166.3 217.6l2.6 2.5zM168.9 222.7l2.5-2.6zM166.3 220.1l2.6 2.6zM171.4 220.1h25.4zM189.2 225.2h7.6zM194.3 230.3v2.5zM194.3 227.7h2.5zM194.3 227.7v2.6zM196.8 227.7h3.1zM196.8 220.1h5.1z"/>
<path d="M196.8 225.2h5.1zM201.9 224.2l2 1zM201.9 226.2l2-1zM217.1 220.1h5.1zM227.3 220.1h2.5zM222.2 220.1h5.1zM273 220.1h2.6zM275.6 220.1h45.7zM321.3 220.1h7.6zM326.4 230.3v2.5zM326.4 189.7v35.5zM326.4 225.2v2.5z"/>
<path d="M326.4 227.7h2.5zM326.4 227.7v2.6zM328.9 225.2h3.1zM328.9 220.1h5.1zM328.9 227.7h3.1zM326.4 225.2h2.5zM349.2 220.1h5.1zM354.3 220.1h17.8zM372.1 217.6l2.5 2.5zM372.1 220.1l2.5 2.6zM400 224.2h3.8zM29.2 255.7v2.5z"/>
<path d="M29.2 250.6v2.5zM29.2 255.2v.5zM29.2 253.1v.6zM29.2 248.1v2.5zM29.2 258.2v2.6zM36.8 255.7v2.5zM36.8 250.6v2.5zM36.8 255.2v.5zM36.8 253.1v.6zM36.8 248.1v2.5zM29.2 248.1h7.6zM44.4 255.7v2.5z"/>
<path d="M44.4 250.6v2.5zM44.4 255.2v.5zM44.4 253.1v.6zM36.8 248.1h7.6zM44.4 248.1v2.5zM52.1 255.7v2.5zM52.1 250.6v2.5zM52.1 255.2v.5zM52.1 253.1v.6zM44.4 248.1h7.7zM52.1 248.1v2.5zM59.7 255.7v2.5z"/>
<path d="M59.7 250.6v2.5zM59.7 255.2v.5zM59.7 253.1v.6zM52.1 248.1h7.6zM59.7 248.1v2.5zM67.3 255.7v2.5zM67.3 250.6v2.5zM67.3 255.2v.5zM67.3 253.1v.6zM59.7 248.1h7.6zM67.3 248.1v2.5zM67.3 258.2v2.6z"/>
<path d="M74.9 255.7v2.5zM74.9 250.6v2.5zM74.9 255.2v.5zM74.9 253.1v.6zM67.3 248.1h7.6zM74.9 248.1v2.5zM74.9 258.2v2.6zM82.5 255.7v2.5zM82.5 250.6v2.5zM82.5 255.2v.5zM82.5 253.1v.6zM74.9 248.1h7.6z"/>
<path d="M82.5 248.1v2.5zM82.5 258.2v2.6zM90.2 255.7v2.5zM90.2 250.6v2.5zM90.2 255.2v.5zM90.2 253.1v.6zM82.5 248.1h7.7zM90.2 248.1v2.5zM90.2 258.2v2.6zM97.8 243v2.5zM97.8 255.7v2.5zM97.8 250.6v2.5z"/>
<path d="M97.8 255.2v.5zM97.8 253.1v.6zM90.2 248.1h7.6zM97.8 245.5v2.6zM97.8 248.1v2.5zM107.9 243v2.5zM107.9 250.6v2.5zM107.9 255.7v2.5zM107.9 253.1v.6zM107.9 255.2v.5zM107.9 245.5v5.1zM20.3 274.7h379.7z"/>
<path d="M29.2 263.3v2.5zM29.2 260.8h7.6zM29.2 260.8v2.5zM36.8 258.2v2.6zM36.8 260.8h7.6zM44.4 258.2v2.6zM44.4 260.8h7.7zM52.1 258.2v2.6zM52.1 260.8h7.6zM59.7 258.2v2.6zM59.7 260.8h7.6zM67.8 274.7v3.8z"/>
<path d="M67.3 260.8h7.6zM74.9 260.8h7.6zM82.5 260.8h7.7zM90.2 260.8h7.6zM97.8 258.2v2.6zM107.9 263.3v2.5zM107.9 258.2v5.1zM115.3 274.7v3.8zM162.7 274.7v3.8zM210.2 274.7v3.8zM257.6 274.7v3.8zM305.1 274.7v3.8z"/>
<path d="M352.5 274.7v3.8zM400 264.5v.1zM400 268.4v6.2zM400 274.6h.1zM400 22.1v252.6z"/>
<circle cx="323.8" cy="55.1" r=".51"/>
<circle cx="328.9" cy="50" r=".51"/>
<circle cx="331.4" cy="44.9" r=".51"/>
<circle cx="110.5" cy="77.9" r=".51"/>
<circle cx="115.6" cy="72.8" r=".51"/>
<circle cx="316.2" cy="65.2" r=".51"/>
<circle cx="321.3" cy="60.2" r=".51"/>
<circle cx="105.4" cy="108.4" r=".51"/>
<circle cx="133.3" cy="103.3" r=".51"/>
<circle cx="39.4" cy="177" r=".51"/>
<circle cx="39.4" cy="169.4" r=".51"/>
<circle cx="39.4" cy="171.9" r=".51"/>
<circle cx="39.4" cy="174.4" r=".51"/>
<circle cx="39.4" cy="179.5" r=".51"/>
<circle cx="39.4" cy="166.8" r=".51"/>
<circle cx="59.7" cy="164.3" r=".51"/>
<circle cx="62.2" cy="166.8" r=".51"/>
<circle cx="64.8" cy="169.4" r=".51"/>
<circle cx="67.3" cy="171.9" r=".51"/>
<circle cx="69.8" cy="174.4" r=".51"/>
<circle cx="72.4" cy="177" r=".51"/>
<circle cx="74.9" cy="179.5" r=".51"/>
<circle cx="278.1" cy="164.3" r=".51"/>
<circle cx="280.6" cy="166.8" r=".51"/>
<circle cx="283.2" cy="169.4" r=".51"/>
<circle cx="285.7" cy="171.9" r=".51"/>
<circle cx="288.3" cy="174.4" r=".51"/>
<circle cx="290.8" cy="177" r=".51"/>
<circle cx="293.3" cy="179.5" r=".51"/>
<circle cx="39.4" cy="182.1" r=".51"/>
<circle cx="77.5" cy="182.1" r=".51"/>
<circle cx="120.6" cy="187.1" r=".51"/>
<circle cx="120.6" cy="189.7" r=".51"/>
<circle cx="189.2" cy="187.1" r=".51"/>
<circle cx="295.9" cy="182.1" r=".51"/>
<circle cx="326.4" cy="187.1" r=".51"/>
<circle cx="326.4" cy="189.7" r=".51"/>
<circle cx="39.4" cy="210" r=".51"/>
<circle cx="39.4" cy="202.4" r=".51"/>
<circle cx="39.4" cy="204.9" r=".51"/>
<circle cx="39.4" cy="207.4" r=".51"/>
<circle cx="39.4" cy="217.6" r=".51"/>
<circle cx="39.4" cy="215" r=".51"/>
<circle cx="39.4" cy="212.5" r=".51"/>
<circle cx="85.1" cy="202.4" r=".51"/>
<circle cx="87.6" cy="204.9" r=".51"/>
<circle cx="90.2" cy="207.4" r=".51"/>
<circle cx="92.7" cy="210" r=".51"/>
<circle cx="95.2" cy="212.5" r=".51"/>
<circle cx="97.8" cy="215" r=".51"/>
<circle cx="100.3" cy="217.6" r=".51"/>
<circle cx="303.5" cy="202.4" r=".51"/>
<circle cx="306" cy="204.9" r=".51"/>
<circle cx="308.6" cy="207.4" r=".51"/>
<circle cx="311.1" cy="210" r=".51"/>
<circle cx="313.7" cy="212.5" r=".51"/>
<circle cx="316.2" cy="215" r=".51"/>
<circle cx="318.7" cy="217.6" r=".51"/>
<circle cx="39.4" cy="220.1" r=".51"/>
<circle cx="102.9" cy="220.1" r=".51"/>
<circle cx="120.6" cy="225.2" r=".51"/>
<circle cx="120.6" cy="227.7" r=".51"/>
<circle cx="194.3" cy="227.7" r=".51"/>
<circle cx="321.3" cy="220.1" r=".51"/>
<circle cx="326.4" cy="227.7" r=".51"/>
<circle cx="326.4" cy="225.2" r=".51"/>
<circle cx="36.8" cy="248.1" r=".51"/>
<circle cx="44.4" cy="248.1" r=".51"/>
<circle cx="52.1" cy="248.1" r=".51"/>
<circle cx="59.7" cy="248.1" r=".51"/>
<circle cx="67.3" cy="248.1" r=".51"/>
<circle cx="74.9" cy="248.1" r=".51"/>
<circle cx="82.5" cy="248.1" r=".51"/>
<circle cx="90.2" cy="248.1" r=".51"/>
<circle cx="97.8" cy="248.1" r=".51"/>
<circle cx="29.2" cy="260.8" r=".51"/>
<circle cx="36.8" cy="260.8" r=".51"/>
<circle cx="44.4" cy="260.8" r=".51"/>
<circle cx="52.1" cy="260.8" r=".51"/>
<circle cx="59.7" cy="260.8" r=".51"/>
<circle cx="67.3" cy="260.8" r=".51"/>
<circle cx="74.9" cy="260.8" r=".51"/>
<circle cx="82.5" cy="260.8" r=".51"/>
<circle cx="90.2" cy="260.8" r=".51"/>
</g>
<g fill="#000" stroke="#000" stroke-width=".42">
<path d="M77.5 85.5v22.9zM77.5 85.5h17.7zM140.9 88.1v22.8zM140.9 88.1h17.8zM316.2 98.2h5.1zM311.1 93.2h15.3zM77.5 108.4h17.7zM95.2 85.5v22.9zM140.9 110.9h17.8zM140.9 118.6v22.8zM158.7 88.1v22.8zM140.9 118.6h17.8z"/>
<path d="M318.7 116h15.3zM323.8 121.1h5.1zM57.1 145.2v8.9zM57.1 145.2h22.9zM57.1 154.1h22.9zM80 145.2v8.9zM82.5 145.2v8.9zM82.5 145.2h22.9zM82.5 154.1h22.9zM105.4 145.2v8.9zM140.9 141.4h17.8zM158.7 118.6v22.8z"/>
<path d="M275.6 145.2v8.9zM275.6 145.2h22.8zM275.6 154.1h22.8zM298.4 145.2v8.9zM301 145.2v8.9zM301 145.2h22.8zM301 154.1h22.8zM323.8 145.2v8.9zM44.4 161.7v22.9zM44.4 161.7h10.2zM44.4 199.8v22.9zM44.4 184.6h10.2z"/>
<path d="M44.4 199.8h10.2zM54.6 161.7v22.9zM44.4 222.7h10.2zM54.6 199.8v22.9zM222.2 253.1v10.2zM222.2 253.1h55.9zM222.2 263.3v7.6zM222.2 270.9h55.9zM222.2 263.3h55.9zM278.1 263.3v7.6zM278.1 253.1v10.2z"/>
</g>
<g fill="none" stroke="#000" stroke-width=".42">
<path d="M311.1 93.2a5.1 5.1 0 0 0 5.1 5M326.4 93.2a5.1 5.1 0 0 1-5.1 5M318.7 116a5.1 5.1 0 0 0 5.1 5.1M334 116a5.1 5.1 0 0 1-5.1 5.1"/>
<circle cx="59.7" cy="146.5" r=".25"/>
<circle cx="62.2" cy="146.5" r=".25"/>
<circle cx="64.8" cy="146.5" r=".25"/>
<circle cx="67.3" cy="146.5" r=".25"/>
<circle cx="69.8" cy="146.5" r=".25"/>
<circle cx="72.4" cy="146.5" r=".25"/>
<circle cx="74.9" cy="146.5" r=".25"/>
<circle cx="85.1" cy="146.5" r=".25"/>
<circle cx="87.6" cy="146.5" r=".25"/>
<circle cx="90.2" cy="146.5" r=".25"/>
<circle cx="92.7" cy="146.5" r=".25"/>
<circle cx="95.2" cy="146.5" r=".25"/>
<circle cx="97.8" cy="146.5" r=".25"/>
<circle cx="100.3" cy="146.5" r=".25"/>
<circle cx="278.1" cy="146.5" r=".25"/>
<circle cx="280.6" cy="146.5" r=".25"/>
<circle cx="283.2" cy="146.5" r=".25"/>
<circle cx="285.7" cy="146.5" r=".25"/>
<circle cx="288.3" cy="146.5" r=".25"/>
<circle cx="290.8" cy="146.5" r=".25"/>
<circle cx="293.3" cy="146.5" r=".25"/>
<circle cx="303.5" cy="146.5" r=".25"/>
<circle cx="306" cy="146.5" r=".25"/>
<circle cx="308.6" cy="146.5" r=".25"/>
<circle cx="311.1" cy="146.5" r=".25"/>
<circle cx="313.7" cy="146.5" r=".25"/>
<circle cx="316.2" cy="146.5" r=".25"/>
<circle cx="318.7" cy="146.5" r=".25"/>
</g>
<g fill="none" stroke="#000" stroke-width=".21">
<circle cx="96.2" cy="95.7" r=".99"/>
<circle cx="96.2" cy="90.6" r=".99"/>
<circle cx="96.2" cy="93.2" r=".99"/>
<circle cx="96.2" cy="88.1" r=".99"/>
<circle cx="96.2" cy="98.2" r=".99"/>
<circle cx="159.7" cy="98.2" r=".99"/>
<circle cx="159.7" cy="90.6" r=".99"/>
<circle cx="159.7" cy="93.2" r=".99"/>
<circle cx="159.7" cy="95.7" r=".99"/>
<circle cx="76.5" cy="103.3" r=".99"/>
<circle cx="76.5" cy="105.9" r=".99"/>
<circle cx="96.2" cy="103.3" r=".99"/>
<circle cx="96.2" cy="100.8" r=".99"/>
<circle cx="96.2" cy="105.9" r=".99"/>
<circle cx="140" cy="105.9" r=".99"/>
<circle cx="140" cy="108.4" r=".99"/>
<circle cx="159.7" cy="108.4" r=".99"/>
<circle cx="159.7" cy="105.9" r=".99"/>
<circle cx="159.7" cy="100.8" r=".99"/>
<circle cx="159.7" cy="103.3" r=".99"/>
<circle cx="140" cy="136.3" r=".99"/>
<circle cx="140" cy="138.9" r=".99"/>
<circle cx="159.7" cy="136.3" r=".99"/>
<circle cx="159.7" cy="128.7" r=".99"/>
<circle cx="159.7" cy="138.9" r=".99"/>
<circle cx="159.7" cy="131.3" r=".99"/>
<circle cx="159.7" cy="126.2" r=".99"/>
<circle cx="159.7" cy="121.1" r=".99"/>
<circle cx="159.7" cy="123.6" r=".99"/>
<circle cx="159.7" cy="133.8" r=".99"/>
<circle cx="127.3" cy="187.1" r=".99"/>
<circle cx="127.3" cy="189.7" r=".99"/>
<circle cx="200.9" cy="189.7" r=".99"/>
<circle cx="333" cy="187.1" r="1"/>
<circle cx="333" cy="189.7" r="1"/>
<circle cx="127.3" cy="227.7" r=".99"/>
<circle cx="127.3" cy="225.2" r=".99"/>
<circle cx="200.9" cy="227.7" r=".99"/>
<circle cx="333" cy="227.7" r="1"/>
<circle cx="333" cy="225.2" r="1"/>
</g>
<g fill="#000" stroke="#000" stroke-width=".61">
<path d="M20.3 22.1v252.6zM20.3 22.1h379.7zM128.2 161.7v30.5zM128.2 161.7h15.3zM201.9 161.7v30.5zM201.9 161.7h15.2zM229.8 164.3h1.3zM229.8 166.8h1.3zM229.8 169.4h1.3zM229.8 171.9h1.3zM229.8 174.4h1.3zM229.8 177h1.3z"/>
<path d="M229.8 179.5h1.3zM271.8 164.3h1.2zM271.8 166.8h1.2zM271.8 169.4h1.2zM271.8 171.9h1.2zM271.8 174.4h1.2zM271.8 177h1.2zM271.8 179.5h1.2zM334 161.7v30.5zM334 161.7h15.2zM128.2 192.2h15.3zM128.2 199.8v30.5z"/>
<path d="M143.5 161.7v30.5zM128.2 199.8h15.3zM201.9 192.2h15.2zM201.9 199.8v30.5zM217.1 161.7v30.5zM201.9 199.8h15.2zM229.8 182.1h1.3zM271.8 182.1h1.2zM334 192.2h15.2zM334 199.8v30.5zM349.2 161.7v30.5zM334 199.8h15.2z"/>
<path d="M229.8 202.4h1.3zM229.8 204.9h1.3zM229.8 207.4h1.3zM229.8 210h1.3zM229.8 212.5h1.3zM229.8 215h1.3zM229.8 217.6h1.3zM271.8 202.4h1.2zM271.8 204.9h1.2zM271.8 207.4h1.2zM271.8 210h1.2zM271.8 212.5h1.2z"/>
<path d="M271.8 215h1.2zM271.8 217.6h1.2zM128.2 230.3h15.3zM143.5 199.8v30.5zM201.9 230.3h15.2zM217.1 199.8v30.5zM229.8 220.1h1.3zM271.8 220.1h1.2zM334 230.3h15.2zM349.2 199.8v30.5zM283.2 244.3v30.4zM313.7 254.4v5.1z"/>
<path d="M313.7 249.3v5.1zM313.7 244.3v5zM313.7 244.3h86.3zM283.2 244.3h30.5zM400 254.4v5.1zM400 249.3v5.1zM400 244.3v5zM400 22.1v222.2zM20.3 274.7h262.9zM283.2 274.7h30.5zM313.7 274.7h86.3zM313.7 269.7v5z"/>
<path d="M313.7 264.6v5.1zM313.7 259.5v5.1zM400 268.4v6.3zM400 264.6v3.8zM400 259.5v5.1z"/>
</g>
<g fill="#000" stroke="#000" stroke-width=".21">
<path d="M46.6 179.3h1v.5h-1zM46.6 176.7h1v.5h-1zM46.6 174.2h1v.5h-1zM46.6 171.6h1v.5h-1zM46.6 169.1h1v.5h-1zM46.6 166.6h1v.5h-1zM46.6 164h1v.5h-1zM48.1 179.3h1v.5h-1zM48.1 176.7h1v.5h-1zM48.1 174.2h1v.5h-1zM48.1 171.6h1v.5h-1zM48.1 169.1h1v.5h-1z"/>
<path d="M48.1 166.6h1v.5h-1zM48.1 164h1v.5h-1zM46.6 181.8h1v.5h-1zM48.1 181.8h1v.5h-1zM46.6 219.9h1v.5h-1zM46.6 217.3h1v.5h-1zM46.6 214.8h1v.5h-1zM46.6 212.3h1v.5h-1zM46.6 209.7h1v.5h-1zM46.6 207.2h1v.5h-1zM46.6 204.7h1v.5h-1zM46.6 202.1h1v.5h-1z"/>
<path d="M48.1 219.9h1v.5h-1zM48.1 217.3h1v.5h-1zM48.1 214.8h1v.5h-1zM48.1 212.3h1v.5h-1zM48.1 209.7h1v.5h-1zM48.1 207.2h1v.5h-1zM48.1 204.7h1v.5h-1zM48.1 202.1h1v.5h-1zM27.2 253.7h4v.5h-4zM27.2 254.7h4v.5h-4zM34.8 253.7h4.1v.5h-4.1zM34.8 254.7h4.1v.5h-4.1z"/>
<path d="M42.4 253.7h4.1v.5h-4.1zM42.4 254.7h4.1v.5h-4.1zM50 253.7h4.1v.5h-4.1zM50 254.7h4.1v.5h-4.1zM57.7 253.7h4v.5h-4zM57.7 254.7h4v.5h-4zM65.3 253.7h4v.5h-4zM65.3 254.7h4v.5h-4zM72.9 253.7h4.1v.5h-4.1zM72.9 254.7h4.1v.5h-4.1zM80.5 253.7h4.1v.5h-4.1zM80.5 254.7h4.1v.5h-4.1z"/>
<path d="M88.1 253.7h4.1v.5h-4.1zM88.1 254.7h4.1v.5h-4.1zM95.8 253.7h4v.5h-4zM95.8 254.7h4v.5h-4zM105.9 254.7h4.1v.5h-4.1zM105.9 253.7h4.1v.5h-4.1zM252.7 253.1h25.4v10.2h-25.4z"/>
</g>
<path d="M16.5 18.2v260.3zM16.5 18.2h387.3zM16.5 278.5h387.3zM403.8 18.2v260.3z" fill="#000" stroke="#000" stroke-width=".32"/>
<g fill="#000" stroke="#000" stroke-width=".76">
<path d="M44.4 32.2h7.7zM52.1 32.2h66zM52.1 32.2l2.5 2.6zM118.1 32.2h177.8zM118.1 32.2l2.5 2.6zM247.6 37.3l5.1 5.1zM44.4 37.3h251.5zM252.7 42.4v190.4zM54.6 34.8v66zM120.6 34.8v88.8zM168.9 166.8v66zM374.6 166.8v55.9z"/>
<path d="M168.9 232.8l5.1 5.1zM174 237.9h73.6zM247.6 237.9l5.1-5.1zM252.7 232.8l5.1 5.1zM257.8 237.9h111.7zM369.5 237.9l5.1-5.1zM374.6 222.7v10.1z"/>
</g>
<use href="#words"/>
</svg>
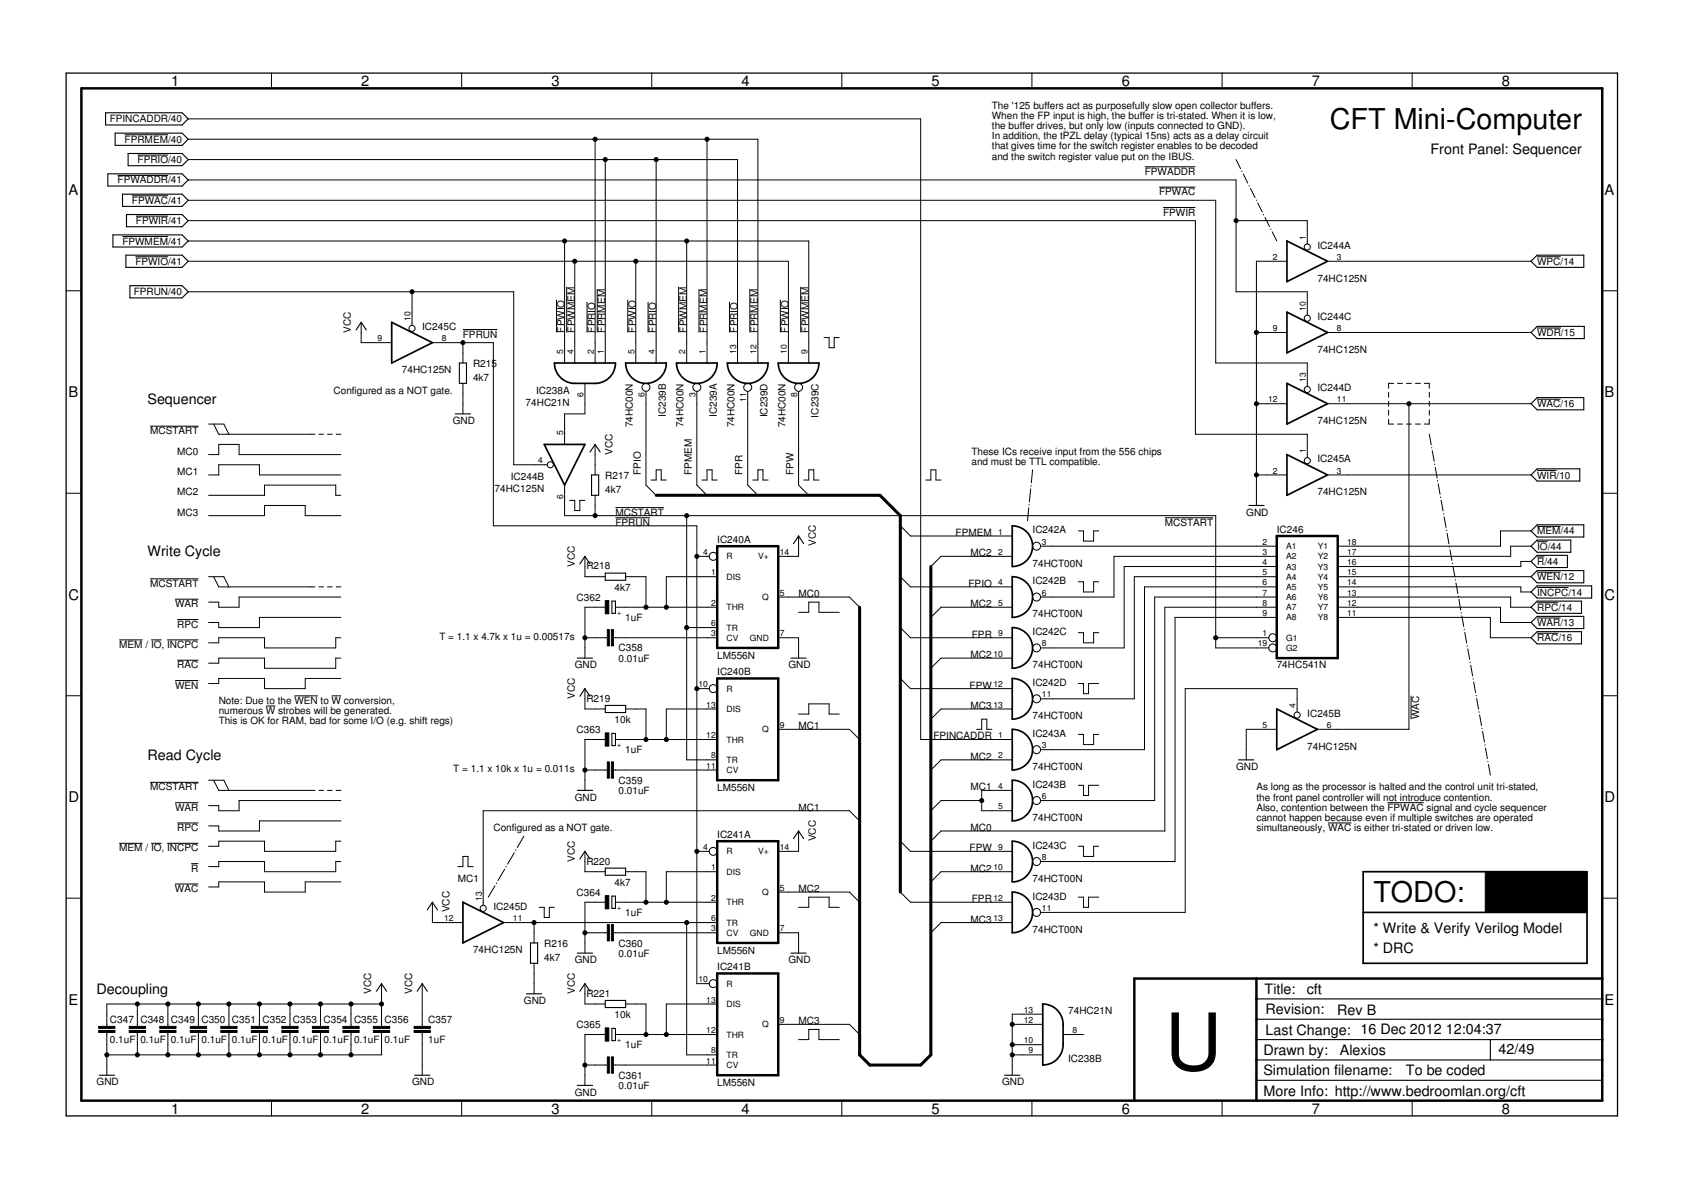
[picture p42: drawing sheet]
<svg xmlns="http://www.w3.org/2000/svg" width="420mm" height="297mm" viewBox="0 0 420 297" stroke-linecap="round" stroke-linejoin="round" font-family="sans-serif">
<defs><g id="words">
<text font-size="19.7" x="290.8" y="267.1">U</text>
<g font-size="7.2">
<text x="332" y="32.2">CFT Mini-Computer</text>
<text x="342.9" y="225.2">TODO:</text>
</g>
<g font-size="3.7">
<text x="42.7" y="21.5">1</text>
<text x="90.2" y="21.5">2</text>
<text x="137.7" y="21.5">3</text>
<text x="185.1" y="21.5">4</text>
<text x="232.6" y="21.5">5</text>
<text x="280" y="21.5">6</text>
<text x="327.5" y="21.5">7</text>
<text x="375" y="21.5">8</text>
<text x="17.1" y="48.6">A</text>
<text x="400.6" y="48.6">A</text>
<text x="17.1" y="99.2">B</text>
<text x="400.6" y="99.2">B</text>
<text x="17.1" y="149.7">C</text>
<text x="400.6" y="149.7">C</text>
<text x="17.1" y="200.2">D</text>
<text x="400.6" y="200.2">D</text>
<text x="17.1" y="250.8">E</text>
<text x="400.6" y="250.8">E</text>
<text x="42.7" y="277.9">1</text>
<text x="90.2" y="277.9">2</text>
<text x="137.7" y="277.9">3</text>
<text x="185.1" y="277.9">4</text>
<text x="232.6" y="277.9">5</text>
<text x="280" y="277.9">6</text>
<text x="327.5" y="277.9">7</text>
<text x="375" y="277.9">8</text>
</g>
<g font-size="3.6">
<text x="357.1" y="38.6">Front Panel: Sequencer</text>
<text x="36.8" y="100.8">Sequencer</text>
<text x="36.8" y="138.9">Write Cycle</text>
<text x="36.8" y="189.7">Read Cycle</text>
<text x="342.9" y="232.8">* Write &amp; Verify Verilog Model</text>
<text x="342.9" y="237.9">* DRC</text>
<text x="24.1" y="248.1">Decoupling</text>
<text x="315.7" y="248.1">Title:</text>
<text x="326.2" y="248.2">cft</text>
<text x="315.9" y="253.2">Revision:</text>
<text x="333.8" y="253.3">Rev B</text>
<text x="315.4" y="263.3">Drawn by:</text>
<text x="315.9" y="258.2">Last Change: 16 Dec 2012</text>
<text x="334.5" y="263.3">Alexios</text>
<text x="361" y="258.1">12:04:37</text>
<text x="374.1" y="263.2">42/49</text>
<text x="315.4" y="268.4">Simulation filename:</text>
<text x="351" y="268.4">To be coded</text>
<text x="315.4" y="273.5">More Info: http://www.bedroomlan.org/cft</text>
</g>
<g font-size="2.5">
<text x="247.6" y="27.1">The '125 buffers act as purposefully slow open collector buffers.</text>
<text x="247.6" y="29.7">When the FP input is high, the buffer is tri-stated. When it is low,</text>
<text x="27.4" y="30.6">FPINCADDR/40</text>
<text x="31.1" y="35.6">FPRMEM/40</text>
<text x="247.6" y="32.2">the buffer drives, but only low (inputs connected to GND).</text>
<text x="247.6" y="34.7">In addition, the tPZL delay (typical 15ns) acts as a delay circuit</text>
<text x="34.3" y="40.7">FPRIO/40</text>
<text x="247.6" y="37.3">that gives time for the switch register enables to be decoded</text>
<text x="247.6" y="39.8">and the switch register value put on the IBUS.</text>
<text x="29.4" y="45.8">FPWADDR/41</text>
<text x="285.8" y="43.6">FPWADDR</text>
<text x="32.9" y="50.9">FPWAC/41</text>
<text x="289.4" y="48.7">FPWAC</text>
<text x="290.4" y="53.8">FPWIR</text>
<text x="33.9" y="56">FPWIR/41</text>
<text x="30.6" y="61">FPWMEM/41</text>
<text x="328.9" y="62">IC244A</text>
<text x="33.8" y="66.1">FPWIO/41</text>
<text x="328.9" y="70.3">74HC125N</text>
<text x="383.7" y="66.1">WPC/14</text>
<text x="33.4" y="73.7">FPRUN/40</text>
<text x="87.6" y="83" transform="rotate(-90 87.6 83)">VCC</text>
<text x="105.4" y="82.4">IC245C</text>
<text x="141" y="83" transform="rotate(-90 141 83)">FPWIO</text>
<text x="143.5" y="83" transform="rotate(-90 143.5 83)">FPWMEM</text>
<text x="148.6" y="83" transform="rotate(-90 148.6 83)">FPRIO</text>
<text x="151.1" y="83" transform="rotate(-90 151.1 83)">FPRMEM</text>
<text x="158.7" y="83" transform="rotate(-90 158.7 83)">FPWIO</text>
<text x="163.8" y="83" transform="rotate(-90 163.8 83)">FPRIO</text>
<text x="171.4" y="83" transform="rotate(-90 171.4 83)">FPWMEM</text>
<text x="176.5" y="83" transform="rotate(-90 176.5 83)">FPRMEM</text>
<text x="184.1" y="83" transform="rotate(-90 184.1 83)">FPRIO</text>
<text x="189.2" y="83" transform="rotate(-90 189.2 83)">FPRMEM</text>
<text x="196.8" y="83" transform="rotate(-90 196.8 83)">FPWIO</text>
<text x="201.9" y="83" transform="rotate(-90 201.9 83)">FPWMEM</text>
<text x="328.9" y="79.8">IC244C</text>
<text x="383.7" y="83.9">WDR/15</text>
<text x="115.6" y="84.3">FPRUN</text>
<text x="328.9" y="88.1">74HC125N</text>
<text x="100.3" y="93.2">74HC125N</text>
<text x="118.1" y="95.2">4k7</text>
<text x="118.1" y="91.7">R215</text>
<text x="83.3" y="98.2">Configured as a NOT gate.</text>
<text x="131.2" y="101.4">74HC21N</text>
<text x="133.8" y="98.2">IC238A</text>
<text x="328.9" y="97.6">IC244D</text>
<text x="383.7" y="101.7">WAC/16</text>
<text x="113" y="105.9">GND</text>
<text x="158" y="106.7" transform="rotate(-90 158 106.7)">74HC00N</text>
<text x="166.2" y="104.1" transform="rotate(-90 166.2 104.1)">IC239B</text>
<text x="170.7" y="106.7" transform="rotate(-90 170.7 106.7)">74HC00N</text>
<text x="178.9" y="104.1" transform="rotate(-90 178.9 104.1)">IC239A</text>
<text x="183.4" y="106.7" transform="rotate(-90 183.4 106.7)">74HC00N</text>
<text x="191.6" y="104.2" transform="rotate(-90 191.6 104.2)">IC239D</text>
<text x="196.1" y="106.7" transform="rotate(-90 196.1 106.7)">74HC00N</text>
<text x="204.3" y="104.2" transform="rotate(-90 204.3 104.2)">IC239C</text>
<text x="328.9" y="105.9">74HC125N</text>
<text x="37.5" y="108.4">MCSTART</text>
<text x="44.2" y="113.5">MC0</text>
<text x="152.9" y="113.5" transform="rotate(-90 152.9 113.5)">VCC</text>
<text x="242.5" y="113.5">These ICs receive input from the 556 chips</text>
<text x="44.2" y="118.6">MC1</text>
<text x="127.5" y="119.7">IC244B</text>
<text x="151.1" y="119.6">R217</text>
<text x="160" y="118.6" transform="rotate(-90 160 118.6)">FPIO</text>
<text x="172.7" y="118.6" transform="rotate(-90 172.7 118.6)">FPMEM</text>
<text x="185.4" y="118.6" transform="rotate(-90 185.4 118.6)">FPR</text>
<text x="198.1" y="118.6" transform="rotate(-90 198.1 118.6)">FPW</text>
<text x="242.5" y="116">and must be TTL compatible.</text>
<text x="328.9" y="115.4">IC245A</text>
<text x="383.7" y="119.4">WIR/10</text>
<text x="44.2" y="123.6">MC2</text>
<text x="123.5" y="122.9">74HC125N</text>
<text x="151.1" y="123.1">4k7</text>
<text x="328.9" y="123.6">74HC125N</text>
<text x="44.2" y="128.7">MC3</text>
<text x="153.7" y="128.7">MCSTART</text>
<text x="153.7" y="131.3">FPRUN</text>
<text x="290.8" y="131.3">MCSTART</text>
<text x="311.1" y="128.7">GND</text>
<text x="179.1" y="135.6">IC240A</text>
<text x="203.7" y="136.3" transform="rotate(-90 203.7 136.3)">VCC</text>
<text x="238.6" y="133.8">FPMEM</text>
<text x="257.8" y="133.2">IC242A</text>
<text x="318.7" y="133.2">IC246</text>
<text x="383.7" y="137.2">IO/44</text>
<text x="383.7" y="133.4">MEM/44</text>
<text x="143.5" y="141.4" transform="rotate(-90 143.5 141.4)">VCC</text>
<text x="146.4" y="142.1">R218</text>
<text x="242.3" y="138.9">MC2</text>
<text x="257.8" y="141.4">74HCT00N</text>
<text x="383.7" y="141">R/44</text>
<text x="37.5" y="146.5">MCSTART</text>
<text x="153.4" y="147.5">4k7</text>
<text x="199.4" y="149">MC0</text>
<text x="241.8" y="146.5">FPIO</text>
<text x="257.8" y="145.9">IC242B</text>
<text x="383.7" y="148.6">INCPC/14</text>
<text x="383.7" y="144.8">WEN/12</text>
<text x="43.7" y="151.6">WAR</text>
<text x="144" y="150">C362</text>
<text x="156.1" y="154.9">1uF</text>
<text x="242.3" y="151.6">MC2</text>
<text x="257.8" y="154.1">74HCT00N</text>
<text x="383.7" y="152.5">RPC/14</text>
<text x="29.8" y="161.7">MEM / IO, INCPC</text>
<text x="44.2" y="156.6">RPC</text>
<text x="109.7" y="159.7">T = 1.1 x 4.7k x 1u = 0.00517s</text>
<text x="242.6" y="159.2">FPR</text>
<text x="257.8" y="158.6">IC242C</text>
<text x="383.7" y="156.3">WAR/13</text>
<text x="383.7" y="160.1">RAC/16</text>
<text x="44.2" y="166.8">RAC</text>
<text x="143.5" y="166.8">GND</text>
<text x="154.4" y="165.2">0.01uF</text>
<text x="154.4" y="162.6">C358</text>
<text x="179.1" y="164.4">LM556N</text>
<text x="196.8" y="166.8">GND</text>
<text x="242.3" y="164.3">MC2</text>
<text x="257.8" y="166.8">74HCT00N</text>
<text x="318.7" y="166.8">74HC541N</text>
<text x="43.7" y="171.9">WEN</text>
<text x="179.1" y="168.6">IC240B</text>
<text x="242.1" y="171.9">FPW</text>
<text x="257.8" y="171.3">IC242D</text>
<text x="54.6" y="175.7">Note: Due to the WEN to W conversion,</text>
<text x="54.6" y="178.2">numerous W strobes will be generated.</text>
<text x="143.5" y="174.4" transform="rotate(-90 143.5 174.4)">VCC</text>
<text x="146.4" y="175.2">R219</text>
<text x="242.3" y="177">MC3</text>
<text x="257.8" y="179.5">74HCT00N</text>
<text x="326.4" y="178.9">IC245B</text>
<text x="354.3" y="179.5" transform="rotate(-90 354.3 179.5)">WAC</text>
<text x="54.6" y="180.8">This is OK for RAM, bad for some I/O (e.g. shift regs)</text>
<text x="144" y="183">C363</text>
<text x="153.4" y="180.5">10k</text>
<text x="199.4" y="182">MC1</text>
<text x="233" y="184.6">FPINCADDR</text>
<text x="257.8" y="183.9">IC243A</text>
<text x="156.1" y="187.9">1uF</text>
<text x="242.3" y="189.7">MC2</text>
<text x="326.4" y="187.1">74HC125N</text>
<text x="37.5" y="197.3">MCSTART</text>
<text x="113.2" y="192.7">T = 1.1 x 10k x 1u = 0.011s</text>
<text x="154.4" y="195.6">C359</text>
<text x="179.1" y="197.4">LM556N</text>
<text x="242.3" y="197.3">MC1</text>
<text x="257.8" y="192.2">74HCT00N</text>
<text x="257.8" y="196.6">IC243B</text>
<text x="308.6" y="192.2">GND</text>
<text x="313.7" y="197.3">As long as the processor is halted and the control unit tri-stated,</text>
<text x="43.7" y="202.4">WAR</text>
<text x="143.5" y="199.8">GND</text>
<text x="154.4" y="198.2">0.01uF</text>
<text x="199.4" y="202.4">MC1</text>
<text x="313.7" y="199.8">the front panel controller will not introduce contention.</text>
<text x="313.7" y="202.4">Also, contention between the FPWAC signal and cycle sequencer</text>
<text x="44.2" y="207.4">RPC</text>
<text x="123.2" y="207.4">Configured as a NOT gate.</text>
<text x="179.1" y="209.2">IC241A</text>
<text x="203.7" y="210" transform="rotate(-90 203.7 210)">VCC</text>
<text x="242.3" y="207.4">MC0</text>
<text x="257.8" y="204.9">74HCT00N</text>
<text x="313.7" y="204.9">cannot happen because even if multiple switches are operated</text>
<text x="313.7" y="207.4">simultaneously, WAC is either tri-stated or driven low.</text>
<text x="29.8" y="212.5">MEM / IO, INCPC</text>
<text x="143.5" y="215.1" transform="rotate(-90 143.5 215.1)">VCC</text>
<text x="146.4" y="215.8">R220</text>
<text x="242.1" y="212.5">FPW</text>
<text x="257.8" y="211.9">IC243C</text>
<text x="47.7" y="217.6">R</text>
<text x="114.3" y="220.1">MC1</text>
<text x="153.4" y="221.2">4k7</text>
<text x="242.3" y="217.6">MC2</text>
<text x="257.8" y="220.1">74HCT00N</text>
<text x="43.7" y="222.7">WAC</text>
<text x="112.3" y="227.8" transform="rotate(-90 112.3 227.8)">VCC</text>
<text x="123.2" y="227.1">IC245D</text>
<text x="144" y="223.7">C364</text>
<text x="199.4" y="222.7">MC2</text>
<text x="242.6" y="225.2">FPR</text>
<text x="257.8" y="224.6">IC243D</text>
<text x="156.1" y="228.5">1uF</text>
<text x="242.3" y="230.3">MC3</text>
<text x="257.8" y="232.8">74HCT00N</text>
<text x="118.1" y="237.9">74HC125N</text>
<text x="135.9" y="239.9">4k7</text>
<text x="135.9" y="236.4">R216</text>
<text x="154.4" y="238.8">0.01uF</text>
<text x="154.4" y="236.3">C360</text>
<text x="179.1" y="238">LM556N</text>
<text x="143.5" y="240.5">GND</text>
<text x="179.1" y="242.2">IC241B</text>
<text x="196.8" y="240.5">GND</text>
<text x="92.7" y="248.1" transform="rotate(-90 92.7 248.1)">VCC</text>
<text x="102.9" y="248.1" transform="rotate(-90 102.9 248.1)">VCC</text>
<text x="130.8" y="250.6">GND</text>
<text x="143.5" y="248.1" transform="rotate(-90 143.5 248.1)">VCC</text>
<text x="146.4" y="248.8">R221</text>
<text x="27.4" y="255.3">C347</text>
<text x="35" y="255.3">C348</text>
<text x="42.7" y="255.3">C349</text>
<text x="50.3" y="255.3">C350</text>
<text x="57.9" y="255.3">C351</text>
<text x="65.5" y="255.3">C352</text>
<text x="73.1" y="255.3">C353</text>
<text x="80.8" y="255.3">C354</text>
<text x="88.4" y="255.3">C355</text>
<text x="96" y="255.3">C356</text>
<text x="106.9" y="255.3">C357</text>
<text x="144" y="256.7">C365</text>
<text x="153.4" y="254.2">10k</text>
<text x="199.4" y="255.7">MC3</text>
<text x="266.7" y="253">74HC21N</text>
<text x="27.4" y="260.4">0.1uF</text>
<text x="35" y="260.4">0.1uF</text>
<text x="42.7" y="260.4">0.1uF</text>
<text x="50.3" y="260.4">0.1uF</text>
<text x="57.9" y="260.4">0.1uF</text>
<text x="65.5" y="260.4">0.1uF</text>
<text x="73.1" y="260.4">0.1uF</text>
<text x="80.8" y="260.4">0.1uF</text>
<text x="88.4" y="260.4">0.1uF</text>
<text x="96" y="260.4">0.1uF</text>
<text x="106.9" y="260.4">1uF</text>
<text x="156.1" y="261.6">1uF</text>
<text x="154.4" y="269.3">C361</text>
<text x="266.7" y="265.1">IC238B</text>
<text x="24.1" y="270.9">GND</text>
<text x="102.9" y="270.9">GND</text>
<text x="143.5" y="273.5">GND</text>
<text x="154.4" y="271.8">0.01uF</text>
<text x="179.1" y="271.1">LM556N</text>
<text x="250.2" y="270.9">GND</text>
</g>
<g font-size="2.1">
<text x="326" y="59.8" transform="rotate(-90 326 59.8)">1</text>
<text x="317.8" y="64.9">2</text>
<text x="333.8" y="64.9">3</text>
<text x="326" y="77.6" transform="rotate(-90 326 77.6)">10</text>
<text x="102.5" y="80.1" transform="rotate(-90 102.5 80.1)">10</text>
<text x="317.8" y="82.6">9</text>
<text x="333.8" y="82.6">8</text>
<text x="94.3" y="85.2">9</text>
<text x="110.3" y="85.2">8</text>
<text x="140.6" y="88.3" transform="rotate(-90 140.6 88.3)">5</text>
<text x="143.1" y="88.3" transform="rotate(-90 143.1 88.3)">4</text>
<text x="148.2" y="88.3" transform="rotate(-90 148.2 88.3)">2</text>
<text x="150.8" y="88.3" transform="rotate(-90 150.8 88.3)">1</text>
<text x="158.4" y="88.3" transform="rotate(-90 158.4 88.3)">5</text>
<text x="163.5" y="88.3" transform="rotate(-90 163.5 88.3)">4</text>
<text x="171.1" y="88.3" transform="rotate(-90 171.1 88.3)">2</text>
<text x="176.2" y="88.3" transform="rotate(-90 176.2 88.3)">1</text>
<text x="183.8" y="88.3" transform="rotate(-90 183.8 88.3)">13</text>
<text x="188.9" y="88.3" transform="rotate(-90 188.9 88.3)">12</text>
<text x="196.5" y="88.3" transform="rotate(-90 196.5 88.3)">10</text>
<text x="201.6" y="88.3" transform="rotate(-90 201.6 88.3)">9</text>
<text x="326" y="95.3" transform="rotate(-90 326 95.3)">13</text>
<text x="145.7" y="99.2" transform="rotate(-90 145.7 99.2)">6</text>
<text x="160.9" y="99.2" transform="rotate(-90 160.9 99.2)">6</text>
<text x="173.6" y="99.2" transform="rotate(-90 173.6 99.2)">3</text>
<text x="186.3" y="100.4" transform="rotate(-90 186.3 100.4)">11</text>
<text x="199" y="99.2" transform="rotate(-90 199 99.2)">8</text>
<text x="316.6" y="100.4">12</text>
<text x="333.8" y="100.4">11</text>
<text x="140.6" y="108.6" transform="rotate(-90 140.6 108.6)">5</text>
<text x="326" y="113.1" transform="rotate(-90 326 113.1)">1</text>
<text x="134.3" y="115.7">4</text>
<text x="317.8" y="118.2">2</text>
<text x="333.8" y="118.2">3</text>
<text x="140.6" y="124.6" transform="rotate(-90 140.6 124.6)">6</text>
<text x="249.2" y="133.4">1</text>
<text x="260.1" y="136">3</text>
<text x="315.2" y="136">2</text>
<text x="321.1" y="137.1">A1</text>
<text x="329" y="137.1">Y1</text>
<text x="336.3" y="136">18</text>
<text x="175.5" y="138.5">4</text>
<text x="177.5" y="143.6">1</text>
<text x="181.4" y="139.6">R</text>
<text x="189.3" y="139.6">V+</text>
<text x="194.6" y="138.5">14</text>
<text x="249.2" y="138.5">2</text>
<text x="315.2" y="138.5">3</text>
<text x="315.2" y="141.1">4</text>
<text x="315.2" y="143.6">5</text>
<text x="321.1" y="139.6">A2</text>
<text x="321.1" y="142.2">A3</text>
<text x="329" y="142.2">Y3</text>
<text x="329" y="139.6">Y2</text>
<text x="336.3" y="143.6">15</text>
<text x="336.3" y="141.1">16</text>
<text x="336.3" y="138.5">17</text>
<text x="181.4" y="144.7">DIS</text>
<text x="190.3" y="149.8">Q</text>
<text x="194.6" y="148.7">5</text>
<text x="249.2" y="146.1">4</text>
<text x="260.1" y="148.7">6</text>
<text x="315.2" y="146.1">6</text>
<text x="315.2" y="148.7">7</text>
<text x="321.1" y="144.7">A4</text>
<text x="321.1" y="147.3">A5</text>
<text x="321.1" y="149.8">A6</text>
<text x="329" y="149.8">Y6</text>
<text x="329" y="147.3">Y5</text>
<text x="329" y="144.7">Y4</text>
<text x="336.3" y="148.7">13</text>
<text x="336.3" y="146.1">14</text>
<text x="177.5" y="151.2">2</text>
<text x="181.4" y="152.3">THR</text>
<text x="249.2" y="151.2">5</text>
<text x="315.2" y="151.2">8</text>
<text x="315.2" y="153.8">9</text>
<text x="321.1" y="152.3">A7</text>
<text x="321.1" y="154.9">A8</text>
<text x="329" y="154.9">Y8</text>
<text x="329" y="152.3">Y7</text>
<text x="336.3" y="153.8">11</text>
<text x="336.3" y="151.2">12</text>
<text x="177.5" y="156.3">6</text>
<text x="177.5" y="158.8">3</text>
<text x="181.4" y="157.4">TR</text>
<text x="181.4" y="159.9">CV</text>
<text x="187.2" y="160">GND</text>
<text x="194.6" y="158.8">7</text>
<text x="249.2" y="158.8">9</text>
<text x="260.1" y="161.4">8</text>
<text x="314" y="161.4">19</text>
<text x="315.2" y="158.8">1</text>
<text x="321.1" y="159.9">G1</text>
<text x="248" y="163.9">10</text>
<text x="321.1" y="162.5">G2</text>
<text x="174.3" y="171.5">10</text>
<text x="181.4" y="172.6">R</text>
<text x="248" y="171.5">12</text>
<text x="176.3" y="176.6">13</text>
<text x="181.4" y="177.7">DIS</text>
<text x="248" y="176.6">13</text>
<text x="260.1" y="174.1">11</text>
<text x="323.5" y="176.6" transform="rotate(-90 323.5 176.6)">4</text>
<text x="176.3" y="184.2">12</text>
<text x="181.4" y="185.3">THR</text>
<text x="190.3" y="182.8">Q</text>
<text x="194.6" y="181.7">9</text>
<text x="249.2" y="184.2">1</text>
<text x="315.2" y="181.7">5</text>
<text x="331.2" y="181.7">6</text>
<text x="176.3" y="191.8">11</text>
<text x="177.5" y="189.3">8</text>
<text x="181.4" y="190.4">TR</text>
<text x="249.2" y="189.3">2</text>
<text x="260.1" y="186.8">3</text>
<text x="181.4" y="193">CV</text>
<text x="249.2" y="196.9">4</text>
<text x="249.2" y="202">5</text>
<text x="260.1" y="199.5">6</text>
<text x="175.5" y="212.2">4</text>
<text x="181.4" y="213.3">R</text>
<text x="189.3" y="213.3">V+</text>
<text x="194.6" y="212.2">14</text>
<text x="249.2" y="212.2">9</text>
<text x="260.1" y="214.7">8</text>
<text x="177.5" y="217.2">1</text>
<text x="181.4" y="218.4">DIS</text>
<text x="248" y="217.2">10</text>
<text x="120.3" y="224.9" transform="rotate(-90 120.3 224.9)">13</text>
<text x="177.5" y="224.9">2</text>
<text x="181.4" y="226">THR</text>
<text x="190.3" y="223.4">Q</text>
<text x="194.6" y="222.3">5</text>
<text x="248" y="224.9">12</text>
<text x="260.1" y="227.4">11</text>
<text x="110.9" y="229.9">12</text>
<text x="128.1" y="229.9">11</text>
<text x="177.5" y="229.9">6</text>
<text x="177.5" y="232.5">3</text>
<text x="181.4" y="231.1">TR</text>
<text x="181.4" y="233.6">CV</text>
<text x="187.2" y="233.6">GND</text>
<text x="194.6" y="232.5">7</text>
<text x="248" y="229.9">13</text>
<text x="174.3" y="245.2">10</text>
<text x="176.3" y="250.3">13</text>
<text x="181.4" y="246.3">R</text>
<text x="181.4" y="251.4">DIS</text>
<text x="176.3" y="257.9">12</text>
<text x="190.3" y="256.5">Q</text>
<text x="194.6" y="255.3">9</text>
<text x="255.6" y="255.3">12</text>
<text x="255.6" y="252.8">13</text>
<text x="267.7" y="257.9">8</text>
<text x="177.5" y="263">8</text>
<text x="181.4" y="259">THR</text>
<text x="255.6" y="260.4">10</text>
<text x="256.8" y="263">9</text>
<text x="176.3" y="265.5">11</text>
<text x="181.4" y="264.1">TR</text>
<text x="181.4" y="266.6">CV</text>
</g>
<g font-size="1.8">
<text x="154.1" y="153.4">+</text>
<text x="154.1" y="186.4">+</text>
<text x="154.1" y="227.1">+</text>
<text x="154.1" y="260.1">+</text>
</g>
</g></defs>
<g fill="#000" stroke="#000" stroke-width=".25">
<path d="M67.8 18.2v3.9zM115.3 18.2v3.9zM162.7 18.2v3.9zM210.2 18.2v3.9zM257.6 18.2v3.9zM305.1 18.2v3.9zM352.5 18.2v3.9zM20.3 22.1v252.6zM31.1 33.6h10.9zM34.4 38.7h7.6zM47 29.7h182.8zM47 34.8h101.6z"/>
<path d="M47 39.8h104.1zM151.1 39.8h12.7zM148.6 34.8h27.9zM163.8 39.8h20.3zM176.5 34.8h12.7zM229.8 29.7v154.9zM308.6 39.8l1.1 2.3zM20.3 22.1h379.7zM29.4 43.8h12.6zM30.6 59h11.4zM32.9 48.9h9.1zM33.9 54h8.1z"/>
<path d="M47 44.9h261.6zM47 55.1h251.4zM285.8 41.6h12.6zM289.4 46.7h9zM290.4 51.8h8zM298.4 55.1v53.3zM47 50h256.5zM308.6 55.1h17.8zM308.6 55.1v17.7zM308.6 44.9v10.2zM310.4 43.4l1.1 2.3zM311.8 46.3l.1 .1z"/>
<path d="M312.2 47.1l1.1 2.2zM314 50.7l1.1 2.2zM315.4 53.5l.1 .2zM315.8 54.3l1.1 2.2zM317.6 57.9l1.1 2.2zM326.4 57.6v2.6zM326.4 55.1v2.5zM16.5 72.6h3.8zM33.8 64.1h8.2zM47 60.2h93.9zM47 65.2h96.5zM102.9 77.9v2.6z"/>
<path d="M47 72.8h55.9zM102.9 72.8v5.1zM102.9 72.8h25.3zM143.5 65.2h15.2zM140.9 60.2h30.5zM158.7 65.2h38.1zM171.4 60.2h30.5zM308.6 72.8h17.8zM313.7 65.2v17.8zM316.2 65.2h5.1zM313.7 65.2h2.5zM326.4 60.2v.7z"/>
<path d="M326.4 75.4v2.5zM326.4 77.9v.8zM326.4 72.8v2.6zM331.4 65.2h5.1zM336.5 65.2h45.7zM383.7 64.1h5.9zM400 72.6h3.8zM90.2 80.5v2.5zM90.2 83v2.5zM92.7 85.5h5.1zM90.2 85.5h2.5zM102.9 80.5v.7z"/>
<path d="M107.9 85.5h5.1zM113 85.5h2.6zM115.6 82.3h8.6zM115.6 88.1v2.5zM115.6 95.7v2.5zM115.6 85.5h7.6zM115.6 85.5v2.6zM123.2 85.5v45.8zM138.9 74.8v8.2zM140.9 85.5v5.1zM140.9 60.2v25.3zM141.5 71.6v11.4z"/>
<path d="M143.5 85.5v5.1zM143.5 65.2v20.3zM146.6 75.4v7.6zM148.6 85.5v5.1zM148.6 34.8v50.7zM149.1 72.1v10.9zM151.1 85.5v5.1zM151.1 39.8v45.7zM156.7 74.8v8.2zM158.7 85.5v5.1zM158.7 65.2v20.3zM161.8 75.4v7.6z"/>
<path d="M163.8 85.5v5.1zM163.8 39.8v45.7zM169.4 71.6v11.4zM171.4 85.5v5.1zM171.4 60.2v25.3zM174.5 72.1v10.9zM176.5 85.5v5.1zM176.5 34.8v50.7zM182.1 75.4v7.6zM184.1 85.5v5.1zM184.1 39.8v45.7zM187.2 72.1v10.9z"/>
<path d="M189.2 85.5v5.1zM189.2 34.8v50.7zM194.8 74.8v8.2zM196.8 85.5v5.1zM196.8 65.2v20.3zM199.9 71.6v11.4zM201.9 85.5v5.1zM201.9 60.2v25.3zM205.7 84.3h1.3zM207 84.3v2.5zM207 86.8h1.3zM208.3 84.3v2.5z"/>
<path d="M208.3 84.3h1.2zM303.5 50v40.6zM313.7 83v17.8zM316.2 83h5.1zM313.7 83h2.5zM326.4 93.2v2.5zM326.4 95.7v.8zM303.5 90.6h22.9zM326.4 90.6v2.6zM331.4 83h5.1zM336.5 83h45.7zM346.7 95.7v1.2z"/>
<path d="M346.7 97.9v1.3zM346.7 95.7h1.2zM348.9 95.7h1.2zM351.1 95.7h1.3zM353.4 95.7h1.2zM356.8 97.9v1.3zM356.8 95.7v1.2zM355.6 95.7h1.2zM383.7 81.9h6zM383.7 99.7h5.9zM37.5 106.4h12zM52.1 113.5h2.5z"/>
<path d="M52.1 118.6h2.5zM52.1 105.9h3.8zM54.6 110.9v2.6zM54.6 110.9h5.1zM54.6 116v2.6zM54.6 116h10.2zM53.3 105.9l1.3 2.5zM55.9 105.9l1.2 2.5zM54.6 108.4h2.5zM57.1 108.4h20.4zM59.7 110.9v2.6zM59.7 113.5h25.4z"/>
<path d="M64.8 116v2.6zM64.8 118.6h20.3zM77.5 108.4h1.1zM79.6 108.4h1.2zM81.8 108.4h1.1zM83.9 108.4h1.2zM115.6 100.8v2.5zM115.6 98.2v2.6zM128.2 72.8v43.2zM133.3 116h2.6zM128.2 116h5.1zM135.9 116h.7z"/>
<path d="M140.9 105.9v5zM140.9 103.3v2.6zM140.9 103.3h5.1zM146 95.7v5.1zM146 100.8v2.5zM148.6 116v2.6zM148.6 110.9v2.6zM148.6 113.5v2.5zM161.3 97.7v3.1zM161.3 100.8v20.3zM162.5 119.8h1.3zM163.8 117.3v2.5z"/>
<path d="M163.8 117.3h1.3zM165.1 117.3v2.5zM165.1 119.8h1.2zM174 97.7v3.1zM174 100.8v20.3zM175.2 119.8h1.3zM176.5 117.3v2.5zM176.5 117.3h1.3zM177.8 117.3v2.5zM177.8 119.8h1.2zM186.7 97.7v3.1zM186.7 100.8v20.3z"/>
<path d="M187.9 119.8h1.3zM189.2 117.3v2.5zM189.2 117.3h1.3zM190.5 117.3v2.5zM190.5 119.8h1.2zM199.4 97.7v3.1zM199.4 100.8v20.3zM200.6 119.8h1.3zM201.9 117.3v2.5zM201.9 117.3h1.3zM203.2 117.3v2.5zM203.2 119.8h1.2z"/>
<path d="M231.1 119.8h1.3zM232.4 117.3v2.5zM232.4 117.3h1.3zM233.7 117.3v2.5zM233.7 119.8h1.2zM298.4 108.4h28zM313.7 100.8v17.8zM316.2 100.8h5.1zM316.2 118.6h5.1zM313.7 100.8h2.5zM313.7 118.6h2.5zM326.4 110.9v2.6z"/>
<path d="M326.4 113.5v.7zM326.4 108.4v2.5zM331.4 100.8h5.1zM331.4 118.6h5.1zM336.5 118.6h45.7zM336.5 100.8h15.2zM346.7 100.2v1.2zM346.7 102.4v1.2zM346.7 104.6v1.3zM346.7 105.9h1.2zM348.9 105.9h1.2zM351.1 105.9h1.3z"/>
<path d="M351.7 100.8h30.5zM353.4 105.9h1.2zM355.6 105.9h1.2zM356.8 104.6v1.3zM356.8 102.4v1.2zM356.8 100.2v1.2zM356.8 108.4l.5 2.6zM357.4 111.7l.1 .1zM357.6 112.5l.4 2.7zM358.2 115.8v.2zM358.3 116.6l.5 2.7zM358.9 119.9v.2z"/>
<path d="M383.7 117.4h4.9zM16.5 123.1h3.8zM52.1 123.6h13.9zM52.1 128.7h13.9zM66 121.1v2.5zM66 121.1h17.8zM66 126.2v2.5zM66 126.2h10.2zM76.2 126.2v2.5zM76.2 128.7h8.9zM83.8 121.1v2.5zM83.8 123.6h1.3z"/>
<path d="M140.9 121.1v5.1zM140.9 126.2v2.5zM142.2 124.9h1.3zM143.5 124.9v2.5zM143.5 127.4h1.3zM144.8 124.9v2.5zM144.8 124.9h1.2zM148.6 123.6v2.6zM140.9 128.7h7.7zM148.6 126.2v2.5zM153.6 126.7h12.1zM153.6 129.2h8.6z"/>
<path d="M161.3 121.1l2.5 2.5zM148.6 128.7h22.8zM171.4 128.7v28zM174 121.1l2.5 2.5zM174 138.9v33zM174 131.3v7.6zM123.2 131.3h50.8zM176.5 138.9h.6zM174 138.9h2.5zM186.7 121.1l2.5 2.5zM194.3 138.9h2.5zM196.8 138.9h2.6z"/>
<path d="M199.4 133.8v2.5zM199.4 136.3v2.6zM199.4 121.1l2.5 2.5zM224.8 131.3l2.5 2.5zM234.9 138.9h12.7zM247.6 133.8h5.1zM247.6 138.9h5.1zM227.3 133.8h20.3zM256.8 126.7l-.3 3.3zM256.9 125.9v.2zM257.3 122l-.3 3.3zM257.4 121.2v.1z"/>
<path d="M257.8 117.3l-.3 3.2zM259.8 136.3h3.1zM262.9 136.3h50.8zM269.2 132.5h1.3zM270.5 132.5v2.6zM270.5 135.1h2.5zM273 132.5v2.6zM273 132.5h1.3zM278.1 138.9h35.6zM290.8 129.2h12.1zM303.5 128.7v30.5zM171.4 128.7h132.1z"/>
<path d="M313.7 123.6v2.6zM313.7 136.3h5zM313.7 138.9h5zM313.7 118.6v5zM334 138.9h5zM334 136.3h5zM339 138.9h38.1zM339 136.3h35.6zM359 120.8l.5 2.6zM359.6 124.1l.1 .1zM359.8 124.9l.5 2.6zM360.4 128.2v.1z"/>
<path d="M360.5 129l.5 2.7zM361.1 132.3v.2zM361.3 133.1l.4 2.7zM361.9 136.4v.2zM362 137.2l.5 2.7zM374.6 132.5v3.8zM374.6 132.5h7.6zM377.1 136.3v2.6zM377.1 136.3h5.1zM383.7 135.2h2.7zM383.7 139h1.8zM383.7 131.4h5.9z"/>
<path d="M400 123.1h3.8zM29.8 159.7h5.8zM37.5 144.5h12zM37.7 159.7h2.6zM41.7 159.7h7.8zM43.7 149.6h5.8zM44.2 154.6h5.3zM52.1 150.3h2.5zM52.1 155.4h2.5zM52.1 144h3.8zM54.6 150.3v1.3zM54.6 151.6h5.1z"/>
<path d="M54.6 159.2h11.4zM54.6 155.4v1.3zM54.6 156.7h10.2zM53.3 144l1.3 2.5zM55.9 144l1.2 2.5zM54.6 146.5h2.5zM57.1 146.5h20.4zM59.7 149v2.6zM59.7 149h25.4zM64.8 154.1v2.6zM64.8 154.1h20.3zM66 159.2v2.5z"/>
<path d="M77.5 146.5h1.1zM79.6 146.5h1.2zM81.8 146.5h1.1zM83.8 159.2h1.3zM83.9 146.5h1.2zM146 138.9v2.5zM146 141.4v2.6zM146 144h2.6zM146 151.6v7.6zM146 159.2v2.5zM148.6 151.6h2.5zM148.6 159.2h2.5z"/>
<path d="M148.6 144h2.5zM146 151.6h2.6zM146 159.2h2.6zM151.1 159.2h.5zM153.1 159.2h.5zM153.6 151.6h2.6zM153.6 159.2h2.6zM156.2 144h2.5zM158.7 144h2.6zM156.2 151.6h5.1zM161.3 144v7.6zM161.3 151.6h5z"/>
<path d="M166.3 144v7.6zM171.4 156.7h5.1zM171.4 156.7v33zM176.5 156.7h2.5zM176.5 159.2h2.5zM176.5 151.6h2.5zM176.5 144h2.5zM166.3 151.6h10.2zM166.3 144h10.2zM156.2 159.2h20.3zM194.3 149h2.5zM194.3 159.2h2.5z"/>
<path d="M196.8 159.2h2.6zM199.4 152.8h2.5zM199.4 159.2v2.5zM201.9 150.3v2.5zM201.9 150.3h2.5zM204.4 150.3v2.5zM204.4 152.8h5.1zM196.8 149h15.3zM212.1 149l2.5 2.6zM224.8 144l2.5 2.5zM224.8 156.7l2.5 2.5zM232.4 154.1l2.5-2.5z"/>
<path d="M234.9 138.9l-2.5 2.5zM234.9 151.6h12.7zM247.6 146.5h5.1zM247.6 151.6h5.1zM247.6 159.2h5.1zM227.3 146.5h20.3zM227.3 159.2h20.3zM259.8 149h3.1zM262.9 149h15.2zM269.2 145.2h1.3zM269.2 157.9h1.3zM270.5 145.2v2.6z"/>
<path d="M270.5 147.8h2.5zM270.5 157.9v2.6zM273 145.2v2.6zM273 145.2h1.3zM273 157.9h1.3zM278.1 138.9v10.1zM280.6 141.4h33.1zM283.2 144h30.5zM285.7 146.5h28zM288.3 149h25.4zM290.8 151.6h22.9zM293.3 154.1h20.4z"/>
<path d="M303.5 159.2v2.5zM313.7 159.2h3.1zM313.7 141.4h5zM313.7 144h5zM313.7 146.5h5zM313.7 149h5zM313.7 151.6h5zM313.7 154.1h5zM303.5 159.2h10.2zM334 154.1h5zM334 151.6h5zM334 149h5z"/>
<path d="M334 146.5h5zM334 144h5zM334 141.4h5zM339 141.4h40.7zM339 146.5h40.7zM339 149h38.1zM339 151.6h35.6zM339 154.1h33.1zM339 144h43.2zM362.6 140.6v.1zM362.7 141.4l.5 2.6zM363.3 144.7l.1 .1z"/>
<path d="M363.5 145.5l.5 2.6zM364.1 148.8v.1zM364.2 149.6l.5 2.6zM364.8 152.9v.2zM364.9 153.7l.5 2.7zM365.5 157.1l.1 .1zM365.7 157.9l.5 2.6zM372.1 154.1v5.1zM372.1 159.2h10.1zM374.6 151.6v3.8zM374.6 155.4h7.6zM377.1 149v2.6z"/>
<path d="M377.1 151.6h5.1zM379.7 140.1v1.3zM379.7 140.1h2.5zM379.7 146.5v1.3zM379.7 147.8h2.5zM383.7 146.6h7.9zM383.7 150.5h5.3zM383.7 154.3h5.9zM383.7 158.1h5.3zM383.7 142.8h5.9zM16.5 173.7h3.8zM43.7 169.9h5.8z"/>
<path d="M44.2 164.8h5.3zM52.1 160.5h2.5zM52.1 170.6h2.5zM52.1 165.5h2.5zM54.6 159.2v1.3zM54.6 169.4v1.2zM54.6 169.4h11.4zM54.6 164.3v1.2zM54.6 164.3h11.4zM66 161.7h17.8zM66 169.4v2.5zM66 171.9h10.2z"/>
<path d="M66 164.3v2.5zM66 166.8h17.8zM66.4 176.2h2.3zM73.5 173.7h5.8zM76.2 169.4v2.5zM76.2 169.4h8.9zM82.8 173.7h2.4zM83.8 159.2v2.5zM83.8 164.3v2.5zM83.8 164.3h1.3zM146 161.7v2.6zM146 171.9v2.5z"/>
<path d="M146 174.4v2.6zM146 177h2.6zM148.6 177h2.5zM156.2 177h2.5zM158.7 177h2.6zM161.3 177v7.6zM166.3 177v7.6zM174 171.9v40.6zM176.5 171.9h.6zM176.5 177h2.5zM174 171.9h2.5zM166.3 177h10.2z"/>
<path d="M199.4 178.2h2.5zM199.4 161.7v2.6zM201.9 175.7v2.5zM201.9 175.7h5.1zM207 175.7v2.5zM207 178.2h2.5zM224.8 169.4l2.5 2.5zM232.4 166.8l2.5-2.5zM234.9 164.3h12.7zM234.9 177l-2.5 2.5zM245.1 179.5h1.3zM246.4 179.5v2.6z"/>
<path d="M247.6 164.3h5.1zM247.6 171.9h5.1zM247.6 177h5.1zM234.9 177h12.7zM227.3 171.9h20.3zM259.8 161.7h3.1zM259.8 174.4h3.1zM262.9 161.7h17.7zM262.9 174.4h20.3zM269.2 170.6h1.3zM270.5 170.6v2.6zM270.5 173.2h1.3z"/>
<path d="M270.5 160.5h2.5zM271.8 170.6v2.6zM271.8 170.6h2.5zM273 157.9v2.6zM280.6 141.4v20.3zM283.2 144v30.4zM295.9 171.9h27.9zM313.7 161.7h3.1zM303.5 161.7h10.2zM323.8 174.4v2.6zM323.8 177v.7zM323.8 171.9v2.5z"/>
<path d="M352.3 173.7v5.8zM366.3 161.2v.1zM366.4 162l.5 2.6zM367 165.3v.1zM367.2 166.1l.4 2.6zM367.8 169.4v.1zM367.9 170.2l.5 2.7zM368.5 173.5v.2zM368.6 174.3l.5 2.7zM369.2 177.6l.1 .2zM369.4 178.5l.5 2.6zM400 173.7h3.8z"/>
<path d="M37.5 195.3h12zM52.1 194.8h3.8zM53.3 194.8l1.3 2.5zM55.9 194.8l1.2 2.5zM54.6 197.3h2.5zM57.1 197.3h20.4zM59.7 199.8h25.4zM77.5 197.3h1.1zM79.6 197.3h1.2zM81.8 197.3h1.1zM83.9 197.3h1.2zM146 194.8v2.5z"/>
<path d="M146 184.6v7.6zM146 192.2v2.6zM148.6 184.6h2.5zM148.6 192.2h2.5zM146 184.6h2.6zM146 192.2h2.6zM151.1 192.2h.5zM153.1 192.2h.5zM153.6 184.6h2.6zM153.6 192.2h2.6zM156.2 184.6h5.1zM161.3 184.6h5z"/>
<path d="M171.4 189.7h5.1zM176.5 189.7h2.5zM176.5 192.2h2.5zM176.5 184.6h2.5zM166.3 184.6h10.2zM156.2 192.2h20.3zM194.3 182.1h2.5zM196.8 182.1h15.3zM212.1 182.1l2.5 2.5zM229.8 184.6h17.8zM232.4 192.2l2.5-2.5zM234.9 199.8h10.2z"/>
<path d="M234.9 189.7h12.7zM243.8 182.1h1.3zM245.1 179.5v2.6zM245.1 197.3v2.5zM245.1 199.8v2.6zM246.4 182.1h1.2zM247.6 184.6h5.1zM247.6 189.7h5.1zM247.6 197.3h5.1zM245.1 197.3h2.5zM259.8 187.1h3.1zM259.8 199.8h3.1z"/>
<path d="M262.9 187.1h22.8zM262.9 199.8h25.4zM269.2 183.3h1.3zM269.2 196h1.3zM270.5 183.3v2.6zM270.5 185.9h2.5zM270.5 196v2.6zM270.5 198.6h1.3zM271.8 196v2.6zM271.8 196h2.5zM273 183.3v2.6zM273 183.3h1.3z"/>
<path d="M285.7 146.5v40.6zM288.3 149v50.8zM311.1 187.1v2.6zM311.1 182.1v5zM313.7 182.1h5zM311.1 182.1h2.6zM328.9 182.1h5.1zM334 182.1h17.7zM351.7 100.8v81.3zM370 181.8v.1zM370.1 182.6l.5 2.6zM370.7 185.9v.1z"/>
<path d="M370.9 186.7l.4 2.7zM371.4 190l.1 .2zM371.6 190.8l.5 2.7zM29.8 210.5h5.8zM37.7 210.5h2.6zM41.7 210.5h7.8zM43.7 200.4h5.8zM44.2 205.4h5.3zM47.7 215.6h1.8zM52.1 201.1h2.5zM52.1 211.2h2.5zM52.1 206.2h2.5z"/>
<path d="M52.1 216.3h2.5zM54.6 201.1v1.3zM54.6 202.4h5.1zM54.6 210v1.2zM54.6 210h11.4zM54.6 206.2v1.2zM54.6 207.4h10.2zM54.6 215v1.3zM54.6 215h11.4zM59.7 199.8v2.6zM64.8 204.9v2.5zM64.8 204.9h20.3z"/>
<path d="M66 210v2.5zM66 212.5h17.8zM66 215v2.6zM66 217.6h17.8zM83.8 210v2.5zM83.8 210h1.3zM83.8 215v2.6zM83.8 215h1.3zM114.3 216.3h1.3zM115.6 213.8v2.5zM115.6 213.8h1.2zM116.8 213.8v2.5z"/>
<path d="M116.8 216.3h1.3zM120.6 202.4h91.5zM126 217l-1.7 2.8zM128.4 212.8l-1.7 2.9zM128.8 212.1l-.1 .2zM130.8 208.7l-1.7 2.9zM146 212.5v2.5zM146 215v2.6zM146 217.6h2.6zM148.6 217.6h2.5zM156.2 217.6h2.5zM158.7 217.6h2.6z"/>
<path d="M161.3 217.6v7.6zM166.3 217.6v7.6zM174 212.5v33zM176.5 212.5h.6zM176.5 217.6h2.5zM174 212.5h2.5zM166.3 217.6h10.2zM194.3 212.5h2.5zM199.4 207.4v2.6zM196.8 212.5h2.6zM199.4 210v2.5zM212.1 202.4l2.5 2.5z"/>
<path d="M224.8 210l2.5 2.5zM227.3 212.5h20.3zM232.4 210l2.5-2.6zM232.4 202.4l2.5-2.6zM234.9 207.4h55.9zM234.9 217.6h12.7zM245.1 202.4h2.5zM247.6 202.4h5.1zM247.6 212.5h5.1zM247.6 217.6h5.1zM259.8 215h3.1zM262.9 215h30.4z"/>
<path d="M269.2 211.2h1.3zM270.5 211.2v2.6zM270.5 213.8h2.5zM273 211.2v2.6zM273 211.2h1.3zM290.8 151.6v55.8zM293.3 154.1v60.9zM331.5 205.4h5.9zM346.4 200.4h9zM16.5 224.2h3.8zM43.7 220.7h5.8zM52.1 221.4h2.5z"/>
<path d="M54.6 220.1v1.3zM54.6 220.1h11.4zM66 220.1v2.6zM66 222.7h10.2zM76.2 220.1v2.6zM76.2 220.1h8.9zM107.9 225.2v2.5zM107.9 227.7v2.6zM110.5 230.3h5.1zM107.9 230.3h2.6zM120.6 222.7v2.5zM120.6 225.2v.8z"/>
<path d="M120.6 202.4v20.3zM123.6 221.1l-1.7 2.8zM125.7 230.3h5.1zM130.8 230.3h2.5zM133.3 232.8v2.6zM133.3 230.3v2.5zM133.3 230.3h38.1zM134.6 226.5h1.3zM135.9 226.5v2.5zM135.9 229h1.2zM137.1 226.5v2.5zM137.1 226.5h1.3z"/>
<path d="M146 235.4v2.5zM146 225.2v7.6zM146 232.8v2.6zM148.6 225.2h2.5zM148.6 232.8h2.5zM146 225.2h2.6zM146 232.8h2.6zM151.1 232.8h.5zM153.1 232.8h.5zM153.6 225.2h2.6zM153.6 232.8h2.6zM156.2 225.2h5.1z"/>
<path d="M161.3 225.2h5zM171.4 230.3h5.1zM171.4 230.3v33zM176.5 230.3h2.5zM176.5 232.8h2.5zM176.5 225.2h2.5zM166.3 225.2h10.2zM156.2 232.8h20.3zM194.3 222.7h2.5zM194.3 232.8h2.5zM196.8 232.8h2.6zM199.4 226.5h2.5z"/>
<path d="M199.4 235.4v2.5zM199.4 232.8v2.6zM201.9 223.9v2.6zM201.9 223.9h5.1zM207 223.9v2.6zM207 226.5h2.5zM196.8 222.7h15.3zM212.1 222.7l2.5 2.5zM224.8 222.7l2.5 2.5zM232.4 220.1l2.5-2.5zM234.9 230.3l-2.5 2.5zM247.6 225.2h5.1z"/>
<path d="M247.6 230.3h5.1zM234.9 230.3h12.7zM227.3 225.2h20.3zM259.8 227.7h3.1zM262.9 227.7h33zM269.2 223.9h1.3zM270.5 223.9v2.6zM270.5 226.5h1.3zM271.8 223.9v2.6zM271.8 223.9h2.5zM295.9 171.9v55.8zM400 224.2h3.8z"/>
<path d="M26.7 253.1v2.6zM26.7 257.7v.5zM26.7 255.7v.5zM26.7 250.6v2.5zM34.3 253.1v2.6zM34.3 257.7v.5zM34.3 255.7v.5zM34.3 250.6v2.5zM26.7 250.6h7.6zM41.9 253.1v2.6zM41.9 257.7v.5zM41.9 255.7v.5z"/>
<path d="M34.3 250.6h7.6zM41.9 250.6v2.5zM49.5 253.1v2.6zM49.5 257.7v.5zM49.5 255.7v.5zM41.9 250.6h7.6zM49.5 250.6v2.5zM57.1 253.1v2.6zM57.1 257.7v.5zM57.1 255.7v.5zM49.5 250.6h7.6zM57.1 250.6v2.5z"/>
<path d="M64.8 253.1v2.6zM64.8 257.7v.5zM64.8 255.7v.5zM57.1 250.6h7.7zM64.8 250.6v2.5zM72.4 253.1v2.6zM72.4 257.7v.5zM72.4 255.7v.5zM64.8 250.6h7.6zM72.4 250.6v2.5zM80 253.1v2.6zM80 257.7v.5z"/>
<path d="M80 255.7v.5zM72.4 250.6h7.6zM80 250.6v2.5zM87.6 253.1v2.6zM87.6 257.7v.5zM87.6 255.7v.5zM80 250.6h7.6zM87.6 250.6v2.5zM95.2 245.5v2.6zM95.2 253.1v2.6zM95.2 257.7v.5zM95.2 255.7v.5z"/>
<path d="M87.6 250.6h7.6zM95.2 248.1v2.5zM95.2 250.6v2.5zM105.4 245.5v2.6zM105.4 253.1v2.6zM105.4 255.7v.5zM105.4 257.7v.5zM105.4 248.1v5zM133.3 240.4v2.6zM133.3 245.5v2.6zM133.3 243v2.5zM146 245.5v2.6z"/>
<path d="M146 248.1v2.5zM146 250.6h2.6zM146 258.2v7.6zM148.6 258.2h2.5zM148.6 250.6h2.5zM146 258.2h2.6zM153.6 258.2h2.6zM156.2 250.6h2.5zM158.7 250.6h2.6zM156.2 258.2h5.1zM161.3 250.6v7.6zM161.3 258.2h5z"/>
<path d="M166.3 250.6v7.6zM174 245.5h2.5zM176.5 245.5h.6zM176.5 258.2h2.5zM176.5 250.6h2.5zM166.3 258.2h10.2zM166.3 250.6h10.2zM194.3 255.7h2.5zM199.4 259.5h2.5zM201.9 257v2.5zM201.9 257h2.5zM204.4 257v2.5z"/>
<path d="M204.4 259.5h5.1zM196.8 255.7h15.3zM212.1 255.7l2.5 2.5zM252.7 253.1v2.6zM252.7 255.7v5.1zM255.2 255.7h5.1zM255.2 253.1h5.1zM252.7 253.1h2.5zM252.7 255.7h2.5zM265.4 258.2h5.1zM20.3 274.7h379.7zM26.7 265.8v2.6z"/>
<path d="M26.7 258.2v2.6zM26.7 260.8v2.5zM26.7 263.3h7.6zM26.7 263.3v2.5zM34.3 258.2v2.6zM34.3 260.8v2.5zM41.9 258.2v2.6zM34.3 263.3h7.6zM41.9 260.8v2.5zM49.5 258.2v2.6zM41.9 263.3h7.6zM49.5 260.8v2.5z"/>
<path d="M57.1 258.2v2.6zM49.5 263.3h7.6zM57.1 260.8v2.5zM64.8 258.2v2.6zM57.1 263.3h7.7zM64.8 260.8v2.5zM67.8 274.7v3.8zM72.4 258.2v2.6zM64.8 263.3h7.6zM72.4 260.8v2.5zM80 258.2v2.6zM72.4 263.3h7.6z"/>
<path d="M80 260.8v2.5zM87.6 258.2v2.6zM80 263.3h7.6zM87.6 260.8v2.5zM95.2 258.2v2.6zM87.6 263.3h7.6zM95.2 260.8v2.5zM105.4 258.2v2.6zM105.4 265.8v2.6zM105.4 260.8v5zM115.3 274.7v3.8zM146 268.4v2.5z"/>
<path d="M146 265.8v2.6zM148.6 265.8h2.5zM146 265.8h2.6zM151.1 265.8h.5zM153.1 265.8h.5zM153.6 265.8h2.6zM162.7 274.7v3.8zM171.4 263.3h5.1zM176.5 263.3h2.5zM176.5 265.8h2.5zM156.2 265.8h20.3zM210.2 274.7v3.8z"/>
<path d="M252.7 265.8v2.6zM252.7 260.8v2.5zM252.7 263.3v2.5zM255.2 263.3h5.1zM255.2 260.8h5.1zM252.7 260.8h2.5zM252.7 263.3h2.5zM257.6 274.7v3.8zM305.1 274.7v3.8zM352.5 274.7v3.8zM400 264.5v.1zM400 268.4v6.2z"/>
<path d="M400 274.6h.1zM400 22.1v252.6z"/>
<circle cx="148.6" cy="34.8" r=".51"/>
<circle cx="151.1" cy="39.8" r=".51"/>
<circle cx="163.8" cy="39.8" r=".51"/>
<circle cx="176.5" cy="34.8" r=".51"/>
<circle cx="308.6" cy="55.1" r=".51"/>
<circle cx="102.9" cy="72.8" r=".51"/>
<circle cx="140.9" cy="60.2" r=".51"/>
<circle cx="143.5" cy="65.2" r=".51"/>
<circle cx="158.7" cy="65.2" r=".51"/>
<circle cx="171.4" cy="60.2" r=".51"/>
<circle cx="115.6" cy="85.5" r=".51"/>
<circle cx="313.7" cy="83" r=".51"/>
<circle cx="313.7" cy="118.6" r=".51"/>
<circle cx="313.7" cy="100.8" r=".51"/>
<circle cx="351.7" cy="100.8" r=".51"/>
<circle cx="148.6" cy="128.7" r=".51"/>
<circle cx="171.4" cy="128.7" r=".51"/>
<circle cx="174" cy="138.9" r=".51"/>
<circle cx="146" cy="159.2" r=".51"/>
<circle cx="161.3" cy="151.6" r=".51"/>
<circle cx="166.3" cy="151.6" r=".51"/>
<circle cx="171.4" cy="156.7" r=".51"/>
<circle cx="303.5" cy="159.2" r=".51"/>
<circle cx="174" cy="171.9" r=".51"/>
<circle cx="146" cy="192.2" r=".51"/>
<circle cx="161.3" cy="184.6" r=".51"/>
<circle cx="166.3" cy="184.6" r=".51"/>
<circle cx="245.1" cy="199.8" r=".51"/>
<circle cx="174" cy="212.5" r=".51"/>
<circle cx="133.3" cy="230.3" r=".51"/>
<circle cx="146" cy="232.8" r=".51"/>
<circle cx="161.3" cy="225.2" r=".51"/>
<circle cx="166.3" cy="225.2" r=".51"/>
<circle cx="171.4" cy="230.3" r=".51"/>
<circle cx="34.3" cy="250.6" r=".51"/>
<circle cx="41.9" cy="250.6" r=".51"/>
<circle cx="49.5" cy="250.6" r=".51"/>
<circle cx="57.1" cy="250.6" r=".51"/>
<circle cx="64.8" cy="250.6" r=".51"/>
<circle cx="72.4" cy="250.6" r=".51"/>
<circle cx="80" cy="250.6" r=".51"/>
<circle cx="87.6" cy="250.6" r=".51"/>
<circle cx="95.2" cy="250.6" r=".51"/>
<circle cx="161.3" cy="258.2" r=".51"/>
<circle cx="166.3" cy="258.2" r=".51"/>
<circle cx="252.7" cy="255.7" r=".51"/>
<circle cx="26.7" cy="263.3" r=".51"/>
<circle cx="34.3" cy="263.3" r=".51"/>
<circle cx="41.9" cy="263.3" r=".51"/>
<circle cx="49.5" cy="263.3" r=".51"/>
<circle cx="57.1" cy="263.3" r=".51"/>
<circle cx="64.8" cy="263.3" r=".51"/>
<circle cx="72.4" cy="263.3" r=".51"/>
<circle cx="80" cy="263.3" r=".51"/>
<circle cx="87.6" cy="263.3" r=".51"/>
<circle cx="146" cy="265.8" r=".51"/>
<circle cx="252.7" cy="263.3" r=".51"/>
<circle cx="252.7" cy="260.8" r=".51"/>
</g>
<g fill="#000" stroke="#000" stroke-width=".28">
<path d="M26.4 28.2v3zM28.7 33.2v3.1zM32 38.3v3.1zM26.4 28.2h19.1zM26.4 31.2h19.1zM28.7 33.2h16.8zM28.7 36.3h16.8zM32 38.3h13.5zM45.5 28.2l1.5 1.5zM47 29.7l-1.5 1.5zM45.5 33.2l1.5 1.6zM47 34.8l-1.5 1.5z"/>
<path d="M45.5 38.3l1.5 1.5zM47 39.8l-1.5 1.6zM26.9 43.4v3zM28.2 58.6v3.1zM30.6 48.5v3zM31.6 53.6v3zM26.9 43.4h18.6zM26.9 46.4h18.6zM30.6 48.5h14.9zM30.6 51.5h14.9zM31.6 53.6h13.9zM31.6 56.6h13.9z"/>
<path d="M28.2 58.6h17.3zM32 41.4h13.5zM45.5 43.4l1.5 1.5zM47 44.9l-1.5 1.5zM45.5 48.5l1.5 1.5zM47 50l-1.5 1.5zM45.5 53.6l1.5 1.5zM45.5 56.6l1.5-1.5zM31.4 63.7v3zM32.4 71.3v3.1zM28.2 61.7h17.3zM31.4 63.7h14.1z"/>
<path d="M31.4 66.7h14.1zM32.4 71.3h13.1zM32.4 74.4h13.1zM45.5 58.6l1.5 1.6zM45.5 61.7l1.5-1.5zM45.5 63.7l1.5 1.5zM45.5 66.7l1.5-1.5zM45.5 71.3l1.5 1.5zM45.5 74.4l1.5-1.6zM382.2 65.2l1.5-1.5zM382.2 65.2l1.5 1.5zM383.7 63.7h11.7z"/>
<path d="M383.7 66.7h11.7zM395.4 63.7v3zM90.2 80.5l-1.3 1.9zM90.2 80.5l1.2 1.9zM114.7 90.6v5.1zM116.5 90.6v5.1zM114.7 90.6h1.8zM114.7 95.7h1.8zM382.2 83l1.5-1.5zM382.2 83l1.5 1.5zM383.7 81.5h11.8zM383.7 84.5h11.8z"/>
<path d="M383.7 99.2h11.7zM395.4 99.2v3.1zM395.5 81.5v3zM113.7 103.3h3.8zM148.6 110.9l-1.3 1.9zM147.7 118.6v5zM148.6 110.9l1.2 1.9zM147.7 118.6h1.8zM382.2 118.6l1.5-1.6zM382.2 118.6l1.5 1.5zM382.2 100.8l1.5-1.6zM382.2 100.8l1.5 1.5z"/>
<path d="M383.7 117h10.7zM383.7 102.3h11.7zM394.4 117v3.1zM146 138.9l-1.2 1.9zM149.5 118.6v5zM147.7 123.6h1.8zM199.4 133.8l-1.3 1.9zM199.4 133.8l1.2 1.9zM311.8 126.2h3.8zM382.2 136.3l1.5-1.5zM382.2 136.3l1.5 1.6zM382.2 132.5l1.5-1.5z"/>
<path d="M382.2 132.5l1.5 1.5zM383.7 134.8h8.4zM383.7 137.9h8.4zM383.7 138.6h7.6zM383.7 120.1h10.7zM383.7 131h11.7zM383.7 134h11.7zM391.3 138.6v3.1zM392.1 134.8v3.1zM395.4 131v3zM146 138.9l1.3 1.9zM151.1 144.8h5.1z"/>
<path d="M151.1 143.1v1.7zM152.8 150v3.1zM152.8 150h.8zM152.8 153.1h.8zM153.6 150v3.1zM151.1 143.1h5.1zM156.2 143.1v1.7zM382.2 140.1l1.5-1.5zM382.2 140.1l1.5 1.6zM382.2 147.8l1.5-1.6zM382.2 147.8l1.5 1.5zM382.2 151.6l1.5-1.6z"/>
<path d="M382.2 151.6l1.5 1.5zM382.2 155.4l1.5-1.5zM382.2 155.4l1.5 1.5zM382.2 159.2l1.5-1.5zM382.2 159.2l1.5 1.5zM382.2 144l1.5-1.6zM382.2 144l1.5 1.5zM383.7 141.7h7.6zM383.7 146.2h13.7zM383.7 149.3h13.7zM383.7 150h11.1zM383.7 153.1h11.1z"/>
<path d="M383.7 153.9h11.7zM383.7 156.9h11.7zM383.7 157.7h11.1zM383.7 142.4h11.7zM383.7 145.5h11.7zM394.8 150v3.1zM394.8 157.7v3zM395.4 153.9v3zM395.4 142.4v3.1zM397.4 146.2v3.1zM144.1 164.3h3.8zM146 171.9l-1.2 1.9z"/>
<path d="M146 171.9l1.3 1.9zM151.1 177.9h5.1zM151.1 176.1v1.8zM151.1 176.1h5.1zM156.2 176.1v1.8zM197.5 164.3h3.8zM383.7 160.7h11.1zM144.1 197.3h3.8zM152.8 183.1v3zM152.8 183.1h.8zM152.8 186.1h.8zM153.6 183.1v3z"/>
<path d="M309.2 189.7h3.8zM146 212.5l-1.2 1.9zM146 212.5l1.3 1.9zM151.1 218.5h5.1zM151.1 216.7v1.8zM151.1 216.7h5.1zM156.2 216.7v1.8zM199.4 207.4l-1.3 1.9zM199.4 207.4l1.2 1.9zM107.9 225.2l-1.2 1.9zM107.9 225.2l1.3 1.9zM132.4 235.4v5z"/>
<path d="M132.4 235.4h1.8zM144.1 237.9h3.8zM152.8 223.7v3zM152.8 223.7h.8zM152.8 226.7h.8zM153.6 223.7v3zM197.5 237.9h3.8zM95.2 245.5l-1.2 1.9zM95.2 245.5l1.3 1.9zM105.4 245.5l-1.3 1.9zM105.4 245.5l1.3 1.9zM131.4 248.1h3.8z"/>
<path d="M134.2 235.4v5zM132.4 240.4h1.8zM146 245.5l-1.2 1.9zM146 245.5l1.3 1.9zM151.1 251.5h5.1zM151.1 249.7v1.8zM152.8 256.7v3.1zM152.8 256.7h.8zM152.8 259.8h.8zM153.6 256.7v3.1zM151.1 249.7h5.1zM156.2 249.7v1.8z"/>
<path d="M313.7 249.3h86.3zM313.7 254.4h86.3zM313.7 259.5h58.4zM372.1 259.5h27.9zM372.1 259.5v5.1zM24.8 268.4h3.8zM103.5 268.4h3.8zM144.1 270.9h3.8zM250.8 268.4h3.8zM313.7 264.6h58.4zM313.7 269.7h86.3zM372.1 264.6h27.9z"/>
<path d="M400 268.4v1.3z"/>
</g>
<g fill="none" stroke="#000" stroke-width=".42">
<path d="M138.4 90.6a5.1 5.1 0 0 0 5.1 5.1M153.6 90.6a5.1 5.1 0 0 1-5 5.1M156.2 90.6a5.1 5.1 0 0 0 5.1 5.1 5.1 5.1 0 0 0 5-5.1M168.9 90.6a5.1 5.1 0 0 0 5.1 5.1 5.1 5.1 0 0 0 5-5.1M181.6 90.6a5.1 5.1 0 0 0 5.1 5.1 5.1 5.1 0 0 0 5-5.1M194.3 90.6a5.1 5.1 0 0 0 5.1 5.1 5.1 5.1 0 0 0 5-5.1M252.7 131.3a5.1 5.1 0 0 1 5.1 5 5.1 5.1 0 0 1-5.1 5.1M252.7 144a5.1 5.1 0 0 1 5.1 5 5.1 5.1 0 0 1-5.1 5.1M252.7 156.7a5.1 5.1 0 0 1 5.1 5 5.1 5.1 0 0 1-5.1 5.1M252.7 169.4a5.1 5.1 0 0 1 5.1 5 5.1 5.1 0 0 1-5.1 5.1M252.7 182.1a5.1 5.1 0 0 1 5.1 5 5.1 5.1 0 0 1-5.1 5.1M252.7 194.8a5.1 5.1 0 0 1 5.1 5 5.1 5.1 0 0 1-5.1 5.1"/>
<path d="M252.7 210a5.1 5.1 0 0 1 5.1 5 5.1 5.1 0 0 1-5.1 5.1M252.7 222.7a5.1 5.1 0 0 1 5.1 5 5.1 5.1 0 0 1-5.1 5.1M260.3 250.6a5.1 5.1 0 0 1 5.1 5.1M265.4 260.8a5.1 5.1 0 0 1-5.1 5"/>
</g>
<g fill="#000" stroke="#000" stroke-width=".42">
<path d="M321.3 60.2v10.1zM321.3 60.2l10.1 5zM321.3 70.3l10.1-5.1zM97.8 80.5v10.1zM97.8 80.5l10.1 5zM97.8 90.6l10.1-5.1zM143.5 95.7h5.1zM138.4 90.6h15.2zM156.2 90.6h10.1zM168.9 90.6h10.1zM181.6 90.6h10.1zM194.3 90.6h10.1z"/>
<path d="M321.3 77.9v10.2zM321.3 77.9l10.1 5.1zM321.3 88.1l10.1-5.1zM135.9 110.9h10.1zM321.3 95.7v10.2zM321.3 95.7l10.1 5.1zM321.3 105.9l10.1-5.1zM321.3 113.5l10.1 5.1zM321.3 123.6l10.1-5zM135.9 110.9l5 10.2zM146 110.9l-5.1 10.2zM252.7 131.3v10.1z"/>
<path d="M321.3 113.5v10.1zM252.7 144v10.1zM252.7 156.7v10.1zM252.7 169.4v10.1zM252.7 182.1v10.1zM252.7 194.8v10.1zM318.7 177v10.1zM318.7 177l10.2 5.1zM318.7 187.1l10.2-5zM252.7 210v10.1zM340.3 217.6v10.1zM340.3 217.6h55.9z"/>
<path d="M115.6 225.2v10.2zM115.6 225.2l10.1 5.1zM115.6 235.4l10.1-5.1zM252.7 222.7v10.1zM340.3 227.7v12.7zM340.3 227.7h55.9zM396.2 217.6v10.1zM340.3 240.4h55.9zM396.2 227.7v12.7zM260.3 250.6v15.2zM265.4 255.7v5.1z"/>
</g>
<g fill="none" stroke="#000" stroke-width=".25">
<circle cx="326.4" cy="61.7" r=".76"/>
<circle cx="326.4" cy="79.4" r=".76"/>
<circle cx="102.9" cy="82" r=".76"/>
<circle cx="161.3" cy="96.7" r=".99"/>
<circle cx="174" cy="96.7" r=".99"/>
<circle cx="186.7" cy="96.7" r=".99"/>
<circle cx="199.4" cy="96.7" r=".99"/>
<circle cx="326.4" cy="97.2" r=".76"/>
<circle cx="137.4" cy="116" r=".76"/>
<circle cx="326.4" cy="115" r=".76"/>
<circle cx="178.1" cy="138.9" r=".99"/>
<circle cx="258.8" cy="136.3" r="1"/>
<circle cx="258.8" cy="149" r="1"/>
<circle cx="317.7" cy="159.2" r="1"/>
<circle cx="178.1" cy="171.9" r=".99"/>
<circle cx="258.8" cy="161.7" r="1"/>
<circle cx="258.8" cy="174.4" r="1"/>
<circle cx="317.7" cy="161.7" r="1"/>
<circle cx="323.8" cy="178.5" r=".76"/>
<circle cx="258.8" cy="187.1" r="1"/>
<circle cx="258.8" cy="199.8" r="1"/>
<circle cx="178.1" cy="212.5" r=".99"/>
<circle cx="258.8" cy="215" r="1"/>
<circle cx="120.6" cy="226.7" r=".76"/>
<circle cx="258.8" cy="227.7" r="1"/>
<circle cx="178.1" cy="245.5" r=".99"/>
</g>
<path d="M16.5 18.2v260.3zM16.5 18.2h387.3zM16.5 278.5h387.3zM403.8 18.2v260.3z" fill="#000" stroke="#000" stroke-width=".32"/>
<g fill="#000" stroke="#000" stroke-width=".61">
<path d="M20.3 22.1v252.6zM20.3 22.1h379.7zM179 136.3v25.4zM179 136.3h15.3zM318.7 133.8v30.5zM318.7 133.8h15.3zM179 161.7h15.3zM179 169.4v25.4zM194.3 136.3v25.4zM179 169.4h15.3zM318.7 164.3h15.3zM334 133.8v30.5z"/>
<path d="M179 194.8h15.3zM194.3 169.4v25.4zM179 210v25.4zM179 210h15.3zM179 235.4h15.3zM194.3 210v25.4zM179 243v25.4zM179 243h15.3zM283.2 244.3v30.4zM313.7 254.4v5.1zM313.7 249.3v5.1zM313.7 244.3v5z"/>
<path d="M313.7 244.3h86.3zM283.2 244.3h30.5zM400 254.4v5.1zM400 249.3v5.1zM400 244.3v5zM400 22.1v222.2zM20.3 274.7h262.9zM179 268.4h15.3zM194.3 243v25.4zM283.2 274.7h30.5zM313.7 274.7h86.3zM313.7 269.7v5z"/>
<path d="M313.7 264.6v5.1zM313.7 259.5v5.1zM400 268.4v6.3zM400 264.6v3.8zM400 259.5v5.1z"/>
</g>
<g fill="#000" stroke="#000" stroke-width=".25">
<path d="M151.1 149.9h.9v3.3h-.9zM151.6 157.2h.5v4h-.5zM152.6 157.2h.5v4h-.5zM151.1 182.9h.9v3.3h-.9zM151.6 190.2h.5v4h-.5zM152.6 190.2h.5v4h-.5zM370.8 217.6h25.4v10.1h-25.4zM151.1 223.6h.9v3.3h-.9zM151.6 230.8h.5v4.1h-.5zM152.6 230.8h.5v4.1h-.5zM24.6 256.2h4.1v.5h-4.1zM24.6 257.2h4.1v.5h-4.1z"/>
<path d="M32.3 256.2h4v.5h-4zM32.3 257.2h4v.5h-4zM39.9 256.2h4v.5h-4zM39.9 257.2h4v.5h-4zM47.5 256.2h4.1v.5h-4.1zM47.5 257.2h4.1v.5h-4.1zM55.1 256.2h4.1v.5h-4.1zM55.1 257.2h4.1v.5h-4.1zM62.7 256.2h4.1v.5h-4.1zM62.7 257.2h4.1v.5h-4.1zM70.4 256.2h4v.5h-4zM70.4 257.2h4v.5h-4z"/>
<path d="M78 256.2h4v.5h-4zM78 257.2h4v.5h-4zM85.6 256.2h4.1v.5h-4.1zM85.6 257.2h4.1v.5h-4.1zM93.2 256.2h4.1v.5h-4.1zM93.2 257.2h4.1v.5h-4.1zM103.4 257.2h4v.5h-4zM103.4 256.2h4v.5h-4zM151.1 256.6h.9v3.3h-.9zM151.6 263.8h.5v4.1h-.5zM152.6 263.8h.5v4.1h-.5z"/>
</g>
<path d="M163.8 123.6h55.9zM219.7 123.6l5.1 5.1zM224.8 128.7v94zM214.6 151.6v111.7zM214.6 263.3l2.5 2.5zM217.1 265.8h12.7zM229.8 265.8l2.6-2.5zM232.4 141.4v121.9z" fill="#000" stroke="#000" stroke-width=".76"/>
<use href="#words"/>
</svg>
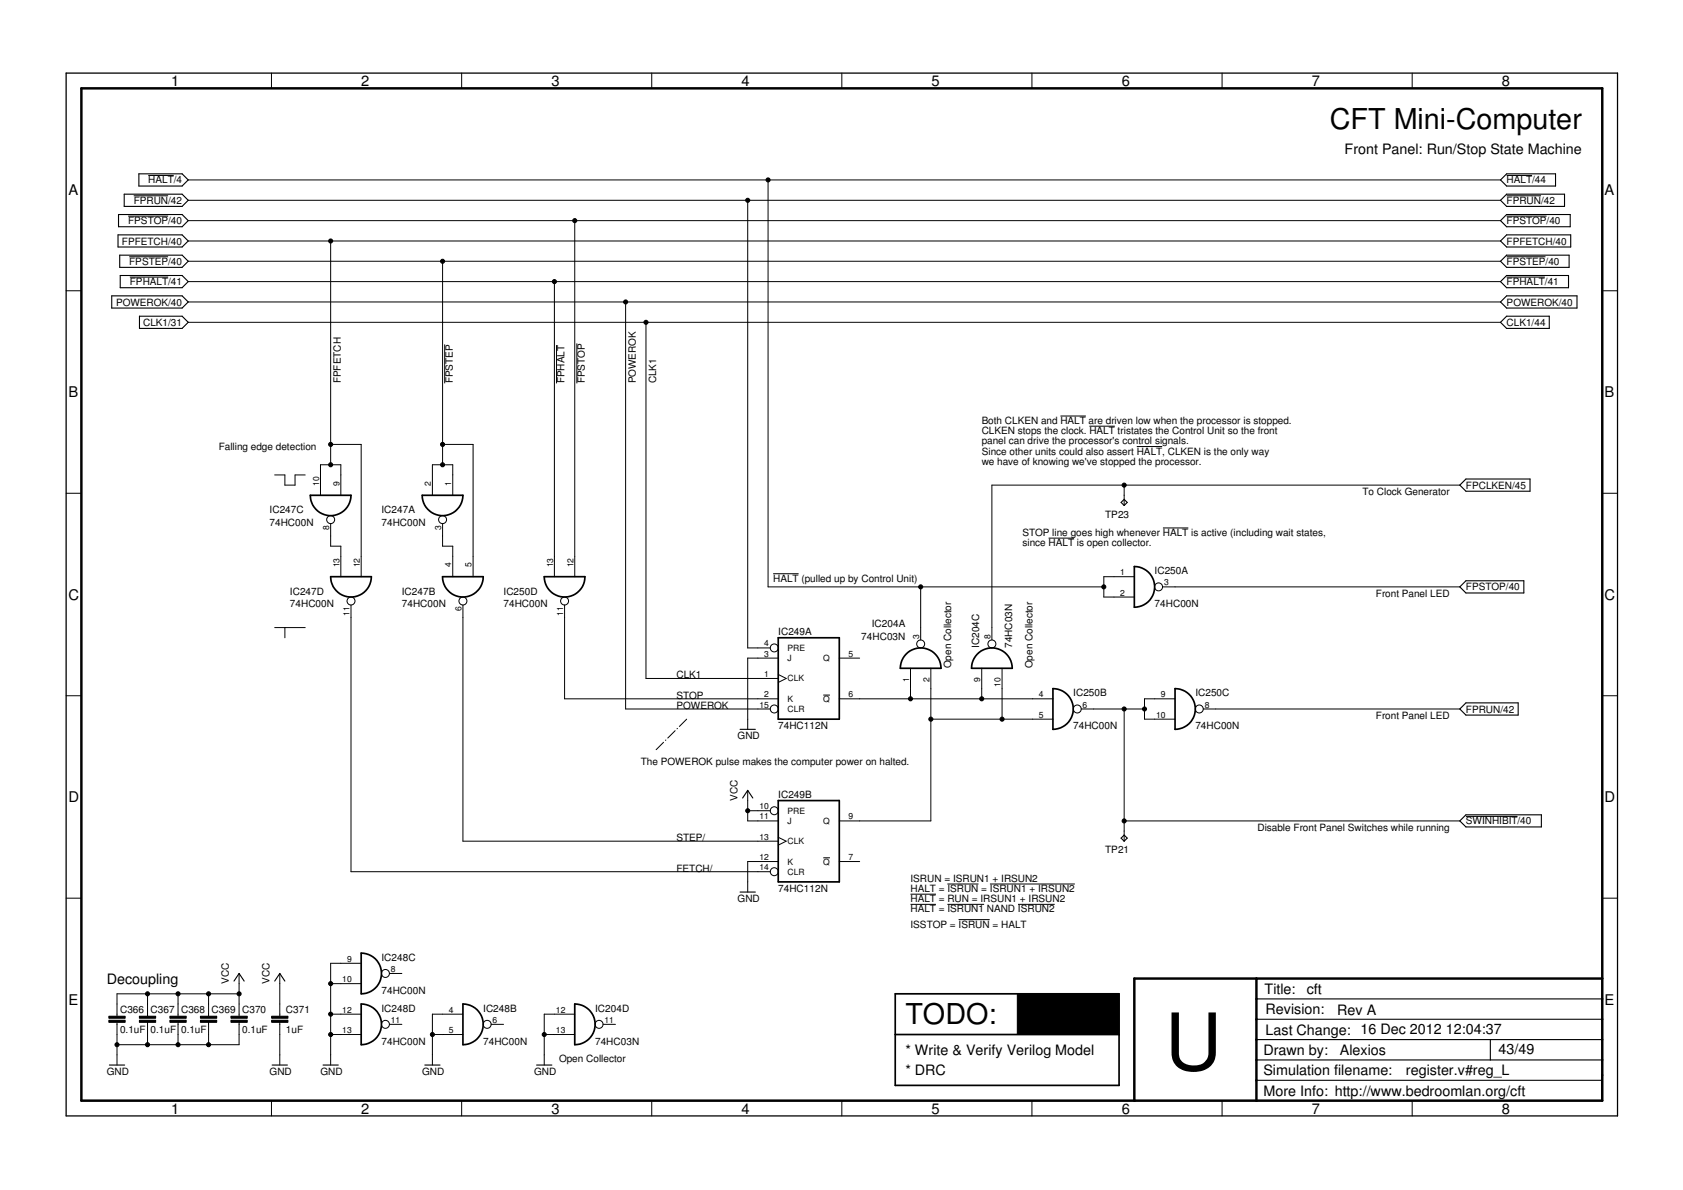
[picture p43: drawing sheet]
<svg xmlns="http://www.w3.org/2000/svg" width="420mm" height="297mm" viewBox="0 0 420 297" stroke-linecap="round" stroke-linejoin="round" font-family="sans-serif">
<defs><g id="words">
<text font-size="19.7" x="290.8" y="267.1">U</text>
<g font-size="7.2">
<text x="332" y="32.2">CFT Mini-Computer</text>
<text x="226" y="255.7">TODO:</text>
</g>
<g font-size="3.7">
<text x="42.7" y="21.5">1</text>
<text x="90.2" y="21.5">2</text>
<text x="137.7" y="21.5">3</text>
<text x="185.1" y="21.5">4</text>
<text x="232.6" y="21.5">5</text>
<text x="280" y="21.5">6</text>
<text x="327.5" y="21.5">7</text>
<text x="375" y="21.5">8</text>
<text x="17.1" y="48.6">A</text>
<text x="400.6" y="48.6">A</text>
<text x="17.1" y="99.2">B</text>
<text x="400.6" y="99.2">B</text>
<text x="17.1" y="149.7">C</text>
<text x="400.6" y="149.7">C</text>
<text x="17.1" y="200.2">D</text>
<text x="400.6" y="200.2">D</text>
<text x="17.1" y="250.8">E</text>
<text x="400.6" y="250.8">E</text>
<text x="42.7" y="277.9">1</text>
<text x="90.2" y="277.9">2</text>
<text x="137.7" y="277.9">3</text>
<text x="185.1" y="277.9">4</text>
<text x="232.6" y="277.9">5</text>
<text x="280" y="277.9">6</text>
<text x="327.5" y="277.9">7</text>
<text x="375" y="277.9">8</text>
</g>
<g font-size="3.6">
<text x="335.7" y="38.6">Front Panel: Run/Stop State Machine</text>
<text x="26.7" y="245.5">Decoupling</text>
<text x="315.7" y="248.1">Title:</text>
<text x="326.2" y="248.2">cft</text>
<text x="315.9" y="253.2">Revision:</text>
<text x="333.8" y="253.3">Rev A</text>
<text x="226" y="263.3">* Write &amp; Verify Verilog Model</text>
<text x="315.4" y="263.3">Drawn by:</text>
<text x="315.9" y="258.2">Last Change: 16 Dec 2012</text>
<text x="334.5" y="263.3">Alexios</text>
<text x="361" y="258.1">12:04:37</text>
<text x="374.1" y="263.2">43/49</text>
<text x="226" y="268.4">* DRC</text>
<text x="315.4" y="268.4">Simulation filename:</text>
<text x="351" y="268.4">register.v#reg_L</text>
<text x="315.4" y="273.5">More Info: http://www.bedroomlan.org/cft</text>
</g>
<g font-size="2.5">
<text x="37" y="45.8">HALT/4</text>
<text x="376.1" y="45.8">HALT/44</text>
<text x="33.4" y="50.9">FPRUN/42</text>
<text x="376.1" y="50.9">FPRUN/42</text>
<text x="32" y="56">FPSTOP/40</text>
<text x="376.1" y="56">FPSTOP/40</text>
<text x="30.5" y="61">FPFETCH/40</text>
<text x="376.1" y="61">FPFETCH/40</text>
<text x="32.3" y="66.1">FPSTEP/40</text>
<text x="32.4" y="71.2">FPHALT/41</text>
<text x="376.1" y="71.2">FPHALT/41</text>
<text x="376.1" y="66.1">FPSTEP/40</text>
<text x="29" y="76.3">POWEROK/40</text>
<text x="376.1" y="76.3">POWEROK/40</text>
<text x="35.7" y="81.3">CLK1/31</text>
<text x="376.1" y="81.3">CLK1/44</text>
<text x="85.1" y="95.7" transform="rotate(-90 85.1 95.7)">FPFETCH</text>
<text x="113" y="95.7" transform="rotate(-90 113 95.7)">FPSTEP</text>
<text x="141" y="95.7" transform="rotate(-90 141 95.7)">FPHALT</text>
<text x="146" y="95.7" transform="rotate(-90 146 95.7)">FPSTOP</text>
<text x="158.7" y="95.7" transform="rotate(-90 158.7 95.7)">POWEROK</text>
<text x="163.8" y="95.7" transform="rotate(-90 163.8 95.7)">CLK1</text>
<text x="245.1" y="105.9">Both CLKEN and HALT are driven low when the processor is stopped.</text>
<text x="54.6" y="112.2">Falling edge detection</text>
<text x="245.1" y="108.4">CLKEN stops the clock. HALT tristates the Control Unit so the front</text>
<text x="245.1" y="110.9">panel can drive the processor's control signals.</text>
<text x="245.1" y="113.5">Since other units could also assert HALT, CLKEN is the only way</text>
<text x="245.1" y="116">we have of knowing we've stopped the processor.</text>
<text x="340.2" y="123.6">To Clock Generator</text>
<text x="366" y="122">FPCLKEN/45</text>
<text x="67.3" y="131.3">74HC00N</text>
<text x="67.3" y="128.1">IC247C</text>
<text x="95.2" y="131.3">74HC00N</text>
<text x="95.2" y="128.1">IC247A</text>
<text x="275.9" y="129.2">TP23</text>
<text x="255.2" y="133.8">STOP line goes high whenever HALT is active (including wait states,</text>
<text x="255.2" y="136.3">since HALT is open collector.</text>
<text x="288.3" y="143.3">IC250A</text>
<text x="72.4" y="148.4">IC247D</text>
<text x="100.3" y="148.4">IC247B</text>
<text x="125.7" y="148.4">IC250D</text>
<text x="193" y="145.2">HALT (pulled up by Control Unit)</text>
<text x="343.5" y="149">Front Panel LED</text>
<text x="366" y="147.4">FPSTOP/40</text>
<text x="72.4" y="151.6">74HC00N</text>
<text x="100.3" y="151.6">74HC00N</text>
<text x="125.7" y="151.6">74HC00N</text>
<text x="288.3" y="151.6">74HC00N</text>
<text x="194.3" y="158.6">IC249A</text>
<text x="215" y="159.7">74HC03N</text>
<text x="217.7" y="156.5">IC204A</text>
<text x="244.4" y="161.7" transform="rotate(-90 244.4 161.7)">IC204C</text>
<text x="252.7" y="161.7" transform="rotate(-90 252.7 161.7)">74HC03N</text>
<text x="237.5" y="166.8" transform="rotate(-90 237.5 166.8)">Open Collector</text>
<text x="257.8" y="166.8" transform="rotate(-90 257.8 166.8)">Open Collector</text>
<text x="168.9" y="169.3">CLK1</text>
<text x="267.9" y="173.8">IC250B</text>
<text x="298.4" y="173.8">IC250C</text>
<text x="168.9" y="177">POWEROK</text>
<text x="168.9" y="174.4">STOP</text>
<text x="343.5" y="179.5">Front Panel LED</text>
<text x="366" y="177.9">FPRUN/42</text>
<text x="184.1" y="184.6">GND</text>
<text x="194.3" y="182">74HC112N</text>
<text x="267.9" y="182">74HC00N</text>
<text x="298.4" y="182">74HC00N</text>
<text x="160" y="190.9">The POWEROK pulse makes the computer power on halted.</text>
<text x="184.1" y="199.8" transform="rotate(-90 184.1 199.8)">VCC</text>
<text x="194.3" y="199.2">IC249B</text>
<text x="168.9" y="210">STEP/</text>
<text x="313.9" y="207.4">Disable Front Panel Switches while running</text>
<text x="366" y="205.8">SWINHIBIT/40</text>
<text x="275.9" y="213">TP21</text>
<text x="168.9" y="217.6">FETCH/</text>
<text x="227.3" y="220.1">ISRUN = ISRUN1 + IRSUN2</text>
<text x="184.1" y="225.2">GND</text>
<text x="194.3" y="222.7">74HC112N</text>
<text x="227.3" y="222.7">HALT = ISRUN = ISRUN1 + IRSUN2</text>
<text x="227.3" y="225.2">HALT = RUN = IRSUN1 + IRSUN2</text>
<text x="227.3" y="227.8">HALT = ISRUN1 NAND ISRUN2</text>
<text x="227.3" y="231.6">ISSTOP = ISRUN = HALT</text>
<text x="95.2" y="239.8">IC248C</text>
<text x="57.1" y="245.5" transform="rotate(-90 57.1 245.5)">VCC</text>
<text x="67.3" y="245.5" transform="rotate(-90 67.3 245.5)">VCC</text>
<text x="95.2" y="248.1">74HC00N</text>
<text x="30" y="257.9">0.1uF</text>
<text x="30" y="252.8">C366</text>
<text x="37.6" y="257.9">0.1uF</text>
<text x="37.6" y="252.8">C367</text>
<text x="45.2" y="257.9">0.1uF</text>
<text x="45.2" y="252.8">C368</text>
<text x="52.8" y="252.8">C369</text>
<text x="60.4" y="257.9">0.1uF</text>
<text x="60.4" y="252.8">C370</text>
<text x="71.4" y="257.9">1uF</text>
<text x="71.4" y="252.8">C371</text>
<text x="95.2" y="252.5">IC248D</text>
<text x="120.6" y="252.5">IC248B</text>
<text x="148.6" y="252.5">IC204D</text>
<text x="95.2" y="260.8">74HC00N</text>
<text x="120.6" y="260.8">74HC00N</text>
<text x="148.6" y="260.8">74HC03N</text>
<text x="26.7" y="268.4">GND</text>
<text x="67.3" y="268.4">GND</text>
<text x="80" y="268.4">GND</text>
<text x="105.4" y="268.4">GND</text>
<text x="133.3" y="268.4">GND</text>
<text x="139.6" y="265.1">Open Collector</text>
</g>
<g font-size="2.1">
<text x="79.6" y="121.3" transform="rotate(-90 79.6 121.3)">10</text>
<text x="84.7" y="121.3" transform="rotate(-90 84.7 121.3)">9</text>
<text x="107.6" y="121.3" transform="rotate(-90 107.6 121.3)">2</text>
<text x="112.7" y="121.3" transform="rotate(-90 112.7 121.3)">1</text>
<text x="82.2" y="132.2" transform="rotate(-90 82.2 132.2)">8</text>
<text x="110.1" y="132.2" transform="rotate(-90 110.1 132.2)">3</text>
<text x="84.7" y="141.6" transform="rotate(-90 84.7 141.6)">13</text>
<text x="89.8" y="141.6" transform="rotate(-90 89.8 141.6)">12</text>
<text x="112.7" y="141.6" transform="rotate(-90 112.7 141.6)">4</text>
<text x="117.7" y="141.6" transform="rotate(-90 117.7 141.6)">5</text>
<text x="138.1" y="141.6" transform="rotate(-90 138.1 141.6)">13</text>
<text x="143.1" y="141.6" transform="rotate(-90 143.1 141.6)">12</text>
<text x="279.7" y="143.6">1</text>
<text x="279.7" y="148.7">2</text>
<text x="290.6" y="146.1">3</text>
<text x="87.3" y="153.7" transform="rotate(-90 87.3 153.7)">11</text>
<text x="115.2" y="152.6" transform="rotate(-90 115.2 152.6)">6</text>
<text x="140.6" y="153.7" transform="rotate(-90 140.6 153.7)">11</text>
<text x="190.8" y="161.4">4</text>
<text x="229.5" y="159.4" transform="rotate(-90 229.5 159.4)">3</text>
<text x="247.3" y="159.4" transform="rotate(-90 247.3 159.4)">8</text>
<text x="190.8" y="163.9">3</text>
<text x="196.6" y="165">J</text>
<text x="196.6" y="162.5">PRE</text>
<text x="205.5" y="165">Q</text>
<text x="211.9" y="163.9">5</text>
<text x="190.8" y="169">1</text>
<text x="196.6" y="170.1">CLK</text>
<text x="226.9" y="170.3" transform="rotate(-90 226.9 170.3)">1</text>
<text x="232" y="170.3" transform="rotate(-90 232 170.3)">2</text>
<text x="244.7" y="170.3" transform="rotate(-90 244.7 170.3)">9</text>
<text x="249.8" y="171.5" transform="rotate(-90 249.8 171.5)">10</text>
<text x="189.6" y="176.6">15</text>
<text x="190.8" y="174.1">2</text>
<text x="196.6" y="175.2">K</text>
<text x="196.6" y="177.7">CLR</text>
<text x="205.5" y="175.2">Q</text>
<text x="211.9" y="174.1">6</text>
<text x="259.3" y="174.1">4</text>
<text x="259.3" y="179.1">5</text>
<text x="270.3" y="176.6">6</text>
<text x="288.6" y="179.1">10</text>
<text x="289.8" y="174.1">9</text>
<text x="300.8" y="176.6">8</text>
<text x="189.6" y="202">10</text>
<text x="196.6" y="203.1">PRE</text>
<text x="189.6" y="209.6">13</text>
<text x="189.6" y="204.5">11</text>
<text x="196.6" y="205.7">J</text>
<text x="205.5" y="205.7">Q</text>
<text x="211.9" y="204.5">9</text>
<text x="189.6" y="214.7">12</text>
<text x="196.6" y="210.7">CLK</text>
<text x="196.6" y="215.8">K</text>
<text x="205.5" y="215.8">Q</text>
<text x="211.9" y="214.7">7</text>
<text x="189.6" y="217.2">14</text>
<text x="196.6" y="218.4">CLR</text>
<text x="85.5" y="245.2">10</text>
<text x="86.6" y="240.1">9</text>
<text x="97.6" y="242.6">8</text>
<text x="85.5" y="252.8">12</text>
<text x="85.5" y="257.9">13</text>
<text x="97.6" y="255.3">11</text>
<text x="112" y="252.8">4</text>
<text x="112" y="257.9">5</text>
<text x="123" y="255.3">6</text>
<text x="138.8" y="252.8">12</text>
<text x="138.8" y="257.9">13</text>
<text x="150.9" y="255.3">11</text>
</g>
</g></defs>
<g fill="#000" stroke="#000" stroke-width=".25">
<path d="M67.8 18.2v3.9zM115.3 18.2v3.9zM162.7 18.2v3.9zM210.2 18.2v3.9zM257.6 18.2v3.9zM305.1 18.2v3.9zM352.5 18.2v3.9zM20.3 22.1v252.6zM20.3 22.1h379.7zM32 54h10zM33.4 48.9h8.6zM37 43.8h6.4z"/>
<path d="M47 50h139.7zM47 55.1h96.5zM47 44.9h144.7zM143.5 55.1h231.1zM186.7 50v111.7zM186.7 50h187.9zM191.7 44.9v101.6zM191.7 44.9h182.9zM376.1 48.9h8.6zM376.1 54h10zM376.1 43.8h6.4zM16.5 72.6h3.8z"/>
<path d="M32.3 64.1h9.7zM32.4 69.2h9.6zM47 70.3h91.4zM47 65.2h63.5zM47 60.2h35.5zM82.5 60.2h292.1zM110.5 65.2v45.7zM110.5 65.2h264.1zM138.4 70.3v68.6zM138.4 70.3h236.2zM47 75.4h109.2zM156.2 75.4h218.4z"/>
<path d="M376.1 69.2h9.6zM376.1 64.1h9.7zM400 72.6h3.8zM111 86v9.7zM138.9 86.1v9.6zM144 85.7v10zM47 80.5h114.3zM161.3 80.5v88.9zM161.3 80.5h213.3zM68.6 118.6h2.5zM71.1 118.6v2.5zM73.7 118.6h2.5z"/>
<path d="M80 118.6v5zM80 116v2.6zM80 116h2.5zM82.5 110.9v5.1zM82.5 60.2v50.7zM85.1 118.6v5zM85.1 116v2.6zM82.5 116h2.6zM82.5 110.9h7.7zM107.9 118.6v5zM107.9 116v2.6zM110.5 110.9v5.1z"/>
<path d="M107.9 116h2.6zM113 118.6v5zM113 116v2.6zM110.5 116h2.5zM110.5 110.9h7.6zM264.7 103.8h6.4zM272 106.4h6.3zM283.8 111.5h6.3zM16.5 123.1h3.8zM71.1 121.1h2.6zM73.7 118.6v2.5zM82.5 130.7v3.1z"/>
<path d="M82.5 133.8v2.5zM85.1 138.9v5.1zM85.1 136.3v2.6zM82.5 136.3h2.6zM90.2 138.9v5.1zM90.2 110.9v28zM110.5 130.7v3.1zM110.5 133.8v2.5zM113 138.9v5.1zM113 136.3v2.6zM110.5 136.3h2.5zM118.1 138.9v5.1z"/>
<path d="M118.1 110.9v28zM138.4 138.9v5.1zM143.5 138.9v5.1zM143.5 55.1v83.8zM247.6 121.1h33zM261.8 134.3h6.3zM280.6 123.6v2.6zM280.6 121.1h83.8zM280.6 121.1v2.5zM290.3 131.8h6.4zM400 123.1h3.8zM68.6 156.7h2.5z"/>
<path d="M71.1 156.7v2.5zM71.1 156.7h5.1zM87.6 151v3.1zM87.6 154.1v63.5zM115.6 151v3.1zM140.9 151v3.1zM191.7 146.5h38.1zM193 143.2h6.4zM229.8 156.7v3zM229.8 146.5v10.2zM229.8 146.5h45.8zM247.6 156.7v3z"/>
<path d="M247.6 121.1v35.6zM275.6 144v2.5zM275.6 146.5v2.5zM275.6 149h2.5zM275.6 144h2.5zM278.1 144h5.1zM278.1 149h5.1zM290.2 146.5h3.1zM293.3 146.5h71.1zM16.5 173.7h3.8zM140.9 154.1v20.3zM156.2 75.4v101.6z"/>
<path d="M171.4 179.5l-1.8 1.8zM186.7 179.5v2.6zM186.7 164.3v15.2zM186.7 161.7h2.5zM189.2 169.4h5.1zM189.2 174.4h5.1zM189.2 164.3h5.1zM189.2 161.7h3.1zM189.2 177h3.1zM186.7 164.3h2.5zM161.3 169.4h27.9zM156.2 177h33z"/>
<path d="M140.9 174.4h48.3zM194.3 168.4l2 1zM194.3 170.3l2-.9zM205.5 173.5h1.7zM209.5 164.3h5.1zM209.5 174.4h5.1zM214.6 174.4h12.7zM227.3 166.8v5.1zM227.3 171.9v2.5zM232.4 166.8v5.1zM232.4 171.9v7.6zM245.1 166.8v5.1z"/>
<path d="M227.3 174.4h17.8zM245.1 171.9v2.5zM250.2 166.8v5.1zM232.4 179.5h17.8zM250.2 171.9v7.6zM257.8 174.4h5.1zM257.8 179.5h5.1zM245.1 174.4h12.7zM250.2 179.5h7.6zM269.9 177h3.1zM273 177h7.6zM280.6 177h5.1z"/>
<path d="M280.6 177v27.9zM285.7 174.4v2.6zM285.7 177v2.5zM285.7 179.5h2.6zM288.3 174.4h5zM288.3 179.5h5zM285.7 174.4h2.6zM300.4 177h3.1zM303.5 177h60.9zM400 173.7h3.8zM163.8 187.1l1.8-1.8zM168.5 182.4l-1.8 1.8z"/>
<path d="M169.1 181.8l-.1 .1zM186.7 197.3v2.5zM115.6 154.1v55.9zM186.7 215v5.1zM186.7 202.4v2.5zM186.7 199.8v2.6zM189.2 210h5.1zM189.2 215h5.1zM189.2 204.9h5.1zM189.2 202.4h3.1zM189.2 217.6h3.1zM186.7 215h2.5z"/>
<path d="M186.7 204.9h2.5zM186.7 202.4h2.5zM87.6 217.6h101.6zM115.6 210h73.6zM194.3 209l2 1zM194.3 211l2-1zM205.5 214.1h1.7zM209.5 204.9h5.1zM209.5 215h5.1zM214.6 204.9h17.8zM232.4 179.5v25.4zM280.6 207.4v2.6z"/>
<path d="M280.6 204.9h83.8zM280.6 204.9v2.5zM366 203.8h12.8zM16.5 224.2h3.8zM186.7 220.1v2.6zM227.3 223.2h6.4zM227.3 225.7h6.4zM236.5 220.7h7.8zM236.5 225.7h9.2zM239.3 229.5h7.8zM247.1 220.7h21.2zM254.1 225.7h9.2z"/>
<path d="M400 224.2h3.8zM29.2 255.7v2.5zM29.2 250.6v2.5zM29.2 255.2v.5zM29.2 253.1v.6zM29.2 258.2v2.6zM29.2 248.1v2.5zM36.8 255.7v2.5zM36.8 250.6v2.5zM36.8 255.2v.5zM36.8 253.1v.6zM36.8 248.1v2.5z"/>
<path d="M29.2 248.1h7.6zM44.4 255.7v2.5zM44.4 250.6v2.5zM44.4 255.2v.5zM44.4 253.1v.6zM36.8 248.1h7.6zM44.4 248.1v2.5zM52.1 255.7v2.5zM52.1 250.6v2.5zM52.1 255.2v.5zM52.1 253.1v.6zM44.4 248.1h7.7z"/>
<path d="M52.1 248.1v2.5zM59.7 243v2.5zM59.7 255.7v2.5zM59.7 250.6v2.5zM59.7 255.2v.5zM59.7 253.1v.6zM52.1 248.1h7.6zM59.7 245.5v2.6zM59.7 248.1v2.5zM69.8 243v2.5zM69.8 250.6v2.5zM69.8 255.7v2.5z"/>
<path d="M69.8 253.1v.6zM69.8 255.2v.5zM69.8 245.5v5.1zM82.5 240.4v5.1zM82.5 245.5v7.6zM82.5 253.1v5.1zM82.5 258.2v5.1zM85.1 240.4h5.1zM85.1 245.5h5.1zM85.1 253.1h5.1zM85.1 258.2h5.1zM82.5 240.4h2.6z"/>
<path d="M82.5 245.5h2.6zM82.5 253.1h2.6zM82.5 258.2h2.6zM97.2 243h3.1zM97.2 255.7h3.1zM107.9 253.1v5.1zM110.5 253.1h5.1zM110.5 258.2h5.1zM107.9 253.1h2.6zM107.9 258.2h2.6zM122.6 255.7h3.1zM135.9 253.1v5.1z"/>
<path d="M135.9 258.2v5.1zM138.4 253.1h5.1zM138.4 258.2h5.1zM135.9 253.1h2.5zM135.9 258.2h2.5zM150.6 255.7h3zM20.3 274.7h379.7zM29.2 263.3v2.5zM29.2 260.8h7.6zM29.2 260.8v2.5zM36.8 258.2v2.6zM36.8 260.8h7.6z"/>
<path d="M44.4 258.2v2.6zM44.4 260.8h7.7zM52.1 258.2v2.6zM52.1 260.8h7.6zM59.7 258.2v2.6zM67.8 274.7v3.8zM69.8 263.3v2.5zM69.8 258.2v5.1zM82.5 263.3v2.5zM107.9 263.3v2.5zM107.9 258.2v5.1zM115.3 274.7v3.8z"/>
<path d="M135.9 263.3v2.5zM162.7 274.7v3.8zM210.2 274.7v3.8zM257.6 274.7v3.8zM305.1 274.7v3.8zM352.5 274.7v3.8zM400 264.5v.1zM400 268.4v6.2zM400 274.6h.1zM400 22.1v252.6z"/>
<circle cx="143.5" cy="55.1" r=".51"/>
<circle cx="186.7" cy="50" r=".51"/>
<circle cx="191.7" cy="44.9" r=".51"/>
<circle cx="82.5" cy="60.2" r=".51"/>
<circle cx="110.5" cy="65.2" r=".51"/>
<circle cx="138.4" cy="70.3" r=".51"/>
<circle cx="156.2" cy="75.4" r=".51"/>
<circle cx="161.3" cy="80.5" r=".51"/>
<circle cx="82.5" cy="110.9" r=".51"/>
<circle cx="82.5" cy="116" r=".51"/>
<circle cx="110.5" cy="110.9" r=".51"/>
<circle cx="110.5" cy="116" r=".51"/>
<circle cx="280.6" cy="121.1" r=".51"/>
<circle cx="229.8" cy="146.5" r=".51"/>
<circle cx="275.6" cy="146.5" r=".51"/>
<circle cx="227.3" cy="174.4" r=".51"/>
<circle cx="232.4" cy="179.5" r=".51"/>
<circle cx="245.1" cy="174.4" r=".51"/>
<circle cx="250.2" cy="179.5" r=".51"/>
<circle cx="280.6" cy="177" r=".51"/>
<circle cx="285.7" cy="177" r=".51"/>
<circle cx="186.7" cy="202.4" r=".51"/>
<circle cx="280.6" cy="204.9" r=".51"/>
<circle cx="36.8" cy="248.1" r=".51"/>
<circle cx="44.4" cy="248.1" r=".51"/>
<circle cx="52.1" cy="248.1" r=".51"/>
<circle cx="59.7" cy="248.1" r=".51"/>
<circle cx="82.5" cy="253.1" r=".51"/>
<circle cx="82.5" cy="245.5" r=".51"/>
<circle cx="82.5" cy="258.2" r=".51"/>
<circle cx="107.9" cy="258.2" r=".51"/>
<circle cx="135.9" cy="258.2" r=".51"/>
<circle cx="29.2" cy="260.8" r=".51"/>
<circle cx="36.8" cy="260.8" r=".51"/>
<circle cx="44.4" cy="260.8" r=".51"/>
<circle cx="52.1" cy="260.8" r=".51"/>
</g>
<g fill="#000" stroke="#000" stroke-width=".28">
<path d="M29.5 58.6v3.1zM29.6 53.6v3zM31 48.5v3zM34.7 43.4v3zM31 48.5h14.5zM31 51.5h14.5zM29.6 53.6h15.9zM29.6 56.6h15.9zM34.7 43.4h10.8zM34.7 46.4h10.8zM29.5 58.6h16zM45.5 48.5l1.5 1.5z"/>
<path d="M47 50l-1.5 1.5zM45.5 53.6l1.5 1.5zM45.5 56.6l1.5-1.5zM45.5 43.4l1.5 1.5zM47 44.9l-1.5 1.5zM374.6 50l1.5-1.5zM374.6 50l1.5 1.5zM374.6 55.1l1.5-1.5zM374.6 55.1l1.5 1.5zM374.6 44.9l1.5-1.5zM374.6 44.9l1.5 1.5zM376.1 48.5h14.5z"/>
<path d="M376.1 51.5h14.5zM376.1 53.6h15.9zM376.1 56.6h15.9zM376.1 43.4h12.2zM376.1 46.4h12.2zM376.1 58.6h16zM388.3 43.4v3zM390.6 48.5v3zM392 53.6v3zM392.1 58.6v3.1zM27.9 73.8v3.1zM29.9 63.7v3z"/>
<path d="M30 68.8v3zM30 68.8h15.5zM30 71.8h15.5zM29.5 61.7h16zM29.9 63.7h15.6zM29.9 66.7h15.6zM34.8 78.9h10.7zM27.9 76.9h17.6zM27.9 73.8h17.6zM45.5 68.8l1.5 1.5zM47 70.3l-1.5 1.5zM45.5 58.6l1.5 1.6z"/>
<path d="M45.5 61.7l1.5-1.5zM45.5 63.7l1.5 1.5zM45.5 66.7l1.5-1.5zM47 75.4l-1.5 1.5zM45.5 73.8l1.5 1.6zM374.6 70.3l1.5-1.5zM374.6 70.3l1.5 1.5zM374.6 60.2l1.5-1.6zM374.6 60.2l1.5 1.5zM374.6 65.2l1.5-1.5zM374.6 65.2l1.5 1.5zM374.6 75.4l1.5-1.6z"/>
<path d="M374.6 75.4l1.5 1.5zM376.1 68.8h15.5zM376.1 71.8h15.5zM376.1 61.7h16zM376.1 63.7h15.6zM376.1 66.7h15.6zM376.1 78.9h10.7zM376.1 73.8h17.6zM376.1 76.9h17.6zM386.8 78.9v3.1zM391.6 68.8v3zM391.7 63.7v3z"/>
<path d="M393.7 73.8v3.1zM34.8 78.9v3.1zM34.8 82h10.7zM47 80.5l-1.5 1.5zM45.5 78.9l1.5 1.6zM374.6 80.5l1.5-1.6zM374.6 80.5l1.5 1.5zM376.1 82h10.7zM366 119.6h16zM382 119.6v3zM279.9 125.4l.7-.8zM279.9 125.4l.7 .8z"/>
<path d="M280.6 124.6l.8 .8zM280.6 126.2l.8-.8zM364.4 121.1l1.6-1.5zM364.4 121.1l1.6 1.5zM366 122.6h16zM364.4 146.5l1.6-1.5zM364.4 146.5l1.6 1.5zM366 145h14.4zM366 148h14.4zM380.4 145v3zM364.4 177l1.6-1.6zM364.4 177l1.6 1.5z"/>
<path d="M366 175.4h13zM366 178.5h13zM379 175.4v3.1zM184.8 182.1h3.8zM186.7 197.3l-1.3 1.9zM186.7 197.3l1.2 1.9zM279.9 209.2l.7-.8zM279.9 209.2l.7 .8zM280.6 208.4l.8 .8zM281.4 209.2l-.8 .8zM364.4 204.9l1.6-1.5zM364.4 204.9l1.6 1.5z"/>
<path d="M366 203.4h18.8zM366 206.4h18.8zM384.8 203.4v3zM184.8 222.7h3.8zM59.7 243l-1.3 1.9zM59.7 243l1.3 1.9zM69.8 243l-1.2 1.9zM69.8 243l1.3 1.9zM313.7 249.3h86.3zM313.7 254.4h86.3zM313.7 259.5h58.4zM372.1 259.5h27.9z"/>
<path d="M372.1 259.5v5.1zM27.3 265.8h3.8zM67.9 265.8h3.9zM80.6 265.8h3.9zM106 265.8h3.9zM134 265.8h3.8zM313.7 264.6h58.4zM313.7 269.7h86.3zM372.1 264.6h27.9zM400 268.4v1.3z"/>
</g>
<g fill="none" stroke="#000" stroke-width=".25">
<circle cx="82.5" cy="129.7" r=".99"/>
<circle cx="110.5" cy="129.7" r=".99"/>
<circle cx="87.6" cy="150" r=".99"/>
<circle cx="115.6" cy="150" r=".99"/>
<circle cx="140.9" cy="150" r=".99"/>
<circle cx="289.2" cy="146.5" r="1"/>
<circle cx="193.3" cy="177" r=".99"/>
<circle cx="193.3" cy="161.7" r=".99"/>
<circle cx="229.8" cy="160.7" r="1"/>
<circle cx="247.6" cy="160.7" r="1"/>
<circle cx="268.9" cy="177" r="1"/>
<circle cx="299.4" cy="177" r="1"/>
<circle cx="193.3" cy="217.6" r=".99"/>
<circle cx="193.3" cy="202.4" r=".99"/>
<circle cx="96.2" cy="255.7" r=".99"/>
<circle cx="96.2" cy="243" r=".99"/>
<circle cx="121.6" cy="255.7" r=".99"/>
<circle cx="149.6" cy="255.7" r=".99"/>
</g>
<g fill="#000" stroke="#000" stroke-width=".42">
<path d="M77.5 123.6h10.1zM105.4 123.6h10.2zM82.5 144h10.2zM110.5 144h10.1zM135.9 144h10.1zM194.3 159.2v20.3zM194.3 159.2h15.2zM283.2 141.4v10.2zM194.3 179.5h15.2zM209.5 159.2v20.3zM224.8 166.8h10.1zM242.5 166.8h10.2z"/>
<path d="M262.9 171.9v10.2zM293.3 171.9v10.2zM194.3 199.8v20.3zM194.3 199.8h15.2zM90.2 237.9v10.2zM194.3 220.1h15.2zM209.5 199.8v20.3zM90.2 250.6v10.2zM115.6 250.6v10.2zM143.5 250.6v10.2zM223.5 248.1v10.1zM223.5 258.2v12.7z"/>
<path d="M223.5 258.2h55.9zM279.4 248.1v10.1zM223.5 248.1h55.9zM223.5 270.9h55.9zM279.4 258.2v12.7z"/>
</g>
<g fill="none" stroke="#000" stroke-width=".42">
<path d="M77.5 123.6a5.1 5.1 0 0 0 5 5.1 5.1 5.1 0 0 0 5.1-5.1M105.4 123.6a5.1 5.1 0 0 0 5.1 5.1 5.1 5.1 0 0 0 5.1-5.1M82.5 144a5.1 5.1 0 0 0 5.1 5 5.1 5.1 0 0 0 5.1-5M110.5 144a5.1 5.1 0 0 0 5.1 5 5.1 5.1 0 0 0 5-5M135.9 144a5.1 5.1 0 0 0 5 5 5.1 5.1 0 0 0 5.1-5M283.2 141.4a5.1 5.1 0 0 1 5.1 5.1 5.1 5.1 0 0 1-5.1 5.1M224.8 166.8a5.1 5.1 0 0 1 5-5.1 5.1 5.1 0 0 1 5.1 5.1M242.5 166.8a5.1 5.1 0 0 1 5.1-5.1 5.1 5.1 0 0 1 5.1 5.1M262.9 171.9a5.1 5.1 0 0 1 5 5.1 5.1 5.1 0 0 1-5 5.1M293.3 171.9a5.1 5.1 0 0 1 5.1 5.1 5.1 5.1 0 0 1-5.1 5.1M90.2 237.9a5.1 5.1 0 0 1 5 5.1 5.1 5.1 0 0 1-5 5.1M90.2 250.6a5.1 5.1 0 0 1 5 5.1 5.1 5.1 0 0 1-5 5.1"/>
<path d="M115.6 250.6a5.1 5.1 0 0 1 5 5.1 5.1 5.1 0 0 1-5 5.1M143.5 250.6a5.1 5.1 0 0 1 5.1 5.1 5.1 5.1 0 0 1-5.1 5.1"/>
</g>
<path d="M16.5 18.2v260.3zM16.5 18.2h387.3zM16.5 278.5h387.3zM403.8 18.2v260.3z" fill="#000" stroke="#000" stroke-width=".32"/>
<g fill="#000" stroke="#000" stroke-width=".61">
<path d="M20.3 22.1v252.6zM20.3 22.1h379.7zM283.2 244.3v30.4zM313.7 254.4v5.1zM313.7 249.3v5.1zM313.7 244.3v5zM313.7 244.3h86.3zM283.2 244.3h30.5zM400 254.4v5.1zM400 249.3v5.1zM400 244.3v5zM400 22.1v222.2z"/>
<path d="M20.3 274.7h262.9zM283.2 274.7h30.5zM313.7 274.7h86.3zM313.7 269.7v5zM313.7 264.6v5.1zM313.7 259.5v5.1zM400 268.4v6.3zM400 264.6v3.8zM400 259.5v5.1z"/>
</g>
<g fill="#000" stroke="#000" stroke-width=".25">
<path d="M27.2 253.7h4v.5h-4zM27.2 254.7h4v.5h-4zM34.8 253.7h4.1v.5h-4.1zM34.8 254.7h4.1v.5h-4.1zM42.4 253.7h4.1v.5h-4.1zM42.4 254.7h4.1v.5h-4.1zM50 253.7h4.1v.5h-4.1zM50 254.7h4.1v.5h-4.1zM57.7 253.7h4v.5h-4zM57.7 254.7h4v.5h-4zM67.8 254.7h4.1v.5h-4.1zM67.8 253.7h4.1v.5h-4.1z"/>
<path d="M254 248.1h25.4v10.1h-25.4z"/>
</g>
<use href="#words"/>
</svg>
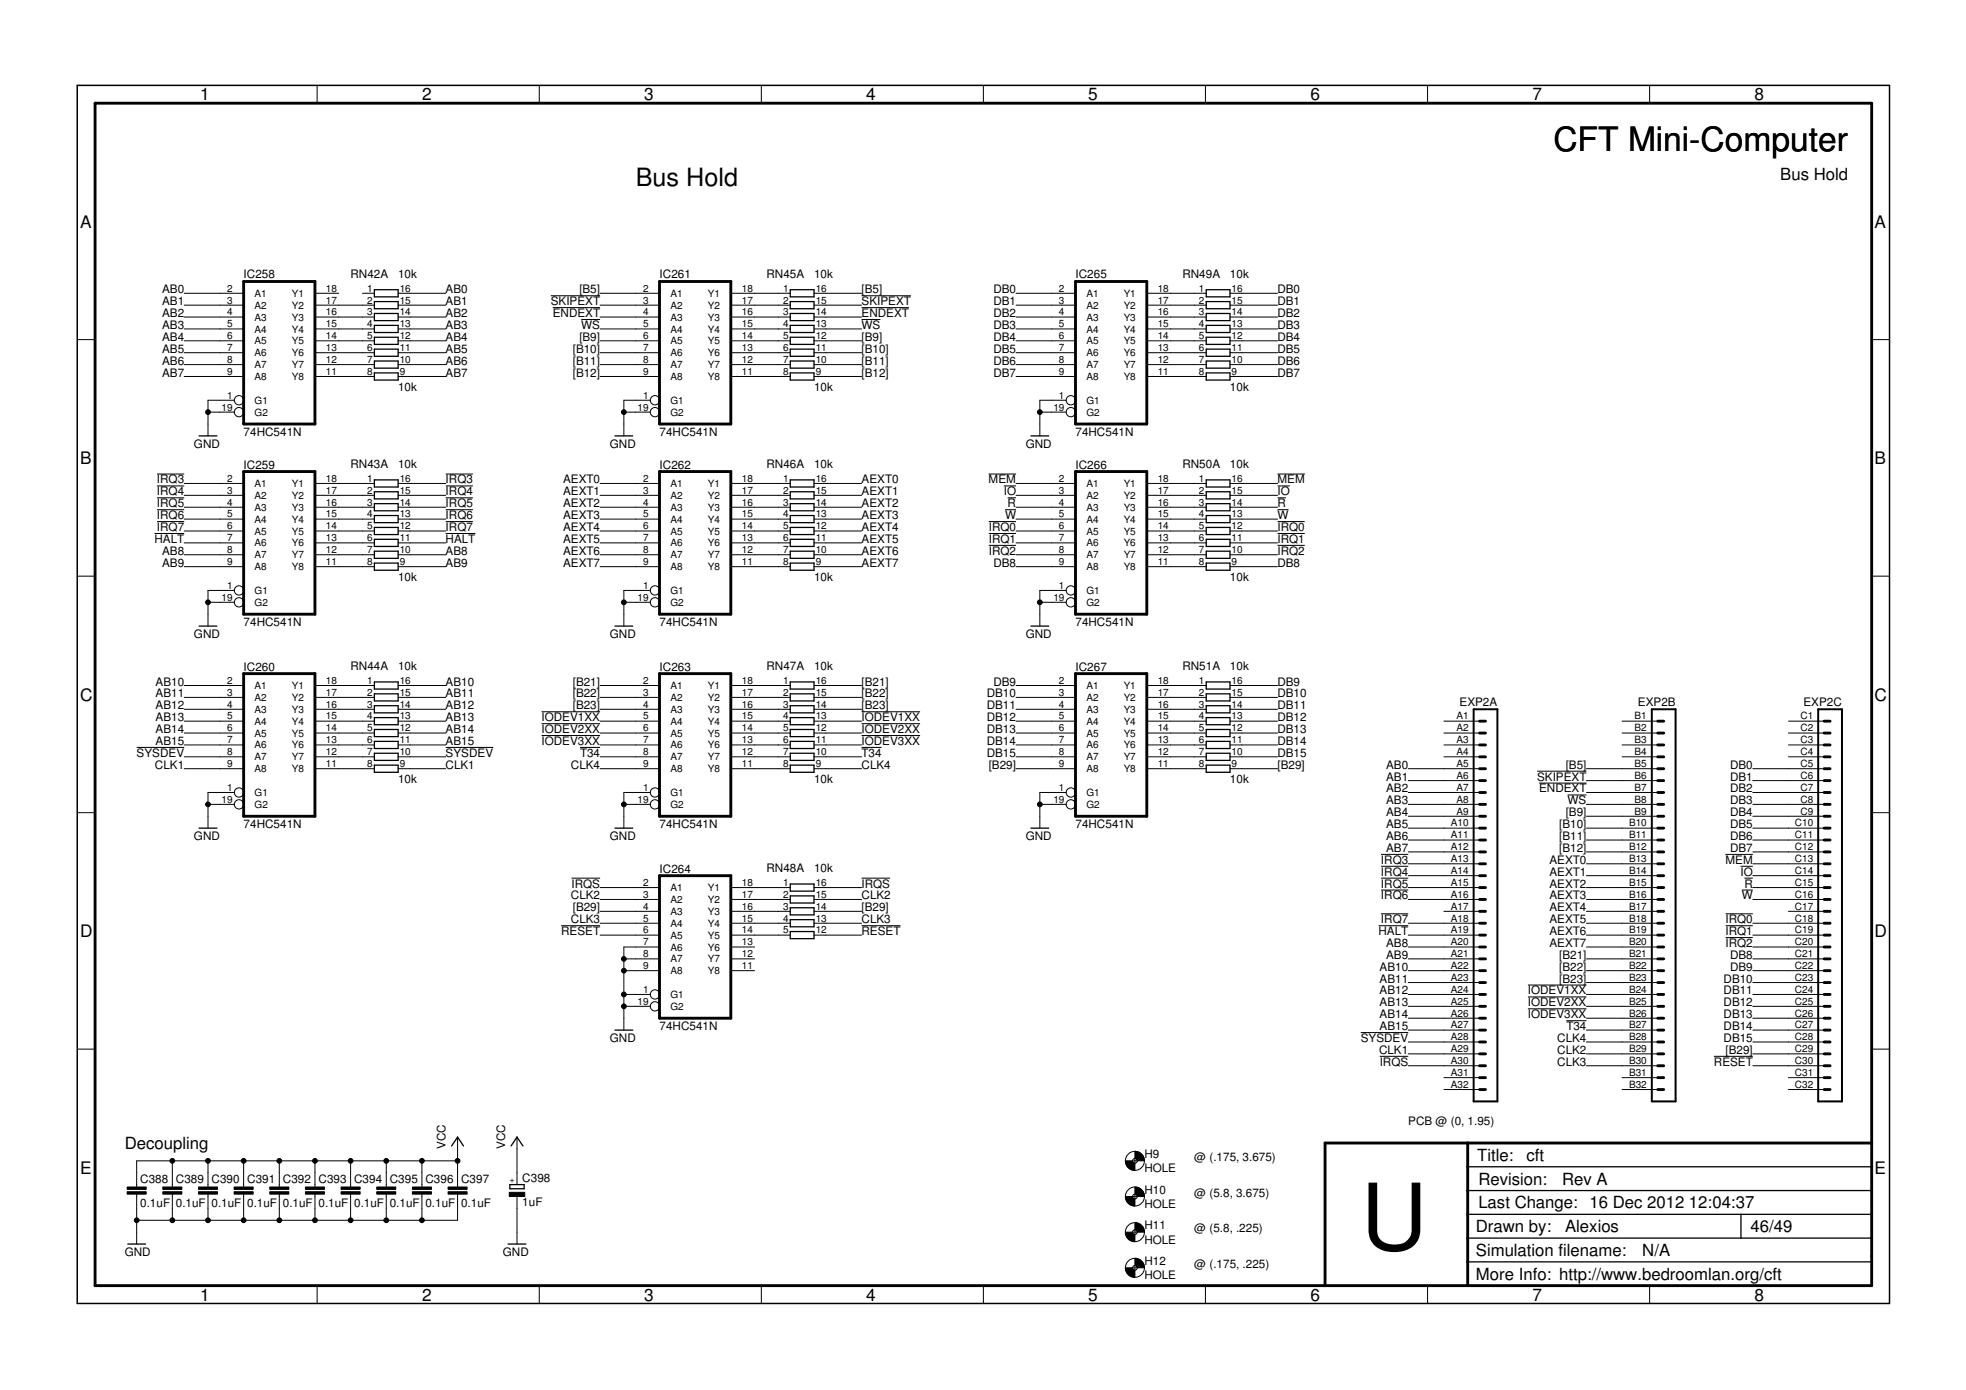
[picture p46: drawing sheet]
<svg xmlns="http://www.w3.org/2000/svg" width="420mm" height="297mm" viewBox="0 0 420 297" stroke-linecap="round" stroke-linejoin="round" font-family="sans-serif">
<defs><g id="words">
<text font-size="19.7" x="290.8" y="267.1">U</text>
<text font-size="7.2" x="332" y="32.2">CFT Mini-Computer</text>
<text font-size="5.4" x="135.9" y="39.8">Bus Hold</text>
<g font-size="3.7">
<text x="42.7" y="21.5">1</text>
<text x="90.2" y="21.5">2</text>
<text x="137.7" y="21.5">3</text>
<text x="185.1" y="21.5">4</text>
<text x="232.6" y="21.5">5</text>
<text x="280" y="21.5">6</text>
<text x="327.5" y="21.5">7</text>
<text x="375" y="21.5">8</text>
<text x="17.1" y="48.6">A</text>
<text x="400.6" y="48.6">A</text>
<text x="17.1" y="99.2">B</text>
<text x="400.6" y="99.2">B</text>
<text x="17.1" y="149.7">C</text>
<text x="400.6" y="149.7">C</text>
<text x="17.1" y="200.2">D</text>
<text x="400.6" y="200.2">D</text>
<text x="17.1" y="250.8">E</text>
<text x="400.6" y="250.8">E</text>
<text x="42.7" y="277.9">1</text>
<text x="90.2" y="277.9">2</text>
<text x="137.7" y="277.9">3</text>
<text x="185.1" y="277.9">4</text>
<text x="232.6" y="277.9">5</text>
<text x="280" y="277.9">6</text>
<text x="327.5" y="277.9">7</text>
<text x="375" y="277.9">8</text>
</g>
<g font-size="3.6">
<text x="380.5" y="38.6">Bus Hold</text>
<text x="26.7" y="245.5">Decoupling</text>
<text x="315.7" y="248.1">Title:</text>
<text x="326.2" y="248.2">cft</text>
<text x="315.9" y="253.2">Revision:</text>
<text x="333.8" y="253.3">Rev A</text>
<text x="315.4" y="263.3">Drawn by:</text>
<text x="315.9" y="258.2">Last Change: 16 Dec 2012</text>
<text x="334.5" y="263.3">Alexios</text>
<text x="361" y="258.1">12:04:37</text>
<text x="374.1" y="263.2">46/49</text>
<text x="315.4" y="268.4">Simulation filename:</text>
<text x="351" y="268.4">N/A</text>
<text x="315.4" y="273.5">More Info: http://www.bedroomlan.org/cft</text>
</g>
<g font-size="2.5">
<text x="52.1" y="59.5">IC258</text>
<text x="74.9" y="59.4">RN42A</text>
<text x="85.1" y="59.4">10k</text>
<text x="141" y="59.5">IC261</text>
<text x="163.8" y="59.4">RN45A</text>
<text x="174" y="59.4">10k</text>
<text x="229.8" y="59.5">IC265</text>
<text x="252.7" y="59.4">RN49A</text>
<text x="262.9" y="59.4">10k</text>
<text x="34.6" y="65.2">AB1</text>
<text x="34.6" y="62.7">AB0</text>
<text x="95.2" y="65.2">AB1</text>
<text x="95.2" y="62.7">AB0</text>
<text x="117.7" y="65.2">SKIPEXT</text>
<text x="123.8" y="62.7">[B5]</text>
<text x="184.1" y="65.2">SKIPEXT</text>
<text x="184.1" y="62.7">[B5]</text>
<text x="212.3" y="65.2">DB1</text>
<text x="212.3" y="62.7">DB0</text>
<text x="273" y="65.2">DB1</text>
<text x="273" y="62.7">DB0</text>
<text x="34.6" y="70.3">AB3</text>
<text x="34.6" y="67.8">AB2</text>
<text x="95.2" y="70.3">AB3</text>
<text x="95.2" y="67.8">AB2</text>
<text x="118.1" y="67.8">ENDEXT</text>
<text x="124.2" y="70.3">WS</text>
<text x="184.1" y="67.8">ENDEXT</text>
<text x="184.1" y="70.3">WS</text>
<text x="212.3" y="70.3">DB3</text>
<text x="212.3" y="67.8">DB2</text>
<text x="273" y="70.3">DB3</text>
<text x="273" y="67.8">DB2</text>
<text x="34.6" y="77.9">AB6</text>
<text x="34.6" y="75.4">AB5</text>
<text x="34.6" y="72.8">AB4</text>
<text x="95.2" y="77.9">AB6</text>
<text x="95.2" y="75.4">AB5</text>
<text x="95.2" y="72.8">AB4</text>
<text x="122.4" y="75.4">[B10]</text>
<text x="122.4" y="77.9">[B11]</text>
<text x="123.8" y="72.8">[B9]</text>
<text x="184.1" y="72.8">[B9]</text>
<text x="184.1" y="75.4">[B10]</text>
<text x="184.1" y="77.9">[B11]</text>
<text x="212.3" y="77.9">DB6</text>
<text x="212.3" y="75.4">DB5</text>
<text x="212.3" y="72.8">DB4</text>
<text x="273" y="77.9">DB6</text>
<text x="273" y="75.4">DB5</text>
<text x="273" y="72.8">DB4</text>
<text x="34.6" y="80.5">AB7</text>
<text x="85.1" y="83.5">10k</text>
<text x="95.2" y="80.5">AB7</text>
<text x="122.4" y="80.5">[B12]</text>
<text x="174" y="83.5">10k</text>
<text x="184.1" y="80.5">[B12]</text>
<text x="212.3" y="80.5">DB7</text>
<text x="262.9" y="83.5">10k</text>
<text x="273" y="80.5">DB7</text>
<text x="41.4" y="95.7">GND</text>
<text x="52.1" y="93.2">74HC541N</text>
<text x="130.3" y="95.7">GND</text>
<text x="141" y="93.2">74HC541N</text>
<text x="219.2" y="95.7">GND</text>
<text x="229.8" y="93.2">74HC541N</text>
<text x="52.1" y="100.1">IC259</text>
<text x="74.9" y="100">RN43A</text>
<text x="85.1" y="100">10k</text>
<text x="141" y="100.1">IC262</text>
<text x="163.8" y="100">RN46A</text>
<text x="174" y="100">10k</text>
<text x="229.8" y="100.1">IC266</text>
<text x="252.7" y="100">RN50A</text>
<text x="262.9" y="100">10k</text>
<text x="33.5" y="103.3">IRQ3</text>
<text x="33.5" y="105.9">IRQ4</text>
<text x="95.2" y="103.3">IRQ3</text>
<text x="95.2" y="105.9">IRQ4</text>
<text x="120.3" y="105.9">AEXT1</text>
<text x="120.3" y="103.3">AEXT0</text>
<text x="184.1" y="105.9">AEXT1</text>
<text x="184.1" y="103.3">AEXT0</text>
<text x="211.3" y="103.3">MEM</text>
<text x="214.5" y="105.9">IO</text>
<text x="273" y="103.3">MEM</text>
<text x="273" y="105.9">IO</text>
<text x="33.5" y="108.4">IRQ5</text>
<text x="33.5" y="113.5">IRQ7</text>
<text x="33.5" y="110.9">IRQ6</text>
<text x="95.2" y="108.4">IRQ5</text>
<text x="95.2" y="113.5">IRQ7</text>
<text x="95.2" y="110.9">IRQ6</text>
<text x="120.3" y="113.5">AEXT4</text>
<text x="120.3" y="110.9">AEXT3</text>
<text x="120.3" y="108.4">AEXT2</text>
<text x="184.1" y="113.5">AEXT4</text>
<text x="184.1" y="110.9">AEXT3</text>
<text x="184.1" y="108.4">AEXT2</text>
<text x="211.3" y="113.5">IRQ0</text>
<text x="214.8" y="110.9">W</text>
<text x="215.3" y="108.4">R</text>
<text x="273" y="108.4">R</text>
<text x="273" y="110.9">W</text>
<text x="273" y="113.5">IRQ0</text>
<text x="33" y="116">HALT</text>
<text x="34.6" y="118.6">AB8</text>
<text x="95.2" y="116">HALT</text>
<text x="95.2" y="118.6">AB8</text>
<text x="120.3" y="118.6">AEXT6</text>
<text x="120.3" y="116">AEXT5</text>
<text x="184.1" y="118.6">AEXT6</text>
<text x="184.1" y="116">AEXT5</text>
<text x="211.3" y="118.6">IRQ2</text>
<text x="211.3" y="116">IRQ1</text>
<text x="273" y="118.6">IRQ2</text>
<text x="273" y="116">IRQ1</text>
<text x="34.6" y="121.1">AB9</text>
<text x="85.1" y="124.1">10k</text>
<text x="95.2" y="121.1">AB9</text>
<text x="120.3" y="121.1">AEXT7</text>
<text x="174" y="124.1">10k</text>
<text x="184.1" y="121.1">AEXT7</text>
<text x="212.3" y="121.1">DB8</text>
<text x="262.9" y="124.1">10k</text>
<text x="273" y="121.1">DB8</text>
<text x="41.4" y="136.3">GND</text>
<text x="52.1" y="133.8">74HC541N</text>
<text x="130.3" y="136.3">GND</text>
<text x="141" y="133.8">74HC541N</text>
<text x="219.2" y="136.3">GND</text>
<text x="229.8" y="133.8">74HC541N</text>
<text x="52.1" y="143.3">IC260</text>
<text x="74.9" y="143.2">RN44A</text>
<text x="85.1" y="143.2">10k</text>
<text x="141" y="143.3">IC263</text>
<text x="163.8" y="143.2">RN47A</text>
<text x="174" y="143.2">10k</text>
<text x="229.8" y="143.3">IC267</text>
<text x="252.7" y="143.2">RN51A</text>
<text x="262.9" y="143.2">10k</text>
<text x="33.2" y="149">AB11</text>
<text x="33.2" y="146.5">AB10</text>
<text x="95.2" y="149">AB11</text>
<text x="95.2" y="146.5">AB10</text>
<text x="122.4" y="146.5">[B21]</text>
<text x="122.4" y="149">[B22]</text>
<text x="184.1" y="146.5">[B21]</text>
<text x="184.1" y="149">[B22]</text>
<text x="210.9" y="149">DB10</text>
<text x="212.3" y="146.5">DB9</text>
<text x="273" y="149">DB10</text>
<text x="273" y="146.5">DB9</text>
<text x="33.2" y="154.1">AB13</text>
<text x="33.2" y="151.6">AB12</text>
<text x="95.2" y="154.1">AB13</text>
<text x="95.2" y="151.6">AB12</text>
<text x="115.7" y="154.1">IODEV1XX</text>
<text x="122.4" y="151.6">[B23]</text>
<text x="184.1" y="154.1">IODEV1XX</text>
<text x="184.1" y="151.6">[B23]</text>
<text x="210.9" y="154.1">DB12</text>
<text x="210.9" y="151.6">DB11</text>
<text x="273" y="154.1">DB12</text>
<text x="273" y="151.6">DB11</text>
<text x="311.9" y="150.8">EXP2A</text>
<text x="350" y="150.8">EXP2B</text>
<text x="385.4" y="150.8">EXP2C</text>
<text x="29.2" y="161.7">SYSDEV</text>
<text x="33.2" y="159.2">AB15</text>
<text x="33.2" y="156.6">AB14</text>
<text x="95.2" y="159.2">AB15</text>
<text x="95.2" y="156.6">AB14</text>
<text x="95.2" y="161.7">SYSDEV</text>
<text x="115.7" y="159.2">IODEV3XX</text>
<text x="115.7" y="156.6">IODEV2XX</text>
<text x="124" y="161.7">T34</text>
<text x="184.1" y="159.2">IODEV3XX</text>
<text x="184.1" y="156.6">IODEV2XX</text>
<text x="184.1" y="161.7">T34</text>
<text x="210.9" y="161.7">DB15</text>
<text x="210.9" y="159.2">DB14</text>
<text x="210.9" y="156.6">DB13</text>
<text x="273" y="161.7">DB15</text>
<text x="273" y="159.2">DB14</text>
<text x="273" y="156.6">DB13</text>
<text x="33.1" y="164.3">CLK1</text>
<text x="85.1" y="167.3">10k</text>
<text x="95.2" y="164.3">CLK1</text>
<text x="122" y="164.3">CLK4</text>
<text x="174" y="167.3">10k</text>
<text x="184.1" y="164.3">CLK4</text>
<text x="211.3" y="164.3">[B29]</text>
<text x="262.9" y="167.3">10k</text>
<text x="273" y="164.3">[B29]</text>
<text x="296.2" y="166.8">AB1</text>
<text x="296.2" y="164.3">AB0</text>
<text x="328.5" y="166.8">SKIPEXT</text>
<text x="334.6" y="164.3">[B5]</text>
<text x="369.8" y="166.8">DB1</text>
<text x="369.8" y="164.3">DB0</text>
<text x="296.2" y="171.9">AB3</text>
<text x="296.2" y="169.3">AB2</text>
<text x="328.9" y="169.3">ENDEXT</text>
<text x="335" y="171.9">WS</text>
<text x="369.8" y="171.9">DB3</text>
<text x="369.8" y="169.3">DB2</text>
<text x="41.4" y="179.5">GND</text>
<text x="52.1" y="177">74HC541N</text>
<text x="130.3" y="179.5">GND</text>
<text x="141" y="177">74HC541N</text>
<text x="219.2" y="179.5">GND</text>
<text x="229.8" y="177">74HC541N</text>
<text x="296.2" y="179.5">AB6</text>
<text x="296.2" y="177">AB5</text>
<text x="296.2" y="174.4">AB4</text>
<text x="333.2" y="177">[B10]</text>
<text x="333.2" y="179.5">[B11]</text>
<text x="334.6" y="174.4">[B9]</text>
<text x="369.8" y="179.5">DB6</text>
<text x="369.8" y="177">DB5</text>
<text x="369.8" y="174.4">DB4</text>
<text x="295.1" y="184.6">IRQ3</text>
<text x="296.2" y="182">AB7</text>
<text x="331.1" y="184.6">AEXT0</text>
<text x="333.2" y="182">[B12]</text>
<text x="368.7" y="184.6">MEM</text>
<text x="369.8" y="182">DB7</text>
<text x="122.2" y="189.7">IRQS</text>
<text x="141" y="186.5">IC264</text>
<text x="163.8" y="186.4">RN48A</text>
<text x="174" y="186.4">10k</text>
<text x="184.1" y="189.7">IRQS</text>
<text x="295.1" y="187.1">IRQ4</text>
<text x="295.1" y="189.7">IRQ5</text>
<text x="331.1" y="189.7">AEXT2</text>
<text x="331.1" y="187.1">AEXT1</text>
<text x="372" y="187.1">IO</text>
<text x="372.8" y="189.7">R</text>
<text x="122" y="192.2">CLK2</text>
<text x="122" y="197.3">CLK3</text>
<text x="122.4" y="194.7">[B29]</text>
<text x="184.1" y="192.2">CLK2</text>
<text x="184.1" y="197.3">CLK3</text>
<text x="184.1" y="194.7">[B29]</text>
<text x="295.1" y="197.3">IRQ7</text>
<text x="295.1" y="192.2">IRQ6</text>
<text x="331.1" y="197.3">AEXT5</text>
<text x="331.1" y="194.7">AEXT4</text>
<text x="331.1" y="192.2">AEXT3</text>
<text x="368.8" y="197.3">IRQ0</text>
<text x="372.3" y="192.2">W</text>
<text x="119.9" y="199.8">RESET</text>
<text x="184.1" y="199.8">RESET</text>
<text x="294.6" y="199.8">HALT</text>
<text x="296.2" y="202.4">AB8</text>
<text x="331.1" y="202.4">AEXT7</text>
<text x="331.1" y="199.8">AEXT6</text>
<text x="368.8" y="202.4">IRQ2</text>
<text x="368.8" y="199.8">IRQ1</text>
<text x="294.8" y="210">AB11</text>
<text x="294.8" y="207.4">AB10</text>
<text x="296.2" y="204.9">AB9</text>
<text x="333.2" y="204.9">[B21]</text>
<text x="333.2" y="207.4">[B22]</text>
<text x="333.2" y="210">[B23]</text>
<text x="368.4" y="210">DB10</text>
<text x="369.8" y="207.4">DB9</text>
<text x="369.8" y="204.9">DB8</text>
<text x="294.8" y="215.1">AB13</text>
<text x="294.8" y="212.5">AB12</text>
<text x="326.5" y="215.1">IODEV2XX</text>
<text x="326.5" y="212.5">IODEV1XX</text>
<text x="368.4" y="215.1">DB12</text>
<text x="368.4" y="212.5">DB11</text>
<text x="141" y="220.1">74HC541N</text>
<text x="294.8" y="220.1">AB15</text>
<text x="294.8" y="217.6">AB14</text>
<text x="326.5" y="217.6">IODEV3XX</text>
<text x="334.8" y="220.1">T34</text>
<text x="368.4" y="220.1">DB14</text>
<text x="368.4" y="217.6">DB13</text>
<text x="130.3" y="222.7">GND</text>
<text x="290.8" y="222.7">SYSDEV</text>
<text x="294.7" y="225.2">CLK1</text>
<text x="294.9" y="227.8">IRQS</text>
<text x="332.8" y="225.2">CLK2</text>
<text x="332.8" y="227.8">CLK3</text>
<text x="332.8" y="222.7">CLK4</text>
<text x="366.3" y="227.8">RESET</text>
<text x="368.4" y="222.7">DB15</text>
<text x="368.8" y="225.2">[B29]</text>
<text x="95.2" y="245.5" transform="rotate(-90 95.2 245.5)">VCC</text>
<text x="107.9" y="245.5" transform="rotate(-90 107.9 245.5)">VCC</text>
<text x="301" y="240.5">PCB @ (0, 1.95)</text>
<text x="244.6" y="250.5">HOLE</text>
<text x="244.6" y="247.5">H9</text>
<text x="255.2" y="248.1">@ (.175, 3.675)</text>
<text x="30" y="257.9">0.1uF</text>
<text x="30" y="252.8">C388</text>
<text x="37.6" y="257.9">0.1uF</text>
<text x="37.6" y="252.8">C389</text>
<text x="45.2" y="257.9">0.1uF</text>
<text x="45.2" y="252.8">C390</text>
<text x="52.8" y="257.9">0.1uF</text>
<text x="52.8" y="252.8">C391</text>
<text x="60.4" y="257.9">0.1uF</text>
<text x="60.4" y="252.8">C392</text>
<text x="68.1" y="257.9">0.1uF</text>
<text x="68.1" y="252.8">C393</text>
<text x="75.7" y="257.9">0.1uF</text>
<text x="75.7" y="252.8">C394</text>
<text x="83.3" y="257.9">0.1uF</text>
<text x="83.3" y="252.8">C395</text>
<text x="90.9" y="257.9">0.1uF</text>
<text x="90.9" y="252.8">C396</text>
<text x="98.5" y="257.9">0.1uF</text>
<text x="98.5" y="252.8">C397</text>
<text x="111.6" y="257.7">1uF</text>
<text x="111.6" y="252.7">C398</text>
<text x="244.6" y="255.1">H10</text>
<text x="255.2" y="255.7">@ (5.8, 3.675)</text>
<text x="244.6" y="258.2">HOLE</text>
<text x="244.6" y="262.7">H11</text>
<text x="255.2" y="263.3">@ (5.8, .225)</text>
<text x="26.7" y="268.4">GND</text>
<text x="107.5" y="268.4">GND</text>
<text x="244.6" y="265.8">HOLE</text>
<text x="244.6" y="273.4">HOLE</text>
<text x="244.6" y="270.3">H12</text>
<text x="255.2" y="270.9">@ (.175, .225)</text>
</g>
<g font-size="2.1">
<text x="48.5" y="62.3">2</text>
<text x="48.5" y="64.9">3</text>
<text x="54.4" y="63.4">A1</text>
<text x="54.4" y="66">A2</text>
<text x="62.4" y="66">Y2</text>
<text x="62.4" y="63.4">Y1</text>
<text x="69.6" y="64.9">17</text>
<text x="69.6" y="62.3">18</text>
<text x="78.5" y="62.3">1</text>
<text x="78.5" y="64.9">2</text>
<text x="85.4" y="62.3">16</text>
<text x="85.4" y="64.9">15</text>
<text x="137.4" y="62.3">2</text>
<text x="137.4" y="64.9">3</text>
<text x="143.3" y="63.4">A1</text>
<text x="143.3" y="66">A2</text>
<text x="151.3" y="66">Y2</text>
<text x="151.3" y="63.4">Y1</text>
<text x="158.5" y="64.9">17</text>
<text x="158.5" y="62.3">18</text>
<text x="167.4" y="62.3">1</text>
<text x="167.4" y="64.9">2</text>
<text x="174.3" y="62.3">16</text>
<text x="174.3" y="64.9">15</text>
<text x="226.3" y="62.3">2</text>
<text x="226.3" y="64.9">3</text>
<text x="232.2" y="63.4">A1</text>
<text x="232.2" y="66">A2</text>
<text x="240.1" y="66">Y2</text>
<text x="240.1" y="63.4">Y1</text>
<text x="247.4" y="64.9">17</text>
<text x="247.4" y="62.3">18</text>
<text x="256.2" y="62.3">1</text>
<text x="256.2" y="64.9">2</text>
<text x="263.2" y="62.3">16</text>
<text x="263.2" y="64.9">15</text>
<text x="48.5" y="67.4">4</text>
<text x="48.5" y="69.9">5</text>
<text x="54.4" y="68.5">A3</text>
<text x="54.4" y="71.1">A4</text>
<text x="62.4" y="71.1">Y4</text>
<text x="62.4" y="68.5">Y3</text>
<text x="69.6" y="69.9">15</text>
<text x="69.6" y="67.4">16</text>
<text x="78.5" y="67.4">3</text>
<text x="78.5" y="69.9">4</text>
<text x="85.4" y="67.4">14</text>
<text x="85.4" y="69.9">13</text>
<text x="137.4" y="67.4">4</text>
<text x="137.4" y="69.9">5</text>
<text x="143.3" y="68.5">A3</text>
<text x="143.3" y="71.1">A4</text>
<text x="151.3" y="71.1">Y4</text>
<text x="151.3" y="68.5">Y3</text>
<text x="158.5" y="69.9">15</text>
<text x="158.5" y="67.4">16</text>
<text x="167.4" y="67.4">3</text>
<text x="167.4" y="69.9">4</text>
<text x="174.3" y="67.4">14</text>
<text x="174.3" y="69.9">13</text>
<text x="226.3" y="67.4">4</text>
<text x="226.3" y="69.9">5</text>
<text x="232.2" y="68.5">A3</text>
<text x="232.2" y="71.1">A4</text>
<text x="240.1" y="71.1">Y4</text>
<text x="240.1" y="68.5">Y3</text>
<text x="247.4" y="69.9">15</text>
<text x="247.4" y="67.4">16</text>
<text x="256.2" y="67.4">3</text>
<text x="256.2" y="69.9">4</text>
<text x="263.2" y="67.4">14</text>
<text x="263.2" y="69.9">13</text>
<text x="48.5" y="72.5">6</text>
<text x="48.5" y="75">7</text>
<text x="48.5" y="77.6">8</text>
<text x="54.4" y="73.6">A5</text>
<text x="54.4" y="76.1">A6</text>
<text x="62.4" y="76.1">Y6</text>
<text x="62.4" y="73.6">Y5</text>
<text x="69.6" y="77.6">12</text>
<text x="69.6" y="75">13</text>
<text x="69.6" y="72.5">14</text>
<text x="78.5" y="72.5">5</text>
<text x="78.5" y="75">6</text>
<text x="78.5" y="77.6">7</text>
<text x="85.4" y="72.5">12</text>
<text x="85.4" y="75">11</text>
<text x="85.4" y="77.6">10</text>
<text x="137.4" y="72.5">6</text>
<text x="137.4" y="75">7</text>
<text x="137.4" y="77.6">8</text>
<text x="143.3" y="73.6">A5</text>
<text x="143.3" y="76.1">A6</text>
<text x="151.3" y="76.1">Y6</text>
<text x="151.3" y="73.6">Y5</text>
<text x="158.5" y="77.6">12</text>
<text x="158.5" y="75">13</text>
<text x="158.5" y="72.5">14</text>
<text x="167.4" y="72.5">5</text>
<text x="167.4" y="75">6</text>
<text x="167.4" y="77.6">7</text>
<text x="174.3" y="72.5">12</text>
<text x="174.3" y="75">11</text>
<text x="174.3" y="77.6">10</text>
<text x="226.3" y="72.5">6</text>
<text x="226.3" y="75">7</text>
<text x="226.3" y="77.6">8</text>
<text x="232.2" y="73.6">A5</text>
<text x="232.2" y="76.1">A6</text>
<text x="240.1" y="76.1">Y6</text>
<text x="240.1" y="73.6">Y5</text>
<text x="247.4" y="77.6">12</text>
<text x="247.4" y="75">13</text>
<text x="247.4" y="72.5">14</text>
<text x="256.2" y="72.5">5</text>
<text x="256.2" y="75">6</text>
<text x="256.2" y="77.6">7</text>
<text x="263.2" y="72.5">12</text>
<text x="263.2" y="75">11</text>
<text x="263.2" y="77.6">10</text>
<text x="48.5" y="80.1">9</text>
<text x="54.4" y="78.7">A7</text>
<text x="54.4" y="81.2">A8</text>
<text x="62.4" y="81.2">Y8</text>
<text x="62.4" y="78.7">Y7</text>
<text x="69.6" y="80.1">11</text>
<text x="78.5" y="80.1">8</text>
<text x="85.4" y="80.1">9</text>
<text x="137.4" y="80.1">9</text>
<text x="143.3" y="78.7">A7</text>
<text x="143.3" y="81.2">A8</text>
<text x="151.3" y="81.2">Y8</text>
<text x="151.3" y="78.7">Y7</text>
<text x="158.5" y="80.1">11</text>
<text x="167.4" y="80.1">8</text>
<text x="174.3" y="80.1">9</text>
<text x="226.3" y="80.1">9</text>
<text x="232.2" y="78.7">A7</text>
<text x="232.2" y="81.2">A8</text>
<text x="240.1" y="81.2">Y8</text>
<text x="240.1" y="78.7">Y7</text>
<text x="247.4" y="80.1">11</text>
<text x="256.2" y="80.1">8</text>
<text x="263.2" y="80.1">9</text>
<text x="47.4" y="87.7">19</text>
<text x="48.5" y="85.2">1</text>
<text x="54.4" y="86.3">G1</text>
<text x="54.4" y="88.8">G2</text>
<text x="136.2" y="87.7">19</text>
<text x="137.4" y="85.2">1</text>
<text x="143.3" y="86.3">G1</text>
<text x="143.3" y="88.8">G2</text>
<text x="225.1" y="87.7">19</text>
<text x="226.3" y="85.2">1</text>
<text x="232.2" y="86.3">G1</text>
<text x="232.2" y="88.8">G2</text>
<text x="48.5" y="103">2</text>
<text x="48.5" y="105.5">3</text>
<text x="54.4" y="104.1">A1</text>
<text x="54.4" y="106.6">A2</text>
<text x="62.4" y="106.6">Y2</text>
<text x="62.4" y="104.1">Y1</text>
<text x="69.6" y="105.5">17</text>
<text x="69.6" y="103">18</text>
<text x="78.5" y="103">1</text>
<text x="78.5" y="105.5">2</text>
<text x="85.4" y="103">16</text>
<text x="85.4" y="105.5">15</text>
<text x="137.4" y="103">2</text>
<text x="137.4" y="105.5">3</text>
<text x="143.3" y="104.1">A1</text>
<text x="143.3" y="106.6">A2</text>
<text x="151.3" y="106.6">Y2</text>
<text x="151.3" y="104.1">Y1</text>
<text x="158.5" y="105.5">17</text>
<text x="158.5" y="103">18</text>
<text x="167.4" y="103">1</text>
<text x="167.4" y="105.5">2</text>
<text x="174.3" y="103">16</text>
<text x="174.3" y="105.5">15</text>
<text x="226.3" y="103">2</text>
<text x="226.3" y="105.5">3</text>
<text x="232.2" y="104.1">A1</text>
<text x="232.2" y="106.6">A2</text>
<text x="240.1" y="106.6">Y2</text>
<text x="240.1" y="104.1">Y1</text>
<text x="247.4" y="105.5">17</text>
<text x="247.4" y="103">18</text>
<text x="256.2" y="103">1</text>
<text x="256.2" y="105.5">2</text>
<text x="263.2" y="103">16</text>
<text x="263.2" y="105.5">15</text>
<text x="48.5" y="108">4</text>
<text x="48.5" y="110.6">5</text>
<text x="48.5" y="113.1">6</text>
<text x="54.4" y="109.2">A3</text>
<text x="54.4" y="111.7">A4</text>
<text x="62.4" y="111.7">Y4</text>
<text x="62.4" y="109.2">Y3</text>
<text x="69.6" y="113.1">14</text>
<text x="69.6" y="110.6">15</text>
<text x="69.6" y="108">16</text>
<text x="78.5" y="108">3</text>
<text x="78.5" y="110.6">4</text>
<text x="78.5" y="113.1">5</text>
<text x="85.4" y="108">14</text>
<text x="85.4" y="110.6">13</text>
<text x="85.4" y="113.1">12</text>
<text x="137.4" y="108">4</text>
<text x="137.4" y="110.6">5</text>
<text x="137.4" y="113.1">6</text>
<text x="143.3" y="109.2">A3</text>
<text x="143.3" y="111.7">A4</text>
<text x="151.3" y="111.7">Y4</text>
<text x="151.3" y="109.2">Y3</text>
<text x="158.5" y="113.1">14</text>
<text x="158.5" y="110.6">15</text>
<text x="158.5" y="108">16</text>
<text x="167.4" y="108">3</text>
<text x="167.4" y="110.6">4</text>
<text x="167.4" y="113.1">5</text>
<text x="174.3" y="108">14</text>
<text x="174.3" y="110.6">13</text>
<text x="174.3" y="113.1">12</text>
<text x="226.3" y="108">4</text>
<text x="226.3" y="110.6">5</text>
<text x="226.3" y="113.1">6</text>
<text x="232.2" y="109.2">A3</text>
<text x="232.2" y="111.7">A4</text>
<text x="240.1" y="111.7">Y4</text>
<text x="240.1" y="109.2">Y3</text>
<text x="247.4" y="113.1">14</text>
<text x="247.4" y="110.6">15</text>
<text x="247.4" y="108">16</text>
<text x="256.2" y="108">3</text>
<text x="256.2" y="110.6">4</text>
<text x="256.2" y="113.1">5</text>
<text x="263.2" y="108">14</text>
<text x="263.2" y="110.6">13</text>
<text x="263.2" y="113.1">12</text>
<text x="48.5" y="115.7">7</text>
<text x="48.5" y="118.2">8</text>
<text x="54.4" y="114.2">A5</text>
<text x="54.4" y="116.8">A6</text>
<text x="54.4" y="119.3">A7</text>
<text x="62.4" y="119.3">Y7</text>
<text x="62.4" y="116.8">Y6</text>
<text x="62.4" y="114.2">Y5</text>
<text x="69.6" y="118.2">12</text>
<text x="69.6" y="115.7">13</text>
<text x="78.5" y="115.7">6</text>
<text x="78.5" y="118.2">7</text>
<text x="85.4" y="115.7">11</text>
<text x="85.4" y="118.2">10</text>
<text x="137.4" y="115.7">7</text>
<text x="137.4" y="118.2">8</text>
<text x="143.3" y="114.2">A5</text>
<text x="143.3" y="116.8">A6</text>
<text x="143.3" y="119.3">A7</text>
<text x="151.3" y="119.3">Y7</text>
<text x="151.3" y="116.8">Y6</text>
<text x="151.3" y="114.2">Y5</text>
<text x="158.5" y="118.2">12</text>
<text x="158.5" y="115.7">13</text>
<text x="167.4" y="115.7">6</text>
<text x="167.4" y="118.2">7</text>
<text x="174.3" y="115.7">11</text>
<text x="174.3" y="118.2">10</text>
<text x="226.3" y="115.7">7</text>
<text x="226.3" y="118.2">8</text>
<text x="232.2" y="114.2">A5</text>
<text x="232.2" y="116.8">A6</text>
<text x="232.2" y="119.3">A7</text>
<text x="240.1" y="119.3">Y7</text>
<text x="240.1" y="116.8">Y6</text>
<text x="240.1" y="114.2">Y5</text>
<text x="247.4" y="118.2">12</text>
<text x="247.4" y="115.7">13</text>
<text x="256.2" y="115.7">6</text>
<text x="256.2" y="118.2">7</text>
<text x="263.2" y="115.7">11</text>
<text x="263.2" y="118.2">10</text>
<text x="48.5" y="125.8">1</text>
<text x="48.5" y="120.7">9</text>
<text x="54.4" y="121.9">A8</text>
<text x="62.4" y="121.9">Y8</text>
<text x="69.6" y="120.7">11</text>
<text x="78.5" y="120.7">8</text>
<text x="85.4" y="120.7">9</text>
<text x="137.4" y="125.8">1</text>
<text x="137.4" y="120.7">9</text>
<text x="143.3" y="121.9">A8</text>
<text x="151.3" y="121.9">Y8</text>
<text x="158.5" y="120.7">11</text>
<text x="167.4" y="120.7">8</text>
<text x="174.3" y="120.7">9</text>
<text x="226.3" y="125.8">1</text>
<text x="226.3" y="120.7">9</text>
<text x="232.2" y="121.9">A8</text>
<text x="240.1" y="121.9">Y8</text>
<text x="247.4" y="120.7">11</text>
<text x="256.2" y="120.7">8</text>
<text x="263.2" y="120.7">9</text>
<text x="47.4" y="128.4">19</text>
<text x="54.4" y="126.9">G1</text>
<text x="54.4" y="129.5">G2</text>
<text x="136.2" y="128.4">19</text>
<text x="143.3" y="126.9">G1</text>
<text x="143.3" y="129.5">G2</text>
<text x="225.1" y="128.4">19</text>
<text x="232.2" y="126.9">G1</text>
<text x="232.2" y="129.5">G2</text>
<text x="48.5" y="146.1">2</text>
<text x="48.5" y="148.7">3</text>
<text x="54.4" y="147.3">A1</text>
<text x="54.4" y="149.8">A2</text>
<text x="62.4" y="149.8">Y2</text>
<text x="62.4" y="147.3">Y1</text>
<text x="69.6" y="148.7">17</text>
<text x="69.6" y="146.1">18</text>
<text x="78.5" y="146.1">1</text>
<text x="78.5" y="148.7">2</text>
<text x="85.4" y="146.1">16</text>
<text x="85.4" y="148.7">15</text>
<text x="137.4" y="146.1">2</text>
<text x="137.4" y="148.7">3</text>
<text x="143.3" y="147.3">A1</text>
<text x="143.3" y="149.8">A2</text>
<text x="151.3" y="149.8">Y2</text>
<text x="151.3" y="147.3">Y1</text>
<text x="158.5" y="148.7">17</text>
<text x="158.5" y="146.1">18</text>
<text x="167.4" y="146.1">1</text>
<text x="167.4" y="148.7">2</text>
<text x="174.3" y="146.1">16</text>
<text x="174.3" y="148.7">15</text>
<text x="226.3" y="146.1">2</text>
<text x="226.3" y="148.7">3</text>
<text x="232.2" y="147.3">A1</text>
<text x="232.2" y="149.8">A2</text>
<text x="240.1" y="149.8">Y2</text>
<text x="240.1" y="147.3">Y1</text>
<text x="247.4" y="148.7">17</text>
<text x="247.4" y="146.1">18</text>
<text x="256.2" y="146.1">1</text>
<text x="256.2" y="148.7">2</text>
<text x="263.2" y="146.1">16</text>
<text x="263.2" y="148.7">15</text>
<text x="48.5" y="151.2">4</text>
<text x="48.5" y="153.8">5</text>
<text x="54.4" y="152.3">A3</text>
<text x="54.4" y="154.9">A4</text>
<text x="62.4" y="154.9">Y4</text>
<text x="62.4" y="152.3">Y3</text>
<text x="69.6" y="153.8">15</text>
<text x="69.6" y="151.2">16</text>
<text x="78.5" y="151.2">3</text>
<text x="78.5" y="153.8">4</text>
<text x="85.4" y="151.2">14</text>
<text x="85.4" y="153.8">13</text>
<text x="137.4" y="151.2">4</text>
<text x="137.4" y="153.8">5</text>
<text x="143.3" y="152.3">A3</text>
<text x="143.3" y="154.9">A4</text>
<text x="151.3" y="154.9">Y4</text>
<text x="151.3" y="152.3">Y3</text>
<text x="158.5" y="153.8">15</text>
<text x="158.5" y="151.2">16</text>
<text x="167.4" y="151.2">3</text>
<text x="167.4" y="153.8">4</text>
<text x="174.3" y="151.2">14</text>
<text x="174.3" y="153.8">13</text>
<text x="226.3" y="151.2">4</text>
<text x="226.3" y="153.8">5</text>
<text x="232.2" y="152.3">A3</text>
<text x="232.2" y="154.9">A4</text>
<text x="240.1" y="154.9">Y4</text>
<text x="240.1" y="152.3">Y3</text>
<text x="247.4" y="153.8">15</text>
<text x="247.4" y="151.2">16</text>
<text x="256.2" y="151.2">3</text>
<text x="256.2" y="153.8">4</text>
<text x="263.2" y="151.2">14</text>
<text x="263.2" y="153.8">13</text>
<text x="311.3" y="153.8">A1</text>
<text x="349.3" y="153.8">B1</text>
<text x="384.8" y="153.8">C1</text>
<text x="48.5" y="156.3">6</text>
<text x="48.5" y="158.8">7</text>
<text x="48.5" y="161.4">8</text>
<text x="54.4" y="157.4">A5</text>
<text x="54.4" y="159.9">A6</text>
<text x="62.4" y="160">Y6</text>
<text x="62.4" y="157.4">Y5</text>
<text x="69.6" y="161.4">12</text>
<text x="69.6" y="158.8">13</text>
<text x="69.6" y="156.3">14</text>
<text x="78.5" y="156.3">5</text>
<text x="78.5" y="158.8">6</text>
<text x="78.5" y="161.4">7</text>
<text x="85.4" y="156.3">12</text>
<text x="85.4" y="158.8">11</text>
<text x="85.4" y="161.4">10</text>
<text x="137.4" y="156.3">6</text>
<text x="137.4" y="158.8">7</text>
<text x="137.4" y="161.4">8</text>
<text x="143.3" y="157.4">A5</text>
<text x="143.3" y="159.9">A6</text>
<text x="151.3" y="160">Y6</text>
<text x="151.3" y="157.4">Y5</text>
<text x="158.5" y="161.4">12</text>
<text x="158.5" y="158.8">13</text>
<text x="158.5" y="156.3">14</text>
<text x="167.4" y="156.3">5</text>
<text x="167.4" y="158.8">6</text>
<text x="167.4" y="161.4">7</text>
<text x="174.3" y="156.3">12</text>
<text x="174.3" y="158.8">11</text>
<text x="174.3" y="161.4">10</text>
<text x="226.3" y="156.3">6</text>
<text x="226.3" y="158.8">7</text>
<text x="226.3" y="161.4">8</text>
<text x="232.2" y="157.4">A5</text>
<text x="232.2" y="159.9">A6</text>
<text x="240.1" y="160">Y6</text>
<text x="240.1" y="157.4">Y5</text>
<text x="247.4" y="161.4">12</text>
<text x="247.4" y="158.8">13</text>
<text x="247.4" y="156.3">14</text>
<text x="256.2" y="156.3">5</text>
<text x="256.2" y="158.8">6</text>
<text x="256.2" y="161.4">7</text>
<text x="263.2" y="156.3">12</text>
<text x="263.2" y="158.8">11</text>
<text x="263.2" y="161.4">10</text>
<text x="311.3" y="156.3">A2</text>
<text x="311.3" y="158.8">A3</text>
<text x="311.3" y="161.4">A4</text>
<text x="349.3" y="156.3">B2</text>
<text x="349.3" y="158.8">B3</text>
<text x="349.3" y="161.4">B4</text>
<text x="384.8" y="156.3">C2</text>
<text x="384.8" y="158.8">C3</text>
<text x="384.8" y="161.4">C4</text>
<text x="48.5" y="163.9">9</text>
<text x="54.4" y="162.5">A7</text>
<text x="54.4" y="165">A8</text>
<text x="62.4" y="165">Y8</text>
<text x="62.4" y="162.5">Y7</text>
<text x="69.6" y="163.9">11</text>
<text x="78.5" y="163.9">8</text>
<text x="85.4" y="163.9">9</text>
<text x="137.4" y="163.9">9</text>
<text x="143.3" y="162.5">A7</text>
<text x="143.3" y="165">A8</text>
<text x="151.3" y="165">Y8</text>
<text x="151.3" y="162.5">Y7</text>
<text x="158.5" y="163.9">11</text>
<text x="167.4" y="163.9">8</text>
<text x="174.3" y="163.9">9</text>
<text x="226.3" y="163.9">9</text>
<text x="232.2" y="162.5">A7</text>
<text x="232.2" y="165">A8</text>
<text x="240.1" y="165">Y8</text>
<text x="240.1" y="162.5">Y7</text>
<text x="247.4" y="163.9">11</text>
<text x="256.2" y="163.9">8</text>
<text x="263.2" y="163.9">9</text>
<text x="311.3" y="163.9">A5</text>
<text x="311.3" y="166.5">A6</text>
<text x="349.3" y="163.9">B5</text>
<text x="349.3" y="166.5">B6</text>
<text x="384.8" y="163.9">C5</text>
<text x="384.8" y="166.5">C6</text>
<text x="47.4" y="171.5">19</text>
<text x="48.5" y="169">1</text>
<text x="54.4" y="170.1">G1</text>
<text x="54.4" y="172.6">G2</text>
<text x="136.2" y="171.5">19</text>
<text x="137.4" y="169">1</text>
<text x="143.3" y="170.1">G1</text>
<text x="143.3" y="172.6">G2</text>
<text x="225.1" y="171.5">19</text>
<text x="226.3" y="169">1</text>
<text x="232.2" y="170.1">G1</text>
<text x="232.2" y="172.6">G2</text>
<text x="311.3" y="169">A7</text>
<text x="311.3" y="171.5">A8</text>
<text x="349.3" y="169">B7</text>
<text x="349.3" y="171.5">B8</text>
<text x="384.8" y="169">C7</text>
<text x="384.8" y="171.5">C8</text>
<text x="310.1" y="176.6">A10</text>
<text x="310.1" y="179.1">A11</text>
<text x="311.3" y="174.1">A9</text>
<text x="348.2" y="176.6">B10</text>
<text x="348.2" y="179.1">B11</text>
<text x="349.3" y="174.1">B9</text>
<text x="383.6" y="176.6">C10</text>
<text x="383.6" y="179.1">C11</text>
<text x="384.8" y="174.1">C9</text>
<text x="310.1" y="181.7">A12</text>
<text x="310.1" y="184.2">A13</text>
<text x="348.2" y="181.7">B12</text>
<text x="348.2" y="184.2">B13</text>
<text x="383.6" y="181.7">C12</text>
<text x="383.6" y="184.2">C13</text>
<text x="137.4" y="189.3">2</text>
<text x="137.4" y="191.8">3</text>
<text x="143.3" y="190.4">A1</text>
<text x="151.3" y="190.4">Y1</text>
<text x="158.5" y="191.8">17</text>
<text x="158.5" y="189.3">18</text>
<text x="167.4" y="189.3">1</text>
<text x="167.4" y="191.8">2</text>
<text x="174.3" y="189.3">16</text>
<text x="174.3" y="191.8">15</text>
<text x="310.1" y="186.8">A14</text>
<text x="310.1" y="189.3">A15</text>
<text x="310.1" y="191.8">A16</text>
<text x="348.2" y="186.8">B14</text>
<text x="348.2" y="189.3">B15</text>
<text x="348.2" y="191.8">B16</text>
<text x="383.6" y="186.8">C14</text>
<text x="383.6" y="189.3">C15</text>
<text x="383.6" y="191.8">C16</text>
<text x="137.4" y="194.4">4</text>
<text x="137.4" y="196.9">5</text>
<text x="143.3" y="193">A2</text>
<text x="143.3" y="195.5">A3</text>
<text x="151.3" y="195.5">Y3</text>
<text x="151.3" y="193">Y2</text>
<text x="158.5" y="196.9">15</text>
<text x="158.5" y="194.4">16</text>
<text x="167.4" y="194.4">3</text>
<text x="167.4" y="196.9">4</text>
<text x="174.3" y="194.4">14</text>
<text x="174.3" y="196.9">13</text>
<text x="310.1" y="194.4">A17</text>
<text x="310.1" y="196.9">A18</text>
<text x="348.2" y="194.4">B17</text>
<text x="348.2" y="196.9">B18</text>
<text x="383.6" y="194.4">C17</text>
<text x="383.6" y="196.9">C18</text>
<text x="137.4" y="199.5">6</text>
<text x="137.4" y="202">7</text>
<text x="143.3" y="198">A4</text>
<text x="143.3" y="200.6">A5</text>
<text x="143.3" y="203.1">A6</text>
<text x="151.3" y="203.1">Y6</text>
<text x="151.3" y="200.6">Y5</text>
<text x="151.3" y="198">Y4</text>
<text x="158.5" y="202">13</text>
<text x="158.5" y="199.5">14</text>
<text x="167.4" y="199.5">5</text>
<text x="174.3" y="199.5">12</text>
<text x="310.1" y="199.5">A19</text>
<text x="310.1" y="202">A20</text>
<text x="348.2" y="199.5">B19</text>
<text x="348.2" y="202">B20</text>
<text x="383.6" y="199.5">C19</text>
<text x="383.6" y="202">C20</text>
<text x="137.4" y="204.5">8</text>
<text x="137.4" y="207.1">9</text>
<text x="143.3" y="205.7">A7</text>
<text x="143.3" y="208.2">A8</text>
<text x="151.3" y="208.2">Y8</text>
<text x="151.3" y="205.7">Y7</text>
<text x="158.5" y="207.1">11</text>
<text x="158.5" y="204.5">12</text>
<text x="310.1" y="204.5">A21</text>
<text x="310.1" y="207.1">A22</text>
<text x="310.1" y="209.6">A23</text>
<text x="348.2" y="204.5">B21</text>
<text x="348.2" y="207.1">B22</text>
<text x="348.2" y="209.6">B23</text>
<text x="383.6" y="204.5">C21</text>
<text x="383.6" y="207.1">C22</text>
<text x="383.6" y="209.6">C23</text>
<text x="136.2" y="214.7">19</text>
<text x="137.4" y="212.2">1</text>
<text x="143.3" y="213.3">G1</text>
<text x="143.3" y="215.8">G2</text>
<text x="310.1" y="212.2">A24</text>
<text x="310.1" y="214.7">A25</text>
<text x="348.2" y="212.2">B24</text>
<text x="348.2" y="214.7">B25</text>
<text x="383.6" y="212.2">C24</text>
<text x="383.6" y="214.7">C25</text>
<text x="310.1" y="217.2">A26</text>
<text x="310.1" y="219.8">A27</text>
<text x="348.2" y="217.2">B26</text>
<text x="348.2" y="219.8">B27</text>
<text x="383.6" y="217.2">C26</text>
<text x="383.6" y="219.8">C27</text>
<text x="310.1" y="222.3">A28</text>
<text x="310.1" y="224.9">A29</text>
<text x="310.1" y="227.4">A30</text>
<text x="348.2" y="222.3">B28</text>
<text x="348.2" y="224.9">B29</text>
<text x="348.2" y="227.4">B30</text>
<text x="383.6" y="222.3">C28</text>
<text x="383.6" y="224.9">C29</text>
<text x="383.6" y="227.4">C30</text>
<text x="310.1" y="229.9">A31</text>
<text x="310.1" y="232.5">A32</text>
<text x="348.2" y="229.9">B31</text>
<text x="348.2" y="232.5">B32</text>
<text x="383.6" y="229.9">C31</text>
<text x="383.6" y="232.5">C32</text>
</g>
<text font-size="1.8" x="109.9" y="252.7" transform="rotate(-90 109.9 252.7)">+</text>
</g></defs>
<g fill="#000" stroke="#000" stroke-width=".21">
<path d="M67.8 18.2v3.9zM115.3 18.2v3.9zM162.7 18.2v3.9zM210.2 18.2v3.9zM257.6 18.2v3.9zM305.1 18.2v3.9zM352.5 18.2v3.9zM20.3 22.1v252.6zM20.3 22.1h379.7zM16.5 72.6h3.8zM39.4 77.9h7.6zM39.4 75.4h7.6z"/>
<path d="M39.4 72.8h7.6zM39.4 70.3h7.6zM39.4 67.8h7.6zM39.4 65.2h7.6zM39.4 62.7h7.6zM47 62.7h5.1zM47 65.2h5.1zM47 67.8h5.1zM47 70.3h5.1zM47 72.8h5.1zM47 75.4h5.1zM47 77.9h5.1z"/>
<path d="M67.3 77.9h5.1zM67.3 75.4h5.1zM67.3 72.8h5.1zM67.3 70.3h5.1zM67.3 67.8h5.1zM67.3 65.2h5.1zM67.3 62.7h5.1zM72.4 70.3h5.1zM72.4 67.8h5.1zM72.4 65.2h5.1zM72.4 72.8h5.1zM72.4 75.4h5.1z"/>
<path d="M72.4 77.9h5.1zM77.5 62.7h2.5zM77.5 65.2h2.5zM77.5 67.8h2.5zM77.5 70.3h2.5zM77.5 72.8h2.5zM77.5 75.4h2.5zM77.5 77.9h2.5zM85.1 62.7h2.5zM85.1 65.2h2.5zM85.1 67.8h2.5zM85.1 70.3h2.5z"/>
<path d="M85.1 72.8h2.5zM85.1 75.4h2.5zM85.1 77.9h2.5zM87.6 77.9h7.6zM87.6 75.4h7.6zM87.6 72.8h7.6zM87.6 70.3h7.6zM87.6 67.8h7.6zM87.6 65.2h7.6zM87.6 62.7h7.6zM117.7 63.2h10.5zM118.1 65.7h10.1z"/>
<path d="M124.2 68.3h4zM135.9 62.7h5zM135.9 65.2h5zM135.9 67.8h5zM135.9 70.3h5zM135.9 72.8h5zM135.9 75.4h5zM135.9 77.9h5zM128.2 65.2h7.7zM128.2 67.8h7.7zM128.2 70.3h7.7zM128.2 62.7h7.7z"/>
<path d="M128.2 72.8h7.7zM128.2 75.4h7.7zM128.2 77.9h7.7zM156.2 77.9h5.1zM156.2 75.4h5.1zM156.2 72.8h5.1zM156.2 70.3h5.1zM156.2 67.8h5.1zM156.2 65.2h5.1zM156.2 62.7h5.1zM166.3 62.7h2.6zM166.3 65.2h2.6z"/>
<path d="M166.3 67.8h2.6zM166.3 70.3h2.6zM166.3 72.8h2.6zM166.3 75.4h2.6zM166.3 77.9h2.6zM161.3 62.7h5zM161.3 65.2h5zM161.3 67.8h5zM161.3 70.3h5zM161.3 72.8h5zM161.3 75.4h5zM161.3 77.9h5z"/>
<path d="M174 62.7h2.5zM174 65.2h2.5zM174 67.8h2.5zM174 70.3h2.5zM174 72.8h2.5zM174 75.4h2.5zM174 77.9h2.5zM176.5 65.2h7.6zM176.5 67.8h7.6zM176.5 70.3h7.6zM176.5 62.7h7.6zM176.5 72.8h7.6z"/>
<path d="M176.5 75.4h7.6zM176.5 77.9h7.6zM184.1 63.2h10.6zM184.1 65.7h10.1zM184.1 68.3h4zM217.1 77.9h7.7zM217.1 75.4h7.7zM217.1 72.8h7.7zM217.1 70.3h7.7zM217.1 67.8h7.7zM217.1 65.2h7.7zM217.1 62.7h7.7z"/>
<path d="M224.8 62.7h5zM224.8 65.2h5zM224.8 67.8h5zM224.8 70.3h5zM224.8 72.8h5zM224.8 75.4h5zM224.8 77.9h5zM245.1 77.9h5.1zM245.1 75.4h5.1zM245.1 72.8h5.1zM245.1 70.3h5.1zM245.1 67.8h5.1z"/>
<path d="M245.1 65.2h5.1zM245.1 62.7h5.1zM255.2 62.7h2.6zM255.2 65.2h2.6zM255.2 67.8h2.6zM255.2 70.3h2.6zM255.2 72.8h2.6zM255.2 75.4h2.6zM255.2 77.9h2.6zM250.2 62.7h5zM250.2 65.2h5zM250.2 67.8h5z"/>
<path d="M250.2 70.3h5zM250.2 72.8h5zM250.2 75.4h5zM250.2 77.9h5zM262.9 62.7h2.5zM262.9 65.2h2.5zM262.9 67.8h2.5zM262.9 70.3h2.5zM262.9 72.8h2.5zM262.9 75.4h2.5zM262.9 77.9h2.5zM265.4 77.9h7.6z"/>
<path d="M265.4 75.4h7.6zM265.4 72.8h7.6zM265.4 70.3h7.6zM265.4 67.8h7.6zM265.4 65.2h7.6zM265.4 62.7h7.6zM400 72.6h3.8zM39.4 80.5h7.6zM44.4 90.6v2.6zM44.4 85.5v2.6zM44.4 88.1v2.5zM47 85.5h3.1z"/>
<path d="M47 80.5h5.1zM47 88.1h3.1zM44.4 85.5h2.6zM44.4 88.1h2.6zM67.3 80.5h5.1zM72.4 80.5h5.1zM77.5 80.5h2.5zM85.1 80.5h2.5zM87.6 80.5h7.6zM133.3 90.6v2.6zM133.3 85.5v2.6zM133.3 88.1v2.5z"/>
<path d="M135.9 85.5h3.1zM135.9 80.5h5zM135.9 88.1h3.1zM133.3 85.5h2.6zM133.3 88.1h2.6zM128.2 80.5h7.7zM156.2 80.5h5.1zM166.3 80.5h2.6zM161.3 80.5h5zM174 80.5h2.5zM176.5 80.5h7.6zM217.1 80.5h7.7z"/>
<path d="M222.2 90.6v2.6zM222.2 85.5v2.6zM222.2 88.1v2.5zM224.8 85.5h3.1zM224.8 80.5h5zM224.8 88.1h3.1zM222.2 85.5h2.6zM222.2 88.1h2.6zM245.1 80.5h5.1zM255.2 80.5h2.6zM250.2 80.5h5zM262.9 80.5h2.5z"/>
<path d="M265.4 80.5h7.6zM33 114h6.4zM33.5 101.3h5.9zM33.5 103.8h5.9zM33.5 106.4h5.9zM33.5 111.5h5.9zM33.5 108.9h5.9zM39.4 118.6h7.6zM47 103.3h5.1zM47 105.9h5.1zM47 108.4h5.1zM47 110.9h5.1z"/>
<path d="M47 113.5h5.1zM47 116h5.1zM47 118.6h5.1zM39.4 116h7.6zM39.4 103.3h7.6zM39.4 105.9h7.6zM39.4 108.4h7.6zM39.4 113.5h7.6zM39.4 110.9h7.6zM67.3 118.6h5.1zM67.3 116h5.1zM67.3 113.5h5.1z"/>
<path d="M67.3 110.9h5.1zM67.3 108.4h5.1zM67.3 105.9h5.1zM67.3 103.3h5.1zM77.5 103.3h2.5zM77.5 105.9h2.5zM77.5 108.4h2.5zM77.5 110.9h2.5zM77.5 113.5h2.5zM77.5 116h2.5zM77.5 118.6h2.5zM72.4 103.3h5.1z"/>
<path d="M72.4 105.9h5.1zM72.4 108.4h5.1zM72.4 110.9h5.1zM72.4 113.5h5.1zM72.4 116h5.1zM72.4 118.6h5.1zM85.1 103.3h2.5zM85.1 105.9h2.5zM85.1 108.4h2.5zM85.1 110.9h2.5zM85.1 113.5h2.5zM85.1 116h2.5z"/>
<path d="M85.1 118.6h2.5zM87.6 116h7.6zM87.6 103.3h7.6zM87.6 105.9h7.6zM87.6 108.4h7.6zM87.6 113.5h7.6zM87.6 110.9h7.6zM95.2 114h6.4zM95.2 101.3h5.9zM95.2 103.8h5.9zM95.2 106.4h5.9zM95.2 111.5h5.9z"/>
<path d="M95.2 108.9h5.9zM87.6 118.6h7.6zM128.2 118.6h7.7zM128.2 116h7.7zM128.2 113.5h7.7zM128.2 110.9h7.7zM128.2 108.4h7.7zM128.2 105.9h7.7zM128.2 103.3h7.7zM135.9 103.3h5zM135.9 105.9h5zM135.9 108.4h5z"/>
<path d="M135.9 110.9h5zM135.9 113.5h5zM135.9 116h5zM135.9 118.6h5zM156.2 118.6h5.1zM156.2 116h5.1zM156.2 113.5h5.1zM156.2 110.9h5.1zM156.2 108.4h5.1zM156.2 105.9h5.1zM156.2 103.3h5.1zM166.3 103.3h2.6z"/>
<path d="M166.3 105.9h2.6zM166.3 108.4h2.6zM166.3 110.9h2.6zM166.3 113.5h2.6zM166.3 116h2.6zM166.3 118.6h2.6zM161.3 103.3h5zM161.3 105.9h5zM161.3 108.4h5zM161.3 110.9h5zM161.3 113.5h5zM161.3 116h5z"/>
<path d="M161.3 118.6h5zM174 103.3h2.5zM174 105.9h2.5zM174 108.4h2.5zM174 110.9h2.5zM174 113.5h2.5zM174 116h2.5zM174 118.6h2.5zM176.5 118.6h7.6zM176.5 116h7.6zM176.5 113.5h7.6zM176.5 110.9h7.6z"/>
<path d="M176.5 108.4h7.6zM176.5 105.9h7.6zM176.5 103.3h7.6zM211.3 101.3h5.8zM211.3 111.5h5.8zM211.3 116.5h5.8zM211.3 114h5.8zM214.5 103.8h2.6zM214.8 108.9h2.3zM215.3 106.4h1.8zM224.8 103.3h5zM224.8 105.9h5z"/>
<path d="M224.8 108.4h5zM224.8 110.9h5zM224.8 113.5h5zM224.8 116h5zM224.8 118.6h5zM217.1 103.3h7.7zM217.1 105.9h7.7zM217.1 108.4h7.7zM217.1 110.9h7.7zM217.1 113.5h7.7zM217.1 118.6h7.7zM217.1 116h7.7z"/>
<path d="M245.1 118.6h5.1zM245.1 116h5.1zM245.1 113.5h5.1zM245.1 110.9h5.1zM245.1 108.4h5.1zM245.1 105.9h5.1zM245.1 103.3h5.1zM255.2 103.3h2.6zM255.2 105.9h2.6zM255.2 108.4h2.6zM255.2 110.9h2.6zM255.2 113.5h2.6z"/>
<path d="M255.2 116h2.6zM255.2 118.6h2.6zM250.2 103.3h5zM250.2 105.9h5zM250.2 108.4h5zM250.2 110.9h5zM250.2 113.5h5zM250.2 116h5zM250.2 118.6h5zM262.9 103.3h2.5zM262.9 105.9h2.5zM262.9 108.4h2.5z"/>
<path d="M262.9 110.9h2.5zM262.9 113.5h2.5zM262.9 116h2.5zM262.9 118.6h2.5zM265.4 103.3h7.6zM265.4 105.9h7.6zM265.4 108.4h7.6zM265.4 110.9h7.6zM265.4 113.5h7.6zM265.4 118.6h7.6zM265.4 116h7.6zM273 101.3h5.9z"/>
<path d="M273 103.8h2.6zM273 106.4h1.8zM273 108.9h2.4zM273 111.5h5.8zM273 116.5h5.8zM273 114h5.8zM16.5 123.1h3.8zM39.4 121.1h7.6zM44.4 131.3v2.5zM44.4 126.2v2.5zM44.4 128.7v2.6zM47 126.2h3.1z"/>
<path d="M47 121.1h5.1zM47 128.7h3.1zM44.4 126.2h2.6zM44.4 128.7h2.6zM67.3 121.1h5.1zM77.5 121.1h2.5zM72.4 121.1h5.1zM85.1 121.1h2.5zM87.6 121.1h7.6zM128.2 121.1h7.7zM133.3 131.3v2.5zM133.3 126.2v2.5z"/>
<path d="M133.3 128.7v2.6zM135.9 126.2h3.1zM135.9 121.1h5zM135.9 128.7h3.1zM133.3 126.2h2.6zM133.3 128.7h2.6zM156.2 121.1h5.1zM166.3 121.1h2.6zM161.3 121.1h5zM174 121.1h2.5zM176.5 121.1h7.6zM217.1 121.1h7.7z"/>
<path d="M222.2 131.3v2.5zM222.2 126.2v2.5zM222.2 128.7v2.6zM224.8 126.2h3.1zM224.8 121.1h5zM224.8 128.7h3.1zM222.2 126.2h2.6zM222.2 128.7h2.6zM245.1 121.1h5.1zM255.2 121.1h2.6zM250.2 121.1h5zM262.9 121.1h2.5z"/>
<path d="M265.4 121.1h7.6zM400 123.1h3.8zM29.2 159.7h10.2zM39.4 159.2h7.6zM39.4 156.7h7.6zM39.4 154.1h7.6zM39.4 151.6h7.6zM39.4 149h7.6zM39.4 146.5h7.6zM47 146.5h5.1zM47 149h5.1zM47 151.6h5.1z"/>
<path d="M47 154.1h5.1zM47 156.7h5.1zM47 159.2h5.1zM67.3 159.2h5.1zM67.3 156.7h5.1zM67.3 154.1h5.1zM67.3 151.6h5.1zM67.3 149h5.1zM67.3 146.5h5.1zM77.5 146.5h2.5zM77.5 149h2.5zM77.5 151.6h2.5z"/>
<path d="M77.5 154.1h2.5zM77.5 156.7h2.5zM77.5 159.2h2.5zM72.4 146.5h5.1zM72.4 149h5.1zM72.4 151.6h5.1zM72.4 154.1h5.1zM72.4 156.7h5.1zM72.4 159.2h5.1zM85.1 146.5h2.5zM85.1 149h2.5zM85.1 151.6h2.5z"/>
<path d="M85.1 154.1h2.5zM85.1 156.7h2.5zM85.1 159.2h2.5zM95.2 159.7h10.2zM87.6 159.2h7.6zM87.6 156.7h7.6zM87.6 154.1h7.6zM87.6 151.6h7.6zM87.6 149h7.6zM87.6 146.5h7.6zM115.7 157.2h12.5zM115.7 154.6h12.5z"/>
<path d="M115.7 152.1h12.5zM123.9 159.7h4.3zM135.9 146.5h5zM135.9 149h5zM135.9 151.6h5zM135.9 154.1h5zM135.9 156.7h5zM135.9 159.2h5zM128.2 159.2h7.7zM128.2 156.7h7.7zM128.2 154.1h7.7zM128.2 146.5h7.7z"/>
<path d="M128.2 149h7.7zM128.2 151.6h7.7zM156.2 159.2h5.1zM156.2 156.7h5.1zM156.2 154.1h5.1zM156.2 151.6h5.1zM156.2 149h5.1zM156.2 146.5h5.1zM166.3 146.5h2.6zM166.3 149h2.6zM166.3 151.6h2.6zM166.3 154.1h2.6z"/>
<path d="M166.3 156.7h2.6zM166.3 159.2h2.6zM161.3 146.5h5zM161.3 149h5zM161.3 151.6h5zM161.3 154.1h5zM161.3 156.7h5zM161.3 159.2h5zM174 146.5h2.5zM174 149h2.5zM174 151.6h2.5zM174 154.1h2.5z"/>
<path d="M174 156.7h2.5zM174 159.2h2.5zM176.5 159.2h7.6zM176.5 156.7h7.6zM176.5 154.1h7.6zM176.5 146.5h7.6zM176.5 149h7.6zM176.5 151.6h7.6zM184.1 157.2h12.5zM184.1 154.6h12.5zM184.1 152.1h12.5zM184.1 159.7h4.3z"/>
<path d="M217.1 159.2h7.7zM217.1 156.7h7.7zM217.1 154.1h7.7zM217.1 151.6h7.7zM217.1 149h7.7zM217.1 146.5h7.7zM224.8 146.5h5zM224.8 149h5zM224.8 151.6h5zM224.8 154.1h5zM224.8 156.7h5zM224.8 159.2h5z"/>
<path d="M245.1 159.2h5.1zM245.1 156.7h5.1zM245.1 154.1h5.1zM245.1 151.6h5.1zM245.1 149h5.1zM245.1 146.5h5.1zM255.2 146.5h2.6zM255.2 149h2.6zM255.2 151.6h2.6zM255.2 154.1h2.6zM255.2 156.7h2.6zM255.2 159.2h2.6z"/>
<path d="M250.2 146.5h5zM250.2 149h5zM250.2 151.6h5zM250.2 154.1h5zM250.2 156.7h5zM250.2 159.2h5zM262.9 146.5h2.5zM262.9 149h2.5zM262.9 151.6h2.5zM262.9 154.1h2.5zM262.9 156.7h2.5zM262.9 159.2h2.5z"/>
<path d="M265.4 159.2h7.6zM265.4 156.7h7.6zM265.4 154.1h7.6zM265.4 151.6h7.6zM265.4 149h7.6zM265.4 146.5h7.6zM308.6 154.1h7.6zM308.6 156.7h7.6zM308.6 159.2h7.6zM346.7 154.1h7.6zM346.7 156.7h7.6zM346.7 159.2h7.6z"/>
<path d="M382.2 154.1h7.6zM382.2 156.7h7.6zM382.2 159.2h7.6zM16.5 173.7h3.8zM44.4 174.4v2.6zM44.4 169.4v2.5zM44.4 171.9v2.5zM47 169.4h3.1zM47 161.7h5.1zM47 164.3h5.1zM47 171.9h3.1zM44.4 169.4h2.6z"/>
<path d="M44.4 171.9h2.6zM39.4 161.7h7.6zM39.4 164.3h7.6zM67.3 164.3h5.1zM67.3 161.7h5.1zM77.5 161.7h2.5zM77.5 164.3h2.5zM72.4 161.7h5.1zM72.4 164.3h5.1zM85.1 161.7h2.5zM85.1 164.3h2.5zM87.6 161.7h7.6z"/>
<path d="M87.6 164.3h7.6zM128.2 161.7h7.7zM133.3 174.4v2.6zM133.3 169.4v2.5zM133.3 171.9v2.5zM135.9 169.4h3.1zM135.9 161.7h5zM135.9 164.3h5zM135.9 171.9h3.1zM133.3 169.4h2.6zM133.3 171.9h2.6zM128.2 164.3h7.7z"/>
<path d="M156.2 164.3h5.1zM156.2 161.7h5.1zM166.3 161.7h2.6zM166.3 164.3h2.6zM161.3 161.7h5zM161.3 164.3h5zM174 161.7h2.5zM174 164.3h2.5zM176.5 164.3h7.6zM176.5 161.7h7.6zM217.1 161.7h7.7zM222.2 174.4v2.6z"/>
<path d="M222.2 169.4v2.5zM222.2 171.9v2.5zM224.8 169.4h3.1zM224.8 161.7h5zM224.8 164.3h5zM224.8 171.9h3.1zM222.2 169.4h2.6zM222.2 171.9h2.6zM217.1 164.3h7.7zM245.1 164.3h5.1zM245.1 161.7h5.1zM255.2 161.7h2.6z"/>
<path d="M255.2 164.3h2.6zM250.2 161.7h5zM250.2 164.3h5zM262.9 161.7h2.5zM262.9 164.3h2.5zM265.4 164.3h7.6zM265.4 161.7h7.6zM301 179.5h7.6zM301 177h7.6zM301 174.4h7.6zM301 171.9h7.6zM301 169.4h7.6z"/>
<path d="M301 166.8h7.6zM301 164.3h7.6zM308.6 161.7h7.6zM308.6 164.3h7.6zM308.6 166.8h7.6zM308.6 169.4h7.6zM308.6 171.9h7.6zM308.6 174.4h7.6zM308.6 177h7.6zM308.6 179.5h7.6zM328.5 164.8h10.5zM328.9 167.3h10.1z"/>
<path d="M335 169.9h4zM346.7 161.7h7.6zM346.7 164.3h7.6zM346.7 166.8h7.6zM346.7 169.4h7.6zM346.7 171.9h7.6zM346.7 174.4h7.6zM346.7 177h7.6zM346.7 179.5h7.6zM339 166.8h7.7zM339 169.4h7.7zM339 171.9h7.7z"/>
<path d="M339 164.3h7.7zM339 174.4h7.7zM339 177h7.7zM339 179.5h7.7zM374.6 179.5h7.6zM374.6 177h7.6zM374.6 174.4h7.6zM374.6 171.9h7.6zM374.6 169.4h7.6zM374.6 166.8h7.6zM374.6 164.3h7.6zM382.2 161.7h7.6z"/>
<path d="M382.2 164.3h7.6zM382.2 166.8h7.6zM382.2 169.4h7.6zM382.2 171.9h7.6zM382.2 174.4h7.6zM382.2 177h7.6zM382.2 179.5h7.6zM400 173.7h3.8zM119.9 197.8h8.3zM122.2 187.7h6zM128.2 192.2h7.7zM135.9 189.7h5z"/>
<path d="M135.9 192.2h5zM135.9 194.8h5zM135.9 197.3h5zM135.9 199.8h5zM128.2 199.8h7.7zM128.2 197.3h7.7zM128.2 189.7h7.7zM128.2 194.8h7.7zM156.2 199.8h5.1zM156.2 197.3h5.1zM156.2 194.8h5.1zM156.2 192.2h5.1z"/>
<path d="M156.2 189.7h5.1zM166.3 189.7h2.6zM166.3 192.2h2.6zM166.3 194.8h2.6zM166.3 197.3h2.6zM166.3 199.8h2.6zM161.3 189.7h5zM161.3 192.2h5zM161.3 194.8h5zM161.3 197.3h5zM161.3 199.8h5zM174 189.7h2.5z"/>
<path d="M174 192.2h2.5zM174 194.8h2.5zM174 197.3h2.5zM174 199.8h2.5zM176.5 199.8h7.6zM176.5 197.3h7.6zM176.5 189.7h7.6zM176.5 194.8h7.6zM184.1 197.8h8.3zM184.1 187.7h6.1zM176.5 192.2h7.6zM294.6 197.8h6.4z"/>
<path d="M295.1 182.6h5.9zM295.1 185.1h5.9zM295.1 187.7h5.9zM295.1 195.3h5.9zM295.1 190.2h5.9zM301 182.1h7.6zM308.6 182.1h7.6zM308.6 184.6h7.6zM308.6 187.1h7.6zM308.6 189.7h7.6zM308.6 192.2h7.6zM308.6 194.8h7.6z"/>
<path d="M308.6 197.3h7.6zM308.6 199.8h7.6zM301 199.8h7.6zM301 184.6h7.6zM301 187.1h7.6zM301 189.7h7.6zM301 197.3h7.6zM301 192.2h7.6zM339 199.8h7.7zM339 197.3h7.7zM339 194.8h7.7zM339 192.2h7.7z"/>
<path d="M339 189.7h7.7zM339 187.1h7.7zM339 184.6h7.7zM346.7 182.1h7.6zM346.7 184.6h7.6zM346.7 187.1h7.6zM346.7 189.7h7.6zM346.7 192.2h7.6zM346.7 194.8h7.6zM346.7 197.3h7.6zM346.7 199.8h7.6zM339 182.1h7.7z"/>
<path d="M368.7 182.6h5.9zM368.8 195.3h5.8zM368.8 197.8h5.8zM372 185.1h2.6zM372.3 190.2h2.3zM372.8 187.7h1.8zM374.6 182.1h7.6zM382.2 182.1h7.6zM382.2 184.6h7.6zM382.2 187.1h7.6zM382.2 189.7h7.6zM382.2 192.2h7.6z"/>
<path d="M382.2 194.8h7.6zM382.2 197.3h7.6zM382.2 199.8h7.6zM374.6 184.6h7.6zM374.6 187.1h7.6zM374.6 189.7h7.6zM374.6 192.2h7.6zM374.6 197.3h7.6zM374.6 199.8h7.6zM133.3 217.6v2.5zM133.3 212.5v2.5zM133.3 215v2.6z"/>
<path d="M133.3 202.4v2.5zM133.3 204.9v2.5zM133.3 207.4v5.1zM135.9 212.5h3.1zM135.9 202.4h5zM135.9 204.9h5zM135.9 207.4h5zM135.9 215h3.1zM133.3 212.5h2.6zM133.3 215h2.6zM133.3 202.4h2.6zM133.3 204.9h2.6z"/>
<path d="M133.3 207.4h2.6zM156.2 207.4h5.1zM156.2 204.9h5.1zM156.2 202.4h5.1zM301 217.6h7.6zM301 215h7.6zM301 212.5h7.6zM301 210h7.6zM301 207.4h7.6zM301 204.9h7.6zM301 202.4h7.6zM308.6 202.4h7.6z"/>
<path d="M308.6 204.9h7.6zM308.6 207.4h7.6zM308.6 210h7.6zM308.6 212.5h7.6zM308.6 215h7.6zM308.6 217.6h7.6zM326.5 215.6h12.5zM326.5 213h12.5zM326.5 210.5h12.5zM334.7 218.1h4.3zM339 202.4h7.7zM346.7 202.4h7.6z"/>
<path d="M346.7 204.9h7.6zM346.7 207.4h7.6zM346.7 210h7.6zM346.7 212.5h7.6zM346.7 215h7.6zM346.7 217.6h7.6zM339 217.6h7.7zM339 215h7.7zM339 212.5h7.7zM339 204.9h7.7zM339 207.4h7.7zM339 210h7.7z"/>
<path d="M368.8 200.4h5.8zM374.6 217.6h7.6zM374.6 215h7.6zM374.6 212.5h7.6zM374.6 210h7.6zM374.6 207.4h7.6zM374.6 204.9h7.6zM382.2 202.4h7.6zM382.2 204.9h7.6zM382.2 207.4h7.6zM382.2 210h7.6zM382.2 212.5h7.6z"/>
<path d="M382.2 215h7.6zM382.2 217.6h7.6zM374.6 202.4h7.6zM16.5 224.2h3.8zM290.8 220.7h10.2zM294.9 225.7h6.1zM301 220.1h7.6zM308.6 220.1h7.6zM308.6 222.7h7.6zM308.6 225.2h7.6zM308.6 227.7h7.6zM308.6 230.3h7.6z"/>
<path d="M308.6 232.8h7.6zM301 222.7h7.6zM301 225.2h7.6zM301 227.7h7.6zM339 225.2h7.7zM339 220.1h7.7zM346.7 220.1h7.6zM346.7 222.7h7.6zM346.7 225.2h7.6zM346.7 227.7h7.6zM346.7 230.3h7.6zM346.7 232.8h7.6z"/>
<path d="M339 227.7h7.7zM339 222.7h7.7zM366.3 225.7h8.3zM374.6 222.7h7.6zM374.6 220.1h7.6zM382.2 220.1h7.6zM382.2 222.7h7.6zM382.2 225.2h7.6zM382.2 227.7h7.6zM382.2 230.3h7.6zM382.2 232.8h7.6zM374.6 227.7h7.6z"/>
<path d="M374.6 225.2h7.6zM400 224.2h3.8zM29.2 255.7v2.5zM29.2 250.6v2.5zM29.2 255.2v.5zM29.2 253.1v.6zM29.2 258.2v2.6zM29.2 248.1v2.5zM36.8 255.7v2.5zM36.8 250.6v2.5zM36.8 255.2v.5zM36.8 253.1v.6z"/>
<path d="M36.8 248.1v2.5zM29.2 248.1h7.6zM44.4 255.7v2.5zM44.4 250.6v2.5zM44.4 255.2v.5zM44.4 253.1v.6zM36.8 248.1h7.6zM44.4 248.1v2.5zM52.1 255.7v2.5zM52.1 250.6v2.5zM52.1 255.2v.5zM52.1 253.1v.6z"/>
<path d="M44.4 248.1h7.7zM52.1 248.1v2.5zM59.7 255.7v2.5zM59.7 250.6v2.5zM59.7 255.2v.5zM59.7 253.1v.6zM52.1 248.1h7.6zM59.7 248.1v2.5zM67.3 255.7v2.5zM67.3 250.6v2.5zM67.3 255.2v.5zM67.3 253.1v.6z"/>
<path d="M67.3 258.2v2.6zM59.7 248.1h7.6zM67.3 248.1v2.5zM74.9 255.7v2.5zM74.9 250.6v2.5zM74.9 255.2v.5zM74.9 253.1v.6zM74.9 258.2v2.6zM67.3 248.1h7.6zM74.9 248.1v2.5zM82.5 255.7v2.5zM82.5 250.6v2.5z"/>
<path d="M82.5 255.2v.5zM82.5 253.1v.6zM82.5 258.2v2.6zM74.9 248.1h7.6zM82.5 248.1v2.5zM90.2 255.7v2.5zM90.2 250.6v2.5zM90.2 255.2v.5zM90.2 253.1v.6zM90.2 258.2v2.6zM82.5 248.1h7.7zM90.2 248.1v2.5z"/>
<path d="M97.8 243v2.5zM97.8 255.7v2.5zM97.8 250.6v2.5zM97.8 255.2v.5zM97.8 253.1v.6zM90.2 248.1h7.6zM97.8 245.5v2.6zM97.8 248.1v2.5zM110.5 255.7v2.5zM110.5 250.6v2.5zM110.5 243v2.5zM110.5 245.5v5.1z"/>
<path d="M242 248.1h1.1zM242 255.7h1.1zM242.5 247.6v1zM242.5 255.2v1zM20.3 274.7h379.7zM29.2 263.3v2.5zM29.2 260.8h7.6zM29.2 260.8v2.5zM36.8 258.2v2.6zM36.8 260.8h7.6zM44.4 258.2v2.6zM44.4 260.8h7.7z"/>
<path d="M52.1 258.2v2.6zM52.1 260.8h7.6zM59.7 258.2v2.6zM59.7 260.8h7.6zM67.8 274.7v3.8zM67.3 260.8h7.6zM74.9 260.8h7.6zM82.5 260.8h7.7zM90.2 260.8h7.6zM97.8 258.2v2.6zM110.5 263.3v2.5zM110.5 258.2v5.1z"/>
<path d="M115.3 274.7v3.8zM162.7 274.7v3.8zM210.2 274.7v3.8zM242 263.3h1.1zM242 270.9h1.1zM242.5 262.8v1zM242.5 270.4v1zM257.6 274.7v3.8zM305.1 274.7v3.8zM352.5 274.7v3.8zM400 264.5v.1zM400 268.4v6.2z"/>
<path d="M400 274.6h.1zM400 22.1v252.6z"/>
<path d="M240.5 248.1h1.5l.1 .3 .4 .2v1.5a2 2 0 0 1-2-2z" fill-rule="evenodd"/>
<path d="M240.5 255.7h1.5l.2 .4 .3 .1v1.5a2 2 0 0 1-2-2z" fill-rule="evenodd"/>
<path d="M242.5 246a2.04 2.04 0 0 1 2.1 2.1h-1.5l-.2-.3-.4-.2z" fill-rule="evenodd"/>
<path d="M242.5 253.7a2.04 2.04 0 0 1 2.1 2h-1.5l-.2-.3-.4-.2z" fill-rule="evenodd"/>
<path d="M240.5 263.3h1.5l.2 .4 .3 .1v1.5a2 2 0 0 1-2-2z" fill-rule="evenodd"/>
<path d="M240.5 270.9h1.5l.1 .3 .4 .2v1.6a2 2 0 0 1-2-2.1z" fill-rule="evenodd"/>
<path d="M242.5 261.3a2.04 2.04 0 0 1 2.1 2h-1.5l-.2-.3-.4-.2z" fill-rule="evenodd"/>
<path d="M242.5 268.9a2 2 0 0 1 2.1 2h-1.5l-.2-.3-.4-.2z" fill-rule="evenodd"/>
<circle cx="44.4" cy="88.1" r=".51"/>
<circle cx="133.3" cy="88.1" r=".51"/>
<circle cx="222.2" cy="88.1" r=".51"/>
<circle cx="44.4" cy="128.7" r=".51"/>
<circle cx="133.3" cy="128.7" r=".51"/>
<circle cx="222.2" cy="128.7" r=".51"/>
<circle cx="44.4" cy="171.9" r=".51"/>
<circle cx="133.3" cy="171.9" r=".51"/>
<circle cx="222.2" cy="171.9" r=".51"/>
<circle cx="133.3" cy="207.4" r=".51"/>
<circle cx="133.3" cy="204.9" r=".51"/>
<circle cx="133.3" cy="215" r=".51"/>
<circle cx="133.3" cy="212.5" r=".51"/>
<circle cx="36.8" cy="248.1" r=".51"/>
<circle cx="44.4" cy="248.1" r=".51"/>
<circle cx="52.1" cy="248.1" r=".51"/>
<circle cx="59.7" cy="248.1" r=".51"/>
<circle cx="67.3" cy="248.1" r=".51"/>
<circle cx="74.9" cy="248.1" r=".51"/>
<circle cx="82.5" cy="248.1" r=".51"/>
<circle cx="90.2" cy="248.1" r=".51"/>
<circle cx="97.8" cy="248.1" r=".51"/>
<circle cx="29.2" cy="260.8" r=".51"/>
<circle cx="36.8" cy="260.8" r=".51"/>
<circle cx="44.4" cy="260.8" r=".51"/>
<circle cx="52.1" cy="260.8" r=".51"/>
<circle cx="59.7" cy="260.8" r=".51"/>
<circle cx="67.3" cy="260.8" r=".51"/>
<circle cx="74.9" cy="260.8" r=".51"/>
<circle cx="82.5" cy="260.8" r=".51"/>
<circle cx="90.2" cy="260.8" r=".51"/>
</g>
<path d="M320 151.6v83.8zM314.9 151.6h5.1zM358.1 151.6v83.8zM353 151.6h5.1zM393.7 151.6v83.8zM388.6 151.6h5.1zM314.9 235.4h5.1zM314.9 151.6v83.8zM353 235.4h5.1zM353 151.6v83.8zM388.6 235.4h5.1zM388.6 151.6v83.8z" fill="#000" stroke="#000" stroke-width=".42"/>
<g fill="#000" stroke="#000" stroke-width=".61">
<path d="M20.3 22.1v252.6zM20.3 22.1h379.7zM52.1 60.2v30.4zM52.1 60.2h15.2zM140.9 60.2v30.4zM140.9 60.2h15.3zM229.8 60.2v30.4zM229.8 60.2h15.3zM52.1 90.6h15.2zM67.3 60.2v30.4zM140.9 90.6h15.3zM156.2 60.2v30.4z"/>
<path d="M229.8 90.6h15.3zM245.1 60.2v30.4zM52.1 100.8v30.5zM52.1 100.8h15.2zM140.9 100.8v30.5zM140.9 100.8h15.3zM229.8 100.8v30.5zM229.8 100.8h15.3zM52.1 131.3h15.2zM67.3 100.8v30.5zM140.9 131.3h15.3zM156.2 100.8v30.5z"/>
<path d="M229.8 131.3h15.3zM245.1 100.8v30.5zM52.1 144v30.4zM52.1 144h15.2zM140.9 144v30.4zM140.9 144h15.3zM229.8 144v30.4zM229.8 144h15.3zM316.2 159.2h1.3zM316.2 156.7h1.3zM316.2 154.1h1.3zM354.3 159.2h1.3z"/>
<path d="M354.3 156.7h1.3zM354.3 154.1h1.3zM389.8 159.2h1.3zM389.8 156.7h1.3zM389.8 154.1h1.3zM52.1 174.4h15.2zM67.3 144v30.4zM140.9 174.4h15.3zM156.2 144v30.4zM229.8 174.4h15.3zM245.1 144v30.4zM316.2 179.5h1.3z"/>
<path d="M316.2 177h1.3zM316.2 174.4h1.3zM316.2 171.9h1.3zM316.2 169.4h1.3zM316.2 166.8h1.3zM316.2 164.3h1.3zM316.2 161.7h1.3zM354.3 179.5h1.3zM354.3 177h1.3zM354.3 174.4h1.3zM354.3 171.9h1.3zM354.3 169.4h1.3z"/>
<path d="M354.3 166.8h1.3zM354.3 164.3h1.3zM354.3 161.7h1.3zM389.8 179.5h1.3zM389.8 177h1.3zM389.8 174.4h1.3zM389.8 171.9h1.3zM389.8 169.4h1.3zM389.8 166.8h1.3zM389.8 164.3h1.3zM389.8 161.7h1.3zM140.9 187.1v30.5z"/>
<path d="M140.9 187.1h15.3zM316.2 199.8h1.3zM316.2 197.3h1.3zM316.2 194.8h1.3zM316.2 192.2h1.3zM316.2 189.7h1.3zM316.2 187.1h1.3zM316.2 184.6h1.3zM316.2 182.1h1.3zM354.3 199.8h1.3zM354.3 197.3h1.3zM354.3 194.8h1.3z"/>
<path d="M354.3 192.2h1.3zM354.3 189.7h1.3zM354.3 187.1h1.3zM354.3 184.6h1.3zM354.3 182.1h1.3zM389.8 199.8h1.3zM389.8 197.3h1.3zM389.8 194.8h1.3zM389.8 192.2h1.3zM389.8 189.7h1.3zM389.8 187.1h1.3zM389.8 184.6h1.3z"/>
<path d="M389.8 182.1h1.3zM140.9 217.6h15.3zM156.2 187.1v30.5zM316.2 217.6h1.3zM316.2 215h1.3zM316.2 212.5h1.3zM316.2 210h1.3zM316.2 207.4h1.3zM316.2 204.9h1.3zM316.2 202.4h1.3zM354.3 217.6h1.3zM354.3 215h1.3z"/>
<path d="M354.3 212.5h1.3zM354.3 210h1.3zM354.3 207.4h1.3zM354.3 204.9h1.3zM354.3 202.4h1.3zM389.8 217.6h1.3zM389.8 215h1.3zM389.8 212.5h1.3zM389.8 210h1.3zM389.8 207.4h1.3zM389.8 204.9h1.3zM389.8 202.4h1.3z"/>
<path d="M316.2 232.8h1.3zM316.2 230.3h1.3zM316.2 227.7h1.3zM316.2 225.2h1.3zM316.2 222.7h1.3zM316.2 220.1h1.3zM354.3 232.8h1.3zM354.3 230.3h1.3zM354.3 227.7h1.3zM354.3 225.2h1.3zM354.3 222.7h1.3zM354.3 220.1h1.3z"/>
<path d="M389.8 232.8h1.3zM389.8 230.3h1.3zM389.8 227.7h1.3zM389.8 225.2h1.3zM389.8 222.7h1.3zM389.8 220.1h1.3zM283.2 244.3v30.4zM313.7 254.4v5.1zM313.7 249.3v5.1zM313.7 244.3v5zM313.7 244.3h86.3zM283.2 244.3h30.5z"/>
<path d="M400 254.4v5.1zM400 249.3v5.1zM400 244.3v5zM400 22.1v222.2zM20.3 274.7h262.9zM283.2 274.7h30.5zM313.7 274.7h86.3zM313.7 269.7v5zM313.7 264.6v5.1zM313.7 259.5v5.1zM400 268.4v6.3zM400 264.6v3.8z"/>
<path d="M400 259.5v5.1z"/>
</g>
<g fill="none" stroke="#000" stroke-width=".21">
<circle cx="51.1" cy="88.1" r=".99"/>
<circle cx="51.1" cy="85.5" r=".99"/>
<circle cx="140" cy="88.1" r=".99"/>
<circle cx="140" cy="85.5" r=".99"/>
<circle cx="228.8" cy="88.1" r="1"/>
<circle cx="228.8" cy="85.5" r="1"/>
<circle cx="51.1" cy="128.7" r=".99"/>
<circle cx="51.1" cy="126.2" r=".99"/>
<circle cx="140" cy="126.2" r=".99"/>
<circle cx="140" cy="128.7" r=".99"/>
<circle cx="228.8" cy="128.7" r="1"/>
<circle cx="228.8" cy="126.2" r="1"/>
<circle cx="51.1" cy="171.9" r=".99"/>
<circle cx="51.1" cy="169.4" r=".99"/>
<circle cx="140" cy="171.9" r=".99"/>
<circle cx="140" cy="169.4" r=".99"/>
<circle cx="228.8" cy="169.4" r="1"/>
<circle cx="228.8" cy="171.9" r="1"/>
<circle cx="140" cy="215" r=".99"/>
<circle cx="140" cy="212.5" r=".99"/>
<circle cx="242.5" cy="255.7" r="2.03"/>
<circle cx="242.5" cy="248.1" r="2.03"/>
<circle cx="242.5" cy="248.1" r=".51"/>
<circle cx="242.5" cy="255.7" r=".51"/>
<circle cx="242.5" cy="270.9" r="2.03"/>
<circle cx="242.5" cy="263.3" r="2.03"/>
<circle cx="242.5" cy="263.3" r=".51"/>
<circle cx="242.5" cy="270.9" r=".51"/>
</g>
<path d="M16.5 18.2v260.3zM16.5 18.2h387.3zM16.5 278.5h387.3zM403.8 18.2v260.3z" fill="#000" stroke="#000" stroke-width=".32"/>
<g fill="#000" stroke="#000" stroke-width=".28">
<path d="M80 63.4h5.1zM80 61.9v1.5zM80 66h5.1zM80 64.5v1.5zM80 68.5h5.1zM80 67v1.5zM80 71.1h5.1zM80 69.5v1.6zM80 73.6h5.1zM80 72.1v1.5zM80 76.1h5.1zM80 74.6v1.5z"/>
<path d="M80 78.7h5.1zM80 77.2v1.5zM80 79.7v1.5zM80 61.9h5.1zM85.1 61.9v1.5zM80 64.5h5.1zM85.1 64.5v1.5zM80 67h5.1zM85.1 67v1.5zM80 69.5h5.1zM85.1 69.5v1.6zM80 72.1h5.1z"/>
<path d="M85.1 72.1v1.5zM80 74.6h5.1zM85.1 74.6v1.5zM80 77.2h5.1zM85.1 77.2v1.5zM80 79.7h5.1zM168.9 63.4h5.1zM168.9 61.9v1.5zM168.9 66h5.1zM168.9 64.5v1.5zM168.9 68.5h5.1zM168.9 67v1.5z"/>
<path d="M168.9 71.1h5.1zM168.9 69.5v1.6zM168.9 73.6h5.1zM168.9 72.1v1.5zM168.9 76.1h5.1zM168.9 74.6v1.5zM168.9 78.7h5.1zM168.9 77.2v1.5zM168.9 79.7v1.5zM168.9 61.9h5.1zM174 61.9v1.5zM168.9 64.5h5.1z"/>
<path d="M174 64.5v1.5zM168.9 67h5.1zM174 67v1.5zM168.9 69.5h5.1zM174 69.5v1.6zM168.9 72.1h5.1zM174 72.1v1.5zM168.9 74.6h5.1zM174 74.6v1.5zM168.9 77.2h5.1zM174 77.2v1.5zM168.9 79.7h5.1z"/>
<path d="M257.8 63.4h5.1zM257.8 61.9v1.5zM257.8 66h5.1zM257.8 64.5v1.5zM257.8 68.5h5.1zM257.8 67v1.5zM257.8 71.1h5.1zM257.8 69.5v1.6zM257.8 73.6h5.1zM257.8 72.1v1.5zM257.8 76.1h5.1zM257.8 74.6v1.5z"/>
<path d="M257.8 78.7h5.1zM257.8 77.2v1.5zM257.8 79.7v1.5zM257.8 61.9h5.1zM262.9 61.9v1.5zM257.8 64.5h5.1zM262.9 64.5v1.5zM257.8 67h5.1zM262.9 67v1.5zM257.8 69.5h5.1zM262.9 69.5v1.6zM257.8 72.1h5.1z"/>
<path d="M262.9 72.1v1.5zM257.8 74.6h5.1zM262.9 74.6v1.5zM257.8 77.2h5.1zM262.9 77.2v1.5zM257.8 79.7h5.1zM42.5 93.2h3.9zM80 81.2h5.1zM85.1 79.7v1.5zM131.4 93.2h3.8zM168.9 81.2h5.1zM174 79.7v1.5z"/>
<path d="M220.3 93.2h3.8zM257.8 81.2h5.1zM262.9 79.7v1.5zM80 104.1h5.1zM80 102.6v1.5zM80 106.6h5.1zM80 105.1v1.5zM80 109.2h5.1zM80 107.6v1.6zM80 111.7h5.1zM80 110.2v1.5zM80 114.2h5.1z"/>
<path d="M80 112.7v1.5zM80 116.8h5.1zM80 115.3v1.5zM80 119.3h5.1zM80 117.8v1.5zM80 102.6h5.1zM85.1 102.6v1.5zM80 105.1h5.1zM85.1 105.1v1.5zM80 107.6h5.1zM85.1 107.6v1.6zM80 110.2h5.1z"/>
<path d="M85.1 110.2v1.5zM80 112.7h5.1zM85.1 112.7v1.5zM80 115.3h5.1zM85.1 115.3v1.5zM80 117.8h5.1zM85.1 117.8v1.5zM168.9 104.1h5.1zM168.9 102.6v1.5zM168.9 106.6h5.1zM168.9 105.1v1.5zM168.9 109.2h5.1z"/>
<path d="M168.9 107.6v1.6zM168.9 111.7h5.1zM168.9 110.2v1.5zM168.9 114.2h5.1zM168.9 112.7v1.5zM168.9 116.8h5.1zM168.9 115.3v1.5zM168.9 119.3h5.1zM168.9 117.8v1.5zM168.9 102.6h5.1zM174 102.6v1.5zM168.9 105.1h5.1z"/>
<path d="M174 105.1v1.5zM168.9 107.6h5.1zM174 107.6v1.6zM168.9 110.2h5.1zM174 110.2v1.5zM168.9 112.7h5.1zM174 112.7v1.5zM168.9 115.3h5.1zM174 115.3v1.5zM168.9 117.8h5.1zM174 117.8v1.5zM257.8 104.1h5.1z"/>
<path d="M257.8 102.6v1.5zM257.8 106.6h5.1zM257.8 105.1v1.5zM257.8 109.2h5.1zM257.8 107.6v1.6zM257.8 111.7h5.1zM257.8 110.2v1.5zM257.8 114.2h5.1zM257.8 112.7v1.5zM257.8 116.8h5.1zM257.8 115.3v1.5zM257.8 119.3h5.1z"/>
<path d="M257.8 117.8v1.5zM257.8 102.6h5.1zM262.9 102.6v1.5zM257.8 105.1h5.1zM262.9 105.1v1.5zM257.8 107.6h5.1zM262.9 107.6v1.6zM257.8 110.2h5.1zM262.9 110.2v1.5zM257.8 112.7h5.1zM262.9 112.7v1.5zM257.8 115.3h5.1z"/>
<path d="M262.9 115.3v1.5zM257.8 117.8h5.1zM262.9 117.8v1.5zM42.5 133.8h3.9zM80 121.9h5.1zM80 120.3v1.6zM80 120.3h5.1zM85.1 120.3v1.6zM131.4 133.8h3.8zM168.9 121.9h5.1zM168.9 120.3v1.6zM168.9 120.3h5.1z"/>
<path d="M174 120.3v1.6zM220.3 133.8h3.8zM257.8 121.9h5.1zM257.8 120.3v1.6zM257.8 120.3h5.1zM262.9 120.3v1.6zM80 147.3h5.1zM80 145.7v1.6zM80 149.8h5.1zM80 148.3v1.5zM80 152.3h5.1zM80 150.8v1.5z"/>
<path d="M80 154.9h5.1zM80 153.3v1.6zM80 157.4h5.1zM80 155.9v1.5zM80 160h5.1zM80 158.4v1.6zM80 145.7h5.1zM85.1 145.7v1.6zM80 148.3h5.1zM85.1 148.3v1.5zM80 150.8h5.1zM85.1 150.8v1.5z"/>
<path d="M80 153.3h5.1zM85.1 153.3v1.6zM80 155.9h5.1zM85.1 155.9v1.5zM80 158.4h5.1zM85.1 158.4v1.6zM168.9 147.3h5.1zM168.9 145.7v1.6zM168.9 149.8h5.1zM168.9 148.3v1.5zM168.9 152.3h5.1zM168.9 150.8v1.5z"/>
<path d="M168.9 154.9h5.1zM168.9 153.3v1.6zM168.9 157.4h5.1zM168.9 155.9v1.5zM168.9 160h5.1zM168.9 158.4v1.6zM168.9 145.7h5.1zM174 145.7v1.6zM168.9 148.3h5.1zM174 148.3v1.5zM168.9 150.8h5.1zM174 150.8v1.5z"/>
<path d="M168.9 153.3h5.1zM174 153.3v1.6zM168.9 155.9h5.1zM174 155.9v1.5zM168.9 158.4h5.1zM174 158.4v1.6zM257.8 147.3h5.1zM257.8 145.7v1.6zM257.8 149.8h5.1zM257.8 148.3v1.5zM257.8 152.3h5.1zM257.8 150.8v1.5z"/>
<path d="M257.8 154.9h5.1zM257.8 153.3v1.6zM257.8 157.4h5.1zM257.8 155.9v1.5zM257.8 160h5.1zM257.8 158.4v1.6zM257.8 145.7h5.1zM262.9 145.7v1.6zM257.8 148.3h5.1zM262.9 148.3v1.5zM257.8 150.8h5.1zM262.9 150.8v1.5z"/>
<path d="M257.8 153.3h5.1zM262.9 153.3v1.6zM257.8 155.9h5.1zM262.9 155.9v1.5zM257.8 158.4h5.1zM262.9 158.4v1.6zM42.5 177h3.9zM80 162.5h5.1zM80 161v1.5zM80 165h5.1zM80 163.5v1.5zM80 161h5.1z"/>
<path d="M85.1 161v1.5zM80 163.5h5.1zM85.1 163.5v1.5zM131.4 177h3.8zM168.9 162.5h5.1zM168.9 161v1.5zM168.9 165h5.1zM168.9 163.5v1.5zM168.9 161h5.1zM174 161v1.5zM168.9 163.5h5.1zM174 163.5v1.5z"/>
<path d="M220.3 177h3.8zM257.8 162.5h5.1zM257.8 161v1.5zM257.8 165h5.1zM257.8 163.5v1.5zM257.8 161h5.1zM262.9 161v1.5zM257.8 163.5h5.1zM262.9 163.5v1.5zM168.9 190.4h5.1zM168.9 188.9v1.5zM168.9 193h5.1z"/>
<path d="M168.9 191.4v1.6zM168.9 195.5h5.1zM168.9 194v1.5zM168.9 198.1h5.1zM168.9 196.5v1.6zM168.9 199.1v1.5zM168.9 188.9h5.1zM174 188.9v1.5zM168.9 191.4h5.1zM174 191.4v1.6zM168.9 194h5.1zM174 194v1.5z"/>
<path d="M168.9 196.5h5.1zM174 196.5v1.6zM168.9 199.1h5.1zM168.9 200.6h5.1zM174 199.1v1.5zM131.4 220.1h3.8zM97.8 243l-1.3 1.9zM97.8 243l1.3 1.9zM109 254h3zM109 253.1v.9zM109 253.1h3zM110.5 243l-1.3 1.9z"/>
<path d="M110.5 243l1.3 1.9zM112 253.1v.9zM313.7 249.3h86.3zM313.7 254.4h86.3zM313.7 259.5h58.4zM372.1 259.5h27.9zM372.1 259.5v5.1zM27.3 265.8h3.8zM108.6 265.8h3.8zM313.7 264.6h58.4zM313.7 269.7h86.3zM372.1 264.6h27.9z"/>
<path d="M400 268.4v1.3z"/>
</g>
<g fill="#000" stroke="#000" stroke-width=".21">
<path d="M27.2 253.7h4v.5h-4zM27.2 254.7h4v.5h-4zM34.8 253.7h4.1v.5h-4.1zM34.8 254.7h4.1v.5h-4.1zM42.4 253.7h4.1v.5h-4.1zM42.4 254.7h4.1v.5h-4.1zM50 253.7h4.1v.5h-4.1zM50 254.7h4.1v.5h-4.1zM57.7 253.7h4v.5h-4zM57.7 254.7h4v.5h-4zM65.3 253.7h4v.5h-4zM65.3 254.7h4v.5h-4z"/>
<path d="M72.9 253.7h4.1v.5h-4.1zM72.9 254.7h4.1v.5h-4.1zM80.5 253.7h4.1v.5h-4.1zM80.5 254.7h4.1v.5h-4.1zM88.1 253.7h4.1v.5h-4.1zM88.1 254.7h4.1v.5h-4.1zM95.8 253.7h4v.5h-4zM95.8 254.7h4v.5h-4zM108.8 254.8h3.3v.9h-3.3z"/>
</g>
<use href="#words"/>
</svg>
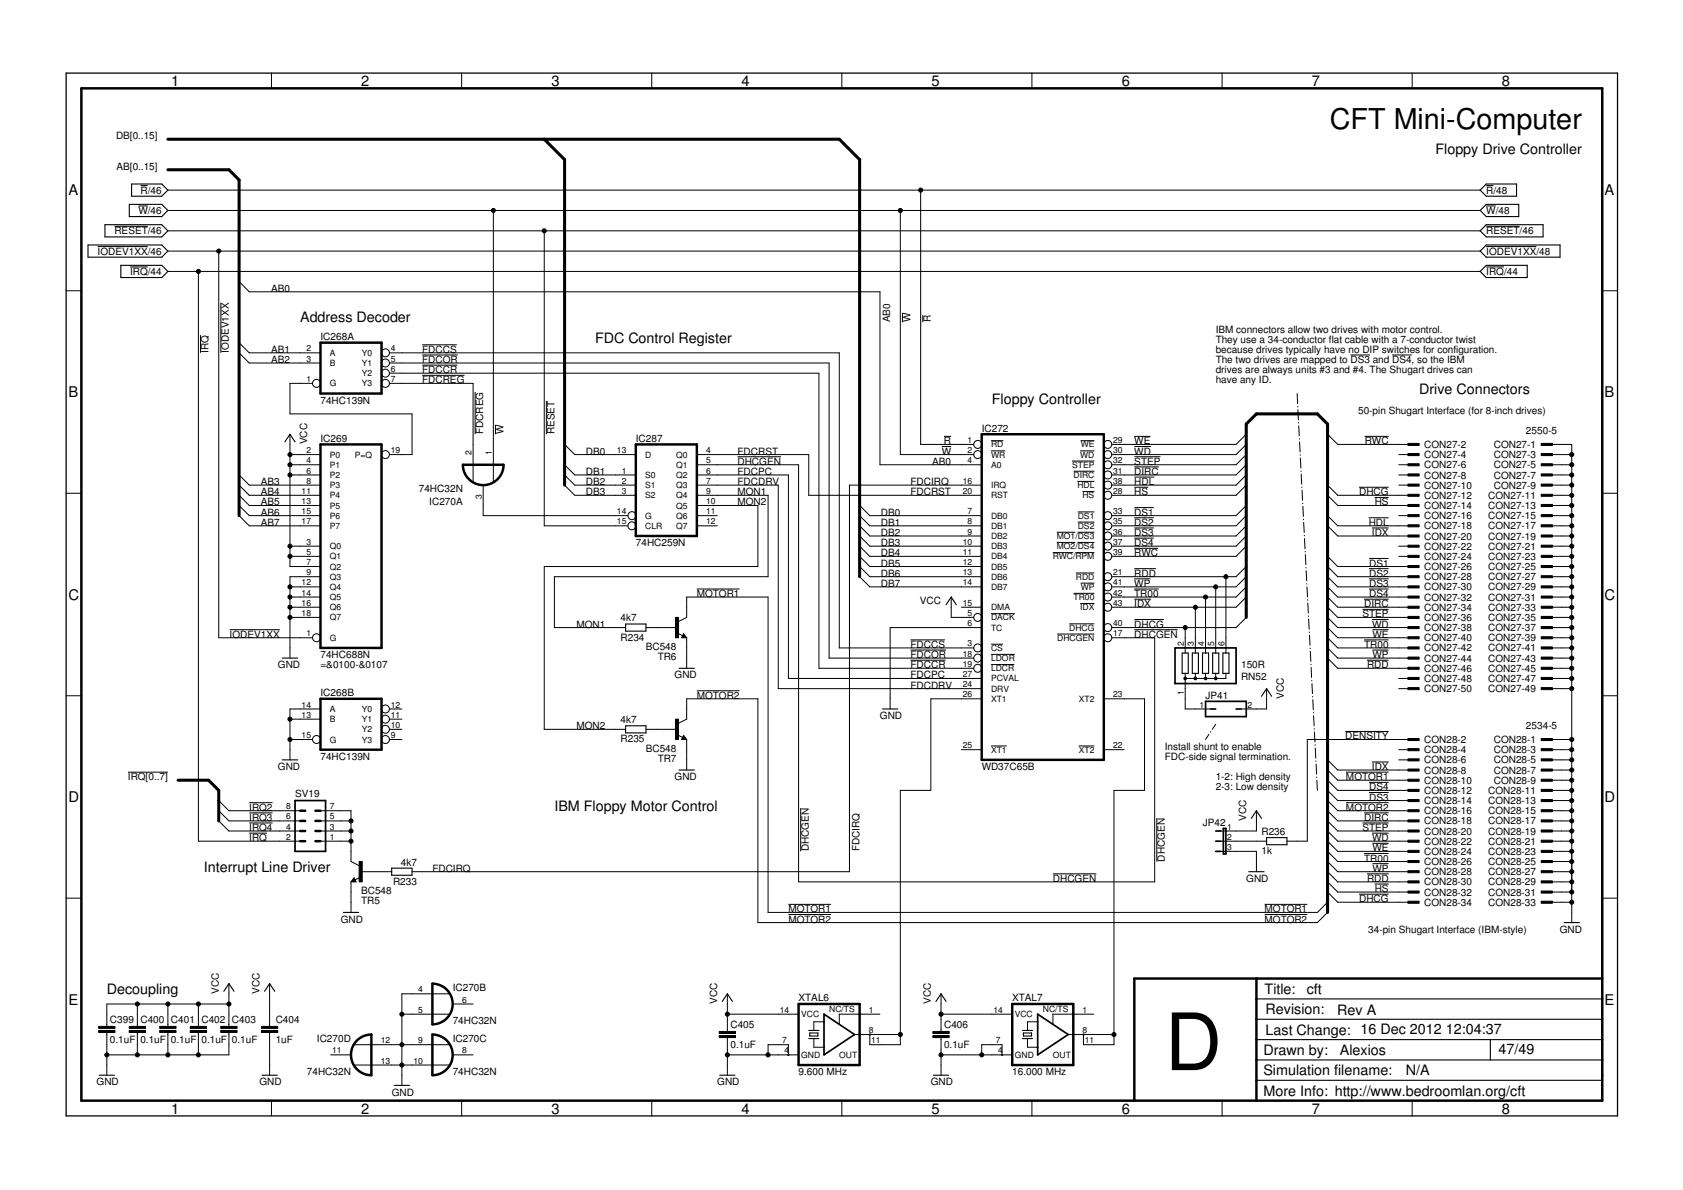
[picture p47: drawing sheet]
<svg xmlns="http://www.w3.org/2000/svg" width="420mm" height="297mm" viewBox="0 0 420 297" stroke-linecap="round" stroke-linejoin="round" font-family="sans-serif">
<defs><g id="words">
<text font-size="19.7" x="290.8" y="267.1">D</text>
<text font-size="7.2" x="332" y="32.2">CFT Mini-Computer</text>
<g font-size="3.7">
<text x="42.7" y="21.5">1</text>
<text x="90.2" y="21.5">2</text>
<text x="137.7" y="21.5">3</text>
<text x="185.1" y="21.5">4</text>
<text x="232.6" y="21.5">5</text>
<text x="280" y="21.5">6</text>
<text x="327.5" y="21.5">7</text>
<text x="375" y="21.5">8</text>
<text x="17.1" y="48.6">A</text>
<text x="400.6" y="48.6">A</text>
<text x="17.1" y="99.2">B</text>
<text x="400.6" y="99.2">B</text>
<text x="17.1" y="149.7">C</text>
<text x="400.6" y="149.7">C</text>
<text x="17.1" y="200.2">D</text>
<text x="400.6" y="200.2">D</text>
<text x="17.1" y="250.8">E</text>
<text x="400.6" y="250.8">E</text>
<text x="42.7" y="277.9">1</text>
<text x="90.2" y="277.9">2</text>
<text x="137.7" y="277.9">3</text>
<text x="185.1" y="277.9">4</text>
<text x="232.6" y="277.9">5</text>
<text x="280" y="277.9">6</text>
<text x="327.5" y="277.9">7</text>
<text x="375" y="277.9">8</text>
</g>
<g font-size="3.6">
<text x="358.4" y="38.6">Floppy Drive Controller</text>
<text x="74.9" y="80.5">Address Decoder</text>
<text x="148.6" y="85.5">FDC Control Register</text>
<text x="247.6" y="100.8">Floppy Controller</text>
<text x="354.3" y="98.2">Drive Connectors</text>
<text x="138.4" y="202.4">IBM Floppy Motor Control</text>
<text x="50.9" y="217.6">Interrupt Line Driver</text>
<text x="26.7" y="248.1">Decoupling</text>
<text x="315.7" y="248.1">Title:</text>
<text x="326.2" y="248.2">cft</text>
<text x="315.9" y="253.2">Revision:</text>
<text x="333.8" y="253.3">Rev A</text>
<text x="315.4" y="263.3">Drawn by:</text>
<text x="315.9" y="258.2">Last Change: 16 Dec 2012</text>
<text x="334.5" y="263.3">Alexios</text>
<text x="361" y="258.1">12:04:37</text>
<text x="374.1" y="263.2">47/49</text>
<text x="315.4" y="268.4">Simulation filename:</text>
<text x="351" y="268.4">N/A</text>
<text x="315.4" y="273.5">More Info: http://www.bedroomlan.org/cft</text>
</g>
<g font-size="2.5">
<text x="29" y="34.7">DB[0..15]</text>
<text x="29.1" y="42.4">AB[0..15]</text>
<text x="34.5" y="53.4">W/46</text>
<text x="35.1" y="48.3">R/46</text>
<text x="371" y="53.4">W/48</text>
<text x="371" y="48.3">R/48</text>
<text x="28.6" y="58.5">RESET/46</text>
<text x="371" y="58.5">RESET/46</text>
<text x="24.4" y="63.6">IODEV1XX/46</text>
<text x="371" y="63.6">IODEV1XX/48</text>
<text x="32.5" y="68.7">IRQ/44</text>
<text x="371" y="68.7">IRQ/44</text>
<text x="67.7" y="72.8">AB0</text>
<text x="222.2" y="80.5" transform="rotate(-90 222.2 80.5)">AB0</text>
<text x="227.3" y="80.5" transform="rotate(-90 227.3 80.5)">W</text>
<text x="232.4" y="80.5" transform="rotate(-90 232.4 80.5)">R</text>
<text x="303.5" y="83">IBM connectors allow two drives with motor control.</text>
<text x="52.1" y="88.1" transform="rotate(-90 52.1 88.1)">IRQ</text>
<text x="57.1" y="88.1" transform="rotate(-90 57.1 88.1)">IODEV1XX</text>
<text x="67.7" y="88.1">AB1</text>
<text x="80" y="84.9">IC268A</text>
<text x="105.4" y="88.1">FDCCS</text>
<text x="303.5" y="85.5">They use a 34-conductor flat cable with a 7-conductor twist</text>
<text x="303.5" y="88.1">because drives typically have no DIP switches for configuration.</text>
<text x="67.7" y="90.6">AB2</text>
<text x="105.4" y="90.6">FDCOR</text>
<text x="105.4" y="93.2">FDCCR</text>
<text x="105.4" y="95.7">FDCREG</text>
<text x="303.5" y="90.6">The two drives are mapped to DS3 and DS4, so the IBM</text>
<text x="303.5" y="93.2">drives are always units #3 and #4. The Shugart drives can</text>
<text x="303.5" y="95.7">have any ID.</text>
<text x="80" y="100.8">74HC139N</text>
<text x="245.1" y="107.8">IC272</text>
<text x="339.1" y="103.3">50-pin Shugart Interface (for 8-inch drives)</text>
<text x="76.7" y="110.9" transform="rotate(-90 76.7 110.9)">VCC</text>
<text x="80" y="110.3">IC269</text>
<text x="120.6" y="108.4" transform="rotate(-90 120.6 108.4)">FDCREG</text>
<text x="125.7" y="108.4" transform="rotate(-90 125.7 108.4)">W</text>
<text x="138.4" y="108.4" transform="rotate(-90 138.4 108.4)">RESET</text>
<text x="146.3" y="113.5">DB0</text>
<text x="158.7" y="110.3">IC287</text>
<text x="184.1" y="113.5">FDCRST</text>
<text x="235.1" y="113.5">W</text>
<text x="235.7" y="110.9">R</text>
<text x="283.2" y="110.9">WE</text>
<text x="283.2" y="113.5">WD</text>
<text x="340.7" y="110.9">RWC</text>
<text x="355.6" y="111.8">CON27-2</text>
<text x="372.9" y="111.8">CON27-1</text>
<text x="381" y="108.3">2550-5</text>
<text x="146.3" y="118.6">DB1</text>
<text x="184.1" y="116">DHCGEN</text>
<text x="184.1" y="118.6">FDCPC</text>
<text x="232.7" y="116">AB0</text>
<text x="283.2" y="116">STEP</text>
<text x="283.2" y="118.6">DIRC</text>
<text x="355.6" y="114.4">CON27-4</text>
<text x="355.6" y="116.9">CON27-6</text>
<text x="355.6" y="119.4">CON27-8</text>
<text x="372.9" y="114.4">CON27-3</text>
<text x="372.9" y="116.9">CON27-5</text>
<text x="372.9" y="119.4">CON27-7</text>
<text x="65.1" y="121.1">AB3</text>
<text x="65.1" y="123.6">AB4</text>
<text x="104.6" y="122.9">74HC32N</text>
<text x="146.3" y="121.1">DB2</text>
<text x="146.3" y="123.6">DB3</text>
<text x="184.1" y="121.1">FDCDRV</text>
<text x="184.1" y="123.6">MON1</text>
<text x="227.3" y="121.1">FDCIRQ</text>
<text x="227.3" y="123.6">FDCRST</text>
<text x="283.2" y="121.1">HDL</text>
<text x="283.2" y="123.6">HS</text>
<text x="339.3" y="123.6">DHCG</text>
<text x="355.6" y="122">CON27-10</text>
<text x="355.6" y="124.5">CON27-12</text>
<text x="371.5" y="124.5">CON27-11</text>
<text x="372.9" y="122">CON27-9</text>
<text x="65.1" y="126.2">AB5</text>
<text x="65.1" y="128.7">AB6</text>
<text x="65.1" y="131.3">AB7</text>
<text x="107.2" y="126">IC270A</text>
<text x="184.1" y="126.2">MON</text>
<text x="190" y="126.2">2</text>
<text x="219.9" y="128.7">DB0</text>
<text x="219.9" y="131.3">DB1</text>
<text x="283.2" y="128.7">DS1</text>
<text x="283.2" y="131.3">DS2</text>
<text x="341.7" y="131.3">HDL</text>
<text x="343.2" y="126.2">HS</text>
<text x="355.6" y="127.1">CON27-14</text>
<text x="355.6" y="129.6">CON27-16</text>
<text x="371.5" y="127.1">CON27-13</text>
<text x="371.5" y="129.6">CON27-15</text>
<text x="158.7" y="136.3">74HC259N</text>
<text x="219.9" y="133.8">DB2</text>
<text x="219.9" y="136.3">DB3</text>
<text x="283.2" y="136.3">DS4</text>
<text x="283.2" y="133.8">DS3</text>
<text x="342.5" y="133.8">IDX</text>
<text x="355.6" y="132.1">CON27-18</text>
<text x="355.6" y="134.7">CON27-20</text>
<text x="355.6" y="137.2">CON27-22</text>
<text x="371.5" y="132.1">CON27-17</text>
<text x="371.5" y="134.7">CON27-19</text>
<text x="371.5" y="137.2">CON27-21</text>
<text x="219.9" y="138.9">DB4</text>
<text x="219.9" y="141.4">DB5</text>
<text x="219.9" y="144">DB6</text>
<text x="283.2" y="138.9">RWC</text>
<text x="283.2" y="144">RDD</text>
<text x="341.8" y="141.4">DS1</text>
<text x="341.8" y="144">DS2</text>
<text x="355.6" y="139.8">CON27-24</text>
<text x="355.6" y="142.3">CON27-26</text>
<text x="371.5" y="139.8">CON27-23</text>
<text x="371.5" y="142.3">CON27-25</text>
<text x="174" y="149">MOTOR1</text>
<text x="219.9" y="146.5">DB7</text>
<text x="283.2" y="146.5">WP</text>
<text x="283.2" y="149">TR00</text>
<text x="341.8" y="149">DS4</text>
<text x="341.8" y="146.5">DS3</text>
<text x="355.6" y="144.8">CON27-28</text>
<text x="355.6" y="147.4">CON27-30</text>
<text x="355.6" y="149.9">CON27-32</text>
<text x="371.5" y="144.8">CON27-27</text>
<text x="371.5" y="147.4">CON27-29</text>
<text x="371.5" y="149.9">CON27-31</text>
<text x="154.9" y="155.1">4k7</text>
<text x="229.6" y="150.8">VCC</text>
<text x="283.2" y="151.6">IDX</text>
<text x="340.2" y="154.1">STEP</text>
<text x="340.6" y="151.6">DIRC</text>
<text x="355.6" y="152.5">CON27-34</text>
<text x="355.6" y="155">CON27-36</text>
<text x="371.5" y="152.5">CON27-33</text>
<text x="371.5" y="155">CON27-35</text>
<text x="57.3" y="159.2">IODEV1XX</text>
<text x="143.9" y="156.6">MON1</text>
<text x="154.9" y="159.9">R234</text>
<text x="227.3" y="161.7">FDCCS</text>
<text x="283.2" y="156.6">DHCG</text>
<text x="283.2" y="159.2">DHCGEN</text>
<text x="340.6" y="161.7">TR00</text>
<text x="342.5" y="156.6">WD</text>
<text x="342.6" y="159.2">WE</text>
<text x="355.6" y="157.5">CON27-38</text>
<text x="355.6" y="160.1">CON27-40</text>
<text x="371.5" y="157.5">CON27-37</text>
<text x="371.5" y="160.1">CON27-39</text>
<text x="69.4" y="166.8">GND</text>
<text x="80" y="166.8">=&amp;0100-&amp;0107</text>
<text x="80" y="164.3">74HC688N</text>
<text x="161.2" y="162.2">BC548</text>
<text x="164.2" y="164.8">TR6</text>
<text x="227.3" y="164.3">FDCOR</text>
<text x="227.3" y="166.8">FDCCR</text>
<text x="309.8" y="166.7">150R</text>
<text x="341.3" y="166.8">RDD</text>
<text x="342.6" y="164.3">WP</text>
<text x="355.6" y="162.6">CON27-42</text>
<text x="355.6" y="165.2">CON27-44</text>
<text x="355.6" y="167.7">CON27-46</text>
<text x="371.5" y="162.6">CON27-41</text>
<text x="371.5" y="165.2">CON27-43</text>
<text x="371.5" y="167.7">CON27-45</text>
<text x="80" y="173.8">IC268B</text>
<text x="168.4" y="169.3">GND</text>
<text x="227.3" y="169.3">FDCPC</text>
<text x="227.3" y="171.9">FDCDRV</text>
<text x="309.8" y="169.9">RN52</text>
<text x="355.6" y="170.2">CON27-48</text>
<text x="355.6" y="172.8">CON27-50</text>
<text x="371.5" y="170.2">CON27-47</text>
<text x="371.5" y="172.8">CON27-49</text>
<text x="174" y="174.4">MOTOR2</text>
<text x="219.7" y="179.5">GND</text>
<text x="301" y="174.4">JP41</text>
<text x="320.5" y="174.4" transform="rotate(-90 320.5 174.4)">VCC</text>
<text x="143.9" y="182">MON2</text>
<text x="154.9" y="180.5">4k7</text>
<text x="154.9" y="185.3">R235</text>
<text x="335.9" y="184.6">DENSITY</text>
<text x="355.6" y="185.5">CON28-2</text>
<text x="372.9" y="185.5">CON28-1</text>
<text x="381" y="181.9">2534-5</text>
<text x="80" y="189.7">74HC139N</text>
<text x="161.2" y="187.6">BC548</text>
<text x="164.2" y="190.2">TR7</text>
<text x="290.8" y="187.1">Install shunt to enable</text>
<text x="290.8" y="189.7">FDC-side signal termination.</text>
<text x="355.6" y="188">CON28-4</text>
<text x="355.6" y="190.6">CON28-6</text>
<text x="372.9" y="188">CON28-3</text>
<text x="372.9" y="190.6">CON28-5</text>
<text x="31.9" y="194.7">IRQ[0..7]</text>
<text x="69.4" y="192.2">GND</text>
<text x="168.4" y="194.7">GND</text>
<text x="245.1" y="192.2">WD37C65B</text>
<text x="303.5" y="194.7">1-2: High density</text>
<text x="303.5" y="197.3">2-3: Low density</text>
<text x="336" y="194.7">MOTOR1</text>
<text x="341.8" y="197.3">DS4</text>
<text x="342.5" y="192.2">IDX</text>
<text x="355.6" y="193.1">CON28-8</text>
<text x="355.6" y="195.6">CON28-10</text>
<text x="372.9" y="193.1">CON28-7</text>
<text x="372.9" y="195.6">CON28-9</text>
<text x="62.2" y="202.4">IRQ2</text>
<text x="73.7" y="199.1">SV19</text>
<text x="336" y="202.4">MOTOR2</text>
<text x="341.8" y="199.8">DS3</text>
<text x="355.6" y="198.2">CON28-12</text>
<text x="355.6" y="200.7">CON28-14</text>
<text x="355.6" y="203.3">CON28-16</text>
<text x="371.5" y="198.2">CON28-11</text>
<text x="371.5" y="200.7">CON28-13</text>
<text x="371.5" y="203.3">CON28-15</text>
<text x="62.2" y="210">IRQ</text>
<text x="62.2" y="204.9">IRQ3</text>
<text x="62.2" y="207.4">IRQ4</text>
<text x="300.3" y="206.2">JP42</text>
<text x="311.1" y="204.9" transform="rotate(-90 311.1 204.9)">VCC</text>
<text x="314.9" y="208.5">R236</text>
<text x="340.2" y="207.4">STEP</text>
<text x="340.6" y="204.9">DIRC</text>
<text x="342.5" y="210">WD</text>
<text x="355.6" y="205.8">CON28-18</text>
<text x="355.6" y="208.3">CON28-20</text>
<text x="371.5" y="205.8">CON28-17</text>
<text x="371.5" y="208.3">CON28-19</text>
<text x="201.9" y="212.5" transform="rotate(-90 201.9 212.5)">DHCGEN</text>
<text x="214.6" y="212.5" transform="rotate(-90 214.6 212.5)">FDCIRQ</text>
<text x="290.8" y="215.1" transform="rotate(-90 290.8 215.1)">DHCGEN</text>
<text x="314.9" y="213.3">1k</text>
<text x="340.6" y="215.1">TR00</text>
<text x="342.6" y="212.5">WE</text>
<text x="355.6" y="210.9">CON28-22</text>
<text x="355.6" y="213.4">CON28-24</text>
<text x="355.6" y="215.9">CON28-26</text>
<text x="371.5" y="210.9">CON28-21</text>
<text x="371.5" y="213.4">CON28-23</text>
<text x="371.5" y="215.9">CON28-25</text>
<text x="98.1" y="220.9">R233</text>
<text x="100.1" y="216.1">4k7</text>
<text x="107.9" y="217.6">FDCIRQ</text>
<text x="262.9" y="220.1">DHCGEN</text>
<text x="311.1" y="220.1">GND</text>
<text x="341.3" y="220.1">RDD</text>
<text x="342.6" y="217.6">WP</text>
<text x="355.6" y="218.5">CON28-28</text>
<text x="355.6" y="221">CON28-30</text>
<text x="371.5" y="218.5">CON28-27</text>
<text x="371.5" y="221">CON28-29</text>
<text x="90.2" y="223.2">BC548</text>
<text x="90.2" y="225.7">TR5</text>
<text x="196.8" y="227.8">MOTOR1</text>
<text x="315.7" y="227.8">MOTOR1</text>
<text x="339.3" y="225.2">DHCG</text>
<text x="343.2" y="222.7">HS</text>
<text x="355.6" y="223.6">CON28-32</text>
<text x="355.6" y="226.1">CON28-34</text>
<text x="371.5" y="223.6">CON28-31</text>
<text x="371.5" y="226.1">CON28-33</text>
<text x="85.1" y="230.3">GND</text>
<text x="196.8" y="230.3">MOTOR2</text>
<text x="315.7" y="230.3">MOTOR2</text>
<text x="341.6" y="232.8">34-pin Shugart Interface (IBM-style)</text>
<text x="389.4" y="232.8">GND</text>
<text x="54.6" y="248.1" transform="rotate(-90 54.6 248.1)">VCC</text>
<text x="64.8" y="248.1" transform="rotate(-90 64.8 248.1)">VCC</text>
<text x="113" y="247.4">IC270B</text>
<text x="179.1" y="250.6" transform="rotate(-90 179.1 250.6)">VCC</text>
<text x="199.4" y="250">XTAL6</text>
<text x="232.4" y="250.6" transform="rotate(-90 232.4 250.6)">VCC</text>
<text x="252.7" y="250">XTAL7</text>
<text x="27.4" y="255.3">C399</text>
<text x="35" y="255.3">C400</text>
<text x="42.7" y="255.3">C401</text>
<text x="50.3" y="255.3">C402</text>
<text x="57.9" y="255.3">C403</text>
<text x="68.8" y="255.3">C404</text>
<text x="113" y="255.7">74HC32N</text>
<text x="182.4" y="256.6">C405</text>
<text x="235.7" y="256.6">C406</text>
<text x="27.4" y="260.4">0.1uF</text>
<text x="35" y="260.4">0.1uF</text>
<text x="42.7" y="260.4">0.1uF</text>
<text x="50.3" y="260.4">0.1uF</text>
<text x="57.9" y="260.4">0.1uF</text>
<text x="68.8" y="260.4">1uF</text>
<text x="79.1" y="260.1">IC270D</text>
<text x="113" y="260.1">IC270C</text>
<text x="182.4" y="261.7">0.1uF</text>
<text x="235.7" y="261.7">0.1uF</text>
<text x="76.6" y="268.4">74HC32N</text>
<text x="113" y="268.4">74HC32N</text>
<text x="199.4" y="268.4">9.600 MHz</text>
<text x="252.7" y="268.4">16.000 MHz</text>
<text x="24.1" y="270.9">GND</text>
<text x="64.8" y="270.9">GND</text>
<text x="97.8" y="273.5">GND</text>
<text x="179.1" y="270.9">GND</text>
<text x="232.4" y="270.9">GND</text>
</g>
<g font-size="2.1">
<text x="76.5" y="87.7">2</text>
<text x="82.3" y="88.8">A</text>
<text x="90.3" y="88.8">Y0</text>
<text x="97.6" y="87.7">4</text>
<text x="76.5" y="95.3">1</text>
<text x="76.5" y="90.3">3</text>
<text x="82.3" y="91.4">B</text>
<text x="90.3" y="91.4">Y1</text>
<text x="90.3" y="93.9">Y2</text>
<text x="97.6" y="90.3">5</text>
<text x="97.6" y="92.8">6</text>
<text x="97.6" y="95.3">7</text>
<text x="82.3" y="96.5">G</text>
<text x="90.3" y="96.5">Y3</text>
<text x="76.5" y="113.1">2</text>
<text x="97.6" y="113.1">19</text>
<text x="117.7" y="113.7" transform="rotate(-90 117.7 113.7)">2</text>
<text x="122.8" y="113.7" transform="rotate(-90 122.8 113.7)">1</text>
<text x="154" y="113.1">13</text>
<text x="176.3" y="113.1">4</text>
<text x="241.6" y="110.6">1</text>
<text x="241.6" y="113.1">2</text>
<text x="247.4" y="111.7">RD</text>
<text x="269.8" y="111.7">WE</text>
<text x="277.9" y="110.6">29</text>
<text x="277.9" y="113.1">30</text>
<text x="76.5" y="115.7">4</text>
<text x="76.5" y="118.2">6</text>
<text x="82.3" y="114.2">P0</text>
<text x="82.3" y="116.8">P1</text>
<text x="82.3" y="119.3">P2</text>
<text x="88.6" y="114.2">P=Q</text>
<text x="155.2" y="118.2">1</text>
<text x="161.1" y="119.3">S0</text>
<text x="161.1" y="114.2">D</text>
<text x="168.8" y="114.2">Q0</text>
<text x="168.8" y="116.8">Q1</text>
<text x="168.8" y="119.3">Q2</text>
<text x="176.3" y="115.7">5</text>
<text x="176.3" y="118.2">6</text>
<text x="241.6" y="115.7">4</text>
<text x="247.4" y="114.2">WR</text>
<text x="247.4" y="116.8">A0</text>
<text x="267.6" y="116.8">STEP</text>
<text x="268" y="119.3">DIRC</text>
<text x="269.7" y="114.2">WD</text>
<text x="277.9" y="118.2">31</text>
<text x="277.9" y="115.7">32</text>
<text x="75.3" y="123.3">11</text>
<text x="75.3" y="125.8">13</text>
<text x="76.5" y="120.7">8</text>
<text x="82.3" y="121.9">P3</text>
<text x="82.3" y="124.4">P4</text>
<text x="120.3" y="124.6" transform="rotate(-90 120.3 124.6)">3</text>
<text x="155.2" y="120.7">2</text>
<text x="155.2" y="123.3">3</text>
<text x="161.1" y="121.9">S1</text>
<text x="161.1" y="124.4">S2</text>
<text x="168.8" y="121.9">Q3</text>
<text x="168.8" y="124.4">Q4</text>
<text x="176.3" y="120.7">7</text>
<text x="176.3" y="123.3">9</text>
<text x="176.3" y="125.8">10</text>
<text x="240.4" y="120.7">16</text>
<text x="240.4" y="123.3">20</text>
<text x="247.4" y="121.9">IRQ</text>
<text x="247.4" y="124.4">RST</text>
<text x="269" y="121.9">HDL</text>
<text x="270.3" y="124.4">HS</text>
<text x="277.9" y="123.3">28</text>
<text x="277.9" y="120.7">38</text>
<text x="75.3" y="128.4">15</text>
<text x="75.3" y="130.9">17</text>
<text x="82.3" y="126.9">P5</text>
<text x="82.3" y="129.5">P6</text>
<text x="154" y="128.4">14</text>
<text x="154" y="130.9">15</text>
<text x="161.1" y="129.5">G</text>
<text x="168.8" y="126.9">Q5</text>
<text x="168.8" y="129.5">Q6</text>
<text x="176.3" y="128.4">11</text>
<text x="176.3" y="130.9">12</text>
<text x="241.6" y="128.4">7</text>
<text x="241.6" y="130.9">8</text>
<text x="247.4" y="129.5">DB0</text>
<text x="269.1" y="129.5">DS1</text>
<text x="277.9" y="128.4">33</text>
<text x="277.9" y="130.9">35</text>
<text x="76.5" y="136">3</text>
<text x="82.3" y="137.1">Q0</text>
<text x="82.3" y="132">P7</text>
<text x="161.1" y="132">CLR</text>
<text x="168.8" y="132">Q7</text>
<text x="240.4" y="136">10</text>
<text x="241.6" y="133.4">9</text>
<text x="247.4" y="132">DB1</text>
<text x="247.4" y="134.6">DB2</text>
<text x="247.4" y="137.1">DB3</text>
<text x="263.8" y="134.6">MO1/DS3</text>
<text x="263.8" y="137.1">MO2/DS4</text>
<text x="269.1" y="132">DS2</text>
<text x="277.9" y="133.4">36</text>
<text x="277.9" y="136">37</text>
<text x="76.5" y="138.5">5</text>
<text x="76.5" y="141.1">7</text>
<text x="76.5" y="143.6">9</text>
<text x="82.3" y="139.6">Q1</text>
<text x="82.3" y="142.2">Q2</text>
<text x="240.4" y="138.5">11</text>
<text x="240.4" y="141.1">12</text>
<text x="240.4" y="143.6">13</text>
<text x="247.4" y="139.6">DB4</text>
<text x="247.4" y="142.2">DB5</text>
<text x="262.8" y="139.6">RWC/RPM</text>
<text x="277.9" y="143.6">21</text>
<text x="277.9" y="138.5">39</text>
<text x="75.3" y="146.1">12</text>
<text x="75.3" y="148.7">14</text>
<text x="82.3" y="144.7">Q3</text>
<text x="82.3" y="147.3">Q4</text>
<text x="82.3" y="149.8">Q5</text>
<text x="240.4" y="146.1">14</text>
<text x="247.4" y="144.7">DB6</text>
<text x="247.4" y="147.3">DB7</text>
<text x="268" y="149.8">TR00</text>
<text x="268.6" y="144.7">RDD</text>
<text x="269.8" y="147.3">WP</text>
<text x="277.9" y="146.1">41</text>
<text x="277.9" y="148.7">42</text>
<text x="75.3" y="151.2">16</text>
<text x="75.3" y="153.8">18</text>
<text x="82.3" y="152.3">Q6</text>
<text x="82.3" y="154.9">Q7</text>
<text x="240.4" y="151.2">15</text>
<text x="241.6" y="153.8">5</text>
<text x="247.4" y="154.9">DACK</text>
<text x="247.4" y="152.3">DMA</text>
<text x="269.7" y="152.3">IDX</text>
<text x="277.9" y="151.2">43</text>
<text x="76.5" y="158.8">1</text>
<text x="82.3" y="159.9">G</text>
<text x="241.6" y="161.4">3</text>
<text x="241.6" y="156.3">6</text>
<text x="247.4" y="157.4">TC</text>
<text x="264" y="160">DHCGEN</text>
<text x="266.9" y="157.4">DHCG</text>
<text x="277.9" y="158.8">17</text>
<text x="277.9" y="156.3">40</text>
<text x="295.5" y="161.4" transform="rotate(-90 295.5 161.4)">2</text>
<text x="298.1" y="161.4" transform="rotate(-90 298.1 161.4)">3</text>
<text x="300.6" y="161.4" transform="rotate(-90 300.6 161.4)">4</text>
<text x="303.1" y="161.4" transform="rotate(-90 303.1 161.4)">5</text>
<text x="305.7" y="161.4" transform="rotate(-90 305.7 161.4)">6</text>
<text x="240.4" y="163.9">18</text>
<text x="240.4" y="166.5">19</text>
<text x="247.4" y="162.5">CS</text>
<text x="247.4" y="165">LDOR</text>
<text x="247.4" y="167.6">LDCR</text>
<text x="240.4" y="171.5">24</text>
<text x="240.4" y="169">27</text>
<text x="247.4" y="172.6">DRV</text>
<text x="247.4" y="170.1">PCVAL</text>
<text x="295.5" y="173.4" transform="rotate(-90 295.5 173.4)">1</text>
<text x="75.3" y="176.6">14</text>
<text x="75.3" y="179.1">13</text>
<text x="82.3" y="177.7">A</text>
<text x="90.3" y="177.7">Y0</text>
<text x="97.6" y="176.6">12</text>
<text x="97.6" y="179.1">11</text>
<text x="240.4" y="174.1">26</text>
<text x="247.4" y="175.2">XT1</text>
<text x="269.3" y="175.2">XT2</text>
<text x="277.9" y="174.1">23</text>
<text x="299.4" y="176.6">1</text>
<text x="311.5" y="176.6">2</text>
<text x="75.3" y="184.2">15</text>
<text x="82.3" y="185.3">G</text>
<text x="82.3" y="180.3">B</text>
<text x="90.3" y="180.3">Y1</text>
<text x="90.3" y="182.8">Y2</text>
<text x="90.3" y="185.3">Y3</text>
<text x="97.6" y="181.7">10</text>
<text x="97.6" y="184.2">9</text>
<text x="240.4" y="186.8">25</text>
<text x="247.4" y="187.9">XT1</text>
<text x="269.3" y="187.9">XT2</text>
<text x="277.9" y="186.8">22</text>
<text x="71.4" y="202">8</text>
<text x="82.3" y="202">7</text>
<text x="71.4" y="209.6">2</text>
<text x="71.4" y="207.1">4</text>
<text x="71.4" y="204.5">6</text>
<text x="82.3" y="209.6">1</text>
<text x="82.3" y="207.1">3</text>
<text x="82.3" y="204.5">5</text>
<text x="306.4" y="207.1">1</text>
<text x="306.4" y="209.6">2</text>
<text x="306.4" y="212.2">3</text>
<text x="104.4" y="247.7">4</text>
<text x="115.4" y="250.3">6</text>
<text x="104.4" y="252.8">5</text>
<text x="194.7" y="252.8">14</text>
<text x="200" y="253.9">VCC</text>
<text x="207" y="252.6">NC/TS</text>
<text x="216.9" y="257.9">8</text>
<text x="216.9" y="252.8">1</text>
<text x="248" y="252.8">14</text>
<text x="253.3" y="253.9">VCC</text>
<text x="260.3" y="252.6">NC/TS</text>
<text x="270.3" y="257.9">8</text>
<text x="270.3" y="252.8">1</text>
<text x="82.9" y="263">11</text>
<text x="95" y="260.4">12</text>
<text x="104.4" y="260.4">9</text>
<text x="115.4" y="263">8</text>
<text x="195.3" y="260.4">7</text>
<text x="195.8" y="263">4</text>
<text x="217.5" y="260.4">11</text>
<text x="248.6" y="260.4">7</text>
<text x="249.2" y="263">4</text>
<text x="270.8" y="260.4">11</text>
<text x="95" y="265.5">13</text>
<text x="103.2" y="265.5">10</text>
<text x="200" y="264.1">GND</text>
<text x="209.5" y="264.1">OUT</text>
<text x="253.3" y="264.1">GND</text>
<text x="262.9" y="264.1">OUT</text>
</g>
</g></defs>
<g fill="#000" stroke="#000" stroke-width=".25">
<path d="M67.8 18.2v3.9zM115.3 18.2v3.9zM162.7 18.2v3.9zM210.2 18.2v3.9zM257.6 18.2v3.9zM305.1 18.2v3.9zM352.5 18.2v3.9zM20.3 22.1v252.6zM20.3 22.1h379.7zM28.6 56.5h8.3zM34.5 51.4h2.4zM35.1 46.3h1.8z"/>
<path d="M41.9 52.5h81.3zM41.9 47.5h187.9zM123.2 52.5h101.6zM41.9 57.6h94zM224.8 52.5h144.7zM229.8 47.5h139.7zM135.9 57.6h233.6zM371 51.4h2.4zM371 46.3h1.8zM371 56.5h8.4zM16.5 72.6h3.8zM24.4 61.6h12.5z"/>
<path d="M32.5 66.6h4.4zM41.9 67.8h7.6zM41.9 62.7h12.7zM49.5 67.8h320zM54.6 62.7h314.9zM54.6 62.7v96.5zM59.7 70.3l2.5 2.5zM62.2 72.8h157.5zM219.7 72.8v43.2zM371 66.6h4.5zM371 61.6h12.6zM400 72.6h3.8z"/>
<path d="M50.1 83.6v4.5zM55.1 75.6v12.5zM59.7 85.5l2.5 2.6zM59.7 88.1l2.5 2.5zM72.4 95.7v7.6zM74.9 95.7h3.1zM74.9 88.1h5.1zM74.9 90.6h5.1zM62.2 88.1h12.7zM62.2 90.6h12.7zM72.4 95.7h2.5zM97.2 88.1h3.1z"/>
<path d="M97.2 90.6h3.1zM97.2 93.2h3.1zM97.2 95.7h3.1zM100.3 88.1h109.2zM100.3 95.7h17.8zM105.4 86.1h8.6zM105.4 88.6h8.9zM105.4 91.1h8.8zM105.4 93.7h10.6zM100.3 93.2h104.1zM100.3 90.6h106.7zM225.3 78.1v2.4z"/>
<path d="M230.4 78.7v1.8zM323.8 98.2l.2 2.6zM337.2 88.6h4.8zM347.6 88.6h4.8zM72.4 108.4v2.5zM72.4 116v2.6zM72.4 113.5v2.5zM72.4 110.9v2.6zM72.4 103.3h30.5zM74.9 113.5h5.1zM74.9 116h5.1zM74.9 118.6h5.1z"/>
<path d="M72.4 118.6h2.5zM72.4 116h2.5zM72.4 113.5h2.5zM97.2 113.5h3.1zM100.3 113.5h2.6zM102.9 103.3v10.2zM118.1 110.9v5.1zM118.1 95.7v15.2zM118.6 97.8v10.6zM123.2 110.9v5.1zM123.2 52.5v58.4zM123.7 106v2.4z"/>
<path d="M136.4 100.1v8.3zM140.9 110.9l2.6 2.6zM140.9 116l2.6 2.6zM153.6 118.6h5.1zM153.6 113.5h5.1zM143.5 113.5h10.1zM143.5 118.6h10.1zM174 113.5h5zM174 116h5zM174 118.6h5zM179 113.5h22.9zM179 118.6h17.8z"/>
<path d="M184.1 114h10.9zM196.8 118.6v50.8zM179 116h20.4zM201.9 113.5v10.1zM219.7 116h20.3zM224.8 52.5v61zM229.8 47.5v63.4zM235.1 111.5h2.4zM235.7 108.9h1.8zM240 110.9h3.1zM240 113.5h3.1zM240 116h5.1z"/>
<path d="M224.8 113.5h15.2zM229.8 110.9h10.2zM247.4 110h3.1zM247.4 112.5h3.5zM267.6 115.1h5.6zM268 117.6h5.2zM269.7 112.5h3.5zM269.8 110h3.4zM277.5 110.9h3.1zM277.5 113.5h3.1zM277.5 118.6h3.1zM277.5 116h3.1z"/>
<path d="M280.6 110.9h28zM280.6 113.5h28zM280.6 116h28zM280.6 118.6h28zM283.2 108.9h4zM283.2 111.5h4.1zM283.2 114h6.5zM283.2 116.5h6.1zM283.2 119.1h5zM308.6 110.9l2.5-2.5zM308.6 113.5l2.5-2.6zM308.6 116l2.5-2.5z"/>
<path d="M308.6 118.6l2.5-2.6zM324 101.5v.1zM324 102.3l.1 2.5zM324.2 105.5v.1zM324.2 106.3l.2 2.5zM324.4 109.5v.1zM324.4 110.3l.2 2.5zM324.6 113.5v.1zM324.6 114.3l.2 2.5zM324.8 117.5v.2zM324.8 118.3l.2 2.6zM331.4 108.4l2.6 2.5z"/>
<path d="M340.7 108.9h6zM349.2 110.9h2.5zM349.2 113.5h2.5zM349.2 116h2.5zM349.2 118.6h2.5zM334 110.9h15.2zM387.3 110.9h2.5zM387.3 113.5h2.5zM387.3 116h2.5zM387.3 118.6h2.5zM389.8 110.9h2.6zM389.8 113.5h2.6z"/>
<path d="M389.8 116h2.6zM389.8 118.6h2.6zM392.4 110.9v2.6zM392.4 113.5v2.5zM392.4 116v2.6zM392.4 118.6v2.5zM16.5 123.1h3.8zM59.7 121.1l2.5 2.5zM59.7 123.6l2.5 2.6zM59.7 126.2l2.5 2.5zM59.7 128.7l2.5 2.6zM59.7 118.6l2.5 2.5z"/>
<path d="M62.2 123.6h12.7zM62.2 126.2h12.7zM62.2 128.7h12.7zM62.2 131.3h12.7zM72.4 136.3v2.6zM72.4 118.6v17.7zM74.9 136.3h5.1zM74.9 138.9h5.1zM74.9 121.1h5.1zM74.9 123.6h5.1zM74.9 126.2h5.1zM74.9 128.7h5.1z"/>
<path d="M74.9 131.3h5.1zM72.4 138.9h2.5zM72.4 136.3h2.5zM62.2 121.1h12.7zM118.1 116v4.3zM120.6 121.1v5.1zM120.6 126.2v2.5zM120.6 128.7h33zM123.2 116v4.3zM135.9 57.6v73.7zM140.9 118.6l2.6 2.5zM140.9 121.1l2.6 2.5z"/>
<path d="M153.6 121.1h5.1zM153.6 123.6h5.1zM153.6 128.7h3.2zM153.6 131.3h3.2zM143.5 121.1h10.1zM143.5 123.6h10.1zM135.9 131.3h17.7zM174 121.1h5zM174 123.6h5zM174 126.2h5zM174 128.7h5zM174 131.3h5z"/>
<path d="M179 123.6h12.7zM179 126.2h10.2zM189.2 126.2v15.2zM191.7 123.6v20.4zM179 121.1h15.3zM201.9 123.6h38.1zM214.6 126.2l2.5 2.5zM214.6 128.7l2.5 2.6zM214.6 131.3l2.5 2.5zM214.6 133.8l2.5 2.5zM214.6 136.3l2.5 2.6zM240 128.7h5.1z"/>
<path d="M240 131.3h5.1zM240 133.8h5.1zM240 136.3h5.1zM240 138.9h5.1zM240 121.1h5.1zM240 123.6h5.1zM217.1 128.7h22.9zM217.1 131.3h22.9zM217.1 133.8h22.9zM217.1 136.3h22.9zM217.1 138.9h22.9zM212.1 121.1h27.9z"/>
<path d="M262.8 137.9h5.1zM263.8 132.9h4.7zM263.8 135.4h4.7zM268.5 137.9h4.7zM269 120.2h4.2zM269 127.8h4.2zM269 130.3h4.2zM269 132.9h4.2zM269 135.4h4.2zM270.3 122.7h2.9zM277.5 123.6h3.1zM277.5 128.7h3.1z"/>
<path d="M277.5 131.3h3.1zM277.5 133.8h3.1zM277.5 136.3h3.1zM277.5 121.1h3.1zM277.5 138.9h3.1zM280.6 121.1h28zM280.6 123.6h28zM280.6 128.7h28zM280.6 131.3h28zM280.6 136.3h28zM280.6 133.8h28zM280.6 138.9h28z"/>
<path d="M283.2 121.6h3.5zM283.2 126.7h4.9zM283.2 129.2h4.9zM283.2 134.3h4.9zM283.2 131.8h4.9zM283.2 136.9h6zM308.6 121.1l2.5-2.5zM308.6 123.6l2.5-2.5zM308.6 128.7l2.5-2.5zM308.6 131.3l2.5-2.6zM308.6 136.3l2.5-2.5zM308.6 133.8l2.5-2.5z"/>
<path d="M308.6 138.9l2.5-2.6zM325 121.6v.1zM325.1 122.4l.1 2.5zM325.2 125.6v.1zM325.3 126.4l.1 2.5zM325.4 129.6v.1zM325.5 130.4l.1 2.5zM325.6 133.6v.1zM325.7 134.4l.1 2.5zM325.8 137.6v.2zM325.9 138.4l.1 2.6zM331.4 128.7l2.6 2.6z"/>
<path d="M331.4 123.6l2.6 2.6zM331.4 131.3l2.6 2.5zM331.4 121.1l2.6 2.5zM339.3 121.6h7.4zM341.7 129.2h5zM341.8 139.4h4.9zM342.5 131.8h4.2zM343.2 124.2h3.5zM349.2 121.1h2.5zM349.2 123.6h2.5zM349.2 126.2h2.5zM349.2 128.7h2.5z"/>
<path d="M349.2 131.3h2.5zM349.2 133.8h2.5zM349.2 136.3h2.5zM349.2 138.9h2.5zM334 131.3h15.2zM334 126.2h15.2zM334 133.8h15.2zM334 123.6h15.2zM387.3 121.1h2.5zM387.3 123.6h2.5zM387.3 126.2h2.5zM387.3 128.7h2.5z"/>
<path d="M387.3 131.3h2.5zM387.3 133.8h2.5zM387.3 136.3h2.5zM387.3 138.9h2.5zM389.8 121.1h2.6zM389.8 123.6h2.6zM389.8 126.2h2.6zM389.8 128.7h2.6zM389.8 131.3h2.6zM389.8 133.8h2.6zM389.8 136.3h2.6zM389.8 138.9h2.6z"/>
<path d="M392.4 121.1v2.5zM392.4 123.6v2.6zM392.4 126.2v2.5zM392.4 128.7v2.6zM392.4 131.3v2.5zM392.4 133.8v2.5zM392.4 136.3v2.6zM392.4 138.9v2.5zM400 123.1h3.8zM57.3 157.2h12.5zM72.4 146.5v2.5zM72.4 149v2.6z"/>
<path d="M72.4 151.6v2.5zM72.4 154.1v7.6zM72.4 144v2.5zM72.4 138.9v2.5zM74.9 159.2h3.1zM74.9 141.4h5.1zM74.9 144h5.1zM74.9 146.5h5.1zM74.9 149h5.1zM74.9 151.6h5.1zM74.9 154.1h5.1zM72.4 146.5h2.5z"/>
<path d="M72.4 149h2.5zM72.4 151.6h2.5zM72.4 154.1h2.5zM72.4 144h2.5zM72.4 141.4h2.5zM54.6 159.2h20.3zM135.9 141.4v40.7zM138.4 144v12.7zM138.4 156.7h15.2zM153.6 156.7h2.6zM161.3 156.7h2.5zM163.8 156.7h2.5z"/>
<path d="M166.3 156.7h2.6zM170.7 158.2l-.5 1zM169.2 158.1l1.2 .6zM170.7 158.2l.7 1zM171.4 151.6v2.5zM169.4 155.1l2-1zM170.2 159.2h1.2zM171.4 149v2.6zM171.4 149h20.3zM174 147h10.6zM135.9 141.4h53.3zM138.4 144h53.3z"/>
<path d="M191.7 149v78.7zM214.6 138.9l2.5 2.5zM214.6 141.4l2.5 2.6zM214.6 144l2.5 2.5zM222.2 156.7h17.8zM227.3 159.7h8.6zM237.5 149v2.6zM237.5 151.6v2.5zM240 154.1h3.1zM240 156.7h5.1zM240 141.4h5.1zM240 144h5.1z"/>
<path d="M240 146.5h5.1zM240 151.6h5.1zM237.5 154.1h2.5zM217.1 141.4h22.9zM217.1 144h22.9zM217.1 146.5h22.9zM247.4 153.2h5.9zM263.9 158.3h9.3zM266.9 155.7h6.3zM268 148.1h5.2zM268.6 143h4.6zM269.7 150.6h3.5z"/>
<path d="M269.8 145.6h3.4zM277.5 144h3.1zM277.5 146.5h3.1zM277.5 149h3.1zM277.5 151.6h3.1zM277.5 159.2h3.1zM277.5 156.7h3.1zM280.6 144h25.4zM280.6 146.5h22.9zM280.6 149h20.4zM280.6 151.6h17.8zM280.6 156.7h15.3z"/>
<path d="M280.6 159.2h7.7zM283.2 141.9h5.4zM283.2 144.5h4zM283.2 147h6.1zM283.2 149.6h4.2zM283.2 154.6h7.3zM283.2 157.2h10.8zM288.3 159.2v60.9zM295.9 159.2v2.5zM295.9 156.7h12.7zM295.9 156.7v2.5zM298.4 159.2v2.5z"/>
<path d="M298.4 151.6h10.2zM298.4 151.6v7.6zM301 159.2v2.5zM301 149h7.6zM301 149v10.2zM303.5 159.2v2.5zM303.5 146.5h5.1zM303.5 146.5v12.7zM306 159.2v2.5zM306 144h2.6zM306 144v15.2zM308.6 144l2.5-2.6z"/>
<path d="M308.6 146.5l2.5-2.5zM308.6 149l2.5-2.5zM308.6 151.6l2.5-2.6zM308.6 156.7l2.5-2.6zM326 141.7v.1zM326.1 142.5l.1 2.5zM326.2 145.7l.1 .1zM326.3 146.5l.1 2.5zM326.4 149.7l.1 .1zM326.5 150.5l.1 2.5zM326.7 153.7v.2zM326.7 154.5l.1 2.6z"/>
<path d="M326.9 157.8v.1zM326.9 158.6l.1 2.5zM331.4 156.7l2.6 2.5zM331.4 154.1l2.6 2.6zM331.4 151.6l2.6 2.5zM331.4 149l2.6 2.6zM331.4 138.9l2.6 2.5zM331.4 141.4l2.6 2.6zM331.4 146.5l2.6 2.5zM331.4 144l2.6 2.5zM340.1 152.1h6.6zM340.5 149.6h6.2z"/>
<path d="M340.6 159.7h6.1zM341.8 141.9h4.9zM341.8 147h4.9zM341.8 144.5h4.9zM342.5 154.6h4.2zM342.6 157.2h4.1zM349.2 141.4h2.5zM349.2 144h2.5zM349.2 146.5h2.5zM349.2 149h2.5zM349.2 151.6h2.5zM349.2 154.1h2.5z"/>
<path d="M349.2 156.7h2.5zM349.2 159.2h2.5zM334 159.2h15.2zM334 156.7h15.2zM334 154.1h15.2zM334 151.6h15.2zM334 141.4h15.2zM334 144h15.2zM334 149h15.2zM334 146.5h15.2zM387.3 141.4h2.5zM387.3 144h2.5z"/>
<path d="M387.3 146.5h2.5zM387.3 149h2.5zM387.3 151.6h2.5zM387.3 154.1h2.5zM387.3 156.7h2.5zM387.3 159.2h2.5zM389.8 141.4h2.6zM389.8 144h2.6zM389.8 146.5h2.6zM389.8 149h2.6zM389.8 151.6h2.6zM389.8 154.1h2.6z"/>
<path d="M389.8 156.7h2.6zM389.8 159.2h2.6zM392.4 141.4v2.6zM392.4 144v2.5zM392.4 146.5v2.5zM392.4 149v2.6zM392.4 151.6v2.5zM392.4 154.1v2.6zM392.4 156.7v2.5zM392.4 159.2v2.5zM16.5 173.7h3.8zM72.4 161.7v2.6z"/>
<path d="M72.4 177v2.5zM72.4 179.5v5.1zM74.9 177h5.1zM74.9 179.5h5.1zM72.4 177h2.5zM72.4 179.5h2.5zM97.2 177h3.1zM97.2 179.5h3.1zM171.4 164.3v2.5zM171.4 159.2v2.5zM171.4 177v2.5zM169.4 180.5l2-1z"/>
<path d="M171.4 161.7v2.6zM171.4 174.4v2.6zM171.4 174.4h17.8zM174 172.4h10.6zM189.2 174.4v55.9zM194.3 121.1v50.8zM196.8 169.4h43.2zM204.4 93.2v73.6zM207 90.6v73.7zM209.5 88.1v73.6zM222.2 174.4v2.6zM222.2 156.7v17.7z"/>
<path d="M227.3 162.3h8.9zM227.3 164.8h8.8zM232.4 174.4h7.6zM240 161.7h3.1zM240 164.3h3.1zM240 166.8h3.1zM240 171.9h5.1zM240 174.4h5.1zM240 169.4h5.1zM209.5 161.7h30.5zM207 164.3h33zM204.4 166.8h35.6z"/>
<path d="M194.3 171.9h45.7zM247.4 160.8h3zM247.4 163.3h5.9zM247.4 165.9h5.8zM275.6 174.4h5zM280.6 174.4h5.1zM295.9 171.9v2.5zM295.9 161.7v1.3zM295.9 168.1v1.3zM295.9 169.4h2.5zM295.9 169.4v2.5zM295.9 174.4v2.6z"/>
<path d="M298.4 168.1v1.3zM298.4 169.4h2.6zM298.4 161.7v1.3zM298.4 177h2.6zM295.9 177h2.5zM301 168.1v1.3zM301 169.4h2.5zM301 161.7v1.3zM301 177h1.2zM303.5 168.1v1.3zM303.5 169.4h2.5zM303.5 161.7v1.3z"/>
<path d="M306 168.1v1.3zM306 161.7v1.3zM309.9 177h1.2zM311.1 177h2.6zM316.2 171.9v2.5zM316.2 174.4v2.6zM313.7 177h2.5zM327.1 161.8v.1zM327.1 162.6l.2 2.5zM327.3 165.8v.1zM327.3 166.6l.1 2.5zM327.5 169.8v.1z"/>
<path d="M327.5 170.6l.2 2.5zM327.7 173.8v.2zM327.7 174.6l.2 2.6zM327.9 177.9v.1zM327.9 178.7l.2 2.5zM331.4 164.3l2.6 2.5zM331.4 161.7l2.6 2.6zM331.4 159.2l2.6 2.5zM341.3 164.8h5.4zM342.6 162.3h4.1zM349.2 161.7h2.5zM349.2 164.3h2.5z"/>
<path d="M349.2 166.8h2.5zM349.2 169.4h2.5zM349.2 171.9h2.5zM334 166.8h15.2zM334 164.3h15.2zM334 161.7h15.2zM387.3 161.7h2.5zM387.3 164.3h2.5zM387.3 166.8h2.5zM387.3 169.4h2.5zM387.3 171.9h2.5zM389.8 161.7h2.6z"/>
<path d="M389.8 164.3h2.6zM389.8 166.8h2.6zM389.8 169.4h2.6zM389.8 171.9h2.6zM392.4 161.7v2.6zM392.4 164.3v2.5zM392.4 166.8v2.6zM392.4 169.4v2.5zM392.4 171.9v12.7zM400 173.7h3.8zM31.9 192.7h10zM72.4 187.1v2.6z"/>
<path d="M72.4 184.6v2.5zM74.9 184.6h3.1zM72.4 184.6h2.5zM97.2 182.1h3.1zM97.2 184.6h3.1zM153.6 182.1h2.6zM135.9 182.1h17.7zM161.3 182.1h2.5zM163.8 182.1h2.5zM166.3 182.1h2.6zM170.7 183.6l-.5 1zM169.2 183.5l1.2 .6z"/>
<path d="M170.7 183.6l.7 1zM171.4 189.7v2.5zM171.4 184.6v2.5zM170.2 184.6h1.2zM171.4 187.1v2.6zM224.8 197.3h7.6zM232.4 174.4v22.9zM240 187.1h5.1zM247.4 186.2h3.9zM269.3 186.2h3.9zM278.1 197.3h7.6zM275.6 187.1h5z"/>
<path d="M285.7 174.4v22.9zM301.8 183.3l-.8 1.3zM303.5 180.8l-.9 1.3zM326.4 184.6h22.8zM328.1 181.9v.1zM328.1 182.7l.2 2.5zM328.3 185.9v.1zM328.4 186.7l.1 2.5zM328.5 189.9v.2zM328.6 190.7l.1 2.5zM328.7 193.9v.2zM328.8 194.8l.1 2.5z"/>
<path d="M331.4 194.8l2.6 2.5zM331.4 197.3l2.6 2.5zM331.4 189.7l2.6 2.5zM331.4 192.2l2.6 2.6zM335.8 182.6h10.9zM336 192.7h10.7zM341.8 195.3h4.9zM341.8 197.8h4.9zM342.5 190.2h4.2zM349.2 184.6h2.5zM349.2 187.1h2.5zM349.2 189.7h2.5z"/>
<path d="M349.2 192.2h2.5zM349.2 194.8h2.5zM349.2 197.3h2.5zM349.2 199.8h2.5zM334 197.3h15.2zM334 199.8h15.2zM334 192.2h15.2zM334 194.8h15.2zM387.3 184.6h2.5zM387.3 187.1h2.5zM387.3 189.7h2.5zM387.3 192.2h2.5z"/>
<path d="M387.3 194.8h2.5zM387.3 197.3h2.5zM387.3 199.8h2.5zM389.8 184.6h2.6zM389.8 187.1h2.6zM389.8 189.7h2.6zM389.8 192.2h2.6zM389.8 194.8h2.6zM389.8 197.3h2.6zM389.8 199.8h2.6zM392.4 184.6v2.5zM392.4 187.1v2.6z"/>
<path d="M392.4 189.7v2.5zM392.4 192.2v2.6zM392.4 194.8v2.5zM392.4 197.3v2.5zM392.4 199.8v2.6zM49.5 67.8v142.2zM54.6 199.8l2.5 2.6zM54.6 202.4l2.5 2.5zM54.6 204.9l2.5 2.5zM62.2 208h4.5zM62.2 200.4h5.8zM62.2 202.9h5.8z"/>
<path d="M62.2 205.4h5.8zM69.8 210h5.1zM69.8 207.4h5.1zM69.8 204.9h5.1zM69.8 202.4h5.1zM49.5 210h20.3zM57.1 202.4h12.7zM57.1 204.9h12.7zM57.1 207.4h12.7zM80 210h5.1zM80 207.4h5.1zM80 204.9h5.1z"/>
<path d="M80 202.4h5.1zM85.1 210h2.5zM85.1 204.9h2.5zM87.6 212.5v2.5zM87.6 215l2.1 1.1zM85.1 207.4h2.5zM87.6 207.4v2.6zM87.6 204.9v2.5zM85.1 202.4h2.5zM87.6 202.4v2.5zM87.6 210v2.5zM88.4 219.1l-.8 1z"/>
<path d="M88.6 219.6l1.3-.6zM90.2 217.6h2.5zM95.2 217.6h2.6zM92.7 217.6h2.5zM102.9 217.6h2.5zM199.9 201.7v10.8zM105.4 217.6h106.7zM212.1 121.1v96.5zM262.9 218.1h10.8zM288.8 204.2v10.8zM304.8 212.5h1.2zM304.8 210h1.2z"/>
<path d="M304.8 207.4h1.2zM306 207.4h2.6zM306 210h2.6zM306 212.5h2.6zM308.6 212.5h5.1zM308.6 207.4h5.1zM313.7 210h2.5zM313.7 215v2.6zM313.7 202.4v2.5zM313.7 212.5v2.5zM313.7 204.9v2.5zM308.6 210h5.1z"/>
<path d="M321.3 210h2.5zM323.8 210h2.6zM326.4 184.6v25.4zM331.4 210l2.6 2.5zM331.4 207.4l2.6 2.6zM331.4 204.9l2.6 2.5zM331.4 202.4l2.6 2.5zM331.4 215l2.6 2.6zM331.4 212.5l2.6 2.5zM331.4 199.8l2.6 2.6zM336 200.4h10.7zM340.1 205.4h6.6z"/>
<path d="M340.5 202.9h6.2zM340.6 213h6.1zM341.3 218.1h5.4zM342.5 208h4.2zM342.6 210.5h4.1zM342.6 215.6h4.1zM349.2 202.4h2.5zM349.2 204.9h2.5zM349.2 207.4h2.5zM349.2 210h2.5zM349.2 212.5h2.5zM349.2 215h2.5z"/>
<path d="M349.2 217.6h2.5zM334 212.5h15.2zM334 210h15.2zM334 207.4h15.2zM334 204.9h15.2zM334 217.6h15.2zM334 215h15.2zM334 202.4h15.2zM387.3 202.4h2.5zM387.3 204.9h2.5zM387.3 207.4h2.5zM387.3 210h2.5z"/>
<path d="M387.3 212.5h2.5zM387.3 215h2.5zM387.3 217.6h2.5zM389.8 202.4h2.6zM389.8 204.9h2.6zM389.8 207.4h2.6zM389.8 210h2.6zM389.8 212.5h2.6zM389.8 215h2.6zM389.8 217.6h2.6zM392.4 202.4v2.5zM392.4 204.9v2.5z"/>
<path d="M392.4 207.4v2.6zM392.4 212.5v10.2zM392.4 210v2.5zM392.4 212.5v2.5zM392.4 215v2.6zM392.4 217.6v2.5zM16.5 224.2h3.8zM87.6 225.2v2.5zM87.6 220.1v2.6zM87.6 220.1h1.3zM87.6 222.7v2.5zM88.4 219.1l.5 1z"/>
<path d="M189.2 230.3h139.7zM196.8 225.7h10.7zM196.8 228.3h10.7zM199.4 116v104.1zM199.4 220.1h88.9zM315.7 225.7h10.7zM315.7 228.3h10.7zM191.7 227.7h137.2zM328.9 230.3l2.5-2.6zM331.4 225.2l-2.5 2.5zM331.4 220.1l2.6 2.6zM331.4 217.6l2.6 2.5z"/>
<path d="M331.4 222.7l2.6 2.5zM339.3 223.2h7.4zM343.2 220.7h3.5zM349.2 220.1h2.5zM349.2 222.7h2.5zM349.2 225.2h2.5zM334 222.7h15.2zM334 220.1h15.2zM334 225.2h15.2zM387.3 220.1h2.5zM387.3 222.7h2.5zM387.3 225.2h2.5z"/>
<path d="M389.8 220.1h2.6zM389.8 222.7h2.6zM389.8 225.2h2.6zM392.4 227.7v2.6zM392.4 222.7v2.5zM392.4 225.2v2.5zM392.4 220.1v2.6zM400 224.2h3.8zM26.7 253.1v2.6zM26.7 257.7v.5zM26.7 255.7v.5zM26.7 250.6v2.5z"/>
<path d="M34.3 253.1v2.6zM34.3 257.7v.5zM34.3 255.7v.5zM34.3 250.6v2.5zM26.7 250.6h7.6zM41.9 253.1v2.6zM41.9 257.7v.5zM41.9 255.7v.5zM34.3 250.6h7.6zM41.9 250.6v2.5zM49.5 253.1v2.6zM49.5 257.7v.5z"/>
<path d="M49.5 255.7v.5zM41.9 250.6h7.6zM49.5 250.6v2.5zM57.1 245.5v2.6zM57.1 253.1v2.6zM57.1 257.7v.5zM57.1 255.7v.5zM49.5 250.6h7.6zM57.1 248.1v2.5zM57.1 250.6v2.5zM67.3 245.5v2.6zM67.3 253.1v2.6z"/>
<path d="M67.3 255.7v.5zM67.3 257.7v.5zM67.3 248.1v5zM100.3 248.1v5zM100.3 253.1v7.7zM102.9 248.1h5zM102.9 253.1h5zM100.3 248.1h2.6zM100.3 253.1h2.6zM107.9 248.1h4.4zM107.9 253.1h4.4zM113 250.6h5.1z"/>
<path d="M181.6 248.1v2.5zM181.6 254.4v2.6zM181.6 259v.5zM181.6 257v.5zM181.6 253.1h12.7zM181.6 253.1v1.3zM181.6 250.6v2.5zM194.3 253.1h5.1zM203.2 255.1h2.5zM203.2 255.1v2.1zM209.5 253.1v2.6zM213.3 258.2h1.3z"/>
<path d="M209.5 253.1h5.1zM217.1 258.2v2.6zM214.6 258.2h5.1zM214.6 253.1h5.1zM219.7 258.2h5.1zM224.8 197.3v60.9zM234.9 248.1v2.5zM234.9 254.4v2.6zM234.9 259v.5zM234.9 257v.5zM234.9 253.1h12.7zM234.9 253.1v1.3z"/>
<path d="M234.9 250.6v2.5zM247.6 253.1h5.1zM256.5 255.1h2.6zM256.5 255.1v2.1zM262.9 253.1v2.6zM266.7 258.2h1.2zM262.9 253.1h5zM270.5 258.2v2.6zM267.9 258.2h5.1zM267.9 253.1h5.1zM273 258.2h5.1zM278.1 197.3v60.9z"/>
<path d="M278.1 258.2v2.6zM20.3 274.7h379.7zM26.7 265.8v2.6zM26.7 258.2v2.6zM26.7 260.8v2.5zM26.7 263.3h7.6zM26.7 263.3v2.5zM34.3 258.2v2.6zM34.3 260.8v2.5zM41.9 258.2v2.6zM34.3 263.3h7.6zM41.9 260.8v2.5z"/>
<path d="M49.5 258.2v2.6zM41.9 263.3h7.6zM49.5 260.8v2.5zM57.1 258.2v2.6zM49.5 263.3h7.6zM57.1 260.8v2.5zM67.3 265.8v2.6zM67.3 258.2v2.6zM67.3 260.8v5zM67.8 274.7v3.8zM82.5 263.3h5.1zM88.4 260.8h4.3z"/>
<path d="M88.4 265.8h4.3zM92.7 260.8h5.1zM92.7 265.8h5.1zM97.8 260.8h2.5zM97.8 265.8h2.5zM100.3 268.4v2.5zM100.3 260.8v5zM100.3 265.8v2.6zM100.3 260.8h2.6zM100.3 265.8h2.6zM102.9 260.8h5zM102.9 265.8h5z"/>
<path d="M107.9 260.8h4.4zM107.9 265.8h4.4zM115.3 274.7v3.8zM113 263.3h5.1zM162.7 274.7v3.8zM181.6 265.8v2.6zM181.6 259.5v2.5zM181.6 263.3h10.1zM181.6 262v1.3zM181.6 263.3v2.5zM191.7 263.3h2.6zM191.7 260.8v2.5z"/>
<path d="M194.3 263.3h5.1zM194.3 260.8h2.5zM191.7 260.8h2.6zM196.8 260.8v2.5zM203.2 261.4h2.5zM203.2 259.2v2.2zM210.2 274.7v3.8zM217.1 260.8h2.6zM219.7 260.8h5.1zM224.8 258.2v2.6zM234.9 265.8v2.6zM234.9 259.5v2.5z"/>
<path d="M234.9 263.3h10.2zM234.9 262v1.3zM234.9 263.3v2.5zM245.1 263.3h2.5zM245.1 260.8v2.5zM247.6 263.3h5.1zM247.6 260.8h2.6zM245.1 260.8h2.5zM250.2 260.8v2.5zM256.5 261.4h2.6zM256.5 259.2v2.2zM257.6 274.7v3.8z"/>
<path d="M270.5 260.8h2.5zM273 260.8h5.1zM305.1 274.7v3.8zM352.5 274.7v3.8zM400 264.5v.1zM400 268.4v6.2zM400 274.6h.1zM400 22.1v252.6z"/>
<circle cx="123.2" cy="52.5" r=".51"/>
<circle cx="135.9" cy="57.6" r=".51"/>
<circle cx="224.8" cy="52.5" r=".51"/>
<circle cx="229.8" cy="47.5" r=".51"/>
<circle cx="49.5" cy="67.8" r=".51"/>
<circle cx="54.6" cy="62.7" r=".51"/>
<circle cx="72.4" cy="118.6" r=".51"/>
<circle cx="72.4" cy="113.5" r=".51"/>
<circle cx="72.4" cy="116" r=".51"/>
<circle cx="392.4" cy="113.5" r=".51"/>
<circle cx="392.4" cy="118.6" r=".51"/>
<circle cx="392.4" cy="116" r=".51"/>
<circle cx="72.4" cy="136.3" r=".51"/>
<circle cx="72.4" cy="138.9" r=".51"/>
<circle cx="392.4" cy="133.8" r=".51"/>
<circle cx="392.4" cy="136.3" r=".51"/>
<circle cx="392.4" cy="131.3" r=".51"/>
<circle cx="392.4" cy="128.7" r=".51"/>
<circle cx="392.4" cy="126.2" r=".51"/>
<circle cx="392.4" cy="121.1" r=".51"/>
<circle cx="392.4" cy="138.9" r=".51"/>
<circle cx="392.4" cy="123.6" r=".51"/>
<circle cx="72.4" cy="146.5" r=".51"/>
<circle cx="72.4" cy="151.6" r=".51"/>
<circle cx="72.4" cy="149" r=".51"/>
<circle cx="72.4" cy="154.1" r=".51"/>
<circle cx="295.9" cy="156.7" r=".51"/>
<circle cx="298.4" cy="151.6" r=".51"/>
<circle cx="301" cy="149" r=".51"/>
<circle cx="303.5" cy="146.5" r=".51"/>
<circle cx="306" cy="144" r=".51"/>
<circle cx="392.4" cy="159.2" r=".51"/>
<circle cx="392.4" cy="151.6" r=".51"/>
<circle cx="392.4" cy="144" r=".51"/>
<circle cx="392.4" cy="156.7" r=".51"/>
<circle cx="392.4" cy="141.4" r=".51"/>
<circle cx="392.4" cy="154.1" r=".51"/>
<circle cx="392.4" cy="149" r=".51"/>
<circle cx="392.4" cy="146.5" r=".51"/>
<circle cx="72.4" cy="179.5" r=".51"/>
<circle cx="392.4" cy="161.7" r=".51"/>
<circle cx="392.4" cy="171.9" r=".51"/>
<circle cx="392.4" cy="169.4" r=".51"/>
<circle cx="392.4" cy="166.8" r=".51"/>
<circle cx="392.4" cy="164.3" r=".51"/>
<circle cx="72.4" cy="184.6" r=".51"/>
<circle cx="392.4" cy="197.3" r=".51"/>
<circle cx="392.4" cy="194.8" r=".51"/>
<circle cx="392.4" cy="199.8" r=".51"/>
<circle cx="392.4" cy="192.2" r=".51"/>
<circle cx="392.4" cy="187.1" r=".51"/>
<circle cx="392.4" cy="189.7" r=".51"/>
<circle cx="392.4" cy="184.6" r=".51"/>
<circle cx="87.6" cy="210" r=".51"/>
<circle cx="87.6" cy="204.9" r=".51"/>
<circle cx="87.6" cy="207.4" r=".51"/>
<circle cx="392.4" cy="204.9" r=".51"/>
<circle cx="392.4" cy="202.4" r=".51"/>
<circle cx="392.4" cy="207.4" r=".51"/>
<circle cx="392.4" cy="210" r=".51"/>
<circle cx="392.4" cy="212.5" r=".51"/>
<circle cx="392.4" cy="215" r=".51"/>
<circle cx="392.4" cy="217.6" r=".51"/>
<circle cx="392.4" cy="225.2" r=".51"/>
<circle cx="392.4" cy="220.1" r=".51"/>
<circle cx="392.4" cy="222.7" r=".51"/>
<circle cx="34.3" cy="250.6" r=".51"/>
<circle cx="41.9" cy="250.6" r=".51"/>
<circle cx="49.5" cy="250.6" r=".51"/>
<circle cx="57.1" cy="250.6" r=".51"/>
<circle cx="100.3" cy="253.1" r=".51"/>
<circle cx="181.6" cy="253.1" r=".51"/>
<circle cx="224.8" cy="258.2" r=".51"/>
<circle cx="234.9" cy="253.1" r=".51"/>
<circle cx="278.1" cy="258.2" r=".51"/>
<circle cx="26.7" cy="263.3" r=".51"/>
<circle cx="34.3" cy="263.3" r=".51"/>
<circle cx="41.9" cy="263.3" r=".51"/>
<circle cx="49.5" cy="263.3" r=".51"/>
<circle cx="100.3" cy="265.8" r=".51"/>
<circle cx="100.3" cy="260.8" r=".51"/>
<circle cx="181.6" cy="263.3" r=".51"/>
<circle cx="191.7" cy="263.3" r=".51"/>
<circle cx="234.9" cy="263.3" r=".51"/>
<circle cx="245.1" cy="263.3" r=".51"/>
</g>
<g fill="#000" stroke="#000" stroke-width=".28">
<path d="M26.2 56.1v3zM32.3 51v3.1zM32.9 45.9v3.1zM32.3 51h8.1zM32.3 54.1h8.1zM32.9 45.9h7.5zM32.9 49h7.5zM26.2 56.1h14.2zM26.2 59.1h14.2zM40.4 51l1.5 1.5zM41.9 52.5l-1.5 1.6zM40.4 45.9l1.5 1.6z"/>
<path d="M41.9 47.5l-1.5 1.5zM40.4 56.1l1.5 1.5zM41.9 57.6l-1.5 1.5zM369.5 52.5l1.5-1.5zM369.5 52.5l1.5 1.6zM369.5 47.5l1.5-1.6zM369.5 47.5l1.5 1.5zM371 56.1l-1.5 1.5zM369.5 57.6l1.5 1.5zM371 51h8.2zM371 54.1h8.2zM371 45.9h7.6z"/>
<path d="M371 49h7.6zM371 56.1h14.2zM371 59.1h14.2zM378.6 45.9v3.1zM379.2 51v3.1zM385.2 56.1v3zM22 61.1v3.1zM30.2 66.2v3.1zM30.2 69.3h10.2zM30.2 66.2h10.2zM22 64.2h18.4zM22 61.1h18.4z"/>
<path d="M41.9 67.8l-1.5 1.5zM40.4 66.2l1.5 1.6zM40.4 64.2l1.5-1.5zM40.4 61.1l1.5 1.6zM371 66.2l-1.5 1.6zM369.5 67.8l1.5 1.5zM371 61.1l-1.5 1.6zM369.5 62.7l1.5 1.5zM371 66.2h10.3zM371 69.3h10.3zM371 61.1h18.5zM371 64.2h18.5z"/>
<path d="M381.3 66.2v3.1zM389.5 61.1v3.1zM72.4 108.4l-1.3 1.9zM72.4 108.4l1.3 1.9zM156.2 155.8h5.1zM156.2 155.8v1.7zM156.2 157.5h5.1zM161.3 155.8v1.7zM170.4 159.1h.8zM170.4 158.9h.4zM170.7 158.4l-.3 .5zM170.7 158.7l.1 .2z"/>
<path d="M170.7 158.4l.5 .7zM237.5 149l-1.3 1.9zM237.5 149l1.2 1.9zM70.5 164.3h3.8zM169.5 166.8h3.8zM220.3 177h3.8zM295.1 163v5.1zM295.1 163h.8zM295.9 163h.7zM295.1 168.1h.8zM296.6 163v5.1zM295.9 168.1h.7z"/>
<path d="M297.7 163h.7zM297.7 163v5.1zM298.4 163h.8zM297.7 168.1h.7zM298.4 168.1h.8zM299.2 163v5.1zM300.2 163v5.1zM300.2 163h.8zM300.2 168.1h.8zM301 163h.7zM301.7 163v5.1zM301 168.1h.7z"/>
<path d="M302.7 163v5.1zM302.7 163h.8zM302.7 168.1h.8zM303.5 163h.8zM304.3 163v5.1zM303.5 168.1h.8zM305.3 163v5.1zM305.3 163h.7zM305.3 168.1h.7zM306 163h.8zM306.8 163v5.1zM306 168.1h.8z"/>
<path d="M316.2 171.9l-1.3 1.9zM316.2 171.9l1.3 1.9zM70.5 189.7h3.8zM156.2 181.2h5.1zM156.2 181.2v1.7zM156.2 182.9h5.1zM161.3 181.2v1.7zM170.4 184.5h.8zM170.4 184.3h.4zM170.7 183.8l-.3 .5zM170.7 184.1l.1 .2zM170.7 183.8l.5 .7z"/>
<path d="M169.5 192.2h3.8zM88.4 219.6l-.1 .3zM88.4 219.4l.2 .5zM88.3 219.9h.3zM97.8 218.5h5.1zM97.8 216.7v1.8zM97.8 216.7h5.1zM102.9 216.7v1.8zM311.8 217.6h3.8zM313.7 202.4l-1.3 1.9zM313.7 202.4l1.2 1.9zM316.2 210.9h5.1z"/>
<path d="M316.2 209.1v1.8zM316.2 209.1h5.1zM321.3 209.1v1.8zM85.7 227.7h3.8zM88.4 219.4l-.5 .6zM87.9 220h.7zM390.5 230.3h3.8zM57.1 245.5l-1.2 1.9zM57.1 245.5l1.3 1.9zM67.3 245.5l-1.3 1.9zM67.3 245.5l1.3 1.9zM181.6 248.1l-1.3 1.9z"/>
<path d="M181.6 248.1l1.3 1.9zM201.9 259.2h1.3zM201.9 257.2h2.5zM202.2 257.8v.8zM202.2 257.8h2zM202.2 258.6h2zM203.2 259.2h1.2zM204.2 257.8v.8zM234.9 248.1l-1.2 1.9zM234.9 248.1l1.3 1.9zM255.2 259.2h1.3zM255.2 257.2h2.6z"/>
<path d="M255.5 257.8v.8zM255.5 257.8h2zM255.5 258.6h2zM256.5 259.2h1.3zM257.5 257.8v.8zM313.7 249.3h86.3zM313.7 254.4h86.3zM313.7 259.5h58.4zM372.1 259.5h27.9zM372.1 259.5v5.1zM24.8 268.4h3.8zM65.4 268.4h3.8z"/>
<path d="M98.4 270.9h3.8zM179.7 268.4h3.8zM233 268.4h3.8zM313.7 264.6h58.4zM313.7 269.7h86.3zM372.1 264.6h27.9zM400 268.4v1.3z"/>
</g>
<path d="M16.5 18.2v260.3zM16.5 18.2h387.3zM16.5 278.5h387.3zM403.8 18.2v260.3z" fill="#000" stroke="#000" stroke-width=".32"/>
<g fill="#000" stroke="#000" stroke-width=".61">
<path d="M20.3 22.1v252.6zM20.3 22.1h379.7zM80 98.2h15.2zM80 85.5v12.7zM95.2 85.5v12.7zM80 85.5h15.2zM80 110.9v50.8zM80 110.9h15.2zM115.6 116h10.1zM158.7 110.9v22.9zM158.7 110.9h15.3zM245.1 108.4h30.5z"/>
<path d="M275.6 108.4v81.3zM158.7 133.8h15.3zM174 110.9v22.9zM80 161.7h15.2zM80 174.4v12.7zM95.2 110.9v50.8zM80 174.4h15.2zM80 187.1h15.2zM95.2 174.4v12.7zM245.1 108.4v81.3zM245.1 189.7h30.5zM74.9 204.9h1.3z"/>
<path d="M74.9 207.4h1.3zM74.9 210h1.3zM74.9 202.4h1.3zM78.7 204.9h1.3zM78.7 207.4h1.3zM78.7 210h1.3zM78.7 202.4h1.3zM92.7 258.2v10.2zM107.9 245.5v10.2zM107.9 258.2v10.2zM199.4 250.6v15.2zM199.4 250.6h15.2z"/>
<path d="M214.6 253.1v5.1zM214.6 250.6v2.5zM252.7 250.6v15.2zM252.7 250.6h15.2zM267.9 253.1v5.1zM267.9 250.6v2.5zM283.2 244.3v30.4zM313.7 254.4v5.1zM313.7 249.3v5.1zM313.7 244.3v5zM313.7 244.3h86.3zM283.2 244.3h30.5z"/>
<path d="M400 254.4v5.1zM400 249.3v5.1zM400 244.3v5zM400 22.1v222.2zM20.3 274.7h262.9zM199.4 265.8h15.2zM214.6 258.2v7.6zM252.7 265.8h15.2zM267.9 258.2v7.6zM283.2 274.7h30.5zM313.7 274.7h86.3zM313.7 269.7v5z"/>
<path d="M313.7 264.6v5.1zM313.7 259.5v5.1zM400 268.4v6.3zM400 264.6v3.8zM400 259.5v5.1z"/>
</g>
<g fill="#000" stroke="#000" stroke-width=".25">
<path d="M351.5 110.7h2.8v.5h-2.8zM351.5 113.2h2.8v.5h-2.8zM351.5 115.8h2.8v.5h-2.8zM351.5 118.3h2.8v.5h-2.8zM384.8 110.7h2.8v.5h-2.8zM384.8 113.2h2.8v.5h-2.8zM384.8 115.8h2.8v.5h-2.8zM384.8 118.3h2.8v.5h-2.8zM351.5 120.8h2.8v.5h-2.8zM351.5 123.4h2.8v.5h-2.8zM351.5 125.9h2.8v.5h-2.8zM351.5 128.5h2.8v.5h-2.8z"/>
<path d="M351.5 131h2.8v.5h-2.8zM351.5 133.5h2.8v.5h-2.8zM351.5 136.1h2.8v.5h-2.8zM351.5 138.6h2.8v.5h-2.8zM384.8 120.8h2.8v.5h-2.8zM384.8 123.4h2.8v.5h-2.8zM384.8 125.9h2.8v.5h-2.8zM384.8 128.5h2.8v.5h-2.8zM384.8 131h2.8v.5h-2.8zM384.8 133.5h2.8v.5h-2.8zM384.8 136.1h2.8v.5h-2.8zM384.8 138.6h2.8v.5h-2.8z"/>
<path d="M168.6 154.1h.8v5.1h-.8zM351.5 141.2h2.8v.5h-2.8zM351.5 143.7h2.8v.5h-2.8zM351.5 146.2h2.8v.5h-2.8zM351.5 148.8h2.8v.5h-2.8zM351.5 151.3h2.8v.5h-2.8zM351.5 153.9h2.8v.5h-2.8zM351.5 156.4h2.8v.5h-2.8zM351.5 158.9h2.8v.5h-2.8zM384.8 141.2h2.8v.5h-2.8zM384.8 143.7h2.8v.5h-2.8zM384.8 146.2h2.8v.5h-2.8z"/>
<path d="M384.8 148.8h2.8v.5h-2.8zM384.8 151.3h2.8v.5h-2.8zM384.8 153.9h2.8v.5h-2.8zM384.8 156.4h2.8v.5h-2.8zM384.8 158.9h2.8v.5h-2.8zM168.6 179.5h.8v5.1h-.8zM351.5 161.5h2.8v.5h-2.8zM351.5 164h2.8v.5h-2.8zM351.5 166.6h2.8v.5h-2.8zM351.5 169.1h2.8v.5h-2.8zM351.5 171.6h2.8v.5h-2.8zM384.8 161.5h2.8v.5h-2.8z"/>
<path d="M384.8 164h2.8v.5h-2.8zM384.8 166.6h2.8v.5h-2.8zM384.8 169.1h2.8v.5h-2.8zM384.8 171.6h2.8v.5h-2.8zM351.5 184.3h2.8v.5h-2.8zM351.5 186.9h2.8v.5h-2.8zM351.5 189.4h2.8v.5h-2.8zM351.5 192h2.8v.5h-2.8zM351.5 194.5h2.8v.5h-2.8zM351.5 197h2.8v.5h-2.8zM351.5 199.6h2.8v.5h-2.8zM384.8 184.3h2.8v.5h-2.8z"/>
<path d="M384.8 186.9h2.8v.5h-2.8zM384.8 189.4h2.8v.5h-2.8zM384.8 192h2.8v.5h-2.8zM384.8 194.5h2.8v.5h-2.8zM384.8 197h2.8v.5h-2.8zM384.8 199.6h2.8v.5h-2.8zM89.7 215h.7v5.1h-.7zM351.5 202.1h2.8v.5h-2.8zM351.5 204.7h2.8v.5h-2.8zM351.5 207.2h2.8v.5h-2.8zM351.5 209.7h2.8v.5h-2.8zM351.5 212.3h2.8v.5h-2.8z"/>
<path d="M351.5 214.8h2.8v.5h-2.8zM351.5 217.3h2.8v.5h-2.8zM351.5 219.9h2.8v.5h-2.8zM384.8 202.1h2.8v.5h-2.8zM384.8 204.7h2.8v.5h-2.8zM384.8 207.2h2.8v.5h-2.8zM384.8 209.7h2.8v.5h-2.8zM384.8 212.3h2.8v.5h-2.8zM384.8 214.8h2.8v.5h-2.8zM384.8 217.3h2.8v.5h-2.8zM384.8 219.9h2.8v.5h-2.8zM351.5 222.4h2.8v.5h-2.8z"/>
<path d="M351.5 225h2.8v.5h-2.8zM384.8 222.4h2.8v.5h-2.8zM384.8 225h2.8v.5h-2.8zM24.6 256.2h4.1v.5h-4.1zM24.6 257.2h4.1v.5h-4.1zM32.3 256.2h4v.5h-4zM32.3 257.2h4v.5h-4zM39.9 256.2h4v.5h-4zM39.9 257.2h4v.5h-4zM47.5 256.2h4.1v.5h-4.1zM47.5 257.2h4.1v.5h-4.1zM55.1 256.2h4.1v.5h-4.1z"/>
<path d="M55.1 257.2h4.1v.5h-4.1zM65.3 257.2h4v.5h-4zM65.3 256.2h4v.5h-4zM179.6 257.5h4v.5h-4zM179.6 258.5h4v.5h-4zM232.9 257.5h4.1v.5h-4.1zM232.9 258.5h4.1v.5h-4.1z"/>
</g>
<g fill="none" stroke="#000" stroke-width=".25">
<circle cx="79" cy="95.7" r=".99"/>
<circle cx="96.2" cy="95.7" r=".99"/>
<circle cx="96.2" cy="90.6" r=".99"/>
<circle cx="96.2" cy="88.1" r=".99"/>
<circle cx="96.2" cy="93.2" r=".99"/>
<circle cx="96.2" cy="113.5" r=".99"/>
<circle cx="244.1" cy="110.9" r="1"/>
<circle cx="244.1" cy="113.5" r="1"/>
<circle cx="276.6" cy="118.6" r="1"/>
<circle cx="276.6" cy="116" r="1"/>
<circle cx="276.6" cy="110.9" r="1"/>
<circle cx="276.6" cy="113.5" r="1"/>
<circle cx="157.8" cy="128.7" r=".99"/>
<circle cx="157.8" cy="131.3" r=".99"/>
<circle cx="276.6" cy="131.3" r="1"/>
<circle cx="276.6" cy="123.6" r="1"/>
<circle cx="276.6" cy="138.9" r="1"/>
<circle cx="276.6" cy="128.7" r="1"/>
<circle cx="276.6" cy="136.3" r="1"/>
<circle cx="276.6" cy="121.1" r="1"/>
<circle cx="276.6" cy="133.8" r="1"/>
<circle cx="79" cy="159.2" r=".99"/>
<circle cx="244.1" cy="154.1" r="1"/>
<circle cx="276.6" cy="151.6" r="1"/>
<circle cx="276.6" cy="146.5" r="1"/>
<circle cx="276.6" cy="149" r="1"/>
<circle cx="276.6" cy="144" r="1"/>
<circle cx="276.6" cy="159.2" r="1"/>
<circle cx="276.6" cy="156.7" r="1"/>
<circle cx="96.2" cy="179.5" r=".99"/>
<circle cx="96.2" cy="177" r=".99"/>
<circle cx="244.1" cy="161.7" r="1"/>
<circle cx="244.1" cy="166.8" r="1"/>
<circle cx="244.1" cy="164.3" r="1"/>
<circle cx="79" cy="184.6" r=".99"/>
<circle cx="96.2" cy="184.6" r=".99"/>
<circle cx="96.2" cy="182.1" r=".99"/>
<circle cx="217.1" cy="258.2" r=".15"/>
<circle cx="270.5" cy="258.2" r=".15"/>
<circle cx="196.8" cy="263.3" r=".15"/>
<circle cx="250.2" cy="263.3" r=".15"/>
</g>
<g fill="#000" stroke="#000" stroke-width=".42">
<path d="M293.3 161.7v8.9zM293.3 170.6h15.3zM293.3 161.7h15.3zM301 175.1v3.8zM301 175.1h10.1zM302.2 177h1.3zM308.6 161.7v8.9zM308.6 177h1.3zM311.1 175.1v3.8zM301 178.9h10.1zM73.7 199.8v12.7zM73.7 199.8h7.6z"/>
<path d="M73.7 212.5h7.6zM81.3 199.8v12.7zM303.5 212.5h1.3zM303.5 210h1.3zM303.5 207.4h1.3zM305.4 206.8v6.3zM305.4 206.8h.6zM306 206.8v6.3zM305.4 213.1h.6zM205.7 253.1l3.8 2.6zM205.7 253.1v2zM209.5 255.7l3.8 2.5z"/>
<path d="M205.7 263.3l7.6-5.1zM259.1 253.1l3.8 2.6zM259.1 253.1v2zM262.9 255.7l3.8 2.5zM259.1 263.3l7.6-5.1zM205.7 261.4v1.9zM205.7 255.1v6.3zM259.1 261.4v1.9zM259.1 255.1v6.3z"/>
</g>
<g fill="none" stroke="#000" stroke-width=".42">
<circle cx="295.9" cy="169.4" r=".25"/>
<circle cx="298.4" cy="169.4" r=".25"/>
<circle cx="301" cy="169.4" r=".25"/>
<circle cx="303.5" cy="169.4" r=".25"/>
</g>
<path d="M115.6 116a5.1 5.1 0 0 0 5 5.1 5.1 5.1 0 0 0 5.1-5.1M92.7 258.2a5.1 5.1 0 0 0-5.1 5.1 5.1 5.1 0 0 0 5.1 5.1M107.9 245.5a5.1 5.1 0 0 1 5.1 5.1 5.1 5.1 0 0 1-5.1 5.1M107.9 258.2a5.1 5.1 0 0 1 5.1 5.1 5.1 5.1 0 0 1-5.1 5.1" fill="none" stroke="#000" stroke-width=".61"/>
<g fill="#000" stroke="#000" stroke-width=".76">
<path d="M41.9 34.8h94zM135.9 34.8l5 5zM135.9 34.8h73.6zM209.5 34.8l5.1 5zM41.9 42.4h15.2zM57.1 42.4l2.6 2.5zM59.7 44.9v83.8zM311.1 105.9v48.2zM313.7 103.3l-2.6 2.6zM313.7 103.3h15.2zM328.9 103.3l2.5 2.6zM140.9 39.8v81.3z"/>
<path d="M214.6 39.8v104.2zM44.4 194.8h7.7zM52.1 194.8l2.5 2.5zM54.6 197.3v2.5zM54.6 199.8v5.1zM331.4 105.9v121.8z"/>
</g>
<use href="#words"/>
</svg>
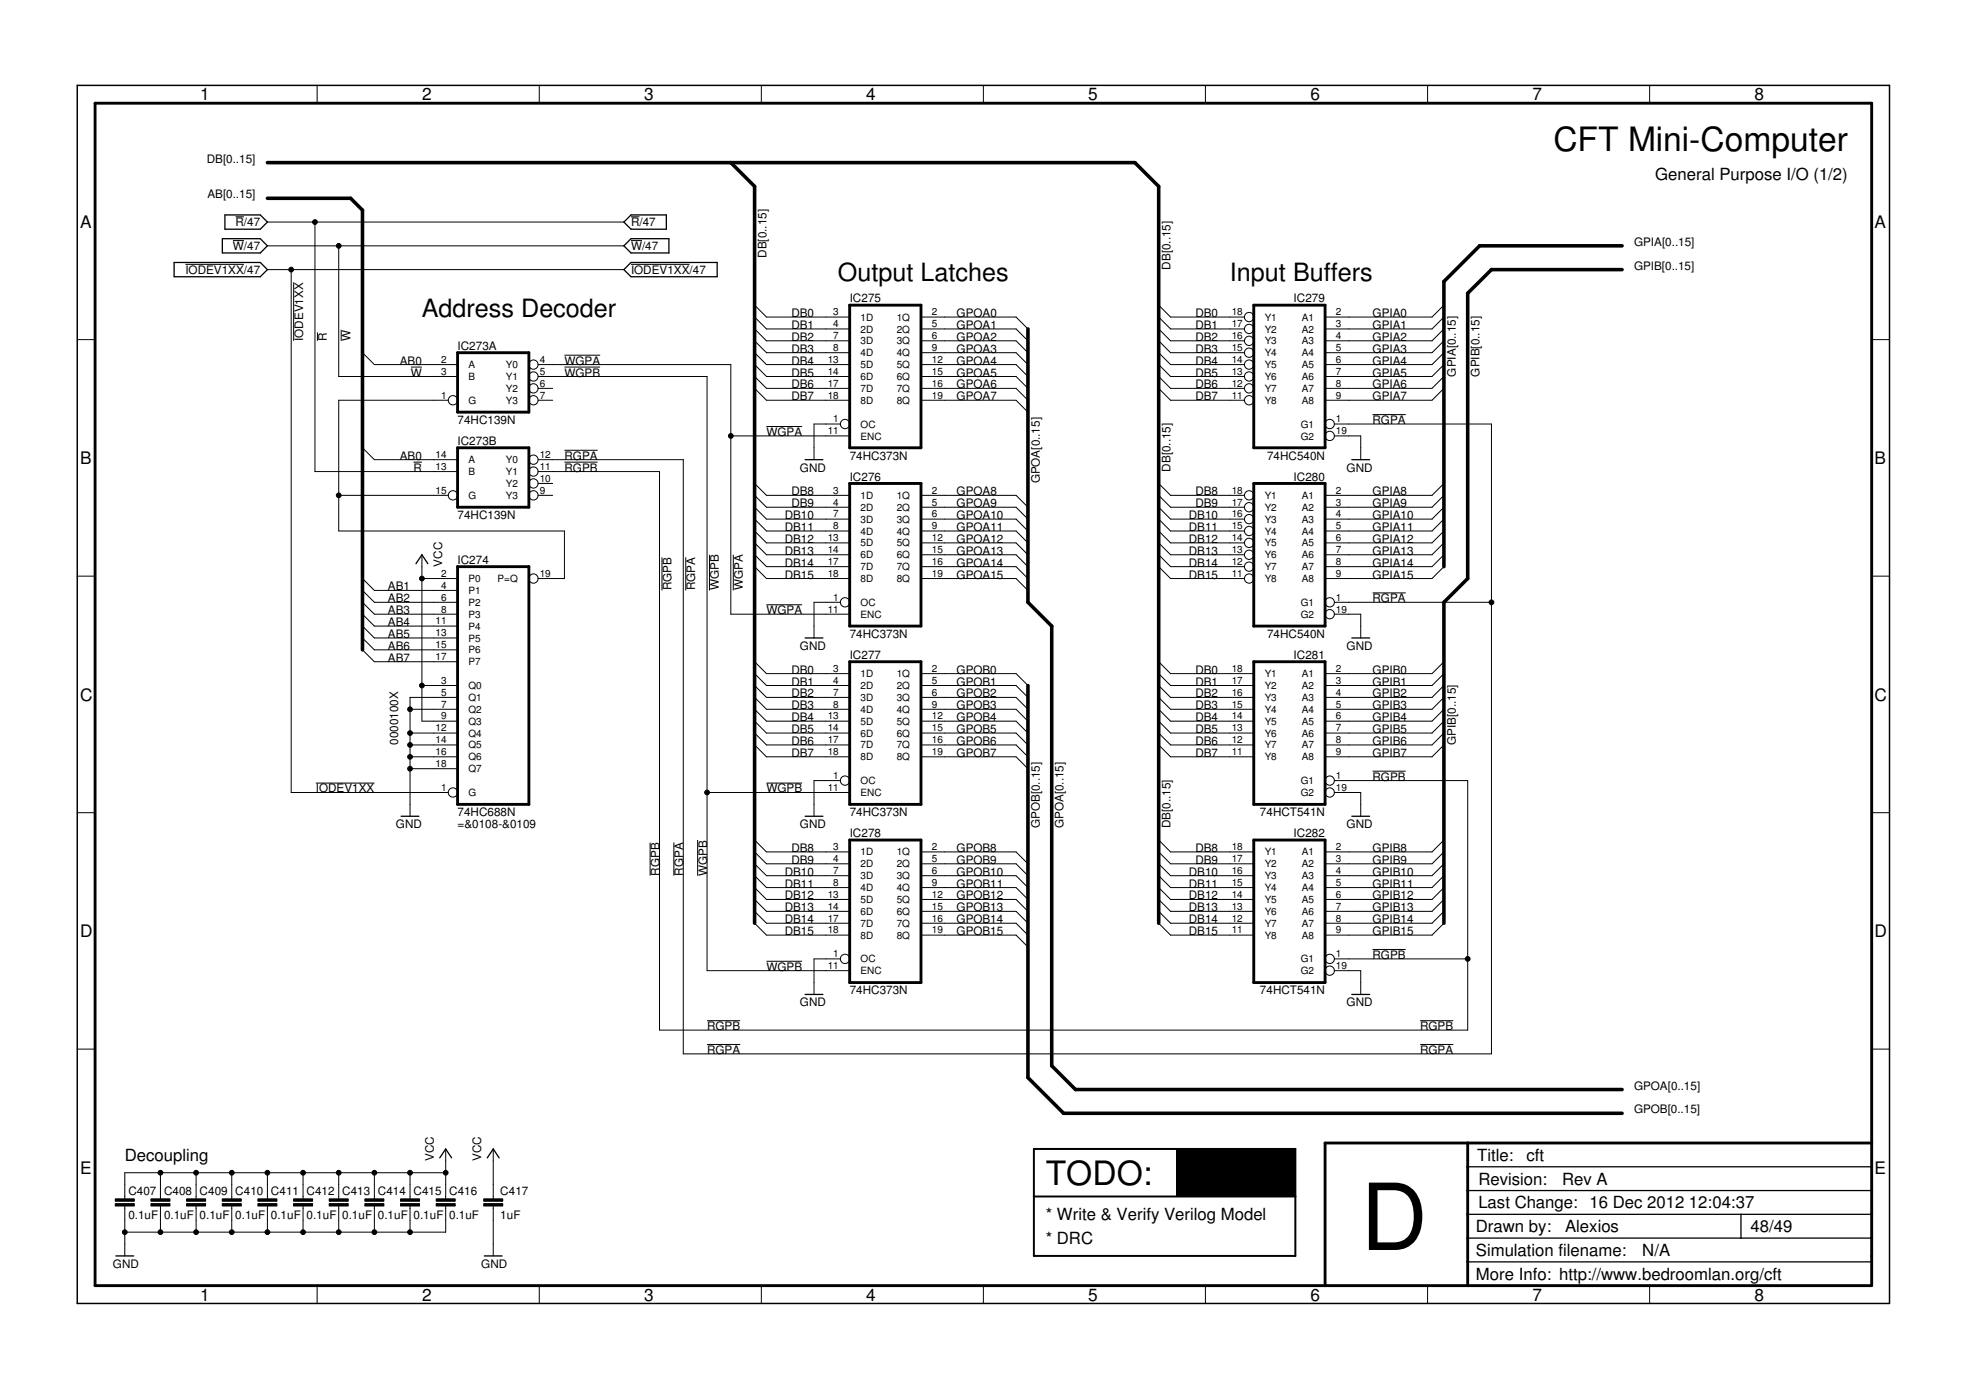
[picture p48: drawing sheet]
<svg xmlns="http://www.w3.org/2000/svg" width="420mm" height="297mm" viewBox="0 0 420 297" stroke-linecap="round" stroke-linejoin="round" font-family="sans-serif">
<defs><g id="words">
<text font-size="19.7" x="290.8" y="267.1">D</text>
<g font-size="7.2">
<text x="332" y="32.2">CFT Mini-Computer</text>
<text x="223.5" y="253.2">TODO:</text>
</g>
<g font-size="5.4">
<text x="179.1" y="60.1">Output Latches</text>
<text x="262.9" y="60.1">Input Buffers</text>
<text x="90.2" y="67.8">Address Decoder</text>
</g>
<g font-size="3.7">
<text x="42.7" y="21.5">1</text>
<text x="90.2" y="21.5">2</text>
<text x="137.7" y="21.5">3</text>
<text x="185.1" y="21.5">4</text>
<text x="232.6" y="21.5">5</text>
<text x="280" y="21.5">6</text>
<text x="327.5" y="21.5">7</text>
<text x="375" y="21.5">8</text>
<text x="17.1" y="48.6">A</text>
<text x="400.6" y="48.6">A</text>
<text x="17.1" y="99.2">B</text>
<text x="400.6" y="99.2">B</text>
<text x="17.1" y="149.7">C</text>
<text x="400.6" y="149.7">C</text>
<text x="17.1" y="200.2">D</text>
<text x="400.6" y="200.2">D</text>
<text x="17.1" y="250.8">E</text>
<text x="400.6" y="250.8">E</text>
<text x="42.7" y="277.9">1</text>
<text x="90.2" y="277.9">2</text>
<text x="137.7" y="277.9">3</text>
<text x="185.1" y="277.9">4</text>
<text x="232.6" y="277.9">5</text>
<text x="280" y="277.9">6</text>
<text x="327.5" y="277.9">7</text>
<text x="375" y="277.9">8</text>
</g>
<g font-size="3.6">
<text x="353.8" y="38.6">General Purpose I/O (1/2)</text>
<text x="26.7" y="248.1">Decoupling</text>
<text x="315.7" y="248.1">Title:</text>
<text x="326.2" y="248.2">cft</text>
<text x="315.9" y="253.2">Revision:</text>
<text x="333.8" y="253.3">Rev A</text>
<text x="223.5" y="260.8">* Write &amp; Verify Verilog Model</text>
<text x="315.4" y="263.3">Drawn by:</text>
<text x="315.9" y="258.2">Last Change: 16 Dec 2012</text>
<text x="334.5" y="263.3">Alexios</text>
<text x="361" y="258.1">12:04:37</text>
<text x="374.1" y="263.2">48/49</text>
<text x="223.5" y="265.8">* DRC</text>
<text x="315.4" y="268.4">Simulation filename:</text>
<text x="351" y="268.4">N/A</text>
<text x="315.4" y="273.5">More Info: http://www.bedroomlan.org/cft</text>
</g>
<g font-size="2.5">
<text x="44.2" y="34.7">DB[0..15]</text>
<text x="44.3" y="42.4">AB[0..15]</text>
<text x="49.8" y="53.4">W/47</text>
<text x="50.3" y="48.3">R/47</text>
<text x="134.9" y="53.4">W/47</text>
<text x="134.9" y="48.3">R/47</text>
<text x="349.2" y="52.5">GPIA[0..15]</text>
<text x="39.6" y="58.5">IODEV1XX/47</text>
<text x="134.9" y="58.5">IODEV1XX/47</text>
<text x="163.8" y="55.1" transform="rotate(-90 163.8 55.1)">DB[0..15]</text>
<text x="250.2" y="57.6" transform="rotate(-90 250.2 57.6)">DB[0..15]</text>
<text x="349.2" y="57.6">GPIB[0..15]</text>
<text x="181.6" y="64.6">IC275</text>
<text x="276.5" y="64.6">IC279</text>
<text x="169.1" y="67.8">DB0</text>
<text x="169.1" y="70.3">DB1</text>
<text x="204.4" y="67.8">GPOA0</text>
<text x="204.4" y="70.3">GPOA1</text>
<text x="255.5" y="67.8">DB0</text>
<text x="255.5" y="70.3">DB1</text>
<text x="293.3" y="67.8">GPIA0</text>
<text x="293.3" y="70.3">GPIA1</text>
<text x="64.8" y="72.8" transform="rotate(-90 64.8 72.8)">IODEV1XX</text>
<text x="69.8" y="72.8" transform="rotate(-90 69.8 72.8)">R</text>
<text x="74.9" y="72.8" transform="rotate(-90 74.9 72.8)">W</text>
<text x="85.4" y="77.9">AB0</text>
<text x="97.8" y="74.7">IC273A</text>
<text x="120.6" y="77.9">WGPA</text>
<text x="169.1" y="72.8">DB2</text>
<text x="169.1" y="75.4">DB3</text>
<text x="169.1" y="77.9">DB4</text>
<text x="204.4" y="72.8">GPOA2</text>
<text x="204.4" y="75.4">GPOA3</text>
<text x="204.4" y="77.9">GPOA4</text>
<text x="255.5" y="72.8">DB2</text>
<text x="255.5" y="75.4">DB3</text>
<text x="255.5" y="77.9">DB4</text>
<text x="293.3" y="72.8">GPIA2</text>
<text x="293.3" y="75.4">GPIA3</text>
<text x="293.3" y="77.9">GPIA4</text>
<text x="87.8" y="80.5">W</text>
<text x="120.6" y="80.5">WGPB</text>
<text x="169.1" y="80.5">DB5</text>
<text x="169.1" y="83">DB6</text>
<text x="204.4" y="80.5">GPOA5</text>
<text x="204.4" y="83">GPOA6</text>
<text x="255.5" y="80.5">DB5</text>
<text x="255.5" y="83">DB6</text>
<text x="293.3" y="80.5">GPIA5</text>
<text x="293.3" y="83">GPIA6</text>
<text x="311.1" y="80.5" transform="rotate(-90 311.1 80.5)">GPIA[0..15]</text>
<text x="316.2" y="80.5" transform="rotate(-90 316.2 80.5)">GPIB[0..15]</text>
<text x="169.1" y="85.5">DB7</text>
<text x="204.4" y="85.5">GPOA7</text>
<text x="255.5" y="85.5">DB7</text>
<text x="293.3" y="85.5">GPIA7</text>
<text x="97.8" y="90.6">74HC139N</text>
<text x="97.8" y="95.1">IC273B</text>
<text x="163.8" y="93.2">WGPA</text>
<text x="293.3" y="90.6">RGPA</text>
<text x="85.4" y="98.2">AB0</text>
<text x="88.4" y="100.8">R</text>
<text x="120.6" y="98.2">RGPA</text>
<text x="120.6" y="100.8">RGPB</text>
<text x="171" y="100.8">GND</text>
<text x="181.6" y="98.2">74HC373N</text>
<text x="250.2" y="100.8" transform="rotate(-90 250.2 100.8)">DB[0..15]</text>
<text x="270.8" y="98.2">74HC540N</text>
<text x="287.8" y="100.8">GND</text>
<text x="169.1" y="105.9">DB8</text>
<text x="181.6" y="102.7">IC276</text>
<text x="204.4" y="105.9">GPOA8</text>
<text x="222.2" y="103.3" transform="rotate(-90 222.2 103.3)">GPOA[0..15]</text>
<text x="255.5" y="105.9">DB8</text>
<text x="276.5" y="102.7">IC280</text>
<text x="293.3" y="105.9">GPIA8</text>
<text x="97.8" y="110.9">74HC139N</text>
<text x="167.7" y="110.9">DB10</text>
<text x="167.7" y="113.5">DB11</text>
<text x="169.1" y="108.4">DB9</text>
<text x="204.4" y="108.4">GPOA9</text>
<text x="204.4" y="110.9">GPOA10</text>
<text x="204.4" y="113.5">GPOA11</text>
<text x="254.1" y="110.9">DB10</text>
<text x="254.1" y="113.5">DB11</text>
<text x="255.5" y="108.4">DB9</text>
<text x="293.3" y="108.4">GPIA9</text>
<text x="293.3" y="110.9">GPIA10</text>
<text x="293.3" y="113.5">GPIA11</text>
<text x="167.7" y="116">DB12</text>
<text x="167.7" y="118.6">DB13</text>
<text x="204.4" y="116">GPOA12</text>
<text x="204.4" y="118.6">GPOA13</text>
<text x="254.1" y="116">DB12</text>
<text x="254.1" y="118.6">DB13</text>
<text x="293.3" y="116">GPIA12</text>
<text x="293.3" y="118.6">GPIA13</text>
<text x="94.5" y="121.1" transform="rotate(-90 94.5 121.1)">VCC</text>
<text x="97.8" y="120.5">IC274</text>
<text x="167.7" y="121.1">DB14</text>
<text x="167.7" y="123.6">DB15</text>
<text x="204.4" y="121.1">GPOA14</text>
<text x="204.4" y="123.6">GPOA15</text>
<text x="254.1" y="121.1">DB14</text>
<text x="254.1" y="123.6">DB15</text>
<text x="293.3" y="121.1">GPIA14</text>
<text x="293.3" y="123.6">GPIA15</text>
<text x="82.9" y="131.3">AB3</text>
<text x="82.9" y="126.2">AB1</text>
<text x="82.9" y="128.7">AB2</text>
<text x="143.5" y="126.2" transform="rotate(-90 143.5 126.2)">RGPB</text>
<text x="148.6" y="126.2" transform="rotate(-90 148.6 126.2)">RGPA</text>
<text x="153.7" y="126.2" transform="rotate(-90 153.7 126.2)">WGPB</text>
<text x="158.7" y="126.2" transform="rotate(-90 158.7 126.2)">WGPA</text>
<text x="163.8" y="131.3">WGPA</text>
<text x="293.3" y="128.7">RGPA</text>
<text x="82.9" y="133.8">AB4</text>
<text x="82.9" y="136.3">AB5</text>
<text x="181.6" y="136.3">74HC373N</text>
<text x="270.8" y="136.3">74HC540N</text>
<text x="82.9" y="138.9">AB6</text>
<text x="82.9" y="141.4">AB7</text>
<text x="169.1" y="144">DB0</text>
<text x="171" y="138.9">GND</text>
<text x="181.6" y="140.8">IC277</text>
<text x="204.4" y="144">GPOB0</text>
<text x="255.5" y="144">DB0</text>
<text x="276.5" y="140.8">IC281</text>
<text x="287.8" y="138.9">GND</text>
<text x="293.3" y="144">GPIB0</text>
<text x="169.1" y="146.5">DB1</text>
<text x="169.1" y="149">DB2</text>
<text x="204.4" y="146.5">GPOB1</text>
<text x="204.4" y="149">GPOB2</text>
<text x="255.5" y="146.5">DB1</text>
<text x="255.5" y="149">DB2</text>
<text x="293.3" y="146.5">GPIB1</text>
<text x="293.3" y="149">GPIB2</text>
<text x="169.1" y="151.6">DB3</text>
<text x="169.1" y="154.1">DB4</text>
<text x="204.4" y="151.6">GPOB3</text>
<text x="204.4" y="154.1">GPOB4</text>
<text x="255.5" y="151.6">DB3</text>
<text x="255.5" y="154.1">DB4</text>
<text x="293.3" y="151.6">GPIB3</text>
<text x="293.3" y="154.1">GPIB4</text>
<text x="85.1" y="159.2" transform="rotate(-90 85.1 159.2)">0000100X</text>
<text x="169.1" y="156.6">DB5</text>
<text x="169.1" y="159.2">DB6</text>
<text x="169.1" y="161.7">DB7</text>
<text x="204.4" y="156.6">GPOB5</text>
<text x="204.4" y="159.2">GPOB6</text>
<text x="204.4" y="161.7">GPOB7</text>
<text x="255.5" y="156.6">DB5</text>
<text x="255.5" y="159.2">DB6</text>
<text x="255.5" y="161.7">DB7</text>
<text x="293.3" y="156.6">GPIB5</text>
<text x="293.3" y="159.2">GPIB6</text>
<text x="293.3" y="161.7">GPIB7</text>
<text x="311.1" y="159.2" transform="rotate(-90 311.1 159.2)">GPIB[0..15]</text>
<text x="293.3" y="166.8">RGPB</text>
<text x="67.5" y="169.3">IODEV1XX</text>
<text x="163.8" y="169.3">WGPB</text>
<text x="84.6" y="177">GND</text>
<text x="97.8" y="177">=&amp;0108-&amp;0109</text>
<text x="97.8" y="174.4">74HC688N</text>
<text x="171" y="177">GND</text>
<text x="181.6" y="174.4">74HC373N</text>
<text x="181.6" y="178.9">IC278</text>
<text x="222.2" y="177" transform="rotate(-90 222.2 177)">GPOB[0..15]</text>
<text x="227.3" y="177" transform="rotate(-90 227.3 177)">GPOA[0..15]</text>
<text x="250.2" y="177" transform="rotate(-90 250.2 177)">DB[0..15]</text>
<text x="269.3" y="174.4">74HCT541N</text>
<text x="276.5" y="178.9">IC282</text>
<text x="287.8" y="177">GND</text>
<text x="169.1" y="182">DB8</text>
<text x="169.1" y="184.6">DB9</text>
<text x="204.4" y="182">GPOB8</text>
<text x="204.4" y="184.6">GPOB9</text>
<text x="255.5" y="182">DB8</text>
<text x="255.5" y="184.6">DB9</text>
<text x="293.3" y="182">GPIB8</text>
<text x="293.3" y="184.6">GPIB9</text>
<text x="141" y="187.1" transform="rotate(-90 141 187.1)">RGPB</text>
<text x="146" y="187.1" transform="rotate(-90 146 187.1)">RGPA</text>
<text x="151.1" y="187.1" transform="rotate(-90 151.1 187.1)">WGPB</text>
<text x="167.7" y="187.1">DB10</text>
<text x="167.7" y="189.7">DB11</text>
<text x="204.4" y="187.1">GPOB10</text>
<text x="204.4" y="189.7">GPOB11</text>
<text x="254.1" y="187.1">DB10</text>
<text x="254.1" y="189.7">DB11</text>
<text x="293.3" y="187.1">GPIB10</text>
<text x="293.3" y="189.7">GPIB11</text>
<text x="167.7" y="192.2">DB12</text>
<text x="167.7" y="194.7">DB13</text>
<text x="167.7" y="197.3">DB14</text>
<text x="204.4" y="194.7">GPOB13</text>
<text x="204.4" y="197.3">GPOB14</text>
<text x="204.4" y="192.2">GPOB12</text>
<text x="254.1" y="192.2">DB12</text>
<text x="254.1" y="194.7">DB13</text>
<text x="254.1" y="197.3">DB14</text>
<text x="293.3" y="192.2">GPIB12</text>
<text x="293.3" y="194.7">GPIB13</text>
<text x="293.3" y="197.3">GPIB14</text>
<text x="167.7" y="199.8">DB15</text>
<text x="204.4" y="199.8">GPOB15</text>
<text x="254.1" y="199.8">DB15</text>
<text x="293.3" y="199.8">GPIB15</text>
<text x="163.8" y="207.4">WGPB</text>
<text x="293.3" y="204.9">RGPB</text>
<text x="171" y="215.1">GND</text>
<text x="181.6" y="212.5">74HC373N</text>
<text x="269.3" y="212.5">74HCT541N</text>
<text x="287.8" y="215.1">GND</text>
<text x="151.1" y="220.1">RGPB</text>
<text x="303.5" y="220.1">RGPB</text>
<text x="151.1" y="225.2">RGPA</text>
<text x="303.5" y="225.2">RGPA</text>
<text x="349.2" y="232.8">GPOA[0..15]</text>
<text x="349.2" y="237.9">GPOB[0..15]</text>
<text x="92.7" y="248.1" transform="rotate(-90 92.7 248.1)">VCC</text>
<text x="102.9" y="248.1" transform="rotate(-90 102.9 248.1)">VCC</text>
<text x="27.4" y="255.3">C407</text>
<text x="35" y="255.3">C408</text>
<text x="42.7" y="255.3">C409</text>
<text x="50.3" y="255.3">C410</text>
<text x="57.9" y="255.3">C411</text>
<text x="65.5" y="255.3">C412</text>
<text x="73.1" y="255.3">C413</text>
<text x="80.8" y="255.3">C414</text>
<text x="88.4" y="255.3">C415</text>
<text x="96" y="255.3">C416</text>
<text x="106.9" y="255.3">C417</text>
<text x="27.4" y="260.4">0.1uF</text>
<text x="35" y="260.4">0.1uF</text>
<text x="42.7" y="260.4">0.1uF</text>
<text x="50.3" y="260.4">0.1uF</text>
<text x="57.9" y="260.4">0.1uF</text>
<text x="65.5" y="260.4">0.1uF</text>
<text x="73.1" y="260.4">0.1uF</text>
<text x="80.8" y="260.4">0.1uF</text>
<text x="88.4" y="260.4">0.1uF</text>
<text x="96" y="260.4">0.1uF</text>
<text x="106.9" y="260.4">1uF</text>
<text x="24.1" y="270.9">GND</text>
<text x="102.9" y="270.9">GND</text>
</g>
<g font-size="2.1">
<text x="178.1" y="67.4">3</text>
<text x="178.1" y="69.9">4</text>
<text x="183.9" y="68.5">1D</text>
<text x="183.9" y="71.1">2D</text>
<text x="191.6" y="68.5">1Q</text>
<text x="191.6" y="71.1">2Q</text>
<text x="199.2" y="67.4">2</text>
<text x="199.2" y="69.9">5</text>
<text x="263.2" y="69.9">17</text>
<text x="263.2" y="67.4">18</text>
<text x="270.3" y="71.1">Y2</text>
<text x="270.3" y="68.5">Y1</text>
<text x="278.2" y="68.5">A1</text>
<text x="278.2" y="71.1">A2</text>
<text x="285.5" y="67.4">2</text>
<text x="285.5" y="69.9">3</text>
<text x="94.3" y="77.6">2</text>
<text x="115.4" y="77.6">4</text>
<text x="176.9" y="77.6">13</text>
<text x="178.1" y="72.5">7</text>
<text x="178.1" y="75">8</text>
<text x="183.9" y="73.6">3D</text>
<text x="183.9" y="76.1">4D</text>
<text x="191.6" y="73.6">3Q</text>
<text x="191.6" y="76.1">4Q</text>
<text x="199.2" y="72.5">6</text>
<text x="199.2" y="75">9</text>
<text x="199.2" y="77.6">12</text>
<text x="263.2" y="77.6">14</text>
<text x="263.2" y="75">15</text>
<text x="263.2" y="72.5">16</text>
<text x="270.3" y="76.1">Y4</text>
<text x="270.3" y="73.6">Y3</text>
<text x="278.2" y="73.6">A3</text>
<text x="278.2" y="76.1">A4</text>
<text x="285.5" y="72.5">4</text>
<text x="285.5" y="75">5</text>
<text x="285.5" y="77.6">6</text>
<text x="94.3" y="80.1">3</text>
<text x="100.1" y="78.7">A</text>
<text x="100.1" y="81.2">B</text>
<text x="108.1" y="78.7">Y0</text>
<text x="108.1" y="81.2">Y1</text>
<text x="108.1" y="83.8">Y2</text>
<text x="115.4" y="80.1">5</text>
<text x="115.4" y="82.6">6</text>
<text x="176.9" y="80.1">14</text>
<text x="176.9" y="82.6">17</text>
<text x="183.9" y="78.7">5D</text>
<text x="183.9" y="81.2">6D</text>
<text x="183.9" y="83.8">7D</text>
<text x="191.6" y="78.7">5Q</text>
<text x="191.6" y="81.2">6Q</text>
<text x="191.6" y="83.8">7Q</text>
<text x="199.2" y="80.1">15</text>
<text x="199.2" y="82.6">16</text>
<text x="263.2" y="82.6">12</text>
<text x="263.2" y="80.1">13</text>
<text x="270.3" y="83.8">Y7</text>
<text x="270.3" y="81.2">Y6</text>
<text x="270.3" y="78.7">Y5</text>
<text x="278.2" y="78.7">A5</text>
<text x="278.2" y="81.2">A6</text>
<text x="278.2" y="83.8">A7</text>
<text x="285.5" y="80.1">7</text>
<text x="285.5" y="82.6">8</text>
<text x="94.3" y="85.2">1</text>
<text x="100.1" y="86.3">G</text>
<text x="108.1" y="86.3">Y3</text>
<text x="115.4" y="85.2">7</text>
<text x="176.9" y="85.2">18</text>
<text x="183.9" y="86.3">8D</text>
<text x="191.6" y="86.3">8Q</text>
<text x="199.2" y="85.2">19</text>
<text x="263.2" y="85.2">11</text>
<text x="270.3" y="86.3">Y8</text>
<text x="278.2" y="86.3">A8</text>
<text x="285.5" y="85.2">9</text>
<text x="176.9" y="92.8">11</text>
<text x="178.1" y="90.3">1</text>
<text x="183.9" y="91.4">OC</text>
<text x="183.9" y="93.9">ENC</text>
<text x="278" y="91.4">G1</text>
<text x="278" y="93.9">G2</text>
<text x="285.5" y="90.3">1</text>
<text x="285.5" y="92.8">19</text>
<text x="93.1" y="97.9">14</text>
<text x="93.1" y="100.4">13</text>
<text x="100.1" y="99">A</text>
<text x="100.1" y="101.5">B</text>
<text x="108.1" y="99">Y0</text>
<text x="108.1" y="101.5">Y1</text>
<text x="115.4" y="97.9">12</text>
<text x="115.4" y="100.4">11</text>
<text x="93.1" y="105.5">15</text>
<text x="100.1" y="106.6">G</text>
<text x="108.1" y="104.1">Y2</text>
<text x="108.1" y="106.6">Y3</text>
<text x="115.4" y="103">10</text>
<text x="115.4" y="105.5">9</text>
<text x="178.1" y="105.5">3</text>
<text x="183.9" y="106.6">1D</text>
<text x="191.6" y="106.6">1Q</text>
<text x="199.2" y="105.5">2</text>
<text x="263.2" y="105.5">18</text>
<text x="270.3" y="106.6">Y1</text>
<text x="278.2" y="106.6">A1</text>
<text x="285.5" y="105.5">2</text>
<text x="178.1" y="108">4</text>
<text x="178.1" y="110.6">7</text>
<text x="178.1" y="113.1">8</text>
<text x="183.9" y="109.2">2D</text>
<text x="183.9" y="111.7">3D</text>
<text x="191.6" y="109.2">2Q</text>
<text x="191.6" y="111.7">3Q</text>
<text x="199.2" y="108">5</text>
<text x="199.2" y="110.6">6</text>
<text x="199.2" y="113.1">9</text>
<text x="263.2" y="113.1">15</text>
<text x="263.2" y="110.6">16</text>
<text x="263.2" y="108">17</text>
<text x="270.3" y="111.7">Y3</text>
<text x="270.3" y="109.2">Y2</text>
<text x="278.2" y="109.2">A2</text>
<text x="278.2" y="111.7">A3</text>
<text x="285.5" y="108">3</text>
<text x="285.5" y="110.6">4</text>
<text x="285.5" y="113.1">5</text>
<text x="176.9" y="115.7">13</text>
<text x="176.9" y="118.2">14</text>
<text x="183.9" y="114.2">4D</text>
<text x="183.9" y="116.8">5D</text>
<text x="183.9" y="119.3">6D</text>
<text x="191.6" y="114.2">4Q</text>
<text x="191.6" y="116.8">5Q</text>
<text x="191.6" y="119.3">6Q</text>
<text x="199.2" y="115.7">12</text>
<text x="199.2" y="118.2">15</text>
<text x="263.2" y="118.2">13</text>
<text x="263.2" y="115.7">14</text>
<text x="270.3" y="119.3">Y6</text>
<text x="270.3" y="116.8">Y5</text>
<text x="270.3" y="114.2">Y4</text>
<text x="278.2" y="114.2">A4</text>
<text x="278.2" y="116.8">A5</text>
<text x="278.2" y="119.3">A6</text>
<text x="285.5" y="115.7">6</text>
<text x="285.5" y="118.2">7</text>
<text x="94.3" y="123.3">2</text>
<text x="94.3" y="125.8">4</text>
<text x="100.1" y="124.4">P0</text>
<text x="106.3" y="124.4">P=Q</text>
<text x="115.4" y="123.3">19</text>
<text x="176.9" y="120.7">17</text>
<text x="176.9" y="123.3">18</text>
<text x="183.9" y="121.9">7D</text>
<text x="183.9" y="124.4">8D</text>
<text x="191.6" y="121.9">7Q</text>
<text x="191.6" y="124.4">8Q</text>
<text x="199.2" y="120.7">16</text>
<text x="199.2" y="123.3">19</text>
<text x="263.2" y="123.3">11</text>
<text x="263.2" y="120.7">12</text>
<text x="270.3" y="124.4">Y8</text>
<text x="270.3" y="121.9">Y7</text>
<text x="278.2" y="121.9">A7</text>
<text x="278.2" y="124.4">A8</text>
<text x="285.5" y="120.7">8</text>
<text x="285.5" y="123.3">9</text>
<text x="94.3" y="128.4">6</text>
<text x="94.3" y="130.9">8</text>
<text x="100.1" y="126.9">P1</text>
<text x="100.1" y="129.5">P2</text>
<text x="176.9" y="130.9">11</text>
<text x="178.1" y="128.4">1</text>
<text x="183.9" y="129.5">OC</text>
<text x="278" y="129.5">G1</text>
<text x="285.5" y="128.4">1</text>
<text x="285.5" y="130.9">19</text>
<text x="93.1" y="133.4">11</text>
<text x="93.1" y="136">13</text>
<text x="100.1" y="132">P3</text>
<text x="100.1" y="134.6">P4</text>
<text x="100.1" y="137.1">P5</text>
<text x="183.9" y="132">ENC</text>
<text x="278" y="132">G2</text>
<text x="93.1" y="138.5">15</text>
<text x="93.1" y="141.1">17</text>
<text x="100.1" y="139.6">P6</text>
<text x="100.1" y="142.2">P7</text>
<text x="178.1" y="143.6">3</text>
<text x="199.2" y="143.6">2</text>
<text x="263.2" y="143.6">18</text>
<text x="285.5" y="143.6">2</text>
<text x="94.3" y="146.1">3</text>
<text x="94.3" y="148.7">5</text>
<text x="100.1" y="147.3">Q0</text>
<text x="100.1" y="149.8">Q1</text>
<text x="178.1" y="146.1">4</text>
<text x="178.1" y="148.7">7</text>
<text x="183.9" y="144.7">1D</text>
<text x="183.9" y="147.3">2D</text>
<text x="183.9" y="149.8">3D</text>
<text x="191.6" y="144.7">1Q</text>
<text x="191.6" y="147.3">2Q</text>
<text x="191.6" y="149.8">3Q</text>
<text x="199.2" y="146.1">5</text>
<text x="199.2" y="148.7">6</text>
<text x="263.2" y="148.7">16</text>
<text x="263.2" y="146.1">17</text>
<text x="270.3" y="149.8">Y3</text>
<text x="270.3" y="147.3">Y2</text>
<text x="270.3" y="144.7">Y1</text>
<text x="278.2" y="144.7">A1</text>
<text x="278.2" y="147.3">A2</text>
<text x="278.2" y="149.8">A3</text>
<text x="285.5" y="146.1">3</text>
<text x="285.5" y="148.7">4</text>
<text x="94.3" y="151.2">7</text>
<text x="94.3" y="153.8">9</text>
<text x="100.1" y="152.3">Q2</text>
<text x="100.1" y="154.9">Q3</text>
<text x="176.9" y="153.8">13</text>
<text x="178.1" y="151.2">8</text>
<text x="183.9" y="152.3">4D</text>
<text x="183.9" y="154.9">5D</text>
<text x="191.6" y="152.3">4Q</text>
<text x="191.6" y="154.9">5Q</text>
<text x="199.2" y="151.2">9</text>
<text x="199.2" y="153.8">12</text>
<text x="263.2" y="153.8">14</text>
<text x="263.2" y="151.2">15</text>
<text x="270.3" y="154.9">Y5</text>
<text x="270.3" y="152.3">Y4</text>
<text x="278.2" y="152.3">A4</text>
<text x="278.2" y="154.9">A5</text>
<text x="285.5" y="151.2">5</text>
<text x="285.5" y="153.8">6</text>
<text x="93.1" y="156.3">12</text>
<text x="93.1" y="158.8">14</text>
<text x="93.1" y="161.4">16</text>
<text x="100.1" y="157.4">Q4</text>
<text x="100.1" y="159.9">Q5</text>
<text x="176.9" y="156.3">14</text>
<text x="176.9" y="158.8">17</text>
<text x="176.9" y="161.4">18</text>
<text x="183.9" y="157.4">6D</text>
<text x="183.9" y="159.9">7D</text>
<text x="191.6" y="157.4">6Q</text>
<text x="191.6" y="160">7Q</text>
<text x="199.2" y="156.3">15</text>
<text x="199.2" y="158.8">16</text>
<text x="199.2" y="161.4">19</text>
<text x="263.2" y="161.4">11</text>
<text x="263.2" y="158.8">12</text>
<text x="263.2" y="156.3">13</text>
<text x="270.3" y="160">Y7</text>
<text x="270.3" y="157.4">Y6</text>
<text x="278.2" y="157.4">A6</text>
<text x="278.2" y="159.9">A7</text>
<text x="285.5" y="156.3">7</text>
<text x="285.5" y="158.8">8</text>
<text x="285.5" y="161.4">9</text>
<text x="93.1" y="163.9">18</text>
<text x="100.1" y="162.5">Q6</text>
<text x="100.1" y="165">Q7</text>
<text x="178.1" y="166.5">1</text>
<text x="183.9" y="167.6">OC</text>
<text x="183.9" y="162.5">8D</text>
<text x="191.6" y="162.5">8Q</text>
<text x="270.3" y="162.5">Y8</text>
<text x="278" y="167.6">G1</text>
<text x="278.2" y="162.5">A8</text>
<text x="285.5" y="166.5">1</text>
<text x="94.3" y="169">1</text>
<text x="100.1" y="170.1">G</text>
<text x="176.9" y="169">11</text>
<text x="183.9" y="170.1">ENC</text>
<text x="278" y="170.1">G2</text>
<text x="285.5" y="169">19</text>
<text x="178.1" y="181.7">3</text>
<text x="178.1" y="184.2">4</text>
<text x="183.9" y="182.8">1D</text>
<text x="183.9" y="185.3">2D</text>
<text x="191.6" y="182.8">1Q</text>
<text x="191.6" y="185.3">2Q</text>
<text x="199.2" y="181.7">2</text>
<text x="199.2" y="184.2">5</text>
<text x="263.2" y="184.2">17</text>
<text x="263.2" y="181.7">18</text>
<text x="270.3" y="185.3">Y2</text>
<text x="270.3" y="182.8">Y1</text>
<text x="278.2" y="182.8">A1</text>
<text x="278.2" y="185.3">A2</text>
<text x="285.5" y="181.7">2</text>
<text x="285.5" y="184.2">3</text>
<text x="176.9" y="191.8">13</text>
<text x="178.1" y="186.8">7</text>
<text x="178.1" y="189.3">8</text>
<text x="183.9" y="187.9">3D</text>
<text x="183.9" y="190.4">4D</text>
<text x="191.6" y="187.9">3Q</text>
<text x="191.6" y="190.4">4Q</text>
<text x="199.2" y="186.8">6</text>
<text x="199.2" y="189.3">9</text>
<text x="199.2" y="191.8">12</text>
<text x="263.2" y="191.8">14</text>
<text x="263.2" y="189.3">15</text>
<text x="263.2" y="186.8">16</text>
<text x="270.3" y="190.4">Y4</text>
<text x="270.3" y="187.9">Y3</text>
<text x="278.2" y="187.9">A3</text>
<text x="278.2" y="190.4">A4</text>
<text x="285.5" y="186.8">4</text>
<text x="285.5" y="189.3">5</text>
<text x="285.5" y="191.8">6</text>
<text x="176.9" y="194.4">14</text>
<text x="176.9" y="196.9">17</text>
<text x="183.9" y="193">5D</text>
<text x="183.9" y="195.5">6D</text>
<text x="191.6" y="193">5Q</text>
<text x="191.6" y="195.5">6Q</text>
<text x="199.2" y="194.4">15</text>
<text x="199.2" y="196.9">16</text>
<text x="263.2" y="196.9">12</text>
<text x="263.2" y="194.4">13</text>
<text x="270.3" y="195.5">Y6</text>
<text x="270.3" y="193">Y5</text>
<text x="278.2" y="193">A5</text>
<text x="278.2" y="195.5">A6</text>
<text x="285.5" y="194.4">7</text>
<text x="285.5" y="196.9">8</text>
<text x="176.9" y="199.5">18</text>
<text x="183.9" y="198">7D</text>
<text x="183.9" y="200.6">8D</text>
<text x="191.6" y="198">7Q</text>
<text x="191.6" y="200.6">8Q</text>
<text x="199.2" y="199.5">19</text>
<text x="263.2" y="199.5">11</text>
<text x="270.3" y="200.6">Y8</text>
<text x="270.3" y="198">Y7</text>
<text x="278.2" y="198">A7</text>
<text x="278.2" y="200.6">A8</text>
<text x="285.5" y="199.5">9</text>
<text x="176.9" y="207.1">11</text>
<text x="178.1" y="204.5">1</text>
<text x="183.9" y="205.7">OC</text>
<text x="183.9" y="208.2">ENC</text>
<text x="278" y="205.7">G1</text>
<text x="278" y="208.2">G2</text>
<text x="285.5" y="204.5">1</text>
<text x="285.5" y="207.1">19</text>
</g>
</g></defs>
<g fill="#000" stroke="#000" stroke-width=".28">
<path d="M37.2 56.1v3zM47.5 51v3.1zM48.1 45.9v3.1zM47.5 51h8.1zM47.5 54.1h8.1zM48.1 45.9h7.5zM48.1 49h7.5zM37.2 59.1h18.4zM37.2 56.1h18.4zM55.6 51l1.5 1.5zM57.1 52.5l-1.5 1.6zM55.6 45.9l1.5 1.6z"/>
<path d="M57.1 47.5l-1.5 1.5zM57.1 57.6l-1.5 1.5zM55.6 56.1l1.5 1.5zM133.3 52.5l1.6-1.5zM133.3 52.5l1.6 1.6zM133.3 47.5l1.6-1.6zM133.3 47.5l1.6 1.5zM133.3 57.6l1.6-1.5zM133.3 57.6l1.6 1.5zM134.9 51h8.1zM134.9 54.1h8.1zM134.9 45.9h7.5z"/>
<path d="M134.9 49h7.5zM134.9 56.1h18.4zM134.9 59.1h18.4zM142.4 45.9v3.1zM143 51v3.1zM153.3 56.1v3zM172.1 98.2h3.8zM288.9 98.2h3.8zM90.2 118.6l1.2 1.9zM90.2 118.6l-1.3 1.9zM172.1 136.3h3.8zM288.9 136.3h3.8z"/>
<path d="M85.7 174.4h3.8zM172.1 174.4h3.8zM288.9 174.4h3.8zM172.1 212.5h3.8zM288.9 212.5h3.8zM95.2 245.5l-1.2 1.9zM95.2 245.5l1.3 1.9zM105.4 245.5l-1.3 1.9zM105.4 245.5l1.3 1.9zM313.7 249.3h86.3zM313.7 254.4h86.3zM313.7 259.5h58.4z"/>
<path d="M372.1 259.5h27.9zM372.1 259.5v5.1zM24.8 268.4h3.8zM103.5 268.4h3.8zM313.7 264.6h58.4zM313.7 269.7h86.3zM372.1 264.6h27.9zM400 268.4v1.3z"/>
</g>
<g fill="#000" stroke="#000" stroke-width=".21">
<path d="M67.8 18.2v3.9zM115.3 18.2v3.9zM162.7 18.2v3.9zM210.2 18.2v3.9zM257.6 18.2v3.9zM305.1 18.2v3.9zM352.5 18.2v3.9zM20.3 22.1v252.6zM20.3 22.1h379.7zM39.6 56.5h12.5zM49.8 51.4h2.3zM50.3 46.3h1.8z"/>
<path d="M57.1 52.5h15.3zM57.1 47.5h10.2zM57.1 57.6h5.1zM62.2 57.6h71.1zM62.2 57.6v111.8zM67.3 47.5h66zM67.3 47.5v53.3zM72.4 52.5h60.9zM72.4 52.5v28zM134.9 51.4h2.3zM134.9 46.3h1.7zM134.9 56.5h12.5z"/>
<path d="M16.5 72.6h3.8zM62.8 60.3v12.5zM67.8 71v1.8zM72.9 70.5v2.3zM77.5 75.4l2.5 2.5zM87.8 78.4h2.4zM92.7 77.9h5.1zM80 77.9h12.7zM115 77.9h3.1zM120.6 78.4h7.6zM120.6 75.9h7.7zM118.1 77.9h38.1z"/>
<path d="M161.3 65.2l2.5 2.6zM161.3 67.8l2.5 2.5zM161.3 70.3l2.5 2.5zM161.3 72.8l2.5 2.6zM161.3 75.4l2.5 2.5zM176.5 67.8h5.1zM176.5 70.3h5.1zM176.5 72.8h5.1zM176.5 75.4h5.1zM176.5 77.9h5.1zM163.8 67.8h12.7zM163.8 70.3h12.7z"/>
<path d="M163.8 72.8h12.7zM163.8 75.4h12.7zM163.8 77.9h12.7zM196.8 67.8h5.1zM196.8 70.3h5.1zM196.8 72.8h5.1zM196.8 75.4h5.1zM196.8 77.9h5.1zM201.9 67.8h15.2zM201.9 70.3h15.2zM201.9 72.8h15.2zM201.9 75.4h15.2z"/>
<path d="M201.9 77.9h15.2zM217.1 67.8l2.6 2.5zM217.1 70.3l2.6 2.5zM217.1 72.8l2.6 2.6zM217.1 75.4l2.6 2.5zM217.1 77.9l2.6 2.6zM247.6 65.2l2.6 2.6zM247.6 67.8l2.6 2.5zM247.6 70.3l2.6 2.5zM247.6 72.8l2.6 2.6zM247.6 75.4l2.6 2.5zM262.9 77.9h3.1z"/>
<path d="M262.9 75.4h3.1zM262.9 72.8h3.1zM262.9 70.3h3.1zM262.9 67.8h3.1zM250.2 67.8h12.7zM250.2 70.3h12.7zM250.2 72.8h12.7zM250.2 75.4h12.7zM250.2 77.9h12.7zM283.2 67.8h5.1zM283.2 70.3h5.1zM283.2 72.8h5.1z"/>
<path d="M283.2 75.4h5.1zM283.2 77.9h5.1zM288.3 67.8h17.7zM288.3 70.3h17.7zM288.3 72.8h17.7zM288.3 75.4h17.7zM288.3 77.9h17.7zM308.6 65.2l-2.6 2.6zM308.6 67.8l-2.6 2.5zM306 72.8l2.6-2.5zM308.6 72.8l-2.6 2.6zM308.6 75.4l-2.6 2.5z"/>
<path d="M400 72.6h3.8zM72.4 80.5h20.3zM72.4 85.5h20.3zM77.5 95.7l2.5 2.5zM88.4 98.8h1.8zM92.7 85.5h3.1zM92.7 80.5h5.1zM92.7 98.2h5.1zM80 98.2h12.7zM115 80.5h3.1zM115 83h3.1zM115 85.5h3.1z"/>
<path d="M115 98.2h3.1zM118.1 98.2h27.9zM118.1 80.5h33zM120.6 96.2h7.1zM120.6 98.8h7.1zM146 98.2v127zM156.2 77.9v15.3zM156.2 93.2v38.1zM163.8 91.1h7.6zM161.3 77.9l2.5 2.6zM161.3 80.5l2.5 2.5zM161.3 83l2.5 2.5z"/>
<path d="M174 95.7v2.5zM174 90.6v5.1zM176.5 90.6h3.1zM176.5 93.2h5.1zM176.5 80.5h5.1zM176.5 83h5.1zM176.5 85.5h5.1zM174 90.6h2.5zM156.2 93.2h20.3zM163.8 80.5h12.7zM163.8 83h12.7zM163.8 85.5h12.7z"/>
<path d="M196.8 80.5h5.1zM196.8 83h5.1zM196.8 85.5h5.1zM201.9 80.5h15.2zM201.9 83h15.2zM201.9 85.5h15.2zM217.1 80.5l2.6 2.5zM217.1 83l2.6 2.5zM217.1 85.5l2.6 2.6zM247.6 77.9l2.6 2.6zM247.6 80.5l2.6 2.5zM247.6 83l2.6 2.5z"/>
<path d="M262.9 85.5h3.1zM262.9 83h3.1zM262.9 80.5h3.1zM250.2 80.5h12.7zM250.2 83h12.7zM250.2 85.5h12.7zM285.2 90.6h3.1zM283.2 80.5h5.1zM283.2 83h5.1zM283.2 85.5h5.1zM285.2 93.2h3.1zM288.3 93.2h2.5z"/>
<path d="M288.3 80.5h17.7zM288.3 83h17.7zM288.3 85.5h17.7zM290.8 95.7v2.5zM290.8 93.2v2.5zM293.3 88.6h7.1zM306 80.5l2.6-2.6zM308.6 80.5l-2.6 2.5zM308.6 83l-2.6 2.5zM288.3 90.6h30.4zM67.3 100.8h25.4zM72.4 105.9v7.6z"/>
<path d="M72.4 85.5v20.4zM92.7 105.9h3.1zM92.7 100.8h5.1zM72.4 105.9h20.3zM115 100.8h3.1zM115 103.3h3.1zM115 105.9h3.1zM118.1 100.8h22.8zM72.4 113.5h48.2zM140.9 100.8v119.3zM161.3 103.3l2.5 2.6zM161.3 105.9l2.5 2.5z"/>
<path d="M161.3 108.4l2.5 2.5zM161.3 110.9l2.5 2.6zM161.3 113.5l2.5 2.5zM161.3 116l2.5 2.6zM176.5 105.9h5.1zM176.5 108.4h5.1zM176.5 110.9h5.1zM176.5 113.5h5.1zM176.5 116h5.1zM176.5 118.6h5.1zM163.8 105.9h12.7zM163.8 108.4h12.7z"/>
<path d="M163.8 110.9h12.7zM163.8 113.5h12.7zM163.8 116h12.7zM163.8 118.6h12.7zM196.8 105.9h5.1zM196.8 108.4h5.1zM196.8 110.9h5.1zM196.8 113.5h5.1zM196.8 116h5.1zM196.8 118.6h5.1zM201.9 105.9h15.2zM201.9 108.4h15.2z"/>
<path d="M201.9 110.9h15.2zM201.9 113.5h15.2zM201.9 116h15.2zM201.9 118.6h15.2zM217.1 105.9l2.6 2.5zM217.1 108.4l2.6 2.5zM217.1 110.9l2.6 2.6zM217.1 113.5l2.6 2.5zM217.1 116l2.6 2.6zM217.1 118.6l2.6 2.5zM247.6 103.3l2.6 2.6zM247.6 105.9l2.6 2.5z"/>
<path d="M247.6 108.4l2.6 2.5zM247.6 110.9l2.6 2.6zM247.6 113.5l2.6 2.5zM247.6 116l2.6 2.6zM262.9 118.6h3.1zM262.9 116h3.1zM262.9 113.5h3.1zM262.9 110.9h3.1zM262.9 108.4h3.1zM262.9 105.9h3.1zM250.2 105.9h12.7zM250.2 108.4h12.7z"/>
<path d="M250.2 110.9h12.7zM250.2 113.5h12.7zM250.2 116h12.7zM250.2 118.6h12.7zM283.2 105.9h5.1zM283.2 108.4h5.1zM283.2 110.9h5.1zM283.2 113.5h5.1zM283.2 116h5.1zM283.2 118.6h5.1zM288.3 105.9h17.7zM288.3 108.4h17.7z"/>
<path d="M288.3 110.9h17.7zM288.3 113.5h17.7zM288.3 116h17.7zM288.3 118.6h17.7zM308.6 103.3l-2.6 2.6zM308.6 105.9l-2.6 2.5zM306 110.9l2.6-2.5zM308.6 110.9l-2.6 2.6zM308.6 113.5l-2.6 2.5zM306 118.6l2.6-2.6zM16.5 123.1h3.8zM77.5 131.3l2.5 2.5z"/>
<path d="M77.5 133.8l2.5 2.5zM77.5 136.3l2.5 2.6zM77.5 138.9l2.5 2.5zM77.5 128.7l2.5 2.6zM80 133.8h12.7zM80 136.3h12.7zM80 138.9h12.7zM77.5 123.6l2.5 2.6zM77.5 126.2l2.5 2.5zM90.2 118.6v2.5zM90.2 121.1v2.5zM92.7 123.6h5.1z"/>
<path d="M92.7 126.2h5.1zM92.7 128.7h5.1zM92.7 131.3h5.1zM92.7 133.8h5.1zM92.7 136.3h5.1zM92.7 138.9h5.1zM90.2 123.6h2.5zM80 131.3h12.7zM80 126.2h12.7zM80 128.7h12.7zM115 123.6h3.1zM118.1 123.6h2.5z"/>
<path d="M120.6 113.5v10.1zM141.5 119.1v7.1zM146.6 119.1v7.1zM151.6 118.6v7.6zM156.7 118.5v7.7zM163.8 129.2h7.6zM161.3 118.6l2.5 2.5zM161.3 121.1l2.5 2.5zM174 133.8v2.5zM174 128.7v5.1zM176.5 128.7h3.1zM176.5 131.3h5.1z"/>
<path d="M176.5 121.1h5.1zM176.5 123.6h5.1zM174 128.7h2.5zM156.2 131.3h20.3zM163.8 121.1h12.7zM163.8 123.6h12.7zM196.8 121.1h5.1zM196.8 123.6h5.1zM201.9 121.1h15.2zM201.9 123.6h15.2zM217.1 121.1l2.6 2.5zM217.1 123.6l2.6 2.6z"/>
<path d="M247.6 118.6l2.6 2.5zM247.6 121.1l2.6 2.5zM262.9 123.6h3.1zM262.9 121.1h3.1zM250.2 121.1h12.7zM250.2 123.6h12.7zM285.2 128.7h3.1zM283.2 121.1h5.1zM283.2 123.6h5.1zM285.2 131.3h3.1zM288.3 131.3h2.5zM288.3 128.7h30.4z"/>
<path d="M288.3 121.1h17.7zM288.3 123.6h17.7zM290.8 133.8v2.5zM290.8 131.3v2.5zM293.3 126.7h7.1zM308.6 118.6l-2.6 2.5zM308.6 121.1l-2.6 2.5zM318.7 90.6v38.1zM400 123.1h3.8zM80 141.4h12.7zM87.6 156.7v2.5zM87.6 159.2v2.5z"/>
<path d="M87.6 151.6v5.1zM87.6 149v2.6zM90.2 123.6v22.9zM90.2 146.5v7.6zM92.7 146.5h5.1zM92.7 149h5.1zM92.7 151.6h5.1zM92.7 154.1h5.1zM92.7 156.7h5.1zM92.7 159.2h5.1zM92.7 141.4h5.1zM87.6 156.7h5.1z"/>
<path d="M87.6 159.2h5.1zM87.6 151.6h5.1zM87.6 149h5.1zM90.2 146.5h2.5zM90.2 154.1h2.5zM161.3 141.4l2.5 2.6zM161.3 144l2.5 2.5zM161.3 146.5l2.5 2.5zM161.3 149l2.5 2.6zM161.3 151.6l2.5 2.5zM161.3 154.1l2.5 2.6zM161.3 156.7l2.5 2.5z"/>
<path d="M176.5 144h5.1zM176.5 146.5h5.1zM176.5 149h5.1zM176.5 151.6h5.1zM176.5 154.1h5.1zM176.5 156.7h5.1zM176.5 159.2h5.1zM163.8 144h12.7zM163.8 146.5h12.7zM163.8 149h12.7zM163.8 151.6h12.7zM163.8 154.1h12.7z"/>
<path d="M163.8 156.7h12.7zM163.8 159.2h12.7zM196.8 144h5.1zM196.8 146.5h5.1zM196.8 149h5.1zM196.8 151.6h5.1zM196.8 154.1h5.1zM196.8 156.7h5.1zM196.8 159.2h5.1zM201.9 144h15.2zM201.9 146.5h15.2zM201.9 149h15.2z"/>
<path d="M201.9 151.6h15.2zM201.9 154.1h15.2zM201.9 156.7h15.2zM201.9 159.2h15.2zM217.1 144l2.6 2.5zM217.1 146.5l2.6 2.5zM217.1 149l2.6 2.6zM217.1 151.6l2.6 2.5zM217.1 154.1l2.6 2.6zM217.1 156.7l2.6 2.5zM217.1 159.2l2.6 2.5zM247.6 141.4l2.6 2.6z"/>
<path d="M247.6 144l2.6 2.5zM247.6 146.5l2.6 2.5zM247.6 149l2.6 2.6zM247.6 151.6l2.6 2.5zM247.6 154.1l2.6 2.6zM247.6 156.7l2.6 2.5zM262.9 159.2h5zM262.9 156.7h5zM262.9 154.1h5zM262.9 151.6h5zM262.9 149h5zM262.9 146.5h5z"/>
<path d="M262.9 144h5zM250.2 144h12.7zM250.2 146.5h12.7zM250.2 149h12.7zM250.2 151.6h12.7zM250.2 154.1h12.7zM250.2 156.7h12.7zM250.2 159.2h12.7zM283.2 144h5.1zM283.2 146.5h5.1zM283.2 149h5.1zM283.2 151.6h5.1z"/>
<path d="M283.2 154.1h5.1zM283.2 156.7h5.1zM283.2 159.2h5.1zM288.3 144h17.7zM288.3 146.5h17.7zM288.3 151.6h17.7zM288.3 154.1h17.7zM288.3 156.7h17.7zM288.3 159.2h17.7zM288.3 149h17.7zM308.6 141.4l-2.6 2.6zM308.6 144l-2.6 2.5z"/>
<path d="M308.6 149l-2.6 2.6zM308.6 151.6l-2.6 2.5zM308.6 154.1l-2.6 2.6zM308.6 156.7l-2.6 2.5zM308.6 159.2l-2.6 2.5zM308.6 146.5l-2.6 2.5zM16.5 173.7h3.8zM67.5 167.3h12.5zM87.6 171.9v2.5zM87.6 161.7v2.6zM87.6 164.3v7.6zM92.7 169.4h3.1z"/>
<path d="M92.7 161.7h5.1zM92.7 164.3h5.1zM87.6 161.7h5.1zM87.6 164.3h5.1zM62.2 169.4h30.5zM151.1 80.5v88.9zM163.8 167.3h7.6zM161.3 159.2l2.5 2.5zM174 171.9v2.5zM174 166.8v5.1zM176.5 166.8h3.1zM176.5 169.4h5.1z"/>
<path d="M176.5 161.7h5.1zM174 166.8h2.5zM151.1 169.4h25.4zM163.8 161.7h12.7zM196.8 161.7h5.1zM201.9 161.7h15.2zM217.1 161.7l2.6 2.6zM247.6 159.2l2.6 2.5zM262.9 161.7h5zM250.2 161.7h12.7zM285.2 166.8h3.1zM283.2 161.7h5.1z"/>
<path d="M285.2 169.4h3.1zM288.3 169.4h2.5zM290.8 171.9v2.5zM290.8 169.4v2.5zM293.3 164.8h7.1zM288.3 161.7h17.7zM308.6 179.5l-2.6 2.6zM288.3 166.8h25.4zM400 173.7h3.8zM138.9 180.1v7zM144 180v7.1zM149.1 179.5v7.6z"/>
<path d="M161.3 179.5l2.5 2.6zM161.3 182.1l2.5 2.5zM161.3 184.6l2.5 2.5zM161.3 187.1l2.5 2.6zM161.3 189.7l2.5 2.5zM161.3 192.2l2.5 2.6zM161.3 194.8l2.5 2.5zM161.3 197.3l2.5 2.5zM176.5 182.1h5.1zM176.5 184.6h5.1zM176.5 187.1h5.1zM176.5 189.7h5.1z"/>
<path d="M176.5 192.2h5.1zM176.5 194.8h5.1zM176.5 197.3h5.1zM176.5 199.8h5.1zM163.8 182.1h12.7zM163.8 184.6h12.7zM163.8 187.1h12.7zM163.8 189.7h12.7zM163.8 192.2h12.7zM163.8 194.8h12.7zM163.8 197.3h12.7zM163.8 199.8h12.7z"/>
<path d="M196.8 182.1h5.1zM196.8 184.6h5.1zM196.8 187.1h5.1zM196.8 189.7h5.1zM196.8 192.2h5.1zM196.8 194.8h5.1zM196.8 197.3h5.1zM196.8 199.8h5.1zM201.9 182.1h15.2zM201.9 184.6h15.2zM201.9 197.3h15.2zM201.9 199.8h15.2z"/>
<path d="M217.1 182.1l2.6 2.5zM217.1 184.6l2.6 2.5zM201.9 194.8h15.2zM217.1 197.3l2.6 2.5zM217.1 199.8l2.6 2.6zM201.9 187.1h15.2zM201.9 192.2h15.2zM201.9 189.7h15.2zM217.1 194.8l2.6 2.5zM217.1 187.1l2.6 2.6zM217.1 192.2l2.6 2.6zM217.1 189.7l2.6 2.5z"/>
<path d="M247.6 179.5l2.6 2.6zM247.6 182.1l2.6 2.5zM247.6 184.6l2.6 2.5zM247.6 187.1l2.6 2.6zM247.6 189.7l2.6 2.5zM247.6 192.2l2.6 2.6zM247.6 194.8l2.6 2.5zM247.6 197.3l2.6 2.5zM262.9 199.8h5zM262.9 197.3h5zM262.9 194.8h5zM262.9 192.2h5z"/>
<path d="M262.9 189.7h5zM262.9 187.1h5zM262.9 184.6h5zM262.9 182.1h5zM250.2 182.1h12.7zM250.2 184.6h12.7zM250.2 187.1h12.7zM250.2 189.7h12.7zM250.2 192.2h12.7zM250.2 194.8h12.7zM250.2 197.3h12.7zM250.2 199.8h12.7z"/>
<path d="M283.2 182.1h5.1zM283.2 184.6h5.1zM283.2 187.1h5.1zM283.2 189.7h5.1zM283.2 192.2h5.1zM283.2 194.8h5.1zM283.2 197.3h5.1zM283.2 199.8h5.1zM288.3 182.1h17.7zM288.3 184.6h17.7zM288.3 187.1h17.7zM288.3 189.7h17.7z"/>
<path d="M288.3 192.2h17.7zM288.3 194.8h17.7zM288.3 197.3h17.7zM288.3 199.8h17.7zM308.6 182.1l-2.6 2.5zM308.6 184.6l-2.6 2.5zM308.6 187.1l-2.6 2.6zM308.6 189.7l-2.6 2.5zM308.6 192.2l-2.6 2.6zM308.6 194.8l-2.6 2.5zM308.6 197.3l-2.6 2.5zM151.1 218.1h7.1z"/>
<path d="M151.1 169.4v38zM163.8 205.4h7.6zM174 210v2.5zM174 204.9v5.1zM176.5 204.9h3.1zM176.5 207.4h5.1zM174 204.9h2.5zM151.1 207.4h25.4zM285.2 204.9h3.1zM285.2 207.4h3.1zM288.3 207.4h2.5zM288.3 204.9h25.4z"/>
<path d="M290.8 210v2.5zM290.8 207.4v2.6zM293.3 202.9h7.1zM303.5 218.1h7.1zM313.7 166.8v38.1zM16.5 224.2h3.8zM140.9 220.1h172.8zM146 225.2h172.7zM151.1 223.2h7.1zM303.5 223.2h7.1zM313.7 204.9v15.2zM318.7 128.7v96.5z"/>
<path d="M400 224.2h3.8zM26.7 253.1v2.6zM26.7 257.7v.5zM26.7 255.7v.5zM26.7 250.6v2.5zM34.3 253.1v2.6zM34.3 257.7v.5zM34.3 255.7v.5zM26.7 250.6h7.6zM34.3 250.6v2.5zM41.9 253.1v2.6zM41.9 257.7v.5z"/>
<path d="M41.9 255.7v.5zM34.3 250.6h7.6zM41.9 250.6v2.5zM49.5 253.1v2.6zM49.5 257.7v.5zM49.5 255.7v.5zM41.9 250.6h7.6zM49.5 250.6v2.5zM57.1 253.1v2.6zM57.1 257.7v.5zM57.1 255.7v.5zM49.5 250.6h7.6z"/>
<path d="M57.1 250.6v2.5zM64.8 253.1v2.6zM64.8 257.7v.5zM64.8 255.7v.5zM57.1 250.6h7.7zM64.8 250.6v2.5zM72.4 253.1v2.6zM72.4 257.7v.5zM72.4 255.7v.5zM64.8 250.6h7.6zM72.4 250.6v2.5zM80 253.1v2.6z"/>
<path d="M80 257.7v.5zM80 255.7v.5zM80 250.6v2.5zM72.4 250.6h7.6zM87.6 253.1v2.6zM87.6 257.7v.5zM87.6 255.7v.5zM80 250.6h7.6zM87.6 250.6v2.5zM95.2 245.5v2.6zM95.2 253.1v2.6zM95.2 257.7v.5z"/>
<path d="M95.2 255.7v.5zM87.6 250.6h7.6zM95.2 248.1v2.5zM95.2 250.6v2.5zM105.4 245.5v2.6zM105.4 253.1v2.6zM105.4 255.7v.5zM105.4 257.7v.5zM105.4 248.1v5zM20.3 274.7h379.7zM26.7 265.8v2.6zM26.7 258.2v2.6z"/>
<path d="M26.7 260.8v2.5zM26.7 263.3h7.6zM26.7 263.3v2.5zM34.3 258.2v2.6zM34.3 263.3h7.6zM34.3 260.8v2.5zM41.9 258.2v2.6zM41.9 263.3h7.6zM41.9 260.8v2.5zM49.5 258.2v2.6zM49.5 263.3h7.6zM49.5 260.8v2.5z"/>
<path d="M57.1 258.2v2.6zM57.1 263.3h7.7zM57.1 260.8v2.5zM64.8 258.2v2.6zM64.8 263.3h7.6zM64.8 260.8v2.5zM67.8 274.7v3.8zM72.4 258.2v2.6zM72.4 263.3h7.6zM72.4 260.8v2.5zM80 258.2v2.6zM80 260.8v2.5z"/>
<path d="M87.6 258.2v2.6zM80 263.3h7.6zM87.6 260.8v2.5zM95.2 258.2v2.6zM87.6 263.3h7.6zM95.2 260.8v2.5zM105.4 265.8v2.6zM105.4 258.2v2.6zM105.4 260.8v5zM115.3 274.7v3.8zM162.7 274.7v3.8zM210.2 274.7v3.8z"/>
<path d="M257.6 274.7v3.8zM305.1 274.7v3.8zM352.5 274.7v3.8zM400 264.5v.1zM400 268.4v6.2zM400 274.6h.1zM400 22.1v252.6z"/>
<circle cx="62.2" cy="57.6" r=".51"/>
<circle cx="67.3" cy="47.5" r=".51"/>
<circle cx="72.4" cy="52.5" r=".51"/>
<circle cx="156.2" cy="93.2" r=".51"/>
<circle cx="72.4" cy="105.9" r=".51"/>
<circle cx="90.2" cy="123.6" r=".51"/>
<circle cx="318.7" cy="128.7" r=".51"/>
<circle cx="87.6" cy="151.6" r=".51"/>
<circle cx="87.6" cy="159.2" r=".51"/>
<circle cx="87.6" cy="156.7" r=".51"/>
<circle cx="90.2" cy="146.5" r=".51"/>
<circle cx="87.6" cy="164.3" r=".51"/>
<circle cx="87.6" cy="161.7" r=".51"/>
<circle cx="151.1" cy="169.4" r=".51"/>
<circle cx="313.7" cy="204.9" r=".51"/>
<circle cx="34.3" cy="250.6" r=".51"/>
<circle cx="41.9" cy="250.6" r=".51"/>
<circle cx="49.5" cy="250.6" r=".51"/>
<circle cx="57.1" cy="250.6" r=".51"/>
<circle cx="64.8" cy="250.6" r=".51"/>
<circle cx="72.4" cy="250.6" r=".51"/>
<circle cx="80" cy="250.6" r=".51"/>
<circle cx="87.6" cy="250.6" r=".51"/>
<circle cx="95.2" cy="250.6" r=".51"/>
<circle cx="26.7" cy="263.3" r=".51"/>
<circle cx="34.3" cy="263.3" r=".51"/>
<circle cx="41.9" cy="263.3" r=".51"/>
<circle cx="49.5" cy="263.3" r=".51"/>
<circle cx="57.1" cy="263.3" r=".51"/>
<circle cx="64.8" cy="263.3" r=".51"/>
<circle cx="72.4" cy="263.3" r=".51"/>
<circle cx="80" cy="263.3" r=".51"/>
<circle cx="87.6" cy="263.3" r=".51"/>
</g>
<path d="M16.5 18.2v260.3zM16.5 18.2h387.3zM16.5 278.5h387.3zM403.8 18.2v260.3z" fill="#000" stroke="#000" stroke-width=".32"/>
<g fill="#000" stroke="#000" stroke-width=".61">
<path d="M20.3 22.1v252.6zM20.3 22.1h379.7zM97.8 75.4v12.7zM97.8 75.4h15.2zM181.6 65.2v30.5zM181.6 65.2h15.2zM267.9 65.2h15.3zM283.2 65.2v30.5zM97.8 88.1h15.2zM97.8 95.7v12.7zM113 75.4v12.7zM97.8 95.7h15.2z"/>
<path d="M181.6 95.7h15.2zM196.8 65.2v30.5zM267.9 65.2v30.5zM267.9 95.7h15.3zM97.8 108.4h15.2zM113 95.7v12.7zM181.6 103.3v30.5zM181.6 103.3h15.2zM267.9 103.3h15.3zM283.2 103.3v30.5zM97.8 121.1v50.8zM97.8 121.1h15.2z"/>
<path d="M181.6 133.8h15.2zM196.8 103.3v30.5zM267.9 103.3v30.5zM267.9 133.8h15.3zM181.6 141.4v30.5zM181.6 141.4h15.2zM267.9 141.4h15.3zM283.2 141.4v30.5zM97.8 171.9h15.2zM113 121.1v50.8zM181.6 171.9h15.2zM181.6 179.5v30.5z"/>
<path d="M196.8 141.4v30.5zM181.6 179.5h15.2zM267.9 141.4v30.5zM267.9 179.5h15.3zM267.9 171.9h15.3zM283.2 179.5v30.5zM181.6 210h15.2zM196.8 179.5v30.5zM267.9 179.5v30.5zM267.9 210h15.3zM283.2 244.3v30.4zM313.7 254.4v5.1z"/>
<path d="M313.7 249.3v5.1zM313.7 244.3v5zM313.7 244.3h86.3zM283.2 244.3h30.5zM400 254.4v5.1zM400 249.3v5.1zM400 244.3v5zM400 22.1v222.2zM20.3 274.7h262.9zM283.2 274.7h30.5zM313.7 274.7h86.3zM313.7 269.7v5z"/>
<path d="M313.7 264.6v5.1zM313.7 259.5v5.1zM400 268.4v6.3zM400 264.6v3.8zM400 259.5v5.1z"/>
</g>
<g fill="#000" stroke="#000" stroke-width=".21">
<path d="M24.6 256.2h4.1v.5h-4.1zM24.6 257.2h4.1v.5h-4.1zM32.3 256.2h4v.5h-4zM32.3 257.2h4v.5h-4zM39.9 256.2h4v.5h-4zM39.9 257.2h4v.5h-4zM47.5 256.2h4.1v.5h-4.1zM47.5 257.2h4.1v.5h-4.1zM55.1 256.2h4.1v.5h-4.1zM55.1 257.2h4.1v.5h-4.1zM62.7 256.2h4.1v.5h-4.1zM62.7 257.2h4.1v.5h-4.1z"/>
<path d="M70.4 256.2h4v.5h-4zM70.4 257.2h4v.5h-4zM78 256.2h4v.5h-4zM78 257.2h4v.5h-4zM85.6 256.2h4.1v.5h-4.1zM85.6 257.2h4.1v.5h-4.1zM93.2 256.2h4.1v.5h-4.1zM93.2 257.2h4.1v.5h-4.1zM103.4 257.2h4v.5h-4zM103.4 256.2h4v.5h-4zM251.4 245.5h25.4v10.2h-25.4z"/>
</g>
<g fill="none" stroke="#000" stroke-width=".21">
<circle cx="114" cy="77.9" r=".99"/>
<circle cx="266.9" cy="77.9" r="1"/>
<circle cx="266.9" cy="67.8" r="1"/>
<circle cx="266.9" cy="70.3" r="1"/>
<circle cx="266.9" cy="75.4" r="1"/>
<circle cx="266.9" cy="72.8" r="1"/>
<circle cx="96.8" cy="85.5" r=".99"/>
<circle cx="114" cy="98.2" r=".99"/>
<circle cx="114" cy="83" r=".99"/>
<circle cx="114" cy="80.5" r=".99"/>
<circle cx="114" cy="85.5" r=".99"/>
<circle cx="180.6" cy="90.6" r=".99"/>
<circle cx="266.9" cy="80.5" r="1"/>
<circle cx="266.9" cy="83" r="1"/>
<circle cx="266.9" cy="85.5" r="1"/>
<circle cx="284.2" cy="93.2" r="1"/>
<circle cx="284.2" cy="90.6" r="1"/>
<circle cx="96.8" cy="105.9" r=".99"/>
<circle cx="114" cy="103.3" r=".99"/>
<circle cx="114" cy="100.8" r=".99"/>
<circle cx="114" cy="105.9" r=".99"/>
<circle cx="266.9" cy="110.9" r="1"/>
<circle cx="266.9" cy="108.4" r="1"/>
<circle cx="266.9" cy="105.9" r="1"/>
<circle cx="266.9" cy="118.6" r="1"/>
<circle cx="266.9" cy="116" r="1"/>
<circle cx="266.9" cy="113.5" r="1"/>
<circle cx="114" cy="123.6" r=".99"/>
<circle cx="180.6" cy="128.7" r=".99"/>
<circle cx="266.9" cy="123.6" r="1"/>
<circle cx="266.9" cy="121.1" r="1"/>
<circle cx="284.2" cy="131.3" r="1"/>
<circle cx="284.2" cy="128.7" r="1"/>
<circle cx="96.8" cy="169.4" r=".99"/>
<circle cx="180.6" cy="166.8" r=".99"/>
<circle cx="284.2" cy="169.4" r="1"/>
<circle cx="284.2" cy="166.8" r="1"/>
<circle cx="180.6" cy="204.9" r=".99"/>
<circle cx="284.2" cy="204.9" r="1"/>
<circle cx="284.2" cy="207.4" r="1"/>
</g>
<g fill="#000" stroke="#000" stroke-width=".76">
<path d="M57.1 34.8h99.1zM156.2 34.8l5.1 5zM156.2 34.8h86.3zM242.5 34.8l5.1 5zM57.1 42.4h17.8zM74.9 42.4l2.6 2.5zM77.5 44.9v94zM316.2 52.5h30.5zM313.7 62.7l5-5.1zM318.7 57.6h28zM219.7 70.3v58.4zM308.6 60.2l7.6-7.7z"/>
<path d="M313.7 62.7v60.9zM219.7 128.7l5.1 5.1zM224.8 133.8v93.9zM308.6 60.2v60.9zM308.6 128.7v68.6zM308.6 128.7l5.1-5.1zM219.7 146.5v83.8zM161.3 39.8v157.5zM247.6 39.8v157.5zM219.7 230.3l7.6 7.6zM224.8 227.7l5 5.1zM227.3 237.9h119.4z"/>
<path d="M229.8 232.8h116.9z"/>
</g>
<path d="M221 245.5v10.2zM221 255.7v12.7zM221 255.7h55.8zM276.8 245.5v10.2zM221 245.5h55.8zM221 268.4h55.8zM276.8 255.7v12.7z" fill="#000" stroke="#000" stroke-width=".42"/>
<use href="#words"/>
</svg>
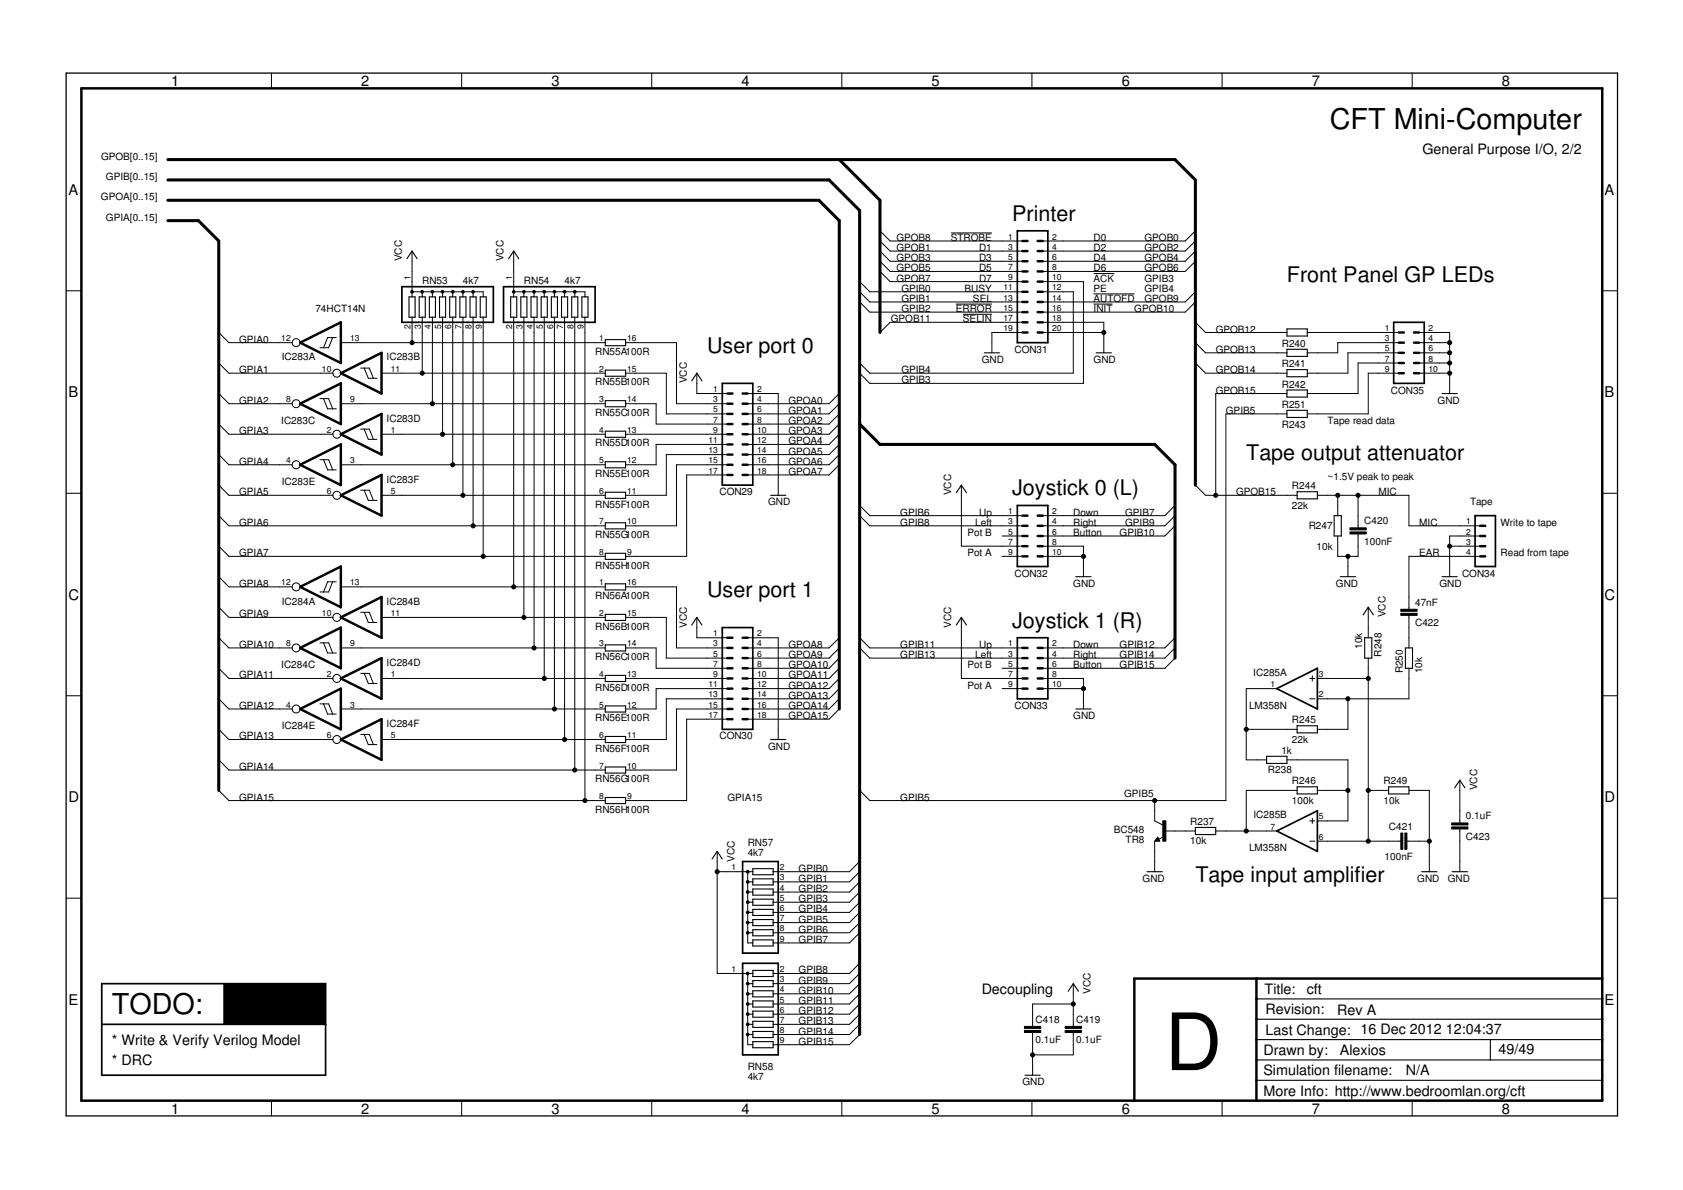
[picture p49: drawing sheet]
<svg xmlns="http://www.w3.org/2000/svg" width="420mm" height="297mm" viewBox="0 0 420 297" stroke-linecap="round" stroke-linejoin="round" font-family="sans-serif">
<defs><g id="words">
<text font-size="19.7" x="290.8" y="267.1">D</text>
<g font-size="7.2">
<text x="332" y="32.2">CFT Mini-Computer</text>
<text x="27.9" y="253.2">TODO:</text>
</g>
<g font-size="5.4">
<text x="252.7" y="55.1">Printer</text>
<text x="321.3" y="70.3">Front Panel GP LEDs</text>
<text x="176.5" y="88.1">User port 0</text>
<text x="311.1" y="114.7">Tape output attenuator</text>
<text x="252.7" y="123.6">Joystick 0 (L)</text>
<text x="176.5" y="149">User port 1</text>
<text x="252.7" y="156.6">Joystick 1 (R)</text>
<text x="298.4" y="220.1">Tape input amplifier</text>
</g>
<g font-size="3.7">
<text x="42.7" y="21.5">1</text>
<text x="90.2" y="21.5">2</text>
<text x="137.7" y="21.5">3</text>
<text x="185.1" y="21.5">4</text>
<text x="232.6" y="21.5">5</text>
<text x="280" y="21.5">6</text>
<text x="327.5" y="21.5">7</text>
<text x="375" y="21.5">8</text>
<text x="17.1" y="48.6">A</text>
<text x="400.6" y="48.6">A</text>
<text x="17.1" y="99.2">B</text>
<text x="400.6" y="99.2">B</text>
<text x="17.1" y="149.7">C</text>
<text x="400.6" y="149.7">C</text>
<text x="17.1" y="200.2">D</text>
<text x="400.6" y="200.2">D</text>
<text x="17.1" y="250.8">E</text>
<text x="400.6" y="250.8">E</text>
<text x="42.7" y="277.9">1</text>
<text x="90.2" y="277.9">2</text>
<text x="137.7" y="277.9">3</text>
<text x="185.1" y="277.9">4</text>
<text x="232.6" y="277.9">5</text>
<text x="280" y="277.9">6</text>
<text x="327.5" y="277.9">7</text>
<text x="375" y="277.9">8</text>
</g>
<g font-size="3.6">
<text x="355.1" y="38.6">General Purpose I/O, 2/2</text>
<text x="245.1" y="248.1">Decoupling</text>
<text x="315.7" y="248.1">Title:</text>
<text x="326.2" y="248.2">cft</text>
<text x="315.9" y="253.2">Revision:</text>
<text x="333.8" y="253.3">Rev A</text>
<text x="27.9" y="260.8">* Write &amp; Verify Verilog Model</text>
<text x="315.4" y="263.3">Drawn by:</text>
<text x="315.9" y="258.2">Last Change: 16 Dec 2012</text>
<text x="334.5" y="263.3">Alexios</text>
<text x="361" y="258.1">12:04:37</text>
<text x="374.1" y="263.2">49/49</text>
<text x="27.9" y="265.8">* DRC</text>
<text x="315.4" y="268.4">Simulation filename:</text>
<text x="351" y="268.4">N/A</text>
<text x="315.4" y="273.5">More Info: http://www.bedroomlan.org/cft</text>
</g>
<g font-size="2.5">
<text x="25.2" y="39.8">GPOB[0..15]</text>
<text x="26.5" y="44.9">GPIB[0..15]</text>
<text x="25.2" y="50">GPOA[0..15]</text>
<text x="26.4" y="55.1">GPIA[0..15]</text>
<text x="100.3" y="65.2" transform="rotate(-90 100.3 65.2)">VCC</text>
<text x="125.7" y="65.2" transform="rotate(-90 125.7 65.2)">VCC</text>
<text x="223.8" y="62.7">GPOB1</text>
<text x="223.8" y="65.2">GPOB3</text>
<text x="223.8" y="60.1">GPOB8</text>
<text x="237.4" y="60.1">STROBE</text>
<text x="244.4" y="62.7">D1</text>
<text x="244.4" y="65.2">D3</text>
<text x="273" y="60.1">D0</text>
<text x="273" y="62.7">D2</text>
<text x="273" y="65.2">D4</text>
<text x="285.7" y="60.1">GPOB0</text>
<text x="285.7" y="62.7">GPOB2</text>
<text x="285.7" y="65.2">GPOB4</text>
<text x="105.4" y="70.9">RN53</text>
<text x="115.6" y="70.9">4k7</text>
<text x="130.8" y="70.9">RN54</text>
<text x="141" y="70.9">4k7</text>
<text x="223.8" y="67.8">GPOB5</text>
<text x="223.8" y="70.3">GPOB7</text>
<text x="244.4" y="67.8">D5</text>
<text x="244.4" y="70.3">D7</text>
<text x="273" y="67.8">D6</text>
<text x="273" y="70.3">ACK</text>
<text x="285.7" y="67.8">GPOB6</text>
<text x="285.7" y="70.3">GPIB3</text>
<text x="78.7" y="77.9">74HCT14N</text>
<text x="225" y="72.8">GPIB0</text>
<text x="225" y="75.4">GPIB1</text>
<text x="225" y="77.9">GPIB2</text>
<text x="238.6" y="77.9">ERROR</text>
<text x="240.8" y="72.8">BUSY</text>
<text x="242.9" y="75.4">SEL</text>
<text x="273" y="75.4">AUTOFD</text>
<text x="273" y="77.9">INIT</text>
<text x="273" y="72.8">PE</text>
<text x="283.2" y="77.9">GPOB10</text>
<text x="285.7" y="75.4">GPOB9</text>
<text x="285.7" y="72.8">GPIB4</text>
<text x="222.4" y="80.5">GPOB11</text>
<text x="240.4" y="80.5">SELIN</text>
<text x="303.5" y="83">GPOB12</text>
<text x="59.7" y="85.5">GPIA0</text>
<text x="70.4" y="90">IC283A</text>
<text x="96.5" y="90">IC283B</text>
<text x="148.6" y="88.6">RN55A100R</text>
<text x="253.3" y="88.1">CON31</text>
<text x="303.5" y="88.1">GPOB13</text>
<text x="320" y="86.6">R240</text>
<text x="59.7" y="93.2">GPIA1</text>
<text x="171.4" y="95.7" transform="rotate(-90 171.4 95.7)">VCC</text>
<text x="225" y="95.7">GPIB3</text>
<text x="225" y="93.2">GPIB4</text>
<text x="245.1" y="90.6">GND</text>
<text x="273" y="90.6">GND</text>
<text x="303.5" y="93.2">GPOB14</text>
<text x="320" y="91.7">R241</text>
<text x="59.7" y="100.8">GPIA2</text>
<text x="148.6" y="96.2">RN55B100R</text>
<text x="196.8" y="100.8">GPOA0</text>
<text x="303.5" y="98.2">GPOB15</text>
<text x="320" y="96.7">R242</text>
<text x="320" y="101.8">R251</text>
<text x="347.2" y="98.2">CON35</text>
<text x="358.9" y="100.8">GND</text>
<text x="70.2" y="105.7">IC283C</text>
<text x="96.5" y="105.2">IC283D</text>
<text x="148.6" y="103.8">RN55C100R</text>
<text x="196.8" y="103.3">GPOA1</text>
<text x="196.8" y="105.9">GPOA2</text>
<text x="306" y="103.3">GPIB5</text>
<text x="320" y="106.9">R243</text>
<text x="331.4" y="105.9">Tape read data</text>
<text x="59.7" y="108.4">GPIA3</text>
<text x="148.6" y="111.4">RN55D100R</text>
<text x="196.8" y="108.4">GPOA3</text>
<text x="196.8" y="110.9">GPOA4</text>
<text x="196.8" y="113.5">GPOA5</text>
<text x="59.7" y="116">GPIA4</text>
<text x="148.6" y="119.1">RN55E100R</text>
<text x="196.8" y="116">GPOA6</text>
<text x="196.8" y="118.6">GPOA7</text>
<text x="331.4" y="119.8">~1.5V peak to peak</text>
<text x="59.7" y="123.6">GPIA5</text>
<text x="70.4" y="121">IC283E</text>
<text x="96.5" y="120.5">IC283F</text>
<text x="179.6" y="123.6">CON29</text>
<text x="237.5" y="123.6" transform="rotate(-90 237.5 123.6)">VCC</text>
<text x="308.6" y="123.6">GPOB15</text>
<text x="322.5" y="122.1">R244</text>
<text x="344.1" y="123.6">MIC</text>
<text x="59.7" y="131.3">GPIA6</text>
<text x="148.6" y="126.7">RN55F100R</text>
<text x="191.7" y="126.2">GND</text>
<text x="224.8" y="128.7">GPIB6</text>
<text x="224.8" y="131.3">GPIB8</text>
<text x="243.5" y="131.3">Left</text>
<text x="244.4" y="128.7">Up</text>
<text x="267.9" y="128.7">Down</text>
<text x="267.9" y="131.3">Right</text>
<text x="280.9" y="128.7">GPIB7</text>
<text x="280.9" y="131.3">GPIB9</text>
<text x="322.5" y="126.9">22k</text>
<text x="326.7" y="132">R247</text>
<text x="340.6" y="130.9">C420</text>
<text x="354.3" y="131.3">MIC</text>
<text x="367" y="126.2">Tape</text>
<text x="374.6" y="131.3">Write to tape</text>
<text x="148.6" y="134.3">RN55G100R</text>
<text x="241.5" y="133.8">Pot B</text>
<text x="267.9" y="133.8">Button</text>
<text x="279.5" y="133.8">GPIB10</text>
<text x="328.7" y="137.3">10k</text>
<text x="340.6" y="136">100nF</text>
<text x="59.7" y="138.9">GPIA7</text>
<text x="148.6" y="141.9">RN55H100R</text>
<text x="241.5" y="138.9">Pot A</text>
<text x="253.3" y="144">CON32</text>
<text x="354.3" y="138.9">EAR</text>
<text x="365" y="144">CON34</text>
<text x="374.6" y="138.9">Read from tape</text>
<text x="59.7" y="146.5">GPIA8</text>
<text x="148.6" y="149.5">RN56A100R</text>
<text x="267.9" y="146.5">GND</text>
<text x="333.5" y="146.5">GND</text>
<text x="359.4" y="146.5">GND</text>
<text x="59.7" y="154.1">GPIA9</text>
<text x="70.4" y="150.9">IC284A</text>
<text x="96.5" y="150.9">IC284B</text>
<text x="345.9" y="154.1" transform="rotate(-90 345.9 154.1)">VCC</text>
<text x="353.3" y="151.2">47nF</text>
<text x="59.7" y="161.7">GPIA10</text>
<text x="148.6" y="157.2">RN56B100R</text>
<text x="171.4" y="156.6" transform="rotate(-90 171.4 156.6)">VCC</text>
<text x="196.8" y="161.7">GPOA8</text>
<text x="224.8" y="161.7">GPIB11</text>
<text x="237.5" y="156.6" transform="rotate(-90 237.5 156.6)">VCC</text>
<text x="244.4" y="161.7">Up</text>
<text x="267.9" y="161.7">Down</text>
<text x="279.5" y="161.7">GPIB12</text>
<text x="340.1" y="162" transform="rotate(-90 340.1 162)">10k</text>
<text x="353.3" y="156.3">C422</text>
<text x="70.2" y="166.7">IC284C</text>
<text x="96.5" y="166.2">IC284D</text>
<text x="148.6" y="164.8">RN56C100R</text>
<text x="196.8" y="164.3">GPOA9</text>
<text x="196.8" y="166.8">GPOA10</text>
<text x="224.8" y="164.3">GPIB13</text>
<text x="241.5" y="166.8">Pot B</text>
<text x="243.5" y="164.3">Left</text>
<text x="267.9" y="164.3">Right</text>
<text x="267.9" y="166.8">Button</text>
<text x="279.5" y="164.3">GPIB14</text>
<text x="279.5" y="166.8">GPIB15</text>
<text x="344.9" y="163.9" transform="rotate(-90 344.9 163.9)">R248</text>
<text x="59.7" y="169.3">GPIA11</text>
<text x="148.6" y="172.4">RN56D100R</text>
<text x="196.8" y="169.3">GPOA11</text>
<text x="196.8" y="171.9">GPOA12</text>
<text x="241.5" y="171.9">Pot A</text>
<text x="312.9" y="168.7">IC285A</text>
<text x="350.2" y="168.1" transform="rotate(-90 350.2 168.1)">R250</text>
<text x="355.1" y="168.1" transform="rotate(-90 355.1 168.1)">10k</text>
<text x="59.7" y="177">GPIA12</text>
<text x="196.8" y="174.4">GPOA13</text>
<text x="196.8" y="177">GPOA14</text>
<text x="196.8" y="179.5">GPOA15</text>
<text x="253.3" y="177">CON33</text>
<text x="267.9" y="179.5">GND</text>
<text x="311.8" y="177">LM358N</text>
<text x="59.7" y="184.6">GPIA13</text>
<text x="70.4" y="181.9">IC284E</text>
<text x="96.5" y="181.4">IC284F</text>
<text x="148.6" y="180">RN56E100R</text>
<text x="179.6" y="184.6">CON30</text>
<text x="322.5" y="185.3">22k</text>
<text x="322.5" y="180.5">R245</text>
<text x="148.6" y="187.6">RN56F100R</text>
<text x="191.7" y="187.1">GND</text>
<text x="319.9" y="188.1">1k</text>
<text x="59.7" y="192.2">GPIA14</text>
<text x="148.6" y="195.3">RN56G100R</text>
<text x="316.6" y="192.9">R238</text>
<text x="322.5" y="195.8">R246</text>
<text x="345.4" y="195.8">R249</text>
<text x="368.8" y="197.3" transform="rotate(-90 368.8 197.3)">VCC</text>
<text x="59.7" y="199.8">GPIA15</text>
<text x="148.6" y="202.9">RN56H100R</text>
<text x="181.6" y="199.8">GPIA15</text>
<text x="224.8" y="199.8">GPIB5</text>
<text x="280.6" y="199.1">GPIB5</text>
<text x="322.5" y="200.6">100k</text>
<text x="345.4" y="200.6">10k</text>
<text x="278.1" y="207.9">BC548</text>
<text x="297.1" y="205.9">R237</text>
<text x="312.9" y="204.3">IC285B</text>
<text x="346.8" y="207.1">C421</text>
<text x="366" y="204.5">0.1uF</text>
<text x="366" y="209.6">C423</text>
<text x="183.4" y="215.1" transform="rotate(-90 183.4 215.1)">VCC</text>
<text x="186.7" y="213.7">4k7</text>
<text x="186.7" y="211.1">RN57</text>
<text x="281" y="210.5">TR8</text>
<text x="297.1" y="210.7">10k</text>
<text x="311.8" y="212.5">LM358N</text>
<text x="345.7" y="214.7">100nF</text>
<text x="199.4" y="217.6">GPIB0</text>
<text x="199.4" y="220.1">GPIB1</text>
<text x="285.2" y="220.1">GND</text>
<text x="353.8" y="220.1">GND</text>
<text x="361.4" y="220.1">GND</text>
<text x="199.4" y="222.7">GPIB2</text>
<text x="199.4" y="225.2">GPIB3</text>
<text x="199.4" y="227.8">GPIB4</text>
<text x="199.4" y="230.3">GPIB5</text>
<text x="199.4" y="232.8">GPIB6</text>
<text x="199.4" y="235.4">GPIB7</text>
<text x="199.4" y="243">GPIB8</text>
<text x="199.4" y="245.5">GPIB9</text>
<text x="199.4" y="248.1">GPIB10</text>
<text x="199.4" y="250.6">GPIB11</text>
<text x="272.3" y="248.1" transform="rotate(-90 272.3 248.1)">VCC</text>
<text x="199.4" y="253.2">GPIB12</text>
<text x="199.4" y="255.7">GPIB13</text>
<text x="258.5" y="255.3">C418</text>
<text x="268.7" y="255.3">C419</text>
<text x="199.4" y="258.2">GPIB14</text>
<text x="199.4" y="260.8">GPIB15</text>
<text x="258.5" y="260.4">0.1uF</text>
<text x="268.7" y="260.4">0.1uF</text>
<text x="186.7" y="269.5">4k7</text>
<text x="186.7" y="267">RN58</text>
<text x="255.2" y="270.9">GND</text>
</g>
<g font-size="2.1">
<text x="251.7" y="59.8">1</text>
<text x="262.7" y="59.8">2</text>
<text x="251.7" y="62.3">3</text>
<text x="251.7" y="64.9">5</text>
<text x="262.7" y="62.3">4</text>
<text x="262.7" y="64.9">6</text>
<text x="102.5" y="69.9" transform="rotate(-90 102.5 69.9)">1</text>
<text x="127.9" y="69.9" transform="rotate(-90 127.9 69.9)">1</text>
<text x="251.7" y="67.4">7</text>
<text x="251.7" y="69.9">9</text>
<text x="262.7" y="67.4">8</text>
<text x="262.7" y="69.9">10</text>
<text x="250.5" y="72.5">11</text>
<text x="250.5" y="75">13</text>
<text x="250.5" y="77.6">15</text>
<text x="262.7" y="72.5">12</text>
<text x="262.7" y="75">14</text>
<text x="262.7" y="77.6">16</text>
<text x="102.5" y="82" transform="rotate(-90 102.5 82)">2</text>
<text x="105" y="82" transform="rotate(-90 105 82)">3</text>
<text x="107.6" y="82" transform="rotate(-90 107.6 82)">4</text>
<text x="110.1" y="82" transform="rotate(-90 110.1 82)">5</text>
<text x="112.7" y="82" transform="rotate(-90 112.7 82)">6</text>
<text x="115.2" y="82" transform="rotate(-90 115.2 82)">7</text>
<text x="117.7" y="82" transform="rotate(-90 117.7 82)">8</text>
<text x="120.3" y="82" transform="rotate(-90 120.3 82)">9</text>
<text x="127.9" y="82" transform="rotate(-90 127.9 82)">2</text>
<text x="130.4" y="82" transform="rotate(-90 130.4 82)">3</text>
<text x="133" y="82" transform="rotate(-90 133 82)">4</text>
<text x="135.5" y="82" transform="rotate(-90 135.5 82)">5</text>
<text x="138.1" y="82" transform="rotate(-90 138.1 82)">6</text>
<text x="140.6" y="82" transform="rotate(-90 140.6 82)">7</text>
<text x="143.1" y="82" transform="rotate(-90 143.1 82)">8</text>
<text x="145.7" y="82" transform="rotate(-90 145.7 82)">9</text>
<text x="250.5" y="80.1">17</text>
<text x="250.5" y="82.6">19</text>
<text x="262.7" y="80.1">18</text>
<text x="262.7" y="82.6">20</text>
<text x="345.7" y="82.6">1</text>
<text x="356.6" y="82.6">2</text>
<text x="70.2" y="85.2">12</text>
<text x="87.4" y="85.2">13</text>
<text x="149.6" y="85.2">1</text>
<text x="156.5" y="85.2">16</text>
<text x="345.7" y="85.2">3</text>
<text x="345.7" y="87.7">5</text>
<text x="356.6" y="85.2">4</text>
<text x="356.6" y="87.7">6</text>
<text x="80.4" y="92.8">10</text>
<text x="97.6" y="92.8">11</text>
<text x="149.6" y="92.8">2</text>
<text x="156.5" y="92.8">15</text>
<text x="345.7" y="90.3">7</text>
<text x="345.7" y="92.8">9</text>
<text x="356.6" y="90.3">8</text>
<text x="356.6" y="92.8">10</text>
<text x="71.4" y="100.4">8</text>
<text x="87.4" y="100.4">9</text>
<text x="149.6" y="100.4">3</text>
<text x="156.5" y="100.4">14</text>
<text x="178.1" y="97.9">1</text>
<text x="178.1" y="100.4">3</text>
<text x="189" y="97.9">2</text>
<text x="189" y="100.4">4</text>
<text x="178.1" y="103">5</text>
<text x="178.1" y="105.5">7</text>
<text x="189" y="103">6</text>
<text x="189" y="105.5">8</text>
<text x="81.6" y="108">2</text>
<text x="97.6" y="108">1</text>
<text x="149.6" y="108">4</text>
<text x="156.5" y="108">13</text>
<text x="176.9" y="110.6">11</text>
<text x="176.9" y="113.1">13</text>
<text x="178.1" y="108">9</text>
<text x="189" y="108">10</text>
<text x="189" y="110.6">12</text>
<text x="189" y="113.1">14</text>
<text x="71.4" y="115.7">4</text>
<text x="87.4" y="115.7">3</text>
<text x="149.6" y="115.7">5</text>
<text x="156.5" y="115.7">12</text>
<text x="176.9" y="115.7">15</text>
<text x="176.9" y="118.2">17</text>
<text x="189" y="115.7">16</text>
<text x="189" y="118.2">18</text>
<text x="81.6" y="123.3">6</text>
<text x="97.6" y="123.3">5</text>
<text x="149.6" y="123.3">6</text>
<text x="156.5" y="123.3">11</text>
<text x="149.6" y="130.9">7</text>
<text x="156.5" y="130.9">10</text>
<text x="251.7" y="128.4">1</text>
<text x="251.7" y="130.9">3</text>
<text x="262.7" y="128.4">2</text>
<text x="262.7" y="130.9">4</text>
<text x="366" y="130.9">1</text>
<text x="251.7" y="133.4">5</text>
<text x="251.7" y="136">7</text>
<text x="262.7" y="133.4">6</text>
<text x="262.7" y="136">8</text>
<text x="366" y="133.4">2</text>
<text x="366" y="136">3</text>
<text x="149.6" y="138.5">8</text>
<text x="156.5" y="138.5">9</text>
<text x="251.7" y="138.5">9</text>
<text x="262.7" y="138.5">10</text>
<text x="366" y="138.5">4</text>
<text x="70.2" y="146.1">12</text>
<text x="87.4" y="146.1">13</text>
<text x="149.6" y="146.1">1</text>
<text x="156.5" y="146.1">16</text>
<text x="80.4" y="153.8">10</text>
<text x="97.6" y="153.8">11</text>
<text x="149.6" y="153.8">2</text>
<text x="156.5" y="153.8">15</text>
<text x="71.4" y="161.4">8</text>
<text x="87.4" y="161.4">9</text>
<text x="149.6" y="161.4">3</text>
<text x="156.5" y="161.4">14</text>
<text x="178.1" y="158.8">1</text>
<text x="178.1" y="161.4">3</text>
<text x="189" y="158.8">2</text>
<text x="189" y="161.4">4</text>
<text x="251.7" y="161.4">1</text>
<text x="262.7" y="161.4">2</text>
<text x="178.1" y="163.9">5</text>
<text x="178.1" y="166.5">7</text>
<text x="189" y="163.9">6</text>
<text x="189" y="166.5">8</text>
<text x="251.7" y="163.9">3</text>
<text x="251.7" y="166.5">5</text>
<text x="262.7" y="163.9">4</text>
<text x="262.7" y="166.5">6</text>
<text x="81.6" y="169">2</text>
<text x="97.6" y="169">1</text>
<text x="149.6" y="169">4</text>
<text x="156.5" y="169">13</text>
<text x="176.9" y="171.5">11</text>
<text x="178.1" y="169">9</text>
<text x="189" y="169">10</text>
<text x="189" y="171.5">12</text>
<text x="251.7" y="169">7</text>
<text x="251.7" y="171.5">9</text>
<text x="262.7" y="169">8</text>
<text x="262.7" y="171.5">10</text>
<text x="317.2" y="171.5">1</text>
<text x="329.2" y="169">3</text>
<text x="71.4" y="176.6">4</text>
<text x="87.4" y="176.6">3</text>
<text x="149.6" y="176.6">5</text>
<text x="156.5" y="176.6">12</text>
<text x="176.9" y="174.1">13</text>
<text x="176.9" y="176.6">15</text>
<text x="176.9" y="179.1">17</text>
<text x="189" y="174.1">14</text>
<text x="189" y="176.6">16</text>
<text x="189" y="179.1">18</text>
<text x="329.2" y="174.1">2</text>
<text x="81.6" y="184.2">6</text>
<text x="97.6" y="184.2">5</text>
<text x="149.6" y="184.2">6</text>
<text x="156.5" y="184.2">11</text>
<text x="149.6" y="191.8">7</text>
<text x="156.5" y="191.8">10</text>
<text x="149.6" y="199.5">8</text>
<text x="156.5" y="199.5">9</text>
<text x="317.2" y="207.1">7</text>
<text x="329.2" y="209.6">6</text>
<text x="329.2" y="204.5">5</text>
<text x="182.6" y="217.2">1</text>
<text x="194.6" y="217.2">2</text>
<text x="194.6" y="219.8">3</text>
<text x="194.6" y="222.3">4</text>
<text x="194.6" y="224.9">5</text>
<text x="194.6" y="227.4">6</text>
<text x="194.6" y="229.9">7</text>
<text x="194.6" y="232.5">8</text>
<text x="194.6" y="235">9</text>
<text x="182.6" y="242.6">1</text>
<text x="194.6" y="242.6">2</text>
<text x="194.6" y="245.2">3</text>
<text x="194.6" y="247.7">4</text>
<text x="194.6" y="250.3">5</text>
<text x="194.6" y="252.8">6</text>
<text x="194.6" y="255.3">7</text>
<text x="194.6" y="257.9">8</text>
<text x="194.6" y="260.4">9</text>
</g>
</g></defs>
<g fill="#000" stroke="#000" stroke-width=".25">
<path d="M67.8 18.2v3.9zM115.3 18.2v3.9zM162.7 18.2v3.9zM210.2 18.2v3.9zM257.6 18.2v3.9zM305.1 18.2v3.9zM352.5 18.2v3.9zM20.3 22.1v252.6zM20.3 22.1h379.7zM219.7 57.6l2.5 2.6zM237.4 58.1h10.2zM16.5 72.6h3.8z"/>
<path d="M102.9 67.8v2.5zM102.9 79.2v1.3zM102.9 72.8v1.3zM102.9 72.8h2.5zM102.9 70.3v2.5zM102.9 62.7v2.5zM102.9 65.2v2.6zM105.4 72.8v1.3zM105.4 72.8h2.5zM107.9 72.8v1.3zM107.9 72.8h2.6zM110.5 72.8v1.3z"/>
<path d="M110.5 72.8h2.5zM113 72.8v1.3zM113 72.8h2.6zM115.6 79.2v1.3zM115.6 72.8v1.3zM115.6 72.8h2.5zM118.1 72.8v1.3zM118.1 72.8h2.5zM120.6 72.8v1.3zM128.2 67.8v2.5zM128.2 79.2v1.3zM128.2 72.8v1.3z"/>
<path d="M128.2 72.8h2.6zM128.2 70.3v2.5zM128.2 62.7v2.5zM128.2 65.2v2.6zM130.8 72.8v1.3zM130.8 72.8h2.5zM133.3 72.8v1.3zM133.3 72.8h2.6zM135.9 72.8v1.3zM135.9 72.8h2.5zM138.4 72.8v1.3zM138.4 72.8h2.5z"/>
<path d="M140.9 79.2v1.3zM140.9 72.8v1.3zM140.9 72.8h2.6zM143.5 72.8v1.3zM143.5 72.8h2.5zM146 72.8v1.3zM214.6 70.3l2.5 2.5zM214.6 72.8l2.5 2.6zM214.6 75.4l2.5 2.5zM219.7 60.2l2.5 2.5zM219.7 62.7l2.5 2.5zM219.7 65.2l2.5 2.6z"/>
<path d="M219.7 67.8l2.5 2.5zM222.2 60.2h28zM238.6 75.9h9zM240.4 78.4h7.2zM250.2 60.2h5zM250.2 62.7h5zM250.2 65.2h5zM250.2 67.8h5zM250.2 70.3h5zM250.2 72.8h5zM250.2 75.4h5zM250.2 77.9h5z"/>
<path d="M222.2 62.7h28zM222.2 65.2h28zM222.2 67.8h28zM222.2 70.3h28zM217.1 72.8h33.1zM217.1 75.4h33.1zM217.1 77.9h33.1zM260.3 60.2h5.1zM260.3 62.7h5.1zM260.3 65.2h5.1zM260.3 67.8h5.1zM260.3 70.3h5.1z"/>
<path d="M260.3 72.8h5.1zM260.3 75.4h5.1zM260.3 77.9h5.1zM265.4 60.2h30.5zM265.4 62.7h30.5zM265.4 65.2h30.5zM265.4 67.8h30.5zM265.4 75.4h30.5zM265.4 77.9h30.5zM265.4 70.3h5.1zM265.4 72.8h2.5zM270.5 70.3v25.4z"/>
<path d="M273 73.4h10.2zM273 75.9h4.7zM273 68.3h5.2zM295.9 60.2l2.5-2.6zM295.9 62.7l2.5-2.5zM295.9 65.2l2.5-2.5zM295.9 67.8l2.5-2.6zM295.9 75.4l2.5-2.6zM295.9 77.9l2.5-2.5zM400 72.6h3.8zM54.6 83l2.5 2.5zM54.6 90.6l2.5 2.6z"/>
<path d="M69.8 85.5h3.1zM57.1 85.5h12.7zM80 93.2h3.1zM57.1 93.2h22.9zM81.8 84.3l-1 2.5zM79.9 86.8h.9zM80.8 99.5l1 2.5zM79.9 99.5h.9zM83.1 84.3l-1.1 2.5zM80.8 86.8h1.2zM82 99.5l1.1 2.5zM80.8 99.5h1.2z"/>
<path d="M81.8 84.3h1.3zM83.1 84.3h.8zM85.1 85.5h5.1zM90.2 85.5h12.7zM90.9 91.9l1 2.5zM90 91.9h.9zM92.2 91.9l1 2.5zM90.9 91.9h1.3zM91.9 94.4h1.3zM93.2 94.4h.9zM95.2 93.2h5.1zM100.3 93.2h5.1z"/>
<path d="M102.9 80.5v2.5zM102.9 85.5h45.7zM102.9 83v2.5zM105.4 80.5v2.5zM105.4 79.2v1.3zM105.4 93.2h43.2zM105.4 83v10.2zM107.9 80.5v2.5zM107.9 79.2v1.3zM107.9 83v17.8zM110.5 80.5v2.5zM110.5 79.2v1.3z"/>
<path d="M110.5 83v25.4zM113 80.5v2.5zM113 79.2v1.3zM113 83v33zM115.6 80.5v2.5zM115.6 83v40.6zM118.1 80.5v2.5zM118.1 79.2v1.3zM118.1 83v48.3zM120.6 80.5v2.5zM120.6 79.2v1.3zM120.6 83v55.9z"/>
<path d="M128.2 80.5v2.5zM128.2 83v63.5zM130.8 80.5v2.5zM130.8 79.2v1.3zM130.8 83v71.1zM133.3 80.5v2.5zM133.3 79.2v1.3zM133.3 83v78.7zM135.9 80.5v2.5zM135.9 79.2v1.3zM135.9 83v86.4zM138.4 80.5v2.5z"/>
<path d="M138.4 79.2v1.3zM138.4 83v94zM140.9 80.5v2.5zM140.9 83v101.6zM143.5 80.5v2.5zM143.5 79.2v1.3zM143.5 83v109.2zM146 80.5v2.5zM146 79.2v1.3zM146 83v116.8zM148.6 85.5h2.5zM148.6 93.2h2.5z"/>
<path d="M156.2 85.5h2.5zM156.2 93.2h2.5zM158.7 85.5h10.2zM158.7 93.2h7.6zM166.3 93.2v10.1zM168.9 85.5v15.3zM174 93.2v2.5zM174 95.7v2.5zM176.5 98.2h5.1zM174 98.2h2.5zM186.7 98.2h5zM191.7 98.2h2.6z"/>
<path d="M194.3 98.2v22.9zM214.6 93.2l2.5 2.5zM214.6 90.6l2.5 2.6zM222.2 80.5l-2.5 2.5zM247.6 85.5v2.6zM247.6 83v2.5zM250.2 80.5h5zM250.2 83h5zM247.6 83h2.6zM222.2 80.5h28zM260.3 80.5h5.1zM260.3 83h5.1z"/>
<path d="M265.4 80.5h10.2zM265.4 83h10.2zM217.1 93.2h50.8zM267.9 72.8v20.4zM217.1 95.7h53.4zM275.6 85.5v2.6zM275.6 80.5v2.5zM275.6 83v2.5zM298.4 80.5l2.6 2.5zM298.4 85.5l2.6 2.6zM298.4 90.6l2.6 2.6zM303.5 98.2v25.4z"/>
<path d="M318.7 83h2.6zM318.7 88.1h2.6zM318.7 93.2h2.6zM318.7 98.2h2.6zM303.5 98.2h15.2zM301 83h17.7zM301 88.1h17.7zM301 93.2h17.7zM326.4 83h2.5zM326.4 88.1h2.5zM326.4 93.2h2.5zM326.4 98.2h2.5z"/>
<path d="M328.9 83h15.2zM328.9 88.1h5.1zM328.9 93.2h7.6zM328.9 98.2h10.1zM334 85.5v2.6zM334 85.5h10.1zM336.5 88.1v5.1zM336.5 88.1h7.6zM339 90.6v7.6zM341.6 93.2h2.5zM344.1 83h5.1zM344.1 85.5h5.1z"/>
<path d="M344.1 88.1h5.1zM344.1 90.6h5.1zM344.1 93.2h5.1zM339 90.6h5.1zM354.3 83h5.1zM354.3 85.5h5.1zM354.3 88.1h5.1zM354.3 90.6h5.1zM354.3 93.2h5.1zM359.4 83h2.5zM359.4 85.5h2.5zM359.4 88.1h2.5z"/>
<path d="M359.4 90.6h2.5zM359.4 93.2h2.5zM361.9 95.7v2.5zM361.9 83v2.5zM361.9 85.5v2.6zM361.9 88.1v2.5zM361.9 90.6v2.6zM361.9 93.2v2.5zM54.6 98.2l2.5 2.6zM54.6 105.9l2.5 2.5zM54.6 113.5l2.5 2.5zM69.8 100.8h3.1z"/>
<path d="M69.8 116h3.1zM57.1 100.8h12.7zM57.1 116h12.7zM80 108.4h3.1zM57.1 108.4h22.9zM80.8 114.7l1 2.6zM79.9 114.7h.9zM82 114.7l1.1 2.6zM80.8 114.7h1.2zM81.8 102h1.3zM81.8 117.3h1.3zM83.1 102h.8z"/>
<path d="M83.1 117.3h.8zM85.1 100.8h5.1zM85.1 116h5.1zM90.2 100.8h17.7zM90.2 116h22.8zM90.9 107.1l1 2.6zM90 107.1h.9zM92.2 107.1l1 2.6zM90.9 107.1h1.3zM91.9 109.7h1.3zM93.2 109.7h.9zM95.2 108.4h5.1z"/>
<path d="M100.3 108.4h10.2zM107.9 100.8h40.7zM110.5 108.4h38.1zM113 116h35.6zM148.6 100.8h2.5zM148.6 108.4h2.5zM148.6 116h2.5zM156.2 100.8h2.5zM156.2 108.4h2.5zM156.2 116h2.5zM158.7 100.8h5.1zM158.7 108.4h17.8z"/>
<path d="M158.7 116h5.1zM163.8 100.8v5.1zM163.8 105.9h12.7zM163.8 110.9v5.1zM163.8 110.9h12.7zM166.3 103.3h10.2zM166.3 113.5h10.2zM168.9 100.8h7.6zM168.9 116h7.6zM171.4 118.6h5.1zM176.5 100.8h5.1zM176.5 103.3h5.1z"/>
<path d="M176.5 105.9h5.1zM176.5 108.4h5.1zM176.5 110.9h5.1zM176.5 113.5h5.1zM176.5 116h5.1zM176.5 118.6h5.1zM186.7 100.8h5zM186.7 103.3h5zM186.7 105.9h5zM186.7 108.4h5zM186.7 110.9h5zM186.7 113.5h5z"/>
<path d="M186.7 116h5zM186.7 118.6h5zM191.7 100.8h15.3zM191.7 103.3h15.3zM191.7 105.9h15.3zM191.7 108.4h15.3zM191.7 110.9h15.3zM191.7 113.5h15.3zM191.7 116h15.3zM191.7 118.6h15.3zM207 100.8l2.5-2.6zM207 103.3l2.5-2.5z"/>
<path d="M207 105.9l2.5-2.6zM207 108.4l2.5-2.5zM207 110.9l2.5-2.5zM207 113.5l2.5-2.6zM207 116l2.5-2.5zM207 118.6l2.5-2.6zM306 103.3h12.7zM318.7 103.3h2.6zM326.4 103.3h2.5zM328.9 103.3h12.7zM341.6 93.2v10.1zM16.5 123.1h3.8z"/>
<path d="M54.6 128.7l2.5 2.6zM54.6 136.3l2.5 2.6zM54.6 121.1l2.5 2.5zM57.1 131.3h61zM57.1 138.9h63.5zM80 123.6h3.1zM57.1 123.6h22.9zM90.9 122.4l1 2.5zM90 122.4h.9zM92.2 122.4l1 2.5zM90.9 122.4h1.3zM91.9 124.9h1.3z"/>
<path d="M93.2 124.9h.9zM95.2 123.6h5.1zM100.3 123.6h15.3zM115.6 123.6h33zM148.6 123.6h2.5zM148.6 131.3h2.5zM148.6 138.9h2.5zM118.1 131.3h30.5zM120.6 138.9h28zM156.2 123.6h2.5zM156.2 131.3h2.5zM156.2 138.9h2.5z"/>
<path d="M158.7 123.6h7.6zM158.7 131.3h10.2zM158.7 138.9h12.7zM166.3 113.5v10.1zM168.9 116v15.3zM171.4 118.6v20.3zM194.3 121.1v2.5zM214.6 126.2l2.5 2.5zM214.6 128.7l2.5 2.6zM240 121.1v2.5zM240 123.6v12.7zM250.2 128.7h5z"/>
<path d="M250.2 131.3h5zM250.2 133.8h5zM250.2 136.3h5zM250.2 138.9h5zM240 136.3h10.2zM217.1 128.7h33.1zM217.1 131.3h33.1zM260.3 128.7h5.1zM260.3 131.3h5.1zM260.3 133.8h5.1zM260.3 136.3h5.1zM260.3 138.9h5.1z"/>
<path d="M265.4 136.3h5.1zM265.4 138.9h5.1zM265.4 128.7h25.4zM265.4 131.3h25.4zM265.4 133.8h25.4zM270.5 136.3v2.6zM270.5 138.9v2.5zM293.3 126.2l-2.5 2.5zM293.3 128.7l-2.5 2.6zM290.8 133.8l2.5-2.5zM298.4 121.1l2.6 2.5zM301 123.6h2.5z"/>
<path d="M321.3 123.6h2.5zM303.5 123.6h17.8zM328.9 123.6h2.5zM331.4 123.6h2.6zM334 133.8v2.5zM334 126.2v2.5zM334 136.3v2.6zM334 123.6h5zM334 123.6v2.6zM334 138.9h2.5zM339 128.7v2.6zM339 133.8v2.5z"/>
<path d="M339 131.3v.5zM339 133.3v.5zM339 136.3v2.6zM336.5 138.9h2.5zM339 123.6v5.1zM339 123.6h12.7zM351.7 123.6v7.7zM351.7 131.3h12.7zM351.7 138.9v10.1zM361.9 133.8v2.5zM361.9 136.3v5.1zM364.4 131.3h5.1z"/>
<path d="M364.4 133.8h5.1zM364.4 136.3h5.1zM364.4 138.9h5.1zM361.9 133.8h2.5zM361.9 136.3h2.5zM351.7 138.9h12.7zM400 123.1h3.8zM54.6 144l2.5 2.5zM54.6 151.6l2.5 2.5zM69.8 146.5h3.1zM57.1 146.5h12.7zM80 154.1h3.1z"/>
<path d="M57.1 154.1h22.9zM81.8 145.2l-1 2.6zM79.9 147.8h.9zM83.1 145.2l-1.1 2.6zM80.8 147.8h1.2zM81.8 145.2h1.3zM83.1 145.2h.8zM85.1 146.5h5.1zM90.2 146.5h38zM90.9 152.8l1 2.6zM90 152.8h.9zM92.2 152.8l1 2.6z"/>
<path d="M90.9 152.8h1.3zM91.9 155.4h1.3zM93.2 155.4h.9zM95.2 154.1h5.1zM100.3 154.1h30.5zM128.2 146.5h20.4zM130.8 154.1h17.8zM148.6 146.5h2.5zM148.6 154.1h2.5zM156.2 146.5h2.5zM156.2 154.1h2.5zM158.7 146.5h10.2z"/>
<path d="M158.7 154.1h7.6zM166.3 154.1v10.2zM168.9 146.5v15.2zM174 154.1v2.6zM174 156.7v2.5zM176.5 159.2h5.1zM174 159.2h2.5zM186.7 159.2h5zM191.7 159.2h2.6zM194.3 159.2v22.9zM240 154.1v2.6zM270.5 141.4v2.6z"/>
<path d="M336.5 141.4v2.6zM336.5 138.9v2.5zM341.6 156.7v2.5zM341.6 151.6v2.5zM341.6 154.1v2.6zM351.7 154.1v2.6zM351.7 149v2.6zM351.7 153.6v.5zM351.7 151.6v.5zM351.7 159.2v2.5zM351.7 156.7v2.5zM361.9 141.4v2.6z"/>
<path d="M16.5 173.7h3.8zM54.6 159.2l2.5 2.5zM54.6 166.8l2.5 2.6zM54.6 174.4l2.5 2.6zM69.8 161.7h3.1zM69.8 177h3.1zM57.1 161.7h12.7zM57.1 177h12.7zM80 169.4h3.1zM57.1 169.4h22.9zM80.8 160.5l1 2.5zM79.9 160.5h.9z"/>
<path d="M80.8 175.7l1 2.5zM79.9 175.7h.9zM82 160.5l1.1 2.5zM80.8 160.5h1.2zM82 175.7l1.1 2.5zM80.8 175.7h1.2zM81.8 163h1.3zM81.8 178.2h1.3zM83.1 163h.8zM83.1 178.2h.8zM85.1 161.7h5.1zM85.1 177h5.1z"/>
<path d="M90.2 161.7h43.1zM90.2 177h48.2zM90.9 168.1l1 2.5zM90 168.1h.9zM92.2 168.1l1 2.5zM90.9 168.1h1.3zM91.9 170.6h1.3zM93.2 170.6h.9zM95.2 169.4h5.1zM100.3 169.4h35.6zM133.3 161.7h15.3zM135.9 169.4h12.7z"/>
<path d="M138.4 177h10.2zM148.6 161.7h2.5zM148.6 169.4h2.5zM148.6 177h2.5zM156.2 161.7h2.5zM156.2 169.4h2.5zM156.2 177h2.5zM158.7 169.4h17.8zM158.7 161.7h5.1zM158.7 177h5.1zM163.8 161.7v5.1zM163.8 166.8h12.7z"/>
<path d="M163.8 171.9v5.1zM163.8 171.9h12.7zM166.3 164.3h10.2zM166.3 174.4h10.2zM168.9 161.7h7.6zM168.9 177h7.6zM171.4 179.5v20.3zM176.5 161.7h5.1zM176.5 164.3h5.1zM176.5 166.8h5.1zM176.5 169.4h5.1zM176.5 171.9h5.1z"/>
<path d="M176.5 174.4h5.1zM176.5 177h5.1zM176.5 179.5h5.1zM171.4 179.5h5.1zM186.7 161.7h5zM186.7 164.3h5zM186.7 166.8h5zM186.7 169.4h5zM186.7 171.9h5zM186.7 174.4h5zM186.7 177h5zM186.7 179.5h5z"/>
<path d="M191.7 161.7h15.3zM191.7 164.3h15.3zM191.7 166.8h15.3zM191.7 169.4h15.3zM191.7 171.9h15.3zM191.7 174.4h15.3zM191.7 177h15.3zM207 161.7l2.5-2.5zM207 164.3l2.5-2.6zM207 166.8l2.5-2.5zM207 169.4l2.5-2.6zM207 171.9l2.5-2.5z"/>
<path d="M207 174.4l2.5-2.5zM207 177l2.5-2.6zM191.7 179.5h15.3zM209.5 177l-2.5 2.5zM214.6 159.2l2.5 2.5zM214.6 161.7l2.5 2.6zM240 156.7v12.7zM250.2 161.7h5zM250.2 164.3h5zM250.2 166.8h5zM250.2 169.4h5zM250.2 171.9h5z"/>
<path d="M240 169.4h10.2zM217.1 161.7h33.1zM217.1 164.3h33.1zM260.3 161.7h5.1zM260.3 164.3h5.1zM260.3 166.8h5.1zM260.3 169.4h5.1zM260.3 171.9h5.1zM265.4 169.4h5.1zM265.4 171.9h5.1zM265.4 161.7h25.4zM265.4 164.3h25.4z"/>
<path d="M265.4 166.8h25.4zM270.5 174.4v2.6zM270.5 169.4v2.5zM270.5 171.9v2.5zM293.3 159.2l-2.5 2.5zM290.8 164.3l2.5-2.6zM293.3 164.3l-2.5 2.5zM311.1 171.9h5.1zM311.1 171.9v10.2zM316.2 171.9h2.5zM327.6 168.7v1.3zM327 169.4h1.2z"/>
<path d="M327 174.4h1.2zM328.9 174.4h2.5zM328.9 169.4h2.5zM331.4 174.4h5.1zM341.6 164.3v2.5zM331.4 169.4h10.2zM341.6 166.8v2.6zM351.7 166.8v2.6zM351.7 169.4v5zM336.5 174.4h15.2zM400 173.7h3.8zM54.6 189.7l2.5 2.5z"/>
<path d="M54.6 197.3l2.5 2.5zM54.6 182.1l2.5 2.5zM57.1 192.2h86.4zM57.1 199.8h88.9zM80 184.6h3.1zM57.1 184.6h22.9zM90.9 183.3l1 2.6zM90 183.3h.9zM92.2 183.3l1 2.6zM90.9 183.3h1.3zM91.9 185.9h1.3zM93.2 185.9h.9z"/>
<path d="M95.2 184.6h5.1zM100.3 184.6h40.6zM140.9 184.6h7.7zM148.6 184.6h2.5zM148.6 192.2h2.5zM148.6 199.8h2.5zM143.5 192.2h5.1zM146 199.8h2.6zM156.2 184.6h2.5zM156.2 192.2h2.5zM156.2 199.8h2.5zM158.7 184.6h7.6z"/>
<path d="M158.7 192.2h10.2zM166.3 174.4v10.2zM168.9 177v15.2zM158.7 199.8h12.7zM194.3 182.1v2.5zM214.6 197.3l2.5 2.5zM288.3 199.8h17.7zM288.3 199.8v2.6zM217.1 199.8h71.2zM306 103.3v96.5zM311.1 197.3h10.2zM311.1 182.1h10.2z"/>
<path d="M311.1 182.1v7.6zM311.1 189.7h2.6zM313.7 189.7h2.5zM321.3 182.1h2.5zM321.3 197.3h2.5zM321.3 189.7h2.5zM323.8 189.7h12.7zM328.9 182.1h2.5zM328.9 197.3h2.5zM331.4 197.3h5.1zM336.5 174.4v7.7zM331.4 182.1h5.1z"/>
<path d="M336.5 189.7v7.6zM336.5 197.3v7.6zM341.6 169.4v27.9zM344.1 197.3h2.6zM341.6 197.3h2.5zM351.7 197.3h2.6zM354.3 197.3h2.5zM356.8 197.3v12.7zM364.4 194.8v2.5zM364.4 197.3v5.1zM179 212.5v2.5zM179 215v2.6z"/>
<path d="M179 217.6h2.6zM179 217.6v25.4zM181.6 217.6h2.5zM186.7 217.6h1.2zM186.7 217.6v2.5zM184.1 217.6h2.6zM193 217.6h1.3zM194.3 217.6h2.5zM196.8 217.6h15.3zM214.6 215l-2.5 2.6zM288.3 210v2.5zM288.3 202.4v2.5z"/>
<path d="M288.3 204.9l2 1zM288.3 210h1.2zM288.3 215v2.6zM288.3 212.5v2.5zM289 209l-.7 1zM289.3 209.5l1.2-.6zM289 209l.5 1zM290.8 207.4h2.5zM293.3 207.4h2.6zM295.9 207.4h2.5zM303.5 207.4h2.5zM311.1 197.3v10.1z"/>
<path d="M306 207.4h5.1zM316.2 207.4h2.5zM311.1 207.4h5.1zM327.6 204.3v1.2zM327 204.9h1.2zM327 210h1.2zM328.9 210h2.5zM328.9 204.9h2.5zM331.4 210h10.2zM331.4 204.9h5.1zM341.6 197.3v12.7zM346.7 210h2.5z"/>
<path d="M341.6 210h5.1zM349.2 210h.5zM351.2 210h.5zM351.7 210h2.6zM354.3 210h2.5zM356.8 215v2.6zM356.8 210v5zM364.4 207.4v2.6zM364.4 202.4v2.5zM364.4 206.9v.5zM364.4 204.9v.5zM364.4 215v2.6z"/>
<path d="M364.4 210v5zM16.5 224.2h3.8zM186.7 220.1h1.2zM186.7 220.1v2.6zM186.7 222.7h1.2zM186.7 222.7v2.5zM186.7 225.2h1.2zM186.7 225.2v2.5zM186.7 227.7h1.2zM186.7 230.3h1.2zM186.7 230.3v2.5zM186.7 232.8h1.2z"/>
<path d="M186.7 232.8v2.6zM186.7 235.4h1.2zM186.7 227.7v2.6zM193 230.3h1.3zM193 227.7h1.3zM193 225.2h1.3zM193 222.7h1.3zM193 220.1h1.3zM193 235.4h1.3zM193 232.8h1.3zM194.3 220.1h2.5zM194.3 222.7h2.5z"/>
<path d="M194.3 225.2h2.5zM194.3 227.7h2.5zM194.3 230.3h2.5zM194.3 232.8h2.5zM194.3 235.4h2.5zM196.8 220.1h15.3zM196.8 222.7h15.3zM196.8 225.2h15.3zM196.8 230.3h15.3zM196.8 227.7h15.3zM196.8 232.8h15.3zM196.8 235.4h15.3z"/>
<path d="M212.1 220.1l2.5-2.5zM212.1 222.7l2.5-2.6zM214.6 222.7l-2.5 2.5zM212.1 230.3l2.5-2.6zM212.1 227.7l2.5-2.5zM214.6 230.3l-2.5 2.5zM212.1 235.4l2.5-2.6zM400 224.2h3.8zM179 243h2.6zM181.6 243h2.5zM186.7 243h1.2zM186.7 243v2.5z"/>
<path d="M186.7 245.5h1.2zM186.7 245.5v2.6zM186.7 248.1h1.2zM186.7 248.1v2.5zM186.7 250.6h1.2zM186.7 250.6v2.5zM186.7 253.1h1.2zM186.7 255.7h1.2zM186.7 255.7v2.5zM186.7 258.2h1.2zM186.7 258.2v2.6zM186.7 253.1v2.6z"/>
<path d="M184.1 243h2.6zM193 243h1.3zM193 255.7h1.3zM193 253.1h1.3zM193 250.6h1.3zM193 248.1h1.3zM193 245.5h1.3zM193 258.2h1.3zM194.3 243h2.5zM194.3 245.5h2.5zM194.3 248.1h2.5zM194.3 250.6h2.5z"/>
<path d="M194.3 253.1h2.5zM194.3 255.7h2.5zM194.3 258.2h2.5zM196.8 245.5h15.3zM196.8 248.1h15.3zM196.8 250.6h15.3zM196.8 253.1h15.3zM196.8 255.7h15.3zM196.8 258.2h15.3zM196.8 243h15.3zM212.1 245.5l2.5-2.5zM214.6 245.5l-2.5 2.6z"/>
<path d="M212.1 250.6l2.5-2.5zM212.1 253.1l2.5-2.5zM214.6 253.1l-2.5 2.6zM212.1 258.2l2.5-2.5zM214.6 240.4l-2.5 2.6zM257.8 253.1v2.6zM257.8 257.7v.5zM257.8 255.7v.5zM257.8 250.6v2.5zM267.9 253.1v2.6zM267.9 257.7v.5zM267.9 255.7v.5z"/>
<path d="M267.9 245.5v2.6zM257.8 250.6h10.1zM267.9 248.1v2.5zM267.9 250.6v2.5zM20.3 274.7h379.7zM67.8 274.7v3.8zM115.3 274.7v3.8zM162.7 274.7v3.8zM186.7 260.8h1.2zM193 260.8h1.3zM194.3 260.8h2.5zM196.8 260.8h15.3z"/>
<path d="M210.2 274.7v3.8zM212.1 260.8l2.5-2.6zM257.6 274.7v3.8zM257.8 265.8v2.6zM257.8 258.2v2.6zM257.8 260.8v2.5zM257.8 263.3v2.5zM267.9 258.2v2.6zM257.8 263.3h10.1zM267.9 260.8v2.5zM305.1 274.7v3.8zM352.5 274.7v3.8z"/>
<path d="M400 264.5v.1zM400 268.4v6.2zM400 274.6h.1zM400 22.1v252.6z"/>
<circle cx="102.9" cy="85.5" r=".51"/>
<circle cx="105.4" cy="93.2" r=".51"/>
<circle cx="275.6" cy="83" r=".51"/>
<circle cx="361.9" cy="85.5" r=".51"/>
<circle cx="361.9" cy="93.2" r=".51"/>
<circle cx="361.9" cy="88.1" r=".51"/>
<circle cx="361.9" cy="90.6" r=".51"/>
<circle cx="107.9" cy="100.8" r=".51"/>
<circle cx="110.5" cy="108.4" r=".51"/>
<circle cx="113" cy="116" r=".51"/>
<circle cx="115.6" cy="123.6" r=".51"/>
<circle cx="118.1" cy="131.3" r=".51"/>
<circle cx="120.6" cy="138.9" r=".51"/>
<circle cx="270.5" cy="138.9" r=".51"/>
<circle cx="303.5" cy="123.6" r=".51"/>
<circle cx="334" cy="123.6" r=".51"/>
<circle cx="336.5" cy="138.9" r=".51"/>
<circle cx="339" cy="123.6" r=".51"/>
<circle cx="361.9" cy="136.3" r=".51"/>
<circle cx="128.2" cy="146.5" r=".51"/>
<circle cx="130.8" cy="154.1" r=".51"/>
<circle cx="133.3" cy="161.7" r=".51"/>
<circle cx="135.9" cy="169.4" r=".51"/>
<circle cx="138.4" cy="177" r=".51"/>
<circle cx="270.5" cy="171.9" r=".51"/>
<circle cx="336.5" cy="174.4" r=".51"/>
<circle cx="341.6" cy="169.4" r=".51"/>
<circle cx="140.9" cy="184.6" r=".51"/>
<circle cx="143.5" cy="192.2" r=".51"/>
<circle cx="146" cy="199.8" r=".51"/>
<circle cx="288.3" cy="199.8" r=".51"/>
<circle cx="311.1" cy="182.1" r=".51"/>
<circle cx="336.5" cy="197.3" r=".51"/>
<circle cx="341.6" cy="197.3" r=".51"/>
<circle cx="179" cy="217.6" r=".51"/>
<circle cx="311.1" cy="207.4" r=".51"/>
<circle cx="341.6" cy="210" r=".51"/>
<circle cx="356.8" cy="210" r=".51"/>
<circle cx="267.9" cy="250.6" r=".51"/>
<circle cx="257.8" cy="263.3" r=".51"/>
</g>
<path d="M16.5 18.2v260.3zM16.5 18.2h387.3zM16.5 278.5h387.3zM403.8 18.2v260.3z" fill="#000" stroke="#000" stroke-width=".32"/>
<g fill="#000" stroke="#000" stroke-width=".61">
<path d="M20.3 22.1v252.6zM20.3 22.1h379.7zM255.2 65.2h1.3zM255.2 62.7h1.3zM255.2 60.2h1.3zM255.2 70.3h1.3zM255.2 67.8h1.3zM255.2 77.9h1.3zM255.2 75.4h1.3zM255.2 72.8h1.3zM259.1 65.2h1.2zM259.1 62.7h1.2z"/>
<path d="M259.1 60.2h1.2zM259.1 70.3h1.2zM259.1 67.8h1.2zM259.1 77.9h1.2zM259.1 75.4h1.2zM259.1 72.8h1.2zM74.9 85.5l10.2 5.1zM74.9 85.5l10.2-5zM85.1 80.5v10.1zM85.1 93.2l10.1-5.1zM85.1 95.7v10.2zM85.1 93.2l10.1 5z"/>
<path d="M95.2 88.1v10.1zM181.6 98.2h1.3zM185.4 98.2h1.3zM255.2 83h1.3zM255.2 80.5h1.3zM259.1 83h1.2zM259.1 80.5h1.2zM349.2 88.1h1.3zM349.2 85.5h1.3zM349.2 83h1.3zM349.2 93.2h1.3zM349.2 90.6h1.3z"/>
<path d="M353 88.1h1.3zM353 85.5h1.3zM353 83h1.3zM353 93.2h1.3zM353 90.6h1.3zM74.9 100.8l10.2-5.1zM74.9 116l10.2-5.1zM74.9 100.8l10.2 5.1zM85.1 108.4l10.1-5.1zM85.1 110.9v10.2zM85.1 108.4l10.1 5.1zM95.2 103.3v10.2z"/>
<path d="M95.2 118.6v10.1zM181.6 103.3h1.3zM181.6 100.8h1.3zM181.6 108.4h1.3zM181.6 105.9h1.3zM181.6 116h1.3zM181.6 113.5h1.3zM181.6 110.9h1.3zM181.6 118.6h1.3zM185.4 103.3h1.3zM185.4 100.8h1.3zM185.4 108.4h1.3z"/>
<path d="M185.4 105.9h1.3zM185.4 116h1.3zM185.4 113.5h1.3zM185.4 110.9h1.3zM185.4 118.6h1.3zM74.9 116l10.2 5.1zM85.1 123.6l10.1-5zM85.1 123.6l10.1 5.1zM255.2 133.8h1.3zM255.2 131.3h1.3zM255.2 128.7h1.3zM255.2 138.9h1.3z"/>
<path d="M255.2 136.3h1.3zM259.1 133.8h1.2zM259.1 131.3h1.2zM259.1 128.7h1.2zM259.1 138.9h1.2zM259.1 136.3h1.2zM369.5 136.3h1.3zM369.5 133.8h1.3zM369.5 131.3h1.3zM369.5 138.9h1.3zM74.9 146.5l10.2 5.1zM74.9 146.5l10.2-5.1z"/>
<path d="M85.1 141.4v10.2zM85.1 154.1l10.1-5.1zM85.1 156.7v10.1zM85.1 154.1l10.1 5.1zM95.2 149v10.2zM181.6 159.2h1.3zM185.4 159.2h1.3zM74.9 161.7l10.2-5zM74.9 177l10.2-5.1zM74.9 161.7l10.2 5.1zM85.1 169.4l10.1-5.1zM85.1 171.9v10.2z"/>
<path d="M85.1 169.4l10.1 5zM95.2 164.3v10.1zM95.2 179.5v10.2zM181.6 164.3h1.3zM181.6 161.7h1.3zM181.6 169.4h1.3zM181.6 166.8h1.3zM181.6 177h1.3zM181.6 174.4h1.3zM181.6 171.9h1.3zM181.6 179.5h1.3zM185.4 164.3h1.3z"/>
<path d="M185.4 161.7h1.3zM185.4 169.4h1.3zM185.4 166.8h1.3zM185.4 177h1.3zM185.4 174.4h1.3zM185.4 171.9h1.3zM185.4 179.5h1.3zM255.2 166.8h1.3zM255.2 164.3h1.3zM255.2 161.7h1.3zM255.2 171.9h1.3zM255.2 169.4h1.3z"/>
<path d="M259.1 166.8h1.2zM259.1 164.3h1.2zM259.1 161.7h1.2zM259.1 171.9h1.2zM259.1 169.4h1.2zM74.9 177l10.2 5.1zM85.1 184.6l10.1-5.1zM85.1 184.6l10.1 5.1zM283.2 244.3v30.4zM313.7 254.4v5.1zM313.7 249.3v5.1zM313.7 244.3v5z"/>
<path d="M313.7 244.3h86.3zM283.2 244.3h30.5zM400 254.4v5.1zM400 249.3v5.1zM400 244.3v5zM400 22.1v222.2zM20.3 274.7h262.9zM283.2 274.7h30.5zM313.7 274.7h86.3zM313.7 269.7v5zM313.7 264.6v5.1zM313.7 259.5v5.1z"/>
<path d="M400 268.4v6.3zM400 264.6v3.8zM400 259.5v5.1z"/>
</g>
<g fill="#000" stroke="#000" stroke-width=".28">
<path d="M102.1 74.1v5.1zM102.1 79.2h.8zM102.9 79.2h.7zM102.1 74.1h.8zM102.9 62.7l-1.3 1.9zM103.6 74.1v5.1zM102.9 74.1h.7zM102.9 62.7l1.2 1.9zM104.6 79.2h.8zM104.6 74.1v5.1zM105.4 79.2h.8zM104.6 74.1h.8z"/>
<path d="M105.4 74.1h.8zM106.2 74.1v5.1zM107.2 74.1v5.1zM107.2 79.2h.7zM107.2 74.1h.7zM107.9 79.2h.8zM108.7 74.1v5.1zM107.9 74.1h.8zM109.7 74.1v5.1zM109.7 79.2h.8zM109.7 74.1h.8zM110.5 79.2h.8z"/>
<path d="M111.3 74.1v5.1zM110.5 74.1h.8zM112.3 74.1v5.1zM112.3 79.2h.7zM112.3 74.1h.7zM113 79.2h.8zM113.8 74.1v5.1zM113 74.1h.8zM114.8 74.1v5.1zM114.8 79.2h.8zM115.6 79.2h.7zM114.8 74.1h.8z"/>
<path d="M116.3 74.1v5.1zM115.6 74.1h.7zM117.3 79.2h.8zM117.3 74.1v5.1zM118.1 79.2h.8zM117.3 74.1h.8zM118.1 74.1h.8zM118.9 74.1v5.1zM119.9 74.1v5.1zM119.9 79.2h.7zM119.9 74.1h.7zM120.6 79.2h.8z"/>
<path d="M121.4 74.1v5.1zM120.6 74.1h.8zM127.5 74.1v5.1zM127.5 79.2h.7zM128.2 79.2h.8zM127.5 74.1h.7zM128.2 62.7l-1.2 1.9zM129 74.1v5.1zM128.2 74.1h.8zM128.2 62.7l1.3 1.9zM130 79.2h.8zM130 74.1v5.1z"/>
<path d="M130.8 79.2h.7zM130 74.1h.8zM130.8 74.1h.7zM131.5 74.1v5.1zM132.6 74.1v5.1zM132.6 79.2h.7zM132.6 74.1h.7zM133.3 79.2h.8zM134.1 74.1v5.1zM133.3 74.1h.8zM135.1 74.1v5.1zM135.1 79.2h.8z"/>
<path d="M135.1 74.1h.8zM135.9 79.2h.7zM136.6 74.1v5.1zM135.9 74.1h.7zM137.6 74.1v5.1zM137.6 79.2h.8zM137.6 74.1h.8zM138.4 79.2h.8zM139.2 74.1v5.1zM138.4 74.1h.8zM140.2 74.1v5.1zM140.2 79.2h.7z"/>
<path d="M140.9 79.2h.8zM140.2 74.1h.7zM141.7 74.1v5.1zM140.9 74.1h.8zM142.7 79.2h.8zM142.7 74.1v5.1zM143.5 79.2h.7zM142.7 74.1h.8zM143.5 74.1h.7zM144.2 74.1v5.1zM145.3 74.1v5.1zM145.3 79.2h.7z"/>
<path d="M145.3 74.1h.7zM146 79.2h.8zM146.8 74.1v5.1zM146 74.1h.8zM151.1 86.3h5.1zM151.1 84.8v1.5zM151.1 93.9h5.1zM151.1 92.4v1.5zM151.1 84.8h5.1zM156.2 84.8v1.5zM151.1 92.4h5.1zM156.2 92.4v1.5z"/>
<path d="M174 93.2l-1.3 1.9zM174 93.2l1.2 1.9zM245.7 88.1h3.8zM273.7 88.1h3.8zM321.3 83.9h5.1zM321.3 82.1v1.8zM321.3 89h5.1zM321.3 87.2v1.8zM321.3 94h5.1zM321.3 92.3v1.7zM321.3 99.1h5.1zM321.3 97.3v1.8z"/>
<path d="M321.3 82.1h5.1zM326.4 82.1v1.8zM321.3 87.2h5.1zM326.4 87.2v1.8zM321.3 92.3h5.1zM326.4 92.3v1.7zM321.3 97.3h5.1zM326.4 97.3v1.8zM360 98.2h3.8zM151.1 101.5h5.1zM151.1 100v1.5zM151.1 109.2h5.1z"/>
<path d="M151.1 107.6v1.6zM151.1 116.8h5.1zM151.1 115.3v1.5zM151.1 100h5.1zM156.2 100v1.5zM151.1 107.6h5.1zM156.2 107.6v1.6zM151.1 115.3h5.1zM156.2 115.3v1.5zM321.3 104.2h5.1zM321.3 102.4v1.8zM321.3 102.4h5.1z"/>
<path d="M326.4 102.4v1.8zM151.1 124.4h5.1zM151.1 122.9v1.5zM151.1 132h5.1zM151.1 130.5v1.5zM151.1 139.6h5.1zM151.1 138.1v1.5zM151.1 122.9h5.1zM156.2 122.9v1.5zM151.1 130.5h5.1zM156.2 130.5v1.5zM151.1 138.1h5.1z"/>
<path d="M156.2 138.1v1.5zM192.4 123.6h3.8zM240 121.1l-1.3 1.9zM240 121.1l1.3 1.9zM323.8 124.5h5.1zM323.8 122.7v1.8zM323.8 122.7h5.1zM328.9 122.7v1.8zM333.1 128.7v5.1zM333.1 133.8h1.8zM333.1 128.7h1.8zM334.9 128.7v5.1z"/>
<path d="M151.1 147.3h5.1zM151.1 145.7v1.6zM151.1 154.9h5.1zM151.1 153.3v1.6zM151.1 145.7h5.1zM156.2 145.7v1.6zM151.1 153.3h5.1zM156.2 153.3v1.6zM174 154.1l-1.3 1.9zM174 154.1l1.2 1.9zM240 154.1l-1.3 1.9zM240 154.1l1.3 1.9z"/>
<path d="M268.6 144h3.8zM334.6 144h3.8zM341.6 151.6l-1.3 1.9zM340.7 159.2v5.1zM340.7 159.2h1.8zM341.6 151.6l1.3 1.9zM360 144h3.8zM151.1 162.5h5.1zM151.1 161v1.5zM151.1 170.1h5.1zM151.1 168.6v1.5zM151.1 177.7h5.1z"/>
<path d="M151.1 176.2v1.5zM151.1 161h5.1zM156.2 161v1.5zM151.1 168.6h5.1zM156.2 168.6v1.5zM151.1 176.2h5.1zM156.2 176.2v1.5zM268.6 177h3.8zM340.7 164.3h1.8zM342.5 159.2v5.1zM350.9 161.7v5.1zM352.6 161.7v5.1z"/>
<path d="M350.9 161.7h1.7zM350.9 166.8h1.7zM151.1 185.4h5.1zM151.1 183.8v1.6zM151.1 193h5.1zM151.1 191.4v1.6zM151.1 199.1v1.5zM151.1 183.8h5.1zM156.2 183.8v1.6zM151.1 191.4h5.1zM156.2 191.4v1.6zM151.1 199.1h5.1z"/>
<path d="M192.4 184.6h3.8zM316.2 190.6h5.1zM316.2 188.8v1.8zM316.2 188.8h5.1zM321.3 188.8v1.8zM323.8 182.9h5.1zM323.8 181.2v1.7zM323.8 198.2h5.1zM323.8 196.4v1.8zM323.8 181.2h5.1zM328.9 181.2v1.7zM323.8 196.4h5.1z"/>
<path d="M328.9 196.4v1.8zM346.7 198.2h5zM346.7 196.4v1.8zM346.7 196.4h5zM351.7 196.4v1.8zM364.4 194.8l-1.2 1.9zM364.4 194.8l1.3 1.9zM151.1 200.6h5.1zM156.2 199.1v1.5zM179 212.5l-1.2 1.9zM179 212.5l1.3 1.9zM187.9 216.8h5.1z"/>
<path d="M187.9 217.6v.8zM187.9 216.8v.8zM187.9 219.4h5.1zM187.9 218.4h5.1zM193 216.8v.8zM193 217.6v.8zM193 219.4v.7zM289 209.2l-.5 .6zM289 209.5l-.1 .2zM289 209.2l.3 .5zM288.5 209.8h.8zM288.9 209.7h.4z"/>
<path d="M286.4 217.6h3.8zM298.4 208.3h5.1zM298.4 206.5v1.8zM298.4 206.5h5.1zM303.5 206.5v1.8zM354.9 217.6h3.8zM362.5 217.6h3.8zM187.9 220.1v.8zM187.9 219.4v.7zM187.9 221.9h5.1zM187.9 224.4h5.1zM187.9 227h5.1z"/>
<path d="M187.9 222.7v.7zM187.9 225.2v.8zM187.9 227.7v.8zM187.9 221.9v.8zM187.9 224.4v.8zM187.9 227v.7zM187.9 229.5h5.1zM187.9 230.3v.8zM187.9 229.5v.8zM187.9 232.8v.8zM187.9 232.1v.7zM187.9 232.1h5.1z"/>
<path d="M187.9 234.6h5.1zM187.9 235.4v.7zM187.9 234.6v.8zM193 220.1v.8zM187.9 220.9h5.1zM187.9 223.4h5.1zM187.9 226h5.1zM187.9 228.5h5.1zM193 222.7v.7zM193 225.2v.8zM193 227.7v.8zM193 221.9v.8z"/>
<path d="M193 224.4v.8zM193 227v.7zM187.9 231.1h5.1zM193 229.5v.8zM193 230.3v.8zM193 232.8v.8zM193 232.1v.7zM187.9 233.6h5.1zM187.9 236.1h5.1zM193 235.4v.7zM193 234.6v.8zM187.9 242.2h5.1z"/>
<path d="M187.9 243v.8zM187.9 242.2v.8zM187.9 245.5v.8zM187.9 244.8v.7zM187.9 244.8h5.1zM187.9 247.3h5.1zM187.9 249.8h5.1zM187.9 252.4h5.1zM187.9 248.1v.7zM187.9 250.6v.8zM187.9 253.1v.8zM187.9 247.3v.8z"/>
<path d="M187.9 249.8v.8zM187.9 252.4v.7zM187.9 254.9h5.1zM187.9 255.7v.8zM187.9 254.9v.8zM187.9 258.2v.8zM187.9 257.5v.7zM187.9 257.5h5.1zM187.9 243.8h5.1zM193 242.2v.8zM193 243v.8zM193 245.5v.8z"/>
<path d="M193 244.8v.7zM187.9 246.3h5.1zM187.9 248.8h5.1zM187.9 251.4h5.1zM187.9 253.9h5.1zM193 248.1v.7zM193 250.6v.8zM193 253.1v.8zM193 247.3v.8zM193 249.8v.8zM193 252.4v.7zM187.9 256.5h5.1z"/>
<path d="M193 254.9v.8zM193 255.7v.8zM193 258.2v.8zM193 257.5v.7zM187.9 259h5.1zM267.9 245.5l-1.2 1.9zM267.9 245.5l1.3 1.9zM313.7 249.3h86.3zM313.7 254.4h86.3zM313.7 259.5h58.4zM372.1 259.5h27.9zM372.1 259.5v5.1z"/>
<path d="M187.9 260h5.1zM187.9 260.8v.7zM187.9 260v.8zM187.9 261.5h5.1zM193 260.8v.7zM193 260v.8zM255.9 268.4h3.8zM313.7 264.6h58.4zM313.7 269.7h86.3zM372.1 264.6h27.9zM400 268.4v1.3z"/>
</g>
<g fill="#000" stroke="#000" stroke-width=".25">
<path d="M337 132.8h4.1v.5h-4.1zM337 131.8h4.1v.5h-4.1zM349.7 152.1h4.1v.5h-4.1zM349.7 153.1h4.1v.5h-4.1zM290.3 204.9h.8v5.1h-.8zM349.7 207.9h.5v4.1h-.5zM350.7 207.9h.5v4.1h-.5zM362.4 205.4h4.1v.5h-4.1zM362.4 206.4h4.1v.5h-4.1zM55.9 245.5h25.4v10.2h-25.4zM255.8 256.2h4v.5h-4zM255.8 257.2h4v.5h-4z"/>
<path d="M265.9 256.2h4.1v.5h-4.1zM265.9 257.2h4.1v.5h-4.1z"/>
</g>
<g fill="none" stroke="#000" stroke-width=".25">
<circle cx="73.9" cy="85.5" r=".99"/>
<circle cx="84.1" cy="93.2" r=".99"/>
<circle cx="73.9" cy="116" r=".99"/>
<circle cx="73.9" cy="100.8" r=".99"/>
<circle cx="84.1" cy="108.4" r=".99"/>
<circle cx="84.1" cy="123.6" r=".99"/>
<circle cx="73.9" cy="146.5" r=".99"/>
<circle cx="84.1" cy="154.1" r=".99"/>
<circle cx="73.9" cy="161.7" r=".99"/>
<circle cx="73.9" cy="177" r=".99"/>
<circle cx="84.1" cy="169.4" r=".99"/>
<circle cx="84.1" cy="184.6" r=".99"/>
</g>
<g fill="#000" stroke="#000" stroke-width=".42">
<path d="M254 57.6h7.6zM254 57.6v27.9zM100.3 71.6v8.9zM100.3 71.6h22.9zM123.2 71.6v8.9zM125.7 71.6v8.9zM125.7 71.6h22.9zM148.6 71.6v8.9zM100.3 80.5h22.9zM125.7 80.5h22.9zM180.3 95.7h7.6zM180.3 95.7v25.4z"/>
<path d="M261.6 57.6v27.9zM254 85.5h7.6zM347.9 80.5h7.7zM347.9 80.5v15.2zM355.6 80.5v15.2zM347.9 95.7h7.7zM187.9 95.7v25.4zM180.3 121.1h7.6zM254 126.2h7.6zM254 126.2v15.2zM368.3 128.7h5zM368.3 128.7v12.7z"/>
<path d="M180.3 156.7h7.6zM180.3 156.7v25.4zM254 159.2h7.6zM254 159.2v15.2zM261.6 126.2v15.2zM254 141.4h7.6zM373.3 128.7v12.7zM368.3 141.4h5zM261.6 159.2v15.2zM254 174.4h7.6zM318.7 171.9l10.2-5.1zM328.9 166.8v10.2z"/>
<path d="M318.7 171.9l10.2 5.1zM187.9 156.7v25.4zM180.3 182.1h7.6zM185.4 215h8.9zM185.4 215v22.9zM194.3 215v22.9zM318.7 207.4l10.2-5zM328.9 202.4v10.1zM318.7 207.4l10.2 5.1zM185.4 237.9h8.9zM25.4 245.5v10.2zM25.4 255.7v12.7z"/>
<path d="M25.4 255.7h55.9zM81.3 245.5v10.2zM25.4 245.5h55.9zM185.4 240.4h8.9zM185.4 240.4v22.9zM194.3 240.4v22.9zM25.4 268.4h55.9zM81.3 255.7v12.7zM185.4 263.3h8.9z"/>
</g>
<g fill="none" stroke="#000" stroke-width=".42">
<circle cx="102.9" cy="72.8" r=".25"/>
<circle cx="105.4" cy="72.8" r=".25"/>
<circle cx="107.9" cy="72.8" r=".25"/>
<circle cx="110.5" cy="72.8" r=".25"/>
<circle cx="113" cy="72.8" r=".25"/>
<circle cx="115.6" cy="72.8" r=".25"/>
<circle cx="118.1" cy="72.8" r=".25"/>
<circle cx="128.2" cy="72.8" r=".25"/>
<circle cx="130.8" cy="72.8" r=".25"/>
<circle cx="133.3" cy="72.8" r=".25"/>
<circle cx="135.9" cy="72.8" r=".25"/>
<circle cx="138.4" cy="72.8" r=".25"/>
<circle cx="140.9" cy="72.8" r=".25"/>
<circle cx="143.5" cy="72.8" r=".25"/>
<circle cx="186.7" cy="217.6" r=".25"/>
<circle cx="186.7" cy="220.1" r=".25"/>
<circle cx="186.7" cy="232.8" r=".25"/>
<circle cx="186.7" cy="230.3" r=".25"/>
<circle cx="186.7" cy="222.7" r=".25"/>
<circle cx="186.7" cy="227.7" r=".25"/>
<circle cx="186.7" cy="225.2" r=".25"/>
<circle cx="186.7" cy="255.7" r=".25"/>
<circle cx="186.7" cy="248.1" r=".25"/>
<circle cx="186.7" cy="250.6" r=".25"/>
<circle cx="186.7" cy="245.5" r=".25"/>
<circle cx="186.7" cy="258.2" r=".25"/>
<circle cx="186.7" cy="253.1" r=".25"/>
<circle cx="186.7" cy="243" r=".25"/>
</g>
<g fill="#000" stroke="#000" stroke-width=".76">
<path d="M41.9 39.8h251.4zM41.9 44.9h165.1zM41.9 55.1h7.6zM41.9 50h162.5zM207 44.9l7.6 7.6zM204.4 50l5.1 5.1zM214.6 52.5v53.4zM209.5 39.8l10.2 10.2zM293.3 39.8l5.1 5.1zM49.5 55.1l5.1 5.1zM219.7 50v33zM214.6 105.9v152.3z"/>
<path d="M214.6 105.9l5.1 5zM219.7 110.9h68.6zM288.3 110.9l5 5.1zM298.4 44.9v76.2zM209.5 55.1v121.9zM293.3 116v48.3zM54.6 60.2v137.1z"/>
</g>
<use href="#words"/>
</svg>
